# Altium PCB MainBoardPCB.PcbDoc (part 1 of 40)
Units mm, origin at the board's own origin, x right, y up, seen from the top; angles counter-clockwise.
Board outline 258.95 x 308.86 mm, 16 copper layers (L1, L2 (GND), L3 (Sign), L4 (GND), L5 (Sign), L6 (PWR/GND), L7(12V+Other), L8 (Plane_GND), L9 (PWR/GND), L10 (3V3+Other), L11 (PWR/GND), L12 (Sign), L13 (GND), L14 (Sign), L15 (GND), L16), stack 2.503 mm thick; 2578 components, 1867 nets, 8817 pads, 8021 vias.
Unrouted connection lines stored in the file: 25.

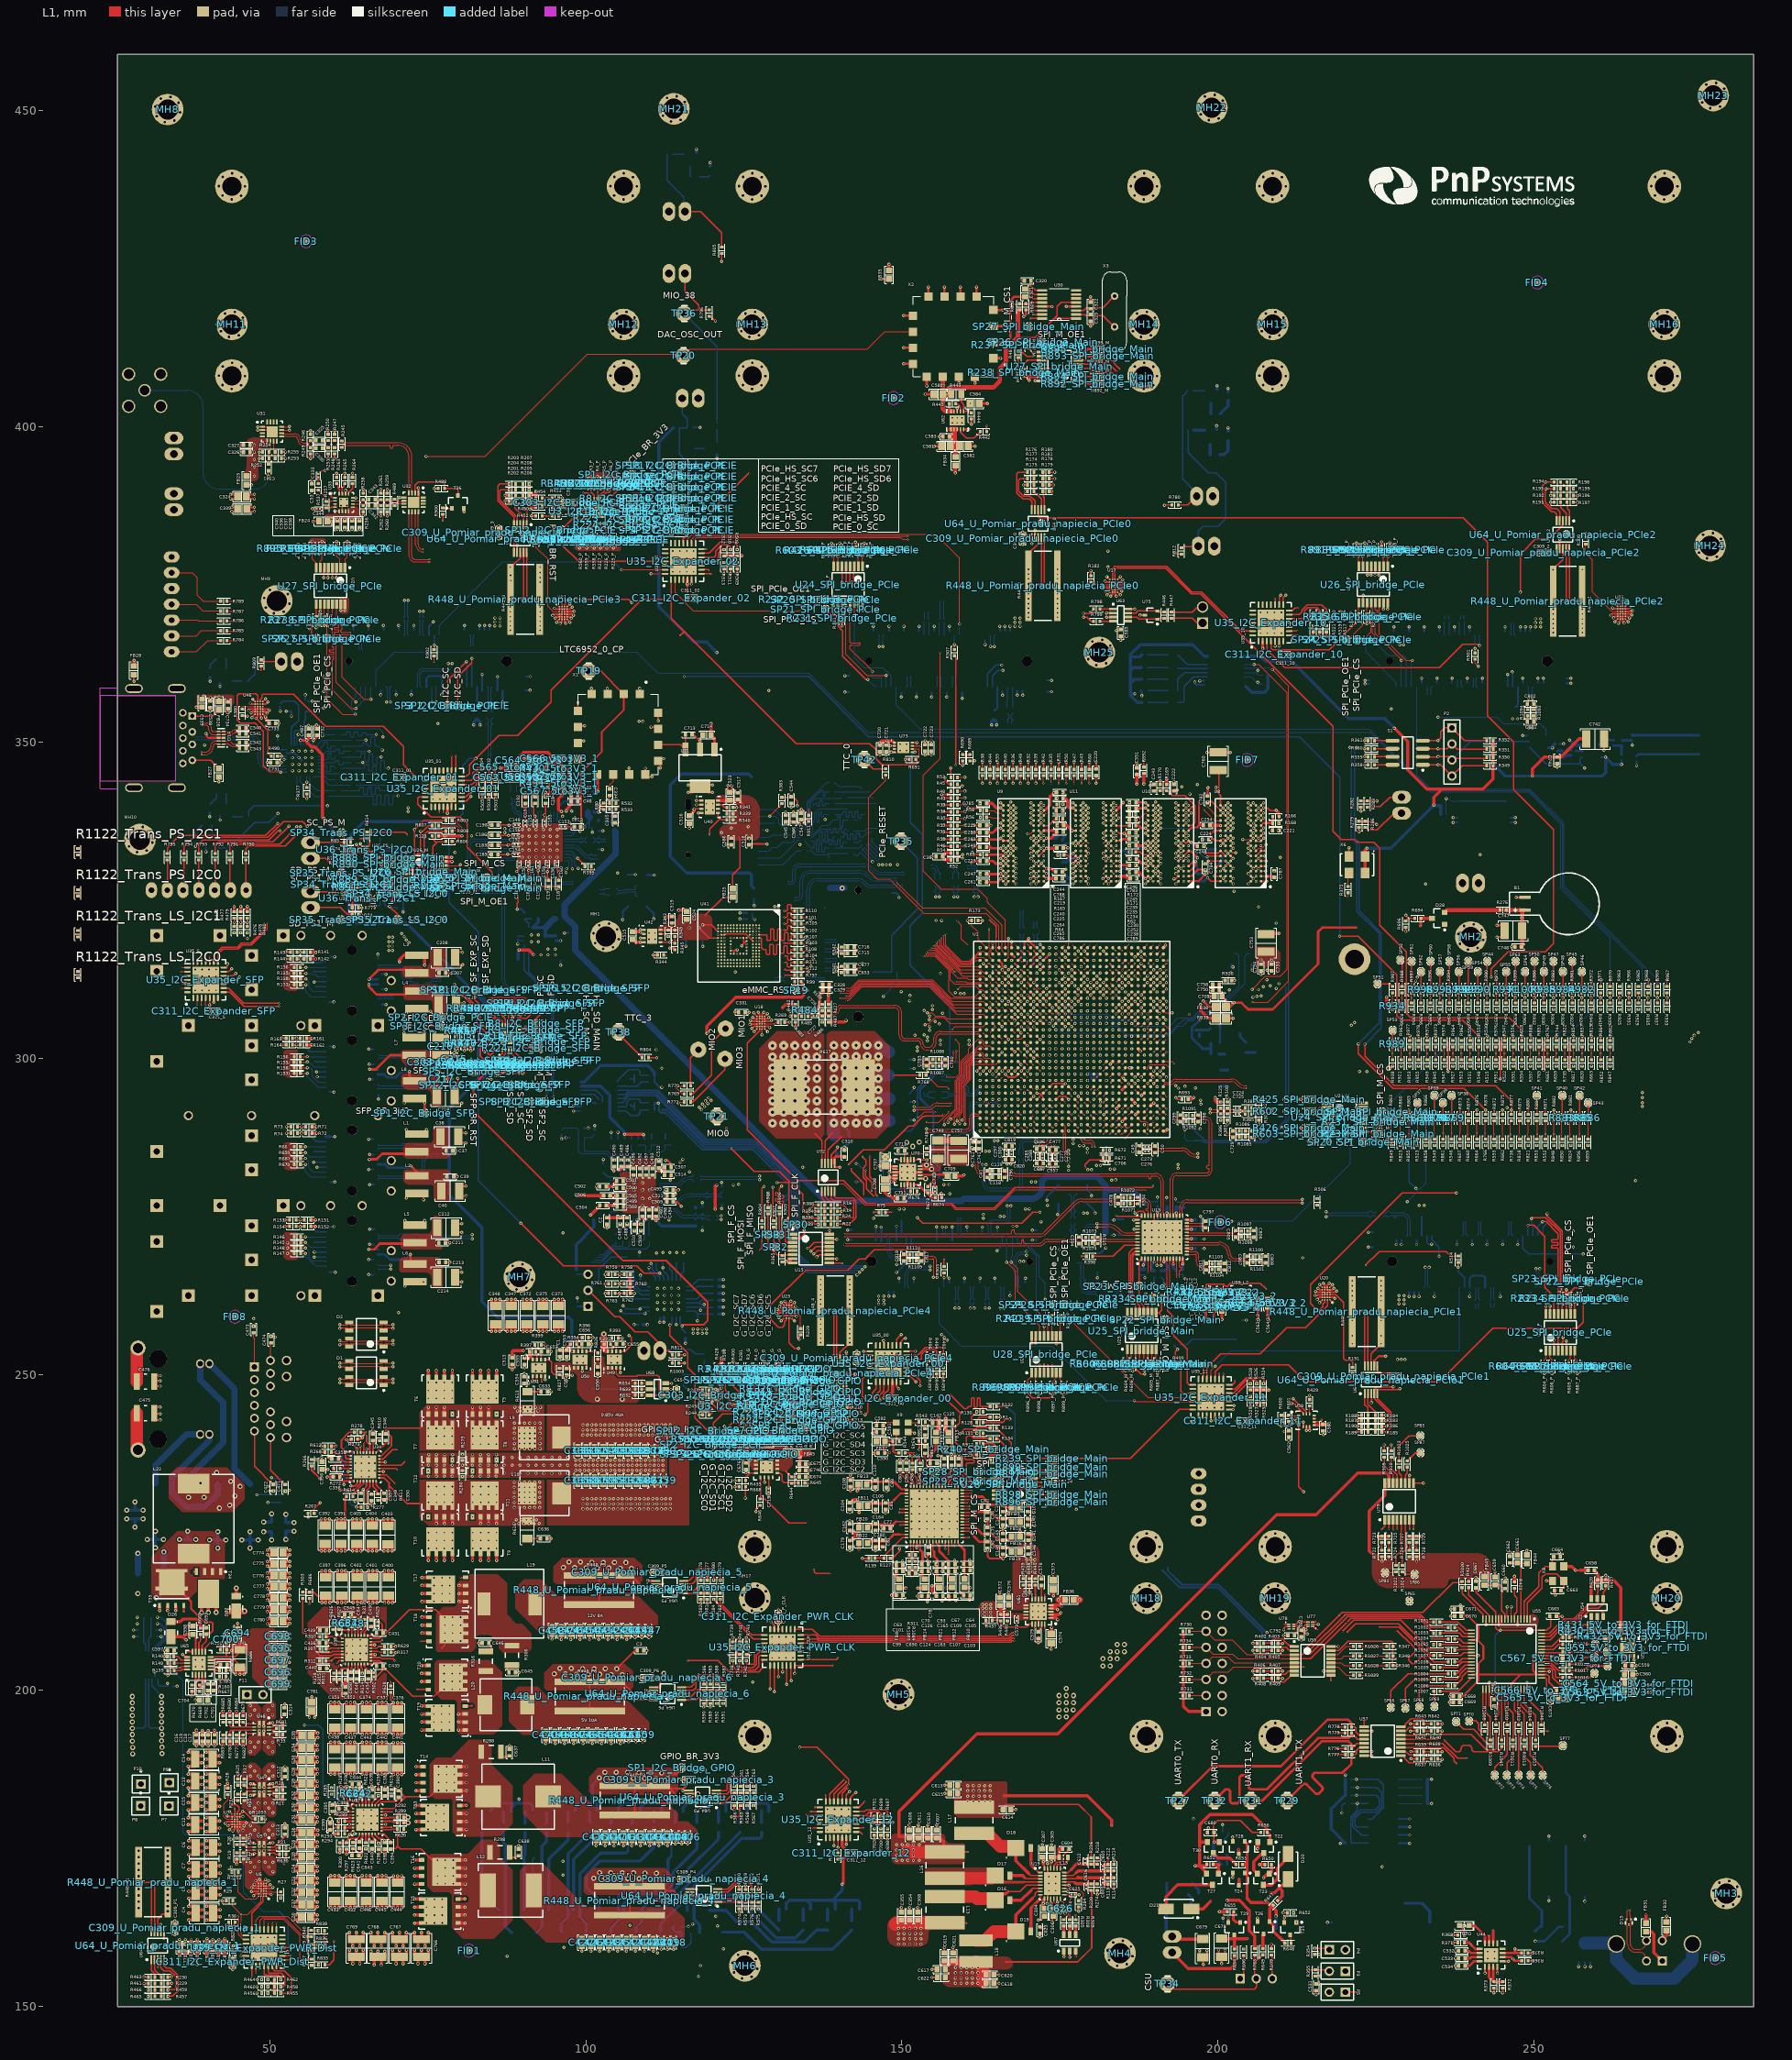
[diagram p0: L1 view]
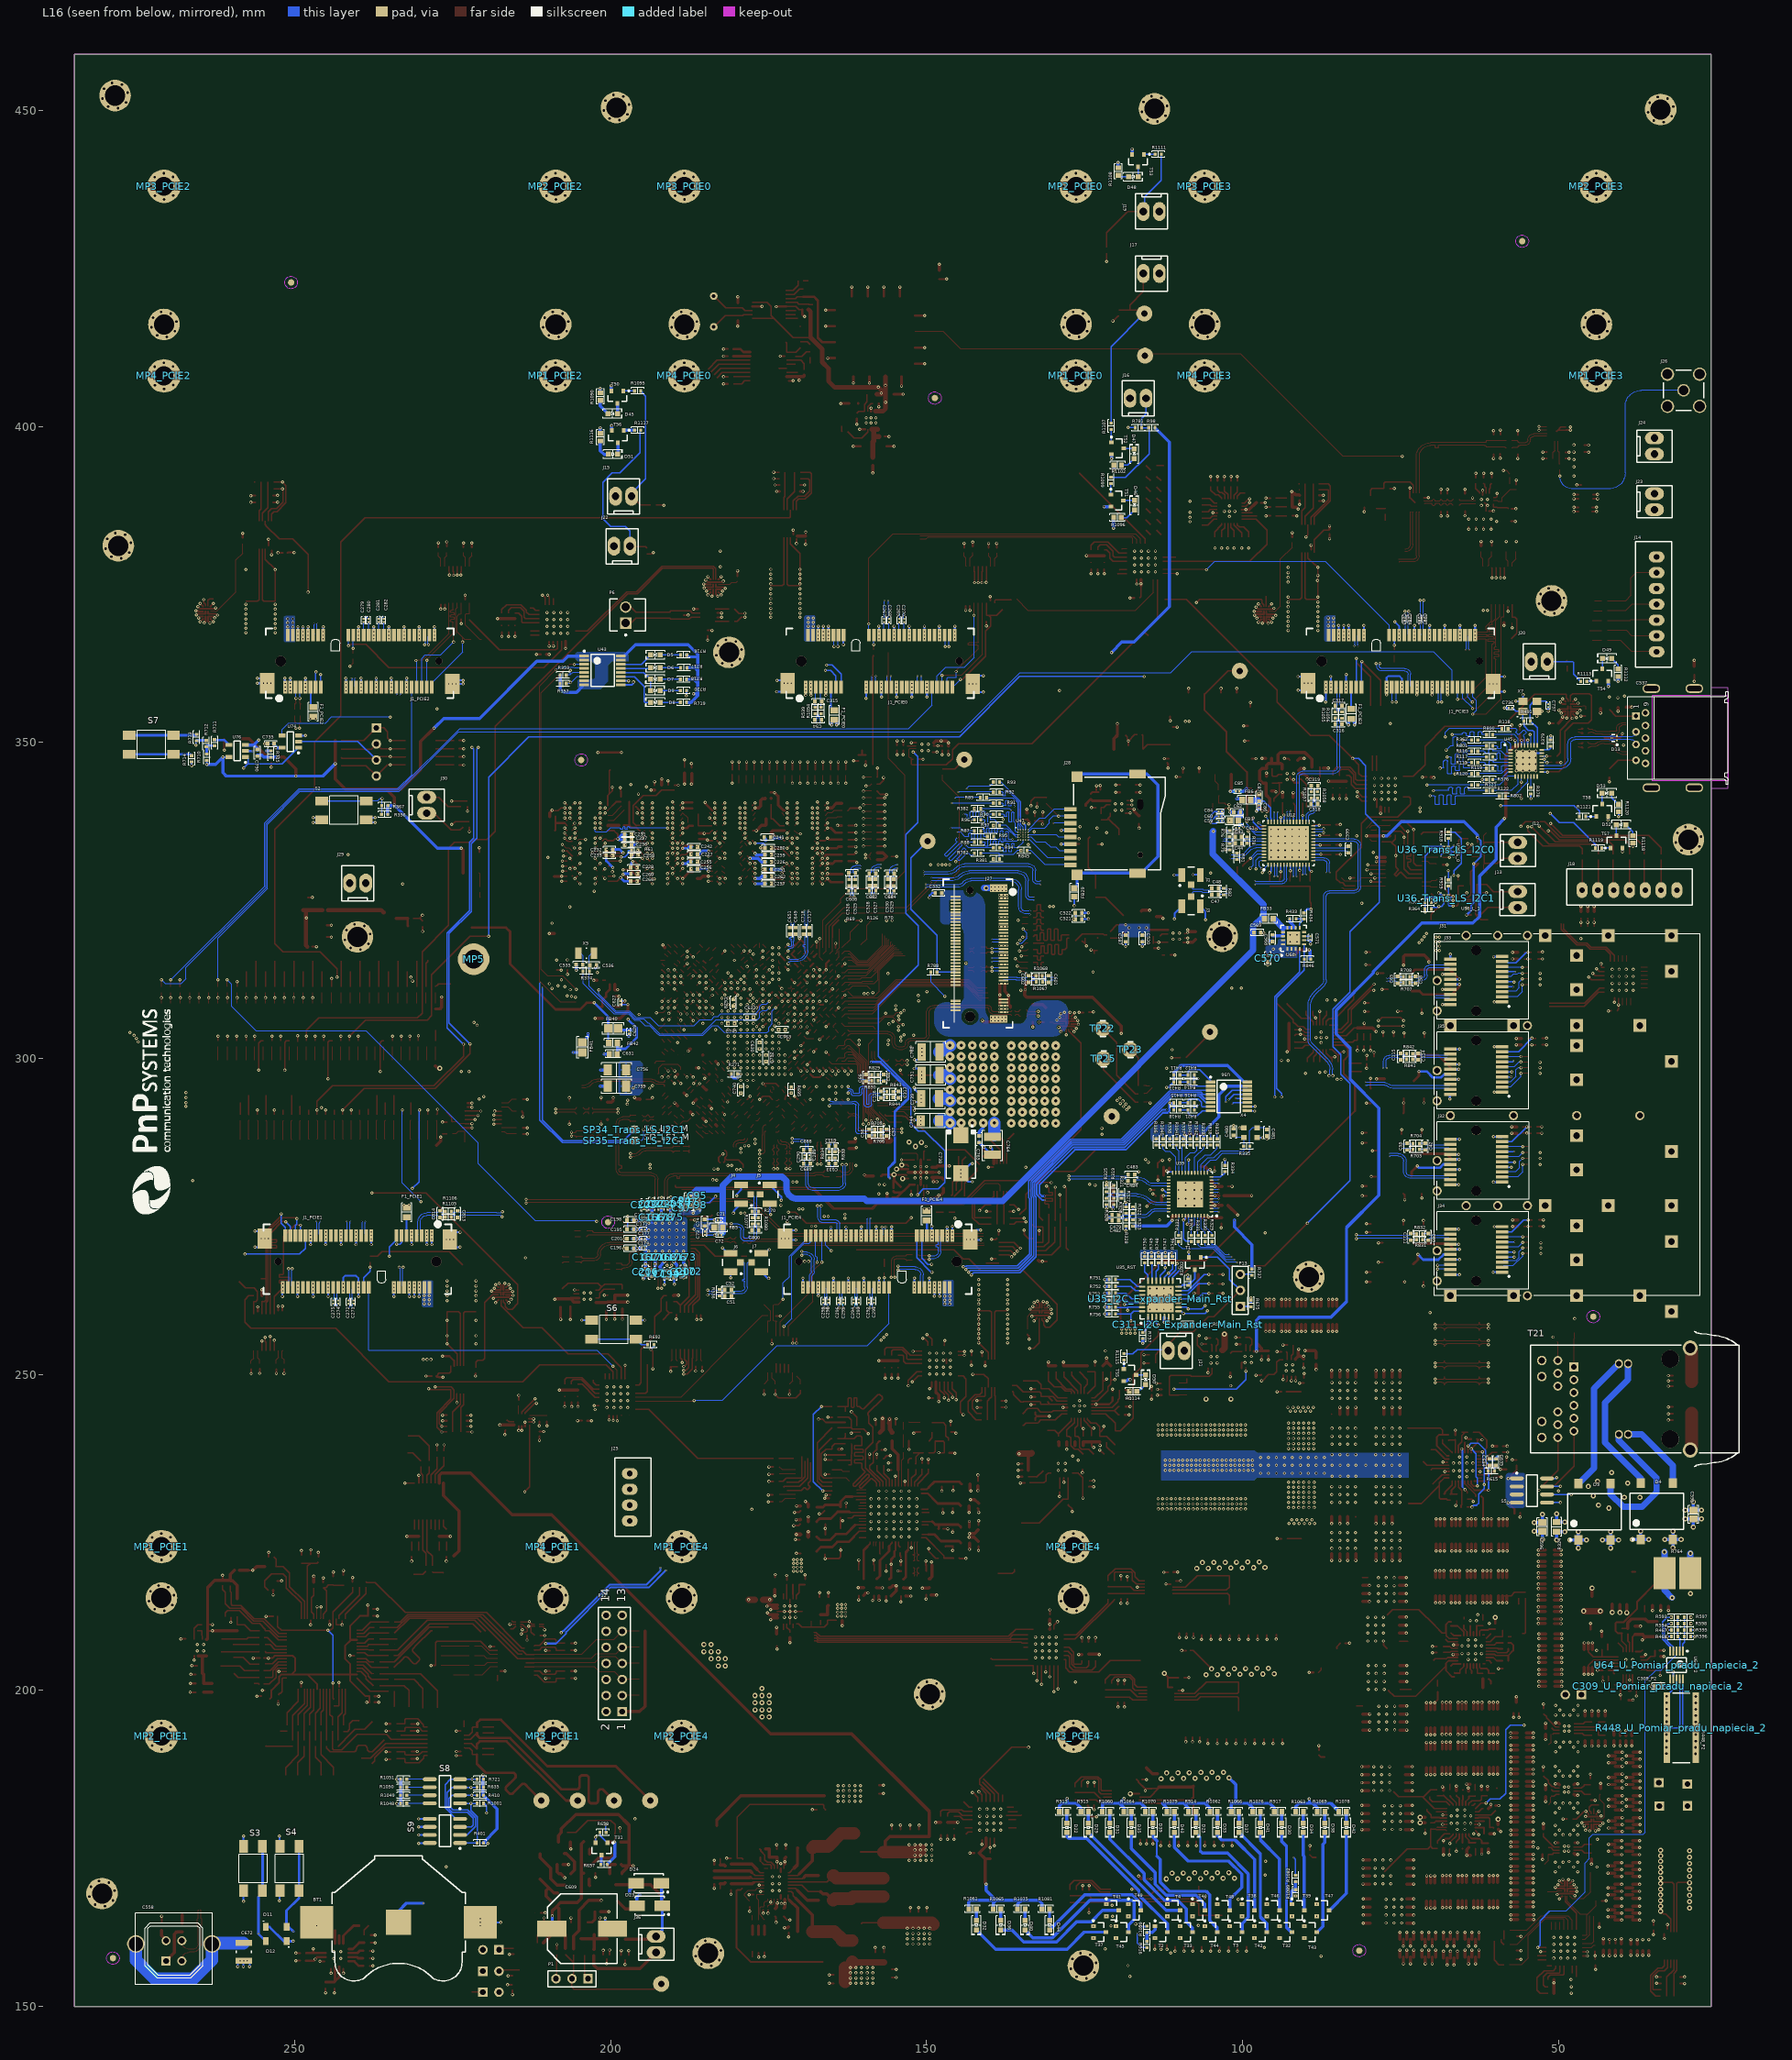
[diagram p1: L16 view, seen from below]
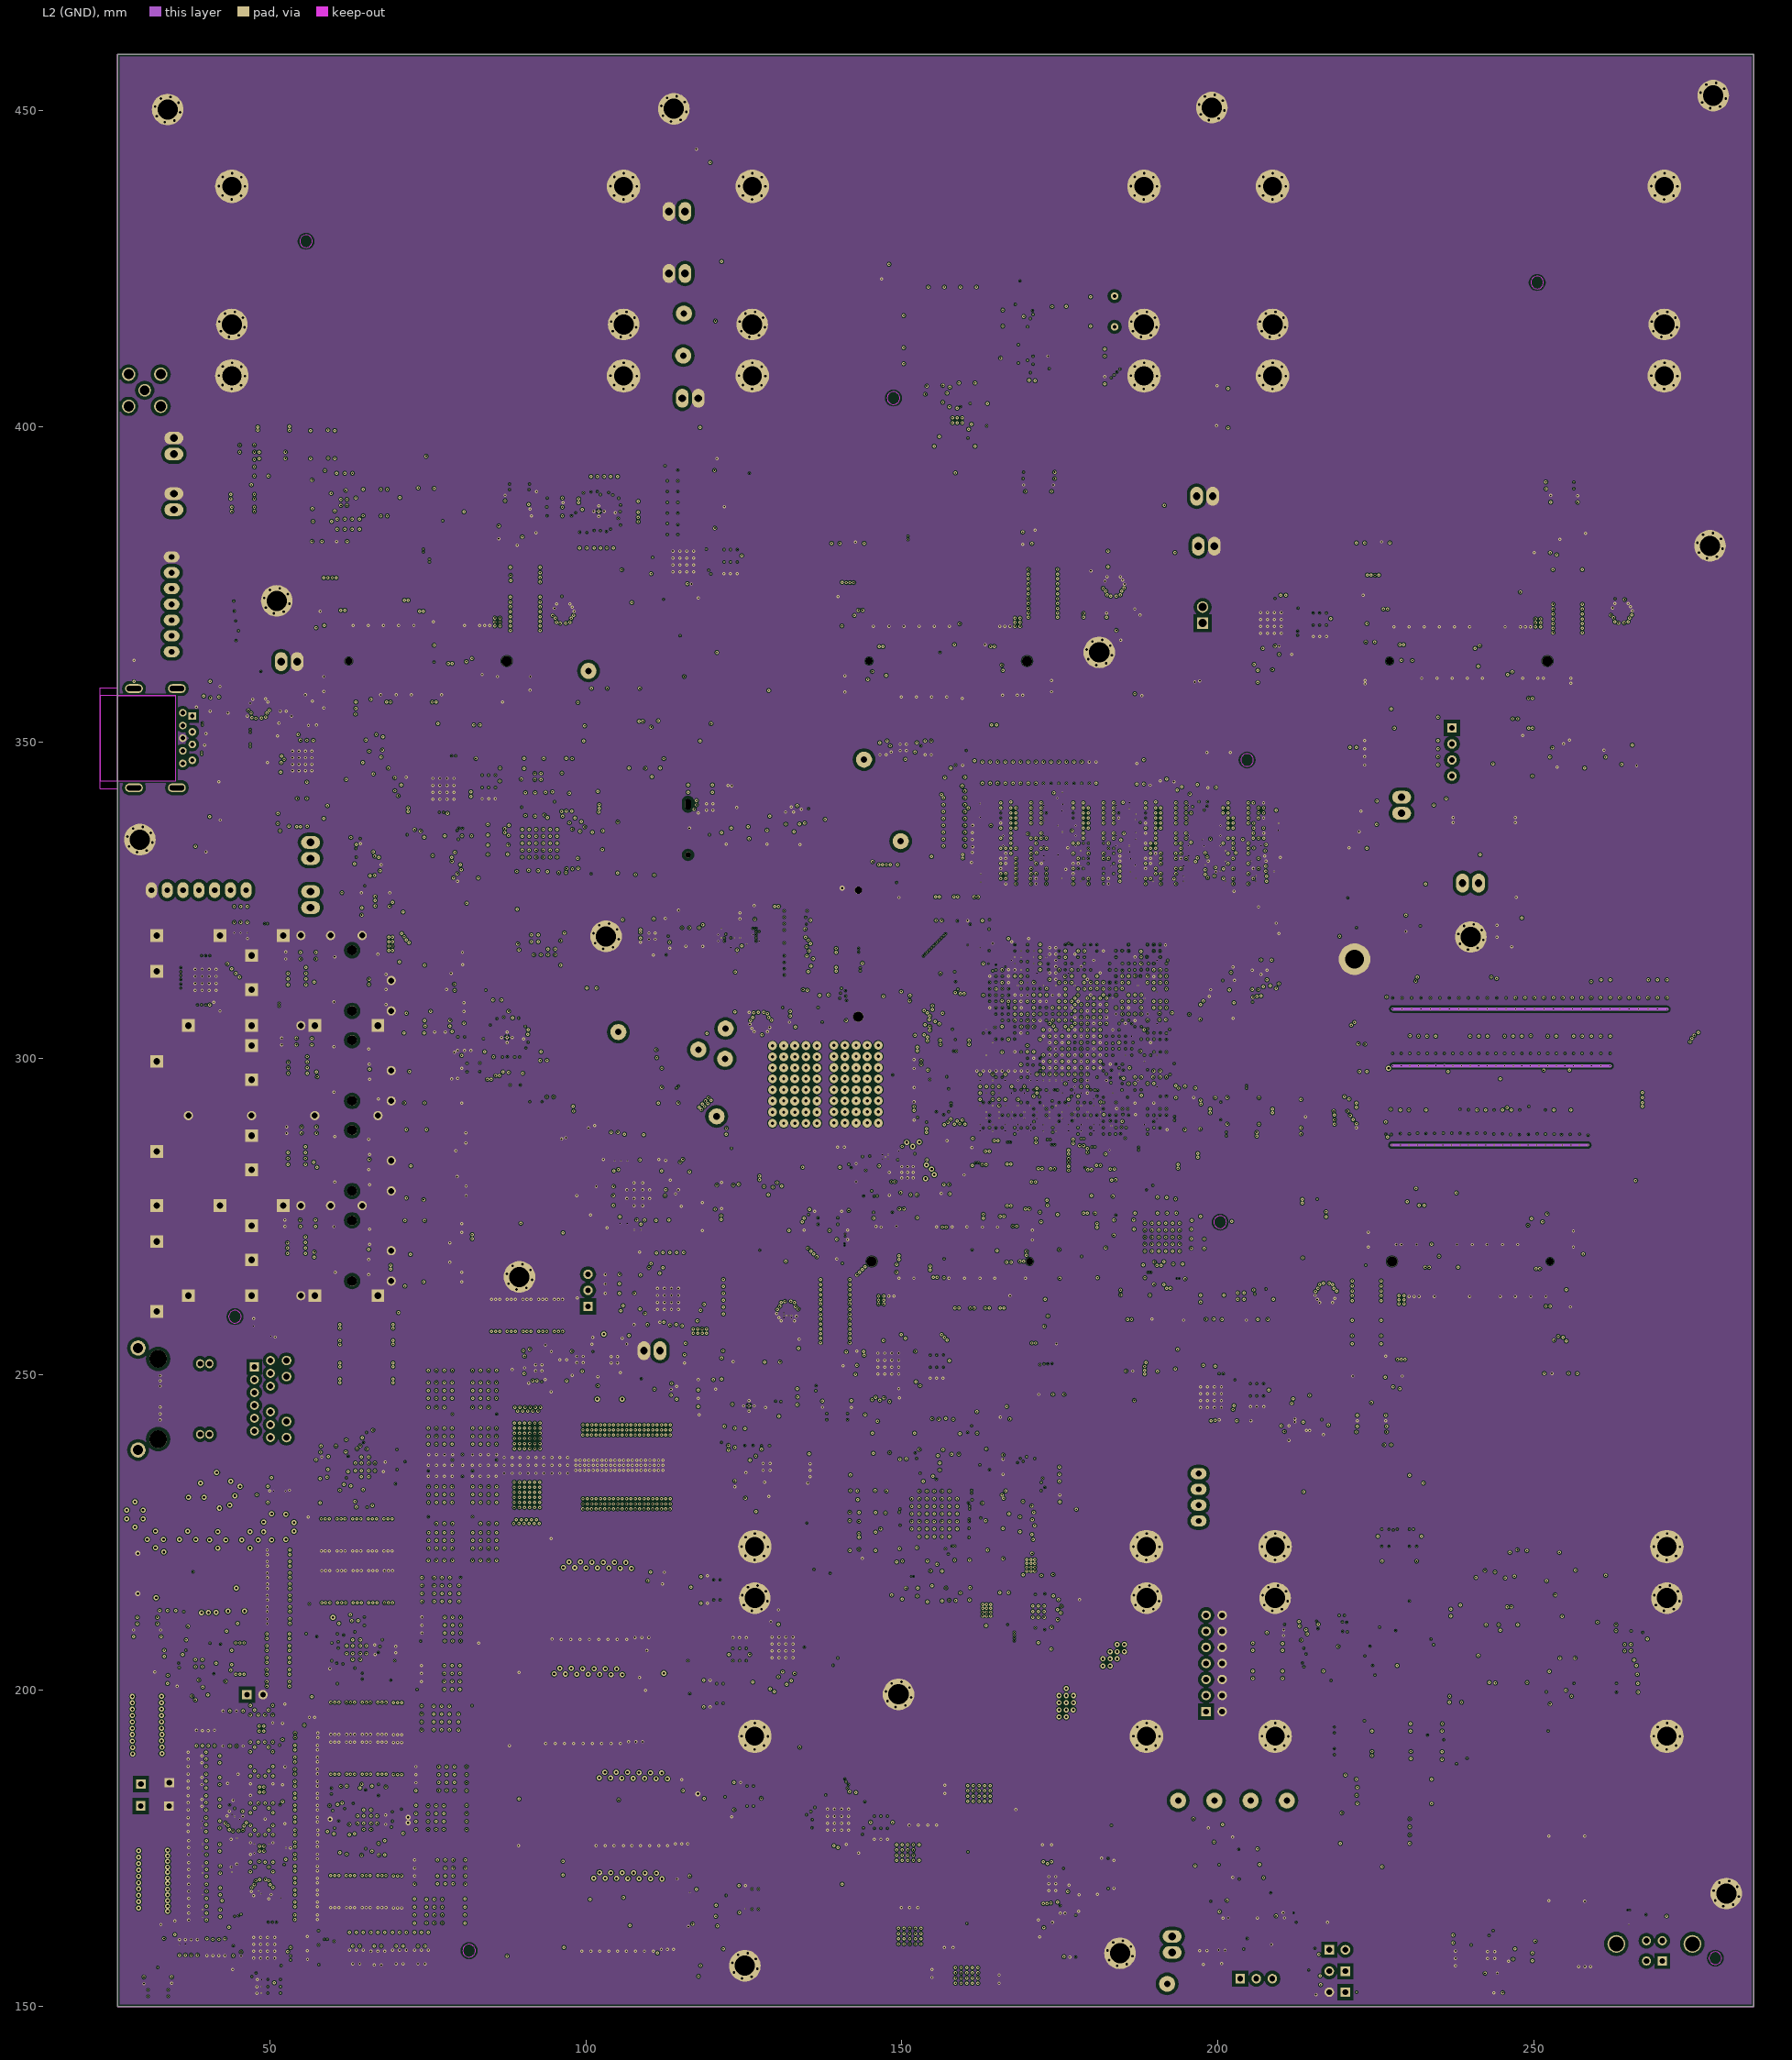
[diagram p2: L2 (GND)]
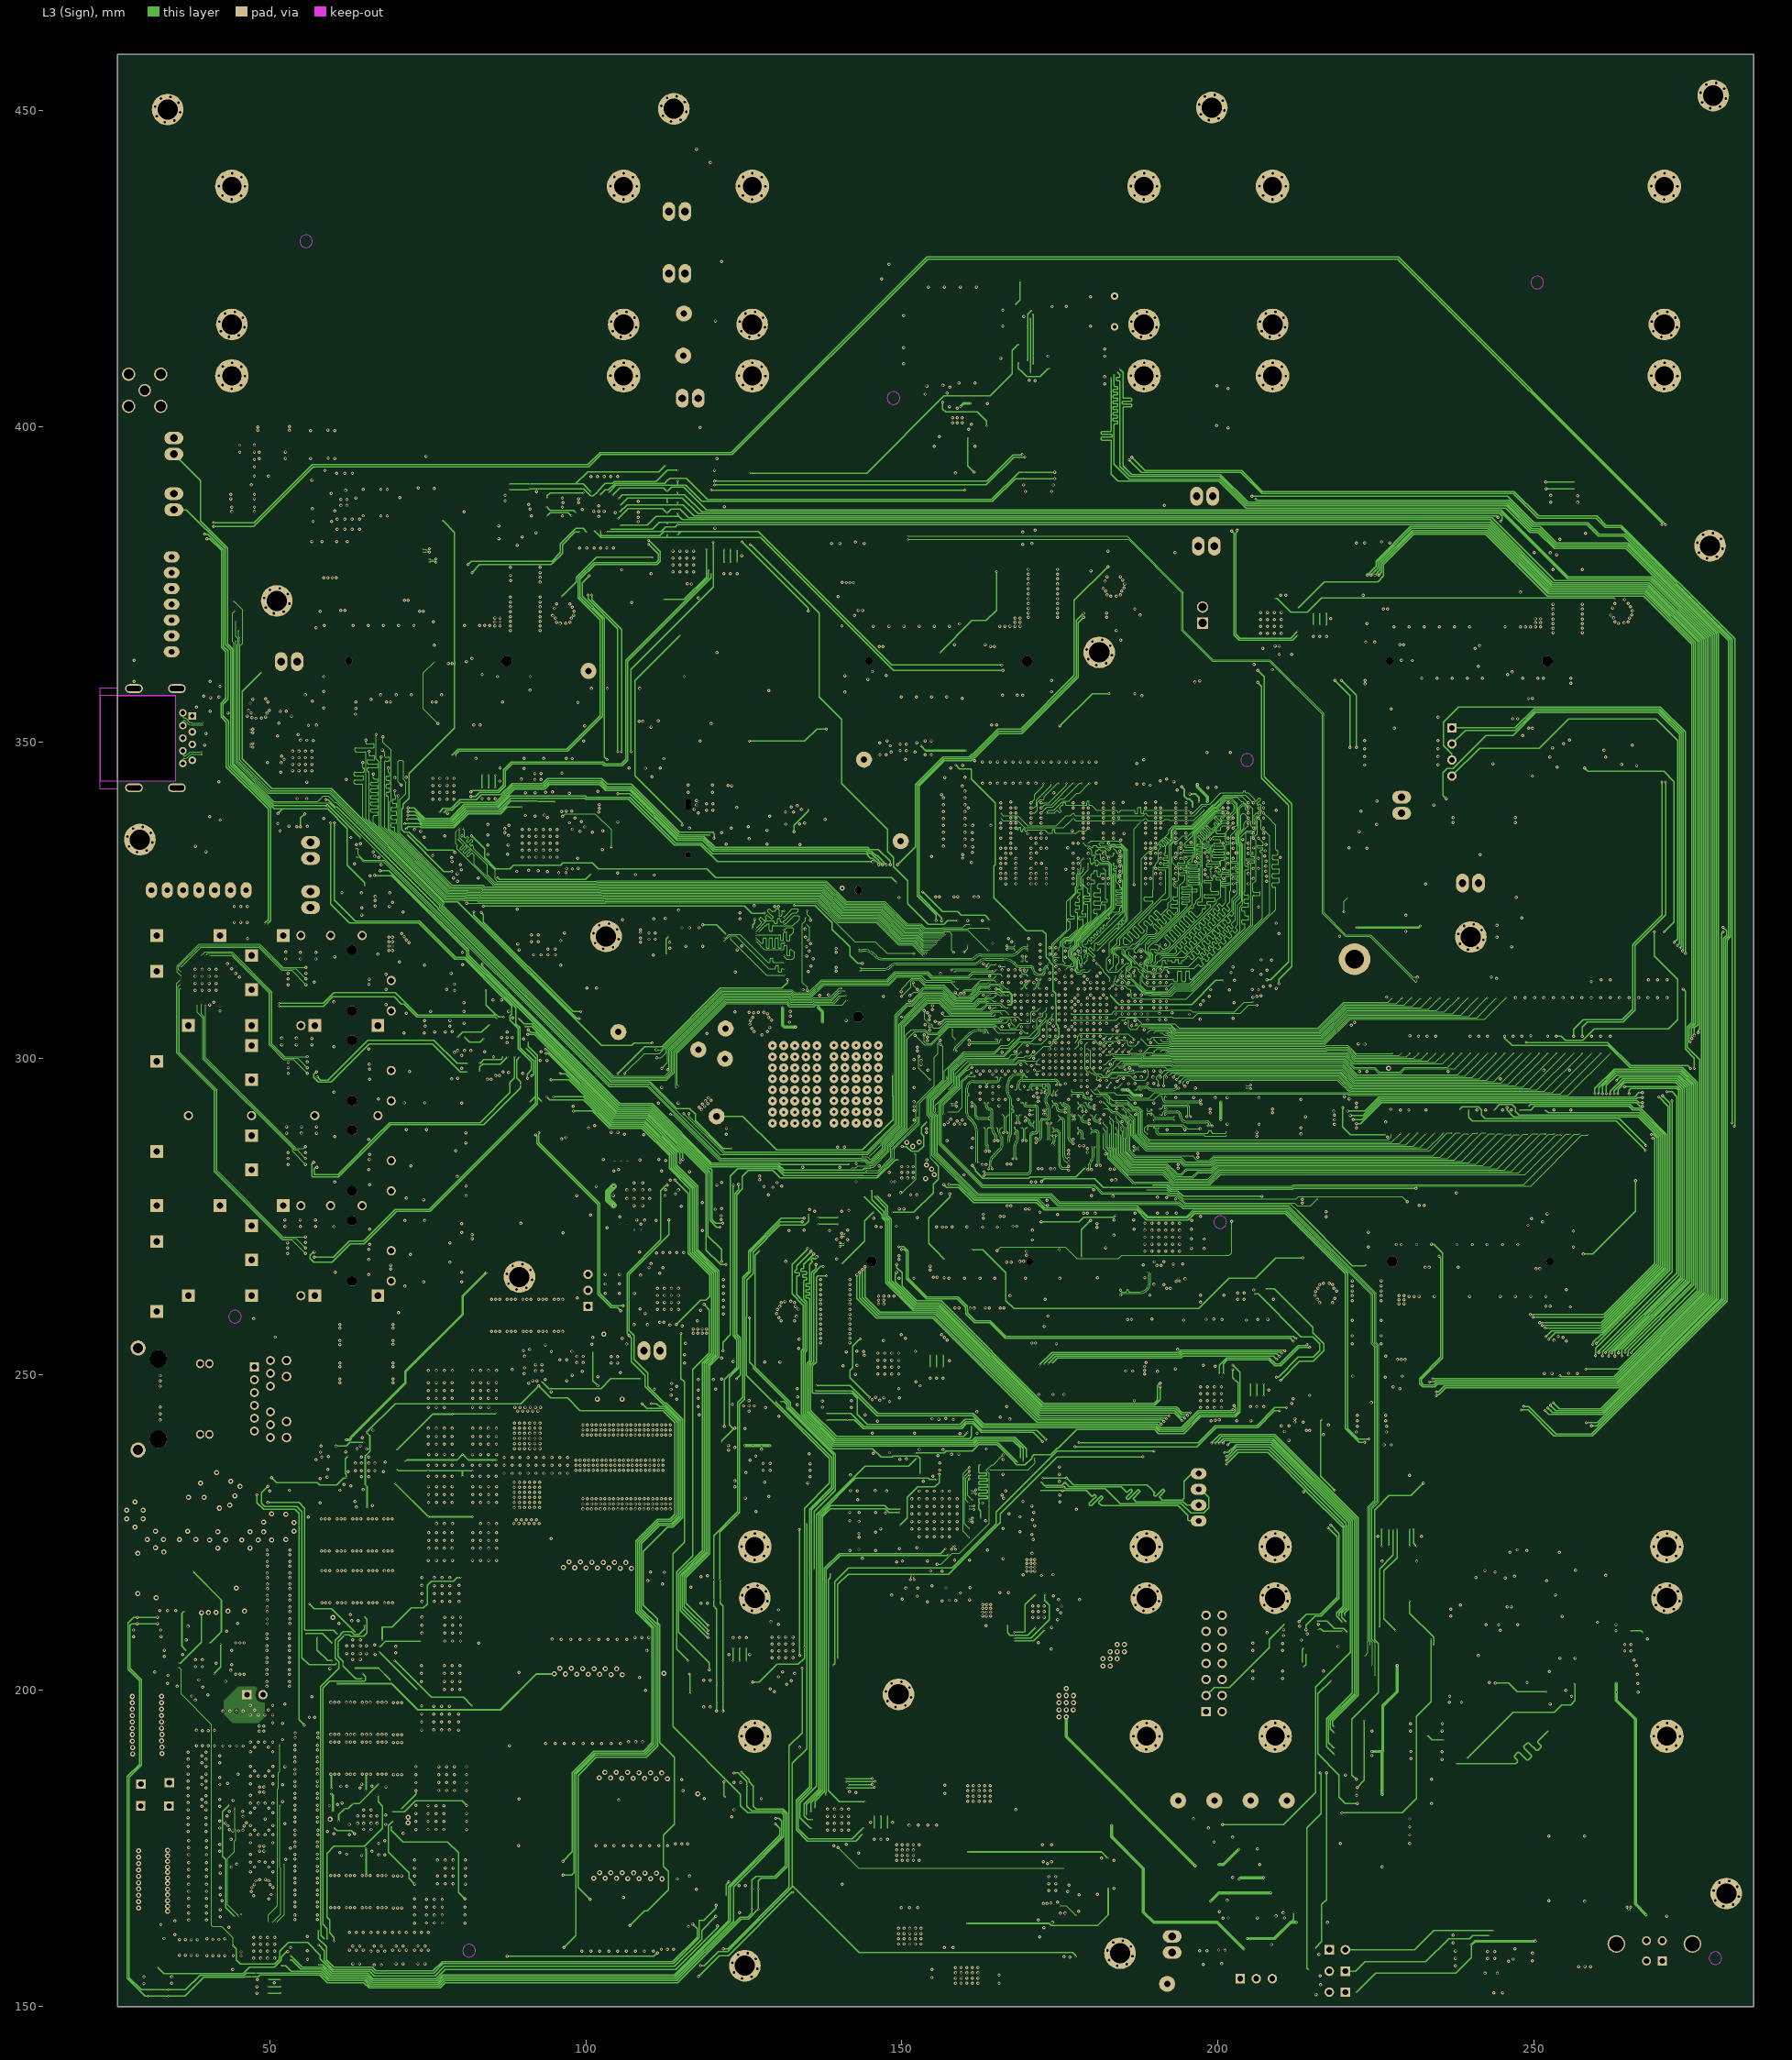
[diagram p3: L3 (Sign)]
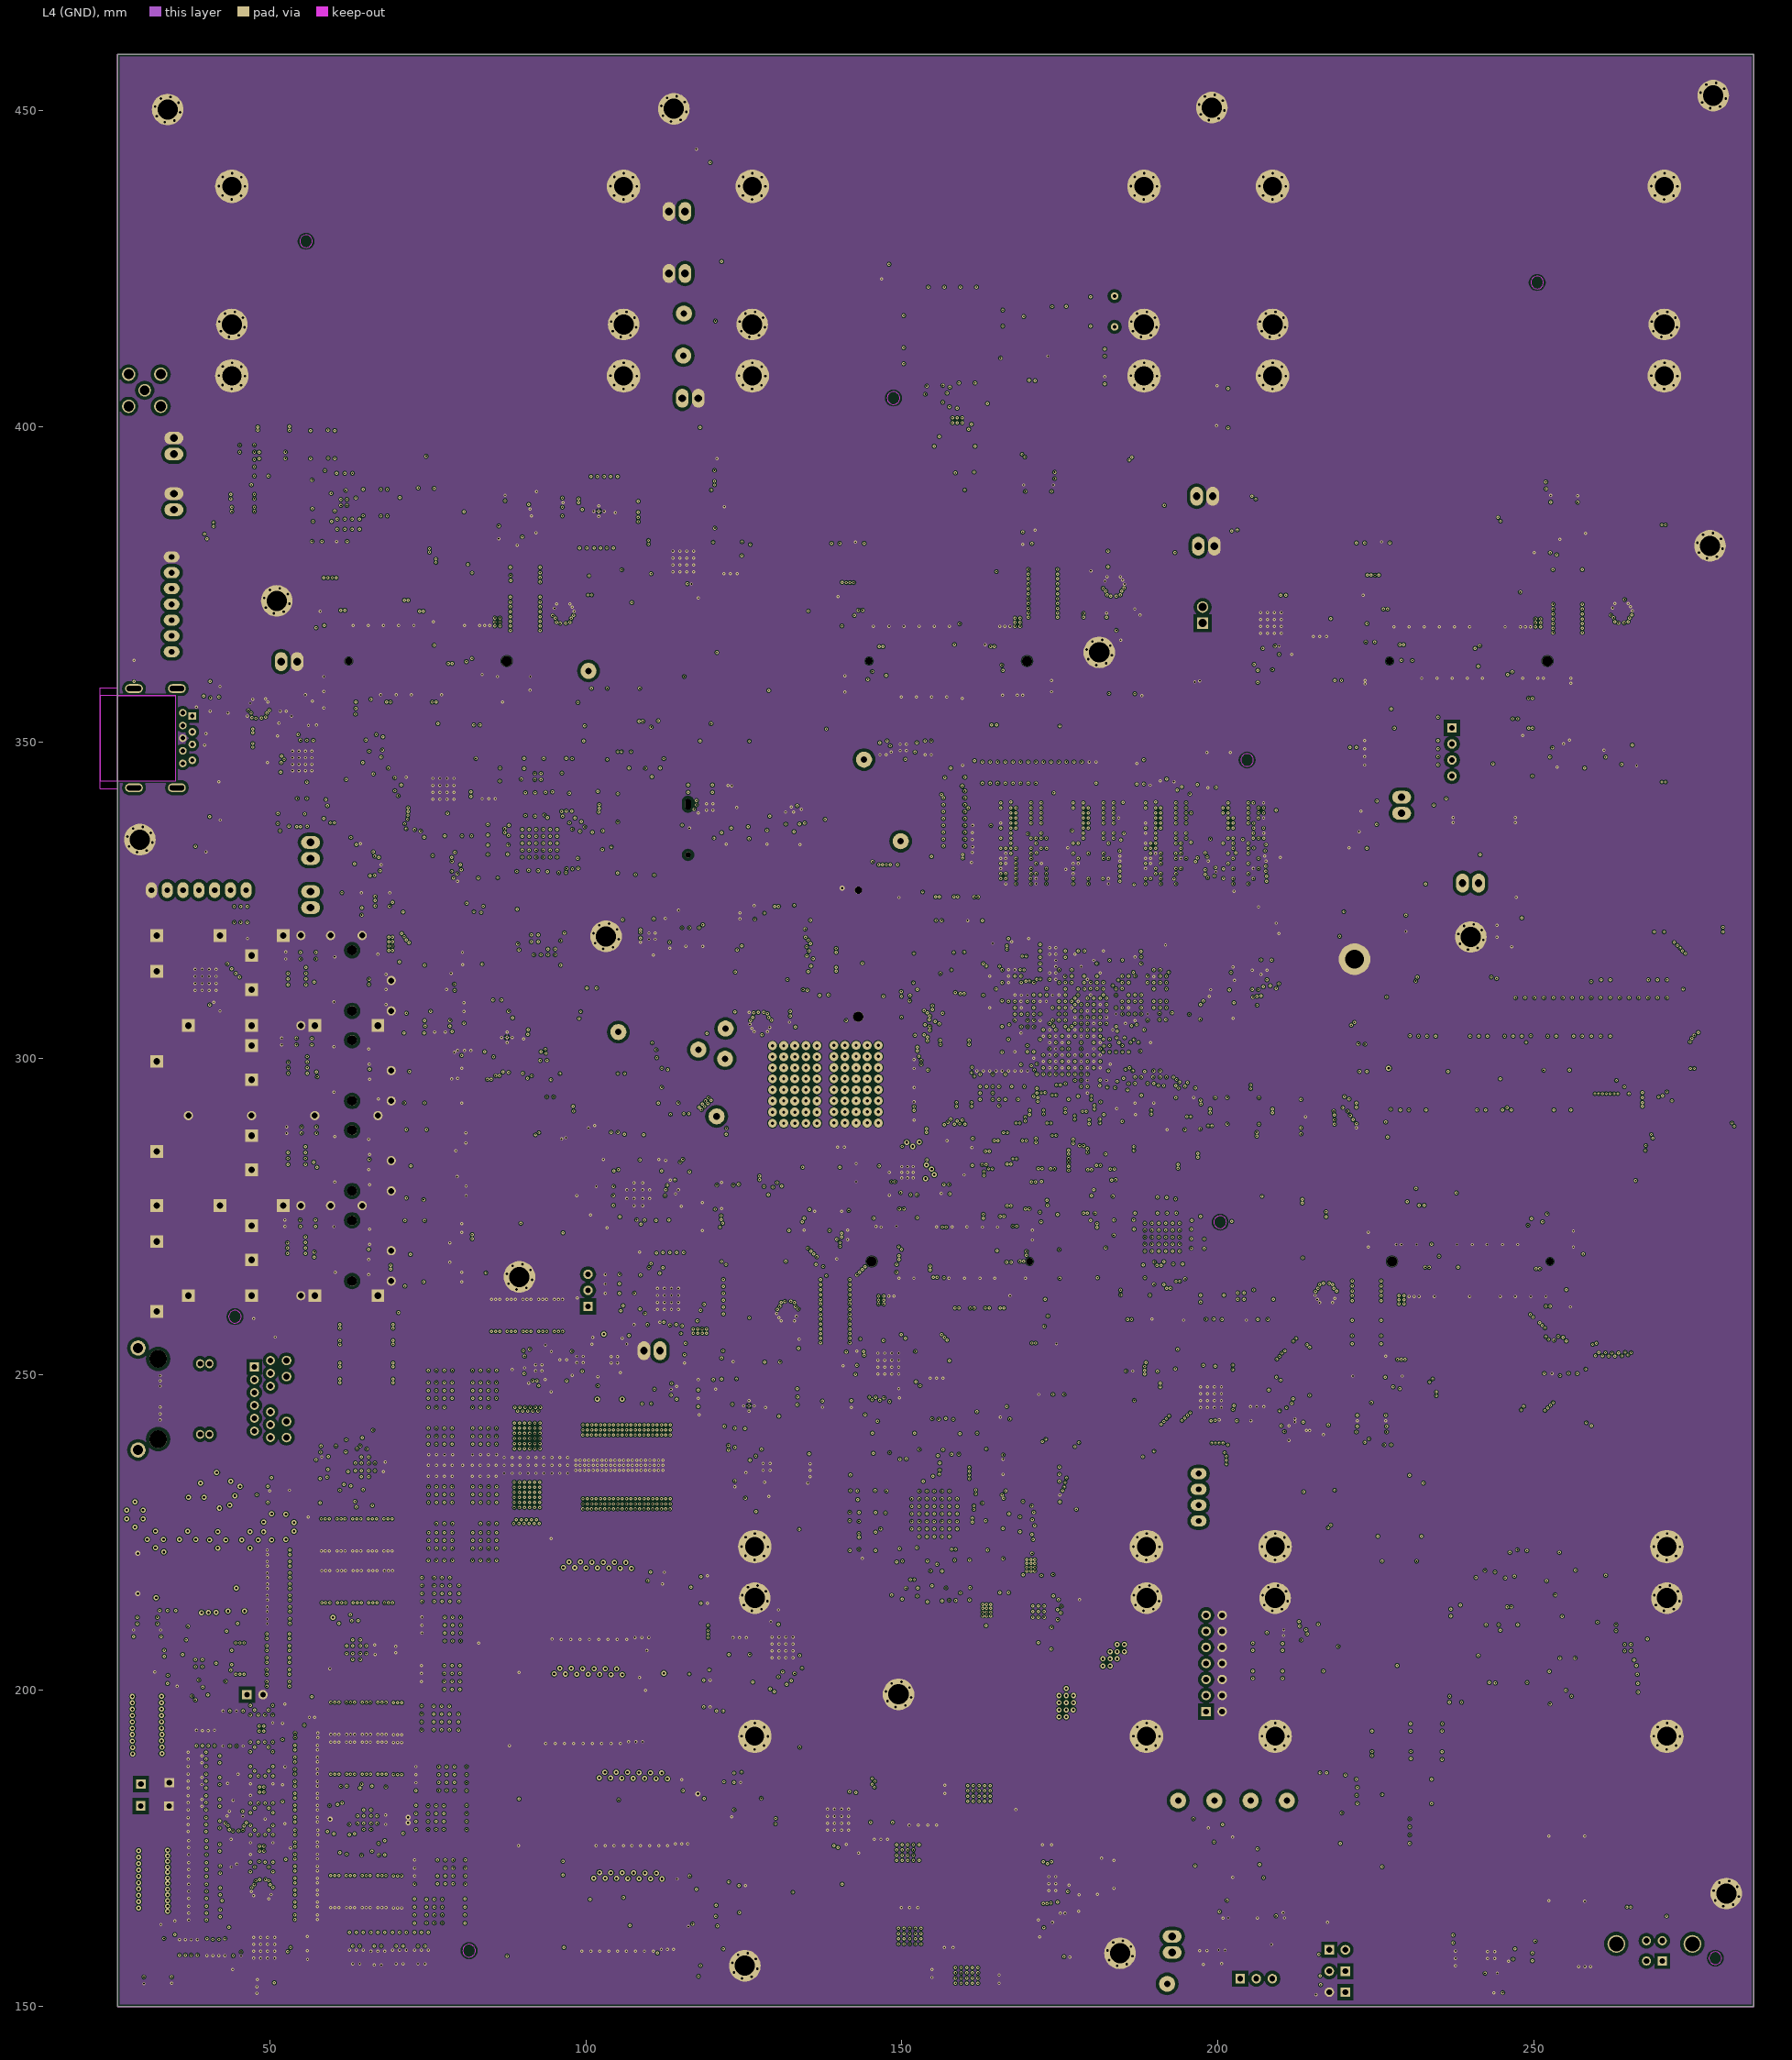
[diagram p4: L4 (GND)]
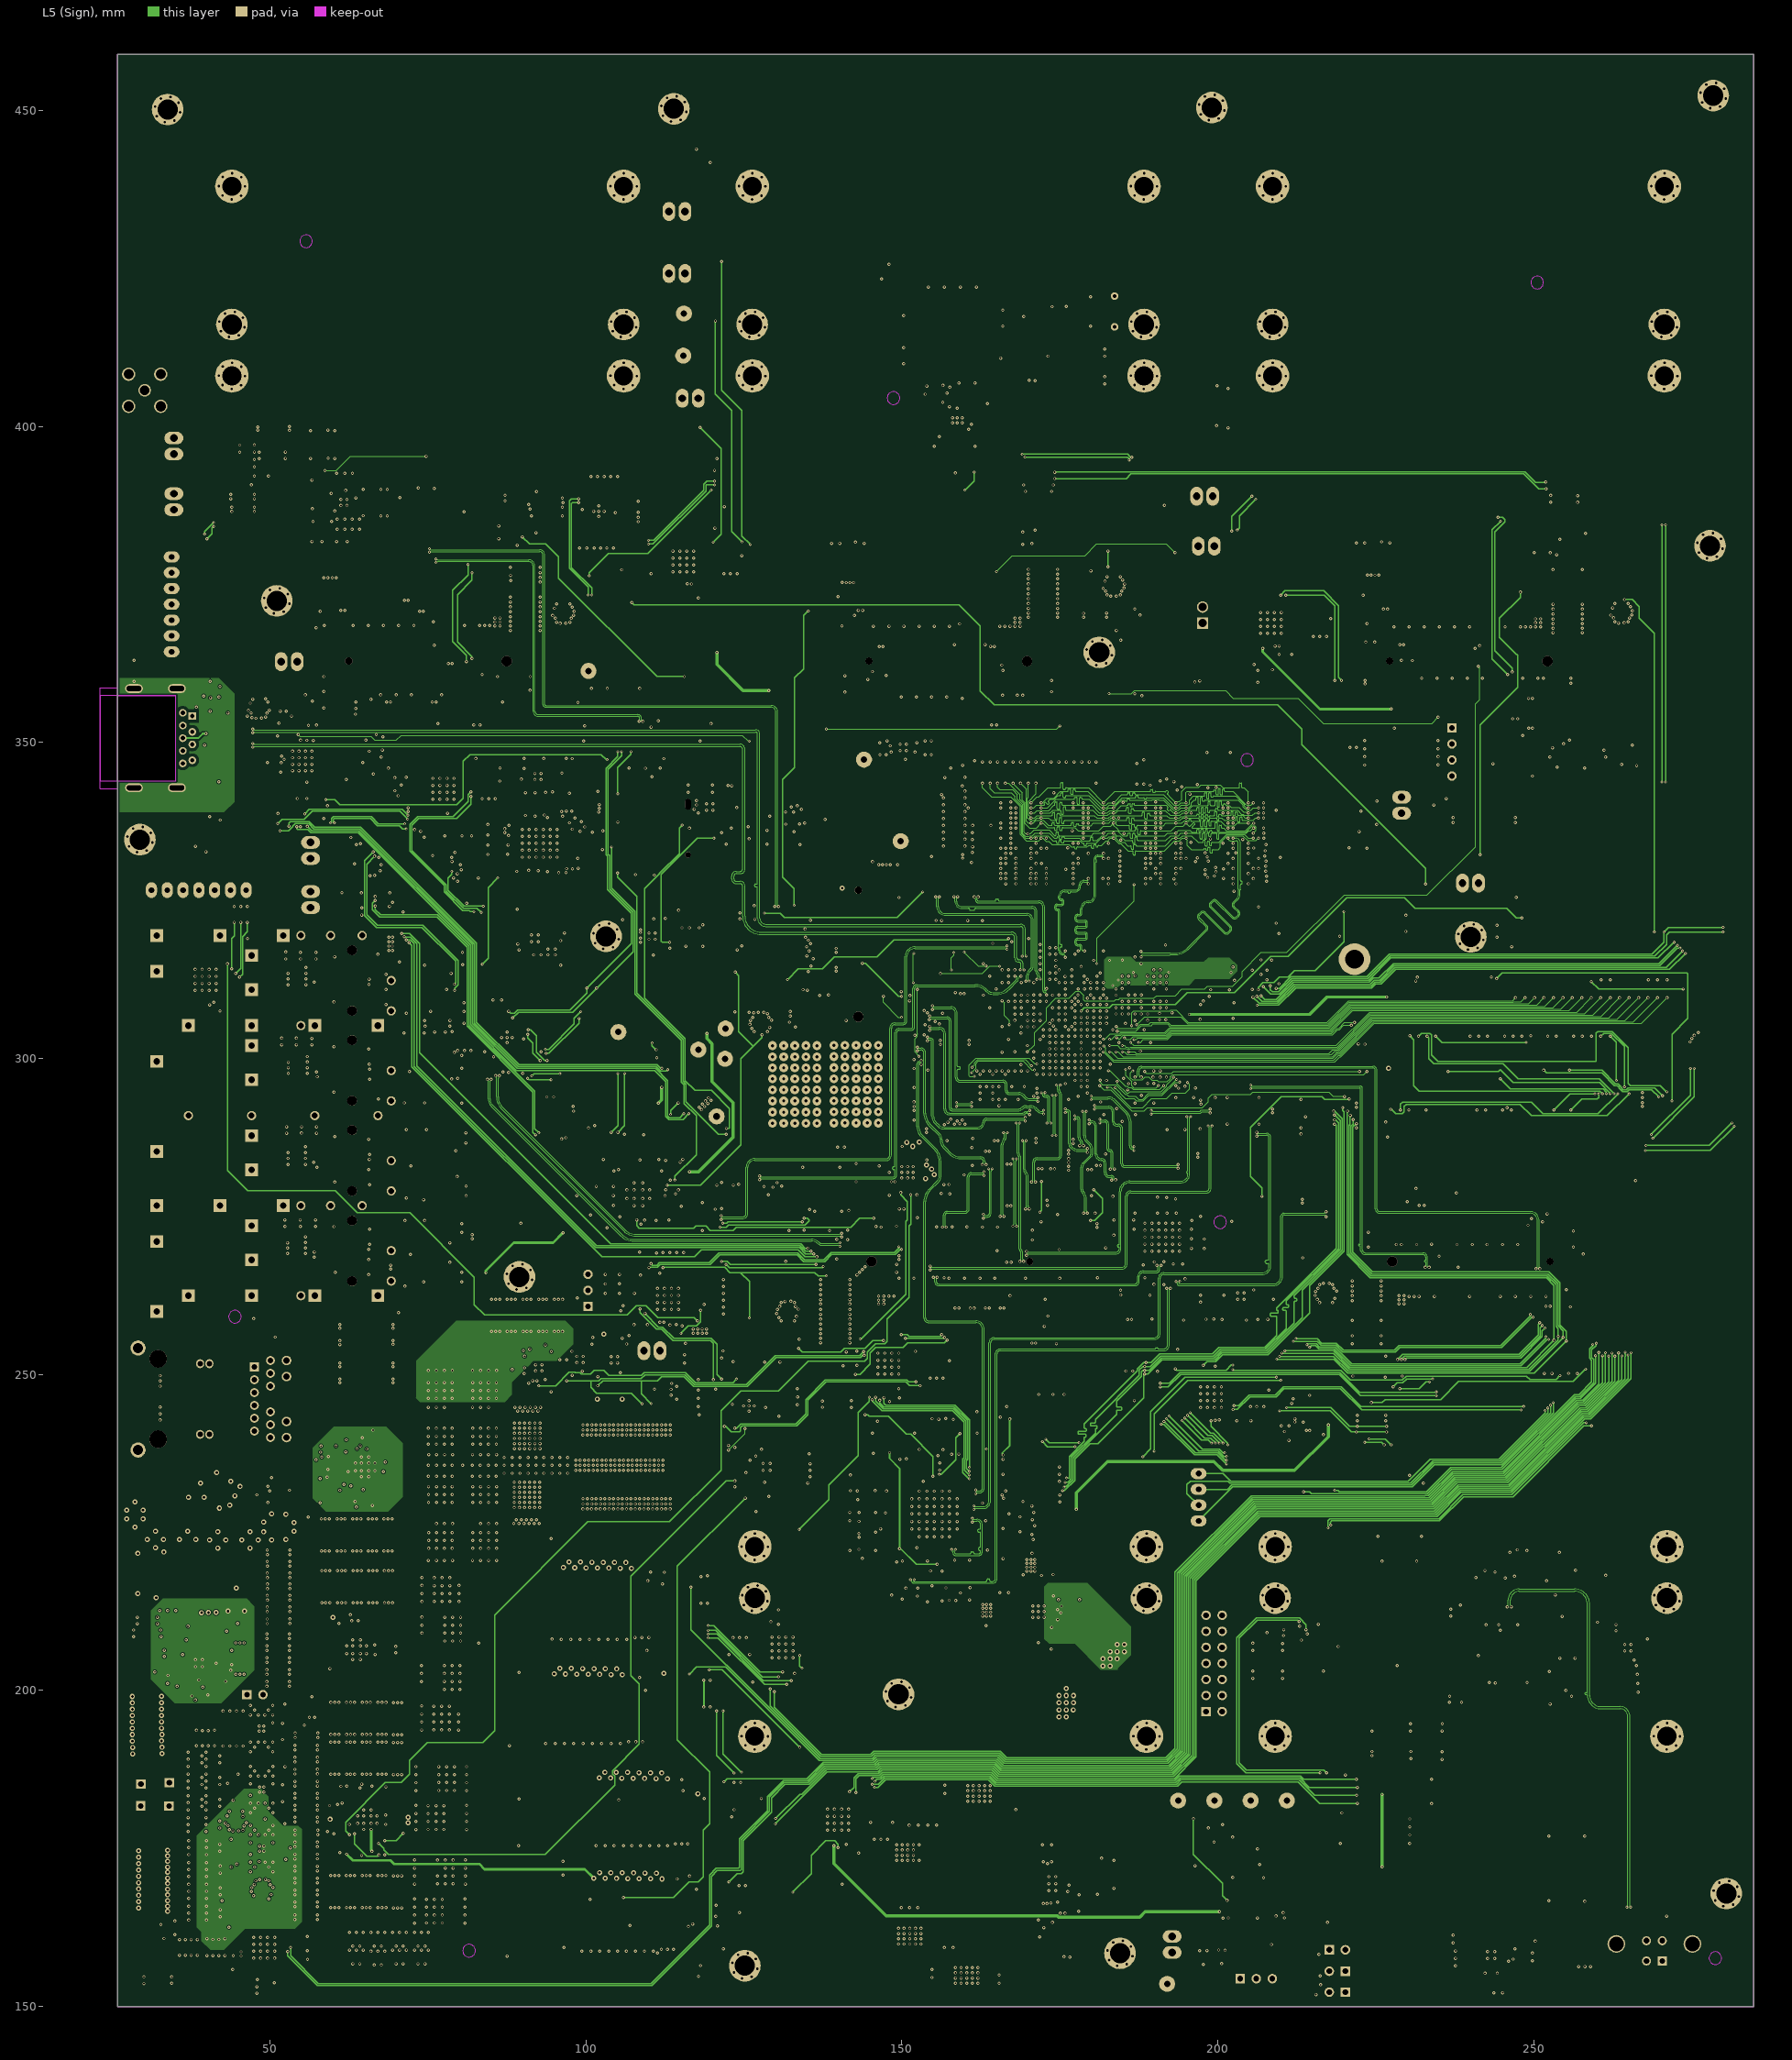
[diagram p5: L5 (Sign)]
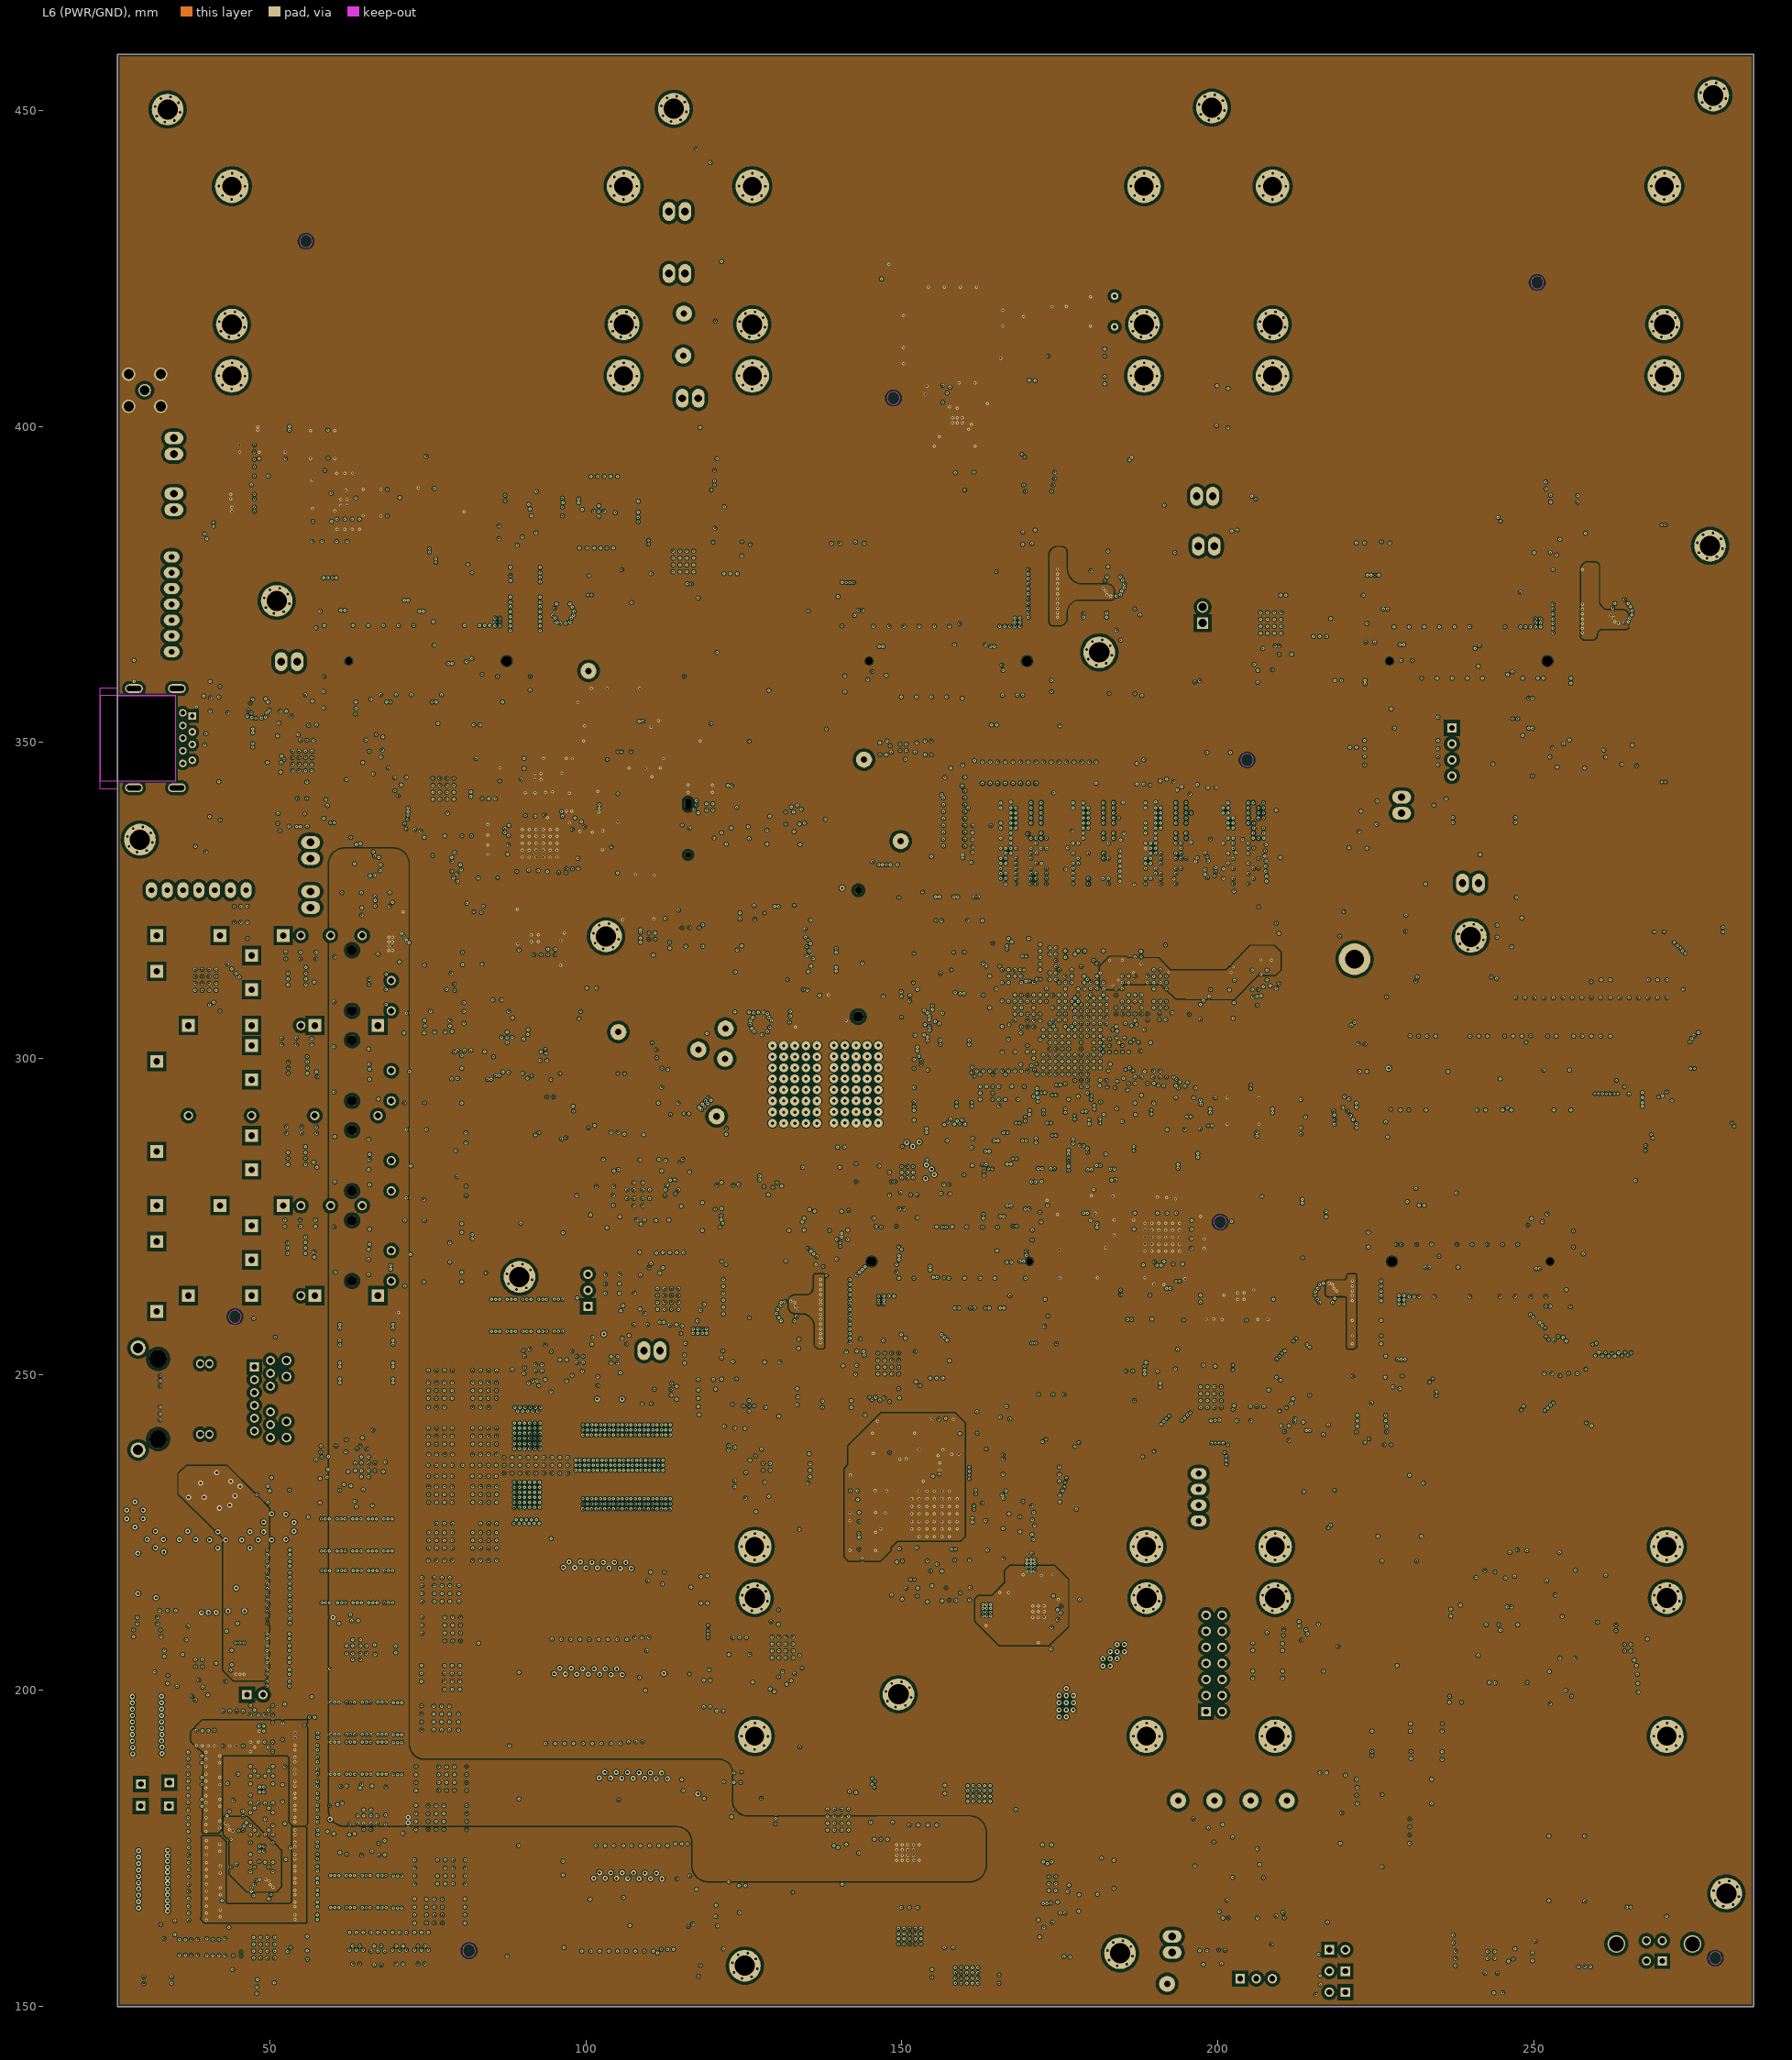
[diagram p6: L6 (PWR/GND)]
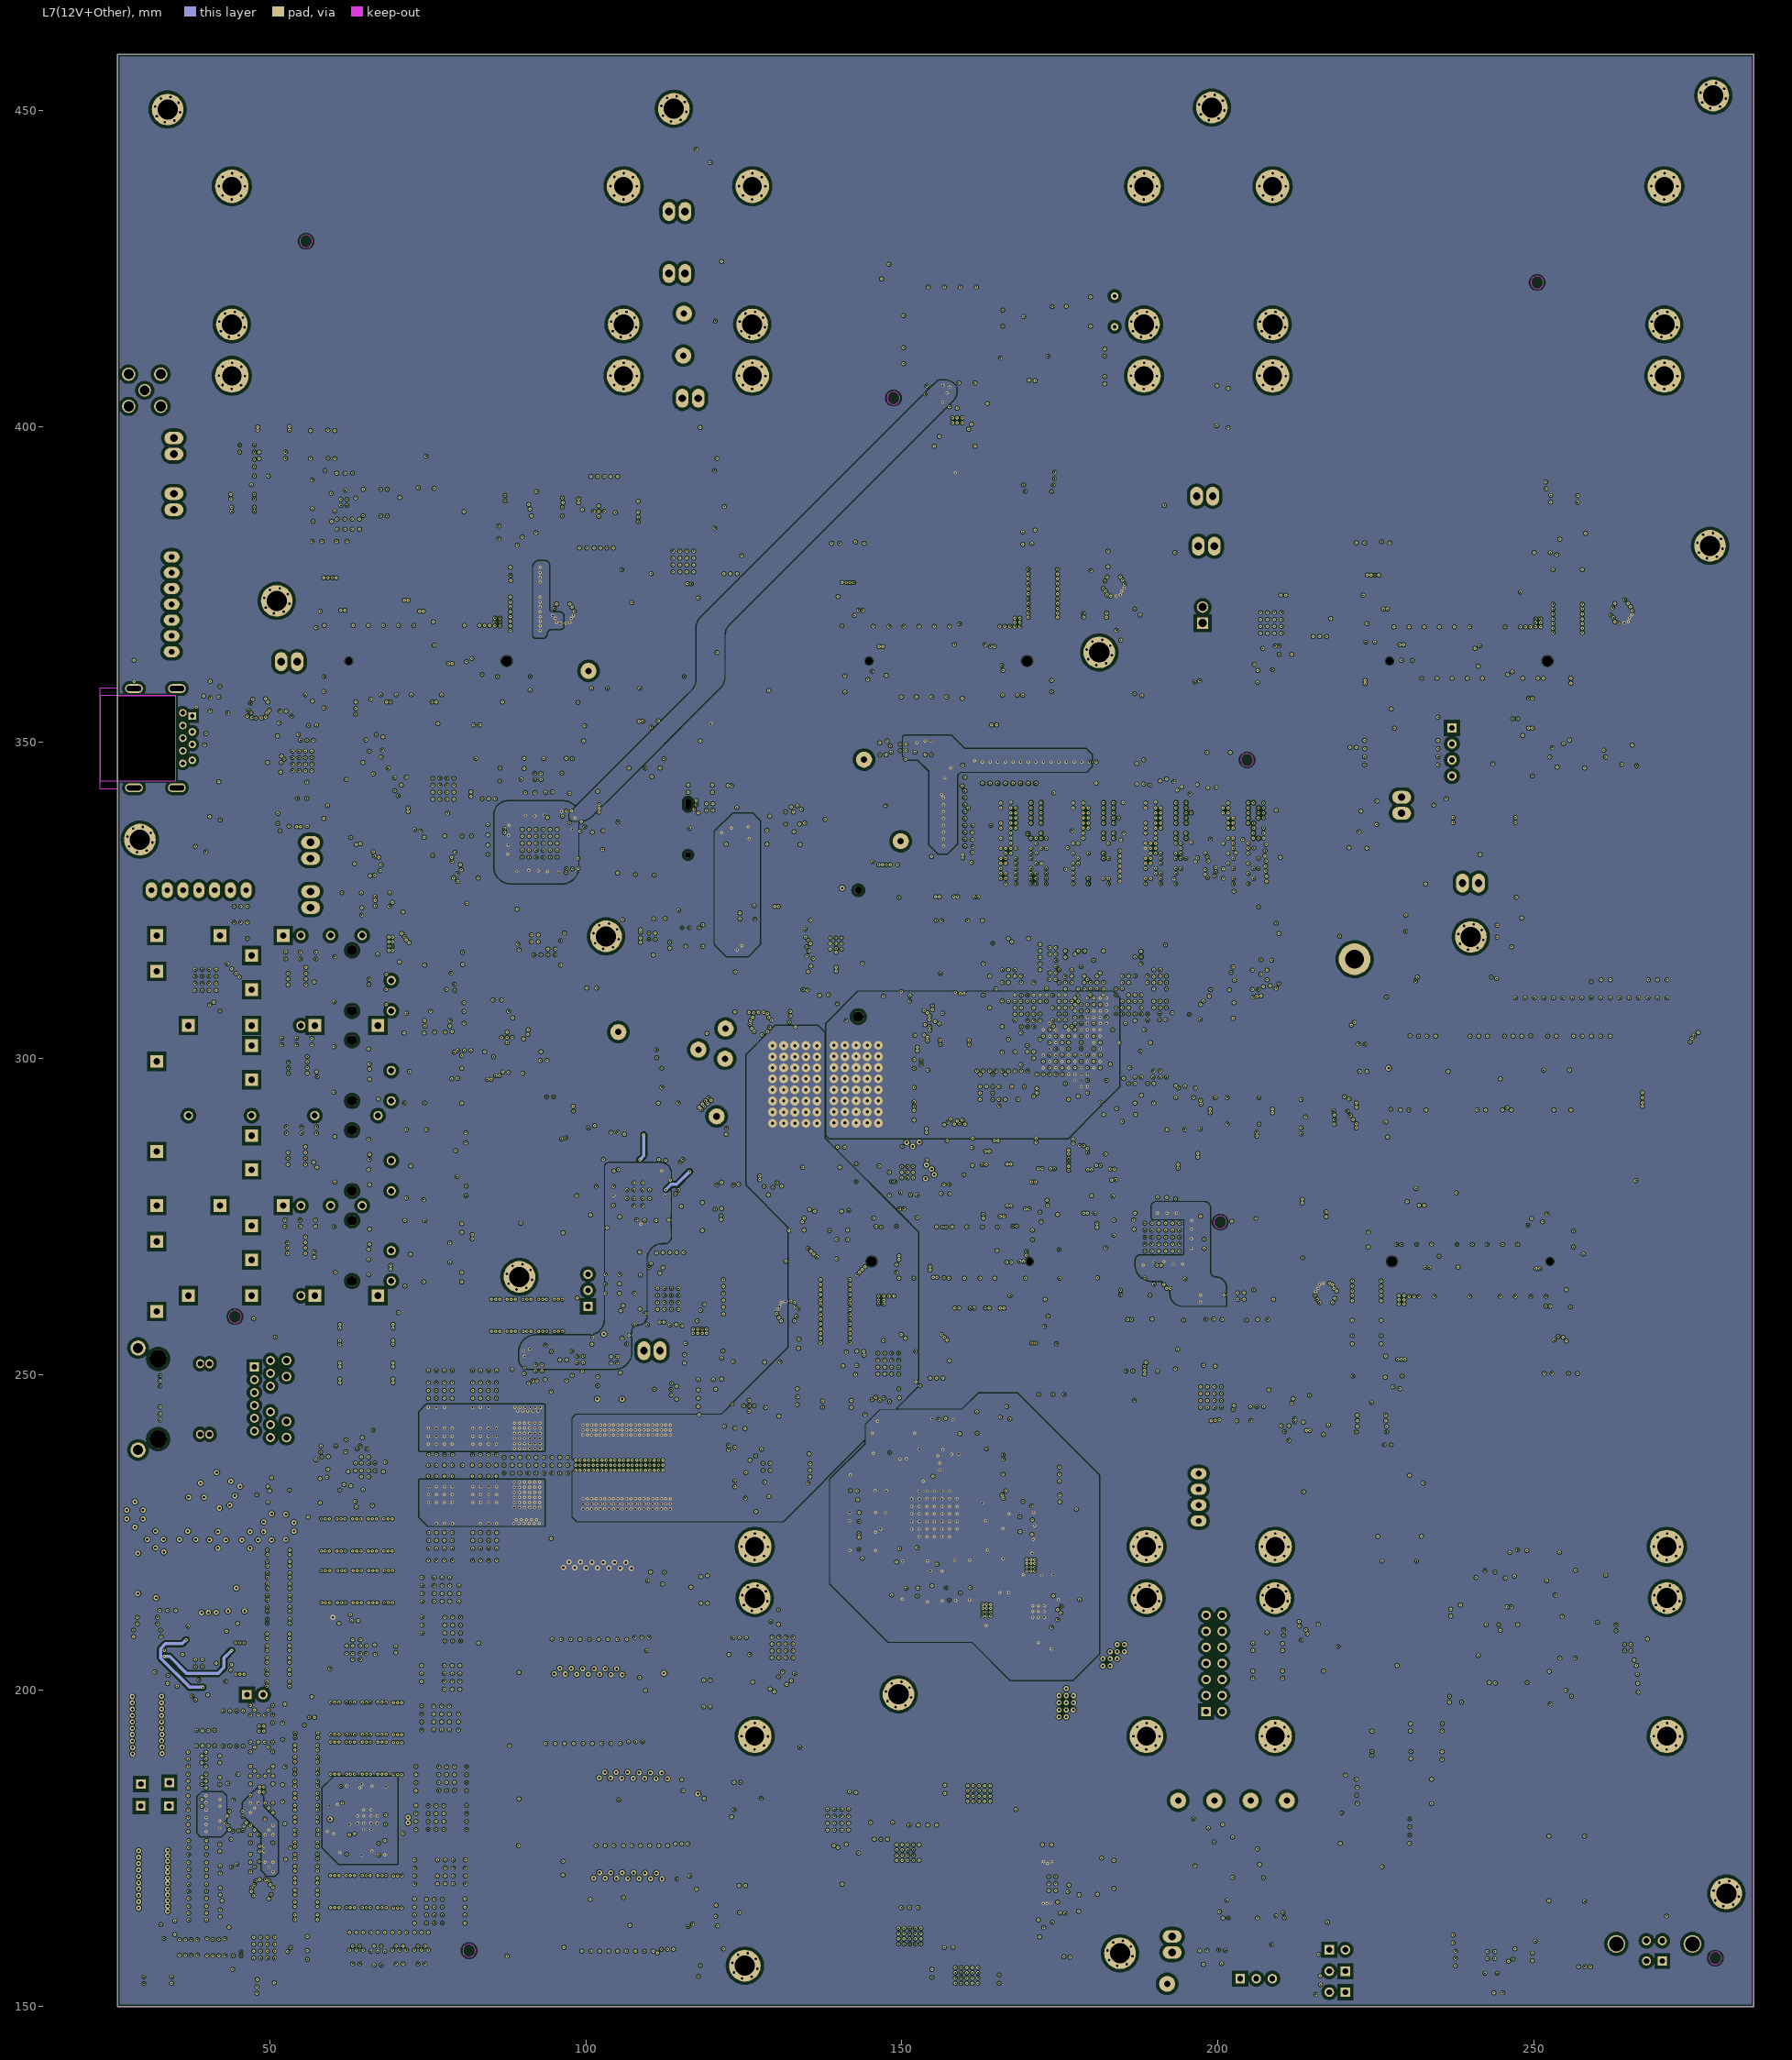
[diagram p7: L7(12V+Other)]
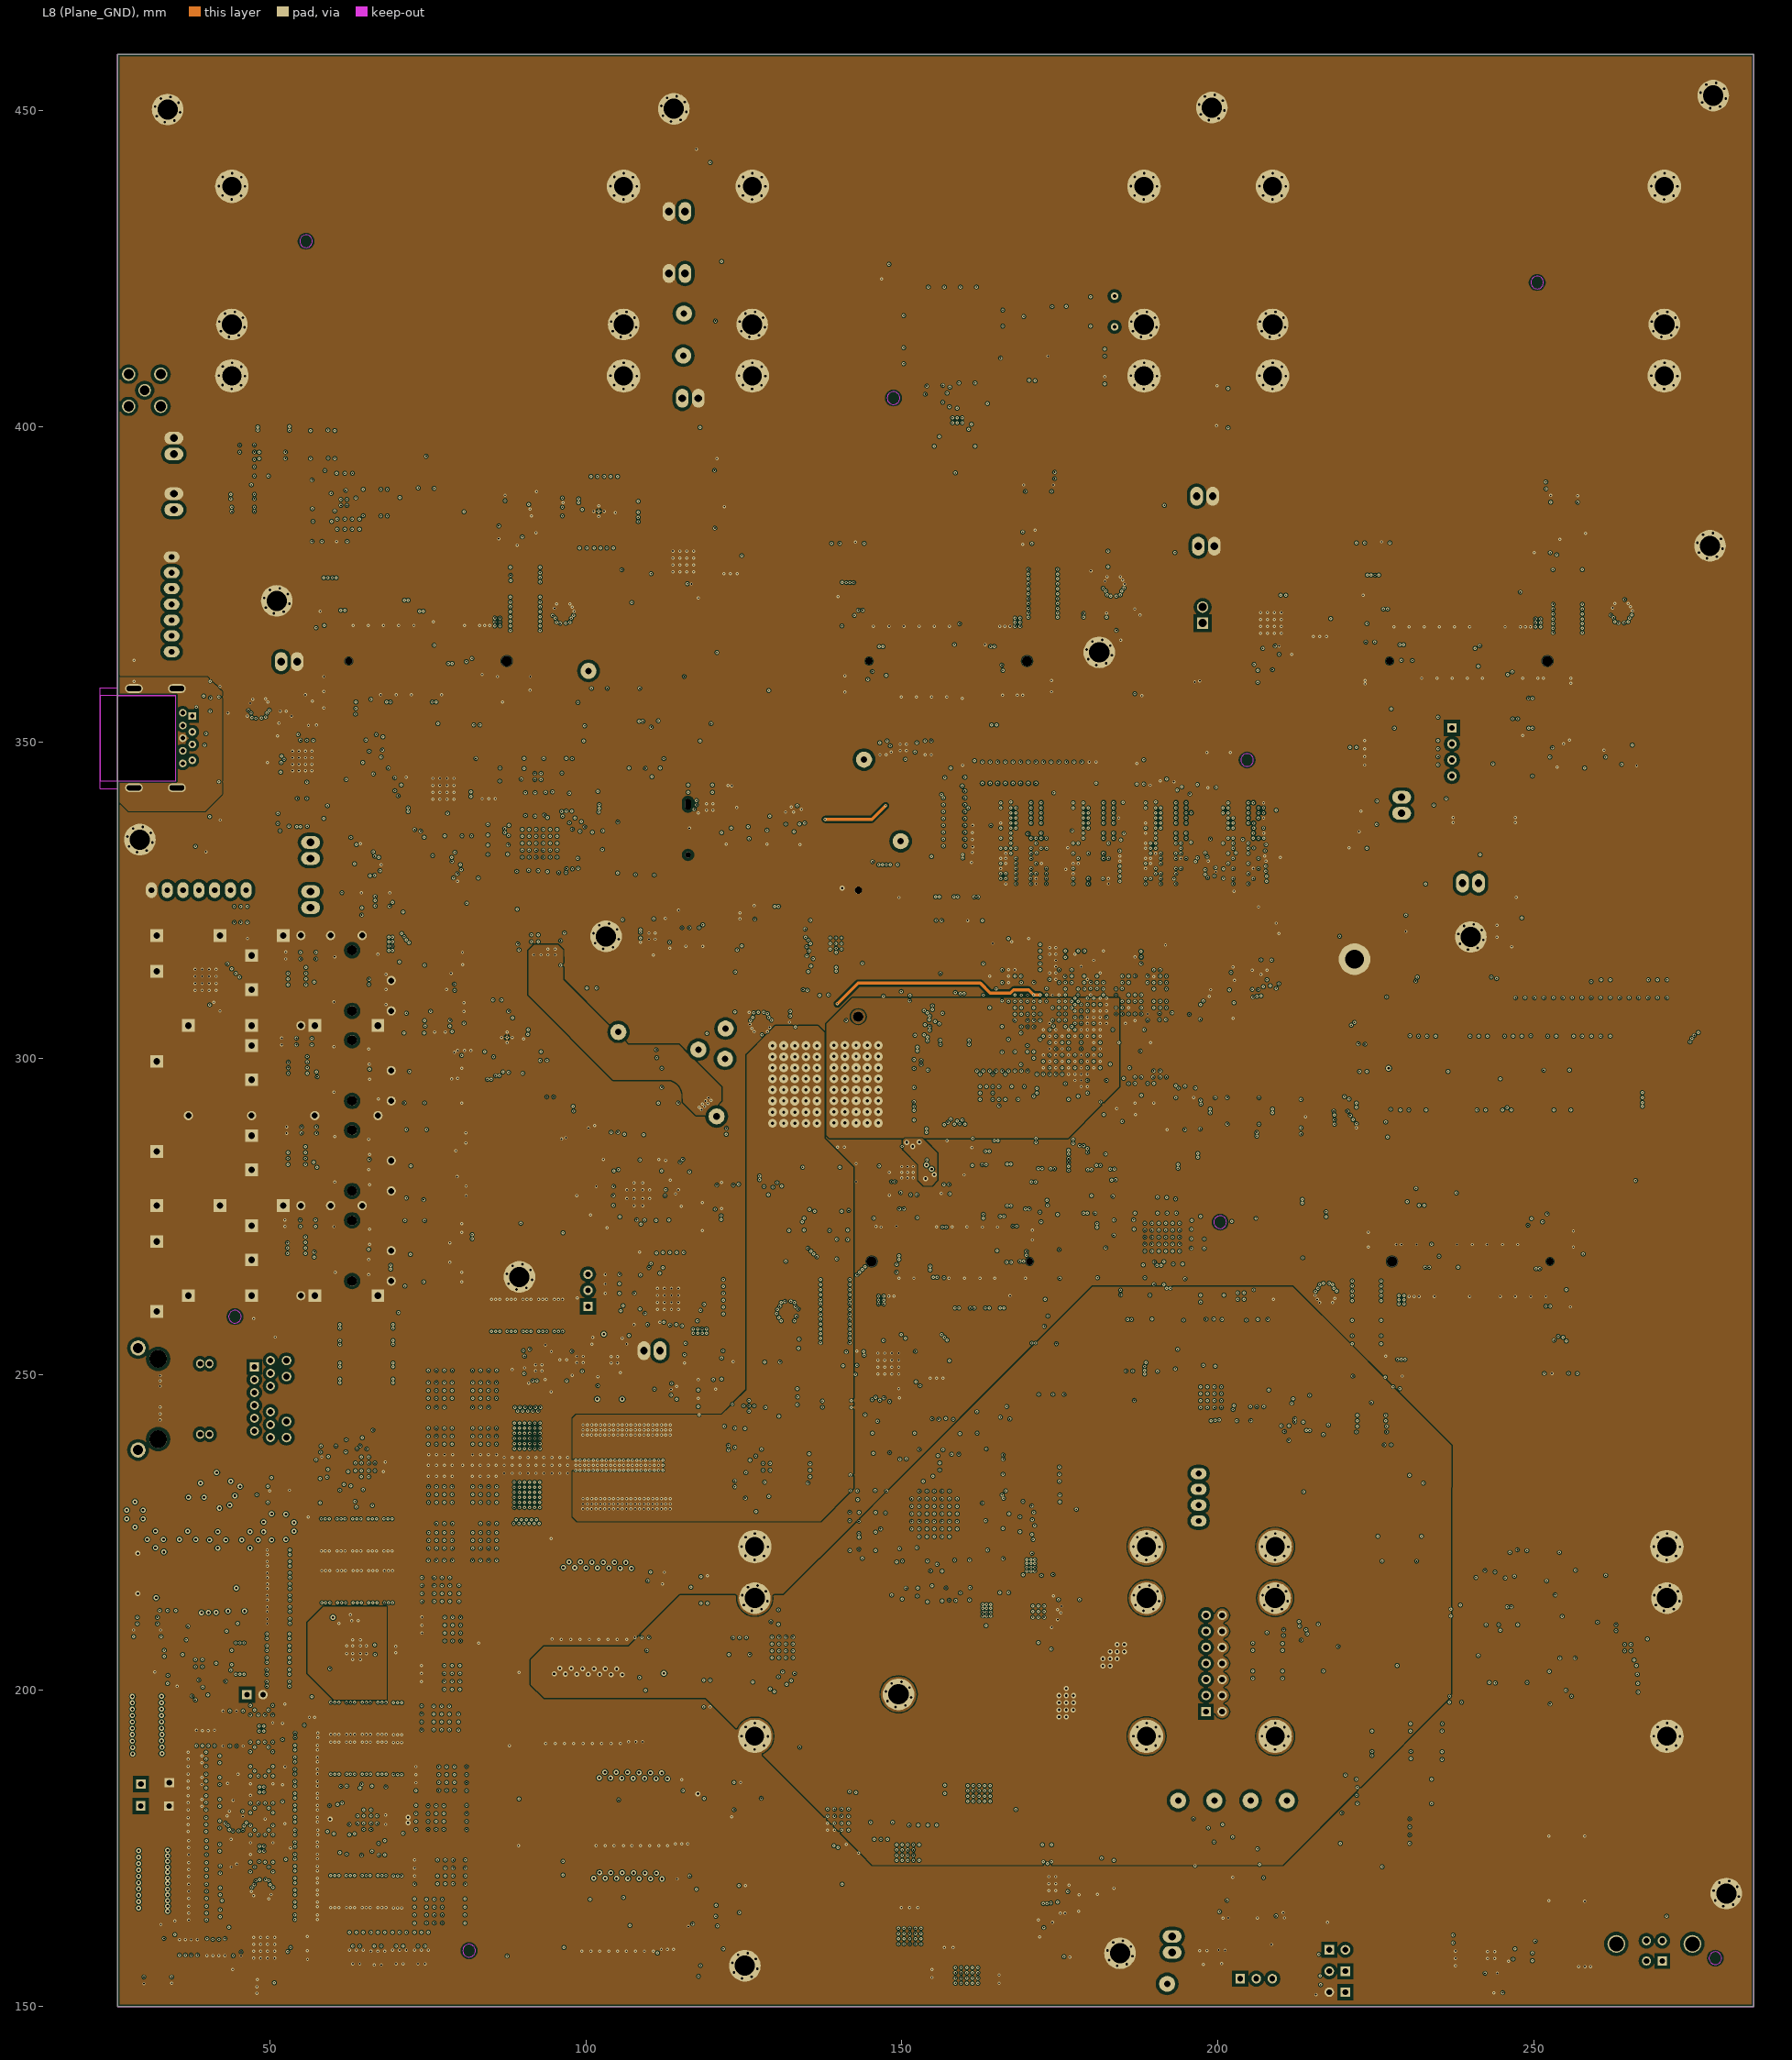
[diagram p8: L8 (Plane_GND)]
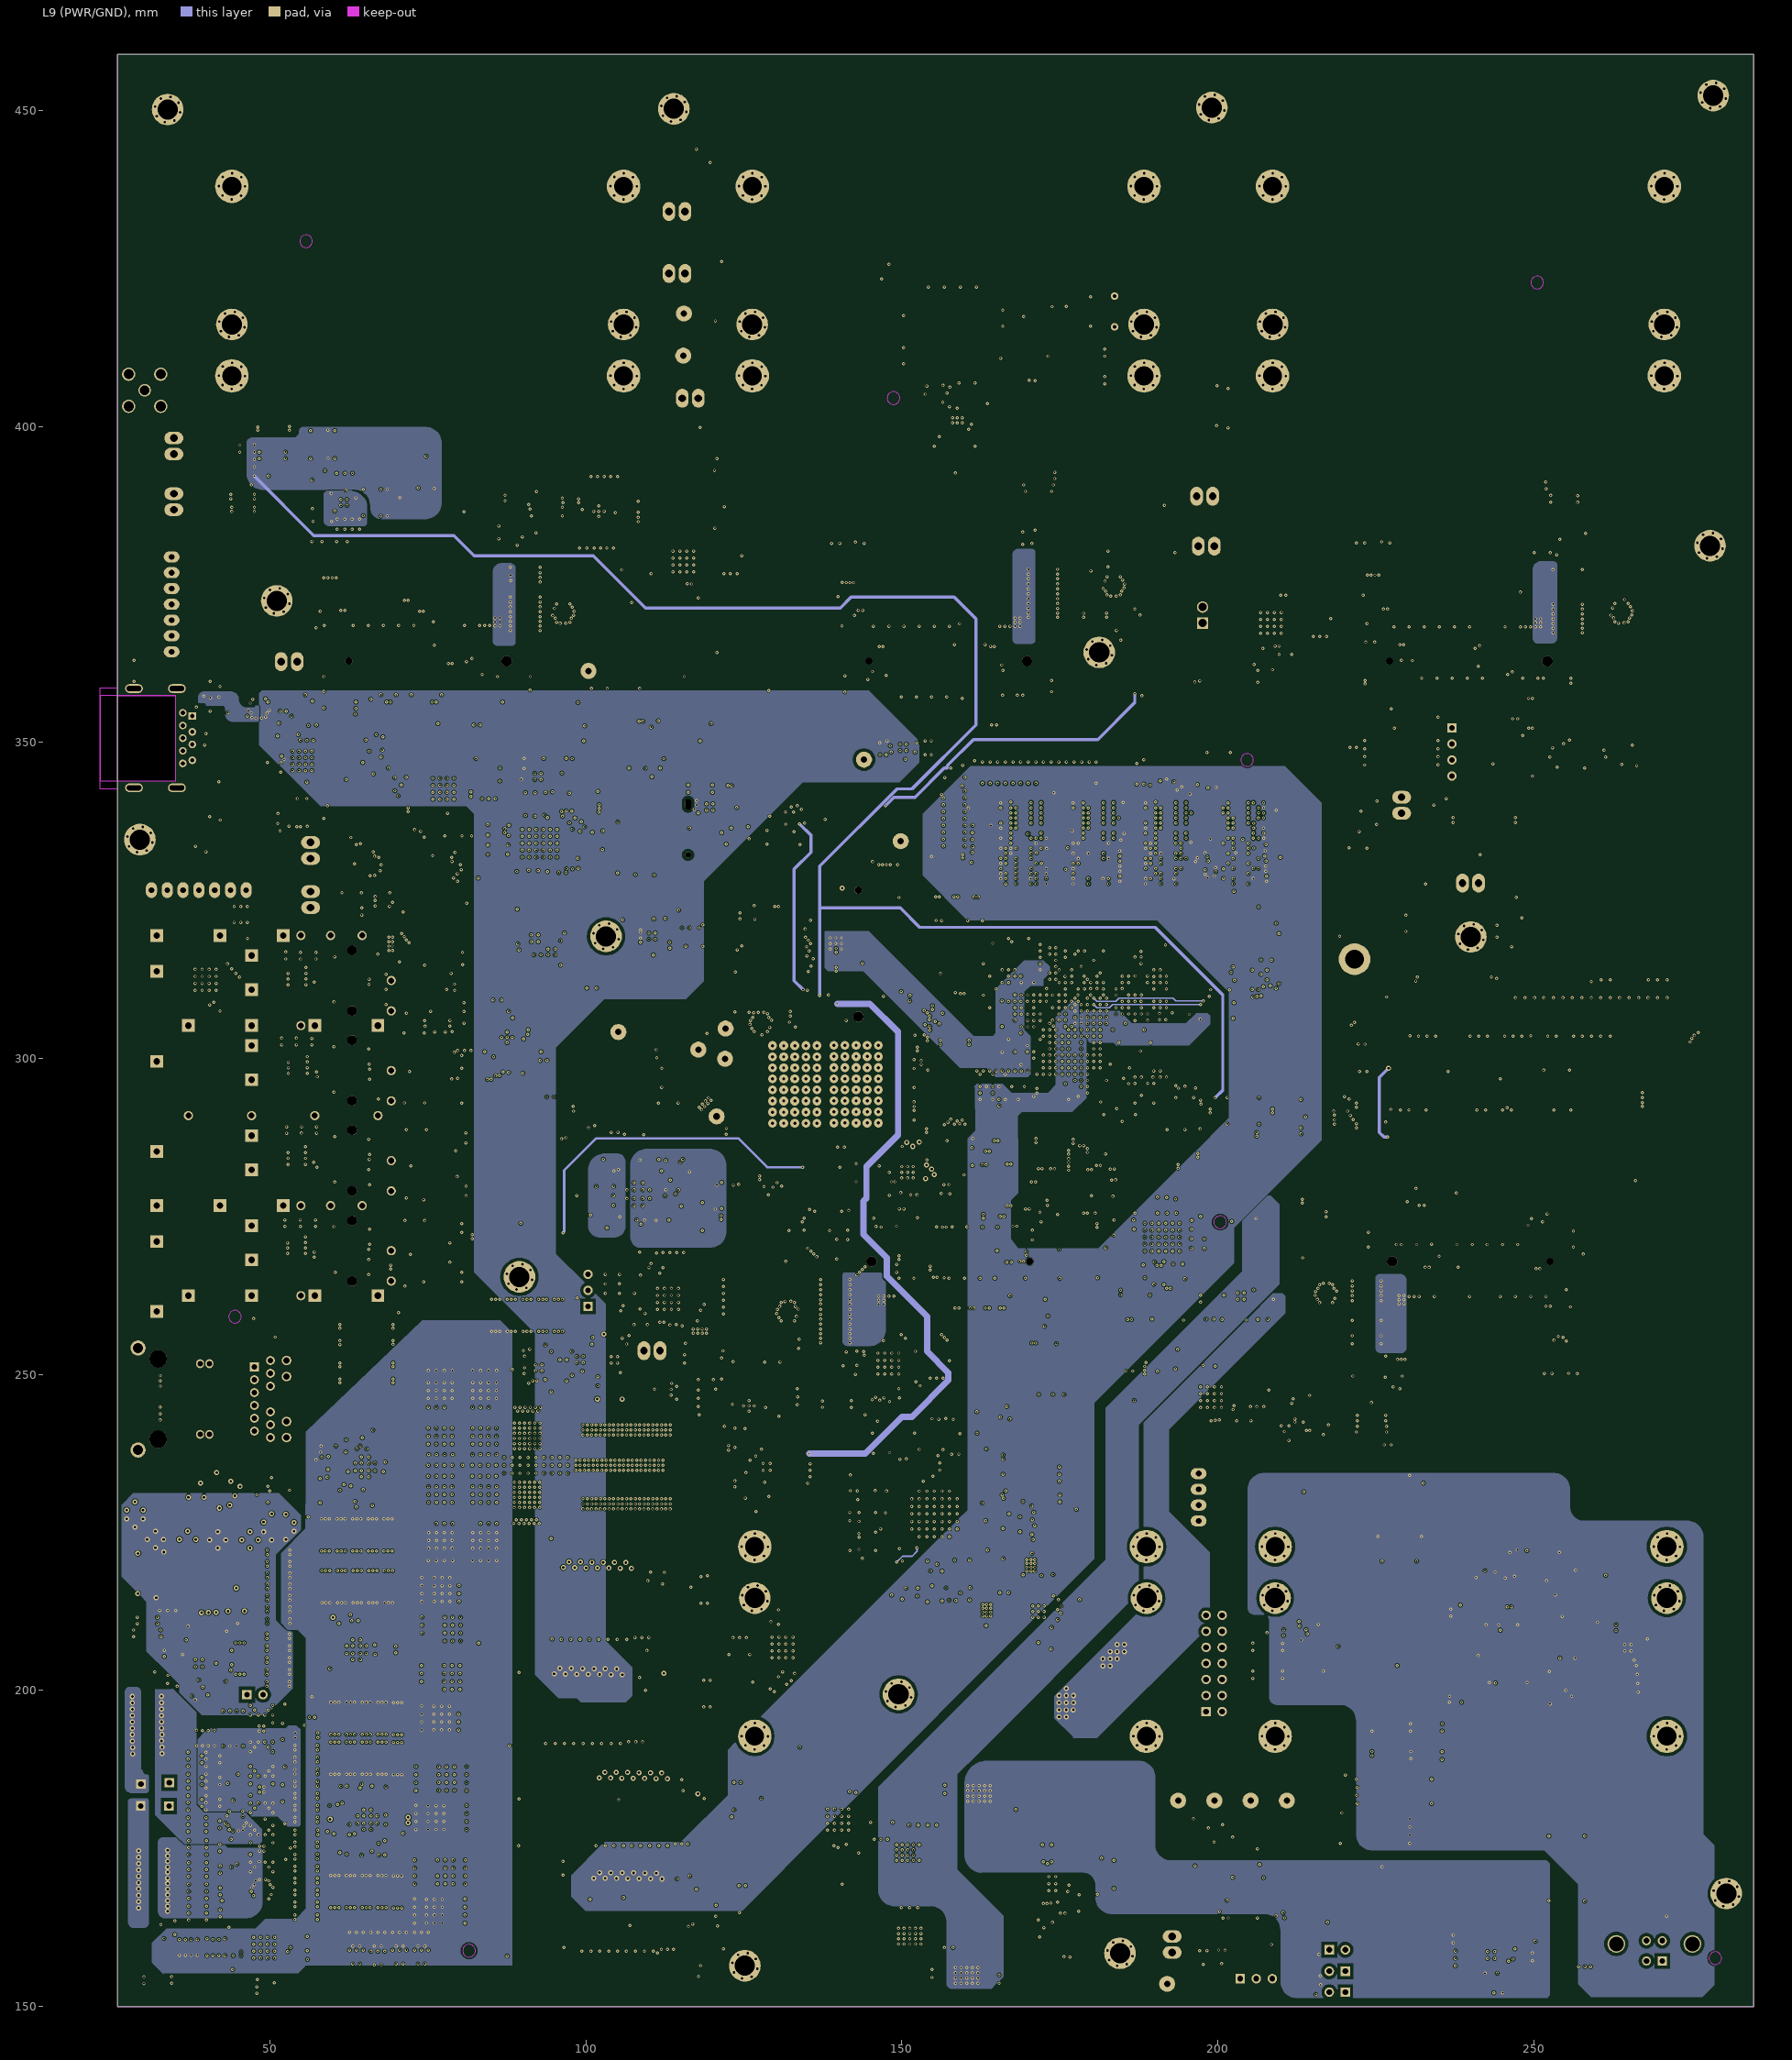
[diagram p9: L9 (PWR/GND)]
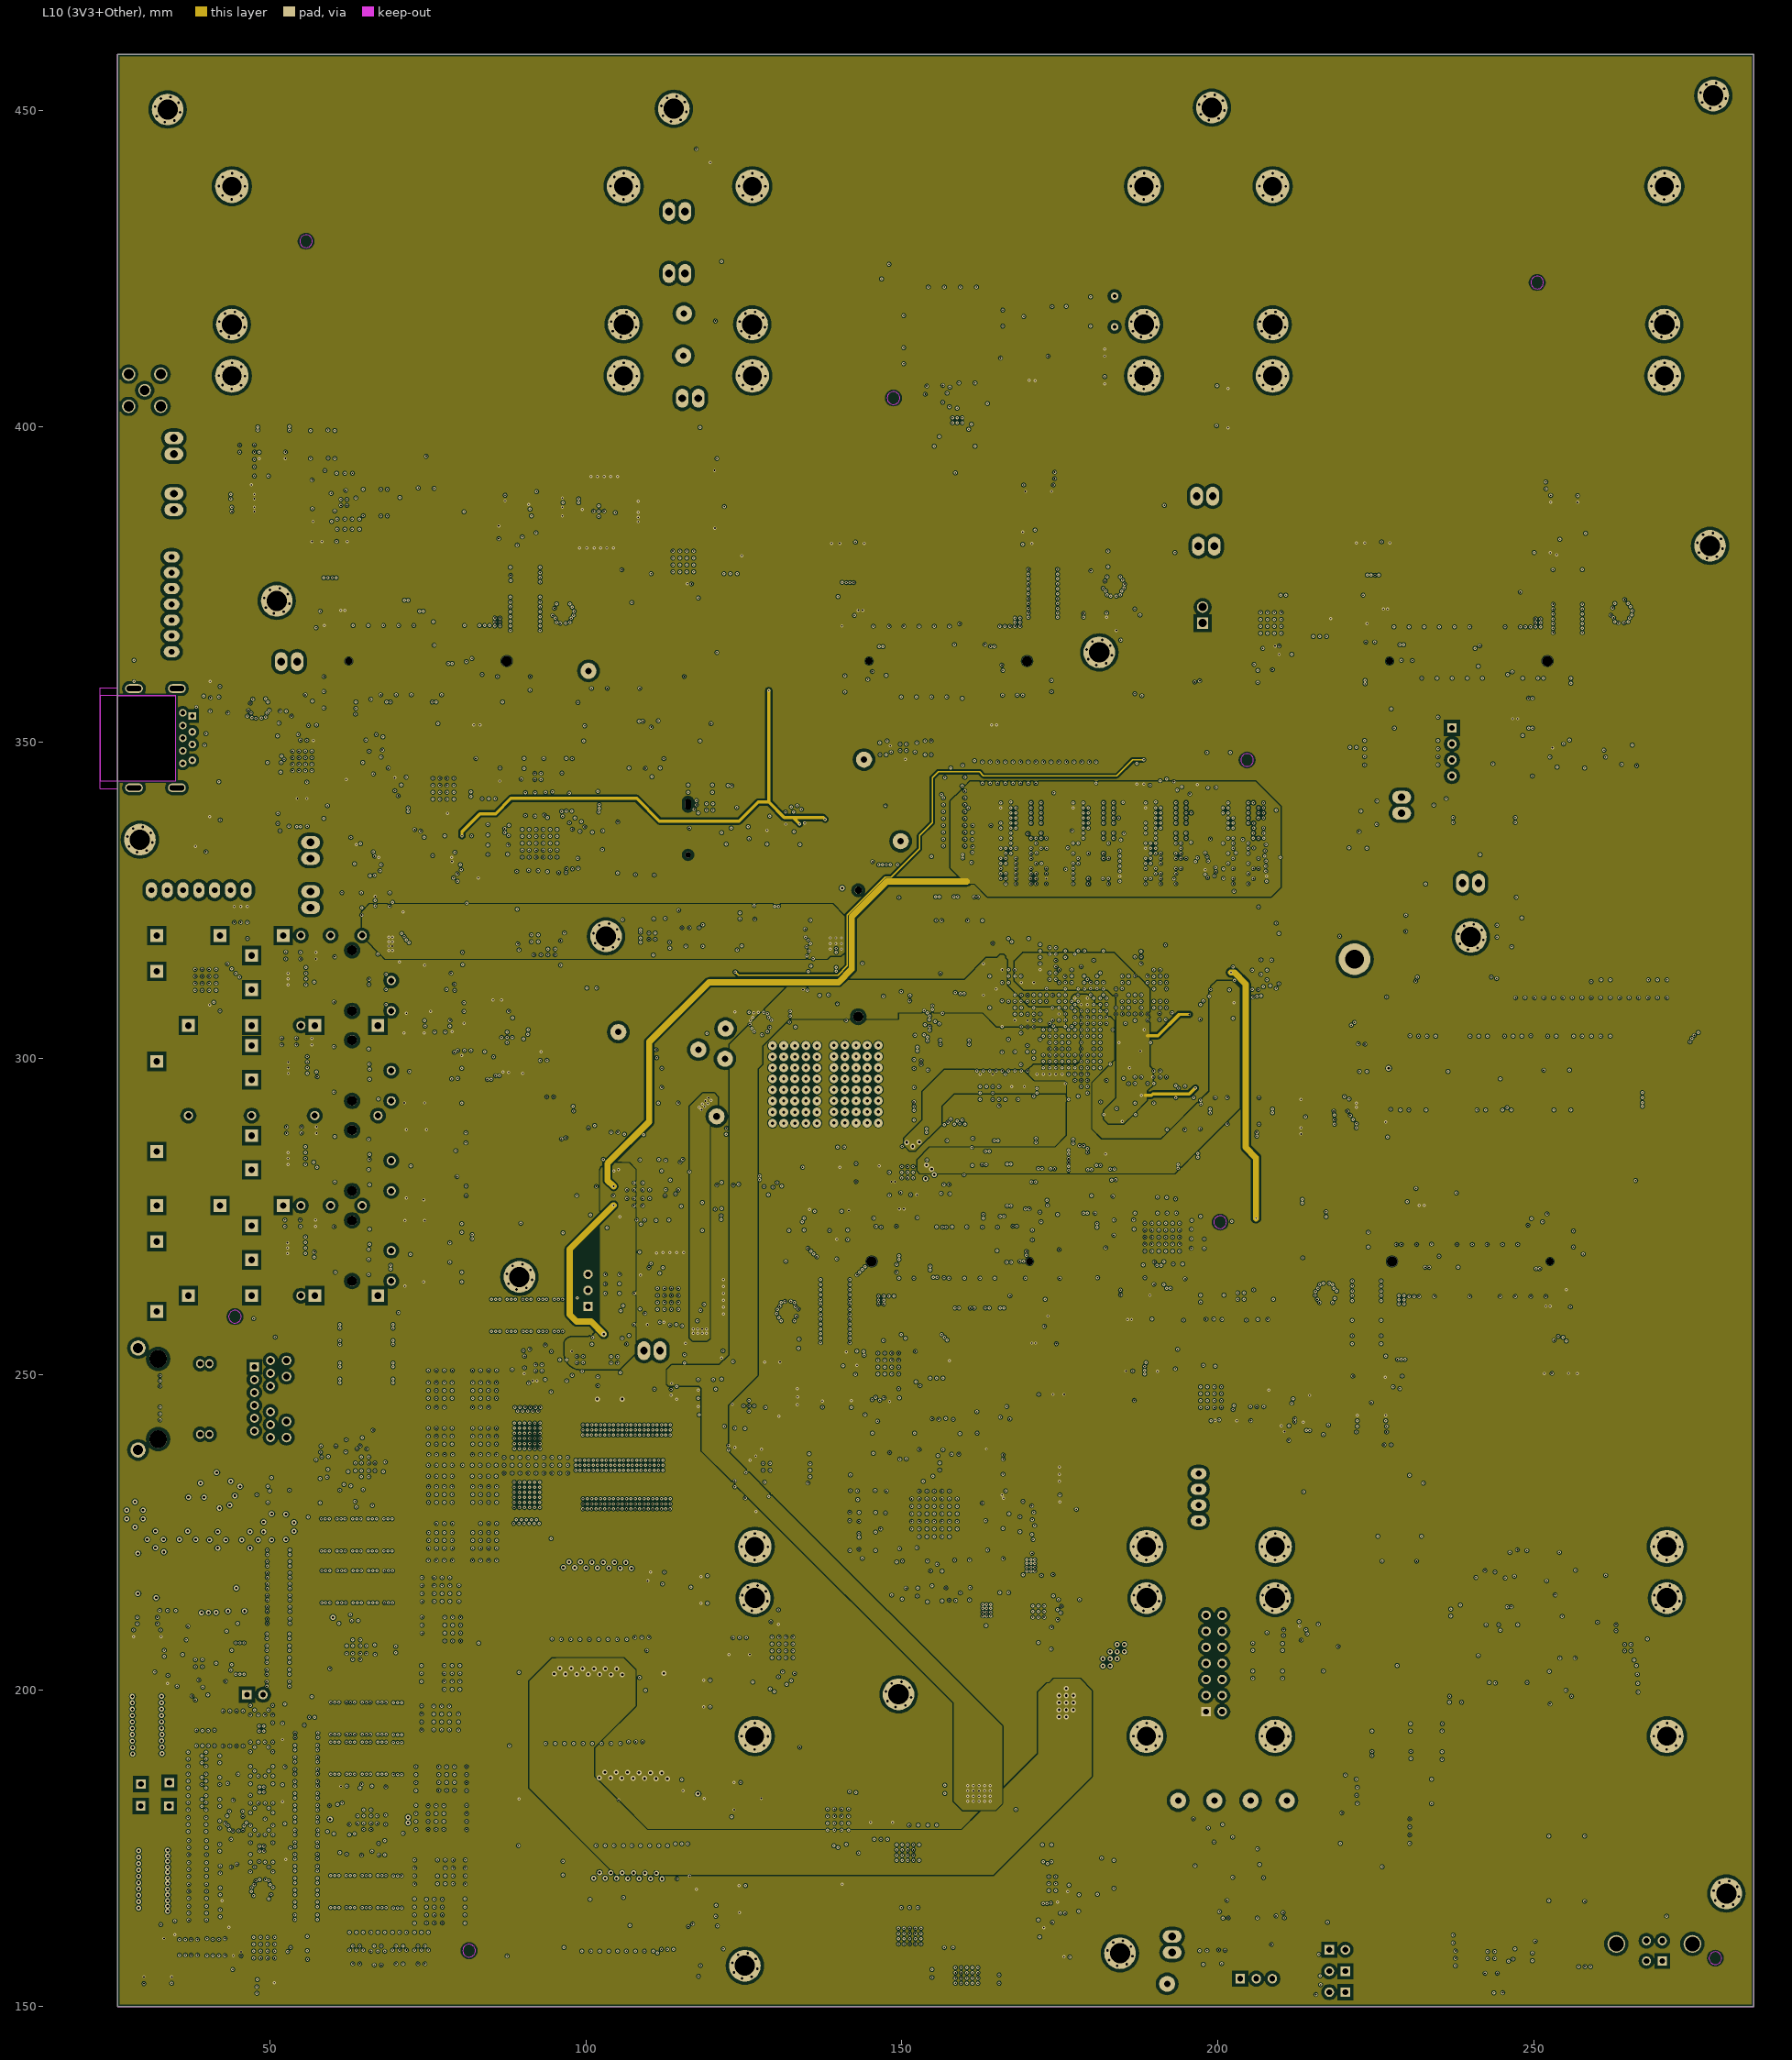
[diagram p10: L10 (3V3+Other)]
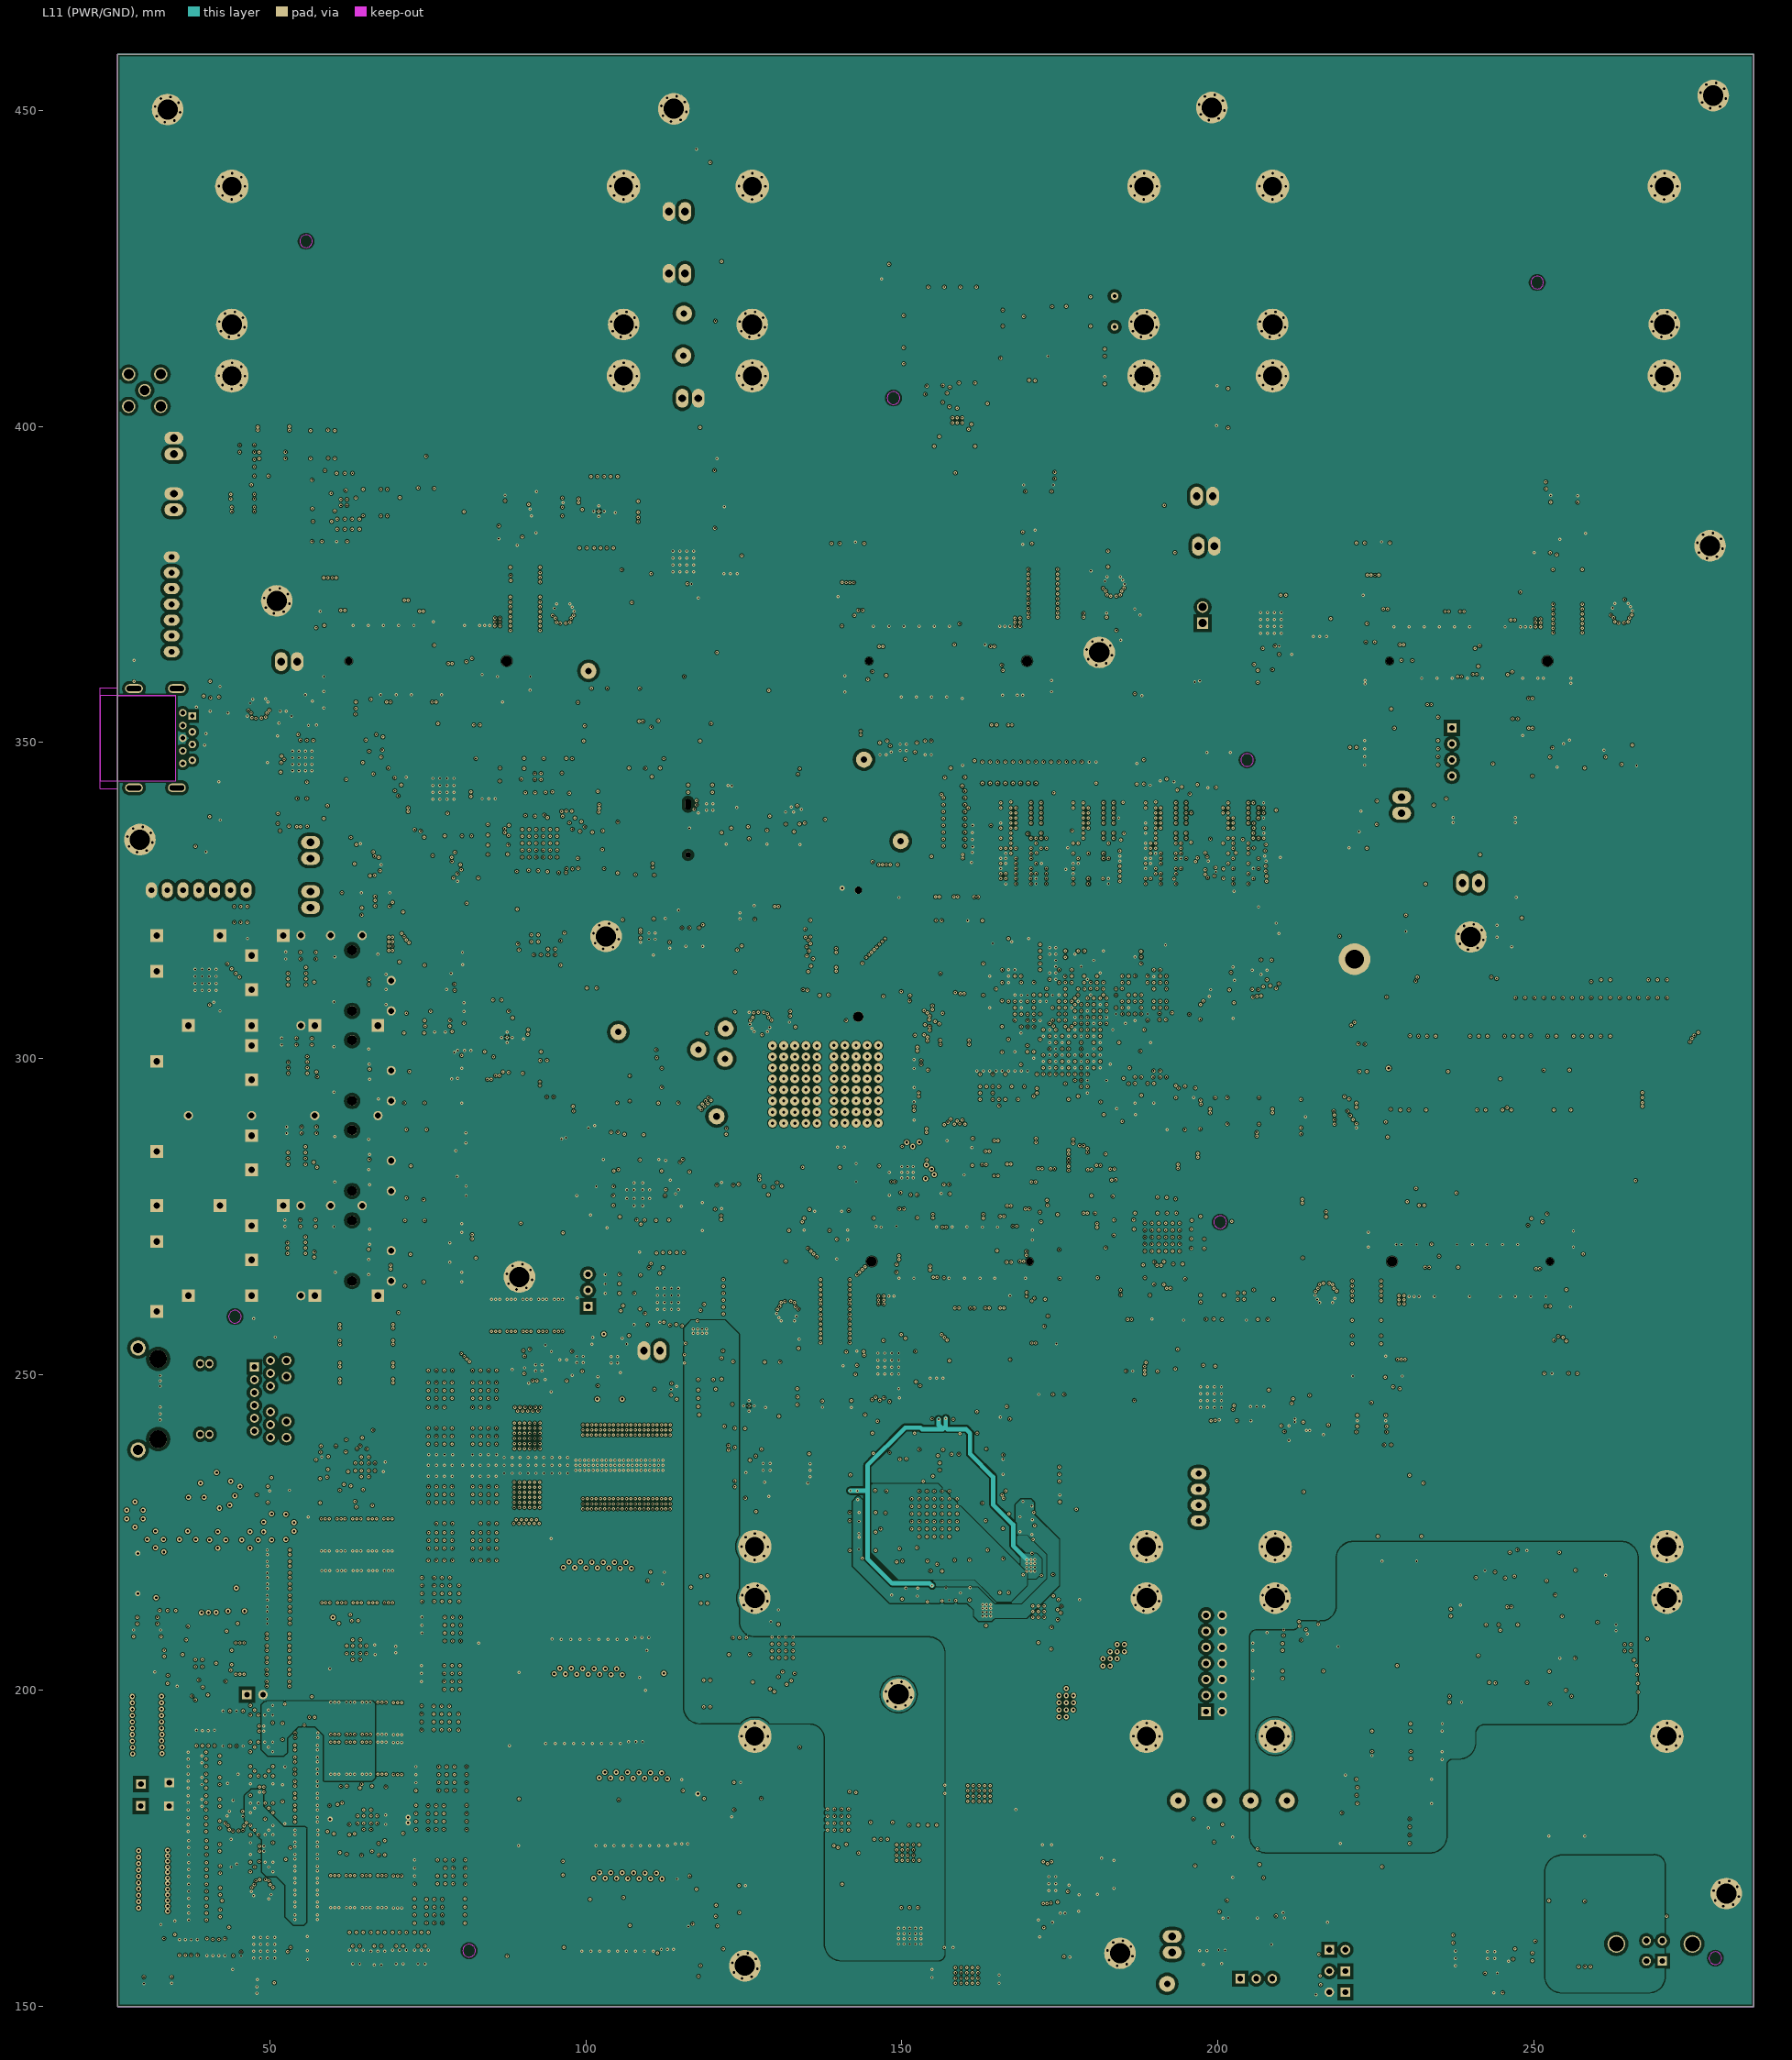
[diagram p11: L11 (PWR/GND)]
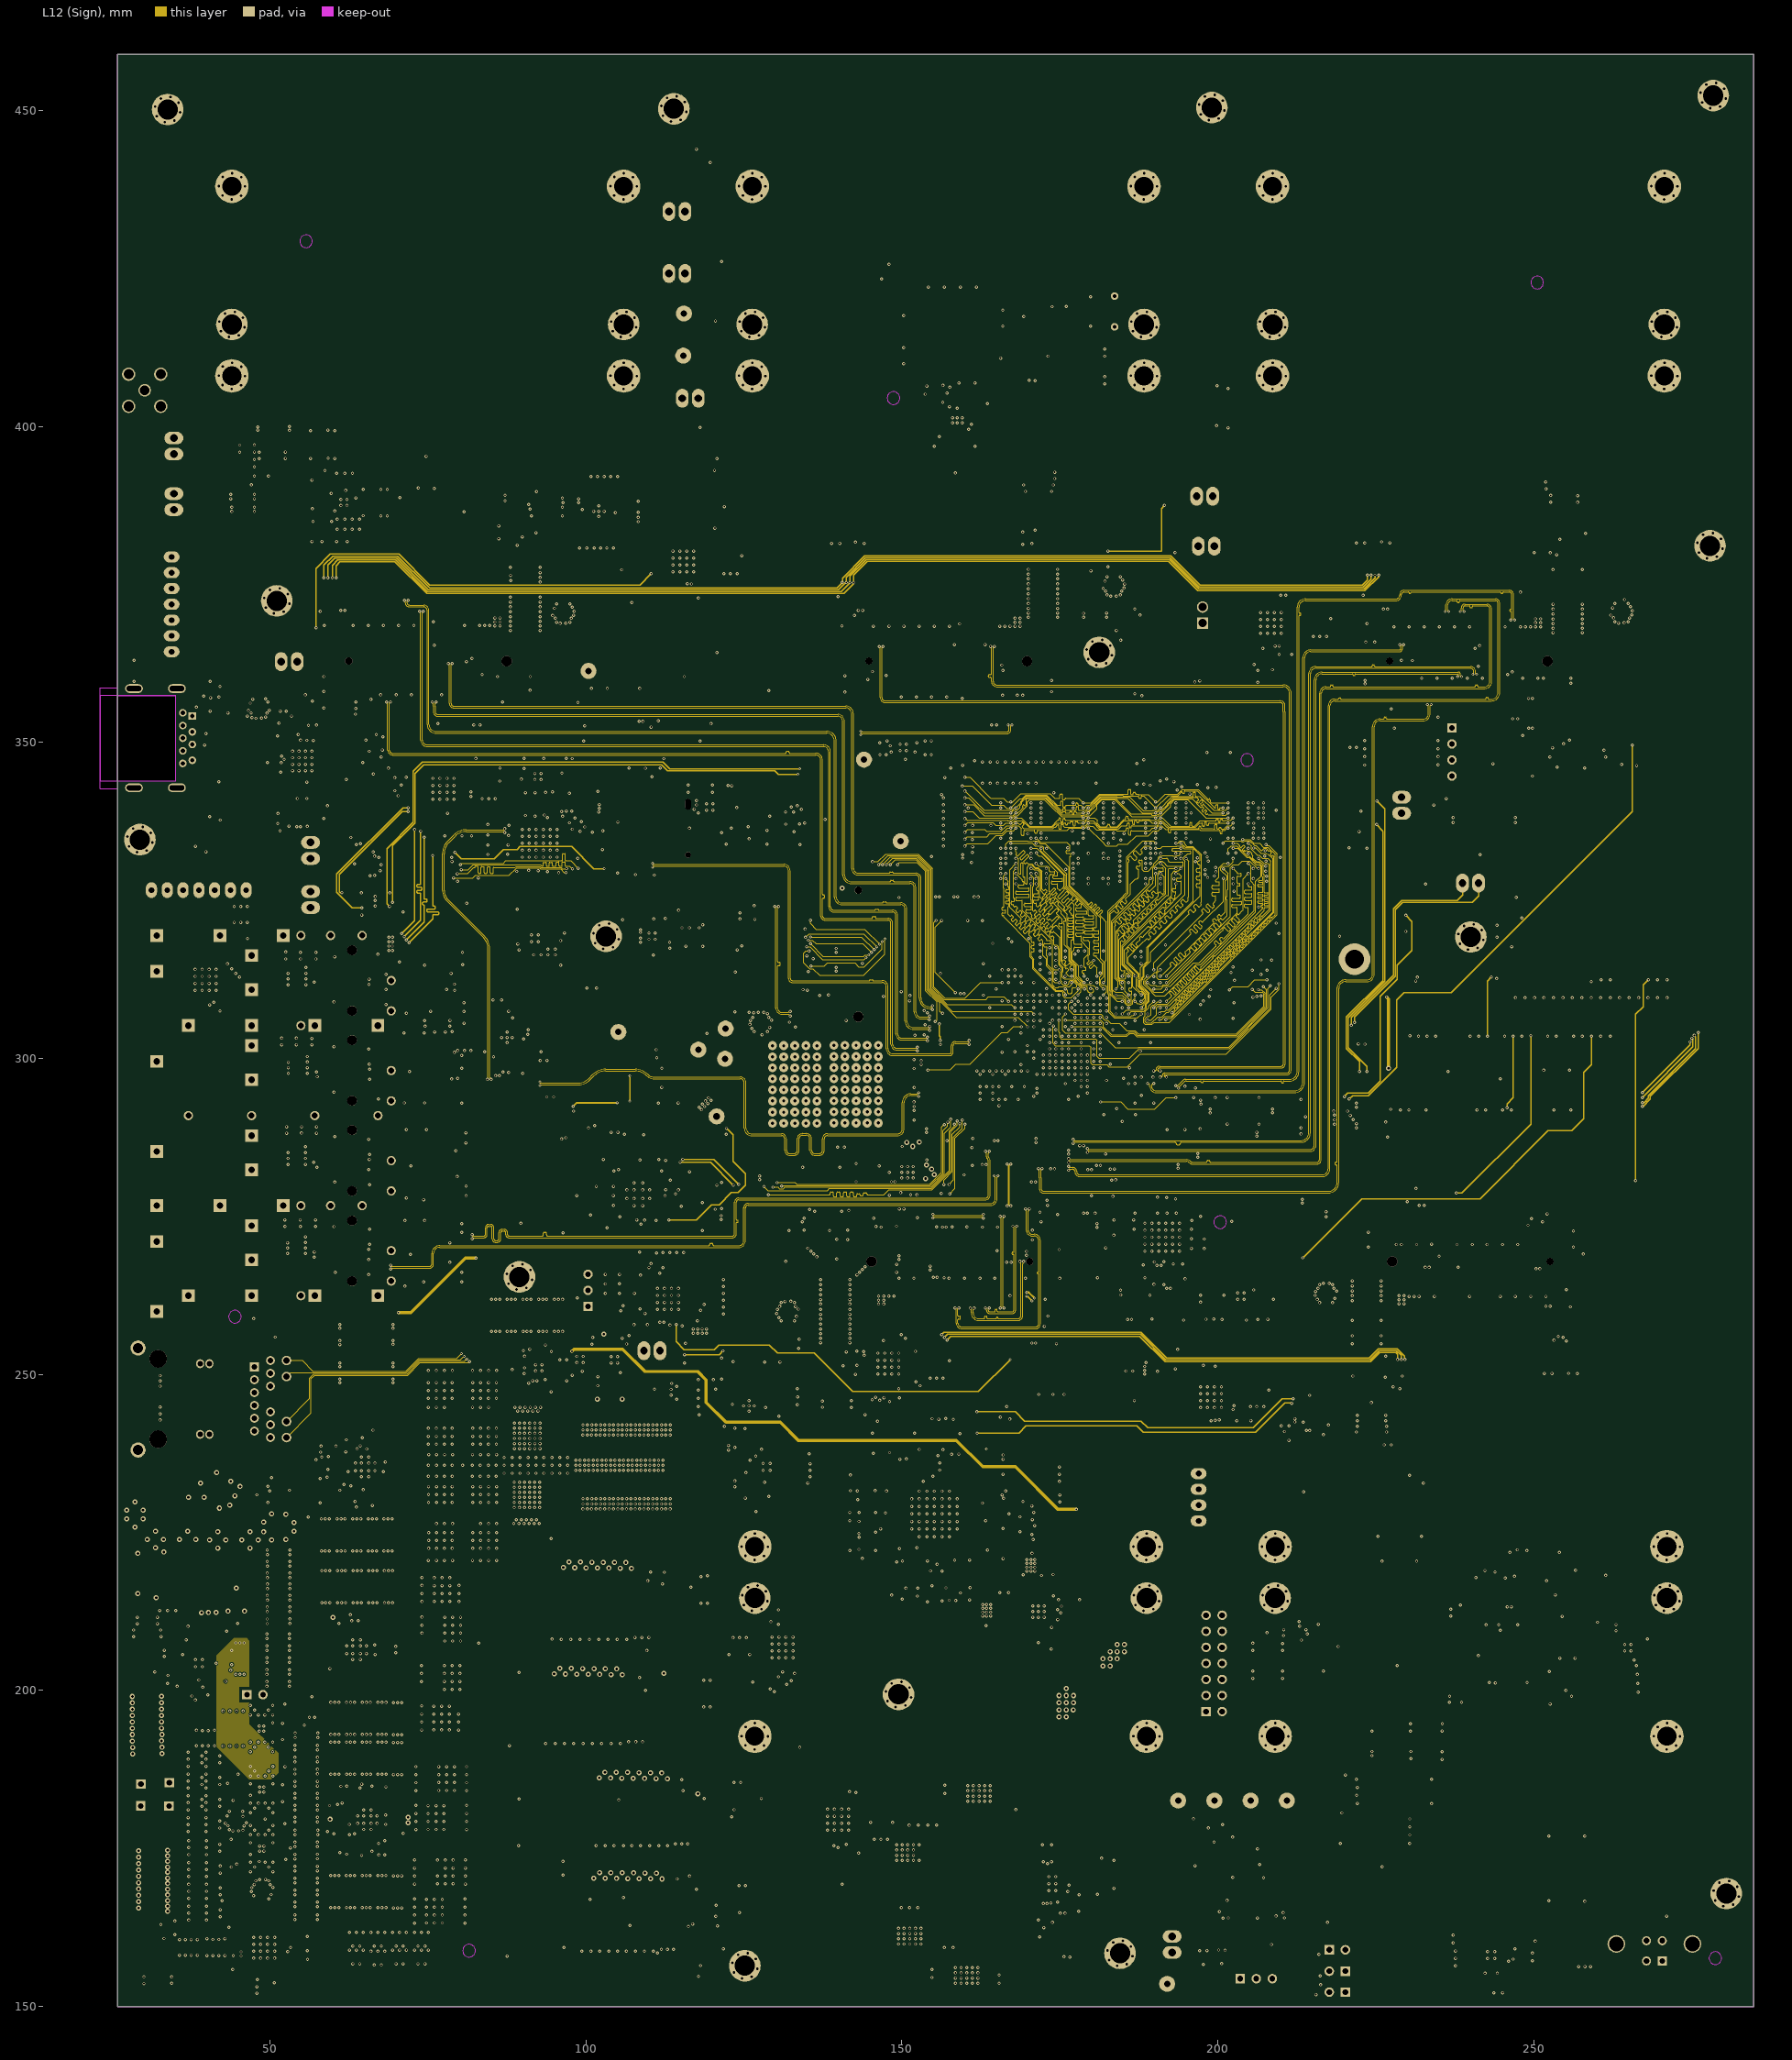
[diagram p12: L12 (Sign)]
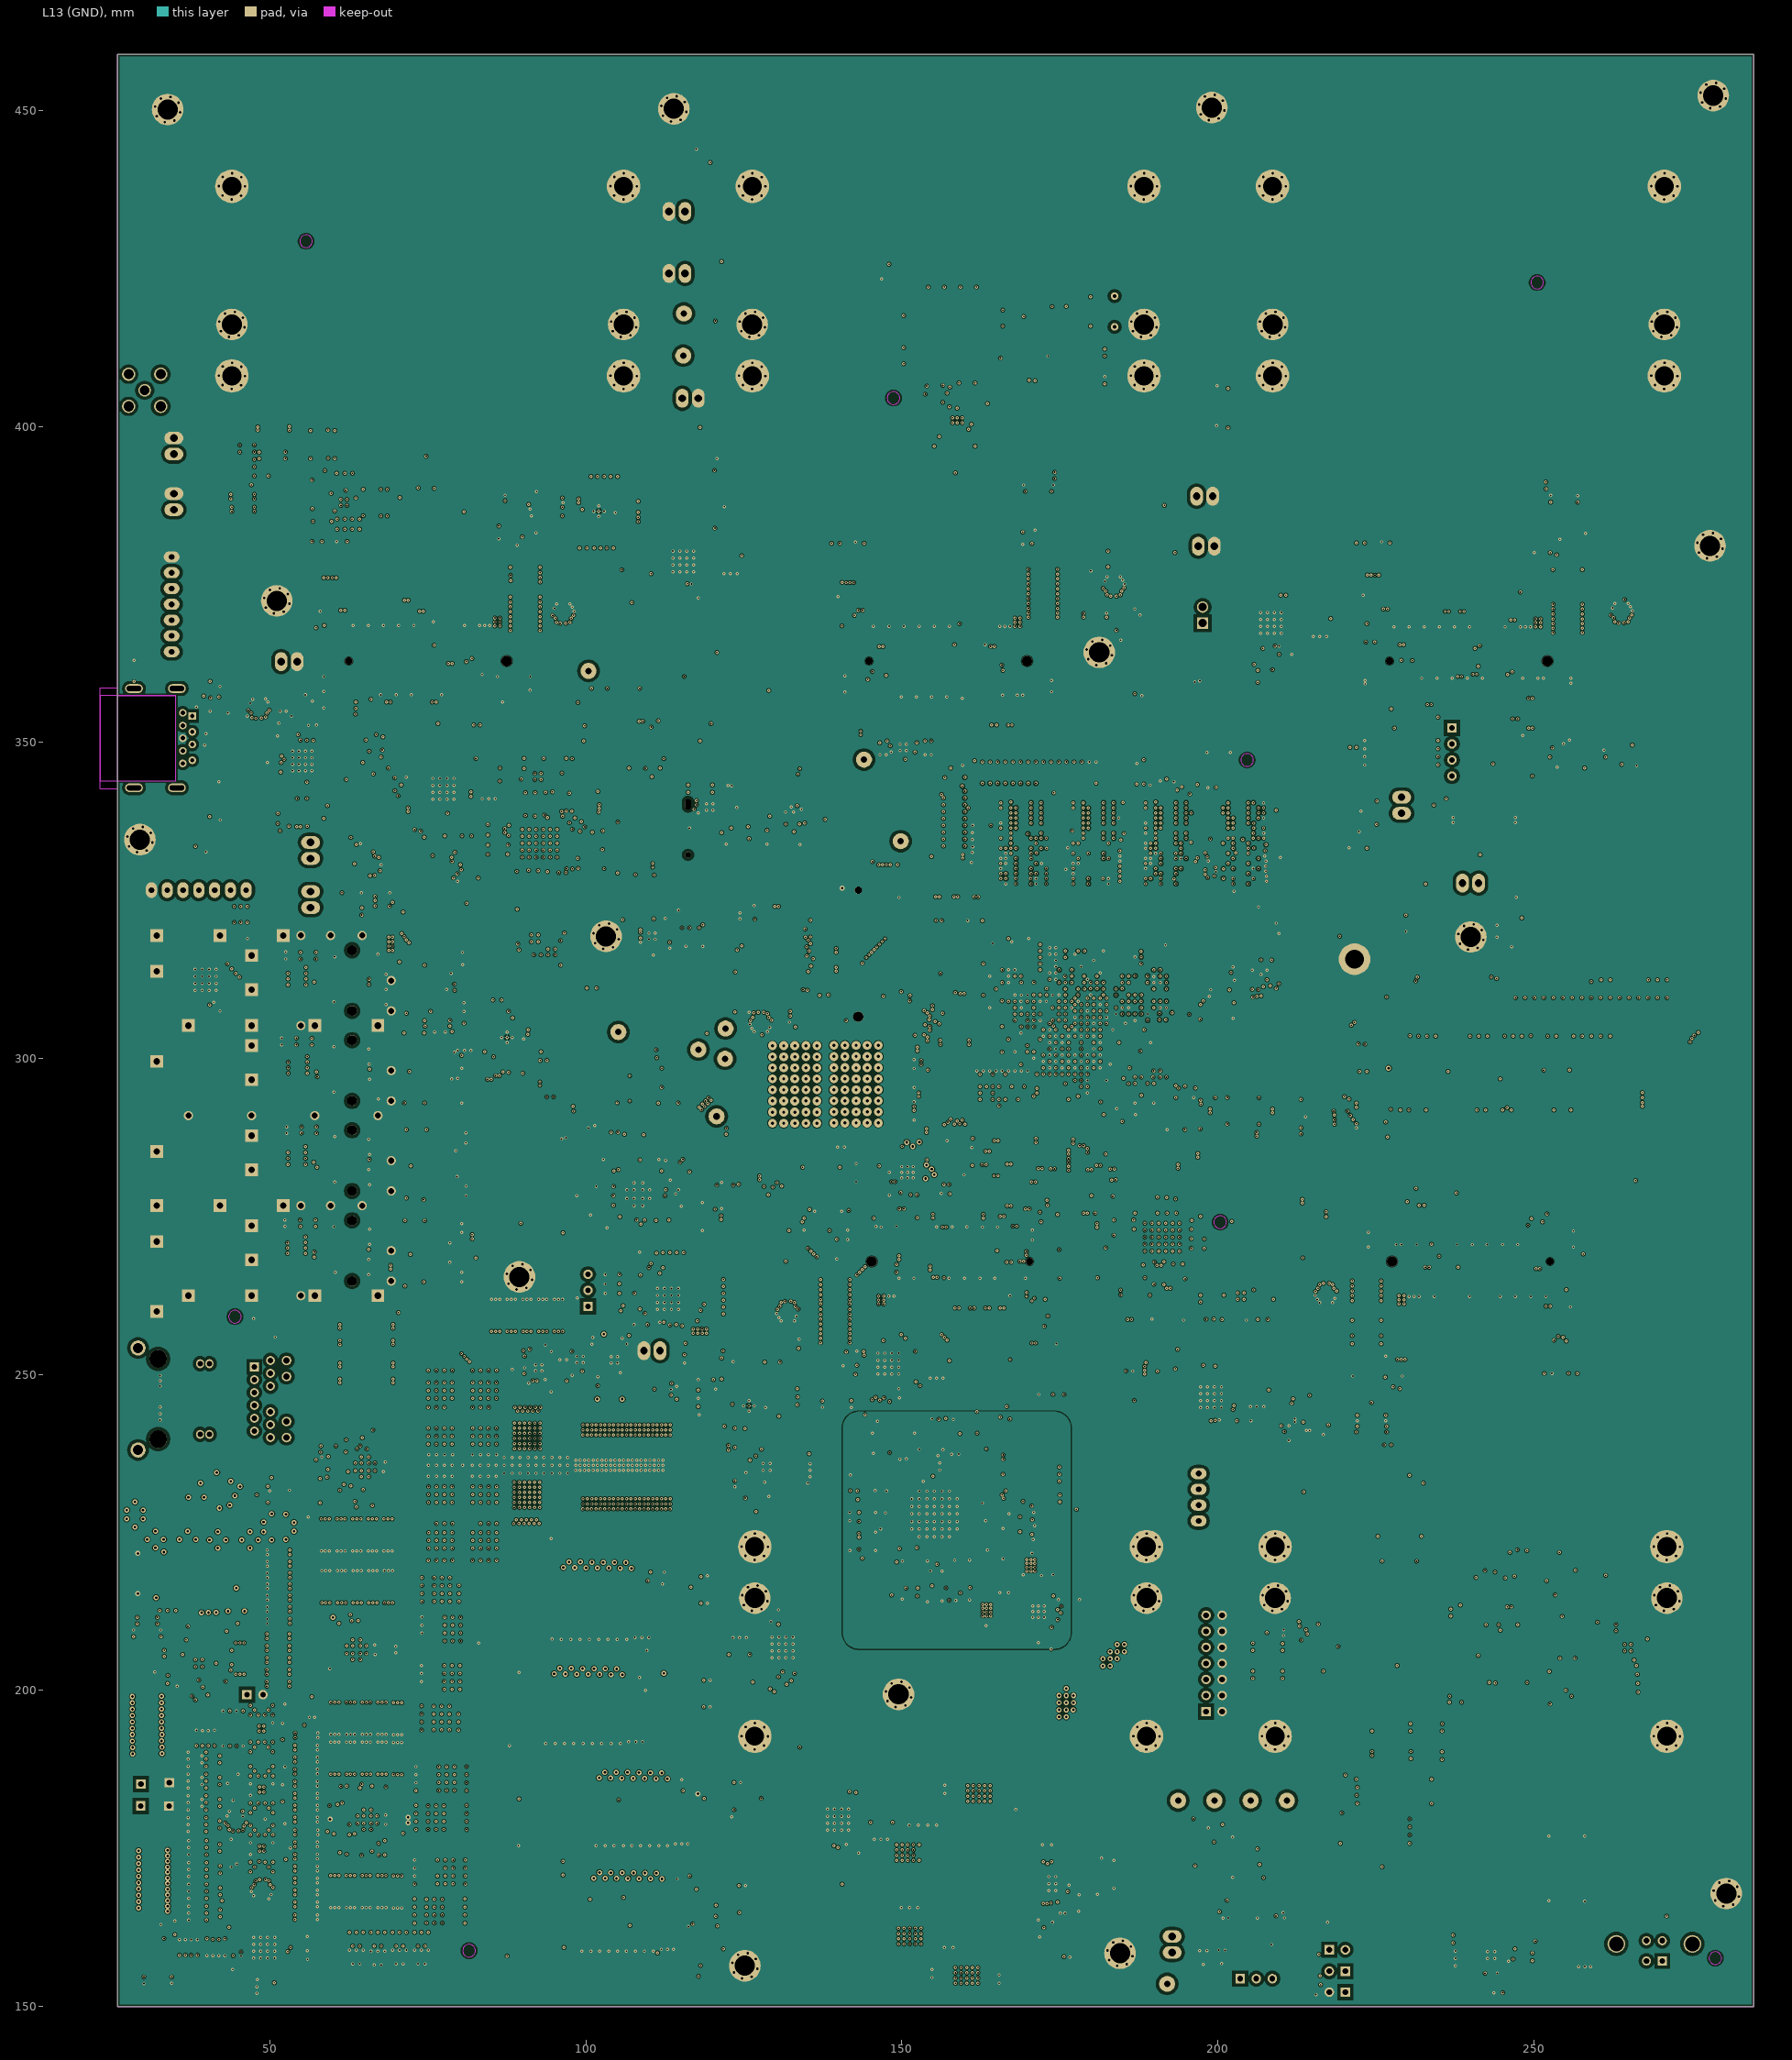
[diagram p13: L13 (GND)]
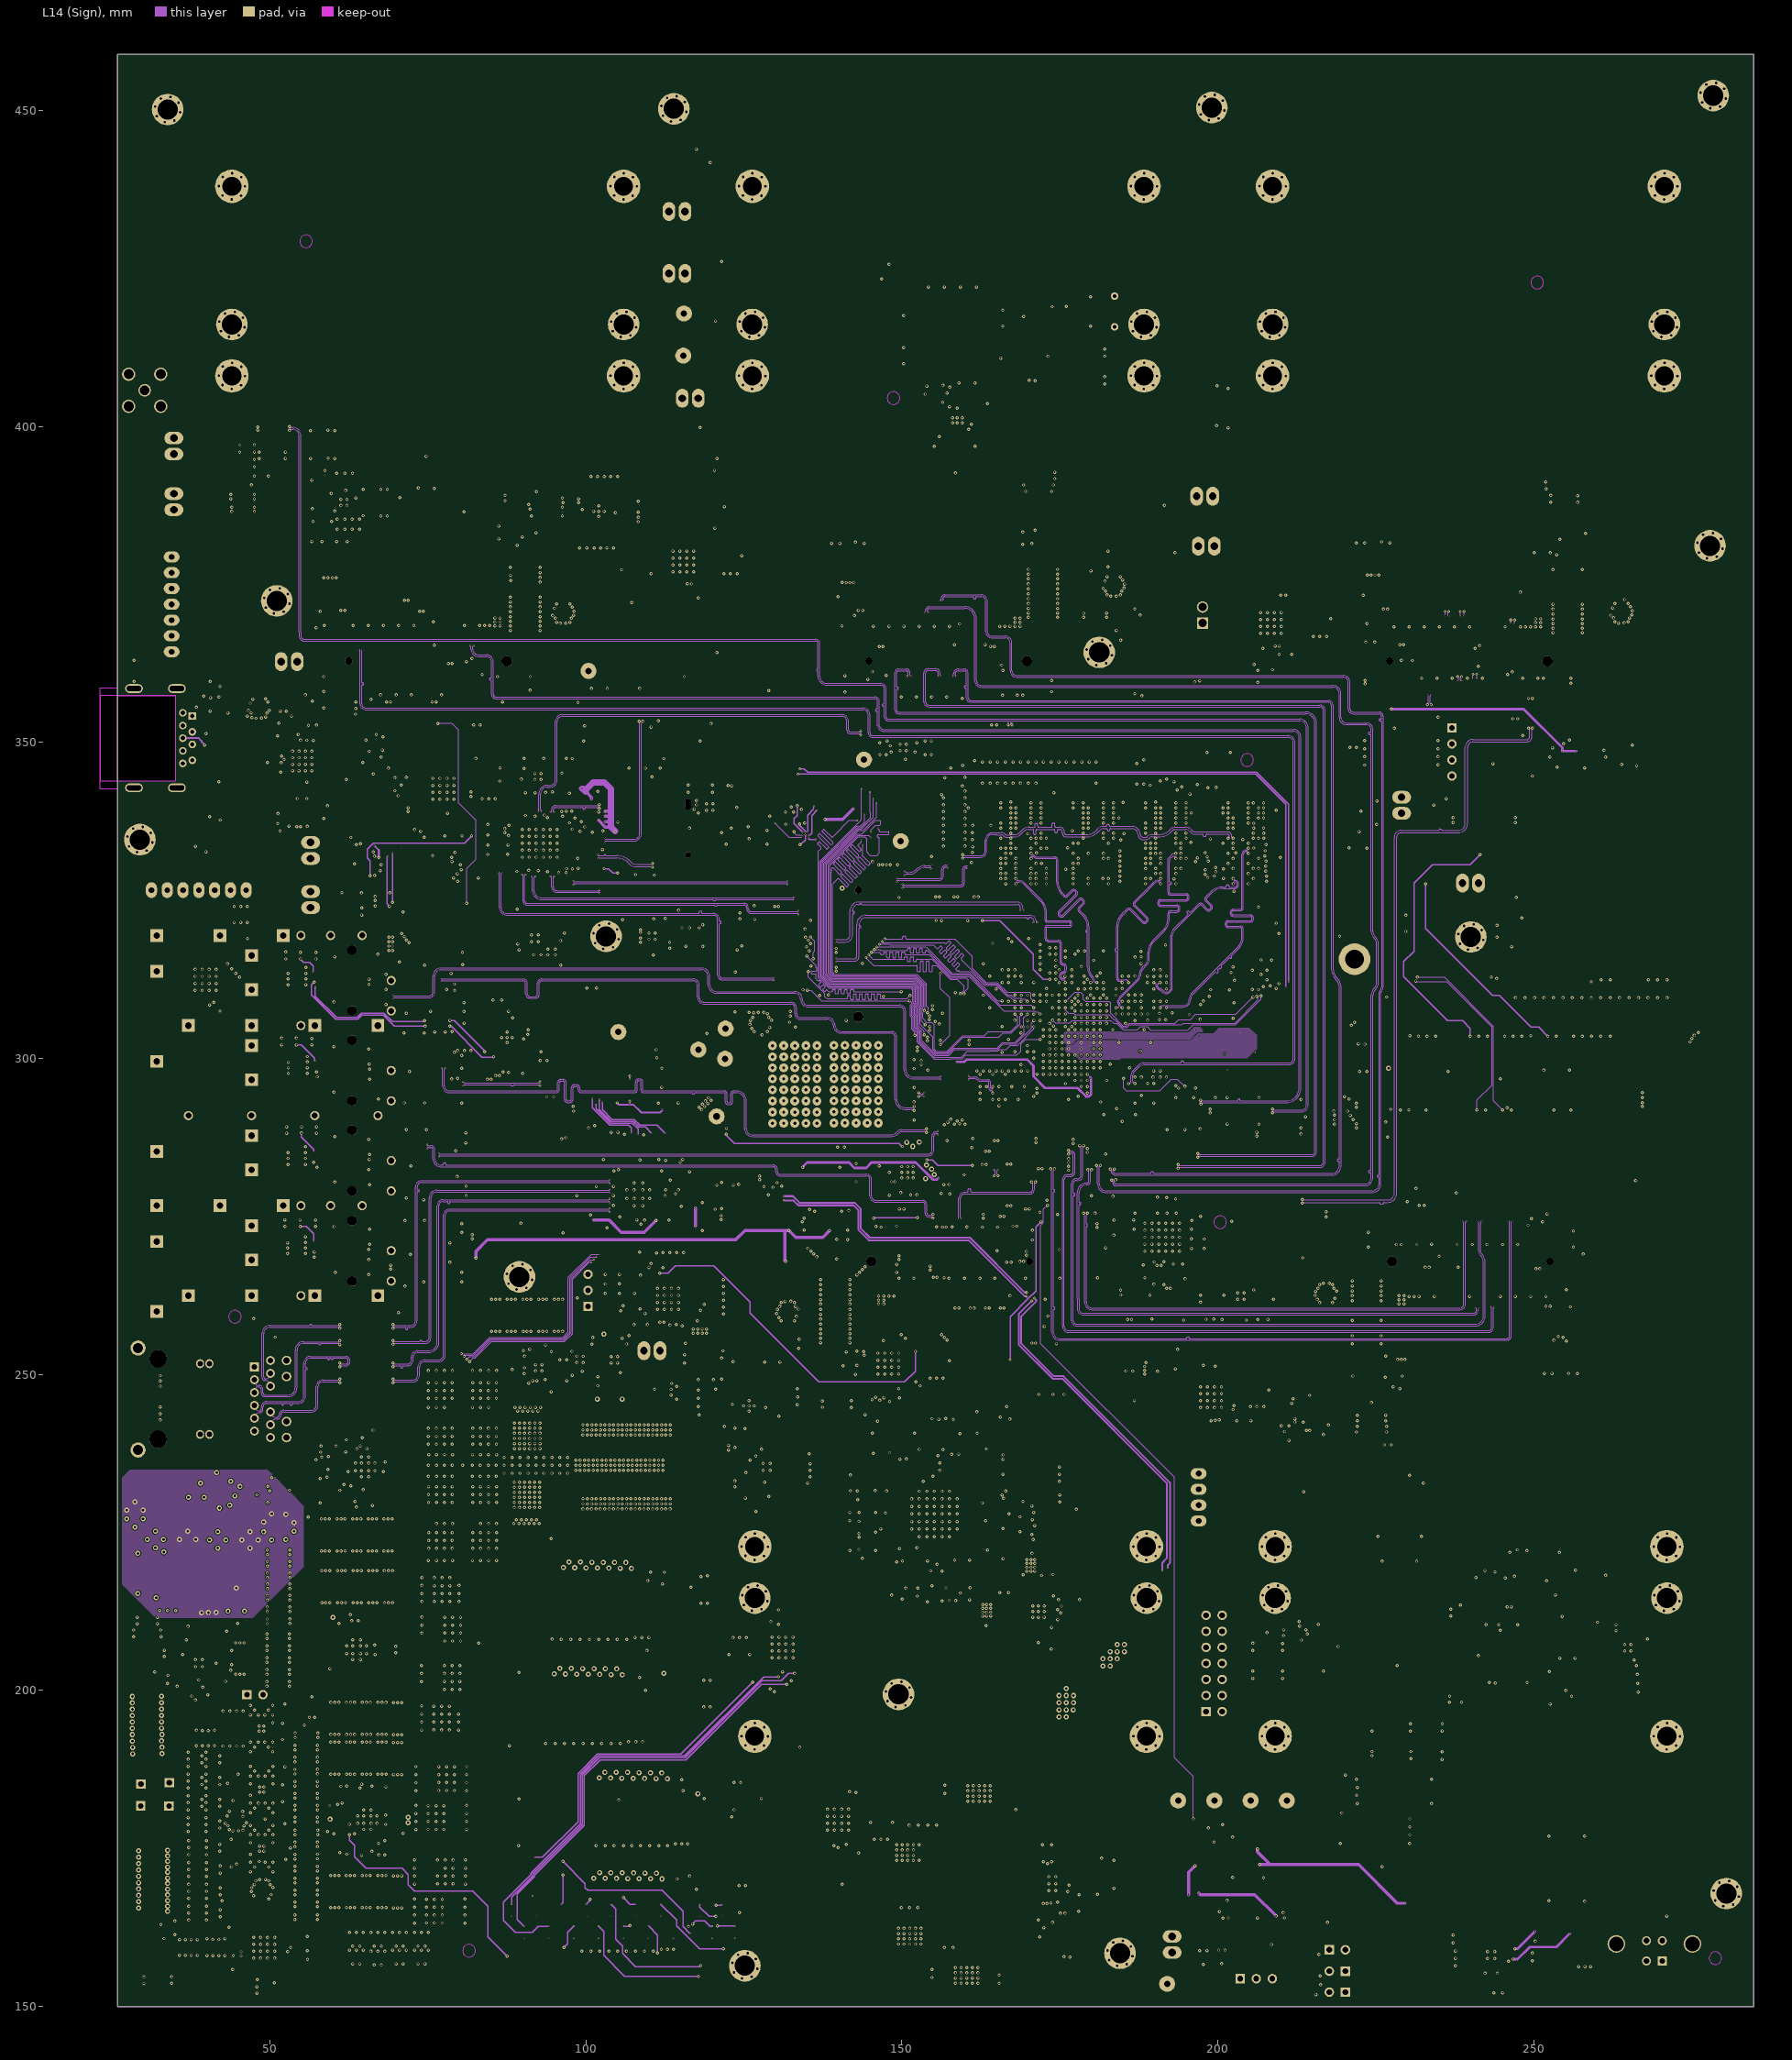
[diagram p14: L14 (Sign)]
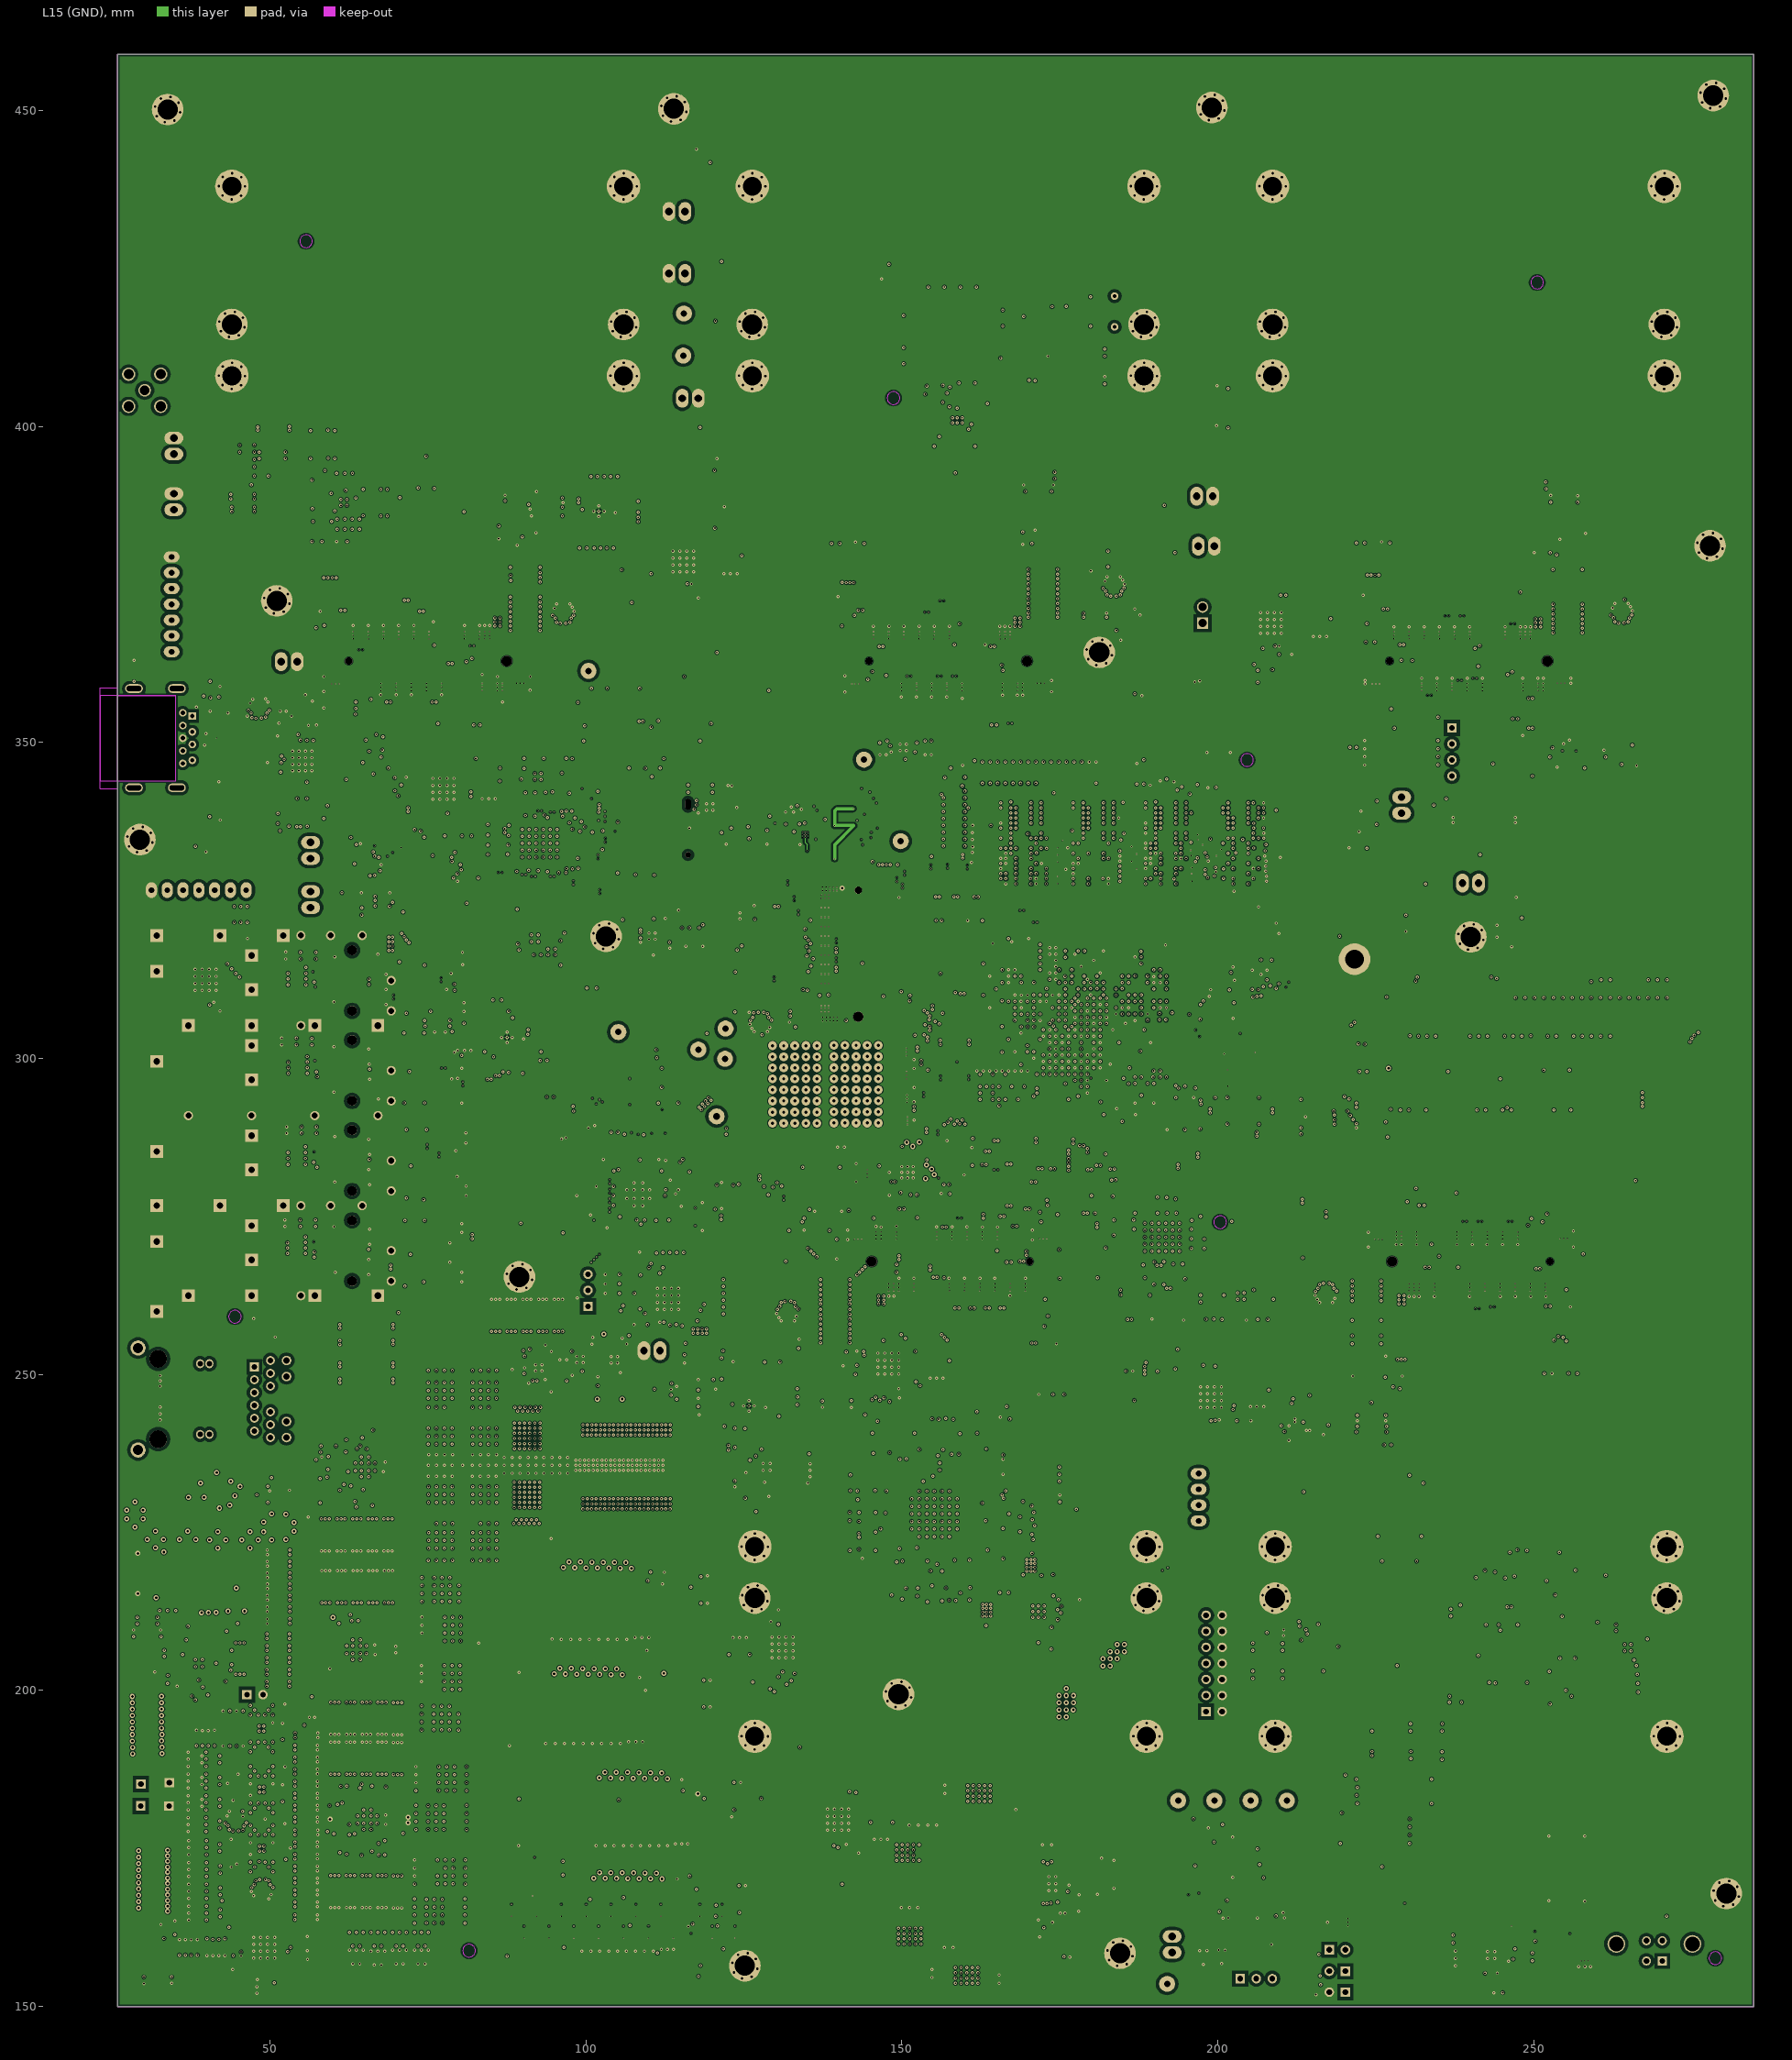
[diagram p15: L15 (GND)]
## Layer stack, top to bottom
Top Solder: solder mask 0.025, SM-001, Dk 4
L1: signal copper 0.064
Dielectric 1: prepreg 0.074, PP-013, Dk 4.3
L2 (GND): signal copper 0.015
Dielectric 2: core 0.114, Core-001, Dk 4.1
L3 (Sign): signal copper 0.015
Dielectric 3: prepreg 0.114, PP-013, Dk 4.3
L4 (GND): signal copper 0.015
Dielectric 4: core 0.114, Core-001, Dk 4.1
L5 (Sign): signal copper 0.015
Dielectric 5: prepreg 0.114, PP-013, Dk 4.3
L6 (PWR/GND): signal copper 0.03
Dielectric 6: core 0.203, Core-001, Dk 4.1
L7(12V+Other): signal copper 0.03
Dielectric 7: prepreg 0.203, PP-013, Dk 4.3
L8 (Plane_GND): signal copper 0.03
Dielectric 8: core 0.203, Core-001, Dk 4.1
L9 (PWR/GND): signal copper 0.03
Dielectric 9: prepreg 0.203, PP-013, Dk 4.3
L10 (3V3+Other): signal copper 0.03
Dielectric 10: core 0.203, Core-001, Dk 4.1
L11 (PWR/GND): signal copper 0.03
Dielectric 11: prepreg 0.114, PP-013, Dk 4.3
L12 (Sign): signal copper 0.015
Dielectric 12: core 0.114, Core-001, Dk 4.1
L13 (GND): signal copper 0.015
Dielectric 13: prepreg 0.114, PP-013, Dk 4.3
L14 (Sign): signal copper 0.015
Dielectric 14: core 0.114, Core-001, Dk 4.1
L15 (GND): signal copper 0.015
Dielectric 15: prepreg 0.074, PP-013, Dk 4.3
L16: signal copper 0.064
Bottom Solder: solder mask 0.025, SM-001, Dk 4

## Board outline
25.87,150.012 284.823,150.012 284.823,458.876 25.87,458.876

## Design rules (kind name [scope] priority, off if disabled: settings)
BackDrilling [(InNetClass('RAM_Adress') Or InNetClass('RAM_Data_IO') Or InNetClass('RAM_Clock_Signal') Or InNetClass('RAM_DQS_Strobe'))  And IsVia] p1: maxstublength=0.5 usetopbackdrill=TRUE usebottombackdrill=TRUE holeoversize=0.1 holetolplus=0.25 holetolminus=0
BoardOutlineClearance [All] p1: gap=0.254 ignorepadtopadclearanceinfootprint=FALSE except(0: Arc-SplitContinuation Track-SplitContinuation SMDPad-SplitContinuation THPad-SplitContinuation Via-SplitContinuation Fill-SplitContinuation Poly-SplitContinuation Region-SplitContinuation Text-SplitContinuation)
Clearance Clearance_4 [(IsTrack or IsArc) And (OnLayer('L1')   or  OnLayer('L16')) vs InNetClass('All Nets')] p1: gap=0.1 ignorepadtopadclearanceinfootprint=FALSE except(0.11: Arc-Via Track-Via Via-Via; 0.12: Arc-Arc Arc-Track; 0.2: SMDPad-Poly Fill-Poly Poly-Poly; 0.3: Arc-Poly Track-Poly; 0.5: THPad-Poly)
Clearance Clearance_3 [InNetClass('All Nets') vs BackDrillBottom] p2: gap=0.25 ignorepadtopadclearanceinfootprint=FALSE
Clearance Clearance_2 [InNetClass('RAM_Clock_Signal') vs InNetClass('RAM_Clock_Signal')] p3: gap=0.1 ignorepadtopadclearanceinfootprint=FALSE
Clearance Clearance_1 [All] p4 off: gap=0.1 ignorepadtopadclearanceinfootprint=FALSE except(0.102: Arc-Via Track-Via Via-Via)
Clearance RAM_Clearence [WithinRoom('RAM_CLK')] p5: gap=0.1 ignorepadtopadclearanceinfootprint=FALSE
Clearance "RAM_Addr to RAM_Addr" [InNetClass('Single_36_39_50_Adr') vs InNetClass('Single_36_39_50_Adr')] p6: gap=0.1 ignorepadtopadclearanceinfootprint=FALSE
Clearance "RAM_Addr to RAM_PWR" [InNetClass('Single_36_39_50_Adr') vs InNet('RAM_Vcc1V2')] p7: gap=0.1 ignorepadtopadclearanceinfootprint=FALSE
Clearance "RAM_Addr to other" [InNetClass('Single_36_39_50_Adr')] p8: gap=0.15 ignorepadtopadclearanceinfootprint=TRUE
Clearance [All] p9: gap=0.1 ignorepadtopadclearanceinfootprint=FALSE except(0.12: Via-Poly; 0.2: SMDPad-Poly Fill-Poly Poly-Poly; 0.3: Arc-Poly Track-Poly; 0.5: THPad-Poly)
Creepage [All] p1 off: checkdistance=0.254
DiffPairsRouting Diff100_Fpga [InDifferentialPairClass('Diff_100') and WithinRoom('FPGA_Room')] p1: maxlimit=0.254 minlimit=0.127 mostfreqgap=0.254 toplayer_mingap=0.2 toplayer_maxgap=0.2 toplayer_prefgap=0.2 toplayer_minwidth=0.09 toplayer_maxwidth=0.09 toplayer_prefwidth=0.09 midlayer2_mingap=0.2 midlayer2_maxgap=0.2 midlayer2_prefgap=0.2 midlayer2_minwidth=0.081 midlayer2_maxwidth=0.081 midlayer2_prefwidth=0.081 midlayer5_mingap=0.2 midlayer5_maxgap=0.2 midlayer5_prefgap=0.2 midlayer5_minwidth=0.081 midlayer5_maxwidth=0.081 midlayer5_prefwidth=0.081 midlayer8_mingap=0.2 midlayer8_maxgap=0.2 midlayer8_prefgap=0.2 midlayer8_minwidth=0.081 midlayer8_maxwidth=0.081 midlayer8_prefwidth=0.081 midlayer13_mingap=0.2 midlayer13_maxgap=0.2 midlayer13_prefgap=0.2 midlayer13_minwidth=0.081 midlayer13_maxwidth=0.081 midlayer13_prefwidth=0.081 bottomlayer_mingap=0.2 bottomlayer_maxgap=0.2 bottomlayer_prefgap=0.2 bottomlayer_minwidth=0.09 bottomlayer_maxwidth=0.09 bottomlayer_prefwidth=0.09 impedanceprofiledriven=TRUE impedanceprofileid={60D4C832-B92A-4812-B2AD-BB3BD3425739} impedanceprofilevalue=100.000000 maxuncoupledlength=12.7
DiffPairsRouting RAM_Diff86 [InDifferentialPairClass('Diff_76_to_90_Ram_CLK') and (WithinRoom('RAM_1')or WithinRoom('RAM_2')or WithinRoom('RAM_3')or WithinRoom('Ram_4')or WithinRoom('FPGA_Room'))and  OnTopLayer] p2: maxlimit=0.254 minlimit=0.148 mostfreqgap=0.254 toplayer_mingap=0.2 toplayer_maxgap=0.22 toplayer_prefgap=0.21 toplayer_minwidth=0.1 toplayer_maxwidth=0.1 toplayer_prefwidth=0.1 midlayer2_maxgap=0.15 midlayer2_prefgap=0.149 midlayer2_minwidth=0.1 midlayer2_maxwidth=0.12 midlayer2_prefwidth=0.1 midlayer5_maxgap=0.15 midlayer5_prefgap=0.149 midlayer5_minwidth=0.1 midlayer5_maxwidth=0.12 midlayer5_prefwidth=0.1 midlayer8_maxgap=0.15 midlayer8_prefgap=0.149 midlayer8_minwidth=0.1 midlayer8_maxwidth=0.12 midlayer8_prefwidth=0.1 midlayer13_maxgap=0.15 midlayer13_prefgap=0.149 midlayer13_minwidth=0.1 midlayer13_maxwidth=0.12 midlayer13_prefwidth=0.1 bottomlayer_mingap=0.2 bottomlayer_maxgap=0.22 bottomlayer_prefgap=0.21 bottomlayer_minwidth=0.1 bottomlayer_maxwidth=0.12 bottomlayer_prefwidth=0.1 impedanceprofiledriven=TRUE impedanceprofileid={1AFD27EA-460E-472B-BC44-4C5C59E93A8B} impedanceprofilevalue=86.000000 maxuncoupledlength=12.7 // breakout
DiffPairsRouting RAM_Diff90 [InDifferentialPairClass('Diff_76_to_90_Ram_CLK') and (WithinRoom('RAM_1')or WithinRoom('RAM_2')or WithinRoom('RAM_3')or WithinRoom('Ram_4')or WithinRoom('FPGA_Room')or WithinRoom('RAM_CLK'))and (not OnTopLayer)] p3: maxlimit=0.31 minlimit=0.127 mostfreqgap=0.254 toplayer_prefgap=0.31 toplayer_minwidth=0.018 toplayer_maxwidth=0.135 toplayer_prefwidth=0.135 midlayer2_maxgap=0.262 midlayer2_prefgap=0.25 midlayer2_minwidth=0.011 midlayer2_maxwidth=0.111 midlayer2_prefwidth=0.111 midlayer5_maxgap=0.262 midlayer5_prefgap=0.25 midlayer5_minwidth=0.011 midlayer5_maxwidth=0.111 midlayer5_prefwidth=0.111 midlayer8_maxgap=0.262 midlayer8_prefgap=0.25 midlayer8_minwidth=0.011 midlayer8_maxwidth=0.111 midlayer8_prefwidth=0.111 midlayer13_maxgap=0.262 midlayer13_prefgap=0.25 midlayer13_minwidth=0.011 midlayer13_maxwidth=0.111 midlayer13_prefwidth=0.111 bottomlayer_prefgap=0.31 bottomlayer_minwidth=0.018 bottomlayer_maxwidth=0.135 bottomlayer_prefwidth=0.135 impedanceprofiledriven=TRUE impedanceprofileid={1D82871A-FACB-482B-B08F-C93C2922060F} impedanceprofilevalue=90.000000 maxuncoupledlength=12.7
DiffPairsRouting Diff_76 [InDifferentialPairClass('Diff_76_to_90_Ram_CLK')] p4: maxlimit=0.254 minlimit=0.074 mostfreqgap=0.254 toplayer_mingap=0.115 toplayer_maxgap=0.154 toplayer_prefgap=0.115 toplayer_minwidth=0.1 toplayer_maxwidth=0.159 toplayer_prefwidth=0.143 midlayer2_maxgap=0.127 midlayer2_prefgap=0.103 midlayer2_minwidth=0.1 midlayer2_maxwidth=0.137 midlayer2_prefwidth=0.128 midlayer5_maxgap=0.127 midlayer5_prefgap=0.103 midlayer5_minwidth=0.1 midlayer5_maxwidth=0.137 midlayer5_prefwidth=0.128 midlayer8_maxgap=0.127 midlayer8_prefgap=0.103 midlayer8_minwidth=0.1 midlayer8_maxwidth=0.137 midlayer8_prefwidth=0.128 midlayer13_maxgap=0.127 midlayer13_prefgap=0.103 midlayer13_minwidth=0.1 midlayer13_maxwidth=0.137 midlayer13_prefwidth=0.128 bottomlayer_mingap=0.115 bottomlayer_maxgap=0.154 bottomlayer_prefgap=0.115 bottomlayer_minwidth=0.1 bottomlayer_maxwidth=0.159 bottomlayer_prefwidth=0.143 impedanceprofiledriven=TRUE impedanceprofileid={BD08387B-4D6E-4BB2-82BF-460CD7A1F64F} impedanceprofilevalue=76.000000 maxuncoupledlength=12.7
DiffPairsRouting RAM_DQS [InDifferentialPairClass('Diff_76_to_90_Ram_DQS')] p5: maxlimit=0.254 minlimit=0.127 mostfreqgap=0.254 toplayer_maxgap=0.127 toplayer_prefgap=0.127 toplayer_minwidth=0.123 toplayer_maxwidth=0.159 toplayer_prefwidth=0.124 midlayer1_maxgap=0.127 midlayer1_prefgap=0.127 midlayer1_minwidth=0.105 midlayer1_maxwidth=0.105 midlayer1_prefwidth=0.105 midlayer2_maxgap=0.127 midlayer2_prefgap=0.127 midlayer2_minwidth=0.105 midlayer2_maxwidth=0.137 midlayer2_prefwidth=0.105 midlayer3_mingap=0.254 midlayer3_minwidth=0.381 midlayer3_maxwidth=0.381 midlayer3_prefwidth=0.381 midlayer4_mingap=0.254 midlayer4_minwidth=0.381 midlayer4_maxwidth=0.381 midlayer4_prefwidth=0.381 midlayer5_maxgap=0.127 midlayer5_prefgap=0.127 midlayer5_minwidth=0.105 midlayer5_maxwidth=0.127 midlayer5_prefwidth=0.105 midlayer6_maxgap=0.127 midlayer6_prefgap=0.127 midlayer6_minwidth=0.105 midlayer6_maxwidth=0.105 midlayer6_prefwidth=0.105 midlayer7_maxgap=0.127 midlayer7_prefgap=0.127 midlayer7_minwidth=0.084 midlayer7_maxwidth=0.084 midlayer7_prefwidth=0.084 midlayer8_maxgap=0.127 midlayer8_prefgap=0.127 midlayer8_minwidth=0.105 midlayer8_maxwidth=0.137 midlayer8_prefwidth=0.105 midlayer9_mingap=0.254 midlayer9_minwidth=0.381 midlayer9_maxwidth=0.381 midlayer9_prefwidth=0.381 midlayer10_mingap=0.254 midlayer10_minwidth=0.381 midlayer10_maxwidth=0.381 midlayer10_prefwidth=0.381 midlayer11_mingap=0.254 midlayer11_minwidth=0.381 midlayer11_maxwidth=0.381 midlayer11_prefwidth=0.381 midlayer12_mingap=0.254 midlayer12_minwidth=0.381 midlayer12_maxwidth=0.381 midlayer12_prefwidth=0.381 midlayer13_maxgap=0.127 midlayer13_prefgap=0.127 midlayer13_minwidth=0.105 midlayer13_maxwidth=0.137 midlayer13_prefwidth=0.105 midlayer14_maxgap=0.127 midlayer14_prefgap=0.127 midlayer14_minwidth=0.084 midlayer14_maxwidth=0.102 midlayer14_prefwidth=0.084 bottomlayer_maxgap=0.127 bottomlayer_prefgap=0.127 bottomlayer_minwidth=0.123 bottomlayer_maxwidth=0.159 bottomlayer_prefwidth=0.124 maxuncoupledlength=12.7
DiffPairsRouting RAM_Diff_76_86_90_Addr [InDifferentialPairClass('Diff_76_to_90_Ram_CLK')] p6 off: maxlimit=0.254 minlimit=0.148 mostfreqgap=0.254 toplayer_mingap=0.2 toplayer_maxgap=0.22 toplayer_prefgap=0.21 toplayer_minwidth=0.1 toplayer_maxwidth=0.12 toplayer_prefwidth=0.1 midlayer2_maxgap=0.15 midlayer2_prefgap=0.149 midlayer2_minwidth=0.1 midlayer2_maxwidth=0.12 midlayer2_prefwidth=0.1 midlayer5_maxgap=0.15 midlayer5_prefgap=0.149 midlayer5_minwidth=0.1 midlayer5_maxwidth=0.12 midlayer5_prefwidth=0.1 midlayer8_maxgap=0.15 midlayer8_prefgap=0.149 midlayer8_minwidth=0.1 midlayer8_maxwidth=0.12 midlayer8_prefwidth=0.1 midlayer13_maxgap=0.15 midlayer13_prefgap=0.149 midlayer13_minwidth=0.1 midlayer13_maxwidth=0.12 midlayer13_prefwidth=0.1 bottomlayer_mingap=0.2 bottomlayer_maxgap=0.22 bottomlayer_prefgap=0.21 bottomlayer_minwidth=0.1 bottomlayer_maxwidth=0.12 bottomlayer_prefwidth=0.1 impedanceprofiledriven=TRUE impedanceprofileid={1AFD27EA-460E-472B-BC44-4C5C59E93A8B} impedanceprofilevalue=86.000000 maxuncoupledlength=0.2 // Differential pair 86 Ohm
DiffPairsRouting Diff100 [InDifferentialPairClass('Diff_100')] p7: maxlimit=0.504 minlimit=0.127 mostfreqgap=0.254 toplayer_mingap=0.3 toplayer_maxgap=0.3 toplayer_prefgap=0.3 toplayer_minwidth=0.101 toplayer_maxwidth=0.101 toplayer_prefwidth=0.101 midlayer2_mingap=0.2 midlayer2_maxgap=0.2 midlayer2_prefgap=0.2 midlayer2_minwidth=0.081 midlayer2_maxwidth=0.081 midlayer2_prefwidth=0.081 midlayer5_mingap=0.2 midlayer5_maxgap=0.2 midlayer5_prefgap=0.2 midlayer5_minwidth=0.081 midlayer5_maxwidth=0.081 midlayer5_prefwidth=0.081 midlayer8_mingap=0.2 midlayer8_maxgap=0.2 midlayer8_prefgap=0.2 midlayer8_minwidth=0.081 midlayer8_maxwidth=0.081 midlayer8_prefwidth=0.081 midlayer13_mingap=0.2 midlayer13_maxgap=0.2 midlayer13_prefgap=0.2 midlayer13_minwidth=0.081 midlayer13_maxwidth=0.081 midlayer13_prefwidth=0.081 bottomlayer_mingap=0.3 bottomlayer_maxgap=0.3 bottomlayer_prefgap=0.3 bottomlayer_minwidth=0.101 bottomlayer_maxwidth=0.101 bottomlayer_prefwidth=0.101 impedanceprofiledriven=TRUE impedanceprofileid={3149E961-6C2D-4C90-A41E-90A05D6C6F09} impedanceprofilevalue=100.000000 maxuncoupledlength=12.7 // Differential 100 Ohm
DiffPairsRouting "Diff 90" [InDifferentialPairClass('Diff_90')] p8: maxlimit=0.31 minlimit=0.127 mostfreqgap=0.254 toplayer_prefgap=0.31 toplayer_minwidth=0.018 toplayer_maxwidth=0.135 toplayer_prefwidth=0.135 midlayer2_maxgap=0.262 midlayer2_prefgap=0.25 midlayer2_minwidth=0.011 midlayer2_maxwidth=0.111 midlayer2_prefwidth=0.111 midlayer5_maxgap=0.262 midlayer5_prefgap=0.25 midlayer5_minwidth=0.011 midlayer5_maxwidth=0.111 midlayer5_prefwidth=0.111 midlayer8_maxgap=0.262 midlayer8_prefgap=0.25 midlayer8_minwidth=0.011 midlayer8_maxwidth=0.111 midlayer8_prefwidth=0.111 midlayer13_maxgap=0.262 midlayer13_prefgap=0.25 midlayer13_minwidth=0.011 midlayer13_maxwidth=0.111 midlayer13_prefwidth=0.111 bottomlayer_prefgap=0.31 bottomlayer_minwidth=0.018 bottomlayer_maxwidth=0.135 bottomlayer_prefwidth=0.135 impedanceprofiledriven=TRUE impedanceprofileid={1D82871A-FACB-482B-B08F-C93C2922060F} impedanceprofilevalue=90.000000 maxuncoupledlength=12.7 // Differential 90 Ohm
HoleSize DrillHole [All] p1: absolutevalues=TRUE maxlimit=5 minlimit=0.1 maxpercent=80.000 minpercent=20.000
HoleToHoleClearance [All] p1: gap=0.09 allowstackedmicrovias=TRUE
MatchedLengths SPI_R_U26_L [InxSignalClass('SPI_R_U26')] p1: tolerance=2 checknetsindiffpair=FALSE checkdiffpairvsdiffpair=TRUE checkxsignals=TRUE checkothers=TRUE
MatchedLengths SPI_R_U15_L [InxSignalClass('SPI_R_U15')] p2: tolerance=2 checknetsindiffpair=FALSE checkdiffpairvsdiffpair=TRUE checkxsignals=TRUE checkothers=TRUE
MatchedLengths SPI_R_U28_L [InxSignalClass('SPI_R_U28')] p3: tolerance=2 checknetsindiffpair=FALSE checkdiffpairvsdiffpair=TRUE checkxsignals=TRUE checkothers=TRUE
MatchedLengths SPI_R_U25_L [InxSignalClass('SPI_R_U25')] p4: tolerance=2 checknetsindiffpair=FALSE checkdiffpairvsdiffpair=TRUE checkxsignals=TRUE checkothers=TRUE
MatchedLengths SPI_R_U24_L [InxSignalClass('SPI_R_U24')] p5: tolerance=2 checknetsindiffpair=FALSE checkdiffpairvsdiffpair=TRUE checkxsignals=TRUE checkothers=TRUE
MatchedLengths SPI_R_J25_L [InxSignalClass('SPI_R_J25')] p6: tolerance=2 checknetsindiffpair=FALSE checkdiffpairvsdiffpair=TRUE checkxsignals=TRUE checkothers=TRUE
MatchedLengths SPI_R_U27_L [InxSignalClass('SPIR_U27')] p7: tolerance=2 checknetsindiffpair=FALSE checkdiffpairvsdiffpair=TRUE checkxsignals=TRUE checkothers=TRUE
MatchedLengths MDIO_Lengths [InNetClass('MDI_ETH')] p8: tolerance=7 checknetsindiffpair=FALSE checkdiffpairvsdiffpair=TRUE checkxsignals=TRUE checkothers=TRUE
MatchedLengths UART_FPGA_R_Lengths [InNetClass('UART_FPGA_R')] p9: tolerance=7 checknetsindiffpair=FALSE checkdiffpairvsdiffpair=TRUE checkxsignals=TRUE checkothers=TRUE
MatchedLengths UART_FTDI_LS_0_Lengths [InNetClass('UART_FTDI_LS_0')] p10: tolerance=7 checknetsindiffpair=FALSE checkdiffpairvsdiffpair=TRUE checkxsignals=TRUE checkothers=TRUE
MatchedLengths UART_FTDI_LS_2_Lengths [InNetClass('UART_FTDI_LS_2')] p11: tolerance=7 checknetsindiffpair=FALSE checkdiffpairvsdiffpair=TRUE checkxsignals=TRUE checkothers=TRUE
MatchedLengths UART_FTDI_LS_1_Lengths [InNetClass('UART_FTDI_LS_1')] p12: tolerance=7 checknetsindiffpair=FALSE checkdiffpairvsdiffpair=TRUE checkxsignals=TRUE checkothers=TRUE
MatchedLengths UART_FPTDI_US_1_Lengths [InNetClass('UART_FTDI_US1_1')] p13: tolerance=7 checknetsindiffpair=FALSE checkdiffpairvsdiffpair=TRUE checkxsignals=TRUE checkothers=TRUE
MatchedLengths UART_FTDI_US_1_2_Lengths [InNetClass('UART_FTDI_US1_2')] p14: tolerance=7 checknetsindiffpair=FALSE checkdiffpairvsdiffpair=TRUE checkxsignals=TRUE checkothers=TRUE
MatchedLengths UART_FTDI_US_2_Lengths [InNetClass('UART_FTDI_US2')] p15: tolerance=7 checknetsindiffpair=FALSE checkdiffpairvsdiffpair=TRUE checkxsignals=TRUE checkothers=TRUE
MatchedLengths SPI1_MIO_Lengths [InNetClass('SPI1_MIO')] p16: tolerance=2 checknetsindiffpair=FALSE checkdiffpairvsdiffpair=TRUE checkxsignals=TRUE checkothers=TRUE
MatchedLengths SPI_05028_Lengths [InNetClass('SPI_05028')] p17: tolerance=5 checknetsindiffpair=FALSE checkdiffpairvsdiffpair=TRUE checkxsignals=TRUE checkothers=TRUE
MatchedLengths SPI_DAC_Lengths [InNetClass('SPI_DAC')] p18: tolerance=5 checknetsindiffpair=FALSE checkdiffpairvsdiffpair=TRUE checkxsignals=TRUE checkothers=TRUE
MatchedLengths SPI_LTC0_Lengths [InNetClass('SPI_LTC_0')] p19: tolerance=5 checknetsindiffpair=FALSE checkdiffpairvsdiffpair=TRUE checkxsignals=TRUE checkothers=TRUE
MatchedLengths SPI_LTC1_Lengths [InNetClass('SPI_LTC_1')] p20: tolerance=7 checknetsindiffpair=FALSE checkdiffpairvsdiffpair=TRUE checkxsignals=TRUE checkothers=TRUE
MatchedLengths SPI_PCIE_RF0_Lengths [InNetClass('SPI_PCIE_RF_0')] p21: tolerance=5 checknetsindiffpair=FALSE checkdiffpairvsdiffpair=TRUE checkxsignals=TRUE checkothers=TRUE
MatchedLengths SPI_PCIE_RF2_Lengths [InNetClass('SPI_PCIE_RF_2')] p22: tolerance=5 checknetsindiffpair=FALSE checkdiffpairvsdiffpair=TRUE checkxsignals=TRUE checkothers=TRUE
MatchedLengths SPI_PCIE_RF1_Lengths [InNetClass('SPI_PCIE_RF_1')] p23: tolerance=5 checknetsindiffpair=FALSE checkdiffpairvsdiffpair=TRUE checkxsignals=TRUE checkothers=TRUE
MatchedLengths SPI_PCIE_RF3_Lengths [InNetClass('SPI_PCIE_RF_3')] p24: tolerance=5 checknetsindiffpair=FALSE checkdiffpairvsdiffpair=TRUE checkxsignals=TRUE checkothers=TRUE
MatchedLengths SPI_PCIE_RF4_Lengths [InNetClass('SPI_PCIE_RF_4')] p25: tolerance=5 checknetsindiffpair=FALSE checkdiffpairvsdiffpair=TRUE checkxsignals=TRUE checkothers=TRUE
MatchedLengths SPI_US2_FPGA_R_Lengths [InNetClass('SPI_US2_FPGA_R')] p26: tolerance=5 checknetsindiffpair=FALSE checkdiffpairvsdiffpair=TRUE checkxsignals=TRUE checkothers=TRUE
MatchedLengths SPI_Main_Lengths [InNetClass('SPI_MAIN')] p27 off: tolerance=5 checknetsindiffpair=FALSE checkdiffpairvsdiffpair=TRUE checkxsignals=TRUE checkothers=TRUE
MatchedLengths SPI_US2_R_Lengths [InNetClass('SPI_US2_R')] p28: tolerance=5 checknetsindiffpair=FALSE checkdiffpairvsdiffpair=TRUE checkxsignals=TRUE checkothers=TRUE
MatchedLengths SPI_US2_FPGA_Lengths [InNetClass('SPI_US2_FPGA_R')] p29: tolerance=5 checknetsindiffpair=FALSE checkdiffpairvsdiffpair=TRUE checkxsignals=TRUE checkothers=TRUE
MatchedLengths CAN_Lenght [InNetClass('CAN_US_01')] p30: tolerance=14 checknetsindiffpair=FALSE checkdiffpairvsdiffpair=TRUE checkxsignals=TRUE checkothers=TRUE
MatchedLengths USB2_Lenght [InNetClass('USB2_Lines')] p31: tolerance=11 checknetsindiffpair=FALSE checkdiffpairvsdiffpair=TRUE checkxsignals=TRUE checkothers=TRUE
MatchedLengths USB2_Dev [InNetClass('USB2_Dev')] p32: tolerance=2 checknetsindiffpair=FALSE checkdiffpairvsdiffpair=TRUE checkxsignals=TRUE checkothers=TRUE
MatchedLengths eMMC_Lenght [InNetClass('eMMC_Lines')] p33: tolerance=5 checknetsindiffpair=FALSE checkdiffpairvsdiffpair=TRUE checkxsignals=TRUE checkothers=TRUE
MatchedLengths eMMC_Dev [InNetClass('eMMC_Dev')] p34: tolerance=1 checknetsindiffpair=FALSE checkdiffpairvsdiffpair=TRUE checkxsignals=TRUE checkothers=TRUE
MatchedLengths uSD_Lenght [InNetClass('uSD_Lines')] p35: tolerance=5 checknetsindiffpair=FALSE checkdiffpairvsdiffpair=TRUE checkxsignals=TRUE checkothers=TRUE
MatchedLengths uSD_Dev [InNetClass('uSD_Dev')] p36: tolerance=1 checknetsindiffpair=FALSE checkdiffpairvsdiffpair=TRUE checkxsignals=TRUE checkothers=TRUE
MatchedLengths MatchedLengths_DDR_CLOCKS_STROBES [InxSignalClass('ADDR_PP1') OR InxSignalClass('ADDR_PP2') OR InxSignalClass('ADDR_PP3') OR InxSignalClass('ADDR_PP4') OR InxSignalClass('DATA_BL0') OR InxSignalClass('DATA_BL1') OR InxSignalClass('DATA_BL2') OR InxSignalClass('DATA_BL3') OR InxSignalClass('DATA_BL4') OR InxSignalClass('DATA_BL5') OR InxSignalClass('DATA_BL6') OR InxSignalClass('DATA_BL7')] p37: tolerance=0.305 checknetsindiffpair=TRUE checkdiffpairvsdiffpair=FALSE checkxsignals=FALSE checkothers=FALSE
MatchedLengths MatchedLengths_DATA_BL7 [InxSignalClass('DATA_BL7')] p38: tolerance=1.473 checknetsindiffpair=FALSE checkdiffpairvsdiffpair=TRUE checkxsignals=TRUE checkothers=TRUE
MatchedLengths MatchedLengths_DATA_BL6 [InxSignalClass('DATA_BL6')] p39: tolerance=1.473 checknetsindiffpair=FALSE checkdiffpairvsdiffpair=TRUE checkxsignals=TRUE checkothers=TRUE
MatchedLengths MatchedLengths_DATA_BL5 [InxSignalClass('DATA_BL5')] p40: tolerance=1.473 checknetsindiffpair=FALSE checkdiffpairvsdiffpair=TRUE checkxsignals=TRUE checkothers=TRUE
MatchedLengths MatchedLengths_DATA_BL4 [InxSignalClass('DATA_BL4')] p41: tolerance=1.473 checknetsindiffpair=FALSE checkdiffpairvsdiffpair=TRUE checkxsignals=TRUE checkothers=TRUE
MatchedLengths MatchedLengths_DATA_BL3 [InxSignalClass('DATA_BL3')] p42: tolerance=1.473 checknetsindiffpair=FALSE checkdiffpairvsdiffpair=TRUE checkxsignals=TRUE checkothers=TRUE
MatchedLengths MatchedLengths_DATA_BL2 [InxSignalClass('DATA_BL2')] p43: tolerance=1.473 checknetsindiffpair=FALSE checkdiffpairvsdiffpair=TRUE checkxsignals=TRUE checkothers=TRUE
MatchedLengths MatchedLengths_DATA_BL1 [InxSignalClass('DATA_BL1')] p44: tolerance=1.473 checknetsindiffpair=FALSE checkdiffpairvsdiffpair=TRUE checkxsignals=TRUE checkothers=TRUE
MatchedLengths MatchedLengths_DATA_BL0 [InxSignalClass('DATA_BL0')] p45: tolerance=1.473 checknetsindiffpair=FALSE checkdiffpairvsdiffpair=TRUE checkxsignals=TRUE checkothers=TRUE
MatchedLengths MatchedLengths_ADDR_PP4 [InxSignalClass('ADDR_PP4')] p46: tolerance=1.194 checknetsindiffpair=FALSE checkdiffpairvsdiffpair=TRUE checkxsignals=TRUE checkothers=TRUE
MatchedLengths MatchedLengths_ADDR_PP3 [InxSignalClass('ADDR_PP3')] p47: tolerance=1.194 checknetsindiffpair=FALSE checkdiffpairvsdiffpair=TRUE checkxsignals=TRUE checkothers=TRUE
MatchedLengths MatchedLengths_ADDR_PP2 [InxSignalClass('ADDR_PP2')] p48: tolerance=1.194 checknetsindiffpair=FALSE checkdiffpairvsdiffpair=TRUE checkxsignals=TRUE checkothers=TRUE
MatchedLengths MatchedLengths_ADDR_PP1 [InxSignalClass('ADDR_PP1')] p49: tolerance=1.194 checknetsindiffpair=FALSE checkdiffpairvsdiffpair=TRUE checkxsignals=TRUE checkothers=TRUE
MatchedLengths SFP_RX_1 [InNetClass('SFP_R_RX')] p50: tolerance=3 checknetsindiffpair=FALSE checkdiffpairvsdiffpair=TRUE checkxsignals=TRUE checkothers=TRUE
MatchedLengths SFP_TX_1 [InNetClass('SFP_R_TX')] p51: tolerance=3 checknetsindiffpair=FALSE checkdiffpairvsdiffpair=TRUE checkxsignals=TRUE checkothers=TRUE
MatchedLengths DiferentialPairSkew [All] p52: tolerance=0.3 checknetsindiffpair=TRUE checkdiffpairvsdiffpair=FALSE checkxsignals=FALSE checkothers=FALSE
MatchedLengths RAM_Data_to_DQS [InNetClass('Lenght_DQS_to_Data')] p53 off: tolerance=25.4 checknetsindiffpair=FALSE checkdiffpairvsdiffpair=TRUE checkxsignals=TRUE checkothers=TRUE
MatchedLengths RAM_DQS_to_CK [InNetClass('Lenght_DQS_to_CK')] p54 off: tolerance=25.4 checknetsindiffpair=FALSE checkdiffpairvsdiffpair=TRUE checkxsignals=TRUE checkothers=TRUE
MatchedLengths MatchedLengths_DDR_DQS [InNetClass('RAM_DQS_Strobe')] p55 off: tolerance=0.305 checknetsindiffpair=TRUE checkdiffpairvsdiffpair=FALSE checkxsignals=FALSE checkothers=FALSE
MatchedLengths RAM_Addr_LenghMatch [InNetClass('RAM_Adress')] p56 off: tolerance=0.305 checknetsindiffpair=FALSE checkdiffpairvsdiffpair=TRUE checkxsignals=TRUE checkothers=TRUE
MatchedLengths Ram_Addr_Com_Ctrl_to_CK [InNetClass('Lenght_CK_to_Addr')] p57 off: tolerance=0.305 checknetsindiffpair=FALSE checkdiffpairvsdiffpair=TRUE checkxsignals=TRUE checkothers=TRUE
MatchedLengths RAM_MatchedLengths_DATA_IO [InNetClass('RAM_Data_IO')] p58 off: tolerance=0.305 checknetsindiffpair=FALSE checkdiffpairvsdiffpair=TRUE checkxsignals=TRUE checkothers=TRUE
MinimumAnnularRing DefRing [All] p1: minimumring=0.105
MinimumSolderMaskSliver [All] p1: minsoldermaskwidth=0.1
PlaneClearance [All] p1 off: clearance=0.13
PlaneConnect [All] p1 off: planeconnectstyle=Direct reliefexpansion=0.508 reliefentries=4 reliefconductorwidth=0.4 reliefairgap=0.254
PolygonConnect PowerPolygon [HasFootprint('CAP 0201/0603 KK') or HasFootprint('CAP 0603/1608 RF') or HasFootprint('CAP 0402/1005 KK') or HasFootprint('CAP 0805/2012 RF') or HasFootprint('CAP 1206/3216') or   HasFootprint('CAP 1206/3216 - 0.8MM') or HasFootprint('CAP 1206/3216 - 1MM') or HasFootprint('FER 0603/1608') or   HasFootprint('FER 0805/2012') or  HasFootprint('RES 0201/0603') or  HasFootprint('RES 0603/1608 RF') or  HasFootprint('RES 0402/1005 RF KK') or  HasFootprint('RES 0805/2012 RF') or HasFootprint('RES 1206/2012 RF')] p1: thpad.connectstyle=Direct thpad.reliefconductorwidth=0.51 thpad.reliefentries=4 thpad.polygonreliefangle="90 Angle" thpad.airgapwidth=0.254 smdpad.connectstyle=Relief smdpad.reliefconductorwidth=0.4 smdpad.reliefentries=4 smdpad.polygonreliefangle="90 Angle" smdpad.airgapwidth=0.13 via.connectstyle=Direct via.reliefconductorwidth=0.254 via.reliefentries=4 via.polygonreliefangle="90 Angle" via.airgapwidth=0.254
PolygonConnect PolygonConnect_1 [All] p2: connectstyle=Direct reliefconductorwidth=0.254 reliefentries=4 polygonreliefangle="90 Angle" airgapwidth=0.254
ReturnPath [All] p1: impedanceprofileid={C52096D4-C36E-4BDB-BB83-9E54FFDADA41} _gaplimit=0
RoomDefinition RAM_3 [Not All] p1: confinementstyle=ConfineIn formatcopy=TRUE lockcomponents=FALSE outline 165.001,341.335 173.551,341.335 173.551,326.785 165.001,326.785
RoomDefinition Ram_4 [Not All] p2: confinementstyle=ConfineIn formatcopy=TRUE lockcomponents=FALSE outline 176.461,341.335 185.011,341.335 185.011,326.785 176.461,326.785
RoomDefinition RAM_2 [Not All] p3: confinementstyle=ConfineIn formatcopy=TRUE lockcomponents=FALSE outline 187.922,341.335 196.472,341.335 196.472,326.785 187.922,326.785
RoomDefinition RAM_1 [Not All] p4: confinementstyle=ConfineIn formatcopy=TRUE lockcomponents=FALSE outline 199.382,341.335 207.932,341.335 207.932,326.785 199.382,326.785
RoomDefinition FPGA_Room [Not All] p5: confinementstyle=ConfineIn formatcopy=TRUE lockcomponents=FALSE outline 161.397,318.539 192.397,318.539 192.397,287.539 161.397,287.539
RoomDefinition RAM_CLK [False] p6: confinementstyle=ConfineIn formatcopy=TRUE lockcomponents=FALSE outline 165.251,343.852 207.682,343.852 207.682,327.035 165.251,327.035
RoomDefinition RAMStubRoom_Addr [not All] p7: confinementstyle=ConfineIn formatcopy=TRUE lockcomponents=FALSE outline 158.259,345.172 185.298,345.172 185.298,330.46 158.259,330.46
RoutingTopology RoutingTopology_DDRAddressAndControls [InNetClass('DDR_AddressAndControls')] p1: topology=Daisy_Simple
RoutingTopology [All] p2: topology=Shortest
RoutingVias BackDrilled_1-5 [InDrillLayerPair('[BD] L5 (Sign) - L16')] p1: holewidth=0.35 width=0.5 viastyle="Through Hole" minholewidth=0.2 minwidth=0.5 maxholewidth=0.35 maxwidth=0.5
RoutingVias BackDrilled_1-14 [InDrillLayerPair('[BD] L14 (Sign) - L16')] p2: holewidth=0.35 width=0.5 viastyle="Through Hole" minholewidth=0.2 minwidth=0.5 maxholewidth=0.35 maxwidth=0.5
RoutingVias BackDrilled_1-12 [InDrillLayerPair('[BD] L12 (Sign) - L16')] p3: holewidth=0.35 width=0.5 viastyle="Through Hole" minholewidth=0.2 minwidth=0.5 maxholewidth=0.35 maxwidth=0.5
RoutingVias Vi14-16 [InDrillLayerPair('[UVIA] L14 (Sign) - L16')] p4: holewidth=0.1 width=0.254 viastyle="Through Hole" minholewidth=0.1 minwidth=0.254 maxholewidth=0.1 maxwidth=0.254
RoutingVias UVia1-2 [InDrillLayerPair('[UVIA] L1 - L2 (GND)')] p5: holewidth=0.1 width=0.254 viastyle="Through Hole" minholewidth=0.1 minwidth=0.254 maxholewidth=0.1 maxwidth=0.254
RoutingVias UVia1-3 [InDrillLayerPair('[UVIA] L1 - L3 (Sign)')] p6: holewidth=0.1 width=0.254 viastyle="Through Hole" minholewidth=0.1 minwidth=0.254 maxholewidth=0.1 maxwidth=0.254
RoutingVias UVia16-15 [InDrillLayerPair('[UVIA] L15 (GND) - L16')] p7: holewidth=0.127 width=0.35 viastyle="Through Hole" minholewidth=0.1 minwidth=0.225 maxholewidth=0.127 maxwidth=0.35
RoutingVias Diff_Pair_Via [InDifferentialPairClass('All Differential Pairs')] p8: holewidth=0.2 width=0.4 viastyle="Through Hole" minholewidth=0.127 minwidth=0.35 maxholewidth=0.3 maxwidth=0.5
RoutingVias [All] p9: holewidth=0.2 width=0.5 viastyle="Through Hole" minholewidth=0.1 minwidth=0.2 maxholewidth=2 maxwidth=2.25
ShortCircuit [InPadClass('All Pads') vs InPadClass('All Pads')] p1: allowed=FALSE
SilkToSilkClearance [All] p1: silktosilkclearance=0.1
SilkToSolderMaskClearance [IsPad] p1: minsilkscreentomaskgap=0 clearancetoexposedcopper=TRUE
SolderMaskExpansion [All] p1: expansion=0.102 istentingtop=FALSE
StubLength [All] p1 off: limit=25.4
UnConnectedPin [All] p1 off:
ViasUnderSMD [not (InDrillLayerPair('[UVIA] L14 (Sign) - L16') or  InDrillLayerPair('[UVIA] L1 - L2 (GND)') or  InDrillLayerPair('[UVIA] L1 - L3 (Sign)') or  InDrillLayerPair('[UVIA] L15 (GND) - L16')    )] p1 off: allowed=FALSE
Width Width_1 [InAnyDifferentialPair] p1: maxlimit=0.3 minlimit=0.05 preferedwidth=0.254 toplayer_minwidth=0.1 bottomlayer_minwidth=0.1 minimp=50.000000 maximp=50.000000 favimp=50.000000
Width Interrupts [InNetClass('Interrupt_Line')] p2: maxlimit=0.12 minlimit=0.076 preferedwidth=0.12 toplayer_minwidth=0.12 midlayer1_minwidth=0.12 midlayer2_minwidth=0.12 midlayer3_minwidth=0.12 midlayer4_minwidth=0.12 midlayer5_minwidth=0.12 midlayer6_minwidth=0.12 midlayer7_minwidth=0.12 midlayer9_minwidth=0.12 midlayer10_minwidth=0.12 midlayer11_minwidth=0.12 midlayer12_minwidth=0.12 midlayer13_minwidth=0.12 midlayer14_minwidth=0.12 bottomlayer_minwidth=0.12 minimp=50.000000 maximp=50.000000 favimp=50.000000
Width RAM_Address_50 [InNetClass('Single_36_39_50_Adr') and (WithinRoom('RAM_CLK')or WithinRoom('FPGA_Room'))] p3: maxlimit=0.254 minlimit=0.073 preferedwidth=0.254 toplayer_minwidth=0.1 toplayer_maxwidth=0.12 toplayer_prefwidth=0.101 midlayer2_maxwidth=0.093 midlayer2_prefwidth=0.081 midlayer5_maxwidth=0.093 midlayer5_prefwidth=0.081 midlayer8_minwidth=0.079 midlayer8_maxwidth=0.093 midlayer8_prefwidth=0.081 midlayer13_minwidth=0.079 midlayer13_maxwidth=0.093 midlayer13_prefwidth=0.081 bottomlayer_minwidth=0.1 bottomlayer_maxwidth=0.12 bottomlayer_prefwidth=0.101 impedanceprofiledriven=TRUE impedanceprofileid={C52096D4-C36E-4BDB-BB83-9E54FFDADA41} impedanceprofilevalue=50.000000 minimp=50.000000 maximp=50.000000 favimp=50.000000
Width RAM_Address_36 [InNetClass('Single_36_39_50_Adr') and (not((WithinRoom('RAM_CLK')or WithinRoom('FPGA_Room')or WithinRoom('RAMStubRoom_Addr'))))] p4: maxlimit=0.254 minlimit=0.171 preferedwidth=0.254 toplayer_minwidth=0.181 toplayer_maxwidth=0.184 toplayer_prefwidth=0.182 midlayer2_maxwidth=0.174 midlayer2_prefwidth=0.173 midlayer5_maxwidth=0.174 midlayer5_prefwidth=0.173 midlayer8_maxwidth=0.174 midlayer8_prefwidth=0.173 midlayer13_maxwidth=0.174 midlayer13_prefwidth=0.173 bottomlayer_minwidth=0.181 bottomlayer_maxwidth=0.184 bottomlayer_prefwidth=0.182 impedanceprofiledriven=TRUE impedanceprofileid={2EC469A3-C20B-4F07-A421-E0D2C58D58A8} impedanceprofilevalue=36.000000 minimp=50.000000 maximp=50.000000 favimp=50.000000
Width RAM_StubAddress39 [InNetClass('Single_36_39_50_Adr') and WithinRoom('RAMStubRoom_Addr')] p5: maxlimit=0.254 minlimit=0.15 preferedwidth=0.254 toplayer_maxwidth=0.156 toplayer_prefwidth=0.155 midlayer2_maxwidth=0.156 midlayer2_prefwidth=0.151 midlayer5_maxwidth=0.156 midlayer5_prefwidth=0.151 midlayer8_maxwidth=0.156 midlayer8_prefwidth=0.151 midlayer13_maxwidth=0.156 midlayer13_prefwidth=0.151 bottomlayer_maxwidth=0.156 bottomlayer_prefwidth=0.155 impedanceprofiledriven=TRUE impedanceprofileid={9B370C13-2427-420A-A153-D73BE69366B2} impedanceprofilevalue=39.000000 minimp=50.000000 maximp=50.000000 favimp=50.000000
Width RAM_Addr36 [InNetClass('Single_36_39_50_Adr')and not (WithinRoom('RAM_CLK')or WithinRoom('FPGA_Room'))] p6 off: maxlimit=0.254 minlimit=0.171 preferedwidth=0.254 toplayer_minwidth=0.181 toplayer_maxwidth=0.184 toplayer_prefwidth=0.182 midlayer2_maxwidth=0.184 midlayer2_prefwidth=0.173 midlayer5_maxwidth=0.184 midlayer5_prefwidth=0.173 midlayer8_maxwidth=0.184 midlayer8_prefwidth=0.173 midlayer13_maxwidth=0.184 midlayer13_prefwidth=0.173 bottomlayer_minwidth=0.181 bottomlayer_maxwidth=0.184 bottomlayer_prefwidth=0.182 impedanceprofiledriven=TRUE impedanceprofileid={2EC469A3-C20B-4F07-A421-E0D2C58D58A8} impedanceprofilevalue=36.000000 minimp=50.000000 maximp=50.000000 favimp=50.000000
Width Single_Ram_CLK [InNetClass('RAM_Clock_Signal')] p7: maxlimit=0.152 minlimit=0.102 preferedwidth=0.127
Width Single_RAM_Com [InNetClass('RAM_Adress')] p8: maxlimit=0.254 minlimit=0.068 preferedwidth=0.254 toplayer_minwidth=0.116 toplayer_maxwidth=0.211 toplayer_prefwidth=0.184 midlayer1_minwidth=0.092 midlayer1_maxwidth=0.173 midlayer1_prefwidth=0.151 midlayer2_minwidth=0.092 midlayer2_maxwidth=0.173 midlayer2_prefwidth=0.151 midlayer3_minwidth=0.254 midlayer4_minwidth=0.254 midlayer5_minwidth=0.092 midlayer5_maxwidth=0.173 midlayer5_prefwidth=0.151 midlayer6_minwidth=0.092 midlayer6_maxwidth=0.173 midlayer6_prefwidth=0.151 midlayer7_maxwidth=0.132 midlayer7_prefwidth=0.114 midlayer8_minwidth=0.092 midlayer8_maxwidth=0.173 midlayer8_prefwidth=0.151 midlayer9_minwidth=0.092 midlayer9_prefwidth=0.151 midlayer10_minwidth=0.254 midlayer11_minwidth=0.254 midlayer12_minwidth=0.254 midlayer13_minwidth=0.092 midlayer13_maxwidth=0.173 midlayer13_prefwidth=0.151 midlayer14_maxwidth=0.132 midlayer14_prefwidth=0.114 bottomlayer_minwidth=0.116 bottomlayer_maxwidth=0.211 bottomlayer_prefwidth=0.184 minimp=50.000000 maximp=50.000000 favimp=50.000000 // Track's for Adress, comands and control
Width Single_RAM_Ten [InNet('DDR4_TEN')] p9: maxlimit=0.254 minlimit=0.068 preferedwidth=0.254 toplayer_minwidth=0.116 toplayer_maxwidth=0.211 toplayer_prefwidth=0.184 midlayer1_minwidth=0.092 midlayer1_maxwidth=0.173 midlayer1_prefwidth=0.151 midlayer2_minwidth=0.092 midlayer2_maxwidth=0.173 midlayer2_prefwidth=0.151 midlayer3_minwidth=0.254 midlayer4_minwidth=0.254 midlayer5_minwidth=0.092 midlayer5_maxwidth=0.173 midlayer5_prefwidth=0.151 midlayer6_minwidth=0.092 midlayer6_maxwidth=0.173 midlayer6_prefwidth=0.151 midlayer7_maxwidth=0.132 midlayer7_prefwidth=0.114 midlayer8_minwidth=0.092 midlayer8_maxwidth=0.173 midlayer8_prefwidth=0.151 midlayer9_minwidth=0.092 midlayer9_prefwidth=0.151 midlayer10_minwidth=0.254 midlayer11_minwidth=0.254 midlayer12_minwidth=0.254 midlayer13_minwidth=0.092 midlayer13_maxwidth=0.173 midlayer13_prefwidth=0.151 midlayer14_maxwidth=0.132 midlayer14_prefwidth=0.114 bottomlayer_minwidth=0.116 bottomlayer_maxwidth=0.211 bottomlayer_prefwidth=0.184 minimp=50.000000 maximp=50.000000 favimp=50.000000 // Track's for Adress, comands and control
Width SingleRam_Data [InNetClass('RAM_Data_IO')] p10: maxlimit=0.254 minlimit=0.068 preferedwidth=0.254 toplayer_minwidth=0.101 toplayer_maxwidth=0.211 toplayer_prefwidth=0.101 midlayer2_minwidth=0.081 midlayer2_maxwidth=0.173 midlayer2_prefwidth=0.081 midlayer5_minwidth=0.081 midlayer5_maxwidth=0.173 midlayer5_prefwidth=0.081 midlayer8_minwidth=0.081 midlayer8_maxwidth=0.173 midlayer8_prefwidth=0.081 midlayer13_minwidth=0.081 midlayer13_maxwidth=0.173 midlayer13_prefwidth=0.081 bottomlayer_minwidth=0.101 bottomlayer_maxwidth=0.211 bottomlayer_prefwidth=0.101 impedanceprofiledriven=TRUE impedanceprofileid={C52096D4-C36E-4BDB-BB83-9E54FFDADA41} impedanceprofilevalue=50.000000 minimp=50.000000 maximp=50.000000 favimp=50.000000 // Track's for comand in r
Width Single45 [InNetClass('Single_45')] p11: maxlimit=0.254 minlimit=0.111 preferedwidth=0.254 toplayer_minwidth=0.113 toplayer_maxwidth=0.143 toplayer_prefwidth=0.135 midlayer2_maxwidth=0.115 midlayer2_prefwidth=0.111 midlayer5_maxwidth=0.115 midlayer5_prefwidth=0.111 midlayer8_maxwidth=0.115 midlayer8_prefwidth=0.111 midlayer13_maxwidth=0.115 midlayer13_prefwidth=0.111 bottomlayer_minwidth=0.113 bottomlayer_maxwidth=0.143 bottomlayer_prefwidth=0.135 impedanceprofiledriven=TRUE impedanceprofileid={F22BED46-E16F-4103-815A-6A081543B36A} impedanceprofilevalue=45.000000 minimp=50.000000 maximp=50.000000 favimp=50.000000 // Single line impedance 45 Ohm
Width "Single 50" [InNetClass('Single_50')] p12: maxlimit=0.254 minlimit=0.073 preferedwidth=0.254 toplayer_minwidth=0.1 toplayer_maxwidth=0.12 toplayer_prefwidth=0.101 midlayer2_maxwidth=0.092 midlayer2_prefwidth=0.081 midlayer5_maxwidth=0.092 midlayer5_prefwidth=0.081 midlayer8_minwidth=0.079 midlayer8_maxwidth=0.092 midlayer8_prefwidth=0.081 midlayer13_minwidth=0.079 midlayer13_maxwidth=0.092 midlayer13_prefwidth=0.081 bottomlayer_minwidth=0.1 bottomlayer_maxwidth=0.12 bottomlayer_prefwidth=0.101 impedanceprofiledriven=TRUE impedanceprofileid={C52096D4-C36E-4BDB-BB83-9E54FFDADA41} impedanceprofilevalue=50.000000 minimp=50.000000 maximp=50.000000 favimp=50.000000 checkconnectedcopper=TRUE // Single impedance line 50 Ohm
Width [InNetClass('SFP_diff')] p13 off: maxlimit=0.254 minlimit=0.254 preferedwidth=0.254
Width Power1A [InNetClass('Power_Line_1A')] p14: maxlimit=2 minlimit=0.2 preferedwidth=0.5
Width Power2A [InNetClass('Power_Line_2A')] p15: maxlimit=2 minlimit=0.2 preferedwidth=0.5
Width Power10A [InNetClass('Power_Line_10A')] p16: maxlimit=2 minlimit=0.2 preferedwidth=0.5
Width Power20A [InNetClass('Power_Line_20A')] p17: maxlimit=2 minlimit=0.2 preferedwidth=0.5
Width Power40A [InNetClass('Power_Line_40A')] p18: maxlimit=2 minlimit=0.2 preferedwidth=0.5
Width Power1A_5 [InNetClass('Ground')] p19: maxlimit=1 minlimit=0.2 preferedwidth=0.5
Width Other [All] p20: maxlimit=2 minlimit=0.12 preferedwidth=0.2
20 further rules are at their usual default settings.

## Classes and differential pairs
net class eMMC_Data: eMMC_data0 eMMC_data1 eMMC_data2 eMMC_data3 eMMC_data4 eMMC_data5 eMMC_data6 eMMC_data7
component class Main_Board: FID1 FID2 FID3 FID4 FID5 FID6 FID7 FID8
net class SFP_RX: SFP0_Rx_N SFP0_Rx_P SFP1_Rx_N SFP1_Rx_P SFP2_Rx_N SFP2_Rx_P SFP3_Rx_N SFP3_Rx_P
net class SFP_R_TX: SFP0_Tx_FPGA_N SFP0_Tx_FPGA_P SFP1_Tx_FPGA_N SFP1_Tx_FPGA_P SFP2_Tx_FPGA_N SFP2_Tx_FPGA_P SFP3_Tx_FPGA_N SFP3_Tx_FPGA_P
net class SFP_R_RX: SFP0_Rx_FPGA_N SFP0_Rx_FPGA_P SFP2_Rx_FPGA_N SFP2_Rx_FPGA_P SFP3_Rx_FPGA_N SFP3_Rx_FPGA_P
net class SPI1_MIO: MIO_64 MIO_67 MIO_68 MIO_69
net class SPI_PCIE_RF_4: HiSpeedModule_SPI4.C\S\ HiSpeedModule_SPI4.CLK HiSpeedModule_SPI4.MISO HiSpeedModule_SPI4.MOSI
net class SPI_PCIE_RF_3: HiSpeedModule_SPI3.C\S\ HiSpeedModule_SPI3.CLK HiSpeedModule_SPI3.MISO HiSpeedModule_SPI3.MOSI
net class SPI_PCIE_RF_2: HiSpeedModule_SPI2.C\S\ HiSpeedModule_SPI2.CLK HiSpeedModule_SPI2.MISO HiSpeedModule_SPI2.MOSI
net class SPI_PCIE_RF_1: HiSpeedModule_SPI1.C\S\ HiSpeedModule_SPI1.CLK HiSpeedModule_SPI1.MISO HiSpeedModule_SPI1.MOSI
net class SPI_PCIE_RF_0: HiSpeedModule_SPI0.C\S\ HiSpeedModule_SPI0.CLK HiSpeedModule_SPI0.MISO HiSpeedModule_SPI0.MOSI
component class U_LED_US_1: D45 D46 D47 D48 D49 D50 D51 D52 D53 R1090 R1095 R1096 R1099 R1102 R1107 R1108 R1111 R1112 R1113 R1114 R1115 R1116 R1117 R1118 R1119 R1120 R1121 T50 T51 T52 T53 T54 T55 T56 T57 T58
net class UART_FTDI_US2: US2_FTDI_UART1_RXD US2_FTDI_UART1_TXD
net class UART_FTDI_US1_2: uart0_RxD uart0_TxD
net class UART_FTDI_US1_1: uart1_RxD uart1_TxD
net class UART_FTDI_LS_2: FTDI_LS_UART2_RXD FTDI_LS_UART2_TXD
net class UART_FTDI_LS_1: FTDI_LS_UART_RXD FTDI_LS_UART_TXD
net class UART_FTDI_LS_0: FTDI_LS_UART0_RXD FTDI_LS_UART0_TXD
net class UART_FPGA_R: uart_FPGA_RxD_R uart_FPGA_TxD_R
net class SPI_US2_R: SPI_FPGA_CLK SPI_FPGA_CS SPI_FPGA_MISO SPI_FPGA_MOSI
net class SPI_US2_FPGA_R: SPI_FPGA_CLK_R SPI_FPGA_CS_R SPI_FPGA_MISO_R SPI_FPGA_MOSI_R
net class SPI_PCIE_RF: HiSpeedModule_SPI0.C\S\ HiSpeedModule_SPI0.CLK HiSpeedModule_SPI0.MISO HiSpeedModule_SPI0.MOSI HiSpeedModule_SPI1.C\S\ HiSpeedModule_SPI1.CLK HiSpeedModule_SPI1.MISO HiSpeedModule_SPI1.MOSI HiSpeedModule_SPI2.C\S\ HiSpeedModule_SPI2.CLK HiSpeedModule_SPI2.MISO HiSpeedModule_SPI2.MOSI HiSpeedModule_SPI3.C\S\ HiSpeedModule_SPI3.CLK HiSpeedModule_SPI3.MISO HiSpeedModule_SPI3.MOSI HiSpeedModule_SPI4.C\S\ HiSpeedModule_SPI4.CLK HiSpeedModule_SPI4.MISO HiSpeedModule_SPI4.MOSI
net class SPI_MAIN: SPI1_CLK SPI1_CS SPI1_MISO SPI1_MOSI
net class SPI_LTC_1: CLK0_SPI.C\S\ CLK0_SPI.CLK CLK0_SPI.MISO CLK0_SPI.MOSI
net class SPI_LTC_0: CLK1_SPI.C\S\ CLK1_SPI.CLK CLK1_SPI.MISO CLK1_SPI.MOSI
net class SPI_DAC: DAC_SPI_CLK DAC_SPI_MOSI SPI_DAC_CS
net class SPI_05028: I2C_05028_SCL I2C_05028_SDA SPI_05028_CS SPI_05028_MISO
net class MDI_ETH: GEM3_MDC GEM3_MDIO
net class JTAG_US_PS: US_PS_JTAG_TCK US_PS_JTAG_TDI US_PS_JTAG_TDO US_PS_JTAG_TMS
net class JTAG_FTDI: FTDI_TCK FTDI_TDI FTDI_TDO FTDI_TMS
net class CAN: CAN0_H CAN0_L
net class CAN_US_01: CAN1_RxD CAN1_TxD
component class U_Power_LED: D22 D25 D29 D30 D31 D32 D33 D34 D35 D36 D37 D38 D39 D40 D41 D42 D43 D44 R913 R914 R915 R916 R917 R1059 R1060 R1061 R1062 R1063 R1064 R1065 R1066 R1069 R1070 R1075 R1076 R1078 R1079 R1081 R1082 R1089 T2 T3 T4 T32 T33 T37 T38 T39 T40 T41 T42 T43 T44 T45 T46 T47 T48 T49
net class uSD_Dev: uSD_CD uSD_CLK uSD_CMD uSD_D0 uSD_D1 uSD_D2 uSD_D3 uSD_D4 uSD_D5 uSD_D6 uSD_D7
net class USB2_Dev: USB2_CLK USB2_D0 USB2_D1 USB2_D2 USB2_D3 USB2_D4 USB2_D5 USB2_D6 USB2_D7 USB2_DIR USB2_NXT USB2_STP
net class eMMC_Dev: eMMC_clk eMMC_cmd eMMC_data0 eMMC_data1 eMMC_data2 eMMC_data3 eMMC_data4 eMMC_data5 eMMC_data6 eMMC_data7 eMMC_rst
net class SPI1_Group: SPI1_CLK SPI1_CS SPI1_MISO SPI1_MOSI
net class SFP_diff_FPGA: SFP0_Rx_FPGA_N SFP0_Rx_FPGA_P SFP0_Tx_FPGA_N SFP0_Tx_FPGA_P SFP1_Rx_FPGA_N SFP1_Rx_FPGA_P SFP1_Tx_FPGA_N SFP1_Tx_FPGA_P SFP2_Rx_FPGA_N SFP2_Rx_FPGA_P SFP2_Tx_FPGA_N SFP2_Tx_FPGA_P SFP3_Rx_FPGA_N SFP3_Rx_FPGA_P SFP3_Tx_FPGA_N SFP3_Tx_FPGA_P
net class USB_FTDI_D: FTDI_D_N FTDI_D_P
net class SYNC: SYNC_PCIE0_N SYNC_PCIE0_P SYNC_PCIE1_N SYNC_PCIE1_P SYNC_PCIE2_N SYNC_PCIE2_P SYNC_PCIE3_N SYNC_PCIE3_P SYNC_PCIE4_N SYNC_PCIE4_P
net class RF_SYSEF_TO_FPGA*: RF_SYSREF_TO_FPGA_PCIE0_N RF_SYSREF_TO_FPGA_PCIE0_P RF_SYSREF_TO_FPGA_PCIE1_N RF_SYSREF_TO_FPGA_PCIE1_P RF_SYSREF_TO_FPGA_PCIE2_N RF_SYSREF_TO_FPGA_PCIE2_P RF_SYSREF_TO_FPGA_PCIE3_N RF_SYSREF_TO_FPGA_PCIE3_P RF_SYSREF_TO_FPGA_PCIE4_N RF_SYSREF_TO_FPGA_PCIE4_P
net class EXT_SRQ: CLK0_EZS_N CLK0_EZS_P
net class Si53323_2_Q2_C: Si53323_2_Q2_C_N Si53323_2_Q2_C_P
net class Si53323_1_Q2_C: Si53323_1_Q2_C_N Si53323_1_Q2_C_P
net class Ground: B503_Ground
net class USB2_Lines: MIO_52 MIO_53 MIO_54 MIO_55 MIO_56 MIO_57 MIO_58 MIO_59 MIO_60 MIO_61 MIO_62 MIO_63
net class uSD_Lines: MIO_13 MIO_14 MIO_15 MIO_16 MIO_17 MIO_18 MIO_19 MIO_20 MIO_21 MIO_22 MIO_24
net class eMMC_Lines: MIO_39 MIO_40 MIO_41 MIO_42 MIO_43 MIO_46 MIO_47 MIO_48 MIO_49 MIO_50 MIO_51
net class WR_CLK2: WR_LMK_CLK_RC_HF2_N WR_LMK_CLK_RC_HF2_P
net class WR_CLK1: WR_LMK_CLK_RC_HF1_N WR_LMK_CLK_RC_HF1_P
net class LTC_6952_2_MATCH_REF: LTC6952_1_REF_MATCH_N LTC6952_1_REF_MATCH_P
net class Interrupt_Line: Interrupt0 Interrupt1 Interrupt2 Interrupt3 Interrupt4 Interrupt5 Interrupt6 Interrupt7 Interrupt8 Interrupt9 Interrupt10 Interrupt11 Interrupt12 Interrupt13 Interrupt14 Interrupt15 Interrupt16 Interrupt17 Interrupt18 Interrupt19 Interrupt20 Interrupt21 Interrupt22 Interrupt23 Interrupt24 Interrupt25 Interrupt26 Interrupt27 Interrupt28 Interrupt29 Interrupt30 Interrupt31 Interrupt32 Interrupt33 Interrupt34 Interrupt35 Interrupt36 Interrupt37 Interrupt38 Interrupt39 Interrupt40 Interrupt41 Interrupt42 Interrupt43 Interrupt44 Interrupt45 Interrupt46 Interrupt47 Interrupt48 Interrupt49 Interrupt50 Interrupt51 Interrupt52 Interrupt53 Interrupt54 Interrupt55 Interrupt56 Interrupt57 Interrupt58 Interrupt59 Interrupt60 Interrupt61 Interrupt62 Interrupt63 Interrupt64 Interrupt65 Interrupt66 Interrupt67 Interrupt68 Interrupt69 Interrupt70 Interrupt71 Interrupt72 Interrupt73 Interrupt74 Interrupt75 Interrupt76 Interrupt77 Interrupt78 Interrupt79
component class I2C_Expander_02: C311_I2C_Expander_02 U35_I2C_Expander_02
component class I2C_Expander_01: C311_I2C_Expander_01 U35_I2C_Expander_01
component class I2C_Expander_00: C311_I2C_Expander_00 U35_I2C_Expander_00
net class Bank225_MGTREFx: Bank225_MGTREF0_N Bank225_MGTREF0_P
net class Bank224_MGTREFx: Bank224_MGTREF0_N Bank224_MGTREF0_P Bank224_MGTREF1_N Bank224_MGTREF1_P
net class Bank223_MGTREFx: Bank223_MGTREF0_N Bank223_MGTREF0_P Bank223_MGTREF1_N Bank223_MGTREF1_P
net class WR_CLK_C_LMK: LTC6952_1_MATCH_Out8_N LTC6952_1_MATCH_Out8_P
net class LTC_6952_1_REF: LTC6952_0_REF_N LTC6952_0_REF_P
component class "Xilinx FPGA": R75 R124 R363 R364 R365 R395 R398 R506 R507 R514 R900 R901 R902 R903 R904 R905 R906 R907 R908 R909 R910 R918 R919 SP30 SP31 SP32 SP33 U15
component class LTC6952_0: C43 C44 C47 C48 C54 C315 C316 C317 C318 C319 C478 C594 C599 C601 C602 C608 C682 C684 J2 J3 R76 R78 R79 R80 R81 R82 R539 R1054 R1055 R1056 R1057 R1058 R1067 R1068 R1071 R1072 R1073 R1074 U12
component class Ext_GPIO: R241 R242 R243 R244 R281 R281_G R400 R400_G R428 R428_g R599 R599_G R825 R826 R827 R828
component class Ext_GPIO_Bank0: R492 R493 R494 R495 R496 R497 R500 R501 R502 R503 R504 R505 R508 R509 R510 R511 R512 R513
component class ClockDistrib: C45 C46 C334 C335 R77 R532 R533 TP19 TP20 X1
differential pair class Diff_86: DDR4_CK
differential pair class Diff_76: DDR4_CK
component class GND: J31 MH1 MH2 MH3 MH4 MH5 MH6 MH7 MH8 MH9 MH10 MH11 MH12 MH13 MH14 MH15 MH16 MH17 MH18 MH19 MH20 MH21 MH22 MH23 MH24 MH25
component class I2C_Expander_12: C311_I2C_Expander_12 U35_I2C_Expander_12
component class I2C_Expander_11: C311_I2C_Expander_11 U35_I2C_Expander_11
component class I2C_Expander_10: C311_I2C_Expander_10 U35_I2C_Expander_10
component class I2C_Expander_Main_Rst: C311_I2C_Expander_Main_Rst U35_I2C_Expander_Main_Rst
component class I2C_Bridge_GPIO: C303_I2C_Bridge_GPIO R3_I2C_Bridge_GPIO R4_I2C_Bridge_GPIO R5_I2C_Bridge_GPIO R6_I2C_Bridge_GPIO R7_I2C_Bridge_GPIO R8_I2C_Bridge_GPIO R9_I2C_Bridge_GPIO R10_I2C_Bridge_GPIO R223_I2C_Bridge_GPIO R224_I2C_Bridge_GPIO R225_I2C_Bridge_GPIO R226_I2C_Bridge_GPIO R227_I2C_Bridge_GPIO R558_I2C_Bridge_GPIO R559_I2C_Bridge_GPIO R560_I2C_Bridge_GPIO SP1_I2C_Bridge_GPIO SP2_I2C_Bridge_PCIE SP3_I2C_Bridge_GPIO SP4_I2C_Bridge_GPIO SP5_I2C_Bridge_GPIO SP6_I2C_Bridge_GPIO SP7_I2C_Bridge_GPIO SP8_I2C_Bridge_GPIO SP9_I2C_Bridge_GPIO SP10_I2C_Bridge_GPIO SP11_I2C_Bridge_GPIO SP12_I2C_Bridge_GPIO SP13_I2C_Bridge_GPIO SP14_I2C_Bridge_GPIO SP15_I2C_Bridge_GPIO SP16_I2C_Bridge_GPIO SP17_I2C_Bridge_GPIO SP18_I2C_Bridge_GPIO U3_I2C_Bridge_GPIO
differential pair class Diff_90: DDR4_CK FTDI_D USB_D USB_RX USB_RX_C USB_TX USB_TX_C
net class uSD_to_Driv: CMD_SD DATA0_SD DATA1_SD DATA2_SD DATA3_SD SD_Card_CLK
net class USB_2.0: USB_D_N USB_D_P
net class USB3._to_C: USB_RX_C_N USB_RX_C_P USB_TX_C_N USB_TX_C_P
net class USB3._C_to_FPGA: USB_RX_N USB_RX_P USB_TX_N USB_TX_P
net class Single_45: FTDI_D_N FTDI_D_P USB_D_N USB_D_P USB_RX_C_N USB_RX_C_P USB_RX_N USB_RX_P USB_TX_C_N USB_TX_C_P USB_TX_N USB_TX_P
net class SGMII_DATA_TO_C: SGMI_Rx_N SGMI_Rx_P SGMI_Tx_N SGMI_Tx_P
net class SGMII_DATA_C_FPGA: SGMI_C_Rx_N SGMI_C_Rx_P SGMI_C_Tx_N SGMI_C_Tx_P
net class Power_Line_40A: 0.85V@40A_INA US+_Vcc_PS_IntFp
net class Power_Line_20A: 3V3_RAIL RAM_Vcc1V2 Vout1_1 Vout2_1
net class Power_Line_10A: 3V3_NVMe 5V_RAIL 12V_LT3042 Vout1_2 Vout2_2
net class Power_Line_2A: 0V9@1A_REG3 0V85@2A 1V0@1.5A 1V8@0.5A_ADC_filtered 1V8@1.5A 2V5@1.5A 3.3V_LN_1 3.3V_Stable_1 3.3V_Stable_2 12V_PCIE0 12V_PCIE0_CM 12V_PCIE1 12V_PCIE1_CM 12V_PCIE2 12V_PCIE2_CM 12V_PCIE3 12V_PCIE3_CM 12V_PCIE4 12V_PCIE4_CM FTDI_5V FTDI_VBUS FTDI_VccIO NetC568_2 NetC674_2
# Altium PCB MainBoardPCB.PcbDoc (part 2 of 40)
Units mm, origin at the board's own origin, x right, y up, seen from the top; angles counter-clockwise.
Board outline 258.95 x 308.86 mm, 16 copper layers (L1, L2 (GND), L3 (Sign), L4 (GND), L5 (Sign), L6 (PWR/GND), L7(12V+Other), L8 (Plane_GND), L9 (PWR/GND), L10 (3V3+Other), L11 (PWR/GND), L12 (Sign), L13 (GND), L14 (Sign), L15 (GND), L16), stack 2.503 mm thick; 2578 components, 1867 nets, 8817 pads, 8021 vias.
Unrouted connection lines stored in the file: 25.

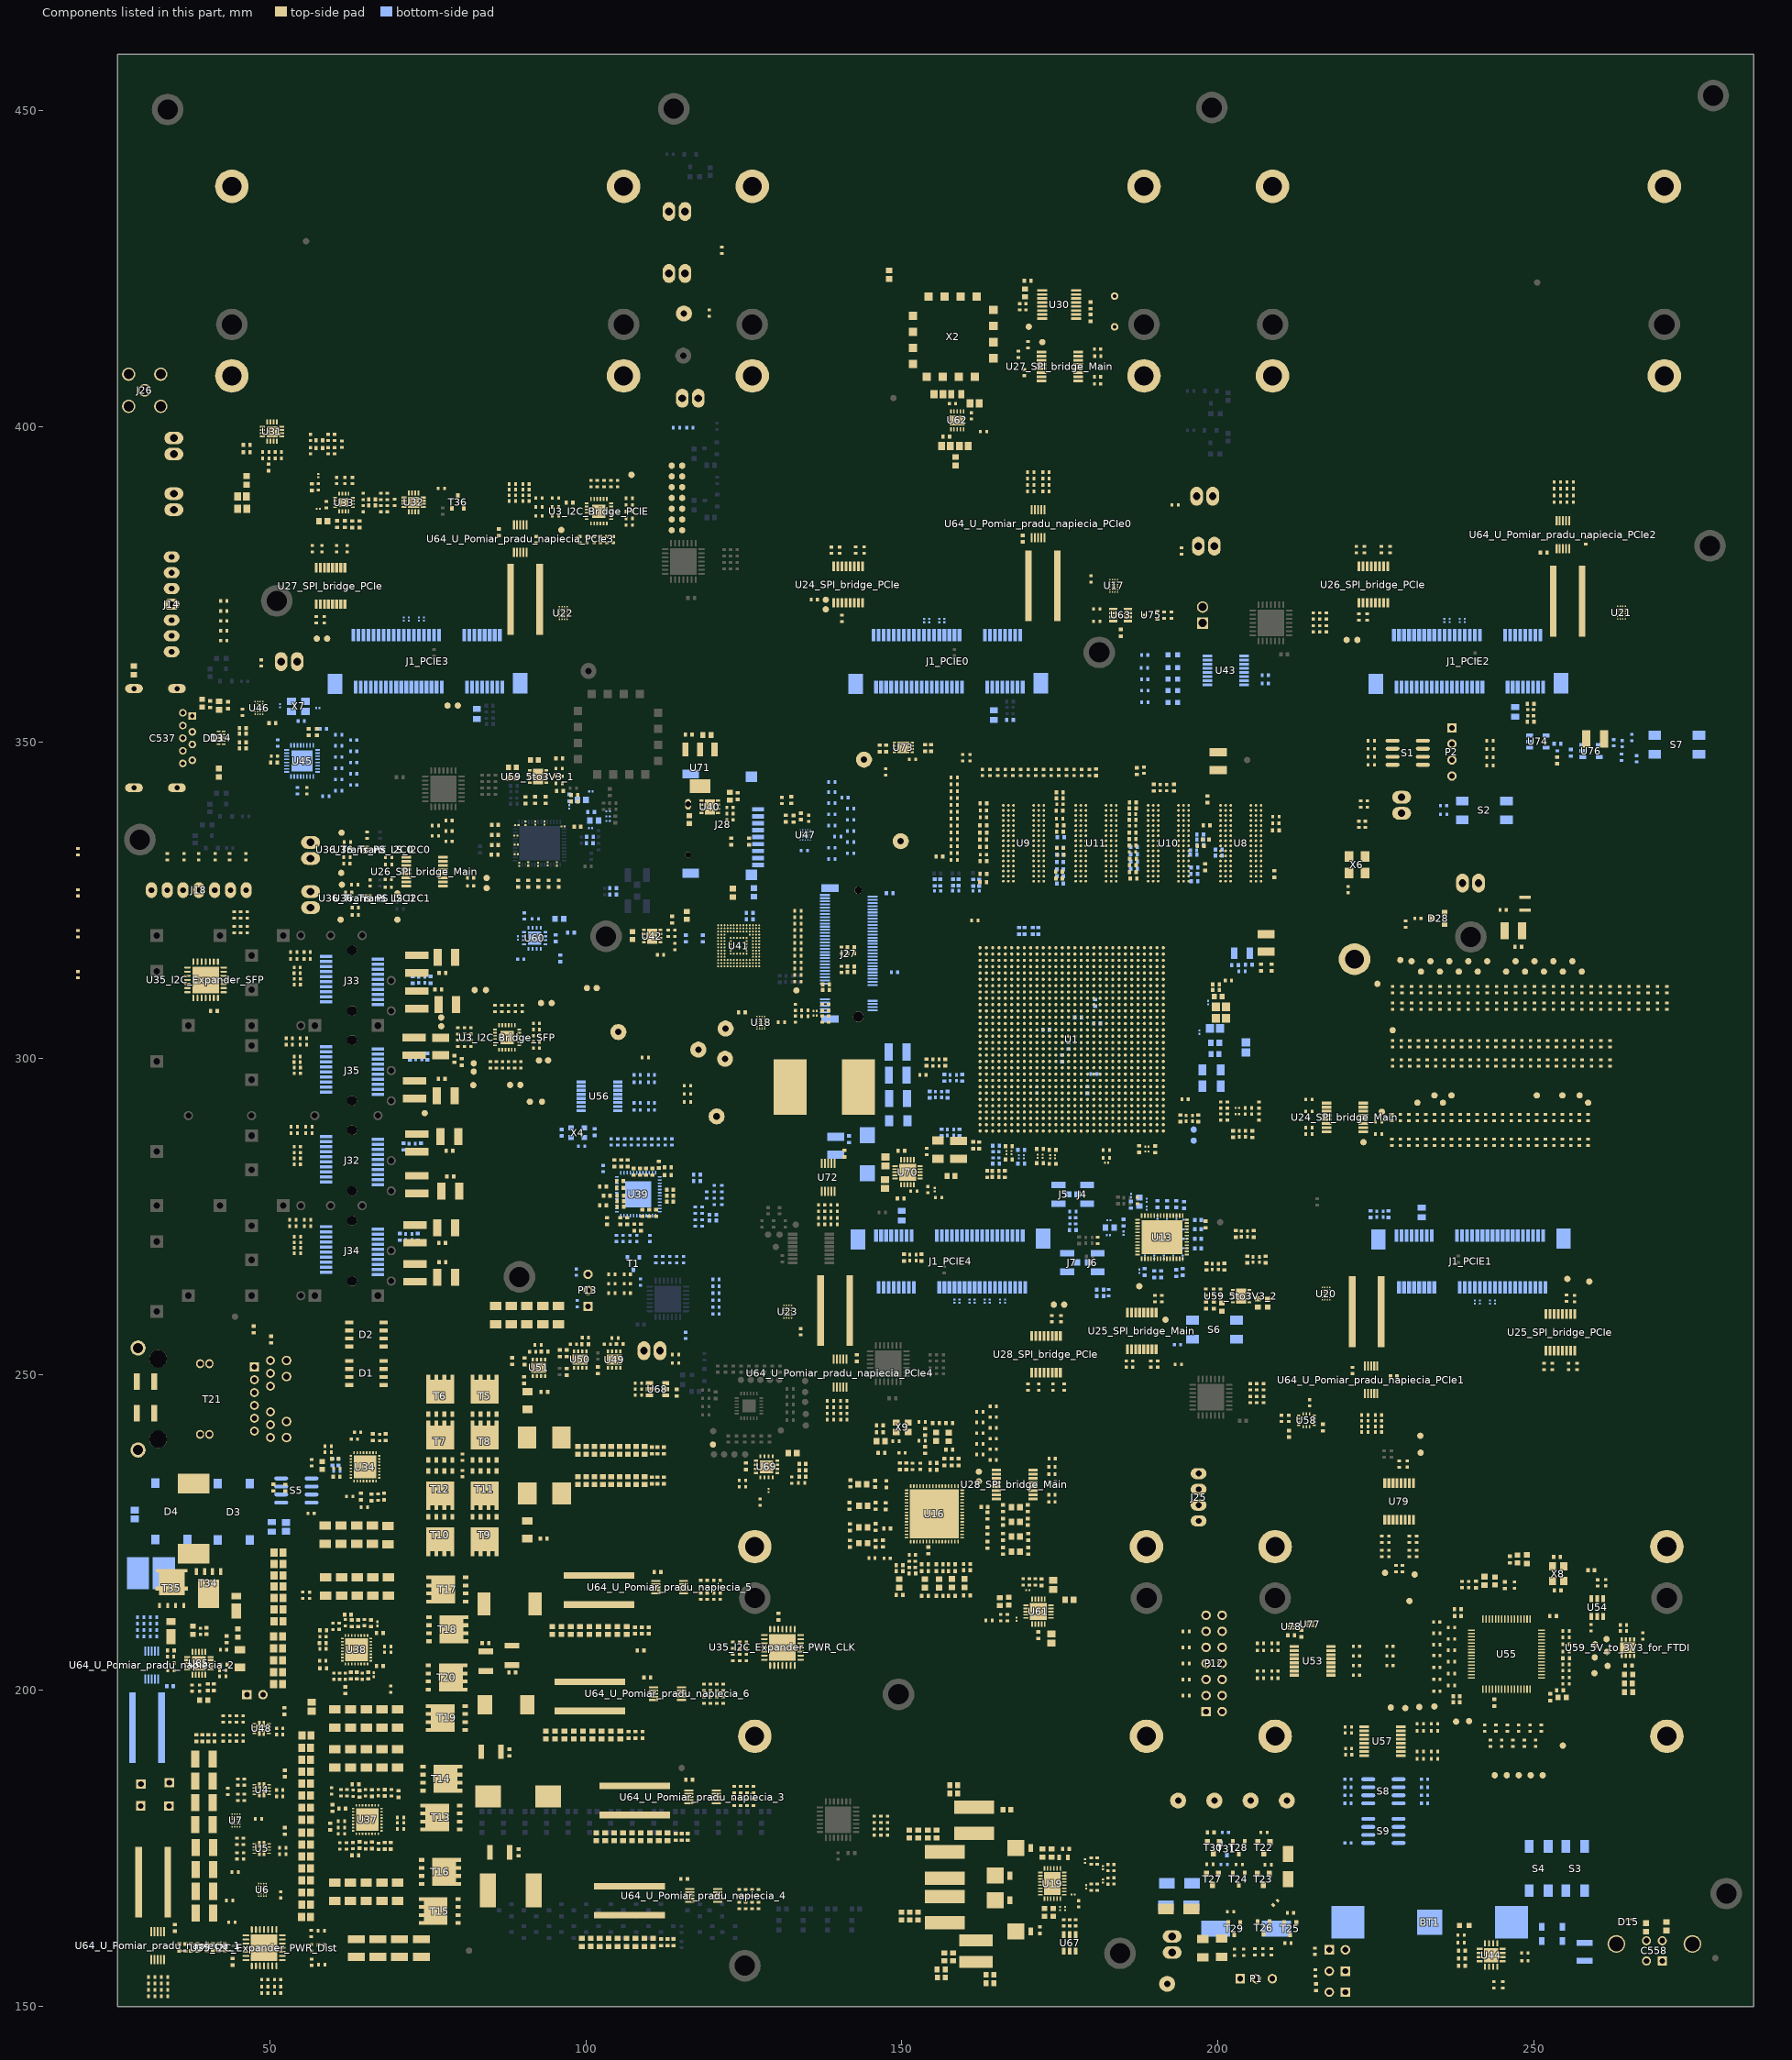
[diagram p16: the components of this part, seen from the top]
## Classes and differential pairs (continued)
net class NVMe_DATA: NVMe_Rx_0_N NVMe_Rx_0_P NVMe_Rx_1_N NVMe_Rx_1_P NVMe_Tx_0_N NVMe_Tx_0_P NVMe_Tx_1_N NVMe_Tx_1_P
net class DATA_ETH_TO_PHY: TD_A_N TD_A_P TD_B_N TD_B_P TD_C_N TD_C_P TD_D_N TD_D_P
component class µSD: C544 C545 C546 C547 FB29 J28 R381 R382 R383 R845 R911 U47
component class USB3.0: C1 C2 C3 C537 C538 C539 C540 C541 C542 C543 C731 C732 C733 C734 C735 C736 C737 D13 D14 FB26 FB27 FB28 R376 R377 R378 R379 R380 R490 R491 U45 U46 U74 X7
component class U_Expander_RESET: R746 R747 R748 R749 R750 R751 R752 R753 R754 R755 R756 R757 R758 R759 R760 R761 R762 R763 R1002 R1003 T1
component class U_CAN: C585 P6 R446 R447 U63 U75
component class NVMe: J27 MP5 R541 R542
component class "Gigabit Eth": C471 C472 C473 C474 C475 C476 C479 C480 C481 C482 C483 C484 C485 C486 C487 C488 C489 C490 C491 C492 C493 C494 C495 C496 C497 C498 C499 C500 C501 C502 C503 C504 C505 C506 C507 C508 C509 C510 C511 C512 C513 C514 C790 D1 D2 D3 D4 R319 R320 R321 R322 R323 R324 R325 R326 R327 R328 R329 R330 R331 R332 R333 R334 R335 R336 R337 R338 R709 R710 R711 R712 R713 R714 R715 S7 T21 U39 U76 X4
component class Flash_Memory: C515 C516 C517 C518 C519 C520 C521 C522 C523 C524 C586 C587 FB25 R339 R340 R341 R342 R343 R344 R345 U40 U41 U42
component class Debug: C558 C559 C560 C658 C659 C660 C661 C662 C663 C664 C665 C666 C667 C668 C669 C670 C671 C672 C673 C791 C792 D15 FB31 FB32 FB43 FB44 P12 R401 R402 R403 R404 R405 R406 R407 R408 R409 R410 R411 R412 R413 R414 R415 R416 R417 R418 R419 R420 R421 R422 R423 R424 R635 R636 R637 R638 R639 R640 R641 R642 R643 R721 R722 R723 R724 R725 R726 R727 R728 R729 R730 R731 R732 R733 R734 R1001 R1004 R1005 R1006 R1007 R1008 R1009 R1010 R1011 R1012 R1013 R1014 R1015 R1016 R1017 R1018 R1019 R1020 R1021 R1022 R1023 R1024 R1025 R1026 R1027 R1028 R1029 R1030 R1031 R1032 R1033 R1034 R1035 R1036 R1037 R1038 R1039 R1040 R1041 R1042 R1043 R1044 R1045 R1046 R1047 R1048 R1049 R1050 R1051 S8 S9 SP65 SP66 SP67 SP68 SP69 SP70 SP71 SP72 SP73 SP74 SP75 SP76 SP77 SP78 SP79 SP80 SP81 SP82 SP83 SP84 SP85 SP86 SP87 U53 U54 U55 U56 U57 U77 U78 U79 X8
component class 5V_to_3V3_for_FTDI: C563_5V_to_3V3_for_FTDI C564_5V_to_3V3_for_FTDI C565_5V_to_3V3_for_FTDI C566_5V_to_3V3_for_FTDI C567_5V_to_3V3_for_FTDI R430_5V_to_3V3_for_FTDI R431_5V_to_3V3_for_FTDI R432_5V_to_3V3_for_FTDI U59_5V_to_3V3_for_FTDI
component class I2C_Expander_PWR_CLK: C311_I2C_Expander_PWR_CLK U35_I2C_Expander_PWR_CLK
component class I2C_Expander_PWR_Dist: C311_I2C_Expander_PWR_Dist U35_I2C_Expander_PWR_Dist
component class U_FPGA_Decoupling: C738 C739 C740 C741 C742 C743 C744 C745 C746 C747 C748 C749 C750 C751 C752 C753 C754 C755 C756 C757 C758 C759 C760 C761 C762 C763 C764 C765
net class NVME_DATA_BANK: NVME_C_RX_1_N NVME_C_RX_1_P NVME_C_RX_O_N NVME_C_RX_O_P NVME_C_TX_1_N NVME_C_TX_1_P NVME_C_TX_O_N NVME_C_TX_O_P
component class U_ST1L08_5V_0V6: C720 C721 C722 C723 R689 R690 R691 U73
component class U_Pomiar_napiecia_high_curr: C310 R617 U72
component class U_UM78M_12_8V: C713 C714 U71
component class U_TPS7A88_3V3_1V8_0V9V@2x1A: C705 C706 C707 C708 C709 C710 C711 C712 R671 R672 R673 R674 R676 R745 U70
component class U_ADP1741_3V3_0V85: C674 C675 C676 C719 FB45 R435 R644 R645 R646 R668 U69
component class LowCurr: C304 C305 C306 C307 C308 C354 C355 C603 C604 C605 C606 C607 C610 C611 C612 C613 C614 C615 C616 C617 C618 C619 C620 C621 C622 C623 C624 C625 C626 D16 D17 D18 D19 L13 L15 L16 L17 L18 R113 R114 R212 R214 R216 R218 R220 R274 R284 R305 R308 R309 U19 U67
component class U_Detektor_otwarcia: BT1 BT? C609 C678 C679 C680 D20 D21 D23 D24 J36 R647 R648 R649 R650 R651 R652 R653 R654 R655 R656 R657 R658 T22 T23 T24 T25 T26 T27 T28 T29 T30 T31
net class RAM_DQS_Strobe: DDR4_DQS_0_N DDR4_DQS_0_P DDR4_DQS_1_N DDR4_DQS_1_P DDR4_DQS_2_N DDR4_DQS_2_P DDR4_DQS_3_N DDR4_DQS_3_P DDR4_DQS_4_N DDR4_DQS_4_P DDR4_DQS_5_N DDR4_DQS_5_P DDR4_DQS_6_N DDR4_DQS_6_P DDR4_DQS_7_N DDR4_DQS_7_P DDR4_DQS_8_N DDR4_DQS_8_P
net class RAM_Data_IO: DDR4_DM0 DDR4_DM1 DDR4_DM2 DDR4_DM3 DDR4_DM4 DDR4_DM5 DDR4_DM6 DDR4_DM7 DDR4_DQ0 DDR4_DQ1 DDR4_DQ2 DDR4_DQ3 DDR4_DQ4 DDR4_DQ5 DDR4_DQ6 DDR4_DQ7 DDR4_DQ8 DDR4_DQ9 DDR4_DQ10 DDR4_DQ11 DDR4_DQ12 DDR4_DQ13 DDR4_DQ14 DDR4_DQ15 DDR4_DQ16 DDR4_DQ17 DDR4_DQ18 DDR4_DQ19 DDR4_DQ20 DDR4_DQ21 DDR4_DQ22 DDR4_DQ23 DDR4_DQ24 DDR4_DQ25 DDR4_DQ26 DDR4_DQ27 DDR4_DQ28 DDR4_DQ29 DDR4_DQ30 DDR4_DQ31 DDR4_DQ32 DDR4_DQ33 DDR4_DQ34 DDR4_DQ35 DDR4_DQ36 DDR4_DQ37 DDR4_DQ38 DDR4_DQ39 DDR4_DQ40 DDR4_DQ41 DDR4_DQ42 DDR4_DQ43 DDR4_DQ44 DDR4_DQ45 DDR4_DQ46 DDR4_DQ47 DDR4_DQ48 DDR4_DQ49 DDR4_DQ50 DDR4_DQ51 DDR4_DQ52 DDR4_DQ53 DDR4_DQ54 DDR4_DQ55 DDR4_DQ56 DDR4_DQ57 DDR4_DQ58 DDR4_DQ59 DDR4_DQ60 DDR4_DQ61 DDR4_DQ62 DDR4_DQ63
net class Power_Line_1A: 12V_LT3042 ADP1741_3.6V ETH_VDDIO NetD16_2 NetD17_1 NetD17_2 NetD18_1 NetD18_2 NetD19_1 NetD19_2 Power_3.3_1 Power_3.3_2 US+_MGTVccAux US+_Vcc_PS_DDR_504
net class Lenght_DQS_to_Data: DDR4_DM0 DDR4_DM1 DDR4_DM2 DDR4_DM3 DDR4_DM4 DDR4_DM5 DDR4_DM6 DDR4_DM7 DDR4_DQ0 DDR4_DQ1 DDR4_DQ2 DDR4_DQ3 DDR4_DQ4 DDR4_DQ5 DDR4_DQ6 DDR4_DQ7 DDR4_DQ8 DDR4_DQ9 DDR4_DQ10 DDR4_DQ11 DDR4_DQ12 DDR4_DQ13 DDR4_DQ14 DDR4_DQ15 DDR4_DQ16 DDR4_DQ17 DDR4_DQ18 DDR4_DQ19 DDR4_DQ20 DDR4_DQ21 DDR4_DQ22 DDR4_DQ23 DDR4_DQ24 DDR4_DQ25 DDR4_DQ26 DDR4_DQ27 DDR4_DQ28 DDR4_DQ29 DDR4_DQ30 DDR4_DQ31 DDR4_DQ32 DDR4_DQ33 DDR4_DQ34 DDR4_DQ35 DDR4_DQ36 DDR4_DQ37 DDR4_DQ38 DDR4_DQ39 DDR4_DQ40 DDR4_DQ41 DDR4_DQ42 DDR4_DQ43 DDR4_DQ44 DDR4_DQ45 DDR4_DQ46 DDR4_DQ47 DDR4_DQ48 DDR4_DQ49 DDR4_DQ50 DDR4_DQ51 DDR4_DQ52 DDR4_DQ53 DDR4_DQ54 DDR4_DQ55 DDR4_DQ56 DDR4_DQ57 DDR4_DQ58 DDR4_DQ59 DDR4_DQ60 DDR4_DQ61 DDR4_DQ62 DDR4_DQ63
net class Lenght_DQS_to_CK: DDR4_DQS_0_N DDR4_DQS_0_P DDR4_DQS_1_N DDR4_DQS_1_P DDR4_DQS_2_N DDR4_DQS_2_P DDR4_DQS_3_N DDR4_DQS_3_P DDR4_DQS_4_N DDR4_DQS_4_P DDR4_DQS_5_N DDR4_DQS_5_P DDR4_DQS_6_N DDR4_DQS_6_P DDR4_DQS_7_N DDR4_DQS_7_P DDR4_DQS_8_N DDR4_DQS_8_P
net class Lenght_CK_to_Addr: DDR4_CK_N DDR4_CK_P
differential pair class Diff_76_to_90_Ram_CLK: DDR4_CK
net class RAM_Adress: DDR4_A0 DDR4_A1 DDR4_A2 DDR4_A3 DDR4_A4 DDR4_A5 DDR4_A6 DDR4_A7 DDR4_A8 DDR4_A9 DDR4_A10 DDR4_A11 DDR4_A12 DDR4_A13 DDR4_ACT_N DDR4_ALERT_N DDR4_BA0 DDR4_BA1 DDR4_BG0 DDR4_CAS DDR4_CKE0 DDR4_CS_B DDR4_DQS_ODT0 DDR4_PARITY DDR4_RAM_RST_N DDR4_RAS DDR4_TEN DDR4_WE
component class U_Power_48_20V@3A: C595 C596 C597 C598 C693 C694 C695 C696 C697 C698 C699 C700 C701 C702 C703 C704 D26 D27 L22 R140 R149 R150 R159 R160 R665 R666 R667 R669 R670 R764 T34 T35 U65
net class WR_CLK_C: WR_LMK_CLK_IN_N WR_LMK_CLK_IN_P
net class WR_CLK2_RC: WR_LMK_CLK_HF2_N WR_LMK_CLK_HF2_P
net class WR_CLK1_RC: WR_LMK_CLK_HF1_N WR_LMK_CLK_HF1_P
component class U_Pomiar_pradu_napiecia_1: C309_U_Pomiar_pradu_napiecia_1 R448_U_Pomiar_pradu_napiecia_1 U64_U_Pomiar_pradu_napiecia_1
component class U_Pomiar_pradu_napiecia_2: C309_U_Pomiar_pradu_napiecia_2 R448_U_Pomiar_pradu_napiecia_2 U64_U_Pomiar_pradu_napiecia_2
component class U_Pomiar_pradu_napiecia_3: C309_U_Pomiar_pradu_napiecia_3 R448_U_Pomiar_pradu_napiecia_3 U64_U_Pomiar_pradu_napiecia_3
component class U_Pomiar_pradu_napiecia_4: C309_U_Pomiar_pradu_napiecia_4 R448_U_Pomiar_pradu_napiecia_4 U64_U_Pomiar_pradu_napiecia_4
net class LTC_6952_2_REF_SMA: LTC6952_1_C_N LTC6952_1_C_P
component class DAC: C320 C321 C322 C323 R481 R608 R609 U30 X2 X3
net class Si53323_2_Q2_LVDS: Si53323_2_Q2_LVDS_N Si53323_2_Q2_LVDS_P
net class Si53323_1_Q2_LVDS: Si53323_1_Q2_LVDS_N Si53323_1_Q2_LVDS_P
component class SFP_Group+IMU: R469 R470 R471 R472 R473 R474 R475 R476 R477 R478 R479 R480
component class HighSpeed: R449 R450 R451 R452 R453 R454
component class CLK_MUX: C53 C324 C325 C326 C327 C328 C329 C330 C333 C336 C337 C338 C339 C340 C341 C342 C343 C344 C724 C725 C726 C727 FB23 FB24 J26 R100 R125 R245 R246 R247 R248 R249 R250 R251 R252 R253 R254 R255 R256 R257 R258 R259 R260 R261 R262 R263 R264 R265 R291 R301 R384 R385 R386 R387 R427 R482 R483 R484 R485 R486 R487 R488 R489 R537 R538 T36 U31 U32 U33
net class Si53323_2_Q2: Si53323_2_Q2_N Si53323_2_Q2_P
net class Si53323_2_Q1: Si53323_2_Q1_N Si53323_2_Q1_P
net class Si53323_2_CLK1: Si53323_2_CLK1_N Si53323_2_CLK1_P
net class Si53323_1_Q2: Si53323_1_Q2_N Si53323_1_Q2_P
net class Si53323_1_Q1: Si53323_1_Q1_N Si53323_1_Q1_P
net class RefClk_Si53323: RefClk_Si53323_N RefClk_Si53323_P
net class MUX_DIV_OUT: OSC_Out_DIV_N OSC_Out_DIV_P
net class MUX_DIV_OUT_I: Osc_in_Si53323_2_N Osc_in_Si53323_2_P
net class CLM_M_OSC_IN_C: OSC_500Out
net class CLK_SMA1_C: CLK_SMA0_C_N CLK_SMA0_C_P LTC6952_1_C_Out10_N LTC6952_1_C_Out10_P
net class CLK_M_OSC_In: CLK_M_OSC_In
differential pair class Diff_76_to_90_Ram_DQS: DDR4_DQS_0 DDR4_DQS_1 DDR4_DQS_2 DDR4_DQS_3 DDR4_DQS_4 DDR4_DQS_5 DDR4_DQS_6 DDR4_DQS_7 DDR4_DQS_8
net class Single_36_39_50_Adr: DDR4_A0 DDR4_A1 DDR4_A2 DDR4_A3 DDR4_A4 DDR4_A5 DDR4_A6 DDR4_A7 DDR4_A8 DDR4_A9 DDR4_A10 DDR4_A11 DDR4_A12 DDR4_A13 DDR4_ACT_N DDR4_ALERT_N DDR4_BA0 DDR4_BA1 DDR4_BG0 DDR4_CAS DDR4_CKE0 DDR4_CS_B DDR4_DQS_ODT0 DDR4_PARITY DDR4_RAM_RST_N DDR4_RAS DDR4_TEN DDR4_WE
net class Diff_76_86_90: DDR4_DQS_0_N DDR4_DQS_0_P DDR4_DQS_1_N DDR4_DQS_1_P DDR4_DQS_2_N DDR4_DQS_2_P DDR4_DQS_3_N DDR4_DQS_3_P DDR4_DQS_4_N DDR4_DQS_4_P DDR4_DQS_5_N DDR4_DQS_5_P DDR4_DQS_6_N DDR4_DQS_6_P DDR4_DQS_7_N DDR4_DQS_7_P DDR4_DQS_8_N DDR4_DQS_8_P
net class RAM_Clock_Signal: DDR4_CK_N DDR4_CK_P
component class U_Pomiar_pradu_napiecia_5: C309_U_Pomiar_pradu_napiecia_5 R448_U_Pomiar_pradu_napiecia_5 U64_U_Pomiar_pradu_napiecia_5
component class U_Pomiar_pradu_napiecia_6: C309_U_Pomiar_pradu_napiecia_6 R448_U_Pomiar_pradu_napiecia_6 U64_U_Pomiar_pradu_napiecia_6
component class U_Pomiar_pradu_napiecia_PCIe0: C309_U_Pomiar_pradu_napiecia_PCIe0 R448_U_Pomiar_pradu_napiecia_PCIe0 U64_U_Pomiar_pradu_napiecia_PCIe0
component class U_Pomiar_pradu_napiecia_PCIe1: C309_U_Pomiar_pradu_napiecia_PCIe1 R448_U_Pomiar_pradu_napiecia_PCIe1 U64_U_Pomiar_pradu_napiecia_PCIe1
component class U_Pomiar_pradu_napiecia_PCIe2: C309_U_Pomiar_pradu_napiecia_PCIe2 R448_U_Pomiar_pradu_napiecia_PCIe2 U64_U_Pomiar_pradu_napiecia_PCIe2
channel class Pomiar_pradu_napiecia: U_Pomiar_pradu_napiecia_PCIe3 U_Pomiar_pradu_napiecia_PCIe4
net class Single_39_50_D: DDR4_DM0 DDR4_DM1 DDR4_DM2 DDR4_DM3 DDR4_DM4 DDR4_DM5 DDR4_DM6 DDR4_DM7 DDR4_DQ0 DDR4_DQ1 DDR4_DQ2 DDR4_DQ3 DDR4_DQ4 DDR4_DQ5 DDR4_DQ6 DDR4_DQ7 DDR4_DQ8 DDR4_DQ9 DDR4_DQ10 DDR4_DQ11 DDR4_DQ12 DDR4_DQ13 DDR4_DQ14 DDR4_DQ15 DDR4_DQ16 DDR4_DQ17 DDR4_DQ18 DDR4_DQ19 DDR4_DQ20 DDR4_DQ21 DDR4_DQ22 DDR4_DQ23 DDR4_DQ24 DDR4_DQ25 DDR4_DQ26 DDR4_DQ27 DDR4_DQ28 DDR4_DQ29 DDR4_DQ30 DDR4_DQ31 DDR4_DQ32 DDR4_DQ33 DDR4_DQ34 DDR4_DQ35 DDR4_DQ36 DDR4_DQ37 DDR4_DQ38 DDR4_DQ39 DDR4_DQ40 DDR4_DQ41 DDR4_DQ42 DDR4_DQ43 DDR4_DQ44 DDR4_DQ45 DDR4_DQ46 DDR4_DQ47 DDR4_DQ48 DDR4_DQ49 DDR4_DQ50 DDR4_DQ51 DDR4_DQ52 DDR4_DQ53 DDR4_DQ54 DDR4_DQ55 DDR4_DQ56 DDR4_DQ57 DDR4_DQ58 DDR4_DQ59 DDR4_DQ60 DDR4_DQ61 DDR4_DQ62 DDR4_DQ63
component class US+_Interrupts: R515 R522 R523 R530 R531 R546 R547 R548 R549 R550 R551 R552 R553 R554 R555 R556 R557 R607 R618 R659 R660 R661 R662 R663 R664 R688 R735 R736 R744 R765 R766 R767 R817 R818 R819 R820 R821 R822 R823 R824 R847 R848 R849 R850 R851 R852 R853 R854 R855 R856 R857 R858 R859 R860 R861 R862 R863 R864 R865 R866 R867 R868 R869 R870 R871 R872 R873 R874 R875 R876 R877 R878 R879 R880 R881 R882 R883 R884 R885 R886 R921 R922 R923 R924 R925 R926 R927 R928 R929 R930 R931 R932 R933 R934 R935 R936 R937 R938 R939 R940 R941 R942 R943 R944 R945 R946 R947 R948 R949 R950 R951 R952 R953 R954 R955 R956 R957 R958 R959 R960 R961 R962 R963 R964 R965 R966 R967 R968 R969 R970 R971 R972 R973 R974 R975 R976 R977 R978 R979 R980 R981 R982 R983 R984 R985 R986 R987 R988 R989 R990 R991 R992 R993 R994 R995 R996 R997 R998 R999 R1000 SP36 SP37 SP38 SP39 SP40 SP41 SP42 SP43 SP44 SP45 SP46 SP47 SP48 SP49 SP50 SP51 SP52 SP53 SP54 SP55 SP56 SP57 SP58 SP59 SP60 SP61 SP62 SP63 SP64
component class U_Pomiar_pradu_napiecia_PCIe3: C309_U_Pomiar_pradu_napiecia_PCIe3 R448_U_Pomiar_pradu_napiecia_PCIe3 U64_U_Pomiar_pradu_napiecia_PCIe3
component class U_Pomiar_pradu_napiecia_PCIe4: C309_U_Pomiar_pradu_napiecia_PCIe4 R448_U_Pomiar_pradu_napiecia_PCIe4 U64_U_Pomiar_pradu_napiecia_PCIe4
component class PowerDistribition: P7 P8 P9 P10 P11 R229 R230 R455 R456 R457 R458 R459 R460 R461 R462 R463 R464 R465 R466 R467 R468 R593 R594 R595 R596 R597 R598 R835 R836 R837 R838 R839 R840
net class Single_50: Bank223_MGTREF0_N Bank223_MGTREF0_P Bank223_MGTREF1_N Bank223_MGTREF1_P Bank224_MGTREF0_N Bank224_MGTREF0_P Bank224_MGTREF1_N Bank224_MGTREF1_P Bank225_MGTREF0_N Bank225_MGTREF0_P Bank505_MGTRREF0_C_N Bank505_MGTRREF0_C_P Bank505_MGTRREF2_C_N Bank505_MGTRREF2_C_P Bank505_MGTRREF3_C_N Bank505_MGTRREF3_C_P CLK0_EZS_N CLK0_EZS_P CLK_M_OSC_In CLK_SMA0_C_N CLK_SMA0_C_P LTC6952_0_MATCH_Out0_N LTC6952_0_MATCH_Out0_P LTC6952_0_MATCH_Out1_N LTC6952_0_MATCH_Out1_P LTC6952_0_MATCH_Out2_N LTC6952_0_MATCH_Out2_P LTC6952_0_MATCH_Out3_N LTC6952_0_MATCH_Out3_P LTC6952_0_MATCH_Out4_N LTC6952_0_MATCH_Out4_P LTC6952_0_MATCH_Out5_N LTC6952_0_MATCH_Out5_P LTC6952_0_MATCH_Out6_N LTC6952_0_MATCH_Out6_P LTC6952_0_MATCH_Out7_N LTC6952_0_MATCH_Out7_P LTC6952_0_MATCH_Out8_N LTC6952_0_MATCH_Out8_P LTC6952_0_MATCH_Out9_N LTC6952_0_MATCH_Out9_P LTC6952_0_Out0_N LTC6952_0_Out0_P LTC6952_0_Out1_N LTC6952_0_Out1_P LTC6952_0_Out2_N LTC6952_0_Out2_P LTC6952_0_Out3_N LTC6952_0_Out3_P LTC6952_0_Out4_N LTC6952_0_Out4_P LTC6952_0_Out6_N LTC6952_0_Out6_P LTC6952_0_Out10_N LTC6952_0_Out10_P LTC6952_0_REF_N LTC6952_0_REF_P LTC6952_1_C_N LTC6952_1_C_Out10_N LTC6952_1_C_Out10_P LTC6952_1_C_P LTC6952_1_MATCH_Out0_N LTC6952_1_MATCH_Out0_P LTC6952_1_MATCH_Out1_N LTC6952_1_MATCH_Out1_P LTC6952_1_MATCH_Out2_N LTC6952_1_MATCH_Out2_P LTC6952_1_MATCH_Out3_N LTC6952_1_MATCH_Out3_P LTC6952_1_MATCH_Out4_N LTC6952_1_MATCH_Out4_P LTC6952_1_MATCH_Out5_N LTC6952_1_MATCH_Out5_P LTC6952_1_MATCH_Out6_N LTC6952_1_MATCH_Out6_P LTC6952_1_MATCH_Out7_N LTC6952_1_MATCH_Out7_P LTC6952_1_MATCH_Out8_N LTC6952_1_MATCH_Out8_P LTC6952_1_MATCH_Out9_N LTC6952_1_MATCH_Out9_P LTC6952_1_Out0_N LTC6952_1_Out0_P LTC6952_1_Out1_N LTC6952_1_Out1_P LTC6952_1_Out2_N LTC6952_1_Out2_P LTC6952_1_Out4_N LTC6952_1_Out4_P LTC6952_1_Out5_N LTC6952_1_Out5_P LTC6952_1_Out6_N LTC6952_1_Out6_P LTC6952_1_Out7_N LTC6952_1_Out7_P LTC6952_1_Out9_N LTC6952_1_Out9_P LTC6952_1_Out10_N LTC6952_1_Out10_P LTC6952_1_REF_MATCH_N LTC6952_1_REF_MATCH_P LTC6952_1_VCO_N LTC6952_1_VCO_P NetC333_2 NetC334_2 NetC335_2 NetC341_2 NetC588_1 NetC588_2 NetR543_1 NVME_C_RX_1_N NVME_C_RX_1_P NVME_C_RX_O_N NVME_C_RX_O_P NVME_C_TX_1_N NVME_C_TX_1_P NVME_C_TX_O_N NVME_C_TX_O_P NVMe_Rx_0_N NVMe_Rx_0_P NVMe_Rx_1_N NVMe_Rx_1_P NVMe_Tx_0_N NVMe_Tx_0_P NVMe_Tx_1_N NVMe_Tx_1_P OSC_500Out Osc_in_Si53323_2_N Osc_in_Si53323_2_P OSC_Out_DIV_N OSC_Out_DIV_P RefClk_Si53323_N RefClk_Si53323_P RF_SYSREF_TO_FPGA_PCIE0_N RF_SYSREF_TO_FPGA_PCIE0_P RF_SYSREF_TO_FPGA_PCIE1_N RF_SYSREF_TO_FPGA_PCIE1_P RF_SYSREF_TO_FPGA_PCIE2_N RF_SYSREF_TO_FPGA_PCIE2_P RF_SYSREF_TO_FPGA_PCIE3_N RF_SYSREF_TO_FPGA_PCIE3_P RF_SYSREF_TO_FPGA_PCIE4_N RF_SYSREF_TO_FPGA_PCIE4_P SFP0_Rx_FPGA_N SFP0_Rx_FPGA_P SFP0_Tx_FPGA_N SFP0_Tx_FPGA_P SFP1_Rx_FPGA_N SFP1_Rx_FPGA_P SFP1_Tx_FPGA_N SFP1_Tx_FPGA_P SFP2_Rx_FPGA_N SFP2_Rx_FPGA_P SFP2_Tx_FPGA_N SFP2_Tx_FPGA_P SFP3_Rx_FPGA_N SFP3_Rx_FPGA_P SFP3_Tx_FPGA_N SFP3_Tx_FPGA_P SGMI_C_Rx_N SGMI_C_Rx_P SGMI_C_Tx_N SGMI_C_Tx_P SGMI_CLK_Out_N SGMI_CLK_Out_P SGMI_Rx_N SGMI_Rx_P SGMI_Tx_N SGMI_Tx_P Si53323_1_Q1_N Si53323_1_Q1_P Si53323_1_Q2_C_N Si53323_1_Q2_C_P Si53323_1_Q2_LVDS_N Si53323_1_Q2_LVDS_P Si53323_1_Q2_N Si53323_1_Q2_P Si53323_2_CLK1_N Si53323_2_CLK1_P Si53323_2_Q1_N Si53323_2_Q1_P Si53323_2_Q2_C_N Si53323_2_Q2_C_P Si53323_2_Q2_LVDS_N Si53323_2_Q2_LVDS_P Si53323_2_Q2_N Si53323_2_Q2_P SYNC_PCIE0_N SYNC_PCIE0_P SYNC_PCIE1_N SYNC_PCIE1_P SYNC_PCIE2_N SYNC_PCIE2_P SYNC_PCIE3_N SYNC_PCIE3_P SYNC_PCIE4_N SYNC_PCIE4_P TD_A_N TD_A_P TD_B_N TD_B_P TD_C_N TD_C_P TD_D_N TD_D_P WR_LMK_CLK_HF1_N WR_LMK_CLK_HF1_P WR_LMK_CLK_HF2_N WR_LMK_CLK_HF2_P WR_LMK_CLK_IN_N WR_LMK_CLK_IN_P WR_LMK_CLK_RC_HF1_N WR_LMK_CLK_RC_HF1_P WR_LMK_CLK_RC_HF2_N WR_LMK_CLK_RC_HF2_P XO_LMK05028_P
net class Bank505_MGTRREFx_C: Bank505_MGTRREF0_C_N Bank505_MGTRREF0_C_P Bank505_MGTRREF2_C_N Bank505_MGTRREF2_C_P Bank505_MGTRREF3_C_N Bank505_MGTRREF3_C_P NetU2_L25 NetU2_L26
net class Bank225_MGTREFx_C: Bank225_MGTREF0_C_N Bank225_MGTREF0_C_P Bank225_MGTREF1_C_N Bank225_MGTREF1_C_P
net class Bank224_MGTREFx_C: Bank224_MGTREF0_C_N Bank224_MGTREF0_C_P Bank224_MGTREF1_C_N Bank224_MGTREF1_C_P
net class Bank223_MGTREFx_C: Bank223_MGTREF0_C_N Bank223_MGTREF0_C_P Bank223_MGTREF1_C_N Bank223_MGTREF1_C_P
component class Trans_LS_I2C0: R1122_Trans_LS_I2C0 SP34_Trans_LS_I2C0 SP35_Trans_LS_I2C0 U36_Trans_LS_I2C0
differential pair class Diff_100: B223_Rx0 B223_Rx1 B223_Rx2 B223_Rx3 B223_Tx0_to_C B223_Tx0C_to_B B223_Tx1_to_C B223_Tx1C_to_B B223_Tx2_to_C B223_Tx2C_to_B B223_Tx3_to_C B223_Tx3C_to_B B224_Rx0 B224_Rx1 B224_Rx2 B224_Rx3 B224_Tx0_to_C B224_Tx0C_to_B B224_Tx1_to_C B224_Tx1C_to_B B224_Tx2_to_C B224_Tx2C_to_B B224_Tx3_to_C B224_Tx3C_to_B B225_Rx0 B225_Rx1 B225_Rx2 B225_Rx3 B225_Tx0_to_C B225_Tx0C_to_B B225_Tx1_to_C B225_Tx1C_to_B B225_Tx2_to_C B225_Tx2C_to_B B225_Tx3_to_C B225_Tx3C_to_B Bank223_MGTREF0 Bank223_MGTREF0_C Bank223_MGTREF1 Bank223_MGTREF1_C Bank224_MGTREF0 Bank224_MGTREF0_C Bank224_MGTREF1 Bank224_MGTREF1_C Bank225_MGTREF0 Bank225_MGTREF0_C Bank225_MGTREF1 Bank225_MGTREF1_C Bank505_MGTRREF0_C Bank505_MGTRREF2_C Bank505_MGTRREF3_C CLK0_EZS CLK_100 CLK_Fanout_In CLK_GTR_T1 CLK_GTR_T2 CLK_GTR_T3 CLK_Hi_Rail1 CLK_Hi_Rail1_SysRef CLK_Hi_Rail2 CLK_Hi_Rail2_SysRef CLK_M_OSC_In CLK_NVME_Conn CLK_Q223_T1 CLK_Q224_T1 CLK_Q225_T1 CLK_Q226_T1 CLK_SMA0 CLK_SMA0_C CLK_SMA1 CLK_SMA1_C CLK_SMA2 CLK_SMA2_C Data_2_RX_PCIE0 Data_2_RX_PCIE1 Data_2_RX_PCIE2 Data_2_RX_PCIE3 Data_2_TX_PCIE0 Data_2_TX_PCIE1 Data_2_TX_PCIE2 Data_2_TX_PCIE3 Data_3_RX_PCIE0 Data_3_RX_PCIE1 Data_3_RX_PCIE2 Data_3_RX_PCIE3 Data_3_TX_PCIE0 Data_3_TX_PCIE1 Data_3_TX_PCIE2 Data_3_TX_PCIE3 LTC6952_0_MATCH_Out0 LTC6952_0_MATCH_Out1 LTC6952_0_MATCH_Out2 LTC6952_0_MATCH_Out3 LTC6952_0_MATCH_Out4 LTC6952_0_MATCH_Out5 LTC6952_0_MATCH_Out6 LTC6952_0_MATCH_Out7 LTC6952_0_MATCH_Out8 LTC6952_0_MATCH_Out9 LTC6952_0_Out0 LTC6952_0_Out1 LTC6952_0_Out2 LTC6952_0_Out3 LTC6952_0_Out4 LTC6952_0_Out5 LTC6952_0_Out6 LTC6952_0_Out7 LTC6952_0_Out8 LTC6952_0_Out9 LTC6952_0_Out10 LTC6952_0_REF LTC6952_0_REF_MATCH LTC6952_1_C LTC6952_1_C_Out10 LTC6952_1_MATCH_Out0 LTC6952_1_MATCH_Out1 LTC6952_1_MATCH_Out2 LTC6952_1_MATCH_Out3 LTC6952_1_MATCH_Out4 LTC6952_1_MATCH_Out5 LTC6952_1_MATCH_Out6 LTC6952_1_MATCH_Out7 LTC6952_1_MATCH_Out8 LTC6952_1_MATCH_Out9 LTC6952_1_Out0 LTC6952_1_Out1 LTC6952_1_Out2 LTC6952_1_Out3 LTC6952_1_Out4 LTC6952_1_Out5 LTC6952_1_Out6 LTC6952_1_Out7 LTC6952_1_Out8 LTC6952_1_Out9 LTC6952_1_Out10 LTC6952_1_REF LTC6952_1_REF_MATCH LTC6952_1_VCO LTC6952_2_REF LTC6952_2_REF_SMA LTC6952_3_REF LTC6952_3_REF_SMA NVME_C_RX_1 NVME_C_RX_O NVME_C_TX_1 NVME_C_TX_O NVMe_CLK NVMe_Rx_0 NVMe_Rx_1 NVMe_Tx_0 NVMe_Tx_1 Osc_in_Si53323_2 OSC_Out_DIV PCIE0_CLK PCIE0_Sync PCIE0_SysRef PCIE0_SysRef_FPGA PCIE1_CLK PCIE1_Sync PCIE1_SysRef PCIE1_SysRef_FPGA PCIE2_CLK PCIE2_Sync PCIE2_SysRef PCIE2_SysRef_FPGA PCIE3_CLK PCIE3_Sync PCIE3_SysRef PCIE3_SysRef_FPGA PCIE4_CLK PCIE4_Sync PCIE4_SysRef PCIE4_SysRef_FPGA RefClk_Si53323 RF_SYSREF_TO_FPGA_PCIE0 RF_SYSREF_TO_FPGA_PCIE1 RF_SYSREF_TO_FPGA_PCIE2 RF_SYSREF_TO_FPGA_PCIE3 RF_SYSREF_TO_FPGA_PCIE4 SFP0_Rx SFP0_Rx_FPGA SFP0_Tx SFP0_Tx_FPGA SFP1_Rx SFP1_Rx_FPGA SFP1_Tx SFP1_Tx_FPGA SFP2_Rx SFP2_Rx_FPGA SFP2_Tx SFP2_Tx_FPGA SFP3_Rx SFP3_Rx_FPGA SFP3_Tx SFP3_Tx_FPGA SGMI_C_Rx SGMI_C_Tx SGMI_CLK_C_Out SGMI_CLK_Out SGMI_Rx SGMI_Tx Si53323_1_Q1 Si53323_1_Q2 Si53323_1_Q2_C Si53323_1_Q2_LVDS Si53323_2_CLK1 Si53323_2_Q1 Si53323_2_Q2 Si53323_2_Q2_C Si53323_2_Q2_LVDS SYNC_PCIE0 SYNC_PCIE1 SYNC_PCIE2 SYNC_PCIE3 SYNC_PCIE4 SYSREF_PCIE0 SYSREF_PCIE1 SYSREF_PCIE2 SYSREF_PCIE3 SYSREF_PCIE4 TD_A TD_B TD_C TD_D WR_LMK_CLK_HF1 WR_LMK_CLK_HF2 WR_LMK_CLK_IN WR_LMK_CLK_LF WR_LMK_CLK_RC_HF1 WR_LMK_CLK_RC_HF2 WR_LMK_CLK_RC_IN WR_Source_CLK
channel class Translator_I2C: Trans_LS_I2C1 Trans_PS_I2C0 Trans_PS_I2C1
channel class 5V_to_3V3: 5to3V3_1 5to3V3_2 5V_to_3V3_for_FTDI
net class SFP_TX: SFP0_Rx_N SFP0_Tx_N SFP0_Tx_P SFP1_Rx_N SFP1_Tx_N SFP1_Tx_P SFP2_Rx_N SFP2_Tx_N SFP2_Tx_P SFP3_Rx_N SFP3_Tx_N SFP3_Tx_P
net class C_to_Bank225: B225_Rx0_N B225_Rx0_P B225_Rx1_N B225_Rx1_P B225_Rx2_N B225_Rx2_P B225_Rx3_N B225_Rx3_P B225_Tx0C_to_B_N B225_Tx0C_to_B_P B225_Tx1C_to_B_N B225_Tx1C_to_B_P B225_Tx2C_to_B_N B225_Tx2C_to_B_P B225_Tx3C_to_B_N B225_Tx3C_to_B_P
net class C_to_Bank224: B224_Tx0C_to_B_N B224_Tx0C_to_B_P B224_Tx1C_to_B_N B224_Tx1C_to_B_P B224_Tx2C_to_B_N B224_Tx2C_to_B_P B224_Tx3C_to_B_N B224_Tx3C_to_B_P
net class C_to_Bank223: B223_Rx0_N B223_Rx0_P B223_Rx1_N B223_Rx1_P B223_Rx2_N B223_Rx2_P B223_Rx3_N B223_Rx3_P B223_Tx0C_to_B_N B223_Tx0C_to_B_P B223_Tx1C_to_B_N B223_Tx1C_to_B_P B223_Tx2C_to_B_N B223_Tx2C_to_B_P B223_Tx3C_to_B_N B223_Tx3C_to_B_P
component class Trans_PS_I2C0: R1122_Trans_PS_I2C0 SP34_Trans_PS_I2C0 SP35_Trans_PS_I2C0 U36_Trans_PS_I2C0
component class Trans_PS_I2C1: R1122_Trans_PS_I2C1 SP34_Trans_PS_I2C1 SP35_Trans_PS_I2C1 U36_Trans_PS_I2C1
component class Trans_LS_I2C1: R1122_Trans_LS_I2C1 SP34_Trans_LS_I2C1 SP35_Trans_LS_I2C1 U36_Trans_LS_I2C1
component class U_TPS7A88_5V_Dual_3: C572 C573 C574 C575 C576 C577 C578 C579 R436 R437 R438 R439 R440 R441 U61
component class U_LT3042_12V_5V_LNLDO: C580 C581 C582 C583 C584 FB34 R442 R443 R444 R445 U62
component class U_ADP1741_3: C568 C569 C570 C571 FB33 R433 R434 R846 U60
component class 5to3V3_1: C563_5to3V3_1 C564_5to3V3_1 C565_5to3V3_1 C566_5to3V3_1 C567_5to3V3_1 R430_5to3V3_1 R431_5to3V3_1 R432_5to3V3_1 U59_5to3V3_1
component class 5to3V3_2: C563_5to3V3_2 C564_5to3V3_2 C565_5to3V3_2 C566_5to3V3_2 C567_5to3V3_2 R430_5to3V3_2 R431_5to3V3_2 R432_5to3V3_2 U59_5to3V3_2
component class Ram_Power: C219 C220 C221 C222 C223 C224 C225 C226 C227 C228 C229 C230 C231 C232 C233 C234 C235 C236 C237 C238 C239 C240 C241 C242 C243 C244 C245 C246 C247 C248 C249 C250 C251 C252 C253 C254 C255 C256 C257 C258 C259 C260 C261 C262 C263 C264 C265 C266 C782 C783 C784 C785 C786 C787 C788 C789 R165 R166 R167 R168 R169 R170 R171 R172
component class PS_Config: C531 C532 C533 C534 C535 C536 D5 D6 D7 D8 D9 D10 D11 D12 P2 P3 P4 P5 R346 R347 R348 R349 R350 R351 R352 R353 R354 R355 R356 R357 R358 R359 R360 R361 R367 R368 R369 R370 R371 R372 R373 R374 R375 R716 R717 R718 R719 R720 S1 S2 S3 S4 U43 U44 X5 X6
component class IMU: C561 C562 R429 R600 R601 U58
component class GTR: C525 C526 C527 C528 C529 C530 C649 C651 C653 C677 C715 C716 C717 C718 R69 R70 R126
component class "Bank 225": C291 C292 C293 C294 C295 C296 C297 C298 C299 C300 C819 C820
component class "Bank 224": C279 C280 C281 C282 C283 C284 C285 C286 C287 C288 C289 C290 C686 C687 C688 C689
component class "Bank 223": C49 C50 C267 C268 C269 C270 C271 C272 C273 C274 C275 C276 C277 C278 C477 C557
component class U_Power_Ethernet: C550 C551 C552 C553 C554 C555 C654 C655 C656 C657 R391 R392 R393 R394 R396 R397 R399 R632 R633 R634 U49 U50 U51 U68
component class U_Power_ADP1850_Dual_2: C430 C431 C432 C433 C434 C435 C436 C437 C438 C439 C440 C441 C442 C443 C444 C445 C446 C447 C448 C449 C450 C451 C452 C453 C454 C455 C456 C457 C458 C459 C460 C461 C462 C463 C464 C465 C466 C467 C468 C469 C470 C548 C549 C645 C646 C647 C648 C650 C652 L19 L20 R302 R303 R306 R307 R310 R312 R313 R314 R315 R316 R317 R318 R625 R626 R627 R628 R629 R631 R686 R687 T17 T18 T19 T20 U38
component class U_HI_Curr_ADP1850_3: C389 C390 C391 C392 C393 C394 C395 C396 C397 C398 C399 C400 C401 C402 C403 C404 C405 C406 C407 C408 C409 C410 C411 C412 C413 C414 C415 C416 C417 C418 C419 C420 C421 C422 C423 C424 C425 C426 C427 C428 C429 C637 C638 C639 C640 C641 C642 C643 C644 L11 L12 R285 R287 R288 R289 R290 R292 R293 R294 R295 R296 R297 R298 R299 R300 R619 R620 R621 R622 R623 R624 T13 T14 T15 T16 U37
component class "Zasilanie CLK": C59 C60 C61 C62 C63 C64 C67 C70 C71 C72 C73 C74 C75 C76 C77 C78 C79 C80 C81 C82 C83 C84 C85 C86 C87 C88 C89 C90 C91 C92 C93 C94 C95 C96 C97 C98 C99 C100 C101 C102 C103 C104 C105 C106 C107 C108 C109 C110 C124 C125 C126 C127 C141 C142 C143 C144 C145 C146 C147 C148 C149 C150 C151 C152 C153 C154 C155 C156 C157 C158 C159 C160 C161 C162 C163 C164 C165 C166 C167 C168 C169 C170 C171 C172 C173 C174 C175 C176 C177 C178 C179 C180 C181 C182 C183 C184 C185 C186 C187 C188 C189 C190 C191 C192 C193 C194 C195 C196 C197 C198 C199 C200 C201 C202 C203 C204 C205 C206 FB3 FB5 FB6 FB7 FB8 FB9 FB10 FB11 FB12 FB13 FB14 FB15 FB16 FB17 FB18 FB19 FB20 FB21 FB22 FB35 FB36 R738 R739 R740 R741 R742 R743 U16
component class PowerSelector: C4 C5 C6 C7 C8 C9 C10 C11 C12 C13 C14 C15 C16 C17 C18 C19 C20 C21 C22 C23 C24 C25 C26 C27 C28 C29 C30 C31 C32 C33 C34 C35 C312 C313 C314 C766 C767 C768 C769 C770 C771 C772 C773 C774 C775 C776 C777 C778 C779 C780 C781 R11 R12 R13 R15 R17 R18 R19 R20 R21 R23 R25 R26 R27 R28 R29 R30 R630 R677 R678 R679 R680 R681 R682 R683 R684 R685 R1052 R1053 U4 U5 U6 U7 U48
channel class SPI_Muxes: SPI_bridge_Main SPI_bridge_PCIe
channel class I2C_Expander: I2C_Expander4 I2C_Expander5
component class XilinxPower: B1 C627 C628 C629 C630 C631 C632 D28 FB38 FB39 FB40 FB41 FB42 J29 J30 R173 R276 R279 R282 R283 R286 R693 R694 R695 R696
component class "Xilinx Linux": J12 J13 J14 J15 J16 J17 J18 J19 J20 J21 J22 J23 J24 J25 P1 P13 R83 R84 R85 R86 R87 R88 R89 R90 R91 R92 R93 R94 R95 R96 R97 R98 R99 R101 R102 R103 R104 R105 R106 R107 R108 R109 R110 R111 R112 R115 R116 R117 R118 R119 R120 R121 R122 R123 R362 R675 R737 R768 R769 R770 R771 R772 R773 R774 R775 R776 R777 R778 R779 R780 R781 R782 R783 R784 R785 R786 R787 R788 R789 R790 R791 R792 R793 R794 R795 R796 R797 R798 R799 R800 R801 R802 R803 R804 R805 R806 R807 R808 R809 R810 R811 R812 R813 R814 R815 R816 SP19 TP21 TP22 TP23 TP25 TP27 TP29 TP31 TP32 TP34 TP35 TP36 TP38 TP42
component class "WR CLK": C588 C589 C590 C591 C592 C690 C728 C729 C730 C793 FB37 R1 R2 R127 R128 R129 R130 R131 R132 R133 R134 R139 R311 R366 R498 R499 R540 R543 R544 R545 R692 R912 R1083 R1084 R1085 R1086 R1087 R1088 S6 X9
component class U_HI_Curr_ADP1850_1: C345 C346 C347 C348 C349 C350 C351 C352 C353 C356 C357 C358 C359 C360 C361 C362 C363 C364 C365 C366 C367 C368 C369 C370 C371 C372 C373 C374 C375 C376 C377 C378 C379 C380 C381 C382 C383 C384 C385 C386 C387 C388 C633 C634 C635 C636 L9 L10 R268 R271 R272 R273 R275 R277 R278 R280 R610 R611 R612 R613 R614 R615 R616 T5 T6 T7 T8 T9 T10 T11 T12 U34
component class SPI_bridge_Main: R231_SPI_bridge_Main R232_SPI_bridge_Main R233_SPI_bridge_Main R234_SPI_bridge_Main R235_SPI_bridge_Main R236_SPI_bridge_Main R237_SPI_bridge_Main R238_SPI_bridge_Main R239_SPI_bridge_Main R240_SPI_bridge_Main R425_SPI_bridge_Main R426_SPI_bridge_Main R602_SPI_bridge_Main R603_SPI_bridge_Main R604_SPI_bridge_Main R605_SPI_bridge_Main R606_SPI_bridge_Main R887_SPI_bridge_Main R888_SPI_bridge_Main R889_SPI_bridge_Main R890_SPI_bridge_Main R891_SPI_bridge_Main R892_SPI_bridge_Main R893_SPI_bridge_Main R894_SPI_bridge_Main R895_SPI_bridge_Main R896_SPI_bridge_Main R897_SPI_bridge_Main R898_SPI_bridge_Main R899_SPI_bridge_Main SP20_SPI_bridge_Main SP21_SPI_bridge_Main SP22_SPI_bridge_Main SP23_SPI_bridge_Main SP24_SPI_bridge_Main SP25_SPI_bridge_Main SP26_SPI_bridge_Main SP27_SPI_bridge_Main SP28_SPI_bridge_Main SP29_SPI_bridge_Main U24_SPI_bridge_Main U25_SPI_bridge_Main U26_SPI_bridge_Main U27_SPI_bridge_Main U28_SPI_bridge_Main
component class SPI_bridge_PCIe: R231_SPI_bridge_PCIe R232_SPI_bridge_PCIe R233_SPI_bridge_PCIe R234_SPI_bridge_PCIe R235_SPI_bridge_PCIe R236_SPI_bridge_PCIe R237_SPI_bridge_PCIe R238_SPI_bridge_PCIe R239_SPI_bridge_PCIe R240_SPI_bridge_PCIe R425_SPI_bridge_PCIe R426_SPI_bridge_PCIe R602_SPI_bridge_PCIe R603_SPI_bridge_PCIe R604_SPI_bridge_PCIe R605_SPI_bridge_PCIe R606_SPI_bridge_PCIe R887_SPI_bridge_PCIe R888_SPI_bridge_PCIe R889_SPI_bridge_PCIe R890_SPI_bridge_PCIe R891_SPI_bridge_PCIe R892_SPI_bridge_PCIe R893_SPI_bridge_PCIe R894_SPI_bridge_PCIe R895_SPI_bridge_PCIe R896_SPI_bridge_PCIe R897_SPI_bridge_PCIe R898_SPI_bridge_PCIe R899_SPI_bridge_PCIe SP20_SPI_bridge_PCIe SP21_SPI_bridge_PCIe SP22_SPI_bridge_PCIe SP23_SPI_bridge_PCIe SP24_SPI_bridge_PCIe SP25_SPI_bridge_PCIe SP26_SPI_bridge_PCIe SP27_SPI_bridge_PCIe SP28_SPI_bridge_PCIe SP29_SPI_bridge_PCIe U24_SPI_bridge_PCIe U25_SPI_bridge_PCIe U26_SPI_bridge_PCIe U27_SPI_bridge_PCIe U28_SPI_bridge_PCIe
component class SFP3: C215 C216 C217 C218 J35 L7 L8 R155 R156 R157 R158 R161 R162 R163 R164
component class SFP2: C211 C212 C213 C214 J34 L5 L6 R145 R146 R147 R148 R151 R152 R153 R154
component class SFP1: C207 C208 C209 C210 J33 L3 L4 R135 R136 R137 R138 R141 R142 R143 R144
component class Ram: C36 R31 R32 R33 R34 R35 R36 R37 R38 R39 R40 R41 R42 R43 R44 R45 R46 R47 R48 R49 R50 R51 R52 R53 R54 R55 R56 R57 R58 R59 R60 R61 R62 R63 R64 R920 U8 U9 U10 U11
component class Power4HighSpeed: R174 R175 R176 R177 R178 R179 R180 R181 R182 R183 R184 R185 R186 R187 R188 R189 R190 R191 R192 R193 R194 R195 R196 R197 R198 R199 R200 R201 R202 R203 R204 R205 R206 R207 R208 R209 R210 R211 R213 R215 R217 R219 R221 R222 R228 U17 U20 U21 U22 U23
component class I2C_Expander_SFP: C311_I2C_Expander_SFP U35_I2C_Expander_SFP
component class Ext_GPIO_Bank1: R516 R517 R518 R519 R520 R521 R524 R525 R526 R527 R528 R529 R697 R698 R699 R700 R701 R702
component class HiCurrent: C331 C332 R14 R16 R22 R24 R266 R267 R269 R304 R388 R389 R390 R561 R562 R563 R564 R565 R566 R567 R568 R569 R570 R571 R572 R573 R574 R575 R576 R577 R578 R579 R580 R581 R582 R583 R584 R585 R586 R587 R588 R589 R590 R591 R592 S5 U18
component class PCIE4: D1_PCIE4 F1_PCIE4 J1_PCIE4 MP1_PCIE4 MP2_PCIE4 MP3_PCIE4 MP4_PCIE4
component class PCIE3: D1_PCIE3 F1_PCIE3 J1_PCIE3 MP1_PCIE3 MP2_PCIE3 MP3_PCIE3 MP4_PCIE3
component class PCIE2: D1_PCIE2 F1_PCIE2 J1_PCIE2 MP1_PCIE2 MP2_PCIE2 MP3_PCIE2 MP4_PCIE2
component class PCIE1: D1_PCIE1 F1_PCIE1 J1_PCIE1 MP1_PCIE1 MP2_PCIE1 MP3_PCIE1 MP4_PCIE1
component class PCIE0: D1_PCIE0 F1_PCIE0 J1_PCIE0 MP1_PCIE0 MP2_PCIE0 MP3_PCIE0 MP4_PCIE0
component class LTC6952_1: C41 C51 C52 C118 C119 C796 C797 C798 C799 C800 C801 C802 C805 C806 C807 C808 C811 C812 C813 C814 C817 C818 J4 J5 J6 J7 R270 R534 R535 R536 R1077 R1080 R1091 R1092 R1093 R1094 R1097 R1098 R1100 R1101 R1103 R1104 R1105 R1106 R1109 R1110 U13
channel class PCIe: PCIE0 PCIE1 PCIE2 PCIE3 PCIE4
channel class I2C_Bridge: I2C_Bridge_PCIE I2C_Bridge_SFP
component class "Bank 226": C42 C55 C56 C57 C58 C65 C66 C68 C69 C111 C112 C113 C114 C115 C116 C117 R703 R704 R705 R706 R707 R708 R829 R830 R831 R832 R833 R834 R841 R842 R843 R844 U1
component class SFP0: C37 C38 C39 C40 J32 L1 L2 R65 R66 R67 R68 R71 R72 R73 R74
component class I2C_Bridge_SFP: C303_I2C_Bridge_SFP PCIe_I2C_BR_RST R3_I2C_Bridge_SFP R4_I2C_Bridge_SFP R5_I2C_Bridge_SFP R6_I2C_Bridge_SFP R7_I2C_Bridge_SFP R8_I2C_Bridge_SFP R9_I2C_Bridge_SFP R10_I2C_Bridge_SFP R223_I2C_Bridge_SFP R224_I2C_Bridge_SFP R225_I2C_Bridge_SFP R226_I2C_Bridge_SFP R227_I2C_Bridge_SFP R558_I2C_Bridge_SFP R559_I2C_Bridge_SFP R560_I2C_Bridge_SFP SP1_I2C_Bridge_SFP SP2_I2C_Bridge_PCIE SP3_I2C_Bridge_SFP SP4_I2C_Bridge_SFP SP5_I2C_Bridge_SFP SP6_I2C_Bridge_SFP SP7_I2C_Bridge_SFP SP8_I2C_Bridge_SFP SP9_I2C_Bridge_SFP SP10_I2C_Bridge_SFP SP11_I2C_Bridge_SFP SP12_I2C_Bridge_SFP SP13_I2C_Bridge_SFP SP14_I2C_Bridge_SFP SP15_I2C_Bridge_SFP SP16_I2C_Bridge_SFP SP17_I2C_Bridge_SFP SP18_I2C_Bridge_SFP U3_I2C_Bridge_SFP
component class I2C_Bridge_PCIE: C303_I2C_Bridge_PCIE R3_I2C_Bridge_PCIE R4_I2C_Bridge_PCIE R5_I2C_Bridge_PCIE R6_I2C_Bridge_PCIE R7_I2C_Bridge_PCIE R8_I2C_Bridge_PCIE R9_I2C_Bridge_PCIE R10_I2C_Bridge_PCIE R223_I2C_Bridge_PCIE R224_I2C_Bridge_PCIE R225_I2C_Bridge_PCIE R226_I2C_Bridge_PCIE R227_I2C_Bridge_PCIE R558_I2C_Bridge_PCIE R559_I2C_Bridge_PCIE R560_I2C_Bridge_PCIE SP1_I2C_Bridge_PCIE SP2_I2C_Bridge_PCIE SP3_I2C_Bridge_PCIE SP4_I2C_Bridge_PCIE SP5_I2C_Bridge_PCIE SP6_I2C_Bridge_PCIE SP7_I2C_Bridge_PCIE SP8_I2C_Bridge_PCIE SP9_I2C_Bridge_PCIE SP10_I2C_Bridge_PCIE SP11_I2C_Bridge_PCIE SP12_I2C_Bridge_PCIE SP13_I2C_Bridge_PCIE SP14_I2C_Bridge_PCIE SP15_I2C_Bridge_PCIE SP16_I2C_Bridge_PCIE SP17_I2C_Bridge_PCIE SP18_I2C_Bridge_PCIE U3_I2C_Bridge_PCIE
differential pair SFP3_Tx_FPGA: +SFP3_Tx_FPGA_P -SFP3_Tx_FPGA_N
differential pair SFP3_Rx_FPGA: +SFP3_Rx_FPGA_P -SFP3_Rx_FPGA_N
differential pair SFP2_Tx_FPGA: +SFP2_Tx_FPGA_P -SFP2_Tx_FPGA_N
differential pair SFP2_Rx_FPGA: +SFP2_Rx_FPGA_P -SFP2_Rx_FPGA_N
differential pair SFP1_Tx_FPGA: +SFP1_Tx_FPGA_P -SFP1_Tx_FPGA_N
differential pair SFP1_Rx_FPGA: +SFP1_Rx_FPGA_P -SFP1_Rx_FPGA_N
differential pair SFP0_Tx_FPGA: +SFP0_Tx_FPGA_P -SFP0_Tx_FPGA_N
differential pair SFP0_Rx_FPGA: +SFP0_Rx_FPGA_P -SFP0_Rx_FPGA_N
differential pair OSC_Out_DIV: +OSC_Out_DIV_P -OSC_Out_DIV_N
differential pair FTDI_D: +FTDI_D_P -FTDI_D_N
differential pair LTC6952_1_Out0: +LTC6952_1_Out0_P -LTC6952_1_Out0_N
differential pair LTC6952_0_Out4: +LTC6952_0_Out4_P -LTC6952_0_Out4_N
differential pair LTC6952_0_Out3: +LTC6952_0_Out3_P -LTC6952_0_Out3_N
differential pair LTC6952_1_MATCH_Out9: +LTC6952_1_MATCH_Out9_P -LTC6952_1_MATCH_Out9_N
differential pair LTC6952_1_MATCH_Out8: +LTC6952_1_MATCH_Out8_P -LTC6952_1_MATCH_Out8_N
differential pair LTC6952_1_MATCH_Out7: +LTC6952_1_MATCH_Out7_P -LTC6952_1_MATCH_Out7_N
differential pair LTC6952_1_MATCH_Out6: +LTC6952_1_MATCH_Out6_P -LTC6952_1_MATCH_Out6_N
differential pair LTC6952_1_MATCH_Out5: +LTC6952_1_MATCH_Out5_P -LTC6952_1_MATCH_Out5_N
differential pair LTC6952_1_MATCH_Out4: +LTC6952_1_MATCH_Out4_P -LTC6952_1_MATCH_Out4_N
differential pair LTC6952_1_MATCH_Out3: +LTC6952_1_MATCH_Out3_P -LTC6952_1_MATCH_Out3_N
differential pair LTC6952_1_MATCH_Out2: +LTC6952_1_MATCH_Out2_P -LTC6952_1_MATCH_Out2_N
differential pair LTC6952_1_MATCH_Out1: +LTC6952_1_MATCH_Out1_P -LTC6952_1_MATCH_Out1_N
differential pair LTC6952_1_MATCH_Out0: +LTC6952_1_MATCH_Out0_P -LTC6952_1_MATCH_Out0_N
differential pair LTC6952_0_MATCH_Out9: +LTC6952_0_MATCH_Out9_P -LTC6952_0_MATCH_Out9_N
differential pair LTC6952_0_MATCH_Out8: +LTC6952_0_MATCH_Out8_P -LTC6952_0_MATCH_Out8_N
differential pair LTC6952_0_MATCH_Out7: +LTC6952_0_MATCH_Out7_P -LTC6952_0_MATCH_Out7_N
differential pair LTC6952_0_MATCH_Out6: +LTC6952_0_MATCH_Out6_P -LTC6952_0_MATCH_Out6_N
differential pair LTC6952_0_MATCH_Out5: +LTC6952_0_MATCH_Out5_P -LTC6952_0_MATCH_Out5_N
differential pair LTC6952_0_MATCH_Out4: +LTC6952_0_MATCH_Out3_P -LTC6952_0_MATCH_Out3_N
differential pair LTC6952_0_MATCH_Out3: +LTC6952_0_MATCH_Out4_P -LTC6952_0_MATCH_Out4_N
differential pair LTC6952_0_MATCH_Out2: +LTC6952_0_MATCH_Out2_P -LTC6952_0_MATCH_Out2_N
differential pair LTC6952_0_MATCH_Out1: +LTC6952_0_MATCH_Out1_P -LTC6952_0_MATCH_Out1_N
differential pair LTC6952_0_MATCH_Out0: +LTC6952_0_MATCH_Out0_P -LTC6952_0_MATCH_Out0_N
differential pair SYNC_PCIE4: +SYNC_PCIE4_P -SYNC_PCIE4_N
differential pair SYNC_PCIE3: +SYNC_PCIE3_P -SYNC_PCIE3_N
differential pair SYNC_PCIE2: +SYNC_PCIE2_P -SYNC_PCIE2_N
differential pair SYNC_PCIE1: +SYNC_PCIE1_P -SYNC_PCIE1_N
differential pair SYNC_PCIE0: +SYNC_PCIE0_P -SYNC_PCIE0_N
differential pair RF_SYSREF_TO_FPGA_PCIE4: +RF_SYSREF_TO_FPGA_PCIE4_P -RF_SYSREF_TO_FPGA_PCIE4_N
differential pair RF_SYSREF_TO_FPGA_PCIE3: +RF_SYSREF_TO_FPGA_PCIE3_P -RF_SYSREF_TO_FPGA_PCIE3_N
differential pair RF_SYSREF_TO_FPGA_PCIE2: +RF_SYSREF_TO_FPGA_PCIE2_P -RF_SYSREF_TO_FPGA_PCIE2_N
differential pair RF_SYSREF_TO_FPGA_PCIE1: +RF_SYSREF_TO_FPGA_PCIE1_P -RF_SYSREF_TO_FPGA_PCIE1_N
differential pair RF_SYSREF_TO_FPGA_PCIE0: +RF_SYSREF_TO_FPGA_PCIE0_P -RF_SYSREF_TO_FPGA_PCIE0_N
differential pair CLK0_EZS: +CLK0_EZS_P -CLK0_EZS_N
differential pair Si53323_2_Q2_C: +Si53323_2_Q2_C_P -Si53323_2_Q2_C_N
differential pair Si53323_1_Q2_C: +Si53323_1_Q2_C_P -Si53323_1_Q2_C_N
differential pair WR_LMK_CLK_LF: +WR_LMK_CLK_LF_P -WR_LMK_CLK_LF_N
differential pair WR_LMK_CLK_RC_HF2: +WR_LMK_CLK_RC_HF2_P -WR_LMK_CLK_RC_HF2_N
differential pair Bank223_MGTREF0: +Bank223_MGTREF0_P -Bank223_MGTREF0_N
differential pair WR_LMK_CLK_RC_HF1: +WR_LMK_CLK_RC_HF1_P -WR_LMK_CLK_RC_HF1_N
differential pair SGMI_CLK_Out: +SGMI_CLK_Out_P -SGMI_CLK_Out_N
differential pair LTC6952_1_REF_MATCH: +LTC6952_1_REF_MATCH_P -LTC6952_1_REF_MATCH_N
differential pair Bank225_MGTREF0: +Bank225_MGTREF0_P -Bank225_MGTREF0_N
differential pair Bank224_MGTREF1: +Bank224_MGTREF1_P -Bank224_MGTREF1_N
differential pair Bank224_MGTREF0: +Bank224_MGTREF0_P -Bank224_MGTREF0_N
differential pair Bank223_MGTREF1: +Bank223_MGTREF1_P -Bank223_MGTREF1_N
differential pair B225_Tx3_to_C: +B225_Tx3_to_C_P -B225_Tx3_to_C_N
differential pair B225_Tx2_to_C: +B225_Tx2_to_C_P -B225_Tx2_to_C_N
differential pair B225_Tx1_to_C: +B225_Tx1_to_C_P -B225_Tx1_to_C_N
differential pair B225_Tx0_to_C: +B225_Tx0_to_C_P -B225_Tx0_to_C_N
differential pair B225_Rx3: +B225_Rx3_P -B225_Rx3_N
differential pair B225_Rx2: +B225_Rx2_P -B225_Rx2_N
differential pair B225_Rx1: +B225_Rx1_P -B225_Rx1_N
differential pair B225_Rx0: +B225_Rx0_P -B225_Rx0_N
differential pair B224_Tx3_to_C: +B224_Tx3_to_C_P -B224_Tx3_to_C_N
differential pair B224_Tx2_to_C: +B224_Tx2_to_C_P -B224_Tx2_to_C_N
differential pair B224_Tx1_to_C: +B224_Tx1_to_C_P -B224_Tx1_to_C_N
differential pair B224_Tx0_to_C: +B224_Tx0_to_C_P -B224_Tx0_to_C_N
differential pair B224_Rx3: +B224_Rx3_P -B224_Rx3_N
differential pair B224_Rx2: +B224_Rx2_P -B224_Rx2_N
differential pair B224_Rx1: +B224_Rx1_P -B224_Rx1_N
differential pair B224_Rx0: +B224_Rx0_P -B224_Rx0_N
differential pair B223_Tx3_to_C: +B223_Tx3_to_C_P -B223_Tx3_to_C_N
differential pair B223_Tx2_to_C: +B223_Tx2_to_C_P -B223_Tx2_to_C_N
differential pair B223_Tx1_to_C: +B223_Tx1_to_C_P -B223_Tx1_to_C_N
differential pair B223_Tx0_to_C: +B223_Tx0_to_C_P -B223_Tx0_to_C_N
differential pair B223_Rx3: +B223_Rx3_P -B223_Rx3_N
differential pair B223_Rx2: +B223_Rx2_P -B223_Rx2_N
differential pair B223_Rx1: +B223_Rx1_P -B223_Rx1_N
differential pair B223_Rx0: +B223_Rx0_P -B223_Rx0_N
differential pair NVME_C_RX_1: +NVME_C_RX_1_P -NVME_C_RX_1_N
differential pair LTC6952_1_VCO: +LTC6952_1_VCO_P -LTC6952_1_VCO_N
differential pair LTC6952_1_Out10: +LTC6952_1_Out10_P -LTC6952_1_Out10_N
differential pair LTC6952_1_Out9: +LTC6952_1_Out9_P -LTC6952_1_Out9_N
differential pair LTC6952_1_Out7: +LTC6952_1_Out7_P -LTC6952_1_Out7_N
differential pair LTC6952_1_Out6: +LTC6952_1_Out6_P -LTC6952_1_Out6_N
differential pair LTC6952_1_Out5: +LTC6952_1_Out5_P -LTC6952_1_Out5_N
differential pair LTC6952_1_Out4: +LTC6952_1_Out4_P -LTC6952_1_Out4_N
differential pair LTC6952_1_Out2: +LTC6952_1_Out2_P -LTC6952_1_Out2_N
differential pair LTC6952_1_Out1: +LTC6952_1_Out1_P -LTC6952_1_Out1_N
differential pair LTC6952_1_C: +LTC6952_1_C_P -LTC6952_1_C_N
differential pair LTC6952_1_C_Out10: +LTC6952_1_C_Out10_P -LTC6952_1_C_Out10_N
differential pair LTC6952_0_REF: +LTC6952_0_REF_P -LTC6952_0_REF_N
differential pair LTC6952_0_Out10: +LTC6952_0_Out10_P -LTC6952_0_Out10_N
differential pair LTC6952_0_Out6: +LTC6952_0_Out6_P -LTC6952_0_Out6_N
differential pair LTC6952_0_Out2: +LTC6952_0_Out2_P -LTC6952_0_Out2_N
differential pair LTC6952_0_Out1: +LTC6952_0_Out1_P -LTC6952_0_Out1_N
differential pair LTC6952_0_Out0: +LTC6952_0_Out0_P -LTC6952_0_Out0_N
differential pair USB_TX: +USB_TX_P -USB_TX_N
differential pair USB_TX_C: +USB_TX_C_P -USB_TX_C_N
differential pair USB_RX: +USB_RX_P -USB_RX_N
differential pair USB_RX_C: +USB_RX_C_P -USB_RX_C_N
differential pair USB_D: +USB_D_P -USB_D_N
differential pair TD_D: +TD_D_P -TD_D_N
differential pair TD_C: +TD_C_P -TD_C_N
differential pair TD_B: +TD_B_P -TD_B_N
differential pair TD_A: +TD_A_P -TD_A_N
differential pair SGMI_Tx: +SGMI_Tx_P -SGMI_Tx_N
differential pair SGMI_Rx: +SGMI_Rx_P -SGMI_Rx_N
differential pair SGMI_C_Tx: +SGMI_C_Tx_P -SGMI_C_Tx_N
differential pair SGMI_C_Rx: +SGMI_C_Rx_P -SGMI_C_Rx_N
differential pair NVMe_Tx_1: +NVMe_Tx_1_P -NVMe_Tx_1_N
differential pair NVMe_Tx_0: +NVMe_Tx_0_P -NVMe_Tx_0_N
differential pair NVMe_Rx_1: +NVMe_Rx_1_P -NVMe_Rx_1_N
differential pair NVMe_Rx_0: +NVMe_Rx_0_P -NVMe_Rx_0_N
differential pair DDR4_DQS_8: +DDR4_DQS_8_P -DDR4_DQS_8_N
differential pair DDR4_DQS_4: +DDR4_DQS_4_P -DDR4_DQS_4_N
differential pair NVME_C_TX_O: +NVME_C_TX_O_P -NVME_C_TX_O_N
differential pair NVME_C_TX_1: +NVME_C_TX_1_P -NVME_C_TX_1_N
differential pair NVME_C_RX_O: +NVME_C_RX_O_P -NVME_C_RX_O_N
differential pair WR_LMK_CLK_IN: +WR_LMK_CLK_IN_P -WR_LMK_CLK_IN_N
differential pair WR_LMK_CLK_HF2: +WR_LMK_CLK_HF2_P -WR_LMK_CLK_HF2_N
differential pair WR_LMK_CLK_HF1: +WR_LMK_CLK_HF1_P -WR_LMK_CLK_HF1_N
differential pair Si53323_2_Q2_LVDS: +Si53323_2_Q2_LVDS_P -Si53323_2_Q2_LVDS_N
differential pair Si53323_1_Q2_LVDS: +Si53323_1_Q2_LVDS_P -Si53323_1_Q2_LVDS_N
differential pair Si53323_2_CLK1: +Si53323_2_CLK1_P -Si53323_2_CLK1_N
differential pair Osc_in_Si53323_2: +Osc_in_Si53323_2_P -Osc_in_Si53323_2_N
differential pair CLK_SMA0_C: +CLK_SMA0_C_P -CLK_SMA0_C_N
differential pair DDR4_DQS_7: +DDR4_DQS_7_P -DDR4_DQS_7_N
differential pair DDR4_DQS_6: +DDR4_DQS_6_P -DDR4_DQS_6_N
differential pair DDR4_DQS_5: +DDR4_DQS_5_P -DDR4_DQS_5_N
differential pair DDR4_DQS_3: +DDR4_DQS_3_P -DDR4_DQS_3_N
differential pair DDR4_DQS_2: +DDR4_DQS_2_P -DDR4_DQS_2_N
differential pair DDR4_DQS_1: +DDR4_DQS_1_P -DDR4_DQS_1_N
differential pair DDR4_DQS_0: +DDR4_DQS_0_P -DDR4_DQS_0_N
differential pair DDR4_CK: +DDR4_CK_P -DDR4_CK_N
differential pair Si53323_2_Q2: +Si53323_2_Q2_P -Si53323_2_Q2_N
differential pair Si53323_2_Q1: +Si53323_2_Q1_P -Si53323_2_Q1_N
differential pair Si53323_1_Q2: +Si53323_1_Q2_P -Si53323_1_Q2_N
differential pair Si53323_1_Q1: +Si53323_1_Q1_P -Si53323_1_Q1_N
differential pair RefClk_Si53323: +RefClk_Si53323_P -RefClk_Si53323_N
differential pair Bank505_MGTRREF3_C: +Bank505_MGTRREF3_C_P -Bank505_MGTRREF3_C_N
differential pair Bank505_MGTRREF2_C: +Bank505_MGTRREF2_C_P -Bank505_MGTRREF2_C_N
differential pair Bank505_MGTRREF0_C: +Bank505_MGTRREF0_C_P -Bank505_MGTRREF0_C_N
differential pair Bank225_MGTREF1_C: +Bank225_MGTREF1_C_P -Bank225_MGTREF1_C_N
differential pair Bank225_MGTREF0_C: +Bank225_MGTREF0_C_P -Bank225_MGTREF0_C_N
differential pair Bank224_MGTREF1_C: +Bank224_MGTREF1_C_P -Bank224_MGTREF1_C_N
differential pair Bank224_MGTREF0_C: +Bank224_MGTREF0_C_P -Bank224_MGTREF0_C_N
differential pair Bank223_MGTREF1_C: +Bank223_MGTREF1_C_P -Bank223_MGTREF1_C_N
differential pair Bank223_MGTREF0_C: +Bank223_MGTREF0_C_P -Bank223_MGTREF0_C_N
differential pair SFP3_Tx: +SFP3_Tx_P -SFP3_Tx_N
differential pair SFP3_Rx: +SFP3_Rx_P -SFP3_Rx_N
differential pair SFP2_Tx: +SFP2_Tx_P -SFP2_Tx_N
differential pair SFP2_Rx: +SFP2_Rx_P -SFP2_Rx_N
differential pair SFP1_Tx: +SFP1_Tx_P -SFP1_Tx_N
differential pair SFP1_Rx: +SFP1_Rx_P -SFP1_Rx_N
differential pair SFP0_Tx: +SFP0_Tx_P -SFP0_Tx_N
differential pair SFP0_Rx: +SFP0_Rx_P -SFP0_Rx_N
differential pair B225_Tx3C_to_B: +B225_Tx3C_to_B_P -B225_Tx3C_to_B_N
differential pair B225_Tx2C_to_B: +B225_Tx2C_to_B_P -B225_Tx2C_to_B_N
differential pair B225_Tx1C_to_B: +B225_Tx1C_to_B_P -B225_Tx1C_to_B_N
differential pair B225_Tx0C_to_B: +B225_Tx0C_to_B_P -B225_Tx0C_to_B_N
differential pair B224_Tx3C_to_B: +B224_Tx3C_to_B_P -B224_Tx3C_to_B_N
differential pair B224_Tx2C_to_B: +B224_Tx2C_to_B_P -B224_Tx2C_to_B_N
differential pair B224_Tx1C_to_B: +B224_Tx1C_to_B_P -B224_Tx1C_to_B_N
differential pair B224_Tx0C_to_B: +B224_Tx0C_to_B_P -B224_Tx0C_to_B_N
differential pair B223_Tx3C_to_B: +B223_Tx3C_to_B_P -B223_Tx3C_to_B_N
differential pair B223_Tx2C_to_B: +B223_Tx2C_to_B_P -B223_Tx2C_to_B_N
differential pair B223_Tx1C_to_B: +B223_Tx1C_to_B_P -B223_Tx1C_to_B_N
differential pair B223_Tx0C_to_B: +B223_Tx0C_to_B_P -B223_Tx0C_to_B_N

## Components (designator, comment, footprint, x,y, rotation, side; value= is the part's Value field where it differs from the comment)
B1 "TS920E-FL27E" Battery 248.648,324.51 r270 top
BT1 "79523141" 79523141 233.566,163.335 r0 bottom
C1 "100nF" "CAP 0402/1005 KK" 95.898,253.357 r90 top
C2 "100nF" "CAP 0402/1005 KK" 103.325,274.294 r90 top
C3 "100nF" "CAP 0402/1005 KK" 108.677,206.318 r180 top
C4 "22uF" "CAP 1210/3225 - 1MM" 39.648,164.772 r180 top
C5 "22uF" "CAP 1210/3225 - 1MM" 39.648,168.226 r180 top
C6 "22uF" "CAP 1210/3225 - 1MM" 39.648,175.135 r180 top
C7 "22uF" "CAP 1210/3225 - 1MM" 39.648,171.68 r180 top
C8 "100nF" "CAP 0402/1005 KK" 42.89,159.407 r90 top
C9 "100nF" "CAP 0402/1005 KK" 40.046,159.407 r90 top
C10 "100nF" "CAP 0402/1005 KK" 40.975,159.407 r90 top
C11 "100nF" "CAP 0402/1005 KK" 41.91,159.407 r90 top
C12 "22uF" "CAP 1210/3225 - 1MM" 39.567,178.794 r180 top
C13 "22uF" "CAP 1210/3225 - 1MM" 39.567,185.684 r180 top
C14 "22uF" "CAP 1210/3225 - 1MM" 39.567,189.129 r180 top
C15 "22uF" "CAP 1210/3225 - 1MM" 39.567,182.239 r180 top
C16 "100nF" "CAP 0402/1005 KK" 38.398,192.465 r270 top
C17 "100nF" "CAP 0402/1005 KK" 41.232,192.465 r270 top
C18 "100nF" "CAP 0402/1005 KK" 40.234,192.465 r270 top
C19 "100nF" "CAP 0402/1005 KK" 39.328,192.465 r270 top
C20 "10uF" "CAP 0805/2012 RF" 55.719,164.138 r180 top
C21 "10uF" "CAP 0805/2012 RF" 55.746,169.941 r180 top
C22 "10uF" "CAP 0805/2012 RF" 55.746,168.043 r180 top
C23 "10uF" "CAP 0805/2012 RF" 55.746,175.635 r180 top
C24 "4.7uF" "CAP 0805/2012 RF" 55.746,171.839 r180 top
C25 "4.7uF" "CAP 0805/2012 RF" 55.746,173.737 r180 top
C26 "4.7uF" "CAP 0805/2012 RF" 55.746,177.532 r180 top
C27 "4.7uF" "CAP 0805/2012 RF" 55.746,166.145 r180 top
C28 "10uF" "CAP 0805/2012 RF" 55.758,187.161 r180 top
C29 "10uF" "CAP 0805/2012 RF" 55.758,185.263 r180 top
C30 "10uF" "CAP 0805/2012 RF" 55.758,181.467 r180 top
C31 "10uF" "CAP 0805/2012 RF" 55.758,179.569 r180 top
C32 "4.7uF" "CAP 0805/2012 RF" 55.758,183.365 r180 top
C33 "4.7uF" "CAP 0805/2012 RF" 55.758,189.059 r180 top
C34 "4.7uF" "CAP 0805/2012 RF" 55.758,190.956 r180 top
C35 "4.7uF" "CAP 0805/2012 RF" 55.784,192.899 r180 top
C36 "10nF" "CAP 0402/1005 KK" 155.956,331.965 r180 top
C37 "100nF" "CAP 0402/1005 KK" 78.423,285.399 r180 top
C38 "22uF" "CAP 1210/3225 - 1MM" 78.423,287.647 r0 top
C39 "100nF" "CAP 0402/1005 KK" 78.553,281.311 r180 top
C40 "22uF" "CAP 1210/3225 - 1MM" 78.564,279.047 r0 top
C41 "100nF" "CAP 0402/1005 KK" 163.525,281.724 r90 top
C42 "10nF" "CAP 0402/1005 KK" 71.12,286.084 r90 bottom
C43 "1uF" "CAP 0402/1005 KK" 100.651,335.064 r0 bottom
C44 "1uF" "CAP 0402/1005 KK" 100.631,334.061 r0 bottom
C45 "5.6nF" "CAP 0402/1005 KK" 98.18,341.655 r0 top
C46 "200pF" "CAP 0402/1005 KK" 98.18,340.652 r0 top
C47 "1uF" "CAP 0402/1005 KK" 104.327,325.921 r180 bottom
C48 "1uF" "CAP 0402/1005 KK" 104.327,326.935 r180 bottom
C49 "100nF" "CAP 0402/1005 KK" 187.558,285.664 r90 top
C50 "100nF" "CAP 0402/1005 KK" 190.098,285.639 r90 top
C51 "1uF" "CAP 0402/1005 KK" 181.403,262.445 r0 bottom
C52 "1uF" "CAP 0402/1005 KK" 181.403,263.449 r0 bottom
C53 "100nF" "CAP 0402/1005 KK" 56.672,390.418 r270 top
C54 "100nF" "CAP 0402/1005 KK" 167.137,353.56 r180 bottom
C55 "10nF" "CAP 0402/1005 KK" 73.927,286.084 r270 bottom
C56 "10nF" "CAP 0402/1005 KK" 159.115,288.303 r90 bottom
C57 "10nF" "CAP 0402/1005 KK" 156.308,288.303 r270 bottom
C58 "10nF" "CAP 0402/1005 KK" 72.634,312.458 r90 bottom
C59 "0.1µF" "CAP 0201/0603 KK" 103.537,337.579 r180 bottom
C60 "0.1µF" "CAP 0201/0603 KK" 103.537,338.336 r180 bottom
C61 "0.1µF" "CAP 0201/0603 KK" 100.771,336.482 r180 bottom
C62 "10uF" "CAP 0402/1005 KK" 100.846,338.988 r180 bottom
C63 "100nF" "CAP 0402/1005 KK" 149.657,219.834 r0 top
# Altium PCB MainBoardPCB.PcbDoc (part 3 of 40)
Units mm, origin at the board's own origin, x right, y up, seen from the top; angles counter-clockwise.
Board outline 258.95 x 308.86 mm, 16 copper layers (L1, L2 (GND), L3 (Sign), L4 (GND), L5 (Sign), L6 (PWR/GND), L7(12V+Other), L8 (Plane_GND), L9 (PWR/GND), L10 (3V3+Other), L11 (PWR/GND), L12 (Sign), L13 (GND), L14 (Sign), L15 (GND), L16), stack 2.503 mm thick; 2578 components, 1867 nets, 8817 pads, 8021 vias.
Unrouted connection lines stored in the file: 25.

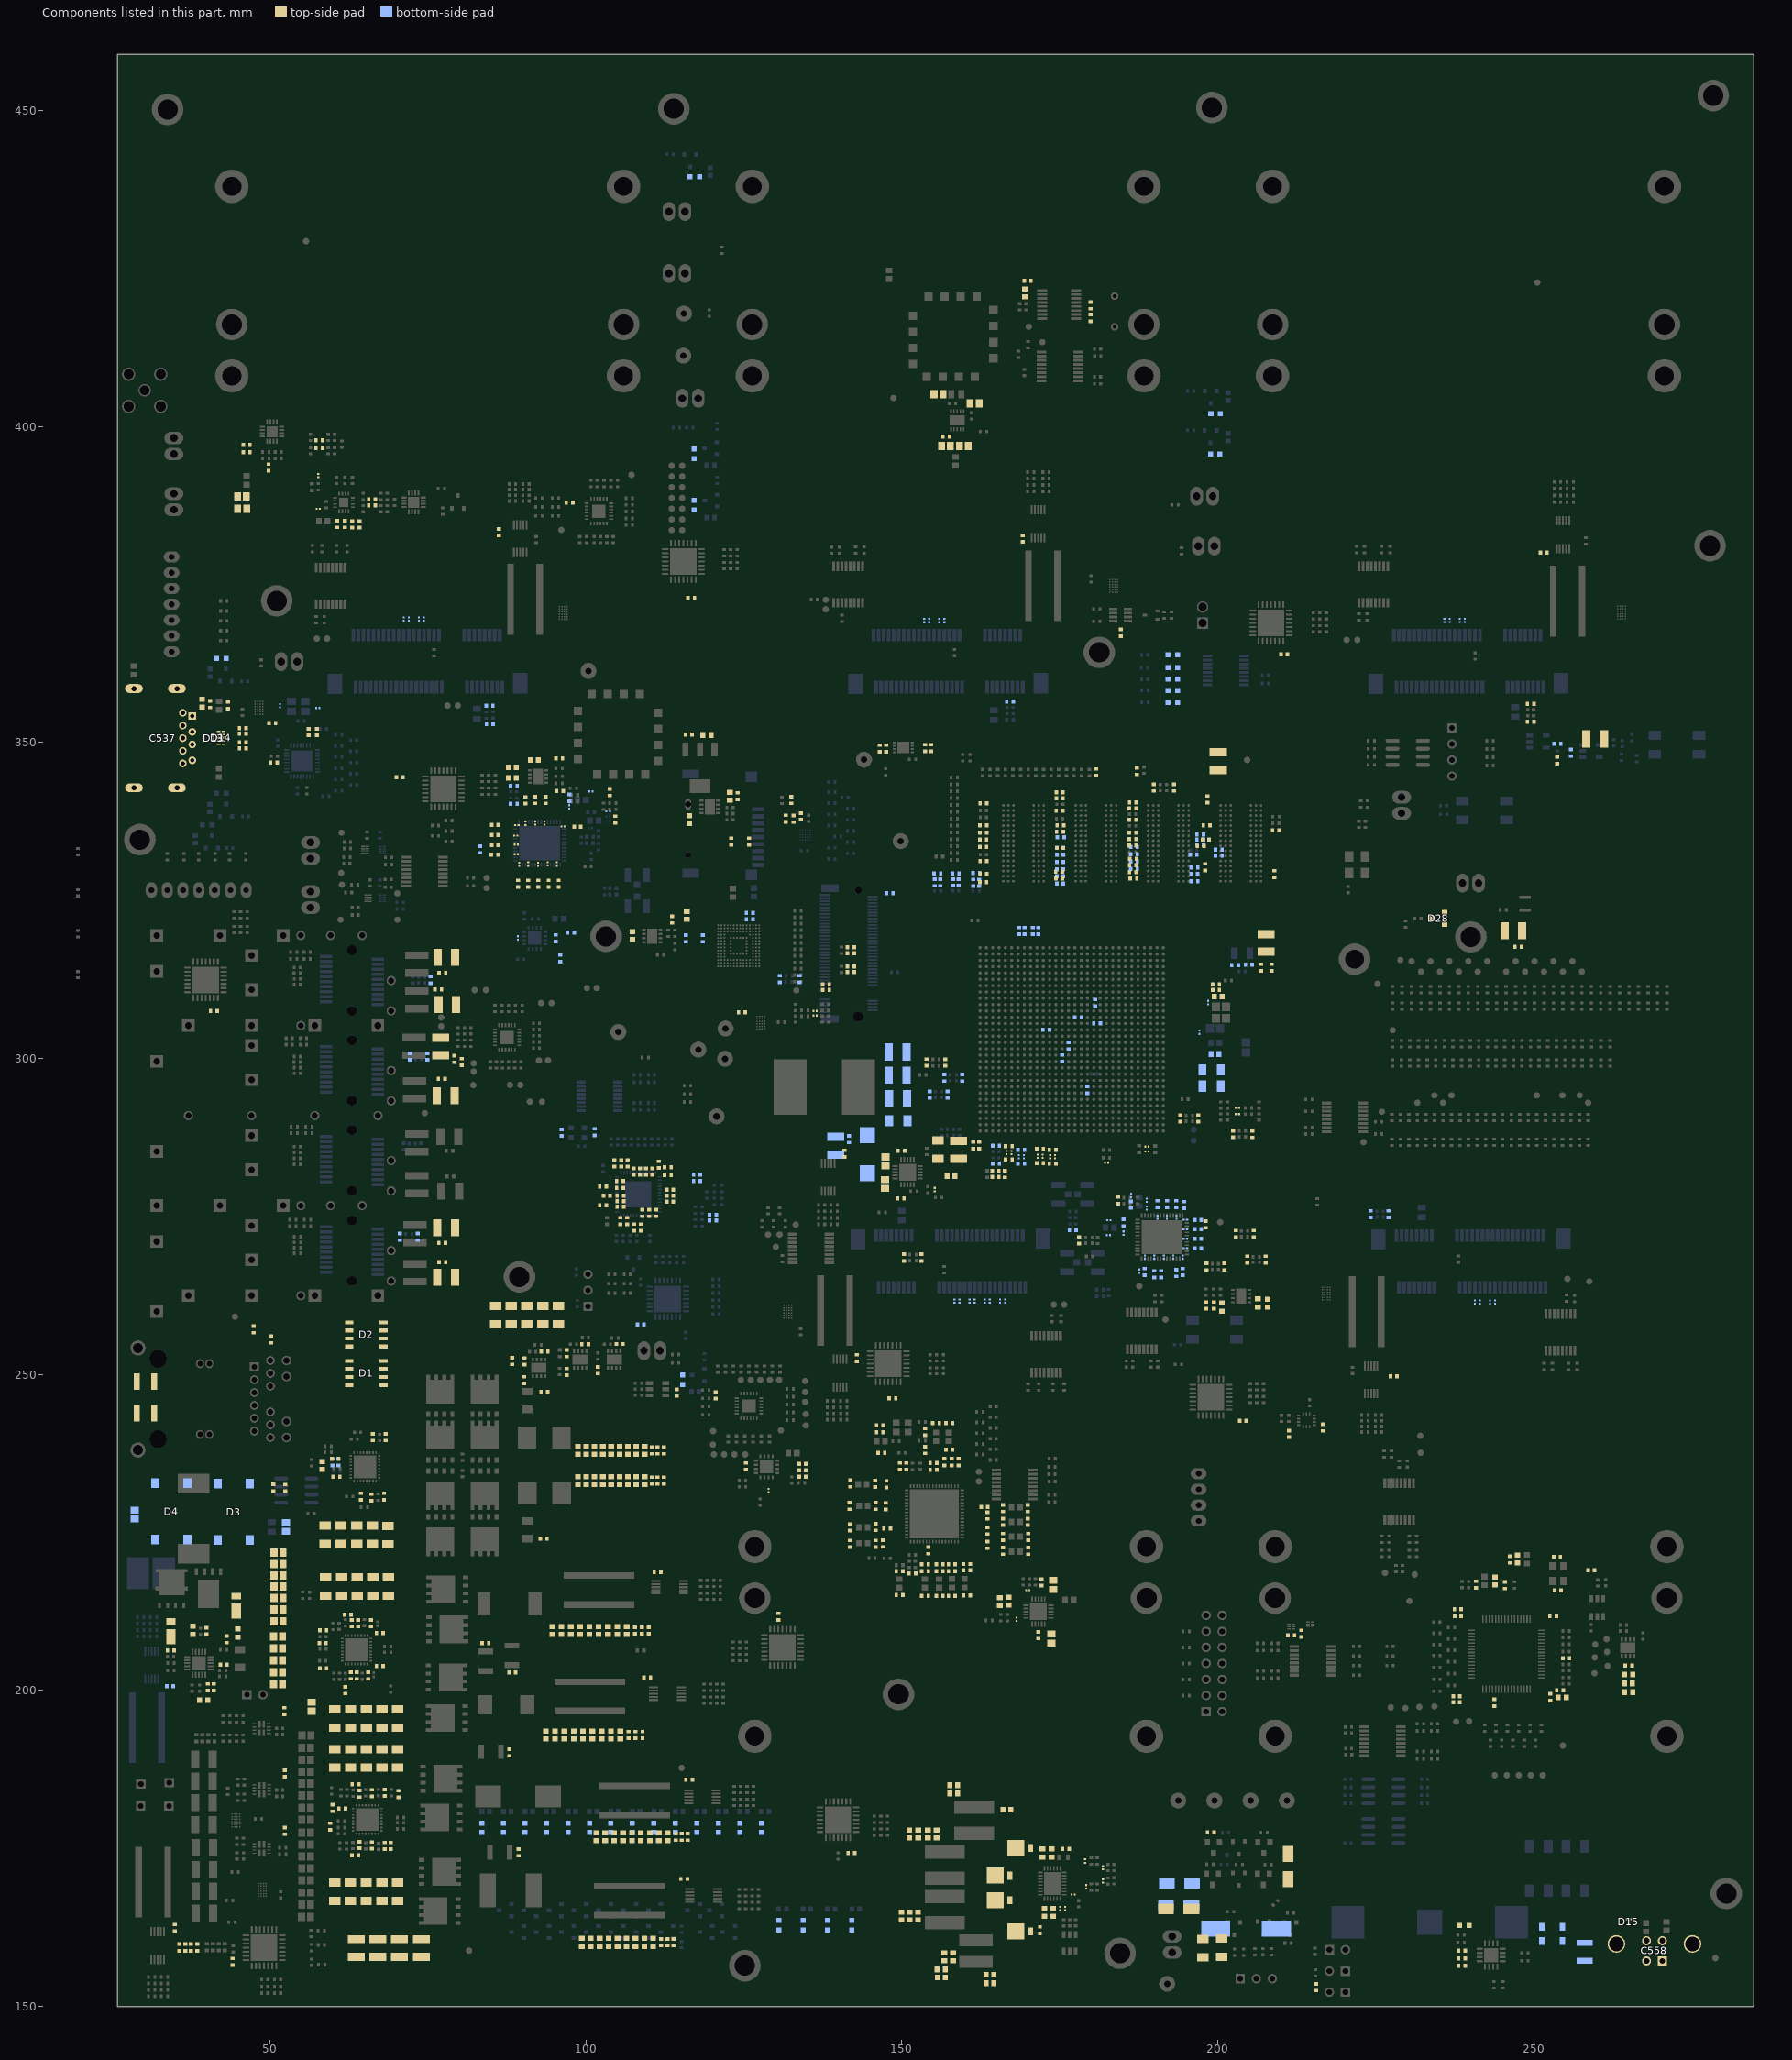
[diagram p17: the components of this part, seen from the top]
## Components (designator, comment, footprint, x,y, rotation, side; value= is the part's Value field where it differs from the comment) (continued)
C64 "100nF" "CAP 0402/1005 KK" 160.328,220.015 r0 top
C65 "10nF" "CAP 0402/1005 KK" 75.441,312.458 r270 bottom
C66 "10nF" "CAP 0402/1005 KK" 159.58,296.964 r90 bottom
C67 "100nF" "CAP 0402/1005 KK" 157.915,219.978 r0 top
C68 "10nF" "CAP 0402/1005 KK" 156.773,296.964 r270 bottom
C69 "10nF" "CAP 0402/1005 KK" 70.561,271.784 r90 bottom
C70 "100nF" "CAP 0402/1005 KK" 153.67,219.97 r0 top
C71 "0.1µF" "CAP 0201/0603 KK" 182.799,274.436 r180 bottom
C72 "0.1µF" "CAP 0201/0603 KK" 182.73,272.048 r180 bottom
C73 "0.1µF" "CAP 0201/0603 KK" 185.092,272.382 r90 bottom
C74 "10uF" "CAP 0402/1005 KK" 185.092,274.024 r270 bottom
C75 "100nF" "CAP 0402/1005 KK" 163.59,225.304 r90 top
C76 "100nF" "CAP 0402/1005 KK" 163.591,227.695 r270 top
C77 "100nF" "CAP 0402/1005 KK" 147.705,225.611 r180 top
C78 "10uF" "CAP 0402/1005 KK" 154.17,222.165 r90 top
C79 "10uF" "CAP 0402/1005 KK" 157.879,236.153 r270 top
C80 "10uF" "CAP 0402/1005 KK" 149.717,235.477 r270 top
C81 "100nF" "CAP 0402/1005 KK" 147.032,223.247 r270 top
C82 "100nF" "CAP 0402/1005 KK" 163.092,229.045 r180 top
C83 "100nF" "CAP 0402/1005 KK" 147.445,229.172 r270 top
C84 "0.1µF" "CAP 0201/0603 KK" 103.54,339.094 r180 bottom
C85 "0.1µF" "CAP 0201/0603 KK" 100.787,342.257 r180 bottom
C86 "10nF" "CAP 0201/0603 KK" 97.38,339.839 r90 bottom
C87 "10uF" "CAP 0402/1005 KK" 97.38,341.255 r270 bottom
C88 "100nF" "CAP 0402/1005 KK" 147.567,232.642 r270 top
C89 "100nF" "CAP 0402/1005 KK" 158.972,236.155 r90 top
C90 "100nF" "CAP 0402/1005 KK" 155.029,236.017 r0 top
C91 "100nF" "CAP 0402/1005 KK" 156.761,236.153 r90 top
C92 "100nF" "CAP 0402/1005 KK" 163.59,223.041 r270 top
C93 "100nF" "CAP 0402/1005 KK" 155.999,219.97 r0 top
C94 "0.1µF" "CAP 0201/0603 KK" 188.761,277.581 r90 bottom
C95 "0.1µF" "CAP 0201/0603 KK" 186.309,278.331 r90 bottom
C96 "100nF" "CAP 0402/1005 KK" 150.717,235.477 r90 top
C97 "10nF" "CAP 0201/0603 KK" 188.767,276.337 r270 bottom
C98 "10uF" "CAP 0402/1005 KK" 186.259,276.85 r270 bottom
C99 "100nF" "CAP 0402/1005 KK" 149.666,215.088 r180 top
C100 "100nF" "CAP 0402/1005 KK" 169.949,228.831 r90 top
C101 "10uF" "CAP 0402/1005 KK" 149.657,218.898 r180 top
C102 "10uF" "CAP 0402/1005 KK" 166.003,228.831 r90 top
C103 "100nF" "CAP 0402/1005 KK" 160.328,215.064 r180 top
C104 "100nF" "CAP 0402/1005 KK" 141.763,229.212 r90 top
C105 "10uF" "CAP 0402/1005 KK" 160.328,219.01 r180 top
C106 "10uF" "CAP 0402/1005 KK" 145.847,229.208 r90 top
C107 "100nF" "CAP 0402/1005 KK" 157.92,214.977 r180 top
C108 "100nF" "CAP 0402/1005 KK" 141.861,232.766 r270 top
C109 "10uF" "CAP 0402/1005 KK" 157.92,218.923 r180 top
C110 "10uF" "CAP 0402/1005 KK" 145.797,232.709 r90 top
C111 "10nF" "CAP 0402/1005 KK" 73.368,271.784 r270 bottom
C112 "10nF" "CAP 0402/1005 KK" 164.922,286.169 r180 bottom
C113 "10nF" "CAP 0402/1005 KK" 164.922,283.362 r0 bottom
C114 "10nF" "CAP 0402/1005 KK" 72.149,300.313 r90 bottom
C115 "10nF" "CAP 0402/1005 KK" 74.956,300.313 r270 bottom
C116 "10nF" "CAP 0402/1005 KK" 157.217,294.293 r90 bottom
C117 "10nF" "CAP 0402/1005 KK" 154.411,294.293 r270 bottom
C118 "10nF" "CAP 0402/1005 KK" 164.838,281.267 r180 top
C119 "10nF" "CAP 0402/1005 KK" 164.835,282.179 r180 top
C124 "100nF" "CAP 0402/1005 KK" 153.67,214.95 r180 top
C125 "100nF" "CAP 0402/1005 KK" 157.537,242.309 r180 top
C126 "10uF" "CAP 0402/1005 KK" 153.67,218.896 r180 top
C127 "10uF" "CAP 0402/1005 KK" 157.512,238.086 r0 top
C141 "100nF" "CAP 0402/1005 KK" 169.989,224.311 r90 top
C142 "100nF" "CAP 0402/1005 KK" 155.41,242.309 r0 top
C143 "10uF" "CAP 0402/1005 KK" 166.043,224.311 r270 top
C144 "10uF" "CAP 0402/1005 KK" 155.029,234.888 r180 top
C145 "100nF" "CAP 0402/1005 KK" 169.949,226.686 r90 top
C146 "100nF" "CAP 0402/1005 KK" 169.989,222.114 r90 top
C147 "10uF" "CAP 0402/1005 KK" 166.003,226.686 r90 top
C148 "10uF" "CAP 0402/1005 KK" 166.043,222.114 r90 top
C149 "10nF" "CAP 0201/0603 KK" 89.103,336.956 r180 top
C150 "10nF" "CAP 0201/0603 KK" 89.459,330.74 r270 top
C151 "10nF" "CAP 0201/0603 KK" 90.437,337.229 r90 top
C152 "10nF" "CAP 0201/0603 KK" 89.014,333.845 r180 top
C153 "10nF" "CAP 0201/0603 KK" 93.472,337.257 r90 top
C154 "10nF" "CAP 0201/0603 KK" 88.979,332.321 r180 top
C155 "10nF" "CAP 0201/0603 KK" 92.011,337.264 r90 top
C156 "10nF" "CAP 0201/0603 KK" 88.938,335.28 r180 top
C157 "10nF" "CAP 0201/0603 KK" 96.38,336.74 r0 top
C158 "10nF" "CAP 0201/0603 KK" 93.98,330.81 r270 top
C159 "10nF" "CAP 0201/0603 KK" 92.456,330.733 r270 top
C160 "10nF" "CAP 0201/0603 KK" 95.428,330.784 r270 top
C161 "10nF" "CAP 0201/0603 KK" 90.868,330.784 r270 top
C162 "100nF" "CAP 0402/1005 KK" 141.801,225.845 r270 top
C163 "100nF" "CAP 0402/1005 KK" 155.999,214.95 r180 top
C164 "10uF" "CAP 0402/1005 KK" 145.847,225.876 r90 top
C165 "10uF" "CAP 0402/1005 KK" 155.999,218.896 r180 top
C166 "10nF" "CAP 0201/0603 KK" 193.473,274.871 r90 bottom
C167 "10nF" "CAP 0201/0603 KK" 194.473,268.591 r270 bottom
C168 "10nF" "CAP 0201/0603 KK" 191.473,268.591 r270 bottom
C169 "10nF" "CAP 0201/0603 KK" 194.863,274.481 r0 bottom
C170 "10nF" "CAP 0201/0603 KK" 192.973,268.591 r270 bottom
C171 "10nF" "CAP 0201/0603 KK" 194.863,272.981 r0 bottom
C172 "10nF" "CAP 0201/0603 KK" 187.598,266.361 r90 bottom
C173 "10nF" "CAP 0201/0603 KK" 188.473,268.601 r270 bottom
C174 "10nF" "CAP 0201/0603 KK" 194.863,269.981 r0 bottom
C175 "10nF" "CAP 0201/0603 KK" 190.473,274.871 r90 bottom
C176 "10nF" "CAP 0201/0603 KK" 189.973,268.591 r270 bottom
C177 "10nF" "CAP 0201/0603 KK" 194.863,271.481 r0 bottom
C178 "10nF" "CAP 0201/0603 KK" 191.973,274.871 r90 bottom
C179 "100nF" "CAP 0402/1005 KK" 141.801,223.227 r90 top
C180 "10uF" "CAP 0402/1005 KK" 145.847,223.227 r90 top
C181 "1uF" "CAP 0402/1005 KK" 89.319,327.673 r270 top
C182 "1uF" "CAP 0402/1005 KK" 98.679,336.69 r0 top
C183 "1uF" "CAP 0402/1005 KK" 85.623,333.795 r180 top
C184 "1uF" "CAP 0402/1005 KK" 93.65,340.899 r90 top
C185 "1uF" "CAP 0402/1005 KK" 85.573,332.296 r180 top
C186 "1uF" "CAP 0402/1005 KK" 85.623,335.396 r180 top
C187 "1uF" "CAP 0402/1005 KK" 95.707,327.673 r270 top
C188 "1uF" "CAP 0402/1005 KK" 91.961,340.899 r90 top
C189 "1uF" "CAP 0402/1005 KK" 90.916,327.673 r270 top
C190 "1uF" "CAP 0402/1005 KK" 85.623,336.997 r180 top
C191 "1uF" "CAP 0402/1005 KK" 94.11,327.673 r270 top
C192 "1uF" "CAP 0402/1005 KK" 90.437,340.866 r90 top
C193 "1uF" "CAP 0402/1005 KK" 92.513,327.673 r270 top
C194 "1uF" "CAP 0402/1005 KK" 191.059,265.884 r270 bottom
C195 "1uF" "CAP 0402/1005 KK" 196.891,272.981 r0 bottom
C196 "1uF" "CAP 0402/1005 KK" 196.891,269.981 r0 bottom
C197 "1uF" "CAP 0402/1005 KK" 193.43,266.054 r270 bottom
C198 "1uF" "CAP 0402/1005 KK" 196.891,274.481 r0 bottom
C199 "1uF" "CAP 0402/1005 KK" 189.973,265.884 r270 bottom
C200 "1uF" "CAP 0402/1005 KK" 188.473,266.235 r270 bottom
C201 "1uF" "CAP 0402/1005 KK" 196.891,271.481 r0 bottom
C202 "1uF" "CAP 0402/1005 KK" 193.473,276.985 r90 bottom
C203 "1uF" "CAP 0402/1005 KK" 194.669,276.815 r90 bottom
C204 "1uF" "CAP 0402/1005 KK" 191.973,276.985 r90 bottom
C205 "1uF" "CAP 0402/1005 KK" 190.473,276.985 r90 bottom
C206 "1uF" "CAP 0402/1005 KK" 194.473,266.235 r270 bottom
C207 "100nF" "CAP 0402/1005 KK" 77.314,313.547 r180 top
C208 "22uF" "CAP 1210/3225 - 1MM" 77.936,315.991 r0 top
C209 "100nF" "CAP 0402/1005 KK" 76.641,310.947 r180 top
C210 "22uF" "CAP 1210/3225 - 1MM" 78.074,308.517 r0 top
C211 "100nF" "CAP 0402/1005 KK" 77.275,270.856 r180 top
C212 "22uF" "CAP 1210/3225 - 1MM" 77.915,273.206 r0 top
C213 "100nF" "CAP 0402/1005 KK" 77.304,267.773 r180 top
C214 "22uF" "CAP 1210/3225 - 1MM" 77.915,265.412 r0 top
C215 "100nF" "CAP 0402/1005 KK" 79.181,299.938 r270 top
C216 "22uF" "CAP 1210/3225 - 1MM" 77.031,301.911 r90 top
C217 "100nF" "CAP 0402/1005 KK" 77.181,296.771 r180 top
C218 "22uF" "CAP 1210/3225 - 1MM" 77.844,294.081 r0 top
C219 "100nF" "CAP 0402/1005 KK" 174.977,339.217 r0 top
C220 "100nF" "CAP 0402/1005 KK" 180.759,345.31 r90 top
C221 "100nF" "CAP 0402/1005 KK" 209.194,336.106 r0 top
C222 "100nF" "CAP 0402/1005 KK" 193.055,342.877 r90 top
C223 "4.7uF" "CAP 0402/1005 KK" 162.916,331.241 r0 top
C224 "470nF" "CAP 0402/1005 KK" 198.095,334.638 r0 top
C225 "470nF" "CAP 0402/1005 KK" 175.032,335.856 r180 top
C226 "68nF" "CAP 0402/1005 KK" 175.056,331.091 r0 bottom
C227 "68nF" "CAP 0402/1005 KK" 186.766,332.353 r180 bottom
C228 "4.7uF" "CAP 0402/1005 KK" 196.317,330.2 r0 bottom
C229 "470nF" "CAP 0402/1005 KK" 162.91,336.878 r0 top
C230 "470nF" "CAP 0402/1005 KK" 186.601,331.61 r0 top
C231 "68nF" "CAP 0402/1005 KK" 197.231,335.42 r0 bottom
C232 "68nF" "CAP 0402/1005 KK" 200.177,333.083 r180 bottom
C233 "4.7uF" "CAP 0402/1005 KK" 200.177,332.092 r0 bottom
C234 "470nF" "CAP 0402/1005 KK" 186.524,333.686 r0 top
C235 "470nF" "CAP 0402/1005 KK" 186.524,334.718 r180 top
C236 "68nF" "CAP 0402/1005 KK" 197.231,333.807 r180 bottom
C237 "68nF" "CAP 0402/1005 KK" 197.231,334.62 r0 bottom
C238 "4.7uF" "CAP 0402/1005 KK" 186.576,329.527 r0 top
C239 "470nF" "CAP 0402/1005 KK" 186.524,335.75 r180 top
C240 "470nF" "CAP 0402/1005 KK" 175.11,336.878 r0 top
C241 "68nF" "CAP 0402/1005 KK" 175.165,335.035 r180 bottom
C242 "68nF" "CAP 0402/1005 KK" 186.766,333.518 r0 bottom
C243 "100nF" "CAP 0402/1005 KK" 189.878,342.861 r90 top
C244 "100nF" "CAP 0402/1005 KK" 175.015,342.113 r0 top
C245 "100nF" "CAP 0402/1005 KK" 186.548,337.795 r0 top
C246 "100nF" "CAP 0402/1005 KK" 186.576,340.514 r180 top
C247 "4.7uF" "CAP 0402/1005 KK" 162.916,329.197 r0 top
C248 "470nF" "CAP 0402/1005 KK" 197.294,333.654 r180 top
C249 "470nF" "CAP 0402/1005 KK" 162.897,333.518 r0 top
C250 "68nF" "CAP 0402/1005 KK" 175.056,333.362 r0 bottom
C251 "68nF" "CAP 0402/1005 KK" 175.056,329.956 r180 bottom
C252 "4.7uF" "CAP 0402/1005 KK" 186.576,330.606 r180 top
C253 "470nF" "CAP 0402/1005 KK" 162.91,335.758 r0 top
C254 "470nF" "CAP 0402/1005 KK" 198.26,336.886 r180 top
C255 "68nF" "CAP 0402/1005 KK" 186.766,331.188 r0 bottom
C256 "68nF" "CAP 0402/1005 KK" 186.766,330.022 r180 bottom
C257 "4.7uF" "CAP 0402/1005 KK" 175.056,327.685 r0 bottom
C258 "470nF" "CAP 0402/1005 KK" 196.177,332.227 r0 bottom
C259 "470nF" "CAP 0402/1005 KK" 175.056,332.227 r0 bottom
C260 "68nF" "CAP 0402/1005 KK" 196.278,329.24 r0 bottom
C261 "68nF" "CAP 0402/1005 KK" 162.897,327.914 r0 top
C262 "4.7uF" "CAP 0402/1005 KK" 175.056,328.821 r0 bottom
C263 "470nF" "CAP 0402/1005 KK" 162.905,334.638 r0 top
C264 "470nF" "CAP 0402/1005 KK" 175.056,333.311 r180 top
C265 "68nF" "CAP 0402/1005 KK" 174.884,329.59 r180 top
C266 "68nF" "CAP 0402/1005 KK" 196.317,328.06 r0 bottom
C267 "100nF" "CAP 0201/0603 KK" 156.737,369.297 r90 bottom
C268 "100nF" "CAP 0201/0603 KK" 155.937,369.297 r90 bottom
C269 "100nF" "CAP 0201/0603 KK" 154.337,369.297 r90 bottom
C270 "100nF" "CAP 0201/0603 KK" 153.537,369.297 r90 bottom
C271 "100nF" "CAP 0201/0603 KK" 240.69,261.449 r270 bottom
C272 "100nF" "CAP 0201/0603 KK" 241.49,261.449 r270 bottom
C273 "10nF" "CAP 0201/0603 KK" 188.778,286.056 r0 top
C274 "100nF" "CAP 0201/0603 KK" 243.09,261.449 r270 bottom
C275 "100nF" "CAP 0201/0603 KK" 243.89,261.449 r270 bottom
C276 "10nF" "CAP 0201/0603 KK" 188.777,285.308 r0 top
C277 "10nF" "CAP 0201/0603 KK" 173.498,284.44 r270 top
C278 "10nF" "CAP 0201/0603 KK" 174.278,284.44 r270 top
C279 "100nF" "CAP 0201/0603 KK" 239.09,369.335 r90 bottom
C280 "100nF" "CAP 0201/0603 KK" 238.29,369.335 r90 bottom
C281 "100nF" "CAP 0201/0603 KK" 236.69,369.335 r90 bottom
C282 "100nF" "CAP 0201/0603 KK" 235.89,369.335 r90 bottom
C283 "100nF" "CAP 0201/0603 KK" 74.385,369.563 r90 bottom
C284 "100nF" "CAP 0201/0603 KK" 73.585,369.563 r90 bottom
C285 "10nF" "CAP 0201/0603 KK" 171.505,284.534 r270 top
C286 "100nF" "CAP 0201/0603 KK" 71.985,369.563 r90 bottom
C287 "100nF" "CAP 0201/0603 KK" 71.185,369.563 r90 bottom
C288 "10nF" "CAP 0201/0603 KK" 172.285,284.55 r270 top
C289 "10nF" "CAP 0201/0603 KK" 168.533,284.465 r270 bottom
C290 "10nF" "CAP 0201/0603 KK" 169.313,284.465 r270 bottom
C291 "100nF" "CAP 0201/0603 KK" 158.337,261.601 r270 bottom
C292 "100nF" "CAP 0201/0603 KK" 159.137,261.601 r270 bottom
C293 "100nF" "CAP 0201/0603 KK" 160.737,261.601 r270 bottom
C294 "100nF" "CAP 0201/0603 KK" 161.537,261.601 r270 bottom
C295 "100nF" "CAP 0201/0603 KK" 163.137,261.601 r270 bottom
C296 "100nF" "CAP 0201/0603 KK" 163.937,261.601 r270 bottom
C297 "10nF" "CAP 0201/0603 KK" 166.577,285.109 r270 top
C298 "100nF" "CAP 0201/0603 KK" 165.537,261.601 r270 bottom
C299 "100nF" "CAP 0201/0603 KK" 166.337,261.601 r270 bottom
C300 "10nF" "CAP 0201/0603 KK" 167.357,285.109 r270 top
C303_I2C_Bridge_GPIO "100nF" "CAP 0402/1005 KK" 120.568,246.733 r270 top (schematic designator C303)
C303_I2C_Bridge_PCIE "100nF" "CAP 0402/1005 KK" 97.426,387.96 r0 top (schematic designator C303)
C303_I2C_Bridge_SFP "100nF" "CAP 0402/1005 KK" 80.337,299.462 r90 top (schematic designator C303)
C304 "4.7µF" "CAP 0603/1608 RF" 172.578,164.915 r270 top
C305 "4.7µF" "CAP 0603/1608 RF" 173.703,174.283 r90 top
C306 "4.7µF" "CAP 0603/1608 RF" 173.953,164.914 r270 top
C307 "4.7µF" "CAP 0603/1608 RF" 172.278,174.282 r90 top
C308 "4.7uF" "CAP 0603/1608 RF" 152.563,164.29 r270 top
C309_U_Pomiar_pradu_napiecia_1 "100nF" "CAP 0402/1005 KK" 34.961,162.454 r270 top (schematic designator C309)
C309_U_Pomiar_pradu_napiecia_2 "100nF" "CAP 0402/1005 KK" 34.195,200.659 r180 bottom (schematic designator C309)
C309_U_Pomiar_pradu_napiecia_3 "100nF" "CAP 0402/1005 KK" 116.346,185.901 r0 top (schematic designator C309)
C309_U_Pomiar_pradu_napiecia_4 "100nF" "CAP 0402/1005 KK" 115.566,170.186 r0 top (schematic designator C309)
C309_U_Pomiar_pradu_napiecia_5 "100nF" "CAP 0402/1005 KK" 111.354,218.75 r180 top (schematic designator C309)
C309_U_Pomiar_pradu_napiecia_6 "100nF" "CAP 0402/1005 KK" 109.725,202.052 r0 top (schematic designator C309)
C309_U_Pomiar_pradu_napiecia_PCIe0 "100nF" "CAP 0402/1005 KK" 169.134,382.273 r90 top (schematic designator C309)
C309_U_Pomiar_pradu_napiecia_PCIe1 "100nF" "CAP 0402/1005 KK" 227.863,249.751 r180 top (schematic designator C309)
C309_U_Pomiar_pradu_napiecia_PCIe2 "100nF" "CAP 0402/1005 KK" 251.612,380.03 r0 top (schematic designator C309)
C309_U_Pomiar_pradu_napiecia_PCIe3 "100nF" "CAP 0402/1005 KK" 86.22,383.255 r90 top (schematic designator C309)
C309_U_Pomiar_pradu_napiecia_PCIe4 "100nF" "CAP 0402/1005 KK" 142.887,252.614 r270 top (schematic designator C309)
C310 "100nF" "CAP 0402/1005 KK" 140.907,284.937 r270 top
C311_I2C_Expander_00 "1uF" "CAP 0402/1005 KK" 148.522,246.24 r180 top (schematic designator C311)
C311_I2C_Expander_01 "1uF" "CAP 0402/1005 KK" 70.542,344.544 r180 top (schematic designator C311)
C311_I2C_Expander_02 "1uF" "CAP 0402/1005 KK" 116.697,372.875 r180 top (schematic designator C311)
C311_I2C_Expander_10 "1uF" "CAP 0402/1005 KK" 210.528,363.954 r180 top (schematic designator C311)
C311_I2C_Expander_11 "1uF" "CAP 0402/1005 KK" 203.999,242.712 r180 top (schematic designator C311)
C311_I2C_Expander_12 "1uF" "CAP 0402/1005 KK" 142.045,174.28 r180 top (schematic designator C311)
C311_I2C_Expander_Main_Rst "1uF" "CAP 0402/1005 KK" 108.689,257.892 r0 bottom (schematic designator C311)
C311_I2C_Expander_PWR_CLK "1uF" "CAP 0402/1005 KK" 130.479,211.703 r270 top (schematic designator C311)
C311_I2C_Expander_PWR_Dist "1uF" "CAP 0402/1005 KK" 44.121,157.078 r90 top (schematic designator C311)
C311_I2C_Expander_SFP "1uF" "CAP 0402/1005 KK" 41.127,307.547 r180 top (schematic designator C311)
C312 "100nF" "CAP 0402/1005 KK" 52.362,186.867 r270 top
C313 "100nF" "CAP 0402/1005 KK" 52.362,177.787 r270 top
C314 "100nF" "CAP 0402/1005 KK" 52.299,196.748 r90 top
C315 "100nF" "CAP 0402/1005 KK" 167.127,356.458 r0 bottom
C316 "100nF" "CAP 0402/1005 KK" 84.798,352.901 r180 bottom
C317 "100nF" "CAP 0402/1005 KK" 84.776,355.809 r0 bottom
C318 "100nF" "CAP 0402/1005 KK" 88.616,340.289 r180 bottom
C319 "100nF" "CAP 0402/1005 KK" 88.603,343.159 r0 bottom
C320 "10nF" "CAP 0402/1005 KK" 169.915,423.06 r0 top
C321 "3.3nF" "CAP 0603/1608 RF" 169.496,421.167 r270 top
C322 "27pF" "CAP 0402/1005 KK" 179.87,419.179 r270 top
C323 "27pF" "CAP 0402/1005 KK" 179.87,417.199 r90 top
C324 "10uF" "CAP 0805/2012 RF" 45.571,388.955 r0 top
C325 "100nF" "CAP 0402/1005 KK" 57.824,397.819 r180 top
C326 "1uF" "CAP 0402/1005 KK" 46.32,395.959 r180 top
C327 "1uF" "CAP 0402/1005 KK" 46.32,397.075 r180 top
C328 "1uF" "CAP 0402/1005 KK" 138.022,311.721 r0 top
C329 "1uF" "CAP 0402/1005 KK" 138.022,310.865 r0 top
C330 "100nF" "CAP 0402/1005 KK" 57.824,396.618 r180 top
C331 "1uF" "CAP 0402/1005 KK" 124.688,307.343 r0 top
C332 "1uF" "CAP 0402/1005 KK" 148.095,326.164 r0 bottom
C333 "10nF" "CAP 0201/0603 KK" 57.675,392.233 r270 top
C334 "100nF" "CAP 0402/1005 KK" 103.797,342.129 r90 top
C335 "100nF" "CAP 0402/1005 KK" 104.697,337.82 r90 top
C336 "100nF" "CAP 0402/1005 KK" 61.848,384.57 r90 top
C337 "100nF" "CAP 0402/1005 KK" 63.008,384.555 r90 top
C338 "100nF" "CAP 0402/1005 KK" 64.184,384.549 r90 top
C339 "10uF" "CAP 0805/2012 RF" 45.621,386.973 r0 top
C340 "1uF" "CAP 0402/1005 KK" 60.666,384.57 r270 top
C341 "100nF" "CAP 0402/1005 KK" 49.793,393.546 r270 top
C342 "100nF" "CAP 0402/1005 KK" 66.167,387.497 r180 top
C343 "100nF" "CAP 0402/1005 KK" 66.167,388.497 r180 top
C344 "10nF" "CAP 0201/0603 KK" 57.658,387 r0 top
C345 "22pF" "CAP 0402/1005 KK" 66.32,240.08 r270 top
C346 "100nF" "CAP 0402/1005 KK" 68.336,240.08 r90 top
C347 "10uF" "CAP 1206/3216" 88.21,259.372 r270 top
C348 "10uF" "CAP 1206/3216" 85.728,259.372 r270 top
C349 "22pF" "CAP 0402/1005 KK" 66.055,230.564 r90 top
C350 "100nF" "CAP 0402/1005 KK" 68.072,230.712 r270 top
C351 "1uF" "CAP 0402/1005 KK" 60.322,236.629 r180 top
C352 "10uF" "CAP 1206/3216" 62.772,195.58 r90 top
C353 "10uF" "CAP 1206/3216" 60.29,195.58 r90 top
C354 "4.7uF" "CAP 0603/1608 RF" 151.25,164.289 r270 top
C355 "4.7uF" "CAP 0603/1608 RF" 149.956,164.301 r270 top
C356 "1uF" "CAP 0402/1005 KK" 60.541,233.839 r180 top
C357 "100nF" "CAP 0402/1005 KK" 64.44,230.697 r90 top
C358 "1uF" "CAP 0603/1608 RF" 58.293,235.623 r270 top
C359 "100nF" "CAP 0402/1005 KK" 112.323,233.238 r270 top
C360 "470nF" "CAP 0402/1005 KK" 112.324,237.989 r90 top
C361 "1uF" "CAP 0402/1005 KK" 110.434,233.237 r90 top
C362 "4.7uF" "CAP 0603/1608 RF" 101.381,237.989 r90 top
C363 "10uF" "CAP 0603/1608 RF" 100.061,237.989 r90 top
C364 "22uF" "CAP 0603/1608 RF" 102.7,237.989 r90 top
C365 "10uF" "CAP 0603/1608 RF" 98.742,233.237 r270 top
C366 "22uF" "CAP 0603/1608 RF" 98.742,237.989 r90 top
C367 "10uF" "CAP 0603/1608 RF" 101.381,233.237 r270 top
C368 "22uF" "CAP 0603/1608 RF" 100.061,233.237 r270 top
C369 "10uF" "CAP 0603/1608 RF" 102.7,233.237 r270 top
C370 "22uF" "CAP 0603/1608 RF" 104.02,237.989 r90 top
C371 "10uF" "CAP 1206/3216 - 0.8MM" 67.736,195.58 r90 top
C372 "10uF" "CAP 1206/3216 - 0.8MM" 90.692,259.372 r270 top
C373 "10uF" "CAP 1206/3216 - 0.8MM" 95.656,259.372 r270 top
C374 "10uF" "CAP 1206/3216 - 0.8MM" 65.254,195.58 r90 top
C375 "10uF" "CAP 1206/3216 - 0.8MM" 93.174,259.372 r270 top
C376 "10uF" "CAP 1206/3216 - 0.8MM" 70.218,195.58 r90 top
C377 "100nF" "CAP 0402/1005 KK" 111.364,233.238 r270 top
C378 "470nF" "CAP 0402/1005 KK" 110.435,237.989 r90 top
C379 "1uF" "CAP 0402/1005 KK" 111.365,237.989 r270 top
C380 "4.7uF" "CAP 0603/1608 RF" 105.339,237.989 r90 top
C381 "10uF" "CAP 0603/1608 RF" 105.339,233.237 r270 top
C382 "22uF" "CAP 0603/1608 RF" 106.659,233.237 r270 top
C383 "10uF" "CAP 0603/1608 RF" 109.298,237.989 r90 top
C384 "22uF" "CAP 0603/1608 RF" 107.978,233.238 r270 top
C385 "10uF" "CAP 0603/1608 RF" 104.02,233.237 r270 top
C386 "22uF" "CAP 0603/1608 RF" 106.659,237.989 r90 top
C387 "10uF" "CAP 0603/1608 RF" 109.297,233.238 r270 top
C388 "22uF" "CAP 0603/1608 RF" 107.978,237.989 r90 top
C389 "22pF" "CAP 0402/1005 KK" 68.211,183.823 r270 top
C390 "100nF" "CAP 0402/1005 KK" 70.383,183.613 r90 top
C391 "10uF" "CAP 1206/3216" 61.258,224.638 r270 top
C392 "10uF" "CAP 1206/3216" 58.776,224.638 r90 top
C393 "22pF" "CAP 0402/1005 KK" 68.185,175.427 r90 top
C394 "100nF" "CAP 0402/1005 KK" 69.151,175.427 r270 top
C395 "1uF" "CAP 0402/1005 KK" 59.93,181.401 r90 top
C396 "10uF" "CAP 1206/3216" 61.334,216.433 r270 top
C397 "10uF" "CAP 1206/3216" 58.852,216.433 r90 top
C398 "1uF" "CAP 0402/1005 KK" 61.458,181.317 r180 top
C399 "100nF" "CAP 0402/1005 KK" 59.524,178.467 r90 top
C400 "10uF" "CAP 1206/3216 - 0.8MM" 68.78,216.433 r270 top
C401 "10uF" "CAP 1206/3216 - 0.8MM" 66.298,216.433 r270 top
C402 "10uF" "CAP 1206/3216 - 0.8MM" 63.816,216.433 r270 top
C403 "10uF" "CAP 1206/3216 - 0.8MM" 68.704,224.607 r90 top
C404 "10uF" "CAP 1206/3216 - 0.8MM" 66.222,224.637 r90 top
C405 "10uF" "CAP 1206/3216 - 0.8MM" 63.74,224.637 r90 top
C406 "100nF" "CAP 0402/1005 KK" 116.15,176.851 r90 top
C407 "470nF" "CAP 0402/1005 KK" 115.176,176.847 r90 top
C408 "1uF" "CAP 0402/1005 KK" 114.205,176.851 r270 top
C409 "4.7uF" "CAP 0603/1608 RF" 110.122,176.847 r90 top
C410 "10uF" "CAP 0603/1608 RF" 108.699,176.847 r90 top
C411 "22uF" "CAP 0603/1608 RF" 112.941,176.847 r90 top
C412 "10uF" "CAP 0603/1608 RF" 111.544,176.847 r90 top
C413 "22uF" "CAP 0603/1608 RF" 107.302,176.847 r90 top
C414 "10uF" "CAP 0603/1608 RF" 103.061,176.847 r90 top
C415 "22uF" "CAP 0603/1608 RF" 101.638,176.847 r90 top
C416 "10uF" "CAP 0603/1608 RF" 105.905,176.847 r90 top
C417 "22uF" "CAP 0603/1608 RF" 104.47,176.851 r90 top
C418 "100nF" "CAP 0402/1005 KK" 113.877,160.146 r90 top
C419 "470nF" "CAP 0402/1005 KK" 112.903,160.146 r90 top
C420 "1uF" "CAP 0402/1005 KK" 111.932,160.146 r270 top
C421 "4.7uF" "CAP 0603/1608 RF" 107.849,160.146 r90 top
C422 "10uF" "CAP 0603/1608 RF" 106.426,160.146 r90 top
C423 "22uF" "CAP 0603/1608 RF" 110.668,160.146 r90 top
C424 "10uF" "CAP 0603/1608 RF" 109.271,160.146 r90 top
C425 "22uF" "CAP 0603/1608 RF" 105.029,160.147 r90 top
C426 "10uF" "CAP 0603/1608 RF" 100.787,160.147 r90 top
C427 "22uF" "CAP 0603/1608 RF" 99.37,160.137 r90 top
C428 "10uF" "CAP 0603/1608 RF" 103.632,160.147 r90 top
C429 "22uF" "CAP 0603/1608 RF" 102.197,160.147 r90 top
C430 "22pF" "CAP 0402/1005 KK" 65.978,210.639 r270 top
C431 "100nF" "CAP 0402/1005 KK" 67.391,209.114 r0 top
C432 "10uF" "CAP 1206/3216" 62.758,168.173 r270 top
C433 "10uF" "CAP 1206/3216" 60.276,168.173 r90 top
C434 "22pF" "CAP 0402/1005 KK" 65.578,202.374 r90 top
C435 "100nF" "CAP 0402/1005 KK" 67.406,203.864 r0 top
C436 "1uF" "CAP 0402/1005 KK" 58.356,207.523 r180 top
C437 "10uF" "CAP 1206/3216" 62.772,189.281 r270 top
C438 "10uF" "CAP 1206/3216" 60.29,189.281 r90 top
C439 "1uF" "CAP 0402/1005 KK" 58.455,209.529 r180 top
C440 "100nF" "CAP 0402/1005 KK" 58.449,203.522 r0 top
C441 "10uF" "CAP 1206/3216 - 0.8MM" 70.218,189.281 r270 top
C442 "10uF" "CAP 1206/3216 - 0.8MM" 67.736,189.281 r270 top
C443 "10uF" "CAP 1206/3216 - 0.8MM" 65.254,189.281 r270 top
C444 "10uF" "CAP 1206/3216 - 0.8MM" 70.204,168.173 r90 top
C445 "10uF" "CAP 1206/3216 - 0.8MM" 67.722,168.173 r90 top
C446 "10uF" "CAP 1206/3216 - 0.8MM" 65.24,168.173 r90 top
C447 "100nF" "CAP 0402/1005 KK" 109.987,209.5 r90 top
C448 "470nF" "CAP 0402/1005 KK" 108.87,209.5 r90 top
C449 "1uF" "CAP 0402/1005 KK" 107.777,209.5 r270 top
C450 "4.7uF" "CAP 0603/1608 RF" 106.482,209.5 r90 top
C451 "10uF" "CAP 0603/1608 RF" 104.983,209.5 r90 top
C452 "22uF" "CAP 0603/1608 RF" 103.51,209.499 r90 top
C453 "10uF" "CAP 0603/1608 RF" 102.037,209.499 r90 top
C454 "22uF" "CAP 0603/1608 RF" 100.564,209.499 r90 top
C455 "10uF" "CAP 0603/1608 RF" 99.091,209.499 r90 top
C456 "22uF" "CAP 0603/1608 RF" 97.617,209.499 r90 top
C457 "10uF" "CAP 0603/1608 RF" 96.144,209.498 r90 top
C458 "22uF" "CAP 0603/1608 RF" 94.671,209.498 r90 top
C459 "100nF" "CAP 0402/1005 KK" 108.979,192.987 r90 top
C460 "470nF" "CAP 0402/1005 KK" 107.861,192.987 r90 top
C461 "1uF" "CAP 0402/1005 KK" 106.769,192.987 r270 top
C462 "4.7uF" "CAP 0603/1608 RF" 105.474,192.987 r90 top
C463 "10uF" "CAP 0603/1608 RF" 103.975,192.986 r90 top
C464 "22uF" "CAP 0603/1608 RF" 102.502,192.971 r90 top
C465 "10uF" "CAP 0603/1608 RF" 101.028,192.986 r90 top
C466 "22uF" "CAP 0603/1608 RF" 99.555,192.986 r90 top
C467 "10uF" "CAP 0603/1608 RF" 98.082,192.986 r90 top
C468 "22uF" "CAP 0603/1608 RF" 96.609,192.986 r90 top
C469 "10uF" "CAP 0603/1608 RF" 95.136,192.986 r90 top
C470 "22uF" "CAP 0603/1608 RF" 93.662,192.986 r90 top
C471 "100nF" "CAP 0402/1005 KK" 52.467,232.083 r90 top
C472 "100nF" "CAP 0402/1005 KK" 50.578,232.095 r90 top
C473 "100nF" "CAP 0402/1005 KK" 47.42,257.146 r270 top
C474 "100nF" "CAP 0402/1005 KK" 50.178,255.53 r270 top
C475 "Capacitor_1210" CAPC3326X17L 30.328,243.887 r180 top
C476 "Capacitor_1210" CAPC3326X17L 30.328,248.856 r180 top
C477 "100nF" "CAP 0402/1005 KK" 173.888,285.565 r180 top
C478 "100nF" "CAP 0402/1005 KK" 184.239,277.558 r90 top
C479 "100nF" "CAP 0402/1005 KK" 120.113,275.285 r0 bottom
C480 "27pF" "CAP 0402/1005 KK" 101.403,288.349 r270 bottom
C481 "27pF" "CAP 0402/1005 KK" 96.15,288.272 r90 bottom
C482 "100nF" "CAP 0402/1005 KK" 120.113,274.345 r0 bottom
C483 "100nF" "CAP 0402/1005 KK" 117.584,281.61 r0 bottom
C484 "100nF" "CAP 0402/1005 KK" 117.606,280.645 r0 bottom
C485 "1uF" "CAP 0402/1005 KK" 105.454,274.277 r270 top
C486 "1uF" "CAP 0402/1005 KK" 106.595,283.431 r90 top
C487 "100nF" "CAP 0402/1005 KK" 56.12,351.663 r270 top
C488 "100nF" "CAP 0402/1005 KK" 106.549,274.277 r90 top
C489 "10uF" "CAP 0402/1005 KK" 105.584,283.431 r270 top
C490 "10nF" "CAP 0402/1005 KK" 104.55,283.431 r270 top
C491 "1uF" "CAP 0402/1005 KK" 108.948,275.572 r90 top
C492 "1uF" "CAP 0402/1005 KK" 108.549,282.1 r270 top
C493 "1uF" "CAP 0402/1005 KK" 110.549,282.1 r270 top
C494 "100nF" "CAP 0402/1005 KK" 111.136,275.572 r270 top
C495 "100nF" "CAP 0402/1005 KK" 113.33,279.259 r180 top
C496 "100nF" "CAP 0402/1005 KK" 107.549,282.1 r90 top
C497 "10uF" "CAP 0402/1005 KK" 109.549,282.1 r90 top
C498 "10nF" "CAP 0402/1005 KK" 110.049,275.572 r270 top
C499 "1uF" "CAP 0402/1005 KK" 105.47,277.459 r0 top
C500 "1uF" "CAP 0402/1005 KK" 105.417,279.527 r0 top
C501 "100nF" "CAP 0402/1005 KK" 105.417,280.625 r180 top
C502 "100nF" "CAP 0402/1005 KK" 102.733,279.775 r0 top
C503 "10uF" "CAP 0402/1005 KK" 105.469,276.536 r180 top
C504 "10nF" "CAP 0402/1005 KK" 102.711,276.787 r0 top
C505 "1uF" "CAP 0402/1005 KK" 105.466,278.325 r0 top
C506 "1uF" "CAP 0402/1005 KK" 103.325,278.325 r180 top
C507 "1uF" "CAP 0402/1005 KK" 112.998,282.791 r0 top
C508 "1uF" "CAP 0402/1005 KK" 108.712,273.275 r270 top
C509 "100nF" "CAP 0402/1005 KK" 113.333,277.333 r180 top
C510 "100nF" "CAP 0402/1005 KK" 107.674,273.275 r90 top
C511 "100nF" "CAP 0402/1005 KK" 113.33,278.276 r180 top
C512 "100nF" "CAP 0402/1005 KK" 111.536,283.207 r270 top
C513 "10uF" "CAP 0402/1005 KK" 88.332,252.116 r90 top
C514 "10nF" "CAP 0402/1005 KK" 112.998,281.585 r180 top
C515 "4.7uF" "CAP 0603/1608 RF" 107.397,319.455 r90 top
C516 "4.7uF" "CAP 0603/1608 RF" 116.385,337.809 r90 top
C517 "100nF" "CAP 0402/1005 KK" 124.008,341.516 r270 top
C518 "2.2uF" "CAP 0402/1005 KK" 125.856,334.347 r90 top
C519 "100nF" "CAP 0402/1005 KK" 113.636,321.971 r270 top
C520 "2.2uF" "CAP 0402/1005 KK" 115.838,318.991 r90 bottom
C521 "100nF" "CAP 0402/1005 KK" 125.948,322.059 r0 bottom
C522 "1uF" "CAP 0402/1005 KK" 125.948,323.067 r180 bottom
C523 "4.7uF" "CAP 0603/1608 RF" 122.809,341.516 r270 top
C524 "4.7uF" "CAP 0603/1608 RF" 115.973,322.675 r270 top
C525 "10nF" "CAP 0402/1005 KK" 161.343,327.823 r90 bottom
C526 "10nF" "CAP 0402/1005 KK" 162.232,327.83 r90 bottom
C527 "10nF" "CAP 0402/1005 KK" 158.101,327.872 r90 bottom
C528 "10nF" "CAP 0402/1005 KK" 159,327.872 r90 bottom
C529 "10nF" "CAP 0402/1005 KK" 155.208,327.851 r90 bottom
C530 "10nF" "CAP 0402/1005 KK" 156.108,327.851 r90 bottom
C531 "100nF" "CAP 0402/1005 KK" 215.559,153.047 r90 top
C532 "100nF" "CAP 0402/1005 KK" 238.654,158.839 r0 top
C533 "100nF" "CAP 0402/1005 KK" 238.654,157.633 r0 top
C534 "100nF" "CAP 0402/1005 KK" 238.654,156.426 r0 top
C535 "22pF" "CAP 0402/1005 KK" 204.932,314.832 r180 bottom
C536 "22pF" "CAP 0402/1005 KK" 202.757,314.782 r0 bottom
C537 "WE-Communication Connectors 692121130100" 692121130100 35.291,358.548 r90 bottom locked
C538 "1uF" "CAP 0402/1005 KK" 40.561,356.069 r270 top
C539 "4.7uF" "CAP 0603/1608 RF" 39.29,356.24 r90 top
C540 "100nF" "CAP 0402/1005 KK" 45.72,352.291 r0 top
C541 "100nF" "CAP 0402/1005 KK" 45.72,351.396 r0 top
C542 "100nF" "CAP 0402/1005 KK" 45.72,350.012 r0 top
C543 "100nF" "CAP 0402/1005 KK" 45.72,349.116 r0 top
C544 "1uF" "CAP 0402/1005 KK" 132.499,340.913 r90 top
C545 "100nF" "CAP 0402/1005 KK" 131.629,337.967 r270 top
C546 "100nF" "CAP 0402/1005 KK" 132.863,337.93 r270 top
C547 "100nF" "CAP 0402/1005 KK" 134.066,338.32 r270 top
C548 "11pF" "CAP 0402/1005 KK" 62.953,210.639 r270 top
C549 "220pF" "CAP 0402/1005 KK" 62.344,211.976 r180 top
C550 "4.7uF" "CAP 0402/1005 KK" 101.922,250.684 r90 top
C551 "10uF" "CAP 0402/1005 KK" 187.177,345.465 r270 top
C552 "4.7uF" "CAP 0402/1005 KK" 96.964,250.415 r90 top
C553 "10uF" "CAP 0402/1005 KK" 96.964,253.376 r90 top
C554 "4.7uF" "CAP 0402/1005 KK" 90.252,249.119 r90 top
C555 "10uF" "CAP 0402/1005 KK" 90.322,252.088 r90 top
C557 "100nF" "CAP 0402/1005 KK" 173.888,283.337 r180 top
C558 "WE-Communication Connectors 61400413321" 61400413321 269.108,158.807 r0 bottom
C559 "1uF" "CAP 0402/1005 KK" 265.033,203.945 r0 top
C560 "4.7uF" "CAP 0603/1608 RF" 265.033,202.548 r180 top
C561 "100nF" "CAP 0402/1005 KK" 216.649,241.614 r90 top
C562 "100nF" "CAP 0402/1005 KK" 211.277,240.614 r90 top
C563_5to3V3_1 "4.7uF" "CAP 0603/1608 RF" 88.395,344.43 r0 top (schematic designator C563)
C563_5to3V3_2 "4.7uF" "CAP 0603/1608 RF" 206.365,261.323 r90 top (schematic designator C563)
C563_5V_to_3V3_for_FTDI "4.7uF" "CAP 0603/1608 RF" 265.033,199.737 r180 top (schematic designator C563)
C564_5to3V3_1 "4.7uF" "CAP 0603/1608 RF" 91.885,347.231 r180 top (schematic designator C564)
C564_5to3V3_2 "4.7uF" "CAP 0603/1608 RF" 207.912,261.308 r90 top (schematic designator C564)
C564_5V_to_3V3_for_FTDI "4.7uF" "CAP 0603/1608 RF" 265.02,201.125 r180 top (schematic designator C564)
C565_5to3V3_1 "4.7uF" "CAP 0603/1608 RF" 88.372,346.081 r0 top (schematic designator C565)
C565_5to3V3_2 "4.7uF" "CAP 0603/1608 RF" 200.673,260.673 r90 top (schematic designator C565)
C565_5V_to_3V3_for_FTDI "4.7uF" "CAP 0603/1608 RF" 254.51,198.903 r180 top (schematic designator C565)
C566_5to3V3_1 "100nF" "CAP 0402/1005 KK" 95.783,347.51 r180 top (schematic designator C566)
C566_5to3V3_2 "100nF" "CAP 0402/1005 KK" 199.36,260.933 r90 top (schematic designator C566)
C566_5V_to_3V3_for_FTDI "100nF" "CAP 0402/1005 KK" 254.187,200.046 r180 top (schematic designator C566)
C567_5to3V3_1 "2.2uF" "CAP 0402/1005 KK" 95.905,342.367 r0 top (schematic designator C567)
C567_5to3V3_2 "2.2uF" "CAP 0402/1005 KK" 198.138,260.933 r90 top (schematic designator C567)
C567_5V_to_3V3_for_FTDI "2.2uF" "CAP 0402/1005 KK" 255.143,205.136 r180 top (schematic designator C567)
C568 "4.7uF" "CAP 0402/1005 KK" 95.25,319.049 r90 bottom
C569 "4.7uF" "CAP 0402/1005 KK" 97.649,319.905 r0 bottom
C570 "4.7uF" "CAP 0402/1005 KK" 95.99,315.857 r90 bottom
C571 "1nF" "CAP 0201/0603 KK" 89.245,319.093 r270 bottom
C572 "10uF" "CAP 0603/1608 RF" 165.532,214.092 r270 top
C573 "10nF" "CAP 0201/0603 KK" 168.186,211.252 r90 top
C574 "10uF" "CAP 0805/2012 RF" 173.703,208.234 r90 top
C575 "10uF" "CAP 0805/2012 RF" 174.003,216.713 r270 top
C576 "10uF" "CAP 0603/1608 RF" 166.929,214.123 r270 top
C577 "10nF" "CAP 0201/0603 KK" 169.921,215.87 r180 top
C578 "100nF" "CAP 0402/1005 KK" 172.128,217.14 r270 top
C579 "100nF" "CAP 0402/1005 KK" 171.628,208.749 r90 top
C580 "4.7uF" "CAP 0805/2012 RF" 155.808,405.114 r0 top
C581 "10uF" "CAP 0805/2012 RF" 156.988,396.897 r0 top
C582 "4.7uF" "CAP 0805/2012 RF" 159.807,396.897 r180 top
C583 "100nF" "CAP 0402/1005 KK" 157.06,398.424 r0 top
C584 "4.7uF" "CAP 0805/2012 RF" 161.532,403.653 r180 top
C585 "100nF" "CAP 0402/1005 KK" 184.645,367.367 r90 top
C586 "2.2uF" "CAP 0402/1005 KK" 122.999,334.34 r90 top
C587 "2.2uF" "CAP 0402/1005 KK" 118.496,318.991 r90 bottom
C588 "100nF" "CAP 0402/1005 KK" 153.67,240.917 r90 top
C589 "100nF" "CAP 0402/1005 KK" 153.67,238.054 r90 top
C590 "100nF" "CAP 0402/1005 KK" 146.785,237.602 r0 top
C591 "10uF" "CAP 0402/1005 KK" 146.545,240.889 r0 top
C592 "100nF" "CAP 0402/1005 KK" 146.545,241.974 r0 top
C594 "100nF" "CAP 0402/1005 KK" 178.092,271.228 r270 top
C595 "10uF" "CAP 0805/2012 RF" 28.639,227.851 r90 bottom
C596 "10uF" "CAP 0805/2012 RF" 52.54,225.895 r90 bottom
C597 "1uF" "CAP 0402/1005 KK" 34.332,206.35 r0 top
C598 "10uF" "CAP 0603/1608 RF" 37.846,209.537 r270 top
C599 "100nF" "CAP 0402/1005 KK" 83.248,333.07 r90 bottom
C601 "100nF" "CAP 0402/1005 KK" 130.688,312.598 r270 bottom
C602 "100nF" "CAP 0402/1005 KK" 133.833,312.579 r90 bottom
C603 "43pF" "CAP 0201/0603 KK" 181.834,169.866 r270 top
C604 "1uF" "CAP 0402/1005 KK" 175.978,174.908 r180 top
C605 "100pF" "CAP 0201/0603 KK" 181.826,171.962 r90 top
C606 "4.7uF" "CAP 0603/1608 RF" 151.179,177.287 r270 top
C607 "4.7uF" "CAP 0603/1608 RF" 155.517,177.296 r270 top
C608 "100nF" "CAP 0402/1005 KK" 161.793,329.356 r180 bottom
C609 "FC0H224ZFTBR24" FC0H224ZFTBR24 204.495,162.332 r180 bottom
C610 "4.7uF" "CAP 0603/1608 RF" 154.122,177.296 r270 top
C611 "4.7uF" "CAP 0603/1608 RF" 152.605,177.306 r270 top
C612 "43pF" "CAP 0201/0603 KK" 179.024,173.015 r90 top
C613 "4.7uF" "CAP 0603/1608 RF" 158.243,185.022 r0 top
C614 "4.7uF" "CAP 0603/1608 RF" 166.626,181.153 r180 top
C615 "4.7uF" "CAP 0603/1608 RF" 158.243,183.706 r0 top
C616 "100pF" "CAP 0201/0603 KK" 179.174,168.95 r270 top
C617 "4.7uF" "CAP 0603/1608 RF" 156.237,155.868 r0 top
C618 "4.7uF" "CAP 0603/1608 RF" 163.975,153.678 r180 top
C619 "4.7uF" "CAP 0603/1608 RF" 156.729,157.871 r270 top
C620 "4.7uF" "CAP 0603/1608 RF" 163.975,155.006 r180 top
C621 "4.7uF" "CAP 0603/1608 RF" 158.119,157.87 r270 top
C622 "4.7uF" "CAP 0603/1608 RF" 156.25,154.593 r0 top
C623 "100nF" "CAP 0402/1005 KK" 171.866,162.095 r90 top
C624 "10nF" "CAP 0201/0603 KK" 175.841,165.493 r90 top
C625 "10nF" "CAP 0201/0603 KK" 177.122,167.7 r180 top
C626 "10nF" "CAP 0201/0603 KK" 175.078,165.493 r90 top
C627 "100nF" "CAP 0201/0603 KK" 198.476,308.864 r90 bottom
C628 "470nF" "CAP 0402/1005 KK" 180.581,308.817 r90 bottom
C629 "100nF" "CAP 0201/0603 KK" 197.104,304.165 r90 bottom
C630 "470nF" "CAP 0402/1005 KK" 176.39,302.031 r90 bottom
C631 "10uF" "CAP 0603/1608 RF" 199.567,300.723 r180 bottom
C632 "470nF" "CAP 0402/1005 KK" 177.902,306.54 r0 bottom
C633 "3nF" "CAP 0402/1005 KK" 93.442,247.284 r180 top
C634 "330pF" "CAP 0402/1005 KK" 60.847,236.129 r270 bottom
C635 "6.8nF" "CAP 0402/1005 KK" 59.901,236.129 r270 bottom
C636 "3nF" "CAP 0402/1005 KK" 93.332,224.031 r180 top
C637 "1.2nF" "CAP 0402/1005 KK" 87.909,190.2 r270 top
C638 "1.2nF" "CAP 0402/1005 KK" 89.332,174.38 r270 top
C639 "47nF" "CAP 0402/1005 KK" 66.141,183.759 r270 top
C640 "47nF" "CAP 0402/1005 KK" 66.161,175.503 r90 top
C641 "470pF" "CAP 0402/1005 KK" 64.175,175.557 r90 top
C642 "56pF" "CAP 0402/1005 KK" 64.175,183.66 r270 top
C643 "8.2nF" "CAP 0402/1005 KK" 63.51,173.949 r180 top
C644 "820pF" "CAP 0402/1005 KK" 63.565,185.176 r180 top
C645 "1.2nF" "CAP 0402/1005 KK" 88.354,202.857 r180 top
C646 "1.2nF" "CAP 0402/1005 KK" 84.112,207.488 r0 top
C647 "47nF" "CAP 0402/1005 KK" 63.953,210.654 r270 top
C648 "47nF" "CAP 0402/1005 KK" 63.741,202.373 r90 top
C649 "100nF" "CAP 0402/1005 KK" 170.726,320.189 r90 bottom
C650 "180pF" "CAP 0402/1005 KK" 62.828,202.374 r90 top
C651 "100nF" "CAP 0402/1005 KK" 171.635,320.189 r90 bottom
C652 "2.2nF" "CAP 0402/1005 KK" 61.925,200.059 r90 top
C653 "100nF" "CAP 0402/1005 KK" 141.944,313.674 r180 top
C654 "100nF" "CAP 0402/1005 KK" 114.383,247.123 r270 top
C655 "5.6nF" "CAP 0402/1005 KK" 105.362,254.83 r0 top
C656 "5.6nF" "CAP 0402/1005 KK" 99.88,254.796 r0 top
C657 "5.6nF" "CAP 0402/1005 KK" 93.466,253.617 r0 top
C658 "100nF" "CAP 0402/1005 KK" 259.121,219.018 r0 top
C659 "4.7uF" "CAP 0603/1608 RF" 243.891,217.341 r270 top
C660 "100nF" "CAP 0402/1005 KK" 245.47,216.675 r270 top
C661 "4.7uF" "CAP 0603/1608 RF" 247.434,220.815 r270 top
C662 "100nF" "CAP 0402/1005 KK" 246.235,220.713 r270 top
C663 "27pF" "CAP 0402/1005 KK" 253.801,215.824 r0 top
C664 "27pF" "CAP 0402/1005 KK" 253.712,221.171 r180 top
C665 "100nF" "CAP 0402/1005 KK" 253.081,211.766 r180 top
C666 "100nF" "CAP 0402/1005 KK" 243.803,198.075 r90 top
C667 "100nF" "CAP 0402/1005 KK" 240.851,216.778 r270 top
C668 "100nF" "CAP 0402/1005 KK" 237.8,199.095 r0 top
C669 "100nF" "CAP 0402/1005 KK" 237.8,198.151 r0 top
C670 "100nF" "CAP 0402/1005 KK" 238.019,211.789 r0 top
C671 "100nF" "CAP 0402/1005 KK" 237.999,212.902 r0 top
C672 "Capacitor_1210" CAPC3326X17L 258.076,158.642 r90 bottom
C673 "100nF" "CAP 0402/1005 KK" 252.606,198.947 r90 top
C674 "4.7uF" "CAP 0402/1005 KK" 134.297,233.837 r180 top
C675 "4.7uF" "CAP 0402/1005 KK" 134.297,235.893 r180 top
C676 "4.7uF" "CAP 0402/1005 KK" 125.32,235.477 r90 top
C677 "100nF" "CAP 0402/1005 KK" 141.944,314.574 r180 top
C678 "100uF" "CAP 1206/3216" 200.596,159.284 r90 top
C679 "100uF" "CAP 1206/3216" 197.637,159.208 r90 top
C680 "1uF" "CAP 0402/1005 KK" 198.895,177.56 r180 top
C682 "100nF" "CAP 0402/1005 KK" 158.547,329.308 r180 bottom
C684 "100nF" "CAP 0402/1005 KK" 155.645,329.26 r180 bottom
C686 "100nF" "CAP 0402/1005 KK" 171.895,285.679 r0 top
C687 "100nF" "CAP 0402/1005 KK" 171.895,283.439 r0 top
C688 "100nF" "CAP 0402/1005 KK" 168.923,285.547 r0 bottom
C689 "100nF" "CAP 0402/1005 KK" 168.923,283.375 r0 bottom
C690 "100nF" "CAP 0402/1005 KK" 151.671,218.561 r0 top
C693 "470nF" "CAP 0402/1005 KK" 39.98,209.427 r90 top
C694 "4.7uF" "CAP 0603/1608 RF" 44.911,209.097 r270 top
C695 "10uF" "CAP 0805/2012 RF" 51.294,206.694 r180 top
C696 "10uF" "CAP 0805/2012 RF" 51.294,202.914 r180 top
C697 "10uF" "CAP 0805/2012 RF" 51.294,204.804 r180 top
C698 "10uF" "CAP 0805/2012 RF" 51.294,208.585 r180 top
C699 "10uF" "CAP 0805/2012 RF" 51.294,201.023 r180 top
C700 "1uF" "CAP 0402/1005 KK" 43.152,208.104 r270 top
C701 "12nF" "CAP 0402/1005 KK" 41.097,200.511 r90 top
C702 "36pF" "CAP 0402/1005 KK" 40.17,200.511 r90 top
C703 "15nF" "CAP 0402/1005 KK" 42.714,204.102 r180 top
C704 "1uF" "CAP 0603/1608 RF" 39.532,198.489 r180 top
C705 "10uF" "CAP 0603/1608 RF" 200.101,309.829 r0 top
C706 "10nF" "CAP 0201/0603 KK" 182.401,283.52 r0 top
C707 "10uF" "CAP 0805/2012 RF" 147.408,283.729 r270 top
C708 "10uF" "CAP 0805/2012 RF" 147.331,280.162 r90 top
C709 "10uF" "CAP 0603/1608 RF" 157.772,281.407 r180 top
C710 "10nF" "CAP 0201/0603 KK" 155.232,279.273 r90 top
C711 "100nF" "CAP 0402/1005 KK" 149.822,277.838 r0 top
C712 "100nF" "CAP 0402/1005 KK" 149.928,285.388 r0 top
C713 "100nF" "CAP 0402/1005 KK" 116.287,351.231 r180 top
C714 "330nF" "CAP 0603/1608 RF" 119.177,351.206 r0 top
C715 "100nF" "CAP 0402/1005 KK" 141.944,316.674 r180 top
C716 "100nF" "CAP 0402/1005 KK" 141.944,317.575 r180 top
C717 "100nF" "CAP 0402/1005 KK" 168.542,320.189 r90 bottom
C718 "100nF" "CAP 0402/1005 KK" 169.451,320.189 r90 bottom
C719 "1nF" "CAP 0201/0603 KK" 128.93,231.655 r90 top
C720 "1uF" "CAP 0402/1005 KK" 146.52,349.06 r90 top
C721 "1uF" "CAP 0402/1005 KK" 147.511,349.06 r90 top
C722 "1uF" "CAP 0402/1005 KK" 153.683,349.142 r90 top
C723 "1uF" "CAP 0402/1005 KK" 154.673,349.142 r90 top
C724 "10nF" "CAP 0201/0603 KK" 203.117,292.202 r0 top
C725 "10nF" "CAP 0201/0603 KK" 203.117,291.216 r0 top
C726 "10nF" "CAP 0201/0603 KK" 136.272,307.523 r180 top
C727 "10nF" "CAP 0201/0603 KK" 136.272,306.81 r180 top
C728 "100nF" "CAP 0402/1005 KK" 205.454,288.027 r270 top
C729 "100nF" "CAP 0402/1005 KK" 202.425,288.052 r90 top
C730 "100nF" "CAP 0402/1005 KK" 156.889,299.371 r90 top
C731 "2.2uF" "CAP 0402/1005 KK" 50.629,346.841 r0 top
C732 "100nF" "CAP 0402/1005 KK" 57.413,351.663 r90 top
C733 "1uF" "CAP 0402/1005 KK" 50.404,353.09 r0 top
C734 "1uF" "CAP 0402/1005 KK" 43.346,355.908 r270 top
C735 "100nF" "CAP 0402/1005 KK" 253.772,349.783 r0 bottom
C736 "9pF" "CAP 0201/0603 KK" 57.578,355.473 r180 bottom
C737 "9pF" "CAP 0201/0603 KK" 51.613,355.841 r90 bottom
C738 "6TPE680MI" "CAP POL 2917/7343" 144.564,284.861 r270 bottom
C739 "100uF" "CAP 1210/3225 - 1MM" 149.428,293.649 r0 bottom
C740 "4.7uF" "CAP 0402/1005 KK" 179.387,295.021 r90 bottom
C741 "4.7uF" "CAP 0402/1005 KK" 162.238,286.251 r90 top
C742 "100uF" "CAP 1210/3225 - 1MM" 259.74,350.583 r0 top
C743 "4.7uF" "CAP 0402/1005 KK" 253.708,347.193 r90 top
C744 "47uF" "CAP 1206/3216 - 0.8MM" 149.441,290.157 r180 bottom
C745 "4.7uF" "CAP 0402/1005 KK" 180.911,305.537 r0 bottom
C746 "4.7uF" "CAP 0402/1005 KK" 134.297,234.865 r180 top
C747 "100uF" "CAP 1210/3225 - 1MM" 246.787,320.226 r180 top
C748 "4.7uF" "CAP 0402/1005 KK" 247.58,317.685 r0 top
C749 "47uF" "CAP 1206/3216 - 0.8MM" 155.753,285.612 r270 top
C750 "4.7uF" "CAP 0402/1005 KK" 199.749,310.883 r0 top
C751 "100uF" "CAP 1210/3225 - 1MM" 149.368,297.37 r0 bottom
C752 "4.7uF" "CAP 0402/1005 KK" 175.387,300.047 r270 bottom
C753 "100uF" "CAP 1210/3225 - 1MM" 207.67,318.29 r90 top
C754 "4.7uF" "CAP 0402/1005 KK" 206.836,314.392 r90 top
C755 "4.7uF" "CAP 0402/1005 KK" 208.534,314.392 r90 top
C756 "47uF" "CAP 1206/3216 - 0.8MM" 199.029,298.2 r180 bottom
C757 "100uF" "CAP 1210/3225 - 1MM" 158.966,285.56 r90 top
C758 "4.7uF" "CAP 0402/1005 KK" 199.749,311.734 r0 top
C759 "47uF" "CAP 1206/3216 - 0.8MM" 199.029,295.63 r180 bottom
C760 "100uF" "CAP 1210/3225 - 1MM" 200.088,347.04 r90 top
C761 "4.7uF" "CAP 0402/1005 KK" 161.332,286.273 r90 top
C762 "100uF" "CAP 1210/3225 - 1MM" 149.339,301.028 r0 bottom
C763 "4.7uF" "CAP 0402/1005 KK" 172.872,304.539 r180 bottom
C764 "100uF" "CAP 1210/3225 - 1MM" 139.573,286.207 r270 bottom
C765 "4.7uF" "CAP 0402/1005 KK" 141.681,287.236 r90 bottom
C766 "22uF" "CAP 1210/3225 - 1MM" 73.992,159.249 r270 top
C767 "22uF" "CAP 1210/3225 - 1MM" 70.524,159.25 r270 top
C768 "22uF" "CAP 1210/3225 - 1MM" 67.084,159.249 r270 top
C769 "22uF" "CAP 1210/3225 - 1MM" 63.68,159.249 r270 top
C770 "100nF" "CAP 0402/1005 KK" 38.538,159.341 r270 top
C771 "100nF" "CAP 0402/1005 KK" 37.531,159.341 r270 top
C772 "100nF" "CAP 0402/1005 KK" 36.624,159.341 r270 top
C773 "100nF" "CAP 0402/1005 KK" 35.693,159.341 r270 top
C774 "10uF" "CAP 0805/2012 RF" 51.366,221.852 r0 top
C775 "10uF" "CAP 0805/2012 RF" 51.366,220.038 r0 top
C776 "10uF" "CAP 0805/2012 RF" 51.366,218.215 r0 top
C777 "10uF" "CAP 0805/2012 RF" 51.366,216.47 r0 top
C778 "4.7uF" "CAP 0805/2012 RF" 51.366,214.657 r0 top
C779 "4.7uF" "CAP 0805/2012 RF" 51.366,212.847 r0 top
C780 "4.7uF" "CAP 0805/2012 RF" 51.366,210.952 r0 top
C781 "4.7uF" "CAP 0805/2012 RF" 56.629,197.434 r90 top
C782 "4.7uF" "CAP 0402/1005 KK" 198.382,341.029 r270 top
C783 "100nF" "CAP 0402/1005 KK" 186.552,339.598 r0 top
C784 "4.7uF" "CAP 0402/1005 KK" 198.044,330.285 r270 top
C785 "100nF" "CAP 0402/1005 KK" 162.91,340.36 r0 top
C786 "4.7uF" "CAP 0402/1005 KK" 174.91,328.509 r180 top
C787 "100nF" "CAP 0402/1005 KK" 208.94,329.209 r270 top
C788 "4.7uF" "CAP 0402/1005 KK" 174.995,341.202 r0 top
C789 "100nF" "CAP 0402/1005 KK" 186.669,328.509 r180 top
C790 "100nF" "CAP 0402/1005 KK" 255.918,348.377 r90 bottom
C791 "100nF" "CAP 0402/1005 KK" 213.222,209.005 r90 top
C792 "100nF" "CAP 0402/1005 KK" 211.632,208.702 r0 top
C793 "100nF" "CAP 0402/1005 KK" 153.886,299.371 r90 top
C796 "100nF" "CAP 0402/1005 KK" 166.292,281.724 r270 top
C797 "100nF" "CAP 0402/1005 KK" 198.12,273.745 r270 top
C798 "100nF" "CAP 0402/1005 KK" 196.901,290.539 r90 top
C799 "100nF" "CAP 0402/1005 KK" 194.107,290.539 r270 top
C800 "100nF" "CAP 0402/1005 KK" 177.08,272.854 r180 bottom
C801 "100nF" "CAP 0402/1005 KK" 249.53,353.301 r0 top
C802 "100nF" "CAP 0402/1005 KK" 249.53,356.121 r180 top
C805 "100nF" "CAP 0402/1005 KK" 202.864,272.261 r90 top
C806 "100nF" "CAP 0402/1005 KK" 205.677,272.263 r270 top
C807 "100nF" "CAP 0402/1005 KK" 204.655,268.186 r90 top
C808 "100nF" "CAP 0402/1005 KK" 207.582,268.186 r270 top
C811 "100nF" "CAP 0402/1005 KK" 198.265,267.068 r90 top
C812 "100nF" "CAP 0402/1005 KK" 201.031,267.068 r270 top
C813 "100nF" "CAP 0402/1005 KK" 224.207,275.386 r270 bottom
C814 "100nF" "CAP 0402/1005 KK" 226.996,275.386 r90 bottom
C817 "100nF" "CAP 0402/1005 KK" 153.145,268.503 r270 top
C818 "100nF" "CAP 0402/1005 KK" 150.356,268.503 r90 top
C819 "100nF" "CAP 0402/1005 KK" 166.967,286.131 r0 top
C820 "100nF" "CAP 0402/1005 KK" 166.967,284.036 r0 top
D1 "SLVU2.8-4BTG TVS Array" SLVU2.8-4 65.278,250.254 r180 top
D2 "SLVU2.8-4BTG TVS Array" SLVU2.8-4 65.278,256.337 r180 top
D3 "DF01S2" "DF005S2 - DF10S2" 44.298,228.282 r90 bottom locked
D4 "DF01S2" "DF005S2 - DF10S2" 34.43,228.346 r90 bottom locked
D5 "LTST-C190GKT" "LED 0603/1608 GREEN" 192.916,363.868 r0 bottom
D6 "LTST-C190GKT" "LED 0603/1608 GREEN" 192.916,361.831 r0 bottom
D7 "LTST-C190GKT" "LED 0603/1608 GREEN" 192.916,360.007 r0 bottom
D8 "LTST-C190GKT" "LED 0603/1608 GREEN" 192.916,356.362 r0 bottom
D9 "LTST-C190GKT" "LED 0603/1608 GREEN" 192.916,358.229 r180 bottom
D10 "LTST-C190GKT" "LED 0603/1608 GREEN" 239.044,162.789 r0 top
D11 "BAT54T1G" BAT54T1G 252.92,162.598 r180 bottom
D12 "BAT54T1G" BAT54T1G 252.92,160.333 r0 bottom
D13 "TPD2EUSB30DRTR" TPD2EUSB30 41.148,350.698 r0 bottom
D14 "TPD4EUSB30DQAR" TPD4EUSB30 42.291,350.761 r180 top
D15 "TPD2EUSB30DRTR" TPD2EUSB30 265.066,163.39 r270 top
D16 "MBRM140T3" "CASE 457" 166.424,166.813 r0 top
D17 "MBRM140T3" "CASE 457" 166.423,170.7 r0 top
D18 "MBRM140T3" "CASE 457" 169.724,175.069 r0 top
D19 "MBRM140T3" "CASE 457" 169.724,161.863 r0 top
D20 "S1M-13-F" S1M-13-F 211.142,172.137 r90 top
D21 "S1M-13-F" S1M-13-F 193.826,165.452 r180 top
D22 "LTST-C190GKT" "LED 0603/1608 GREEN" 127.781,178.273 r270 bottom
D23 "S1M-13-F" S1M-13-F 193.826,165.952 r0 bottom
D24 "S1M-13-F" S1M-13-F 193.954,169.495 r0 bottom
D25 "LTST-C190GKT" "LED 0603/1608 GREEN" 107.374,178.273 r270 bottom
D26 "DFLS1100-7" DFLS1100 34.353,210.071 r270 top
D27 "DFLS1100-7" DFLS1100 44.666,214.084 r270 top
D28 "BAS40-04-TP" BAS40-04-TP 234.92,322.199 r180 top
D29 "LTST-C190GKT" "LED 0603/1608 GREEN" 124.379,178.273 r270 bottom
D30 "LTST-C190GKT" "LED 0603/1608 GREEN" 93.769,178.273 r270 bottom
D31 "LTST-C190GKT" "LED 0603/1608 GREEN" 120.978,178.273 r270 bottom
D32 "LTST-C190GKT" "LED 0603/1608 GREEN" 142.113,162.849 r270 bottom
D33 "LTST-C190GKT" "LED 0603/1608 GREEN" 103.973,178.273 r270 bottom
D34 "LTST-C190GKT" "LED 0603/1608 GREEN" 90.368,178.273 r270 bottom
D35 "LTST-C190GKT" "LED 0603/1608 GREEN" 117.577,178.273 r270 bottom
D36 "LTST-C190GKT" "LED 0603/1608 GREEN" 138.253,162.849 r270 bottom
D37 "LTST-C190GKT" "LED 0603/1608 GREEN" 100.572,178.273 r270 bottom
D38 "LTST-C190GKT" "LED 0603/1608 GREEN" 86.967,178.273 r270 bottom
D39 "LTST-C190GKT" "LED 0603/1608 GREEN" 114.176,178.273 r270 bottom
D40 "LTST-C190GKT" "LED 0603/1608 GREEN" 134.393,162.849 r270 bottom
D41 "LTST-C190GKT" "LED 0603/1608 GREEN" 97.17,178.273 r270 bottom
D42 "LTST-C190GKT" "LED 0603/1608 GREEN" 83.566,178.273 r270 bottom
D43 "LTST-C190GKT" "LED 0603/1608 GREEN" 110.775,178.273 r270 bottom
D44 "LTST-C190GKT" "LED 0603/1608 GREEN" 130.533,162.849 r270 bottom
D45 "LTST-C190GKT" "LED 0603/1608 GREEN" 199.67,402.046 r180 bottom
D46 "LTST-C190GKT" "LED 0603/1608 GREEN" 117.11,387.544 r90 bottom
D47 "LTST-C190GKT" "LED 0603/1608 GREEN" 117.138,395.67 r90 bottom
D48 "LTST-C190GKT" "LED 0603/1608 GREEN" 117.27,439.511 r180 bottom
D49 "LTST-C190GKT" "LED 0603/1608 GREEN" 42.303,363.294 r0 bottom
D50 "LTST-C190GKT" "LED 0603/1608 GREEN" 115.316,249.187 r90 bottom
D51 "LTST-C190GKT" "LED 0603/1608 GREEN" 199.62,395.631 r180 bottom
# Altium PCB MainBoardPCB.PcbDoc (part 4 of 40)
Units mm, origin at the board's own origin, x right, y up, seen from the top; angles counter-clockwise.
Board outline 258.95 x 308.86 mm, 16 copper layers (L1, L2 (GND), L3 (Sign), L4 (GND), L5 (Sign), L6 (PWR/GND), L7(12V+Other), L8 (Plane_GND), L9 (PWR/GND), L10 (3V3+Other), L11 (PWR/GND), L12 (Sign), L13 (GND), L14 (Sign), L15 (GND), L16), stack 2.503 mm thick; 2578 components, 1867 nets, 8817 pads, 8021 vias.
Unrouted connection lines stored in the file: 25.

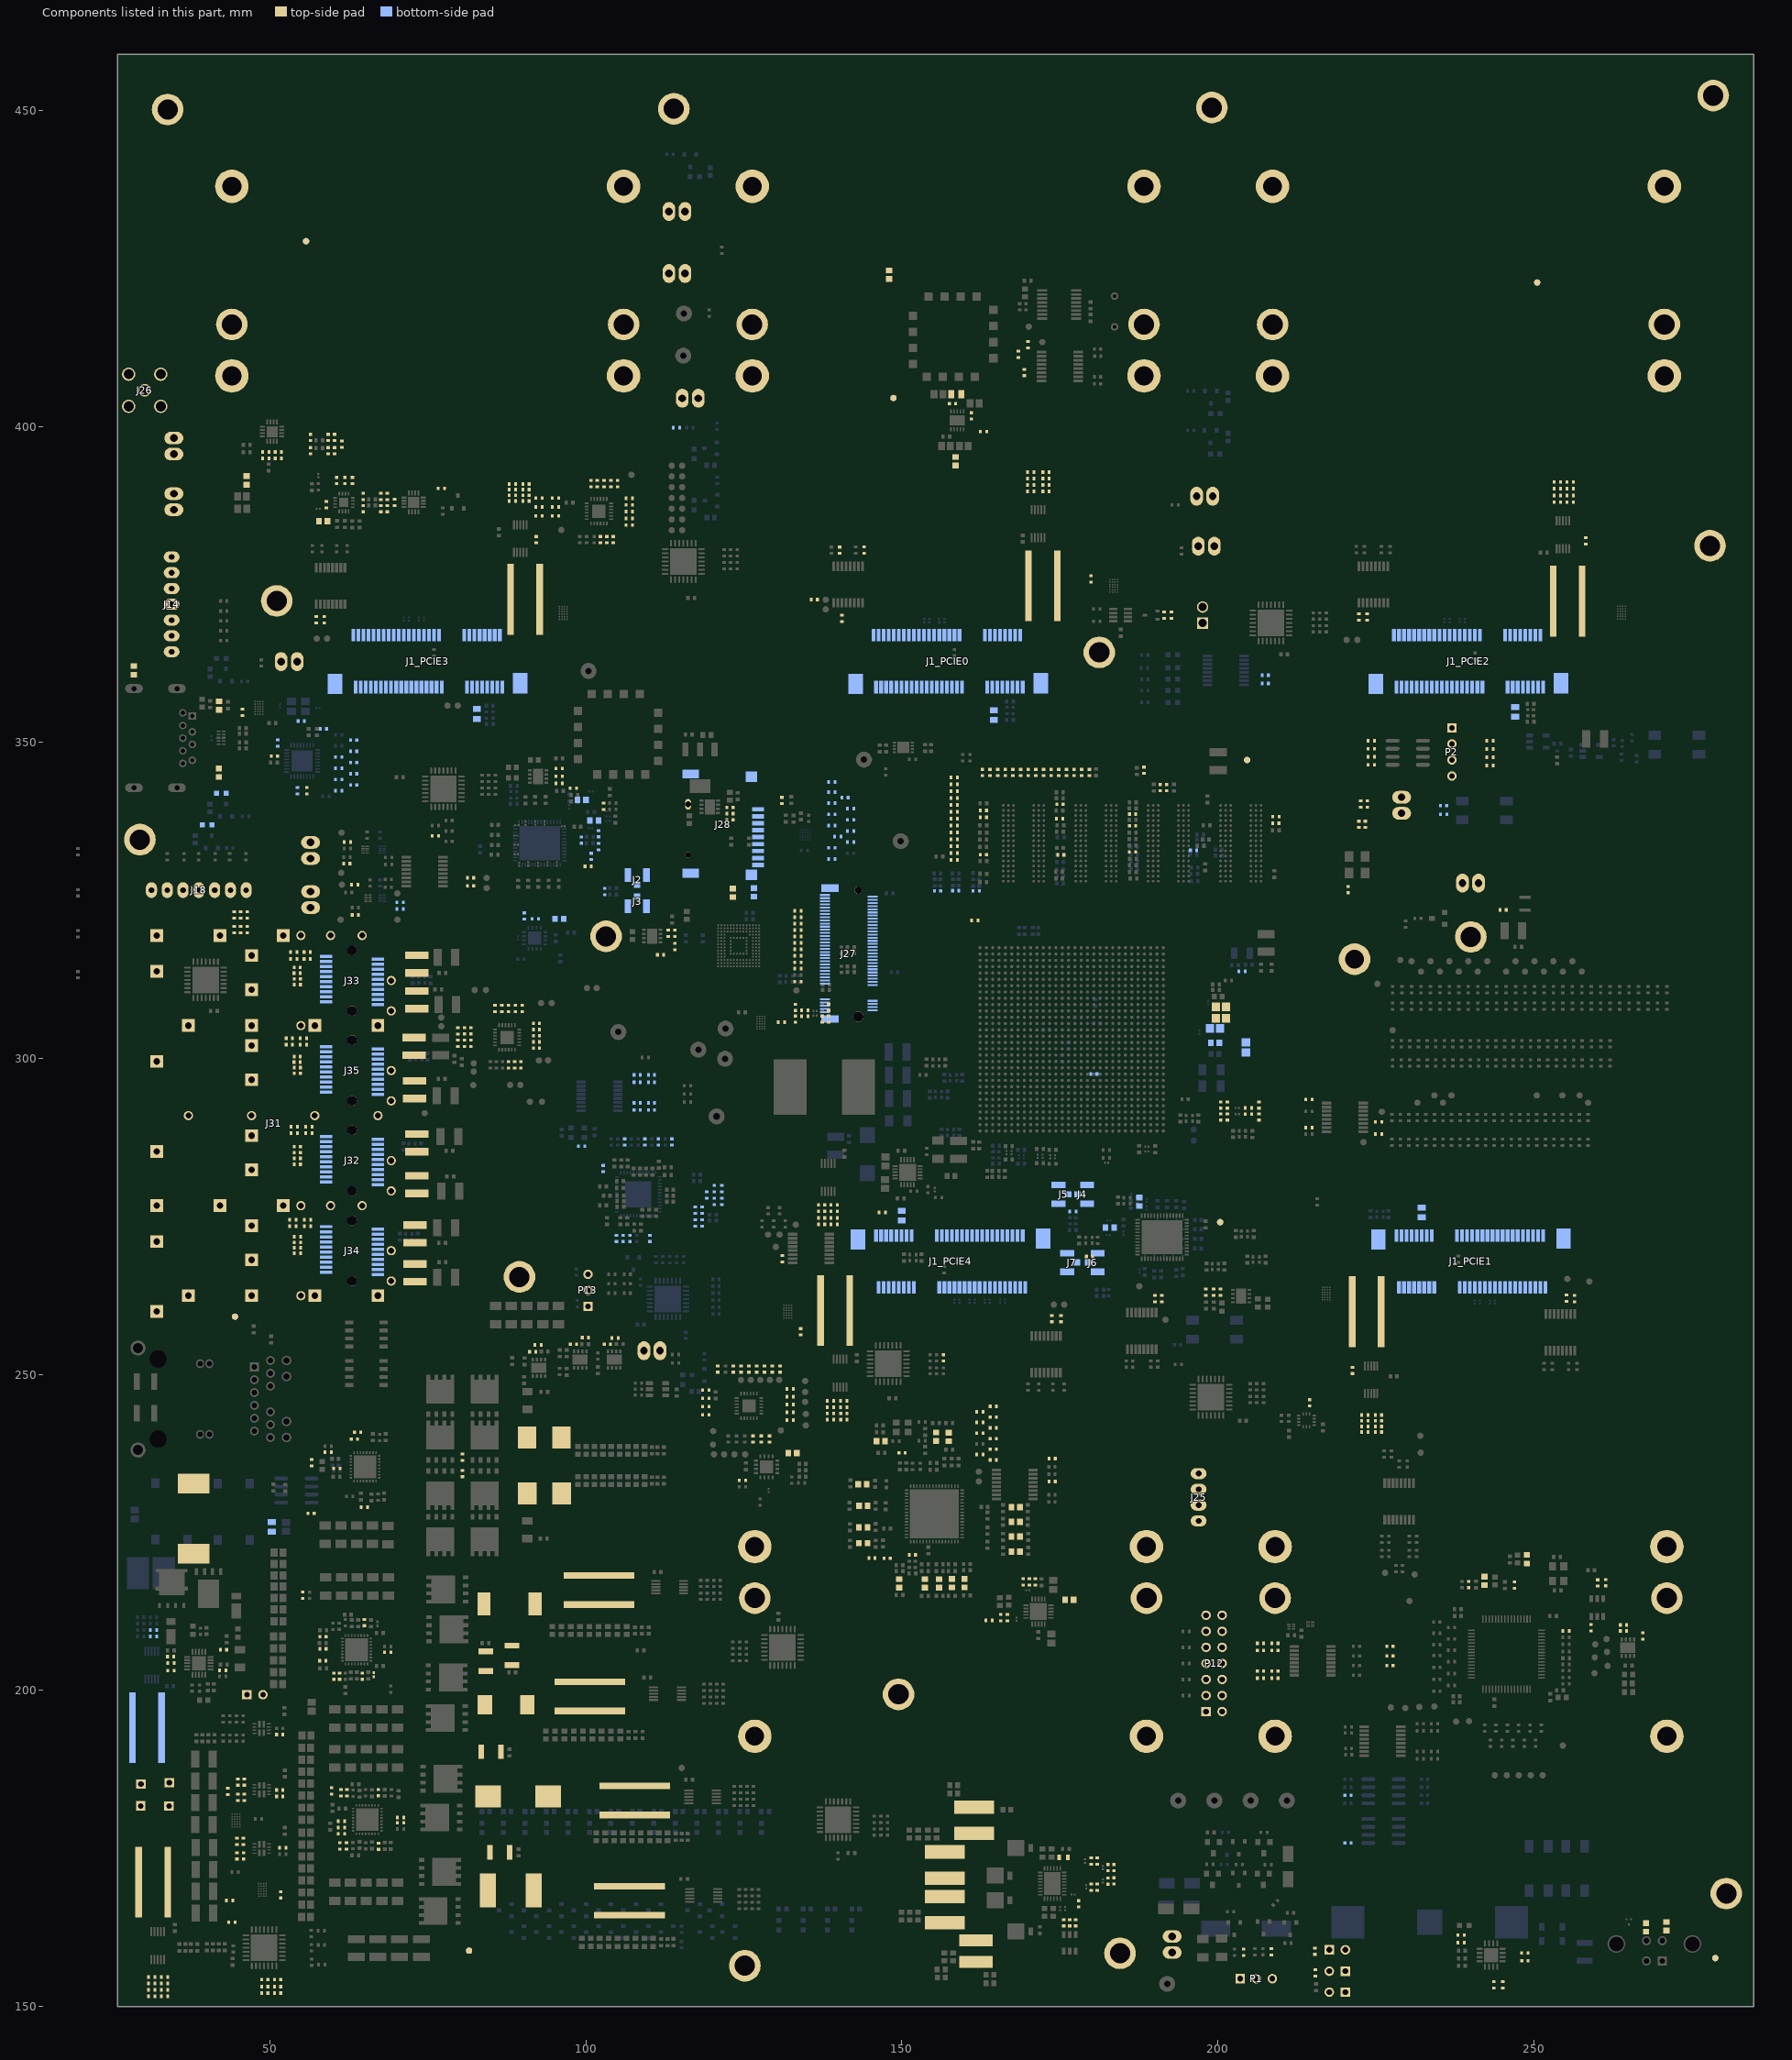
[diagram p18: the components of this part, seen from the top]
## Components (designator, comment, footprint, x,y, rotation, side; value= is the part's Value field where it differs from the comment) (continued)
D52 "LTST-C190GKT" "LED 0603/1608 GREEN" 40.071,337.002 r0 bottom
D53 "LTST-C190GKT" "LED 0603/1608 GREEN" 42.328,341.983 r0 bottom
F1_PCIE0 "" "RES 0805/2012 RF" 164.592,354.335 r270 bottom (schematic designator F1)
F1_PCIE1 "" "RES 0805/2012 RF" 232.29,275.661 r90 bottom (schematic designator F1)
F1_PCIE2 "" "RES 0805/2012 RF" 247.088,354.867 r270 bottom (schematic designator F1)
F1_PCIE3 "" "RES 0805/2012 RF" 82.785,354.533 r270 bottom (schematic designator F1)
F1_PCIE4 "" "RES 0805/2012 RF" 149.974,275.125 r90 bottom (schematic designator F1)
FB3 "220R" "FER 0603/1608" 101.324,337.682 r180 bottom
FB5 "220R" "FER 0603/1608" 182.928,273.241 r0 bottom
FB6 "220R" "FER 0603/1608" 99.355,340.914 r180 bottom
FB7 "220R" "FER 0603/1608" 187.623,277.325 r270 bottom
FB8 "220R" "FER 0603/1608" 149.588,216.951 r90 top
FB9 "220R" "FER 0603/1608" 168.044,229.023 r180 top
FB10 "220R" "FER 0603/1608" 159.938,216.978 r90 top
FB11 "220R" "FER 0603/1608" 143.924,229.212 r0 top
FB12 "220R" "FER 0603/1608" 157.915,216.978 r90 top
FB13 "220R" "FER 0603/1608" 143.794,232.658 r0 top
FB14 "220R" "FER 0603/1608" 153.67,216.951 r90 top
FB15 "220R" "FER 0603/1608" 157.404,240.127 r270 top
FB16 "220R" "FER 0603/1608" 168.044,224.348 r180 top
FB17 "220R" "FER 0603/1608" 155.435,240.157 r270 top
FB18 "220R" "FER 0603/1608" 168.044,226.695 r180 top
FB19 "220R" "FER 0603/1608" 168.044,221.996 r180 top
FB20 "220R" "FER 0603/1608" 143.902,225.818 r0 top
FB21 "220R" "FER 0603/1608" 155.893,216.951 r90 top
FB22 "220R" "FER 0603/1608" 143.902,223.318 r0 top
FB23 "Ferrite Chip" "FER 0603/1608" 46.321,391.484 r90 top
FB24 "Ferrite Chip" "FER 0603/1608" 58.43,385.003 r0 top
FB25 "Ferrite Chip" "FER 0603/1608" 123.254,326.206 r270 top
FB26 "220R" "FER 0603/1608" 41.948,355.864 r270 top
FB27 "220R" "FER 0603/1608" 41.93,345.237 r90 top
FB28 "220R" "FER 0603/1608" 28.49,361.426 r270 top
FB29 "220R" "FER 0603/1608" 126.606,326.288 r270 bottom
FB31 "220R" "FER 0603/1608" 267.792,162.515 r270 top
FB32 "220R" "FER 0603/1608" 271.043,162.693 r270 top
FB33 "120R" "FER 0603/1608" 95.822,322.11 r0 bottom
FB34 "330R" "FER 0603/1608" 158.498,394.509 r90 top
FB35 "220R" "FER 0603/1608" 147.991,424.028 r90 top
FB36 "220R" "FER 0603/1608" 176.517,214.363 r180 top
FB37 "220R" "FER 0603/1608" 146.695,239.444 r180 top
FB38 "600R" "FER 0805/2012" 200.507,308.178 r180 top
FB39 "600R" "FER 0805/2012" 200.507,306.362 r180 top
FB40 "600R" "FER 0805/2012" 199.579,304.749 r180 bottom
FB41 "600R" "FER 0805/2012" 204.466,301.765 r90 bottom
FB42 "120R" "FER 0603/1608" 199.593,302.489 r180 bottom
FB43 "220R" "FER 0603/1608" 242.221,217.341 r270 top
FB44 "220R" "FER 0603/1608" 248.933,220.777 r270 top
FB45 "120R" "FER 0603/1608" 132.702,237.553 r0 top
FID1 "Fiducials" Fiducials 81.526,158.834 r0 top
FID2 "Fiducials" Fiducials 148.691,404.514 r0 top
FID3 "Fiducials" Fiducials 55.728,429.323 r0 top
FID4 "Fiducials" Fiducials 250.564,422.796 r0 top
FID5 "Fiducials" Fiducials 278.757,157.657 r0 top
FID6 "Fiducials" Fiducials 200.395,274.107 r0 top
FID7 "Fiducials" Fiducials 204.659,347.243 r0 top
FID8 "Fiducials" Fiducials 44.475,259.156 r0 top
J1_PCIE0 "2041262-1" "PCI Express / PCI Connectors Mini PCI-E 6.8H G/F" 161.187,362.892 r180 bottom locked (schematic designator J1)
J1_PCIE1 "2041262-1" "PCI Express / PCI Connectors Mini PCI-E 6.8H G/F" 236.24,267.894 r0 bottom locked (schematic designator J1)
J1_PCIE2 "2041262-1" "PCI Express / PCI Connectors Mini PCI-E 6.8H G/F" 243.54,362.892 r180 bottom locked (schematic designator J1)
J1_PCIE3 "2041262-1" "PCI Express / PCI Connectors Mini PCI-E 6.8H G/F" 78.835,362.892 r180 bottom locked (schematic designator J1)
J1_PCIE4 "2041262-1" "PCI Express / PCI Connectors Mini PCI-E 6.8H G/F" 153.887,267.894 r0 bottom locked (schematic designator J1)
J2 "1909763-1" TECO-1909763-1_V 108.134,329.028 r180 bottom
J3 "1909763-1" TECO-1909763-1_V 108.134,324.087 r0 bottom
J4 "1909763-1" TECO-1909763-1_V 179.345,278.518 r90 bottom
J5 "1909763-1" TECO-1909763-1_V 174.806,278.518 r270 bottom
J6 "1909763-1" TECO-1909763-1_V 180.995,267.716 r90 bottom
J7 "1909763-1" TECO-1909763-1_V 176.174,267.716 r270 bottom
J12 "MOLEX - 22-27-2021 - WIRE-BOARD CONNECTOR HEADER 2 POSITION, 2.54MM" "MOLEX KK 0022272021" 56.439,332.93 r270 bottom
J13 "MOLEX - 22-27-2021 - WIRE-BOARD CONNECTOR HEADER 2 POSITION, 2.54MM" "MOLEX KK 0022272021" 56.446,325.158 r270 bottom
J14 "7 Pin" "JST XH B7B-XH-A" 34.455,371.876 r270 bottom
J15 "MOLEX - 22-27-2021 - WIRE-BOARD CONNECTOR HEADER 2 POSITION, 2.54MM" "MOLEX KK 0022272021" 197.942,388.976 r180 bottom
J16 "MOLEX - 22-27-2021 - WIRE-BOARD CONNECTOR HEADER 2 POSITION, 2.54MM" "MOLEX KK 0022272021" 116.535,404.482 r180 bottom
J17 "MOLEX - 22-27-2021 - WIRE-BOARD CONNECTOR HEADER 2 POSITION, 2.54MM" "MOLEX KK 0022272021" 114.427,424.222 r0 bottom
J18 "7 Pin" "JST XH B7B-XH-A" 38.757,326.657 r0 bottom
J19 "MOLEX - 22-27-2021 - WIRE-BOARD CONNECTOR HEADER 2 POSITION, 2.54MM" "MOLEX KK 0022272021" 114.427,434.037 r0 bottom
J20 "MOLEX - 22-27-2021 - WIRE-BOARD CONNECTOR HEADER 2 POSITION, 2.54MM" "MOLEX KK 0022272021" 53.048,362.814 r180 bottom
J21 "MOLEX - 22-27-2021 - WIRE-BOARD CONNECTOR HEADER 2 POSITION, 2.54MM" "MOLEX KK 0022272021" 110.477,253.771 r0 bottom
J22 "MOLEX - 22-27-2021 - WIRE-BOARD CONNECTOR HEADER 2 POSITION, 2.54MM" "MOLEX KK 0022272021" 198.196,381.074 r180 bottom
J23 "MOLEX - 22-27-2021 - WIRE-BOARD CONNECTOR HEADER 2 POSITION, 2.54MM" "MOLEX KK 0022272021" 34.799,388.112 r270 bottom
J24 "MOLEX - 22-27-2021 - WIRE-BOARD CONNECTOR HEADER 2 POSITION, 2.54MM" "MOLEX KK 0022272021" 34.799,396.913 r270 bottom
J25 "JST (JAPAN SOLDERLESS TERMINALS) - B4B-XH-A (LF)(SN) - Wire-To-Board-Steckverbinder, vertikal, 2.5 mm, 4 Kontakt(e), Stiftleiste, Baureihe XH" "JST XH B4B-XH-A" 196.986,230.585 r90 bottom
J26 "5-1814832-1" TECO-5-1814832-1_V 30.188,405.74 r270 bottom
J27 "Key M-SATA CHINA" "M.2 KEY M - NVMe" 141.668,316.624 r270 bottom locked
J28 "693071020811" 693071020811 119.487,337.182 r90 bottom locked
J29 "SYSMON_VP_VN" "MOLEX KK 0022272021" 240.017,327.762 r180 bottom
J30 "SYSMON_VP_VN" "MOLEX KK 0022272021" 229.108,340.081 r270 bottom
J31 "SFP Connector" 2007132 37.104,262.472 r90 bottom locked
J32 "1703820001" 1703820001 63.005,279.047 r90 bottom locked
J33 "1703820001" 1703820001 63.005,307.547 r90 bottom locked
J34 "1703820001" 1703820001 63.005,264.797 r90 bottom locked
J35 "1703820001" 1703820001 63.004,293.297 r90 bottom locked
J36 "MOLEX - 22-27-2021 - WIRE-BOARD CONNECTOR HEADER 2 POSITION, 2.54MM" "MOLEX KK 0022272021" 192.799,159.817 r270 bottom
L1 "NRS4018T4R7MDGJV" NRS8040 73.226,286.66 r270 top
L2 "NRS4018T4R7MDGJV" NRS8040 73.226,280.047 r90 top
L3 "NRS4018T4R7MDGJV" NRS8040 73.226,314.947 r270 top
L4 "NRS4018T4R7MDGJV" NRS8040 73.226,309.271 r90 top
L5 "NRS4018T4R7MDGJV" NRS8040 72.948,272.256 r270 top
L6 "NRS4018T4R7MDGJV" NRS8040 72.948,266.086 r90 top
L7 "NRS4018T4R7MDGJV" NRS8040 72.812,301.927 r270 top
L8 "NRS4018T4R7MDGJV" NRS8040 72.876,295.081 r90 top
L9 "MGV0605R22M-10" MGV0605 93.417,240.05 r0 top
L10 "MGV0605R22M-10" MGV0605 93.442,231.202 r0 top
L11 "MGV10041R2M-10" "MGV1004 Series" 89.295,183.236 r0 top
L12 "744373560068" 744373560068 88.108,168.37 r0 top
L13 "CDRH5D28-8R2" CDRH5D28 156.819,165.326 r270 top
L15 "" FB0603 175.603,173.617 r0 top
L16 "CDRH5D28-4R2" CDRH5D28 156.819,172.367 r90 top
L17 "CDRH5D28-8R2" CDRH5D28 161.461,179.472 r90 top
L18 "CDRH4D28NP-3R3NC" CDRH4D28NP 161.768,158.743 r270 top
L19 "3.3uH, 13.8A" WE-CHSA_1011 87.928,213.721 r0 top
L20 "1.5 uH, 16.5 A" WE-HCC_8070 87.389,197.752 r0 top
L22 "SRP1265A-220M" SRP1265A-220M 37.948,227.19 r90 top locked
MH1 "MH_5_3.2" MH_5_3.2_SUB_VIA 103.206,319.341 r0 top
MH2 "MH_5_3.2" MH_5_3.2_SUB_VIA 240.061,319.242 r0 top
MH3 "MH_5_3.2" MH_5_3.2_SUB_VIA 280.492,167.869 r0 top
MH4 "MH_5_3.2" MH_5_3.2_SUB_VIA 184.544,158.42 r0 top
MH5 "MH_5_3.2" MH_5_3.2_SUB_VIA 149.492,199.39 r0 top
MH6 "MH_5_3.2" MH_5_3.2_SUB_VIA 125.173,156.451 r0 top
MH7 "MH_5_3.2" MH_5_3.2_SUB_VIA 89.497,265.449 r0 top
MH8 "MH_5_3.2" MH_5_3.2_SUB_VIA 33.82,450.177 r0 top
MH9 "MH_5_3.2" MH_5_3.2_SUB_VIA 51.093,372.428 r0 top
MH10 "MH_5_3.2" MH_5_3.2_SUB_VIA 29.426,334.645 r0 top
MH11 "MH_5_3.2" MH_5_3.2_SUB_VIA 43.985,416.166 r0 top
MH12 "MH_5_3.2" MH_5_3.2_SUB_VIA 105.985,416.166 r0 top
MH13 "MH_5_3.2" MH_5_3.2_SUB_VIA 126.337,416.166 r0 top
MH14 "MH_5_3.2" MH_5_3.2_SUB_VIA 188.337,416.166 r0 top
MH15 "MH_5_3.2" MH_5_3.2_SUB_VIA 208.69,416.166 r0 top
MH16 "MH_5_3.2" MH_5_3.2_SUB_VIA 270.69,416.166 r0 top
MH17 "MH_5_3.2" MH_5_3.2_SUB_VIA 126.737,214.62 r0 top
MH18 "MH_5_3.2" MH_5_3.2_SUB_VIA 188.737,214.62 r0 top
MH19 "MH_5_3.2" MH_5_3.2_SUB_VIA 209.09,214.62 r0 top
MH20 "MH_5_3.2" MH_5_3.2_SUB_VIA 271.09,214.62 r0 top
MH21 "MH_5_3.2" MH_5_3.2_SUB_VIA 113.932,450.279 r0 top
MH22 "MH_5_3.2" MH_5_3.2_SUB_VIA 199.072,450.482 r0 top
MH23 "MH_5_3.2" MH_5_3.2_SUB_VIA 278.422,452.375 r0 top
MH24 "MH_5_3.2" MH_5_3.2_SUB_VIA 277.914,381.14 r0 top
MH25 "MH_5_3.2" MH_5_3.2_SUB_VIA 181.262,364.262 r0 top
MP1_PCIE0 "M2x4.5mm" "9774045243 - dual side copper" 126.337,408.024 r90 bottom (schematic designator MP1)
MP1_PCIE1 "M2x4.5mm" "9774045243 - dual side copper" 271.09,222.762 r90 bottom (schematic designator MP1)
MP1_PCIE2 "M2x4.5mm" "9774045243 - dual side copper" 208.69,408.024 r90 bottom (schematic designator MP1)
MP1_PCIE3 "M2x4.5mm" "9774045243 - dual side copper" 43.985,408.024 r90 bottom (schematic designator MP1)
MP1_PCIE4 "M2x4.5mm" "9774045243 - dual side copper" 188.737,222.762 r90 bottom (schematic designator MP1)
MP2_PCIE0 "M2x4.5mm" "9774045243 - dual side copper" 126.337,438.024 r90 bottom (schematic designator MP2)
MP2_PCIE1 "M2x4.5mm" "9774045243 - dual side copper" 271.09,192.762 r90 bottom (schematic designator MP2)
MP2_PCIE2 "M2x4.5mm" "9774045243 - dual side copper" 208.69,438.024 r90 bottom (schematic designator MP2)
MP2_PCIE3 "M2x4.5mm" "9774045243 - dual side copper" 43.985,438.024 r90 bottom (schematic designator MP2)
MP2_PCIE4 "M2x4.5mm" "9774045243 - dual side copper" 188.737,192.762 r90 bottom (schematic designator MP2)
MP3_PCIE0 "M2x4.5mm" "9774045243 - dual side copper" 188.337,438.024 r90 bottom (schematic designator MP3)
MP3_PCIE1 "M2x4.5mm" "9774045243 - dual side copper" 209.09,192.762 r90 bottom (schematic designator MP3)
MP3_PCIE2 "M2x4.5mm" "9774045243 - dual side copper" 270.69,438.024 r90 bottom (schematic designator MP3)
MP3_PCIE3 "M2x4.5mm" "9774045243 - dual side copper" 105.985,438.024 r90 bottom (schematic designator MP3)
MP3_PCIE4 "M2x4.5mm" "9774045243 - dual side copper" 126.737,192.762 r90 bottom (schematic designator MP3)
MP4_PCIE0 "M2x4.5mm" "9774045243 - dual side copper" 188.337,408.024 r90 bottom (schematic designator MP4)
MP4_PCIE1 "M2x4.5mm" "9774045243 - dual side copper" 209.09,222.762 r90 bottom (schematic designator MP4)
MP4_PCIE2 "M2x4.5mm" "9774045243 - dual side copper" 270.69,408.024 r90 bottom (schematic designator MP4)
MP4_PCIE3 "M2x4.5mm" "9774045243 - dual side copper" 105.985,408.024 r90 bottom (schematic designator MP4)
MP4_PCIE4 "M2x4.5mm" "9774045243 - dual side copper" 126.737,222.762 r90 bottom (schematic designator MP4)
MP5 "M2x2.5mm" 9774025243 221.669,315.724 r180 bottom
P1 "Header 3" HDR1X3 203.568,154.407 r0 bottom
P2 "Header 4" HDR1X4 237.071,352.323 r270 top
P3 "Header 2" HDR1X2 220.209,155.588 r180 top
P4 "Header 2" HDR1X2 217.669,158.979 r0 top
P5 "Header 2" HDR1X2 220.209,152.273 r180 top
P6 "640456-2" TECO-640456-2_V 197.613,370.167 r270 bottom
P7 "Plug" PIN1 34.034,181.709 r0 top
P8 "Plug" PIN1 29.564,181.734 r0 top
P9 "Plug" PIN1 34.092,185.417 r0 top
P10 "Plug" PIN1 29.583,185.201 r0 top
P11 "Header 2" HDR1X2 46.368,199.339 r0 top
P12 "Header 7X2" HDR2X7 198.171,196.669 r90 bottom
P13 "Header 3" HDR1X3 100.343,260.782 r90 bottom
R1 "0mR" "RES 0402/1005 RF KK" 164.501,243.256 r180 top
R2 "0mR" "RES 0402/1005 RF KK" 164.503,236.477 r180 top
R3_I2C_Bridge_GPIO "1kR" "RES 0402/1005 RF KK" 125.807,250.869 r270 top (schematic designator R3)
R3_I2C_Bridge_PCIE "1kR" "RES 0402/1005 RF KK" 100.82,390.989 r270 top (schematic designator R3)
R3_I2C_Bridge_SFP "1kR" "RES 0402/1005 RF KK" 85.62,307.942 r270 top (schematic designator R3)
R4_I2C_Bridge_GPIO "1kR" "RES 0402/1005 RF KK" 127.043,250.869 r270 top (schematic designator R4)
R4_I2C_Bridge_PCIE "1kR" "RES 0402/1005 RF KK" 101.82,390.989 r270 top (schematic designator R4)
R4_I2C_Bridge_SFP "1kR" "RES 0402/1005 RF KK" 86.698,307.942 r270 top (schematic designator R4)
R5_I2C_Bridge_GPIO "1kR" "RES 0402/1005 RF KK" 128.28,250.869 r270 top (schematic designator R5)
R5_I2C_Bridge_PCIE "1kR" "RES 0402/1005 RF KK" 102.895,390.989 r270 top (schematic designator R5)
R5_I2C_Bridge_SFP "1kR" "RES 0402/1005 RF KK" 87.775,307.942 r270 top (schematic designator R5)
R6_I2C_Bridge_GPIO "1kR" "RES 0402/1005 RF KK" 129.517,250.869 r270 top (schematic designator R6)
R6_I2C_Bridge_PCIE "1kR" "RES 0402/1005 RF KK" 103.955,390.989 r270 top (schematic designator R6)
R6_I2C_Bridge_SFP "1kR" "RES 0402/1005 RF KK" 88.853,307.942 r270 top (schematic designator R6)
R7_I2C_Bridge_GPIO "1kR" "RES 0402/1005 RF KK" 130.753,250.869 r270 top (schematic designator R7)
R7_I2C_Bridge_PCIE "1kR" "RES 0402/1005 RF KK" 105.028,390.989 r270 top (schematic designator R7)
R7_I2C_Bridge_SFP "1kR" "RES 0402/1005 RF KK" 89.93,307.942 r270 top (schematic designator R7)
R8_I2C_Bridge_GPIO "1kR" "RES 0402/1005 RF KK" 132.354,247.732 r180 top (schematic designator R8)
R8_I2C_Bridge_PCIE "1kR" "RES 0402/1005 RF KK" 106.896,388.645 r180 top (schematic designator R8)
R8_I2C_Bridge_SFP "1kR" "RES 0402/1005 RF KK" 92.188,305.56 r180 top (schematic designator R8)
R9_I2C_Bridge_GPIO "1kR" "RES 0402/1005 RF KK" 132.354,246.497 r180 top (schematic designator R9)
R9_I2C_Bridge_PCIE "1kR" "RES 0402/1005 RF KK" 106.896,387.59 r180 top (schematic designator R9)
R9_I2C_Bridge_SFP "1kR" "RES 0402/1005 RF KK" 92.188,304.586 r180 top (schematic designator R9)
R10_I2C_Bridge_GPIO "1kR" "RES 0402/1005 RF KK" 132.354,245.261 r180 top (schematic designator R10)
R10_I2C_Bridge_PCIE "1kR" "RES 0402/1005 RF KK" 106.896,386.535 r180 top (schematic designator R10)
R10_I2C_Bridge_SFP "1kR" "RES 0402/1005 RF KK" 92.188,303.612 r180 top (schematic designator R10)
R11 "10kR" "RES 0402/1005 RF KK" 51.567,183.244 r0 top
R12 "95.3kR" "RES 0402/1005 RF KK" 45.844,173.839 r270 top
R13 "10kR" "RES 0402/1005 RF KK" 51.568,193.051 r180 top
R14 "1kR" "RES 0402/1005 RF KK" 139.304,275.821 r0 top
R15 "95.3kR" "RES 0402/1005 RF KK" 45.94,183.113 r270 top
R16 "1kR" "RES 0402/1005 RF KK" 139.304,276.846 r0 top
R17 "95.3kR" "RES 0402/1005 RF KK" 45.94,185.524 r90 top
R18 "24.9kR" "RES 0402/1005 RF KK" 51.568,184.274 r180 top
R19 "4.87kR" "RES 0402/1005 RF KK" 44.801,173.839 r90 top
R20 "95.3kR" "RES 0402/1005 RF KK" 45.822,176.136 r90 top
R21 "24.9kR" "RES 0402/1005 RF KK" 52.05,175.125 r180 top
R22 "1kR" "RES 0402/1005 RF KK" 139.304,273.772 r0 top
R23 "4.87kR" "RES 0402/1005 RF KK" 44.92,183.113 r90 top
R24 "1kR" "RES 0402/1005 RF KK" 139.304,274.797 r0 top
R25 "4.87kR" "RES 0402/1005 RF KK" 44.92,185.524 r270 top
R26 "4.87kR" "RES 0402/1005 RF KK" 44.801,176.136 r270 top
R27 "1.02kR" "RES 0402/1005 RF KK" 51.717,167.669 r90 top
R28 "1.02kR" "RES 0402/1005 RF KK" 43.358,184.021 r90 top
R29 "10kR" "RES 0402/1005 RF KK" 43.622,166.762 r180 top
R30 "10kR" "RES 0402/1005 RF KK" 43.974,163.338 r180 top
R31 "39.2R" "RES 0402/1005 RF KK" 174.855,345.25 r90 top
R32 "39.2R" "RES 0402/1005 RF KK" 170.02,345.25 r90 top
R33 "39.2R" "RES 0402/1005 RF KK" 158.287,340.144 r180 top
R34 "39.2R" "RES 0402/1005 RF KK" 158.287,339.055 r180 top
R35 "39.2R" "RES 0402/1005 RF KK" 173.646,345.25 r90 top
R36 "39.2R" "RES 0402/1005 RF KK" 167.603,345.25 r90 top
R37 "39.2R" "RES 0402/1005 RF KK" 158.287,337.967 r180 top
R38 "39.2R" "RES 0402/1005 RF KK" 162.769,345.25 r90 top
R39 "39.2R" "RES 0402/1005 RF KK" 171.229,345.25 r90 top
R40 "39.2R" "RES 0402/1005 RF KK" 166.395,345.25 r90 top
R41 "39.2R" "RES 0402/1005 RF KK" 158.287,341.233 r180 top
R42 "39.2R" "RES 0402/1005 RF KK" 172.438,345.25 r90 top
R43 "39.2R" "RES 0402/1005 RF KK" 178.481,345.25 r90 top
R44 "39.2R" "RES 0402/1005 RF KK" 163.977,345.25 r90 top
R45 "39.2R" "RES 0402/1005 RF KK" 158.287,343.411 r180 top
R46 "39.2R" "RES 0402/1005 RF KK" 158.287,333.611 r180 top
R47 "39.2R" "RES 0402/1005 RF KK" 177.272,345.25 r90 top
R48 "39.2R" "RES 0402/1005 RF KK" 158.287,342.322 r180 top
R49 "39.2R" "RES 0402/1005 RF KK" 168.812,345.25 r90 top
R50 "39.2R" "RES 0402/1005 RF KK" 176.063,345.25 r90 top
R51 "39.2R" "RES 0402/1005 RF KK" 158.287,335.789 r180 top
R52 "36R" "RES 0402/1005 RF KK" 158.287,331.433 r180 top
R53 "39.2R" "RES 0402/1005 RF KK" 158.287,344.5 r180 top
R54 "36R" "RES 0402/1005 RF KK" 158.287,332.522 r180 top
R55 "39.2R" "RES 0402/1005 RF KK" 165.186,345.25 r90 top
R56 "499R" "RES 0402/1005 RF KK" 162.91,338.184 r180 top
R57 "39.2R" "RES 0402/1005 RF KK" 158.287,336.878 r180 top
R58 "4.7kR" "RES 0402/1005 RF KK" 162.91,339.242 r180 top
R59 "39.2R" "RES 0402/1005 RF KK" 158.287,334.7 r180 top
R60 "1kR" "RES 0402/1005 RF KK" 179.692,345.25 r90 top
R61 "240R" "RES 0402/1005 RF KK" 196.19,332.943 r180 bottom
R62 "240R" "RES 0402/1005 RF KK" 186.512,332.702 r180 top
R63 "240R" "RES 0402/1005 RF KK" 162.916,332.27 r180 top
R64 "240R" "RES 0402/1005 RF KK" 175.177,332.21 r180 top
R65 "4.7kR" "RES 0402/1005 RF KK" 54.329,285.118 r180 top
R66 "4.7kR" "RES 0402/1005 RF KK" 54.329,286.047 r180 top
R67 "4.7kR" "RES 0402/1005 RF KK" 54.329,283.247 r180 top
R68 "4.7kR" "RES 0402/1005 RF KK" 54.329,284.205 r180 top
R69 "100R" "RES 0402/1005 RF KK" 161.788,326.529 r0 bottom
R70 "100R" "RES 0402/1005 RF KK" 155.658,326.529 r0 bottom
R71 "0mR" "RES 0402/1005 RF KK" 56.183,289.204 r180 top
R72 "0mR" "RES 0402/1005 RF KK" 56.183,288.188 r180 top
R73 "0mR" "RES 0402/1005 RF KK" 53.843,289.204 r180 top
R74 "0mR" "RES 0402/1005 RF KK" 53.843,288.188 r180 top
R75 "0mR" "RES 0402/1005 RF KK" 146.908,275.654 r180 top
R76 "150R" "RES 0402/1005 RF KK" 102.019,335.59 r90 bottom
R77 "7.5kR" "RES 0402/1005 RF KK" 98.039,342.772 r0 top
R78 "100R" "RES 0402/1005 RF KK" 99.293,334.575 r90 bottom
R79 "150R" "RES 0402/1005 RF KK" 102.019,333.535 r90 bottom
R80 "160R" "RES 0402/1005 RF KK" 102.806,339.934 r90 top
R81 "100R" "RES 0402/1005 RF KK" 100.876,331.972 r90 bottom
R82 "100R" "RES 0402/1005 RF KK" 102.984,326.421 r270 bottom
R83 "4.7kR" "RES 0402/1005 RF KK" 63.409,327.515 r0 top
R84 "4.7kR" "RES 0402/1005 RF KK" 63.525,322.724 r0 top
R85 "4.7kR" "RES 0402/1005 RF KK" 62.261,334.259 r0 top
R86 "4.7kR" "RES 0402/1005 RF KK" 62.166,330.848 r0 top
R87 "30R" "RES 0402/1005 RF KK" 141.908,336.008 r180 bottom
R88 "30R" "RES 0402/1005 RF KK" 141.908,334.241 r180 bottom
R89 "30R" "RES 0402/1005 RF KK" 141.008,341.31 r180 bottom
R90 "30R" "RES 0402/1005 RF KK" 138.925,338.641 r180 bottom
R91 "0mR" "RES 0402/1005 RF KK" 138.925,340.405 r0 bottom
R92 "0mR" "RES 0402/1005 RF KK" 138.925,342.169 r0 bottom
R93 "0mR" "RES 0402/1005 RF KK" 138.918,343.738 r0 bottom
R94 "0mR" "RES 0402/1005 RF KK" 138.925,333.348 r0 bottom
R95 "30R" "RES 0402/1005 RF KK" 139.86,335.128 r180 bottom
R96 "30R" "RES 0402/1005 RF KK" 141.908,337.776 r180 bottom
R97 "4.7kR" "RES 0402/1005 RF KK" 138.925,336.877 r0 bottom
R98 "4.7kR" "RES 0402/1005 RF KK" 114.333,399.809 r180 bottom
R99 "4.7kR" "RES 0402/1005 RF KK" 133.579,312.179 r0 top
R100 "5.1kR" "RES 0402/1005 RF KK" 201.531,292.652 r270 top
R101 "30R" "RES 0402/1005 RF KK" 133.566,322.351 r180 top
R102 "30R" "RES 0402/1005 RF KK" 133.566,320.319 r180 top
R103 "30R" "RES 0402/1005 RF KK" 133.566,318.287 r180 top
R104 "30R" "RES 0402/1005 RF KK" 133.566,316.255 r180 top
R105 "30R" "RES 0402/1005 RF KK" 133.566,321.335 r180 top
R106 "1kR" "RES 0402/1005 RF KK" 204.114,158.598 r270 top
R107 "30R" "RES 0402/1005 RF KK" 133.566,319.303 r180 top
R108 "30R" "RES 0402/1005 RF KK" 133.566,317.271 r180 top
R109 "1kR" "RES 0402/1005 RF KK" 208.509,158.674 r270 top
R110 "30R" "RES 0402/1005 RF KK" 133.566,323.367 r180 top
R111 "30R" "RES 0402/1005 RF KK" 133.566,315.214 r180 top
R112 "30R" "RES 0402/1005 RF KK" 133.566,314.223 r180 top
R113 "34.8kR" "RES 0402/1005 RF KK" 182.642,169.852 r270 top
R114 "10kR" "RES 0402/1005 RF KK" 183.592,169.86 r90 top
R115 "30R" "RES 0402/1005 RF KK" 63.251,346.841 r180 bottom
R116 "30R" "RES 0402/1005 RF KK" 63.251,348.619 r180 bottom
R117 "30R" "RES 0402/1005 RF KK" 60.877,347.702 r180 bottom
R118 "30R" "RES 0402/1005 RF KK" 58.465,352.175 r180 bottom
R119 "30R" "RES 0402/1005 RF KK" 60.877,345.929 r180 bottom
R120 "30R" "RES 0402/1005 RF KK" 63.251,345.063 r180 bottom
R121 "30R" "RES 0402/1005 RF KK" 63.251,343.285 r180 bottom
R122 "30R" "RES 0402/1005 RF KK" 60.877,342.383 r180 bottom
R123 "4.7kR" "RES 0402/1005 RF KK" 76.199,335.229 r0 top
R124 "1kR" "RES 0402/1005 RF KK" 173.803,233.083 r0 top
R125 "8.87kR" "RES 0402/1005 RF KK" 200.49,292.652 r270 top
R126 "100R" "RES 0402/1005 RF KK" 158.551,326.55 r0 bottom
R127 "10kR" "RES 0402/1005 RF KK" 147.691,220.935 r0 top
R128 "10kR" "RES 0402/1005 RF KK" 162.382,242.418 r0 top
R129 "10kR" "RES 0402/1005 RF KK" 162.382,237.34 r0 top
R130 "0mR" "RES 0402/1005 RF KK" 162.382,244.11 r180 top
R131 "0mR" "RES 0402/1005 RF KK" 162.382,240.725 r180 top
R132 "0mR" "RES 0402/1005 RF KK" 164.501,244.951 r180 top
R133 "0mR" "RES 0402/1005 RF KK" 164.501,241.561 r180 top
R134 "0mR" "RES 0402/1005 RF KK" 164.501,239.866 r180 top
R135 "4.7kR" "RES 0402/1005 RF KK" 54.317,313.497 r180 top
R136 "4.7kR" "RES 0402/1005 RF KK" 54.326,314.403 r180 top
R137 "4.7kR" "RES 0402/1005 RF KK" 54.329,311.684 r180 top
R138 "4.7kR" "RES 0402/1005 RF KK" 54.329,312.59 r180 top
R139 "0mR" "RES 0402/1005 RF KK" 145.283,220.955 r0 top
R140 "2.2R" "RES 0402/1005 RF KK" 34.297,205.384 r180 top
R141 "0mR" "RES 0402/1005 RF KK" 55.911,316.827 r180 top
R142 "0mR" "RES 0402/1005 RF KK" 55.911,315.741 r180 top
R143 "0mR" "RES 0402/1005 RF KK" 53.772,316.827 r180 top
R144 "0mR" "RES 0402/1005 RF KK" 53.772,315.759 r180 top
R145 "4.7kR" "RES 0402/1005 RF KK" 54.344,270.912 r180 top
R146 "4.7kR" "RES 0402/1005 RF KK" 54.344,271.797 r180 top
R147 "4.7kR" "RES 0402/1005 RF KK" 54.348,269.173 r180 top
R148 "4.7kR" "RES 0402/1005 RF KK" 54.344,270.046 r180 top
R149 "196kR" "RES 0402/1005 RF KK" 34.323,204.343 r0 top
R150 "22k" "RES 0402/1005 RF KK" 42.652,206.468 r0 top
R151 "0mR" "RES 0402/1005 RF KK" 55.964,274.472 r180 top
R152 "0mR" "RES 0402/1005 RF KK" 55.964,273.456 r180 top
R153 "0mR" "RES 0402/1005 RF KK" 53.655,274.472 r180 top
R154 "0mR" "RES 0402/1005 RF KK" 53.655,273.456 r180 top
R155 "4.7kR" "RES 0402/1005 RF KK" 54.317,299.431 r180 top
R156 "4.7kR" "RES 0402/1005 RF KK" 54.326,300.308 r180 top
R157 "4.7kR" "RES 0402/1005 RF KK" 54.329,297.677 r180 top
R158 "4.7kR" "RES 0402/1005 RF KK" 54.329,298.554 r180 top
R159 "10kR" "RES 0402/1005 RF KK" 34.323,203.149 r0 top
R160 "910R" "RES 0402/1005 RF KK" 42.528,203.203 r180 top
R161 "0mR" "RES 0402/1005 RF KK" 55.321,303.205 r180 top
R162 "0mR" "RES 0402/1005 RF KK" 55.321,302.189 r180 top
R163 "0mR" "RES 0402/1005 RF KK" 53.082,303.205 r180 top
R164 "0mR" "RES 0402/1005 RF KK" 53.082,302.189 r180 top
R165 "100R" "RES 0402/1005 RF KK" 174.977,337.95 r0 top
R166 "100R" "RES 0402/1005 RF KK" 209.207,338.277 r0 top
R167 "100R" "RES 0402/1005 RF KK" 175.031,340.24 r0 top
R168 "100R" "RES 0402/1005 RF KK" 209.194,337.236 r0 top
R169 "100R" "RES 0402/1005 RF KK" 191.916,342.861 r90 top
R170 "100R" "RES 0402/1005 RF KK" 190.901,342.861 r90 top
R171 "100R" "RES 0402/1005 RF KK" 186.548,336.842 r0 top
R172 "100R" "RES 0402/1005 RF KK" 186.548,338.696 r0 top
R173 "500R" "RES 0402/1005 RF KK" 161.58,321.871 r180 top
R174 "1kR" "RES 0402/1005 RF KK" 170.427,390.756 r180 top
R175 "1kR" "RES 0402/1005 RF KK" 170.427,389.74 r180 top
R176 "1kR" "RES 0402/1005 RF KK" 170.427,392.788 r180 top
R177 "1kR" "RES 0402/1005 RF KK" 170.427,391.772 r180 top
R178 "1kR" "RES 0402/1005 RF KK" 172.84,390.756 r0 top
R179 "1kR" "RES 0402/1005 RF KK" 172.84,389.74 r0 top
R180 "1kR" "RES 0402/1005 RF KK" 172.84,392.788 r0 top
R181 "1kR" "RES 0402/1005 RF KK" 172.84,391.772 r0 top
R182 "1.02kR" "RES 0402/1005 RF KK" 179.955,375.907 r270 top
R183 "1kR" "RES 0402/1005 RF KK" 225.441,242.685 r0 top
R184 "1kR" "RES 0402/1005 RF KK" 225.441,243.574 r0 top
R185 "1kR" "RES 0402/1005 RF KK" 225.441,240.907 r0 top
R186 "1kR" "RES 0402/1005 RF KK" 225.441,241.796 r0 top
R187 "1kR" "RES 0402/1005 RF KK" 223.282,242.685 r180 top
R188 "1kR" "RES 0402/1005 RF KK" 223.282,243.574 r180 top
R189 "1kR" "RES 0402/1005 RF KK" 223.282,240.907 r180 top
R190 "1kR" "RES 0402/1005 RF KK" 223.282,241.796 r180 top
R191 "1.02kR" "RES 0402/1005 RF KK" 221.342,250.651 r90 top
R192 "1kR" "RES 0402/1005 RF KK" 253.774,389.101 r180 top
R193 "1kR" "RES 0402/1005 RF KK" 253.774,388.043 r180 top
R194 "1kR" "RES 0402/1005 RF KK" 253.774,391.218 r180 top
R195 "1kR" "RES 0402/1005 RF KK" 253.774,390.16 r180 top
R196 "1kR" "RES 0402/1005 RF KK" 255.806,389.101 r0 top
R197 "1kR" "RES 0402/1005 RF KK" 255.806,388.043 r0 top
R198 "1kR" "RES 0402/1005 RF KK" 255.806,391.218 r0 top
R199 "1kR" "RES 0402/1005 RF KK" 255.806,390.16 r0 top
R200 "1.02kR" "RES 0402/1005 RF KK" 258.249,381.907 r270 top
R201 "1kR" "RES 0402/1005 RF KK" 88.363,389.129 r180 top
R202 "1kR" "RES 0402/1005 RF KK" 88.363,388.24 r180 top
R203 "1kR" "RES 0402/1005 RF KK" 88.363,390.907 r180 top
R204 "1kR" "RES 0402/1005 RF KK" 88.363,390.018 r180 top
R205 "1kR" "RES 0402/1005 RF KK" 90.522,389.129 r0 top
R206 "1kR" "RES 0402/1005 RF KK" 90.522,388.24 r0 top
R207 "1kR" "RES 0402/1005 RF KK" 90.522,390.907 r0 top
R208 "1kR" "RES 0402/1005 RF KK" 90.522,390.018 r0 top
R209 "1.02kR" "RES 0402/1005 RF KK" 92.133,382.099 r270 top
R210 "1kR" "RES 0402/1005 RF KK" 140.841,244.823 r0 top
R211 "1kR" "RES 0402/1005 RF KK" 140.841,245.818 r0 top
R212 "12.5k" "RES 0402/1005 RF KK" 182.642,171.965 r90 top
R213 "1kR" "RES 0402/1005 RF KK" 140.844,242.844 r0 top
R214 "10kR" "RES 0402/1005 RF KK" 183.592,171.965 r270 top
R215 "1kR" "RES 0402/1005 RF KK" 140.844,243.828 r0 top
R216 "31.2kR" "RES 0402/1005 RF KK" 179.984,173.015 r270 top
R217 "1kR" "RES 0402/1005 RF KK" 138.715,244.823 r180 top
R218 "10kR" "RES 0402/1005 RF KK" 180.95,173.015 r270 top
R219 "1kR" "RES 0402/1005 RF KK" 138.714,245.818 r180 top
R220 "4.99kR" "RES 0402/1005 RF KK" 179.984,168.89 r270 top
R221 "1kR" "RES 0402/1005 RF KK" 138.715,242.844 r180 top
R222 "1kR" "RES 0402/1005 RF KK" 138.715,243.828 r180 top
R223_I2C_Bridge_GPIO "1kR" "RES 0402/1005 RF KK" 132.354,244.026 r180 top (schematic designator R223)
R223_I2C_Bridge_PCIE "1kR" "RES 0402/1005 RF KK" 106.896,385.48 r180 top (schematic designator R223)
R223_I2C_Bridge_SFP "1kR" "RES 0402/1005 RF KK" 92.188,302.638 r180 top (schematic designator R223)
R224_I2C_Bridge_GPIO "1kR" "RES 0402/1005 RF KK" 132.354,242.791 r180 top (schematic designator R224)
R224_I2C_Bridge_PCIE "1kR" "RES 0402/1005 RF KK" 106.896,384.424 r180 top (schematic designator R224)
R224_I2C_Bridge_SFP "1kR" "RES 0402/1005 RF KK" 92.188,301.665 r180 top (schematic designator R224)
R225_I2C_Bridge_GPIO "1kR" "RES 0402/1005 RF KK" 129.09,239.794 r90 top (schematic designator R225)
R225_I2C_Bridge_PCIE "1kR" "RES 0402/1005 RF KK" 104.356,382.099 r90 top (schematic designator R225)
R225_I2C_Bridge_SFP "1kR" "RES 0402/1005 RF KK" 89.707,298.998 r90 top (schematic designator R225)
R226_I2C_Bridge_GPIO "1kR" "RES 0402/1005 RF KK" 127.784,239.794 r90 top (schematic designator R226)
R226_I2C_Bridge_PCIE "1kR" "RES 0402/1005 RF KK" 103.32,382.099 r90 top (schematic designator R226)
R226_I2C_Bridge_SFP "1kR" "RES 0402/1005 RF KK" 88.742,298.998 r90 top (schematic designator R226)
R227_I2C_Bridge_GPIO "1kR" "RES 0402/1005 RF KK" 126.479,239.794 r90 top (schematic designator R227)
R227_I2C_Bridge_PCIE "1kR" "RES 0402/1005 RF KK" 102.32,382.099 r90 top (schematic designator R227)
R227_I2C_Bridge_SFP "1kR" "RES 0402/1005 RF KK" 87.777,298.998 r90 top (schematic designator R227)
R228 "1.02kR" "RES 0402/1005 RF KK" 134.003,256.757 r90 top
R229 "1kR" "RES 0402/1005 RF KK" 33.32,153.653 r0 top
R230 "1kR" "RES 0402/1005 RF KK" 33.32,154.669 r0 top
R231_SPI_bridge_Main "1kR" "RES 0402/1005 RF KK" 225.457,289.983 r0 top (schematic designator R231)
R231_SPI_bridge_PCIe "1kR" "RES 0402/1005 RF KK" 140.532,369.66 r270 top (schematic designator R231)
R232_SPI_bridge_Main "1kR" "RES 0402/1005 RF KK" 225.457,288.068 r180 top (schematic designator R232)
R232_SPI_bridge_PCIe "1kR" "RES 0402/1005 RF KK" 136.144,372.643 r0 top (schematic designator R232)
R233_SPI_bridge_Main "1kR" "RES 0402/1005 RF KK" 190.081,262.011 r90 top (schematic designator R233)
R233_SPI_bridge_PCIe "1kR" "RES 0402/1005 RF KK" 255.191,262.064 r90 top (schematic designator R233)
R234_SPI_bridge_Main "1kR" "RES 0402/1005 RF KK" 191.148,262.011 r270 top (schematic designator R234)
R234_SPI_bridge_PCIe "1kR" "RES 0402/1005 RF KK" 256.491,262.014 r270 top (schematic designator R234)
R235_SPI_bridge_Main "1kR" "RES 0402/1005 RF KK" 81.755,327.34 r0 top (schematic designator R235)
R235_SPI_bridge_PCIe "1kR" "RES 0402/1005 RF KK" 222.34,369.89 r270 top (schematic designator R235)
R236_SPI_bridge_Main "1kR" "RES 0402/1005 RF KK" 81.755,328.59 r0 top (schematic designator R236)
R236_SPI_bridge_PCIe "1kR" "RES 0402/1005 RF KK" 223.64,369.89 r270 top (schematic designator R236)
R237_SPI_bridge_Main "1kR" "RES 0402/1005 RF KK" 169.979,412.95 r90 top (schematic designator R237)
R237_SPI_bridge_PCIe "1kR" "RES 0402/1005 RF KK" 57.328,369.413 r270 top (schematic designator R237)
R238_SPI_bridge_Main "1kR" "RES 0402/1005 RF KK" 169.382,408.551 r270 top (schematic designator R238)
R238_SPI_bridge_PCIe "1kR" "RES 0402/1005 RF KK" 58.613,369.413 r270 top (schematic designator R238)
R239_SPI_bridge_Main "1kR" "RES 0402/1005 RF KK" 173.803,236.703 r180 top (schematic designator R239)
R239_SPI_bridge_PCIe "1kR" "RES 0402/1005 RF KK" 175.192,258.849 r270 top (schematic designator R239)
R240_SPI_bridge_Main "1kR" "RES 0402/1005 RF KK" 164.501,238.172 r180 top (schematic designator R240)
R240_SPI_bridge_PCIe "1kR" "RES 0402/1005 RF KK" 173.746,258.849 r90 top (schematic designator R240)
R241 "1kR" "RES 0402/1005 RF KK" 119.006,247.554 r0 top
R242 "0mR" "RES 0402/1005 RF KK" 119.006,246.246 r180 top
R243 "1kR" "RES 0402/1005 RF KK" 119.006,244.938 r0 top
R244 "0mR" "RES 0402/1005 RF KK" 119.006,243.63 r180 top
R245 "100R" "RES 0402/1005 RF KK" 61.419,397.235 r90 top
R246 "120R" "RES 0402/1005 RF KK" 56.436,398.269 r270 top
R247 "127R" "RES 0402/1005 RF KK" 60.246,398.269 r270 top
R248 "127R" "RES 0402/1005 RF KK" 60.246,396.168 r90 top
R249 "120R" "RES 0402/1005 RF KK" 56.436,396.168 r270 top
R250 "82.5R" "RES 0402/1005 RF KK" 59.23,398.269 r270 top
R251 "82.5R" "RES 0402/1005 RF KK" 59.23,396.168 r90 top
R252 "1kR" "RES 0402/1005 RF KK" 49.343,394.952 r180 top
R253 "1kR" "RES 0402/1005 RF KK" 51.347,394.952 r0 top
R254 "1kR" "RES 0402/1005 RF KK" 49.343,395.968 r0 top
R255 "1kR" "RES 0402/1005 RF KK" 51.347,395.968 r180 top
R256 "120R" "RES 0402/1005 RF KK" 64.77,387.018 r90 top
R257 "49.9R" "RES 0402/1005 RF KK" 58.922,387.635 r90 top
R258 "120R" "RES 0402/1005 RF KK" 64.77,388.955 r90 top
R259 "82.5R" "RES 0402/1005 RF KK" 68.58,388.955 r270 top
R260 "82.5R" "RES 0402/1005 RF KK" 68.58,387.018 r90 top
R261 "127R" "RES 0402/1005 RF KK" 67.564,388.955 r270 top
R262 "127R" "RES 0402/1005 RF KK" 67.564,387.018 r90 top
R263 "60.4kR" "RES 0402/1005 RF KK" 60.573,391.456 r270 top
R264 "0mR" "RES 0402/1005 RF KK" 63.083,391.456 r270 top
R265 "0mR" "RES 0402/1005 RF KK" 61.858,391.456 r270 top
R266 "84.5kR" "RES 0402/1005 RF KK" 56.594,236.039 r90 top
R267 "4.7kR" "RES 0402/1005 RF KK" 56.502,228.016 r0 top
R268 "2R" "RES 0402/1005 RF KK" 59.242,237.714 r0 top
R269 "1.02kR" "RES 0402/1005 RF KK" 130.948,305.752 r180 top
R270 "100R" "RES 0402/1005 RF KK" 177.08,275.811 r0 bottom
R271 "5kR" "RES 0402/1005 RF KK" 180.397,297.539 r180 bottom
R272 "2R" "RES 0402/1005 RF KK" 60.606,235.139 r180 top
R273 "12kR" "RES 0402/1005 RF KK" 63.385,239.777 r180 top
R274 "10kR" "RES 0402/1005 RF KK" 180.95,168.894 r90 top
R275 "47kR" "RES 0402/1005 RF KK" 80.488,236.914 r90 top
R276 "4.7kR" "RES 0402/1005 RF KK" 245.163,323.51 r180 top
R277 "12kR" "RES 0402/1005 RF KK" 64.94,229.024 r0 top
R278 "12kR" "RES 0402/1005 RF KK" 63.889,240.855 r0 top
R279 "0mR" "RES 0402/1005 RF KK" 222.364,337.058 r270 top
R280 "47kR" "RES 0402/1005 RF KK" 80.488,234.339 r270 top
R281 "1kR" "RES 0402/1005 RF KK" 124.57,250.869 r270 top
R282 "0mR" "RES 0402/1005 RF KK" 222.656,340.296 r270 top
R283 "0mR" "RES 0402/1005 RF KK" 223.698,340.296 r270 top
R284 "18.2k (1MHz)" "RES 0402/1005 RF KK" 177.98,166.233 r90 top
R285 "2R" "RES 0402/1005 RF KK" 59.753,184.12 r270 top
R286 "0mR" "RES 0402/1005 RF KK" 223.368,337.058 r270 top
R287 "49.9kR" "RES 0402/1005 RF KK" 61.241,183.809 r90 top
R288 "Resistor_1210" RES_1210 85.014,190.309 r180 top value=3.6R
R289 "2R" "RES 0402/1005 RF KK" 61.331,179.317 r180 top
R290 "10k" "RES 0402/1005 RF KK" 62.191,183.809 r90 top
R291 "150R" "RES 0402/1005 RF KK" 206.539,292.652 r90 top
R292 "" "RES 0402/1005 RF KK" 70.661,179.917 r180 top
R293 "0mR" "RES 0402/1005 RF KK" 61.331,178.317 r180 top
R294 "0mR" "RES 0402/1005 RF KK" 61.331,177.317 r180 top
R295 "12kR" "RES 0402/1005 RF KK" 67.169,183.85 r270 top
R296 "12kR" "RES 0402/1005 RF KK" 67.204,175.367 r90 top
R297 "10k" "RES 0402/1005 RF KK" 62.14,175.401 r90 top
R298 "Resistor_1210" RES_1210 86.39,174.414 r180 top value=3.6R
R299 "47kR" "RES 0402/1005 RF KK" 70.661,179.067 r180 top
R300 "10k" "RES 0402/1005 RF KK" 61.068,175.401 r270 top
R301 "150R" "RES 0402/1005 RF KK" 206.539,290.767 r270 top
R302 "1.4kR" "RES 0201/0603" 66.453,202.488 r90 top
R303 "2R" "RES 0402/1005 RF KK" 55.203,215.087 r270 top
R304 "1kR" "RES 0402/1005 RF KK" 137.316,275.821 r180 top
R305 "100R" "RES 0402/1005 RF KK" 175.639,163.255 r90 top
R306 "Resistor_1210" RES_1210 88.316,205.562 r90 top value=3.6R
R307 "2R" "RES 0402/1005 RF KK" 58.395,206.596 r0 top
R308 "100R" "RES 0402/1005 RF KK" 176.589,163.255 r270 top
R309 "100R" "RES 0402/1005 RF KK" 177.539,163.255 r90 top
R310 "0mR" "RES 0402/1005 RF KK" 58.395,208.526 r0 top
R311 "100R" "RES 0402/1005 RF KK" 151.671,221.475 r180 top
R312 "0mR" "RES 0402/1005 RF KK" 58.376,204.716 r180 top
R313 "12kR" "RES 0402/1005 RF KK" 64.953,210.754 r270 top
R314 "12kR" "RES 0402/1005 RF KK" 64.623,202.273 r90 top
R315 "196kR" "RES 0402/1005 RF KK" 61.041,202.273 r270 top
R316 "Resistor_1210" RES_1210 84.163,204.643 r270 top value=3.6R
R317 "47kR" "RES 0402/1005 RF KK" 68.656,206.039 r180 top
R318 "27kR" "RES 0402/1005 RF KK" 60.114,202.273 r90 top
R319 "10kR" "RES 0402/1005 RF KK" 120.332,279.437 r90 bottom
R320 "10kR" "RES 0402/1005 RF KK" 120.332,277.401 r270 bottom
R321 "100R" "RES 0402/1005 RF KK" 119.139,278.384 r90 bottom
R322 "5.76kR" "RES 0402/1005 RF KK" 117.334,276.022 r90 bottom
R323 "5.76kR" "RES 0402/1005 RF KK" 117.334,273.977 r270 bottom
R324 "100kR" "RES 0805/2012 RF" 50.292,225.882 r90 bottom
R325 "2.49kR" "RES 0402/1005 RF KK" 121.539,279.437 r270 bottom
R326 "2.49kR" "RES 0402/1005 RF KK" 121.539,277.401 r90 bottom
R327 "2.49kR" "RES 0402/1005 RF KK" 118.427,276.022 r270 bottom
R328 "2.49kR" "RES 0402/1005 RF KK" 118.427,273.977 r90 bottom
R329 "100R" "RES 0402/1005 RF KK" 104.826,271.544 r270 bottom
R330 "100R" "RES 0402/1005 RF KK" 105.908,271.544 r270 bottom
R331 "100R" "RES 0402/1005 RF KK" 106.991,271.544 r270 bottom
R332 "100R" "RES 0402/1005 RF KK" 110.122,271.544 r90 bottom
R333 "2.2kR" "RES 0402/1005 RF KK" 106.145,286.787 r270 bottom
R334 "11kR" "RES 0402/1005 RF KK" 102.761,282.585 r90 bottom
R335 "1MR" "RES 0402/1005 RF KK" 99.32,286.117 r180 bottom
R336 "2.2kR" "RES 0402/1005 RF KK" 113.633,286.787 r270 bottom
R337 "2.2kR" "RES 0402/1005 RF KK" 109.354,286.787 r270 bottom
R338 "2.2kR" "RES 0402/1005 RF KK" 111.494,286.787 r270 bottom
R339 "105kR" "RES 0402/1005 RF KK" 122.804,338.747 r0 top
R340 "10kR" "RES 0402/1005 RF KK" 122.804,337.782 r0 top
R341 "15kR" "RES 0402/1005 RF KK" 122.809,339.731 r180 top
R342 "105kR" "RES 0402/1005 RF KK" 113.04,319.805 r90 top
R343 "10kR" "RES 0402/1005 RF KK" 114.1,319.805 r90 top
R344 "15kR" "RES 0402/1005 RF KK" 111.84,316.411 r0 top
R345 "0mR" "RES 0402/1005 RF KK" 114.1,317.724 r270 top
R346 "4.7kR" "RES 0402/1005 RF KK" 227.247,203.962 r180 top
R347 "4.7kR" "RES 0402/1005 RF KK" 227.247,206.983 r180 top
R348 "4.7kR" "RES 0402/1005 RF KK" 227.247,205.472 r180 top
R349 "4.7kR" "RES 0402/1005 RF KK" 243.109,346.354 r0 top
R350 "4.7kR" "RES 0402/1005 RF KK" 243.109,347.667 r0 top
R351 "4.7kR" "RES 0402/1005 RF KK" 243.109,348.979 r0 top
R352 "4.7kR" "RES 0402/1005 RF KK" 243.109,350.291 r0 top
R353 "4.7kR" "RES 0402/1005 RF KK" 207.518,360.667 r180 bottom
R354 "4.7kR" "RES 0402/1005 RF KK" 215.392,158.75 r270 top
R355 "4.7kR" "RES 0402/1005 RF KK" 215.459,155.321 r90 top
R356 "4.7kR" "RES 0402/1005 RF KK" 235.757,338.633 r0 bottom
R357 "4.7kR" "RES 0402/1005 RF KK" 207.518,359.346 r0 bottom
R358 "499R" "RES 0402/1005 RF KK" 224.315,346.481 r180 top
R359 "499R" "RES 0402/1005 RF KK" 224.315,347.751 r180 top
R360 "499R" "RES 0402/1005 RF KK" 224.315,349.021 r180 top
R361 "499R" "RES 0402/1005 RF KK" 224.315,350.291 r180 top
R362 "30R" "RES 0402/1005 RF KK" 63.251,350.397 r180 bottom
R363 "4.7kR" "RES 0402/1005 RF KK" 70.63,324.714 r180 bottom
R364 "4.7kR" "RES 0402/1005 RF KK" 70.63,323.685 r180 bottom
R365 "4.7kR" "RES 0402/1005 RF KK" 131.091,268.344 r90 top
R366 "10kR" "RES 0402/1005 RF KK" 150.056,237.602 r0 top
R367 "4.7kR" "RES 0402/1005 RF KK" 235.744,340.03 r180 bottom
R368 "261R" "RES 0402/1005 RF KK" 238.513,161.303 r180 top
R369 "10kR" "RES 0402/1005 RF KK" 248.628,157.226 r0 top
R370 "10kR" "RES 0402/1005 RF KK" 248.602,158.458 r0 top
R371 "10kR" "RES 0402/1005 RF KK" 238.513,160.096 r180 top
R372 "8.06kR" "RES 0402/1005 RF KK" 245.11,153.421 r270 top
R373 "10kR" "RES 0402/1005 RF KK" 243.713,153.421 r90 top
R374 "4.7MR" "RES 0402/1005 RF KK" 203.86,313.797 r180 bottom
R375 "40.2R" "RES 0402/1005 RF KK" 220.65,326.735 r270 top
R376 "0mR" "RES 0402/1005 RF KK" 60.877,344.156 r0 bottom
R377 "0mR" "RES 0402/1005 RF KK" 55.855,342.386 r270 top
R378 "0mR" "RES 0402/1005 RF KK" 54.355,342.397 r270 bottom
R379 "8.06kR" "RES 0402/1005 RF KK" 51.256,349.941 r270 bottom
R380 "4.22kR" "RES 0402/1005 RF KK" 45.649,354.779 r90 top
R381 "4.7kR" "RES 0402/1005 RF KK" 138.925,331.584 r0 bottom
R382 "4.7kR" "RES 0402/1005 RF KK" 141.908,339.543 r0 bottom
R383 "10k" "RES 0402/1005 RF KK" 131.039,340.823 r270 top
R384 "71.5R" "RES 0402/1005 RF KK" 204.872,292.202 r0 top
R385 "71.5R" "RES 0402/1005 RF KK" 204.872,291.216 r0 top
R386 "8.87kR" "RES 0402/1005 RF KK" 200.49,290.759 r90 top
R387 "5.1kR" "RES 0402/1005 RF KK" 201.531,290.766 r90 top
R388 "1kR" "RES 0402/1005 RF KK" 137.316,276.846 r180 top
R389 "1kR" "RES 0402/1005 RF KK" 137.316,273.772 r180 top
R390 "1kR" "RES 0402/1005 RF KK" 137.316,274.797 r180 top
R391 "75kR" "RES 0402/1005 RF KK" 103.42,254.796 r180 top
R392 "100kR" "RES 0402/1005 RF KK" 188.316,345.614 r270 top
R393 "15kR" "RES 0402/1005 RF KK" 104.62,255.77 r180 top
R394 "51.1kR" "RES 0402/1005 RF KK" 98.051,254.796 r180 top
R395 "0mR" "RES 0402/1005 RF KK" 100.383,330.39 r180 top
R396 "15kR" "RES 0402/1005 RF KK" 99.944,255.867 r180 top
R397 "21.5kR" "RES 0402/1005 RF KK" 91.606,253.618 r180 top
R398 "0mR" "RES 0402/1005 RF KK" 179.73,268.694 r0 top
R399 "15kR" "RES 0402/1005 RF KK" 92.461,254.68 r180 top
R400 "0mR" "RES 0402/1005 RF KK" 123.333,250.869 r90 top
R401 "10k" "RES 0402/1005 RF KK" 220.642,175.874 r180 bottom
R402 "0mR" "RES 0402/1005 RF KK" 206.789,207.472 r0 top
R403 "0mR" "RES 0402/1005 RF KK" 209.049,207.472 r180 top
R404 "0mR" "RES 0402/1005 RF KK" 206.789,206.333 r0 top
R405 "0mR" "RES 0402/1005 RF KK" 209.049,206.333 r180 top
R406 "0mR" "RES 0402/1005 RF KK" 206.789,203.083 r0 top
R407 "0mR" "RES 0402/1005 RF KK" 209.049,203.083 r180 top
R408 "0mR" "RES 0402/1005 RF KK" 206.789,201.944 r0 top
R409 "0mR" "RES 0402/1005 RF KK" 209.049,201.944 r180 top
R410 "10k" "RES 0402/1005 RF KK" 220.642,183.418 r180 bottom
R411 "0mR" "RES 0402/1005 RF KK" 110.394,297.394 r180 bottom
R412 "0mR" "RES 0402/1005 RF KK" 108.133,297.394 r0 bottom
R413 "0mR" "RES 0402/1005 RF KK" 110.394,296.255 r180 bottom
R414 "0mR" "RES 0402/1005 RF KK" 108.133,296.255 r0 bottom
R415 "0mR" "RES 0402/1005 RF KK" 110.394,293.005 r180 bottom
R416 "0mR" "RES 0402/1005 RF KK" 108.133,293.005 r0 bottom
R417 "10k" "RES 0402/1005 RF KK" 261.417,217.076 r270 top
R418 "0mR" "RES 0402/1005 RF KK" 110.394,291.866 r180 bottom
R419 "2kR" "RES 0402/1005 RF KK" 255.115,209.431 r0 top
R420 "10k" "RES 0402/1005 RF KK" 260.159,217.013 r270 top
R421 "0mR" "RES 0402/1005 RF KK" 108.133,291.866 r0 bottom
R422 "10k" "RES 0402/1005 RF KK" 259.093,209.926 r270 top
R423 "12kR" "RES 0402/1005 RF KK" 246.959,216.675 r90 top
R424 "1kR" "RES 0402/1005 RF KK" 239.72,216.776 r270 top
R425_SPI_bridge_Main "0mR" "RES 0402/1005 RF KK" 214.452,293.539 r180 top (schematic designator R425)
R425_SPI_bridge_PCIe "0mR" "RES 0402/1005 RF KK" 144.057,380.477 r90 top (schematic designator R425)
R426_SPI_bridge_Main "0mR" "RES 0402/1005 RF KK" 214.452,289.052 r0 top (schematic designator R426)
R426_SPI_bridge_PCIe "0mR" "RES 0402/1005 RF KK" 140.183,380.427 r270 top (schematic designator R426)
R427 "5.1kR" "RES 0402/1005 RF KK" 138.412,308.1 r270 top
R428 "1kR" "RES 0402/1005 RF KK" 120.86,250.869 r90 top
R429 "0mR" "RES 0402/1005 RF KK" 214.553,245.515 r90 top
R430_5to3V3_1 "105kR" "RES 0402/1005 RF KK" 95.764,345.91 r0 top (schematic designator R430)
R430_5to3V3_2 "105kR" "RES 0402/1005 RF KK" 199.36,263.013 r270 top (schematic designator R430)
R430_5V_to_3V3_for_FTDI "105kR" "RES 0402/1005 RF KK" 264.233,209.436 r180 top (schematic designator R430)
R431_5to3V3_1 "100kR" "RES 0402/1005 RF KK" 95.764,343.56 r0 top (schematic designator R431)
R431_5to3V3_2 "100kR" "RES 0402/1005 RF KK" 198.138,263.038 r270 top (schematic designator R431)
R431_5V_to_3V3_for_FTDI "100kR" "RES 0402/1005 RF KK" 264.233,210.378 r180 top (schematic designator R431)
R432_5to3V3_1 "15kR" "RES 0402/1005 RF KK" 95.764,344.678 r180 top (schematic designator R432)
R432_5to3V3_2 "15kR" "RES 0402/1005 RF KK" 200.435,263.013 r90 top (schematic designator R432)
R432_5V_to_3V3_for_FTDI "15kR" "RES 0402/1005 RF KK" 267.268,208.612 r90 top (schematic designator R432)
R433 "56kR" "RES 0402/1005 RF KK" 92.011,322.096 r0 bottom
R434 "10k" "RES 0402/1005 RF KK" 90.287,322.546 r90 bottom
R435 "10kR" "RES 0402/1005 RF KK" 124.786,233.243 r180 top
R436 "3.57kR" "RES 0402/1005 RF KK" 165.659,211.548 r90 top
R437 "1.15kR" "RES 0402/1005 RF KK" 163.83,211.087 r0 top
R438 "3.57kR" "RES 0402/1005 RF KK" 170.181,217.2 r90 top
R439 "1.15kR" "RES 0402/1005 RF KK" 169.215,217.2 r270 top
R440 "20kR" "RES 0402/1005 RF KK" 166.736,211.548 r270 top
R441 "20kR" "RES 0402/1005 RF KK" 171.128,217.2 r270 top
R442 "100kR" "RES 0402/1005 RF KK" 162.941,399.212 r0 top
R443 "698kR" "RES 0805/2012 RF" 158.638,405.114 r180 top
R444 "49.9kR" "RES 0402/1005 RF KK" 161.032,401.681 r90 top
R445 "49.9kR" "RES 0402/1005 RF KK" 158.037,403.631 r0 top
R446 "120R" "RES 0402/1005 RF KK" 191.516,370.167 r90 top
R447 "120R" "RES 0402/1005 RF KK" 192.684,370.167 r90 top
R448_U_Pomiar_pradu_napiecia_1 "FCSL110R005FER" FCSL110R005FERCT-ND 31.533,169.673 r0 top (schematic designator R448)
R448_U_Pomiar_pradu_napiecia_2 "FCSL110R005FER" FCSL110R005FERCT-ND 30.549,194.108 r0 bottom (schematic designator R448)
R448_U_Pomiar_pradu_napiecia_3 "FCSL110R005FER" FCSL110R005FERCT-ND 107.759,182.601 r90 top (schematic designator R448)
R448_U_Pomiar_pradu_napiecia_4 "FCSL110R005FER" FCSL110R005FERCT-ND 106.904,166.738 r90 top (schematic designator R448)
R448_U_Pomiar_pradu_napiecia_5 "FCSL110R005FER" FCSL110R005FERCT-ND 102.092,215.887 r90 top (schematic designator R448)
R448_U_Pomiar_pradu_napiecia_6 "FCSL110R005FER" FCSL110R005FERCT-ND 100.635,199.06 r90 top (schematic designator R448)
R448_U_Pomiar_pradu_napiecia_PCIe0 "FCSL110R005FER" FCSL110R005FERCT-ND 172.34,374.81 r180 top (schematic designator R448)
R448_U_Pomiar_pradu_napiecia_PCIe1 "FCSL110R005FER" FCSL110R005FERCT-ND 223.582,259.937 r0 top (schematic designator R448)
R448_U_Pomiar_pradu_napiecia_PCIe2 "FCSL110R005FER" FCSL110R005FERCT-ND 255.391,372.367 r180 top (schematic designator R448)
R448_U_Pomiar_pradu_napiecia_PCIe3 "FCSL110R005FER" FCSL110R005FERCT-ND 90.391,372.663 r180 top (schematic designator R448)
R448_U_Pomiar_pradu_napiecia_PCIe4 "FCSL110R005FER" FCSL110R005FERCT-ND 139.473,260.116 r0 top (schematic designator R448)
R449 "1kR" "RES 0402/1005 RF KK" 95.195,387.28 r180 top
R450 "0mR" "RES 0402/1005 RF KK" 92.583,387.28 r180 top
R451 "1kR" "RES 0402/1005 RF KK" 95.195,385.877 r180 top
R452 "0mR" "RES 0402/1005 RF KK" 92.583,385.877 r180 top
R453 "1kR" "RES 0402/1005 RF KK" 95.195,388.683 r180 top
R454 "0mR" "RES 0402/1005 RF KK" 92.583,388.683 r180 top
R455 "1kR" "RES 0402/1005 RF KK" 51.217,152.11 r0 top
R456 "0mR" "RES 0402/1005 RF KK" 49.185,152.11 r180 top
R457 "1kR" "RES 0402/1005 RF KK" 33.32,151.621 r0 top
R458 "1kR" "RES 0402/1005 RF KK" 51.217,153.126 r0 top
R459 "1kR" "RES 0402/1005 RF KK" 33.32,152.637 r0 top
R460 "0mR" "RES 0402/1005 RF KK" 49.185,153.126 r180 top
R461 "1kR" "RES 0402/1005 RF KK" 31.288,153.653 r180 top
R462 "1kR" "RES 0402/1005 RF KK" 51.217,154.269 r0 top
R463 "1kR" "RES 0402/1005 RF KK" 31.288,154.669 r180 top
R464 "0mR" "RES 0402/1005 RF KK" 49.185,154.269 r180 top
R465 "1kR" "RES 0402/1005 RF KK" 31.288,151.621 r180 top
R466 "1kR" "RES 0402/1005 RF KK" 31.288,152.637 r180 top
R467 "1kR" "RES 0402/1005 RF KK" 31.608,209.555 r0 bottom
R468 "1kR" "RES 0402/1005 RF KK" 31.608,208.539 r0 bottom
R469 "1kR" "RES 0402/1005 RF KK" 80.807,304.401 r270 top
R470 "0mR" "RES 0402/1005 RF KK" 80.807,302.427 r270 top
R471 "1kR" "RES 0402/1005 RF KK" 81.823,304.401 r270 top
R472 "0mR" "RES 0402/1005 RF KK" 81.823,302.427 r270 top
R473 "1kR" "RES 0402/1005 RF KK" 79.743,304.389 r270 top
R474 "0mR" "RES 0402/1005 RF KK" 79.743,302.415 r270 top
R475 "1kR" "RES 0402/1005 RF KK" 44.356,322.712 r270 top
R476 "0mR" "RES 0402/1005 RF KK" 44.356,320.403 r270 top
R477 "1kR" "RES 0402/1005 RF KK" 45.372,322.712 r270 top
R478 "0mR" "RES 0402/1005 RF KK" 45.372,320.403 r270 top
R479 "1kR" "RES 0402/1005 RF KK" 46.434,322.712 r270 top
R480 "0mR" "RES 0402/1005 RF KK" 46.434,320.403 r270 top
R481 "0mR" "RES 0402/1005 RF KK" 168.442,411.413 r270 top
R482 "150R" "RES 0402/1005 RF KK" 133.18,308.1 r90 top
R483 "150R" "RES 0402/1005 RF KK" 133.18,306.235 r270 top
R484 "71.5R" "RES 0402/1005 RF KK" 134.673,307.65 r180 top
R485 "71.5R" "RES 0402/1005 RF KK" 134.673,306.685 r180 top
R486 "8.87kR" "RES 0402/1005 RF KK" 137.421,306.222 r90 top
R487 "5.1kR" "RES 0402/1005 RF KK" 138.412,306.222 r90 top
R488 "1kR" "RES 0402/1005 RF KK" 77.147,390.204 r180 top
R489 "100R" "RES 0402/1005 RF KK" 69.748,387.989 r90 top
R490 "10kR" "RES 0402/1005 RF KK" 50.706,347.841 r180 top
R491 "1MR" "RES 0402/1005 RF KK" 54.966,353.39 r0 bottom
R492 "1kR" "RES 0402/1005 RF KK" 156.598,252.62 r90 top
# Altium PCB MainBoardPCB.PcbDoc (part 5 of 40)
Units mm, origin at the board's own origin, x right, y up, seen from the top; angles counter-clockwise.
Board outline 258.95 x 308.86 mm, 16 copper layers (L1, L2 (GND), L3 (Sign), L4 (GND), L5 (Sign), L6 (PWR/GND), L7(12V+Other), L8 (Plane_GND), L9 (PWR/GND), L10 (3V3+Other), L11 (PWR/GND), L12 (Sign), L13 (GND), L14 (Sign), L15 (GND), L16), stack 2.503 mm thick; 2578 components, 1867 nets, 8817 pads, 8021 vias.
Unrouted connection lines stored in the file: 25.

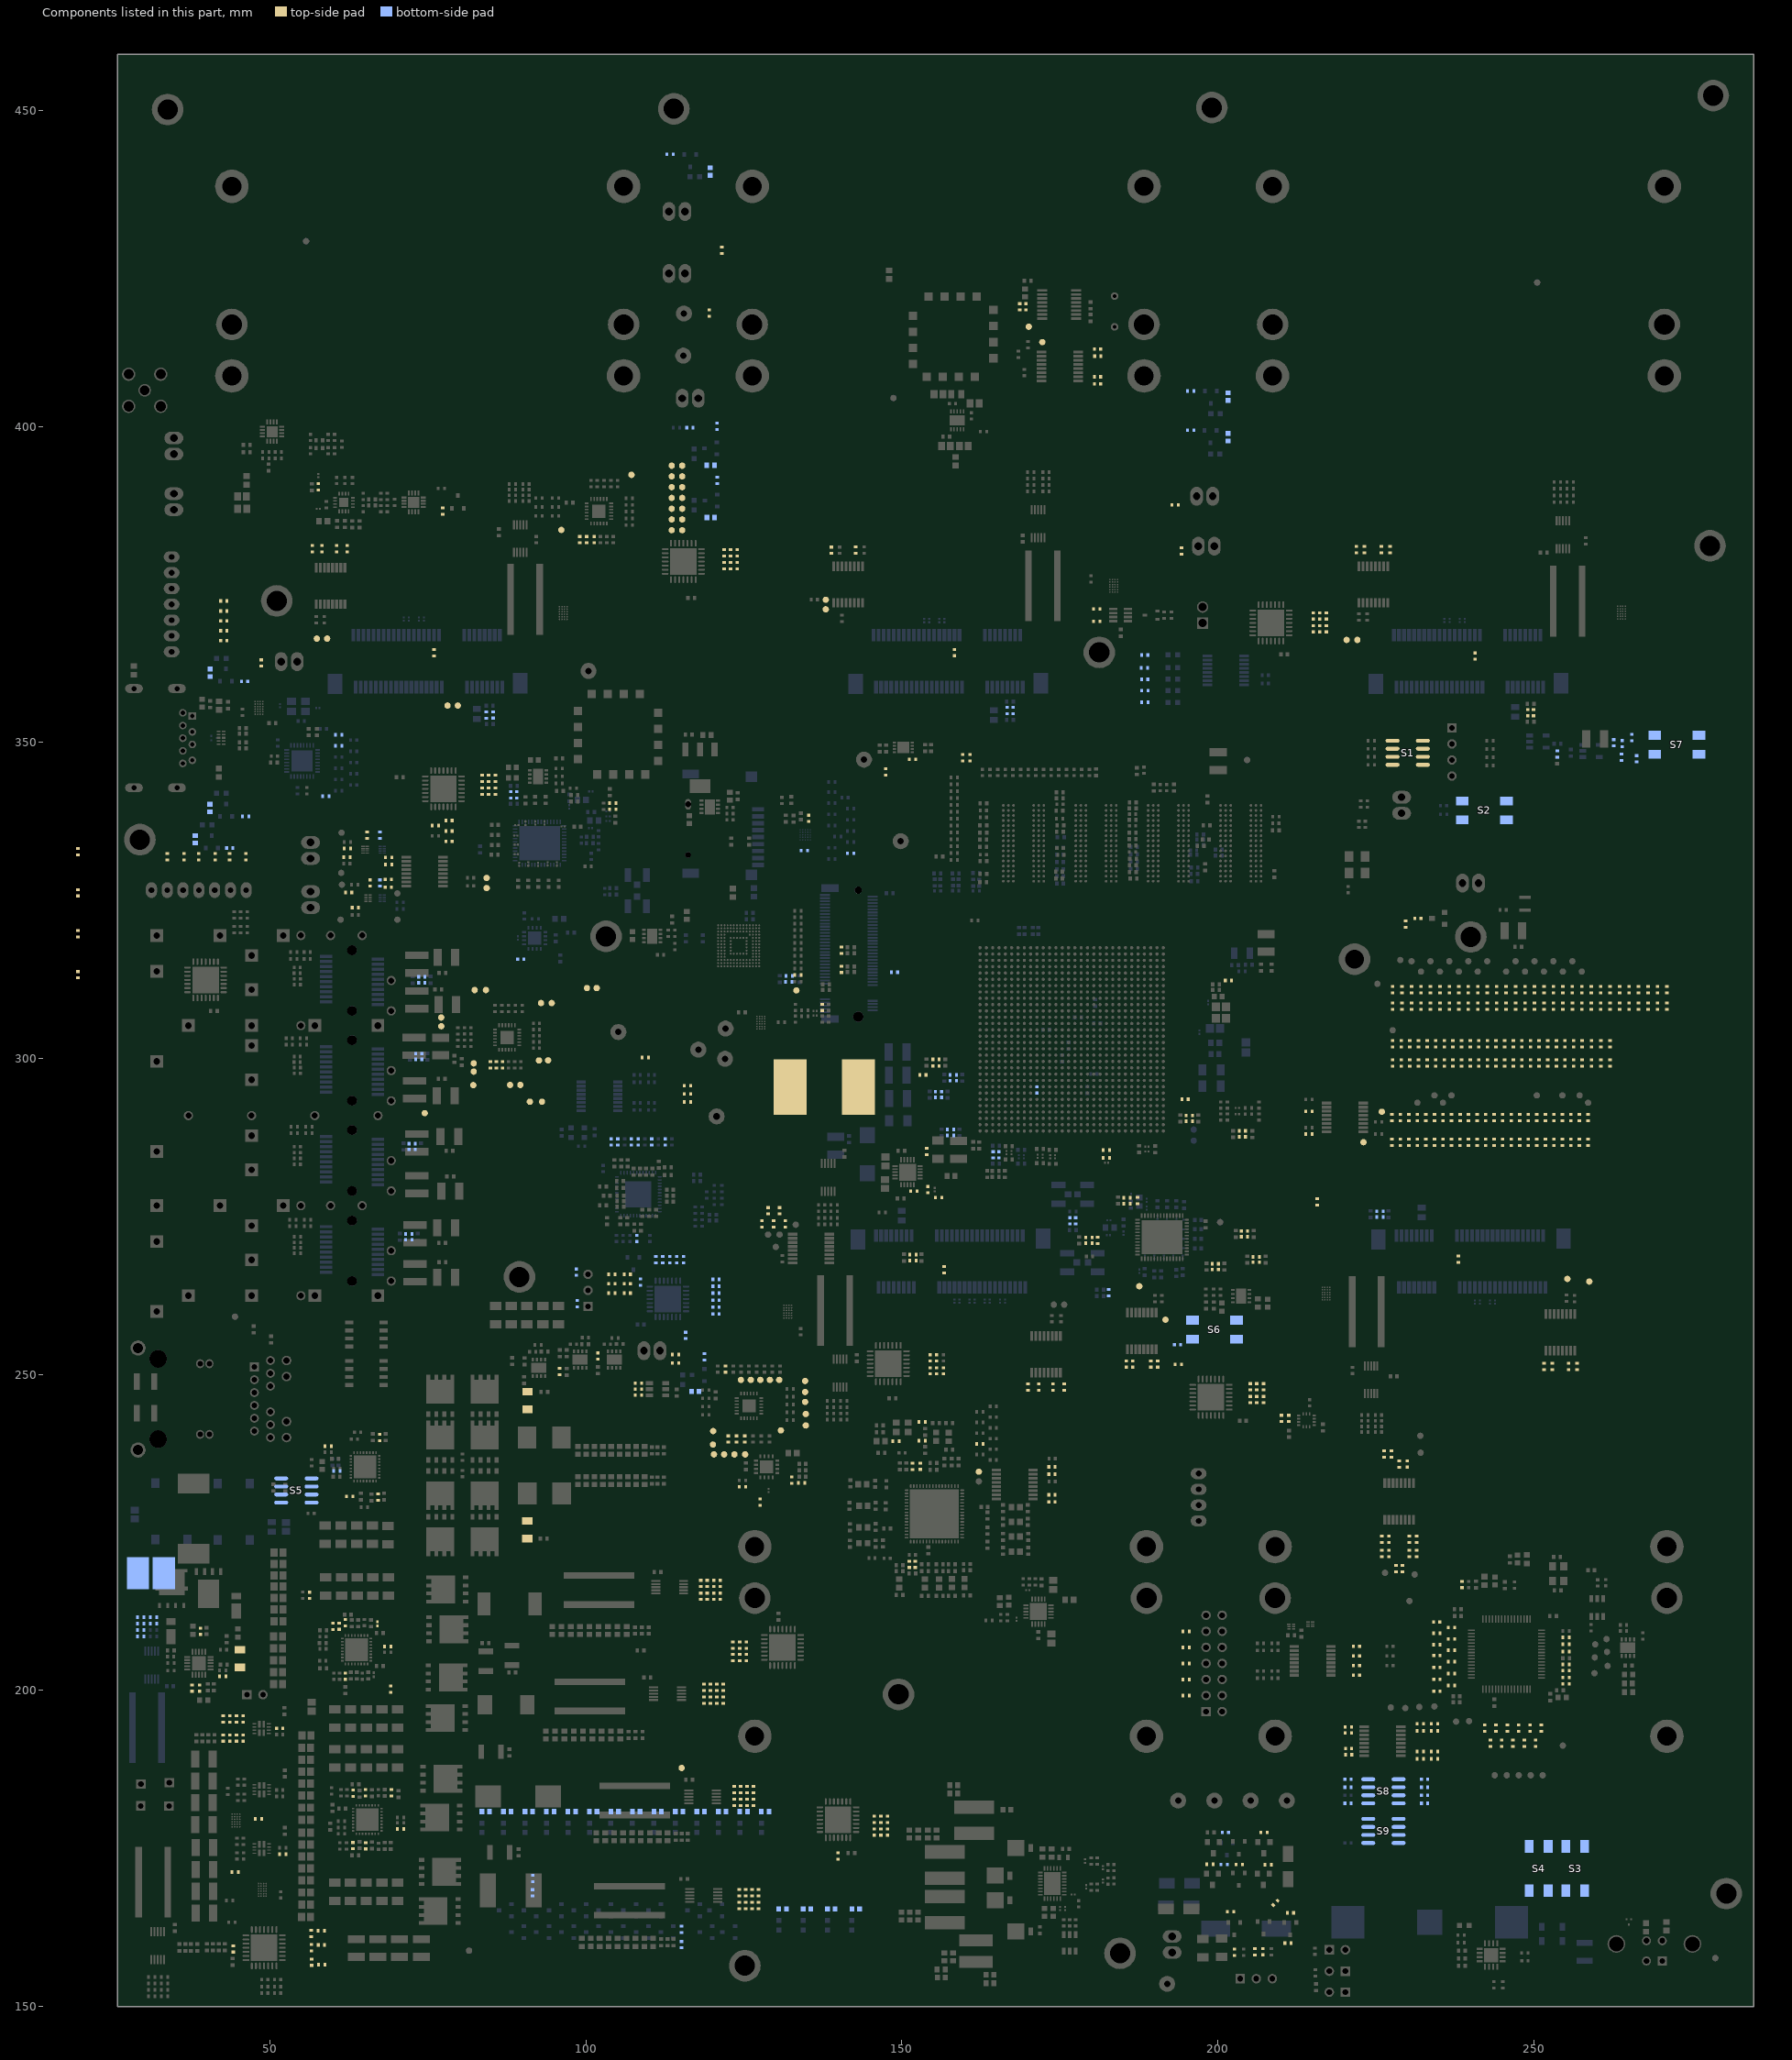
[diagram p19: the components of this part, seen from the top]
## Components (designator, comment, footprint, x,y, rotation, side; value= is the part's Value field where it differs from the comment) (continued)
R493 "0mR" "RES 0402/1005 RF KK" 156.598,250.588 r270 top
R494 "1kR" "RES 0402/1005 RF KK" 155.524,252.62 r90 top
R495 "0mR" "RES 0402/1005 RF KK" 155.524,250.588 r270 top
R496 "1kR" "RES 0402/1005 RF KK" 154.508,252.62 r90 top
R497 "0mR" "RES 0402/1005 RF KK" 154.508,250.588 r270 top
R498 "0mR" "RES 0402/1005 RF KK" 151.701,235.458 r90 top
R499 "1kR" "RES 0402/1005 RF KK" 193.751,251.6 r180 top
R500 "1kR" "RES 0402/1005 RF KK" 85.683,344.334 r90 top
R501 "0mR" "RES 0402/1005 RF KK" 85.683,342.302 r270 top
R502 "1kR" "RES 0402/1005 RF KK" 84.609,344.334 r90 top
R503 "0mR" "RES 0402/1005 RF KK" 84.609,342.302 r270 top
R504 "1kR" "RES 0402/1005 RF KK" 83.593,344.334 r90 top
R505 "0mR" "RES 0402/1005 RF KK" 83.593,342.302 r270 top
R506 "0mR" "RES 0402/1005 RF KK" 215.756,277.31 r270 top
R507 "0mR" "RES 0402/1005 RF KK" 158.337,364.243 r90 top
R508 "1kR" "RES 0402/1005 RF KK" 123.963,380.028 r90 top
R509 "0mR" "RES 0402/1005 RF KK" 123.963,377.996 r270 top
R510 "1kR" "RES 0402/1005 RF KK" 122.889,380.028 r90 top
R511 "0mR" "RES 0402/1005 RF KK" 122.889,377.996 r270 top
R512 "1kR" "RES 0402/1005 RF KK" 121.873,380.028 r90 top
R513 "0mR" "RES 0402/1005 RF KK" 121.873,377.996 r270 top
R514 "0mR" "RES 0402/1005 RF KK" 238.087,268.244 r270 top
R515 "10kR" "RES 0402/1005 RF KK" 242.686,299.297 r90 top
R516 "1kR" "RES 0402/1005 RF KK" 217.215,370.045 r90 top
R517 "0mR" "RES 0402/1005 RF KK" 217.215,368.013 r270 top
R518 "1kR" "RES 0402/1005 RF KK" 216.141,370.045 r90 top
R519 "0mR" "RES 0402/1005 RF KK" 216.141,368.013 r270 top
R520 "1kR" "RES 0402/1005 RF KK" 215.125,370.045 r90 top
R521 "0mR" "RES 0402/1005 RF KK" 215.125,368.013 r270 top
R522 "10kR" "RES 0402/1005 RF KK" 245.413,299.297 r90 top
R523 "10kR" "RES 0402/1005 RF KK" 231.607,286.757 r270 top
R524 "1kR" "RES 0402/1005 RF KK" 207.265,248.06 r90 top
R525 "0mR" "RES 0402/1005 RF KK" 207.265,246.028 r270 top
R526 "1kR" "RES 0402/1005 RF KK" 206.191,248.06 r90 top
R527 "0mR" "RES 0402/1005 RF KK" 206.191,246.028 r270 top
R528 "1kR" "RES 0402/1005 RF KK" 205.175,248.06 r90 top
R529 "0mR" "RES 0402/1005 RF KK" 205.175,246.028 r270 top
R530 "0mR" "RES 0402/1005 RF KK" 242.686,302.335 r90 top
R531 "10kR" "RES 0402/1005 RF KK" 239.96,299.297 r90 top
R532 "75R" "RES 0402/1005 RF KK" 104.247,340.411 r180 top
R533 "30R" "RES 0402/1005 RF KK" 104.247,339.432 r180 top
R534 "160R" "RES 0402/1005 RF KK" 187.323,277.55 r90 top
R535 "100R" "RES 0402/1005 RF KK" 181.026,271.241 r90 top
R536 "100R" "RES 0402/1005 RF KK" 182.758,262.957 r270 bottom
R537 "0mR" "RES 0402/1005 RF KK" 57.675,390.468 r90 top
R538 "8.87kR" "RES 0402/1005 RF KK" 137.421,308.1 r270 top
R539 "0mR" "RES 0402/1005 RF KK" 167.615,355.087 r270 bottom
R540 "0mR" "RES 0402/1005 RF KK" 152.915,235.5 r90 top
R541 "100R" "RES 0402/1005 RF KK" 140.462,314.124 r90 top
R542 "100R" "RES 0402/1005 RF KK" 140.462,317.125 r270 top
R543 "100R" "RES 0402/1005 RF KK" 153.22,242.481 r0 top
R544 "1kR" "RES 0402/1005 RF KK" 149.091,239.444 r180 top
R545 "49.9R" "RES 0402/1005 RF KK" 153.22,239.511 r0 top
R546 "10kR" "RES 0402/1005 RF KK" 237.005,286.757 r270 top
R547 "0mR" "RES 0402/1005 RF KK" 245.413,302.335 r90 top
R548 "10kR" "RES 0402/1005 RF KK" 241.323,299.297 r90 top
R549 "10kR" "RES 0402/1005 RF KK" 234.306,286.757 r270 top
R550 "0mR" "RES 0402/1005 RF KK" 239.96,302.335 r90 top
R551 "10kR" "RES 0402/1005 RF KK" 246.776,299.297 r90 top
R552 "10kR" "RES 0402/1005 RF KK" 251.85,286.757 r270 top
R553 "0mR" "RES 0402/1005 RF KK" 241.323,302.335 r90 top
R554 "10kR" "RES 0402/1005 RF KK" 248.14,299.297 r90 top
R555 "10kR" "RES 0402/1005 RF KK" 243.753,286.757 r270 top
R556 "0mR" "RES 0402/1005 RF KK" 246.776,302.335 r90 top
R557 "10kR" "RES 0402/1005 RF KK" 249.503,299.297 r90 top
R558_I2C_Bridge_GPIO "1kR" "RES 0402/1005 RF KK" 125.173,239.794 r90 top (schematic designator R558)
R558_I2C_Bridge_PCIE "1kR" "RES 0402/1005 RF KK" 101.32,382.099 r90 top (schematic designator R558)
R558_I2C_Bridge_SFP "1kR" "RES 0402/1005 RF KK" 86.811,298.998 r90 top (schematic designator R558)
R559_I2C_Bridge_GPIO "1kR" "RES 0402/1005 RF KK" 123.867,239.794 r90 top (schematic designator R559)
R559_I2C_Bridge_PCIE "1kR" "RES 0402/1005 RF KK" 100.135,382.099 r90 top (schematic designator R559)
R559_I2C_Bridge_SFP "1kR" "RES 0402/1005 RF KK" 85.846,298.998 r90 top (schematic designator R559)
R560_I2C_Bridge_GPIO "1kR" "RES 0402/1005 RF KK" 122.562,239.794 r90 top (schematic designator R560)
R560_I2C_Bridge_PCIE "1kR" "RES 0402/1005 RF KK" 99.022,382.099 r90 top (schematic designator R560)
R560_I2C_Bridge_SFP "1kR" "RES 0402/1005 RF KK" 84.88,298.998 r90 top (schematic designator R560)
R561 "1kR" "RES 0402/1005 RF KK" 124.498,184.31 r90 top
R562 "1kR" "RES 0402/1005 RF KK" 123.482,184.31 r90 top
R563 "1kR" "RES 0402/1005 RF KK" 126.53,184.31 r90 top
R564 "1kR" "RES 0402/1005 RF KK" 125.514,184.31 r90 top
R565 "1kR" "RES 0402/1005 RF KK" 124.498,182.278 r270 top
R566 "1kR" "RES 0402/1005 RF KK" 123.482,182.278 r270 top
R567 "1kR" "RES 0402/1005 RF KK" 126.53,182.278 r270 top
R568 "1kR" "RES 0402/1005 RF KK" 125.514,182.278 r270 top
R569 "1kR" "RES 0402/1005 RF KK" 125.281,168.011 r90 top
R570 "1kR" "RES 0402/1005 RF KK" 124.265,168.011 r90 top
R571 "1kR" "RES 0402/1005 RF KK" 127.313,168.011 r90 top
R572 "1kR" "RES 0402/1005 RF KK" 126.297,168.011 r90 top
R573 "1kR" "RES 0402/1005 RF KK" 125.281,165.979 r270 top
R574 "1kR" "RES 0402/1005 RF KK" 124.265,165.979 r270 top
R575 "1kR" "RES 0402/1005 RF KK" 127.313,165.979 r270 top
R576 "1kR" "RES 0402/1005 RF KK" 126.297,165.979 r270 top
R577 "1kR" "RES 0402/1005 RF KK" 119.228,216.941 r90 top
R578 "1kR" "RES 0402/1005 RF KK" 118.212,216.941 r90 top
R579 "1kR" "RES 0402/1005 RF KK" 121.26,216.941 r90 top
R580 "1kR" "RES 0402/1005 RF KK" 120.244,216.941 r90 top
R581 "1kR" "RES 0402/1005 RF KK" 119.228,214.909 r270 top
R582 "1kR" "RES 0402/1005 RF KK" 118.212,214.909 r270 top
R583 "1kR" "RES 0402/1005 RF KK" 121.26,214.909 r270 top
R584 "1kR" "RES 0402/1005 RF KK" 120.244,214.909 r270 top
R585 "1kR" "RES 0402/1005 RF KK" 119.698,200.521 r90 top
R586 "1kR" "RES 0402/1005 RF KK" 118.682,200.521 r90 top
R587 "1kR" "RES 0402/1005 RF KK" 121.73,200.521 r90 top
R588 "1kR" "RES 0402/1005 RF KK" 120.714,200.521 r90 top
R589 "1kR" "RES 0402/1005 RF KK" 119.698,198.489 r270 top
R590 "1kR" "RES 0402/1005 RF KK" 118.682,198.489 r270 top
R591 "1kR" "RES 0402/1005 RF KK" 121.73,198.489 r270 top
R592 "1kR" "RES 0402/1005 RF KK" 120.714,198.489 r270 top
R593 "1kR" "RES 0402/1005 RF KK" 31.608,211.587 r0 bottom
R594 "1kR" "RES 0402/1005 RF KK" 31.608,210.571 r0 bottom
R595 "1kR" "RES 0402/1005 RF KK" 29.576,209.555 r180 bottom
R596 "1kR" "RES 0402/1005 RF KK" 29.576,208.539 r180 bottom
R597 "1kR" "RES 0402/1005 RF KK" 29.576,211.587 r180 bottom
R598 "1kR" "RES 0402/1005 RF KK" 29.576,210.571 r180 bottom
R599 "1kR" "RES 0402/1005 RF KK" 122.097,250.869 r90 top
R600 "0mR" "RES 0402/1005 RF KK" 210.075,243.054 r270 top
R601 "0mR" "RES 0402/1005 RF KK" 211.261,243.054 r90 top
R602_SPI_bridge_Main "0mR" "RES 0402/1005 RF KK" 214.452,291.652 r180 top (schematic designator R602)
R602_SPI_bridge_PCIe "0mR" "RES 0402/1005 RF KK" 142.687,380.477 r90 top (schematic designator R602)
R603_SPI_bridge_Main "0mR" "RES 0402/1005 RF KK" 214.452,288.068 r0 top (schematic designator R603)
R603_SPI_bridge_PCIe "0mR" "RES 0402/1005 RF KK" 138.857,380.427 r270 top (schematic designator R603)
R604_SPI_bridge_Main "0mR" "RES 0402/1005 RF KK" 185.538,251.673 r270 top (schematic designator R604)
R604_SPI_bridge_PCIe "0mR" "RES 0402/1005 RF KK" 251.666,251.289 r270 top (schematic designator R604)
R605_SPI_bridge_Main "0mR" "RES 0402/1005 RF KK" 189.416,251.673 r90 top (schematic designator R605)
R605_SPI_bridge_PCIe "0mR" "RES 0402/1005 RF KK" 255.537,251.289 r90 top (schematic designator R605)
R606_SPI_bridge_Main "0mR" "RES 0402/1005 RF KK" 186.548,251.673 r270 top (schematic designator R606)
R606_SPI_bridge_PCIe "0mR" "RES 0402/1005 RF KK" 252.94,251.289 r270 top (schematic designator R606)
R607 "10kR" "RES 0402/1005 RF KK" 238.355,286.758 r270 top
R608 "10k" "RES 0402/1005 RF KK" 168.671,418.947 r90 top
R609 "10k" "RES 0402/1005 RF KK" 169.661,418.939 r270 top
R610 "1.33kR" "RES 0402/1005 RF KK" 67.378,240.02 r90 top
R611 "1.33kR" "RES 0402/1005 RF KK" 67.113,230.597 r270 top
R612 "270R" "RES 0402/1005 RF KK" 59.242,238.671 r180 top
R613 "2.4R" "RES 1206/3216" 90.765,245.884 r270 top
R614 "270R" "RES 0402/1005 RF KK" 62.638,230.712 r180 top
R615 "1kR" "RES 0402/1005 RF KK" 60.606,234.739 r0 bottom
R616 "2.4R" "RES 1206/3216" 90.717,225.431 r90 top
R617 "PU5931FKMP70R004L" PU5931 137.735,295.465 r0 top
R618 "0mR" "RES 0402/1005 RF KK" 248.14,302.335 r90 top
R619 "1.91kR" "RES 0402/1005 RF KK" 69.228,183.819 r90 top
R620 "2kR" "RES 0402/1005 RF KK" 70.68,178.1 r180 top
R621 "147kR" "RES 0402/1005 RF KK" 65.137,183.819 r90 top
R622 "340kR" "RES 0402/1005 RF KK" 65.175,175.443 r270 top
R623 "1.43kR" "RES 0402/1005 RF KK" 63.12,175.457 r90 top
R624 "15kR" "RES 0402/1005 RF KK" 63.175,183.76 r270 top
R625 "1.4kR" "RES 0201/0603" 67.001,210.554 r270 top
R626 "200kR" "RES 0402/1005 RF KK" 59.997,210.161 r90 top
R627 "10.5kR" "RES 0402/1005 RF KK" 60.944,210.183 r270 top
R628 "750kR" "RES 0402/1005 RF KK" 69.132,200.233 r270 top
R629 "" "RES 0402/1005 RF KK" 68.656,206.964 r180 top
R630 "10kR" "RES 0402/1005 RF KK" 52.05,174.091 r180 top
R631 "5.9kR" "RES 0402/1005 RF KK" 61.938,202.273 r90 top
R632 "100kR" "RES 0402/1005 RF KK" 108.341,246.733 r180 top
R633 "100kR" "RES 0402/1005 RF KK" 108.341,247.684 r180 top
R634 "100kR" "RES 0402/1005 RF KK" 108.341,248.634 r180 top
R635 "10k" "RES 0402/1005 RF KK" 220.642,184.688 r180 bottom
R636 "0mR" "RES 0402/1005 RF KK" 234.333,189.21 r180 top
R637 "0mR" "RES 0402/1005 RF KK" 232.073,189.21 r0 top
R638 "0mR" "RES 0402/1005 RF KK" 234.333,190.348 r180 top
R639 "0mR" "RES 0402/1005 RF KK" 232.073,190.348 r0 top
R640 "0mR" "RES 0402/1005 RF KK" 234.333,193.598 r180 top
R641 "0mR" "RES 0402/1005 RF KK" 232.073,193.598 r0 top
R642 "0mR" "RES 0402/1005 RF KK" 234.333,194.737 r180 top
R643 "0mR" "RES 0402/1005 RF KK" 232.073,194.737 r0 top
R644 "9.1kR" "RES 0402/1005 RF KK" 132.588,233.309 r90 top
R645 "13kR" "RES 0402/1005 RF KK" 134.156,232.859 r180 top
R646 "100kR" "RES 0402/1005 RF KK" 127.572,229.826 r90 top
R647 "100kR" "RES 0402/1005 RF KK" 209.143,166.395 r45 top
R648 "2R" "RES 0402/1005 RF KK" 211.137,160.033 r0 top
R649 "10k" "RES 0402/1005 RF KK" 207.162,158.686 r90 top
R650 "100MR" "RES 0402/1005 RF KK" 208.001,172.453 r0 top
R651 "10k" "RES 0402/1005 RF KK" 198.788,172.492 r180 top
R652 "1MR" "RES 0402/1005 RF KK" 211.506,164.834 r0 top
R653 "20R" "RES 0402/1005 RF KK" 203.416,172.467 r180 top
R654 "100R" "RES 0402/1005 RF KK" 202.667,158.573 r270 top
R655 "10k" "RES 0402/1005 RF KK" 202.039,164.999 r0 top
R656 "10k" "RES 0402/1005 RF KK" 207.34,177.547 r180 top
R657 "100R" "RES 0402/1005 RF KK" 201.028,172.467 r180 bottom
R658 "10k" "RES 0402/1005 RF KK" 201.206,177.56 r180 bottom
R659 "10kR" "RES 0402/1005 RF KK" 253.593,299.297 r90 top
R660 "10kR" "RES 0402/1005 RF KK" 239.704,286.758 r270 top
R661 "10kR" "RES 0402/1005 RF KK" 252.23,299.297 r90 top
R662 "10kR" "RES 0402/1005 RF KK" 245.102,286.758 r270 top
R663 "10kR" "RES 0402/1005 RF KK" 259.161,299.297 r90 top
R664 "10kR" "RES 0402/1005 RF KK" 241.054,286.758 r270 top
R665 "0mR" "RES 0402/1005 RF KK" 39.014,209.378 r270 top
R666 "12mR" "RES 1206/3216" 45.266,205.057 r90 top
R667 "24.9kR" "RES 0402/1005 RF KK" 42.528,202.265 r180 top
R668 "20kR" "RES 0402/1005 RF KK" 124.777,232.245 r180 top
R669 "0mR" "RES 0402/1005 RF KK" 38.887,200.381 r270 top
R670 "0mR" "RES 0402/1005 RF KK" 37.668,200.388 r270 top
R671 "1.87kR" "RES 0402/1005 RF KK" 182.401,284.274 r0 top
R672 "1.5kR" "RES 0402/1005 RF KK" 182.401,285.514 r180 top
R673 "1.87kR" "RES 0402/1005 RF KK" 154.127,279.248 r90 top
R674 "15kR" "RES 0402/1005 RF KK" 155.816,278.016 r180 top
R675 "0mR" "RES 0402/1005 RF KK" 98.654,261.232 r270 bottom
R676 "20kR" "RES 0402/1005 RF KK" 151.914,279.02 r180 top
R677 "95.3kR" "RES 0402/1005 RF KK" 44.716,192.483 r270 top
R678 "95.3kR" "RES 0402/1005 RF KK" 43.658,192.483 r270 top
R679 "95.3kR" "RES 0402/1005 RF KK" 45.775,195.483 r90 top
R680 "95.3kR" "RES 0402/1005 RF KK" 43.658,195.483 r90 top
R681 "24.9kR" "RES 0402/1005 RF KK" 51.568,194.019 r180 top
R682 "7.5kR" "RES 0402/1005 RF KK" 45.775,192.483 r90 top
R683 "4.87kR" "RES 0402/1005 RF KK" 42.6,192.483 r90 top
R684 "7.15kR" "RES 0402/1005 RF KK" 44.716,195.483 r270 top
R685 "5.9kR" "RES 0402/1005 RF KK" 42.6,195.483 r270 top
R686 "412kR" "RES 0402/1005 RF KK" 56.27,215.062 r90 top
R687 "57.6kR" "RES 0402/1005 RF KK" 61.953,210.719 r270 top
R688 "0mR" "RES 0402/1005 RF KK" 249.503,302.335 r90 top
R689 "20kR" "RES 0402/1005 RF KK" 160.795,347.612 r90 top
R690 "100kR" "RES 0402/1005 RF KK" 159.652,347.612 r90 top
R691 "20kR" "RES 0402/1005 RF KK" 151.692,347.358 r0 top
R692 "0mR" "RES 0402/1005 RF KK" 193.65,254.724 r0 bottom
R693 "0mR" "RES 0402/1005 RF KK" 194.824,293.548 r0 top
R694 "1kR" "RES 0402/1005 RF KK" 231.673,322.182 r180 top
R695 "100R" "RES 0402/1005 RF KK" 171.394,295.046 r270 bottom
R696 "0mR" "RES 0402/1005 RF KK" 229.761,321.277 r270 top
R697 "1kR" "RES 0402/1005 RF KK" 147.739,179.615 r90 top
R698 "0mR" "RES 0402/1005 RF KK" 147.739,177.615 r270 top
R699 "1kR" "RES 0402/1005 RF KK" 146.698,179.615 r90 top
R700 "0mR" "RES 0402/1005 RF KK" 146.698,177.615 r270 top
R701 "1kR" "RES 0402/1005 RF KK" 145.653,179.615 r90 top
R702 "0mR" "RES 0402/1005 RF KK" 145.653,177.615 r270 top
R703 "0mR" "RES 0402/1005 RF KK" 72.527,285.627 r180 bottom
R704 "0mR" "RES 0402/1005 RF KK" 72.527,286.541 r180 bottom
R705 "0mR" "RES 0402/1005 RF KK" 157.708,288.76 r180 bottom
R706 "0mR" "RES 0402/1005 RF KK" 157.708,287.846 r180 bottom
R707 "0mR" "RES 0402/1005 RF KK" 74.041,312.001 r180 bottom
R708 "0mR" "RES 0402/1005 RF KK" 74.041,312.915 r180 bottom
R709 "2.2kR" "RES 0402/1005 RF KK" 108.074,271.544 r90 bottom
R710 "10kR" "RES 0402/1005 RF KK" 263.919,347.657 r270 bottom
R711 "0mR" "RES 0402/1005 RF KK" 262.674,349.961 r90 bottom
R712 "0mR" "RES 0402/1005 RF KK" 264.008,349.821 r270 bottom
R713 "0mR" "RES 0402/1005 RF KK" 265.532,350.794 r270 bottom
R714 "2.2kR" "RES 0402/1005 RF KK" 266.306,347.434 r90 bottom
R715 "10kR" "RES 0402/1005 RF KK" 253.771,348.166 r270 bottom
R716 "261R" "RES 0402/1005 RF KK" 188.452,363.868 r180 bottom
R717 "261R" "RES 0402/1005 RF KK" 188.412,361.831 r180 bottom
R718 "261R" "RES 0402/1005 RF KK" 188.455,360.007 r180 bottom
R719 "261R" "RES 0402/1005 RF KK" 188.462,356.362 r180 bottom
R720 "261R" "RES 0402/1005 RF KK" 188.462,358.229 r180 bottom
R721 "10k" "RES 0402/1005 RF KK" 220.642,185.958 r180 bottom
R722 "0mR" "RES 0402/1005 RF KK" 225.959,221.69 r90 top
R723 "0mR" "RES 0402/1005 RF KK" 225.959,223.95 r270 top
R724 "0mR" "RES 0402/1005 RF KK" 227.098,221.69 r90 top
R725 "0mR" "RES 0402/1005 RF KK" 227.098,223.95 r270 top
R726 "0mR" "RES 0402/1005 RF KK" 230.348,221.69 r90 top
R727 "0mR" "RES 0402/1005 RF KK" 230.348,223.95 r270 top
R728 "0mR" "RES 0402/1005 RF KK" 231.487,221.69 r90 top
R729 "0mR" "RES 0402/1005 RF KK" 231.487,223.95 r270 top
R730 "4.7kR" "RES 0402/1005 RF KK" 195.016,209.369 r180 top
R731 "4.7kR" "RES 0402/1005 RF KK" 195.016,199.209 r180 top
R732 "4.7kR" "RES 0402/1005 RF KK" 195.016,201.749 r180 top
R733 "4.7kR" "RES 0402/1005 RF KK" 195.016,204.289 r180 top
R734 "4.7kR" "RES 0402/1005 RF KK" 195.016,206.829 r180 top
R735 "10kR" "RES 0402/1005 RF KK" 254.956,299.297 r90 top
R736 "10kR" "RES 0402/1005 RF KK" 246.452,286.758 r270 top
R737 "10kR" "RES 0402/1005 RF KK" 98.501,266.193 r90 bottom
R738 "1kR" "RES 0402/1005 RF KK" 123.273,205.228 r270 top
R739 "1kR" "RES 0402/1005 RF KK" 123.273,207.159 r270 top
R740 "1kR" "RES 0402/1005 RF KK" 124.34,205.228 r270 top
R741 "1kR" "RES 0402/1005 RF KK" 124.34,207.159 r270 top
R742 "1kR" "RES 0402/1005 RF KK" 125.394,205.228 r270 top
R743 "1kR" "RES 0402/1005 RF KK" 125.394,207.159 r270 top
R744 "0mR" "RES 0402/1005 RF KK" 253.593,302.335 r90 top
R745 "20kR" "RES 0402/1005 RF KK" 153.962,285.28 r270 top
R746 "10kR" "RES 0402/1005 RF KK" 111.087,268.181 r90 bottom
R747 "10kR" "RES 0402/1005 RF KK" 112.185,268.181 r90 bottom
R748 "10kR" "RES 0402/1005 RF KK" 113.284,268.181 r90 bottom
R749 "10kR" "RES 0402/1005 RF KK" 114.383,268.181 r90 bottom
R750 "10kR" "RES 0402/1005 RF KK" 115.481,268.181 r90 bottom
R751 "10kR" "RES 0402/1005 RF KK" 120.619,265.049 r0 bottom
R752 "10kR" "RES 0402/1005 RF KK" 120.619,263.957 r0 bottom
R753 "10kR" "RES 0402/1005 RF KK" 120.619,262.865 r0 bottom
R754 "10kR" "RES 0402/1005 RF KK" 120.619,261.772 r0 bottom
R755 "10kR" "RES 0402/1005 RF KK" 120.619,260.68 r0 bottom
R756 "10kR" "RES 0402/1005 RF KK" 120.619,259.588 r0 bottom
R757 "10kR" "RES 0402/1005 RF KK" 115.781,256.177 r270 bottom
R758 "1kR" "RES 0402/1005 RF KK" 106.559,265.852 r180 top
R759 "0mR" "RES 0402/1005 RF KK" 104.133,265.852 r180 top
R760 "1kR" "RES 0402/1005 RF KK" 106.559,264.358 r180 top
R761 "0mR" "RES 0402/1005 RF KK" 104.133,264.358 r180 top
R762 "1kR" "RES 0402/1005 RF KK" 106.559,262.865 r180 top
R763 "0mR" "RES 0402/1005 RF KK" 104.133,262.865 r180 top
R764 "WSHP28184L000FEA" WSHP2818 31.166,218.554 r0 bottom
R765 "10kR" "RES 0402/1005 RF KK" 250.866,299.297 r90 top
R766 "10kR" "RES 0402/1005 RF KK" 242.403,286.758 r270 top
R767 "0mR" "RES 0402/1005 RF KK" 252.23,302.335 r90 top
R768 "0mR" "RES 0402/1005 RF KK" 153.34,297.394 r0 top
R769 "0mR" "RES 0402/1005 RF KK" 116.078,294.405 r180 top
R770 "0mR" "RES 0402/1005 RF KK" 116.078,295.694 r180 top
R771 "0mR" "RES 0402/1005 RF KK" 116.078,293.115 r180 top
R772 "0mR" "RES 0402/1005 RF KK" 62.451,326.276 r180 top
R773 "0mR" "RES 0402/1005 RF KK" 63.531,323.863 r0 top
R774 "0mR" "RES 0402/1005 RF KK" 62.255,333.235 r0 top
R775 "0mR" "RES 0402/1005 RF KK" 62.179,331.864 r0 top
R776 "0mR" "RES 0402/1005 RF KK" 220.717,190.809 r180 top
R777 "0mR" "RES 0402/1005 RF KK" 220.718,189.856 r180 top
R778 "0mR" "RES 0402/1005 RF KK" 220.664,194.229 r180 top
R779 "0mR" "RES 0402/1005 RF KK" 220.668,193.302 r180 top
R780 "0mR" "RES 0402/1005 RF KK" 193.249,387.591 r180 top
R781 "0mR" "RES 0402/1005 RF KK" 116.474,399.809 r0 bottom
R782 "0mR" "RES 0402/1005 RF KK" 141.908,332.473 r0 bottom
R783 "0mR" "RES 0402/1005 RF KK" 205.867,158.649 r90 top
R784 "0mR" "RES 0402/1005 RF KK" 42.71,366.145 r0 top
R785 "0mR" "RES 0402/1005 RF KK" 42.71,367.706 r0 top
R786 "0mR" "RES 0402/1005 RF KK" 42.71,369.267 r0 top
R787 "0mR" "RES 0402/1005 RF KK" 42.71,370.828 r0 top
R788 "0mR" "RES 0402/1005 RF KK" 148.849,313.665 r0 bottom
R789 "0mR" "RES 0402/1005 RF KK" 42.71,372.389 r0 top
R790 "0mR" "RES 0402/1005 RF KK" 46.199,331.914 r90 top
R791 "0mR" "RES 0402/1005 RF KK" 43.646,331.914 r90 top
R792 "0mR" "RES 0402/1005 RF KK" 41.335,331.914 r90 top
R793 "0mR" "RES 0402/1005 RF KK" 38.731,331.914 r90 top
R794 "0mR" "RES 0402/1005 RF KK" 36.407,331.914 r90 top
R795 "0mR" "RES 0402/1005 RF KK" 33.766,331.914 r90 top
R796 "0mR" "RES 0402/1005 RF KK" 119.532,417.964 r270 top
R797 "0mR" "RES 0402/1005 RF KK" 133.566,313.233 r0 top
R798 "0mR" "RES 0402/1005 RF KK" 180.855,371.142 r180 top
R799 "0mR" "RES 0402/1005 RF KK" 180.855,369.192 r180 top
R800 "0mR" "RES 0402/1005 RF KK" 60.877,351.248 r0 bottom
R801 "0mR" "RES 0402/1005 RF KK" 60.877,349.475 r0 bottom
R802 "0mR" "RES 0402/1005 RF KK" 58.839,341.507 r0 bottom
R803 "0mR" "RES 0402/1005 RF KK" 78.346,337.668 r0 top
R804 "0mR" "RES 0402/1005 RF KK" 109.405,300.177 r0 top
R805 "0mR" "RES 0402/1005 RF KK" 121.526,427.888 r270 top
R806 "0mR" "RES 0402/1005 RF KK" 78.346,334.353 r0 top
R807 "0mR" "RES 0402/1005 RF KK" 76.199,336.88 r0 top
R808 "0mR" "RES 0402/1005 RF KK" 78.346,336.01 r0 top
R809 "0mR" "RES 0402/1005 RF KK" 48.616,362.585 r270 top
R810 "0mR" "RES 0402/1005 RF KK" 147.447,345.364 r270 top
R811 "0mR" "RES 0402/1005 RF KK" 114.205,253.149 r0 top
R812 "0mR" "RES 0402/1005 RF KK" 194.259,380.321 r270 top
R813 "0mR" "RES 0402/1005 RF KK" 65.867,327.767 r90 top
R814 "0mR" "RES 0402/1005 RF KK" 65.39,335.362 r90 top
R815 "0mR" "RES 0402/1005 RF KK" 104.005,286.787 r90 bottom
R816 "0mR" "RES 0402/1005 RF KK" 105.075,286.787 r90 bottom
R817 "10kR" "RES 0402/1005 RF KK" 256.32,299.297 r90 top
R818 "10kR" "RES 0402/1005 RF KK" 247.801,286.758 r270 top
R819 "0mR" "RES 0402/1005 RF KK" 259.161,302.335 r90 top
R820 "10kR" "RES 0402/1005 RF KK" 257.683,299.297 r90 top
R821 "10kR" "RES 0402/1005 RF KK" 249.151,286.758 r270 top
R822 "0mR" "RES 0402/1005 RF KK" 254.956,302.335 r90 top
R823 "10kR" "RES 0402/1005 RF KK" 228.908,286.758 r90 top
R824 "10kR" "RES 0402/1005 RF KK" 255.898,286.758 r270 top
R825 "100kR" "RES 0402/1005 RF KK" 139.916,173.83 r90 top
R826 "10kR" "RES 0402/1005 RF KK" 101.905,252.92 r90 top
R827 "10kR" "RES 0402/1005 RF KK" 95.868,250.475 r270 top
R828 "100kR" "RES 0402/1005 RF KK" 44.197,159.116 r90 top
R829 "0mR" "RES 0402/1005 RF KK" 158.173,297.421 r180 bottom
R830 "0mR" "RES 0402/1005 RF KK" 158.173,296.507 r180 bottom
R831 "0mR" "RES 0402/1005 RF KK" 71.968,271.326 r180 bottom
R832 "0mR" "RES 0402/1005 RF KK" 71.968,272.241 r180 bottom
R833 "0mR" "RES 0402/1005 RF KK" 164.465,284.762 r270 bottom
R834 "0mR" "RES 0402/1005 RF KK" 165.38,284.762 r270 bottom
R835 "10kR" "RES 0402/1005 RF KK" 58.197,156.615 r180 top
R836 "10kR" "RES 0402/1005 RF KK" 58.157,159.75 r180 top
R837 "20kR" "RES 0402/1005 RF KK" 56.608,157.015 r90 top
R838 "10kR" "RES 0402/1005 RF KK" 58.147,162 r180 top
R839 "20kR" "RES 0402/1005 RF KK" 56.569,159.3 r270 top
R840 "20kR" "RES 0402/1005 RF KK" 56.558,161.55 r270 top
R841 "0mR" "RES 0402/1005 RF KK" 73.555,299.856 r180 bottom
R842 "0mR" "RES 0402/1005 RF KK" 73.555,300.77 r180 bottom
R843 "0mR" "RES 0402/1005 RF KK" 155.811,294.75 r180 bottom
R844 "0mR" "RES 0402/1005 RF KK" 155.811,293.836 r180 bottom
R845 "0mR" "RES 0402/1005 RF KK" 134.576,332.909 r0 bottom
R846 "10k" "RES 0402/1005 RF KK" 89.719,315.716 r0 bottom
R847 "10kR" "RES 0402/1005 RF KK" 262.116,299.297 r90 top
R848 "10kR" "RES 0402/1005 RF KK" 253.199,286.758 r270 top
R849 "10kR" "RES 0402/1005 RF KK" 227.559,286.758 r90 top
R850 "10kR" "RES 0402/1005 RF KK" 254.549,286.758 r270 top
R851 "0mR" "RES 0402/1005 RF KK" 250.866,302.335 r90 top
R852 "10kR" "RES 0402/1005 RF KK" 260.639,299.297 r90 top
R853 "10kR" "RES 0402/1005 RF KK" 250.5,286.758 r270 top
R854 "0mR" "RES 0402/1005 RF KK" 256.32,302.335 r90 top
R855 "10kR" "RES 0402/1005 RF KK" 230.258,286.758 r90 top
R856 "10kR" "RES 0402/1005 RF KK" 257.248,286.758 r270 top
R857 "0mR" "RES 0402/1005 RF KK" 257.683,302.335 r90 top
R858 "10kR" "RES 0402/1005 RF KK" 232.957,286.758 r90 top
R859 "10kR" "RES 0402/1005 RF KK" 258.597,286.758 r270 top
R860 "0mR" "RES 0402/1005 RF KK" 228.908,290.66 r90 top
R861 "10kR" "RES 0402/1005 RF KK" 235.656,286.758 r270 top
R862 "0mR" "RES 0402/1005 RF KK" 262.116,302.335 r90 top
R863 "0mR" "RES 0402/1005 RF KK" 227.559,290.66 r90 top
R864 "0mR" "RES 0402/1005 RF KK" 260.639,302.335 r90 top
R865 "0mR" "RES 0402/1005 RF KK" 230.258,290.66 r90 top
R866 "0mR" "RES 0402/1005 RF KK" 232.957,290.66 r90 top
R867 "0mR" "RES 0402/1005 RF KK" 235.656,290.66 r90 top
R868 "0mR" "RES 0402/1005 RF KK" 231.607,290.66 r90 top
R869 "0mR" "RES 0402/1005 RF KK" 237.005,290.66 r90 top
R870 "0mR" "RES 0402/1005 RF KK" 234.306,290.66 r90 top
R871 "0mR" "RES 0402/1005 RF KK" 251.85,290.66 r90 top
R872 "0mR" "RES 0402/1005 RF KK" 243.753,290.66 r90 top
R873 "0mR" "RES 0402/1005 RF KK" 238.379,290.652 r90 top
R874 "0mR" "RES 0402/1005 RF KK" 239.704,290.652 r90 top
R875 "0mR" "RES 0402/1005 RF KK" 245.102,290.66 r90 top
R876 "0mR" "RES 0402/1005 RF KK" 241.054,290.66 r90 top
R877 "0mR" "RES 0402/1005 RF KK" 246.452,290.66 r90 top
R878 "0mR" "RES 0402/1005 RF KK" 242.403,290.66 r90 top
R879 "0mR" "RES 0402/1005 RF KK" 247.801,290.66 r90 top
R880 "0mR" "RES 0402/1005 RF KK" 249.151,290.66 r90 top
R881 "0mR" "RES 0402/1005 RF KK" 255.898,290.66 r90 top
R882 "0mR" "RES 0402/1005 RF KK" 253.199,290.66 r90 top
R883 "0mR" "RES 0402/1005 RF KK" 254.549,290.66 r90 top
R884 "0mR" "RES 0402/1005 RF KK" 250.5,290.66 r90 top
R885 "0mR" "RES 0402/1005 RF KK" 257.248,290.66 r90 top
R886 "0mR" "RES 0402/1005 RF KK" 258.597,290.66 r90 top
R887_SPI_bridge_Main "0mR" "RES 0402/1005 RF KK" 190.488,251.673 r90 top (schematic designator R887)
R887_SPI_bridge_PCIe "0mR" "RES 0402/1005 RF KK" 256.891,251.289 r90 top (schematic designator R887)
R888_SPI_bridge_Main "0mR" "RES 0402/1005 RF KK" 68.804,331.84 r180 top (schematic designator R888)
R888_SPI_bridge_PCIe "0mR" "RES 0402/1005 RF KK" 227.265,380.53 r90 top (schematic designator R888)
R889_SPI_bridge_Main "0mR" "RES 0402/1005 RF KK" 68.754,328.34 r0 top (schematic designator R889)
R889_SPI_bridge_PCIe "0mR" "RES 0402/1005 RF KK" 223.24,380.53 r270 top (schematic designator R889)
R890_SPI_bridge_Main "0mR" "RES 0402/1005 RF KK" 68.804,330.703 r180 top (schematic designator R890)
R890_SPI_bridge_PCIe "0mR" "RES 0402/1005 RF KK" 225.92,380.53 r90 top (schematic designator R890)
R891_SPI_bridge_Main "0mR" "RES 0402/1005 RF KK" 68.754,327.115 r0 top (schematic designator R891)
R891_SPI_bridge_PCIe "0mR" "RES 0402/1005 RF KK" 221.965,380.53 r270 top (schematic designator R891)
R892_SPI_bridge_Main "0mR" "RES 0402/1005 RF KK" 180.982,406.752 r0 top (schematic designator R892)
R892_SPI_bridge_PCIe "0mR" "RES 0402/1005 RF KK" 62.238,380.682 r90 top (schematic designator R892)
R893_SPI_bridge_Main "0mR" "RES 0402/1005 RF KK" 181.032,411.141 r180 top (schematic designator R893)
R893_SPI_bridge_PCIe "0mR" "RES 0402/1005 RF KK" 58.229,380.683 r270 top (schematic designator R893)
R894_SPI_bridge_Main "0mR" "RES 0402/1005 RF KK" 180.982,407.891 r0 top (schematic designator R894)
R894_SPI_bridge_PCIe "0mR" "RES 0402/1005 RF KK" 60.563,380.683 r90 top (schematic designator R894)
R895_SPI_bridge_Main "0mR" "RES 0402/1005 RF KK" 180.982,412.28 r180 top (schematic designator R895)
R895_SPI_bridge_PCIe "0mR" "RES 0402/1005 RF KK" 56.733,380.682 r270 top (schematic designator R895)
R896_SPI_bridge_Main "0mR" "RES 0402/1005 RF KK" 173.78,229.85 r0 top (schematic designator R896)
R896_SPI_bridge_PCIe "0mR" "RES 0402/1005 RF KK" 169.964,248.006 r270 top (schematic designator R896)
R897_SPI_bridge_Main "0mR" "RES 0402/1005 RF KK" 173.78,234.238 r180 top (schematic designator R897)
R897_SPI_bridge_PCIe "0mR" "RES 0402/1005 RF KK" 173.938,248.006 r90 top (schematic designator R897)
R898_SPI_bridge_Main "0mR" "RES 0402/1005 RF KK" 173.78,230.988 r0 top (schematic designator R898)
R898_SPI_bridge_PCIe "0mR" "RES 0402/1005 RF KK" 171.673,248.006 r270 top (schematic designator R898)
R899_SPI_bridge_Main "0mR" "RES 0402/1005 RF KK" 173.78,235.377 r180 top (schematic designator R899)
R899_SPI_bridge_PCIe "0mR" "RES 0402/1005 RF KK" 175.706,248.006 r90 top (schematic designator R899)
R900 "0mR" "RES 0402/1005 RF KK" 77.372,386.639 r90 top
R901 "0mR" "RES 0402/1005 RF KK" 240.741,363.677 r90 top
R902 "0mR" "RES 0402/1005 RF KK" 75.985,364.23 r90 top
R903 "0mR" "RES 0402/1005 RF KK" 156.719,266.591 r270 top
R904 "0mR" "RES 0402/1005 RF KK" 127.889,273.85 r270 top
R905 "0mR" "RES 0402/1005 RF KK" 131.572,273.85 r270 top
R906 "0mR" "RES 0402/1005 RF KK" 130.658,275.913 r270 top
R907 "0mR" "RES 0402/1005 RF KK" 129.731,273.85 r270 top
R908 "0mR" "RES 0402/1005 RF KK" 128.841,275.913 r270 top
R909 "0mR" "RES 0402/1005 RF KK" 226.359,237.434 r270 top
R910 "0mR" "RES 0402/1005 RF KK" 227.482,237.434 r270 top
R911 "0mR" "RES 0402/1005 RF KK" 135.274,338.003 r90 top
R912 "0mR" "RES 0402/1005 RF KK" 162.382,239.033 r180 top
R913 "100R" "RES 0603/1608 RF" 128.38,180.867 r0 bottom
R914 "100R" "RES 0603/1608 RF" 107.974,180.867 r0 bottom
R915 "100R" "RES 0603/1608 RF" 124.979,180.867 r0 bottom
R916 "10kR" "RES 0402/1005 RF KK" 115.133,159.779 r90 bottom
R917 "100R" "RES 0603/1608 RF" 94.369,180.867 r0 bottom
R918 "0mR" "RES 0402/1005 RF KK" 67.43,335.362 r270 bottom
R919 "0mR" "RES 0402/1005 RF KK" 67.43,327.767 r270 bottom
R920 "240R" "RES 0402/1005 RF KK" 201.71,312.356 r0 top
R921 "10kR" "RES 0402/1005 RF KK" 229.053,299.297 r90 top
R922 "10kR" "RES 0402/1005 RF KK" 256.128,308.301 r270 top
R923 "10kR" "RES 0402/1005 RF KK" 238.596,299.297 r90 top
R924 "10kR" "RES 0402/1005 RF KK" 257.625,308.301 r270 top
R925 "10kR" "RES 0402/1005 RF KK" 263.613,308.301 r90 top
R926 "10kR" "RES 0402/1005 RF KK" 253.134,308.301 r270 top
R927 "10kR" "RES 0402/1005 RF KK" 237.233,299.297 r90 top
R928 "10kR" "RES 0402/1005 RF KK" 254.631,308.301 r270 top
R929 "10kR" "RES 0402/1005 RF KK" 266.607,308.301 r90 top
R930 "10kR" "RES 0402/1005 RF KK" 251.637,308.301 r270 top
R931 "10kR" "RES 0402/1005 RF KK" 265.11,308.301 r90 top
R932 "10kR" "RES 0402/1005 RF KK" 250.14,308.301 r270 top
R933 "10kR" "RES 0402/1005 RF KK" 271.098,308.301 r90 top
R934 "10kR" "RES 0402/1005 RF KK" 227.686,308.301 r270 top
R935 "10kR" "RES 0402/1005 RF KK" 268.104,308.301 r90 top
R936 "10kR" "RES 0402/1005 RF KK" 229.183,308.301 r270 top
R937 "10kR" "RES 0402/1005 RF KK" 269.601,308.301 r90 top
R938 "10kR" "RES 0402/1005 RF KK" 227.69,299.297 r270 top
R939 "10kR" "RES 0402/1005 RF KK" 262.116,308.301 r90 top
R940 "10kR" "RES 0402/1005 RF KK" 241.159,308.301 r270 top
R941 "10kR" "RES 0402/1005 RF KK" 260.619,308.301 r90 top
R942 "10kR" "RES 0402/1005 RF KK" 245.649,308.301 r270 top
R943 "10kR" "RES 0402/1005 RF KK" 259.122,308.301 r90 top
R944 "10kR" "RES 0402/1005 RF KK" 238.165,308.301 r270 top
R945 "10kR" "RES 0402/1005 RF KK" 234.506,299.297 r90 top
R946 "10kR" "RES 0402/1005 RF KK" 235.171,308.301 r270 top
R947 "10kR" "RES 0402/1005 RF KK" 235.87,299.297 r90 top
R948 "10kR" "RES 0402/1005 RF KK" 236.668,308.301 r270 top
R949 "10kR" "RES 0402/1005 RF KK" 233.143,299.297 r90 top
R950 "10kR" "RES 0402/1005 RF KK" 239.662,308.301 r270 top
R951 "10kR" "RES 0402/1005 RF KK" 244.05,299.297 r90 top
R952 "10kR" "RES 0402/1005 RF KK" 233.674,308.301 r270 top
R953 "10kR" "RES 0402/1005 RF KK" 230.416,299.297 r90 top
R954 "10kR" "RES 0402/1005 RF KK" 230.68,308.301 r270 top
R955 "10kR" "RES 0402/1005 RF KK" 231.78,299.297 r90 top
R956 "10kR" "RES 0402/1005 RF KK" 232.177,308.301 r270 top
R957 "10kR" "RES 0402/1005 RF KK" 244.153,308.301 r90 top
R958 "10kR" "RES 0402/1005 RF KK" 247.146,308.301 r270 top
R959 "10kR" "RES 0402/1005 RF KK" 242.656,308.301 r90 top
R960 "10kR" "RES 0402/1005 RF KK" 248.643,308.301 r270 top
R961 "0mR" "RES 0402/1005 RF KK" 229.053,302.335 r90 top
R962 "0mR" "RES 0402/1005 RF KK" 238.596,302.335 r90 top
R963 "0mR" "RES 0402/1005 RF KK" 263.613,310.913 r90 top
R964 "0mR" "RES 0402/1005 RF KK" 237.233,302.335 r90 top
R965 "0mR" "RES 0402/1005 RF KK" 266.607,310.913 r90 top
R966 "0mR" "RES 0402/1005 RF KK" 265.11,310.913 r90 top
R967 "0mR" "RES 0402/1005 RF KK" 271.098,310.913 r90 top
R968 "0mR" "RES 0402/1005 RF KK" 268.104,310.913 r90 top
R969 "0mR" "RES 0402/1005 RF KK" 269.601,310.913 r90 top
R970 "0mR" "RES 0402/1005 RF KK" 262.116,310.913 r90 top
R971 "0mR" "RES 0402/1005 RF KK" 260.619,310.913 r90 top
R972 "0mR" "RES 0402/1005 RF KK" 259.122,310.913 r90 top
R973 "0mR" "RES 0402/1005 RF KK" 234.506,302.335 r90 top
R974 "0mR" "RES 0402/1005 RF KK" 235.87,302.335 r90 top
R975 "0mR" "RES 0402/1005 RF KK" 233.143,302.335 r90 top
R976 "0mR" "RES 0402/1005 RF KK" 244.05,302.335 r90 top
R977 "0mR" "RES 0402/1005 RF KK" 230.416,302.335 r90 top
R978 "0mR" "RES 0402/1005 RF KK" 231.78,302.335 r90 top
R979 "0mR" "RES 0402/1005 RF KK" 244.152,310.913 r90 top
R980 "0mR" "RES 0402/1005 RF KK" 242.655,310.913 r90 top
R981 "0mR" "RES 0402/1005 RF KK" 256.128,310.913 r90 top
R982 "0mR" "RES 0402/1005 RF KK" 257.625,310.913 r90 top
R983 "0mR" "RES 0402/1005 RF KK" 253.134,310.913 r90 top
R984 "0mR" "RES 0402/1005 RF KK" 254.631,310.913 r90 top
R985 "0mR" "RES 0402/1005 RF KK" 251.637,310.913 r90 top
R986 "0mR" "RES 0402/1005 RF KK" 250.14,310.913 r90 top
R987 "0mR" "RES 0402/1005 RF KK" 227.686,310.913 r90 top
R988 "0mR" "RES 0402/1005 RF KK" 229.183,310.913 r90 top
R989 "0mR" "RES 0402/1005 RF KK" 227.69,302.335 r90 top
R990 "0mR" "RES 0402/1005 RF KK" 241.158,310.913 r90 top
R991 "0mR" "RES 0402/1005 RF KK" 245.649,310.913 r90 top
R992 "0mR" "RES 0402/1005 RF KK" 238.164,310.913 r90 top
R993 "0mR" "RES 0402/1005 RF KK" 235.17,310.913 r90 top
R994 "0mR" "RES 0402/1005 RF KK" 236.667,310.913 r90 top
R995 "0mR" "RES 0402/1005 RF KK" 239.661,310.913 r90 top
R996 "0mR" "RES 0402/1005 RF KK" 233.674,310.913 r90 top
R997 "0mR" "RES 0402/1005 RF KK" 230.68,310.913 r90 top
R998 "0mR" "RES 0402/1005 RF KK" 232.177,310.913 r90 top
R999 "0mR" "RES 0402/1005 RF KK" 247.146,310.913 r90 top
R1000 "0mR" "RES 0402/1005 RF KK" 248.643,310.913 r90 top
R1001 "0mR" "RES 0402/1005 RF KK" 220.642,182.148 r180 bottom
R1002 "10kR" "RES 0402/1005 RF KK" 108.648,264.63 r90 bottom
R1003 "10kR" "RES 0402/1005 RF KK" 114.194,251.823 r180 top
R1004 "0mR" "RES 0402/1005 RF KK" 237.021,202.666 r180 top
R1005 "0mR" "RES 0402/1005 RF KK" 234.71,201.769 r180 top
R1006 "0mR" "RES 0402/1005 RF KK" 237.021,200.787 r180 top
R1007 "0mR" "RES 0402/1005 RF KK" 234.71,199.885 r180 top
R1008 "0mR" "RES 0402/1005 RF KK" 242.252,194.037 r270 top
R1009 "0mR" "RES 0402/1005 RF KK" 243.154,191.651 r270 top
R1010 "0mR" "RES 0402/1005 RF KK" 245.839,194.037 r270 top
R1011 "0mR" "RES 0402/1005 RF KK" 246.729,191.651 r270 top
R1012 "0mR" "RES 0402/1005 RF KK" 247.632,194.037 r270 top
R1013 "0mR" "RES 0402/1005 RF KK" 248.517,191.651 r270 top
R1014 "0mR" "RES 0402/1005 RF KK" 249.425,194.037 r270 top
R1015 "0mR" "RES 0402/1005 RF KK" 250.304,191.651 r270 top
R1016 "0mR" "RES 0402/1005 RF KK" 255.143,202.073 r0 top
R1017 "0mR" "RES 0402/1005 RF KK" 255.127,203.148 r0 top
R1018 "0mR" "RES 0402/1005 RF KK" 255.143,204.145 r0 top
R1019 "0mR" "RES 0402/1005 RF KK" 255.127,206.177 r0 top
R1020 "0mR" "RES 0402/1005 RF KK" 255.143,207.303 r0 top
R1021 "0mR" "RES 0402/1005 RF KK" 255.143,208.402 r0 top
R1022 "0mR" "RES 0402/1005 RF KK" 228.223,219.29 r90 top
R1023 "0mR" "RES 0402/1005 RF KK" 228.723,235.847 r90 top
R1024 "0mR" "RES 0402/1005 RF KK" 229.223,219.29 r90 top
R1025 "0mR" "RES 0402/1005 RF KK" 230.01,235.851 r90 top
R1026 "0mR" "RES 0402/1005 RF KK" 221.963,206.983 r0 top
R1027 "0mR" "RES 0402/1005 RF KK" 221.963,205.466 r0 top
R1028 "0mR" "RES 0402/1005 RF KK" 221.963,203.95 r0 top
R1029 "0mR" "RES 0402/1005 RF KK" 221.963,202.433 r0 top
R1030 "0mR" "RES 0402/1005 RF KK" 238.684,216.776 r90 top
R1031 "0mR" "RES 0402/1005 RF KK" 234.647,210.844 r180 top
R1032 "0mR" "RES 0402/1005 RF KK" 236.983,209.955 r180 top
R1033 "0mR" "RES 0402/1005 RF KK" 234.672,209.066 r180 top
R1034 "0mR" "RES 0402/1005 RF KK" 237.009,208.152 r180 top
R1035 "0mR" "RES 0402/1005 RF KK" 234.685,207.263 r180 top
R1036 "0mR" "RES 0402/1005 RF KK" 237.021,206.387 r180 top
R1037 "0mR" "RES 0402/1005 RF KK" 234.71,205.536 r180 top
R1038 "0mR" "RES 0402/1005 RF KK" 237.021,204.545 r180 top
R1039 "0mR" "RES 0402/1005 RF KK" 234.71,203.652 r180 top
R1040 "0mR" "RES 0402/1005 RF KK" 112.563,286.787 r90 bottom
R1041 "0mR" "RES 0402/1005 RF KK" 110.424,286.787 r90 bottom
R1042 "0mR" "RES 0402/1005 RF KK" 107.214,286.787 r90 bottom
R1043 "0mR" "RES 0402/1005 RF KK" 108.284,286.787 r90 bottom
R1044 "0mR" "RES 0402/1005 RF KK" 244.046,194.037 r270 top
R1045 "0mR" "RES 0402/1005 RF KK" 244.942,191.651 r270 top
R1046 "0mR" "RES 0402/1005 RF KK" 251.219,194.037 r270 top
R1047 "0mR" "RES 0402/1005 RF KK" 255.143,201.037 r0 top
R1048 "1kR" "RES 0402/1005 RF KK" 232.757,182.148 r180 bottom
R1049 "1kR" "RES 0402/1005 RF KK" 232.757,183.418 r180 bottom
R1050 "1kR" "RES 0402/1005 RF KK" 232.757,184.688 r180 bottom
R1051 "1kR" "RES 0402/1005 RF KK" 232.757,185.958 r180 bottom
R1052 "1kR" "RES 0402/1005 RF KK" 44.495,171.26 r180 top
R1053 "1kR" "RES 0402/1005 RF KK" 48.216,179.68 r0 top
R1054 "0mR" "RES 0402/1005 RF KK" 166.682,355.086 r270 bottom
R1055 "0mR" "RES 0402/1005 RF KK" 85.319,354.374 r270 bottom
R1056 "0mR" "RES 0402/1005 RF KK" 84.264,354.361 r270 bottom
R1057 "0mR" "RES 0402/1005 RF KK" 89.073,341.719 r270 bottom
R1058 "0mR" "RES 0402/1005 RF KK" 88.133,341.719 r270 bottom
R1059 "20kR" "RES 0402/1005 RF KK" 115.133,162.197 r90 bottom
R1060 "100R" "RES 0603/1608 RF" 121.578,180.867 r0 bottom
R1061 "100R" "RES 0603/1608 RF" 142.713,165.444 r0 bottom
R1062 "100R" "RES 0603/1608 RF" 104.573,180.867 r0 bottom
R1063 "100R" "RES 0603/1608 RF" 90.968,180.867 r0 bottom
R1064 "100R" "RES 0603/1608 RF" 118.177,180.867 r0 bottom
R1065 "100R" "RES 0603/1608 RF" 138.853,165.444 r0 bottom
R1066 "100R" "RES 0603/1608 RF" 101.171,180.867 r0 bottom
R1067 "0mR" "RES 0402/1005 RF KK" 132.131,312.115 r180 bottom
R1068 "0mR" "RES 0402/1005 RF KK" 132.174,313.055 r180 bottom
R1069 "100R" "RES 0603/1608 RF" 87.567,180.867 r0 bottom
R1070 "100R" "RES 0603/1608 RF" 114.776,180.867 r0 bottom
R1071 "0mR" "RES 0402/1005 RF KK" 185.661,277.035 r0 top
R1072 "0mR" "RES 0402/1005 RF KK" 185.661,277.99 r0 top
R1073 "0mR" "RES 0402/1005 RF KK" 179.636,271.691 r180 top
R1074 "0mR" "RES 0402/1005 RF KK" 179.636,270.771 r180 top
R1075 "100R" "RES 0603/1608 RF" 134.993,165.444 r0 bottom
R1076 "100R" "RES 0603/1608 RF" 97.77,180.867 r0 bottom
R1077 "0mR" "RES 0402/1005 RF KK" 177.53,274.322 r90 bottom
R1078 "100R" "RES 0603/1608 RF" 84.166,180.867 r0 bottom
R1079 "100R" "RES 0603/1608 RF" 111.375,180.867 r0 bottom
R1080 "0mR" "RES 0402/1005 RF KK" 176.63,274.322 r90 bottom
R1081 "100R" "RES 0603/1608 RF" 131.133,165.444 r0 bottom
R1082 "10kR" "RES 0402/1005 RF KK" 91.594,170.265 r270 bottom
R1083 "0mR" "RES 0402/1005 RF KK" 151.201,219.97 r90 top
R1084 "0mR" "RES 0402/1005 RF KK" 152.141,219.97 r90 top
R1085 "0mR" "RES 0402/1005 RF KK" 203.904,287.617 r0 top
R1086 "0mR" "RES 0402/1005 RF KK" 203.904,288.544 r0 top
R1087 "0mR" "RES 0402/1005 RF KK" 155.427,298.825 r180 top
R1088 "0mR" "RES 0402/1005 RF KK" 155.427,299.854 r180 top
R1089 "20kR" "RES 0402/1005 RF KK" 91.59,167.988 r270 bottom
R1090 "100R" "RES 0603/1608 RF" 201.638,404.736 r90 bottom
R1091 "0mR" "RES 0402/1005 RF KK" 195.509,291.002 r0 top
R1092 "0mR" "RES 0402/1005 RF KK" 195.509,290.068 r0 top
R1093 "0mR" "RES 0402/1005 RF KK" 249.987,354.744 r270 top
R1094 "0mR" "RES 0402/1005 RF KK" 249.072,354.744 r270 top
R1095 "0mR" "RES 0402/1005 RF KK" 195.714,405.644 r180 bottom
R1096 "100R" "RES 0603/1608 RF" 119.774,385.589 r0 bottom
R1097 "0mR" "RES 0402/1005 RF KK" 204.249,272.723 r180 top
R1098 "0mR" "RES 0402/1005 RF KK" 204.249,271.798 r180 top
R1099 "0mR" "RES 0402/1005 RF KK" 120.821,391.5 r90 bottom
R1100 "0mR" "RES 0402/1005 RF KK" 206.096,268.605 r180 top
R1101 "0mR" "RES 0402/1005 RF KK" 206.096,267.773 r180 top
R1102 "100R" "RES 0603/1608 RF" 119.754,393.893 r0 bottom
R1103 "0mR" "RES 0402/1005 RF KK" 199.625,267.525 r180 top
R1104 "0mR" "RES 0402/1005 RF KK" 199.625,266.611 r180 top
R1105 "0mR" "RES 0402/1005 RF KK" 225.675,274.924 r180 bottom
R1106 "0mR" "RES 0402/1005 RF KK" 225.675,275.838 r180 bottom
R1107 "0mR" "RES 0402/1005 RF KK" 120.767,400.045 r90 bottom
R1108 "100R" "RES 0603/1608 RF" 119.67,440.345 r90 bottom
R1109 "0mR" "RES 0402/1005 RF KK" 151.786,268.046 r0 top
R1110 "0mR" "RES 0402/1005 RF KK" 151.786,268.961 r0 top
R1111 "0mR" "RES 0402/1005 RF KK" 113.314,443.088 r180 bottom
R1112 "100R" "RES 0603/1608 RF" 40.551,361.031 r270 bottom
R1113 "0mR" "RES 0402/1005 RF KK" 45.992,359.688 r0 bottom
R1114 "100R" "RES 0603/1608 RF" 117.324,247.325 r0 bottom
R1115 "0mR" "RES 0402/1005 RF KK" 118.762,252.804 r90 bottom
R1116 "100R" "RES 0603/1608 RF" 201.638,398.328 r90 bottom
R1117 "0mR" "RES 0402/1005 RF KK" 195.714,399.412 r180 bottom
R1118 "100R" "RES 0603/1608 RF" 38.205,334.688 r270 bottom
R1119 "0mR" "RES 0402/1005 RF KK" 43.658,333.313 r0 bottom
R1120 "100R" "RES 0603/1608 RF" 40.488,339.643 r270 bottom
R1121 "0mR" "RES 0402/1005 RF KK" 46.172,338.307 r0 bottom
R1122_Trans_LS_I2C0 "200kR" "RES 0402/1005 RF KK" 19.61,313.26 r90 top (schematic designator R1122)
R1122_Trans_LS_I2C1 "200kR" "RES 0402/1005 RF KK" 19.61,319.748 r90 top (schematic designator R1122)
R1122_Trans_PS_I2C0 "200kR" "RES 0402/1005 RF KK" 19.61,326.236 r90 top (schematic designator R1122)
R1122_Trans_PS_I2C1 "200kR" "RES 0402/1005 RF KK" 19.61,332.724 r90 top (schematic designator R1122)
S1 "SWITCH SLIDE DIP SPST 25MA 24V" SO8_N 230.073,348.386 r180 top
S2 "430181038816" 430181038816 242.202,339.268 r180 bottom
S3 "430181038816" 430181038816 256.593,171.845 r270 bottom
S4 "430181038816" 430181038816 250.814,171.845 r270 bottom
S5 "SWITCH SLIDE DIP SPST 25MA 24V" SO8_N 54.194,231.648 r180 bottom
S6 "430181038816" 430181038816 199.499,257.103 r180 bottom
S7 "430181038816" 430181038816 272.669,349.656 r180 bottom
S8 "SWITCH SLIDE DIP SPST 25MA 24V" SO8_N 226.229,184.053 r0 bottom
S9 "SWITCH SLIDE DIP SPST 25MA 24V" SO8_N 226.229,177.779 r0 bottom
SP1_I2C_Bridge_GPIO "SP" MeasureTP#1 115.176,187.744 r90 top (schematic designator SP1)
SP1_I2C_Bridge_PCIE "SP" MeasureTP#1 107.227,392.366 r90 top (schematic designator SP1)
SP1_I2C_Bridge_SFP "SP" MeasureTP#1 74.511,291.355 r90 top (schematic designator SP1)
SP2_I2C_Bridge_PCIE "SP" MeasureTP#1 77.123,306.49 r90 top (schematic designator SP2)
SP2_I2C_Bridge_PCIE "SP" MeasureTP#1 79.743,355.854 r90 top (schematic designator SP2)
SP2_I2C_Bridge_PCIE "SP" MeasureTP#1 120.119,238.919 r90 top (schematic designator SP2)
SP3_I2C_Bridge_GPIO "SP" MeasureTP#1 120.279,237.364 r90 top (schematic designator SP3)
SP3_I2C_Bridge_PCIE "SP" MeasureTP#1 78.118,355.854 r90 top (schematic designator SP3)
SP3_I2C_Bridge_SFP "SP" MeasureTP#1 77.13,305.113 r90 top (schematic designator SP3)
SP4_I2C_Bridge_GPIO "SP" MeasureTP#1 121.888,237.364 r90 top (schematic designator SP4)
SP4_I2C_Bridge_PCIE "SP" MeasureTP#1 113.589,383.603 r90 top (schematic designator SP4)
SP4_I2C_Bridge_SFP "SP" MeasureTP#1 82.258,299.239 r90 top (schematic designator SP4)
SP5_I2C_Bridge_GPIO "SP" MeasureTP#1 123.52,237.364 r90 top (schematic designator SP5)
SP5_I2C_Bridge_PCIE "SP" MeasureTP#1 115.252,383.603 r90 top (schematic designator SP5)
SP5_I2C_Bridge_SFP "SP" MeasureTP#1 82.258,297.938 r90 top (schematic designator SP5)
SP6_I2C_Bridge_GPIO "SP" MeasureTP#1 125.216,237.364 r90 top (schematic designator SP6)
SP6_I2C_Bridge_PCIE "SP" MeasureTP#1 115.252,385.305 r90 top (schematic designator SP6)
SP6_I2C_Bridge_SFP "SP" MeasureTP#1 88.012,295.821 r270 top (schematic designator SP6)
SP7_I2C_Bridge_GPIO "SP" MeasureTP#1 130.861,241.158 r90 top (schematic designator SP7)
SP7_I2C_Bridge_PCIE "SP" MeasureTP#1 113.589,385.305 r90 top (schematic designator SP7)
SP7_I2C_Bridge_SFP "SP" MeasureTP#1 89.643,295.821 r270 top (schematic designator SP7)
SP8_I2C_Bridge_GPIO "SP" MeasureTP#1 134.813,241.948 r90 top (schematic designator SP8)
SP8_I2C_Bridge_PCIE "SP" MeasureTP#1 115.252,387.007 r90 top (schematic designator SP8)
SP8_I2C_Bridge_SFP "SP" MeasureTP#1 91.149,293.168 r90 top (schematic designator SP8)
SP9_I2C_Bridge_GPIO "SP" MeasureTP#1 134.813,243.758 r90 top (schematic designator SP9)
SP9_I2C_Bridge_PCIE "SP" MeasureTP#1 113.589,387.007 r90 top (schematic designator SP9)
SP9_I2C_Bridge_SFP "SP" MeasureTP#1 93.064,293.168 r90 top (schematic designator SP9)
SP10_I2C_Bridge_GPIO "SP" MeasureTP#1 134.714,245.661 r90 top (schematic designator SP10)
SP10_I2C_Bridge_PCIE "SP" MeasureTP#1 115.252,388.709 r90 top (schematic designator SP10)
SP10_I2C_Bridge_SFP "SP" MeasureTP#1 92.586,299.695 r90 top (schematic designator SP10)
SP11_I2C_Bridge_GPIO "SP" MeasureTP#1 134.714,247.233 r90 top (schematic designator SP11)
SP11_I2C_Bridge_PCIE "SP" MeasureTP#1 113.589,388.709 r90 top (schematic designator SP11)
SP11_I2C_Bridge_SFP "SP" MeasureTP#1 94.03,299.717 r90 top (schematic designator SP11)
SP12_I2C_Bridge_GPIO "SP" MeasureTP#1 120.157,241.054 r90 top (schematic designator SP12)
SP12_I2C_Bridge_PCIE "SP" MeasureTP#1 96.126,383.645 r90 top (schematic designator SP12)
SP12_I2C_Bridge_SFP "SP" MeasureTP#1 82.194,295.796 r90 top (schematic designator SP12)
SP13_I2C_Bridge_GPIO "SP" MeasureTP#1 134.714,248.972 r90 top (schematic designator SP13)
SP13_I2C_Bridge_PCIE "SP" MeasureTP#1 115.252,390.411 r90 top (schematic designator SP13)
SP13_I2C_Bridge_SFP "SP" MeasureTP#1 94.602,308.775 r90 top (schematic designator SP13)
SP14_I2C_Bridge_GPIO "SP" MeasureTP#1 130.607,249.149 r90 top (schematic designator SP14)
SP14_I2C_Bridge_PCIE "SP" MeasureTP#1 113.589,390.411 r90 top (schematic designator SP14)
SP14_I2C_Bridge_SFP "SP" MeasureTP#1 92.913,308.775 r90 top (schematic designator SP14)
SP15_I2C_Bridge_GPIO "SP" MeasureTP#1 129.134,249.149 r90 top (schematic designator SP15)
SP15_I2C_Bridge_PCIE "SP" MeasureTP#1 115.252,392.113 r90 top (schematic designator SP15)
SP15_I2C_Bridge_SFP "SP" MeasureTP#1 101.719,311.154 r90 top (schematic designator SP15)
SP16_I2C_Bridge_GPIO "SP" MeasureTP#1 127.622,249.149 r90 top (schematic designator SP16)
SP16_I2C_Bridge_PCIE "SP" MeasureTP#1 113.589,392.113 r90 top (schematic designator SP16)
SP16_I2C_Bridge_SFP "SP" MeasureTP#1 100.171,311.154 r90 top (schematic designator SP16)
SP17_I2C_Bridge_GPIO "SP" MeasureTP#1 126.106,249.149 r90 top (schematic designator SP17)
SP17_I2C_Bridge_PCIE "SP" MeasureTP#1 115.252,393.814 r90 top (schematic designator SP17)
SP17_I2C_Bridge_SFP "SP" MeasureTP#1 84.19,310.839 r90 top (schematic designator SP17)
SP18_I2C_Bridge_GPIO "SP" MeasureTP#1 124.549,249.149 r90 top (schematic designator SP18)
SP18_I2C_Bridge_PCIE "SP" MeasureTP#1 113.589,393.814 r90 top (schematic designator SP18)
SP18_I2C_Bridge_SFP "SP" MeasureTP#1 82.407,310.839 r90 top (schematic designator SP18)
SP19 "SP" MeasureTP#2 133.324,310.782 r90 top
SP20_SPI_bridge_Main "SP" MeasureTP#2 223.078,286.766 r90 top (schematic designator SP20)
SP20_SPI_bridge_PCIe "SP" MeasureTP#2 137.973,372.593 r90 top (schematic designator SP20)
SP21_SPI_bridge_Main "SP" MeasureTP#2 225.979,291.576 r90 top (schematic designator SP21)
SP21_SPI_bridge_PCIe "SP" MeasureTP#2 137.973,371.081 r90 top (schematic designator SP21)
SP22_SPI_bridge_Main "SP" MeasureTP#2 191.745,258.674 r90 top (schematic designator SP22)
SP22_SPI_bridge_PCIe "SP" MeasureTP#2 258.814,264.712 r90 top (schematic designator SP22)
SP23_SPI_bridge_Main "SP" MeasureTP#2 187.595,263.969 r90 top (schematic designator SP23)
SP23_SPI_bridge_PCIe "SP" MeasureTP#2 255.34,265.138 r90 top (schematic designator SP23)
SP24_SPI_bridge_Main "SP" MeasureTP#2 84.309,326.976 r90 top (schematic designator SP24)
SP24_SPI_bridge_PCIe "SP" MeasureTP#2 220.405,366.247 r90 top (schematic designator SP24)
SP25_SPI_bridge_Main "SP" MeasureTP#2 84.309,328.584 r90 top (schematic designator SP25)
SP25_SPI_bridge_PCIe "SP" MeasureTP#2 222.1,366.247 r90 top (schematic designator SP25)
SP26_SPI_bridge_Main "SP" MeasureTP#2 172.25,413.36 r180 top (schematic designator SP26)
SP26_SPI_bridge_PCIe "SP" MeasureTP#2 57.429,366.448 r90 top (schematic designator SP26)
SP27_SPI_bridge_Main "SP" MeasureTP#2 170.104,415.798 r180 top (schematic designator SP27)
SP27_SPI_bridge_PCIe "SP" MeasureTP#2 59.064,366.448 r90 top (schematic designator SP27)
SP28_SPI_bridge_Main "SP" MeasureTP#2 162.201,234.625 r90 top (schematic designator SP28)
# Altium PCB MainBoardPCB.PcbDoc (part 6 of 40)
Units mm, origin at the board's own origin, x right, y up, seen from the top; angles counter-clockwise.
Board outline 258.95 x 308.86 mm, 16 copper layers (L1, L2 (GND), L3 (Sign), L4 (GND), L5 (Sign), L6 (PWR/GND), L7(12V+Other), L8 (Plane_GND), L9 (PWR/GND), L10 (3V3+Other), L11 (PWR/GND), L12 (Sign), L13 (GND), L14 (Sign), L15 (GND), L16), stack 2.503 mm thick; 2578 components, 1867 nets, 8817 pads, 8021 vias.
Unrouted connection lines stored in the file: 25.

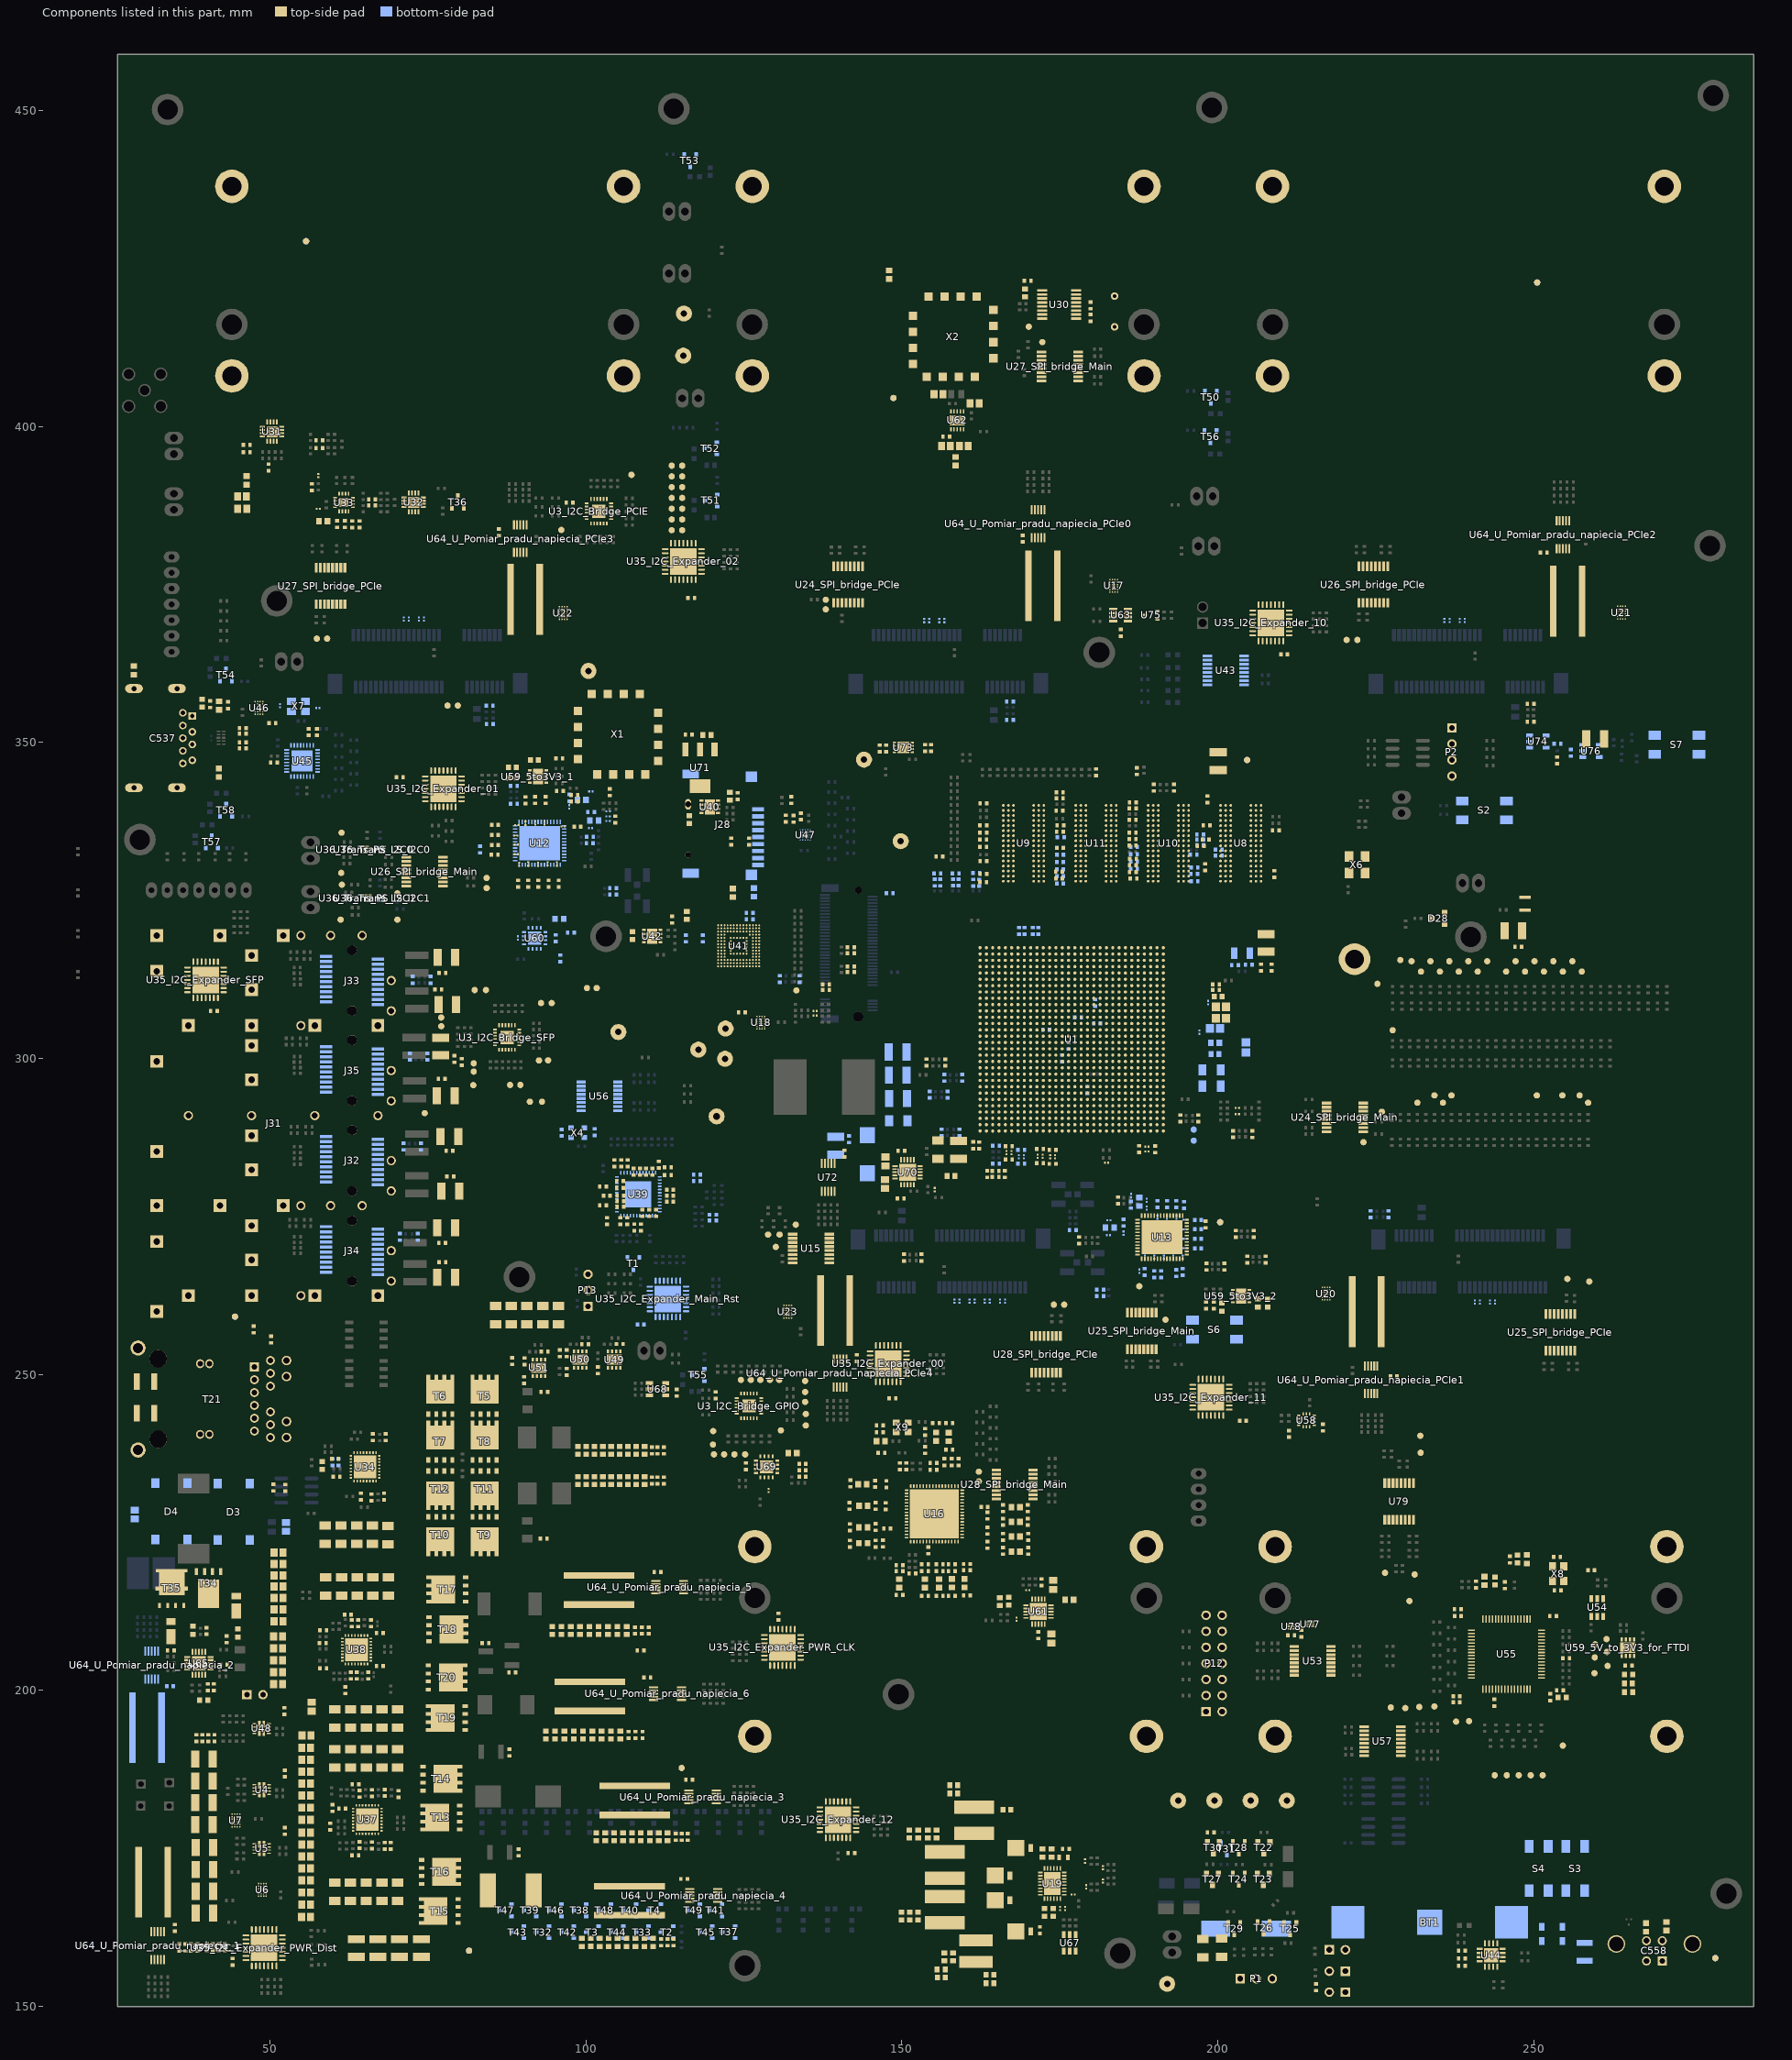
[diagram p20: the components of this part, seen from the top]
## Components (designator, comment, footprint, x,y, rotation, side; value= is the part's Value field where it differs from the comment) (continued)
SP28_SPI_bridge_PCIe "SP" MeasureTP#2 175.706,261.061 r90 top (schematic designator SP28)
SP29_SPI_bridge_Main "SP" MeasureTP#2 162.201,233.095 r90 top (schematic designator SP29)
SP29_SPI_bridge_PCIe "SP" MeasureTP#2 174.072,261.061 r90 top (schematic designator SP29)
SP30 "SP" MeasureTP#1 133.223,273.71 r90 top
SP31 "SP" MeasureTP#1 130.67,272.136 r90 top
SP32 "SP" MeasureTP#1 130.073,270.192 r90 top
SP33 "SP" MeasureTP#1 128.841,272.136 r90 top
SP34_Trans_LS_I2C0 "SP" MeasureTP#1 70.18,326.128 r90 top (schematic designator SP34)
SP34_Trans_LS_I2C1 "SP" MeasureTP#1 196.207,288.76 r180 bottom (schematic designator SP34)
SP34_Trans_PS_I2C0 "SP" MeasureTP#1 61.345,335.739 r0 top (schematic designator SP34)
SP34_Trans_PS_I2C1 "SP" MeasureTP#1 61.401,327.515 r0 top (schematic designator SP34)
SP35_Trans_LS_I2C0 "SP" MeasureTP#1 70.18,321.971 r90 top (schematic designator SP35)
SP35_Trans_LS_I2C1 "SP" MeasureTP#1 196.207,287.007 r180 bottom (schematic designator SP35)
SP35_Trans_PS_I2C0 "SP" MeasureTP#1 61.292,329.375 r0 top (schematic designator SP35)
SP35_Trans_PS_I2C1 "SP" MeasureTP#1 61.19,321.971 r180 top (schematic designator SP35)
SP36 "SP" MeasureTP#2 235.656,293.014 r90 top
SP37 "SP" MeasureTP#2 231.607,293.014 r90 top
SP38 "SP" MeasureTP#2 237.005,294.174 r90 top
SP39 "SP" MeasureTP#2 234.306,294.174 r90 top
SP40 "SP" MeasureTP#2 254.549,294.174 r90 top
SP41 "SP" MeasureTP#2 250.5,294.174 r90 top
SP42 "SP" MeasureTP#2 257.277,294.174 r90 top
SP43 "SP" MeasureTP#2 258.623,293.014 r90 top
SP44 "SP" MeasureTP#2 242.655,315.397 r90 top
SP45 "SP" MeasureTP#2 256.128,315.397 r90 top
SP46 "SP" MeasureTP#2 257.625,313.762 r90 top
SP47 "SP" MeasureTP#2 253.134,315.397 r90 top
SP48 "SP" MeasureTP#2 254.631,313.762 r90 top
SP49 "SP" MeasureTP#2 251.637,313.762 r90 top
SP50 "SP" MeasureTP#2 250.14,315.397 r90 top
SP51 "SP" MeasureTP#2 225.282,311.823 r90 top
SP52 "SP" MeasureTP#2 228.905,315.59 r90 top
SP53 "SP" MeasureTP#2 227.69,304.482 r90 top
SP54 "SP" MeasureTP#2 241.159,313.762 r90 top
SP55 "SP" MeasureTP#2 245.649,313.762 r90 top
SP56 "SP" MeasureTP#2 238.165,313.762 r90 top
SP57 "SP" MeasureTP#2 235.172,313.762 r90 top
SP58 "SP" MeasureTP#2 236.667,315.397 r90 top
SP59 "SP" MeasureTP#2 239.662,315.397 r90 top
SP60 "SP" MeasureTP#2 233.674,315.397 r90 top
SP61 "SP" MeasureTP#2 230.68,315.397 r90 top
SP62 "SP" MeasureTP#2 232.177,313.762 r90 top
SP63 "SP" MeasureTP#2 247.146,315.397 r90 top
SP64 "SP" MeasureTP#2 248.643,313.762 r90 top
SP65 "SP" MeasureTP#1 230.348,214.156 r90 top
SP66 "SP" MeasureTP#1 227.392,197.308 r90 top
SP67 "SP" MeasureTP#1 229.694,197.223 r90 top
SP68 "SP" MeasureTP#1 231.911,197.394 r90 top
SP69 "SP" MeasureTP#1 234.295,197.475 r90 top
SP70 "SP" MeasureTP#1 239.784,195.158 r90 top
SP71 "SP" MeasureTP#1 237.733,195.081 r90 top
SP72 "SP" MeasureTP#1 243.849,186.59 r90 top
SP73 "SP" MeasureTP#1 245.745,186.59 r90 top
SP74 "SP" MeasureTP#1 247.641,186.59 r90 top
SP75 "SP" MeasureTP#1 249.537,186.59 r90 top
SP76 "SP" MeasureTP#1 251.433,186.59 r90 top
SP77 "SP" MeasureTP#1 254.62,191.283 r90 top
SP78 "SP" MeasureTP#1 259.627,202.728 r90 top
SP79 "SP" MeasureTP#1 261.708,203.895 r90 top
SP80 "SP" MeasureTP#1 259.673,205.237 r90 top
SP81 "SP" MeasureTP#1 261.618,206.111 r90 top
SP82 "SP" MeasureTP#1 259.75,207.308 r90 top
SP83 "SP" MeasureTP#1 261.544,208.134 r90 top
SP84 "SP" MeasureTP#1 226.486,218.626 r90 top
SP85 "SP" MeasureTP#1 232.068,240.302 r90 top
SP86 "SP" MeasureTP#1 231.172,218.359 r90 top
SP87 "SP" MeasureTP#1 232.116,237.63 r90 top
T1 "SI2342DS-T1-GE3" SI2342DS-T1-GE3 107.531,267.564 r270 bottom
T2 "SI2342DS-T1-GE3" SI2342DS-T1-GE3 112.849,161.755 r180 bottom
T3 "SI2342DS-T1-GE3" SI2342DS-T1-GE3 101.041,161.755 r180 bottom
T4 "SI2342DS-T1-GE3" SI2342DS-T1-GE3 110.881,165.224 r180 bottom
T5 "BSC080N03LSG" BSC080N03LS 83.977,246.623 r90 top
T6 "BSC080N03LSG" BSC080N03LS 76.977,246.623 r90 top locked
T7 "BSC030N03LS-G" BSC030N03LS 76.977,239.389 r90 top
T8 "BSC030N03LS-G" BSC030N03LS 83.977,239.389 r90 top
T9 "BSC080N03LSG" BSC080N03LS 83.977,224.601 r270 top
T10 "BSC080N03LSG" BSC080N03LS 76.983,224.601 r270 top
T11 "BSC030N03LS-G" BSC030N03LS 83.977,231.864 r270 top
T12 "BSC030N03LS-G" BSC030N03LS 76.977,231.864 r270 top
T13 "BSC080N03LSG" BSC080N03LS 77.142,179.908 r180 top
T14 "BSC030N03LS-G" BSC030N03LS 77.114,186.055 r0 top
T15 "BSC080N03LSG" BSC080N03LS 76.889,165.106 r180 top
T16 "BSC030N03LS-G" BSC030N03LS 76.91,171.285 r0 top
T17 "BSC080N03LSG" BSC080N03LS 78.098,215.984 r180 top
T18 "BSC030N03LS-G" BSC030N03LS 78.073,209.702 r0 top
T19 "BSC080N03LSG" BSC080N03LS 78.029,195.651 r180 top
T20 "BSC030N03LS-G" BSC030N03LS 77.974,202.057 r0 top
T21 "7499511440" 7499511440 37.922,246.126 r90 bottom
T22 "IRLML6401TRPBF" IRLML6401PbF 207.327,175.121 r270 top
T23 "IRLML6401TRPBF" IRLML6401PbF 207.239,170.117 r270 top
T24 "SI2342DS-T1-GE3" SI2342DS-T1-GE3 203.34,170.13 r270 top
T25 "SI2342DS-T1-GE3" SI2342DS-T1-GE3 211.493,162.345 r270 top
T26 "SI2342DS-T1-GE3" SI2342DS-T1-GE3 207.264,162.434 r270 top
T27 "IRLML6401TRPBF" IRLML6401PbF 199.161,170.143 r270 top
T28 "SI2342DS-T1-GE3" SI2342DS-T1-GE3 203.327,175.121 r270 top
T29 "SI2342DS-T1-GE3" SI2342DS-T1-GE3 202.629,162.345 r270 top
T30 "IRLML6401TRPBF" IRLML6401PbF 199.339,175.121 r270 top
T31 "SI2342DS-T1-GE3" SI2342DS-T1-GE3 201.435,174.918 r270 bottom
T32 "SI2342DS-T1-GE3" SI2342DS-T1-GE3 93.169,161.755 r180 bottom
T33 "SI2342DS-T1-GE3" SI2342DS-T1-GE3 108.913,161.755 r180 bottom
T34 "RJK0651DPB-00#J5" RJK0651DPB 40.282,216.141 r270 top
T35 "SIJ482DP-T1-GE3" SiJ482DP 34.455,216.175 r90 top
T36 "SI2342DS-T1-GE3" SI2342DS-T1-GE3 79.761,388.074 r90 top
T37 "SI2342DS-T1-GE3" SI2342DS-T1-GE3 122.618,161.773 r180 bottom
T38 "SI2342DS-T1-GE3" SI2342DS-T1-GE3 99.073,165.224 r180 bottom
T39 "SI2342DS-T1-GE3" SI2342DS-T1-GE3 91.201,165.224 r180 bottom
T40 "SI2342DS-T1-GE3" SI2342DS-T1-GE3 106.945,165.224 r180 bottom
T41 "SI2342DS-T1-GE3" SI2342DS-T1-GE3 120.58,165.224 r180 bottom
T42 "SI2342DS-T1-GE3" SI2342DS-T1-GE3 97.105,161.755 r180 bottom
T43 "SI2342DS-T1-GE3" SI2342DS-T1-GE3 89.233,161.755 r180 bottom
T44 "SI2342DS-T1-GE3" SI2342DS-T1-GE3 104.977,161.755 r180 bottom
T45 "SI2342DS-T1-GE3" SI2342DS-T1-GE3 119.021,161.755 r180 bottom
T46 "SI2342DS-T1-GE3" SI2342DS-T1-GE3 95.137,165.224 r180 bottom
T47 "SI2342DS-T1-GE3" SI2342DS-T1-GE3 87.265,165.224 r180 bottom
T48 "SI2342DS-T1-GE3" SI2342DS-T1-GE3 103.009,165.224 r180 bottom
T49 "SI2342DS-T1-GE3" SI2342DS-T1-GE3 117.053,165.224 r180 bottom
T50 "SI2342DS-T1-GE3" SI2342DS-T1-GE3 198.92,404.66 r270 bottom
T51 "SI2342DS-T1-GE3" SI2342DS-T1-GE3 119.837,388.294 r180 bottom
T52 "SI2342DS-T1-GE3" SI2342DS-T1-GE3 119.755,396.545 r180 bottom
T53 "SI2342DS-T1-GE3" SI2342DS-T1-GE3 116.52,442.104 r270 bottom
T54 "SI2342DS-T1-GE3" SI2342DS-T1-GE3 43.053,360.716 r90 bottom
T55 "SI2342DS-T1-GE3" SI2342DS-T1-GE3 117.778,249.928 r180 bottom
T56 "SI2342DS-T1-GE3" SI2342DS-T1-GE3 198.87,398.428 r270 bottom
T57 "SI2342DS-T1-GE3" SI2342DS-T1-GE3 40.821,334.297 r90 bottom
T58 "SI2342DS-T1-GE3" SI2342DS-T1-GE3 43.078,339.291 r90 bottom
TP19 "TestPoint" TestPoint 100.425,361.34 r0 top
TP20 "TestPoint" TestPoint 115.418,411.226 r0 top
TP21 "TestPoint" TestPoint 120.695,290.845 r0 top
TP22 "TestPoint" TestPoint 122.123,304.749 r180 bottom
TP23 "TestPoint" TestPoint 117.805,301.415 r180 bottom
TP25 "TestPoint" TestPoint 122.034,299.966 r180 bottom
TP27 "TestPoint" TestPoint 193.738,182.585 r0 top
TP29 "TestPoint" TestPoint 210.947,182.585 r0 top
TP31 "TestPoint" TestPoint 205.211,182.585 r0 top
TP32 "TestPoint" TestPoint 199.475,182.585 r0 top
TP34 "TestPoint" TestPoint 191.999,153.581 r0 top
TP35 "TestPoint" TestPoint 149.836,334.393 r0 top
TP36 "TestPoint" TestPoint 115.532,417.893 r0 top
TP38 "TestPoint" TestPoint 105.156,304.196 r0 top
TP42 "TestPoint" TestPoint 144.03,347.301 r0 top
U1 "FBVB900" "FBVB900 XX" 176.897,303.039 r90 top locked
U3_I2C_Bridge_GPIO "TCA9548" TCA9548 125.813,245.039 r90 top locked (schematic designator U3)
U3_I2C_Bridge_PCIE "TCA9548" TCA9548 102.07,386.613 r90 top (schematic designator U3)
U3_I2C_Bridge_SFP "TCA9548" TCA9548 87.535,303.346 r90 top (schematic designator U3)
U4 "TPS2121RUXT" TPS212x 48.71,184.321 r270 top
U5 "TPS2121RUXT" TPS212x 48.71,175 r270 top
U6 "FPF2895CUCX" FPF2895C-D 48.806,168.456 r180 top
U7 "FPF2895CUCX" FPF2895C-D 44.628,179.434 r0 top
U8 "MT40A512M16JY" MT40A512M16JY 203.657,334.06 r180 top locked
U9 "MT40A512M16JY" MT40A512M16JY 169.276,334.06 r180 top locked
U10 "MT40A512M16JY" MT40A512M16JY 192.197,334.06 r180 top locked
U11 "MT40A512M16JY" MT40A512M16JY 180.736,334.06 r180 top locked
U12 "LTC6952" LTC6952 92.697,334.061 r90 bottom
U13 "LTC6952" LTC6952 191.223,271.731 r90 top locked
U15 "SN74AXC4T774PWR" SN74AXC4T774PWR 135.623,269.926 r0 top locked
U16 "LMK05028" LMK05028 155.165,227.945 r90 top locked
U17 "FPF2895CUCX" FPF2895C-D 183.545,374.802 r0 top
U18 "FPF2895CUCX" FPF2895C-D 127.698,305.681 r180 top
U19 "LT3504EUFD#PBF" LT3504 173.828,169.45 r0 top
U20 "FPF2895CUCX" FPF2895C-D 217.156,262.804 r180 top
U21 "FPF2895CUCX" FPF2895C-D 263.909,370.567 r0 top
U22 "FPF2895CUCX" FPF2895C-D 96.428,370.507 r0 top
U23 "FPF2895CUCX" FPF2895C-D 131.955,259.938 r180 top
U24_SPI_bridge_Main "SN74AXC4T774PWR" SN74AXC4T774PWR 220.132,290.677 r0 top (schematic designator U24)
U24_SPI_bridge_PCIe "SN74AXC4T774PWR" SN74AXC4T774PWR 141.507,375.007 r270 top (schematic designator U24)
U25_SPI_bridge_Main "SN74AXC4T774PWR" SN74AXC4T774PWR 187.973,256.921 r90 top (schematic designator U25)
U25_SPI_bridge_PCIe "SN74AXC4T774PWR" SN74AXC4T774PWR 254.216,256.667 r90 top (schematic designator U25)
U26_SPI_bridge_Main "SN74AXC4T774PWR" SN74AXC4T774PWR 74.473,329.565 r0 top (schematic designator U26)
U26_SPI_bridge_PCIe "SN74AXC4T774PWR" SN74AXC4T774PWR 224.615,375.007 r270 top (schematic designator U26)
U27_SPI_bridge_Main "SN74AXC4T774PWR" SN74AXC4T774PWR 175.008,409.516 r180 top (schematic designator U27)
U27_SPI_bridge_PCIe "SN74AXC4T774PWR" SN74AXC4T774PWR 59.588,374.79 r270 top (schematic designator U27)
U28_SPI_bridge_Main "SN74AXC4T774PWR" SN74AXC4T774PWR 167.869,232.613 r180 top (schematic designator U28)
U28_SPI_bridge_PCIe "SN74AXC4T774PWR" SN74AXC4T774PWR 172.823,253.178 r90 top locked (schematic designator U28)
U30 "DAC1220" DAC1220 174.917,419.329 r180 top
U31 "SI53323-B-GM" SI53323-B-GM 50.343,399.199 r0 top
U32 "SI53323-B-GM" SI53323-B-GM 72.745,388.011 r270 top
U33 "CDCM1802RGTT" CDCM1802RGTT 61.719,387.985 r0 top
U34 "ADP1850ACPZ-R7" ADP1850 65.072,235.389 r0 top locked
U35_I2C_Expander_00 "MCP23017-E/ML" QFN-ML28_N 147.872,251.732 r90 top locked (schematic designator U35)
U35_I2C_Expander_01 "MCP23017-E/ML" QFN-ML28_N 77.463,342.689 r90 top locked (schematic designator U35)
U35_I2C_Expander_02 "MCP23017-E/ML" QFN-ML28_N 115.43,378.657 r90 top (schematic designator U35)
U35_I2C_Expander_10 "MCP23017-E/ML" QFN-ML28_N 208.43,368.94 r90 top (schematic designator U35)
U35_I2C_Expander_11 "MCP23017-E/ML" QFN-ML28_N 198.939,246.41 r90 top locked (schematic designator U35)
U35_I2C_Expander_12 "MCP23017-E/ML" QFN-ML28_N 139.916,179.565 r90 top (schematic designator U35)
U35_I2C_Expander_Main_Rst "MCP23017-E/ML" QFN-ML28_N 112.998,261.968 r90 bottom (schematic designator U35)
U35_I2C_Expander_PWR_CLK "MCP23017-E/ML" QFN-ML28_N 131.129,206.828 r270 top (schematic designator U35)
U35_I2C_Expander_PWR_Dist "MCP23017-E/ML" QFN-ML28_N 49.093,159.303 r0 top (schematic designator U35)
U35_I2C_Expander_SFP "MCP23017-E/ML" QFN-ML28_N 39.827,312.453 r90 top (schematic designator U35)
U36_Trans_LS_I2C0 "PCA9306" PCA9306 67.765,333.035 r180 bottom (schematic designator U36)
U36_Trans_LS_I2C1 "PCA9306" PCA9306 67.765,325.361 r180 bottom (schematic designator U36)
U36_Trans_PS_I2C0 "PCA9306" PCA9306 65.062,333.045 r0 top (schematic designator U36)
U36_Trans_PS_I2C1 "PCA9306" PCA9306 65.532,325.361 r0 top (schematic designator U36)
U37 "ADP1850ACPZ-R7" ADP1850 65.425,179.567 r0 top
U38 "ADP1850ACPZ-R7" ADP1850 63.703,206.464 r0 top
U39 "DP83867ERGZT" DP83867E 108.299,278.525 r0 bottom
U40 "MCP1727T-ADJE/MF" MCP1727T-ADJE/MF 119.609,339.819 r0 top
U41 "MTFC8GAKAJCN-4MITTR" "MTFC8GAKAJCN-4M IT TR" 124.188,317.841 r270 top locked
U42 "MCP1727T-ADJE/MF" MCP1727T-ADJE/MF 110.493,319.376 r0 top
U43 "SN74AXC4T774PWR" SN74AXC4T774PWR 201.27,361.404 r180 bottom
U44 "MAX16025TE+T" MAX16025TE+T 243.275,158.132 r90 top
U45 "USB3320C-EZK-TR" USB3320 55.105,347.091 r180 bottom
U46 "FPF2895CUCX" FPF2895C-D 48.275,355.49 r0 top
U47 "IP4856CX25/CZ" IP4856CX25/C 134.729,335.404 r180 bottom locked
U48 "TPS2121RUXT" TPS212x 48.677,193.983 r270 top
U49 "MCP1727T-ADJE/MF" MCP1727T-ADJE/MF 104.495,252.348 r90 top
U50 "MCP1727T-ADJE/MF" MCP1727T-ADJE/MF 99.101,252.371 r90 top
U51 "MCP1727T-ADJE/MF" MCP1727T-ADJE/MF 92.569,251.063 r90 top
U53 "SN74AXC4T774PWR" SN74AXC4T774PWR 215.024,204.708 r0 top
U54 "93LC56BT-I/OT" 93LC56BT 260.071,213.139 r90 top
U55 "FT4232HL-REEL" FT4232HL 245.72,205.766 r270 top locked
U56 "SN74AXC4T774PWR" SN74AXC4T774PWR 102.159,294.005 r180 bottom
U57 "SN74AXC4T774PWR" SN74AXC4T774PWR 226.098,191.973 r180 top
U58 "ISM330DHCXTR" ISM330DHCXL 214.053,242.754 r0 top
U59_5to3V3_1 "MCP1727T-ADJE/MF" MCP1727T-ADJE/MF 92.431,344.627 r0 top (schematic designator U59)
U59_5to3V3_2 "MCP1727T-ADJE/MF" MCP1727T-ADJE/MF 203.695,262.413 r180 top (schematic designator U59)
U59_5V_to_3V3_for_FTDI "MCP1727T-ADJE/MF" MCP1727T-ADJE/MF 264.919,206.777 r90 top (schematic designator U59)
U60 "ADP1741ACPZ-R7" ADP1752_1753/ADP1740_1741 91.914,319.028 r90 bottom
U61 "TPS7A8801RTJT" TPS7A88 171.628,212.498 r180 top
U62 "LT3042EDD#PBF" LT3042 158.785,400.986 r90 top
U63 "MAX3051EKA+T" "MAX3051EKA+T SOT23" 184.645,370.167 r0 top
U64_U_Pomiar_pradu_napiecia_1 "INA226AIDGSR" INA226 32.245,159.614 r90 top (schematic designator U64)
U64_U_Pomiar_pradu_napiecia_2 "INA226AIDGSR" INA226 31.298,204.035 r270 bottom (schematic designator U64)
U64_U_Pomiar_pradu_napiecia_3 "INA226AIDGSR" INA226 118.478,183.159 r180 top (schematic designator U64)
U64_U_Pomiar_pradu_napiecia_4 "INA226AIDGSR" INA226 118.649,167.56 r180 top (schematic designator U64)
U64_U_Pomiar_pradu_napiecia_5 "INA226AIDGSR" INA226 113.271,216.348 r180 top (schematic designator U64)
U64_U_Pomiar_pradu_napiecia_6 "INA226AIDGSR" INA226 112.941,199.508 r180 top (schematic designator U64)
U64_U_Pomiar_pradu_napiecia_PCIe0 "INA226AIDGSR" INA226 171.587,384.63 r270 top (schematic designator U64)
U64_U_Pomiar_pradu_napiecia_PCIe1 "INA226AIDGSR" INA226 224.281,249.17 r90 top (schematic designator U64)
U64_U_Pomiar_pradu_napiecia_PCIe2 "INA226AIDGSR" INA226 254.646,382.875 r270 top (schematic designator U64)
U64_U_Pomiar_pradu_napiecia_PCIe3 "INA226AIDGSR" INA226 89.633,382.271 r270 top (schematic designator U64)
U64_U_Pomiar_pradu_napiecia_PCIe4 "INA226AIDGSR" INA226 140.229,250.204 r90 top (schematic designator U64)
U65 "MAX17557ATP+" MAX17557 38.76,204.318 r90 top
U67 "LM3880MFE-1AF/NOPB" LM3880-Q1 176.589,160.085 r90 top
U68 "LM3880MFE-1AF/NOPB" LM3880-Q1 111.364,247.684 r180 top
U69 "ADP1741ACPZ-R7" ADP1752_1753/ADP1740_1741 128.605,235.393 r0 top
U70 "TPS7A8801RTJT" TPS7A88 150.914,282.003 r0 top
U71 "UA78M08CDCYR" UA78M 118.064,346.024 r270 top
U72 "INA226AIDGSR" INA226 138.353,281.203 r90 top
U73 "ST1L08SPUR" ST1L08 150.244,349.234 r0 top
U74 "SN74LVC1G08DBVR" SN74LVC1G08DBVR 250.685,350.164 r0 bottom
U75 "ESDCAN02-2BWY" ESDCAN02-2BWY 189.459,370.167 r180 top
U76 "SN74LVC1G08DBVR" SN74LVC1G08DBVR 259.08,348.666 r0 bottom
U77 "NC7WZ07FHX" NC7WZ07FHX 214.659,210.512 r180 top
U78 "NC7WZ07FHX" NC7WZ07FHX 211.632,210.124 r0 top
U79 "SN74AXC4T774PWR" SN74AXC4T774PWR 228.723,229.925 r90 top
X1 "OSC CRO 2000-2000 MHZ SMD .5X.5" CVCO55CW 98.755,357.657 r270 top locked
X2 "OSC VCO 490-540MHZ SMD .5X.5\"" CVCO55CW 164.503,420.599 r180 top
X3 "2.4576MHz" Crystal 183.68,420.653 r270 top
X4 "FA-23825.0000MB-C3" FA-23825.0000MB-C3 98.72,288.26 r270 bottom
X5 "32.768kHz" FC-135R/FC-135 203.86,316.649 r180 bottom
X6 "510CCA50M0000BAG" Si510 222.047,330.672 r270 top
X7 "TSX-322524.0000MF15X-AC6" "TSX-3225 24.0000MF15X-AC6" 54.52,355.74 r180 bottom
X8 "ECS-120-8-33-RWY-TR" ECS-120-8-33-RWY-TR 253.877,218.491 r90 top
X9 "SIT1602BI-12-33E-48.000000G" SiT1602B 150.063,241.643 r0 top

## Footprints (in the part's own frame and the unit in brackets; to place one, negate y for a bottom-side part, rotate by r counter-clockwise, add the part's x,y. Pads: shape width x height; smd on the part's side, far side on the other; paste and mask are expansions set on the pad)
93LC56BT [mm] "SOT-23-6, 6-Leads, Body 2,90x1,55mm, Pitch 0,95mm, IPC High Density"
  rect 1.1x0.6 smd: 1(-1.4,0.95) 2(-1.4,0) 3(-1.4,-0.95) 4(1.4,-0.95) 5(1.4,0) 6(1.4,0.95)
  silkscreen extent -1.52,-1.55 0.5,1.92, body extent -1.35,-1.55 1.35,1.55, height 1.45
2007132 [mm] "SFP Connector"
  rect 2x2 hole 1.05: SH1(-2.5,-5) SH1(0,0) SH2(8.575,-5) SH3(14.25,-5) SH4(0,10) SH5(5.675,10) SH6(11.075,10) SH7(14.25,15) SH8(0,20) SH9(0,30) SH10(14.25,5) SH13(19.925,10) SH14(25.325,10) SH17(22.825,-5) SH20(34.175,10) SH21(39.575,10) SH22(42.75,10) SH23(42.75,0) SH24(37.075,-5) SH25(42.75,20) SH26(42.75,30) SH29(57,15) SH30(57,5) SH31(57,-5) SH32(48.425,10) SH33(53.825,10) SH34(51.325,-5)
  round 1.458 hole 0.95: SH11(14.25,22.5) SH12(14.25,27.5) SH15(28.5,10) SH16(28.5,0) SH18(28.5,20) SH19(28.5,30) SH27(57,27.5) SH28(57,22.5) SH35(0,17.8) SH36(2.325,32.1) SH37(7.125,32.1) SH38(14.25,17.8) SH39(16.575,32.1) SH40(21.375,32.1) SH41(30.825,32.1) SH42(35.625,32.1) SH43(45.075,32.1) SH44(49.875,32.1) SH45(42.75,17.8) SH46(57,17.8)
  silkscreen extent 0,-9.5 57.25,32.57, body extent -0.97,-16.49 58.08,32.49, height 10.62
79523141 [mm] "Battery Holder, Battery Type: 2016,2020,2025,2032"
  rect 5.2x5.2 smd: 1(-12.95,0) 1(12.95,0)
  rect 4x4 smd: 2(0,0)
  silkscreen extent -10.55,-10.5 10.55,9.3, body extent -15.25,-10.5 15.25,9.3, height 4
1703820001 [mm] "20 Position zSFP+ Receptacle Connector Solder Surface Mount, Right Angle"
  rect 0.5x2 smd: 1(1.4,-4.1) 2(2.2,-4.1) 3(3,-4.1) 4(3.8,-4.1) 5(4.6,-4.1) 6(5.4,-4.1) 7(6.2,-4.1) 8(7,-4.1) 9(7.8,-4.1) 10(8.6,-4.1) 11(8.2,4.1) 12(7.4,4.1) 13(6.6,4.1) 14(5.8,4.1) 15(5,4.1) 16(4.2,4.1) 17(3.4,4.1) 18(2.6,4.1) 19(1.8,4.1) 20(1,4.1)
  round 1.55 hole 1.55: ""(0,0)
  round 1.55 hole 1.55 unplated: ""(9.6,0)
  silkscreen extent -1.33,-8.3 10.92,6.2, body extent -0.69,-4.41 10.31,4.26, height 5.17
7499511440 [mm] "LAN Transformer, body 33.02x17mm"
  rect 1.4x1.4 hole 0.89: 1(5.075,9.63)
  round 1.4 hole 0.89: 2(3.045,9.63) 3(1.015,9.63) 4(-1.015,9.63) 5(-3.045,9.63) 6(-5.075,9.63) 7(6.09,12.17) 8(4.06,12.17) 9(2.03,12.17) 10(-2.03,12.17) 11(-4.06,12.17) 12(-6.09,12.17)
  oval 1.4x1.25 hole 0.89: 13(5.59,2.51) 14(-5.59,2.51) 15(5.59,1.05) 16(-5.59,1.05)
  round 1.52 hole 1.02: 17(6.095,14.71) 18(3.555,14.71) 19(-3.555,14.71) 20(-6.095,14.71)
  round 2.8 hole 2.8 unplated: MH1(-6.35,-5.61) MH2(6.35,-5.61)
  round 2.4 hole 1.57: S1(-8.065,-8.79) S2(8.065,-8.79)
  silkscreen extent -10.72,-16.51 10.72,16.51, body extent -10.8,-16.51 10.8,16.51, height 16.21
9774025243 [mm] "SMT Steel Spacer with internal Thread M2, height 2.5mm"
  round 5 hole 3: 1(0,0)
  body extent -2.17,-2.17 2.18,2.17, height 2.5
"9774045243 - dual side copper" [mm] "SMT Steel Spacer with internal Thread M2, height 4.5mm"
  round 5.3 hole 3: 1(0,0)
  body extent -2.17,-2.17 2.18,2.17, height 4.5
61400413321 [mm] "F Str 04p Btype vertical"
  rect 1.428x1.428 hole 0.92: 1(1.25,1.6)
  round 1.428 hole 0.92: 2(-1.25,1.6) 3(-1.25,-1.6) 4(1.25,-1.6)
  round 2.8 hole 2.3: Z1(-6.02,-1.1) Z2(6.02,-1.1)
  silkscreen extent -6.1,-5.94 6.1,5.31, body extent -7.4,-5.94 7.4,5.26, height 16.11
430181038816 [mm] "Tact Switch, SMD, body 4.5x4.5mm"
  rect 2x1.4 smd: 1(-3.5,1.5) 2(3.5,1.5) 3(-3.5,-1.5) 4(3.5,-1.5)
  silkscreen extent -2.25,-2.25 2.25,2.25, body extent -3.75,-2.25 3.75,2.25, height 3.8
692121130100 [mm] "Receptacle TH Reverse Offset 0.14mm"
  rect 1.2x1.2 hole 0.7: 1(-4.35,2.43)
  round 1.2 hole 0.7: 2(-6.85,2.43) 3(-8.85,2.43) 4(-11.35,2.43) 5(-11.85,0.93) 6(-9.85,0.93) 7(-7.85,0.93) 8(-5.85,0.93) 9(-3.85,0.93)
  oval 1.4x2.8 hole 0.8 slot 2.3 at 90 deg: Z1(-15.7,-6.8) Z1(-15.7,0) Z1(0,-6.8) Z1(0,0)
  Keep-Out Layer board cut-out: -14.6,-0.2 -1.1,-0.2 -1.1,-12.15 -14.6,-12.15
  Mechanical 1 keep-out lines w0.127: -14.6,-12.15 -14.6,-0.2 -1.1,-0.2 -1.1,-12.15 -14.6,-12.15
  silkscreen extent -15.16,-12.15 -0.53,3.72, body extent -15.85,-12.15 0.15,3.72, height 3.71
693071020811 [mm] "Micro SD Card Connector Push & Push - with Card Detection - 8 Pins"
  rect 0.7x1.9 smd: 1(2.25,7.75) 2(1.15,7.75) 3(0.05,7.75) 4(-1.05,7.75) 5(-2.15,7.75) 6(-3.25,7.75) 7(-4.35,7.75) 8(-5.45,7.75) 9(-6.55,7.75)
  rect 1.7x1.8 smd: 10(-8.1,6.7) 11(7.4,6.7)
  rect 1.4x2.6 smd: 12(-7.85,-2.9) 13(7.85,-2.9)
  round 0.9 hole 0.9 unplated: MH1(-4.95,-3.3)
  oval 1.7x0.9 hole 0.9 slot 1.7 at 0 deg unplated: MH2(3.05,-3.3)
  silkscreen extent -7.35,-7.25 7.35,7.25, body extent -8.2,-7.3 8.2,7.73, height 1.85
744373560068 [mm] "Precision Wire Wound Inductor, 2-Leads, Body 9,70x8,50mm, IPC High Density"
  rect 2.52x5.33 smd: 1(-3.62,0) 2(3.62,0)
  silkscreen extent -5.1,-4.25 5.1,4.25, body extent -4.95,-4.25 4.95,4.25, height 3.1
ADP1752_1753/ADP1740_1741 [mm] "16-Lead Lead Frame Chip Scale Package [LFCSP_WQ]  4 mm × 4 mm Body, Very Very Thin Quad  (CP-16-23)"
  rect 0.6x0.3 smd: 1(-1.675,0.975) 2(-1.675,0.325) 3(-1.675,-0.325) 4(-1.675,-0.975) 9(1.675,-0.975) 10(1.675,-0.325) 11(1.675,0.325) 12(1.675,0.975)
  rect 0.3x0.6 smd: 5(-0.975,-1.675) 6(-0.325,-1.675) 7(0.325,-1.675) 8(0.975,-1.675) 13(0.975,1.675) 14(0.325,1.675) 15(-0.325,1.675) 16(-0.975,1.675)
  rect 2.1x2.1 smd: 17(0,0)
  silkscreen extent -2.82,-2.05 2.05,2.05, body extent -2.05,-2.05 2.05,2.05, height 0.8
ADP1850 [mm] "32-Lead Lead Frame Chip Scale Package [LFCSP] 5 mm × 5 mm Body and 0.75 mm Package Height (CP-32-12)"
  rect 0.4x0.25 smd: 1(-2.25,1.75) 2(-2.25,1.25) 3(-2.25,0.75) 4(-2.25,0.25) 5(-2.25,-0.25) 6(-2.25,-0.75) 7(-2.25,-1.25) 8(-2.25,-1.75) 17(2.25,-1.75) 18(2.25,-1.25) 19(2.25,-0.75) 20(2.25,-0.25) 21(2.25,0.25) 22(2.25,0.75) 23(2.25,1.25) 24(2.25,1.75)
  rect 0.25x0.4 smd: 9(-1.75,-2.25) 10(-1.25,-2.25) 11(-0.75,-2.25) 12(-0.25,-2.25) 13(0.25,-2.25) 14(0.75,-2.25) 15(1.25,-2.25) 16(1.75,-2.25) 25(1.75,2.25) 26(1.25,2.25) 27(0.75,2.25) 28(0.25,2.25) 29(-0.25,2.25) 30(-0.75,2.25) 31(-1.25,2.25) 32(-1.75,2.25)
  rect 3.6x3.6 smd paste-3: 33(0,0)
  silkscreen extent -3.27,-2.5 2.5,2.5, body extent -2.5,-2.5 2.5,2.5, height 0.8
BAS40-04-TP [mm] "SOT23, 3-Leads, Body 2,92x2,37mm, Pitch 0,90mm, IPC High Density"
  rect 0.9x0.8 smd: 1(-1,0.95) 2(-1,-0.95) 3(1,0)
  silkscreen extent -1.13,-1.5 0.7,1.97, body extent -1.32,-1.52 1.32,1.52, height 1.12
BAT54T1G [mm] "SOD-123  CASE 425-04"
  rect 0.91x1.22 smd: 1(-1.635,0) 2(1.635,0)
  silkscreen extent -2.04,0.86 -1.94,0.96, body extent -1.86,-0.9 1.86,0.9, height 1.35
Battery [mm]
  rect 0.5x1.8 smd: 1(1,0) 2(-1,0)
  silkscreen extent -4.86,-2.5 4.91,11.73
BSC030N03LS [mm] "PG-TDSON-8-1"
  rect 0.85x0.6 smd: 1(-2.9,1.905) 2(-2.9,0.635) 3(-2.9,-0.635) 4(-2.9,-1.905)
  rect 0.8x0.6 smd: 5(2.925,-1.905) 6(2.925,-0.635) 7(2.925,0.635) 8(2.925,1.905)
  rect 3.762x4.41 smd paste-2: 8(0.662,0)
  silkscreen extent -3.77,-2.9 3.32,2.94, body extent -3.32,-2.75 3.32,2.75, height 1.1
BSC080N03LS [mm] "PG-TDSON-8-5"
  rect 0.85x0.6 smd: 1(-2.9,1.905) 2(-2.9,0.635) 3(-2.9,-0.635) 4(-2.9,-1.905)
  rect 0.8x0.6 smd: 5(2.925,-1.905) 6(2.925,-0.635) 7(2.925,0.635) 8(2.925,1.905)
  rect 3.762x4.41 smd paste-2: 8(0.662,0)
  silkscreen extent -3.77,-2.9 3.32,2.94, body extent -3.32,-2.75 3.32,2.75, height 1.1
"CAP 0201/0603 KK" [mm] "Chip Capacitor, 2-Leads, Body 0.60x0.30mm, IPC High Density"
  rect 0.3x0.32 smd mask+0.062: 1(-0.26,0) 2(0.26,0)
  silkscreen extent -0.58,-0.33 0.58,0.33, body extent -0.3,-0.15 0.3,0.15, height 0.3
"CAP 0402/1005 KK" [mm] "Chip Capacitor, 2-Leads, Body 1.02x0.51mm, IPC Medium Density"
  rect 0.55x0.65 smd: 1(-0.525,0) 2(0.525,0)
  silkscreen extent -1,-0.5 1,0.5, body extent -0.5,-0.26 0.5,0.26, height 0.52
"CAP 0603/1608 RF" [mm] "Chip Capacitor, 2-Leads, Body 1.60x0.80mm, IPC High Density"
  rect 0.8x0.9 smd: 1(-0.625,0) 2(0.625,0)
  silkscreen extent -1.2,-0.62 1.2,0.62, body extent -0.8,-0.41 0.8,0.41, height 0.82
"CAP 0805/2012 RF" [mm] "Chip Capacitor, 2-Leads, Body 2.00x1.20mm, IPC High Density"
  rect 1.1x1.3 smd: 1(-0.7,0) 2(0.7,0)
  silkscreen extent -1.43,-0.82 1.43,0.82, body extent -1,-0.64 1,0.64, height 1.26
"CAP 1206/3216" [mm] "Chip Capacitor, 2-Leads, Body 3.25x1.60mm, IPC Medium Density"
  rect 1.3x1.8 smd: 1(-1.45,0) 2(1.45,0)
  silkscreen extent -2.38,-1.13 2.38,1.13, body extent -1.6,-0.81 1.6,0.81, height 1.62
"CAP 1206/3216 - 0.8MM" [mm] "Chip Capacitor, 2-Leads, Body 3.25x1.60mm, IPC Medium Density"
  rect 1.3x1.8 smd: 1(-1.45,0) 2(1.45,0)
  silkscreen extent -2.38,-1.13 2.38,1.13, body extent -1.6,-0.8 1.6,0.8, height 0.8
"CAP 1210/3225 - 1MM" [mm] "Chip Capacitor, 2-Leads, Body 3.20x2.50mm, IPC Medium Density"
  rect 1.3x2.7 smd: 1(-1.4,0) 2(1.4,0)
  silkscreen extent -2.38,-1.62 2.38,1.62, body extent -1.6,-1.25 1.6,1.25, height 1
"CAP POL 2917/7343" [mm] "Molded Capacitor, 2-Leads, Body 7.30x4.30mm, IPC Medium Density"
  rect 2.55x2.45 smd: 1(-3.025,0) 2(3.025,0)
  silkscreen extent -4.57,-2.3 3.8,2.3, body extent -3.65,-2.15 3.65,2.15, height 4.1
CAPC3326X17L [mm] "Chip Capacitor, 2-Leads, Body 3,30x2,60mm, IPC High Density"
  rect 0.95x2.6 smd: 1(-1.4,0) 2(1.4,0)
  silkscreen extent -0.2,-1.2 0.2,1.2, body extent -1.85,-1.45 1.85,1.45, height 1.7
"CASE 457" [mil] "CASE 457-04, MBRM140T1G"
  rect 105.12x100 smd: 1(-65.06,0)
  rect 30x50 smd: 2(27.5,0)
  silkscreen extent -126,-61 -122,-57, body extent -118,-52 27,53, height 43
CDCM1802RGTT [mm] "PQFN, 16-Leads, Body 3,00x3,00mm, Pitch 0,50mm, Thermal Pad 1,45x1,45mm, IPC High Density"
  rect 0.6x0.24 smd: 1(-1.4,0.75) 2(-1.4,0.25) 3(-1.4,-0.25) 4(-1.4,-0.75) 9(1.4,-0.75) 10(1.4,-0.25) 11(1.4,0.25) 12(1.4,0.75)
  rect 0.24x0.6 smd: 5(-0.75,-1.4) 6(-0.25,-1.4) 7(0.25,-1.4) 8(0.75,-1.4) 13(0.75,1.4) 14(0.25,1.4) 15(-0.25,1.4) 16(-0.75,1.4)
  rect 1.45x1.45 smd paste-0.11: 17(0,0)
  silkscreen extent -2.32,-1.55 1.55,1.55, body extent -1.55,-1.55 1.55,1.55, height 1
CDRH4D28NP [mm] "Precision Wire Wound Inductor, 2-Leads, Body 4,70x4,70mm, IPC High Density"
  rect 1.9x5.3 smd: 1(-1.7,0) 2(1.7,0)
  body extent -2.45,-2.35 2.45,2.35, height 3.1
CDRH5D28 [mm] "CDRH5D28 , Precision Wire Wound Inductor, 2-Leads, Body 6,00x6,00mm, IPC High Density"
  rect 2.15x6.3 smd: 1(-2.075,0) 2(2.075,0)
  silkscreen extent -0.45,-3 0.45,3, body extent -3.1,-3.15 3.1,3.15, height 3.1
Crystal [mm]
  round 1.2 hole 0.6: 1(0,0) 2(4.88,0)
  silkscreen extent -3.81,-1.91 8.69,1.91
CVCO55CW [mm]
  rect 1.32x1.32 smd: 1(0,9.779) 2(0,7.239) 3(0,4.699) 4(0,2.159) 5(2.667,0) 6(5.207,0) 7(7.747,0) 8(10.287,0) 9(12.7,3.048) 10(12.7,5.588) 11(12.7,8.128) 12(12.7,10.668) 13(10.541,12.7) 14(8.001,12.7) 15(5.461,12.7) 16(2.921,12.7)
  silkscreen extent -1.95,0 12.7,12.7
DAC1220 [mm]
  rect 1.6x0.41 smd: 1(-2.667,2.235) 2(-2.667,1.6) 3(-2.667,0.965) 4(-2.667,0.33) 5(-2.667,-0.305) 6(-2.667,-0.94) 7(-2.667,-1.575) 8(-2.667,-2.21) 9(2.667,-2.21) 10(2.667,-1.575) 11(2.667,-0.94) 12(2.667,-0.305) 13(2.667,0.33) 14(2.667,0.965) 15(2.667,1.6) 16(2.667,2.235)
  silkscreen extent -1.55,-2.49 1.55,2.49
"DF005S2 - DF10S2" [mm] "4-LEAD, SDIP, 6.5 MM WIDE"
  rect 1.5x1.3 smd: 1(-4.45,2.55) 2(-4.45,-2.55) 3(4.45,-2.55) 4(4.45,2.55)
  silkscreen extent -4.57,-4.25 2.85,4.25, body extent -4.92,-4.25 4.92,4.25, height 2.6
DFLS1100 [mm] "Molded Diode, 2-Leads, Body 2,80x1,78mm, IPC High Density"
  rect 1.05x1.5 smd: 1(-0.85,0)
  rect 2.4x1.5 smd: 2(1.524,0)
  silkscreen extent -0.81,-1.02 1.27,1.07, body extent -1.02,-0.96 2.42,0.96, height 1
DP83867E [mm] "VQFN, 48-Leads, Body 7,00x7,00mm, Pitch 0,50mm, Thermal Pad 4,10x4,10mm, IPC High Density"
  oval 0.6x0.24 smd: 1(-3.4,2.75) 2(-3.4,2.25) 3(-3.4,1.75) 4(-3.4,1.25) 5(-3.4,0.75) 6(-3.4,0.25) 7(-3.4,-0.25) 8(-3.4,-0.75) 9(-3.4,-1.25) 10(-3.4,-1.75) 11(-3.4,-2.25) 12(-3.4,-2.75) 25(3.4,-2.75) 26(3.4,-2.25) 27(3.4,-1.75) 28(3.4,-1.25) 29(3.4,-0.75) 30(3.4,-0.25) 31(3.4,0.25) 32(3.4,0.75) 33(3.4,1.25) 34(3.4,1.75) 35(3.4,2.25) 36(3.4,2.75)
  oval 0.24x0.6 smd: 13(-2.75,-3.4) 14(-2.25,-3.4) 15(-1.75,-3.4) 16(-1.25,-3.4) 17(-0.75,-3.4) 18(-0.25,-3.4) 19(0.25,-3.4) 20(0.75,-3.4) 21(1.25,-3.4) 22(1.75,-3.4) 23(2.25,-3.4) 24(2.75,-3.4) 37(2.75,3.4) 38(2.25,3.4) 39(1.75,3.4) 40(1.25,3.4) 41(0.75,3.4) 42(0.25,3.4) 43(-0.25,3.4) 44(-0.75,3.4) 45(-1.25,3.4) 46(-1.75,3.4) 47(-2.25,3.4) 48(-2.75,3.4)
  rect 4.1x4.1 smd paste-2.5: 49(0,0)
  silkscreen extent -4.35,-3.57 3.57,3.58, body extent -3.57,-3.58 3.58,3.57, height 1
ECS-120-8-33-RWY-TR [mm] "Ceramic package 4-Leads, Body 2,50x3,20mm, Pitch 1,80mm, IPC High Density"
  rect 1.3x1.1 smd: 1(-1.15,-0.9) 2(1.15,-0.9) 3(1.15,0.9) 4(-1.15,0.9)
  silkscreen extent -2.1,-1.55 -2,-1.45, body extent -1.6,-1.25 1.6,1.25, height 0.8
ESDCAN02-2BWY [mm] "SOT23, 3-Leads, Body 2,00x2,10mm, Pitch 0,65mm, IPC High Density"
  rect 0.7x0.42 smd: 1(-1,0.65) 2(-1,-0.65) 3(1,0)
  silkscreen extent -1.13,-1.1 0.67,1.53, body extent -1.3,-1.1 1.3,1.1, height 1.1
FA-23825.0000MB-C3 [mm] "3.2 x 2.5 x 0.7 mm -- FA-238V / FA-238"
  rect 0.8x0.9 smd: 1(-0.75,1.05) 2(-0.75,-1.05) 3(0.75,-1.05) 4(0.75,1.05)
  silkscreen extent -1.81,1.66 -1.71,1.76, body extent -1.25,-1.6 1.25,1.6, height 0.7
FB0603 [mm] "Chip Inductor, 2-Leads, Body 1,60x0,80mm, IPC High Density"
  rect 0.6x0.85 smd: 1(-0.7,0) 2(0.7,0)
  silkscreen extent -0.05,-0.3 0.05,0.3, body extent -0.8,-0.4 0.8,0.4, height 0.8
"FBVB900 XX" [mm] "BGA, 900-Leads, Body 31,00x31,00mmx2,88mm, Pitch 1,00mm"
  round 0.5 smd: A1(-14.5,14.5) A2(-13.5,14.5) A3(-12.5,14.5) A4(-11.5,14.5) A5(-10.5,14.5) A6(-9.5,14.5) A7(-8.5,14.5) A8(-7.5,14.5) A9(-6.5,14.5) A10(-5.5,14.5) A11(-4.5,14.5) A12(-3.5,14.5) A13(-2.5,14.5) A14(-1.5,14.5) A15(-0.5,14.5) A16(0.5,14.5) A17(1.5,14.5) A18(2.5,14.5) A19(3.5,14.5) A20(4.5,14.5) A21(5.5,14.5) A22(6.5,14.5) A23(7.5,14.5) A24(8.5,14.5) A25(9.5,14.5) A26(10.5,14.5) A27(11.5,14.5) A28(12.5,14.5) A29(13.5,14.5) A30(14.5,14.5) AA1(-14.5,-5.5) AA2(-13.5,-5.5) AA3(-12.5,-5.5) AA4(-11.5,-5.5) AA5(-10.5,-5.5) AA6(-9.5,-5.5) AA7(-8.5,-5.5) AA8(-7.5,-5.5) AA9(-6.5,-5.5) AA10(-5.5,-5.5) AA11(-4.5,-5.5) AA12(-3.5,-5.5) AA13(-2.5,-5.5) AA14(-1.5,-5.5) AA15(-0.5,-5.5) AA16(0.5,-5.5) AA17(1.5,-5.5) AA18(2.5,-5.5) AA19(3.5,-5.5) AA20(4.5,-5.5) AA21(5.5,-5.5) AA22(6.5,-5.5) AA23(7.5,-5.5) AA24(8.5,-5.5) AA25(9.5,-5.5) AA26(10.5,-5.5) AA27(11.5,-5.5) AA28(12.5,-5.5) AA29(13.5,-5.5) AA30(14.5,-5.5) AB1(-14.5,-6.5) AB2(-13.5,-6.5) AB3(-12.5,-6.5) AB4(-11.5,-6.5) AB5(-10.5,-6.5) AB6(-9.5,-6.5) AB7(-8.5,-6.5) AB8(-7.5,-6.5) AB9(-6.5,-6.5) AB10(-5.5,-6.5) AB11(-4.5,-6.5) AB12(-3.5,-6.5) AB13(-2.5,-6.5) AB14(-1.5,-6.5) AB15(-0.5,-6.5) AB16(0.5,-6.5) AB17(1.5,-6.5) AB18(2.5,-6.5) AB19(3.5,-6.5) AB20(4.5,-6.5) AB21(5.5,-6.5) AB22(6.5,-6.5) AB23(7.5,-6.5) AB24(8.5,-6.5) AB25(9.5,-6.5) AB26(10.5,-6.5) AB27(11.5,-6.5) AB28(12.5,-6.5) AB29(13.5,-6.5) AB30(14.5,-6.5) AC1(-14.5,-7.5) AC2(-13.5,-7.5) AC3(-12.5,-7.5) AC4(-11.5,-7.5) AC5(-10.5,-7.5) AC6(-9.5,-7.5) AC7(-8.5,-7.5) AC8(-7.5,-7.5) AC9(-6.5,-7.5) AC10(-5.5,-7.5) AC11(-4.5,-7.5) AC12(-3.5,-7.5) AC13(-2.5,-7.5) AC14(-1.5,-7.5) AC15(-0.5,-7.5) AC16(0.5,-7.5) AC17(1.5,-7.5) AC18(2.5,-7.5) AC19(3.5,-7.5) AC20(4.5,-7.5) AC21(5.5,-7.5) AC22(6.5,-7.5) AC23(7.5,-7.5) AC24(8.5,-7.5) AC25(9.5,-7.5) AC26(10.5,-7.5) AC27(11.5,-7.5) AC28(12.5,-7.5) AC29(13.5,-7.5) AC30(14.5,-7.5) AD1(-14.5,-8.5) AD2(-13.5,-8.5) AD3(-12.5,-8.5) AD4(-11.5,-8.5) AD5(-10.5,-8.5) AD6(-9.5,-8.5) AD7(-8.5,-8.5) AD8(-7.5,-8.5) AD9(-6.5,-8.5) AD10(-5.5,-8.5) AD11(-4.5,-8.5) AD12(-3.5,-8.5) AD13(-2.5,-8.5) AD14(-1.5,-8.5) AD15(-0.5,-8.5) AD16(0.5,-8.5) AD17(1.5,-8.5) AD18(2.5,-8.5) AD19(3.5,-8.5) AD20(4.5,-8.5) AD21(5.5,-8.5) AD22(6.5,-8.5) AD23(7.5,-8.5) AD24(8.5,-8.5) AD25(9.5,-8.5) AD26(10.5,-8.5) AD27(11.5,-8.5) AD28(12.5,-8.5) AD29(13.5,-8.5) AD30(14.5,-8.5) AE1(-14.5,-9.5) AE2(-13.5,-9.5) AE3(-12.5,-9.5) AE4(-11.5,-9.5) AE5(-10.5,-9.5) AE6(-9.5,-9.5) AE7(-8.5,-9.5) AE8(-7.5,-9.5) AE9(-6.5,-9.5) AE10(-5.5,-9.5) AE11(-4.5,-9.5) AE12(-3.5,-9.5) AE13(-2.5,-9.5) AE14(-1.5,-9.5) AE15(-0.5,-9.5) AE16(0.5,-9.5) AE17(1.5,-9.5) AE18(2.5,-9.5) AE19(3.5,-9.5) AE20(4.5,-9.5) AE21(5.5,-9.5) AE22(6.5,-9.5) AE23(7.5,-9.5) AE24(8.5,-9.5) AE25(9.5,-9.5) AE26(10.5,-9.5) AE27(11.5,-9.5) AE28(12.5,-9.5) AE29(13.5,-9.5) AE30(14.5,-9.5) AF1(-14.5,-10.5) AF2(-13.5,-10.5) AF3(-12.5,-10.5) AF4(-11.5,-10.5) AF5(-10.5,-10.5) AF6(-9.5,-10.5) AF7(-8.5,-10.5) AF8(-7.5,-10.5) AF9(-6.5,-10.5) AF10(-5.5,-10.5) AF11(-4.5,-10.5) AF12(-3.5,-10.5) AF13(-2.5,-10.5) AF14(-1.5,-10.5) AF15(-0.5,-10.5) AF16(0.5,-10.5) AF17(1.5,-10.5) AF18(2.5,-10.5) AF19(3.5,-10.5) AF20(4.5,-10.5) AF21(5.5,-10.5) AF22(6.5,-10.5) AF23(7.5,-10.5) AF24(8.5,-10.5) AF25(9.5,-10.5) AF26(10.5,-10.5) AF27(11.5,-10.5) AF28(12.5,-10.5) AF29(13.5,-10.5) AF30(14.5,-10.5) AG1(-14.5,-11.5) AG2(-13.5,-11.5) AG3(-12.5,-11.5) AG4(-11.5,-11.5) AG5(-10.5,-11.5) AG6(-9.5,-11.5) AG7(-8.5,-11.5) AG8(-7.5,-11.5) AG9(-6.5,-11.5) AG10(-5.5,-11.5) AG11(-4.5,-11.5) AG12(-3.5,-11.5) AG13(-2.5,-11.5) AG14(-1.5,-11.5) AG15(-0.5,-11.5) AG16(0.5,-11.5) AG17(1.5,-11.5) AG18(2.5,-11.5) AG19(3.5,-11.5) AG20(4.5,-11.5) AG21(5.5,-11.5) AG22(6.5,-11.5) AG23(7.5,-11.5) AG24(8.5,-11.5) AG25(9.5,-11.5) AG26(10.5,-11.5) AG27(11.5,-11.5) AG28(12.5,-11.5) AG29(13.5,-11.5) AG30(14.5,-11.5) AH1(-14.5,-12.5) AH2(-13.5,-12.5) AH3(-12.5,-12.5) AH4(-11.5,-12.5) AH5(-10.5,-12.5) AH6(-9.5,-12.5) AH7(-8.5,-12.5) AH8(-7.5,-12.5) AH9(-6.5,-12.5) AH10(-5.5,-12.5) AH11(-4.5,-12.5) AH12(-3.5,-12.5) AH13(-2.5,-12.5) AH14(-1.5,-12.5) AH15(-0.5,-12.5) AH16(0.5,-12.5) AH17(1.5,-12.5) AH18(2.5,-12.5) AH19(3.5,-12.5) AH20(4.5,-12.5) AH21(5.5,-12.5) AH22(6.5,-12.5) AH23(7.5,-12.5) AH24(8.5,-12.5) AH25(9.5,-12.5) AH26(10.5,-12.5) AH27(11.5,-12.5) AH28(12.5,-12.5) AH29(13.5,-12.5) AH30(14.5,-12.5) AJ1(-14.5,-13.5) AJ2(-13.5,-13.5) AJ3(-12.5,-13.5) AJ4(-11.5,-13.5) AJ5(-10.5,-13.5) AJ6(-9.5,-13.5) AJ7(-8.5,-13.5) AJ8(-7.5,-13.5) AJ9(-6.5,-13.5) AJ10(-5.5,-13.5) AJ11(-4.5,-13.5) AJ12(-3.5,-13.5) AJ13(-2.5,-13.5) AJ14(-1.5,-13.5) AJ15(-0.5,-13.5) AJ16(0.5,-13.5) AJ17(1.5,-13.5) AJ18(2.5,-13.5) AJ19(3.5,-13.5) AJ20(4.5,-13.5) AJ21(5.5,-13.5) AJ22(6.5,-13.5) AJ23(7.5,-13.5) AJ24(8.5,-13.5) AJ25(9.5,-13.5) AJ26(10.5,-13.5) AJ27(11.5,-13.5) AJ28(12.5,-13.5) AJ29(13.5,-13.5) AJ30(14.5,-13.5) AK1(-14.5,-14.5) AK2(-13.5,-14.5) AK3(-12.5,-14.5) AK4(-11.5,-14.5) AK5(-10.5,-14.5) AK6(-9.5,-14.5) AK7(-8.5,-14.5) AK8(-7.5,-14.5) AK9(-6.5,-14.5) AK10(-5.5,-14.5) AK11(-4.5,-14.5) AK12(-3.5,-14.5) AK13(-2.5,-14.5) AK14(-1.5,-14.5) AK15(-0.5,-14.5) AK16(0.5,-14.5) AK17(1.5,-14.5) AK18(2.5,-14.5) AK19(3.5,-14.5) AK20(4.5,-14.5) AK21(5.5,-14.5) AK22(6.5,-14.5) AK23(7.5,-14.5) AK24(8.5,-14.5) AK25(9.5,-14.5) AK26(10.5,-14.5) AK27(11.5,-14.5) AK28(12.5,-14.5) AK29(13.5,-14.5) AK30(14.5,-14.5) B1(-14.5,13.5) B2(-13.5,13.5) B3(-12.5,13.5) B4(-11.5,13.5) B5(-10.5,13.5) B6(-9.5,13.5) B7(-8.5,13.5) B8(-7.5,13.5) B9(-6.5,13.5) B10(-5.5,13.5) B11(-4.5,13.5) B12(-3.5,13.5) B13(-2.5,13.5) B14(-1.5,13.5) B15(-0.5,13.5) B16(0.5,13.5) B17(1.5,13.5) B18(2.5,13.5) B19(3.5,13.5) B20(4.5,13.5) B21(5.5,13.5) B22(6.5,13.5) B23(7.5,13.5) B24(8.5,13.5) B25(9.5,13.5) B26(10.5,13.5) B27(11.5,13.5) B28(12.5,13.5) B29(13.5,13.5) B30(14.5,13.5) C1(-14.5,12.5) C2(-13.5,12.5) C3(-12.5,12.5) C4(-11.5,12.5) C5(-10.5,12.5) C6(-9.5,12.5) C7(-8.5,12.5) C8(-7.5,12.5) C9(-6.5,12.5) C10(-5.5,12.5) C11(-4.5,12.5) C12(-3.5,12.5) C13(-2.5,12.5) C14(-1.5,12.5) C15(-0.5,12.5) C16(0.5,12.5) C17(1.5,12.5) C18(2.5,12.5) C19(3.5,12.5) C20(4.5,12.5) C21(5.5,12.5) C22(6.5,12.5) C23(7.5,12.5) C24(8.5,12.5) C25(9.5,12.5) C26(10.5,12.5) C27(11.5,12.5) C28(12.5,12.5) C29(13.5,12.5) C30(14.5,12.5) D1(-14.5,11.5) D2(-13.5,11.5) D3(-12.5,11.5) D4(-11.5,11.5) D5(-10.5,11.5) D6(-9.5,11.5) D7(-8.5,11.5) D8(-7.5,11.5) D9(-6.5,11.5) D10(-5.5,11.5) D11(-4.5,11.5) D12(-3.5,11.5) D13(-2.5,11.5) D14(-1.5,11.5) D15(-0.5,11.5) D16(0.5,11.5) D17(1.5,11.5) D18(2.5,11.5) D19(3.5,11.5) D20(4.5,11.5) D21(5.5,11.5) D22(6.5,11.5) D23(7.5,11.5) D24(8.5,11.5) D25(9.5,11.5) D26(10.5,11.5) D27(11.5,11.5) D28(12.5,11.5) D29(13.5,11.5) D30(14.5,11.5) E1(-14.5,10.5) E2(-13.5,10.5) E3(-12.5,10.5) E4(-11.5,10.5) E5(-10.5,10.5) E6(-9.5,10.5) E7(-8.5,10.5) E8(-7.5,10.5) E9(-6.5,10.5) E10(-5.5,10.5) E11(-4.5,10.5) E12(-3.5,10.5) E13(-2.5,10.5) E14(-1.5,10.5) E15(-0.5,10.5) E16(0.5,10.5) E17(1.5,10.5) E18(2.5,10.5) E19(3.5,10.5) E20(4.5,10.5) E21(5.5,10.5) E22(6.5,10.5) E23(7.5,10.5) E24(8.5,10.5) E25(9.5,10.5) E26(10.5,10.5) E27(11.5,10.5) E28(12.5,10.5) E29(13.5,10.5) E30(14.5,10.5) F1(-14.5,9.5) F2(-13.5,9.5) F3(-12.5,9.5) F4(-11.5,9.5) F5(-10.5,9.5) F6(-9.5,9.5) F7(-8.5,9.5) F8(-7.5,9.5) F9(-6.5,9.5) F10(-5.5,9.5) F11(-4.5,9.5) F12(-3.5,9.5) F13(-2.5,9.5) F14(-1.5,9.5) F15(-0.5,9.5) F16(0.5,9.5) F17(1.5,9.5) F18(2.5,9.5) F19(3.5,9.5) F20(4.5,9.5) F21(5.5,9.5) F22(6.5,9.5) F23(7.5,9.5) F24(8.5,9.5) F25(9.5,9.5) F26(10.5,9.5) F27(11.5,9.5) F28(12.5,9.5) F29(13.5,9.5) F30(14.5,9.5) G1(-14.5,8.5) G2(-13.5,8.5) G3(-12.5,8.5) G4(-11.5,8.5) G5(-10.5,8.5) G6(-9.5,8.5) G7(-8.5,8.5) G8(-7.5,8.5) G9(-6.5,8.5) G10(-5.5,8.5) G11(-4.5,8.5) G12(-3.5,8.5) G13(-2.5,8.5) G14(-1.5,8.5) G15(-0.5,8.5) G16(0.5,8.5) G17(1.5,8.5) G18(2.5,8.5) G19(3.5,8.5) G20(4.5,8.5) G21(5.5,8.5) G22(6.5,8.5) G23(7.5,8.5) G24(8.5,8.5) G25(9.5,8.5) G26(10.5,8.5) G27(11.5,8.5) G28(12.5,8.5) G29(13.5,8.5) G30(14.5,8.5) H1(-14.5,7.5) H2(-13.5,7.5) H3(-12.5,7.5) H4(-11.5,7.5) H5(-10.5,7.5) H6(-9.5,7.5) H7(-8.5,7.5) H8(-7.5,7.5) H9(-6.5,7.5) H10(-5.5,7.5) H11(-4.5,7.5) H12(-3.5,7.5) H13(-2.5,7.5) H14(-1.5,7.5) H15(-0.5,7.5) H16(0.5,7.5) H17(1.5,7.5) H18(2.5,7.5) H19(3.5,7.5) H20(4.5,7.5) H21(5.5,7.5) H22(6.5,7.5) H23(7.5,7.5) H24(8.5,7.5) H25(9.5,7.5) H26(10.5,7.5) H27(11.5,7.5) H28(12.5,7.5) H29(13.5,7.5) H30(14.5,7.5) J1(-14.5,6.5) J2(-13.5,6.5) J3(-12.5,6.5) J4(-11.5,6.5) J5(-10.5,6.5) J6(-9.5,6.5) J7(-8.5,6.5) J8(-7.5,6.5) J9(-6.5,6.5) J10(-5.5,6.5) J11(-4.5,6.5) J12(-3.5,6.5) J13(-2.5,6.5) J14(-1.5,6.5) J15(-0.5,6.5) J16(0.5,6.5) J17(1.5,6.5) J18(2.5,6.5) J19(3.5,6.5) J20(4.5,6.5) J21(5.5,6.5) J22(6.5,6.5) J23(7.5,6.5) J24(8.5,6.5) J25(9.5,6.5) J26(10.5,6.5) J27(11.5,6.5) J28(12.5,6.5) J29(13.5,6.5) J30(14.5,6.5) K1(-14.5,5.5) K2(-13.5,5.5) K3(-12.5,5.5) K4(-11.5,5.5) K5(-10.5,5.5) K6(-9.5,5.5) K7(-8.5,5.5) K8(-7.5,5.5) K9(-6.5,5.5) K10(-5.5,5.5) K11(-4.5,5.5) K12(-3.5,5.5) K13(-2.5,5.5) K14(-1.5,5.5) K15(-0.5,5.5) K16(0.5,5.5) K17(1.5,5.5) K18(2.5,5.5) K19(3.5,5.5) K20(4.5,5.5) K21(5.5,5.5) K22(6.5,5.5) K23(7.5,5.5) K24(8.5,5.5) K25(9.5,5.5) K26(10.5,5.5) K27(11.5,5.5) K28(12.5,5.5) K29(13.5,5.5) K30(14.5,5.5) L1(-14.5,4.5) L2(-13.5,4.5) L3(-12.5,4.5) L4(-11.5,4.5) L5(-10.5,4.5) L6(-9.5,4.5) L7(-8.5,4.5) L8(-7.5,4.5) L9(-6.5,4.5) L10(-5.5,4.5) L11(-4.5,4.5) L12(-3.5,4.5) L13(-2.5,4.5) L14(-1.5,4.5) L15(-0.5,4.5) L16(0.5,4.5) L17(1.5,4.5) L18(2.5,4.5) L19(3.5,4.5) L20(4.5,4.5) L21(5.5,4.5) L22(6.5,4.5) L23(7.5,4.5) L24(8.5,4.5) L25(9.5,4.5) L26(10.5,4.5) L27(11.5,4.5) L28(12.5,4.5) L29(13.5,4.5) L30(14.5,4.5) M1(-14.5,3.5) M2(-13.5,3.5) M3(-12.5,3.5) M4(-11.5,3.5) M5(-10.5,3.5) M6(-9.5,3.5) M7(-8.5,3.5) M8(-7.5,3.5) M9(-6.5,3.5) M10(-5.5,3.5) M11(-4.5,3.5) M12(-3.5,3.5) M13(-2.5,3.5) M14(-1.5,3.5) M15(-0.5,3.5) M16(0.5,3.5) M17(1.5,3.5) M18(2.5,3.5) M19(3.5,3.5) M20(4.5,3.5) M21(5.5,3.5) M22(6.5,3.5) M23(7.5,3.5) M24(8.5,3.5) M25(9.5,3.5) M26(10.5,3.5) M27(11.5,3.5) M28(12.5,3.5) M29(13.5,3.5) M30(14.5,3.5) N1(-14.5,2.5) N2(-13.5,2.5) N3(-12.5,2.5) N4(-11.5,2.5) N5(-10.5,2.5) N6(-9.5,2.5) N7(-8.5,2.5) N8(-7.5,2.5) N9(-6.5,2.5) N10(-5.5,2.5) N11(-4.5,2.5) N12(-3.5,2.5) N13(-2.5,2.5) N14(-1.5,2.5) N15(-0.5,2.5) N16(0.5,2.5) N17(1.5,2.5) N18(2.5,2.5) N19(3.5,2.5) N20(4.5,2.5) N21(5.5,2.5) N22(6.5,2.5) N23(7.5,2.5) N24(8.5,2.5) N25(9.5,2.5) N26(10.5,2.5) N27(11.5,2.5) N28(12.5,2.5) N29(13.5,2.5) N30(14.5,2.5) P1(-14.5,1.5) P2(-13.5,1.5) P3(-12.5,1.5) P4(-11.5,1.5) P5(-10.5,1.5) P6(-9.5,1.5) P7(-8.5,1.5) P8(-7.5,1.5) P9(-6.5,1.5) P10(-5.5,1.5) P11(-4.5,1.5) P12(-3.5,1.5) P13(-2.5,1.5) P14(-1.5,1.5) P15(-0.5,1.5) P16(0.5,1.5) P17(1.5,1.5) P18(2.5,1.5) P19(3.5,1.5) P20(4.5,1.5) P21(5.5,1.5) P22(6.5,1.5) P23(7.5,1.5) P24(8.5,1.5) P25(9.5,1.5) P26(10.5,1.5) P27(11.5,1.5) P28(12.5,1.5) P29(13.5,1.5) P30(14.5,1.5) R1(-14.5,0.5) R2(-13.5,0.5) R3(-12.5,0.5) R4(-11.5,0.5) R5(-10.5,0.5) R6(-9.5,0.5) R7(-8.5,0.5) R8(-7.5,0.5) R9(-6.5,0.5) R10(-5.5,0.5) R11(-4.5,0.5) R12(-3.5,0.5) R13(-2.5,0.5) R14(-1.5,0.5) R15(-0.5,0.5) R16(0.5,0.5) R17(1.5,0.5) R18(2.5,0.5) R19(3.5,0.5) R20(4.5,0.5) R21(5.5,0.5) R22(6.5,0.5) R23(7.5,0.5) R24(8.5,0.5) R25(9.5,0.5) R26(10.5,0.5) R27(11.5,0.5) R28(12.5,0.5) R29(13.5,0.5) R30(14.5,0.5) T1(-14.5,-0.5) T2(-13.5,-0.5) T3(-12.5,-0.5) T4(-11.5,-0.5) T5(-10.5,-0.5) T6(-9.5,-0.5) T7(-8.5,-0.5) T8(-7.5,-0.5) T9(-6.5,-0.5) T10(-5.5,-0.5) T11(-4.5,-0.5) T12(-3.5,-0.5) T13(-2.5,-0.5) T14(-1.5,-0.5) T15(-0.5,-0.5) T16(0.5,-0.5) T17(1.5,-0.5) T18(2.5,-0.5) T19(3.5,-0.5) T20(4.5,-0.5) T21(5.5,-0.5) T22(6.5,-0.5) T23(7.5,-0.5) T24(8.5,-0.5) T25(9.5,-0.5) T26(10.5,-0.5) T27(11.5,-0.5) T28(12.5,-0.5) T29(13.5,-0.5) T30(14.5,-0.5) U1(-14.5,-1.5) U2(-13.5,-1.5) U3(-12.5,-1.5) U4(-11.5,-1.5) U5(-10.5,-1.5) U6(-9.5,-1.5) U7(-8.5,-1.5) U8(-7.5,-1.5) U9(-6.5,-1.5) U10(-5.5,-1.5) U11(-4.5,-1.5) U12(-3.5,-1.5) U13(-2.5,-1.5) U14(-1.5,-1.5) U15(-0.5,-1.5) U16(0.5,-1.5) U17(1.5,-1.5) U18(2.5,-1.5) U19(3.5,-1.5) U20(4.5,-1.5) U21(5.5,-1.5) U22(6.5,-1.5) U23(7.5,-1.5) U24(8.5,-1.5) U25(9.5,-1.5) U26(10.5,-1.5) U27(11.5,-1.5) U28(12.5,-1.5) U29(13.5,-1.5) U30(14.5,-1.5) V1(-14.5,-2.5) V2(-13.5,-2.5) V3(-12.5,-2.5) V4(-11.5,-2.5) V5(-10.5,-2.5) V6(-9.5,-2.5) V7(-8.5,-2.5) V8(-7.5,-2.5) V9(-6.5,-2.5) V10(-5.5,-2.5) V11(-4.5,-2.5) V12(-3.5,-2.5) V13(-2.5,-2.5) V14(-1.5,-2.5) V15(-0.5,-2.5) V16(0.5,-2.5) V17(1.5,-2.5) V18(2.5,-2.5) V19(3.5,-2.5) V20(4.5,-2.5) V21(5.5,-2.5) V22(6.5,-2.5) V23(7.5,-2.5) V24(8.5,-2.5) V25(9.5,-2.5) V26(10.5,-2.5) V27(11.5,-2.5) V28(12.5,-2.5) V29(13.5,-2.5) V30(14.5,-2.5) W1(-14.5,-3.5) W2(-13.5,-3.5) W3(-12.5,-3.5) W4(-11.5,-3.5) W5(-10.5,-3.5) W6(-9.5,-3.5) W7(-8.5,-3.5) W8(-7.5,-3.5) W9(-6.5,-3.5) W10(-5.5,-3.5) W11(-4.5,-3.5) W12(-3.5,-3.5) W13(-2.5,-3.5) W14(-1.5,-3.5) W15(-0.5,-3.5) W16(0.5,-3.5) W17(1.5,-3.5) W18(2.5,-3.5) W19(3.5,-3.5) W20(4.5,-3.5) W21(5.5,-3.5) W22(6.5,-3.5) W23(7.5,-3.5) W24(8.5,-3.5) W25(9.5,-3.5) W26(10.5,-3.5) W27(11.5,-3.5) W28(12.5,-3.5) W29(13.5,-3.5) W30(14.5,-3.5) Y1(-14.5,-4.5) Y2(-13.5,-4.5) Y3(-12.5,-4.5) Y4(-11.5,-4.5) Y5(-10.5,-4.5) Y6(-9.5,-4.5) Y7(-8.5,-4.5) Y8(-7.5,-4.5) Y9(-6.5,-4.5) Y10(-5.5,-4.5) Y11(-4.5,-4.5) Y12(-3.5,-4.5) Y13(-2.5,-4.5) Y14(-1.5,-4.5) Y15(-0.5,-4.5) Y16(0.5,-4.5) Y17(1.5,-4.5) Y18(2.5,-4.5) Y19(3.5,-4.5) Y20(4.5,-4.5) Y21(5.5,-4.5) Y22(6.5,-4.5) Y23(7.5,-4.5) Y24(8.5,-4.5) Y25(9.5,-4.5) Y26(10.5,-4.5) Y27(11.5,-4.5) Y28(12.5,-4.5) Y29(13.5,-4.5) Y30(14.5,-4.5)
  silkscreen extent -16.27,-15.5 15.5,15.5, body extent -15.5,-15.5 15.5,15.5, height 2.88
FC0H224ZFTBR24 [mm] "Super-CAP Aluminum Electrolytic Capacitor, Body 10,80x10,80x11,00mm, IPC High Density"
  rect 4.6x2.5 smd: 1(4.8,0) 2(-4.8,0)
  silkscreen extent -5.5,-5.5 5.5,5.5, body extent -6.1,-5.5 6.1,5.5, height 11
FC-135R/FC-135 [mm] "Crystal Unit,32,768kHz, 2-Leads, Body 3,20x1,50mm, IPC Medium Density"
  rect 1x1.8 smd: 1(-1.25,0) 2(1.25,0)
  silkscreen extent -0.07,-0.8 0.08,0.8, body extent -1.65,-0.8 1.65,0.8, height 0.8
FCSL110R005FERCT-ND [mm] "Wide 4320 (11050 Metric), 2043"
  rect 1.05x11.2 smd: 1(-2.3,0) 2(2.3,0)
  silkscreen extent -1.4,-5.5 1.4,5.5, body extent -2.8,-5.6 2.8,5.6, height 0.8
"FER 0603/1608" [mm] "Chip Ferrite, 2-Leads, Body 1.60x0.80mm, IPC Medium Density"
  rect 0.9x1 smd: 1(-0.675,0) 2(0.675,0)
  silkscreen extent -1.4,-0.7 1.4,0.7, body extent -0.8,-0.41 0.8,0.41, height 0.82
"FER 0805/2012" [mm] "Chip Ferrite, 2-Leads, Body 2.00x1.20mm, IPC Medium Density"
  rect 1.3x1.4 smd: 1(-0.8,0) 2(0.8,0)
  silkscreen extent -1.7,-0.9 1.7,0.9, body extent -1,-0.64 1,0.64, height 1.26
Fiducials [mm]
  round 1 smd paste-10 mask+0.5: 0(0,0)
  round 1 smd far side paste-10 mask+0.5: 0(0,0)
  Keep-Out Layer circle w0.01: c0,0 r1
FPF2895C-D [mm] "BGA, 24-Leads, Body 1,67x2,60mmx0,61mm, Pitch 0,40mm"
  round 0.23 smd mask+0.035: A1(-0.6,1) A2(-0.2,1) A3(0.2,1) A4(0.6,1) B1(-0.6,0.6) B2(-0.2,0.6) B3(0.2,0.6) B4(0.6,0.6) C1(-0.6,0.2) C2(-0.2,0.2) C3(0.2,0.2) C4(0.6,0.2) D1(-0.6,-0.2) D2(-0.2,-0.2) D3(0.2,-0.2) D4(0.6,-0.2) E1(-0.6,-0.6) E2(-0.2,-0.6) E3(0.2,-0.6) E4(0.6,-0.6) F1(-0.6,-1) F2(-0.2,-1) F3(0.2,-1) F4(0.6,-1)
  silkscreen extent -0.99,1.36 -0.89,1.45, body extent -0.83,-1.3 0.83,1.3, height 0.61
FT4232HL [mm] "LQFP-64 Package Dimensions"
  rect 1.1x0.22 smd: 1(-5.55,3.75) 2(-5.55,3.25) 3(-5.55,2.75) 4(-5.55,2.25) 5(-5.55,1.75) 6(-5.55,1.25) 7(-5.55,0.75) 8(-5.55,0.25) 9(-5.55,-0.25) 10(-5.55,-0.75) 11(-5.55,-1.25) 12(-5.55,-1.75) 13(-5.55,-2.25) 14(-5.55,-2.75) 15(-5.55,-3.25) 16(-5.55,-3.75) 33(5.55,-3.75) 34(5.55,-3.25) 35(5.55,-2.75) 36(5.55,-2.25) 37(5.55,-1.75) 38(5.55,-1.25) 39(5.55,-0.75) 40(5.55,-0.25) 41(5.55,0.25) 42(5.55,0.75) 43(5.55,1.25) 44(5.55,1.75) 45(5.55,2.25) 46(5.55,2.75) 47(5.55,3.25) 48(5.55,3.75)
  rect 0.22x1.1 smd: 17(-3.75,-5.55) 18(-3.25,-5.55) 19(-2.75,-5.55) 20(-2.25,-5.55) 21(-1.75,-5.55) 22(-1.25,-5.55) 23(-0.75,-5.55) 24(-0.25,-5.55) 25(0.25,-5.55) 26(0.75,-5.55) 27(1.25,-5.55) 28(1.75,-5.55) 29(2.25,-5.55) 30(2.75,-5.55) 31(3.25,-5.55) 32(3.75,-5.55) 49(3.75,5.55) 50(3.25,5.55) 51(2.75,5.55) 52(2.25,5.55) 53(1.75,5.55) 54(1.25,5.55) 55(0.75,5.55) 56(0.25,5.55) 57(-0.25,5.55) 58(-0.75,5.55) 59(-1.25,5.55) 60(-1.75,5.55) 61(-2.25,5.55) 62(-2.75,5.55) 63(-3.25,5.55) 64(-3.75,5.55)
  silkscreen extent -5.67,-4.68 4.68,4.67, body extent -6,-6 6,6, height 1.6
HDR1X2 [mm] "Connector; Header; 2 Position"
  rect 1.5x1.5 hole 0.9: 1(0,0)
  round 1.5 hole 0.9: 2(2.54,0)
  silkscreen extent -1.27,-1.27 3.81,1.27
HDR1X3 [mm] "Connector; Header; 3 Position"
  rect 1.5x1.5 hole 0.9: 1(0,0)
  round 1.5 hole 0.9: 2(2.54,0) 3(5.08,0)
  silkscreen extent -1.27,-1.27 6.35,1.27
HDR1X4 [mm] "Connector; Header; 4 Position"
  rect 1.5x1.5 hole 0.9: 1(0,0)
  round 1.5 hole 0.9: 2(2.54,0) 3(5.08,0) 4(7.62,0)
  silkscreen extent -1.27,-1.27 8.89,1.27
HDR2X7 [mm] "Connector; Header; 7x2 Position"
  rect 1.5x1.5 hole 0.9: 1(0,0)
  round 1.5 hole 0.9: 2(0,2.54) 3(2.54,0) 4(2.54,2.54) 5(5.08,0) 6(5.08,2.54) 7(7.62,0) 8(7.62,2.54) 9(10.16,0) 10(10.16,2.54) 11(12.7,0) 12(12.7,2.54) 13(15.24,0) 14(15.24,2.54)
  silkscreen extent -1.27,-1.27 16.51,3.81
INA226 [mm] "TSSOP, 10-Leads, Body 3,00x3,00mm, Pitch 0,50mm, IPC Medium Density"
  rect 1.45x0.3 smd: 1(-2.2,1) 2(-2.2,0.5) 3(-2.2,0) 4(-2.2,-0.5) 5(-2.2,-1) 6(2.2,-1) 7(2.2,-0.5) 8(2.2,0) 9(2.2,0.5) 10(2.2,1)
  silkscreen extent -2.32,-1.55 1.15,1.82, body extent -2.45,-1.55 2.45,1.55, height 1.1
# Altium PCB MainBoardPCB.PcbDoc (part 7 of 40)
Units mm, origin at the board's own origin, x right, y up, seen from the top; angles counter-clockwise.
Board outline 258.95 x 308.86 mm, 16 copper layers (L1, L2 (GND), L3 (Sign), L4 (GND), L5 (Sign), L6 (PWR/GND), L7(12V+Other), L8 (Plane_GND), L9 (PWR/GND), L10 (3V3+Other), L11 (PWR/GND), L12 (Sign), L13 (GND), L14 (Sign), L15 (GND), L16), stack 2.503 mm thick; 2578 components, 1867 nets, 8817 pads, 8021 vias.
Unrouted connection lines stored in the file: 25.

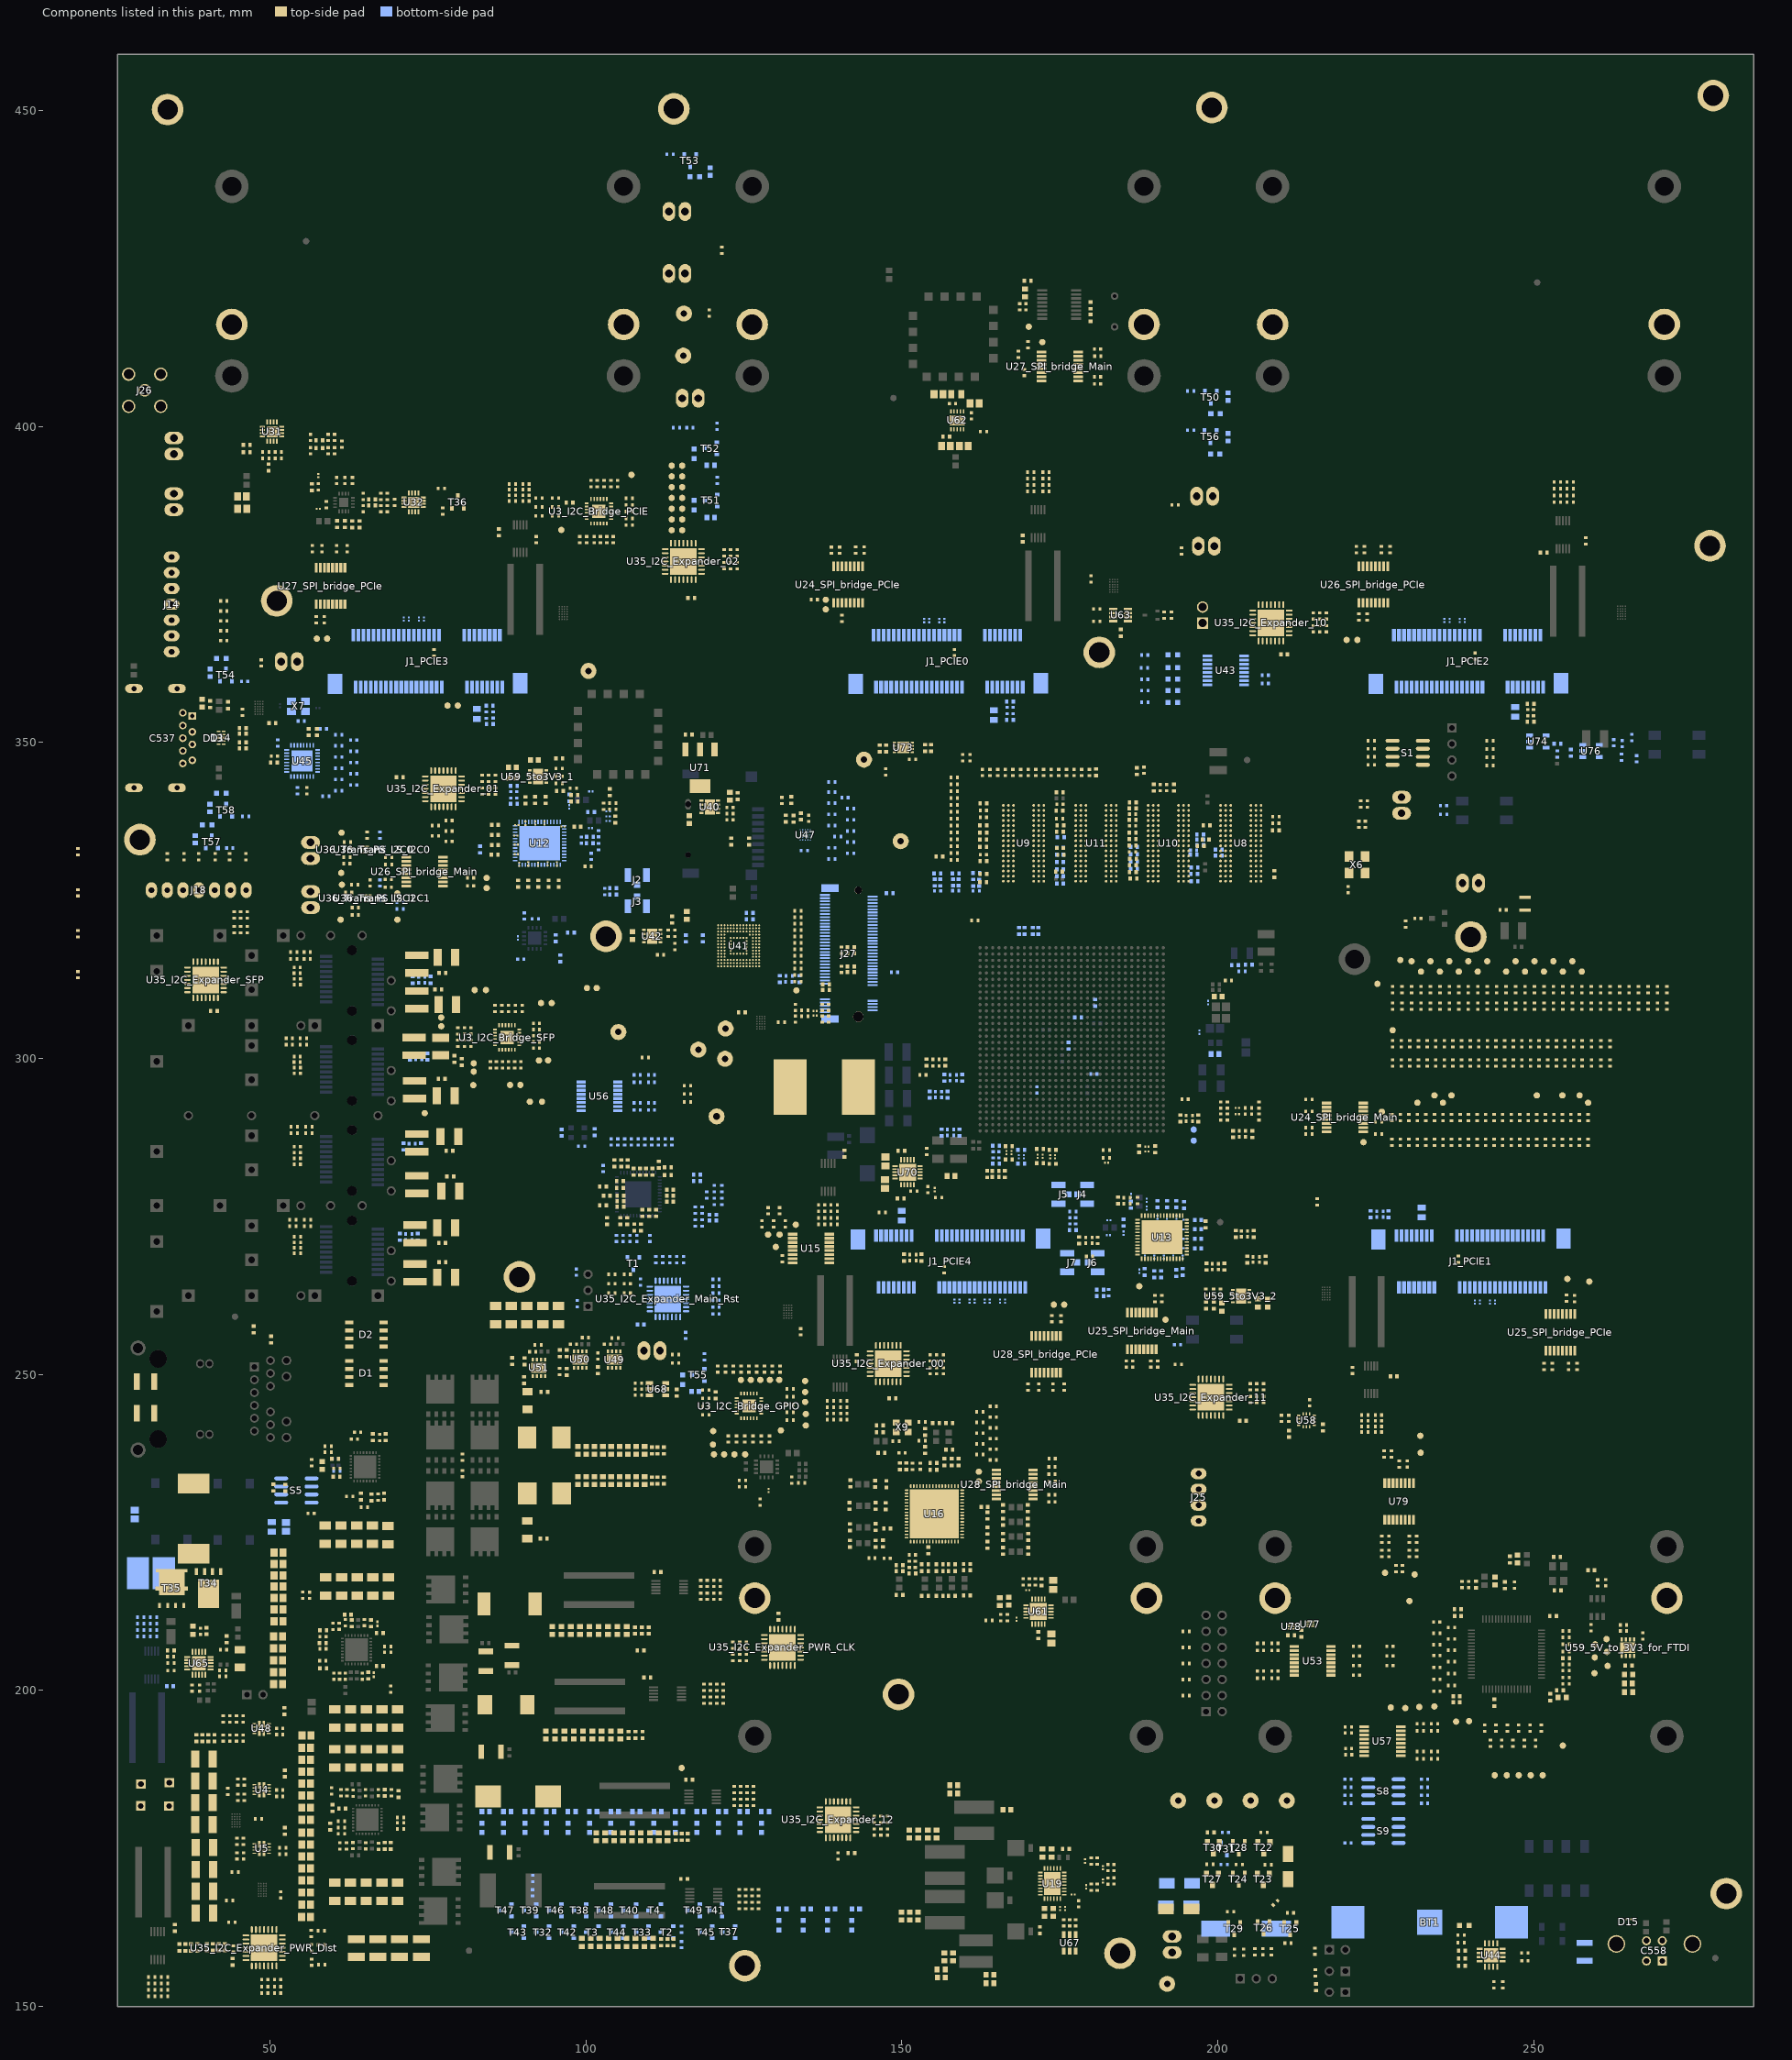
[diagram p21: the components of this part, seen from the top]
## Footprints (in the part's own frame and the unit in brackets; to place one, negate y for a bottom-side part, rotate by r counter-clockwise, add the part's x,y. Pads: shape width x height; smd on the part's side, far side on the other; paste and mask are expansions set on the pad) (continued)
IP4856CX25/C [mm] "BGA, 25-Leads, Body 2,05x2,05mmx0,55mm, Pitch 0,40mm"
  round 0.2 smd: A1(-0.8,0.8) A2(-0.4,0.8) A3(0,0.8) A4(0.4,0.8) A5(0.8,0.8) B1(-0.8,0.4) B2(-0.4,0.4) B3(0,0.4) B4(0.4,0.4) B5(0.8,0.4) C1(-0.8,0) C2(-0.4,0) C3(0,0) C4(0.4,0) C5(0.8,0) D1(-0.8,-0.4) D2(-0.4,-0.4) D3(0,-0.4) D4(0.4,-0.4) D5(0.8,-0.4) E1(-0.8,-0.8) E2(-0.4,-0.8) E3(0,-0.8) E4(0.4,-0.8) E5(0.8,-0.8)
  silkscreen extent -1.18,1.08 -1.08,1.18, body extent -1.02,-1.03 1.03,1.03, height 0.55
IRLML6401PbF [mm] "SOT23, 3-Leads, Body 2,92x2,37mm, Pitch 0,95mm, IPC High Density"
  rect 0.975x0.802 smd: 1(-0.885,0.95) 2(-0.885,-0.95) 3(0.885,0)
  silkscreen extent -1.01,-1.5 0.7,2.03, body extent -1.32,-1.52 1.32,1.52, height 1.12
ISM330DHCXL [mm] "LGA-14L 2.5x3x0.86 mm"
  rect 0.5x0.25 smd: 1(-1.25,0.75) 2(-1.25,0.25) 3(-1.25,-0.25) 4(-1.25,-0.75) 8(1.25,-0.75) 9(1.25,-0.25) 10(1.25,0.25) 11(1.25,0.75)
  rect 0.25x0.5 smd: 5(-0.5,-1) 6(0,-1) 7(0.5,-1) 12(0.5,1) 13(0,1) 14(-0.5,1)
  silkscreen extent -2.47,-1.45 1.7,1.45, body extent -1.6,-1.35 1.6,1.35, height 0.86
"JST XH B4B-XH-A" [mm]
  oval 1.75x2.5 hole 0.9: 1(-3.75,0) 2(-1.25,0) 3(1.25,0) 4(3.75,0)
  silkscreen extent -6.2,-3.38 6.2,2.38, body extent -6.2,-3.37 6.2,2.38, height 7
"JST XH B7B-XH-A" [mm]
  oval 1.75x2.5 hole 0.9: 1(-7.5,0) 2(-5,0) 3(-2.5,0) 4(0,0) 5(2.5,0) 6(5,0) 7(7.5,0)
  silkscreen extent -9.95,-3.38 9.95,2.38, body extent -9.95,-3.37 9.95,2.38, height 7
"LED 0603/1608 GREEN" [mm] "Chip Diode, 2-Leads, Body 1.60x0.80mm, IPC Medium Density"
  rect 0.8x0.8 smd: 1(-0.75,0) 2(0.75,0)
  silkscreen extent -1.52,-0.7 1.52,0.7, body extent -0.8,-0.4 0.8,0.4, height 0.53
LM3880-Q1 [mm] "SOT23, 6-Leads, Body 2,90x2,80mm, Pitch 0,95mm, IPC High Density"
  rect 1.1x0.6 smd: 1(-1.3,0.95) 2(-1.3,0) 3(-1.3,-0.95) 4(1.3,-0.95) 5(1.3,0) 6(1.3,0.95)
  silkscreen extent -1.42,-1.55 0.5,1.92, body extent -1.5,-1.53 1.5,1.53, height 1.45
LMK05028 [mm] "QFN, 64-Leads, Body 9,15x9,15mm, Pitch 0,50mm, Thermal Pad 7,75x7,75mm, IPC Medium Density"
  oval 0.6x0.24 smd: 1(-4.4,3.75) 2(-4.4,3.25) 3(-4.4,2.75) 4(-4.4,2.25) 5(-4.4,1.75) 6(-4.4,1.25) 7(-4.4,0.75) 8(-4.4,0.25) 9(-4.4,-0.25) 10(-4.4,-0.75) 11(-4.4,-1.25) 12(-4.4,-1.75) 13(-4.4,-2.25) 14(-4.4,-2.75) 15(-4.4,-3.25) 16(-4.4,-3.75) 33(4.4,-3.75) 34(4.4,-3.25) 35(4.4,-2.75) 36(4.4,-2.25) 37(4.4,-1.75) 38(4.4,-1.25) 39(4.4,-0.75) 40(4.4,-0.25) 41(4.4,0.25) 42(4.4,0.75) 43(4.4,1.25) 44(4.4,1.75) 45(4.4,2.25) 46(4.4,2.75) 47(4.4,3.25) 48(4.4,3.75)
  oval 0.24x0.6 smd: 17(-3.75,-4.4) 18(-3.25,-4.4) 19(-2.75,-4.4) 20(-2.25,-4.4) 21(-1.75,-4.4) 22(-1.25,-4.4) 23(-0.75,-4.4) 24(-0.25,-4.4) 25(0.25,-4.4) 26(0.75,-4.4) 27(1.25,-4.4) 28(1.75,-4.4) 29(2.25,-4.4) 30(2.75,-4.4) 31(3.25,-4.4) 32(3.75,-4.4) 49(3.75,4.4) 50(3.25,4.4) 51(2.75,4.4) 52(2.25,4.4) 53(1.75,4.4) 54(1.25,4.4) 55(0.75,4.4) 56(0.25,4.4) 57(-0.25,4.4) 58(-0.75,4.4) 59(-1.25,4.4) 60(-1.75,4.4) 61(-2.25,4.4) 62(-2.75,4.4) 63(-3.25,4.4) 64(-3.75,4.4)
  rect 7.75x7.75 smd paste-300: 65(0,0)
  silkscreen extent -5.32,-4.55 4.55,4.55, body extent -4.65,-4.65 4.65,4.65, height 1
LT3042 [mm] "10-Lead Plastic DFN (3mm × 3mm)"
  rect 0.7x0.25 smd: 1(-1.425,1) 2(-1.425,0.5) 3(-1.425,0) 4(-1.425,-0.5) 5(-1.425,-1) 6(1.425,-1) 7(1.425,-0.5) 8(1.425,0) 9(1.425,0.5) 10(1.425,1)
  rect 1.65x2.38 smd: 11(0,0)
  silkscreen extent -2.15,-1.7 1.7,1.75, body extent -1.55,-1.55 1.55,1.55, height 0.75
LT3504 [mm] "UFD Package  28-Lead Plastic QFN (4mm × 5mm)  (Reference LTC DWG # 05-08-1712 Rev B)"
  rect 0.7x0.25 smd: 1(-1.9,1.75) 2(-1.9,1.25) 3(-1.9,0.75) 4(-1.9,0.25) 5(-1.9,-0.25) 6(-1.9,-0.75) 7(-1.9,-1.25) 8(-1.9,-1.75) 15(1.9,-1.75) 16(1.9,-1.25) 17(1.9,-0.75) 18(1.9,-0.25) 19(1.9,0.25) 20(1.9,0.75) 21(1.9,1.25) 22(1.9,1.75)
  rect 0.25x0.7 smd: 9(-1.25,-2.4) 10(-0.75,-2.4) 11(-0.25,-2.4) 12(0.25,-2.4) 13(0.75,-2.4) 14(1.25,-2.4) 23(1.25,2.4) 24(0.75,2.4) 25(0.25,2.4) 26(-0.25,2.4) 27(-0.75,2.4) 28(-1.25,2.4)
  rect 2.65x3.65 smd: 29(0,0)
  silkscreen extent -2.82,-2.55 2.05,2.55, body extent -2.05,-2.55 2.05,2.55, height 0.8
LTC6952 [mm] "PQFN, 52-Leads, Body 7,00x8,00mm, Pitch 0,50mm, Thermal Pad 5,70x6,70mm, IPC High Density"
  rect 0.7x0.25 smd: 1(-3.4,3.25) 2(-3.4,2.75) 3(-3.4,2.25) 4(-3.4,1.75) 5(-3.4,1.25) 6(-3.4,0.75) 7(-3.4,0.25) 8(-3.4,-0.25) 9(-3.4,-0.75) 10(-3.4,-1.25) 11(-3.4,-1.75) 12(-3.4,-2.25) 13(-3.4,-2.75) 14(-3.4,-3.25) 27(3.4,-3.25) 28(3.4,-2.75) 29(3.4,-2.25) 30(3.4,-1.75) 31(3.4,-1.25) 32(3.4,-0.75) 33(3.4,-0.25) 34(3.4,0.25) 35(3.4,0.75) 36(3.4,1.25) 37(3.4,1.75) 38(3.4,2.25) 39(3.4,2.75) 40(3.4,3.25)
  rect 0.25x0.7 smd: 15(-2.75,-3.9) 16(-2.25,-3.9) 17(-1.75,-3.9) 18(-1.25,-3.9) 19(-0.75,-3.9) 20(-0.25,-3.9) 21(0.25,-3.9) 22(0.75,-3.9) 23(1.25,-3.9) 24(1.75,-3.9) 25(2.25,-3.9) 26(2.75,-3.9) 41(2.75,3.9) 42(2.25,3.9) 43(1.75,3.9) 44(1.25,3.9) 45(0.75,3.9) 46(0.25,3.9) 47(-0.25,3.9) 48(-0.75,3.9) 49(-1.25,3.9) 50(-1.75,3.9) 51(-2.25,3.9) 52(-2.75,3.9)
  rect 5.41x6.45 smd: 53(0,0)
  silkscreen extent -4.32,-4.05 3.55,4.05, body extent -3.55,-4.05 3.55,4.05, height 0.8
"M.2 KEY M - NVMe" [mm]
  rect 0.3x1.55 smd: 1(-9.25,3.825) 2(-9,-3.725) 3(-8.75,3.825) 4(-8.5,-3.725) 5(-8.25,3.825) 6(-8,-3.725) 7(-7.75,3.825) 8(-7.5,-3.725) 9(-7.25,3.825) 10(-7,-3.725) 11(-6.75,3.825) 12(-6.5,-3.725) 13(-6.25,3.825) 14(-6,-3.725) 15(-5.75,3.825) 16(-5.5,-3.725) 17(-5.25,3.825) 18(-5,-3.725) 19(-4.75,3.825) 20(-4.5,-3.725) 21(-4.25,3.825) 22(-4,-3.725) 23(-3.75,3.825) 24(-3.5,-3.725) 25(-3.25,3.825) 26(-3,-3.725) 27(-2.75,3.825) 28(-2.5,-3.725) 29(-2.25,3.825) 30(-2,-3.725) 31(-1.75,3.825) 32(-1.5,-3.725) 33(-1.25,3.825) 34(-1,-3.725) 35(-0.75,3.825) 36(-0.5,-3.725) 37(-0.25,3.825) 38(0,-3.725) 39(0.25,3.825) 40(0.5,-3.725) 41(0.75,3.825) 42(1,-3.725) 43(1.25,3.825) 44(1.5,-3.725) 45(1.75,3.825) 46(2,-3.725) 47(2.25,3.825) 48(2.5,-3.725) 49(2.75,3.825) 50(3,-3.725) 51(3.25,3.825) 52(3.5,-3.725) 53(3.75,3.825) 54(4,-3.725) 55(4.25,3.825) 56(4.5,-3.725) 57(4.75,3.825) 58(5,-3.725) 59(7.25,3.825) 60(7.5,-3.725) 61(7.75,3.825) 62(8,-3.725) 63(8.25,3.825) 64(8.5,-3.725) 65(8.75,3.825) 66(9,-3.725) 67(9.25,3.825)
  rect 1.2x2.75 smd: M(-10.35,3.05) M(10.35,3.05)
  round 1.15 hole 1.15: M(-10,-1.45)
  round 1.65 hole 1.65: M(10,-1.45)
  silkscreen extent -11.75,-5.7 11.75,5.45, body extent -10.95,-4.3 10.95,4.4, height 4.09
"MAX3051EKA+T SOT23" [mm] "SOT-23, 8L BODY"
  rect 1.3x0.42 smd: 1(-1.175,0.975) 2(-1.175,0.325) 3(-1.175,-0.325) 4(-1.175,-0.975) 5(1.175,-0.975) 6(1.175,-0.325) 7(1.175,0.325) 8(1.175,0.975)
  silkscreen extent -1.3,-1.5 0.5,1.86, body extent -1.39,-1.5 1.39,1.5, height 1.45
MAX16025TE+T [mm] "Thin Quad Flatpack, No Leads; T1644-4;  4.10mm(L) x 4.10mm(W) x 0.80mm(H)"
  rect 0.95x0.35 smd: 1(-1.84,0.975) 2(-1.84,0.325) 3(-1.84,-0.325) 4(-1.84,-0.975) 9(1.84,-0.975) 10(1.84,-0.325) 11(1.84,0.325) 12(1.84,0.975)
  rect 0.35x0.95 smd: 5(-0.975,-1.84) 6(-0.325,-1.84) 7(0.325,-1.84) 8(0.975,-1.84) 13(0.975,1.84) 14(0.325,1.84) 15(-0.325,1.84) 16(-0.975,1.84)
  rect 2.23x2.23 smd: 17(0,0)
  silkscreen extent -2.97,-2.2 2.2,2.2, body extent -2.05,-2.05 2.05,2.05, height 0.8
MAX17557 [mm] "20 TQFN, Maximintegrated 21-0139, Land Pattern Number 90-0037"
  rect 0.95x0.3 smd: 1(-1.84,1) 2(-1.84,0.5) 3(-1.84,0) 4(-1.84,-0.5) 5(-1.84,-1) 11(1.84,-1) 12(1.84,-0.5) 13(1.84,0) 14(1.84,0.5) 15(1.84,1)
  rect 0.3x0.95 smd: 6(-1,-1.84) 7(-0.5,-1.84) 8(0,-1.84) 9(0.5,-1.84) 10(1,-1.84) 16(1,1.84) 17(0.5,1.84) 18(0,1.84) 19(-0.5,1.84) 20(-1,1.84)
  rect 2.23x2.23 smd: 21(0,0)
  silkscreen extent -2.82,-2.05 2.05,2.05, body extent -2.05,-2.05 2.05,2.05, height 1
MCP1727T-ADJE/MF [mm] "SON, 8-Leads, Body 3.00x3.00mm, Pitch 0.65mm, Thermal Pad 2.40x1.60mm, IPC High Density"
  rect 0.6x0.35 smd: 1(-1.3,0.975) 2(-1.3,0.325) 3(-1.3,-0.325) 4(-1.3,-0.975) 5(1.3,-0.975) 6(1.3,-0.325) 7(1.3,0.325) 8(1.3,0.975)
  rect 1.6x2.4 smd: 9(0,0)
  silkscreen extent -2.1,-1.65 1.65,1.7, body extent -1.5,-1.5 1.5,1.5, height 1
MeasureTP#1 [mm]
  round 1 smd paste-0.5: 1(0,0)
  silkscreen extent -0.6,-0.6 0.6,0.6
MeasureTP#2 [mm]
  round 1 smd: 1(0,0)
  silkscreen extent -0.6,-0.6 0.6,0.6
MGV0605 [mm] "Precision Wire Wound Inductor, 2-Leads, Body 7,30x6,70mm, IPC High Density"
  rect 2.95x3.5 smd: 1(-2.725,0) 2(2.725,0)
  silkscreen extent -3.9,-3.55 3.9,3.55, body extent -3.75,-3.35 3.75,3.35, height 5.5
"MGV1004 Series" [mm] "Precision Wire Wound Inductor, 2-Leads, Body 11,00x10,00mm, IPC High Density"
  rect 4.1x3.5 smd: 1(-4.75,0) 2(4.75,0)
  silkscreen extent -5.75,-5.15 5.75,5.15, body extent -5.6,-5 5.6,5, height 4.1
MH_5_3.2_SUB_VIA [mm] "M3_D5"
  round 5 hole 3.2: 1(0,0)
"MOLEX KK 0022272021" [mm]
  oval 2x3 hole 1.2: 1(-1.27,0) 2(1.27,0)
  silkscreen extent -2.54,-2.79 2.54,2.79, body extent -2.54,-2.9 2.54,2.9, height 11.7
MT40A512M16JY [mm] "BGA, 96-Leads, Body 8,05x14,05mmx1,10mm, Pitch 0,80mm"
  round 0.42 smd: A1(-3.2,6) A2(-2.4,6) A3(-1.6,6) A4(1.6,6) A5(2.4,6) A6(3.2,6) B1(-3.2,5.2) B2(-2.4,5.2) B3(-1.6,5.2) B4(1.6,5.2) B5(2.4,5.2) B6(3.2,5.2) C1(-3.2,4.4) C2(-2.4,4.4) C3(-1.6,4.4) C4(1.6,4.4) C5(2.4,4.4) C6(3.2,4.4) D1(-3.2,3.6) D2(-2.4,3.6) D3(-1.6,3.6) D4(1.6,3.6) D5(2.4,3.6) D6(3.2,3.6) E1(-3.2,2.8) E2(-2.4,2.8) E3(-1.6,2.8) E4(1.6,2.8) E5(2.4,2.8) E6(3.2,2.8) F1(-3.2,2) F2(-2.4,2) F3(-1.6,2) F4(1.6,2) F5(2.4,2) F6(3.2,2) G1(-3.2,1.2) G2(-2.4,1.2) G3(-1.6,1.2) G4(1.6,1.2) G5(2.4,1.2) G6(3.2,1.2) H1(-3.2,0.4) H2(-2.4,0.4) H3(-1.6,0.4) H4(1.6,0.4) H5(2.4,0.4) H6(3.2,0.4) J1(-3.2,-0.4) J2(-2.4,-0.4) J3(-1.6,-0.4) J4(1.6,-0.4) J5(2.4,-0.4) J6(3.2,-0.4) K1(-3.2,-1.2) K2(-2.4,-1.2) K3(-1.6,-1.2) K4(1.6,-1.2) K5(2.4,-1.2) K6(3.2,-1.2) L1(-3.2,-2) L2(-2.4,-2) L3(-1.6,-2) L4(1.6,-2) L5(2.4,-2) L6(3.2,-2) M1(-3.2,-2.8) M2(-2.4,-2.8) M3(-1.6,-2.8) M4(1.6,-2.8) M5(2.4,-2.8) M6(3.2,-2.8) N1(-3.2,-3.6) N2(-2.4,-3.6) N3(-1.6,-3.6) N4(1.6,-3.6) N5(2.4,-3.6) N6(3.2,-3.6) P1(-3.2,-4.4) P2(-2.4,-4.4) P3(-1.6,-4.4) P4(1.6,-4.4) P5(2.4,-4.4) P6(3.2,-4.4) R1(-3.2,-5.2) R2(-2.4,-5.2) R3(-1.6,-5.2) R4(1.6,-5.2) R5(2.4,-5.2) R6(3.2,-5.2) T1(-3.2,-6) T2(-2.4,-6) T3(-1.6,-6) T4(1.6,-6) T5(2.4,-6) T6(3.2,-6)
  silkscreen extent -4.8,-7.03 4.02,7.02, body extent -4.09,-7.15 3.96,6.9, height 1.1
"MTFC8GAKAJCN-4M IT TR" [mm] "BGA, 156-Leads, Body 11,50x13,00mmx1,00mm, Pitch 0,50mm"
  round 0.3 smd mask+0.05: A1(-3.25,3.25) A2(-2.75,3.25) A3(-2.25,3.25) A4(-1.75,3.25) A5(-1.25,3.25) A6(-0.75,3.25) A7(-0.25,3.25) A8(0.25,3.25) A9(0.75,3.25) A10(1.25,3.25) A11(1.75,3.25) A12(2.25,3.25) A13(2.75,3.25) A14(3.25,3.25) B1(-3.25,2.75) B2(-2.75,2.75) B3(-2.25,2.75) B4(-1.75,2.75) B5(-1.25,2.75) B6(-0.75,2.75) B7(-0.25,2.75) B8(0.25,2.75) B9(0.75,2.75) B10(1.25,2.75) B11(1.75,2.75) B12(2.25,2.75) B13(2.75,2.75) B14(3.25,2.75) C1(-3.25,2.25) C2(-2.75,2.25) C3(-2.25,2.25) C4(-1.75,2.25) C5(-1.25,2.25) C6(-0.75,2.25) C7(-0.25,2.25) C8(0.25,2.25) C9(0.75,2.25) C10(1.25,2.25) C11(1.75,2.25) C12(2.25,2.25) C13(2.75,2.25) C14(3.25,2.25) D1(-3.25,1.75) D2(-2.75,1.75) D3(-2.25,1.75) D4(-1.75,1.75) D12(2.25,1.75) D13(2.75,1.75) D14(3.25,1.75) E1(-3.25,1.25) E2(-2.75,1.25) E3(-2.25,1.25) E5(-1.25,1.25) E6(-0.75,1.25) E7(-0.25,1.25) E8(0.25,1.25) E9(0.75,1.25) E10(1.25,1.25) E12(2.25,1.25) E13(2.75,1.25) E14(3.25,1.25) F1(-3.25,0.75) F2(-2.75,0.75) F3(-2.25,0.75) F5(-1.25,0.75) F10(1.25,0.75) F12(2.25,0.75) F13(2.75,0.75) F14(3.25,0.75) G1(-3.25,0.25) G2(-2.75,0.25) G3(-2.25,0.25) G5(-1.25,0.25) G10(1.25,0.25) G12(2.25,0.25) G13(2.75,0.25) G14(3.25,0.25) H1(-3.25,-0.25) H2(-2.75,-0.25) H3(-2.25,-0.25) H5(-1.25,-0.25) H10(1.25,-0.25) H12(2.25,-0.25) H13(2.75,-0.25) H14(3.25,-0.25) J1(-3.25,-0.75) J2(-2.75,-0.75) J3(-2.25,-0.75) J5(-1.25,-0.75) J10(1.25,-0.75) J12(2.25,-0.75) J13(2.75,-0.75) J14(3.25,-0.75) K1(-3.25,-1.25) K2(-2.75,-1.25) K3(-2.25,-1.25) K5(-1.25,-1.25) K6(-0.75,-1.25) K7(-0.25,-1.25) K8(0.25,-1.25) K9(0.75,-1.25) K10(1.25,-1.25) K12(2.25,-1.25) K13(2.75,-1.25) K14(3.25,-1.25) L1(-3.25,-1.75) L2(-2.75,-1.75) L3(-2.25,-1.75) L12(2.25,-1.75) L13(2.75,-1.75) L14(3.25,-1.75) M1(-3.25,-2.25) M2(-2.75,-2.25) M3(-2.25,-2.25) M4(-1.75,-2.25) M5(-1.25,-2.25) M6(-0.75,-2.25) M7(-0.25,-2.25) M8(0.25,-2.25) M9(0.75,-2.25) M10(1.25,-2.25) M11(1.75,-2.25) M12(2.25,-2.25) M13(2.75,-2.25) M14(3.25,-2.25) N1(-3.25,-2.75) N2(-2.75,-2.75) N3(-2.25,-2.75) N4(-1.75,-2.75) N5(-1.25,-2.75) N6(-0.75,-2.75) N7(-0.25,-2.75) N8(0.25,-2.75) N9(0.75,-2.75) N10(1.25,-2.75) N11(1.75,-2.75) N12(2.25,-2.75) N13(2.75,-2.75) N14(3.25,-2.75) P1(-3.25,-3.25) P2(-2.75,-3.25) P3(-2.25,-3.25) P4(-1.75,-3.25) P5(-1.25,-3.25) P6(-0.75,-3.25) P7(-0.25,-3.25) P8(0.25,-3.25) P9(0.75,-3.25) P10(1.25,-3.25) P11(1.75,-3.25) P12(2.25,-3.25) P13(2.75,-3.25) P14(3.25,-3.25)
  silkscreen extent -6.52,-6.5 5.75,6.5, body extent -5.75,-6.5 5.75,6.5, height 1
NC7WZ07FHX [mm] "6-UFDFN, 6-MicroPak2™"
  rect 0.57x0.2 smd: 1(-0.365,0.35)
  rect 0.52x0.2 smd: 2(-0.365,0) 3(-0.365,-0.35) 4(0.365,-0.35) 5(0.365,0) 6(0.365,0.35)
  silkscreen extent -0.91,0.61 -0.81,0.71, body extent -0.53,-0.53 0.53,0.53, height 0.55
NRS8040 [mm] "Precision Wire Wound Inductor, 2-Leads, Body 4,00x4,00mm, IPC High Density"
  rect 1.2x3.7 smd: 1(-1.4,0) 2(1.4,0)
  body extent -2.1,-2 2.1,2, height 1.9
PCA9306 [mm] "8-XFDFN, Body 1,40x1,00mm, Pitch 0,35mm, IPC High Density"
  rect 0.53x0.2 smd: 1(-0.335,0.525) 2(-0.335,0.175) 3(-0.335,-0.175) 4(-0.335,-0.525) 5(0.335,-0.525) 6(0.335,-0.175) 7(0.335,0.175) 8(0.335,0.525)
  silkscreen extent -0.86,0.79 -0.76,0.89, body extent -0.53,-0.73 0.53,0.72, height 0.4
"PCI Express / PCI Connectors Mini PCI-E 6.8H G/F" [mm] "PCI Express / PCI Connectors Mini PCI-E 6.8H G/F"
  rect 0.6x2 smd: 1(-7.95,-4.1) 2(-7.55,4.1) 3(-7.15,-4.1) 4(-6.75,4.1) 5(-6.35,-4.1) 6(-5.95,4.1) 7(-5.55,-4.1) 8(-5.15,4.1) 9(-4.75,-4.1) 10(-4.35,4.1) 11(-3.95,-4.1) 12(-3.55,4.1) 13(-3.15,-4.1) 14(-2.75,4.1) 15(-2.35,-4.1) 16(-1.95,4.1) 17(1.65,-4.1) 18(2.05,4.1) 19(2.45,-4.1) 20(2.85,4.1) 21(3.25,-4.1) 22(3.65,4.1) 23(4.05,-4.1) 24(4.45,4.1) 25(4.85,-4.1) 26(5.25,4.1) 27(5.65,-4.1) 28(6.05,4.1) 29(6.45,-4.1) 30(6.85,4.1) 31(7.25,-4.1) 32(7.65,4.1) 33(8.05,-4.1) 34(8.45,4.1) 35(8.85,-4.1) 36(9.25,4.1) 37(9.65,-4.1) 38(10.05,4.1) 39(10.45,-4.1) 40(10.85,4.1) 41(11.25,-4.1) 42(11.65,4.1) 43(12.05,-4.1) 44(12.45,4.1) 45(12.85,-4.1) 46(13.25,4.1) 47(13.65,-4.1) 48(14.05,4.1) 49(14.45,-4.1) 50(14.85,4.1) 51(15.25,-4.1) 52(15.65,4.1)
  rect 2.3x3.2 smd: M(-10.8,-3.5) M(18.5,-3.6)
  silkscreen extent -11.03,-6.05 18.7,5.15, body extent -11.1,-4.62 18.8,4.63, height 6.95
PIN1 [mm] "Connector; Plug"
  rect 1.5x1.5 hole 0.9: 1(0,0)
  silkscreen extent -1.4,-1.4 1.4,2.17
PU5931 [mm] "Chip Resistor, 2-Leads, Body 15,00x7,75mm, IPC High Density"
  rect 5.2x8.75 smd: 1(-5.4,0) 2(5.4,0)
  silkscreen extent -2.75,-4.28 2.75,4.28, body extent -7.63,-4 7.63,4, height 1.18
QFN-ML28_N [mm] "QFN, 28-Leads, Body 6x6mm, Pitch 0.65mm, Thermal Pad 4.2x4.2mm, IPC Medium Density"
  oval 1.05x0.3 smd: 1(-2.875,1.95) 2(-2.875,1.3) 3(-2.875,0.65) 4(-2.875,0) 5(-2.875,-0.65) 6(-2.875,-1.3) 7(-2.875,-1.95) 15(2.875,-1.95) 16(2.875,-1.3) 17(2.875,-0.65) 18(2.875,0) 19(2.875,0.65) 20(2.875,1.3) 21(2.875,1.95)
  oval 0.3x1.05 smd: 8(-1.95,-2.875) 9(-1.3,-2.875) 10(-0.65,-2.875) 11(0,-2.875) 12(0.65,-2.875) 13(1.3,-2.875) 14(1.95,-2.875) 22(1.95,2.875) 23(1.3,2.875) 24(0.65,2.875) 25(0,2.875) 26(-0.65,2.875) 27(-1.3,2.875) 28(-1.95,2.875)
  rect 4.2x4.2 smd: 29(0,0)
  silkscreen extent -3.97,-3.2 3.2,3.2, body extent -3.05,-3.05 3.05,3.05, height 1
"RES 0201/0603" [mm] "Chip Resistor, 2-Leads, Body 0.60x0.30mm, IPC Medium Density"
  rect 0.44x0.35 smd: 1(-0.325,0) 2(0.325,0)
  silkscreen extent -0.7,-0.33 0.7,0.33, body extent -0.3,-0.15 0.3,0.15, height 0.21
"RES 0402/1005 RF KK" [mm] "Chip Resistor, 2-Leads, Body 1.0x0.5mm, IPC High Density"
  rect 0.45x0.55 smd: 1(-0.5,0) 2(0.5,0)
  silkscreen extent -1.02,-0.51 1.02,0.51, body extent -0.5,-0.25 0.5,0.25, height 0.35
"RES 0603/1608 RF" [mm] "Chip Resistor, 2-Leads, Body 1.60x0.80mm, IPC High Density"
  rect 0.75x0.85 smd: 1(-0.6,0) 2(0.6,0)
  silkscreen extent -1.2,-0.6 1.2,0.6, body extent -0.8,-0.4 0.8,0.4, height 0.45
"RES 0805/2012 RF" [mm] "Chip Resistor, 2-Leads, Body 2.00x1.25mm, IPC High Density"
  rect 0.95x1.25 smd: 1(-0.775,0) 2(0.775,0)
  silkscreen extent -1.5,-0.8 1.5,0.8, body extent -0.95,-0.62 1.05,0.63, height 0.6
"RES 1206/3216" [mm] "Chip Resistor, 2-Leads, Body 3.13x1.55mm, IPC Medium Density"
  rect 1.2x1.65 smd: 1(-1.4,0) 2(1.4,0)
  silkscreen extent -2.3,-1.1 2.3,1.1, body extent -1.57,-0.8 1.62,0.8, height 0.6
RES_1210 [mm]
  rect 0.9x2.3 smd: 1(-1.55,0) 2(1.55,0)
  silkscreen extent -0.4,-1.05 0.4,1.05, body extent -1.67,-1.33 1.68,1.33, height 0.65
RJK0651DPB [mm] "LFPAK, PTZZ0005DA-A"
  rect 1.1x0.5 smd: 1(-2.65,1.905) 2(-2.65,0.635) 3(-2.65,-0.635) 4(-2.65,-1.905)
  rect 4.5x3.3 smd: 5(0.85,0)
  silkscreen extent -2.77,2.58 -2.53,2.83, body extent -3.05,-2.65 2.95,2.65, height 1.1
S1M-13-F [mm] "Molded Diode, 2-Leads, Body 4,30x2,61mm, IPC High Density"
  rect 2.5x1.7 smd: 1(-2,0) 2(2,0)
  silkscreen extent -3.12,-1.5 2.3,1.52, body extent -2.52,-1.46 2.52,1.46, height 2.4
Si510 [mm] "4-Leads, Body 5,00x3,20mm, Pitch 2,54mm, IPC High Density"
  rect 1.7x1.35 smd: 1(-1.3,1.27) 2(-1.3,-1.27) 3(1.3,-1.27) 4(1.3,1.27)
  silkscreen extent -2.2,-2.65 1.75,2.7, body extent -1.6,-2.5 1.6,2.5, height 1.28
SI2342DS-T1-GE3 [mm] "SOT23, 3-Leads, Body 2,92x2,37mm, Pitch 0,95mm, IPC High Density"
  rect 0.724x0.6 smd: 1(-0.984,0.95) 2(-0.984,-0.95) 3(0.984,0)
  silkscreen extent -1.11,-1.5 0.7,1.92, body extent -1.32,-1.52 1.32,1.52, height 1.12
SI53323-B-GM [mm] "QFN, 16-Leads, Body 3,00x3,00mm, Pitch 0,50mm, Thermal Pad 1,75x1,75mm, IPC High Density"
  rect 0.8x0.3 smd: 1(-1.5,0.75) 2(-1.5,0.25) 3(-1.5,-0.25) 4(-1.5,-0.75) 9(1.5,-0.75) 10(1.5,-0.25) 11(1.5,0.25) 12(1.5,0.75)
  rect 0.3x0.8 smd: 5(-0.75,-1.5) 6(-0.25,-1.5) 7(0.25,-1.5) 8(0.75,-1.5) 13(0.75,1.5) 14(0.25,1.5) 15(-0.25,1.5) 16(-0.75,1.5)
  rect 1.75x1.75 smd: 17(0,0)
  silkscreen extent -2.42,-1.65 1.65,1.65, body extent -1.5,-1.5 1.5,1.5, height 0.9
SiJ482DP [mm] "PowerPAK® SO-8L Case Outline 1"
  rect 0.82x0.41 smd: 1(-2.715,1.905) 2(-2.715,0.635) 3(-2.715,-0.635) 4(-2.715,-1.905)
  rect 0.61x0.595 smd: 5(-0.05,2.286) 5(-0.05,-2.286)
  rect 3.63x4.061 smd: 5(0.75,0)
  rect 0.51x5 smd: 5(2.8,0)
  silkscreen extent -2.84,-2.65 -1.47,2.78, body extent -2.67,-2.63 3.48,2.63, height 1.14
SiT1602B [mm] "2.5 x 2.0 x 0.75 mm"
  rect 1.1x1 smd: 1(-0.95,-0.75) 2(0.95,-0.75) 3(0.95,0.75) 4(-0.95,0.75)
  silkscreen extent -1.76,-1.31 -1.66,-1.21, body extent -1.28,-1.02 1.28,1.02, height 0.8
SLVU2.8-4 [mm] "SOIC-8 Pins 8"
  rect 1.3x0.6 smd: 1(-2.75,1.905) 2(-2.75,0.635) 3(-2.75,-0.635) 4(-2.75,-1.905) 5(2.75,-1.905) 6(2.75,-0.635) 7(2.75,0.635) 8(2.75,1.905)
  silkscreen extent -2.88,-2.5 1.6,2.88, body extent -3,-2.5 3,2.5, height 1.75
SN74AXC4T774PWR [mm] "TSOP,PW0016A, 16-Leads, Body 5,00x4,40mm, Pitch 0,65mm, IPC High Density"
  rect 1.5x0.45 smd: 1(-2.9,2.275) 2(-2.9,1.625) 3(-2.9,0.975) 4(-2.9,0.325) 5(-2.9,-0.325) 6(-2.9,-0.975) 7(-2.9,-1.625) 8(-2.9,-2.275) 9(2.9,-2.275) 10(2.9,-1.625) 11(2.9,-0.975) 12(2.9,-0.325) 13(2.9,0.325) 14(2.9,0.975) 15(2.9,1.625) 16(2.9,2.275)
  silkscreen extent -3.02,-2.55 1.85,3.17, body extent -3.2,-2.55 3.2,2.55, height 1.2
SN74LVC1G08DBVR [mm] "SOT23, 5-Leads, Body 2,90x2,80mm, Pitch 0,95mm, IPC High Density"
  rect 1.1x0.6 smd: 1(-1.3,0.95) 2(-1.3,0) 3(-1.3,-0.95) 4(1.3,-0.95) 5(1.3,0.95)
  silkscreen extent -1.42,-1.55 0.5,1.92, body extent -1.5,-1.53 1.5,1.52, height 1.45
SO8_N [mm] "SOIC, 8-Leads, Body 4.9x3.9mm, Pitch 1.27mm, IPC Medium Density"
  oval 2.2x0.6 smd: 1(-2.4,1.905) 2(-2.4,0.635) 3(-2.4,-0.635) 4(-2.4,-1.905) 5(2.4,-1.905) 6(2.4,-0.635) 7(2.4,0.635) 8(2.4,1.905)
  silkscreen extent -2.53,-2.5 0.9,2.88, body extent -2,-2.5 2,2.5, height 1.75
SRP1265A-220M [mm] "Precision Wire Wound Inductor, 2-Leads, Body 13,50x12,50mm, IPC High Density"
  rect 3.1x5 smd: 1(-5.55,0) 2(5.55,0)
  silkscreen extent -7,-6.4 7,6.4, body extent -6.85,-6.25 6.85,6.25, height 6.6
ST1L08 [mm] "DFN8 (2x3 mm) package outline"
  rect 0.5x0.3 smd: 1(-1.4,0.75) 2(-1.4,0.25) 3(-1.4,-0.25) 4(-1.4,-0.75) 5(1.4,-0.75) 6(1.4,-0.25) 7(1.4,0.25) 8(1.4,0.75)
  rect 1.9x1.75 smd: 9(0,0)
  silkscreen extent -1.91,1.06 -1.81,1.16, body extent -1.5,-1 1.5,1, height 0.9
TCA9548 [mm]
  rect 0.6x0.26 smd: 1(-1.935,1.25) 2(-1.935,0.75) 3(-1.935,0.25) 4(-1.935,-0.25) 5(-1.935,-0.75) 6(-1.935,-1.25) 13(1.935,-1.25) 14(1.935,-0.75) 15(1.935,-0.25) 16(1.935,0.25) 17(1.935,0.75) 18(1.935,1.25)
  rect 0.26x0.6 smd: 7(-1.25,-1.935) 8(-0.75,-1.935) 9(-0.25,-1.935) 10(0.25,-1.935) 11(0.75,-1.935) 12(1.25,-1.935) 19(1.25,1.935) 20(0.75,1.935) 21(0.25,1.935) 22(-0.25,1.935) 23(-0.75,1.935) 24(-1.25,1.935)
  rect 2.1x2.1 smd paste-100: 25(0,0)
  silkscreen extent -2.88,-2 2,2
TECO-5-1814832-1_V [mm] "THD, 5-Leads, Body 6.4x6.4mm, Pitch 5.08mm"
  round 2 hole 1.5: 1(0,0)
  round 2.1 hole 1.6: 2(-2.54,2.54) 3(-2.54,-2.54) 4(2.54,-2.54) 5(2.54,2.54)
  silkscreen extent -3.2,-3.2 3.2,3.2, body extent -3.21,-3.21 3.19,3.19, height 9.5
TECO-640456-2_V [mm] "HDR, 2-Leads, Body 5.715x5.08mm, Pitch 2.54mm"
  rect 1.8x1.8 hole 1.3: 1(1.27,0)
  round 1.8 hole 1.3: 2(-1.27,0)
  silkscreen extent -2.54,-2.54 3.26,3.17, body extent -2.54,-2.67 2.54,3.17, height 9.4
TECO-1909763-1_V [mm] "SMD, 3-Leads, Body 2.6x2.6mm, Height 1.25mm"
  rect 1.05x2.2 smd: 1(-1.475,0) 3(1.475,0)
  rect 1x1.05 smd: 2(0,-1.525)
  silkscreen extent -1.9,-1.77 0.55,1.3, body extent -1.5,-1.55 1.5,1.55, height 1.23
TestPoint [mm] "TestPoint,  Body 1,00x2,54x4,60mm, IPC Low Density"
  round 2.54 hole 1.02: 1(0,0)
  silkscreen extent -0.37,-1.27 0.5,1.27, body extent -1.27,-1.27 1.26,1.27, height 4.6
TPD2EUSB30 [mm] "SOT23, 3-Leads, Body 1,00x1,00mm, Pitch 0,35mm, IPC High Density"
  rect 0.3x0.3 smd: 1(-0.425,0.35) 2(-0.425,-0.35) 3(0.425,0)
  silkscreen extent -0.55,-0.55 0.43,1.17, body extent -0.6,-0.52 0.6,0.53, height 0.5
TPD4EUSB30 [mm] "DQA0010A, 10-Leads, Body 2,50x1,00mm, Pitch 0,50mm, IPC High Density"
  rect 0.565x0.2 smd: 1(-0.417,1) 2(-0.418,0.5) 4(-0.417,-0.5) 5(-0.417,-1) 6(0.417,-1) 7(0.417,-0.5) 9(0.417,0.5) 10(0.417,1)
  rect 0.565x0.4 smd paste-0.04: 3(-0.417,0) 8(0.417,0)
  silkscreen extent -1,-1.45 0.55,1.5, body extent -0.63,-1.3 0.63,1.3, height 0.55
TPS7A88 [mm] "RTJ (S-PWQFN-N20) 20-Leads, Body 4,00x4,00mm, Pitch 0,50mm, Thermal Pad 2,70x2,70mm, IPC High Density"
  rect 0.85x0.28 smd: 1(-1.975,1) 2(-1.975,0.5) 3(-1.975,0) 4(-1.975,-0.5) 5(-1.975,-1) 11(1.975,-1) 12(1.975,-0.5) 13(1.975,0) 14(1.975,0.5) 15(1.975,1)
  rect 0.28x0.85 smd: 6(-1,-1.975) 7(-0.5,-1.975) 8(0,-1.975) 9(0.5,-1.975) 10(1,-1.975) 16(1,1.975) 17(0.5,1.975) 18(0,1.975) 19(-0.5,1.975) 20(-1,1.975)
  rect 2.7x2.7 smd paste-3: 21(0,0)
  silkscreen extent -2.85,-2.08 2.07,2.07, body extent -2.07,-2.07 2.07,2.07, height 0.8
TPS212x [mm] "VQFN-HR - 1 mm max height"
  rect 1.05x0.4 smd: 1(-0.675,0.35) 2(-0.675,-0.35) 7(0.675,-0.35) 8(0.675,0.35)
  rect 0.2x0.6 smd: 3(-0.75,-1.15) 4(-0.25,-1.15) 5(0.25,-1.15) 6(0.75,-1.15) 9(0.75,1.15) 10(0.25,1.15) 11(-0.25,1.15) 12(-0.75,1.15)
  silkscreen extent -1.82,-1.3 1.05,1.3, body extent -1.05,-1.3 1.05,1.3, height 1
"TSX-3225 24.0000MF15X-AC6" [mm] "Ceramic Package, 4-Leads, Body 2,50x3,20mm, Pitch 1,60mm, IPC High Density"
  rect 1.4x1.15 smd: 1(-1.1,-0.8) 2(1.1,-0.8) 3(1.1,0.8) 4(-1.1,0.8)
  silkscreen extent -2,-1.7 -1.9,-1.6, body extent -1.6,-1.25 1.6,1.25, height 0.6
UA78M [mm] "SOT223, 4-Leads, DCY (R-PDSO-G4)"
  rect 2.15x0.95 smd: 1(-2.9,2.3) 2(-2.9,0) 3(-2.9,-2.3)
  rect 2.15x3.25 smd: 2(2.9,0)
  silkscreen extent -3.02,-3.35 2.05,3.45, body extent -3.5,-3.35 3.5,3.35, height 1.8
USB3320 [mm] "32-PIN QFN, 5X5MM BODY, 0.5MM PITCH"
  rect 0.75x0.25 smd: 1(-2.45,1.75) 2(-2.45,1.25) 3(-2.45,0.75) 4(-2.45,0.25) 5(-2.45,-0.25) 6(-2.45,-0.75) 7(-2.45,-1.25) 8(-2.45,-1.75) 17(2.45,-1.75) 18(2.45,-1.25) 19(2.45,-0.75) 20(2.45,-0.25) 21(2.45,0.25) 22(2.45,0.75) 23(2.45,1.25) 24(2.45,1.75)
  rect 0.25x0.75 smd: 9(-1.75,-2.45) 10(-1.25,-2.45) 11(-0.75,-2.45) 12(-0.25,-2.45) 13(0.25,-2.45) 14(0.75,-2.45) 15(1.25,-2.45) 16(1.75,-2.45) 25(1.75,2.45) 26(1.25,2.45) 27(0.75,2.45) 28(0.25,2.45) 29(-0.25,2.45) 30(-0.75,2.45) 31(-1.25,2.45) 32(-1.75,2.45)
  rect 3.3x3.3 smd paste-2: 33(0,0)
  silkscreen extent -3.48,2.43 -3.23,2.67, body extent -2.57,-2.57 2.57,2.57, height 1
WE-CHSA_1011 [mm] "SMT High Current Inductor, 2-Leads, body 10.6x10.6mm"
  rect 2.05x3.6 smd: 1(-4.05,0) 2(4.05,0)
  silkscreen extent -5.45,-5.45 5.45,5.45, body extent -5.3,-5.3 5.3,5.3, height 11
WE-HCC_8070 [mm] "SMT High Current Cube Inductor, 2-Leads, body 7.9x7.9mm"
  rect 2.3x3 smd: 1(-3.35,0) 2(3.35,0)
  silkscreen extent -4.1,-4.1 4.1,4.1, body extent -4.2,-3.95 4.2,3.95, height 7.23
WSHP2818 [mm] "Chip Resistor, 2-Leads, Body 7,10x4,60mm, IPC High Density"
  rect 3.5x5.1 smd: 1(-2.055,0) 2(2.055,0)
  body extent -3.67,-2.42 3.68,2.42, height 1.75

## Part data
B1: "BATT LITH 1.5V 5.5MAH COIN 9.5MM", Capacity=5.5mAh, Manufacturer=Seiko, Supplier Part Number 1=728-1082-ND, Voltage Rating=1.5V
BT1: "WA-BCMC Battery Holder, SMT, Battery Type 2016/2020/2025/2032"
C1 C2 C3 C49 C50 C54 C207 C209 C312 C313 C314 C315 C316 C317 C318 C319 C325 C330 C334 C335 C341 C342 C343 C477 C478 C479 C482 C483 C484 C531 C532 C533 C534 C540 C541 C542 C543 C557 C588 C589 C592 C594 C599 C601 C602 C608 C682 C684 C686 C687 C688 C689 C690 C728 C729 C730 C732 C735 C790 C793 C796 C797 C798 C799 C800 C801 C802 C805 C806 C807 C808 C811 C812 C813 C814 C817 C818 C819 C820: library part Capacitor, Case/Package=0402, Case Code (Metric)=1005, Dielectric=X7R, Manufacturer=Murata, Manufacturer Part Number=GRM155R71E104KE14J, Max Operating Temperature=125°C, Min Operating Temperature=-55°C, Package Quantity=50000, Supplier Part Number 1=490-14603-1-ND, Tolerance=10%, Voltage Rating=25V
C4 C5 C6 C7 C12 C13 C14 C15 C38 C40 C212 C214 C216 C218 C766 C767 C768 C769: library part Capacitor, Case Code (Imperial)=1210, Case Code (Metric)=3225, Dielectric=X5R, Manufacturer=Samsung, Manufacturer Part Number=CL32A226KAJNNNE, Max Operating Temperature=85°C, Min Operating Temperature=-55°C, Package Quantity=1, Supplier Part Number 1=1276-1101-1-ND, Tolerance=10%, Voltage=25V
C8 C9 C10 C11 C16 C17 C18 C19 C37 C39 C41 C211 C213 C215 C217 C770 C771 C772 C773: library part Capacitor, Case Code (Imperial)=0402, Case Code (Metric)=1005, Dielectric=X7R, Manufacturer=Murata, Manufacturer Part Number=GRM155R71E104KE14J, Max Operating Temperature=125°C, Min Operating Temperature=-55°C, Package Quantity=50000, Supplier Part Number 1=490-14603-1-ND, Tolerance=10%, Voltage Rating=25V
C20 C21 C22 C23 C28 C29 C30 C31 C574 C575 C581 C774 C775 C776 C777: library part Capacitor, "CAP CER 10UF 25V X5R 0805", Case Code (Imperial)=0805, Case Code (Metric)=2012, Dielectric=X5R, Dielectric Material=Ceramic, Manufacturer=KEMET, Manufacturer Part Number=C0805C106K3PACTU, Max Operating Temperature=85°C, Min Operating Temperature=-55°C, Supplier Part Number 1=399-11939-6-ND, Tolerance=10%, Voltage=25V
C24 C25 C26 C27 C32 C33 C34 C35 C580 C582 C584 C778 C779 C780: library part Capacitor, "CAP CER 4.7UF 25V X5R 0805", Case Code (Imperial)=0805, Case Code (Metric)=2012, Dielectric=X5R, Manufacturer=Murata, Manufacturer Part Number=GRM219R61E475KA73D, Max Operating Temperature=85°C, Min Operating Temperature=-55°C, Package Quantity=4000, Supplier Part Number 1=490-12753-1-ND, Tolerance=10%, Voltage Rating=25V
C36 C320 C490 C498 C504 C514 C525 C526 C527 C528 C529 C530: library part Capacitor, Case/Package=0402, Case Code (Metric)=1005, Dielectric=X7R, Dielectric Material=Ceramic, Manufacturer=KEMET, Manufacturer Part Number=C0402C103K4RACTU, Max Operating Temperature=125°C, Min Operating Temperature=-55°C, Package Quantity=1, Supplier Part Number 1=399-1038-1-ND, Tolerance=10%, Voltage=16V
C42 C55 C56 C57 C58 C65 C66 C68 C69 C111 C112 C113 C114 C115 C116 C117 C118 C119: library part Capacitor, Case Code (Imperial)=0402, Case Code (Metric)=1005, Dielectric=X7R, Dielectric Material=Ceramic, Manufacturer=KEMET, Manufacturer Part Number=C0402C103K4RACTU, Max Operating Temperature=125°C, Min Operating Temperature=-55°C, Package Quantity=1, Supplier Part Number 1=399-1038-1-ND, Tolerance=10%, Voltage=16V
C43 C44 C47 C48 C51 C52 C181 C182 C183 C184 C185 C186 C187 C188 C189 C190 C191 C192 C193 C194 C195 C196 C197 C198 C199 C200 C201 C202 C203 C204 C205 C206 C311_I2C_Expander_00 C311_I2C_Expander_01 C311_I2C_Expander_02 C311_I2C_Expander_10 C311_I2C_Expander_11 C311_I2C_Expander_12 C311_I2C_Expander_Main_Rst C311_I2C_Expander_PWR_CLK C311_I2C_Expander_PWR_Dist C311_I2C_Expander_SFP C326 C327 C328 C329 C331 C332 C340 C351 C356 C361 C379 C395 C398 C408 C420 C436 C449 C461 C485 C486 C491 C492 C493 C499 C500 C505 C506 C507 C508 C522 C538 C544 C559 C604 C680 C700 C720 C721 C722 C723 C733 C734: library part Capacitor, "MURATA - GRT155R61E105KE01D - SMD Multilayer Ceramic Capacitor, 1 µF, 25 V, 0402 [1005 Metric], ± 10%, X5R, GRT Series - SMD Multilayer Ceramic Capacitor, 1 µF, 25 V, 0402 [1005 Metric], ± 10%, X5R, GRT Series", Case/Package=0402, Case Code (Metric)=1005, Dielectric=X5R, Manufacturer=Murata, Manufacturer Part Number=GRT155R61E105KE01D, Max Operating Temperature=85°C, Min Operating Temperature=-55°C, Ratings=AEC-Q200, Supplier Part Number 1=490-12263-1-ND, Tolerance=10%, Voltage Rating=25V
C45: library part Capacitor, "Cap Ceramic 0.0056uF 25V X7R 10% SMD 0402 125C Paper T/R", Case Code (Imperial)=0402, Case Code (Metric)=1005, Dielectric=X7R, Manufacturer=Yageo, Manufacturer Part Number=CC0402KRX7R8BB562, Max Operating Temperature=125°C, Min Operating Temperature=-55°C, Supplier Part Number 1=311-1718-1-ND, Tolerance=10%, Voltage Rating=25V
C46: library part Capacitor, "Multilayer Ceramic Capacitors MLCC - SMD/SMT 200pF 50V NPO 5%", Case Code (Imperial)=0402, Case Code (Metric)=1005, Dielectric=C0G, Manufacturer=Yageo, Manufacturer Part Number=CC0402JRNPO9BN201, Max Operating Temperature=125°C, Min Operating Temperature=-55°C, Supplier Part Number 1=311-1664-1-ND, Tolerance=5%, Voltage Rating=50V
C53 C63 C64 C67 C70 C75 C76 C77 C81 C82 C83 C88 C89 C90 C91 C92 C93 C96 C99 C100 C103 C104 C107 C108 C124 C125 C141 C142 C145 C146 C162 C163 C179 C336 C337 C338 C578 C579 C583 C590: library part Capacitor, "CAP CER 0.1UF 50V X5R 0402", Case Code (Imperial)=0402, Case Code (Metric)=1005, Dielectric=X5R, Dielectric Material=Ceramic, Manufacturer=Murata, Manufacturer Part Number=GRM155R61H104KE14D, Max Operating Temperature=85°C, Min Operating Temperature=-55°C, Package Quantity=10000, Supplier Part Number 1=490-10697-1-ND, Tolerance=10%, Voltage=50V
C59 C60 C61 C71 C72 C73 C84 C85 C94 C95: library part Capacitor, "SMT Capacitor", Part Number=GRM033R61C104ME84D, Supplier Part Number 1=490-9986-1-ND
C62 C74 C87 C98 C489 C497 C503 C551 C553 C555: library part Capacitor, "CAP CER 10UF 10V X5R 0402", Case/Package=0402, Case Code (Metric)=1005, Manufacturer=Samsung, Manufacturer Part Number=CL05A106MP8NUB8, Max Operating Temperature=85°C, Min Operating Temperature=-55°C, Supplier Part Number 1=1276-6830-1-ND, Tolerance=20%, Voltage Rating=10V
C78 C79 C80 C101 C102 C105 C106 C109 C110 C126 C127 C143 C144 C147 C148 C164 C165 C180 C513 C591: library part Capacitor, "CAP CER 10UF 10V X5R 0402", Case Code (Imperial)=0402, Case Code (Metric)=1005, Manufacturer=Samsung, Manufacturer Part Number=CL05A106MP8NUB8, Max Operating Temperature=85°C, Min Operating Temperature=-55°C, Supplier Part Number 1=1276-6830-1-ND, Tolerance=20%, Voltage Rating=10V
C86 C97 C149 C150 C151 C152 C153 C154 C155 C156 C157 C158 C159 C160 C161 C166 C167 C168 C169 C170 C171 C172 C173 C174 C175 C176 C177 C178 C273 C276 C277 C278 C285 C288 C289 C290 C297 C300 C333 C344 C573 C577 C624 C625 C626 C706 C710 C724 C725 C726 C727: library part Capacitor, "CAP CER 10000PF 16V X7R 0201", Dielectric=X7R, Manufacturer=Murata, Manufacturer Part Number=GRM033R71C103KE14D, Supplier Part Number 1=490-14453-1-ND, Tolerance=10%, Voltage Rating (DC)=16V
C208 C210: library part Capacitor, Case/Package=1210, Case Code (Metric)=3225, Dielectric=X5R, Manufacturer=Samsung, Manufacturer Part Number=CL32A226KAJNNNE, Max Operating Temperature=85°C, Min Operating Temperature=-55°C, Package Quantity=1, Supplier Part Number 1=1276-1101-1-ND, Tolerance=10%, Voltage=25V
C219 C220 C221 C222 C243 C244 C245 C246 C303_I2C_Bridge_GPIO C303_I2C_Bridge_PCIE C303_I2C_Bridge_SFP C309_U_Pomiar_pradu_napiecia_1 C309_U_Pomiar_pradu_napiecia_2 C309_U_Pomiar_pradu_napiecia_3 C309_U_Pomiar_pradu_napiecia_4 C309_U_Pomiar_pradu_napiecia_5 C309_U_Pomiar_pradu_napiecia_6 C309_U_Pomiar_pradu_napiecia_PCIe0 C309_U_Pomiar_pradu_napiecia_PCIe1 C309_U_Pomiar_pradu_napiecia_PCIe2 C309_U_Pomiar_pradu_napiecia_PCIe3 C309_U_Pomiar_pradu_napiecia_PCIe4 C310 C346 C350 C357 C359 C377 C390 C394 C399 C406 C418 C431 C435 C440 C447 C459 C471 C472 C473 C474 C487 C488 C494 C495 C496 C501 C502 C509 C510 C511 C512 C517 C519 C521 C545 C546 C547 C561 C562 C566_5to3V3_1 C566_5to3V3_2 C566_5V_to_3V3_for_FTDI C585 C623 C649 C651 C653 C654 C658 C660 C662 C665 C666 C667 C668 C669 C670 C671 C673 C677 C711 C712 C713 C715 C716 C717 C718 C783 C785 C787 C789 C791 C792: library part Capacitor, "CAP CER 0.1UF 50V X5R 0402", Case/Package=0402, Case Code (Metric)=1005, Dielectric=X5R, Dielectric Material=Ceramic, Manufacturer=Murata, Manufacturer Part Number=GRM155R61H104KE14D, Max Operating Temperature=85°C, Min Operating Temperature=-55°C, Package Quantity=10000, Supplier Part Number 1=490-10697-1-ND, Tolerance=10%, Voltage=50V
C223 C228 C233 C238 C247 C252 C257 C262 C550 C552 C554 C568 C569 C570: library part Capacitor, "0402 10 V 4.7 uF ±20% Tolerance X5R Multilayer Ceramic Chip Capacitor", Case Code (Imperial)=0402, Case Code (Metric)=1005, Manufacturer=Murata, Manufacturer Part Number=GRM155R61A475MEAAD, Max Operating Temperature=85°C, Min Operating Temperature=-55°C, Supplier Part Number 1=490-14306-1-ND, Tolerance=20%, Voltage Rating=10V
C224 C225 C229 C230 C234 C235 C239 C240 C248 C249 C253 C254 C258 C259 C263 C264: library part Capacitor, "Cap Ceramic 0.47uF 10V X5R 10% SMD 0402 85C Paper T/R", Case Code (Imperial)=0402, Case Code (Metric)=1005, Dielectric=X5R, Manufacturer=Samsung, Manufacturer Part Number=CL05A474KP5NNNC, Max Operating Temperature=85°C, Min Operating Temperature=-55°C, Supplier Part Number 1=1276-1173-1-ND, Tolerance=10%, Voltage Rating=10V
C226 C227 C231 C232 C236 C237 C241 C242 C250 C251 C255 C256 C260 C261 C265 C266: library part Capacitor, "KEMET - C0402C683K4RACTU - CAP, 0.068µF, 16V, 10%, X7R, 0402", Case Code (Imperial)=0402, Case Code (Metric)=1005, Dielectric=X7R, Dielectric Material=Ceramic, Manufacturer=KEMET, Manufacturer Part Number=C0402C683K4RACTU, Max Operating Temperature=125°C, Min Operating Temperature=-55°C, Package Quantity=1, Supplier Part Number 1=399-4904-1-ND, Tolerance=10%, Voltage=16V
C267 C269 C271 C274 C279 C281 C283 C286 C291 C293 C295 C298: library part Capacitor, "CAP CER 0.1UF 16V X5R 0201", Case Code (Metric)=0603, Case/Package=0201, Dielectric=X5R, Manufacturer=Murata, Manufacturer Part Number=GRM033R61C104ME84D, Max Operating Temperature=85°C, Min Operating Temperature=-55°C, Package Quantity=15000, Supplier Part Number 1=490-9986-1-ND, Tolerance=20%, Voltage Rating=16V
C268 C270 C272 C275 C280 C282 C284 C287 C292 C294 C296 C299 C629: library part Capacitor, "CAP CER 0.1UF 16V X5R 0201", Case Code (Imperial)=0201, Case Code (Metric)=0603, Dielectric=X5R, Manufacturer=Murata, Manufacturer Part Number=GRM033R61C104ME84D, Max Operating Temperature=85°C, Min Operating Temperature=-55°C, Package Quantity=15000, Supplier Part Number 1=490-9986-1-ND, Tolerance=20%, Voltage Rating=16V
C304 C305 C306 C307: library part Capacitor, "SMT Capacitor", Part Number=CL10A475KO8NNNC, Supplier Part Number 1=1276-1784-2-ND
C308 C354 C355 C409 C421 C450 C462 C515 C516 C523 C524 C539 C560 C563_5V_to_3V3_for_FTDI C564_5V_to_3V3_for_FTDI C565_5V_to_3V3_for_FTDI C606 C607 C610 C611 C613 C614 C615 C617 C618 C619 C620 C621 C622 C659 C661: library part Capacitor, Case/Package=0603, Case Code (Metric)=1608, Dielectric=X5R, Manufacturer=Samsung, Manufacturer Part Number=CL10A475KP8NNNC, Max Operating Temperature=85°C, Min Operating Temperature=-55°C, Package Quantity=1, Supplier Part Number 1=1276-1044-1-ND, Tolerance=10%, Voltage Rating=10V
C321: library part Capacitor, Case/Package=0603, Case Code (Metric)=1608, Manufacturer="Wurth Electronics", Manufacturer Part Number=885012006016, Max Operating Temperature=125°C, Min Operating Temperature=-55°C, Supplier Part Number 1=732-7759-1-ND, Tolerance=5%, Voltage Rating=10V
C322 C323 C480 C481 C663 C664: library part Capacitor, Case/Package=0402, Case Code (Metric)=1005, Dielectric=C0G, Dielectric Material=Ceramic, Manufacturer=KEMET, Manufacturer Part Number=C0402C270K5GACTU, Max Operating Temperature=125°C, Min Operating Temperature=-55°C, Package Quantity=1, Supplier Part Number 1=399-8960-1-ND, Tolerance=10%, Voltage Rating=50V
C324 C339 C707 C708: library part Capacitor, "CAP CER 10UF 25V X5R 0805", Case/Package=0805, Case Code (Metric)=2012, Dielectric=X5R, Dielectric Material=Ceramic, Manufacturer=KEMET, Manufacturer Part Number=C0805C106K3PACTU, Max Operating Temperature=85°C, Min Operating Temperature=-55°C, Supplier Part Number 1=399-11939-6-ND, Tolerance=10%, Voltage=25V
C345 C349 C535 C536: library part Capacitor, Case Code (Imperial)=0402, Case Code (Metric)=1005, Dielectric=C0G, Manufacturer="Kyocera AVX", Manufacturer Part Number=04025A220JAT2A, Max Operating Temperature=125°C, Min Operating Temperature=-55°C, Package Quantity=1, Supplier Part Number 1=478-1074-1-ND, Temperature Coefficient=30ppm/°C, Tolerance=5%, Voltage=50V
C347 C348 C352 C353 C391 C392 C396 C397 C432 C433 C437 C438: library part Capacitor, Case/Package=1206, Case Code (Metric)=3216, Dielectric=X7R, Manufacturer 1=Murata, Manufacturer Part Number 1=GRM31CR71E106MA12L, Max Operating Temperature=125°C, Min Operating Temperature=-55°C, Package Quantity=1, Supplier Part Number 1=490-6519-1-ND, Tolerance=20%, Voltage=25V
C358: library part Capacitor, "Cap Ceramic 1uF 10V X5R 10% SMD 0603 85C Paper T/R", Case Code (Imperial)=0603, Case Code (Metric)=1608, Dielectric=X5R, Manufacturer=Samsung, Manufacturer Part Number=CL10A105KP8NNNC, Max Operating Temperature=85°C, Min Operating Temperature=-55°C, Package Quantity=1, Supplier Part Number 1=1276-1182-1-ND, Tolerance=10%, Voltage=10V
C360 C378: library part Capacitor, Case Code (Imperial)=0402, Case Code (Metric)=1005, Dielectric=X5R, Manufacturer=Samsung, Manufacturer Part Number=CL05A474KP5NNNC, Max Operating Temperature=85°C, Min Operating Temperature=-55°C, Supplier Part Number 1=1276-1173-1-ND, Tolerance=10%, Voltage Rating=10V
C362 C380 C563_5to3V3_1 C563_5to3V3_2 C564_5to3V3_1 C564_5to3V3_2 C565_5to3V3_1 C565_5to3V3_2: library part Capacitor, Case Code (Imperial)=0603, Case Code (Metric)=1608, Dielectric=X5R, Manufacturer=Samsung, Manufacturer Part Number=CL10A475KP8NNNC, Max Operating Temperature=85°C, Min Operating Temperature=-55°C, Package Quantity=1, Supplier Part Number 1=1276-1044-1-ND, Tolerance=10%, Voltage Rating=10V
C363 C365 C367 C369 C381 C383 C385 C387 C572 C576 C598 C631: library part Capacitor, Case Code (Imperial)=0603, Case Code (Metric)=1608, Dielectric=X5R, Manufacturer=Murata, Manufacturer Part Number=GRM188R61A106KE69D, Max Operating Temperature=85°C, Min Operating Temperature=-55°C, Supplier Part Number 1=490-10474-1-ND, Tolerance=10%, Voltage=10V
C364 C366 C368 C370 C382 C384 C386 C388: library part Capacitor, Case Code (Imperial)=0603, Case Code (Metric)=1608, Dielectric=X5R, Manufacturer=Murata, Manufacturer Part Number=GRM188R61A226ME15D, Max Operating Temperature=85°C, Min Operating Temperature=-55°C, Package Quantity=4000, Supplier Part Number 1=490-10476-1-ND, Tolerance=20%, Voltage Rating=10V
C371 C372 C373 C374 C375 C376: library part Capacitor, "Cap Ceramic 10uF 25V X5R 10% SMD 1206 85C Embossed T/R", Case Code (Imperial)=1206, Case Code (Metric)=3216, Dielectric=X5R, Manufacturer=Samsung, Manufacturer Part Number=CL31A106KAHNNNE, Max Operating Temperature=85°C, Min Operating Temperature=-55°C, Supplier Part Number 1=1276-1075-1-ND, Tolerance=10%, Voltage=25V
C389 C393 C430 C434: library part Capacitor, Case/Package=0402, Case Code (Metric)=1005, Dielectric=C0G, Manufacturer="Kyocera AVX", Manufacturer Part Number=04025A220JAT2A, Max Operating Temperature=125°C, Min Operating Temperature=-55°C, Package Quantity=1, Supplier Part Number 1=478-1074-1-ND, Temperature Coefficient=30ppm/°C, Tolerance=5%, Voltage=50V
C400 C401 C402 C403 C404 C405 C441 C442 C443 C444 C445 C446: library part Capacitor, "Cap Ceramic 10uF 25V X5R 10% SMD 1206 85C Embossed T/R", Case/Package=1206, Case Code (Metric)=3216, Dielectric=X5R, Manufacturer=Samsung, Manufacturer Part Number=CL31A106KAHNNNE, Max Operating Temperature=85°C, Min Operating Temperature=-55°C, Supplier Part Number 1=1276-1075-1-ND, Tolerance=10%, Voltage=25V
C407 C419 C448 C460 C628 C630 C632 C693: library part Capacitor, Case/Package=0402, Case Code (Metric)=1005, Dielectric=X5R, Manufacturer=Samsung, Manufacturer Part Number=CL05A474KP5NNNC, Max Operating Temperature=85°C, Min Operating Temperature=-55°C, Supplier Part Number 1=1276-1173-1-ND, Tolerance=10%, Voltage Rating=10V
C410 C412 C414 C416 C422 C424 C426 C428 C451 C453 C455 C457 C463 C465 C467 C469 C705 C709: library part Capacitor, Case/Package=0603, Case Code (Metric)=1608, Dielectric=X5R, Manufacturer=Murata, Manufacturer Part Number=GRM188R61A106KE69D, Max Operating Temperature=85°C, Min Operating Temperature=-55°C, Supplier Part Number 1=490-10474-1-ND, Tolerance=10%, Voltage=10V
C411 C413 C415 C417 C423 C425 C427 C429 C452 C454 C456 C458 C464 C466 C468 C470: library part Capacitor, Case/Package=0603, Case Code (Metric)=1608, Dielectric=X5R, Manufacturer=Murata, Manufacturer Part Number=GRM188R61A226ME15D, Max Operating Temperature=85°C, Min Operating Temperature=-55°C, Package Quantity=4000, Supplier Part Number 1=490-10476-1-ND, Tolerance=20%, Voltage Rating=10V
C439 C597: library part Capacitor, "MURATA - GRT155R61E105KE01D - SMD Multilayer Ceramic Capacitor, 1 µF, 25 V, 0402 [1005 Metric], ± 10%, X5R, GRT Series - SMD Multilayer Ceramic Capacitor, 1 µF, 25 V, 0402 [1005 Metric], ± 10%, X5R, GRT Series", Case Code (Imperial)=0402, Case Code (Metric)=1005, Dielectric=X5R, Manufacturer=Murata, Manufacturer Part Number=GRT155R61E105KE01D, Max Operating Temperature=85°C, Min Operating Temperature=-55°C, Ratings=AEC-Q200, Supplier Part Number 1=490-12263-1-ND, Tolerance=10%, Voltage Rating=25V
C475 C476 C672: "CAP CER 1210 4.7NF 2000V X7R 10%", Capacitance={}Capacitance, Case Code (Imperial)=1210, Case Code (Metric)=3225, Manufacturer=KEMET, Manufacturer Part Number=C1210X472KGRACAUTO, Max Operating Temperature=125°C, Min Operating Temperature=-55°C, Ratings=AEC-Q200, Supplier Part Number 1=399-16765-1-ND, Tolerance=10%, Voltage Rating=2kV
C518 C520 C567_5V_to_3V3_for_FTDI C586 C587 C731: library part Capacitor, "CAP CER 2.2UF 6.3V X5R 0402", Case/Package=0402, Case Code (Metric)=1005, Dielectric=X5R, Manufacturer="Taiyo Yuden", Manufacturer Part Number=JMK105BJ225KV-F, Max Operating Temperature=85°C, Min Operating Temperature=-55°C, Package Quantity=10000, Supplier Part Number 1=587-5867-1-ND, Tolerance=10%, Voltage Rating=6.3V
C537: "WR-COM USB 3.0 Horizontal Type A", Manufacturer="Würth Elektronik eiSos GmbH", partNo=692121130100
C548: library part Capacitor, Case/Package=0402, Case Code (Metric)=1005, Dielectric=C0G, Manufacturer=Yageo, Manufacturer Part Number=CC0402JRNPO9BN110, Max Operating Temperature=125°C, Min Operating Temperature=-55°C, Package Quantity=1, Supplier Part Number 1=311-1015-1-ND, Tolerance=5%, Voltage Rating=50V
C549: library part Capacitor, Case/Package=0402, Case Code (Metric)=1005, Dielectric=X7R, Dielectric Material=Ceramic, Insulation Resistance=100GR, Manufacturer=Yageo, Manufacturer Part Number=CC0402KRX7R9BB221, Max Operating Temperature=125°C, Min Operating Temperature=-55°C, Package Quantity=1, Supplier Part Number 1=311-1035-1-ND, Tolerance=10%, Voltage Rating=50V
C558: "WR-COM USB Vertical Type B", Manufacturer="Würth Elektronik eiSos GmbH", partNo=61400413321
C567_5to3V3_1 C567_5to3V3_2: library part Capacitor, "CAP CER 2.2UF 6.3V X5R 0402", Case Code (Imperial)=0402, Case Code (Metric)=1005, Dielectric=X5R, Manufacturer="Taiyo Yuden", Manufacturer Part Number=JMK105BJ225KV-F, Max Operating Temperature=85°C, Min Operating Temperature=-55°C, Package Quantity=10000, Supplier Part Number 1=587-5867-1-ND, Tolerance=10%, Voltage Rating=6.3V
C571 C719: library part Capacitor, "CAP CER 1000PF 25V X5R 0201", Case/Package=0201, Dielectric=X5R, Manufacturer=Murata, Manufacturer Part Number=GRM033R61E102KA01D, Max Operating Temperature=85°C, Min Operating Temperature=-55°C, Supplier Part Number 1=490-14452-1-ND, Tolerance=10%, Voltage Rating (DC)=25V
C595 C596 C695 C696 C697 C698 C699: library part Capacitor, Dielectric=X5R, Manufacturer=Murata, Manufacturer Part Number=GRM21BR61H106KE43L, Supplier Part Number 1=490-18663-1-ND, Tolerance=10%, Voltage Rating (DC)=50V
C603 C612: library part Capacitor, Case Code (Imperial)=0201, Case Code (Metric)=0603, Dielectric=C0G, Manufacturer=Murata, Manufacturer Part Number=GRM0335C1H430GA01D, Max Operating Temperature=125°C, Min Operating Temperature=-55°C, Package Quantity=15000, Supplier Part Number 1=490-14799-1-ND, Tolerance=2%, Voltage Rating=50V
C605 C616: library part Capacitor, Case Code (Imperial)=0201, Case Code (Metric)=0603, Dielectric=C0G, Manufacturer=Murata, Manufacturer Part Number=GRM0335C1E101JA01D, Max Operating Temperature=125°C, Min Operating Temperature=-55°C, Package Quantity=15000, Supplier Part Number 1=490-3160-1-ND, Tolerance=5%, Voltage=25V
C609: "Supercapacitors / Ultracapacitors 0.22F 5.5volts SMD Super Capacitor", Capacitance=220mF, Case/Package=Radial, ESR (Equivalent Series Resistance)=25R, Leakage Current=330uA, Manufacturer=KEMET, Max Operating Temperature=70°C, Min Operating Temperature=-25°C, Package Quantity=500, Supplier Part Number 1=18X4838, Tolerance=80%, Voltage=5.5V
C627: library part Capacitor, "CAP CER 0.1UF 16V X5R 0201", Case/Package=0201, Case Code (Metric)=0603, Dielectric=X5R, Manufacturer=Murata, Manufacturer Part Number=GRM033R61C104ME84D, Max Operating Temperature=85°C, Min Operating Temperature=-55°C, Package Quantity=15000, Supplier Part Number 1=490-9986-1-ND, Tolerance=20%, Voltage Rating=16V
C633 C636: library part Capacitor, Case/Package=0402, Case Code (Metric)=1005, Dielectric=U2J, Manufacturer=Murata, Manufacturer Part Number=GRM1557U1A302JA01D, Max Operating Temperature=125°C, Min Operating Temperature=-55°C, Package Quantity=10000, Supplier Part Number 1=490-8243-1-ND, Tolerance=5%, Voltage Rating=10V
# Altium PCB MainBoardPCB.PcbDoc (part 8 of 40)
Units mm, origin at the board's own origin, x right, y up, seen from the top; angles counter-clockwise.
Board outline 258.95 x 308.86 mm, 16 copper layers (L1, L2 (GND), L3 (Sign), L4 (GND), L5 (Sign), L6 (PWR/GND), L7(12V+Other), L8 (Plane_GND), L9 (PWR/GND), L10 (3V3+Other), L11 (PWR/GND), L12 (Sign), L13 (GND), L14 (Sign), L15 (GND), L16), stack 2.503 mm thick; 2578 components, 1867 nets, 8817 pads, 8021 vias.
Unrouted connection lines stored in the file: 25.

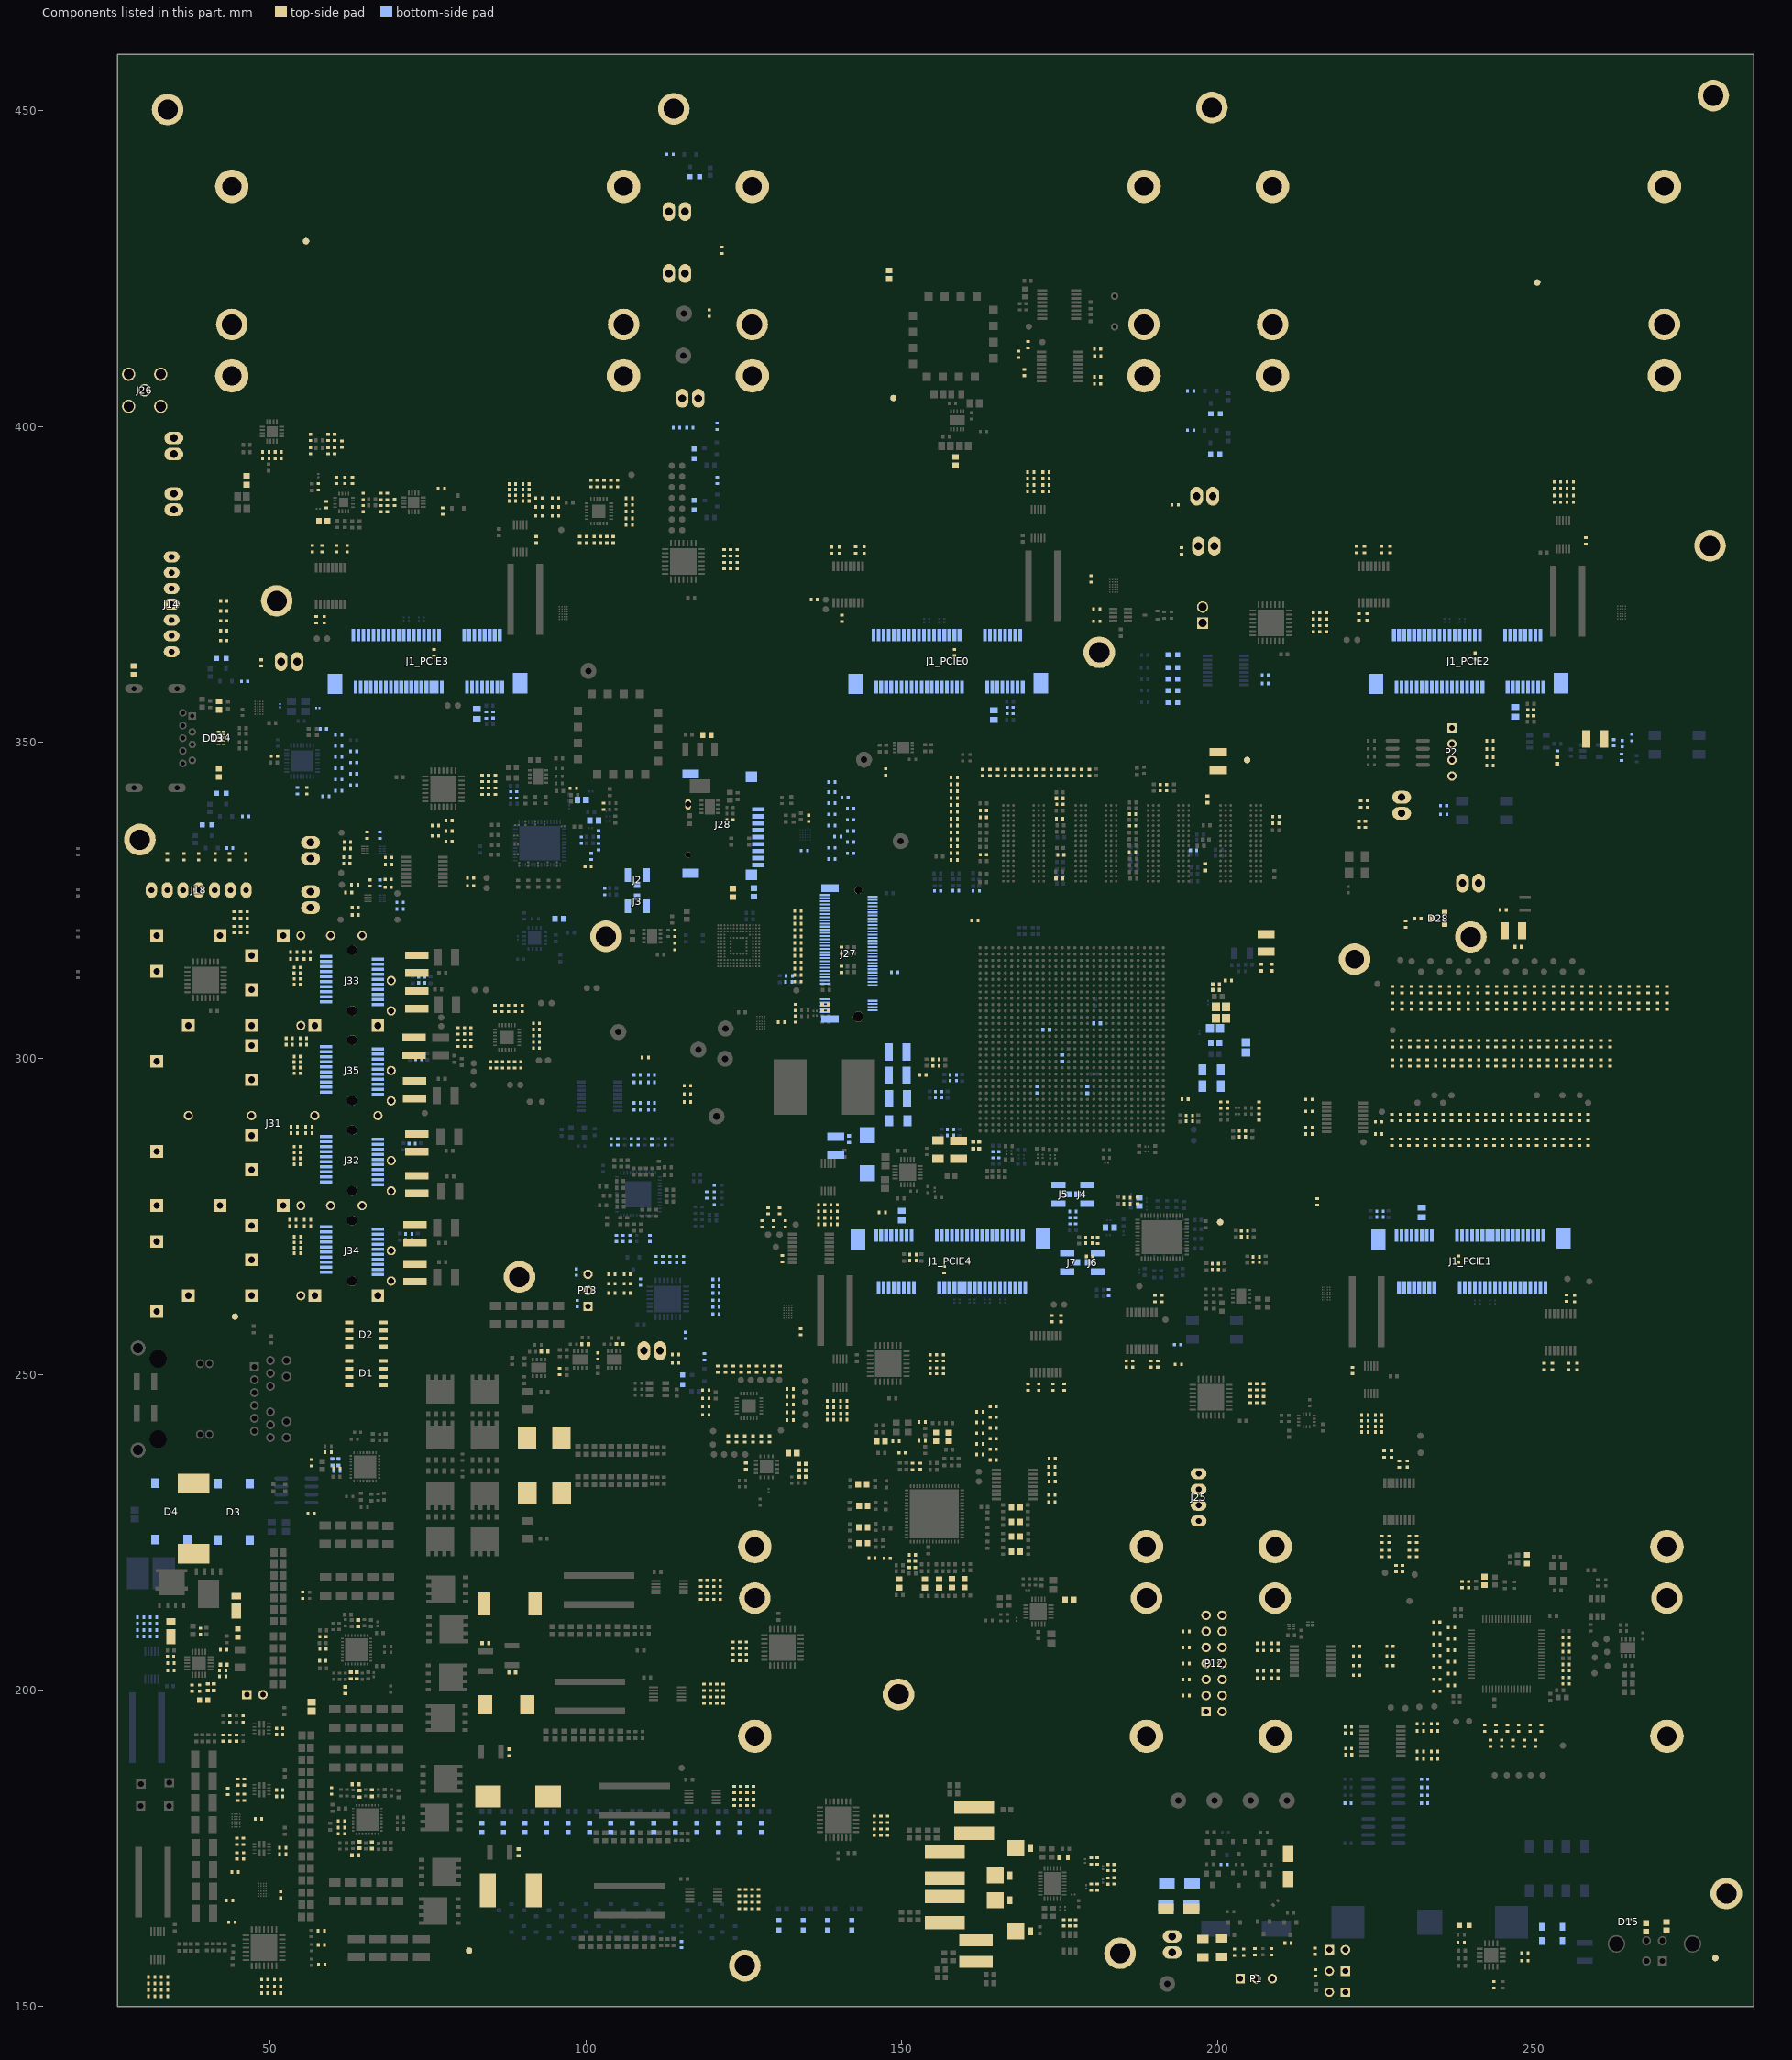
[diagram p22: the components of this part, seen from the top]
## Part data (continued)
C634: library part Capacitor, Case/Package=0402, Case Code (Metric)=1005, Dielectric=X7R, Dielectric Material=Ceramic, Insulation Resistance=100GR, Manufacturer=Yageo, Manufacturer Part Number=CC0402KRX7R9BB331, Max Operating Temperature=125°C, Min Operating Temperature=-55°C, Package Quantity=1, Supplier Part Number 1=311-1027-1-ND, Tolerance=10%, Voltage Rating=50V
C635: library part Capacitor, Case/Package=0402, Case Code (Metric)=1005, Dielectric=X7R, Manufacturer=Yageo, Manufacturer Part Number=CC0402KRX7R9BB682, Max Operating Temperature=125°C, Min Operating Temperature=-55°C, Supplier Part Number 1=311-1726-1-ND, Tolerance=10%, Voltage=50V
C637 C638 C645 C646: library part Capacitor, "CAP CER 1200PF 50V X7R 0402", Case Code (Imperial)=0402, Case Code (Metric)=1005, Dielectric=X7R, Manufacturer=Yageo, Manufacturer Part Number=CC0402KRX7R9BB122, Max Operating Temperature=125°C, Min Operating Temperature=-55°C, Package Quantity=1, Supplier Part Number 1=311-1031-1-ND, Tolerance=10%, Voltage Rating=50V
C639 C640 C647 C648: library part Capacitor, Case/Package=0402, Case Code (Metric)=1005, Dielectric=X7R, Insulation Resistance=10GR, Manufacturer=Yageo, Manufacturer Part Number=CC0402KRX7R8BB473, Max Operating Temperature=125°C, Min Operating Temperature=-55°C, Supplier Part Number 1=311-1717-1-ND, Tolerance=10%, Voltage Rating=25V
C641: library part Capacitor, Case/Package=0402, Dielectric=X7R, Dielectric Material=Ceramic, Manufacturer=KEMET, Manufacturer Part Number=C0402C471K5RACTU, Max Operating Temperature=125°C, Min Operating Temperature=-55°C, Supplier Part Number 1=399-1025-1-ND, Tolerance=10%, Voltage=50V
C642: library part Capacitor, Case/Package=0402, Case Code (Metric)=1005, Dielectric=C0G, Manufacturer=Yageo, Manufacturer Part Number=CC0402JRNPO9BN560, Max Operating Temperature=125°C, Min Operating Temperature=-55°C, Package Quantity=1, Supplier Part Number 1=311-1022-1-ND, Tolerance=5%, Voltage Rating=50V
C643: library part Capacitor, Case/Package=0402, Case Code (Metric)=1005, Dielectric=X7R, Manufacturer=Yageo, Manufacturer Part Number=CC0402KRX7R7BB822, Max Operating Temperature=125°C, Min Operating Temperature=-55°C, Package Quantity=1, Supplier Part Number 1=311-1041-1-ND, Tolerance=10%, Voltage Rating=16V
C644: library part Capacitor, Case/Package=0402, Case Code (Metric)=1005, Dielectric=X7R, Manufacturer=Yageo, Manufacturer Part Number=CC0402KRX7R9BB821, Max Operating Temperature=125°C, Min Operating Temperature=-55°C, Package Quantity=10000, Supplier Part Number 1=311-1727-1-ND, Tolerance=10%, Voltage=50V
C650: library part Capacitor, Case/Package=0402, Case Code (Metric)=1005, Dielectric=C0G, Manufacturer=Yageo, Manufacturer Part Number=CC0402JRNPO9BN181, Max Operating Temperature=125°C, Min Operating Temperature=-55°C, Supplier Part Number 1=311-1663-1-ND, Tolerance=5%, Voltage Rating=50V
C652: library part Capacitor, Case/Package=0402, Case Code (Metric)=1005, Dielectric=X7R, Manufacturer=Yageo, Manufacturer Part Number=CC0402KRX7R7BB222, Max Operating Temperature=125°C, Min Operating Temperature=-55°C, Package Quantity=10000, Supplier Part Number 1=311-1707-1-ND, Tolerance=10%, Voltage Rating=16V
C655 C656 C657: library part Capacitor, Case/Package=0402, Case Code (Metric)=1005, Dielectric=X7R, Manufacturer=Yageo, Manufacturer Part Number=CC0402KRX7R8BB562, Max Operating Temperature=125°C, Min Operating Temperature=-55°C, Supplier Part Number 1=311-1718-1-ND, Tolerance=10%, Voltage Rating=25V
C674 C675 C676 C782 C784 C786 C788: library part Capacitor, "0402 10 V 4.7 uF ±20% Tolerance X5R Multilayer Ceramic Chip Capacitor", Case/Package=0402, Case Code (Metric)=1005, Manufacturer=Murata, Manufacturer Part Number=GRM155R61A475MEAAD, Max Operating Temperature=85°C, Min Operating Temperature=-55°C, Supplier Part Number 1=490-14306-1-ND, Tolerance=20%, Voltage Rating=10V
C678 C679: library part Capacitor, "Cap Ceramic 100uF 6.3V X6T 20% Pad SMD 1206 105C T/R", Case Code (Imperial)=1206, Case Code (Metric)=3216, Dielectric=X6T, Dielectric Material=Ceramic, Manufacturer=Murata, Manufacturer Part Number=GRM31CD80J107ME39L, Max Operating Temperature=105°C, Min Operating Temperature=-55°C, Package Quantity=2000, Supplier Part Number 1=490-10525-1-ND, Tolerance=20%, Voltage=6.3V
C694: library part Capacitor, "0603 4.7 uF 35 V ±10% Tolerance X5R Multilayer Ceramic Chip Capacitor", Case/Package=0603, Case Code (Metric)=1608, Dielectric=X5R, Manufacturer=Murata, Manufacturer Part Number=GRM188R6YA475KE15D, Max Operating Temperature=85°C, Min Operating Temperature=-55°C, Package Quantity=4000, Supplier Part Number 1=490-7205-6-ND, Tolerance=10%, Voltage=35V
C701: library part Capacitor, "CAP, MLCC, X7R, 0.012UF, 16V, 0402; Product Range:C Series; Capacitance:0.012 F; Capacitance Tolerance: 10%; Dielectric Characteristic:X7R; Voltage Rating:16V; Ceramic Capacitor Case:0402 [1005 Metric]; Operating Temperature ;RoHS Compliant: Yes", Case/Package=0402, Case Code (Metric)=1005, Dielectric=X7R, Dielectric Material=Ceramic, Manufacturer=KEMET, Manufacturer Part Number=C0402C123K4RACTU, Max Operating Temperature=125°C, Min Operating Temperature=-55°C, Package Quantity=1, Supplier Part Number 1=399-4875-1-ND, Tolerance=10%, Voltage=16V
C702: library part Capacitor, "Ceramic Capacitor 36PF 50V, C0G, 5%, 0402, Full Reel", Case/Package=0402, Case Code (Metric)=1005, Dielectric=C0G, Manufacturer="Kyocera AVX", Manufacturer Part Number=04025A360JAT2A, Max Operating Temperature=125°C, Min Operating Temperature=-55°C, Package Quantity=10000, Supplier Part Number 1=478-10099-1-ND, Tolerance=5%, Voltage Rating=50V
C703: library part Capacitor, "Cap Ceramic 0.015uF 25V X7R 10% SMD 0402 125C Paper T/R", Case/Package=0402, Case Code (Metric)=1005, Dielectric=X7R, Manufacturer=Yageo, Manufacturer Part Number=CC0402KRX7R8BB153, Max Operating Temperature=125°C, Min Operating Temperature=-55°C, Supplier Part Number 1=311-1713-1-ND, Tolerance=10%, Voltage Rating=25V
C704: library part Capacitor, "Cap Ceramic 1uF 10V X5R 10% SMD 0603 85C Paper T/R", Case/Package=0603, Case Code (Metric)=1608, Dielectric=X5R, Manufacturer=Samsung, Manufacturer Part Number=CL10A105KP8NNNC, Max Operating Temperature=85°C, Min Operating Temperature=-55°C, Package Quantity=1, Supplier Part Number 1=1276-1182-1-ND, Tolerance=10%, Voltage=10V
C714: library part Capacitor, "CAP CER 0.33UF 25V Y5V 0603", Case Code (Imperial)=0603, Case Code (Metric)=1608, Dielectric=Y5V, Dielectric Material=Ceramic, Manufacturer=KEMET, Manufacturer Part Number=C0603C334Z3VACTU, Max Operating Temperature=85°C, Min Operating Temperature=-30°C, Package Quantity=1, Supplier Part Number 1=399-1292-1-ND, Tolerance=80%, Voltage Rating=25V
C736 C737: library part Capacitor, Case/Package=0201, Case Code (Metric)=0603, Manufacturer=Murata, Manufacturer Part Number=GRM0335C1E9R0CA01D, Max Operating Temperature=125°C, Min Operating Temperature=-55°C, Package Quantity=15000, Supplier Part Number 1=490-16718-1-ND, Voltage Rating=25V
C738: "CAP TANT POLY 680UF 6.3V 2917", Capacitance=680uF, Case/Package=2917, Case Code (Metric)=7343, ESR (Equivalent Series Resistance)=18mR, Leakage Current=428.4uA, Manufacturer=Panasonic, Max Operating Temperature=105°C, Min Operating Temperature=-55°C, Package Quantity=1, Ripple Current=3.5A, Supplier Part Number 1=P16633CT-ND, Tolerance=20%, Voltage=6.3V
C739 C742 C747 C751 C753 C757 C760 C762 C764: library part Capacitor, Case/Package=1210, Case Code (Metric)=3225, Dielectric=X7U, Manufacturer=Murata, Manufacturer Part Number=GRM32EE70G107ME19L, Max Operating Temperature=125°C, Min Operating Temperature=-55°C, Package Quantity=1, Supplier Part Number 1=490-6534-1-ND, Tolerance=20%, Voltage Rating=4V
C740 C741 C743 C745 C746 C748 C750 C752 C754 C755 C758 C761 C763 C765: library part Capacitor, Case/Package=0402, Case Code (Metric)=1005, Manufacturer=Murata, Manufacturer Part Number=GRM155R61A475MEAAD, Max Operating Temperature=85°C, Min Operating Temperature=-55°C, Supplier Part Number 1=490-14306-1-ND, Tolerance=20%, Voltage Rating=10V
C744 C749 C756 C759: library part Capacitor, Case/Package=1206, Case Code (Metric)=3216, Dielectric=X5R, Dielectric Material=Ceramic, Manufacturer=KEMET, Manufacturer Part Number=C1206C476M8PACTU, Max Operating Temperature=85°C, Min Operating Temperature=-55°C, Package Quantity=1, Supplier Part Number 1=399-5508-1-ND, Tolerance=20%, Voltage=10V
C781: library part Capacitor, "CAP CER 4.7UF 25V X5R 0805", Case/Package=0805, Case Code (Metric)=2012, Dielectric=X5R, Manufacturer=Murata, Manufacturer Part Number=GRM219R61E475KA73D, Max Operating Temperature=85°C, Min Operating Temperature=-55°C, Package Quantity=4000, Supplier Part Number 1=490-12753-1-ND, Tolerance=10%, Voltage Rating=25V
D1 D2: library part SLVU2.8-4BTG, "ESD Suppressor TVS ±30KV 8-Pin SOIC T/R", Breakdown Voltage=3V, Capacitance=2.5pF, Case/Package=SOIC, Clamping Voltage=15V, Leakage Current=1uA, Manufacturer=Littelfuse, Max Operating Temperature=85°C, Max Power Dissipation=600W, Min Operating Temperature=-40°C, Operating Supply Voltage=2.8V, Package Quantity=2500, Peak Pulse Current=40A, Power Line Protection=No, Supplier Part Number 1=F4206CT-ND
D3 D4: "DIODE BRIDGE 100V 2A SDIP", Case/Package=SMD/SMT, Forward Current=2A, Forward Voltage=1.1V, Manufacturer="ON Semiconductor / Fairchild", Max Forward Surge Current (Ifsm)=85A, Max Operating Temperature=150°C, Max Repetitive Reverse Voltage (Vrrm)=100V, Min Operating Temperature=-55°C, Package Quantity=1500, Peak Reverse Current=3uA, Reverse Voltage (DC)=70V, Supplier Part Number 1=DF01S2CT-ND
D5 D6 D7 D8 D9 D10: "LED,  LTST-C190GKT", Case/Package=0603, Case Code (Metric)=1608, Color=Green, Forward Current=30mA, Forward Voltage=2.1V, Lens Color=Colorless, Manufacturer 1="Vishay Lite-On", Max Operating Temperature=85°C, Min Operating Temperature=-55°C, Package Quantity=1, Power Dissipation=100mW, Reverse Voltage=5V, Supplier Part Number 1=160-1183-1-ND, Test Current=10mA, Voltage=2V
D11 D12: "DIODE SCHOTTKY 30V 200MA SOD123", Average Rectified Current=200mA, Capacitance=10pF, Case/Package=SOD-123-2, Forward Voltage=350mV, Manufacturer="ON Semiconductor", Max Forward Surge Current (Ifsm)=600mA, Max Operating Temperature=125°C, Max Repetitive Reverse Voltage (Vrrm)=30V, Max Reverse Leakage Current=2uA, Min Operating Temperature=-55°C, Package Quantity=3000, Power Dissipation=400mW, Supplier Part Number 1=BAT54T1GOSCT-ND
D13 D15: "TVS DIODE 5.5V 8V SOT3", Breakdown Voltage=9V, Capacitance=0.8pF, Case/Package=SOT, Clamping Voltage=8V, Manufacturer="Texas Instruments", Max Operating Temperature=85°C, Min Operating Temperature=-40°C, Package Quantity=1, Peak Pulse Current=1A, Peak Pulse Power=45W, Power Line Protection=Yes, Reverse Standoff Voltage=5.5V, Supplier Part Number 1=296-25509-1-ND, Test Current=1mA
D14: "TVS DIODE 5.5V 8V 10SON", Breakdown Voltage=7V, Capacitance=0.8pF, Clamping Voltage=8V, Current Rating=5A, Manufacturer="Texas Instruments", Max Operating Temperature=85°C, Min Operating Temperature=-40°C, Package Quantity=1, Peak Pulse Current=1A, Peak Pulse Power=45W, Power Line Protection=Yes, Reverse Standoff Voltage=5.5V, Supplier Part Number 1=296-28063-1-ND
D16 D17 D18 D19: library part MBRM140T1G, Supplier Part Number 1=MBRM140T3GOSCT-ND
D20 D21 D23 D24: "DIODE GEN PURP 1KV 1A SMA", Average Rectified Current=1A, Capacitance=10pF, Case/Package=SMA, Forward Voltage="Vf {} 1.1V", Manufacturer=Diodes, Max Forward Surge Current (Ifsm)=30A, Max Operating Temperature=150°C, Max Repetitive Reverse Voltage (Vrrm)=1kV, Min Operating Temperature=-65°C, Package Quantity=5000, Peak Reverse Current=5uA, Supplier Part Number 1=S1M-FDICT-ND
D22 D25 D29 D30 D31 D32 D33 D34 D35 D36 D37 D38 D39 D40 D41 D42 D43 D44 D45 D46 D47 D48 D49 D50 D51 D52 D53: "LED,  LTST-C190GKT", Case Code (Imperial)=0603, Case Code (Metric)=1608, Color=Green, Forward Current=30mA, Forward Voltage=2.1V, Lens Color=Colorless, Manufacturer 1="Vishay Lite-On", Max Operating Temperature=85°C, Min Operating Temperature=-55°C, Package Quantity=1, Power Dissipation=100mW, Reverse Voltage=5V, Supplier Part Number 1=160-1183-1-ND, Test Current=10mA, Voltage=2V
D26 D27: "DIODE SCHOTTKY 100V POWERDI123", Average Rectified Current=1A, Capacitance=36pF, Forward Voltage=770mV, Manufacturer=Diodes, Max Forward Surge Current (Ifsm)=40A, Max Operating Temperature=175°C, Max Repetitive Reverse Voltage (Vrrm)=100V, Min Operating Temperature=-55°C, Package Quantity=3000, Peak Non-Repetitive Surge Current=50A, Peak Reverse Current=1uA, Supplier Part Number 1=DFLS1100DICT-ND
D28: "DIODE ARRAY SCHOTTKY 40V SOT23", Average Rectified Current=200mA, Capacitance=5pF, Case/Package=SOT-23, Forward Voltage=1V, Manufacturer=MCC, Max Forward Surge Current (Ifsm)=600mA, Max Operating Temperature=125°C, Max Repetitive Reverse Voltage (Vrrm)=40V, Max Reverse Leakage Current=200nA, Min Operating Temperature=-55°C, Package Quantity=3000, Power Dissipation=200mW, Supplier Part Number 1=BAS40-04TPMSCT-ND
F1_PCIE0 F1_PCIE1 F1_PCIE2 F1_PCIE3 F1_PCIE4: library part Resistor, "FUSE BOARD MNT 500MA 32VDC 0805", Case/Package=SMD/SMT, Case Code (Imperial)=0805, Case Code (Metric)=2012, Current Rating=500mA, DC Cold Resistance=570mR, Manufacturer=Vishay, Manufacturer Part Number=MFU0805FF00500P100, Max Operating Temperature=125°C, Min Operating Temperature=-55°C, Package Quantity=1000, Supplier Part Number 1=MFU0805.50CT-ND, Voltage Rating (DC)=32V
FB3 FB5 FB6 FB7 FB26 FB27 FB28 FB29 FB31 FB32 FB35 FB43 FB44: library part Ferrite, "FERRITE BEAD 220 OHM 0603 1LN", Case/Package=0603, Case Code (Metric)=1608, Current Rating=2.5A, DC Resistance (DCR)=40mR, Manufacturer=Murata, Manufacturer Part Number=BLM18SG221TN1D, Max Operating Temperature=125°C, Min Operating Temperature=-55°C, Package Quantity=1, Supplier Part Number 1=490-5225-1-ND, Test Frequency=100MHz, Tolerance=25%
FB8 FB9 FB10 FB11 FB12 FB13 FB14 FB15 FB16 FB17 FB18 FB19 FB20 FB21 FB22 FB36 FB37: library part Ferrite, "FERRITE BEAD 220 OHM 0603 1LN", Case Code (Imperial)=0603, Case Code (Metric)=1608, Current Rating=2.5A, DC Resistance (DCR)=40mR, Manufacturer=Murata, Manufacturer Part Number=BLM18SG221TN1D, Max Operating Temperature=125°C, Min Operating Temperature=-55°C, Package Quantity=1, Supplier Part Number 1=490-5225-1-ND, Test Frequency=100MHz, Tolerance=25%
FB23 FB25: "SMT Ferrite Chip", Case/Package=0603, Case Code (Metric)=1608, Current Rating=1.7A, DC Resistance (DCR)=80mR, Manufacturer=TDK, Manufacturer Part Number=MPZ1608S331ATA00, Package Quantity=1, Supplier Part Number 1=445-5221-1-ND, Tolerance=25%
FB24: "SMT Ferrite Chip", Case Code (Imperial)=0603, Case Code (Metric)=1608, Current Rating=1.7A, DC Resistance (DCR)=80mR, Manufacturer=TDK, Manufacturer Part Number=MPZ1608S331ATA00, Package Quantity=1, Supplier Part Number 1=445-5221-1-ND, Tolerance=25%
FB33 FB45: library part Ferrite, "Ind Chip Bead 120Ohm 25% 100MHz Ferrite 3A 0603 Paper T/R", Case/Package=0603, Case Code (Metric)=1608, Current Rating=3A, DC Resistance (DCR)=25mR, Frequency=100MHz, Manufacturer=Murata, Manufacturer Part Number=BLM18SG121TN1D, Max Operating Temperature=125°C, Min Operating Temperature=-55°C, Package Quantity=1, Supplier Part Number 1=1515752, Tolerance=25%
FB34: library part Ferrite, "Ferrite Beads Power Chip 330Ohm 25% 100MHz 800mA 210mOhm DCR 0603 Automotive T/R", Case Code (Imperial)=0603, Case Code (Metric)=1608, DC Resistance (DCR)=210mR, Frequency=100MHz, Manufacturer="Taiyo Yuden", Manufacturer Part Number=FBMH1608HL331-T, Max Current Rating=800mA, Max DC Current=600mA, Max Operating Temperature=125°C, Min Operating Temperature=-40°C, Package Quantity=1, Supplier Part Number 1=587-1734-1-ND, Tolerance=25%
FB38 FB39 FB40 FB41: library part Ferrite, "FERRITE BEAD 600 OHM 0805 1LN", Case Code (Imperial)=0805, Case Code (Metric)=2012, Current Rating=500mA, DC Resistance (DCR)=300mR, Frequency=100MHz, Manufacturer=Laird, Manufacturer Part Number=HZ0805E601R-10, Max Operating Temperature=125°C, Min Operating Temperature=-40°C, Package Quantity=1, Supplier Part Number 1=240-2399-1-ND
FB42: library part Ferrite, "Ind Chip Bead 120Ohm 25% 100MHz Ferrite 3A 0603 Paper T/R", Case Code (Imperial)=0603, Case Code (Metric)=1608, Current Rating=3A, DC Resistance (DCR)=25mR, Frequency=100MHz, Manufacturer=Murata, Manufacturer Part Number=BLM18SG121TN1D, Max Operating Temperature=125°C, Min Operating Temperature=-55°C, Package Quantity=1, Supplier Part Number 1=1515752, Tolerance=25%
FID1 FID2 FID3 FID4 FID5 FID6 FID7 FID8: library part Fid
J1_PCIE0 J1_PCIE1 J1_PCIE2 J1_PCIE3 J1_PCIE4: "PCI Express / PCI Connectors Mini PCI-E 6.8H G/F", Flammability Rating="UL94 V-0", High Temperature Housing=Yes, Housing Color=Black, Manufacturer="TE Connectivity AMP", Max Operating Temperature=85°C, Min Operating Temperature=-55°C, Package Quantity=450, Supplier Part Number 1=A125147CT-ND
J2 J3 J4 J5 J6 J7: "Ultra Miniature Coaxial Connector Jack, 60 V, 50 Ohm, -40 to 90 degC, RoHS, Tape and Reel", Maximum Frequency="6 GHz", Operating Temperature Range="- 40 C to + 90 C", Supplier Part Number 1=62X0488
J12 J13 J15 J16 J17 J19 J20 J21 J22 J23 J24 J29 J30 J36: library part "2 Pin", Color=White, Contact Resistance=20mR, Current Rating=4A, Flammability Rating="UL94 V-0", Housing Color=Natural, Insulation Resistance=50GR, Manufacturer=Molex, Manufacturer Part Number=22-27-2021, Max Operating Temperature=75°C, Min Operating Temperature=0°C, Package Quantity=24000, Supplier Part Number 1=0022272021, Voltage Rating=250V
J14 J18: "JST (JAPAN SOLDERLESS TERMINALS) - B7B-XH-A (LF)(SN) - HEADER, VERTICAL, 7WAY", Color=Natural, Contact Resistance=20mR, Current Rating=3A, Flammability Rating="UL94 V-0", Housing Color=White, Insulation Resistance=1GR, Manufacturer=JST, Manufacturer Part Number=B7B-XH-A(LF)(SN), Max Operating Temperature=85°C, Max Voltage Rating (AC)=250V, Min Operating Temperature=-25°C, Supplier Part Number 1=1516283
J25: library part "4 Pin", Color=Natural, Contact Resistance=20mR, Current Rating=3A, Housing Color=White, Insulation Resistance=1GR, Manufacturer=JST, Manufacturer Part Number=B4B-XH-A(LF)(SN), Max Operating Temperature=85°C, Max Voltage Rating (AC)=250V, Min Operating Temperature=-25°C, Package Quantity=500, Supplier Part Number 1=73M9436
J26: "SMA Connector, Pitch 5.08 mm, 1 Position, Height 9.5 mm, Tail Length 4 mm, -65 to 165 degC, RoHS, Bulk", Frequency Max=3GHz, Supplier Part Number 1=78M7270
J27: library part 1-2199230-6_CHINA, "CONN EDGE DUAL FMALE 67POS 0.020", Contact Current Rating=500mA, Housing Color=Black, Manufacturer 1="TE Connectivity", Manufacturer Part Number 1=1-2199230-6, Package Quantity=1, Supplier Part Number 1=A118046CT-ND
J28: "WR-CRD Micro SD Card Connector Push & Push", Contact Resistance=100mOhm, Operating Temperature="-40 to +85degC", Rated Current=0.5A, Withstanding Voltage=500VAC, Working Voltage=30VAC
J31: library part 2007132, Flammability Rating="UL94 V-0", Manufacturer="TE Connectivity", Manufacturer Part Number=2007132-1, Package Quantity=16, Supplier Part Number 1=A97939-ND
J32 J33 J34 J35: "Conn zSFP+ F 20 POS 0.8mm Solder RA SMD 20 Terminal 1 Port zSFP+™ Reel", Current Rating=500mA, Flammability Rating="UL94 V-0", Housing Color=Black, Manufacturer=Molex, Max Operating Temperature=85°C, Max Voltage Rating (AC)=120V, Min Operating Temperature=-40°C, Package Quantity=960, Supplier Part Number 1=WM6178CT-ND
L1 L2 L3 L4 L5 L6 L7 L8: "Ind Power Shielded Wirewound 4.7uH 20% 100KHz Ferrite 1.7A Embossed T/R", Case/Package=Nonstandard, Current Rating=1.7A, DC Resistance (DCR)=84mR, Inductance=4.7uH, Manufacturer="Taiyo Yuden", Max Operating Temperature=125°C, Min Operating Temperature=-40°C, Package Quantity=3500, Ratings=AEC-Q200, Saturation Current=2A, Self Resonant Frequency=35MHz, Supplier Part Number 1=587-3578-1-ND, Test Frequency=100kHz, Tolerance=20%
L9 L10: "220nH Shielded Molded Inductor 25A 1.9mOhm Max Nonstandard", Inductance=220nH@25A, Manufacturer 1=Laird, Supplier Part Number 1=240-3179-1-ND
L11: "1.2µH Shielded Molded Inductor 17A 3.8mOhm Max Nonstandard", Inductance=1.2uH@17A, Manufacturer 1=Laird, Supplier Part Number 1=240-3187-1-ND
L12: "Wurth WE-LHMI Series Shielded Wire-wound SMD Inductor with a Iron Core, 0.68 µH Moulded 14A Idc", Case/Package=Nonstandard, Current Rating=14A, DC Resistance (DCR)=3.99mR, Inductance=680nH, Manufacturer 1="Wurth Electronics", Max Operating Temperature=125°C, Min Operating Temperature=-40°C, Saturation Current=32.5A, Self Resonant Frequency=53MHz, Supplier Part Number 1=732-7217-1-ND, Test Frequency=100kHz, Tolerance=20%
L13 L17: Inductance [µH]=8.2, Part Number=CDRH5D28NP-8R2, Supplier Part Number 1=308-2309-1-ND
L15: library part Inductor, Manufacturer=TDK, Manufacturer Part Number=MLZ1608N6R8LT000, Supplier Part Number 1=445-MLZ1608N6R8LT000CT-ND
L16: Inductance="4.2 µH", Supplier Part Number 1=308-1802-1-ND
L18: "Fixed Inductors 3.3uH 1.57A 30% SMD LP INDUCTOR", Case/Package=Nonstandard, Current Rating=1.57A, DC Resistance (DCR)=49.2mR, Inductance=3.3uH, Manufacturer=Sumida, Max Operating Temperature=100°C, Min Operating Temperature=-40°C, Package Quantity=2000, Supplier Part Number 1=308-2184-1-ND, Test Frequency=100kHz, Tolerance=30%
L19: library part 7843330330, "WE-CHSA SMT High Current Inductor, size 1011, 3.3uH, 13.8A", DC Resistance max.=6.5mOhm, Inductance=3.3uH, Operating Temperature="-55 to +150degC", Rated Current=13.8A, Saturation Current=20.5A, Self Resonant Frequency=55MHz
L20: library part 7443340150, "SMT High Current Cube Inductor WE-HCC, size 8070, 1.5 uH, 16.5 A", DC Resistance max.="5.6 mOhm", Inductance="1.5 uH", Operating Temperature="-40 to +125 degC", Rated Current="16.5 A", Saturation Current="18.5 A", Self Resonant Frequency="120 MHz"
L22: "Inductor Power Shielded Wirewound 22uH 20% 100KHz 20Q-Factor Carbonyl Powder 9A 37mOhm DCR Automotive T/R", Case/Package=Nonstandard, Current Rating=9A, DC Resistance (DCR)=37mR, Inductance=22uH, Inductance Tolerance=20%, Manufacturer=Bourns, Max Operating Temperature=150°C, Min Operating Temperature=-40°C, Ratings=AEC-Q200, Saturation Current=12A, Self Resonant Frequency=6MHz, Supplier Part Number 1=SRP1265A-220MCT-ND, Test Frequency=100kHz
MH1 MH2 MH3 MH4 MH5 MH6 MH7 MH8 MH9 MH10 MH11 MH12 MH13 MH14 MH15 MH16 MH17 MH18 MH19 MH20 MH21 MH22 MH23 MH24 MH25: "Mounting Holes_5_3.2"
MP1_PCIE0 MP1_PCIE1 MP1_PCIE2 MP1_PCIE3 MP1_PCIE4 MP2_PCIE0 MP2_PCIE1 MP2_PCIE2 MP2_PCIE3 MP2_PCIE4 MP3_PCIE0 MP3_PCIE1 MP3_PCIE2 MP3_PCIE3 MP3_PCIE4 MP4_PCIE0 MP4_PCIE1 MP4_PCIE2 MP4_PCIE3 MP4_PCIE4: library part 9774045243R, "WA-SMSI SMT Steel Spacer, OD4.35mm, M2x4.5mm", Operating Temperature="-55 to +150degC"
MP5: library part 9774025243R, "WA-SMSI SMT Steel Spacer, OD4.35mm, M2x2.5mm", Operating Temperature="-55 to +150degC"
P1 P13: "CONN HEADER VERT 3POS 2.54MM", Color=Beige,White, Contact Current Rating=5A, Contact Resistance=6mR, Flammability Rating="UL94 V-0", Housing Color=Natural, Manufacturer="TE Connectivity", Manufacturer Part Number=640456-3, Max Operating Temperature=221°C, Max Voltage Rating (AC)=250V, Min Operating Temperature=-67°C, Package Quantity=5000, Supplier Part Number 1=A19470-ND
P2: "Header, 4-Pin"
P3 P4 P5 P11: "00000005000HDR ASSY F/L SQ STR", Color=Natural,White,Beige, Contact Current Rating=5A, Contact Resistance=6mR, Flammability Rating="UL94 V-0", Housing Color=Natural, Manufacturer="TE Connectivity", Manufacturer Part Number=640456-2, Max Operating Temperature=221°C, Max Voltage Rating (AC)=250V, Min Operating Temperature=-67°C, Package Quantity=5000, Supplier Part Number 1=26AC8457
P6: "Male Header, Pitch 2.54 mm, 1 x 2 Position, Height 10.49 mm, Tail Length 3.556 mm, -55 to 105 degC, RoHS, Bulk", Color=White, Current, Rating="5  A", Flammability Rating=UL94V-0, Supplier Part Number 1=A1921-ND, Temperature, Operating="-55 to +105  °C", Voltage, Rating="250  V"
P12: "SAMTEC         HTSW-107-08-T-D-RA             Board-To-Board Connector, Right Angle, HTSW Series, 14 Contacts, Header, 2.54 mm, Through Hole", Housing Color=Natural, Manufacturer=Samtec, Manufacturer Part Number=HTSW-107-08-T-D-RA, Max Current Rating=7.6A, Max Operating Temperature=105°C, Max Voltage Rating (AC)=450V, Min Operating Temperature=-55°C, Supplier Part Number 1=HTSW-107-08-T-D-RA-ND
R1 R2 R71 R72 R73 R74 R75 R91 R92 R93 R94 R130 R131 R132 R133 R134 R139 R141 R142 R143 R144 R151 R152 R153 R154 R161 R162 R163 R164 R242 R244 R279 R282 R283 R286 R293 R294 R310 R312 R345 R376 R377 R378 R395 R398 R400 R402 R403 R404 R405 R406 R407 R408 R409 R411 R412 R413 R414 R415 R416 R418 R421 R425_SPI_bridge_Main R425_SPI_bridge_PCIe R426_SPI_bridge_Main R426_SPI_bridge_PCIe R481 R498 R506 R507 R514 R530 R540 R547 R550 R553 R556 R602_SPI_bridge_Main R602_SPI_bridge_PCIe R603_SPI_bridge_Main R603_SPI_bridge_PCIe R604_SPI_bridge_Main R604_SPI_bridge_PCIe R605_SPI_bridge_Main R605_SPI_bridge_PCIe R606_SPI_bridge_Main R606_SPI_bridge_PCIe R618 R636 R637 R638 R639 R640 R641 R642 R643 R665 R669 R670 R675 R688 R692 R693 R696 R698 R700 R702 R711 R712 R713 R722 R723 R724 R725 R726 R727 R728 R729 R744 R759 R761 R763 R767 R768 R769 R770 R771 R772 R773 R774 R775 R776 R777 R778 R779 R780 R781 R782 R783 R784 R785 R786 R787 R788 R789 R790 R791 R792 R793 R794 R795 R796 R797 R798 R799 R800 R801 R802 R803 R804 R805 R806 R807 R808 R809 R810 R811 R812 R813 R814 R815 R816 R819 R822 R845 R851 R854 R857 R860 R862 R863 R864 R865 R866 R867 R868 R869 R870 R871 R872 R873 R874 R875 R876 R877 R878 R879 R880 R881 R882 R883 R884 R885 R886 R887_SPI_bridge_Main R887_SPI_bridge_PCIe R888_SPI_bridge_Main R888_SPI_bridge_PCIe R889_SPI_bridge_Main R889_SPI_bridge_PCIe R890_SPI_bridge_Main R890_SPI_bridge_PCIe R891_SPI_bridge_Main R891_SPI_bridge_PCIe R892_SPI_bridge_Main R892_SPI_bridge_PCIe R893_SPI_bridge_Main R893_SPI_bridge_PCIe R894_SPI_bridge_Main R894_SPI_bridge_PCIe R895_SPI_bridge_Main R895_SPI_bridge_PCIe R896_SPI_bridge_Main R896_SPI_bridge_PCIe R897_SPI_bridge_Main R897_SPI_bridge_PCIe R898_SPI_bridge_Main R898_SPI_bridge_PCIe R899_SPI_bridge_Main R899_SPI_bridge_PCIe R900 R901 R902 R903 R904 R905 R906 R907 R908 R909 R910 R911 R912 R918 R919 R961 R962 R963 R964 R965 R966 R967 R968 R969 R970 R971 R972 R973 R974 R975 R976 R977 R978 R979 R980 R981 R982 R983 R984 R985 R986 R987 R988 R989 R990 R991 R992 R993 R994 R995 R996 R997 R998 R999 R1000 R1001 R1004 R1005 R1006 R1007 R1008 R1009 R1010 R1011 R1012 R1013 R1014 R1015 R1016 R1017 R1018 R1019 R1020 R1021 R1022 R1023 R1024 R1025 R1026 R1027 R1028 R1029 R1030 R1031 R1032 R1033 R1034 R1035 R1036 R1037 R1038 R1039 R1040 R1041 R1042 R1043 R1044 R1045 R1046 R1047: library part Resistor, Case/Package=0402, Case Code (Metric)=1005, Manufacturer 1=Yageo, Manufacturer Part Number 1=RC0402JR-070RL, Max Operating Temperature=155°C, Max Power Dissipation=63mW, Min Operating Temperature=-55°C, Package Quantity=1, Power Rating=62.5mW, Supplier Part Number 1=311-0.0JRCT-ND, Temperature Coefficient=200ppm/°C, Tolerance=5%, Voltage Rating=50V
R3_I2C_Bridge_GPIO R3_I2C_Bridge_PCIE R3_I2C_Bridge_SFP R4_I2C_Bridge_GPIO R4_I2C_Bridge_PCIE R4_I2C_Bridge_SFP R5_I2C_Bridge_GPIO R5_I2C_Bridge_PCIE R5_I2C_Bridge_SFP R6_I2C_Bridge_GPIO R6_I2C_Bridge_PCIE R6_I2C_Bridge_SFP R7_I2C_Bridge_GPIO R7_I2C_Bridge_PCIE R7_I2C_Bridge_SFP R8_I2C_Bridge_GPIO R8_I2C_Bridge_PCIE R8_I2C_Bridge_SFP R9_I2C_Bridge_GPIO R9_I2C_Bridge_PCIE R9_I2C_Bridge_SFP R10_I2C_Bridge_GPIO R10_I2C_Bridge_PCIE R10_I2C_Bridge_SFP R60 R106 R109 R124 R223_I2C_Bridge_GPIO R223_I2C_Bridge_PCIE R223_I2C_Bridge_SFP R224_I2C_Bridge_GPIO R224_I2C_Bridge_PCIE R224_I2C_Bridge_SFP R225_I2C_Bridge_GPIO R225_I2C_Bridge_PCIE R225_I2C_Bridge_SFP R226_I2C_Bridge_GPIO R226_I2C_Bridge_PCIE R226_I2C_Bridge_SFP R227_I2C_Bridge_GPIO R227_I2C_Bridge_PCIE R227_I2C_Bridge_SFP R558_I2C_Bridge_GPIO R558_I2C_Bridge_PCIE R558_I2C_Bridge_SFP R559_I2C_Bridge_GPIO R559_I2C_Bridge_PCIE R559_I2C_Bridge_SFP R560_I2C_Bridge_GPIO R560_I2C_Bridge_PCIE R560_I2C_Bridge_SFP: library part Resistor, "PANASONIC - ERJ-2RKF1001X - SMD Chip Resistor, 0402 [1005 Metric], 1 kohm, ERJ2R Series, 50 V, Thick Film, 100 mW", Case/Package=0402, Case Code (Metric)=1005, Manufacturer=Panasonic, Manufacturer Part Number=ERJ-2RKF1001X, Max Operating Temperature=155°C, Max Power Dissipation=100mW, Min Operating Temperature=-55°C, Package Quantity=1, Supplier Part Number 1=P1.00KLDKR-ND, Temperature Coefficient=100ppm/°C, Tolerance=1%, Voltage Rating=50V
R11 R13 R29 R30 R127 R128 R129 R214 R218 R319 R320 R340 R343 R366 R369 R370 R371 R373 R490 R607 R630 R659 R660 R661 R662 R663 R664 R710 R715 R735 R736 R765 R766 R817 R818 R820 R821 R823 R824 R826 R827 R835 R836 R838 R847 R848 R849 R850 R852 R853 R855 R856 R858 R859 R861 R921 R922 R923 R924 R925 R926 R927 R928 R929 R930 R931 R932 R933 R934 R935 R936 R937 R938 R939 R940 R941 R942 R943 R944 R945 R946 R947 R948 R949 R950 R951 R952 R953 R954 R955 R956 R957 R958 R959 R960: library part Resistor, Case/Package=0402, Case Code (Metric)=1005, Manufacturer 1=Yageo, Manufacturer Part Number 1=RC0402FR-0710KL, Max Operating Temperature=155°C, Min Operating Temperature=-55°C, Power Rating=62.5mW, Supplier Part Number 1=311-10.0KLRCT-ND, Temperature Coefficient=100ppm/°C, Tolerance=1%, Voltage Rating=50V
R12 R15 R17 R20 R677 R678 R679 R680: library part Resistor, Case/Package=0402, Case Code (Metric)=1005, Manufacturer 1=Yageo, Manufacturer Part Number 1=RC0402FR-0795K3L, Max Operating Temperature=155°C, Max Power Dissipation=63mW, Min Operating Temperature=-55°C, Package Quantity=1, Power Rating=62.5mW, Supplier Part Number 1=311-95.3KLRCT-ND, Temperature Coefficient=100ppm/°C, Tolerance=1%, Voltage Rating=50V
R14 R16 R22 R24 R174 R175 R176 R177 R178 R179 R180 R181 R183 R184 R185 R186 R187 R188 R189 R190 R192 R193 R194 R195 R196 R197 R198 R199 R201 R202 R203 R204 R205 R206 R207 R208 R210 R211 R213 R215 R217 R219 R221 R222 R229 R230 R241 R243 R281 R304 R388 R389 R390 R449 R451 R453 R455 R457 R458 R459 R461 R462 R463 R465 R466 R467 R468 R469 R471 R473 R475 R477 R479 R492 R494 R496 R500 R502 R504 R508 R510 R512 R516 R518 R520 R524 R526 R528 R561 R562 R563 R564 R565 R566 R567 R568 R569 R570 R571 R572 R573 R574 R575 R576 R577 R578 R579 R580 R581 R582 R583 R584 R585 R586 R587 R588 R589 R590 R591 R592 R593 R594 R595 R596 R597 R598 R615 R697 R699 R701 R738 R739 R740 R741 R742 R743 R758 R760 R762: library part Resistor, "PANASONIC - ERJ-2RKF1001X - SMD Chip Resistor, 0402 [1005 Metric], 1 kohm, ERJ2R Series, 50 V, Thick Film, 100 mW", Case Code (Imperial)=0402, Case Code (Metric)=1005, Manufacturer=Panasonic, Manufacturer Part Number=ERJ-2RKF1001X, Max Operating Temperature=155°C, Max Power Dissipation=100mW, Min Operating Temperature=-55°C, Package Quantity=1, Supplier Part Number 1=P1.00KLDKR-ND, Temperature Coefficient=100ppm/°C, Tolerance=1%, Voltage Rating=50V
R18 R21 R667 R681: library part Resistor, "RES SMD 24.9KOHM 0.1% 1/16W 0402", Case/Package=0402, Case Code (Metric)=1005, Manufacturer=Panasonic, Manufacturer Part Number=ERA-2AEB2492X, Max Operating Temperature=155°C, Max Power Dissipation=63mW, Min Operating Temperature=-55°C, Package Quantity=1, Supplier Part Number 1=P24.9KDCCT-ND, Temperature Coefficient=25ppm/°C, Tolerance=0.1%, Voltage Rating=25V, Voltage Rating (DC)=50V
R19 R23 R25 R26 R683: library part Resistor, Case/Package=0402, Case Code (Metric)=1005, Manufacturer 1=Yageo, Manufacturer Part Number 1=RC0402FR-074K87L, Max Operating Temperature=155°C, Max Power Dissipation=63mW, Min Operating Temperature=-55°C, Power Rating=62.5mW, Supplier Part Number 1=YAG3175CT-ND, Temperature Coefficient=100ppm/°C, Tolerance=1%, Voltage Rating=50V
R27 R28 R182 R191 R200 R209 R228 R269: library part Resistor, Case/Package=0402, Case Code (Metric)=1005, Manufacturer=Panasonic, Manufacturer Part Number=ERJ-2RKF1021X, Max Operating Temperature=155°C, Max Power Dissipation=100mW, Min Operating Temperature=-55°C, Package Quantity=1, Supplier Part Number 1=P1.02KLCT-ND, Temperature Coefficient=100ppm/°C, Tolerance=1%, Voltage Rating=50V
R31 R32 R33 R34 R35 R36 R37 R38 R39 R40 R41 R42 R43 R44 R45 R46 R47 R48 R49 R50 R51 R53 R55 R57 R59: library part Resistor, Case/Package=0402, Case Code (Metric)=1005, Manufacturer=Panasonic, Manufacturer Part Number=ERJ-2RKF39R2X, Max Operating Temperature=155°C, Max Power Dissipation=100mW, Min Operating Temperature=-55°C, Package Quantity=1, Supplier Part Number 1=P39.2LCT-ND, Temperature Coefficient=100ppm/°C, Tolerance=1%, Voltage Rating=50V
R52 R54: library part Resistor, Case/Package=0402, Case Code (Metric)=1005, Manufacturer=Panasonic, Manufacturer Part Number=ERJ-2RKF36R0X, Max Operating Temperature=155°C, Max Power Dissipation=100mW, Min Operating Temperature=-55°C, Package Quantity=10000, Supplier Part Number 1=P36.0LCT-ND, Temperature Coefficient=100ppm/°C, Tolerance=1%, Voltage Rating=50V
R56: library part Resistor, "Resistor;  Thick Film;  Res 499 Ohms;  Pwr-Rtg 0.1 W;  Tol 1%;  SMT;  0402;  Tape & Reel", Case/Package=0402, Case Code (Metric)=1005, Manufacturer=Panasonic, Manufacturer Part Number=ERJ-2RKF4990X, Max Operating Temperature=155°C, Max Power Dissipation=100mW, Min Operating Temperature=-55°C, Package Quantity=1, Supplier Part Number 1=P499LCT-ND, Temperature Coefficient=100ppm/°C, Tolerance=1%, Voltage Rating=50V
R58 R99 R267 R276 R363 R364 R365 R381 R382 R730 R731 R732 R733 R734: library part Resistor, Case/Package=0402, Case Code (Metric)=1005, Manufacturer=Panasonic, Manufacturer Part Number=ERJ-2RKF4701X, Max Operating Temperature=155°C, Max Power Dissipation=100mW, Min Operating Temperature=-55°C, Package Quantity=1, Supplier Part Number 1=P4.70KLCT-ND, Temperature Coefficient=100ppm/°C, Tolerance=1%, Voltage Rating=50V
R61 R62 R63 R64 R920: library part Resistor, Case/Package=0402, Case Code (Metric)=1005, Manufacturer=Vishay, Manufacturer Part Number=CRCW0402240RFKED, Max Operating Temperature=155°C, Max Power Dissipation=63mW, Min Operating Temperature=-55°C, Package Quantity=10, Supplier Part Number 1=541-240LCT-ND, Temperature Coefficient=100ppm/°C, Tolerance=1%, Voltage Rating=50V
R65 R66 R67 R68 R83 R84 R85 R86 R97 R98 R123 R135 R136 R137 R138 R145 R146 R147 R148 R155 R156 R157 R158 R346 R347 R348 R349 R350 R351 R352 R353 R354 R355 R356 R357 R367: library part Resistor, Case Code (Imperial)=0402, Case Code (Metric)=1005, Manufacturer=Panasonic, Manufacturer Part Number=ERJ-2RKF4701X, Max Operating Temperature=155°C, Max Power Dissipation=100mW, Min Operating Temperature=-55°C, Package Quantity=1, Supplier Part Number 1=P4.70KLCT-ND, Temperature Coefficient=100ppm/°C, Tolerance=1%, Voltage Rating=50V
R69 R70 R126: library part Resistor, Case Code (Imperial)=0402, Case Code (Metric)=1005, Manufacturer="Vishay Dale", Manufacturer Part Number=CRCW0402100RFKED, Max Operating Temperature=155°C, Max Power Dissipation=63mW, Min Operating Temperature=-55°C, Package Quantity=10, Supplier Part Number 1=541-100LDKR-ND, Temperature Coefficient=100ppm/°C, Tolerance=1%, Voltage Rating=50V
R76 R79 R291 R301 R482 R483: library part Resistor, "RES SMD 150 OHM 1% 1/10W 0402", Case/Package=0402, Case Code (Metric)=1005, Manufacturer=Panasonic, Manufacturer Part Number=ERJ-2RKF1500X, Max Operating Temperature=155°C, Max Power Dissipation=100mW, Min Operating Temperature=-55°C, Package Quantity=1, Supplier Part Number 1=P150LCT-ND, Temperature Coefficient=100ppm/°C, Tolerance=1%, Voltage Rating=50V
R77: library part Resistor, "RES SMD 7.5K OHM 0.5% 1/16W 0402", Case Code (Imperial)=0402, Case Code (Metric)=1005, Manufacturer=Susumu, Manufacturer Part Number=RR0510P-752-D, Max Operating Temperature=125°C, Max Power Dissipation=63mW, Min Operating Temperature=-55°C, Package Quantity=1, Power Rating=62.5mW, Supplier Part Number 1=RR05P7.5KDCT-ND, Temperature Coefficient=25ppm/°C, Tolerance=0.5%, Voltage Rating=25V, Voltage Rating (DC)=50V
R78 R81 R82 R245 R270 R305 R308 R309 R311 R321 R329 R330 R331 R332 R489 R535 R536 R541 R542 R543 R654 R657 R695: library part Resistor, "RES SMD 100 OHM 1% 1/16W 0402", Case/Package=0402, Case Code (Metric)=1005, Manufacturer=Yageo, Manufacturer Part Number=RC0402FR-07100RL, Max Operating Temperature=155°C, Min Operating Temperature=-55°C, Power Rating=62.5mW, Supplier Part Number 1=311-100LRDKR-ND, Temperature Coefficient=100ppm/°C, Tolerance=1%, Voltage Rating=50V
R80 R534: library part Resistor, "Res Thick Film 0402 160 Ohm 1% 1/16W 100ppm/C Molded SMD SMD Paper T/R", Case/Package=0402, Manufacturer="Stackpole Electronics", Manufacturer Part Number=RMCF0402FT160R, Max Operating Temperature=155°C, Min Operating Temperature=-55°C, Supplier Part Number 1=RMCF0402FT160RCT-ND, Temperature Coefficient=100ppm/°C, Tolerance=1%
R87 R88 R89 R90 R95 R96 R101 R102 R103 R104 R105 R107 R108 R110 R111 R112 R115 R116 R117 R118 R119 R120 R121 R122: library part Resistor, "RES SMD 30 OHM 0.5% 1/16W 0402", Case Code (Imperial)=0402, Case Code (Metric)=1005, Manufacturer=Panasonic, Manufacturer Part Number=ERA-2AKD300X, Max Operating Temperature=155°C, Max Power Dissipation=63mW, Min Operating Temperature=-55°C, Package Quantity=10000, Power Rating=62.5mW, Supplier Part Number 1=P30DDCT-ND, Temperature Coefficient=100ppm/°C, Tolerance=0.5%
R100 R427: library part Resistor, Case Code (Imperial)=0402, Case Code (Metric)=1005, Manufacturer=Panasonic, Manufacturer Part Number=ERJ-2RKF5101X, Max Operating Temperature=155°C, Max Power Dissipation=100mW, Min Operating Temperature=-55°C, Package Quantity=10000, Supplier Part Number 1=P5.10KLCT-ND, Temperature Coefficient=100ppm/°C, Tolerance=1%, Voltage Rating=50V
R113: library part Resistor, "Thick Film Resistors 34.8K OHM 1%", Case Code (Imperial)=0402, Case Code (Metric)=1005, Manufacturer=Yageo, Manufacturer Part Number=RC0402FR-0734K8L, Max Operating Temperature=155°C, Max Power Dissipation=63mW, Min Operating Temperature=-55°C, Power Rating=62.5mW, Supplier Part Number 1=YAG3125CT-ND, Temperature Coefficient=100ppm/°C, Tolerance=1%, Voltage Rating=50V
R114 R274 R515 R522 R523 R531 R546 R548 R549 R551 R552 R554 R555 R557 R916 R1082: library part Resistor, Case Code (Imperial)=0402, Case Code (Metric)=1005, Manufacturer 1=Yageo, Manufacturer Part Number 1=RC0402FR-0710KL, Max Operating Temperature=155°C, Min Operating Temperature=-55°C, Power Rating=62.5mW, Supplier Part Number 1=311-10.0KLRCT-ND, Temperature Coefficient=100ppm/°C, Tolerance=1%, Voltage Rating=50V
R125 R538: library part Resistor, Case Code (Imperial)=0402, Case Code (Metric)=1005, Manufacturer="Stackpole Electronics", Manufacturer Part Number=RMCF0402FT8K87, Max Operating Temperature=155°C, Max Power Dissipation=63mW, Min Operating Temperature=-55°C, Package Quantity=1, Supplier Part Number 1=RMCF0402FT8K87CT-ND, Temperature Coefficient=100ppm/°C, Tolerance=1%
R140: library part Resistor, "RES SMD 2.2 OHM 5% 1/16W 0402", Case Code (Imperial)=0402, Case Code (Metric)=1005, Manufacturer=Yageo, Manufacturer Part Number=RC0402JR-072R2L, Max Operating Temperature=155°C, Max Power Dissipation=63mW, Min Operating Temperature=-55°C, Package Quantity=1, Power Rating=62.5mW, Supplier Part Number 1=311-2.2JRCT-ND, Temperature Coefficient=200ppm/°C, Tolerance=5%, Voltage Rating=50V
R149: library part Resistor, "Thick Film Resistors - SMD 196K OHM 1%", Case/Package=0402, Case Code (Metric)=1005, Manufacturer=Yageo, Manufacturer Part Number=RC0402FR-07196KL, Max Operating Temperature=155°C, Max Power Dissipation=63mW, Min Operating Temperature=-55°C, Power Rating=62.5mW, Supplier Part Number 1=YAG3024CT-ND, Temperature Coefficient=100ppm/°C, Tolerance=1%, Voltage Rating=50V
R150: library part Resistor, "TE CONNECTIVITY - CRGCQ0402F22K - RES, 22K, 1%, 0402, THICK FILM", Manufacturer="TE Connectivity", Manufacturer Part Number=CRGCQ0402F22K, Supplier Part Number 1=A129643CT-ND
R159 R737 R746 R747 R748 R749 R750 R751 R752 R753 R754 R755 R756 R757 R1002 R1003: library part Resistor, "Surface Mount Thick Film Resistor, Rc Series, 10 Kohm, 62.5 Mw, - 1%, 50 V, 0402 [1005 Metric]", Case/Package=0402, Case Code (Metric)=1005, Manufacturer=Yageo, Manufacturer Part Number=RC0402FR-0710KL, Max Operating Temperature=155°C, Min Operating Temperature=-55°C, Power Rating=62.5mW, Supplier Part Number 1=311-10.0KLRDKR-ND, Temperature Coefficient=100ppm/°C, Tolerance=1%, Voltage Rating=50V
R160: library part Resistor, "RES SMD 910 OHM 5% 1/10W 0402", Case Code (Imperial)=0402, Case Code (Metric)=1005, Manufacturer=Panasonic, Manufacturer Part Number=ERJ2GEJ911X, Max Operating Temperature=155°C, Max Power Dissipation=100mW, Min Operating Temperature=-55°C, Package Quantity=1, Supplier Part Number 1=P910JCT-ND, Temperature Coefficient=200ppm/°C, Tolerance=5%, Voltage Rating=50V
R165 R166 R167 R168 R169 R170 R171 R172: library part Resistor, "RES SMD 100 OHM 1% 1/16W 0402", Case Code (Imperial)=0402, Case Code (Metric)=1005, Manufacturer=Yageo, Manufacturer Part Number=RC0402FR-07100RL, Max Operating Temperature=155°C, Min Operating Temperature=-55°C, Power Rating=62.5mW, Supplier Part Number 1=311-100LRDKR-ND, Temperature Coefficient=100ppm/°C, Tolerance=1%, Voltage Rating=50V
R173: library part Resistor, "RES SMD 500 OHM 0.1% 1/20W 0402", Case/Package=0402, Case Code (Metric)=1005, Manufacturer="Vishay Dale", Manufacturer Part Number=PNM0402E5000BST1, Max Operating Temperature=155°C, Max Power Dissipation=50mW, Min Operating Temperature=-55°C, Package Quantity=1000, Supplier Part Number 1=541-1905-1-ND, Temperature Coefficient=25ppm/°C, Tolerance=0.1%
R212: library part Resistor, "SMT Resistor", Supplier Part Number 1=RR05P12.4KDCT-ND
R216: library part Resistor, Case/Package=0402, Manufacturer="Vishay Dale", Manufacturer Part Number=TNPW040231K2BEED, Max Operating Temperature=125°C, Max Power Dissipation=63mW, Min Operating Temperature=-55°C, Supplier Part Number 1=541-3564-1-ND, Temperature Coefficient=25ppm/°C, Tolerance=0.1%
R220: library part Resistor, Case Code (Imperial)=0402, Case Code (Metric)=1005, Manufacturer=Panasonic, Manufacturer Part Number=ERA-2AEB4991X, Max Operating Temperature=155°C, Max Power Dissipation=63mW, Min Operating Temperature=-55°C, Package Quantity=1, Power Rating=62.5mW, Supplier Part Number 1=P4.99KDCCT-ND, Temperature Coefficient=25ppm/°C, Tolerance=0.1%, Voltage Rating=50V
R231_SPI_bridge_Main R232_SPI_bridge_Main R232_SPI_bridge_PCIe R233_SPI_bridge_Main R234_SPI_bridge_Main R234_SPI_bridge_PCIe R235_SPI_bridge_Main R235_SPI_bridge_PCIe R236_SPI_bridge_Main R237_SPI_bridge_Main R237_SPI_bridge_PCIe R238_SPI_bridge_Main R239_SPI_bridge_Main R239_SPI_bridge_PCIe R240_SPI_bridge_Main R499 R544: library part Resistor, Case Code (Imperial)=0402, Case Code (Metric)=1005, Manufacturer=Panasonic, Manufacturer Part Number=ERJ-2RKF1001X, Max Operating Temperature=155°C, Max Power Dissipation=100mW, Min Operating Temperature=-55°C, Package Quantity=1, Supplier Part Number 1=P1.00KLCT-ND, Temperature Coefficient=100ppm/°C, Tolerance=1%, Voltage Rating=50V
R231_SPI_bridge_PCIe R233_SPI_bridge_PCIe R236_SPI_bridge_PCIe R238_SPI_bridge_PCIe R240_SPI_bridge_PCIe R252 R253 R254 R255 R424 R428 R488 R599 R694 R1048 R1049 R1050 R1051 R1052 R1053: library part Resistor, Case/Package=0402, Case Code (Metric)=1005, Manufacturer=Panasonic, Manufacturer Part Number=ERJ-2RKF1001X, Max Operating Temperature=155°C, Max Power Dissipation=100mW, Min Operating Temperature=-55°C, Package Quantity=1, Supplier Part Number 1=P1.00KLCT-ND, Temperature Coefficient=100ppm/°C, Tolerance=1%, Voltage Rating=50V
R246 R249 R256 R258: library part Resistor, "Res Thin Film 0402 120 Ohm 0.5% 1/16W ±25ppm/C Molded SMD Punched Carrier T/R", Case Code (Imperial)=0402, Case Code (Metric)=1005, Manufacturer=Panasonic, Manufacturer Part Number=ERA-2AED121X, Max Operating Temperature=155°C, Max Power Dissipation=63mW, Min Operating Temperature=-55°C, Package Quantity=10000, Supplier Part Number 1=P120DECT-ND, Temperature Coefficient=25ppm/°C, Tolerance=0.5%, Voltage Rating=25V
R247 R248 R261 R262: library part Resistor, "Res Thick Film 0402 127 Ohm 1% 0.063W(1/16W) }100ppm/? Molded SMD Paper T/R", Case Code (Imperial)=0402, Case Code (Metric)=1005, Manufacturer=Yageo, Manufacturer Part Number=RC0402FR-07127RL, Max Operating Temperature=155°C, Max Power Dissipation=63mW, Min Operating Temperature=-55°C, Power Rating=62.5mW, Supplier Part Number 1=YAG2963CT-ND, Temperature Coefficient=100ppm/°C, Tolerance=1%, Voltage Rating=50V
R250 R251 R259 R260: library part Resistor, "Res Thick Film 0402 82.5 Ohm 1% 0.063W(1/16W) ±100ppm/C Molded SMD Automotive Punched Paper T/R", Case Code (Imperial)=0402, Case Code (Metric)=1005, Manufacturer="KOA Speer", Manufacturer Part Number=RK73H1ETTP82R5F, Max Operating Temperature=155°C, Min Operating Temperature=-55°C, Package Quantity=10000, Power Rating=63mW, Supplier Part Number 1=2019-RK73H1ETTP82R5FCT-ND, Temperature Coefficient=100ppm/°C, Tolerance=1%, Voltage Rating=50V
R257 R545: library part Resistor, "RES SMD 49.9 OHM 1% 1/16W 0402", Case Code (Imperial)=0402, Case Code (Metric)=1005, Manufacturer=Yageo, Manufacturer Part Number=RC0402FR-0749R9L, Max Operating Temperature=155°C, Max Power Dissipation=63mW, Min Operating Temperature=-55°C, Package Quantity=1, Power Rating=62.5mW, Supplier Part Number 1=311-49.9LRDKR-ND, Temperature Coefficient=100ppm/°C, Tolerance=1%, Voltage Rating=50V
R263: library part Resistor, "RES 60.4K OHM 1% 1/16W 0402", Case Code (Imperial)=0402, Case Code (Metric)=1005, Manufacturer="Stackpole Electronics", Manufacturer Part Number=RMCF0402FT60K4, Max Operating Temperature=155°C, Max Power Dissipation=63mW, Min Operating Temperature=-55°C, Supplier Part Number 1=RMCF0402FT60K4CT-ND, Temperature Coefficient=100ppm/°C, Tolerance=1%
R264 R265 R450 R452 R454 R456 R460 R464 R470 R472 R474 R476 R478 R480 R493 R495 R497 R501 R503 R505 R509 R511 R513 R517 R519 R521 R525 R527 R529 R537 R539 R703 R704 R705 R706 R707 R708 R829 R830 R831 R832 R833 R834 R841 R842 R843 R844 R1054 R1055 R1056 R1057 R1058 R1067 R1068 R1071 R1072 R1073 R1074 R1077 R1080 R1083 R1084 R1085 R1086 R1087 R1088 R1091 R1092 R1093 R1094 R1095 R1097 R1098 R1099 R1100 R1101 R1103 R1104 R1105 R1106 R1107 R1109 R1110 R1111 R1113 R1115 R1117 R1119 R1121: library part Resistor, Case Code (Imperial)=0402, Case Code (Metric)=1005, Manufacturer 1=Yageo, Manufacturer Part Number 1=RC0402JR-070RL, Max Operating Temperature=155°C, Max Power Dissipation=63mW, Min Operating Temperature=-55°C, Package Quantity=1, Power Rating=62.5mW, Supplier Part Number 1=311-0.0JRCT-ND, Temperature Coefficient=200ppm/°C, Tolerance=5%, Voltage Rating=50V
R266: library part Resistor, "Thick Film Resistors - SMD 84.5K OHM 1%", Case/Package=0402, Case Code (Metric)=1005, Manufacturer=Yageo, Manufacturer Part Number=RC0402FR-0784K5L, Max Operating Temperature=155°C, Max Power Dissipation=63mW, Min Operating Temperature=-55°C, Power Rating=62.5mW, Supplier Part Number 1=YAG3245CT-ND, Temperature Coefficient=100ppm/°C, Tolerance=1%, Voltage Rating=50V
R268 R272 R285 R289 R303 R307 R648: library part Resistor, Case/Package=0402, Case Code (Metric)=1005, Manufacturer 1=Yageo, Manufacturer Part Number 1=RC0402FR-072RL, Max Operating Temperature=155°C, Max Power Dissipation=63mW, Min Operating Temperature=-55°C, Supplier Part Number 1=YAG3369CT-ND, Temperature Coefficient=200ppm/°C, Tolerance=1%, Voltage Rating=50V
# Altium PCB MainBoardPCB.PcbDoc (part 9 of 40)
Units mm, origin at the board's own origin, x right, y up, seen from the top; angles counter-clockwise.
Board outline 258.95 x 308.86 mm, 16 copper layers (L1, L2 (GND), L3 (Sign), L4 (GND), L5 (Sign), L6 (PWR/GND), L7(12V+Other), L8 (Plane_GND), L9 (PWR/GND), L10 (3V3+Other), L11 (PWR/GND), L12 (Sign), L13 (GND), L14 (Sign), L15 (GND), L16), stack 2.503 mm thick; 2578 components, 1867 nets, 8817 pads, 8021 vias.
Unrouted connection lines stored in the file: 25.

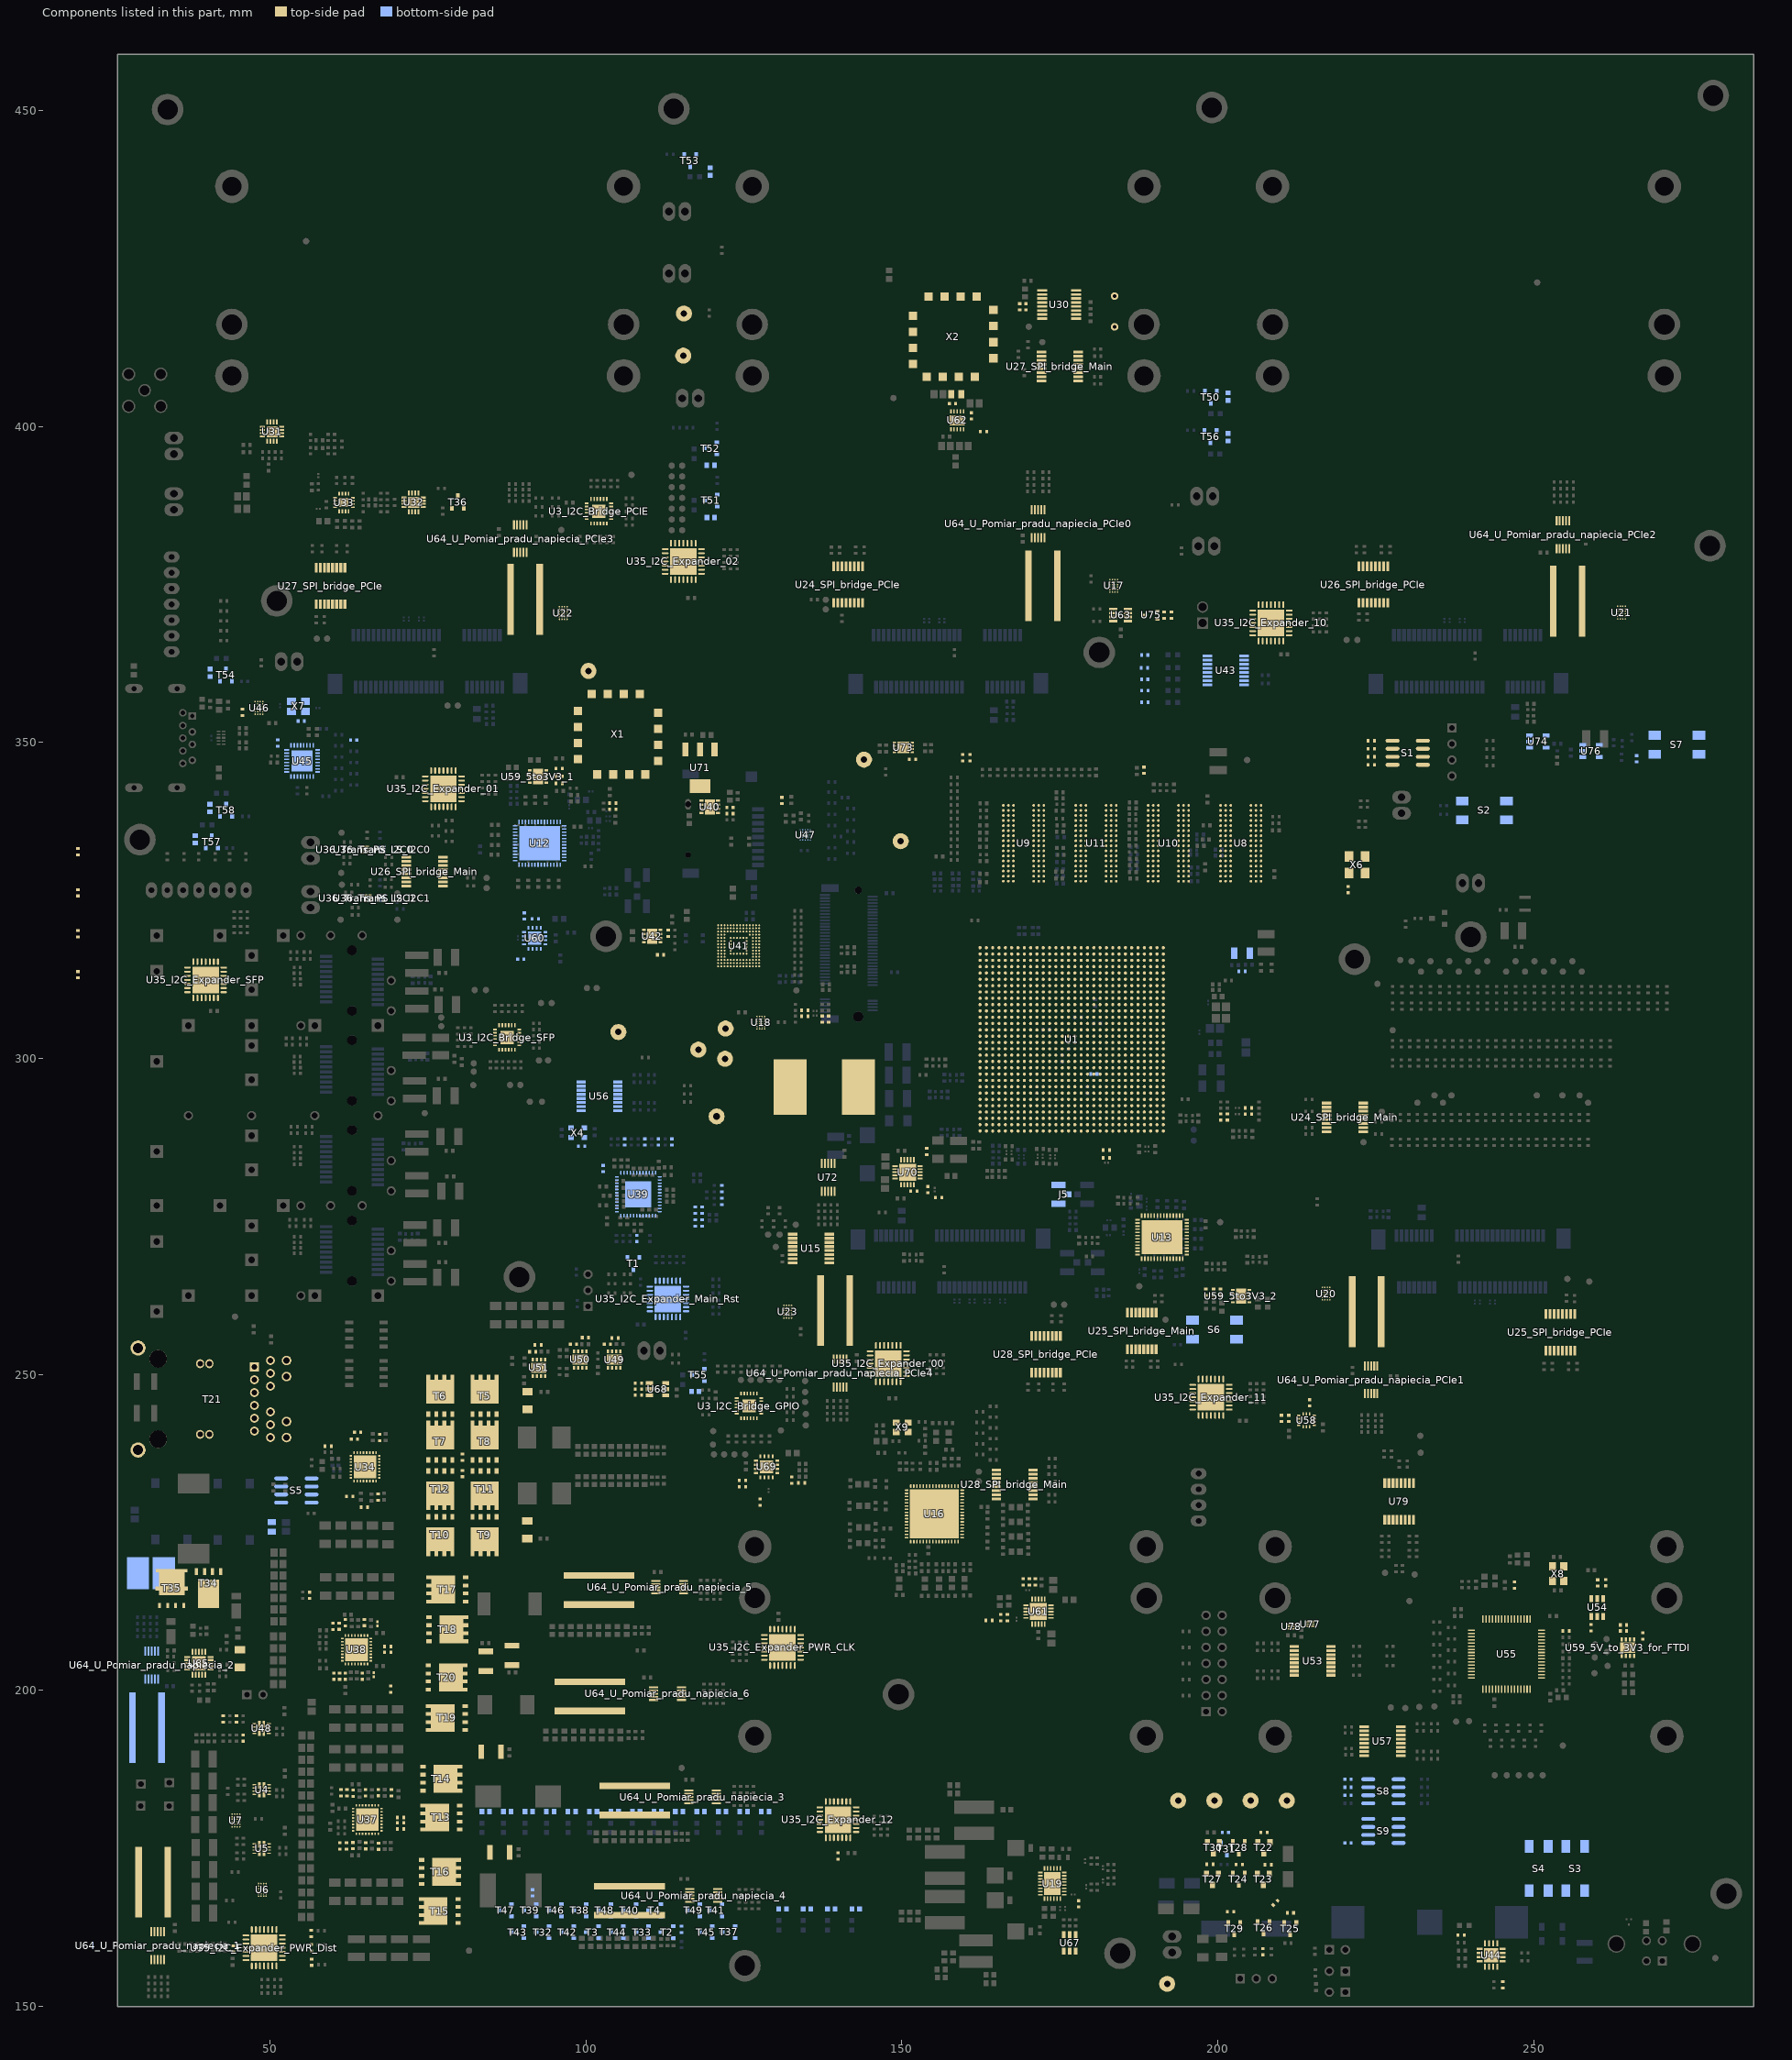
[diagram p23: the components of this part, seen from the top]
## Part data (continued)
R271: library part Resistor, "RES SMD 5K OHM 0.1% 1/20W 0402", Case Code (Imperial)=0402, Case Code (Metric)=1005, Manufacturer="Vishay Dale", Manufacturer Part Number=PNM0402E5001BST1, Max Operating Temperature=155°C, Max Power Dissipation=50mW, Min Operating Temperature=-55°C, Package Quantity=1000, Supplier Part Number 1=541-1901-1-ND, Temperature Coefficient=25ppm/°C, Tolerance=0.1%
R273 R277 R278 R295 R296 R313 R314 R423: library part Resistor, "CRGCQ 0402 12K 1%", Manufacturer="TE Connectivity", Manufacturer Part Number=CRGCQ0402F12K, Supplier Part Number 1=A129640CT-ND
R275 R280 R299 R317: library part Resistor, "PANASONIC - ERJ2RKF4702X - SMD Chip Resistor, 0402 [1005 Metric], 47 kohm, ERJ2R Series, 50 V, Thick Film, 100 mW", Case/Package=0402, Case Code (Metric)=1005, Manufacturer=Panasonic, Manufacturer Part Number=ERJ-2RKF4702X, Max Operating Temperature=155°C, Max Power Dissipation=100mW, Min Operating Temperature=-55°C, Package Quantity=1, Supplier Part Number 1=P47.0KLCT-ND, Temperature Coefficient=100ppm/°C, Tolerance=1%, Voltage Rating=50V
R284: library part Resistor, "SMT Resistor", Supplier Part Number 1=RR05P18.2KDCT-ND
R287 R444 R445: library part Resistor, "Res Thin Film 0402 49.9K Ohm 0.1% 1/16W 25ppm/C Molded SMD SMD Punched Carrier T/R", Case Code (Imperial)=0402, Case Code (Metric)=1005, Manufacturer=Panasonic, Manufacturer Part Number=ERA-2AEB4992X, Max Operating Temperature=155°C, Max Power Dissipation=63mW, Min Operating Temperature=-55°C, Package Quantity=1, Power Rating=62.5mW, Supplier Part Number 1=P49.9KDCCT-ND, Temperature Coefficient=25ppm/°C, Tolerance=0.1%, Voltage Rating=50V
R288 R298 R306 R316: "RES SMD 3.6 OHM 5% 1/2W 1210", Case Code (Imperial)=1210, Case Code (Metric)=3225, Manufacturer=Rohm, Manufacturer Part Number=ESR25JZPJ3R6, Max Operating Temperature=155°C, Max Power Dissipation=500mW, Min Operating Temperature=-55°C, Package Quantity=4000, Power="{}Power (Watts)", Resistance=3.6R, Supplier Part Number 1=RHM3.6AXCT-ND, Temperature Coefficient=200ppm/°C, Tolerance=5%
R290 R297 R300 R383 R401 R410 R417 R420 R422 R434 R608 R609 R635 R649 R651 R655 R656 R658 R721 R846: library part Resistor, "SMT Resistor", Supplier Part Number 1=RR05P10.0KDCT-ND
R292 R629: library part Resistor
R302: library part Resistor, "Thick Film Resistors - SMD 1.4K OHM 1%", Case Code (Imperial)=0402, Case Code (Metric)=1005, Manufacturer=Yageo, Manufacturer Part Number=RC0402FR-071K4L, Max Operating Temperature=155°C, Max Power Dissipation=63mW, Min Operating Temperature=-55°C, Power Rating=62.5mW, Supplier Part Number 1=YAG3039CT-ND, Temperature Coefficient=100ppm/°C, Tolerance=1%, Voltage Rating=50V
R315: library part Resistor, "Thick Film Resistors - SMD 196K OHM 1%", Case Code (Imperial)=0402, Case Code (Metric)=1005, Manufacturer=Yageo, Manufacturer Part Number=RC0402FR-07196KL, Max Operating Temperature=155°C, Max Power Dissipation=63mW, Min Operating Temperature=-55°C, Power Rating=62.5mW, Supplier Part Number 1=YAG3024CT-ND, Temperature Coefficient=100ppm/°C, Tolerance=1%, Voltage Rating=50V
R318: library part Resistor, "RES 27K OHM 1% 1/16W 0402", Case Code (Imperial)=0402, Case Code (Metric)=1005, Manufacturer="Stackpole Electronics", Manufacturer Part Number=RMCF0402FT27K0, Max Operating Temperature=155°C, Max Power Dissipation=63mW, Min Operating Temperature=-55°C, Package Quantity=10000, Power Rating=62.5mW, Supplier Part Number 1=RMCF0402FT27K0CT-ND, Temperature Coefficient=100ppm/°C, Tolerance=1%
R322 R323: library part Resistor, Case/Package=0402, Case Code (Metric)=1005, Manufacturer="Stackpole Electronics", Manufacturer Part Number=RMCF0402FT5K76, Max Operating Temperature=155°C, Max Power Dissipation=63mW, Min Operating Temperature=-55°C, Supplier Part Number 1=RMCF0402FT5K76CT-ND, Temperature Coefficient=100ppm/°C, Tolerance=1%
R324: library part Resistor, "RES SMD 100K OHM 1% 1/8W 0805", Case/Package=0805, Case Code (Metric)=2012, Manufacturer=Yageo, Manufacturer Part Number=RC0805FR-07100KL, Max Operating Temperature=155°C, Max Power Dissipation=125mW, Min Operating Temperature=-55°C, Package Quantity=1, Supplier Part Number 1=311-100KCRDKR-ND, Temperature Coefficient=100ppm/°C, Tolerance=1%, Voltage Rating=150V
R325 R326 R327 R328: library part Resistor, Case/Package=0402, Case Code (Metric)=1005, Manufacturer="Stackpole Electronics", Manufacturer Part Number=RMCF0402FT2K49, Max Operating Temperature=155°C, Max Power Dissipation=63mW, Min Operating Temperature=-55°C, Package Quantity=10000, Supplier Part Number 1=RMCF0402FT2K49CT-ND, Temperature Coefficient=100ppm/°C, Tolerance=1%
R333 R336 R337 R338 R709 R714: library part Resistor, "PANASONIC - ERJ2RKF2201X - SMD Chip Resistor, 0402 [1005 Metric], 2.2 kohm, ERJ2R Series, 50 V, Thick Film, 100 mW", Case/Package=0402, Case Code (Metric)=1005, Manufacturer=Panasonic, Manufacturer Part Number=ERJ-2RKF2201X, Max Operating Temperature=155°C, Max Power Dissipation=100mW, Min Operating Temperature=-55°C, Package Quantity=1, Supplier Part Number 1=P2.20KLCT-ND, Temperature Coefficient=100ppm/°C, Tolerance=1%, Voltage Rating=50V
R334: library part Resistor, Case/Package=0402, Case Code (Metric)=1005, Manufacturer 1=Yageo, Manufacturer Part Number 1=RC0402FR-0711KL, Max Operating Temperature=155°C, Max Power Dissipation=63mW, Min Operating Temperature=-55°C, Package Quantity=1, Supplier Part Number 1=311-11.0KLRCT-ND, Temperature Coefficient=100ppm/°C, Tolerance=1%, Voltage Rating=50V
R335 R491: library part Resistor, "RES SMD 1M OHM 1% 1/16W 0402", Case/Package=0402, Case Code (Metric)=1005, Manufacturer=Yageo, Manufacturer Part Number=RC0402FR-071ML, Max Operating Temperature=155°C, Min Operating Temperature=-55°C, Power Rating=63mW, Supplier Part Number 1=311-1.00MLRDKR-ND, Temperature Coefficient=100ppm/°C, Tolerance=1%, Voltage Rating=50V
R339 R342 R430_5V_to_3V3_for_FTDI: library part Resistor, "Thick Film Resistors - SMD 105K OHM 1%", Case/Package=0402, Case Code (Metric)=1005, Manufacturer=Yageo, Manufacturer Part Number=RC0402FR-07105KL, Max Operating Temperature=155°C, Max Power Dissipation=63mW, Min Operating Temperature=-55°C, Power Rating=62.5mW, Supplier Part Number 1=YAG2946CT-ND, Temperature Coefficient=100ppm/°C, Tolerance=1%, Voltage Rating=50V
R341 R344 R393 R396 R399 R432_5to3V3_1 R432_5to3V3_2 R432_5V_to_3V3_for_FTDI R624 R674: library part Resistor, Case/Package=0402, Case Code (Metric)=1005, Manufacturer=Panasonic, Manufacturer Part Number=ERJ-2RKF1502X, Max Operating Temperature=155°C, Max Power Dissipation=100mW, Min Operating Temperature=-55°C, Package Quantity=1, Supplier Part Number 1=P15.0KLDKR-ND, Temperature Coefficient=100ppm/°C, Tolerance=1%, Voltage Rating=50V
R358 R359 R360 R361: library part Resistor, "Resistor;  Thick Film;  Res 499 Ohms;  Pwr-Rtg 0.1 W;  Tol 1%;  SMT;  0402;  Tape & Reel", Case Code (Imperial)=0402, Case Code (Metric)=1005, Manufacturer=Panasonic, Manufacturer Part Number=ERJ-2RKF4990X, Max Operating Temperature=155°C, Max Power Dissipation=100mW, Min Operating Temperature=-55°C, Package Quantity=1, Supplier Part Number 1=P499LCT-ND, Temperature Coefficient=100ppm/°C, Tolerance=1%, Voltage Rating=50V
R362 R533: library part Resistor, "RES SMD 30 OHM 0.5% 1/16W 0402", Case/Package=0402, Case Code (Metric)=1005, Manufacturer=Panasonic, Manufacturer Part Number=ERA-2AKD300X, Max Operating Temperature=155°C, Max Power Dissipation=63mW, Min Operating Temperature=-55°C, Package Quantity=10000, Power Rating=62.5mW, Supplier Part Number 1=P30DDCT-ND, Temperature Coefficient=100ppm/°C, Tolerance=0.5%
R368: library part Resistor, "Thick Film Resistors 0402 261ohms 1% AEC-Q200", Case Code (Imperial)=0402, Case Code (Metric)=1005, Manufacturer=Panasonic, Manufacturer Part Number=ERJ-2RKF2610X, Max Operating Temperature=155°C, Max Power Dissipation=100mW, Min Operating Temperature=-55°C, Package Quantity=1, Supplier Part Number 1=P261LCT-ND, Temperature Coefficient=100ppm/°C, Tolerance=1%, Voltage Rating=50V
R372: library part Resistor, "RES 8.06K OHM 1% 1/16W 0402", Case Code (Imperial)=0402, Case Code (Metric)=1005, Manufacturer="Stackpole Electronics", Manufacturer Part Number=RMCF0402FT8K06, Max Operating Temperature=155°C, Max Power Dissipation=63mW, Min Operating Temperature=-55°C, Supplier Part Number 1=RMCF0402FT8K06CT-ND, Temperature Coefficient=100ppm/°C, Tolerance=1%
R374: library part Resistor, "Thick Film Resistors 0.1W 4.7Mohms 5%", Case Code (Imperial)=0402, Case Code (Metric)=1005, Manufacturer="KOA Speer", Manufacturer Part Number=RK73B1ETTP475J, Max Operating Temperature=155°C, Min Operating Temperature=-55°C, Package Quantity=10000, Power Rating=63mW, Supplier Part Number 1=2019-RK73B1ETTP475JCT-ND, Temperature Coefficient=200ppm/°C, Tolerance=5%, Voltage Rating=50V
R375: library part Resistor, "RES SMD 40.2 OHM 1% 1/16W 0402", Case Code (Imperial)=0402, Case Code (Metric)=1005, Manufacturer=Yageo, Manufacturer Part Number=RC0402FR-0740R2L, Max Operating Temperature=155°C, Max Power Dissipation=63mW, Min Operating Temperature=-55°C, Package Quantity=1, Power Rating=62.5mW, Supplier Part Number 1=311-40.2LRCT-ND, Temperature Coefficient=100ppm/°C, Tolerance=1%, Voltage Rating=50V
R379: library part Resistor, "RES 8.06K OHM 1% 1/16W 0402", Case/Package=0402, Case Code (Metric)=1005, Manufacturer="Stackpole Electronics", Manufacturer Part Number=RMCF0402FT8K06, Max Operating Temperature=155°C, Max Power Dissipation=63mW, Min Operating Temperature=-55°C, Supplier Part Number 1=RMCF0402FT8K06CT-ND, Temperature Coefficient=100ppm/°C, Tolerance=1%
R380: library part Resistor, "Thick Film Resistors 4.22K OHM 1%", Case/Package=0402, Case Code (Metric)=1005, Manufacturer=Yageo, Manufacturer Part Number=RC0402FR-074K22L, Max Operating Temperature=155°C, Max Power Dissipation=63mW, Min Operating Temperature=-55°C, Power Rating=62.5mW, Supplier Part Number 1=YAG3172CT-ND, Temperature Coefficient=100ppm/°C, Tolerance=1%, Voltage Rating=50V
R384 R385 R484 R485: library part Resistor, Case/Package=0402, Case Code (Metric)=1005, Manufacturer=Vishay, Manufacturer Part Number=CRCW040271R5FKED, Max Operating Temperature=155°C, Max Power Dissipation=63mW, Min Operating Temperature=-55°C, Package Quantity=10, Supplier Part Number 1=541-71.5LCT-ND, Temperature Coefficient=100ppm/°C, Tolerance=1%, Voltage Rating=50V
R386 R486: library part Resistor, Case/Package=0402, Case Code (Metric)=1005, Manufacturer="Stackpole Electronics", Manufacturer Part Number=RMCF0402FT8K87, Max Operating Temperature=155°C, Max Power Dissipation=63mW, Min Operating Temperature=-55°C, Package Quantity=1, Supplier Part Number 1=RMCF0402FT8K87CT-ND, Temperature Coefficient=100ppm/°C, Tolerance=1%
R387 R487: library part Resistor, Case/Package=0402, Case Code (Metric)=1005, Manufacturer=Panasonic, Manufacturer Part Number=ERJ-2RKF5101X, Max Operating Temperature=155°C, Max Power Dissipation=100mW, Min Operating Temperature=-55°C, Package Quantity=10000, Supplier Part Number 1=P5.10KLCT-ND, Temperature Coefficient=100ppm/°C, Tolerance=1%, Voltage Rating=50V
R391: library part Resistor, "RES SMD 75K OHM 1% 1/16W 0402", Case/Package=0402, Case Code (Metric)=1005, Manufacturer=Yageo, Manufacturer Part Number=RC0402FR-0775KL, Max Operating Temperature=155°C, Max Power Dissipation=63mW, Min Operating Temperature=-55°C, Package Quantity=1, Power Rating=62.5mW, Supplier Part Number 1=311-75KLRCT-ND, Temperature Coefficient=100ppm/°C, Tolerance=1%, Voltage Rating=50V
R392 R431_5to3V3_1 R431_5to3V3_2 R442: library part Resistor, Case Code (Imperial)=0402, Case Code (Metric)=1005, Manufacturer 1=Panasonic, Manufacturer Part Number 1=ERA-2AED104X, Max Operating Temperature=155°C, Max Power Dissipation=63mW, Min Operating Temperature=-55°C, Package Quantity=10000, Supplier Part Number 1=P100KDECT-ND, Temperature Coefficient=25ppm/°C, Tolerance=0.5%, Voltage Rating=25V
R394: library part Resistor, "RES 51.1K OHM 1% 1/16W 0402", Case/Package=0402, Case Code (Metric)=1005, Manufacturer="Stackpole Electronics", Manufacturer Part Number=RMCF0402FT51K1, Max Operating Temperature=155°C, Max Power Dissipation=63mW, Min Operating Temperature=-55°C, Supplier Part Number 1=RMCF0402FT51K1CT-ND, Temperature Coefficient=100ppm/°C, Tolerance=1%
R397: library part Resistor, "RES 21.5K OHM 1% 1/16W 0402", Case/Package=0402, Case Code (Metric)=1005, Manufacturer="Stackpole Electronics", Manufacturer Part Number=RMCF0402FT21K5, Max Operating Temperature=155°C, Max Power Dissipation=63mW, Min Operating Temperature=-55°C, Package Quantity=10000, Supplier Part Number 1=RMCF0402FT21K5CT-ND, Temperature Coefficient=100ppm/°C, Tolerance=1%
R419: library part Resistor, "RES SMD 2K OHM 1% 1/16W 0402", Case/Package=0402, Case Code (Metric)=1005, Manufacturer=Yageo, Manufacturer Part Number=RC0402FR-072KL, Max Operating Temperature=155°C, Max Power Dissipation=63mW, Min Operating Temperature=-55°C, Package Quantity=1, Supplier Part Number 1=311-2KLRDKR-ND, Temperature Coefficient=100ppm/°C, Tolerance=1%, Voltage Rating=50V
R429 R600 R601: library part Resistor, Case/Package=0402, Case Code (Metric)=1005, Manufacturer=Yageo, Manufacturer Part Number=RC0402JR-070RL, Max Operating Temperature=155°C, Max Power Dissipation=63mW, Min Operating Temperature=-55°C, Package Quantity=1, Power Rating=62.5mW, Supplier Part Number 1=311-0.0JRCT-ND, Temperature Coefficient=200ppm/°C, Tolerance=5%, Voltage Rating=50V
R430_5to3V3_1 R430_5to3V3_2: library part Resistor, "Thick Film Resistors - SMD 105K OHM 1%", Case Code (Imperial)=0402, Case Code (Metric)=1005, Manufacturer=Yageo, Manufacturer Part Number=RC0402FR-07105KL, Max Operating Temperature=155°C, Max Power Dissipation=63mW, Min Operating Temperature=-55°C, Power Rating=62.5mW, Supplier Part Number 1=YAG2946CT-ND, Temperature Coefficient=100ppm/°C, Tolerance=1%, Voltage Rating=50V
R431_5V_to_3V3_for_FTDI R632 R633 R634 R646 R647 R690 R825 R828: library part Resistor, Case/Package=0402, Case Code (Metric)=1005, Manufacturer 1=Panasonic, Manufacturer Part Number 1=ERA-2AED104X, Max Operating Temperature=155°C, Max Power Dissipation=63mW, Min Operating Temperature=-55°C, Package Quantity=10000, Supplier Part Number 1=P100KDECT-ND, Temperature Coefficient=25ppm/°C, Tolerance=0.5%, Voltage Rating=25V
R433: library part Resistor, "RES 56K OHM 1% 1/16W 0402", Case Code (Imperial)=0402, Case Code (Metric)=1005, Manufacturer="Stackpole Electronics", Manufacturer Part Number=RMCF0402FT56K0, Max Operating Temperature=155°C, Max Power Dissipation=63mW, Min Operating Temperature=-55°C, Package Quantity=10000, Supplier Part Number 1=RMCF0402FT56K0CT-ND, Temperature Coefficient=100ppm/°C, Tolerance=1%
R435: library part Resistor, Case/Package=0402, Case Code (Metric)=1005, Manufacturer=Yageo, Manufacturer Part Number=RC0402FR-0710KL, Max Operating Temperature=155°C, Min Operating Temperature=-55°C, Power Rating=62.5mW, Supplier Part Number 1=311-10.0KLRDKR-ND, Temperature Coefficient=100ppm/°C, Tolerance=1%, Voltage Rating=50V
R436 R438: library part Resistor, "Thick Film Resistors - SMD 3.57K OHM 1%", Case Code (Imperial)=0402, Case Code (Metric)=1005, Manufacturer=Yageo, Manufacturer Part Number=RC0402FR-073K57L, Max Operating Temperature=155°C, Max Power Dissipation=63mW, Min Operating Temperature=-55°C, Power Rating=62.5mW, Supplier Part Number 1=YAG3150CT-ND, Temperature Coefficient=100ppm/°C, Tolerance=1%, Voltage Rating=50V
R437 R439: library part Resistor, "Res General Purpose Thick Film 0402 1.15K Ohm 1% 1/16W ±100ppm/°C Molded SMD Paper T/R", Case Code (Imperial)=0402, Case Code (Metric)=1005, Manufacturer=Yageo, Manufacturer Part Number=RC0402FR-071K15L, Max Operating Temperature=155°C, Max Power Dissipation=63mW, Min Operating Temperature=-55°C, Power Rating=62.5mW, Supplier Part Number 1=YAG3033CT-ND, Temperature Coefficient=100ppm/°C, Tolerance=1%, Voltage Rating=50V
R440 R441 R668 R676 R689 R691 R745 R837 R839 R840: library part Resistor, Case/Package=0402, Case Code (Metric)=1005, Manufacturer=Panasonic, Manufacturer Part Number=ERJ-2RKF2002X, Max Operating Temperature=155°C, Max Power Dissipation=100mW, Min Operating Temperature=-55°C, Package Quantity=1, Supplier Part Number 1=P20.0KLCT-ND, Temperature Coefficient=100ppm/°C, Tolerance=1%, Voltage Rating=50V
R443: library part Resistor, "Panasonic ERA Series Thin Film Surface Mount Fixed Resistor 0805 Case 698k 0.1% 0.125W 25ppm/C", Case Code (Imperial)=0805, Case Code (Metric)=2012, Manufacturer=Panasonic, Manufacturer Part Number=ERA-6AEB6983V, Max Operating Temperature=155°C, Max Power Dissipation=125mW, Min Operating Temperature=-55°C, Package Quantity=5000, Supplier Part Number 1=P698KDACT-ND, Temperature Coefficient=25ppm/°C, Tolerance=0.1%, Voltage Rating=100V
R446 R447: library part Resistor, "RES SMD 120 OHM 1% 1/16W 0402", Case/Package=0402, Case Code (Metric)=1005, Manufacturer=Vishay, Manufacturer Part Number=CRCW0402120RFKED, Max Operating Temperature=155°C, Max Power Dissipation=63mW, Min Operating Temperature=-55°C, Package Quantity=10000, Supplier Part Number 1=541-120LCT-ND, Temperature Coefficient=100ppm/°C, Tolerance=1%, Voltage Rating=50V
R448_U_Pomiar_pradu_napiecia_1 R448_U_Pomiar_pradu_napiecia_2 R448_U_Pomiar_pradu_napiecia_3 R448_U_Pomiar_pradu_napiecia_4 R448_U_Pomiar_pradu_napiecia_5 R448_U_Pomiar_pradu_napiecia_6 R448_U_Pomiar_pradu_napiecia_PCIe0 R448_U_Pomiar_pradu_napiecia_PCIe1 R448_U_Pomiar_pradu_napiecia_PCIe2 R448_U_Pomiar_pradu_napiecia_PCIe3 R448_U_Pomiar_pradu_napiecia_PCIe4: "RES SMD 5 MOHM 5W 4320 WIDE", Case/Package=Metal, Manufacturer=Ohmite, Max Operating Temperature=155°C, Max Power Dissipation=5W, Min Operating Temperature=-55°C, Package Quantity=1, Resistance=5mR, Supplier Part Number 1=FCSL110R005FERCT-ND, Temperature Coefficient=50ppm/°C, Tolerance=1%
R532: library part Resistor, "Res Thick Film 0402 75 Ohm 1% 1/10W 100ppm/C Molded SMD SMD Punched Carrier T/R", Case Code (Imperial)=0402, Case Code (Metric)=1005, Manufacturer=Panasonic, Manufacturer Part Number=ERJ-2RKF75R0X, Max Operating Temperature=155°C, Max Power Dissipation=100mW, Min Operating Temperature=-55°C, Package Quantity=1, Supplier Part Number 1=P75.0LDKR-ND, Temperature Coefficient=100ppm/°C, Tolerance=1%, Voltage Rating=50V
R610 R611: library part Resistor, Case/Package=0402, Case Code (Metric)=1005, Manufacturer=Yageo, Manufacturer Part Number=RC0402FR-071K33L, Max Operating Temperature=155°C, Max Power Dissipation=63mW, Min Operating Temperature=-55°C, Package Quantity=1, Power Rating=62.5mW, Supplier Part Number 1=311-1.33KLRCT-ND, Temperature Coefficient=100ppm/°C, Tolerance=1%, Voltage Rating=50V
R612 R614: library part Resistor, Case/Package=0402, Manufacturer="Vishay BCcomponents", Manufacturer Part Number=MCS04020C2203FE000, Max Operating Temperature=125°C, Min Operating Temperature=-55°C, Supplier Part Number 1=749-1566-1-ND, Temperature Coefficient=50ppm/°C, Tolerance=1%
R613 R616: library part Resistor, Case/Package=1206, Case Code (Metric)=3216, Manufacturer="Vishay Dale", Manufacturer Part Number=CRCW12062R40FKEAHP, Max Operating Temperature=155°C, Max Power Dissipation=500mW, Min Operating Temperature=-55°C, Supplier Part Number 1=541-2.40UCT-ND, Temperature Coefficient=100ppm/°C, Tolerance=1%
R617: "RES 0.004 OHM 1% 7W 5931", Case/Package=5931, Manufacturer=Yageo, Max Operating Temperature=170°C, Max Power Dissipation=7W, Min Operating Temperature=-65°C, Resistance=4mR, Supplier Part Number 1=YAG4096CT-ND, Temperature Coefficient=75ppm/°C, Tolerance=1%
R619: library part Resistor, Case/Package=0402, Case Code (Metric)=1005, Manufacturer="Stackpole Electronics", Manufacturer Part Number=RMCF0402FT1K91, Max Operating Temperature=155°C, Max Power Dissipation=63mW, Min Operating Temperature=-55°C, Supplier Part Number 1=RMCF0402FT1K91CT-ND, Temperature Coefficient=100ppm/°C, Tolerance=1%
R620: library part Resistor, Case/Package=0402, Case Code (Metric)=1005, Manufacturer=Yageo, Manufacturer Part Number=RC0402FR-072KL, Max Operating Temperature=155°C, Max Power Dissipation=63mW, Min Operating Temperature=-55°C, Package Quantity=1, Supplier Part Number 1=311-2KLRCT-ND, Temperature Coefficient=100ppm/°C, Tolerance=1%, Voltage Rating=50V
R621: library part Resistor, "Res Thick Film 0402 147K Ohm 1% 1/16W 100ppm/C Molded SMD SMD Paper T/R", Case/Package=0402, Case Code (Metric)=1005, Manufacturer="Stackpole Electronics", Manufacturer Part Number=RMCF0402FT147K, Max Operating Temperature=155°C, Max Power Dissipation=63mW, Min Operating Temperature=-55°C, Temperature Coefficient=100ppm/°C, Tolerance=1%
R622: library part Resistor, Case/Package=0402, Case Code (Metric)=1005, Manufacturer="Stackpole Electronics", Manufacturer Part Number=RMCF0402FT340K, Max Operating Temperature=155°C, Max Power Dissipation=63mW, Min Operating Temperature=-55°C, Supplier Part Number 1=RMCF0402FT340KCT-ND, Temperature Coefficient=100ppm/°C, Tolerance=1%
R623: library part Resistor, Case/Package=0402, Case Code (Metric)=1005, Manufacturer=Panasonic, Manufacturer Part Number=ERA-2AEB1431X, Max Operating Temperature=155°C, Max Power Dissipation=63mW, Min Operating Temperature=-55°C, Package Quantity=1, Power Rating=62.5mW, Supplier Part Number 1=P1.43KDCCT-ND, Temperature Coefficient=25ppm/°C, Tolerance=0.1%, Voltage Rating=50V
R625: library part Resistor, "Thick Film Resistors - SMD 1.4K OHM 1%", Case/Package=0402, Case Code (Metric)=1005, Manufacturer=Yageo, Manufacturer Part Number=RC0402FR-071K4L, Max Operating Temperature=155°C, Max Power Dissipation=63mW, Min Operating Temperature=-55°C, Power Rating=62.5mW, Supplier Part Number 1=YAG3039CT-ND, Temperature Coefficient=100ppm/°C, Tolerance=1%, Voltage Rating=50V
R626 R1122_Trans_LS_I2C0 R1122_Trans_LS_I2C1 R1122_Trans_PS_I2C0 R1122_Trans_PS_I2C1: library part Resistor, Case/Package=0402, Manufacturer="Vishay BCcomponents", Manufacturer Part Number=MCS04020C2003FE000, Max Operating Temperature=125°C, Min Operating Temperature=-55°C, Supplier Part Number 1=749-1562-1-ND, Temperature Coefficient=50ppm/°C, Tolerance=1%
R627: library part Resistor, Case/Package=0402, Case Code (Metric)=1005, Manufacturer=Yageo, Manufacturer Part Number=RC0402FR-0710K5L, Max Operating Temperature=155°C, Max Power Dissipation=63mW, Min Operating Temperature=-55°C, Power Rating=62.5mW, Supplier Part Number 1=YAG2951CT-ND, Temperature Coefficient=100ppm/°C, Tolerance=1%, Voltage Rating=50V
R628: library part Resistor, Case/Package=0402, Case Code (Metric)=1005, Manufacturer="Stackpole Electronics", Manufacturer Part Number=RMCF0402FT750K, Max Operating Temperature=155°C, Max Power Dissipation=63mW, Min Operating Temperature=-55°C, Supplier Part Number 1=RMCF0402FT750KCT-ND, Temperature Coefficient=100ppm/°C, Tolerance=1%
R631 R685: library part Resistor, Case/Package=0402, Case Code (Metric)=1005, Manufacturer="Stackpole Electronics", Manufacturer Part Number=RMCF0402FT5K90, Max Operating Temperature=155°C, Max Power Dissipation=63mW, Min Operating Temperature=-55°C, Supplier Part Number 1=RMCF0402FT5K90CT-ND, Temperature Coefficient=100ppm/°C, Tolerance=1%
R644: library part Resistor, Case/Package=0402, Case Code (Metric)=1005, Manufacturer=Vishay, Manufacturer Part Number=CRCW04029K10FKED, Max Operating Temperature=155°C, Max Power Dissipation=63mW, Min Operating Temperature=-55°C, Package Quantity=10, Supplier Part Number 1=541-9.10KLCT-ND, Temperature Coefficient=100ppm/°C, Tolerance=1%, Voltage Rating=50V
R645: library part Resistor, Case/Package=0402, Case Code (Metric)=1005, Manufacturer=Panasonic, Manufacturer Part Number=ERA-2AED133X, Max Operating Temperature=155°C, Max Power Dissipation=63mW, Min Operating Temperature=-55°C, Package Quantity=1, Power Rating=62.5mW, Supplier Part Number 1=P13KDECT-ND, Temperature Coefficient=25ppm/°C, Tolerance=0.5%
R650: library part Resistor, "RES SMD 100M OHM 5% 1/16W 0402", Case Code (Imperial)=0402, Case Code (Metric)=1005, Manufacturer="Stackpole Electronics", Manufacturer Part Number=HMC0402JT100M, Max Operating Temperature=125°C, Max Power Dissipation=63mW, Min Operating Temperature=-55°C, Supplier Part Number 1=HMC0402JT100MCT-ND, Temperature Coefficient=400ppm/°C, Tolerance=5%
R652: library part Resistor, "RES SMD 1M OHM 1% 1/16W 0402", Case Code (Imperial)=0402, Case Code (Metric)=1005, Manufacturer=Yageo, Manufacturer Part Number=RC0402FR-071ML, Max Operating Temperature=155°C, Min Operating Temperature=-55°C, Power Rating=63mW, Supplier Part Number 1=311-1.00MLRDKR-ND, Temperature Coefficient=100ppm/°C, Tolerance=1%, Voltage Rating=50V
R653: library part Resistor, "RES SMD 20 OHM 5% 1/5W 0402", Case Code (Imperial)=0402, Case Code (Metric)=1005, Manufacturer=Rohm, Manufacturer Part Number=ESR01MZPJ200, Max Operating Temperature=155°C, Max Power Dissipation=200mW, Min Operating Temperature=-55°C, Package Quantity=1, Supplier Part Number 1=RHM1011CT-ND, Temperature Coefficient=200ppm/°C, Tolerance=5%
R666: library part Resistor, "RES 0.012 OHM 1% 1/2W 1206", Case/Package=1206, Case Code (Metric)=3216, Manufacturer="Stackpole Electronics", Manufacturer Part Number=CSR1206FK12L0, Max Operating Temperature=155°C, Max Power Dissipation=500mW, Min Operating Temperature=-55°C, Supplier Part Number 1=CSR1206FK12L0CT-ND, Temperature Coefficient=100ppm/°C, Tolerance=1%
R671 R673: library part Resistor, Case/Package=0402, Case Code (Metric)=1005, Manufacturer=Panasonic, Manufacturer Part Number=ERA-2AEB1871X, Max Operating Temperature=155°C, Max Power Dissipation=63mW, Min Operating Temperature=-55°C, Package Quantity=10000, Power Rating=62.5mW, Supplier Part Number 1=P1.87KDCCT-ND, Temperature Coefficient=25ppm/°C, Tolerance=0.1%
R672: library part Resistor, Case/Package=0402, Case Code (Metric)=1005, Manufacturer=Panasonic, Manufacturer Part Number=ERA-2AEB152X, Max Operating Temperature=155°C, Max Power Dissipation=63mW, Min Operating Temperature=-55°C, Package Quantity=10000, Supplier Part Number 1=P1.5KDCCT-ND, Temperature Coefficient=25ppm/°C, Tolerance=0.1%, Voltage Rating=25V
R682: library part Resistor, "RES SMD 7.5K OHM 0.5% 1/16W 0402", Case/Package=0402, Case Code (Metric)=1005, Manufacturer=Susumu, Manufacturer Part Number=RR0510P-752-D, Max Operating Temperature=125°C, Max Power Dissipation=63mW, Min Operating Temperature=-55°C, Package Quantity=1, Power Rating=62.5mW, Supplier Part Number 1=RR05P7.5KDCT-ND, Temperature Coefficient=25ppm/°C, Tolerance=0.5%, Voltage Rating=25V, Voltage Rating (DC)=50V
R684: library part Resistor, Case/Package=0402, Case Code (Metric)=1005, Manufacturer 1=Yageo, Manufacturer Part Number 1=RC0402FR-077K15L, Max Operating Temperature=155°C, Max Power Dissipation=63mW, Min Operating Temperature=-55°C, Power Rating=62.5mW, Supplier Part Number 1=YAG3235CT-ND, Temperature Coefficient=100ppm/°C, Tolerance=1%, Voltage Rating=50V
R686: library part Resistor, Case/Package=0402, Case Code (Metric)=1005, Manufacturer=Yageo, Manufacturer Part Number=RC0402FR-07412KL, Max Operating Temperature=155°C, Max Power Dissipation=63mW, Min Operating Temperature=-55°C, Power Rating=62.5mW, Supplier Part Number 1=YAG3153CT-ND, Temperature Coefficient=100ppm/°C, Tolerance=1%, Voltage Rating=50V
R687: library part Resistor, Case/Package=0402, Case Code (Metric)=1005, Manufacturer=Panasonic, Manufacturer Part Number=ERA-2AEB5762X, Max Operating Temperature=155°C, Max Power Dissipation=63mW, Min Operating Temperature=-55°C, Package Quantity=1, Power Rating=62.5mW, Supplier Part Number 1=P57.6KDCCT-ND, Temperature Coefficient=25ppm/°C, Tolerance=0.1%, Voltage Rating=50V
R716 R717 R718 R719 R720: library part Resistor, "Thick Film Resistors 0402 261ohms 1% AEC-Q200", Case/Package=0402, Case Code (Metric)=1005, Manufacturer=Panasonic, Manufacturer Part Number=ERJ-2RKF2610X, Max Operating Temperature=155°C, Max Power Dissipation=100mW, Min Operating Temperature=-55°C, Package Quantity=1, Supplier Part Number 1=P261LCT-ND, Temperature Coefficient=100ppm/°C, Tolerance=1%, Voltage Rating=50V
R764: "RES 0.004 OHM 1% 10W 2818", Case/Package=Nonstandard, Manufacturer=Vishay, Max Operating Temperature=170°C, Max Power Dissipation=10W, Min Operating Temperature=-65°C, Resistance=4mR, Supplier Part Number 1=541-3274-1-ND, Temperature Coefficient=200ppm/°C, Tolerance=1%
R913 R914 R915 R917 R1060 R1061 R1062 R1063 R1064 R1065 R1066 R1069 R1070 R1075 R1076 R1078 R1079 R1081 R1090 R1096 R1102 R1108 R1112 R1114 R1116 R1118 R1120: library part Resistor, "KOA SPEAR ELECTRONICS - RK73H1JTTD1000F - RES, 100R, 1%, 0.1W, 0603, THICK FILM", Case Code (Imperial)=0603, Case Code (Metric)=1608, Manufacturer="KOA Speer", Manufacturer Part Number=RK73H1JTTD1000F, Max Operating Temperature=155°C, Min Operating Temperature=-55°C, Package Quantity=5000, Power Rating=100mW, Supplier Part Number 1=2019-RK73H1JTTD1000FCT-ND, Temperature Coefficient=100ppm/°C, Tolerance=1%, Voltage Rating=50V
R1059 R1089: library part Resistor, Case Code (Imperial)=0402, Case Code (Metric)=1005, Manufacturer=Panasonic, Manufacturer Part Number=ERJ-2RKF2002X, Max Operating Temperature=155°C, Max Power Dissipation=100mW, Min Operating Temperature=-55°C, Package Quantity=1, Supplier Part Number 1=P20.0KLCT-ND, Temperature Coefficient=100ppm/°C, Tolerance=1%, Voltage Rating=50V
S1 S5 S8 S9: library part "SW DIP-4", Current Rating=25mA, Manufacturer=CTS, Manufacturer Part Number=218-4LPSTR, Max Operating Temperature=85°C, Max Voltage Rating (DC)=24V, Min Operating Temperature=-55°C, Package Quantity=2000, Supplier Part Number 1=CT3110CT-ND
S2 S3 S4 S6 S7: "WS-TASV SMT Tact Switch 4.5x4.5mm, height 3.8mm, 160gf", Operating Temperature="-40 to +85degC", Rated Current=50mA, Rated Voltage=12VDC
T1 T2 T3 T4 T24 T25 T26 T28 T29 T31 T32 T33 T36 T37 T38 T39 T40 T41 T42 T43 T44 T45 T46 T47 T48 T49 T50 T51 T52 T53 T54 T55 T56 T57 T58: "Trans MOSFET N-CH 8V 6A 3-Pin SOT-23 T/R", Case/Package=SOT-23, Continuous Drain Current (ID)=6A, Drain to Source Voltage (Vdss)=8V, Gate to Source Voltage (Vgs)=5V, Input Capacitance=1.07nF, Manufacturer=Vishay, Max Operating Temperature=150°C, Max Power Dissipation=2.5W, Min Operating Temperature=-55°C, Package Quantity=3000, Power Dissipation=1.3W, Supplier Part Number 1=SI2342DS-T1-GE3CT-ND, Threshold Voltage=800mV
T5 T6 T9 T10 T13 T15 T17 T19: "MOSFET N-CH 30V 53A TDSON-8", Continuous Drain Current (ID)=53A, Drain to Source Breakdown Voltage=30V, Drain to Source Resistance=8mR, Gate to Source Voltage (Vgs)=20V, Input Capacitance=1.7nF, Manufacturer 1=Infineon, Max Operating Temperature=150°C, Max Power Dissipation=35W, Min Operating Temperature=-55°C, Package Quantity=1, Power Dissipation=2.5W, Supplier Part Number 1=BSC080N03LSGATMA1CT-ND, Threshold Voltage=2.2V
T7 T8 T11 T12 T14 T16 T18 T20: "MOSFET, N CH, 100A, 30V, PG-TDSON-8", Case/Package=TO-252-3, Continuous Drain Current (ID)=100A, Drain to Source Breakdown Voltage=30V, Drain to Source Resistance=4.7mR, Gate to Source Voltage (Vgs)=20V, Input Capacitance=4.3nF, Manufacturer 1=Infineon, Max Operating Temperature=150°C, Max Power Dissipation=69W, Min Operating Temperature=-55°C, Package Quantity=5000, Power Dissipation=2.5W, Supplier Part Number 1="BSC030N03LS G-ND", Threshold Voltage=1V
T21: "WE-RJ45 LAN Transformer, THT, 10/100/1000 Base-T, Port 1x1, Tab Up", Operating Temperature="-40 to +85degC"
T22 T23 T27 T30: "MOSFET MOSFT P-Ch -4.3A 50mOhm 10nC Log Lvl", Case/Package=SOT-23, Continuous Drain Current (ID)=4.3A, Current Rating=-4.3A, Drain to Source Breakdown Voltage=-12V, Drain to Source Resistance=50mR, Drain to Source Voltage (Vdss)=12V, Gate to Source Voltage (Vgs)=8V, Input Capacitance=830pF, Manufacturer="International Rectifier", Max Operating Temperature=150°C, Max Power Dissipation=1.3W, Min Operating Temperature=-55°C, Package Quantity=1, Supplier Part Number 1=IRLML6401PBFCT-ND, Threshold Voltage=-550mV
T34: "MOSFET N-CH 60V 25A LFPAK", Continuous Drain Current (ID)=25A, Drain to Source Resistance=14MR, Drain to Source Voltage (Vdss)=60V, Gate to Source Voltage (Vgs)=20V, Input Capacitance=2.03nF, Manufacturer=Renesas, Max Operating Temperature=150°C, Max Power Dissipation=45W, Min Operating Temperature=-55°C, Package Quantity=1, Supplier Part Number 1=968-RJK0651DPB-00#J5
T35: "MOSFET 80V 6.2mOhm@10V 60A N-Ch MV T-FET", Continuous Drain Current (ID)=60A, Drain to Source Breakdown Voltage=80V, Drain to Source Resistance=6.2mR, Gate to Source Voltage (Vgs)=20V, Input Capacitance=2.425nF, Manufacturer=Vishay, Max Operating Temperature=150°C, Max Power Dissipation=69.4W, Min Operating Temperature=-55°C, On-State Resistance=9.5MR, Package Quantity=1, Supplier Part Number 1=SIJ482DP-T1-GE3CT-ND, Threshold Voltage=1.5V
TP19 TP20 TP21 TP22 TP23 TP25 TP27 TP29 TP31 TP32 TP34 TP35 TP36 TP38 TP42: "TEstPoint", Color=Black, Flammability Rating="UL94 V-0", Manufacturer="Keystone Electronics", Manufacturer Part Number=5001, Package Quantity=100, Supplier Part Number 1=36-5001-ND
U1: "FPGA Zynq UltraScale+ Family 192150 Cells 20nm Technology 0.85V 900-Pin FCBGA Tray", Case/Package=FCBGA, Frequency=500MHz, Manufacturer=Xilinx, Manufacturer Part Number=XCZU4CG-1FBVB900E, Max Operating Temperature=100°C, Min Operating Temperature=0°C, Supplier Part Number 1=217-CZU4CG-1FBVB900E
U3_I2C_Bridge_GPIO U3_I2C_Bridge_PCIE U3_I2C_Bridge_SFP: "8X I2C Switch", Case/Package=VQFN, Manufacturer="Texas Instruments", Manufacturer Part Number=TCA9548ARGER, Max Operating Temperature=85°C, Max Supply Current=80uA, Max Supply Voltage=5.5V, Min Operating Temperature=-40°C, Min Supply Voltage=1.65V, On-State Resistance=70R, Package Quantity=3000, Supplier Part Number 1=296-39222-1-ND
U4 U5 U48: Manufacturer 1="Texas Instruments", Supplier Part Number 1=296-53412-1-ND
U6 U7 U17 U18 U20 U21 U22 U23 U46: "Current Limit Load Switch with OVP and TRCB, 28 V, 5 A", Manufacturer 1="ON Semiconductor", Supplier Part Number 1=863-FPF2895CUCX
U8 U9 U10 U11: "RAM 8GB", Frequency=1.2GHz, Manufacturer="Micron Technology", Manufacturer Part Number=MT40A512M16JY-083EIT:BTR, Max Operating Temperature=95°C, Min Operating Temperature=-40°C, Supplier Part Number 1=557-1690-2-ND
U12 U13: "Dystrybutor Zegarów", Manufacturer="Analog Devices", Manufacturer Part Number=LTC6952IUKG#PBF, Supplier Part Number 1=LTC6952IUKG#PBF-ND
U15 U24_SPI_bridge_Main U24_SPI_bridge_PCIe U25_SPI_bridge_Main U25_SPI_bridge_PCIe U26_SPI_bridge_Main U26_SPI_bridge_PCIe U27_SPI_bridge_Main U27_SPI_bridge_PCIe U28_SPI_bridge_Main U28_SPI_bridge_PCIe U43 U53 U56 U57 U79: Manufacturer 1="Texas Instruments", Supplier Part Number 1=296-SN74AXC4T774PWRCT-ND
U16: Manufacturer="Texas Instruments", Manufacturer Part Number=LMK05028RGCR, Supplier Part Number 1=296-49099-1-ND
U19: "Quad 40 V / 1 A Step-Down Switching Regulator with 100% Duty Cycle Operation, 28-pin QFN (UFD-28), -40 to 125 degC, Pb-Free", Manufacturer="Linear Technology", Supplier Part Number 1=LT3504EUFD#PBF-ND
U30: "DAC 20bit", Case/Package=SSOP, Manufacturer="Texas Instruments", Manufacturer Part Number=DAC1220E, Max Operating Temperature=85°C, Max Supply Voltage=5.25V, Min Operating Temperature=-40°C, Min Supply Voltage=4.75V, Nominal Supply Current=460uA, Operating Supply Voltage=5V, Package Quantity=75, Power Consumption=2.5mW, Supplier Part Number 1=DAC1220E-ND
U31 U32: "IC BUFFER 2:4 LVPECL MUX 16QFN", Case/Package=QFN, Frequency=1.25GHz, Manufacturer 1="Silicon Labs", Max Operating Temperature=85°C, Max Supply Voltage=3.63V, Min Operating Temperature=-40°C, Min Supply Voltage=2.38V, Nominal Supply Current=210mA, Package Quantity=100, Supplier Part Number 1=336-2500-5-ND
U33: "IC, BUF LVPECL CLOCK DRVR 16-VQFN", Case/Package=QFN, Frequency=800MHz, Input Current=10uA, Manufacturer="Texas Instruments", Max Operating Temperature=85°C, Max Supply Voltage=3.6V, Min Operating Temperature=-40°C, Min Supply Voltage=3V, Package Quantity=1, Supplier Part Number 1=296-17045-1-ND
U34 U37 U38: "Analog Devices", Case/Package="LFCSP EP", Max Input Voltage=20V, Max Operating Temperature=85°C, Max Output Current=30A, Min Input Voltage=2.75V, Min Operating Temperature=-40°C, Nominal Supply Current=4.5mA, Operating Supply Current=100uA, Output Current=25A, Output Voltage=18V, Supplier Part Number 1=ADP1850ACPZ-R7CT-ND, Switching Frequency=1.5MHz
U35_I2C_Expander_00 U35_I2C_Expander_01 U35_I2C_Expander_02 U35_I2C_Expander_10 U35_I2C_Expander_11 U35_I2C_Expander_12 U35_I2C_Expander_Main_Rst U35_I2C_Expander_PWR_CLK U35_I2C_Expander_PWR_Dist U35_I2C_Expander_SFP: "16-Bit I/O Expander with Serial Interface, 28-Pin QFN, Extended Temperature", Manufacturer=Microchip, Supplier Part Number 1=MCP23017-E/ML-ND
U36_Trans_LS_I2C0 U36_Trans_LS_I2C1 U36_Trans_PS_I2C0 U36_Trans_PS_I2C1: "I2C [V] Level translator", Low Level Output Current=128mA, Manufacturer="Texas Instruments", Manufacturer Part Number=PCA9306DQER, Max Operating Temperature=85°C, Max Supply Voltage=5V, Min Operating Temperature=-40°C, Min Supply Voltage=0uV, Package Quantity=1, Supplier Part Number 1=296-27957-1-ND
U39: "IC ETHERNET PHY 48VQFN", Case/Package=VQFN, Manufacturer 1="Texas Instruments", Max Operating Temperature=105°C, Max Supply Voltage=2.625V, Min Operating Temperature=-40°C, Min Supply Voltage=950mV, Supplier Part Number 1=296-43254-1-ND
U40 U42 U49 U50 U51 U59_5to3V3_1 U59_5to3V3_2 U59_5V_to_3V3_for_FTDI: "IC REG LDO ADJ 1.5A 8DFN", Case/Package=DFN, Dropout Voltage=330mV, Input Bias Current=120uA, Manufacturer 1=Microchip, Max Input Voltage=6V, Max Operating Temperature=125°C, Max Output Current=1.5A, Min Input Voltage=2.3V, Min Operating Temperature=-40°C, Output Voltage=5V, Package Quantity=3300, Reference Voltage=410mV, Supplier Part Number 1=MCP1727T-ADJE/MFCT-ND
U41: "IC FLASH 64G MMC", Manufacturer 1="Micron Technology", Supplier Part Number 1=340-296563-REEL
U44: "IC SUPERVISORY CIRC DL 16TQFN", Manufacturer=Maxim, Max Operating Temperature=125°C, Max Power Dissipation=2W, Max Supply Voltage=28V, Min Operating Temperature=-40°C, Min Supply Voltage=2.2V, Number of Voltages Monitored=2, Operating Supply Current=52uA, Package Quantity=2500, Supplier Part Number 1=MAX16025TE+TCT-ND
U45: "IC TXRX USB 2.0 FLEXPWR 32QFN", Case/Package=QFN, Frequency=60MHz, Manufacturer 1=Microchip, Max Operating Temperature=85°C, Min Operating Temperature=-40°C, Operating Supply Current=18uA, Operating Supply Voltage=5.5V, Package Quantity=4000, Supplier Part Number 1=USB3320C-EZK-DKR-ND
U47: "Memory Card Interface 25-WLCSP (2.04x2.04)", Manufacturer 1="Nexperia USA", Supplier Part Number 1=1727-8607-1-ND
U54: "MICROCHIP - 93LC56BT-I/OT. - 2K, 128 X 16, SERIAL EE, IND ROHS COMPLIANT: YES", Case/Package=SOT-23, Frequency=2MHz, Manufacturer=Microchip, Max Operating Temperature=85°C, Max Supply Voltage=5.5V, Min Operating Temperature=-40°C, Min Supply Voltage=2.5V, Nominal Supply Current=2mA, Package Quantity=3000, Supplier Part Number 1=93LC56BT-I/OTCT-ND
U55: "IC USB HS QUAD UART/SYNC 64-LQFP", Case/Package=LQFP, Dual Supply Voltage=3.3V, Manufacturer 1=FTDI, Max Operating Temperature=85°C, Max Supply Voltage=3.63V, Min Operating Temperature=-40°C, Min Supply Voltage=1.62V, Operating Supply Current=70mA, Package Quantity=1000, Supplier Part Number 1=768-1026-1-ND
U58: Manufacturer 1=STMicroelectronics, Supplier Part Number 1=497-19784-1-ND
U60 U69: "IC REG LIN POS ADJ 2A 16LFCSP", Case/Package="LFCSP EP", Dropout Voltage=160mV, Manufacturer="Analog Devices", Max Input Voltage=3.6V, Max Operating Temperature=125°C, Max Output Current=2A, Max Output Voltage=3V, Max Supply Current=1.8mA, Min Current Limit=2.4A, Min Input Voltage=1.6V, Min Operating Temperature=-40°C, Min Output Voltage=750mV, Output Voltage Accuracy=1%, Power Supply Rejection Ratio (PSRR)=70dB, Supplier Part Number 1=ADP1741ACPZ-R7CT-ND
U61 U70: "IC REG LINEAR POS ADJ 1A 20QFN", Case/Package=QFN, Dropout Voltage=130mV, Manufacturer="Texas Instruments", Max Operating Temperature=125°C, Min Current Limit=1.5A, Min Operating Temperature=-40°C, Output Current=1A, Output Voltage=5V, Quiescent Current=2mA, Supplier Part Number 1=296-43312-1-ND
U62: "LINEAR TECHNOLOGY         LT3042EDD#PBF             LDO Voltage Regulator, Adjustable, 1.8V to 20V in, 350mV drop, 0V to 15V/0.2A out, DFN-10", Case/Package=DFN, Dropout Voltage=350mV, Manufacturer="Analog Devices / Linear Technology", Max Input Voltage=20V, Max Operating Temperature=125°C, Max Output Voltage=15V, Min Current Limit=220mA, Min Input Voltage=1.8V, Min Operating Temperature=-40°C, Min Output Voltage=0uV, Output Current=200mA, Supplier Part Number 1=LT3042EDD#PBF-ND
U63: "IC TXRX CAN 1MBPS SOT23-8", Case/Package=SOT-23-8, Manufacturer=Maxim, Max Operating Temperature=85°C, Max Supply Current=70mA, Max Supply Voltage=3.465V, Min Operating Temperature=-40°C, Min Supply Voltage=3.135V, Operating Supply Current=35mA, Operating Supply Voltage=3.3V, Package Quantity=1, Supplier Part Number 1=MAX3051EKA+TCT-ND
U64_U_Pomiar_pradu_napiecia_1 U64_U_Pomiar_pradu_napiecia_2 U64_U_Pomiar_pradu_napiecia_3 U64_U_Pomiar_pradu_napiecia_4 U64_U_Pomiar_pradu_napiecia_5 U64_U_Pomiar_pradu_napiecia_6 U64_U_Pomiar_pradu_napiecia_PCIe0 U64_U_Pomiar_pradu_napiecia_PCIe1 U64_U_Pomiar_pradu_napiecia_PCIe2 U64_U_Pomiar_pradu_napiecia_PCIe3 U64_U_Pomiar_pradu_napiecia_PCIe4 U72: "IC MONITOR PWR/CURR BIDIR 10MSOP", Case/Package=VSSOP, Input Bias Current=10uA, Input Offset Voltage (Vos)=2.5uV, Manufacturer="Texas Instruments", Max Operating Temperature=125°C, Max Supply Voltage=5.5V, Min Operating Temperature=-40°C, Min Supply Voltage=2.7V, Nominal Supply Current=330uA, Output Current=10mA, Package Quantity=1, Supplier Part Number 1=296-29034-1-ND
U65: "IC REG CTRLR BUCK 20-TQFN", Manufacturer=Maxim, Supplier Part Number 1=MAX17557ATP+-ND
U67 U68: "IC PWR SUPPLY SEQUENCER SOT23-6", Case/Package=SOT-23-6, Manufacturer="TI National Semiconductor", Max Operating Temperature=125°C, Max Supply Voltage=5.5V, Min Operating Temperature=-40°C, Min Supply Voltage=2.7V, Number of Voltages Monitored=3, Operating Supply Current=25uA, Overvoltage Threshold=1.4V, Package Quantity=250, Supplier Part Number 1=LM3880MFE-1AF/NOPBCT-ND, Undervoltage Threshold=1V
U71: "IC REG LINEAR 8V 500MA SOT223-4", Case/Package=SOT-223-4, Dropout Voltage=2V, Manufacturer="Texas Instruments", Max Input Voltage=25V, Max Operating Temperature=125°C, Max Output Current=500mA, Min Input Voltage=10.5V, Min Operating Temperature=-40°C, Nominal Output Voltage=8V, Package Quantity=1, Power Supply Rejection Ratio (PSRR)=80dB, Quiescent Current=4.6mA, Supplier Part Number 1=296-12612-1-ND
U73: "IC REG LINEAR POS ADJ 800MA 8DFN", Case/Package=DFN, Dropout Voltage=700mV, Input Bias Current=150uA, Manufacturer=STMicroelectronics, Max Input Voltage=5.5V, Max Operating Temperature=125°C, Max Output Current=800mA, Min Input Voltage=1V, Min Operating Temperature=-40°C, Operating Supply Current=200nA, Output Voltage=4V, Package Quantity=2500, Power Supply Rejection Ratio (PSRR)=80dB, Supplier Part Number 1=497-15098-1-ND, Tolerance=2%
U74 U76: "IC GATE AND 1CH 2-INP SOT23-5", Case/Package=SOT-23, High Level Output Current=-32mA, Low Level Output Current=32mA, Manufacturer="Texas Instruments", Max Operating Temperature=125°C, Max Supply Voltage=5.5V, Min Operating Temperature=-40°C, Min Supply Voltage=1.65V, Package Quantity=1, Quiescent Current=10uA, Supplier Part Number 1=296-11601-1-ND
U75: "TVS DIODE 26.5VWM 44VC SOT323", Case/Package=SOT-323-3, Clamping Voltage=44V, Manufacturer=STMicroelectronics, Max Operating Temperature=175°C, Min Breakdown Voltage=28.5V, Min Operating Temperature=-55°C, Peak Pulse Current=3A, Peak Pulse Power=250W, Power Line Protection=No, Reverse Standoff Voltage=26.5V, Supplier Part Number 1=497-15845-1-ND
U77 U78: "Buffer/Driver 2-CH Non-Inverting Open Drain CMOS 6-Pin MicroPak T/R", Low Level Output Current=32mA, Manufacturer="ON Semiconductor / Fairchild", Max Operating Temperature=85°C, Max Supply Voltage=5.5V, Min Operating Temperature=-40°C, Min Supply Voltage=1.65V, Package Quantity=5000, Quiescent Current=1uA, Supplier Part Number 1=NC7WZ07FHXCT-ND
X1: library part CVCO55CC-2000-2000, Frequency=2GHz, Load Capacitance=22pF, Manufacturer=Crystek, Max Operating Temperature=85°C, Min Operating Temperature=-30°C, Operating Supply Voltage=8V, Package Quantity=1, Supplier Part Number 1=549-CVCO55CC20002000
X2: library part CVCO55CL-0490-0540, Case/Package=SMD/SMT, Frequency=540MHz, Load Capacitance=100pF, Manufacturer=Crystek, Max Operating Temperature=85°C, Max Supply Voltage=5.25V, Min Operating Temperature=-40°C, Min Supply Voltage=4.75V, Package Quantity=5, Supplier Part Number 1=744-1174-ND
X3: library part MP024S, "CRYSTAL 2.4576MHZ 32PF T/H", ESR (Equivalent Series Resistance)=300R, Frequency Stability=50ppm, Frequency Tolerance=30ppm, Load Capacitance=32pF, Manufacturer=CTS, Max Operating Temperature=70°C, Min Operating Temperature=-20°C, Package Quantity=100, Supplier Part Number 1=CTX069-ND
X4: "CRYSTAL 25.0000MHZ 18PF SMD", Case/Package=SMD/SMT, ESR (Equivalent Series Resistance)=50R, Frequency=25MHz, Frequency Stability=30ppm, Frequency Tolerance=50ppm, Load Capacitance=18pF, Manufacturer 1=Epson, Max Operating Temperature=70°C, Min Operating Temperature=-20°C, Package Quantity=250, Supplier Part Number 1=SER3691CT-ND
X5: library part FC-13532.7680KA-A5, "CRYSTAL 32.7680 KHZ 12.5PF SMD", Case/Package=SMD/SMT, ESR (Equivalent Series Resistance)=70kR, Frequency Tolerance=20ppm, Load Capacitance=12.5pF, Manufacturer=Epson, Max Operating Temperature=85°C, Min Operating Temperature=-40°C, Supplier Part Number 1=SER4103CT-ND
X6: "SMD Crystal Oscillator 50MHz 3.3V 4-Pin SMD Tray", Case/Package=SMD/SMT, Frequency=50MHz, Frequency Stability=20ppm, Manufacturer="Silicon Labs", Operating Supply Voltage=3.3V, Package Quantity=1, Supplier Part Number 1=336-5245-ND
X7: "CRYSTAL 24.00 MHZ 9.0PF SMD", Case/Package=SMD/SMT, ESR (Equivalent Series Resistance)=40R, Frequency=24MHz, Frequency Stability=15ppm, Frequency Tolerance=10ppm, Load Capacitance=9pF, Manufacturer 1=Epson, Max Operating Temperature=85°C, Min Operating Temperature=-40°C, Supplier Part Number 1=SER4180DKR-ND
X8: Manufacturer 1="ECS International", Supplier Part Number 1=XC2904CT-ND
X9: "OSC MEMS 48.0000MHZ LVCMOS SMD", Case/Package=SMD/SMT, Frequency=48MHz, Frequency Stability=25ppm, Manufacturer=SiTime, Max Operating Temperature=85°C, Max Supply Current=4.5mA, Min Operating Temperature=-40°C, Supplier Part Number 1=1473-30890-1-ND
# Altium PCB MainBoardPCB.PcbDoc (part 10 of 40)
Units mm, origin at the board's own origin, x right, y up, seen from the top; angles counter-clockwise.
Board outline 258.95 x 308.86 mm, 16 copper layers (L1, L2 (GND), L3 (Sign), L4 (GND), L5 (Sign), L6 (PWR/GND), L7(12V+Other), L8 (Plane_GND), L9 (PWR/GND), L10 (3V3+Other), L11 (PWR/GND), L12 (Sign), L13 (GND), L14 (Sign), L15 (GND), L16), stack 2.503 mm thick; 2578 components, 1867 nets, 8817 pads, 8021 vias.
Unrouted connection lines stored in the file: 25.

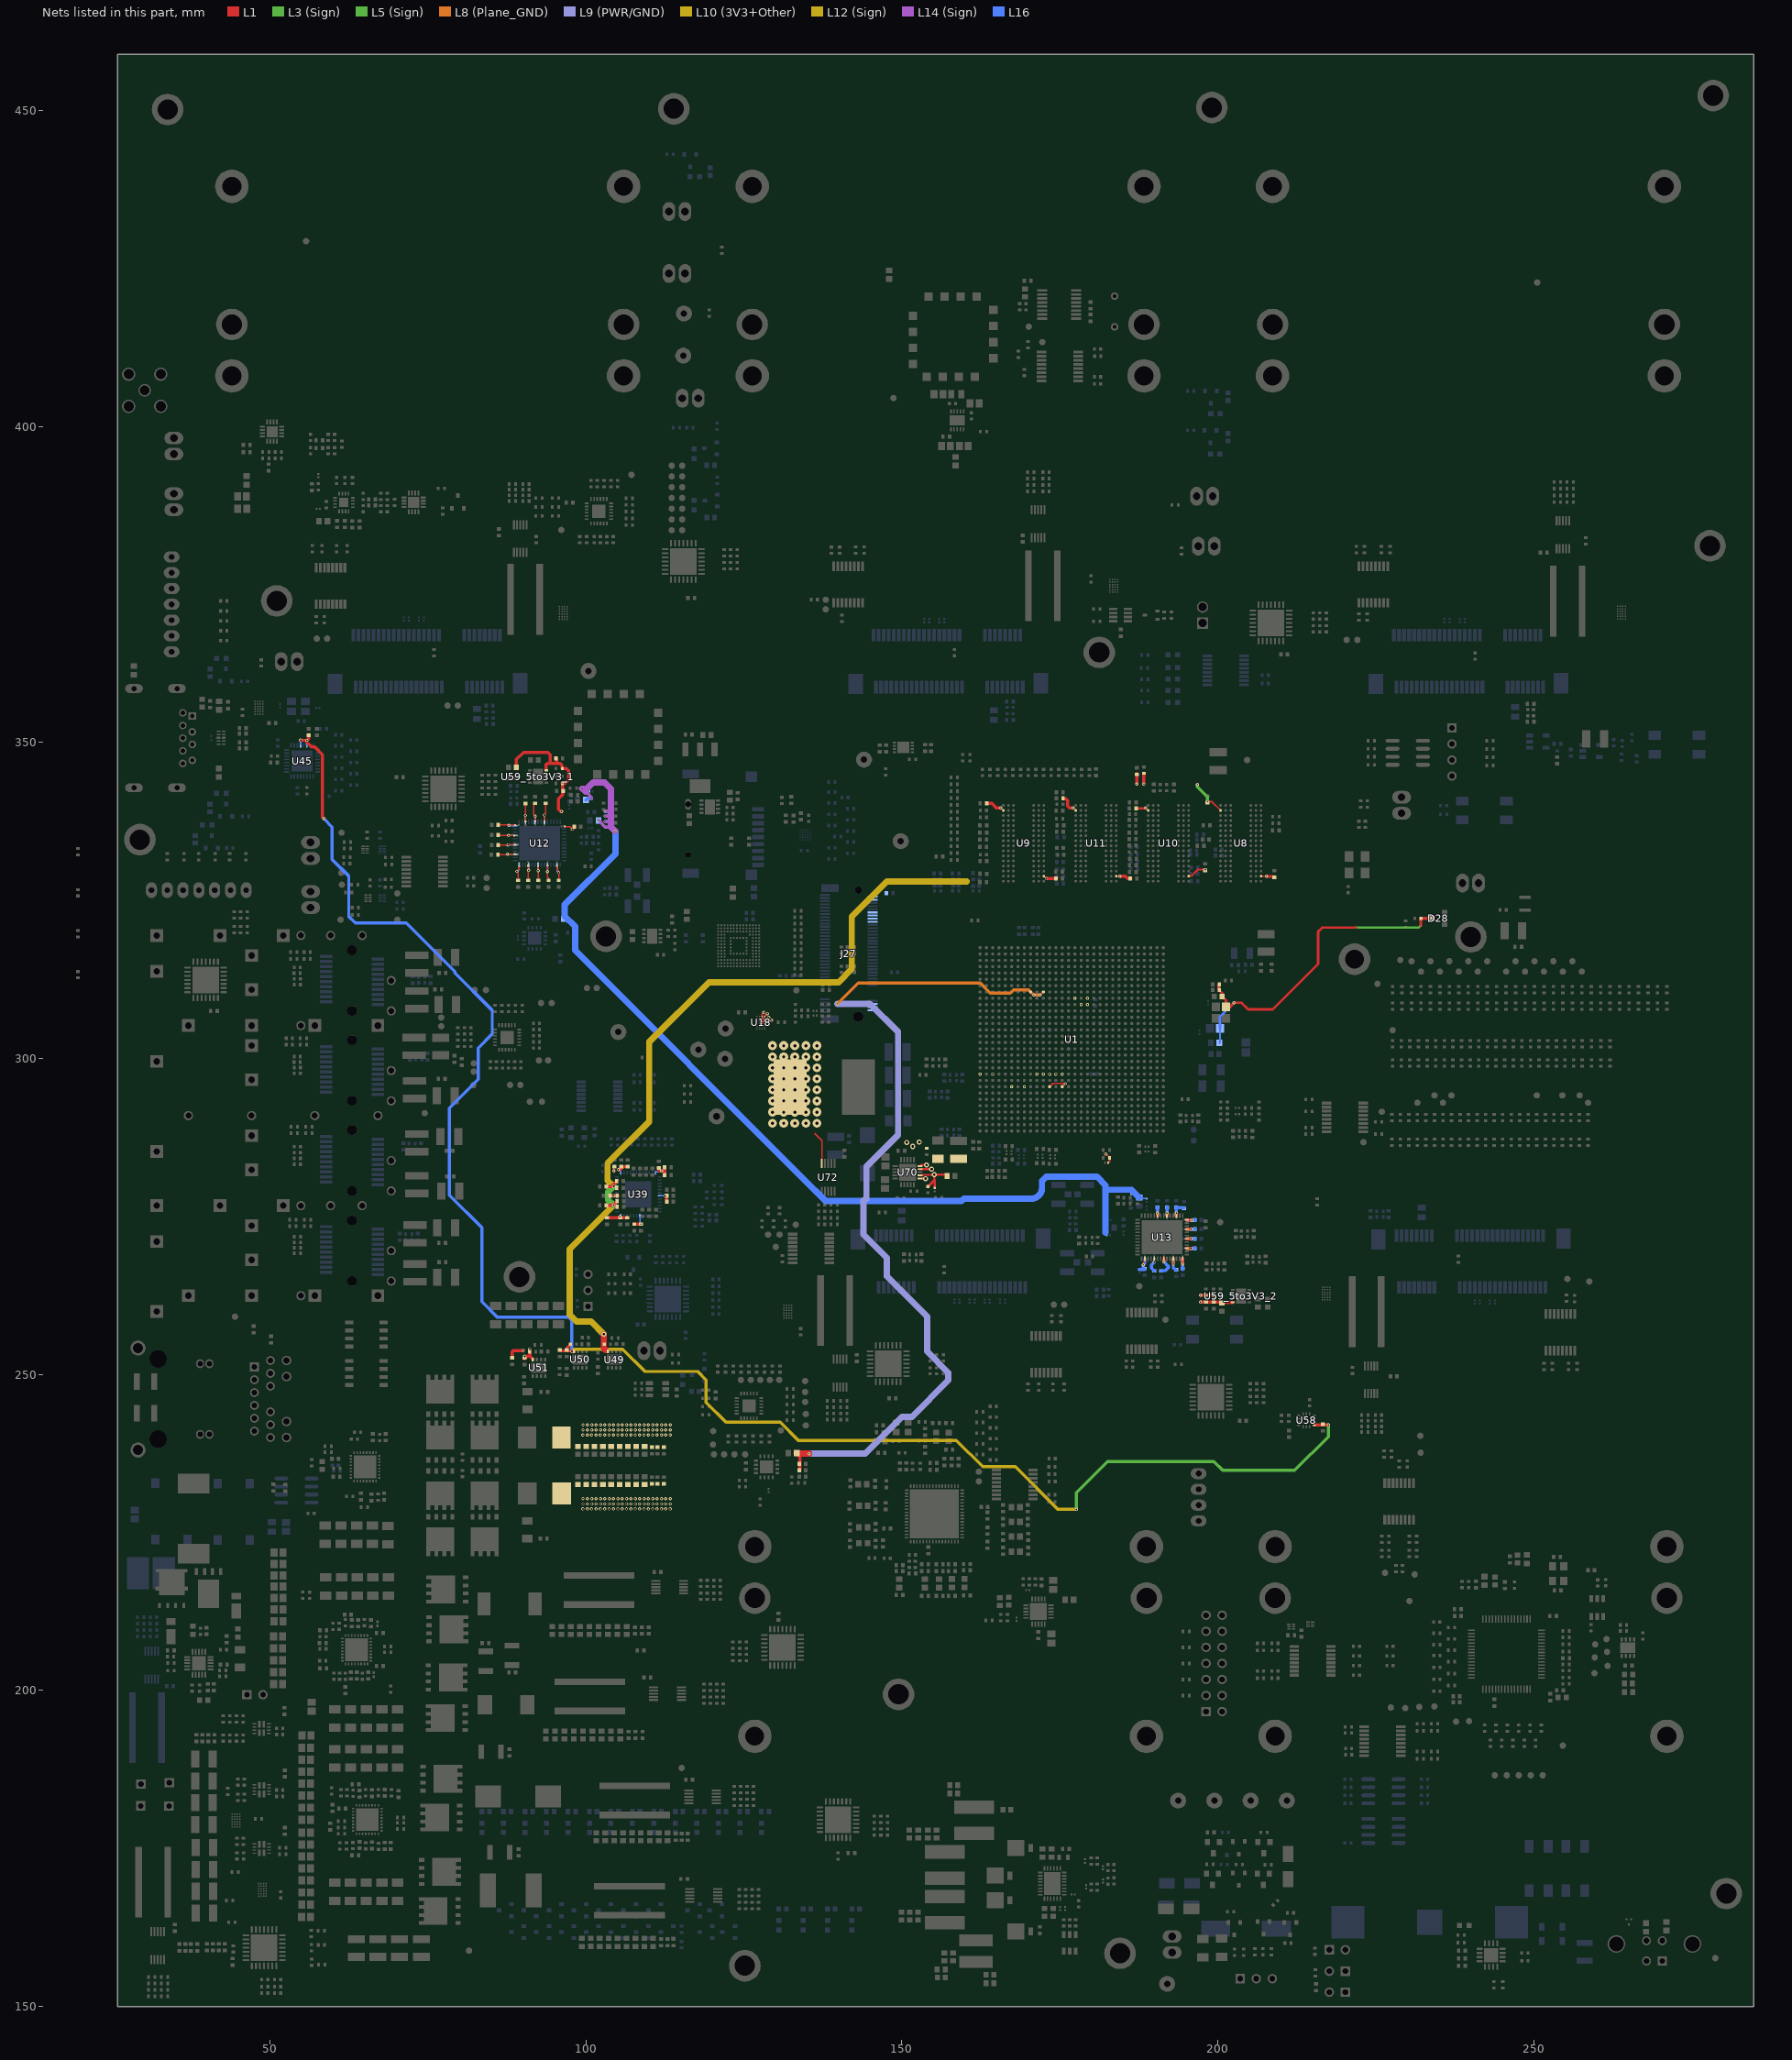
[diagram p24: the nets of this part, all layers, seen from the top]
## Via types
v1: diameter 0.5, hole 0.25, L1 to L16, tented both sides, 4341 vias
v2: diameter 0.254, hole 0.1, L1 to L3 (Sign), tented both sides, 781 vias
v3: diameter 0.5, hole 0.25, L1 to L16, 565 vias
v4: diameter 0.254, hole 0.1, L15 (GND) to L16, tented both sides, 406 vias
v5: diameter 0.254, hole 0.1, L1 to L2 (GND), tented both sides, 283 vias
v6: diameter 0.457, hole 0.2, L3 (Sign) to L6 (PWR/GND), tented both sides, 254 vias
v7: diameter 0.254, hole 0.1, L1 to L3 (Sign), 237 vias
v8: diameter 0.75, hole 0.4, L1 to L16, 200 vias
v9: diameter 0.8, hole 0.4, L1 to L16, tented both sides, 182 vias
v10: diameter 0.254, hole 0.1, L14 (Sign) to L16, tented both sides, 170 vias
v11: diameter 0.75/0/0/0/0/0/0/0/0/0/0/0/0/0/0/0.75 (per signal layer), hole 0.4, L1 to L16, 160 vias
v12: diameter 0.457, hole 0.2, L3 (Sign) to L6 (PWR/GND), 158 vias
v13: diameter 1.4, hole 0.5, L1 to L16, tented both sides, 80 vias
v14: diameter 0.254, hole 0.1, L14 (Sign) to L16, 65 vias
v15: diameter 0.254, hole 0.1, L1 to L2 (GND), 45 vias
v16: diameter 0.457, hole 0.2, L11 (PWR/GND) to L14 (Sign), tented both sides, 26 vias
v17: diameter 0.457, hole 0.2, L11 (PWR/GND) to L14 (Sign), 25 vias
v18: diameter 0.457, hole 0.2, L7(12V+Other) to L10 (3V3+Other), tented both sides, 11 vias
v19: diameter 0.254/0/0.254 (per signal layer), hole 0.1, L1 to L3 (Sign), 9 vias
v20: diameter 0.2/0/0.2 (per signal layer), hole 0.1, L1 to L3 (Sign), 6 vias
v21: diameter 1.65, hole 1.65, L1 to L16, 5 vias
v22: diameter 1.15, hole 1.15, L1 to L16, 5 vias
v23: diameter 0.457, hole 0.2, L1 to L16, 3 vias
v24: diameter 0.5, hole 0.3, L1 to L16, 2 vias
v25: diameter 0.5/0/0.5 (per signal layer), hole 0.2, L14 (Sign) to L16, 1 vias
v26: diameter 0.5, hole 0.25, L1 to L16, tented bottom, 1 vias

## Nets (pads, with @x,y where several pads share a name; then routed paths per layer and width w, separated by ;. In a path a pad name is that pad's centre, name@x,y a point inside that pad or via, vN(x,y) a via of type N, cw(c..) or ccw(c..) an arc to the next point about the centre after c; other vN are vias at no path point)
0.85V@40A_INA: C359.2 C360.2 C361.1 C362.2 C363.2 C364.2 C365.2 C366.2 C367.2 C368.2 C369.2 C370.2 C377.2 C378.2 C379.1 C380.2 C381.2 C382.2 C383.2 C384.2 C385.2 C386.2 C387.2 C388.2 L9.2 L10.2 R617.1 U72.10 | length 5.2
  L1 w0.2: 136.188,288.148 137.353,286.983 U72.10@137.353,283.403
  other v1: 99.543,228.727 100.232,228.727 100.922,228.727 101.612,228.727 102.302,228.727 102.991,228.727 103.681,228.727 104.371,228.727 105.061,228.727 105.75,228.727 106.44,228.727 107.13,228.727 107.82,228.727 108.509,228.727 109.199,228.727 109.889,228.727 110.579,228.727 111.268,228.727 111.958,228.727 112.648,228.727 113.338,228.727 99.554,229.517 100.244,229.517 100.933,229.517 101.623,229.517 102.313,229.517 103.003,229.517 103.693,229.517 104.382,229.517 105.072,229.517 105.762,229.517 106.452,229.517 107.141,229.517 107.831,229.517 108.521,229.517 109.211,229.517 109.9,229.517 110.59,229.517 111.28,229.517 111.97,229.517 112.659,229.517 113.349,229.517 99.554,230.34 100.244,230.34 100.933,230.34 101.623,230.34 102.313,230.34 103.003,230.34 103.693,230.34 104.382,230.34 105.072,230.34 105.762,230.34 106.452,230.34 107.141,230.34 107.831,230.34 108.521,230.34 109.211,230.34 109.9,230.34 110.59,230.34 111.28,230.34 111.97,230.34 112.659,230.34 113.349,230.34 99.543,240.424 100.232,240.424 100.922,240.424 101.612,240.424 102.302,240.424 102.991,240.424 103.681,240.424 104.371,240.424 105.061,240.424 105.75,240.424 106.44,240.424 107.13,240.424 107.82,240.424 108.509,240.424 109.199,240.424 109.889,240.424 110.579,240.424 111.268,240.424 111.958,240.424 112.648,240.424 113.338,240.424 99.554,241.214 100.244,241.214 100.933,241.214 101.623,241.214 102.313,241.214 103.003,241.214 103.693,241.214 104.382,241.214 105.072,241.214 105.762,241.214 106.452,241.214 107.141,241.214 107.831,241.214 108.521,241.214 109.211,241.214 109.9,241.214 110.59,241.214 111.28,241.214 111.97,241.214 112.659,241.214 113.349,241.214 99.554,242.037 100.244,242.037 100.933,242.037 101.623,242.037 102.313,242.037 103.003,242.037 103.693,242.037 104.382,242.037 105.072,242.037 105.762,242.037 106.452,242.037 107.141,242.037 107.831,242.037 108.521,242.037 109.211,242.037 109.9,242.037 110.59,242.037 111.28,242.037 111.97,242.037 112.659,242.037 113.349,242.037
  other v13: 129.565,289.776 131.318,289.776 133.071,289.776 134.823,289.776 136.576,289.776 129.565,291.529 131.318,291.529 133.071,291.529 134.823,291.529 136.576,291.529 129.565,293.282 131.318,293.282 133.071,293.282 134.823,293.282 136.576,293.282 129.565,295.034 131.318,295.034 133.071,295.034 134.823,295.034 136.576,295.034 129.565,296.787 131.318,296.787 133.071,296.787 134.823,296.787 136.576,296.787 129.565,298.539 131.318,298.539 133.071,298.539 134.823,298.539 136.576,298.539 129.565,300.292 131.318,300.292 133.071,300.292 134.823,300.292 136.576,300.292 129.565,302.045 131.318,302.045 133.071,302.045 134.823,302.045 136.576,302.045
0V9@1A_REG3: C709.2 C710.2 R673.2 U1.A10 U1.C10 U1.F8 U1.H8 U1.M8 U1.P8 U70.11 U70.12 | length 12
  L1 w0.2: U1.M8@173.397,295.539 173.909,296.052 175.819,296.052 175.845,296.027 175.845,295.987 U1.P8@175.397,295.539
  L1 w0.3: U70.11@152.889,281.004 v9(153.784,281.004) v9@153.797,281.004 ; U70.12@153.157,281.514 153.217,281.574 153.217,281.614 155.128,281.614 v9(155.141,281.627)
  L1 w0.4: R673.2@154.127,279.698 155.141,280.711 ; C710.2@155.232,279.533 155.232,280.62 155.141,280.711 ; C709.2@157.147,281.407 156.927,281.627 v9(155.141,281.627) 155.141,280.711
  other v1: 167.397,295.539 169.397,295.539 162.397,297.539 164.397,297.539
  other v3: 175.884,296.027
  other v9: 151.752,286.093 150.812,286.74 152.781,286.779
0V85@2A: C675.2 C746.2 FB45.2 U1.J23 U1.L23 | length 142.2
  L1 w0.3: U1.J23@170.397,310.539 v1(170.884,310.052) ; v1(171.909,310.052) U1.L23@172.397,310.539
  L1 w0.5: FB45.2@133.377,237.553 133.377,237.504 133.907,236.974 133.907,235.893 C746.2@133.907,234.865
  L1 w1: FB45.2@133.377,237.553 133.453,237.477 v1(135.344,237.477)
  L8 (Plane_GND) w0.5: v18(139.789,308.661) 139.827,308.661 143.09,311.925 162.433,311.925 164.014,310.344 167.189,310.344 167.702,310.856 170.08,310.856 v1(170.884,310.052) v1(171.909,310.052)
  L9 (PWR/GND) w1: v1(135.344,237.477) 144.238,237.477 150.052,243.291 151.603,243.291 157.387,249.074 157.387,250.296 154.038,253.644 154.038,259.159 147.663,265.534 147.663,268.469 143.942,272.19 143.942,277.431 144.412,277.901 144.412,282.905 149.415,287.909 149.415,304.203 144.957,308.661 v18(139.789,308.661)
1V0@1.5A: C505.1 C506.1 C507.1 C508.1 C509.2 C510.2 C511.2 C512.2 C513.2 C514.2 C555.2 R397.2 U39.6 U39.24 U39.31 U39.42 U51.8 | length 14.8
  L1 w0.5: C513.2@88.332,252.641 88.332,253.595 88.508,253.771 v3(90.124,253.771) ; C555.2@90.322,252.478 90.763,252.919 91.156,252.919 ; R397.2@91.156,253.618 91.156,252.919 ; U51.8@91.595,252.363 91.595,252.481 91.156,252.919 ; C506.1@103.715,278.325 C506.1@103.85,278.325 104.345,278.325 v1(104.349,278.322) 105.073,278.322 C505.1@105.076,278.325 ; C510.2@107.674,273.8 C508.1@108.712,273.8 ; C512.2@111.536,282.682 111.536,282.257 111.593,282.2 v1(111.974,282.2) ; v1@112.08,282.188 112.473,282.188 ; C514.2@112.473,281.585 112.473,282.188 ; C507.1@112.473,282.791 112.473,282.188 ; C511.2@112.805,278.276 C511.2@112.805,278.276 112.807,277.334 C509.2@112.808,277.333
  L16 w0.2: v1(104.349,278.322) 104.395,278.275 U39.6@104.899,278.275 ; U39.42@108.549,275.125 108.549,274.034 108.712,273.871 v1(108.712,273.79) ; U39.24@111.049,281.925 111.049,282.085 111.068,282.103 v1@111.796,282.103 ; U39.31@111.699,278.275 v1(112.53,278.276)
  other v1: 90.322,252.888 91.128,254.018
1V8@0.5A_ADC_filtered: C705.2 C706.2 C749.2 C750.2 C757.1 C758.2 D28.3 FB38.1 FB40.1 FB42.1 R671.2 R694.1 R745.1 U1.K10 U1.L10 U1.M10 U1.N10 U1.P10 U1.T22 U1.U21 U1.V21 U1.V22 U70.14 U70.15 | length 59.2
  L1 w0.254: v1(182.243,284.879) 182.29,284.832 182.393,284.832 182.922,284.303 R671.2@182.922,284.295 ; C706.2@182.661,283.52 182.901,283.76 R671.2@182.901,284.274
  L1 w0.3: U70.14@152.889,282.504 v9(154.745,282.504) ; U70.15@152.889,283.003 153.058,283.172 v9(153.924,283.172) 153.924,283.132 153.925,283.131 v9@153.797,283.003
  L1 w0.4: C758.2@200.139,311.734 200.139,310.883 200.726,310.296 C705.2@200.726,309.829 201.307,309.248 FB38.1@201.307,308.178 201.939,308.178 v1(202.578,308.817) 203.78,308.817 204.826,307.772 208.699,307.772 215.9,314.973 215.9,320.078 216.535,320.713 v2(221.958,320.713) ; v2(232.08,320.993) 232.123,321.036 R694.1@232.123,322.182
  L1 w0.5: R694.1@232.123,322.182 232.131,322.19 233.912,322.19 D28.3@233.92,322.199
  L3 (Sign) w0.4: v2(221.958,320.713) 231.8,320.713 v2(232.08,320.993)
  L16 w0.3: FB42.1@200.268,302.489 200.379,302.599 FB40.1@200.379,304.749
  L16 w0.4: FB40.1@200.379,304.749 200.379,306.618 v1(202.578,308.817)
  other v1: 171.397,297.539 172.397,297.539 173.397,297.539 174.397,297.539 175.397,297.539 178.397,308.539 179.397,308.539 177.397,309.539 179.397,309.539
1V8@1.5A: C1.2 C2.2 C485.1 C486.1 C487.2 C488.2 C489.2 C490.2 C553.2 C561.2 R394.2 U39.13 U39.48 U45.28 U45.30 U50.8 U58.8 | length 289.1
  L1 w0.3: v1(104.427,282.226) C490.2@104.427,282.915
  L1 w0.5: v1(54.855,350.37) 54.868,350.357 v1(55.841,350.357) ; C487.2@56.12,351.273 56.12,350.637 v1(55.841,350.357) ; v1(58.529,337.978) 58.318,338.189 58.318,348.078 57.058,349.339 56.558,349.339 55.841,350.056 v1(55.841,350.357) ; C1.2@95.898,253.747 97.725,253.747 v1(97.801,253.671) U50.8@98.126,253.671 ; C553.2@96.964,253.766 96.964,254.16 R394.2@97.601,254.796 ; C2.2@103.325,274.819 103.333,274.811 106.541,274.811 C488.2@106.549,274.802 ; v1(105.14,282.431) 105.472,282.431 105.947,282.906 C486.1@106.595,282.906 ; U58.8@215.303,242.004 v1(217.513,242.004)
  L5 (Sign) w0.5: v1(177.647,228.653) 177.647,231.305 182.588,236.245 199.39,236.245 200.812,234.823 212.179,234.823 217.513,240.157 v1(217.513,242.004)
  L12 (Sign) w0.5: v1(97.801,253.671) 98.117,253.987 105.855,253.987 109.36,250.482 117.691,250.482 119.05,249.123 119.05,245.58 122.182,242.448 130.773,242.448 133.635,239.585 158.648,239.585 162.827,235.407 167.996,235.407 174.75,228.653 v1(177.647,228.653)
  L16 w0.2: v1(105.14,282.431) 105.33,282.431 105.549,282.212 U39.13@105.549,281.925 ; v1(105.384,274.941) 105.329,274.941 105.329,275.101 105.531,275.101 105.549,275.12 U39.48@105.549,275.125
  L16 w0.3: U45.28@54.855,349.681 v1(54.855,350.37) ; U45.30@55.841,349.668 v1(55.841,350.357)
  L16 w0.5: v1(58.529,337.978) 59.868,336.64 59.868,331.501 62.484,328.884 62.484,322.484 63.531,321.437 71.601,321.437 79.284,313.754 79.284,313.54 85.192,307.633 85.192,303.885 82.958,301.651 82.958,296.723 78.415,292.18 78.415,278.378 83.534,273.258 83.534,261.525 85.954,259.105 97.258,259.105 97.801,258.562 v1(97.801,253.671)
2V5@1.5A: C499.1 C500.1 C501.2 C502.2 C503.2 C504.2 C551.2 C782.2 C783.2 C784.2 C785.2 C786.2 C787.2 C788.2 C789.2 R391.2 R392.2 U8.B1 U8.R6 U9.B1 U9.R6 U10.B1 U10.R6 U11.B1 U11.R6 U39.3 U39.9 U49.8 | length 158.9
  L1 w0.2: U9.B1@172.476,328.86 v1(172.879,328.457) ; U8.B1@206.857,328.86 206.868,328.871 v1(207.752,328.871) 207.774,328.871 v1@207.785,328.86
  L1 w0.25: v1(165.672,339.664) U9.R6@166.076,339.26 ; v1(177.133,339.664) U11.R6@177.536,339.26 ; U11.B1@183.936,328.86 v1@184.423,328.86 ; v1@184.424,328.86 cw(c184.423,328.61) 184.511,328.844 v1(184.518,328.842) ; v1(188.593,339.664) U10.R6@188.997,339.26
  L1 w0.254: C782.2@198.382,340.639 v2(198.387,340.639) 199.094,340.639 ; U8.R6@200.457,339.26 199.094,340.623 199.094,340.639 ; 199.094,340.639 199.094,340.676 199.131,340.639 199.094,340.639
  L1 w0.3: U10.B1@195.397,328.86 195.841,328.86 196.888,329.908 198.022,329.908 198.044,329.886 v1(198.044,329.87)
  L1 w0.4: C783.2@187.077,339.598 188.5,339.598 188.566,339.664 v1(188.593,339.664) ; v1@207.785,328.86 207.826,328.819 C787.2@208.94,328.819
  L1 w0.5: C504.2@103.236,276.787 104.383,276.787 v1(104.395,276.775) ; C502.2@103.258,279.775 v1(104.405,279.775) 104.405,280.087 104.892,280.575 C501.2@104.892,280.625 ; C503.2@104.944,276.536 104.944,276.586 104.919,276.611 104.869,276.611 104.705,276.775 v1(104.395,276.775) ; C499.1@104.945,277.459 104.945,277.409 104.395,276.859 v1(104.395,276.775) ; C785.2@163.435,340.36 164.273,340.36 164.274,340.361 164.971,339.664 v1(165.672,339.664) ; v1(172.879,328.457) 174.467,328.457 C786.2@174.52,328.509 ; C788.2@175.52,341.202 175.52,341.152 175.545,341.127 175.982,341.127 176.275,340.834 176.275,339.957 176.568,339.664 v1(177.133,339.664) ; v1(184.518,328.842) 184.527,328.844 cw(c184.653,328.36) 184.652,328.86 184.654,328.86 185.401,328.86 185.752,328.509 C789.2@186.144,328.509 C789.2@186.279,328.509 ; C551.2@187.177,345.075 187.177,343.427 v1(187.193,343.411) ; v1(188.316,343.433) R392.2@188.316,345.164
  L1 w1: v9(102.851,256.385) 102.851,254.184 103.188,253.848
  L3 (Sign) w0.5: v1(196.788,343.357) 196.788,343.016 198.387,341.417 v2(198.387,340.639)
  L3 (Sign) w1: v1(104.395,276.775) 103.499,277.671 103.499,278.869 v1(104.405,279.775)
  L10 (3V3+Other) w1: v9(102.851,256.385) 100.829,258.407 98.514,258.407 97.447,259.474 97.447,269.827 v1(104.395,276.775) ; v1(104.405,279.775) 103.429,280.751 103.429,283.38 110.033,289.984 110.033,302.603 119.507,312.077 140.005,312.077 142.088,314.16 142.088,322.428 147.663,328.003 160.293,328.003
  L16 w0.2: v1(104.395,276.775) U39.3@104.899,276.775 ; v1(104.405,279.775) U39.9@104.899,279.775
  L16 w0.3: v1(198.044,329.87) v1@198.044,329.895
3.3V_LN_1: C59.2 C60.2 C71.2 C72.2 C84.2 C85.2 C94.2 C95.2 C569.2 FB3.1 FB5.1 FB6.1 FB7.1 FB33.2 | length 163.6
  L14 (Sign) w0.5: 100.005,342.257 100.907,341.355 v14(100.907,341.126) ; v14(102.029,337.682) 103.08,336.632 103.974,336.632 ; v14(103.048,337.49) 103.974,337.49 ; v14(103.048,338.328) 103.087,338.366 103.974,338.366 ; v14(103.048,339.099) 103.097,339.148 103.974,339.148
  L14 (Sign) w1: v14(99.406,342.706) 99.556,342.706 100.005,342.257 100.005,342.545 101.146,343.687 102.941,343.687 103.974,342.654 103.974,339.148 103.974,338.366 103.974,337.49 103.974,336.632 v25(104.631,335.975)
  L16 w0.2: 100.266,342.257 C85.2@100.527,342.257 ; FB7.1@187.623,278 187.782,277.841 C94.2@188.761,277.841
  L16 w0.5: v14(99.406,342.706) 99.855,342.257 100.266,342.257 ; FB6.1@100.03,340.914 100.03,340.926 100.23,341.126 v14(100.907,341.126) ; FB3.1@101.999,337.682 v14(102.029,337.682) ; v14(103.048,337.49) 103.188,337.49 C59.2@103.277,337.579 ; v14(103.048,338.328) 103.056,338.336 C60.2@103.277,338.336 ; v14(103.048,339.099) 103.275,339.099 C84.2@103.28,339.094
  L16 w1: v25(104.631,335.975) 104.697,335.909 104.697,332.375 96.677,324.355 96.677,322.537 98.311,320.904 98.311,317.134 134.398,281.046 134.398,281.027 137.956,277.47 159.461,277.47 159.829,277.838 170.523,277.838 ccw(c170.523,279.509) 172.194,279.509 172.194,280.64 172.86,281.305 180.899,281.305 182.253,279.951 182.253,279.235 ; 182.253,272.429 FB5.1@182.253,273.241 182.253,279.235 ; FB7.1@187.623,278 186.388,279.235 182.253,279.235
3.3V_Stable_1: C149.2 C150.2 C151.2 C152.2 C153.2 C154.2 C155.2 C156.2 C157.2 C158.2 C159.2 C160.2 C161.2 C181.1 C182.1 C183.1 C184.1 C185.1 C186.1 C187.1 C188.1 C189.1 C190.1 C191.1 C192.1 C193.1 C565_5to3V3_1.2 C566_5to3V3_1.2 C567_5to3V3_1.2 R430_5to3V3_1.2 R431_5to3V3_1.2 U12.2 U12.5 U12.8 U12.11 U12.14 U12.17 U12.20 U12.23 U12.26 U12.29 U12.32 U12.35 U59_5to3V3_1.8 | length 70.1
  L1 w0.2: C185.1@85.963,332.296 87.574,332.296 v1(87.599,332.321) C154.2@88.719,332.321 ; C183.1@86.013,333.795 87.707,333.795 v1(87.723,333.811) 87.757,333.845 C152.2@88.754,333.845 ; C190.1@86.013,336.997 87.843,336.997 87.884,336.956 C149.2@88.843,336.956 ; C186.1@86.148,335.396 86.264,335.28 C156.2@88.678,335.28 ; C181.1@89.319,328.063 89.319,329.369 v1(89.072,329.616) 89.459,330.003 C150.2@89.459,330.48 ; C151.2@90.437,337.489 90.437,338.449 C192.1@90.437,340.476 ; C161.2@90.868,330.524 90.869,329.851 v1(90.947,329.772) 90.916,329.741 C189.1@90.916,328.063 ; v1(91.947,338.366) 91.947,338.408 91.722,338.633 91.722,340.082 91.736,340.096 91.736,340.199 91.911,340.374 C188.1@91.961,340.374 ; v1(91.947,338.366) 92.012,338.43 C155.2@92.011,337.524 ; C159.2@92.456,330.473 92.456,328.751 92.513,328.693 C193.1@92.513,328.063 ; C153.2@93.472,337.517 93.442,337.546 93.442,338.508 93.447,338.513 93.447,338.602 93.65,338.805 C184.1@93.65,340.509 ; C158.2@93.98,330.55 93.98,329.839 93.947,329.806 v1(93.947,329.59) 93.947,328.734 94.11,328.571 C191.1@94.11,328.063 ; C160.2@95.428,330.524 95.428,329.921 95.694,329.654 95.694,329.413 v1(95.707,329.4) C187.1@95.707,328.063 ; C157.2@96.64,336.74 96.691,336.69 97.468,336.69 v1(97.868,336.29)
  L1 w0.5: C565_5to3V3_1.2@88.997,346.081 88.997,347.322 90.137,348.463 93.982,348.463 94.348,348.097 94.348,346.723 ; 93.731,345.839 93.731,346.537 93.916,346.723 94.348,346.723 ; C566_5to3V3_1.2@95.393,347.51 95.393,346.761 95.355,346.723 ; v1(96.157,339.099) 96.061,339.099 95.694,339.465 95.694,341.128 96.295,341.728 96.295,342.367 96.295,343.51 96.245,343.56 96.755,343.56 97.259,344.065 97.259,345.542 96.891,345.91 96.214,345.91 96.214,346.432 95.923,346.723 95.355,346.723 ; v1(97.868,336.29) 98.268,336.69 C182.1@98.289,336.69 ; 94.348,346.723 95.355,346.723
  L16 w0.2: v1@87.599,332.311 U12.17@88.797,332.311 ; v1(87.723,333.811) U12.20@88.797,333.811 ; v1@87.775,335.311 U12.23@88.797,335.311 ; v1(87.833,336.906) 87.928,336.811 U12.26@88.797,336.811 ; v1(89.072,329.616) 89.202,329.616 89.447,329.861 U12.14@89.447,330.661 ; U12.29@90.447,337.461 v1(90.447,338.46) ; v1(90.947,329.772) U12.11@90.947,330.661 ; U12.32@91.947,337.461 v1(91.947,338.366) v1@91.961,338.38 ; v1(92.447,329.724) U12.8@92.447,330.661 ; U12.35@93.447,337.461 93.408,337.5 93.472,337.563 93.447,337.588 v1(93.447,338.538) ; v1(93.947,329.59) U12.5@93.947,330.661 ; U12.2@95.447,330.661 95.447,329.66 v1(95.707,329.4)
  other v1: 87.775,335.28
3.3V_Stable_2: C166.2 C167.2 C168.2 C169.2 C170.2 C171.2 C172.2 C173.2 C174.2 C175.2 C176.2 C177.2 C178.2 C194.1 C195.1 C196.1 C197.1 C198.1 C199.1 C200.1 C201.1 C202.1 C203.1 C204.1 C205.1 C206.1 C565_5to3V3_2.2 C566_5to3V3_2.2 C567_5to3V3_2.2 R430_5to3V3_2.2 R431_5to3V3_2.2 U13.2 U13.5 U13.8 U13.11 U13.14 U13.17 U13.20 U13.23 U13.26 U13.29 U13.32 U13.35 U59_5to3V3_2.8 | length 39.5
  L1 w0.2: v1(188.227,267.335) 188.227,267.65 188.473,267.896 U13.2@188.473,268.331 ; U13.5@189.973,268.331 189.973,267.837 ccw(c189.992,267.837) v1(189.992,267.818)
  L1 w0.5: U13.35@190.473,275.131 v1(190.473,275.559) ; U13.8@191.473,268.331 191.481,268.324 v1(191.481,267.841) ; U13.32@191.973,275.131 v1(191.973,275.559) ; v1(192.973,267.478) U13.11@192.973,268.331 ; U13.29@193.473,275.131 v1(193.473,275.559) ; v1(194.473,267.478) U13.14@194.473,268.331 ; U13.17@195.123,269.981 v1(195.812,269.981) ; U13.20@195.123,271.481 v1(195.812,271.481) ; U13.23@195.123,272.981 v1(195.812,272.981) ; U13.26@195.123,274.481 195.148,274.456 195.837,274.456 v1(195.897,274.397) ; v3(197.281,261.448) 197.291,261.458 C567_5to3V3_2.2@198.138,261.458 ; v3(197.291,262.563) 197.316,262.538 R431_5to3V3_2.2@198.138,262.538 199.335,262.538 R430_5to3V3_2.2@199.36,262.513 C566_5to3V3_2.2@199.36,261.458 ; C567_5to3V3_2.2@198.138,261.458 C566_5to3V3_2.2@199.36,261.458 ; U59_5to3V3_2.8@202.345,261.368 200.603,261.368 200.523,261.448 200.19,261.448 200.18,261.458 C566_5to3V3_2.2@199.36,261.458
  L16 w0.2: C176.2@189.973,268.331 189.973,267.837 ccw(c189.992,267.837) v1(189.992,267.818) ; v1@191.473,267.841 C168.2@191.473,268.331
  L16 w0.5: C172.2@187.598,266.621 187.598,266.625 188.473,266.625 188.227,266.871 v1(188.227,267.335) 188.227,267.383 188.473,267.629 C173.2@188.473,268.341 ; C199.1@189.973,266.409 189.923,266.409 189.502,266.829 189.502,267.328 v1(189.992,267.818) ; C175.2@190.473,275.131 v1(190.473,275.559) C205.1@190.473,276.595 ; C194.1@191.059,266.409 191.084,266.434 191.687,266.434 192.243,266.989 192.243,267.071 v1@191.473,267.841 ; C178.2@191.973,275.131 v1(191.973,275.559) C204.1@191.973,276.595 ; C170.2@192.973,268.331 v1(192.973,267.478) 192.973,266.906 193.43,266.449 C197.1@193.43,266.444 ; C166.2@193.473,275.131 v1(193.473,275.559) 193.473,276.595 ccw(c193.643,276.595) 193.643,276.425 C203.1@194.669,276.425 ; C206.1@194.473,266.625 v1(194.473,267.478) C167.2@194.473,268.331 ; C174.2@195.123,269.981 v1(195.812,269.981) C196.1@196.501,269.981 ; C177.2@195.123,271.481 v1(195.812,271.481) C201.1@196.501,271.481 ; C171.2@195.123,272.981 v1(195.812,272.981) C195.1@196.501,272.981 ; C169.2@195.123,274.481 195.208,274.397 v1(195.897,274.397) ; v1@195.897,274.481 C198.1@196.501,274.481
3V3_NVMe: C332.1 J27.2 J27.4 J27.12 J27.14 J27.16 J27.18 J27.62 J27.64 J27.66 U18.C2 U18.D1 U18.D2 U18.E1 U18.E2 U18.F1 U18.F2 | length 4.9
  L1 w0.3: U18.C2@127.898,305.481 U18.D2@127.898,305.881 U18.D1@128.298,305.881 129.163,305.881 v1(129.372,306.09) ; v1(128.191,307.329) 127.898,307.037 U18.F2@127.898,306.681 U18.E2@127.898,306.281 U18.E1@128.298,306.281 128.705,306.281 v1(128.94,306.516) ; U18.F1@128.298,306.681 v1(128.739,307.121)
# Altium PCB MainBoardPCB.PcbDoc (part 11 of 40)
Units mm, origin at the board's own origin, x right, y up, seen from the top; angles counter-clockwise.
Board outline 258.95 x 308.86 mm, 16 copper layers (L1, L2 (GND), L3 (Sign), L4 (GND), L5 (Sign), L6 (PWR/GND), L7(12V+Other), L8 (Plane_GND), L9 (PWR/GND), L10 (3V3+Other), L11 (PWR/GND), L12 (Sign), L13 (GND), L14 (Sign), L15 (GND), L16), stack 2.503 mm thick; 2578 components, 1867 nets, 8817 pads, 8021 vias.
Unrouted connection lines stored in the file: 25.

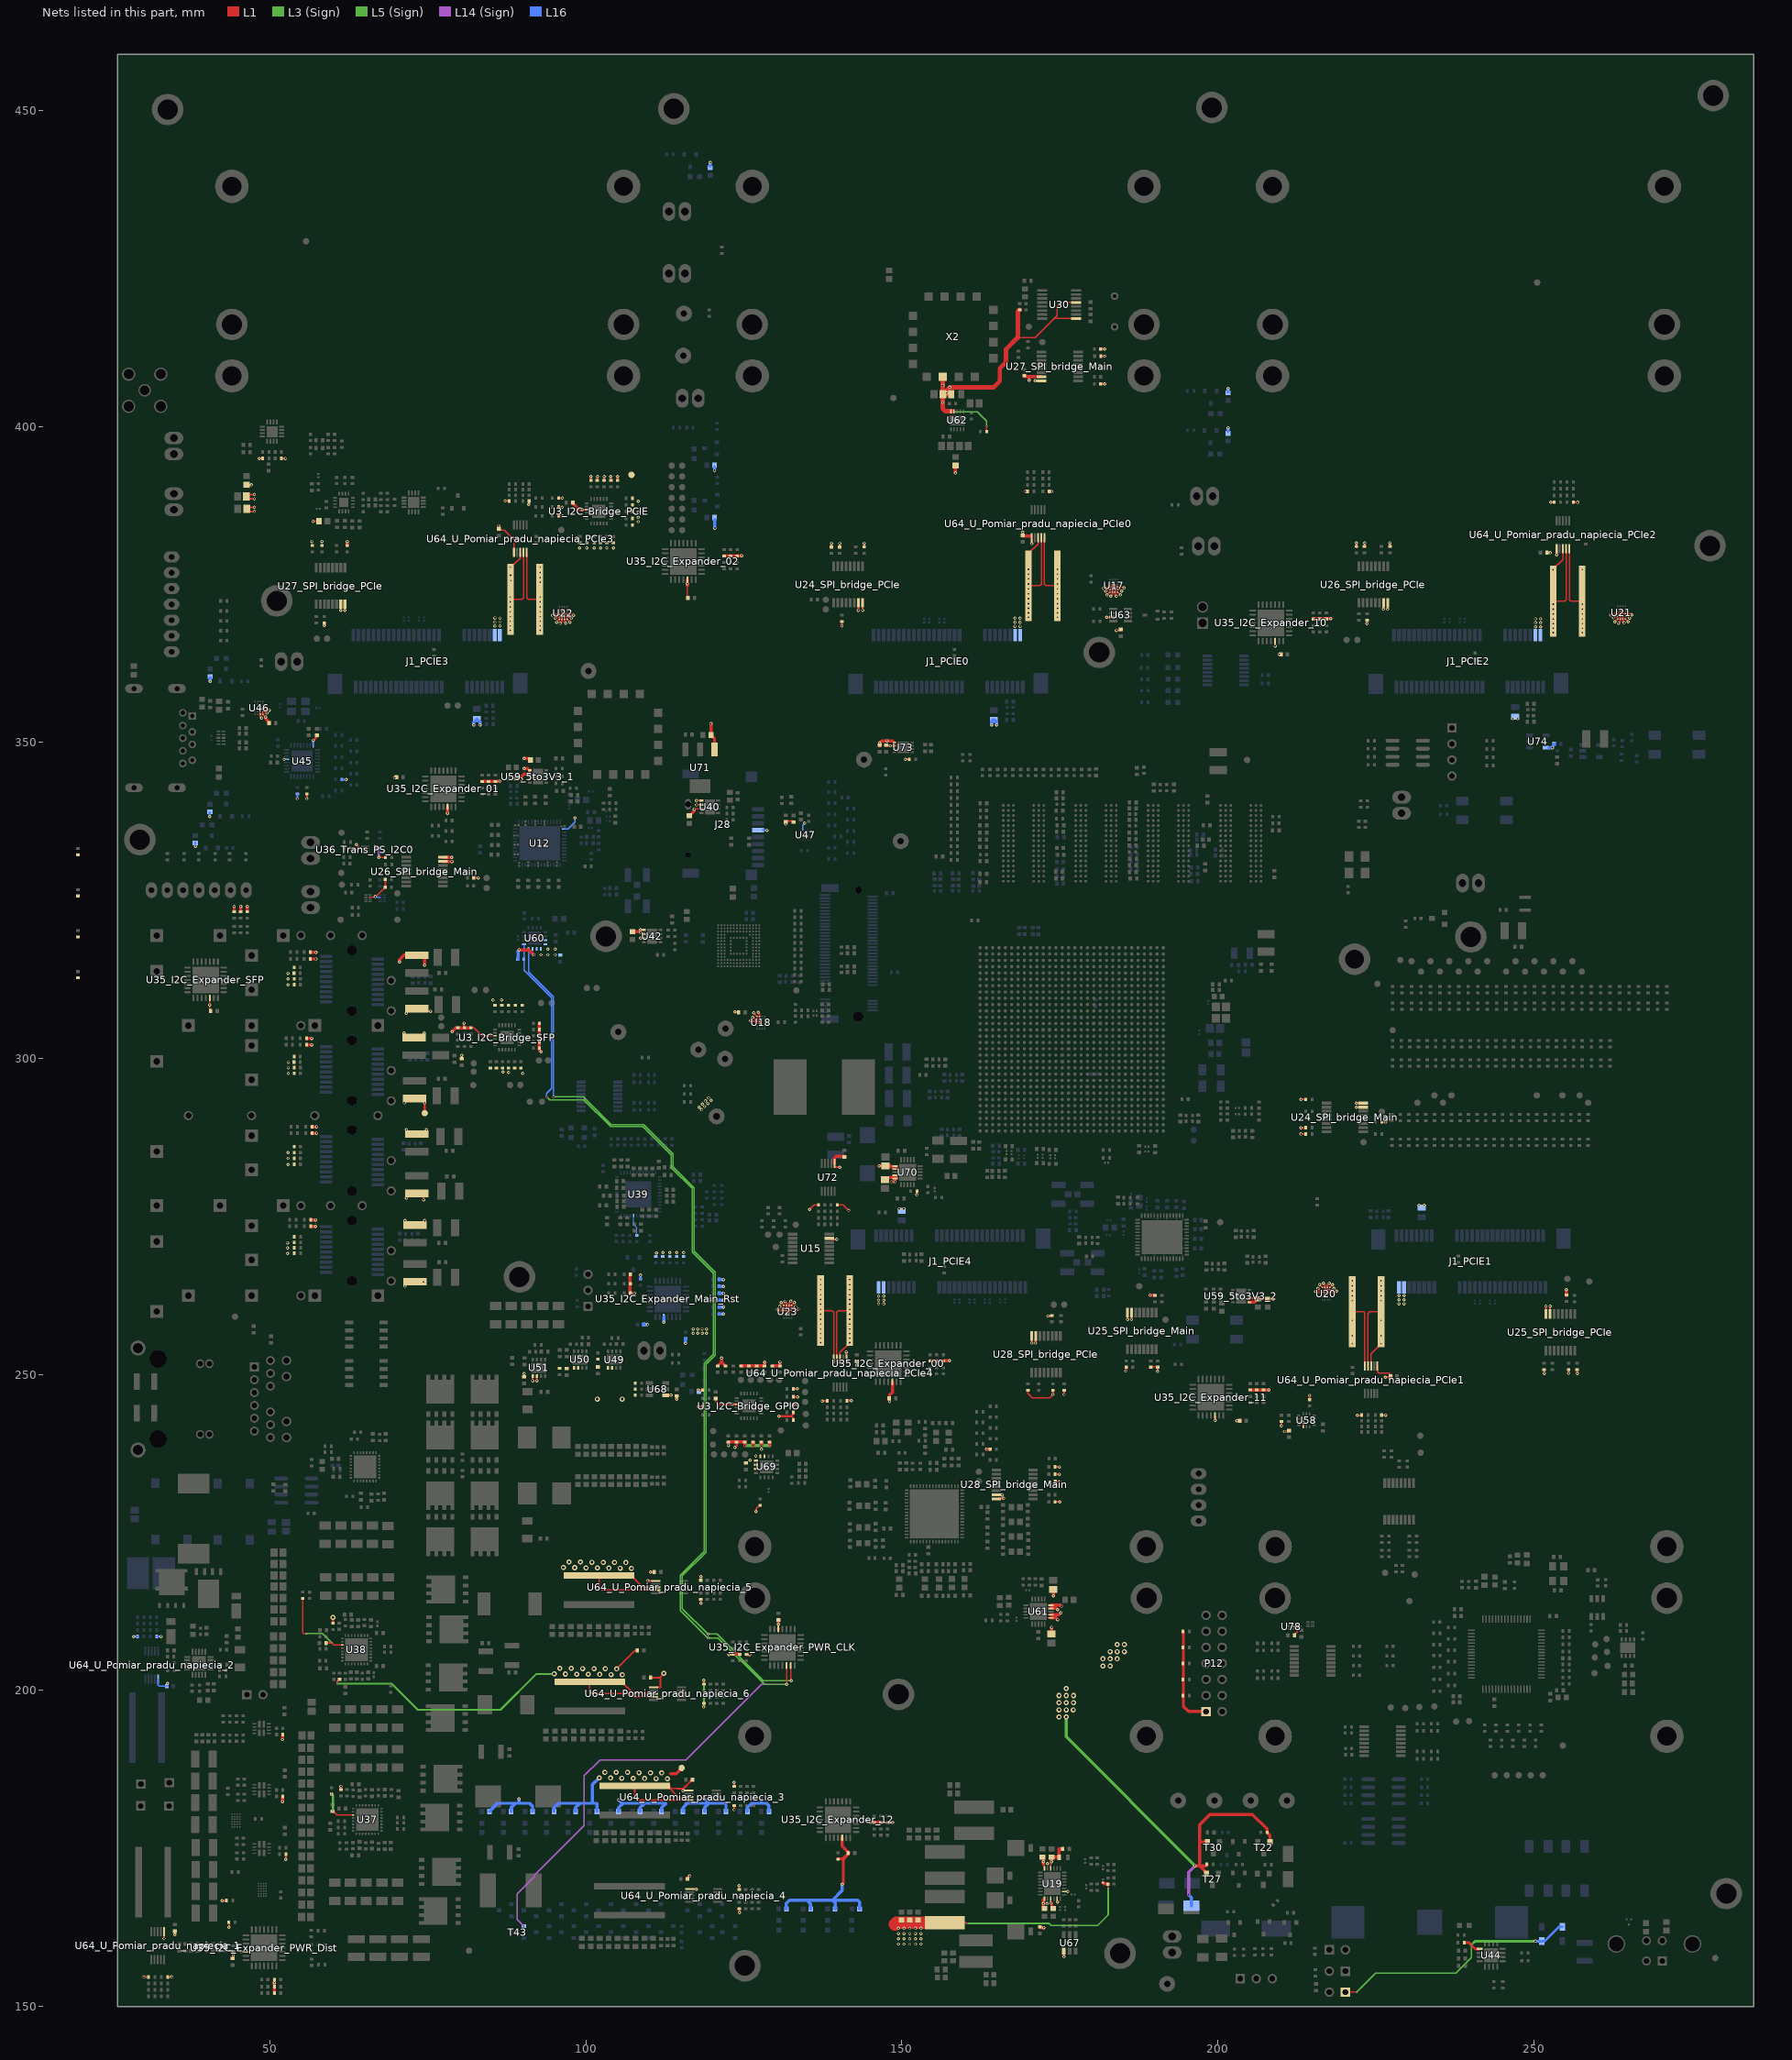
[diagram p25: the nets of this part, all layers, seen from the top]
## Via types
v1: diameter 0.5, hole 0.25, L1 to L16, tented both sides, 4341 vias
v2: diameter 0.254, hole 0.1, L1 to L3 (Sign), tented both sides, 781 vias
v3: diameter 0.5, hole 0.25, L1 to L16, 565 vias
v4: diameter 0.254, hole 0.1, L15 (GND) to L16, tented both sides, 406 vias
v5: diameter 0.254, hole 0.1, L1 to L2 (GND), tented both sides, 283 vias
v6: diameter 0.457, hole 0.2, L3 (Sign) to L6 (PWR/GND), tented both sides, 254 vias
v7: diameter 0.254, hole 0.1, L1 to L3 (Sign), 237 vias
v8: diameter 0.75, hole 0.4, L1 to L16, 200 vias
v9: diameter 0.8, hole 0.4, L1 to L16, tented both sides, 182 vias
v10: diameter 0.254, hole 0.1, L14 (Sign) to L16, tented both sides, 170 vias
v11: diameter 0.75/0/0/0/0/0/0/0/0/0/0/0/0/0/0/0.75 (per signal layer), hole 0.4, L1 to L16, 160 vias
v12: diameter 0.457, hole 0.2, L3 (Sign) to L6 (PWR/GND), 158 vias
v13: diameter 1.4, hole 0.5, L1 to L16, tented both sides, 80 vias
v14: diameter 0.254, hole 0.1, L14 (Sign) to L16, 65 vias
v15: diameter 0.254, hole 0.1, L1 to L2 (GND), 45 vias
v16: diameter 0.457, hole 0.2, L11 (PWR/GND) to L14 (Sign), tented both sides, 26 vias
v17: diameter 0.457, hole 0.2, L11 (PWR/GND) to L14 (Sign), 25 vias
v18: diameter 0.457, hole 0.2, L7(12V+Other) to L10 (3V3+Other), tented both sides, 11 vias
v19: diameter 0.254/0/0.254 (per signal layer), hole 0.1, L1 to L3 (Sign), 9 vias
v20: diameter 0.2/0/0.2 (per signal layer), hole 0.1, L1 to L3 (Sign), 6 vias
v21: diameter 1.65, hole 1.65, L1 to L16, 5 vias
v22: diameter 1.15, hole 1.15, L1 to L16, 5 vias
v23: diameter 0.457, hole 0.2, L1 to L16, 3 vias
v24: diameter 0.5, hole 0.3, L1 to L16, 2 vias
v25: diameter 0.5/0/0.5 (per signal layer), hole 0.2, L14 (Sign) to L16, 1 vias
v26: diameter 0.5, hole 0.25, L1 to L16, tented bottom, 1 vias

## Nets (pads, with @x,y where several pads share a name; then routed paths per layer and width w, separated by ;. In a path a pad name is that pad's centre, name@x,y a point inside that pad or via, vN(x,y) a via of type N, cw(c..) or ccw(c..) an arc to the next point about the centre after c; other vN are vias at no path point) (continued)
3V3_RAIL: C303_I2C_Bridge_GPIO.2 C303_I2C_Bridge_PCIE.2 C303_I2C_Bridge_SFP.2 C309_U_Pomiar_pradu_napiecia_1.2 C309_U_Pomiar_pradu_napiecia_2.2 C309_U_Pomiar_pradu_napiecia_3.2 C309_U_Pomiar_pradu_napiecia_4.2 C309_U_Pomiar_pradu_napiecia_5.2 C309_U_Pomiar_pradu_napiecia_6.2 C309_U_Pomiar_pradu_napiecia_PCIe0.2 C309_U_Pomiar_pradu_napiecia_PCIe1.2 C309_U_Pomiar_pradu_napiecia_PCIe2.2 C309_U_Pomiar_pradu_napiecia_PCIe3.2 C309_U_Pomiar_pradu_napiecia_PCIe4.2 C310.2 C311_I2C_Expander_00.2 C311_I2C_Expander_01.2 C311_I2C_Expander_02.2 C311_I2C_Expander_10.2 C311_I2C_Expander_11.2 C311_I2C_Expander_12.2 C311_I2C_Expander_Main_Rst.2 C311_I2C_Expander_PWR_CLK.2 C311_I2C_Expander_PWR_Dist.2 C311_I2C_Expander_SFP.2 C324.2 C331.1 C339.2 C545.2 C546.2 C550.2 C552.2 C554.2 C562.2 C585.2 C623.2 C654.2 C676.2 C707.2 C708.2 C721.2 C732.1 C735.1 C792.2 F1_PCIE0.2 F1_PCIE1.2 F1_PCIE2.2 F1_PCIE3.2 F1_PCIE4.2 FB23.1 FB24.1 J28.4 L1.1 L2.1 L3.1 L4.1 L5.1 L6.1 L7.1 L8.1 P12.1 R3_I2C_Bridge_GPIO.1 R3_I2C_Bridge_PCIE.1 R3_I2C_Bridge_SFP.1 R4_I2C_Bridge_GPIO.1 R4_I2C_Bridge_PCIE.1 R4_I2C_Bridge_SFP.1 R5_I2C_Bridge_GPIO.1 R5_I2C_Bridge_PCIE.1 R5_I2C_Bridge_SFP.1 R6_I2C_Bridge_GPIO.1 R6_I2C_Bridge_PCIE.1 R6_I2C_Bridge_SFP.1 R7_I2C_Bridge_GPIO.1 R7_I2C_Bridge_PCIE.1 R7_I2C_Bridge_SFP.1 R8_I2C_Bridge_GPIO.1 R8_I2C_Bridge_PCIE.1 R8_I2C_Bridge_SFP.1 R9_I2C_Bridge_GPIO.1 R9_I2C_Bridge_PCIE.1 R9_I2C_Bridge_SFP.1 R10_I2C_Bridge_GPIO.1 R10_I2C_Bridge_PCIE.1 R10_I2C_Bridge_SFP.1 R11.2 R13.1 R16.2 R29.2 R30.2 R65.2 R66.2 R67.2 R68.2 R71.1 R72.1 R124.2 R135.2 R136.2 R137.2 R138.2 R141.1 R142.1 R145.2 R146.2 R147.2 R148.2 R151.1 R152.1 R155.2 R156.2 R157.2 R158.2 R161.1 R162.1 R175.2 R179.2 R184.2 R188.2 R193.2 R197.2 R202.2 R206.2 R211.2 R219.2 R223_I2C_Bridge_GPIO.1 R223_I2C_Bridge_PCIE.1 R223_I2C_Bridge_SFP.1 R224_I2C_Bridge_GPIO.1 R224_I2C_Bridge_PCIE.1 R224_I2C_Bridge_SFP.1 R225_I2C_Bridge_GPIO.1 R225_I2C_Bridge_PCIE.1 R225_I2C_Bridge_SFP.1 R226_I2C_Bridge_GPIO.1 R226_I2C_Bridge_PCIE.1 R226_I2C_Bridge_SFP.1 R227_I2C_Bridge_GPIO.1 R227_I2C_Bridge_PCIE.1 R227_I2C_Bridge_SFP.1 R230.2 R231_SPI_bridge_Main.2 R231_SPI_bridge_PCIe.2 R233_SPI_bridge_Main.2 R233_SPI_bridge_PCIe.2 R236_SPI_bridge_Main.2 R236_SPI_bridge_PCIe.2 R238_SPI_bridge_Main.2 R238_SPI_bridge_PCIe.2 R240_SPI_bridge_Main.2 R240_SPI_bridge_PCIe.2 R241.1 R243.1 R252.2 R253.2 R281.1 R287.2 R376.2 R377.2 R378.2 R388.2 R425_SPI_bridge_Main.2 R425_SPI_bridge_PCIe.2 R426_SPI_bridge_Main.1 R426_SPI_bridge_PCIe.1 R428.2 R429.2 R448_U_Pomiar_pradu_napiecia_3.2 R449.1 R451.1 R453.1 R455.1 R458.1 R462.1 R463.2 R468.2 R469.1 R471.1 R473.1 R475.1 R477.1 R479.1 R492.1 R494.1 R496.1 R500.1 R502.1 R504.1 R508.1 R510.1 R512.1 R516.1 R518.1 R520.1 R524.1 R526.1 R528.1 R558_I2C_Bridge_GPIO.1 R558_I2C_Bridge_PCIE.1 R558_I2C_Bridge_SFP.1 R559_I2C_Bridge_GPIO.1 R559_I2C_Bridge_PCIE.1 R559_I2C_Bridge_SFP.1 R560_I2C_Bridge_GPIO.1 R560_I2C_Bridge_PCIE.1 R560_I2C_Bridge_SFP.1 R562.2 R566.2 R570.2 R574.2 R578.2 R582.2 R586.2 R590.2 R596.2 R599.2 R600.2 R603_SPI_bridge_Main.1 R603_SPI_bridge_PCIe.1 R604_SPI_bridge_Main.2 R604_SPI_bridge_PCIe.2 R605_SPI_bridge_Main.1 R605_SPI_bridge_PCIe.1 R630.1 R632.2 R633.2 R634.2 R646.1 R676.1 R691.1 R697.1 R699.1 R701.1 R730.2 R731.2 R732.2 R733.2 R734.2 R738.1 R740.1 R742.1 R746.2 R747.2 R748.2 R749.2 R750.2 R751.2 R752.2 R753.2 R754.2 R755.2 R756.2 R757.2 R758.1 R760.1 R762.1 R825.1 R826.1 R827.1 R828.1 R887_SPI_bridge_Main.1 R887_SPI_bridge_PCIe.1 R888_SPI_bridge_Main.2 R888_SPI_bridge_PCIe.2 R889_SPI_bridge_Main.1 R889_SPI_bridge_PCIe.1 R891_SPI_bridge_Main.1 R891_SPI_bridge_PCIe.1 R892_SPI_bridge_Main.2 R892_SPI_bridge_PCIe.2 R893_SPI_bridge_Main.1 R893_SPI_bridge_PCIe.1 R895_SPI_bridge_Main.1 R895_SPI_bridge_PCIe.1 R896_SPI_bridge_Main.2 R896_SPI_bridge_PCIe.2 R897_SPI_bridge_Main.1 R897_SPI_bridge_PCIe.1 R899_SPI_bridge_Main.1 R899_SPI_bridge_PCIe.1 R913.2 R914.2 R915.2 R917.2 R1002.2 R1060.2 R1061.2 R1062.2 R1063.2 R1064.2 R1065.2 R1066.2 R1069.2 R1070.2 R1075.2 R1076.2 R1078.2 R1079.2 R1081.2 R1090.2 R1096.2 R1102.2 R1108.2 R1112.2 R1114.2 R1116.2 R1118.2 R1120.2 R1122_Trans_LS_I2C0.1 R1122_Trans_LS_I2C1.1 R1122_Trans_PS_I2C0.1 R1122_Trans_PS_I2C1.1 SP1_I2C_Bridge_GPIO.1 SP1_I2C_Bridge_PCIE.1 SP1_I2C_Bridge_SFP.1 U3_I2C_Bridge_GPIO.21 U3_I2C_Bridge_PCIE.21 U3_I2C_Bridge_SFP.21 U15.15 U18.C3 U18.D3 U18.D4 U18.E3 U18.E4 U18.F3 U18.F4 U19.13 U19.16 U24_SPI_bridge_Main.15 U24_SPI_bridge_Main.16 U24_SPI_bridge_PCIe.15 U24_SPI_bridge_PCIe.16 U25_SPI_bridge_Main.15 U25_SPI_bridge_Main.16 U25_SPI_bridge_PCIe.15 U25_SPI_bridge_PCIe.16 U26_SPI_bridge_Main.15 U26_SPI_bridge_Main.16 U26_SPI_bridge_PCIe.15 U26_SPI_bridge_PCIe.16 U27_SPI_bridge_Main.15 U27_SPI_bridge_Main.16 U27_SPI_bridge_PCIe.15 U27_SPI_bridge_PCIe.16 U28_SPI_bridge_Main.15 U28_SPI_bridge_Main.16 U28_SPI_bridge_PCIe.15 U28_SPI_bridge_PCIe.16 U35_I2C_Expander_00.5 U35_I2C_Expander_01.5 U35_I2C_Expander_02.5 U35_I2C_Expander_10.5 U35_I2C_Expander_11.5 U35_I2C_Expander_12.5 U35_I2C_Expander_Main_Rst.5 U35_I2C_Expander_PWR_CLK.5 U35_I2C_Expander_PWR_Dist.5 U35_I2C_Expander_SFP.5 U36_Trans_PS_I2C0.2 U45.32 U47.A4 U49.1 U49.2 U50.1 U50.2 U51.1 U51.2 U58.5 U63.3 U64_U_Pomiar_pradu_napiecia_1.6 U64_U_Pomiar_pradu_napiecia_2.6 U64_U_Pomiar_pradu_napiecia_3.6 U64_U_Pomiar_pradu_napiecia_3.8 U64_U_Pomiar_pradu_napiecia_3.9 U64_U_Pomiar_pradu_napiecia_4.6 U64_U_Pomiar_pradu_napiecia_5.6 U64_U_Pomiar_pradu_napiecia_6.6 U64_U_Pomiar_pradu_napiecia_PCIe0.6 U64_U_Pomiar_pradu_napiecia_PCIe1.6 U64_U_Pomiar_pradu_napiecia_PCIe2.6 U64_U_Pomiar_pradu_napiecia_PCIe3.6 U64_U_Pomiar_pradu_napiecia_PCIe4.6 U67.1 U68.1 U69.1 U69.2 U69.3 U69.15 U69.16 U70.1 U70.2 U70.4 U70.5 U72.6 U73.2 U74.5 U78.5 | length 421.7
  L1 w0.2: U35_I2C_Expander_SFP.5@40.477,309.578 v1(40.477,308.496) 40.477,307.807 40.562,307.722 40.562,307.717 40.732,307.547 C311_I2C_Expander_SFP.2@40.737,307.547 ; C311_I2C_Expander_PWR_Dist.2@44.121,157.468 44.163,157.509 44.163,158.003 v1(44.204,158.045) ; v1(63.701,333.859) 64.341,333.22 U36_Trans_PS_I2C0.2@64.727,333.22 65.397,333.22 65.512,333.22 ; 65.867,325.536 66.504,325.536 v1@66.596,325.628 ; v1(67.24,331.815) 68.33,331.815 R888_SPI_bridge_Main.2@68.354,331.84 ; R471.1@81.823,304.851 82.308,304.851 83.563,303.596 U3_I2C_Bridge_SFP.21@85.6,303.596 ; C309_U_Pomiar_pradu_napiecia_PCIe3.2@86.22,383.645 87.098,383.645 88.633,382.11 U64_U_Pomiar_pradu_napiecia_PCIe3.6@88.633,380.071 ; U3_I2C_Bridge_PCIE.21@100.127,386.872 U3_I2C_Bridge_PCIE.21@100.135,386.863 ; R448_U_Pomiar_pradu_napiecia_3.2@113.221,184.709 113.221,184.515 113.26,184.476 R448_U_Pomiar_pradu_napiecia_3.2@113.301,184.476 ; 114.401,184.476 R448_U_Pomiar_pradu_napiecia_3.2@113.301,184.476 ; 116.08,374.866 116.08,373.097 116.302,372.875 C311_I2C_Expander_02.2@116.307,372.875 ; U64_U_Pomiar_pradu_napiecia_3.8@116.278,183.159 114.617,183.159 R448_U_Pomiar_pradu_napiecia_3.2@113.301,184.476 ; 130.998,243.428 131.017,243.409 ; v1(135.414,276.105) 136.155,276.846 R388.2@136.866,276.846 ; R16.2@139.754,276.846 140.726,276.846 v1(141.618,275.954) ; R896_SPI_bridge_PCIe.2@169.964,247.556 169.964,247.052 170.686,246.329 173.417,246.329 v1(173.938,246.85) ; U19.13@174.578,167.05 174.603,167.025 174.603,166.558 v1(174.655,166.507) ; U19.16@175.728,168.2 v1(176.283,168.2) ; R605_SPI_bridge_Main.1@189.416,251.223 R887_SPI_bridge_Main.1@190.488,251.223 ; U78.5@211.997,210.124 212.047,210.174 v1(212.983,210.174) 212.915,210.174 212.598,209.856 212.598,209.273 212.027,208.702 C792.2@212.022,208.702 ; U64_U_Pomiar_pradu_napiecia_PCIe1.6@225.281,251.37 225.281,250.426 225.513,250.193 227.161,250.193 227.298,250.056 227.298,249.921 227.468,249.751 227.598,249.751 C309_U_Pomiar_pradu_napiecia_PCIe1.2@227.603,249.751
  L1 w0.3: v1(30.061,154.669) R463.2@30.75,154.669 ; v1(33.245,160.76) U64_U_Pomiar_pradu_napiecia_1.6@33.245,161.449 ; R230.2@33.783,154.669 v1(34.472,154.669) ; v1(34.961,161.359) C309_U_Pomiar_pradu_napiecia_1.2@34.961,162.048 ; v1(42.43,166.723) R29.2@43.119,166.723 ; v1(43.536,162.551) R30.2@43.536,163.24 ; v1(44.204,158.045) R828.1@44.204,158.734 ; v1(45.443,158.652) U35_I2C_Expander_PWR_Dist.5@46.133,158.652 ; FB23.1@46.382,390.768 v1(47.071,390.768) ; C339.2@46.858,386.568 v1(47.548,386.568) ; C339.2@46.858,387.235 v1(47.548,387.235) ; 46.858,388.577 v1(47.548,388.577) ; 46.858,389.255 v1(47.548,389.255) ; v1(48.31,394.936) R252.2@48.843,394.936 ; R253.2@51.847,394.952 v1(52.464,394.952) ; v1(52.5,173.277) 52.525,173.303 52.525,174.066 R630.1@52.55,174.091 ; v1(55.855,341.147) R377.2@55.855,341.837 ; v1(56.828,385.003) FB24.1@57.517,385.003 ; v1(56.855,350.348) 56.898,350.348 57.413,350.863 C732.1@57.413,351.322 ; v1@66.596,325.628 66.635,325.666 66.805,325.666 R891_SPI_bridge_Main.1@68.254,327.115 68.304,327.115 R889_SPI_bridge_Main.1@68.304,328.34 ; L7.1@71.212,303.337 v1(71.212,304.027) ; v1(71.274,292.981) L8.1@71.274,293.671 ; v1(71.362,263.986) L6.1@71.362,264.675 ; L5.1@71.362,273.667 v1(71.362,274.356) ; v1(71.62,277.947) L2.1@71.62,278.636 ; L1.1@71.62,288.07 v1(71.62,288.76) ; v1(71.62,307.17) L4.1@71.62,307.86 ; v1(74.323,264.658) 74.545,264.658 L6.1@74.562,264.675 ; v1(74.323,277.675) 74.323,278.398 L2.1@74.562,278.636 ; L7.1@74.422,303.337 v1(74.422,304.027) ; L8.1@74.474,293.671 v1(74.474,292.981) 74.492,292.963 74.492,291.374 SP1_I2C_Bridge_SFP.1@74.511,291.355 ; L5.1@74.511,273.667 v1(74.511,274.356) ; L4.1@74.737,307.482 v1(75.426,307.482) ; L1.1@74.812,288.07 v1(74.812,288.76) ; C303_I2C_Bridge_SFP.2@80.337,299.79 v1(80.337,300.479) ; v1(80.72,305.594) 80.72,304.938 80.807,304.851 R469.1@80.807,304.822 ; R236_SPI_bridge_Main.2@82.299,328.584 v1(82.989,328.584) ; v1(87.222,388.245) R202.2@87.911,388.245 ; C554.2@90.252,249.455 v1(90.252,250.144) ; v1(90.972,387.678) R206.2@90.972,388.368 ; v1(91.586,249.022) U51.1@91.586,249.711 ; v1(92.244,249.022) U51.2@92.244,249.711 ; R451.1@95.597,385.877 v1(96.287,385.877) ; R449.1@95.597,387.261 v1(96.287,387.261) ; R453.1@95.597,388.683 v1(96.287,388.683) ; v1(99.455,386.863) U3_I2C_Bridge_PCIE.21@100.135,386.863 U3_I2C_Bridge_PCIE.21@100.144,386.863 ; R3_I2C_Bridge_PCIE.1@100.82,391.423 v1(100.82,392.113) ; R4_I2C_Bridge_PCIE.1@101.805,391.423 v1(101.805,392.113) ; R5_I2C_Bridge_PCIE.1@102.895,391.423 v1(102.895,392.113) ; R6_I2C_Bridge_PCIE.1@103.956,391.423 v1(103.956,392.113) ; R7_I2C_Bridge_PCIE.1@105.028,391.423 v1(105.028,392.113) ; R762.1@107.009,262.875 v1(107.679,262.875) ; R448_U_Pomiar_pradu_napiecia_3.2@107.759,184.901 107.759,183.101 108.201,182.659 U64_U_Pomiar_pradu_napiecia_3.9@116.278,182.659 ; v1(109.791,217.348) U64_U_Pomiar_pradu_napiecia_5.6@110.481,217.348 ; C309_U_Pomiar_pradu_napiecia_6.2@110.132,202.052 111.717,202.052 111.825,202.16 ; v1(110.249,218.75) C309_U_Pomiar_pradu_napiecia_5.2@110.938,218.75 ; U64_U_Pomiar_pradu_napiecia_6.6@111.135,200.508 111.825,200.508 111.825,202.16 ; v9(112.367,202.702) 111.825,202.16 ; U68.1@112.793,246.747 v1(113.482,246.747) ; v1(114.383,246.096) C654.2@114.383,246.785 ; 114.401,184.476 115.429,184.476 116.481,185.528 116.481,185.651 116.731,185.901 C309_U_Pomiar_pradu_napiecia_3.2@116.736,185.901 ; U64_U_Pomiar_pradu_napiecia_4.6@116.827,168.572 v1(117.516,168.572) ; v1(117.78,244.934) R243.1@118.469,244.934 ; v1(117.78,247.544) R241.1@118.469,247.544 ; v1(118.212,213.825) R582.2@118.212,214.514 ; R578.2@118.212,217.337 v1(118.212,218.026) ; v1(118.682,197.396) R590.2@118.682,198.085 ; R586.2@118.682,200.923 v1(118.682,201.613) ; C303_I2C_Bridge_GPIO.2@120.56,246.42 120.56,245.822 121.093,245.289 v1(123.198,245.289) U3_I2C_Bridge_GPIO.21@123.878,245.289 U3_I2C_Bridge_GPIO.21@123.887,245.289 ; v1(122.549,238.789) R560_I2C_Bridge_GPIO.1@122.549,239.294 ; R562.2@123.457,184.777 v1(123.457,185.466) ; v1(123.482,181.137) R566.2@123.482,181.826 ; v1(123.568,238.464) 123.619,238.464 123.887,238.732 R559_I2C_Bridge_GPIO.1@123.887,239.344 ; v1(123.588,307.368) C331.1@124.277,307.368 ; R570.2@124.265,168.439 v1(124.265,169.129) ; v1(124.295,164.846) R574.2@124.295,165.535 ; v1(126.057,306.034) 126.21,305.881 U18.D3@127.498,305.881 U18.C3@127.498,305.481 ; v1(126.425,306.529) 126.673,306.281 U18.E4@127.098,306.281 ; v1@126.658,307.121 U18.F4@127.098,306.681 ; v1(126.951,228.321) 126.951,228.735 R646.1@127.577,229.361 ; v1(127.276,307.312) 127.499,307.09 U18.E3@127.498,306.281 ; U35_I2C_Expander_PWR_CLK.5@130.479,209.789 v1(130.479,210.478) ; v1(130.554,243.409) 131.017,243.409 132.537,243.409 ; C545.2@131.629,337.576 C545.2@131.637,337.576 ; v1(131.637,337.087) C545.2@131.637,337.576 ; R8_I2C_Bridge_GPIO.1@132.788,247.742 v1(133.477,247.742) ; R10_I2C_Bridge_GPIO.1@132.802,245.238 v1(133.492,245.238) ; R224_I2C_Bridge_GPIO.1@132.804,242.791 132.804,243.143 132.537,243.409 ; R223_I2C_Bridge_GPIO.1@132.804,244.026 132.804,243.675 132.537,243.409 ; R9_I2C_Bridge_GPIO.1@132.813,246.457 v1(133.503,246.457) ; C546.2@132.863,337.576 C545.2@131.637,337.576 ; v1(137.425,245.815) R219.2@138.114,245.815 ; U15.15@138.89,271.544 139.043,271.392 v1(139.723,271.392) ; R603_SPI_bridge_PCIe.1@138.889,380.843 v1(138.889,381.532) ; U72.6@139.464,282.855 139.515,282.804 v1(140.224,282.804) ; R426_SPI_bridge_PCIe.1@140.183,380.843 v1(140.183,381.532) ; v1(140.532,368.455) R231_SPI_bridge_PCIe.2@140.532,369.144 ; U64_U_Pomiar_pradu_napiecia_PCIe4.6@141.229,252.9 v1(141.229,253.589) ; R211.2@141.325,245.884 v1(142.014,245.884) ; v1(142.919,251.476) C309_U_Pomiar_pradu_napiecia_PCIe4.2@142.919,252.165 ; v1(143.132,370.942) U24_SPI_bridge_PCIe.15@143.132,371.631 ; v1(143.807,370.942) U24_SPI_bridge_PCIe.16@143.807,371.631 ; R425_SPI_bridge_PCIe.2@144.057,380.843 v1(144.057,381.532) ; C721.2@147.511,349.449 147.545,349.484 v1(148.195,349.484) U73.2@148.844,349.484 U73.2@148.884,349.484 ; v1(148.076,245.72) C311_I2C_Expander_00.2@148.076,246.184 ; 148.076,246.753 148.132,246.808 ; v1(150.554,347.364) 150.557,347.361 151.239,347.361 R691.1@151.242,347.358 ; v1(152.416,278.419) R676.1@152.416,279.108 ; U28_SPI_bridge_Main.15@165.208,230.963 v1(165.898,230.963) ; U28_SPI_bridge_Main.16@165.442,230.427 v1(166.132,230.427) ; C309_U_Pomiar_pradu_napiecia_PCIe0.2@169.126,382.609 v1(169.126,383.299) ; v1(170.587,254.974) U28_SPI_bridge_PCIe.16@170.587,255.663 ; v1(170.587,381.48) U64_U_Pomiar_pradu_napiecia_PCIe0.6@170.587,382.169 ; v1(171.103,407.241) U27_SPI_bridge_Main.16@171.793,407.241 ; v1(171.173,254.974) U28_SPI_bridge_PCIe.15@171.173,255.663 ; v1(173.148,259.255) R240_SPI_bridge_PCIe.2@173.837,259.255 ; v1(173.938,246.85) R897_SPI_bridge_PCIe.1@173.938,247.539 ; R124.2@174.244,233.083 v1(174.933,233.083) ; R897_SPI_bridge_Main.1@174.244,234.222 v1(174.933,234.222) ; R899_SPI_bridge_Main.1@174.244,235.377 v1(174.933,235.377) ; R896_SPI_bridge_Main.2@174.351,229.85 v1(175.041,229.85) ; v1(175.676,157.871) U67.1@175.676,158.56 ; v1(175.706,246.85) R899_SPI_bridge_PCIe.1@175.706,247.539 ; R892_SPI_bridge_Main.2@181.429,406.752 v1(182.118,406.752) ; R893_SPI_bridge_Main.1@181.429,411.141 v1(182.118,411.141) ; R895_SPI_bridge_Main.1@181.429,412.28 v1(182.118,412.28) ; v1(182.423,369.815) U63.3@183.112,369.815 ; v1(183.968,367.757) C585.2@184.657,367.757 ; v1(185.492,250.554) R604_SPI_bridge_Main.2@185.492,251.244 ; v1(185.727,258.712) U25_SPI_bridge_Main.16@185.727,259.401 ; v1(186.373,258.712) U25_SPI_bridge_Main.15@186.373,259.401 ; v1(190.488,250.485) R887_SPI_bridge_Main.1@190.488,251.174 ; v1(199.589,242.76) U35_I2C_Expander_11.5@199.589,243.45 ; v1(203.048,242.684) C311_I2C_Expander_11.2@203.737,242.684 ; v1(209.08,365.29) U35_I2C_Expander_10.5@209.08,365.979 ; v1(210.082,241.903) R600.2@210.082,242.592 ; v1(210.584,240.978) C562.2@211.273,240.978 ; v1(213.2,288.068) R603_SPI_bridge_Main.1@213.889,288.068 ; v1(213.2,289.032) R426_SPI_bridge_Main.1@213.889,289.032 ; v1(213.2,293.539) R425_SPI_bridge_Main.2@213.889,293.539 ; U58.5@213.553,241.761 v1(213.553,242.45) ; R429.2@214.541,246.019 v1(214.541,246.708) ; v1(221.933,292.302) U24_SPI_bridge_Main.15@222.622,292.302 ; v1(221.933,292.952) U24_SPI_bridge_Main.16@222.622,292.952 ; R891_SPI_bridge_PCIe.1@221.965,380.893 v1(221.965,381.582) ; v1(222.095,243.535) R188.2@222.784,243.535 ; R889_SPI_bridge_PCIe.1@223.277,380.893 v1(223.277,381.582) ; v1(223.64,368.824) R236_SPI_bridge_PCIe.2@223.64,369.514 ; R184.2@225.907,243.574 v1(226.596,243.574) ; R231_SPI_bridge_Main.2@225.906,289.952 v1(226.596,289.952) ; v1(226.237,371.116) U26_SPI_bridge_PCIe.15@226.237,371.805 ; v1(226.535,249.578) 227.169,249.578 227.173,249.574 227.23,249.631 227.478,249.631 C309_U_Pomiar_pradu_napiecia_PCIe1.2@227.598,249.751 ; v1(226.89,371.116) U26_SPI_bridge_PCIe.16@226.89,371.805 ; R888_SPI_bridge_PCIe.2@227.265,380.92 v1(227.265,381.61) ; v1(251.682,250.183) R604_SPI_bridge_PCIe.2@251.682,250.872 ; C309_U_Pomiar_pradu_napiecia_PCIe2.2@251.924,380.03 v1(252.614,380.03) ; U25_SPI_bridge_PCIe.16@251.941,260.124 v1(251.941,260.813) ; U25_SPI_bridge_PCIe.15@252.608,260.113 v1(252.608,260.802) ; v1(252.696,388.029) R193.2@253.385,388.029 ; v1(253.646,379.725) U64_U_Pomiar_pradu_napiecia_PCIe2.6@253.646,380.415 ; v1(255.538,250.193) R605_SPI_bridge_PCIe.1@255.538,250.883 ; R197.2@256.263,388.01 v1(256.952,388.01) ; v1(256.891,250.164) R887_SPI_bridge_PCIe.1@256.891,250.853
  L1 w0.5: R475.1@44.356,323.227 v1(44.356,324.053) ; R477.1@45.372,323.227 v1(45.372,324.053) ; R479.1@46.449,323.227 v1(46.449,324.053) ; R455.1@50.717,152.11 v3(50.715,153.769) 50.715,154.267 R462.1@50.717,154.269 ; v1(52.017,182.431) R11.2@52.017,183.244 ; v1(52.018,192.237) R13.1@52.018,193.051 ; R162.1@55.84,302.189 v1(56.666,302.189) ; R161.1@55.84,303.205 v1(56.666,303.205) ; R142.1@56.441,315.759 v1(57.267,315.759) ; R141.1@56.441,316.827 v1(57.267,316.827) ; R152.1@56.464,273.456 v1(57.241,273.456) ; R151.1@56.464,274.472 v1(57.241,274.472) ; R72.1@56.566,288.188 v1(57.393,288.188) ; R71.1@56.566,289.204 v1(57.393,289.204) ; v1(58.613,368.538) R238_SPI_bridge_PCIe.2@58.613,368.963 ; R287.2@61.241,184.259 61.241,184.831 v1(61.246,184.836) ; R892_SPI_bridge_PCIe.2@62.238,381.132 v1(62.238,381.826) ; v1(69.748,344.424) 69.748,344.538 69.742,344.544 C311_I2C_Expander_01.2@70.152,344.544 ; v1(70.485,315.283) 70.485,315.62 71.211,316.347 L3.1@73.226,316.347 74.256,316.347 74.536,316.067 74.511,316.041 v1(74.511,314.782) ; U26_SPI_bridge_Main.15@77.373,331.19 78.805,331.19 v1(78.818,331.203) ; U26_SPI_bridge_Main.16@77.373,331.84 v1(78.789,331.84) ; U35_I2C_Expander_01.5@78.113,339.814 78.113,338.817 v1(78.118,338.812) ; v1(78.833,304.282) 79.401,304.851 80.807,304.851 R471.1@81.823,304.851 ; R504.1@83.593,343.884 86.355,343.884 v1(86.374,343.903) ; C309_U_Pomiar_pradu_napiecia_PCIe3.2@86.22,383.864 v1(86.22,384.289) ; R8_I2C_Bridge_SFP.1@92.638,305.56 92.638,301.372 v1(92.926,301.085) ; C303_I2C_Bridge_PCIE.2@97.816,387.96 97.821,387.96 98.918,386.863 v1(99.455,386.863) ; R762.1@107.009,262.865 107.009,262.875 R758.1@107.009,265.852 ; R448_U_Pomiar_pradu_napiecia_3.2@107.759,184.901 107.951,184.709 R448_U_Pomiar_pradu_napiecia_3.2@113.221,184.709 ; 113.47,186.85 114.282,186.85 SP1_I2C_Bridge_GPIO.1@115.176,187.744 ; C309_U_Pomiar_pradu_napiecia_4.2@115.956,170.186 115.961,170.186 116.411,170.636 v1(116.441,170.636) ; 116.08,374.866 v1(116.08,375.133) U35_I2C_Expander_02.5@116.08,375.782 ; R428.2@120.86,251.369 121.469,251.977 121.488,251.977 ; v1(121.488,252.593) 121.488,251.977 ; R512.1@121.873,379.578 v1(124.669,379.578) ; R599.2@122.097,251.369 121.488,251.977 ; R560_I2C_Bridge_GPIO.1@122.562,239.344 123.887,239.344 125.173,239.344 v2(125.173,238.763) ; v1(122.659,205.701) 122.694,205.736 R740.1@124.333,205.736 ; R281.1@124.57,251.369 R3_I2C_Bridge_GPIO.1@125.807,251.369 R4_I2C_Bridge_GPIO.1@127.043,251.369 128.247,251.369 R5_I2C_Bridge_GPIO.1@128.305,251.426 ; R742.1@125.412,205.711 v1(125.947,205.711) ; v2(126.479,238.775) R227_I2C_Bridge_GPIO.1@126.479,239.344 ; R226_I2C_Bridge_GPIO.1@127.784,239.344 127.784,238.773 v2(127.8,238.757) ; R5_I2C_Bridge_GPIO.1@128.28,251.369 128.305,251.394 R5_I2C_Bridge_GPIO.1@128.305,251.426 ; v1(128.322,251.968) 128.305,251.951 R5_I2C_Bridge_GPIO.1@128.305,251.426 ; v2(129.08,238.747) 129.08,239.334 R225_I2C_Bridge_GPIO.1@129.09,239.344 ; R6_I2C_Bridge_GPIO.1@129.517,251.369 R7_I2C_Bridge_GPIO.1@130.753,251.369 130.732,251.39 v1(130.732,251.993) ; U35_I2C_Expander_PWR_CLK.5@130.479,209.703 U35_I2C_Expander_PWR_CLK.5@130.479,209.789 ; v1(130.479,210.478) C311_I2C_Expander_PWR_CLK.2@130.479,211.313 ; U72.6@139.353,283.403 139.353,284.254 139.646,284.547 C310.2@140.907,284.547 ; R825.1@139.916,173.38 140.75,173.38 ; v1(140.564,169.36) 140.75,169.546 140.75,173.38 ; U35_I2C_Expander_12.5@140.566,176.69 140.566,175.359 141.648,174.277 140.75,173.38 ; C311_I2C_Expander_12.2@141.65,174.28 C311_I2C_Expander_12.2@141.655,174.28 ; v1(145.055,179.165) 145.105,179.115 R699.1@146.698,179.115 ; v3@146.415,283.003 148.233,283.003 148.448,282.789 149.165,282.789 ; C708.2@147.331,280.862 147.631,281.162 148.091,281.162 148.156,281.227 149.16,281.227 ; R697.1@147.739,179.115 148.558,179.115 v1(148.565,179.122) ; C311_I2C_Expander_00.2@148.076,246.184 148.076,246.753 ; 148.132,246.808 148.522,247.199 U35_I2C_Expander_00.5@148.522,248.856 ; v1(148.368,280.511) v1(148.939,280.511) U70.5@148.939,281.004 ; R496.1@154.508,252.17 157.538,252.17 v1(157.544,252.176) ; v23(163.401,238.204) 163.408,238.197 R240_SPI_bridge_Main.2@163.976,238.197 ; C309_U_Pomiar_pradu_napiecia_PCIe0.2@169.134,382.663 U64_U_Pomiar_pradu_napiecia_PCIe0.6@170.487,382.663 ; R238_SPI_bridge_Main.2@169.382,408.101 ccw(c169.592,408.101) 169.592,407.891 170.155,407.891 ; v1(169.552,389.74) R175.2@169.977,389.74 ; v1(170.155,407.327) 170.155,407.891 ; C623.2@171.866,162.62 172.001,162.485 v1(172.491,162.484) ; U27_SPI_bridge_Main.15@172.108,407.891 170.155,407.891 ; R179.2@173.29,389.74 v1(173.715,389.74) ; v1(189.278,262.555) 189.987,262.555 R233_SPI_bridge_Main.2@190.081,262.461 ; R730.2@194.566,209.369 194.566,197.509 195.406,196.669 P12.1@198.171,196.669 ; R528.1@205.175,247.56 R526.1@206.191,247.56 R524.1@207.265,247.56 208.104,247.56 v1(208.109,247.556) ; v1(209.728,363.954) C311_I2C_Expander_10.2@210.138,363.954 ; R520.1@215.125,369.595 217.862,369.595 v1(217.894,369.626) ; v1(255.188,263.423) 255.191,263.42 R233_SPI_bridge_PCIe.2@255.191,262.514
  L5 (Sign) w0.3: v1(118.682,197.396) v1(118.682,201.613)
  L3 (Sign) w0.5: v2(125.173,238.763) v2@126.467,238.763 ; v2(126.479,238.775) v2@126.467,238.763 ; v2@129.08,238.763 v2@126.467,238.763
  L14 (Sign) w0.3: v10(66.567,333.659) 67.24,332.986 v1(67.24,331.815)
  L16 w0.2: U64_U_Pomiar_pradu_napiecia_2.6@32.298,201.835 32.298,200.9 32.54,200.659 C309_U_Pomiar_pradu_napiecia_2.2@33.805,200.659 ; v1(66.677,325.628) 66.759,325.628 66.85,325.536 67.43,325.536 ; U47.A4@134.329,336.204 134.329,336.869 134.649,337.188 v1(134.649,337.282)
  L16 w0.3: v1(28.443,208.539) R596.2@29.133,208.539 ; R468.2@32.086,208.547 v1(32.776,208.547) ; C309_U_Pomiar_pradu_napiecia_2.2@33.805,200.762 33.806,200.763 v1(33.807,201.105) v1(33.807,201.105) ; v1(38.205,333.588) R1118.2@38.205,334.277 ; v1(40.468,338.275) R1120.2@40.468,338.964 ; v1(54.347,341.147) R378.2@54.347,341.837 ; U45.32@56.855,349.658 v1(56.855,350.348) ; R376.2@61.366,344.144 v1(62.055,344.144) ; v10(66.567,333.659) 67.015,333.21 67.43,333.21 ; R1002.2@108.648,265.033 v1(108.648,265.722) ; J28.4@127.993,336.132 v1(128.682,336.132) ; U74.5@252.282,349.184 U74.5@252.435,349.184
  L16 w0.5: v1(40.561,359.696) R1112.2@40.561,360.26 ; v1(82.278,352.793) 82.278,353.251 F1_PCIE3.2@82.785,353.758 83.236,353.307 v1(83.236,352.793) ; R1078.2@84.766,180.867 84.766,180.917 86.005,182.156 88.867,182.156 ; R1069.2@88.167,180.867 88.167,181.456 88.867,182.156 ; v1(89.421,182.855) 89.408,182.842 89.408,182.156 ; R1063.2@91.568,180.867 91.568,181.698 91.11,182.156 89.408,182.156 ; R917.2@94.969,180.867 94.969,181.456 95.669,182.156 99.07,182.156 ; R1076.2@98.37,180.867 98.37,181.456 99.07,182.156 ; R1066.2@101.771,180.867 101.771,182.156 101.067,182.156 ; v9(102.113,186.169) 101.067,185.123 101.067,182.156 ; R1062.2@105.173,180.867 105.173,181.456 105.873,182.156 ; v1(105.207,182.677) 105.727,182.156 105.873,182.156 ; R914.2@108.574,180.867 108.574,181.456 109.274,182.156 ; C311_I2C_Expander_Main_Rst.2@109.079,257.892 v1(109.766,257.892) ; R1079.2@111.975,180.867 111.975,181.456 112.675,182.156 109.274,182.156 ; v1(112.347,258.279) U35_I2C_Expander_Main_Rst.5@112.348,259.093 ; R1070.2@115.376,180.867 115.376,181.456 116.076,182.156 119.477,182.156 ; R757.2@115.781,255.727 115.781,254.945 v1(115.786,254.94) ; v1(118.732,182.918) 118.732,182.901 119.477,182.156 ; R1064.2@118.777,180.867 118.777,181.456 119.477,182.156 ; R1108.2@119.702,441.226 v1(119.702,441.79) ; v1(120.367,393.067) R1102.2@120.367,393.63 ; v1(120.434,383.934) 120.434,385.267 R1096.2@120.468,385.301 ; R756.2@121.069,259.588 v1(121.767,259.588) ; R755.2@121.069,260.68 v1(121.767,260.68) ; R754.2@121.069,261.772 v1(121.767,261.772) ; R753.2@121.069,262.865 121.757,262.865 v1(121.767,262.875) ; R752.2@121.069,263.957 121.079,263.947 v1(121.767,263.947) ; R751.2@121.069,265.049 v1(121.767,265.049) ; R1060.2@122.178,180.867 122.178,182.156 119.477,182.156 ; R915.2@125.579,180.867 125.579,181.456 126.279,182.156 127.762,182.156 ; v1(127.762,182.944) 127.762,182.156 ; R913.2@128.98,180.867 128.98,181.789 128.613,182.156 127.762,182.156 ; R1081.2@131.733,165.444 131.733,166.328 132.245,166.84 134.963,166.84 ; R1075.2@135.593,165.444 135.593,166.21 134.963,166.84 ; R1065.2@139.453,165.444 139.453,166.413 139.027,166.84 ; v1(140.564,169.36) 140.564,168.377 139.027,166.84 ; R1061.2@143.313,165.444 143.313,166.547 143.02,166.84 139.027,166.84 ; v1(164.212,352.781) 164.212,353.181 cw(c164.592,353.181) F1_PCIE0.2@164.592,353.56 cw(c164.592,353.154) 164.998,353.154 v1(164.998,352.781) ; R1116.2@201.638,399.248 v1(201.638,399.812) ; R1090.2@201.638,405.48 v1(201.638,406.044) ; U74.5@252.435,349.184 252.777,349.184 253.377,349.783 C735.1@253.382,349.783 ; 88.867,182.156 89.408,182.156 ; 99.07,182.156 101.067,182.156 ; 105.873,182.156 109.274,182.156 ; 134.963,166.84 139.027,166.84
  other v1: 115.374,184.159 125.997,236.461 126.893,237.109 127.8,238.158 52.78,269.153 111.176,269.215 112.195,269.285 113.284,269.308 114.395,269.308 115.498,269.308 52.78,270.015 52.78,270.856 149.608,276.225 150.335,276.225 231.89,276.761 232.69,276.761 52.891,283.247 52.891,284.205 52.891,285.118 52.913,297.676 90.037,297.677 87.79,297.793 86.879,297.864 52.913,298.554 52.913,299.431 126.598,307.231 85.32,309.271 86.645,309.271 52.883,311.671 52.883,312.59 52.883,313.497 252.972,349.184 246.688,353.767 247.488,353.767 61.213,370.926 61.863,370.926 99.004,380.784 100.135,380.784 101.32,380.784 102.325,380.784 103.32,380.784 104.355,380.784 56.672,381.826 58.239,381.826 108.288,384.955 108.288,385.621 108.288,386.433 108.304,388.167
  other v3: 146.414,283.003
  other v9: 112.903,186.048 109.306,186.088 111.104,186.068 107.508,186.109 105.71,186.129 103.911,186.149 110.215,186.977 112.014,186.957 108.417,186.998 103.022,187.058 104.821,187.038 106.599,187.038 105.769,246.109 101.815,246.123
5V_LN: C580.2 R442.2 R443.2 R608.1 U12.42 U30.1 U30.5 U62.9 U62.10 X2.14 | length 58.8
  L1 w0.2: R442.2@163.391,399.212 163.437,399.258 v2(163.437,400.113) ; 168.371,414.045 171.103,414.045 174.151,417.093 ; U30.1@177.584,417.093 174.151,417.093 ; U30.5@177.584,419.633 175.222,419.633 174.612,419.024 174.612,417.554 174.151,417.093
  L1 w0.7: C580.2@156.502,405.414 v1(156.502,406.509) X2.14@156.502,407.899 ; C580.2@156.508,405.114 156.508,404.834 156.488,404.814 v1(156.488,403.832) 156.488,402.841 156.898,402.431 158.102,402.431 ; C580.2@156.678,405.284 v1(157.158,405.284) ; C580.2@156.918,405.524 v1(157.607,406.214) 157.617,406.204 164.512,406.204 165.516,407.207 165.516,409.205 166.51,410.199 166.51,412.277 168.278,414.045 168.371,414.045 168.371,418.197 R608.1@168.671,418.497 ; v1@157.158,405.114 R443.2@157.863,405.114
  L3 (Sign) w0.2: v1(156.488,403.832) 156.488,402.782 156.934,402.336 161.976,402.336 163.437,400.875 v2(163.437,400.113)
  L16 w0.2: U12.42@96.597,336.311 97.214,336.311 98.285,337.382 v1(98.285,338.068)
5V_RAIL: C3.2 C515.2 C516.2 C563_5to3V3_1.2 C563_5to3V3_2.2 C564_5to3V3_1.2 C564_5to3V3_2.2 C574.2 C575.2 C720.2 C733.1 D23.2 R315.2 R448_U_Pomiar_pradu_napiecia_6.2 R651.2 R656.1 T22.1 T27.2 T30.2 U40.1 U40.2 U40.3 U42.1 U42.2 U42.3 U45.21 U46.C3 U46.D3 U46.D4 U46.E3 U46.E4 U46.F3 U46.F4 U59_5to3V3_1.1 U59_5to3V3_1.2 U59_5to3V3_2.1 U59_5to3V3_2.2 U61.1 U61.2 U61.4 U61.5 U64_U_Pomiar_pradu_napiecia_6.8 U64_U_Pomiar_pradu_napiecia_6.9 U73.1 | length 165.9
  L1 w0.2: v9(104.889,203.416) 107.791,206.318 C3.2@108.287,206.318 ; v1(108.658,319.053) 108.659,319.052 U42.3@109.193,319.051 U42.3@109.193,319.051 ; v1(108.661,319.964) 108.681,319.964 108.869,319.776 109.118,319.776 U42.2@109.193,319.701 ; U64_U_Pomiar_pradu_napiecia_6.9@110.741,199.008 107.468,199.008 106.921,199.555 100.848,199.555 100.635,199.769 R448_U_Pomiar_pradu_napiecia_6.2@100.635,201.36 105.71,201.36 107.561,199.508 U64_U_Pomiar_pradu_napiecia_6.8@110.741,199.508 ; v1(117.165,339.471) 117.176,339.482 118.297,339.482 U40.3@118.309,339.494 ; v1(117.526,340.804) 117.531,340.799 118.303,340.799 U40.1@118.309,340.794 ; v1(117.531,340.131) 117.537,340.138 118.302,340.138 U40.2@118.309,340.144
  L1 w0.3: U46.E3@48.475,354.89 U46.F3@48.475,354.49 48.475,354.081 v1(48.698,353.859) ; U46.C3@48.475,355.69 U46.D3@48.475,355.29 U46.D4@48.875,355.29 49.764,355.29 v1(49.917,355.138) ; U46.F4@48.875,354.49 v1(49.315,354.05) ; U46.E4@48.875,354.89 49.301,354.89 v1(49.548,354.642) ; v2(60.664,201.091) 60.664,201.446 R315.2@61.041,201.823
  L1 w0.5: v1(49.315,354.05) 49.315,353.784 50.009,353.09 C733.1@50.014,353.09 ; C563_5to3V3_1.2@89.02,344.43 89.02,344.38 89.17,344.23 89.736,344.23 v1(89.764,344.202) 89.764,344.563 90.237,345.036 U59_5to3V3_1.2@91.047,345.036 ; v1(90.237,345.91) 90.833,345.91 91.136,345.607 U59_5to3V3_1.1@91.131,345.602 ; v1(90.237,347.512) 90.978,347.512 C564_5to3V3_1.2@91.26,347.231 ; C515.2@107.397,320.08 108.388,320.08 v1@108.66,320.353 ; C516.2@116.385,338.434 116.435,338.434 117.165,339.164 v1(117.165,339.471) ; C720.2@146.52,349.449 v1(146.52,349.959) 146.837,350.275 v1(147.695,350.275) 148.553,350.275 U73.1@148.844,349.985 ; U61.1@173.603,211.498 174.414,211.498 v1(174.689,211.223) ; U61.2@173.603,211.998 174.893,211.998 v1(175.192,212.298) ; U61.4@173.603,212.998 174.469,212.998 v1(174.676,212.791) ; U61.5@173.603,213.498 175.115,213.498 v1(175.273,213.34) ; C574.2@173.703,208.934 173.703,209.961 v1(173.736,209.994) ; v1(174.003,214.986) C575.2@174.003,216.013 ; v1(196.434,172.278) 197.117,172.278 ; T27.2@198.211,171.028 198.211,171.184 197.117,172.278 ; R651.2@198.338,172.492 198.124,172.278 197.117,172.278 ; T30.2@198.389,176.006 197.298,176.006 197.117,176.187 ; U59_5to3V3_2.1@204.995,261.438 205.805,261.438 206.315,261.948 C563_5to3V3_2.2@206.365,261.948 ; U59_5to3V3_2.2@204.995,262.088 206.226,262.088 C563_5to3V3_2.2@206.365,261.948 ; T22.1@208.278,176.006 208.278,177.059 207.79,177.547 207.79,178.112 205.499,180.403 198.78,180.403 197.117,178.74 197.117,176.187 ; v1(208.826,261.913) 208.791,261.948 C563_5to3V3_2.2@206.365,261.948 ; 197.117,172.278 197.117,176.187
  L3 (Sign) w0.3: v2(60.664,201.091) 69.254,201.091 73.393,196.952 86.487,196.952 92.164,202.629 v9(94.988,202.629)
  L3 (Sign) w0.5: v9(176.022,195.809) 176.022,192.69 v1(196.434,172.278)
  L14 (Sign) w0.5: v10(195.377,167.684) 195.377,171.221 v1(196.434,172.278)
  L16 w0.2: v1(52.255,347.333) 52.255,347.341 U45.21@52.655,347.341
  L16 w0.5: v10(195.377,167.684) 195.826,167.234 D23.2@195.826,165.952
  other v1: 108.658,320.355
  other v9: 174.91,195.809 174.91,196.939 176.04,196.939 177.152,196.939 174.91,198.069 176.04,198.069 177.17,198.069 174.91,199.2 176.04,199.2 177.17,199.2 176.04,200.33 105.778,202.507 102.181,202.548 103.98,202.527 100.383,202.568 98.585,202.588 96.787,202.608 103.091,203.437 101.292,203.457 99.494,203.477 95.898,203.517 97.696,203.497 181.839,203.886 182.969,203.886 181.839,205.016 182.969,205.016 184.099,205.016 182.969,206.146 184.099,206.146 185.23,206.146 184.099,207.277 185.23,207.277
12V_LT3042: C304.1 C305.1 C306.1 C307.1 C604.2 C714.2 FB34.1 L15.1 R448_U_Pomiar_pradu_napiecia_5.2 R626.2 U17.C3 U17.D3 U17.D4 U17.E3 U17.E4 U17.F3 U17.F4 U19.9 U19.11 U19.26 U19.28 U20.C3 U20.D3 U20.D4 U20.E3 U20.E4 U20.F3 U20.F4 U21.C3 U21.D3 U21.D4 U21.E3 U21.E4 U21.F3 U21.F4 U22.C3 U22.D3 U22.D4 U22.E3 U22.E4 U22.F3 U22.F4 U23.C3 U23.D3 U23.D4 U23.E3 U23.E4 U23.F3 U23.F4 U64_U_Pomiar_pradu_napiecia_5.8 U64_U_Pomiar_pradu_napiecia_5.9 U71.1 | length 59.4
  L1 w0.2: U64_U_Pomiar_pradu_napiecia_5.9@111.071,215.848 111.026,215.893 102.586,215.893 102.092,216.387 R448_U_Pomiar_pradu_napiecia_5.2@102.092,218.187 107.167,218.187 109.006,216.348 U64_U_Pomiar_pradu_napiecia_5.8@111.071,216.348 ; 172.428,172.515 172.553,172.39 172.553,171.875 U19.28@172.578,171.85 ; U19.11@173.578,167.05 173.578,166.389 v3(173.609,166.359) ; U19.26@173.578,171.85 173.578,172.718 173.685,172.825 v1(173.685,172.907)
  L1 w0.3: U22.E3@96.628,369.907 96.628,369.097 v1(96.85,368.875) ; U22.C3@96.628,370.707 U22.D3@96.628,370.307 97.917,370.306 v1(98.07,370.154) ; U22.F4@97.028,369.507 v1(97.468,369.066) ; U22.E4@97.028,369.907 97.454,369.906 v1(97.701,369.659) ; v1(130.313,260.29) 130.466,260.138 U23.D3@131.755,260.138 U23.C3@131.755,259.738 ; v1(130.682,260.786) 130.93,260.538 U23.E4@131.355,260.538 ; v1(130.915,261.378) U23.F4@131.355,260.938 ; v1(131.533,261.569) 131.755,261.347 U23.E3@131.755,260.538 ; U17.E3@183.745,374.202 183.745,373.393 v1(183.968,373.171) ; U17.C3@183.745,375.002 U17.D3@183.745,374.602 185.034,374.602 v1(185.187,374.45) ; U17.F4@184.145,373.802 v1(184.585,373.362) ; U17.E4@184.145,374.202 184.571,374.202 v1(184.819,373.954) ; v1(215.514,263.157) 215.667,263.004 U20.D3@216.956,263.004 U20.C3@216.956,262.604 ; v1(215.883,263.652) 216.131,263.404 U20.E4@216.556,263.404 ; v1(216.116,264.245) U20.F4@216.556,263.804 ; v1(216.734,264.436) 216.956,264.214 U20.E3@216.956,263.404 ; U21.E3@264.109,369.967 264.109,369.157 v1(264.331,368.935) ; U21.C3@264.109,370.767 U21.D3@264.109,370.367 265.398,370.367 v1(265.55,370.214) ; U21.F4@264.509,369.567 v1(264.949,369.126) ; U21.E4@264.509,369.967 264.934,369.967 v1(265.182,369.719)
  L1 w0.4: R626.2@59.997,210.611 v9(59.997,211.56)
  L1 w0.5: v1(119.802,352.984) C714.2@119.802,351.206 119.802,351.156 120.364,350.594 U71.1@120.364,348.924 ; v1(158.498,392.66) FB34.1@158.498,393.834 ; C307.1@172.278,173.657 172.428,173.508 v1(172.428,172.907) 172.428,172.515 ; U19.9@172.453,166.95 172.453,166.925 172.397,166.868 v3(172.397,166.279) 172.397,165.69 172.547,165.54 C304.1@172.578,165.54 ; v3(173.609,166.359) 173.753,166.214 173.753,165.689 173.903,165.539 C306.1@173.953,165.539 ; v1(173.685,172.907) 173.685,173.639 C305.1@173.703,173.658 173.724,173.637 174.883,173.637 L15.1@174.903,173.617 174.903,174.917 174.883,174.938 175.428,174.938 175.453,174.913 C604.2@175.453,174.908
  other v1: 172.971,166.274 173.063,172.608
  other v9: 107.235,219.335 105.437,219.355 103.638,219.375 100.042,219.416 101.84,219.395 98.244,219.436 96.446,219.456 106.346,220.244 104.548,220.264 100.951,220.305 102.749,220.284 99.153,220.325 97.355,220.345
12V_PCIE0: R448_U_Pomiar_pradu_napiecia_PCIe0.1 U17.C2 U17.D1 U17.D2 U17.E1 U17.E2 U17.F1 U17.F2 U64_U_Pomiar_pradu_napiecia_PCIe0.10 | length 14.4
  L1 w0.2: U64_U_Pomiar_pradu_napiecia_PCIe0.10@172.587,382.43 172.587,375.063 172.84,374.81 R448_U_Pomiar_pradu_napiecia_PCIe0.1@174.64,374.81
  L1 w0.3: v1(181.872,374.394) 182.081,374.602 U17.D1@182.945,374.602 U17.D2@183.345,374.602 U17.C2@183.345,375.002 ; v1(182.304,373.967) 182.539,374.202 U17.E1@182.945,374.202 U17.E2@183.345,374.202 U17.F2@183.345,373.802 183.345,373.446 v1(183.053,373.154) ; v1(182.505,373.362) U17.F1@182.945,373.802
  other v1: 174.64,369.821 174.64,370.518 174.64,371.238 174.64,371.988 174.64,372.768 174.64,373.539 174.64,374.318 174.64,375.108 174.64,375.931 174.64,376.642 174.64,377.416
12V_PCIE0_CM: J1_PCIE0.2 J1_PCIE0.4 R448_U_Pomiar_pradu_napiecia_PCIe0.2 U64_U_Pomiar_pradu_napiecia_PCIe0.8 U64_U_Pomiar_pradu_napiecia_PCIe0.9 | length 17.8
  L1 w0.2: U64_U_Pomiar_pradu_napiecia_PCIe0.8@171.587,382.43 171.587,381.432 170.04,379.885 R448_U_Pomiar_pradu_napiecia_PCIe0.2@170.04,374.81 171.84,374.81 172.087,375.057 U64_U_Pomiar_pradu_napiecia_PCIe0.9@172.087,382.43
  other v1: 167.937,368.414 168.741,368.414 167.937,369.036 168.741,369.036 167.937,369.679 168.741,369.679 170.04,369.821 170.04,370.518 170.04,371.238 170.04,371.988 170.04,372.768 170.04,373.539 170.04,374.318 170.04,375.108 170.04,375.931 170.04,376.642 170.04,377.416
12V_PCIE1: R448_U_Pomiar_pradu_napiecia_PCIe1.1 U20.C2 U20.D1 U20.D2 U20.E1 U20.E2 U20.F1 U20.F2 U64_U_Pomiar_pradu_napiecia_PCIe1.10 | length 15.3
  L1 w0.2: R448_U_Pomiar_pradu_napiecia_PCIe1.1@221.282,259.937 223.082,259.937 223.281,259.738 U64_U_Pomiar_pradu_napiecia_PCIe1.10@223.281,251.37
  L1 w0.3: U20.C2@217.356,262.604 U20.D2@217.356,263.004 U20.D1@217.756,263.004 218.62,263.004 v1(218.829,263.213) ; v1(217.648,264.452) 217.356,264.16 U20.F2@217.356,263.804 U20.E2@217.356,263.404 U20.E1@217.756,263.404 218.162,263.404 v1(218.397,263.64) ; U20.F1@217.756,263.804 v1(218.196,264.245)
  other v1: 221.282,254.862 221.282,256.134 221.282,258.58 221.282,261.682 221.282,262.457 221.282,263.23 221.282,264.028 221.282,264.827
12V_PCIE1_CM: J1_PCIE1.2 J1_PCIE1.4 R448_U_Pomiar_pradu_napiecia_PCIe1.2 U64_U_Pomiar_pradu_napiecia_PCIe1.8 U64_U_Pomiar_pradu_napiecia_PCIe1.9 | length 19.7
  L1 w0.2: U64_U_Pomiar_pradu_napiecia_PCIe1.9@223.781,251.37 223.781,259.636 224.082,259.937 R448_U_Pomiar_pradu_napiecia_PCIe1.2@225.882,259.937 v1(225.882,254.862) 224.281,253.261 U64_U_Pomiar_pradu_napiecia_PCIe1.8@224.281,251.37
  other v1: 225.882,256.134 225.882,258.58 228.69,261.2 229.494,261.2 225.882,261.682 228.69,261.821 229.494,261.821 225.882,262.457 228.69,262.464 229.494,262.464 225.882,263.23 225.882,264.028 225.882,264.827
12V_PCIE2: R448_U_Pomiar_pradu_napiecia_PCIe2.1 U21.C2 U21.D1 U21.D2 U21.E1 U21.E2 U21.F1 U21.F2 U64_U_Pomiar_pradu_napiecia_PCIe2.10 | length 15.1
  L1 w0.2: U64_U_Pomiar_pradu_napiecia_PCIe2.10@255.646,380.675 255.646,372.612 255.891,372.367 R448_U_Pomiar_pradu_napiecia_PCIe2.1@257.691,372.367
  L1 w0.3: v1(262.236,370.158) 262.444,370.367 U21.D1@263.309,370.367 U21.D2@263.709,370.367 U21.C2@263.709,370.767 ; v1(262.668,369.731) 262.903,369.967 U21.E1@263.309,369.967 U21.E2@263.709,369.967 U21.F2@263.709,369.567 263.709,369.211 v1(263.417,368.919) ; v1(262.869,369.126) U21.F1@263.309,369.567
  other v1: 257.716,367.392 257.716,368.089 257.716,368.808 257.716,369.558 257.716,370.338 257.716,371.11 257.716,371.888 257.716,377.357
12V_PCIE2_CM: J1_PCIE2.2 J1_PCIE2.4 R448_U_Pomiar_pradu_napiecia_PCIe2.2 U64_U_Pomiar_pradu_napiecia_PCIe2.8 U64_U_Pomiar_pradu_napiecia_PCIe2.9 | length 19.2
  L1 w0.2: v1(253.084,377.349) R448_U_Pomiar_pradu_napiecia_PCIe2.2@253.091,377.349 ; U64_U_Pomiar_pradu_napiecia_PCIe2.8@254.646,380.675 254.646,378.996 253.091,377.442 R448_U_Pomiar_pradu_napiecia_PCIe2.2@253.091,372.367 254.891,372.367 255.146,372.621 U64_U_Pomiar_pradu_napiecia_PCIe2.9@255.146,380.675
  other v1: 253.091,367.392 253.091,368.089 250.29,368.313 251.094,368.313 253.091,368.808 250.29,368.934 251.094,368.934 250.29,369.577 251.094,369.577 253.091,369.558 253.091,370.338 253.091,371.11 253.091,371.888
12V_PCIE3: R448_U_Pomiar_pradu_napiecia_PCIe3.1 U22.C2 U22.D1 U22.D2 U22.E1 U22.E2 U22.F1 U22.F2 U64_U_Pomiar_pradu_napiecia_PCIe3.10 | length 14.2
  L1 w0.2: U64_U_Pomiar_pradu_napiecia_PCIe3.10@90.633,380.071 90.633,372.922 90.891,372.663 R448_U_Pomiar_pradu_napiecia_PCIe3.1@92.691,372.663
  L1 w0.3: v1(94.755,370.098) 94.964,370.306 U22.D2@96.228,370.307 U22.C2@96.228,370.707 ; v1(95.187,369.671) 95.422,369.906 U22.E1@95.828,369.907 U22.E2@96.228,369.907 U22.F2@96.228,369.507 96.228,369.151 v1(95.936,368.859) ; v1(95.388,369.066) U22.F1@95.828,369.507
  other v1: 92.759,367.755 92.759,368.452 92.759,369.172 92.759,369.922 92.759,370.702 92.759,371.473 92.759,372.252 92.759,373.042 92.773,375.387 92.759,376.123 92.761,376.898 92.759,377.72
12V_PCIE3_CM: J1_PCIE3.2 J1_PCIE3.4 R448_U_Pomiar_pradu_napiecia_PCIe3.2 U64_U_Pomiar_pradu_napiecia_PCIe3.8 U64_U_Pomiar_pradu_napiecia_PCIe3.9 | length 17.4
  L1 w0.2: U64_U_Pomiar_pradu_napiecia_PCIe3.8@89.633,380.071 89.633,379.206 88.59,378.163 88.516,378.163 88.091,377.738 v1(88.091,376.457) 88.091,375.628 88.091,373.042 R448_U_Pomiar_pradu_napiecia_PCIe3.2@88.091,372.663 89.891,372.663 90.133,372.905 U64_U_Pomiar_pradu_napiecia_PCIe3.9@90.133,380.071
  other v1: 88.063,367.755 85.619,368.452 86.422,368.452 88.063,368.452 85.619,369.074 86.422,369.074 88.063,369.172 85.619,369.716 86.422,369.716 88.063,369.922 88.063,370.702 88.063,371.473 88.063,372.252 88.063,373.042 88.113,375.628 88.063,377.72
12V_PCIE4: R448_U_Pomiar_pradu_napiecia_PCIe4.1 U23.C2 U23.D1 U23.D2 U23.E1 U23.E2 U23.F1 U23.F2 U64_U_Pomiar_pradu_napiecia_PCIe4.10 | length 14.5
  L1 w0.2: R448_U_Pomiar_pradu_napiecia_PCIe4.1@137.173,260.116 138.973,260.116 139.229,259.86 U64_U_Pomiar_pradu_napiecia_PCIe4.10@139.229,252.404
  L1 w0.3: U23.C2@132.155,259.738 U23.D2@132.155,260.138 U23.D1@132.555,260.138 133.42,260.138 v1(133.628,260.347) ; v1(132.447,261.586) 132.155,261.294 U23.F2@132.155,260.938 U23.E2@132.155,260.538 U23.E1@132.555,260.538 132.961,260.538 v1(133.196,260.773) ; U23.F1@132.555,260.938 v1(132.995,261.378)
  other v1: 137.173,255.041 137.173,255.738 137.173,256.457 137.173,257.207 137.173,257.988 137.173,258.759 137.173,259.537 137.173,260.328 137.173,261.151 137.173,261.861 137.173,262.636 137.173,263.409 137.173,264.207 137.173,265.006
12V_PCIE4_CM: J1_PCIE4.2 J1_PCIE4.4 R448_U_Pomiar_pradu_napiecia_PCIe4.2 U64_U_Pomiar_pradu_napiecia_PCIe4.8 U64_U_Pomiar_pradu_napiecia_PCIe4.9 | length 18
  L1 w0.2: U64_U_Pomiar_pradu_napiecia_PCIe4.9@139.729,252.404 139.729,259.873 139.973,260.116 R448_U_Pomiar_pradu_napiecia_PCIe4.2@141.773,260.116 v1(141.773,255.041) 140.229,253.498 U64_U_Pomiar_pradu_napiecia_PCIe4.8@140.229,252.404
  other v1: 141.773,255.738 141.773,256.457 141.773,257.207 141.773,257.988 141.773,258.759 141.773,259.537 141.773,260.328 141.773,261.151 146.333,261.151 147.137,261.151 146.333,261.772 147.137,261.772 141.773,261.861 146.333,262.415 147.137,262.415 141.773,262.636 141.773,263.409 141.773,264.207 141.773,265.006
\I\N\T\: R709.2 U39.44 | length 3.3
  L16 w0.12: U39.44@107.549,275.125 107.549,273.717 108.074,273.193 R709.2@108.074,271.994
\M\R\: D11.1 D12.1 P5.1 R371.1 U44.13 | length 42.6
  L1 w0.2: P5.1@220.209,152.273 v2(221.988,152.273)
  L1 w0.4: R371.1@239.013,160.096 239.795,160.096 240.785,159.107 U44.13@241.435,159.107
  L3 (Sign) w0.2: v2(221.988,152.273) 224.998,155.283 237.654,155.283 240.132,157.761 v2(240.132,159.728)
  L3 (Sign) w0.4: v2(240.132,159.728) 240.737,160.333 v1(250.266,160.333)
  L16 w0.4: v1(250.266,160.333) D12.1@251.285,160.333 251.697,160.333 253.962,162.598 D11.1@254.555,162.598
ADP1741_3.6V: C308.2 C354.2 C355.2 C570.2 C603.2 L13.2 R113.2 R846.1 U60.1 U60.2 U60.3 U60.15 U60.16 | length 44.7
  L1 w0.254: L13.2@156.819,163.251 160.167,163.251 160.285,163.133 v7(160.311,163.133) ; R113.2@182.642,169.402 182.642,168.709 182.665,168.686 v7(182.665,168.65)
  L1 w0.5: v1(89.43,317.204) 90.984,317.204 v1(91.778,316.411) ; C603.2@181.834,169.606 181.992,169.447 182.597,169.447 R113.2@182.642,169.402
  L1 w2: 148.94,163.022 149.169,163.251 L13.2@156.819,163.251
  L3 (Sign) w0.254: v7(160.311,163.133) 173.335,163.133 173.636,162.832 181.002,162.832 182.665,164.496 v7(182.665,168.65)
  L16 w0.5: R846.1@89.269,315.716 89.269,317.043 v1(89.43,317.204)
  other v1: 149.481,159.889 150.368,159.889 151.269,159.889 152.152,159.889 153.038,159.889 149.481,160.714 150.368,160.714 151.269,160.714 152.152,160.714 153.038,160.714 149.481,161.538 150.368,161.538 151.269,161.538 152.152,161.538 153.038,161.538 149.481,162.363 150.368,162.363 151.269,162.363 152.152,162.363 153.038,162.363 117.021,256.534 117.719,256.538 118.417,256.534 119.115,256.534 117.01,257.213 118.406,257.213 119.104,257.213 117.708,257.217 118.33,291.909 117.936,292.303 118.821,292.405 118.427,292.799 119.317,292.896 118.923,293.29 119.811,293.389 119.417,293.783 92.895,316.411 94.013,316.411 95.13,316.411 94.013,317.311 95.13,317.311
ADP1741_EN: U35_I2C_Expander_PWR_CLK.20 U60.4 | length 149
  L1 w0.2: U35_I2C_Expander_PWR_CLK.20@132.429,203.953 132.429,201.667 v1(132.524,201.571)
  L5 (Sign) w0.2: v6(119.355,208.922) 120.754,208.922 128.105,201.571 v1(132.524,201.571)
  L3 (Sign) w0.2: v1(94.907,293.929) 99.637,293.929 99.787,293.779 99.801,293.779 104.03,289.549 109.157,289.549 113.8,284.906 113.8,282.874 117.118,279.556 117.118,269.517 120.483,266.151 120.483,253.072 119.014,251.604 119.014,221.896 115.269,218.15 115.269,212.971 119.318,208.922 v6(119.355,208.922)
  L16 w0.2: U60.4@90.939,317.353 90.939,313.72 94.907,309.751 v1(94.907,293.929)
ADP1741_PG: R846.2 T43.1 U35_I2C_Expander_PWR_CLK.19 U60.5 | length 218.1
  L1 w0.2: v1(131.778,200.977) U35_I2C_Expander_PWR_CLK.19@131.779,203.953
  L5 (Sign) w0.2: v6(119.355,208.322) 120.93,208.322 128.281,200.971 v1@131.778,200.971
  L3 (Sign) w0.2: v1(93.82,293.929) 94.27,293.479 99.677,293.479 103.906,289.249 109.032,289.249 113.5,284.782 113.5,282.75 116.818,279.432 116.818,269.393 120.183,266.027 120.183,253.197 118.714,251.728 118.714,222.02 114.969,218.275 114.969,212.671 119.318,208.322 v6(119.355,208.322)
  L14 (Sign) w0.2: v10(90.217,162.705) 89.129,163.793 89.129,167.8 91.885,170.556 91.885,170.808 99.738,178.661 99.738,186.532 102.241,189.035 115.842,189.035 127.785,200.977 v1(131.778,200.977)
  L16 w0.2: U60.5@90.239,318.053 90.239,313.995 94.602,309.632 94.602,295.262 93.82,294.48 v1(93.82,293.929)
ADP_Vin_1: C395.1 R285.2 U37.3 | length 6.3
  L1 w0.2: v2(59.93,181.011) 60.625,180.317 U37.3@63.175,180.317
  L3 (Sign) w0.4: v2(59.728,183.629) 59.989,183.368 59.989,181.07 v2(59.93,181.011)
ADP_Vin_2: C436.1 R303.2 U38.3 | length 13.6
  L1 w0.2: R303.2@55.203,214.637 55.203,209.147 55.359,208.991 v2(55.728,208.991)
  L1 w0.254: C436.1@58.746,207.523 v2(59.82,207.523) 60.129,207.214 U38.3@61.453,207.214
  L3 (Sign) w0.2: v2(55.728,208.991) 58.351,208.991 v2(59.82,207.523)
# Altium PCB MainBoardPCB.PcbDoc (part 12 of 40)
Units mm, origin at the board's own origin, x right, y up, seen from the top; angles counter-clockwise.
Board outline 258.95 x 308.86 mm, 16 copper layers (L1, L2 (GND), L3 (Sign), L4 (GND), L5 (Sign), L6 (PWR/GND), L7(12V+Other), L8 (Plane_GND), L9 (PWR/GND), L10 (3V3+Other), L11 (PWR/GND), L12 (Sign), L13 (GND), L14 (Sign), L15 (GND), L16), stack 2.503 mm thick; 2578 components, 1867 nets, 8817 pads, 8021 vias.
Unrouted connection lines stored in the file: 25.

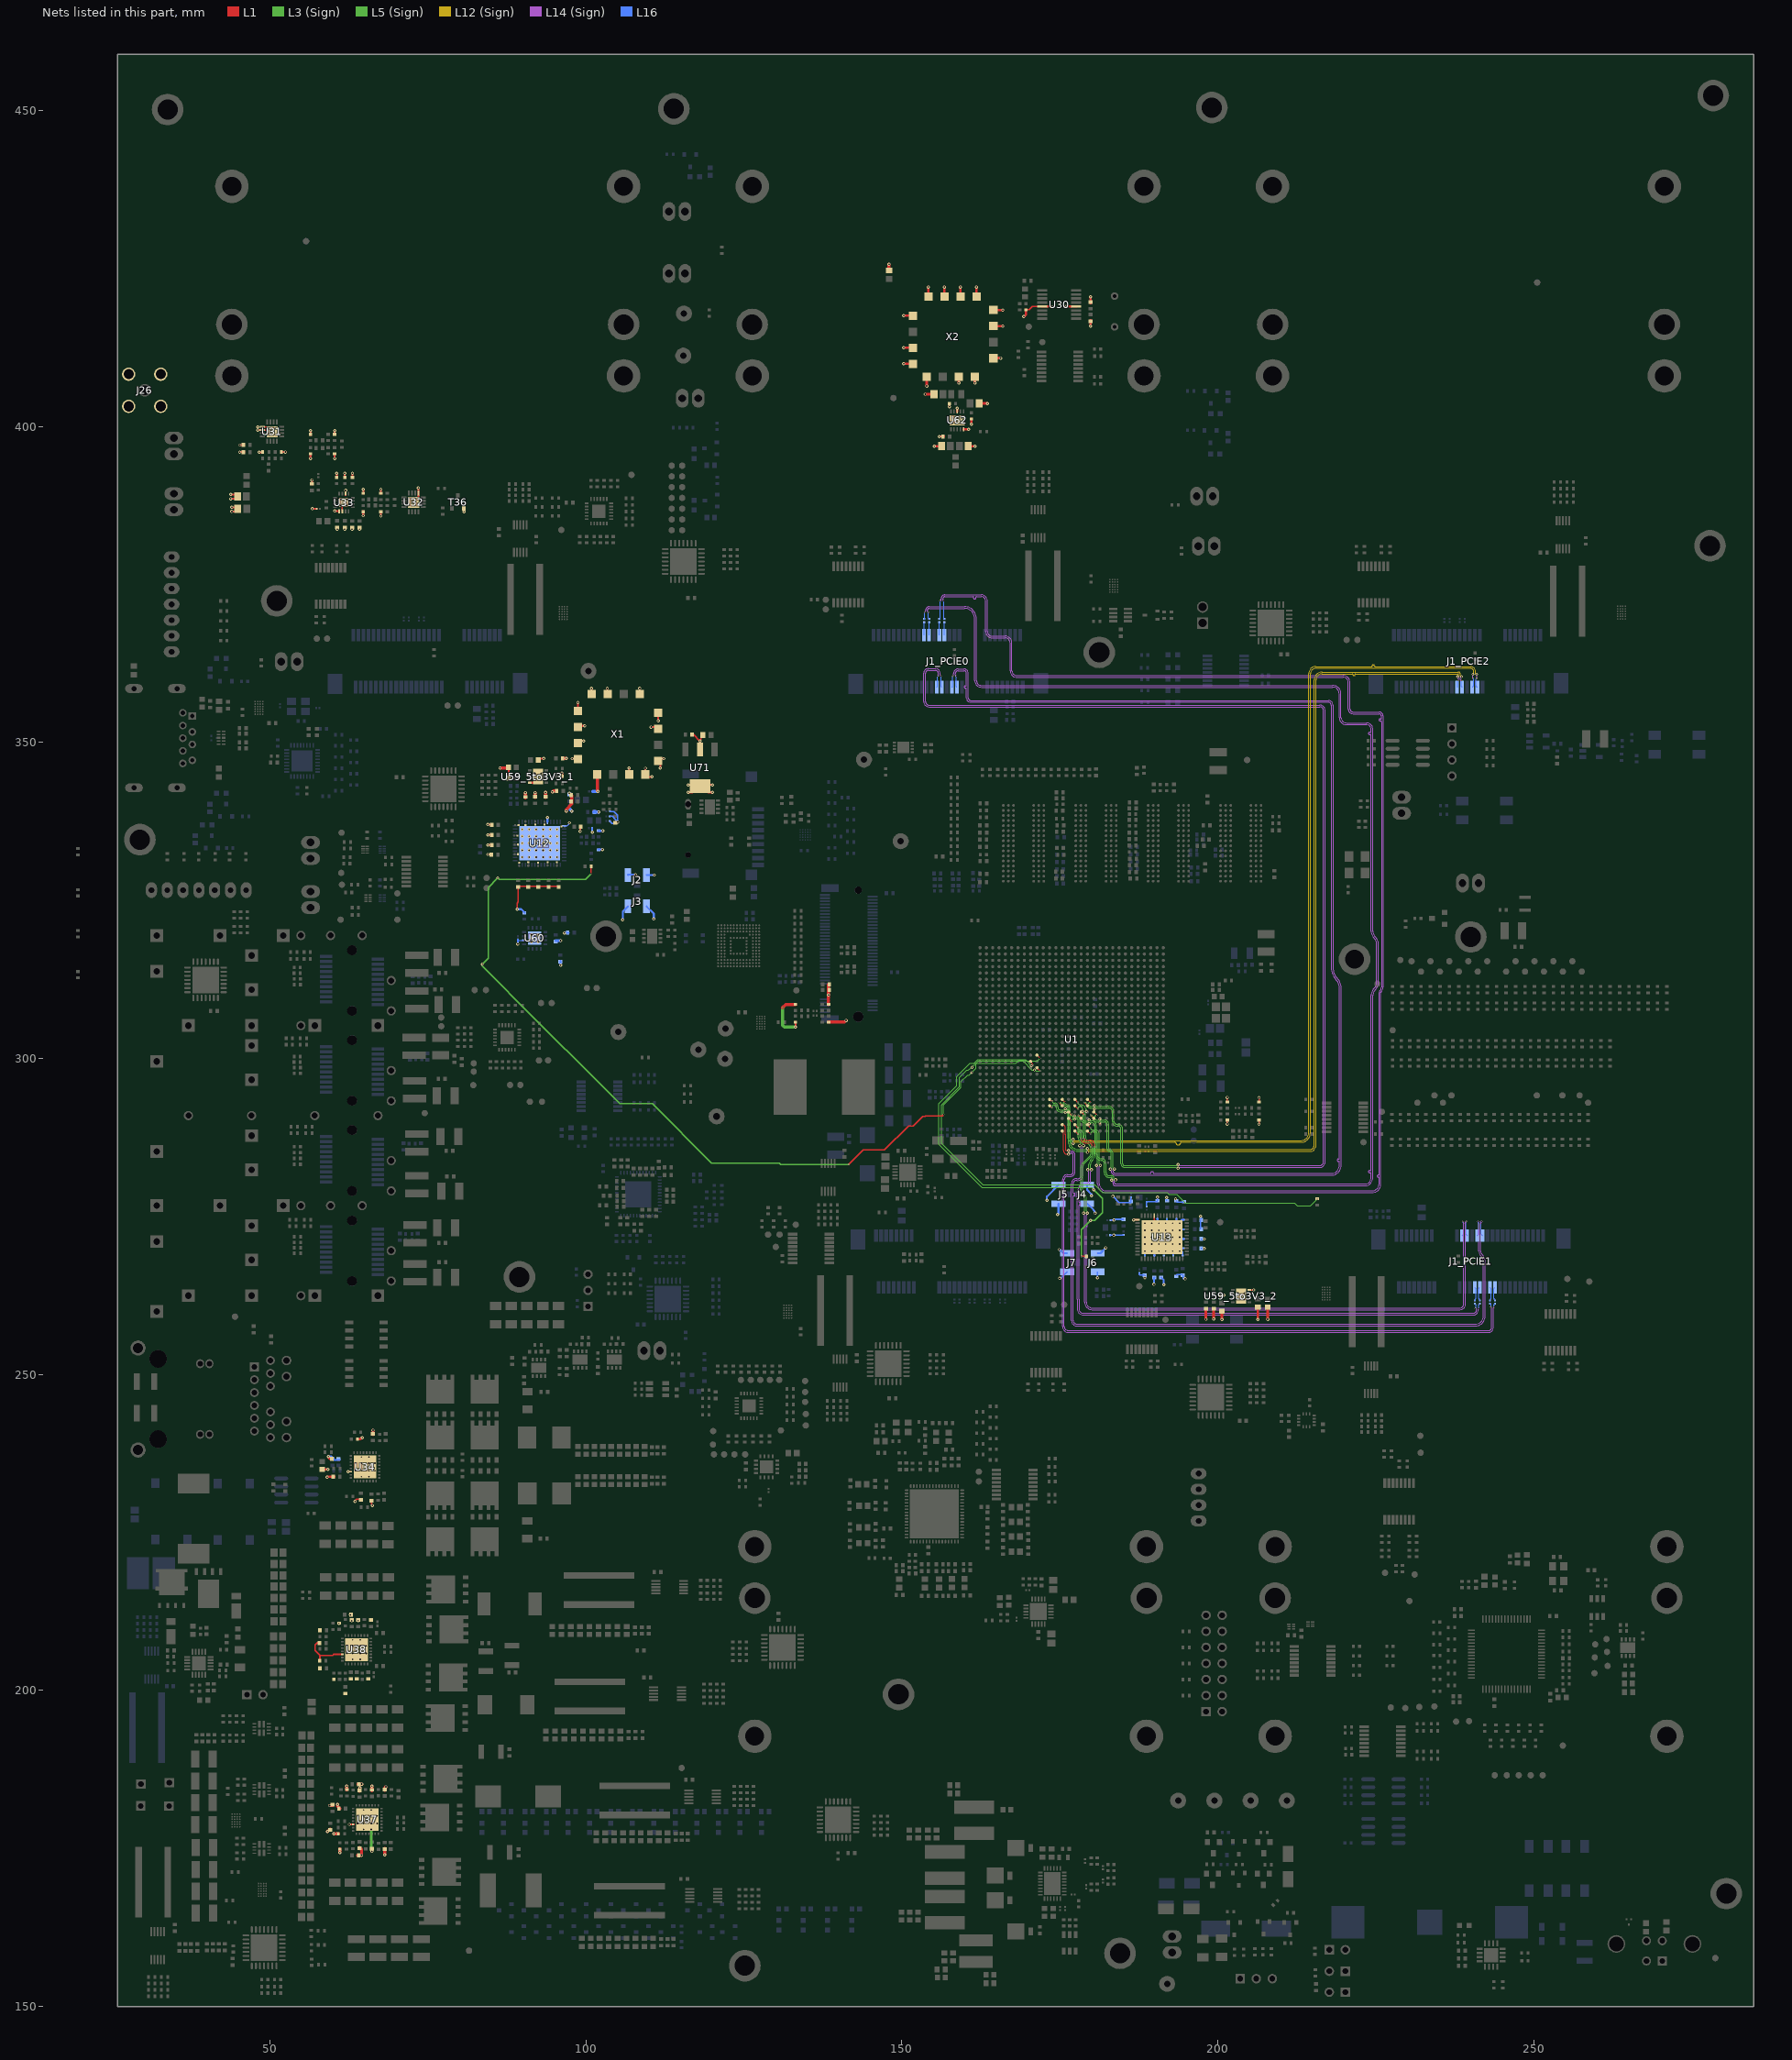
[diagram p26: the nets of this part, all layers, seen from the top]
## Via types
v1: diameter 0.5, hole 0.25, L1 to L16, tented both sides, 4341 vias
v2: diameter 0.254, hole 0.1, L1 to L3 (Sign), tented both sides, 781 vias
v3: diameter 0.5, hole 0.25, L1 to L16, 565 vias
v4: diameter 0.254, hole 0.1, L15 (GND) to L16, tented both sides, 406 vias
v5: diameter 0.254, hole 0.1, L1 to L2 (GND), tented both sides, 283 vias
v6: diameter 0.457, hole 0.2, L3 (Sign) to L6 (PWR/GND), tented both sides, 254 vias
v7: diameter 0.254, hole 0.1, L1 to L3 (Sign), 237 vias
v8: diameter 0.75, hole 0.4, L1 to L16, 200 vias
v9: diameter 0.8, hole 0.4, L1 to L16, tented both sides, 182 vias
v10: diameter 0.254, hole 0.1, L14 (Sign) to L16, tented both sides, 170 vias
v11: diameter 0.75/0/0/0/0/0/0/0/0/0/0/0/0/0/0/0.75 (per signal layer), hole 0.4, L1 to L16, 160 vias
v12: diameter 0.457, hole 0.2, L3 (Sign) to L6 (PWR/GND), 158 vias
v13: diameter 1.4, hole 0.5, L1 to L16, tented both sides, 80 vias
v14: diameter 0.254, hole 0.1, L14 (Sign) to L16, 65 vias
v15: diameter 0.254, hole 0.1, L1 to L2 (GND), 45 vias
v16: diameter 0.457, hole 0.2, L11 (PWR/GND) to L14 (Sign), tented both sides, 26 vias
v17: diameter 0.457, hole 0.2, L11 (PWR/GND) to L14 (Sign), 25 vias
v18: diameter 0.457, hole 0.2, L7(12V+Other) to L10 (3V3+Other), tented both sides, 11 vias
v19: diameter 0.254/0/0.254 (per signal layer), hole 0.1, L1 to L3 (Sign), 9 vias
v20: diameter 0.2/0/0.2 (per signal layer), hole 0.1, L1 to L3 (Sign), 6 vias
v21: diameter 1.65, hole 1.65, L1 to L16, 5 vias
v22: diameter 1.15, hole 1.15, L1 to L16, 5 vias
v23: diameter 0.457, hole 0.2, L1 to L16, 3 vias
v24: diameter 0.5, hole 0.3, L1 to L16, 2 vias
v25: diameter 0.5/0/0.5 (per signal layer), hole 0.2, L14 (Sign) to L16, 1 vias
v26: diameter 0.5, hole 0.25, L1 to L16, tented bottom, 1 vias

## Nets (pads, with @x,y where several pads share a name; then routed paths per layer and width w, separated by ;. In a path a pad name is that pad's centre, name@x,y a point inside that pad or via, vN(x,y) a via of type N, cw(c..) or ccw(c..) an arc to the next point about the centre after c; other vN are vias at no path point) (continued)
AGND: C45.1 C46.1 C53.1 C59.1 C60.1 C61.1 C62.1 C71.1 C72.1 C73.1 C74.1 C84.1 C85.1 C86.1 C87.1 C94.1 C95.1 C97.1 C98.1 C149.1 C150.1 C151.1 C152.1 C153.1 C154.1 C155.1 C156.1 C157.1 C158.1 C159.1 C160.1 C161.1 C166.1 C167.1 C168.1 C169.1 C170.1 C171.1 C172.1 C173.1 C174.1 C175.1 C176.1 C177.1 C178.1 C181.2 C182.2 C183.2 C184.2 C185.2 C186.2 C187.2 C188.2 C189.2 C190.2 C191.2 C192.2 C193.2 C194.2 C195.2 C196.2 C197.2 C198.2 C199.2 C200.2 C201.2 C202.2 C203.2 C204.2 C205.2 C206.2 C322.1 C323.1 C324.1 C326.2 C327.2 C328.2 C329.2 C335.1 C336.1 C337.1 C338.1 C339.1 C340.2 C344.1 C563_5to3V3_1.1 C563_5to3V3_2.1 C564_5to3V3_1.1 C564_5to3V3_2.1 C565_5to3V3_1.1 C565_5to3V3_2.1 C566_5to3V3_1.1 C566_5to3V3_2.1 C567_5to3V3_1.1 C567_5to3V3_2.1 C568.1 C569.1 C570.1 C571.2 C580.1 C581.1 C582.1 C583.1 C584.1 C713.1 C714.1 FB35.2 J2.1 J2.3 J3.1 J3.3 J4.1 J4.3 J5.1 J5.3 J6.1 J6.3 J7.1 J7.3 J26.2 J26.3 J26.4 J26.5 R76.2 R79.1 R100.1 R246.1 R247.1 R248.1 R249.2 R254.1 R255.1 R256.1 R258.2 R261.1 R262.1 R263.1 R264.1 R265.1 R291.2 R301.2 R387.1 R427.1 R432_5to3V3_1.1 R432_5to3V3_2.1 R434.2 R444.1 R445.1 R482.2 R483.2 R487.1 R609.2 T36.2 U12.36 U12.41 U12.53 U13.36 U13.41 U13.53 U30.4 U30.13 U31.1 U31.2 U31.17 U32.1 U32.17 U33.5 U33.6 U33.14 U33.17 U59_5to3V3_1.4 U59_5to3V3_1.9 U59_5to3V3_2.4 U59_5to3V3_2.9 U60.6 U60.17 U62.5 U62.8 U62.11 U71.2 X1.1 X1.3 X1.4 X1.5 X1.6 X1.7 X1.8 X1.9 X1.11 X1.12 X1.13 X1.15 X1.16 X2.1 X2.3 X2.4 X2.5 X2.6 X2.7 X2.8 X2.9 X2.11 X2.12 X2.13 X2.15 X2.16 | length 203.9
  L1 w0.2: U31.2@48.843,399.449 U31.17@50.093,399.449 ; U31.1@48.843,399.949 49.593,399.949 U31.17@50.093,399.449 ; U31.17@50.343,399.199 U31.17@50.093,399.449 ; v1(60.666,383.77) C340.2@60.666,384.18 ; U33.5@60.949,386.639 60.969,386.619 U33.5@60.969,386.585 ; U33.6@61.469,386.585 61.469,387.735 U33.17@61.719,387.985 ; v1(61.848,383.77) C336.1@61.848,384.18 ; v1(63.008,383.755) C337.1@63.008,384.165 ; v1(64.184,383.749) C338.1@64.184,384.159 ; v1(89.138,323.628) 89.138,324.597 89.319,324.777 89.319,327.283 C187.2@95.707,327.283 ; C713.1@116.677,351.231 117.075,351.231 v1@118.044,350.262 ; v1(118.064,350.262) v1@118.044,350.262 ; C714.1@118.552,351.206 118.252,350.906 118.252,350.531 118.044,350.324 v1@118.044,350.262 ; R609.2@169.661,418.489 170.184,418.489 170.693,418.998 U30.13@172.25,418.998 ; 189.973,274.46 U13.36@189.973,275.131 ; R432_5to3V3_2.1@200.435,262.513 200.459,262.538 200.955,262.538 v1(200.98,262.563) ; v1(201.527,289.641) R387.1@201.527,290.197 ; R100.1@201.527,293.284 v1(201.527,293.839) ; U59_5to3V3_2.4@204.995,263.388 v1(205.692,263.388) ; v1@206.539,289.607 R301.2@206.539,290.163 ; R291.2@206.539,293.234 v1(206.539,293.789)
  L1 w0.3: v1(43.791,388.577) C324.1@44.481,388.577 ; v1(43.791,389.255) C324.1@44.481,389.255 ; v1(43.985,386.568) C339.1@44.674,386.568 ; v1(43.985,387.235) C339.1@44.674,387.235 ; v1(45.227,395.959) C326.2@45.916,395.959 ; v1(45.227,397.068) C327.2@45.916,397.068 ; v1(48.09,399.449) U31.2@48.779,399.449 ; v1(48.314,395.937) R254.1@48.843,395.937 ; R255.1@51.847,395.968 v1(52.464,395.968) ; v1(56.433,394.952) R249.2@56.433,395.641 ; R246.1@56.436,398.674 v1(56.436,399.364) ; C53.1@56.672,390.856 v1(56.672,391.545) ; v1(56.729,387) C344.1@57.419,387 ; v1(60.258,386.636) U33.5@60.947,386.636 ; R247.1@60.263,398.769 v1(60.263,399.364) ; v1(60.266,394.952) R248.1@60.266,395.641 ; R263.1@60.573,391.91 v1(60.573,392.599) ; R265.1@61.838,391.91 v1(61.838,392.599) ; U33.14@61.988,389.204 v1(61.988,389.893) ; R264.1@63.066,391.91 v1(63.066,392.599) ; v1(64.77,385.9) R256.1@64.77,386.589 ; R258.2@64.785,389.383 v1(64.785,390.073) ; v1(67.564,385.864) R262.1@67.564,386.553 ; R261.1@67.564,389.395 v1(67.564,390.084) ; U32.17@72.745,388.011 73.495,388.761 U32.1@73.495,389.511 ; U32.1@73.495,389.585 v1(73.495,390.274) ; v1(80.711,386.499) T36.2@80.711,387.09 T36.2@80.711,387.188 ; v1(84.499,332.296) C185.2@85.188,332.296 ; v1(84.515,333.799) C183.2@85.204,333.799 ; v1(84.515,335.396) C186.2@85.204,335.396 ; v1(84.516,337.02) C190.2@85.206,337.02 ; C565_5to3V3_1.1@87.747,346.081 cw(c87.691,346.025) 87.77,346.025 C563_5to3V3_1.1@87.77,344.43 ; U59_5to3V3_1.4@91.131,343.652 91.781,343.652 92.431,344.302 U59_5to3V3_1.9@92.431,344.627 ; C564_5to3V3_1.1@92.509,347.231 92.745,347.467 v3(93.345,347.467) ; v1(97.845,347.453) X1.8@98.535,347.453 ; 98.755,355.665 v1(98.755,356.354) ; X1.7@98.957,350.262 v1(99.646,350.262) ; v1(99.099,335.94) C182.2@99.099,336.63 ; X1.6@99.141,352.639 v1(99.83,352.639) ; X1.4@100.907,357.878 v1(100.907,358.567) ; X1.3@103.397,357.878 v1(103.397,358.567) ; C335.1@104.697,337.43 105.056,337.43 v1(105.06,337.433) ; X1.11@106.857,345.288 v1(106.857,345.978) ; X1.1@108.534,357.878 v1(108.534,358.567) ; X1.12@109.423,345.243 v1(109.423,345.932) ; X1.12@109.767,344.577 v1(110.456,344.577) ; v1(110.353,352.45) X1.15@111.043,352.45 ; v1(111.455,353.454) X1.16@111.455,354.143 ; X1.13@111.676,347.453 v1(112.365,347.453) ; v1(111.782,345.971) 111.782,346.676 X1.13@111.877,346.77 ; v1(116.187,342.124) U71.2@116.877,342.124 ; v1(116.187,343.294) U71.2@116.877,343.294 ; U71.2@118.064,349.573 v1(118.064,350.262) ; U71.2@119.362,342.124 v1(120.052,342.124) ; U71.2@119.362,343.294 v1(120.052,343.294) ; v1(133.18,304.98) R483.2@133.18,305.789 ; v1(155.931,398.424) C583.1@156.67,398.424 ; v1(186.699,274.482) U13.41@187.388,274.482
  L1 w0.4: v1(150.318,409.931) X2.12@151.803,409.931 ; v1(150.318,412.471) X2.11@151.803,412.471 ; v1(150.318,417.551) X2.9@151.803,417.551 ; v1(153.721,405.12) C580.1@155.206,405.12 ; v1(153.962,406.414) X2.13@153.962,407.899 ; X2.8@154.216,420.599 v1(154.216,422.084) ; v1(155.13,396.888) 155.14,396.897 C581.1@156.288,396.897 ; X2.7@156.756,420.599 v1(156.756,422.084) ; v1(157.537,403.147) R445.1@157.537,403.581 ; v1(158.76,402.894) 158.76,402.867 158.785,402.842 U62.8@158.785,402.411 ; v1(159.042,406.914) X2.15@159.042,407.899 ; X2.6@159.296,420.599 v1(159.296,422.084) ; U62.5@159.785,399.561 160.573,399.561 v1(160.579,399.567) ; C582.1@160.507,396.897 v1(161.595,396.897) ; R444.1@161.032,401.231 161.032,400.385 v1(161.036,400.38) ; v1(161.582,406.914) X2.16@161.582,407.899 ; X2.5@161.836,420.599 v1(161.836,422.084) ; C584.1@162.232,403.653 v1(163.581,403.653) ; X2.1@164.503,410.82 164.522,410.839 v1(165.638,410.839) ; X2.3@164.503,415.9 v1(165.988,415.9) ; X2.4@164.503,418.44 v1(165.988,418.44) ; v1(169.316,417.398) 169.329,417.385 169.661,417.718 R609.2@169.661,418.489 ; U30.13@172.25,418.998 173.774,418.998 v1(173.799,418.973) ; v1(176.022,419.024) 175.996,418.998 U30.4@177.584,418.998 ; C323.1@179.87,416.809 179.87,415.914 v1(179.884,415.9) ; C322.1@179.87,419.569 179.87,420.522 v1(179.87,420.535) ; v1(198.138,258.752) C567_5to3V3_2.1@198.138,260.408 ; C566_5to3V3_2.1@199.36,260.408 199.36,258.78 v1(199.365,258.775) ; v1(200.673,258.712) C565_5to3V3_2.1@200.673,260.048 ; C563_5to3V3_2.1@206.365,260.698 206.365,258.734 v1(206.375,258.724) ; C564_5to3V3_2.1@207.912,260.683 207.912,258.747 v1(207.924,258.734)
  L1 w0.5: v1(86.422,345.978) 87.236,345.978 ; C192.2@90.437,341.268 v1(90.437,342.082) ; C188.2@91.961,341.289 v1(91.961,342.082) ; C184.2@93.65,341.289 v1(93.65,342.102) ; v1(94.704,342.189) 94.882,342.367 C567_5to3V3_1.1@95.38,342.367 ; R432_5to3V3_1.1@96.214,344.678 v1(96.214,345.163) ; C566_5to3V3_1.1@96.308,347.51 96.912,347.51 v1(96.914,347.512) ; v1(96.884,339.175) 96.884,339.378 97.79,340.284 C45.1@97.79,341.655 ; X1.9@101.803,344.957 101.803,342.38 v1(101.927,342.257) ; v2(131.153,308.064) 131.153,308.077 131.627,308.55 R482.2@133.18,308.55 ; R487.1@138.412,305.772 140.932,305.772 v1(141.192,306.032) ; R427.1@138.412,308.55 v1(138.412,310.083) C328.2@138.412,311.721 ; FB35.2@147.991,424.703 v1(147.991,425.678)
  L3 (Sign) w0.5: v2(131.153,308.064) 131.153,305.244 131.418,304.98 v1(133.18,304.98)
  L16 w0.12: C571.2@89.238,318.838 ccw(c89.373,318.838) 89.373,318.703 U60.6@90.239,318.703 ; U12.41@96.597,336.811 97.022,336.811 97.396,337.185 v1(97.396,337.299)
  L16 w0.2: C59.1@103.797,337.579 103.797,337.569 104.181,337.185 104.73,337.185 104.978,337.433 v1(105.06,337.433) ; C60.1@103.797,338.336 104.241,338.336 104.446,338.13 104.446,338.046 v1(105.06,337.433) ; C84.1@103.8,339.094 104.446,339.094 105.06,338.481 v1(105.06,337.433) ; J6.1@180.995,266.241 180.995,265.316 v1(181,265.316) ; C72.1@182.995,272.028 v1(183.551,272.028) 184.858,272.028 184.901,272.072 185.042,272.072 C73.1@185.092,272.122 ; C71.1@183.047,274.436 v1(183.603,274.436) ; v1(183.403,278.201) 184.364,277.24 186.259,277.24 186.284,277.265 186.284,278.046 C95.1@186.309,278.071 ; C172.1@187.598,266.101 187.598,265.878 187.715,265.761 188.389,265.761 188.487,265.663 188.487,265.308 v1(188.478,265.299) ; C97.1@188.767,276.597 188.764,276.6 188.764,277.318 C94.1@188.761,277.321 188.788,277.348 190.446,277.348 C205.2@190.473,277.375 ; C205.2@190.481,277.494 v1@190.481,278.05 ; v1(191.941,278.017) 191.941,277.526 C204.2@191.973,277.494 ; v3(192.873,269.531) 192.873,269.45 192.973,269.35 C170.1@192.973,268.851 ; v1(193.334,277.799) ccw(c193.521,277.729) 193.38,277.587 C202.2@193.473,277.494 ; C197.2@193.43,265.664 193.43,265.669 193.6,265.839 193.605,265.839 193.611,265.845 C206.2@194.473,265.845 ; C202.2@193.473,277.375 193.558,277.29 194.584,277.29 C203.2@194.669,277.205 ; v3(193.973,269.531) 194.03,269.474 194.356,269.474 194.473,269.357 C167.1@194.473,268.851 ; 194.263,269.981 C174.1@194.603,269.981 ; C206.2@194.563,265.745 194.563,265.189 194.609,265.143 v1(194.854,265.143) ; C195.2@197.281,272.981 C198.2@197.281,274.481 ; C198.2@197.281,274.631 197.338,274.688 197.338,274.964 v1(197.281,275.021) ; C196.2@197.333,269.926 v1(197.888,269.926) ; C201.2@197.333,271.441 v1(197.888,271.441)
  L16 w0.3: v1(89.138,323.628) 89.779,323.628 R434.2@90.322,323.086 ; v1(89.238,318.148) C571.2@89.238,318.838 ; U12.36@93.931,337.441 v1(93.931,338.13) ; v1(96.009,314.783) C570.1@96.009,315.472 ; v1(96.611,319.889) C569.1@97.3,319.889 ; v1(101.031,335.796) C61.1@101.031,336.485 ; R79.1@101.96,333.085 v1(102.649,333.085) ; R76.2@101.992,336.037 v1(102.681,336.037) ; v1(105.855,321.945) 105.855,323.253 106.659,324.057 J3.1@106.659,324.087 ; J2.3@106.659,329.028 106.737,329.106 v1(107.836,329.106) ; J3.3@109.609,324.087 110.757,322.939 v1(110.757,322.085) ; J2.1@109.609,329.028 109.612,329.032 v1(110.815,329.032) ; v1@172.999,277.571 v1(172.981,277.59) 172.981,278.168 J5.1@174.806,279.993 J5.1@174.803,279.993 ; v1(174.666,275.314) 174.806,275.454 J5.3@174.806,277.043 ; v1(174.91,269.772) 174.948,269.734 175.056,269.734 175.599,269.191 J7.1@176.174,269.191 ; v1(174.993,265.214) 175.148,265.214 J7.3@176.174,266.241 ; J4.1@179.345,277.043 180.365,276.023 cw(c179.854,275.512) v3(180.577,275.512) ; J4.3@179.345,279.993 179.345,279.229 180.037,278.538 v1(180.037,278.294) ; J6.3@180.995,269.191 181.434,269.191 v1(182.296,270.053) ; v1(183.603,274.436) cw(c183.716,274.436) 183.716,274.549 C74.1@185.092,274.549 ; C173.1@188.473,268.861 v3(188.473,269.531) ; v3(189.919,264.268) 189.919,265.305 C199.2@189.973,265.359 ; C176.1@189.973,268.851 189.973,269.494 ; C175.1@190.473,274.611 190.483,274.611 190.483,274.175 190.673,273.985 v3(190.673,273.931) ; C194.2@191.059,265.359 191.481,264.937 v3(191.481,264.245) ; v3(191.773,273.931) 191.773,273.985 191.963,274.175 191.963,274.611 C178.1@191.973,274.611 ; 193.434,274.005 193.473,274.044 C166.1@193.473,274.611 ; v3(193.973,272.831) 194.027,272.831 194.167,272.971 194.603,272.971 C171.1@194.603,272.981 ; 194.03,271.441 194.07,271.481 C177.1@194.603,271.481 ; 194.263,274.481 C169.1@194.603,274.481
  L16 w0.4: C568.1@95.25,318.659 v1(96.009,318.659)
  L16 w0.5: C86.1@97.38,339.579 v1(97.793,339.166) ; C85.1@101.113,342.257 v1(101.927,342.257) ; C62.1@101.236,338.988 101.361,339.113 101.486,338.988 v1(102.029,338.988)
  other v1: 190.481,278.05 206.539,289.607 97.38,341.964 48.09,399.949
  other v3: 203.195,261.913 204.195,261.913 203.195,262.913 204.195,262.913 189.573,269.531 190.673,269.531 191.773,269.531 188.473,270.631 189.573,270.631 190.673,270.631 191.773,270.631 192.873,270.631 193.973,270.631 188.473,271.731 189.573,271.731 190.673,271.731 191.773,271.731 192.873,271.731 193.973,271.731 188.473,272.831 189.573,272.831 190.673,272.831 191.773,272.831 192.873,272.831 188.473,273.931 189.573,273.931 192.873,273.931 193.973,273.931 91.364,318.478 92.464,318.478 91.364,319.578 92.464,319.578 89.947,331.861 91.047,331.861 92.147,331.861 93.247,331.861 94.347,331.861 95.447,331.861 89.947,332.961 91.047,332.961 92.147,332.961 93.247,332.961 94.347,332.961 95.447,332.961 89.947,334.061 91.047,334.061 92.147,334.061 93.247,334.061 94.347,334.061 95.447,334.061 89.947,335.161 91.047,335.161 92.147,335.161 93.247,335.161 94.347,335.161 95.447,335.161 89.947,336.261 91.047,336.261 92.147,336.261 93.247,336.261 94.347,336.261 95.447,336.261 91.931,344.127 92.931,344.127 91.931,345.127 92.931,345.127 61.244,387.51 62.194,387.51 61.244,388.46 62.194,388.46 158.023,400.605 158.785,400.605 159.547,400.605 158.023,401.367 158.785,401.367 159.547,401.367
AGND_1: C389.1 C393.1 C395.2 C398.2 C399.1 C639.1 C640.1 C641.1 C642.1 C643.1 C644.1 R290.2 R294.2 R300.2 U37.6 U37.33 | length 14.2
  L1 w0.2: v1(66.161,174.542) C640.1@66.161,175.113
  L1 w0.3: v1(62.566,178.817) U37.6@63.175,178.817 U37.6@63.255,178.817
  L1 w0.5: v1@59.124,177.667 v1(59.124,177.677) C399.1@59.524,178.077 ; v1@59.436,181.788 v1(59.439,181.791) C395.2@59.93,181.791 ; v1(60.128,177.317) R294.2@60.881,177.317 ; v1(60.689,181.968) 60.689,181.686 61.058,181.317 C398.2@61.068,181.317 ; v1(61.068,174.358) R300.2@61.068,174.951 ; v1(62.185,184.89) 62.191,184.884 R290.2@62.191,184.259 ; C643.1@63.9,173.949 v1(64.514,173.949) 64.514,174.827 C641.1@64.175,175.167 ; C644.1@63.955,185.176 64.515,185.176 v1(64.53,185.19) ; C642.1@64.175,184.05 64.175,184.47 v1(64.275,184.57) ; v1(66.138,184.861) 66.141,184.858 C639.1@66.141,184.149 ; v1(68.185,173.974) C393.1@68.185,175.037 ; C389.1@68.211,184.213 68.211,184.611 v1(68.359,184.76)
  L5 (Sign) w0.4: v3(66.025,178.017) 66.025,174.706 66.161,174.569 v1(66.161,174.542)
  other v3: 64.825,178.017 63.875,178.967 64.825,178.967 66.025,178.967 66.975,178.967 63.875,180.167 64.825,180.167 66.025,180.167 66.975,180.167 64.825,181.117 66.025,181.117
AGND_2: C430.1 C434.1 C436.2 C439.2 C440.1 C548.1 C549.1 C647.1 C648.1 C650.1 C652.1 R312.2 R318.1 R627.1 U38.6 U38.33 | length 7.4
  L1 w0.254: R312.2@57.926,204.716 57.926,205.54 57.15,206.316 57.15,207.205 57.468,207.523 C436.2@57.967,207.523 ; 57.937,205.529 59.906,205.529 60.091,205.714 U38.6@61.453,205.714
  other v1: 60.944,210.633 62.953,211.029 63.953,211.044 62.734,211.976
  other v3: 63.103,204.914 64.303,204.914 62.153,205.864 63.103,205.864 64.303,205.864 65.253,205.864 62.153,207.064 63.103,207.064 64.303,207.064 65.253,207.064 63.103,208.014 64.303,208.014
Analog0_R: R395.1 U1.K11 | length 142.6
  L1 w0.12: U1.K11@171.397,298.539 v2(171.884,298.052)
  L1 w0.2: v2(100.825,329.222) 100.833,329.23 R395.1@100.833,330.39 ; v2(141.618,283.259) 143.892,285.534 147.256,285.534 151.066,289.344 151.822,289.344 153.345,290.867 153.714,290.867 153.768,290.922 156.422,290.922 v2(156.629,291.129)
  L5 (Sign) w0.12: v12(161.081,297.793) 161.081,297.803 161.397,298.119 161.728,298.451 161.728,299.218 162.098,299.588 169.204,299.588 170.609,298.183 v12(170.996,298.183)
  L5 (Sign) w0.2: v6(83.617,314.935) 84.539,315.857 84.539,327.069 v6(86.057,328.587)
  L3 (Sign) w0.12: v2(156.629,291.129) 156.629,292.679 159.385,295.436 159.385,296.38 160.411,297.406 160.694,297.406 v12(161.081,297.793) ; v12(170.996,298.183) 171.099,298.183 171.23,298.052 v2(171.884,298.052)
  L3 (Sign) w0.2: v6(83.617,314.935) 83.617,314.63 87.326,310.92 87.328,310.92 88.295,309.954 88.295,309.952 105.397,292.849 110.553,292.849 119.927,283.476 130.638,283.476 130.854,283.259 v2(141.618,283.259) ; v6(86.057,328.587) 86.29,328.353 99.956,328.353 v2(100.825,329.222)
Analog1_R: R398.1 U1.K13 | length 68.3
  L1 w0.12: U1.K13@171.397,300.539 v2(171.884,300.052)
  L1 w0.2: v2(178.46,268.694) R398.1@179.23,268.694 R398.1@179.28,268.694
  L5 (Sign) w0.2: v6(179.883,274.386) 180.518,274.386 181.767,275.635 181.767,277.865 v6(180.397,279.235)
  L3 (Sign) w0.12: v2(171.884,300.052) 171.474,299.642 169.605,299.642 169.474,299.774 168.585,299.774 168.054,299.243 161.397,299.243 160.783,299.243 158.725,297.185 158.725,295.709 155.876,292.86 155.876,286.401 162.67,279.608 180.024,279.608 v6(180.397,279.235)
  L3 (Sign) w0.2: v2@178.448,268.681 v2(178.46,268.694) 178.46,272.964 v6(179.883,274.386)
Analog2_R: R506.1 U1.J12 | length 89.7
  L1 w0.12: U1.J12@170.397,299.539 170.802,298.977 170.79,298.966 v2(170.786,298.966)
  L5 (Sign) w0.12: v12(161.123,298.613) 161.397,298.887 161.508,298.998 161.508,299.309 162.007,299.808 169.564,299.808 v12(170.517,298.855)
  L3 (Sign) w0.12: v12(161.123,298.613) 161.02,298.613 160.83,298.423 160.82,298.423 160.549,298.152 160.315,298.152 159.165,297.003 159.165,295.527 156.316,292.678 156.316,286.584 162.852,280.048 180.524,280.048 181.741,278.831 192.017,278.831 192.32,278.529 193.495,278.529 194.891,277.132 212.171,277.132 212.612,276.691 214.687,276.691 v2(215.756,277.76) ; v12(170.517,298.855) 170.59,298.927 170.716,298.927 170.765,298.977 v2@170.802,298.977 ; v2(170.786,298.966) v2@170.786,298.977
ANGD: C345.1 C349.1 C351.2 C356.2 C357.1 C358.2 C634.1 C635.1 R273.1 U34.6 U34.33 | length 9
  L1 w0.2: v1(62.395,234.639) U34.6@62.822,234.639 ; v1(63.487,229.921) 63.487,230.073 63.721,230.307 C357.1@64.44,230.307 ; C349.1@66.055,230.039 66.055,229.453 v1(66.222,229.286)
  L1 w0.3: v1(59.242,237.029) 59.242,236.844 59.457,236.629 C351.2@59.932,236.629
  L1 w0.4: C358.2@58.293,234.998 59.159,234.998 v1(59.169,234.988) ; v1(59.064,233.756) 59.146,233.839 C356.2@60.016,233.839 C356.2@60.151,233.839 ; R273.1@63.835,239.777 R273.1@63.885,239.777 64.26,239.777 64.456,239.973 64.598,239.973 v1(64.618,239.992) ; C345.1@66.319,240.47 v1(66.319,241.198)
  L16 w0.3: C635.1@60.062,236.504 C634.1@61.028,236.504
  L16 w0.4: v1(59.242,237.029) 59.672,237.029 59.937,236.764 59.937,236.714 60.012,236.639 C635.1@60.062,236.639
  other v3: 64.472,233.839 65.672,233.839 63.522,234.789 64.472,234.789 65.672,234.789 66.622,234.789 63.522,235.989 64.472,235.989 65.672,235.989 66.622,235.989 64.472,236.939 65.672,236.939
B223_Rx0_N: J1_PCIE0.21 U1.W3 | length 190.8
  L1 w0.1: v2(179.909,291.027) U1.W3@180.397,290.539
  L5 (Sign) w0.081: v12(181.355,289.802) cw(c181.514,289.802) 181.514,289.961 182.143,289.961 cw(c182.143,289.618) 182.486,289.618 182.486,285.708 ccw(c182.887,285.708) 182.887,285.307 cw(c182.887,285.051) 183.143,285.051 183.143,282.659 cw(c183.033,282.659) 183.033,282.55 183.025,282.542 v3(183.025,282.504)
  L3 (Sign) w0.081: v2(179.909,291.027) cw(c179.909,290.68) 180.256,290.68 180.256,290.578 ccw(c180.873,290.578) 180.873,289.961 181.195,289.961 cw(c181.195,289.802) v12(181.355,289.802)
  L14 (Sign) w0.081: v10(158.037,360.528) ccw(c158.037,360.687) 158.197,360.687 158.197,360.909 cw(c158.926,360.909) 158.926,361.639 159.848,361.639 cw(c159.848,360.948) 160.539,360.948 160.539,357.039 ccw(c160.917,357.039) 160.917,356.661 217.52,356.661 cw(c217.52,355.932) 218.25,355.932 218.25,314.377 ccw(c220.736,314.377) 218.978,312.619 218.979,312.617 cw(c217.614,311.252) 219.545,311.252 219.545,283.098 cw(c217.987,283.098) 217.987,281.539 183.836,281.539 cw(c183.836,282.232) 183.143,282.232 183.143,282.44 ccw(c183.033,282.44) 183.033,282.55 183.025,282.542 v3(183.025,282.504)
  L16 w0.101: J1_PCIE0.21@157.937,358.792 ccw(c157.937,358.892) 158.037,358.892 v10(158.037,360.528)
B223_Rx0_P: J1_PCIE0.19 U1.W4 | length 190.6
  L1 w0.1: U1.W4@180.397,291.539 v2(180.884,291.052)
  L5 (Sign) w0.081: v12(181.355,290.402) ccw(c181.514,290.402) 181.514,290.242 182.143,290.242 cw(c182.143,289.618) 182.767,289.618 182.767,285.708 ccw(c182.887,285.708) 182.887,285.588 cw(c182.887,285.051) 183.424,285.051 183.424,282.659 ccw(c183.533,282.659) 183.533,282.55 183.557,282.526 v3(183.633,282.526)
  L3 (Sign) w0.081: v2(180.884,291.052) ccw(c180.884,290.705) 180.537,290.705 180.537,290.578 ccw(c180.873,290.578) 180.873,290.242 181.195,290.242 ccw(c181.195,290.402) v12(181.355,290.402)
  L14 (Sign) w0.081: v10(158.637,360.528) cw(c158.637,360.687) 158.478,360.687 158.478,360.909 cw(c158.926,360.909) 158.926,361.358 159.848,361.358 cw(c159.848,360.948) 160.258,360.948 160.258,359.418 160.258,359.042 cw(c160.174,359.042) 160.174,358.958 160.004,358.958 ccw(c160.004,358.875) 159.92,358.875 159.92,358.707 ccw(c160.004,358.707) 160.004,358.623 160.174,358.623 cw(c160.174,358.539) 160.258,358.539 160.258,357.978 160.258,357.039 ccw(c160.917,357.039) 160.917,356.38 217.52,356.38 cw(c217.52,355.932) 217.969,355.932 217.969,314.375 ccw(c220.732,314.375) 218.778,312.421 218.779,312.42 cw(c217.609,311.25) 219.264,311.25 219.264,284.537 219.264,284.172 cw(c219.18,284.172) 219.18,284.089 219.052,284.089 ccw(c219.052,284.005) 218.968,284.005 218.968,283.837 ccw(c219.052,283.837) 219.052,283.753 219.18,283.753 cw(c219.18,283.67) 219.264,283.67 219.264,283.629 219.264,283.098 cw(c217.987,283.098) 217.987,281.82 190.27,281.82 189.894,281.82 cw(c189.894,281.904) 189.81,281.904 189.81,282.024 ccw(c189.726,282.024) 189.726,282.108 189.559,282.108 ccw(c189.559,282.024) 189.475,282.024 189.475,281.904 cw(c189.391,281.904) 189.391,281.82 189.093,281.82 188.124,281.82 187.039,281.82 183.836,281.82 cw(c183.836,282.232) 183.424,282.232 183.424,282.44 cw(c183.533,282.44) 183.533,282.55 183.557,282.526 v3(183.633,282.526)
  L16 w0.101: v10(158.637,360.528) 158.637,358.892 ccw(c158.737,358.892) J1_PCIE0.19@158.737,358.792
B223_Rx1_N: J1_PCIE0.27 U1.V5 | length 193.3
  L1 w0.1: v2(178.909,293.027) U1.V5@179.397,292.539
  L5 (Sign) w0.081: v12(180.518,291.995) cw(c180.678,291.995) 180.678,292.155 182.737,292.155 cw(c182.737,291.564) 183.328,291.564 183.328,290.038 ccw(c184.029,290.038) 184.029,289.337 184.204,289.337 cw(c184.204,288.858) 184.683,288.858 184.683,283.372 ccw(c185.277,283.372) 185.277,282.778 193.491,282.778 193.65,282.619 v3(193.748,282.619)
  L3 (Sign) w0.081: v2(178.909,293.027) 179.047,293.027 cw(c179.047,292.817) 179.256,292.817 ccw(c179.919,292.817) 179.919,292.155 180.359,292.155 cw(c180.359,291.995) v12(180.518,291.995)
  L14 (Sign) w0.081: v10(155.637,360.528) ccw(c155.637,360.687) 155.797,360.687 155.797,360.948 ccw(c155.328,360.948) 155.328,361.417 154.216,361.417 ccw(c154.216,360.948) 153.747,360.948 153.747,356.501 ccw(c154.316,356.501) 154.316,355.932 216.141,355.932 cw(c216.141,355.054) 217.019,355.054 217.019,283.629 cw(c216.168,283.629) 216.168,282.778 196.064,282.778 193.931,282.778 193.771,282.619 v3(193.748,282.619)
  L16 w0.101: J1_PCIE0.27@155.537,358.792 ccw(c155.537,358.892) 155.637,358.892 v10(155.637,360.528)
B223_Rx1_P: J1_PCIE0.25 U1.V6 | length 193.4
  L1 w0.1: U1.V6@179.397,293.539 179.851,293.086 cw(c179.787,293.022) v2(179.876,293.006)
  L5 (Sign) w0.081: v12(180.518,292.595) ccw(c180.678,292.595) 180.678,292.436 182.737,292.436 cw(c182.737,291.564) 183.609,291.564 183.609,290.038 ccw(c184.029,290.038) 184.029,289.618 184.204,289.618 cw(c184.204,288.858) 184.964,288.858 184.964,283.372 ccw(c185.277,283.372) 185.277,283.059 193.491,283.059 193.65,283.219 v3(193.748,283.219)
  L3 (Sign) w0.081: v2(179.876,293.006) 179.812,293.042 ccw(c179.772,292.971) 179.772,293.052 ccw(c179.772,292.817) 179.537,292.817 ccw(c179.919,292.817) 179.919,292.436 180.359,292.436 ccw(c180.359,292.595) v12(180.518,292.595)
  L14 (Sign) w0.081: v10(156.237,360.528) cw(c156.237,360.687) 156.078,360.687 156.078,360.948 ccw(c155.328,360.948) 155.328,361.698 154.216,361.698 ccw(c154.216,360.948) 153.466,360.948 153.466,356.501 ccw(c154.316,356.501) 154.316,355.651 216.141,355.651 cw(c216.141,355.054) 216.738,355.054 216.738,283.629 cw(c216.168,283.629) 216.168,283.059 196.18,283.059 193.931,283.059 193.771,283.219 v3(193.748,283.219)
  L16 w0.101: v10(156.237,360.528) 156.237,358.892 ccw(c156.337,358.892) J1_PCIE0.25@156.337,358.792
B223_Rx2_N: J1_PCIE1.21 U1.T5 | length 111
  L1 w0.1: U1.T5@177.397,292.539 v2(177.884,292.052)
  L5 (Sign) w0.081: v12(178.613,291.634) cw(c178.613,291.475) 178.772,291.475 178.772,287.795 ccw(c180.14,287.795) 179.173,286.828 179.668,286.332 cw(c178.967,285.631) 179.959,285.631 179.959,285.061 cw(c179.36,285.061) 179.784,284.638 178.618,283.472 ccw(c179.31,282.781) 178.332,282.781 178.332,279.303 ccw(c179.152,279.303) 178.572,278.723 178.574,278.721 cw(c177.709,277.856) 178.932,277.856 178.932,275.922 cw(c178.659,275.922) 178.852,275.729 178.841,275.718 ccw(c179.007,275.552) v3(178.772,275.552)
  L3 (Sign) w0.081: v2(177.884,292.052) cw(c178.244,292.052) 178.244,292.411 178.27,292.411 cw(c178.27,292.069) 178.613,292.069 v12(178.613,291.634)
  L14 (Sign) w0.081: v3(178.772,275.552) ccw(c179.007,275.552) 178.841,275.386 cw(c178.622,275.167) 178.932,275.167 178.932,261.448 ccw(c180.115,261.448) 180.115,260.265 238.352,260.265 ccw(c238.352,261.143) 239.23,261.143 239.23,274.072 cw(c239.39,274.072) v10(239.39,274.231) ccw(c239.39,274.121) 239.28,274.121
  L16 w0.101: v10(239.39,274.231) 239.313,274.155 239.313,273.996 239.29,273.972 239.29,272.194 J1_PCIE1.21@239.49,271.994
B223_Rx2_P: J1_PCIE1.19 U1.T6 | length 111
  L1 w0.1: U1.T6@177.397,293.539 v2(177.884,293.052)
  L5 (Sign) w0.081: v12(179.213,291.634) ccw(c179.213,291.475) 179.053,291.475 179.053,287.796 ccw(c180.142,287.796) 179.372,287.026 179.95,286.449 cw(c179.248,285.747) 180.24,285.747 180.24,285.059 cw(c179.366,285.059) 179.984,284.441 178.819,283.276 ccw(c179.316,282.778) 178.613,282.778 178.613,279.305 ccw(c179.157,279.305) 178.772,278.92 178.775,278.917 cw(c177.718,277.86) 179.213,277.86 179.213,275.922 ccw(c179.485,275.922) 179.292,275.729 179.303,275.718 cw(c179.137,275.552) v3(179.372,275.552)
  L3 (Sign) w0.081: v2(177.884,293.052) ccw(c178.244,293.052) 178.244,292.692 178.27,292.692 cw(c178.27,291.75) 179.213,291.75 v12(179.213,291.634)
  L14 (Sign) w0.081: v3(179.372,275.552) cw(c179.137,275.552) 179.303,275.386 ccw(c179.522,275.167) 179.213,275.167 179.213,273.895 179.213,273.855 ccw(c179.297,273.855) 179.297,273.771 179.325,273.771 cw(c179.325,273.687) 179.408,273.687 179.408,273.52 cw(c179.325,273.52) 179.325,273.436 179.297,273.436 ccw(c179.297,273.352) 179.213,273.352 179.213,273.167 179.213,261.448 ccw(c180.115,261.448) 180.115,260.546 238.352,260.546 ccw(c238.352,261.143) 238.949,261.143 238.949,274.072 ccw(c238.79,274.072) v10(238.79,274.231) cw(c238.79,274.121) 238.9,274.121
  L16 w0.101: J1_PCIE1.19@238.69,271.994 238.889,272.193 238.889,273.972 238.866,273.996 238.866,274.155 v10(238.79,274.231)
B223_Rx3_N: J1_PCIE1.27 U1.R3 | length 119.9
  L1 w0.1: U1.R3@176.397,290.539 176.805,290.132 v2(176.967,290.132)
  L5 (Sign) w0.081: v12(177.397,290.35) cw(c177.556,290.35) 177.556,290.509 177.758,290.509 cw(c177.758,290.358) 177.91,290.358 177.91,287.504 ccw(c178.668,287.504) 178.132,286.967 178.231,286.868 cw(c177.987,286.624) 178.332,286.624 178.332,286.594 cw(c178.059,286.594) 178.252,286.402 178.241,286.391 ccw(c178.407,286.225) v3(178.172,286.225)
  L3 (Sign) w0.081: v2(176.967,290.132) 176.967,290.339 cw(c177.138,290.339) 177.138,290.509 177.237,290.509 cw(c177.237,290.35) v12(177.397,290.35)
  L14 (Sign) w0.081: v3(178.172,286.225) cw(c178.172,286.065) 178.332,286.065 178.332,281.396 cw(c177.939,281.396) 177.939,281.004 177.69,281.004 ccw(c177.69,280.147) 176.833,280.147 176.833,258.603 ccw(c177.753,258.603) 177.753,257.683 240.794,257.683 ccw(c240.794,259.197) 242.309,259.197 242.309,267.882 ccw(c240.847,267.882) 241.881,268.915 241.878,268.918 cw(c242.477,269.517) 241.63,269.517 241.63,273.846 cw(c242.175,273.846) v10(241.79,274.231) ccw(c241.79,274.121) 241.68,274.121
  L16 w0.101: v10(241.79,274.231) 241.713,274.155 241.713,273.996 241.69,273.972 241.69,272.194 J1_PCIE1.27@241.89,271.994
B223_Rx3_P: J1_PCIE1.25 U1.R4 | length 119.5
  L1 w0.1: U1.R4@176.397,291.539 176.769,291.168 v2(176.931,291.168)
  L5 (Sign) w0.081: v12(177.397,290.95) ccw(c177.556,290.95) 177.556,290.79 177.758,290.79 cw(c177.758,290.358) 178.191,290.358 178.191,287.506 ccw(c178.673,287.506) 178.332,287.165 178.47,287.026 cw(c178.127,286.683) 178.613,286.683 178.613,286.532 ccw(c178.735,286.532) 178.648,286.446 178.684,286.41 cw(c178.639,286.41) 178.671,286.378 v3@178.613,286.32
  L3 (Sign) w0.081: v2(176.931,291.168) 176.931,290.997 ccw(c177.138,290.997) 177.138,290.79 177.237,290.79 ccw(c177.237,290.95) v12(177.397,290.95)
  L14 (Sign) w0.081: v3@178.613,286.065 178.613,281.396 cw(c177.939,281.396) 177.939,280.723 177.69,280.723 ccw(c177.69,280.147) 177.114,280.147 177.114,278.849 177.114,278.724 ccw(c177.198,278.724) 177.198,278.64 177.334,278.64 cw(c177.334,278.556) 177.418,278.556 177.418,278.389 cw(c177.334,278.389) 177.334,278.305 177.198,278.305 ccw(c177.198,278.221) 177.114,278.221 177.114,277.845 177.114,258.603 ccw(c177.753,258.603) 177.753,257.964 240.794,257.964 ccw(c240.794,259.197) 242.028,259.197 242.028,267.879 ccw(c240.839,267.879) 241.68,268.719 ; 241.3,274.121 ccw(c241.19,274.121) v10(241.19,274.231) cw(c240.805,273.846) 241.349,273.846 241.349,269.516 ccw(c242.474,269.516) 241.679,268.72
  L16 w0.101: J1_PCIE1.25@241.09,271.994 241.289,272.193 241.289,273.972 241.266,273.996 241.266,274.155 v10(241.19,274.231)
  other v3: 178.772,286.224
B223_Tx0_to_C_N: C268.1 J1_PCIE0.26 | length 2
  L16 w0.101: J1_PCIE0.26@155.937,366.992 C268.1@155.937,369.037
B223_Tx0_to_C_P: C267.1 J1_PCIE0.24 | length 2
  L16 w0.101: J1_PCIE0.24@156.737,366.992 C267.1@156.737,369.037
B223_Tx0C_to_B_N: C268.2 U1.V1 | length 221.2
  L1 w0.1: U1.V1@179.397,288.539 v2(179.884,288.052)
  L3 (Sign) w0.081: v2(179.884,288.052) 179.884,288.1 cw(c180.196,288.1) 180.196,288.411 180.604,288.411 cw(c180.604,288.015) 181,288.015 181,283.226 cw(c180.841,283.226) v3(180.841,283.067)
  L14 (Sign) w0.081: v10(156.063,372.428) ccw(c156.063,372.587) 156.222,372.587 156.222,372.768 cw(c156.823,372.768) 156.823,373.368 162.607,373.368 cw(c162.607,372.428) 163.547,372.428 163.547,367.575 ccw(c164.276,367.575) 164.276,366.847 166.357,366.847 cw(c166.357,365.767) 167.437,365.767 167.437,361.358 ccw(c168.194,361.358) 168.194,360.601 219.857,360.601 cw(c219.857,359.508) 220.95,359.508 220.95,355.308 ccw(c221.418,355.308) 221.418,354.839 225.561,354.839 cw(c225.561,354.213) 226.187,354.213 226.187,311.274 cw(c225.216,311.274) 225.903,310.587 ; v3(180.841,283.067) cw(c180.841,282.907) 181,282.907 181,280.147 ccw(c182.357,280.147) 182.357,278.79 224.467,278.79 ccw(c224.467,280.147) 225.824,280.147 225.824,310.398 cw(c226.091,310.398) 225.902,310.587
  L16 w0.101: C268.2@155.937,369.557 ccw(c155.937,369.682) 156.063,369.682 v10(156.063,372.428)
B223_Tx0C_to_B_P: C267.2 U1.V2 | length 221.2
  L1 w0.1: U1.V2@179.397,289.539 v2(179.884,289.052)
  L3 (Sign) w0.081: v2(179.884,289.052) 179.884,289.004 ccw(c180.196,289.004) 180.196,288.692 180.604,288.692 cw(c180.604,288.015) 181.281,288.015 181.281,283.226 ccw(c181.441,283.226) v3(181.441,283.067)
  L14 (Sign) w0.081: v10(156.663,372.428) cw(c156.663,372.587) 156.503,372.587 156.503,372.768 cw(c156.823,372.768) 156.823,373.087 160.917,373.087 161.293,373.087 cw(c161.293,373.003) 161.376,373.003 161.376,372.816 ccw(c161.46,372.816) 161.46,372.732 161.628,372.732 ccw(c161.628,372.816) 161.711,372.816 161.711,373.003 cw(c161.795,373.003) 161.795,373.087 162.074,373.087 162.607,373.087 cw(c162.607,372.428) 163.266,372.428 163.266,367.575 ccw(c164.276,367.575) 164.276,366.566 166.357,366.566 cw(c166.357,365.767) 167.156,365.767 167.156,361.358 ccw(c168.194,361.358) 168.194,360.32 219.857,360.32 cw(c219.857,359.508) 220.669,359.508 220.669,355.308 ccw(c221.418,355.308) 221.418,354.558 225.561,354.558 cw(c225.561,354.213) 225.906,354.213 225.906,354.172 225.906,353.837 cw(c225.822,353.837) 225.822,353.754 225.687,353.754 ccw(c225.687,353.67) 225.603,353.67 225.603,353.502 ccw(c225.687,353.502) 225.687,353.419 225.822,353.419 cw(c225.822,353.335) 225.906,353.335 225.906,353.244 225.906,353.203 225.906,311.275 cw(c225.214,311.275) 225.704,310.785 ; v3(181.441,283.067) ccw(c181.441,282.907) 181.281,282.907 181.281,280.147 ccw(c182.357,280.147) 182.357,279.071 224.467,279.071 ccw(c224.467,280.147) 225.543,280.147 225.543,280.608 225.543,281.15 ccw(c225.459,281.15) 225.459,281.234 225.405,281.234 cw(c225.405,281.317) 225.321,281.317 225.321,281.485 cw(c225.405,281.485) 225.405,281.569 225.459,281.569 ccw(c225.459,281.653) 225.543,281.653 225.543,282.028 225.543,310.399 cw(c226.088,310.399) 225.703,310.784
  L16 w0.101: v10(156.663,372.428) 156.663,369.631 ccw(c156.737,369.631) C267.2@156.737,369.557
B223_Tx1_to_C_N: C270.1 J1_PCIE0.32 | length 2
  L16 w0.101: J1_PCIE0.32@153.537,366.992 C270.1@153.537,369.037
B223_Tx1_to_C_P: C269.1 J1_PCIE0.30 | length 2
  L16 w0.101: J1_PCIE0.30@154.337,366.992 C269.1@154.337,369.037
B223_Tx1C_to_B_N: C270.2 U1.U3 | length 218.7
  L1 w0.1: v2(177.909,291.027) U1.U3@178.397,290.539
  L5 (Sign) w0.081: v12(179.668,289.675) cw(c179.828,289.675) 179.828,289.835 180.037,289.835 cw(c180.037,289.294) 180.577,289.294 180.577,284.911 ccw(c181.617,284.911) 181.617,283.87 cw(c181.617,283.457) 182.03,283.457 182.03,281.974 ccw(c182.791,281.974) 182.791,281.213 183.165,281.213 cw(c183.165,281.051) 183.328,281.051 183.328,280.93 cw(c183.243,280.93) 183.243,280.846 183.201,280.804 v3(183.201,280.769)
  L3 (Sign) w0.081: v2(177.909,291.027) cw(c177.909,290.68) 178.256,290.68 178.256,290.61 ccw(c179.031,290.61) 179.031,289.835 179.509,289.835 cw(c179.509,289.675) v12(179.668,289.675)
  L14 (Sign) w0.081: v10(153.637,370.637) ccw(c153.637,370.796) 153.797,370.796 153.797,370.942 cw(c154.374,370.942) 154.374,371.519 159.92,371.519 cw(c159.92,369.619) 161.819,369.619 161.819,359.832 ccw(c162.609,359.832) 162.609,359.042 218.191,359.042 cw(c218.191,357.719) 219.514,357.719 219.514,353.983 ccw(c220.391,353.983) 220.391,353.106 223.547,353.106 cw(c223.547,352.083) 224.57,352.083 224.57,320.148 ccw(c225.768,320.148) 224.921,319.3 224.923,319.297 cw(c223.649,318.023) 225.452,318.023 225.452,312.139 cw(c223.65,312.139) 224.924,310.865 ; v3(183.201,280.769) 183.201,280.804 183.243,280.846 183.248,280.841 183.248,280.634 cw(c183.248,280.474) 183.407,280.474 183.407,280.298 ccw(c183.84,280.298) 183.84,279.866 223.298,279.866 ccw(c223.298,281.128) 224.56,281.128 224.56,309.988 cw(c225.8,309.988) 224.923,310.865
  L16 w0.101: C270.2@153.537,369.557 ccw(c153.537,369.657) 153.637,369.657 v10(153.637,370.637)
B223_Tx1C_to_B_P: C269.2 U1.U4 | length 218.1
  L1 w0.1: U1.U4@178.397,291.539 v2(178.884,291.052)
  L5 (Sign) w0.081: v12(179.668,290.275) ccw(c179.828,290.275) 179.828,290.116 180.037,290.116 cw(c180.037,289.294) 180.858,289.294 180.858,284.911 ccw(c181.617,284.911) 181.617,284.151 cw(c181.617,283.457) 182.311,283.457 182.311,281.974 ccw(c182.791,281.974) 182.791,281.494 183.165,281.494 cw(c183.165,281.051) 183.609,281.051 183.609,280.93 ccw(c183.693,280.93) 183.693,280.846 183.725,280.814 v3(183.843,280.814)
  L3 (Sign) w0.081: v2(178.884,291.052) ccw(c178.884,290.705) 178.537,290.705 178.537,290.61 ccw(c179.031,290.61) 179.031,290.116 179.509,290.116 ccw(c179.509,290.275) v12(179.668,290.275)
  L14 (Sign) w0.081: v10(154.237,370.637) cw(c154.237,370.796) 154.078,370.796 154.078,370.942 cw(c154.374,370.942) 154.374,371.238 159.92,371.238 cw(c159.92,369.619) 161.538,369.619 161.538,359.832 ccw(c162.609,359.832) 162.609,358.761 218.191,358.761 cw(c218.191,357.719) 219.233,357.719 219.233,353.983 ccw(c220.391,353.983) 220.391,352.825 223.547,352.825 cw(c223.547,352.083) 224.289,352.083 224.289,351.708 cw(c224.205,351.708) 224.205,351.624 224.018,351.624 ccw(c224.018,351.54) 223.934,351.54 223.934,351.373 ccw(c224.018,351.373) 224.018,351.289 224.205,351.289 cw(c224.205,351.205) 224.289,351.205 224.289,350.902 224.289,320.147 ccw(c225.766,320.147) 224.721,319.102 ; v3(183.843,280.814) 183.715,280.814 183.688,280.841 183.688,280.298 ccw(c183.84,280.298) 183.84,280.147 223.298,280.147 ccw(c223.298,281.128) 224.279,281.128 224.279,281.82 224.279,281.861 ccw(c224.195,281.861) 224.195,281.945 224.025,281.945 cw(c224.025,282.028) 223.941,282.028 223.941,282.196 cw(c224.025,282.196) 224.025,282.28 224.195,282.28 ccw(c224.195,282.364) 224.279,282.364 224.279,283.059 224.279,309.989 cw(c225.797,309.989) 224.724,311.062 224.725,311.063 ccw(c223.649,312.14) 225.171,312.14 225.171,318.019 ccw(c223.639,318.019) 224.722,319.102
  L16 w0.101: v10(154.237,370.637) 154.237,369.657 ccw(c154.337,369.657) C269.2@154.337,369.557
B223_Tx2_to_C_N: C272.1 J1_PCIE1.26 | length 2.3
  L16 w0.101: C272.1@241.49,261.709 241.48,261.709 241.38,261.808 241.38,261.959 241.291,262.049 241.291,263.595 J1_PCIE1.26@241.49,263.794
B223_Tx2_to_C_P: C271.1 J1_PCIE1.24 | length 2.3
  L16 w0.101: C271.1@240.69,261.709 240.7,261.709 240.799,261.808 240.799,261.959 240.89,262.049 240.89,263.595 J1_PCIE1.24@240.69,263.794
B223_Tx2C_to_B_N: C272.2 U1.T1 | length 97.9
  L1 w0.1: U1.T1@177.397,288.539 v2(177.884,288.052)
  L1 w0.101: v7(178.376,287.336) ccw(c179.051,287.336) 179.051,286.661 179.752,286.661 cw(c179.752,286.276) 180.136,286.276 180.136,286.041 cw(c180.111,286.041) v7(180.111,286.016)
  L3 (Sign) w0.081: v2(177.884,288.052) 177.884,288.232 cw(c178.064,288.232) 178.064,288.411 cw(c178.064,288.015) 178.46,288.015 178.46,287.363 cw(c178.433,287.363) 178.433,287.336 v7(178.376,287.336) ; v3(179.442,282.398) 179.468,282.416 179.602,282.55 179.602,283.255 ; 179.602,283.256 cw(c180.561,283.256) 179.609,283.376 179.614,283.403 cw(c180.57,283.252) 179.786,283.82 179.803,283.843 cw(c180.561,283.256) 179.883,283.934 ccw(c179.127,284.69) 180.196,284.69 180.196,286.016 v7(180.111,286.016)
  L14 (Sign) w0.081: v3(179.442,282.398) 179.442,282.393 ccw(c179.678,282.398) 179.511,282.232 cw(c179.293,282.013) 179.602,282.013 179.602,280.634 cw(c179.266,280.634) 179.266,280.298 ccw(c179.266,278.815) 177.783,278.815 177.783,261.887 177.783,260.363 ccw(c178.718,260.363) 178.718,259.428 240.477,259.428 ccw(c240.477,260.181) 241.23,260.181 241.23,260.279 cw(c241.39,260.279) v10(241.39,260.439)
  L16 w0.101: v10(241.39,260.439) 241.313,260.515 241.313,260.674 241.29,260.698 241.29,261.03 241.349,261.089 241.39,261.089 C272.2@241.49,261.189
B223_Tx2C_to_B_P: C271.2 U1.T2 | length 97.8
  L1 w0.1: U1.T2@177.397,289.539 v2(177.884,289.052)
  L1 w0.101: v7(178.826,287.336) ccw(c179.1,287.336) 179.1,287.062 179.752,287.062 cw(c179.752,286.276) 180.537,286.276 180.537,286.041 ccw(c180.561,286.041) v7(180.561,286.016)
  L3 (Sign) w0.081: v2(177.884,289.052) 177.884,288.872 ccw(c178.064,288.872) 178.064,288.692 cw(c178.064,288.015) 178.741,288.015 178.741,287.363 ccw(c178.769,287.363) 178.769,287.336 v7(178.826,287.336) ; v3(180.042,282.398) 180.017,282.416 179.883,282.55 179.883,283.252 cw(c180.57,283.252) 180.084,283.737 ; 180.085,283.738 ccw(c179.136,284.686) 180.477,284.686 180.477,286.016 v7(180.561,286.016)
  L14 (Sign) w0.081: v3(180.042,282.398) 180.042,282.395 cw(c179.807,282.398) 179.974,282.233 179.883,282.013 179.883,280.634 cw(c179.266,280.634) 179.266,280.017 ccw(c179.266,278.815) 178.064,278.815 178.064,277.59 178.064,277.291 ccw(c178.148,277.291) 178.148,277.208 178.263,277.208 cw(c178.263,277.124) 178.347,277.124 178.347,276.956 cw(c178.263,276.956) 178.263,276.872 178.148,276.872 ccw(c178.148,276.789) 178.064,276.789 178.064,276.413 178.064,261.887 178.064,260.363 ccw(c178.718,260.363) 178.718,259.709 240.477,259.709 ccw(c240.477,260.181) 240.949,260.181 240.949,260.279 ccw(c240.79,260.279) v10(240.79,260.439)
  L16 w0.101: C271.2@240.69,261.189 240.789,261.089 240.83,261.089 240.889,261.03 240.889,260.698 240.866,260.674 240.866,260.515 v10(240.79,260.439)
B223_Tx3_to_C_N: C275.1 J1_PCIE1.32 | length 2.3
  L16 w0.101: C275.1@243.89,261.709 243.88,261.709 243.78,261.808 243.78,261.959 243.691,262.049 243.691,263.595 J1_PCIE1.32@243.89,263.794
B223_Tx3_to_C_P: C274.1 J1_PCIE1.30 | length 2.3
  L16 w0.101: C274.1@243.09,261.709 243.1,261.709 243.199,261.808 243.199,261.959 243.29,262.049 243.29,263.594 J1_PCIE1.30@243.09,263.794
B223_Tx3C_to_B_N: C275.2 U1.P1 | length 106.8
  L1 w0.09: 175.599,287.539 175.599,288.337
  L1 w0.1: U1.P1@175.397,288.539 cw(c175.397,288.337) 175.599,288.337
  L1 w0.101: 175.599,287.539 175.599,285.465 ccw(c176.199,285.465) 176.199,284.865 v3(176.403,284.865)
  L14 (Sign) w0.081: v3(176.403,284.865) cw(c176.563,284.865) 176.563,285.025 176.872,285.025 cw(c176.872,284.782) 177.114,284.782 177.114,282.036 cw(c176.705,282.036) 176.705,281.627 176.204,281.627 ccw(c176.204,280.848) 175.425,280.848 175.425,257.645 ccw(c176.403,257.645) 176.403,256.666 242.858,256.666 ccw(c242.858,257.438) 243.63,257.438 243.63,260.546 cw(c243.79,260.546) v14(243.79,260.706)
  L16 w0.101: v14(243.79,260.706) cw(c243.79,260.805) 243.69,260.805 243.69,260.989 cw(c243.89,260.989) C275.2@243.89,261.189
B223_Tx3C_to_B_P: C274.2 U1.P2 | length 106.9
  L1 w0.09: 176,287.539 176,287.859
  L1 w0.1: U1.P2@175.397,289.539 cw(c175.397,289.047) 175.889,289.047 175.889,287.97 cw(c175.889,287.859) 176,287.859
  L1 w0.101: 176,287.539 176,285.465 v3(176.403,285.465)
  L14 (Sign) w0.081: v3(176.403,285.465) ccw(c176.563,285.465) 176.563,285.306 176.872,285.306 cw(c176.872,284.782) 177.395,284.782 177.395,282.036 cw(c176.705,282.036) 176.705,281.346 176.204,281.346 ccw(c176.204,280.848) 175.706,280.848 175.706,257.645 ccw(c176.403,257.645) 176.403,256.947 242.858,256.947 ccw(c242.858,257.438) 243.349,257.438 243.349,260.546 ccw(c243.19,260.546) v14(243.19,260.706)
  L16 w0.101: C274.2@243.09,261.189 cw(c243.09,260.989) 243.289,260.989 243.289,260.805 cw(c243.19,260.805) v14(243.19,260.706)
B224_Rx0_N: J1_PCIE2.21 U1.P5 | length 149.6
  L1 w0.1: v2(174.909,293.027) U1.P5@175.397,292.539
  L12 (Sign) w0.081: v3(177.138,286.593) cw(c177.297,286.593) 177.297,286.753 192.553,286.753 193.233,286.753 cw(c193.233,286.561) 193.425,286.561 193.425,286.558 ccw(c193.617,286.558) 193.617,286.366 193.873,286.366 ccw(c193.873,286.558) 194.065,286.558 194.065,286.561 cw(c194.256,286.561) 194.256,286.753 194.847,286.753 213.214,286.753 ccw(c213.214,288.213) 214.675,288.213 214.675,360.886 cw(c215.535,360.886) 215.535,361.747 239.978,361.747 cw(c239.978,361.175) 240.55,361.175 240.55,360.941 cw(c240.39,360.941) v17(240.39,360.782)
  L3 (Sign) w0.081: v2(174.909,293.027) 175.1,293.027 cw(c175.1,292.87) 175.256,292.87 ccw(c175.691,292.87) 175.691,292.436 176.042,292.436 cw(c176.042,292.132) 176.346,292.132 176.346,287.336 ccw(c176.929,287.336) 176.929,286.753 176.978,286.753 cw(c176.978,286.593) v3(177.138,286.593)
  L14 (Sign) w0.081: v14(240.39,360.168) v17(240.39,360.782)
  L16 w0.101: J1_PCIE2.21@240.29,358.792 ccw(c240.29,358.992) 240.49,358.992 240.49,360.069 ccw(c240.39,360.069) v14(240.39,360.168)
B224_Rx0_P: J1_PCIE2.19 U1.P6 | length 149.6
  L1 w0.1: U1.P6@175.397,293.539 v2(175.884,293.052)
  L12 (Sign) w0.081: v3(177.138,287.193) ccw(c177.297,287.193) 177.297,287.034 213.214,287.034 ccw(c213.214,288.213) 214.394,288.213 214.394,360.886 cw(c215.535,360.886) 215.535,362.028 224.355,362.028 224.396,362.028 ccw(c224.396,362.112) 224.48,362.112 224.48,362.231 cw(c224.563,362.231) 224.563,362.315 224.731,362.315 cw(c224.731,362.231) 224.815,362.231 224.815,362.112 ccw(c224.899,362.112) 224.899,362.028 225.184,362.028 239.978,362.028 cw(c239.978,361.175) 240.831,361.175 240.831,360.941 ccw(c240.99,360.941) v17(240.99,360.782)
  L3 (Sign) w0.081: v2(175.884,293.052) 175.719,293.052 ccw(c175.719,292.87) 175.537,292.87 ccw(c175.691,292.87) 175.691,292.717 176.042,292.717 cw(c176.042,292.132) 176.627,292.132 176.627,287.336 ccw(c176.929,287.336) 176.929,287.034 176.978,287.034 ccw(c176.978,287.193) v3(177.138,287.193)
  L14 (Sign) w0.081: v14(240.99,360.168) v17(240.99,360.782)
  L16 w0.101: v14(240.99,360.168) ccw(c240.99,360.069) 240.891,360.069 240.891,358.991 ccw(c241.09,358.991) J1_PCIE2.19@241.09,358.792
B224_Rx1_N: J1_PCIE2.27 U1.M5 | length 149.1
  L1 w0.1: U1.M5@173.402,292.551 173.646,292.307 v2(173.809,292.307)
  L5 (Sign) w0.081: v12(175.884,291.437) cw(c176.044,291.437) 176.044,291.597 176.181,291.597 cw(c176.181,291.381) 176.397,291.381 176.397,286.589 ccw(c177.377,286.589) 176.684,285.896 176.687,285.893 ccw(c178.102,287.308) 178.102,285.307 179.237,285.307 cw(c179.237,285.147) v3(179.397,285.147)
  L12 (Sign) w0.081: v3(179.397,285.147) cw(c179.556,285.147) v3@179.556,285.307 ; v3@179.558,285.307 196.844,285.361 cw(c196.846,284.97) 196.849,285.361 214.621,285.307 ; 214.622,285.307 ccw(c214.622,286.238) 215.554,286.238 215.554,359.928 cw(c216.478,359.928) 216.478,360.853 220.95,360.853 221.326,360.853 cw(c221.326,360.769) 221.409,360.769 221.409,360.692 ccw(c221.493,360.692) 221.493,360.608 221.661,360.608 ccw(c221.661,360.692) 221.745,360.692 221.745,360.769 cw(c221.828,360.769) 221.828,360.853 222.364,360.853 238.078,360.853 cw(c238.078,360.782) 238.15,360.782 238.15,360.582 cw(c237.99,360.582) v17(237.99,360.423)
  L3 (Sign) w0.081: v2(173.809,292.307) 173.809,292.339 cw(c174.131,292.339) 174.131,292.661 174.22,292.661 cw(c174.22,292.458) 174.423,292.458 174.423,292.263 ccw(c175.09,292.263) 175.09,291.597 175.725,291.597 cw(c175.725,291.437) v12(175.884,291.437)
  L14 (Sign) w0.081: v14(237.99,359.832) ccw(c237.99,359.992) 238.15,359.992 238.15,360.263 ccw(c237.99,360.263) v17(237.99,360.423)
  L16 w0.101: J1_PCIE2.27@237.89,358.792 ccw(c237.89,358.892) 237.99,358.892 v14(237.99,359.832)
B224_Rx1_P: J1_PCIE2.25 U1.M6 | length 149.2
  L1 w0.1: U1.M6@173.397,293.539 173.641,293.296 v2(173.809,293.296)
  L5 (Sign) w0.081: v12(175.884,292.037) ccw(c176.044,292.037) 176.044,291.878 176.205,291.878 cw(c176.205,291.404) 176.678,291.404 176.678,286.591 ccw(c177.383,286.591) 176.884,286.093 ccw(c178.104,287.312) 178.104,285.588 179.237,285.588 ccw(c179.237,285.747) v3(179.397,285.747)
  L12 (Sign) w0.081: v3(179.397,285.747) ccw(c179.556,285.747) 179.556,285.588 196.842,285.642 cw(c196.846,284.97) 196.849,285.642 214.622,285.588 ccw(c214.622,286.238) 215.273,286.238 215.273,359.928 cw(c216.478,359.928) 216.478,361.134 238.078,361.134 cw(c238.078,360.782) 238.431,360.782 238.431,360.582 ccw(c238.59,360.582) v17(238.59,360.423)
  L3 (Sign) w0.081: v2(173.809,293.296) 173.809,293.264 ccw(c174.131,293.264) 174.131,292.942 174.22,292.942 cw(c174.22,292.458) 174.704,292.458 174.704,292.263 ccw(c175.09,292.263) 175.09,291.878 175.725,291.878 ccw(c175.725,292.037) v12(175.884,292.037)
  L14 (Sign) w0.081: v14(238.59,359.832) cw(c238.59,359.992) 238.431,359.992 238.431,360.263 cw(c238.59,360.263) v17(238.59,360.423)
  L16 w0.101: v14(238.59,359.832) 238.59,358.892 ccw(c238.69,358.892) J1_PCIE2.25@238.69,358.792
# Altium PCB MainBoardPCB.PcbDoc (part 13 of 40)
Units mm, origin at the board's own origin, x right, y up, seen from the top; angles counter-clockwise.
Board outline 258.95 x 308.86 mm, 16 copper layers (L1, L2 (GND), L3 (Sign), L4 (GND), L5 (Sign), L6 (PWR/GND), L7(12V+Other), L8 (Plane_GND), L9 (PWR/GND), L10 (3V3+Other), L11 (PWR/GND), L12 (Sign), L13 (GND), L14 (Sign), L15 (GND), L16), stack 2.503 mm thick; 2578 components, 1867 nets, 8817 pads, 8021 vias.
Unrouted connection lines stored in the file: 25.

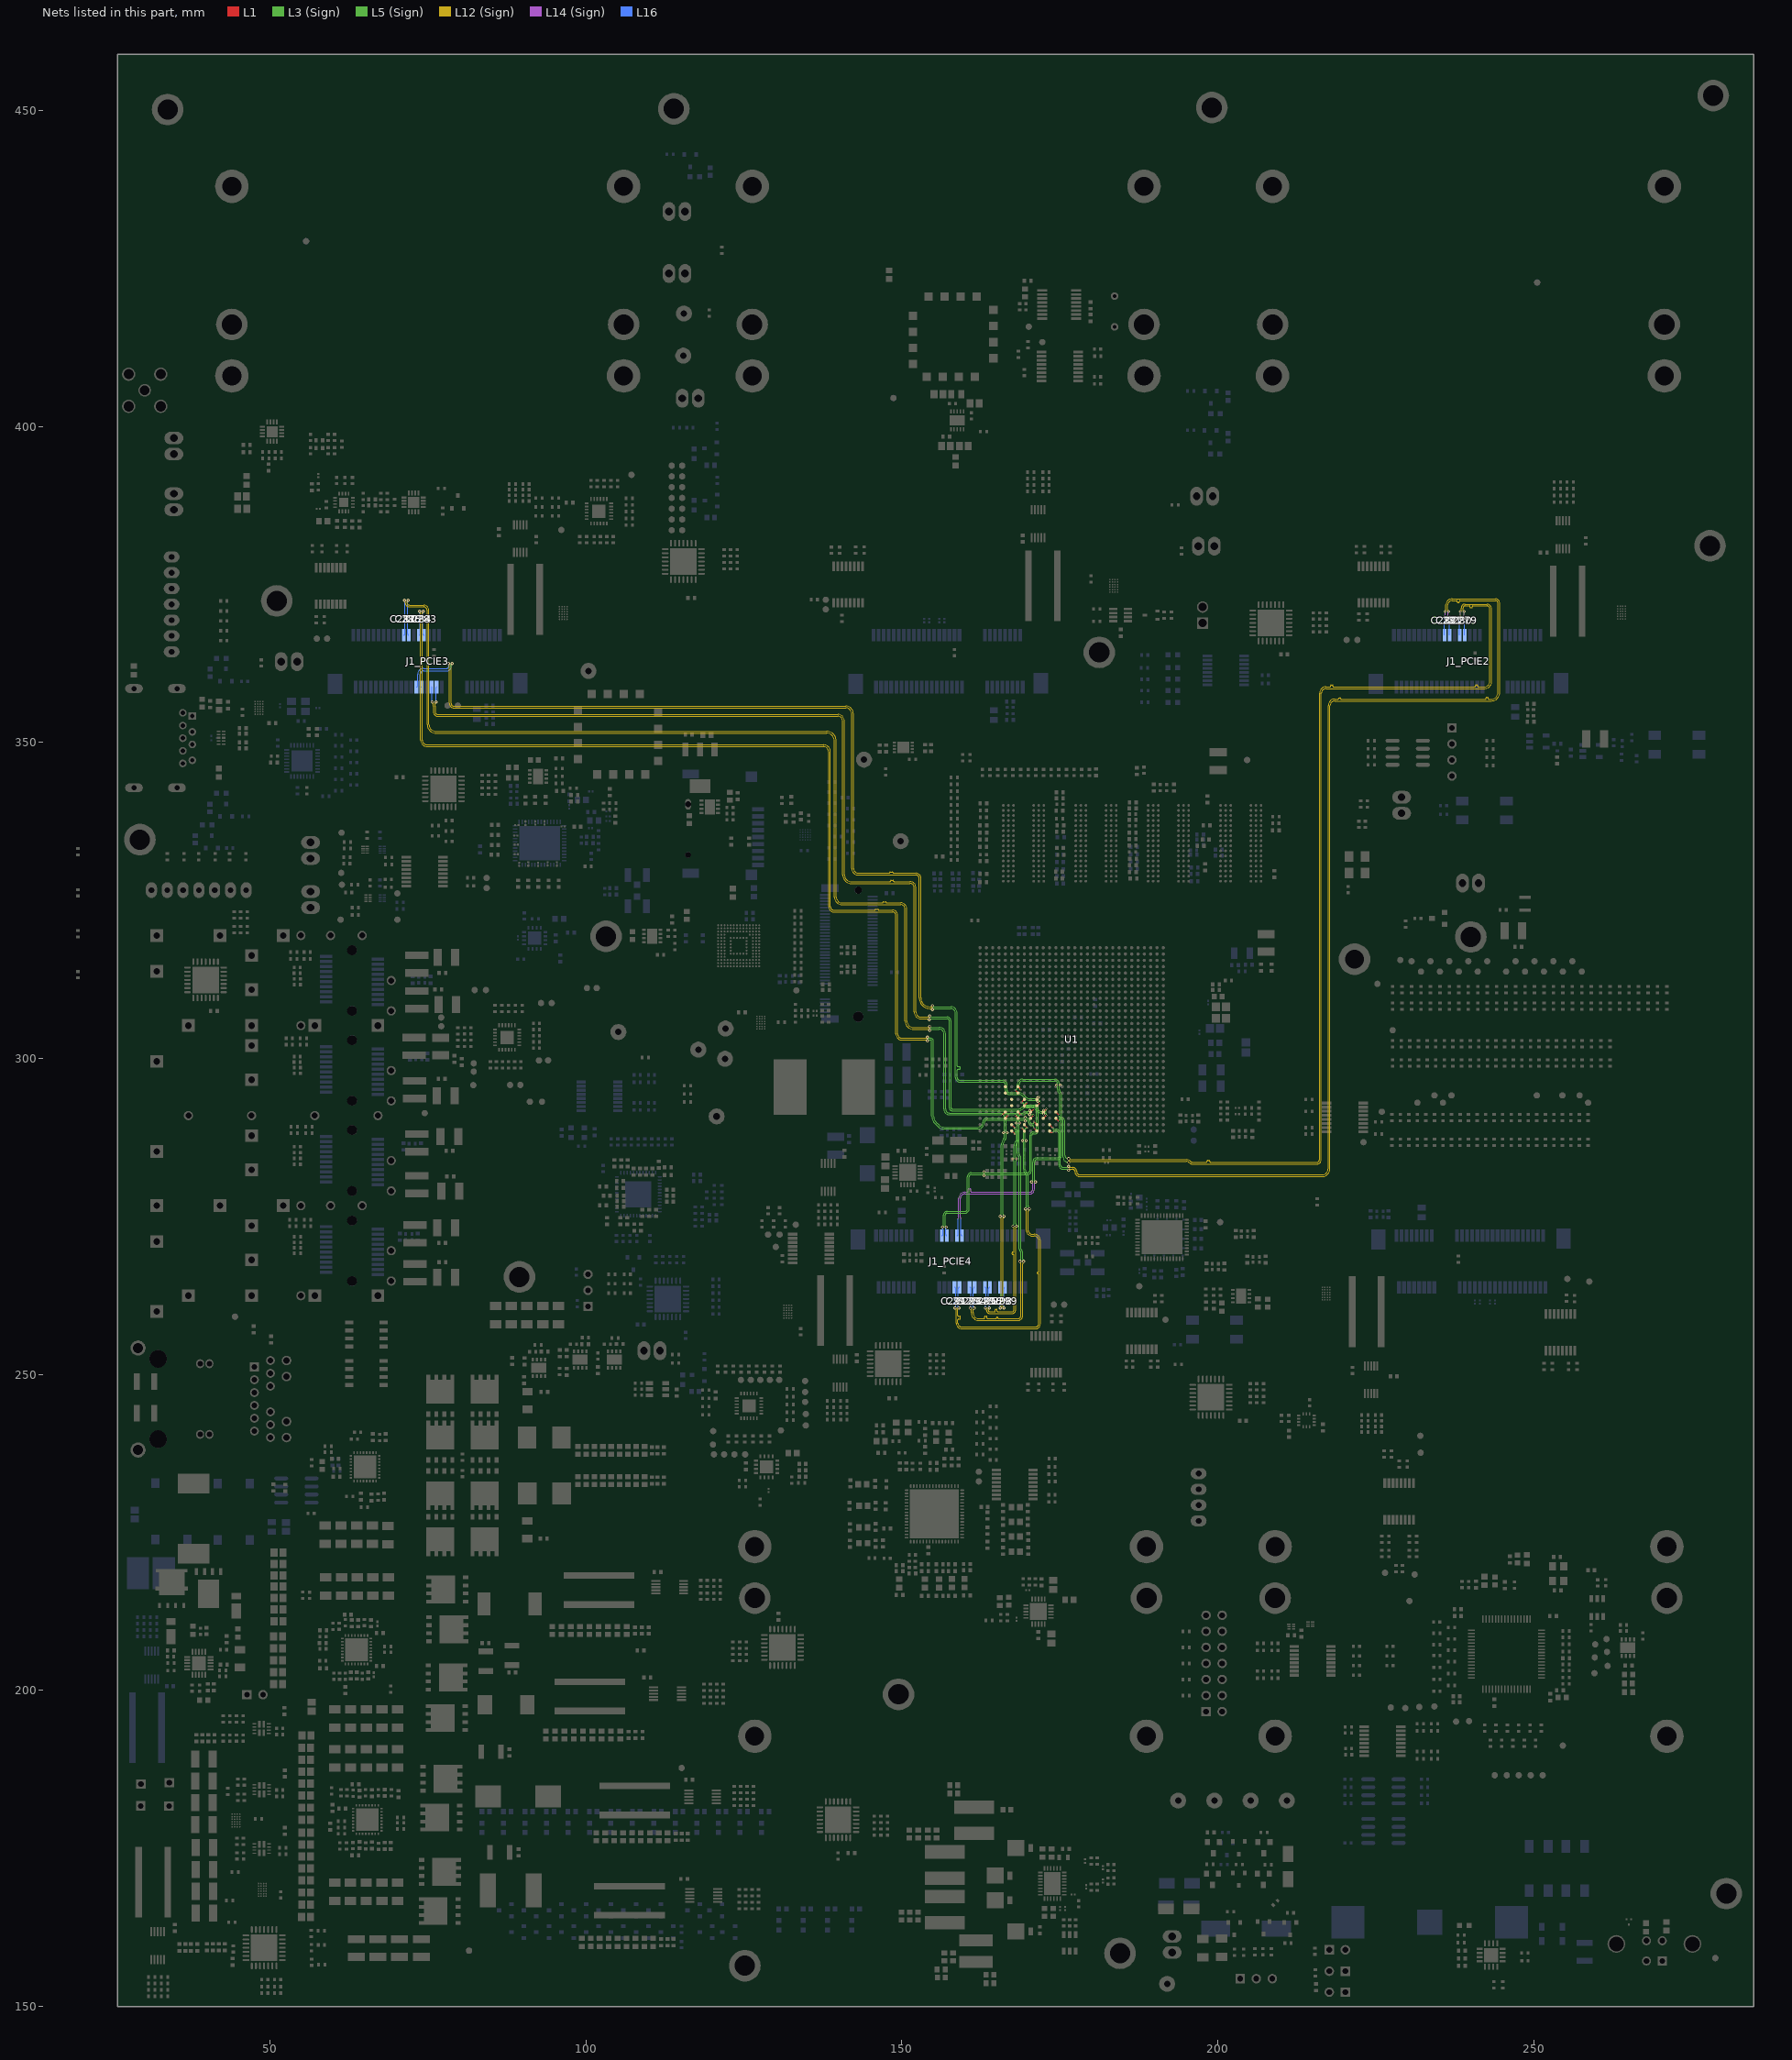
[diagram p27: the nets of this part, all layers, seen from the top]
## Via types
v1: diameter 0.5, hole 0.25, L1 to L16, tented both sides, 4341 vias
v2: diameter 0.254, hole 0.1, L1 to L3 (Sign), tented both sides, 781 vias
v3: diameter 0.5, hole 0.25, L1 to L16, 565 vias
v4: diameter 0.254, hole 0.1, L15 (GND) to L16, tented both sides, 406 vias
v5: diameter 0.254, hole 0.1, L1 to L2 (GND), tented both sides, 283 vias
v6: diameter 0.457, hole 0.2, L3 (Sign) to L6 (PWR/GND), tented both sides, 254 vias
v7: diameter 0.254, hole 0.1, L1 to L3 (Sign), 237 vias
v8: diameter 0.75, hole 0.4, L1 to L16, 200 vias
v9: diameter 0.8, hole 0.4, L1 to L16, tented both sides, 182 vias
v10: diameter 0.254, hole 0.1, L14 (Sign) to L16, tented both sides, 170 vias
v11: diameter 0.75/0/0/0/0/0/0/0/0/0/0/0/0/0/0/0.75 (per signal layer), hole 0.4, L1 to L16, 160 vias
v12: diameter 0.457, hole 0.2, L3 (Sign) to L6 (PWR/GND), 158 vias
v13: diameter 1.4, hole 0.5, L1 to L16, tented both sides, 80 vias
v14: diameter 0.254, hole 0.1, L14 (Sign) to L16, 65 vias
v15: diameter 0.254, hole 0.1, L1 to L2 (GND), 45 vias
v16: diameter 0.457, hole 0.2, L11 (PWR/GND) to L14 (Sign), tented both sides, 26 vias
v17: diameter 0.457, hole 0.2, L11 (PWR/GND) to L14 (Sign), 25 vias
v18: diameter 0.457, hole 0.2, L7(12V+Other) to L10 (3V3+Other), tented both sides, 11 vias
v19: diameter 0.254/0/0.254 (per signal layer), hole 0.1, L1 to L3 (Sign), 9 vias
v20: diameter 0.2/0/0.2 (per signal layer), hole 0.1, L1 to L3 (Sign), 6 vias
v21: diameter 1.65, hole 1.65, L1 to L16, 5 vias
v22: diameter 1.15, hole 1.15, L1 to L16, 5 vias
v23: diameter 0.457, hole 0.2, L1 to L16, 3 vias
v24: diameter 0.5, hole 0.3, L1 to L16, 2 vias
v25: diameter 0.5/0/0.5 (per signal layer), hole 0.2, L14 (Sign) to L16, 1 vias
v26: diameter 0.5, hole 0.25, L1 to L16, tented bottom, 1 vias

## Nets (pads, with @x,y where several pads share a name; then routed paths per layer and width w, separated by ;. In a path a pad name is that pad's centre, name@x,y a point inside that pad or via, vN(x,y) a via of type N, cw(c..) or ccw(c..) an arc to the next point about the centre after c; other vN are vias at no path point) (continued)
B224_Rx2_N: J1_PCIE3.21 U1.L3 | length 163.6
  L1 w0.1: U1.L3@172.397,290.539 v2(172.884,291.027)
  L5 (Sign) w0.081: v1(154.353,306.147) 154.604,306.3 157.143,306.3 cw(c157.143,305.925) 157.518,305.925 157.518,292.217 ccw(c158.006,292.217) 158.006,291.729 168.448,291.729 ccw(c168.448,292.706) 169.139,292.015 169.142,292.018 cw(c169.722,291.438) 169.722,292.258 169.724,292.258 170.245,292.258 cw(c170.245,290.893) 171.21,291.858 171.435,291.634 ccw(c172.033,292.233) 172.033,291.386 172.283,291.386 cw(c172.283,291.227) v12(172.442,291.227)
  L12 (Sign) w0.081: v1(75.685,356.4) cw(c75.685,356.241) 75.844,356.241 75.844,355.768 75.844,354.949 ccw(c76.639,354.949) 76.639,354.154 139.89,354.154 cw(c139.89,353.409) 140.635,353.409 140.635,329.086 ccw(c142.011,329.086) 142.011,327.71 151.315,327.71 cw(c151.315,327.058) 151.967,327.058 151.967,307.354 ccw(c153.021,307.354) 153.021,306.3 154.285,306.3 154.333,306.252 v1(154.353,306.147)
  L3 (Sign) w0.081: v12(172.442,291.227) cw(c172.602,291.227) 172.602,291.386 172.686,291.386 cw(c172.686,291.188) 172.884,291.188 v2(172.884,291.027)
  L16 w0.101: J1_PCIE3.21@75.585,358.792 cw(c75.585,358.692) 75.685,358.692 v1(75.685,356.4)
B224_Rx2_P: J1_PCIE3.19 U1.L4 | length 163.5
  L1 w0.1: U1.L4@172.397,291.539 v2(172.884,292.027)
  L5 (Sign) w0.081: v1(154.445,306.74) ccw(c154.604,306.74) 154.604,306.581 157.143,306.581 cw(c157.143,305.925) 157.799,305.925 157.799,292.217 ccw(c158.006,292.217) 158.006,292.01 168.446,292.01 ccw(c168.446,292.709) 168.941,292.215 168.945,292.219 cw(c169.719,291.444) 169.719,292.539 169.724,292.539 170.246,292.539 cw(c170.246,290.895) 171.409,292.058 171.632,291.834 ccw(c172.035,292.238) 172.035,291.667 172.283,291.667 ccw(c172.283,291.827) v12(172.442,291.827)
  L12 (Sign) w0.081: v1(76.285,356.4) ccw(c76.285,356.241) 76.125,356.241 76.125,355.768 76.125,354.949 ccw(c76.64,354.949) 76.64,354.435 139.89,354.435 cw(c139.89,353.409) 140.916,353.409 140.916,329.086 ccw(c142.011,329.086) 142.011,327.991 148.096,327.991 148.136,327.991 ccw(c148.136,328.088) 148.234,328.088 148.234,328.11 cw(c148.331,328.11) 148.331,328.207 148.623,328.207 cw(c148.623,328.11) 148.721,328.11 148.721,328.088 ccw(c148.818,328.088) 148.818,327.991 149.365,327.991 151.315,327.991 cw(c151.315,327.058) 152.248,327.058 152.248,307.354 ccw(c153.021,307.354) 153.021,306.581 154.285,306.581 ccw(c154.285,306.74) v1(154.445,306.74)
  L3 (Sign) w0.081: v12(172.442,291.827) ccw(c172.602,291.827) 172.602,291.667 172.686,291.667 ccw(c172.686,291.865) 172.884,291.865 v2(172.884,292.027)
  L16 w0.101: v1(76.285,356.4) 76.285,358.692 cw(c76.385,358.692) J1_PCIE3.19@76.385,358.792
B224_Rx3_N: J1_PCIE3.27 U1.K5 | length 168.5
  L1 w0.1: U1.K5@171.397,292.539 v2(171.884,293.027)
  L5 (Sign) w0.081: v1(154.862,307.762) cw(c155.022,307.762) 155.022,307.922 157.743,307.922 cw(c157.743,307.181) 158.484,307.181 158.484,297.015 ccw(c159.227,297.015) 159.227,296.272 166.016,296.272 cw(c166.016,295.901) 166.386,295.901 166.386,294.953 ccw(c167.016,294.953) 167.016,294.322 168.578,294.322 cw(c168.578,293.644) 169.058,294.124 169.483,293.698 ccw(c170.236,294.451) 170.236,293.386 171.378,293.386 cw(c171.378,293.227) v12(171.537,293.227)
  L12 (Sign) w0.081: v1(78.237,362.522) cw(c78.237,362.362) 78.397,362.362 78.397,356.203 ccw(c79.113,356.203) 79.113,355.487 141.147,355.487 cw(c141.147,354.564) 142.07,354.564 142.07,330.094 ccw(c143.118,330.094) 143.118,329.045 152.248,329.045 cw(c152.248,328.552) 152.74,328.552 152.74,309.601 ccw(c154.42,309.601) 154.42,307.922 154.703,307.922 cw(c154.703,307.762) v1(154.862,307.762)
  L3 (Sign) w0.081: v12(171.537,293.227) 171.537,293.287 cw(c171.636,293.287) 171.636,293.386 cw(c171.636,293.138) 171.884,293.138 v2(171.884,293.027)
  L16 w0.101: J1_PCIE3.27@73.185,358.792 ccw(c73.185,358.991) 73.385,358.991 73.385,360.766 cw(c74.36,360.766) 74.36,361.741 77.989,361.741 ccw(c77.989,362.082) 78.329,362.082 78.329,362.43 ccw(c78.237,362.43) v1(78.237,362.522)
B224_Rx3_P: J1_PCIE3.25 U1.K6 | length 168.5
  L1 w0.1: U1.K6@171.397,293.539 v2(171.794,293.937)
  L5 (Sign) w0.081: v1(154.862,308.362) ccw(c155.022,308.362) 155.022,308.203 157.743,308.203 cw(c157.743,307.181) 158.765,307.181 158.765,298.887 158.765,298.846 ccw(c158.895,298.846) 158.895,298.716 159.12,298.716 cw(c159.12,298.585) 159.251,298.585 159.251,298.411 cw(c159.12,298.411) 159.12,298.28 158.895,298.28 ccw(c158.895,298.149) 158.765,298.149 158.765,297.803 158.765,297.015 ccw(c159.227,297.015) 159.227,296.553 166.016,296.553 cw(c166.016,295.901) 166.667,295.901 166.667,294.953 ccw(c167.016,294.953) 167.016,294.604 168.579,294.604 cw(c168.579,293.646) 169.256,294.323 169.681,293.897 ccw(c170.237,294.453) 170.237,293.667 171.378,293.667 ccw(c171.378,293.827) v12(171.537,293.827)
  L12 (Sign) w0.081: v1(78.837,362.522) ccw(c78.837,362.362) 78.678,362.362 78.678,356.203 ccw(c79.113,356.203) 79.113,355.768 141.147,355.768 cw(c141.147,354.564) 142.351,354.564 142.351,330.094 ccw(c143.118,330.094) 143.118,329.326 147.958,329.326 147.998,329.326 ccw(c147.998,329.423) 148.096,329.423 cw(c148.193,329.423) 148.193,329.521 148.485,329.521 cw(c148.485,329.423) 148.583,329.423 ccw(c148.68,329.423) 148.68,329.326 149.365,329.326 152.248,329.326 cw(c152.248,328.552) 153.021,328.552 153.021,309.601 ccw(c154.42,309.601) 154.42,308.203 154.703,308.203 ccw(c154.703,308.362) v1(154.862,308.362)
  L3 (Sign) w0.081: v12(171.537,293.827) 171.651,293.827 171.731,293.907 171.764,293.907 v2(171.794,293.937)
  L16 w0.101: J1_PCIE3.25@73.985,358.792 cw(c73.985,358.991) 73.786,358.991 73.786,360.766 cw(c74.36,360.766) 74.36,361.34 77.989,361.34 ccw(c77.989,362.082) 78.73,362.082 78.73,362.414 cw(c78.837,362.414) v1(78.837,362.522)
B224_Tx0_to_C_N: C280.1 J1_PCIE2.26 | length 2.1
  L16 w0.101: J1_PCIE2.26@238.29,366.992 C280.1@238.29,369.075
B224_Tx0_to_C_P: C279.1 J1_PCIE2.24 | length 2.1
  L16 w0.101: J1_PCIE2.24@239.09,366.992 C279.1@239.09,369.075
B224_Tx0C_to_B_N: C280.2 U1.N3 | length 170.2
  L1 w0.1: U1.N3@174.397,290.539 v2(174.884,290.052)
  L12 (Sign) w0.081: v24(176.397,283.557) cw(c176.556,283.557) 176.556,283.716 177.138,283.716 192.19,283.716 195.016,283.716 cw(c195.016,283.019) 195.509,283.512 ; 195.51,283.511 ccw(c195.976,283.978) 195.976,283.318 215.718,283.318 ccw(c215.718,283.997) 216.397,283.997 216.397,357.78 cw(c217.168,357.78) 217.168,358.551 242.229,358.551 ccw(c242.229,359.69) 243.367,359.69 243.367,371.139 ccw(c242.606,371.139) 242.606,371.9 239.143,371.9 ccw(c239.143,371.306) 238.549,371.306 238.549,370.899 cw(c238.39,370.899) v17(238.39,370.74)
  L3 (Sign) w0.081: v2(174.884,290.052) 174.884,290.167 cw(c175.129,290.167) 175.129,290.411 cw(c175.129,290.003) 175.537,290.003 175.537,284.416 ccw(c176.397,284.416) v24(176.397,283.557)
  L14 (Sign) w0.081: v14(238.39,370.049) v17(238.39,370.74)
  L16 w0.101: C280.2@238.29,369.595 ccw(c238.29,369.794) 238.489,369.794 238.489,369.962 ccw(c238.402,369.962) 238.402,370.049 v14(238.39,370.049)
B224_Tx0C_to_B_P: C279.2 U1.N4 | length 170.2
  L1 w0.1: U1.N4@174.397,291.539 v2(174.884,291.052)
  L12 (Sign) w0.081: v24(176.397,284.157) ccw(c176.556,284.157) 176.556,283.997 177.138,283.997 192.19,283.997 195.017,283.997 cw(c195.017,283.02) 195.708,283.711 ; 195.708,283.711 ccw(c195.977,283.979) 195.977,283.599 198.138,283.599 198.179,283.599 ccw(c198.179,283.73) 198.31,283.73 198.31,283.733 cw(c198.44,283.733) 198.44,283.863 198.615,283.863 cw(c198.615,283.733) 198.745,283.733 198.745,283.73 ccw(c198.876,283.73) 198.876,283.599 199.233,283.599 215.718,283.599 ccw(c215.718,283.997) 216.116,283.997 216.116,357.78 cw(c217.168,357.78) 217.168,358.832 217.773,358.832 217.813,358.832 ccw(c217.813,358.916) 217.897,358.916 217.897,359.036 cw(c217.981,359.036) 217.981,359.12 218.148,359.12 cw(c218.148,359.036) 218.232,359.036 218.232,358.916 ccw(c218.316,358.916) 218.316,358.832 218.517,358.832 240.676,358.832 240.717,358.832 ccw(c240.717,358.916) 240.801,358.916 240.801,359.036 cw(c240.884,359.036) 240.884,359.12 241.052,359.12 cw(c241.052,359.036) 241.136,359.036 241.136,358.916 ccw(c241.22,358.916) 241.22,358.832 241.49,358.832 242.229,358.832 ccw(c242.229,359.69) 243.086,359.69 243.086,371.139 ccw(c242.606,371.139) 242.606,371.619 240.676,371.619 240.368,371.619 ccw(c240.368,371.535) 240.284,371.535 240.284,371.415 cw(c240.201,371.415) 240.201,371.332 240.033,371.332 cw(c240.033,371.415) 239.949,371.415 239.949,371.535 ccw(c239.865,371.535) 239.865,371.619 239.49,371.619 239.143,371.619 ccw(c239.143,371.306) 238.83,371.306 238.83,370.899 ccw(c238.99,370.899) v17(238.99,370.74)
  L3 (Sign) w0.081: v2(174.884,291.052) 174.884,290.937 ccw(c175.129,290.937) 175.129,290.692 cw(c175.129,290.003) 175.818,290.003 175.818,284.686 ccw(c176.348,284.686) 176.348,284.157 v24(176.397,284.157)
  L14 (Sign) w0.081: v14(238.99,370.049) v17(238.99,370.74)
  L16 w0.101: v14(238.99,370.049) 238.977,370.049 ccw(c238.977,369.962) 238.89,369.962 238.89,369.794 ccw(c239.09,369.794) C279.2@239.09,369.595
B224_Tx1_to_C_N: C282.1 J1_PCIE2.32 | length 2.1
  L16 w0.101: J1_PCIE2.32@235.89,366.992 C282.1@235.89,369.075
B224_Tx1_to_C_P: C281.1 J1_PCIE2.30 | length 2.1
  L16 w0.101: J1_PCIE2.30@236.69,366.992 C281.1@236.69,369.075
B224_Tx1C_to_B_N: C282.2 U1.M1 | length 179
  L1 w0.1: U1.M1@173.397,288.539 173.606,288.33 v2(173.884,288.33)
  L12 (Sign) w0.081: v3(176.397,282.32) cw(c176.556,282.32) 176.556,282.48 177.034,282.48 cw(c177.034,282.117) 177.397,282.117 ccw(c178.198,282.117) 178.198,281.316 216.47,281.316 ccw(c216.47,282.619) 217.773,282.619 217.773,355.84 cw(c218.517,355.84) 218.517,356.584 243.339,356.584 ccw(c243.339,357.884) 244.639,357.884 244.639,372.071 ccw(c243.972,372.071) 243.972,372.738 237.09,372.738 ccw(c237.09,371.775) 236.126,371.775 236.126,370.899 cw(c235.967,370.899) v17(235.967,370.74)
  L3 (Sign) w0.081: v2(173.884,288.33) cw(c174.105,288.33) 174.105,288.551 174.389,288.551 cw(c174.389,288.091) 174.848,288.091 174.848,283.169 ccw(c175.537,283.169) 175.537,282.48 176.237,282.48 cw(c176.237,282.32) v3(176.397,282.32)
  L14 (Sign) w0.081: v14(235.967,370.049) ccw(c235.967,370.124) 236.042,370.124 236.042,370.665 ccw(c235.967,370.665) v17(235.967,370.74)
  L16 w0.101: C282.2@235.89,369.595 ccw(c235.89,369.672) 235.967,369.672 v14(235.967,370.049)
B224_Tx1C_to_B_P: C281.2 U1.M2 | length 179.1
  L1 w0.1: U1.M2@173.397,289.539 v2(173.884,289.052)
  L12 (Sign) w0.081: v3(176.397,282.92) ccw(c176.556,282.92) 176.556,282.761 177.034,282.761 cw(c177.034,282.117) 177.678,282.117 ccw(c178.198,282.117) 178.198,281.597 216.47,281.597 ccw(c216.47,282.619) 217.492,282.619 217.492,355.84 cw(c218.517,355.84) 218.517,356.865 218.992,356.865 219.033,356.865 ccw(c219.033,356.949) 219.116,356.949 cw(c219.2,356.949) 219.2,357.033 219.368,357.033 cw(c219.368,356.949) 219.452,356.949 ccw(c219.535,356.949) 219.535,356.865 219.833,356.865 242.353,356.865 242.393,356.865 ccw(c242.393,356.949) 242.477,356.949 242.477,357.068 cw(c242.561,357.068) 242.561,357.152 242.729,357.152 cw(c242.729,357.068) 242.812,357.068 242.812,356.949 ccw(c242.896,356.949) 242.896,356.865 243.086,356.865 243.339,356.865 ccw(c243.339,357.884) 244.358,357.884 244.358,372.071 ccw(c243.972,372.071) 243.972,372.457 238.382,372.457 238.341,372.457 ccw(c238.341,372.373) 238.257,372.373 238.257,372.254 cw(c238.174,372.254) 238.174,372.17 238.006,372.17 cw(c238.006,372.254) 237.922,372.254 237.922,372.373 ccw(c237.838,372.373) 237.838,372.457 237.49,372.457 237.09,372.457 ccw(c237.09,371.775) 236.407,371.775 236.407,370.899 ccw(c236.567,370.899) v17(236.567,370.74)
  L3 (Sign) w0.081: v2(173.884,289.052) ccw(c174.105,289.052) 174.105,288.832 174.389,288.832 cw(c174.389,288.091) 175.129,288.091 175.129,283.169 ccw(c175.537,283.169) 175.537,282.761 176.237,282.761 ccw(c176.237,282.92) v3(176.397,282.92)
  L14 (Sign) w0.081: v14(236.567,370.049) cw(c236.567,370.124) 236.492,370.124 236.492,370.665 cw(c236.567,370.665) v17(236.567,370.74)
  L16 w0.101: v14(236.567,370.049) 236.567,369.717 ccw(c236.69,369.717) C281.2@236.69,369.595 cw(c236.69,369.708) C281.2@236.577,369.708
B224_Tx2_to_C_N: C284.1 J1_PCIE3.26 | length 2.5
  L16 w0.101: J1_PCIE3.26@73.585,366.992 ccw(c73.585,367.191) 73.784,367.191 73.784,369.104 ccw(c73.585,369.104) C284.1@73.585,369.303
B224_Tx2_to_C_P: C283.1 J1_PCIE3.24 | length 2.5
  L16 w0.101: J1_PCIE3.24@74.385,366.992 cw(c74.385,367.192) 74.185,367.192 74.185,369.104 cw(c74.385,369.104) C283.1@74.385,369.303
B224_Tx2C_to_B_N: C284.2 U1.K1 | length 180
  L1 w0.1: v2(170.909,289.027) U1.K1@171.397,288.539
  L5 (Sign) w0.081: v1(154.076,302.784) cw(c154.236,302.784) 154.236,302.943 154.516,302.943 cw(c154.516,302.714) 154.745,302.714 154.745,290.948 ccw(c156.529,290.948) 155.267,289.686 155.65,289.304 ccw(c156.725,290.38) 156.725,288.858 162.024,288.858 ccw(c162.024,289.928) 163.094,289.928 cw(c163.441,289.928) 163.441,290.276 169.378,290.276 cw(c169.378,290.116) 169.537,290.116 v12(169.537,290.115)
  L12 (Sign) w0.081: v1(73.685,370.789) cw(c73.685,370.63) 73.844,370.63 73.844,350.398 ccw(c74.875,350.398) 74.875,349.367 78.15,349.367 135.295,349.367 cw(c135.295,349.286) 135.307,349.366 ccw(c135.347,349.644) 135.347,349.363 137.623,349.363 cw(c137.624,349.282) 137.631,349.363 cw(c137.546,348.482) 138.431,348.482 138.431,324.064 ccw(c139.308,324.064) 139.308,323.186 148.572,323.186 cw(c148.572,322.688) 149.07,322.688 149.07,303.887 ccw(c150.014,303.887) 150.014,302.943 153.917,302.943 cw(c153.917,302.784) v1(154.076,302.784)
  L3 (Sign) w0.081: v12(169.537,290.115) 169.537,290.116 cw(c169.697,290.116) v12@169.697,290.276 ; v12@169.697,290.276 cw(c169.697,289.9) 170.073,289.9 170.073,289.873 ccw(c170.559,289.873) 170.559,289.386 170.668,289.386 cw(c170.668,289.145) 170.909,289.145 v2(170.909,289.027)
  L16 w0.101: C284.2@73.585,369.823 ccw(c73.585,370.023) 73.784,370.023 73.784,370.69 ccw(c73.685,370.69) v1(73.685,370.789)
B224_Tx2C_to_B_P: C283.2 U1.K2 | length 179.8
  L1 w0.1: v2(170.909,290.027) U1.K2@171.397,289.539
  L5 (Sign) w0.081: v1(154.076,303.384) ccw(c154.236,303.384) 154.236,303.224 154.516,303.224 cw(c154.516,302.714) 155.026,302.714 155.026,290.95 ccw(c156.534,290.95) 155.467,289.883 155.848,289.503 ccw(c156.726,290.382) 156.726,289.139 162.024,289.139 ccw(c162.024,289.928) 162.813,289.928 cw(c163.441,289.928) 163.441,290.557 169.378,290.557 ccw(c169.378,290.638) 169.443,290.589 v12(169.537,290.715)
  L12 (Sign) w0.081: v1(74.285,370.789) ccw(c74.285,370.63) 74.125,370.63 74.125,350.398 ccw(c74.875,350.398) 74.875,349.648 135.343,349.648 135.347,349.644 137.639,349.644 cw(c137.639,348.572) 138.712,348.572 138.712,324.064 ccw(c139.308,324.064) 139.308,323.467 145.696,323.467 145.737,323.467 ccw(c145.737,323.548) 145.818,323.548 145.818,323.558 cw(c145.891,323.558) 145.891,323.631 146.232,323.631 cw(c146.232,323.558) 146.305,323.558 146.305,323.548 ccw(c146.386,323.548) 146.386,323.467 147.104,323.467 148.572,323.467 cw(c148.572,322.688) 149.351,322.688 149.351,303.887 ccw(c150.014,303.887) 150.014,303.224 153.917,303.224 ccw(c153.917,303.384) v1(154.076,303.384)
  L3 (Sign) w0.081: v12(169.537,290.715) 169.632,290.589 ccw(c169.697,290.638) 169.697,290.557 cw(c169.697,289.9) 170.354,289.9 170.354,289.873 ccw(c170.559,289.873) 170.559,289.667 170.668,289.667 ccw(c170.668,289.909) 170.909,289.909 v2(170.909,290.027)
  L16 w0.101: v1(74.285,370.789) ccw(c74.285,370.69) 74.185,370.69 74.185,370.023 ccw(c74.385,370.023) C283.2@74.385,369.823
B224_Tx3_to_C_N: C287.1 J1_PCIE3.32 | length 2.5
  L16 w0.101: J1_PCIE3.32@71.185,366.992 ccw(c71.185,367.191) 71.384,367.191 71.384,369.104 ccw(c71.185,369.104) C287.1@71.185,369.303
B224_Tx3_to_C_P: C286.1 J1_PCIE3.30 | length 2.5
  L16 w0.101: J1_PCIE3.30@71.985,366.992 cw(c71.985,367.192) 71.785,367.192 71.785,369.104 cw(c71.985,369.104) C286.1@71.985,369.303
B224_Tx3C_to_B_N: C287.2 U1.J3 | length 180.9
  L1 w0.1: U1.J3@170.397,290.539 v2(170.884,291.027)
  L5 (Sign) w0.081: v1(154.445,304.485) cw(c154.604,304.485) 154.604,304.645 155.958,304.645 cw(c155.958,303.951) 156.653,303.951 156.653,292.01 ccw(c157.557,292.01) 157.557,291.105 169.265,291.105 ccw(c169.265,291.479) 169.53,291.215 cw(c169.794,290.95) 169.794,291.324 169.846,291.324 cw(c169.846,291.001) 170.075,291.23 170.122,291.182 ccw(c170.237,291.298) v12(170.237,291.135)
  L12 (Sign) w0.081: v1(71.285,372.529) cw(c71.285,372.37) 71.444,372.37 71.444,372.09 ccw(c72.061,372.09) 72.061,371.473 74.329,371.473 cw(c74.329,370.911) 74.891,370.911 74.891,352.885 ccw(c76.285,352.885) 76.285,351.492 138.126,351.492 cw(c138.126,350.262) 139.355,350.262 139.355,325.545 ccw(c140.558,325.545) 140.558,324.343 149.836,324.343 cw(c149.836,323.647) 150.531,323.647 150.531,305.928 ccw(c151.814,305.928) 151.814,304.645 154.285,304.645 cw(c154.285,304.485) v1(154.445,304.485)
  L3 (Sign) w0.081: v12(170.237,291.135) 170.776,291.135 cw(c170.776,291.027) v2(170.884,291.027)
  L16 w0.101: C287.2@71.185,369.823 ccw(c71.185,370.023) 71.384,370.023 v1@71.384,372.329
B224_Tx3C_to_B_P: C286.2 U1.J4 | length 180.8
  L1 w0.1: U1.J4@170.397,291.539 v2(170.884,292.027)
  L5 (Sign) w0.081: v1(154.445,305.085) ccw(c154.604,305.085) 154.604,304.926 155.958,304.926 cw(c155.958,303.951) 156.934,303.951 156.934,292.01 ccw(c157.557,292.01) 157.557,291.386 169.149,291.386 ccw(c169.149,291.76) 169.413,291.496 cw(c169.678,291.231) 169.678,291.605 169.854,291.605 ccw(c169.854,291.929) 170.083,291.7 170.13,291.747 cw(c170.245,291.632) v12(170.245,291.795)
  L12 (Sign) w0.081: v1(71.885,372.529) ccw(c71.885,372.37) 71.725,372.37 71.725,372.09 ccw(c72.061,372.09) 72.061,371.754 74.329,371.754 cw(c74.329,370.911) 75.172,370.911 75.172,352.885 ccw(c76.285,352.885) 76.285,351.773 138.126,351.773 cw(c138.126,350.262) 139.636,350.262 139.636,325.545 ccw(c140.558,325.545) 140.558,324.624 146.908,324.624 146.949,324.624 ccw(c146.949,324.705) 147.03,324.705 147.03,324.723 cw(c147.103,324.723) 147.103,324.796 147.444,324.796 cw(c147.444,324.723) 147.517,324.723 147.517,324.705 ccw(c147.598,324.705) 147.598,324.624 148.68,324.624 149.836,324.624 cw(c149.836,323.647) 150.812,323.647 150.812,305.928 ccw(c151.814,305.928) 151.814,304.926 154.285,304.926 ccw(c154.285,305.085) v1(154.445,305.085)
  L3 (Sign) w0.081: v12(170.245,291.795) 170.652,291.795 ccw(c170.652,292.027) v2(170.884,292.027)
  L16 w0.101: v1@71.785,372.329 71.785,370.023 ccw(c71.985,370.023) C286.2@71.985,369.823
B225_Rx0_N: J1_PCIE4.21 U1.H5 | length 37.8
  L1 w0.1: U1.H5@169.397,292.539 v2(169.884,293.027)
  L5 (Sign) w0.081: v3(157.037,273.326) cw(c157.037,273.485) 156.878,273.485 156.878,275.232 cw(c157.186,275.232) 157.186,275.54 159.995,275.54 ccw(c159.995,276.213) 160.668,276.213 160.668,281.286 cw(c161.036,281.286) 161.036,281.654 162.855,281.654 cw(c162.855,281.494) v12(163.014,281.494)
  L3 (Sign) w0.081: v12(163.014,281.494) cw(c163.174,281.494) 163.174,281.654 169.884,281.654 ccw(c169.884,282.329) 170.559,282.329 170.559,287.853 cw(c170.798,287.853) 170.798,288.091 171.123,288.091 ccw(c171.123,288.591) 171.623,288.591 171.623,292.143 ccw(c171.125,292.143) 171.125,292.64 169.768,292.64 cw(c169.768,292.87) 169.537,292.87 cw(c169.694,292.87) 169.694,293.027 v2(169.884,293.027)
  L16 w0.101: v3(157.037,273.326) ccw(c157.037,273.226) 156.938,273.226 156.938,272.193 ccw(c157.137,272.193) J1_PCIE4.21@157.137,271.994
B225_Rx0_P: J1_PCIE4.19 U1.H6 | length 37.7
  L1 w0.1: v2(168.909,293.052) U1.H6@169.397,293.539
  L5 (Sign) w0.081: v3(156.437,273.326) ccw(c156.437,273.485) 156.597,273.485 156.597,275.232 cw(c157.186,275.232) 157.186,275.821 159.995,275.821 ccw(c159.995,276.213) 160.387,276.213 160.387,281.286 cw(c161.036,281.286) 161.036,281.935 162.855,281.935 ccw(c162.855,282.094) v12(163.014,282.094)
  L3 (Sign) w0.081: v12(163.014,282.094) ccw(c163.174,282.094) 163.174,281.935 169.884,281.935 ccw(c169.884,282.329) 170.278,282.329 170.278,287.853 cw(c170.798,287.853) 170.798,288.372 171.007,288.372 ccw(c171.007,288.707) 171.342,288.707 171.342,292.143 ccw(c171.125,292.143) 171.125,292.359 169.768,292.359 cw(c169.768,292.87) 169.256,292.87 ccw(c169.075,292.87) 169.075,293.052 v2(168.909,293.052)
  L16 w0.101: J1_PCIE4.19@156.337,271.994 ccw(c156.337,272.194) 156.537,272.194 156.537,273.226 ccw(c156.437,273.226) v3(156.437,273.326)
B225_Rx1_N: J1_PCIE4.27 U1.G7 | length 49.3
  L1 w0.1: v2(167.909,295.027) U1.G7@168.397,294.539
  L5 (Sign) w0.081: v3(171.155,280.458) 171.155,280.302 cw(c171.155,280.461) 170.996,280.461 170.996,283.582 cw(c171.42,283.582) 171.42,284.007 174.626,284.007 ccw(c174.626,284.718) 175.338,284.718 175.338,294.136 ccw(c174.495,294.136) 175.091,294.731 175.09,294.733 cw(c175.475,295.118) 174.931,295.118 174.931,295.641 cw(c175.09,295.641) v12(175.09,295.8)
  L3 (Sign) w0.081: v2(167.909,295.027) 167.938,295.027 ccw(c167.938,295.345) 168.256,295.345 168.256,295.813 cw(c169.172,295.813) 169.172,296.729 174.224,296.729 cw(c174.224,296.023) 174.931,296.023 174.931,295.96 ccw(c175.09,295.96) v12(175.09,295.8)
  L14 (Sign) w0.081: v10(159.437,274.752) cw(c159.437,274.911) 159.278,274.911 159.278,277.845 cw(c160,277.845) 160,278.568 170.278,278.568 ccw(c170.278,279.285) 170.996,279.285 170.996,280.298 cw(c171.155,280.298) v3(171.155,280.458)
  L16 w0.101: v10(159.437,274.752) ccw(c159.437,274.652) 159.337,274.652 159.337,272.193 ccw(c159.537,272.193) J1_PCIE4.27@159.537,271.994
B225_Rx1_P: J1_PCIE4.25 U1.G8 | length 49.3
  L1 w0.1: U1.G8@168.397,295.539 v2(168.884,295.052)
  L5 (Sign) w0.081: v3(170.555,280.458) 170.555,280.302 ccw(c170.555,280.461) 170.715,280.461 170.715,283.582 cw(c171.42,283.582) 171.42,284.288 174.626,284.288 ccw(c174.626,284.718) 175.057,284.718 175.057,294.134 ccw(c174.492,294.134) 174.891,294.534 174.89,294.535 cw(c175.472,295.116) 174.65,295.116 174.65,295.641 ccw(c174.49,295.641) v12(174.49,295.8)
  L3 (Sign) w0.081: v2(168.884,295.052) 168.83,295.052 cw(c168.83,295.345) 168.537,295.345 168.537,295.813 cw(c169.172,295.813) 169.172,296.448 174.224,296.448 cw(c174.224,296.023) 174.65,296.023 174.65,295.96 cw(c174.49,295.96) v12(174.49,295.8)
  L14 (Sign) w0.081: v10(158.837,274.752) ccw(c158.837,274.911) 158.997,274.911 158.997,277.845 cw(c160,277.845) 160,278.849 160.318,278.849 160.359,278.849 ccw(c160.359,278.979) 160.49,278.979 160.49,279.279 cw(c160.62,279.279) 160.62,279.41 160.795,279.41 cw(c160.795,279.279) 160.925,279.279 160.925,278.979 ccw(c161.056,278.979) 161.056,278.849 161.269,278.849 162.482,278.849 163.382,278.849 170.278,278.849 ccw(c170.278,279.285) 170.715,279.285 170.715,280.298 ccw(c170.555,280.298) v3(170.555,280.458)
  L16 w0.101: J1_PCIE4.25@158.737,271.994 ccw(c158.737,272.193) 158.936,272.193 158.936,274.652 ccw(c158.837,274.652) v10(158.837,274.752)
B225_Rx2_N: U1.F5
B225_Rx2_P: U1.F6
B225_Rx3_N: U1.E7
B225_Rx3_P: U1.E8
B225_Tx0_to_C_N: C292.1 J1_PCIE4.26 | length 2.2
  L16 w0.101: C292.1@159.137,261.861 cw(c159.137,262.061) 158.938,262.061 158.938,263.595 cw(c159.137,263.595) J1_PCIE4.26@159.137,263.794
B225_Tx0_to_C_P: C291.1 J1_PCIE4.24 | length 2.2
  L16 w0.101: C291.1@158.337,261.861 ccw(c158.337,262.061) 158.537,262.061 158.537,263.594 ccw(c158.337,263.594) J1_PCIE4.24@158.337,263.794
B225_Tx0C_to_B_N: C292.2 U1.H1 | length 51.4
  L1 w0.1: v2(168.909,289.027) U1.H1@169.397,288.539
  L5 (Sign) w0.081: v12(169.097,287.011) cw(c169.097,286.851) 169.256,286.851 169.256,282.47 ccw(c170.211,282.47) 169.536,281.795 169.537,281.794 cw(c169.028,281.285) 169.748,281.285 169.748,276.66 ccw(c169.94,276.468) 169.669,276.468 169.669,276.419 cw(c169.395,276.419) v3(169.589,276.225)
  L12 (Sign) w0.081: v1(159.037,260.528) ccw(c159.037,260.368) 158.878,260.368 158.878,259.78 158.878,259.341 ccw(c159.008,259.341) 159.008,259.211 159.185,259.211 cw(c159.185,259.08) 159.315,259.08 159.315,258.906 cw(c159.185,258.906) 159.185,258.775 159.008,258.775 ccw(c159.008,258.644) 158.878,258.644 158.878,258.168 ccw(c159.504,258.168) 159.504,257.542 171.229,257.542 ccw(c171.229,257.97) 171.658,257.97 171.658,265.667 171.658,265.829 ccw(c171.558,265.829) 171.558,265.928 171.536,265.928 cw(c171.536,266.028) 171.437,266.028 171.437,266.113 cw(c171.536,266.113) 171.536,266.212 171.558,266.212 ccw(c171.558,266.312) 171.658,266.312 171.658,266.637 171.658,271.219 ccw(c170.948,271.219) 170.948,271.929 170.619,271.929 cw(c170.619,272.812) 169.736,272.812 169.736,274.636 cw(c169.778,274.636) 169.748,274.665 169.748,275.84 ccw(c169.439,275.84) 169.658,276.059 cw(c169.824,276.225) v3(169.589,276.225)
  L3 (Sign) w0.081: v2(168.909,289.027) 169.061,289.027 cw(c169.061,288.832) 169.256,288.832 169.256,287.17 cw(c169.097,287.17) v12(169.097,287.011)
  L16 w0.101: v1(159.037,260.528) cw(c159.037,260.627) 158.938,260.627 158.938,261.142 cw(c159.137,261.142) C292.2@159.137,261.341
B225_Tx0C_to_B_P: C291.2 U1.H2 | length 51.4
  L1 w0.1: U1.H2@169.397,289.539 v2(169.884,289.052)
  L5 (Sign) w0.081: v12(169.697,287.011) ccw(c169.697,286.851) 169.537,286.851 169.537,282.472 ccw(c170.215,282.472) 169.736,281.993 ; 169.737,281.992 cw(c169.031,281.286) 170.029,281.286 170.029,276.66 cw(c169.838,276.468) 170.109,276.468 170.109,276.419 ccw(c170.382,276.419) v3(170.189,276.225)
  L12 (Sign) w0.081: v1(158.437,260.528) cw(c158.437,260.368) 158.597,260.368 158.597,258.168 ccw(c159.504,258.168) 159.504,257.261 171.229,257.261 ccw(c171.229,257.97) 171.939,257.97 171.939,271.219 ccw(c170.948,271.219) 170.948,272.21 170.619,272.21 cw(c170.619,272.812) 170.017,272.812 170.017,274.519 cw(c170.059,274.519) 170.029,274.549 170.029,275.84 cw(c170.338,275.84) 170.12,276.059 ccw(c169.953,276.225) v3(170.189,276.225)
  L3 (Sign) w0.081: v12(169.697,287.011) cw(c169.697,287.17) 169.537,287.17 169.537,288.832 cw(c169.758,288.832) 169.758,289.052 v2(169.884,289.052)
  L16 w0.101: C291.2@158.337,261.341 cw(c158.337,261.142) 158.537,261.142 158.537,260.627 cw(c158.437,260.627) v1(158.437,260.528)
B225_Tx1_to_C_N: C294.1 J1_PCIE4.32 | length 2.2
  L16 w0.101: J1_PCIE4.32@161.537,263.794 ccw(c161.537,263.595) 161.338,263.595 161.338,262.061 ccw(c161.537,262.061) C294.1@161.537,261.861
B225_Tx1_to_C_P: C293.1 J1_PCIE4.30 | length 2.2
  L16 w0.101: C293.1@160.737,261.861 ccw(c160.737,262.061) 160.937,262.061 160.937,263.594 ccw(c160.737,263.594) J1_PCIE4.30@160.737,263.794
B225_Tx1C_to_B_N: C294.2 U1.G3 | length 44.3
  L1 w0.1: v2(167.909,291.027) U1.G3@168.397,290.539
  L5 (Sign) w0.081: v12(168.097,289.801) cw(c168.097,289.642) 168.256,289.642 168.256,285.061 ccw(c169.02,285.061) 168.48,284.521 168.482,284.52 cw(c168.248,284.286) 168.579,284.286 168.579,269.915 ccw(c169.144,269.915) 168.744,269.515 168.746,269.514 cw(c168.519,269.287) 168.84,269.287 168.84,268.264 cw(c168.568,268.264) 168.76,268.071 168.749,268.06 ccw(c168.916,267.894) v3(168.68,267.894)
  L12 (Sign) w0.081: v1(161.437,260.502) ccw(c161.437,260.343) 161.278,260.343 161.278,259.78 ccw(c162.236,259.78) 162.236,258.821 162.827,258.821 163,258.821 ccw(c163,258.937) 163.116,258.937 163.116,259.119 cw(c163.231,259.119) 163.231,259.234 163.386,259.234 cw(c163.386,259.119) 163.501,259.119 163.501,258.937 ccw(c163.617,258.937) 163.617,258.821 164.043,258.821 164.878,258.821 164.919,258.821 ccw(c164.919,258.903) 165.001,258.903 165.001,258.967 cw(c165.082,258.967) 165.082,259.049 165.152,259.049 cw(c165.152,258.967) 165.234,258.967 165.234,258.903 ccw(c165.316,258.903) 165.316,258.821 165.67,258.821 168.374,258.821 ccw(c168.374,259.287) 168.84,259.287 168.84,267.509 ccw(c168.531,267.509) 168.749,267.728 cw(c168.916,267.894) v3(168.68,267.894)
  L3 (Sign) w0.081: v2(167.909,291.027) cw(c167.94,290.996) 167.94,291.039 168.175,291.039 cw(c168.175,290.958) 168.233,291.016 cw(c168.175,290.958) 168.256,290.958 168.256,289.961 cw(c168.097,289.961) v12(168.097,289.801)
  L16 w0.101: v1(161.437,260.502) cw(c161.437,260.602) 161.338,260.602 161.338,261.142 cw(c161.537,261.142) C294.2@161.537,261.341
B225_Tx1C_to_B_P: C293.2 U1.G4 | length 44.3
  L1 w0.1: U1.G4@168.397,291.539 v2(168.884,291.052)
  L5 (Sign) w0.081: v12(168.697,289.801) ccw(c168.697,289.642) 168.537,289.642 168.537,285.064 ccw(c169.026,285.064) 168.68,284.718 168.682,284.717 cw(c168.253,284.288) 168.86,284.288 168.86,269.918 ccw(c169.15,269.918) 168.945,269.712 168.946,269.711 cw(c168.523,269.289) 169.121,269.289 169.121,268.264 ccw(c169.393,268.264) 169.201,268.071 v3@169.212,268.06 ; v3@169.212,268.06 cw(c169.045,267.894) v3(169.28,267.894)
  L12 (Sign) w0.081: v1(160.837,260.502) cw(c160.837,260.343) 160.997,260.343 160.997,259.78 ccw(c162.236,259.78) 162.236,258.54 168.374,258.54 ccw(c168.374,259.287) 169.121,259.287 169.121,267.509 cw(c169.43,267.509) 169.212,267.728 ccw(c169.045,267.894) v3(169.28,267.894)
  L3 (Sign) w0.081: v12(168.697,289.801) cw(c168.697,289.961) 168.537,289.961 168.537,290.95 cw(c168.64,290.95) 168.567,291.022 cw(c168.64,290.95) 168.64,291.052 v2(168.884,291.052)
  L16 w0.101: C293.2@160.737,261.341 cw(c160.737,261.142) 160.937,261.142 160.937,260.602 cw(c160.837,260.602) v1(160.837,260.502)
B225_Tx2_to_C_N: C296.1 J1_PCIE4.38 | length 2.2
  L16 w0.101: C296.1@163.937,261.861 cw(c163.937,262.061) 163.738,262.061 163.738,263.595 cw(c163.937,263.595) J1_PCIE4.38@163.937,263.794
B225_Tx2_to_C_P: C295.1 J1_PCIE4.36 | length 2.2
  L16 w0.101: C295.1@163.137,261.861 ccw(c163.137,262.061) 163.337,262.061 163.337,263.594 ccw(c163.137,263.594) J1_PCIE4.36@163.137,263.794
B225_Tx2C_to_B_N: C296.2 U1.F1 | length 36.7
  L1 w0.1: U1.F1@167.397,288.539 v2(167.884,288.052)
  L5 (Sign) w0.081: v3(167.583,273.469) cw(c167.818,273.469) 167.652,273.635 ccw(c167.433,273.854) 167.743,273.854 167.743,283.765 ccw(c167.47,283.765) 167.663,283.958 cw(c167.855,284.15) 167.583,284.15 v12@167.583,284.251
  L12 (Sign) w0.081: v1(163.837,260.528) ccw(c163.837,260.368) 163.678,260.368 163.678,260.198 ccw(c163.957,260.198) 163.957,259.918 164.142,259.918 164.677,259.918 ccw(c164.677,260.019) 164.778,260.019 164.778,260.216 cw(c164.878,260.216) 164.878,260.316 165.012,260.316 cw(c165.012,260.216) 165.113,260.216 165.113,260.019 ccw(c165.213,260.019) 165.213,259.918 165.589,259.918 167.472,259.918 ccw(c167.472,260.19) 167.743,260.19 167.743,268.886 167.743,268.927 ccw(c167.659,268.927) 167.659,269.01 167.539,269.01 cw(c167.539,269.094) 167.455,269.094 167.455,269.262 cw(c167.539,269.262) 167.539,269.346 167.659,269.346 ccw(c167.659,269.429) 167.743,269.429 167.743,269.741 167.743,273.31 ccw(c167.583,273.31) v3(167.583,273.469)
  L3 (Sign) w0.081: v12(167.583,284.135) ccw(c167.583,284.294) 167.743,284.294 167.743,286.185 cw(c168.702,286.185) 168.024,286.863 ccw(c167.549,287.338) 168.22,287.338 168.22,288.215 ccw(c168.024,288.215) 168.024,288.411 ccw(c168.024,288.272) 167.884,288.272 v2(167.884,288.052)
  L16 w0.101: v1(163.837,260.528) 163.837,261.241 cw(c163.937,261.241) C296.2@163.937,261.341
B225_Tx2C_to_B_P: C295.2 U1.F2 | length 36.9
  L1 w0.1: U1.F2@167.397,289.539 v2(167.884,289.052)
  L5 (Sign) w0.081: v3(168.183,273.469) ccw(c167.948,273.469) 168.114,273.635 cw(c168.333,273.854) 168.024,273.854 168.024,283.765 cw(c168.296,283.765) 168.103,283.958 168.114,283.968 ccw(c167.948,284.135) v12(168.183,284.135)
  L12 (Sign) w0.081: v1(163.237,260.528) cw(c163.237,260.368) 163.397,260.368 163.397,260.198 ccw(c163.957,260.198) 163.957,259.637 167.472,259.637 ccw(c167.472,260.19) 168.024,260.19 168.024,273.31 cw(c168.183,273.31) v3(168.183,273.469)
  L3 (Sign) w0.081: v2(167.884,289.052) 167.884,288.832 ccw(c168.024,288.832) 168.024,288.692 cw(c168.024,288.215) 168.501,288.215 168.501,287.338 cw(c167.549,287.338) 168.222,286.665 ccw(c168.702,286.185) 168.024,286.185 168.024,284.294 ccw(c168.183,284.294) v12(168.183,284.135)
  L16 w0.101: C295.2@163.137,261.341 cw(c163.137,261.241) 163.237,261.241 v1(163.237,260.528)
B225_Tx3_to_C_N: C299.1 J1_PCIE4.44 | length 2.2
  L16 w0.101: C299.1@166.337,261.861 cw(c166.337,262.061) 166.138,262.061 166.138,263.595 cw(c166.337,263.595) J1_PCIE4.44@166.337,263.794
B225_Tx3_to_C_P: C298.1 J1_PCIE4.42 | length 2.2
  L16 w0.101: C298.1@165.537,261.861 ccw(c165.537,262.061) 165.737,262.061 165.737,263.594 ccw(c165.537,263.594) J1_PCIE4.42@165.537,263.794
B225_Tx3C_to_B_N: C299.2 U1.E3 | length 32.7
  L1 w0.1: U1.E3@166.397,290.539 v2(166.846,291.027)
  L5 (Sign) w0.081: v3@166.098,275.223 166.087,275.233 cw(c166.279,275.425) 166.008,275.425 166.008,278.626 166.016,278.634 166.016,286.32 cw(c167.21,286.32) 166.366,287.165 ccw(c165.951,287.58) 166.537,287.58 166.537,288.131 cw(c166.697,288.131) v12(166.697,288.29) ; v3@166.098,275.223 cw(c165.93,275.056) v3(166.167,275.056)
  L12 (Sign) w0.081: v3(166.167,275.056) 166.167,274.95 ccw(c166.248,274.95) 166.189,274.894 ccw(c166.189,274.734) 166.03,274.734 166.03,271.731 166.03,261.772 166.03,260.687 ccw(c166.189,260.687) v1(166.189,260.528)
  L3 (Sign) w0.081: v12(166.697,288.29) cw(c166.697,288.449) 166.537,288.449 166.537,290.682 cw(c166.618,290.682) 166.561,290.739 v2(166.846,291.027)
  L16 w0.101: v1(166.189,260.528) 166.189,261.193 cw(c166.337,261.193) C299.2@166.337,261.341
B225_Tx3C_to_B_P: C298.2 U1.E4 | length 32.8
  L1 w0.1: v2(165.909,291.052) U1.E4@166.397,291.539
  L5 (Sign) w0.081: v3@165.568,274.939 165.568,275.005 cw(c165.839,275.005) 165.647,275.197 ccw(c165.455,275.389) 165.727,275.389 165.727,278.743 165.735,278.75 165.735,286.32 cw(c167.21,286.32) 166.167,287.363 ccw(c165.951,287.58) 166.256,287.58 166.256,288.131 ccw(c166.097,288.131) v12(166.097,288.29)
  L12 (Sign) w0.081: v1(165.589,260.528) ccw(c165.589,260.687) 165.749,260.687 165.749,261.772 165.749,271.731 165.749,274.734 ccw(c165.589,274.734) v3@165.589,274.894
  L3 (Sign) w0.081: v2(165.909,291.052) cw(c165.909,290.705) 166.256,290.705 166.256,288.449 cw(c166.097,288.449) v12(166.097,288.29)
  L16 w0.101: C298.2@165.537,261.341 cw(c165.537,261.289) 165.589,261.289 v1(165.589,260.528)
  other v3: 165.568,275.02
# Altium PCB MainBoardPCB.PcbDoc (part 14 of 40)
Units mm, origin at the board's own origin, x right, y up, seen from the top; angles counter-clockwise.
Board outline 258.95 x 308.86 mm, 16 copper layers (L1, L2 (GND), L3 (Sign), L4 (GND), L5 (Sign), L6 (PWR/GND), L7(12V+Other), L8 (Plane_GND), L9 (PWR/GND), L10 (3V3+Other), L11 (PWR/GND), L12 (Sign), L13 (GND), L14 (Sign), L15 (GND), L16), stack 2.503 mm thick; 2578 components, 1867 nets, 8817 pads, 8021 vias.
Unrouted connection lines stored in the file: 25.

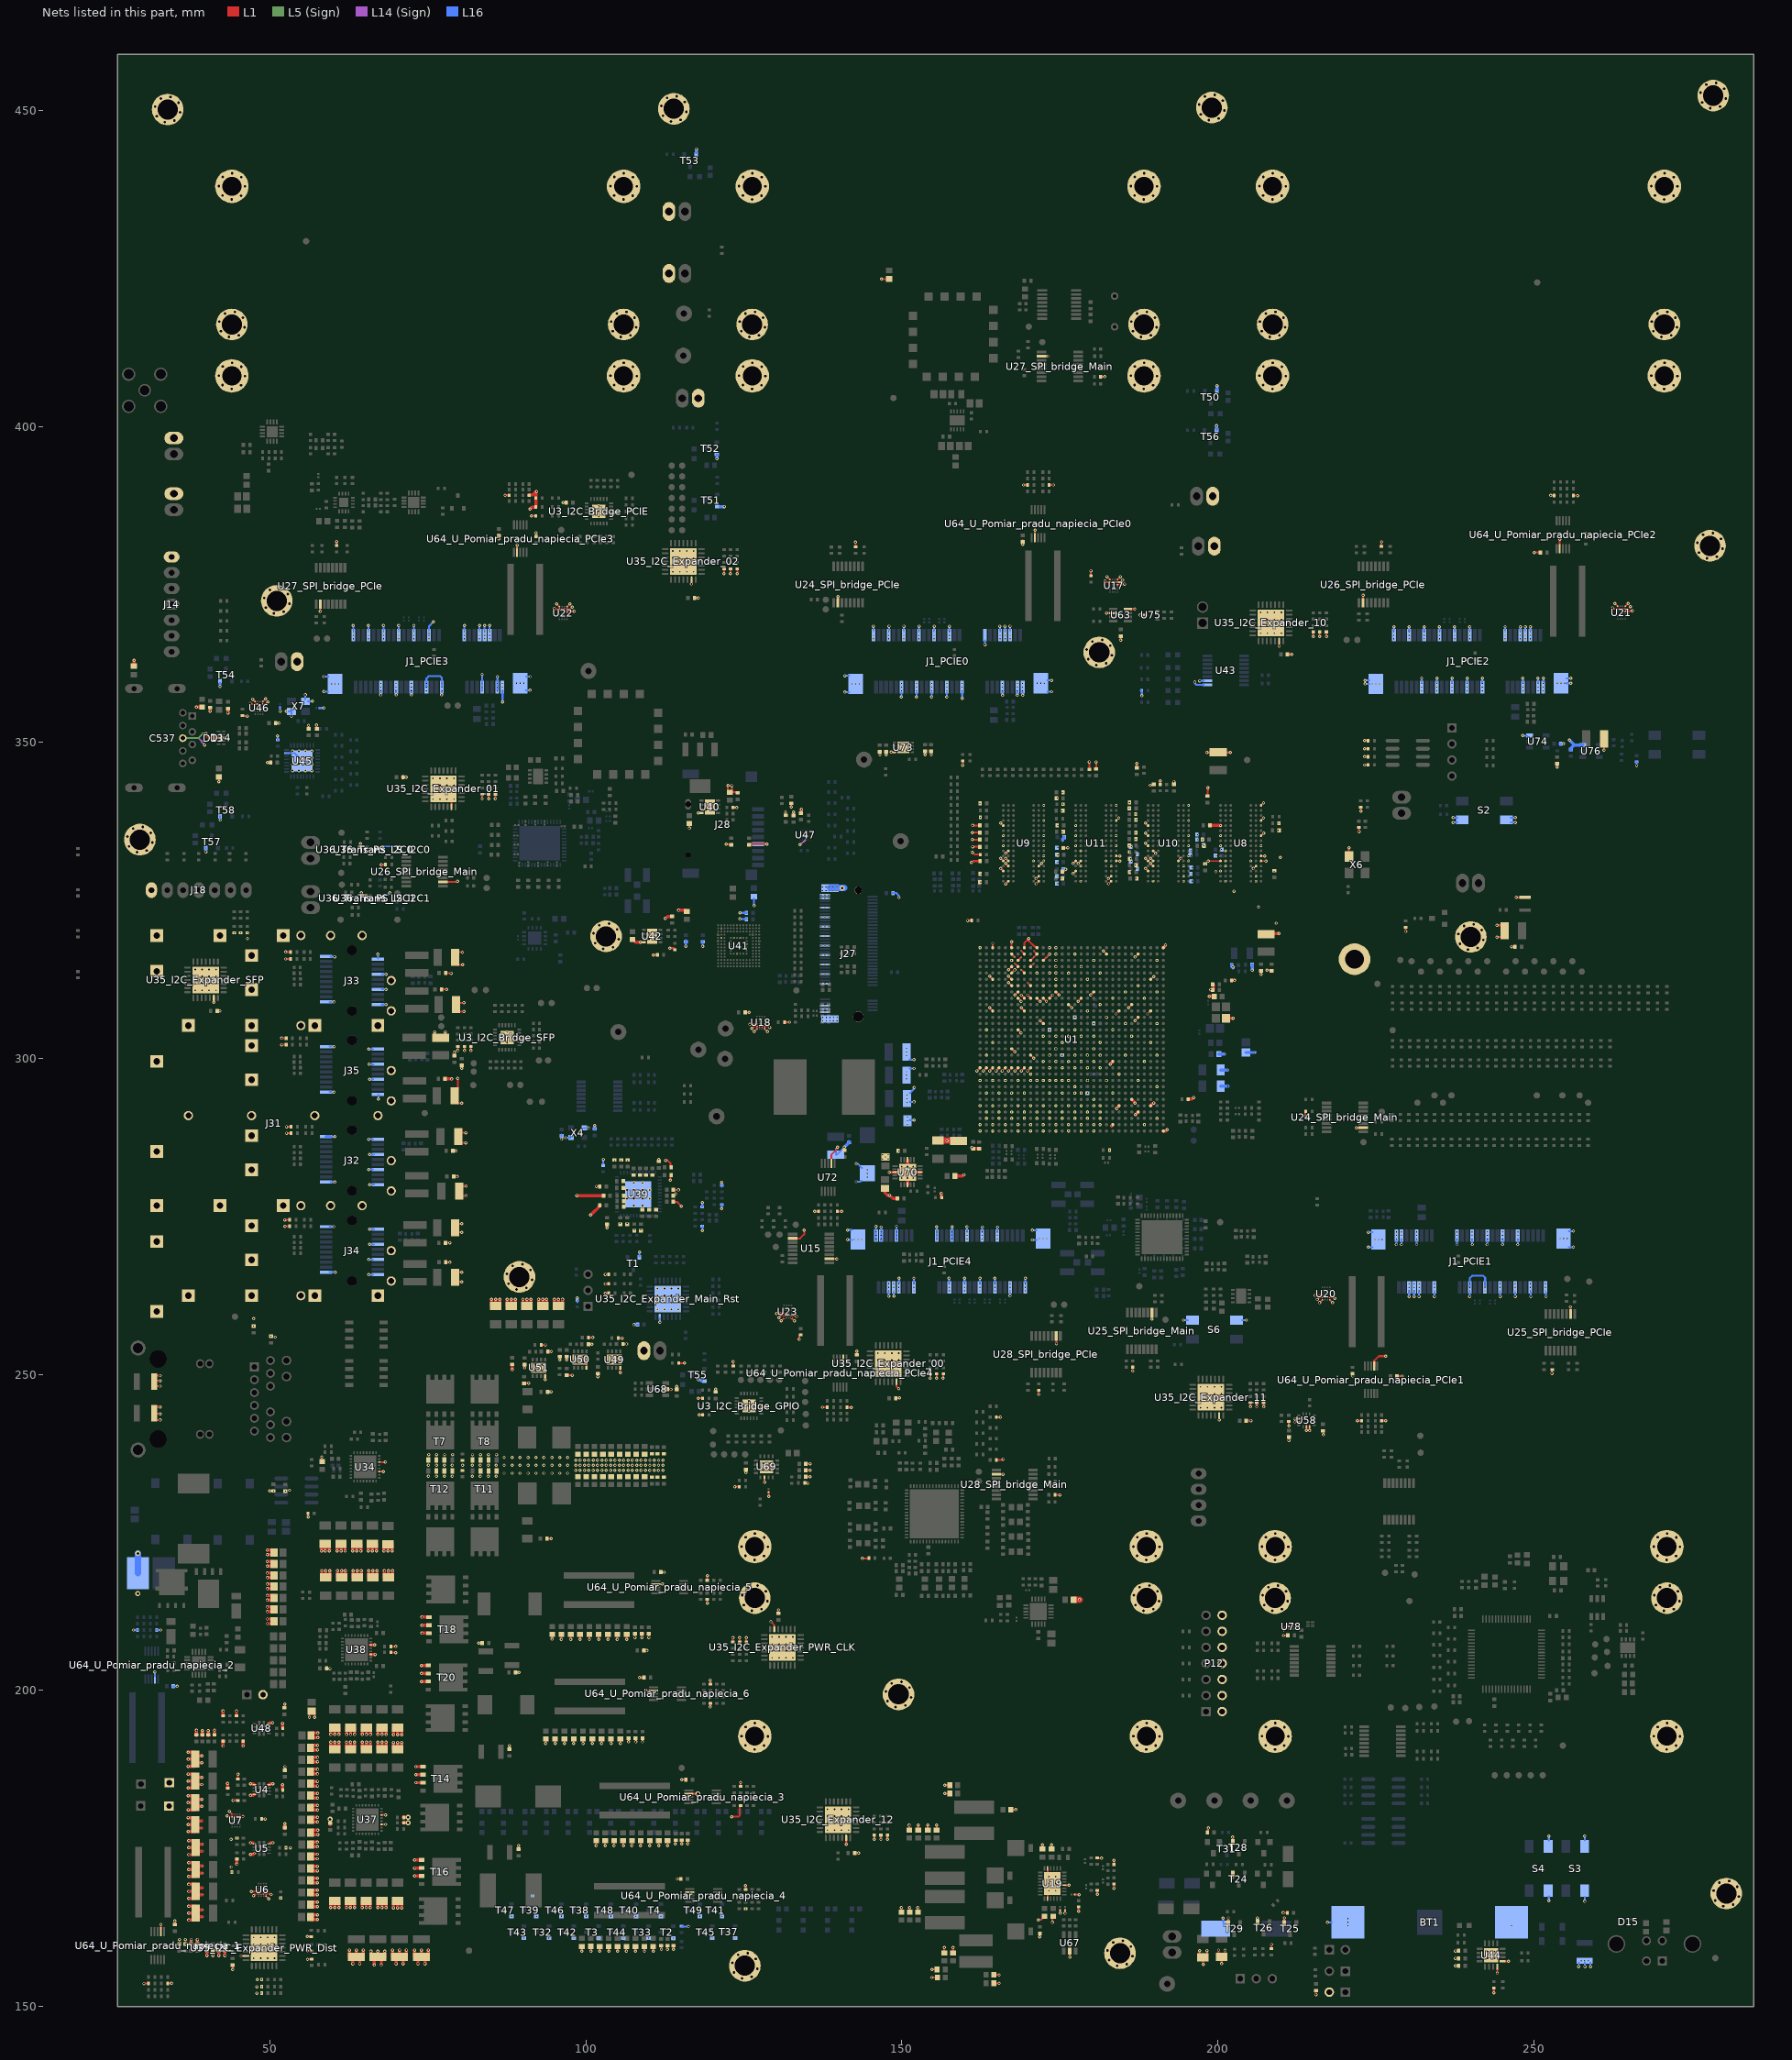
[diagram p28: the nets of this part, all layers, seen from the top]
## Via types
v1: diameter 0.5, hole 0.25, L1 to L16, tented both sides, 4341 vias
v2: diameter 0.254, hole 0.1, L1 to L3 (Sign), tented both sides, 781 vias
v3: diameter 0.5, hole 0.25, L1 to L16, 565 vias
v4: diameter 0.254, hole 0.1, L15 (GND) to L16, tented both sides, 406 vias
v5: diameter 0.254, hole 0.1, L1 to L2 (GND), tented both sides, 283 vias
v6: diameter 0.457, hole 0.2, L3 (Sign) to L6 (PWR/GND), tented both sides, 254 vias
v7: diameter 0.254, hole 0.1, L1 to L3 (Sign), 237 vias
v8: diameter 0.75, hole 0.4, L1 to L16, 200 vias
v9: diameter 0.8, hole 0.4, L1 to L16, tented both sides, 182 vias
v10: diameter 0.254, hole 0.1, L14 (Sign) to L16, tented both sides, 170 vias
v11: diameter 0.75/0/0/0/0/0/0/0/0/0/0/0/0/0/0/0.75 (per signal layer), hole 0.4, L1 to L16, 160 vias
v12: diameter 0.457, hole 0.2, L3 (Sign) to L6 (PWR/GND), 158 vias
v13: diameter 1.4, hole 0.5, L1 to L16, tented both sides, 80 vias
v14: diameter 0.254, hole 0.1, L14 (Sign) to L16, 65 vias
v15: diameter 0.254, hole 0.1, L1 to L2 (GND), 45 vias
v16: diameter 0.457, hole 0.2, L11 (PWR/GND) to L14 (Sign), tented both sides, 26 vias
v17: diameter 0.457, hole 0.2, L11 (PWR/GND) to L14 (Sign), 25 vias
v18: diameter 0.457, hole 0.2, L7(12V+Other) to L10 (3V3+Other), tented both sides, 11 vias
v19: diameter 0.254/0/0.254 (per signal layer), hole 0.1, L1 to L3 (Sign), 9 vias
v20: diameter 0.2/0/0.2 (per signal layer), hole 0.1, L1 to L3 (Sign), 6 vias
v21: diameter 1.65, hole 1.65, L1 to L16, 5 vias
v22: diameter 1.15, hole 1.15, L1 to L16, 5 vias
v23: diameter 0.457, hole 0.2, L1 to L16, 3 vias
v24: diameter 0.5, hole 0.3, L1 to L16, 2 vias
v25: diameter 0.5/0/0.5 (per signal layer), hole 0.2, L14 (Sign) to L16, 1 vias
v26: diameter 0.5, hole 0.25, L1 to L16, tented bottom, 1 vias

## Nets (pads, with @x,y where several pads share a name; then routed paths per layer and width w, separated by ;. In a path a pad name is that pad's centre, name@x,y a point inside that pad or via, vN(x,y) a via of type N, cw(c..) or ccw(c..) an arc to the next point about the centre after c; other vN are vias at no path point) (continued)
B503_Ground: B1.2 BT1.1 C1.1 C2.1 C3.1 C4.2 C5.2 C6.2 C7.2 C8.1 C9.1 C10.1 C11.1 C12.2 C13.2 C14.2 C15.2 C16.1 C17.1 C18.1 C19.1 C20.1 C21.1 C22.1 C23.1 C24.1 C25.1 C26.1 C27.1 C28.1 C29.1 C30.1 C31.1 C32.1 C33.1 C34.1 C35.1 C37.1 C38.2 C39.1 C40.2 C207.1 C208.2 C209.1 C210.2 C211.1 C212.2 C213.1 C214.2 C215.1 C216.2 C217.1 C218.2 C219.2 C220.2 C221.2 C222.2 C223.1 C224.1 C225.1 C226.1 C227.1 C228.1 C229.1 C230.1 C231.1 C232.1 C233.1 C234.1 C235.1 C236.1 C237.1 C238.1 C239.1 C240.1 C241.1 C242.1 C243.2 C244.2 C245.2 C246.2 C247.1 C248.1 C249.1 C250.1 C251.1 C252.1 C253.1 C254.1 C255.1 C256.1 C257.1 C258.1 C259.1 C260.1 C261.1 C262.1 C263.1 C264.1 C265.1 C266.1 C303_I2C_Bridge_GPIO.1 C303_I2C_Bridge_PCIE.1 C303_I2C_Bridge_SFP.1 C304.2 C305.2 C306.2 C307.2 C308.1 C309_U_Pomiar_pradu_napiecia_1.1 C309_U_Pomiar_pradu_napiecia_2.1 C309_U_Pomiar_pradu_napiecia_3.1 C309_U_Pomiar_pradu_napiecia_4.1 C309_U_Pomiar_pradu_napiecia_5.1 C309_U_Pomiar_pradu_napiecia_6.1 C309_U_Pomiar_pradu_napiecia_PCIe0.1 C309_U_Pomiar_pradu_napiecia_PCIe1.1 C309_U_Pomiar_pradu_napiecia_PCIe2.1 C309_U_Pomiar_pradu_napiecia_PCIe3.1 C309_U_Pomiar_pradu_napiecia_PCIe4.1 C310.1 C311_I2C_Expander_00.1 C311_I2C_Expander_01.1 C311_I2C_Expander_02.1 C311_I2C_Expander_10.1 C311_I2C_Expander_11.1 C311_I2C_Expander_12.1 C311_I2C_Expander_Main_Rst.1 C311_I2C_Expander_PWR_CLK.1 C311_I2C_Expander_PWR_Dist.1 C311_I2C_Expander_SFP.1 C312.1 C313.1 C314.2 C331.2 C332.2 C347.1 C348.1 C352.1 C353.1 C354.1 C355.1 C358.1 C359.1 C360.1 C361.2 C362.1 C363.1 C364.1 C365.1 C366.1 C367.1 C368.1 C369.1 C370.1 C371.1 C372.1 C373.1 C374.1 C375.1 C376.1 C377.1 C378.1 C379.2 C380.1 C381.1 C382.1 C383.1 C384.1 C385.1 C386.1 C387.1 C388.1 C391.2 C392.1 C396.1 C397.2 C399.2 C400.1 C401.1 C402.1 C403.1 C404.1 C405.1 C406.1 C407.1 C408.2 C409.1 C410.1 C411.1 C412.1 C413.1 C414.1 C415.1 C416.1 C417.1 C418.1 C419.1 C420.2 C421.1 C422.1 C423.1 C424.1 C425.1 C426.1 C427.1 C428.1 C429.1 C432.2 C433.1 C437.1 C438.2 C440.2 C441.1 C442.1 C443.1 C444.1 C445.1 C446.1 C447.1 C448.1 C449.2 C450.1 C451.1 C452.1 C453.1 C454.1 C455.1 C456.1 C457.1 C458.1 C459.1 C460.1 C461.2 C462.1 C463.1 C464.1 C465.1 C466.1 C467.1 C468.1 C469.1 C470.1 C471.1 C472.1 C473.1 C474.1 C475.1 C476.1 C480.1 C481.1 C485.2 C486.2 C487.1 C488.1 C489.1 C490.1 C491.2 C492.2 C493.2 C494.1 C495.1 C496.1 C497.1 C498.1 C499.2 C500.2 C501.1 C502.1 C503.1 C504.1 C505.2 C506.2 C507.2 C508.2 C509.1 C510.1 C511.1 C512.1 C513.1 C514.1 C515.1 C516.1 C517.1 C518.1 C519.1 C520.1 C521.1 C522.2 C523.1 C524.1 C531.1 C532.1 C533.1 C534.1 C535.1 C536.1 C537.7 C538.2 C539.1 C544.1 C545.1 C546.1 C547.1 C550.1 C551.1 C552.1 C553.1 C554.1 C555.1 C561.1 C562.1 C585.1 C586.1 C587.1 C606.1 C607.1 C609.1 C610.1 C611.1 C613.1 C614.1 C615.1 C617.1 C618.1 C619.1 C620.1 C621.1 C622.1 C623.1 C624.1 C625.1 C626.1 C631.1 C632.1 C633.1 C636.1 C637.1 C638.1 C645.1 C646.1 C654.1 C655.2 C656.2 C657.2 C672.1 C674.1 C675.1 C676.1 C678.1 C679.1 C680.2 C705.1 C707.1 C708.1 C709.1 C711.1 C712.1 C719.1 C720.1 C721.1 C722.1 C723.1 C731.1 C732.2 C733.2 C734.2 C735.2 C736.1 C737.1 C738.2 C739.2 C740.1 C741.1 C742.2 C743.1 C744.1 C745.1 C746.1 C747.2 C748.1 C749.1 C750.1 C751.2 C752.1 C753.2 C754.1 C755.1 C756.1 C757.2 C758.1 C759.1 C760.2 C761.1 C762.2 C763.1 C764.2 C765.1 C766.2 C767.2 C768.2 C769.2 C770.1 C771.1 C772.1 C773.1 C774.1 C775.1 C776.1 C777.1 C778.1 C779.1 C780.1 C781.1 C782.1 C783.1 C784.1 C785.1 C786.1 C787.1 C788.1 C789.1 C790.2 C792.1 D13.3 D14.3 D14.8 D15.3 FB27.1 FB28.1 FB29.2 FB35.1 FB36.1 FB39.1 FB41.1 J1_PCIE0.1 J1_PCIE0.3 J1_PCIE0.6 J1_PCIE0.8 J1_PCIE0.9 J1_PCIE0.10 J1_PCIE0.16 J1_PCIE0.17 J1_PCIE0.22 J1_PCIE0.23 J1_PCIE0.28 J1_PCIE0.29 J1_PCIE0.34 J1_PCIE0.35 J1_PCIE0.40 J1_PCIE0.41 J1_PCIE0.46 J1_PCIE0.52 J1_PCIE0.M J1_PCIE1.1 J1_PCIE1.3 J1_PCIE1.6 J1_PCIE1.8 J1_PCIE1.9 J1_PCIE1.10 J1_PCIE1.16 J1_PCIE1.17 J1_PCIE1.22 J1_PCIE1.23 J1_PCIE1.28 J1_PCIE1.29 J1_PCIE1.34 J1_PCIE1.35 J1_PCIE1.40 J1_PCIE1.41 J1_PCIE1.46 J1_PCIE1.52 J1_PCIE1.M J1_PCIE2.1 J1_PCIE2.3 J1_PCIE2.6 J1_PCIE2.8 J1_PCIE2.9 J1_PCIE2.10 J1_PCIE2.16 J1_PCIE2.17 J1_PCIE2.22 J1_PCIE2.23 J1_PCIE2.28 J1_PCIE2.29 J1_PCIE2.34 J1_PCIE2.35 J1_PCIE2.40 J1_PCIE2.41 J1_PCIE2.46 J1_PCIE2.52 J1_PCIE2.M J1_PCIE3.1 J1_PCIE3.3 J1_PCIE3.6 J1_PCIE3.8 J1_PCIE3.9 J1_PCIE3.10 J1_PCIE3.16 J1_PCIE3.17 J1_PCIE3.22 J1_PCIE3.23 J1_PCIE3.28 J1_PCIE3.29 J1_PCIE3.34 J1_PCIE3.35 J1_PCIE3.40 J1_PCIE3.41 J1_PCIE3.46 J1_PCIE3.52 J1_PCIE3.M J1_PCIE4.1 J1_PCIE4.3 J1_PCIE4.6 J1_PCIE4.8 J1_PCIE4.9 J1_PCIE4.10 J1_PCIE4.16 J1_PCIE4.17 J1_PCIE4.22 J1_PCIE4.23 J1_PCIE4.28 J1_PCIE4.29 J1_PCIE4.34 J1_PCIE4.35 J1_PCIE4.40 J1_PCIE4.41 J1_PCIE4.46 J1_PCIE4.52 J1_PCIE4.M J14.1 J15.1 J16.1 J17.1 J18.1 J19.1 J20.1 J21.1 J22.1 J23.1 J24.1 J27.1 J27.3 J27.9 J27.15 J27.21 J27.27 J27.33 J27.39 J27.45 J27.51 J27.57 J27.63 J27.65 J27.67 J27.M J28.6 J31.SH1 J31.SH2 J31.SH3 J31.SH4 J31.SH5 J31.SH6 J31.SH7 J31.SH8 J31.SH9 J31.SH10 J31.SH11 J31.SH12 J31.SH13 J31.SH14 J31.SH15 J31.SH16 J31.SH17 J31.SH18 J31.SH19 J31.SH20 J31.SH21 J31.SH22 J31.SH23 J31.SH24 J31.SH25 J31.SH26 J31.SH27 J31.SH28 J31.SH29 J31.SH30 J31.SH31 J31.SH32 J31.SH33 J31.SH34 J31.SH35 J31.SH36 J31.SH37 J31.SH38 J31.SH39 J31.SH40 J31.SH41 J31.SH42 J31.SH43 J31.SH44 J31.SH45 J31.SH46 J32.1 J32.10 J32.11 J32.14 J32.17 J32.20 J33.1 J33.10 J33.11 J33.14 J33.17 J33.20 J34.1 J34.10 J34.11 J34.14 J34.17 J34.20 J35.1 J35.10 J35.11 J35.14 J35.17 J35.20 MH1.1 MH2.1 MH3.1 MH4.1 MH5.1 MH6.1 MH7.1 MH8.1 MH9.1 MH10.1 MH11.1 MH12.1 MH13.1 MH14.1 MH15.1 MH16.1 MH17.1 MH18.1 MH19.1 MH20.1 MH21.1 MH22.1 MH23.1 MH24.1 MH25.1 MP1_PCIE0.1 MP1_PCIE1.1 MP1_PCIE2.1 MP1_PCIE3.1 MP1_PCIE4.1 MP2_PCIE0.1 MP2_PCIE1.1 MP2_PCIE2.1 MP2_PCIE3.1 MP2_PCIE4.1 MP3_PCIE0.1 MP3_PCIE1.1 MP3_PCIE2.1 MP3_PCIE3.1 MP3_PCIE4.1 MP4_PCIE0.1 MP4_PCIE1.1 MP4_PCIE2.1 MP4_PCIE3.1 MP4_PCIE4.1 MP5.1 P5.2 P7.1 P9.1 P11.2 P12.2 P12.4 P12.6 P12.8 P12.10 P12.12 P12.14 R1.1 R2.1 R14.2 R18.1 R19.1 R21.1 R23.1 R25.1 R26.1 R27.1 R28.2 R56.2 R60.2 R61.2 R62.2 R63.2 R64.2 R73.2 R74.2 R109.1 R114.1 R139.1 R143.2 R144.2 R153.2 R154.2 R163.2 R164.2 R167.2 R168.2 R170.2 R172.2 R173.2 R174.2 R178.2 R182.1 R183.2 R187.2 R191.1 R192.2 R196.2 R200.1 R201.2 R205.2 R209.1 R210.2 R214.1 R217.2 R218.1 R228.1 R229.2 R242.2 R244.2 R267.1 R269.1 R274.1 R275.1 R279.2 R280.1 R282.2 R284.1 R292.1 R299.1 R304.2 R317.1 R325.1 R326.1 R327.1 R328.1 R334.2 R341.1 R344.1 R345.2 R358.2 R359.2 R360.2 R361.2 R373.1 R379.1 R380.1 R393.1 R396.1 R399.1 R400.2 R450.2 R452.2 R454.2 R456.2 R460.2 R461.2 R464.2 R467.2 R470.2 R472.2 R474.2 R476.2 R478.2 R480.2 R493.2 R495.2 R497.2 R501.2 R503.2 R505.2 R509.2 R511.2 R513.2 R517.2 R519.2 R521.2 R525.2 R527.2 R529.2 R561.2 R565.2 R569.2 R573.2 R577.2 R581.2 R585.2 R589.2 R595.2 R601.1 R602_SPI_bridge_Main.2 R602_SPI_bridge_PCIe.2 R606_SPI_bridge_Main.2 R606_SPI_bridge_PCIe.2 R629.1 R645.1 R652.1 R668.2 R672.1 R674.1 R675.1 R681.1 R682.1 R683.1 R684.1 R685.1 R690.1 R693.2 R696.2 R698.2 R700.2 R702.2 R714.1 R720.2 R739.1 R741.1 R743.1 R759.2 R761.2 R763.2 R764.1 R837.2 R839.2 R840.2 R890_SPI_bridge_Main.2 R890_SPI_bridge_PCIe.2 R894_SPI_bridge_Main.2 R894_SPI_bridge_PCIe.2 R898_SPI_bridge_Main.2 R898_SPI_bridge_PCIe.2 R920.2 R1003.1 R1052.2 R1053.2 R1059.2 R1089.2 S2.3 S2.4 S3.3 S3.4 S4.3 S4.4 S6.1 S6.2 T1.2 T2.2 T3.2 T4.2 T7.1 T7.2 T7.3 T8.1 T8.2 T8.3 T11.1 T11.2 T11.3 T12.1 T12.2 T12.3 T14.1 T14.2 T14.3 T16.1 T16.2 T16.3 T18.1 T18.2 T18.3 T20.1 T20.2 T20.3 T24.2 T25.2 T26.2 T28.2 T29.2 T31.2 T32.2 T33.2 T37.2 T38.2 T39.2 T40.2 T41.2 T42.2 T43.2 T44.2 T45.2 T46.2 T47.2 T48.2 T49.2 T50.2 T51.2 T52.2 T53.2 T54.2 T55.2 T56.2 T57.2 T58.2 U1.A1 U1.A2 U1.A5 U1.A9 U1.A11 U1.A30 U1.AA9 U1.AA19 U1.AA29 U1.AB2 U1.AB7 U1.AB12 U1.AB17 U1.AB22 U1.AC5 U1.AC10 U1.AC20 U1.AD13 U1.AD18 U1.AD23 U1.AE6 U1.AE16 U1.AE21 U1.AF4 U1.AF9 U1.AF19 U1.AF24 U1.AF29 U1.AG2 U1.AG12 U1.AG22 U1.AH5 U1.AH15 U1.AH20 U1.AH25 U1.AJ3 U1.AJ8 U1.AJ13 U1.AJ18 U1.AJ23 U1.AJ28 U1.AK1 U1.AK30 U1.B3 U1.B4 U1.B7 U1.B11 U1.B13 U1.B17 U1.C1 U1.C2 U1.C5 U1.C9 U1.C11 U1.C15 U1.C20 U1.C25 U1.C30 U1.D3 U1.D4 U1.D7 U1.D11 U1.E1 U1.E2 U1.E5 U1.E9 U1.E11 U1.F3 U1.F4 U1.F7 U1.F11 U1.F14 U1.F24 U1.F25 U1.F26 U1.F27 U1.F28 U1.F29 U1.F30 U1.G1 U1.G2 U1.G5 U1.G9 U1.G11 U1.G17 U1.G22 U1.G23 U1.G24 U1.G27 U1.G28 U1.H3 U1.H4 U1.H7 U1.H11 U1.H20 U1.H22 U1.H26 U1.H29 U1.H30 U1.J1 U1.J2 U1.J5 U1.J9 U1.J10 U1.J11 U1.J13 U1.J22 U1.J24 U1.J27 U1.J28 U1.K3 U1.K4 U1.K9 U1.K22 U1.K26 U1.K29 U1.K30 U1.L1 U1.L2 U1.L5 U1.L9 U1.L12 U1.L16 U1.L18 U1.L22 U1.L24 U1.L28 U1.M3 U1.M4 U1.M7 U1.M9 U1.M11 U1.M13 U1.M15 U1.M17 U1.M22 U1.M26 U1.M29 U1.M30 U1.N1 U1.N2 U1.N5 U1.N9 U1.N12 U1.N14 U1.N16 U1.N23 U1.N24 U1.N25 U1.N26 U1.N27 U1.N28 U1.N29 U1.N30 U1.P3 U1.P4 U1.P7 U1.P9 U1.P11 U1.P13 U1.P15 U1.P17 U1.R1 U1.R2 U1.R5 U1.R9 U1.R12 U1.R16 U1.R21 U1.R26 U1.T3 U1.T4 U1.T7 U1.T8 U1.T11 U1.T13 U1.T17 U1.T19 U1.T24 U1.T29 U1.U1 U1.U2 U1.U5 U1.U7 U1.U12 U1.U16 U1.U22 U1.U27 U1.V3 U1.V4 U1.V7 U1.V9 U1.V11 U1.V13 U1.V20 U1.V25 U1.W1 U1.W2 U1.W5 U1.W6 U1.W12 U1.W14 U1.W16 U1.W18 U1.W23 U1.W28 U1.Y2 U1.Y3 U1.Y4 U1.Y5 U1.Y11 U1.Y13 U1.Y15 U1.Y21 U1.Y26 U3_I2C_Bridge_GPIO.9 U3_I2C_Bridge_GPIO.25 U3_I2C_Bridge_PCIE.9 U3_I2C_Bridge_PCIE.25 U3_I2C_Bridge_SFP.9 U3_I2C_Bridge_SFP.25 U4.3 U4.6 U4.12 U5.3 U5.6 U5.12 U6.A1 U6.B1 U6.B2 U6.B3 U6.B4 U6.C4 U7.A1 U7.B1 U7.B2 U7.B3 U7.B4 U7.C4 U8.A2 U8.A5 U8.B2 U8.C6 U8.D2 U8.D5 U8.E1 U8.E3 U8.E5 U8.E6 U8.F1 U8.G5 U8.H1 U8.H6 U8.K1 U8.K6 U8.M6 U8.N1 U8.T1 U9.A2 U9.A5 U9.B2 U9.C6 U9.D2 U9.D5 U9.E1 U9.E3 U9.E5 U9.E6 U9.F1 U9.G5 U9.H1 U9.H6 U9.K1 U9.K6 U9.M6 U9.N1 U9.T1 U10.A2 U10.A5 U10.B2 U10.C6 U10.D2 U10.D5 U10.E1 U10.E3 U10.E5 U10.E6 U10.F1 U10.G5 U10.H1 U10.H6 U10.K1 U10.K6 U10.M6 U10.N1 U10.T1 U11.A2 U11.A5 U11.B2 U11.C6 U11.D2 U11.D5 U11.E1 U11.E3 U11.E5 U11.E6 U11.F1 U11.G5 U11.H1 U11.H6 U11.K1 U11.K6 U11.M6 U11.N1 U11.T1 U15.2 U15.10 U17.A1 U17.A4 U17.B1 U17.B2 U17.B3 U17.B4 U17.C4 U18.A1 U18.A4 U18.B1 U18.B2 U18.B3 U18.B4 U18.C4 U19.10 U19.18 U19.27 U19.29 U20.A1 U20.A4 U20.B1 U20.B2 U20.B3 U20.B4 U20.C4 U21.A1 U21.A4 U21.B1 U21.B2 U21.B3 U21.B4 U21.C4 U22.A1 U22.A4 U22.B1 U22.B2 U22.B3 U22.B4 U22.C4 U23.A1 U23.A4 U23.B1 U23.B2 U23.B3 U23.B4 U23.C4 U24_SPI_bridge_Main.10 U24_SPI_bridge_PCIe.10 U25_SPI_bridge_Main.10 U25_SPI_bridge_PCIe.10 U26_SPI_bridge_Main.10 U26_SPI_bridge_PCIe.10 U27_SPI_bridge_Main.10 U27_SPI_bridge_PCIe.10 U28_SPI_bridge_Main.10 U28_SPI_bridge_PCIe.10 U34.19 U34.22 U35_I2C_Expander_00.6 U35_I2C_Expander_00.29 U35_I2C_Expander_01.6 U35_I2C_Expander_01.29 U35_I2C_Expander_02.6 U35_I2C_Expander_02.29 U35_I2C_Expander_10.6 U35_I2C_Expander_10.29 U35_I2C_Expander_11.6 U35_I2C_Expander_11.29 U35_I2C_Expander_12.6 U35_I2C_Expander_12.29 U35_I2C_Expander_Main_Rst.6 U35_I2C_Expander_Main_Rst.29 U35_I2C_Expander_PWR_CLK.6 U35_I2C_Expander_PWR_CLK.29 U35_I2C_Expander_PWR_Dist.6 U35_I2C_Expander_PWR_Dist.29 U35_I2C_Expander_SFP.6 U35_I2C_Expander_SFP.29 U36_Trans_LS_I2C0.1 U36_Trans_LS_I2C1.1 U36_Trans_PS_I2C0.1 U36_Trans_PS_I2C1.1 U37.19 U37.22 U38.19 U38.22 U39.49 U40.4 U40.9 U41.A6 U41.C4 U41.E7 U41.G5 U41.H10 U41.J5 U41.K8 U41.N2 U41.N5 U41.P4 U41.P6 U42.4 U42.9 U43.9 U43.10 U44.4 U44.5 U44.17 U45.23 U45.33 U46.A1 U46.A4 U46.B1 U46.B2 U46.B4 U47.C3 U48.12 U49.4 U49.9 U50.4 U50.9 U51.4 U51.9 U58.2 U58.3 U58.6 U58.7 U63.2 U63.8 U64_U_Pomiar_pradu_napiecia_1.7 U64_U_Pomiar_pradu_napiecia_2.7 U64_U_Pomiar_pradu_napiecia_3.7 U64_U_Pomiar_pradu_napiecia_4.7 U64_U_Pomiar_pradu_napiecia_5.7 U64_U_Pomiar_pradu_napiecia_6.7 U64_U_Pomiar_pradu_napiecia_PCIe0.7 U64_U_Pomiar_pradu_napiecia_PCIe1.7 U64_U_Pomiar_pradu_napiecia_PCIe2.7 U64_U_Pomiar_pradu_napiecia_PCIe3.7 U64_U_Pomiar_pradu_napiecia_PCIe4.7 U67.2 U68.2 U69.6 U69.17 U70.3 U70.8 U70.13 U70.18 U70.21 U72.7 U73.4 U73.9 U74.3 U75.3 U76.3 U78.2 X4.2 X4.4 X6.2 X7.2 X7.4 | length 927.2
  L1 w0.2: v1(64.325,334.01) 64.383,333.952 64.383,333.749 64.562,333.57 U36_Trans_PS_I2C0.1@64.727,333.57 ; v1(64.477,326.211) 64.802,325.886 U36_Trans_PS_I2C1.1@65.197,325.886 ; v1(129.292,210.882) 129.828,210.345 U35_I2C_Expander_PWR_CLK.6@129.828,209.703 ; U9.H6@166.076,333.66 v5(166.076,333.667) ; U9.E3@170.876,331.26 v5(170.876,331.268) ; U11.H6@177.536,333.66 v5(177.536,333.664) ; v5(183.134,330.46) U11.D2@183.136,330.46 ; v5(183.394,309.542) U1.AB22@183.397,309.539 ; v5(183.934,333.663) U11.H1@183.936,333.66 ; U10.A5@189.797,328.06 v5(189.797,328.063) ; v5(200.449,333.66) U8.H6@200.457,333.66 ; v5(205.251,331.26) U8.E3@205.257,331.26 ; v1(205.652,330.063) 205.66,330.063 U8.D2@206.057,330.46 ; U8.F1@206.857,332.06 v1(207.44,332.06) ; U8.K1@206.857,335.26 207.278,335.681 v1(207.278,335.683) ; U8.N1@206.857,337.66 v1(207.261,338.064) ; U8.T1@206.857,340.06 v1(207.261,340.464) ; U8.E1@206.863,331.254 206.87,331.247 v1(207.638,331.247) ; v1(210.453,209.639) 210.511,209.696 210.511,209.914 210.72,210.124 U78.2@211.267,210.124
  L1 w0.25: v1@165.672,330.064 U9.C6@166.076,329.66 ; v1(171.272,327.657) U9.A2@171.676,328.06 ; v1(171.272,328.457) U9.B2@171.676,328.86 ; U9.D2@171.676,330.46 v1(172.106,330.89) ; v1(177.133,329.257) U11.C6@177.536,329.66 ; v1(177.133,330.857) U11.E6@177.536,331.26 ; v1(177.933,330.857) U11.E5@178.336,331.26 ; R60.2@179.692,345.699 v1(179.692,346.944) ; v1(181.909,317.027) U1.AA29@182.397,316.539 ; v1(182.728,328.46) 182.736,328.46 U11.B2@183.136,328.86 ; v1(182.733,327.657) U11.A2@183.136,328.06 ; v1(183.909,307.052) U1.AC20@184.397,307.539 ; U11.E1@183.936,331.26 v1(184.507,331.26) ; U11.F1@183.936,332.06 v1(184.507,332.06) ; U11.N1@183.936,337.66 v1(184.34,338.064) ; v1(185.909,308.051) U1.AE21@186.397,308.539 ; v1(186.909,306.017) 186.909,306.035 187.397,306.522 U1.AF19@187.397,306.539 ; v1(186.923,316.065) U1.AF29@187.397,316.539 ; v1(188.593,330.064) U10.C6@188.997,329.66 ; v1(188.593,331.664) U10.E6@188.997,331.26 ; v1(188.593,334.064) U10.H6@188.997,333.66 ; v1(188.593,335.664) U10.K6@188.997,335.26 ; v1(188.593,337.264) U10.M6@188.997,336.86 ; v1(188.909,307.052) U1.AH20@189.397,307.539 ; v1(189.393,330.864) U10.D5@189.797,330.46 ; v1(189.393,331.664) U10.E5@189.797,331.26 ; U1.AH25@189.397,312.539 189.427,312.539 189.854,312.967 v1(189.884,312.967) ; U10.G5@189.797,332.86 v1(190.2,332.457)
  L1 w0.254: U64_U_Pomiar_pradu_napiecia_3.7@116.278,183.659 v9(117.754,183.659) ; v5(188.394,309.539) U1.AG22@188.397,309.539 ; v1@198.406,331.26 v1(198.495,331.26) U8.E6@200.457,331.26
  L1 w0.3: v1(30.061,153.632) R461.2@30.75,153.632 ; C475.1@31.917,242.796 v1(32.606,242.796) ; C475.1@31.917,243.78 v1(32.606,243.78) ; C475.1@31.917,244.875 v1(32.606,244.875) ; C476.1@31.917,248.156 v1(32.606,248.156) ; C476.1@31.917,249.01 v1(32.606,249.01) ; C476.1@31.917,249.825 v1(32.606,249.825) ; U64_U_Pomiar_pradu_napiecia_1.7@32.745,162.264 v1(32.745,162.953) ; R229.2@33.783,153.665 v1(34.472,153.665) ; C309_U_Pomiar_pradu_napiecia_1.1@34.961,162.832 C309_U_Pomiar_pradu_napiecia_1.1@34.961,162.979 v1(34.961,163.521) ; C537.7@36.22,350.698 C537.7@36.252,350.73 ; v3(39.871,351.411) 40.036,351.246 40.036,350.937 40.212,350.761 D14.8@41.874,350.761 D14.3@42.708,350.761 ; v1(41.127,308.889) U35_I2C_Expander_SFP.6@41.127,309.578 ; C311_I2C_Expander_SFP.1@41.652,307.547 v1(42.104,307.547) ; v1(41.934,343.787) FB27.1@41.934,344.476 ; v1(43.247,180.173) 43.387,180.034 U7.B1@44.028,180.034 v15(44.428,180.034) U7.B3@44.828,180.034 U7.B4@45.228,180.034 45.698,180.034 v1(45.728,180.064) ; v1@43.588,180.874 v15(44.028,180.434) ; v1(44.121,155.869) C311_I2C_Expander_PWR_Dist.1@44.121,156.553 C311_I2C_Expander_PWR_Dist.1@44.121,156.558 ; v1(44.197,182.652) R23.1@44.886,182.652 ; R25.1@44.945,186.053 v1(44.945,186.742) ; v1(45.443,158.003) U35_I2C_Expander_PWR_Dist.6@46.133,158.003 ; R380.1@45.746,354.193 v1(46.435,354.193) ; v1(46.894,356.23) 46.948,356.23 47.088,356.09 U46.B1@47.675,356.09 U46.B2@48.075,356.09 ; v1(47.076,168.173) 47.412,168.173 47.495,168.256 v15(48.206,168.256) ; v1@47.235,356.93 v1(47.289,356.877) U46.A1@47.675,356.49 ; v1(47.406,167.526) 47.736,167.856 50.047,167.856 v1(50.187,167.716) ; R1053.2@48.666,179.68 R1053.2@48.716,179.68 v1(49.246,179.68) v1@49.251,179.684 ; U46.B4@48.875,356.09 49.345,356.09 v1(49.675,356.42) ; U46.A4@48.875,356.49 v1(49.315,356.93) ; U6.A1@49.406,167.456 v1(49.846,167.016) v1@49.884,167.054 ; v1(49.604,346.841) C731.1@50.293,346.841 ; C733.2@50.758,353.066 v1(51.448,353.066) ; v1(51.891,302.189) R164.2@52.58,302.189 ; v1(51.891,303.225) R163.2@52.58,303.225 ; C314.2@52.35,197.152 v1(52.35,197.842) ; v1(52.388,273.456) R154.2@53.077,273.456 ; v1(52.387,274.472) R153.2@53.077,274.472 ; C312.1@52.394,187.252 v1(52.394,187.942) ; v1(52.521,315.759) R144.2@53.21,315.759 ; v1(52.521,316.852) R143.2@53.21,316.852 ; v1(52.632,288.188) R74.2@53.321,288.188 ; v1(52.632,289.204) R73.2@53.321,289.204 ; v1(55.904,161.1) R840.2@56.558,161.1 ; v1(55.915,158.85) R839.2@56.604,158.85 ; v1(55.954,157.468) R837.2@56.644,157.468 ; v1(56.052,227.457) R267.1@56.052,228.146 ; C487.1@56.104,352.008 v1(56.104,352.698) ; v1(56.246,195.751) C781.1@56.246,196.44 ; v1(57.096,195.751) C781.1@57.096,196.44 ; C732.2@57.37,352.072 v1(57.37,352.762) ; v1(57.979,370.789) U27_SPI_bridge_PCIe.10@57.979,371.479 ; C358.1@58.206,236.249 v1(58.206,236.939) ; C440.2@58.808,203.464 v1(59.497,203.464) ; R894_SPI_bridge_PCIe.2@60.563,381.136 R894_SPI_bridge_PCIe.2@60.563,381.182 v1(60.563,381.826) ; U34.19@67.26,234.639 U34.19@67.322,234.639 v1(67.949,234.639) ; 67.589,236.139 v1(68.278,236.139) ; v1(67.627,330.67) R890_SPI_bridge_Main.2@68.317,330.67 ; U37.19@67.675,178.817 v1(68.313,178.817) ; U37.22@67.675,180.317 v1(68.303,180.317) ; R317.1@69.241,205.994 v1(69.93,205.994) ; R629.1@69.241,206.964 v1(69.93,206.964) ; C311_I2C_Expander_01.1@70.868,344.538 70.871,344.541 71.554,344.541 v1(71.557,344.538) ; C216.2@76.081,303.521 v1(76.081,304.211) ; C209.1@76.983,310.946 76.986,310.944 v1(77.943,310.944) ; C207.1@77.699,313.503 77.701,313.501 v1(78.674,313.501) ; C216.2@77.753,303.521 v1(77.753,304.211) ; C213.1@77.792,267.751 v1(78.482,267.751) ; C211.1@77.792,270.856 C211.1@77.8,270.856 v1(78.482,270.856) ; U26_SPI_bridge_Main.10@78.074,327.94 79.512,327.94 79.633,328.06 v1(79.687,328.06) ; C37.1@78.754,285.418 v1(79.443,285.418) ; U35_I2C_Expander_01.29@78.756,341.039 78.756,339.807 U35_I2C_Expander_01.6@78.763,339.814 ; C39.1@78.925,281.311 v1(79.615,281.311) ; C215.1@79.181,300.288 v1(79.181,300.978) ; C214.2@79.679,264.658 v1(80.368,264.658) ; C214.2@79.679,266.197 v1(80.368,266.197) ; C212.2@79.679,272.507 v1(80.368,272.507) ; C212.2@79.679,273.856 v1(80.368,273.856) ; C218.2@79.679,295.237 79.743,295.301 v1(79.743,296.875) ; C218.2@79.684,292.935 v1(80.374,292.935) ; v1(79.743,301.265) R474.2@79.743,301.915 R474.2@79.743,301.954 ; C208.2@79.786,316.827 v1(80.476,316.827) ; C208.2@79.802,314.837 v1(80.492,314.837) ; C210.2@80.006,307.442 v1(80.696,307.442) ; C210.2@80.006,308.817 v1(80.696,308.817) ; C38.2@80.337,286.66 v1(81.026,286.66) ; C38.2@80.337,288.26 v1(81.026,288.26) ; v1(80.355,298.446) C303_I2C_Bridge_SFP.1@80.355,299.135 ; C40.2@80.368,278.275 v1(81.057,278.275) ; C40.2@80.368,279.822 v1(81.057,279.822) ; v1(80.807,301.265) R470.2@80.807,301.927 R470.2@80.807,301.954 ; v1(81.807,301.265) R472.2@81.807,301.954 ; v1(83.041,207.488) C646.1@83.73,207.488 ; v1(83.593,341.126) R505.2@83.593,341.816 ; v1(84.625,341.107) R503.2@84.625,341.796 ; v1(85.683,341.107) R501.2@85.683,341.796 ; v1(86.22,382.268) C309_U_Pomiar_pradu_napiecia_PCIe3.1@86.22,382.957 ; v1(87.222,389.129) R201.2@87.911,389.129 ; C637.1@87.909,190.59 v1(87.909,191.279) ; C645.1@88.744,202.857 C645.1@88.879,202.857 v1(89.433,202.857) ; U64_U_Pomiar_pradu_napiecia_PCIe3.7@89.133,380.557 v1(89.133,381.246) ; C638.1@89.332,174.77 v1(89.332,175.459) ; U3_I2C_Bridge_SFP.9@89.461,303.096 U3_I2C_Bridge_SFP.9@89.47,303.096 v1(90.15,303.096) ; C554.1@90.28,248.654 v1(90.969,248.654) ; v1(90.322,251.063) C555.1@90.322,251.753 ; v1(91.397,385.88) R452.2@92.086,385.88 ; R209.1@92.133,382.516 R209.1@92.133,382.599 v1(92.133,383.205) ; R399.1@92.911,254.68 v1(93.601,254.68) ; v1(93.548,249.228) U51.4@93.548,249.918 ; v1(93.663,191.635) C470.1@93.663,192.324 ; C636.1@93.832,224.031 v1(94.521,224.031) ; C633.1@93.832,247.284 C633.1@93.967,247.284 v1(94.521,247.284) ; C657.2@93.856,253.617 C657.2@93.991,253.617 v1(94.546,253.617) ; v1(94.661,208.129) C458.1@94.661,208.818 ; v1(95.047,371.246) 95.187,371.106 97.498,371.106 v1(97.828,371.437) ; v1(95.146,191.631) C469.1@95.146,192.32 ; v1(95.388,371.947) U22.A1@95.828,371.507 ; v1(95.898,252.32) C1.1@95.898,252.832 C1.1@95.898,253.009 ; v1(96.134,208.102) C457.1@96.134,208.791 ; v1(96.406,387.95) C303_I2C_Bridge_PCIE.1@97.096,387.95 ; v1(96.619,191.631) C468.1@96.619,192.32 ; v1(96.964,252.32) C553.1@96.964,253.009 ; C552.1@96.995,249.994 97.104,249.884 v1(97.854,249.884) ; U22.C4@97.028,370.707 97.739,370.706 97.822,370.789 v1(98.159,370.789) ; U22.A4@97.028,371.507 v1(97.468,371.947) ; v1(97.607,208.071) C456.1@97.607,208.76 ; v1(98.082,191.631) C467.1@98.082,192.32 ; v1(99.08,208.071) C455.1@99.08,208.76 ; v1(99.369,158.749) C427.1@99.369,159.439 ; v1(99.566,191.631) C466.1@99.566,192.32 ; U50.9@100.076,251.904 100.14,251.841 U50.4@100.14,250.978 ; C656.2@100.27,254.796 C656.2@100.405,254.796 v1(100.959,254.796) ; R396.1@100.394,255.867 v1(101.084,255.867) ; v1(100.564,208.071) C454.1@100.564,208.76 ; v1(100.796,158.749) C426.1@100.796,159.439 ; v1(101.028,191.631) C465.1@101.028,192.32 ; v1(101.638,175.459) C415.1@101.638,176.149 ; v1(101.653,279.775) C502.1@102.208,279.775 C502.1@102.343,279.775 ; v1(101.922,249.669) C550.1@101.922,250.358 ; v1(102.037,208.071) C453.1@102.037,208.76 ; v1(102.197,158.749) C429.1@102.197,159.439 ; v1(102.512,191.631) C464.1@102.512,192.32 ; v1(103.061,175.459) C414.1@103.061,176.149 ; v1(103.099,262.861) R763.2@103.788,262.861 ; v1(103.099,264.33) R761.2@103.788,264.33 ; v1(103.099,265.849) R759.2@103.788,265.849 ; v1(103.358,273.207) C2.1@103.358,273.896 ; v1(103.51,208.071) C452.1@103.51,208.76 ; v1(103.632,158.749) C428.1@103.632,159.439 ; v1(103.985,191.631) C463.1@103.985,192.32 ; U3_I2C_Bridge_PCIE.9@103.996,386.363 U3_I2C_Bridge_PCIE.9@104.005,386.363 v1(104.685,386.363) ; v1(104.47,175.459) C417.1@104.47,176.149 ; v1(104.983,208.071) C451.1@104.983,208.76 ; v1(105.029,158.749) C425.1@105.029,159.439 ; R393.1@105.061,255.77 v1(105.75,255.77) ; v1(105.454,250.294) U49.4@105.454,250.983 ; v1(105.493,191.631) C462.1@105.493,192.32 ; C655.2@105.762,254.83 C655.2@105.887,254.83 v1(106.452,254.83) ; v1(105.951,175.459) C416.1@105.951,176.149 ; v1(106.426,158.749) C422.1@106.426,159.439 ; v1(106.482,208.071) C450.1@106.482,208.76 ; v1(106.769,191.886) C461.2@106.769,192.575 ; v1(107.302,175.459) C413.1@107.302,176.149 ; v1(107.759,208.398) C449.2@107.759,209.088 ; v1(107.857,158.749) C421.1@107.857,159.439 ; v1(107.902,191.887) C460.1@107.902,192.576 ; v1(108.488,202.052) C309_U_Pomiar_pradu_napiecia_6.1@109.177,202.052 ; v1(108.658,318.401) U42.4@109.193,318.401 U42.4@109.348,318.401 ; v1(108.671,175.459) C410.1@108.671,176.149 ; v1(108.869,208.398) C448.1@108.869,209.088 ; C3.1@108.949,206.318 v1(109.638,206.318) ; v1(108.979,191.887) C459.1@108.979,192.576 ; v1(109.271,158.749) C424.1@109.271,159.439 ; v1(109.47,200.021) U64_U_Pomiar_pradu_napiecia_6.7@110.159,200.021 ; v1(109.987,208.398) C447.1@109.987,209.088 ; v1(110.122,175.459) C409.1@110.122,176.149 ; v1(110.668,158.749) C423.1@110.668,159.439 ; v1(110.694,316.392) R344.1@111.383,316.392 ; U64_U_Pomiar_pradu_napiecia_5.7@111.425,216.848 v1(112.115,216.848) ; C512.1@111.536,283.706 C512.1@111.536,283.732 v1(111.536,284.007) ; v1(111.544,175.459) C412.1@111.544,176.149 ; C309_U_Pomiar_pradu_napiecia_5.1@111.752,218.711 v1(112.441,218.711) ; v1(111.956,159.047) C420.2@111.956,159.736 ; v1(112.662,283.909) 112.951,283.909 113.388,283.472 C507.2@113.388,282.791 ; U68.2@112.793,247.654 v1(113.482,247.654) ; v1(112.903,159.047) C419.1@112.903,159.736 ; v1(112.941,175.459) C411.1@112.941,176.149 ; v1(113.281,317.463) 113.97,317.463 ; v1(113.383,280.775) C514.1@113.383,281.464 ; C511.1@113.72,278.276 113.76,278.276 114.059,278.575 v1(114.198,278.575) ; C509.1@113.723,277.333 C509.1@113.858,277.333 114.416,277.333 v1(115.113,276.636) ; v1(113.877,159.047) C418.1@113.877,159.736 ; C495.1@113.954,279.215 v1(114.643,279.215) ; v1(114.184,175.751) C408.2@114.184,176.44 ; C654.1@114.383,247.444 v1(114.383,248.134) ; v1(114.433,170.186) C309_U_Pomiar_pradu_napiecia_4.1@115.041,170.186 C309_U_Pomiar_pradu_napiecia_4.1@115.122,170.186 ; R1003.1@114.769,251.771 114.802,251.804 v1(115.598,251.804) ; v1(115.176,175.751) C407.1@115.176,176.44 ; v1(115.176,185.901) C309_U_Pomiar_pradu_napiecia_3.1@115.821,185.901 C309_U_Pomiar_pradu_napiecia_3.1@115.866,185.901 ; v1(116.15,175.751) C406.1@116.15,176.44 ; v1(116.385,336.441) C516.1@116.385,337.13 ; v1(116.73,375.093) U35_I2C_Expander_02.6@116.73,375.782 ; C311_I2C_Expander_02.1@117.129,372.875 v1(117.818,372.875) ; v1(117.774,338.844) U40.4@118.309,338.844 U40.4@118.463,338.844 ; v1(117.78,246.246) R242.2@118.469,246.246 ; v1(117.935,243.63) R244.2@118.506,243.63 R244.2@118.624,243.63 ; v1(119.228,213.825) R581.2@119.228,214.409 R581.2@119.228,214.514 ; R577.2@119.228,217.459 v1(119.228,218.148) ; v1(119.698,197.396) R589.2@119.698,198.085 ; R585.2@119.698,200.961 R585.2@119.698,201.021 v1(119.698,201.651) ; C303_I2C_Bridge_GPIO.1@120.561,247.383 v1(120.561,247.675) ; v1(121.873,376.707) R513.2@121.873,377.397 ; v1(122.229,333.915) C586.1@122.918,333.915 ; C523.1@122.499,342.525 v1(122.499,343.214) ; C523.1@122.809,342.141 123.773,342.141 123.883,342.031 123.888,342.031 124.008,341.911 C517.1@124.008,341.906 ; v1(122.889,376.707) R511.2@122.889,377.397 ; v1(123.082,180.03) 124.204,180.03 124.379,180.205 124.379,181.707 R565.2@124.498,181.826 ; C523.1@123.109,342.482 v1(123.109,343.172) ; R341.1@123.21,339.71 v1(123.899,339.71) ; R739.1@123.273,207.66 v1(123.273,208.349) ; R400.2@123.333,251.369 v1(123.333,252.058) ; v1(123.568,232.255) 123.573,232.25 124.318,232.25 R668.2@124.323,232.255 ; v1(123.963,376.707) R509.2@123.963,377.397 ; R741.1@124.34,207.66 v1(124.34,208.349) ; R561.2@124.498,184.777 R561.2@124.498,184.81 v1(124.498,185.466) ; C331.2@125.167,307.303 v1(125.856,307.303) ; R569.2@125.282,168.439 v1(125.282,169.129) ; v1(125.319,234.465) C676.1@125.32,234.952 ; R743.1@125.394,207.66 v1(125.394,208.349) ; C518.1@125.856,333.957 125.869,333.944 128.669,333.944 v1(128.682,333.931) ; v1(125.968,305.399) 126.305,305.399 126.387,305.481 U18.C4@127.098,305.481 ; v1(126.298,304.751) 126.628,305.081 U18.B3@127.498,305.081 U18.B2@127.898,305.081 128.94,305.081 v1(129.08,304.941) ; v1(126.658,304.241) U18.A4@127.098,304.681 ; U3_I2C_Bridge_GPIO.9@127.739,244.789 U3_I2C_Bridge_GPIO.9@127.748,244.789 v1(128.428,244.789) ; v1(128.28,232.977) U69.6@128.28,233.666 ; U18.A1@128.298,304.681 v1(128.739,304.241) ; v1(128.947,230.695) C719.1@128.947,231.385 ; v1(130.225,259.655) 130.561,259.655 130.644,259.738 v15(131.355,259.738) ; C311_I2C_Expander_PWR_CLK.1@130.479,212.074 v1(130.479,212.763) ; v1(130.555,259.008) 130.885,259.338 v15(132.555,259.338) 133.196,259.338 v1(133.336,259.198) ; v1(130.915,258.498) v15(131.355,258.938) ; R269.1@131.398,305.752 R269.1@131.448,305.752 v1(132.207,305.752) ; C545.1@131.61,338.32 v1(131.61,339.009) ; v1(132.502,339.822) C544.1@132.502,340.511 ; v15(132.555,258.938) v1(132.995,258.498) ; C546.1@132.863,338.32 C546.1@132.863,338.455 v1(132.863,339.009) ; U15.2@133.085,271.544 133.904,271.544 134.556,272.197 v1(134.556,272.872) ; v1(133.772,255.582) 133.772,256.066 R228.1@134.028,256.323 ; R645.1@134.466,232.843 v1(135.156,232.843) ; C674.1@134.813,233.837 v1(135.503,233.837) ; C746.1@134.813,234.865 v1(135.503,234.865) ; C675.1@134.813,235.893 C675.1@134.822,235.893 v1(135.503,235.893) ; v1(136.203,275.821) R304.2@136.816,275.821 R304.2@136.892,275.821 ; v1(137.429,244.823) R217.2@138.119,244.823 ; U72.7@138.853,283.403 138.853,284.762 139.852,285.761 v1(139.852,285.987) ; U15.10@139.04,268.301 v1(139.729,268.301) ; R14.2@139.808,275.821 v1(140.497,275.821) ; U24_SPI_bridge_PCIe.10@139.883,372.474 139.922,372.513 v1(139.922,373.087) ; v1(140.729,251.369) U64_U_Pomiar_pradu_napiecia_PCIe4.7@140.729,252.058 ; C310.1@140.907,285.277 C310.1@140.907,285.462 v1(140.907,285.966) ; v1(141.216,175.671) U35_I2C_Expander_12.6@141.216,176.36 ; R210.2@141.309,244.789 v1(141.999,244.789) ; C311_I2C_Expander_12.1@142.457,174.28 C311_I2C_Expander_12.1@142.57,174.28 v1(143.147,174.28) ; R602_SPI_bridge_PCIe.2@142.687,381.018 v1(142.687,381.707) ; C309_U_Pomiar_pradu_napiecia_PCIe4.1@142.887,253.016 v1(142.887,253.705) ; v1(143.764,220.897) 144.775,220.897 R139.1@144.813,220.935 ; v1(145.653,176.469) R702.2@145.653,177.115 R702.2@145.653,177.159 ; v1(146.555,348.062) C720.1@146.555,348.751 ; v1(146.698,176.469) R700.2@146.698,177.115 R700.2@146.698,177.159 ; v1(146.814,423.353) FB35.1@147.991,423.353 ; U35_I2C_Expander_00.29@146.866,251.769 U35_I2C_Expander_00.29@146.866,252.458 ; v1(147.537,348.062) C721.1@147.537,348.751 ; v1(147.739,176.469) R698.2@147.739,177.115 R698.2@147.739,177.159 ; v1(148.018,281.993) U70.3@148.939,281.993 ; v1(148.337,348.482) U73.4@149.026,348.482 ; C311_I2C_Expander_00.1@148.941,246.289 v1(149.63,246.289) ; U35_I2C_Expander_00.6@149.172,248.771 149.172,248.092 v1(149.522,247.742) ; C355.1@149.956,164.969 v1(149.956,165.658) ; C606.1@151.179,177.997 v1(151.179,178.687) ; C354.1@151.25,164.969 v1(151.25,165.658) ; C308.1@152.563,164.969 v1(152.563,165.658) ; C611.1@152.605,178.016 v1(152.605,178.706) ; v1(153.702,348.062) C722.1@153.702,348.751 ; C610.1@154.122,178.02 v1(154.122,178.709) ; v1(154.508,249.426) R497.2@154.508,250.116 ; v1(154.673,348.062) C723.1@154.673,348.751 ; v1(154.782,154.594) C622.1@155.472,154.594 ; v1(154.782,155.868) C617.1@155.472,155.868 ; C607.1@155.517,178.037 v1(155.517,178.726) ; v1(155.526,249.426) R495.2@155.526,250.116 ; v1(156.537,249.426) 156.537,250.027 R493.2@156.598,250.088 R493.2@156.598,250.116 ; C619.1@156.729,158.621 v1(156.729,159.31) ; v1(156.835,183.706) C615.1@157.524,183.706 ; v1(156.835,185.022) C613.1@157.524,185.022 ; C621.1@158.119,158.621 v1(158.119,159.31) ; v1(159.652,346.431) R690.1@159.652,347.112 R690.1@159.652,347.12 ; v1(160.415,321.846) R173.2@161.105,321.846 ; v1(161.049,331.038) 161.252,331.241 C223.1@162.391,331.241 ; v1(161.143,332.638) 161.511,332.27 R63.2@162.466,332.27 ; v1(161.143,334.638) C263.1@162.38,334.638 ; v1(161.149,335.758) C253.1@162.385,335.758 ; v1(161.21,333.518) C249.1@162.372,333.518 ; v1(161.211,336.878) C229.1@162.385,336.878 ; v1(161.909,298.052) U1.A11@162.397,298.539 ; v1(162.909,298.052) U1.B11@163.397,298.539 ; v1(163.909,298.052) U1.C11@164.397,298.539 ; v1(163.909,308.027) U1.C20@164.397,307.539 ; v1(163.909,313.027) U1.C25@164.397,312.539 ; U1.C30@164.397,317.539 v1(164.397,318.229) ; C618.1@164.723,153.678 v1(165.413,153.678) ; C620.1@164.723,155.005 v1(165.413,155.005) ; v1(164.909,298.052) U1.D11@165.397,298.539 ; R1.1@164.929,243.244 v1(165.619,243.244) ; R2.1@164.998,236.453 165.839,236.453 166.003,236.617 v1(166.058,236.617) ; U28_SPI_bridge_Main.10@165.335,234.222 v1(166.024,234.222) ; v1(165.665,331.671) U9.E6@166.076,331.26 ; v1(165.665,337.274) 166.076,336.863 U9.M6@166.076,336.86 ; v1(165.909,298.052) U1.E11@166.397,298.539 ; v1@166.433,327.647 v1(166.463,327.647) U9.A5@166.876,328.06 ; v1(166.472,330.873) 166.472,330.864 U9.D5@166.876,330.46 ; v1(166.472,332.456) U9.G5@166.876,332.86 ; v1(166.479,331.657) U9.E5@166.876,331.26 ; v1(166.909,298.052) U1.F11@167.397,298.539 ; v1(166.909,312.027) U1.F24@167.397,311.539 ; v1(166.909,313.027) U1.F25@167.397,312.539 ; v1(166.909,314.052) U1.F27@167.397,314.539 ; C614.1@167.373,181.153 v1(168.062,181.153) ; U1.F14@167.397,301.539 v1(167.884,301.052) ; U1.F26@167.397,313.539 v1(167.884,314.027) ; U1.F29@167.397,316.539 v5(167.884,316.052) ; U1.F30@167.397,317.539 v1(167.397,318.491) ; v1(167.909,298.052) U1.G11@168.397,298.539 ; v1(167.909,310.052) U1.G23@168.397,310.539 ; v5(167.909,315.027) U1.G27@168.397,314.539 ; U1.G17@168.397,304.539 v1(168.884,304.052) ; U1.G22@168.397,309.539 v1(168.884,309.052) ; U1.G28@168.397,315.539 v5(168.884,316.027) ; v1(168.909,298.052) U1.H11@169.397,298.539 ; v1(168.909,308.027) U1.H20@169.397,307.539 ; v1(168.909,310.027) U1.H22@169.397,309.539 ; v5(168.909,314.027) U1.H26@169.397,313.539 ; v5(168.909,317.027) U1.H29@169.397,316.539 ; v1(169.137,381.352) 169.137,382.042 ; v1(169.287,390.756) R174.2@169.977,390.756 ; U1.H30@169.397,317.539 169.418,317.518 169.418,318.325 v1(170.093,319) 170.093,318.629 171.007,317.715 171.221,317.715 U1.K30@171.397,317.539 ; v1(169.909,298.052) U1.J11@170.397,298.539 ; v1(169.909,310.027) U1.J22@170.397,309.539 ; v5(169.909,312.027) U1.J24@170.397,311.539 ; U1.J13@170.397,300.539 v1(170.884,300.052) ; U1.J27@170.397,314.539 v5(170.884,315.027) ; U1.J28@170.397,315.539 v5(170.897,316.039) U1.K29@171.397,316.539 v5(170.909,317.027) ; U64_U_Pomiar_pradu_napiecia_PCIe0.7@171.087,382.94 v1(171.087,383.629) ; U1.K22@171.397,309.539 v1(171.884,309.052) ; v1(171.625,163.709) 172.042,163.709 C304.2@172.578,164.244 ; v1(171.673,246.85) R898_SPI_bridge_PCIe.2@171.673,247.506 R898_SPI_bridge_PCIe.2@171.673,247.539 ; v1(171.831,161.002) C623.1@171.831,161.691 ; v1(171.909,306.027) U1.L18@172.397,305.539 ; C307.2@172.278,174.907 v1(172.278,175.597) ; U1.L22@172.397,309.539 v1(172.884,309.052) ; U1.L28@172.397,315.539 v5(172.884,316.027) v1(173.397,316.539) ; U27_SPI_bridge_Main.10@172.469,411.141 v1(173.158,411.141) ; U19.10@173.078,167.05 173.078,167.615 ; U19.29@173.078,171.264 U19.27@173.078,171.85 ; R178.2@173.29,390.756 v1(173.98,390.756) ; U1.M22@173.397,309.539 v1(173.884,310.027) ; C305.2@173.703,174.908 v1(173.703,175.597) ; v1(173.834,163.309) 173.834,164.125 C306.2@173.954,164.244 ; R898_SPI_bridge_Main.2@174.351,230.963 v1(175.041,230.963) ; U1.N23@174.397,310.539 v1(174.884,310.052) ; v1(174.475,254.889) U28_SPI_bridge_PCIe.10@174.475,255.578 ; v1(175.078,164.751) C626.1@175.078,165.233 ; C265.1@175.274,329.59 175.57,329.59 v1(175.936,329.956) ; C264.1@175.446,333.312 176.34,333.312 176.299,333.352 v1(176.275,333.352) ; U19.18@175.789,169.19 v1(176.478,169.19) ; v1(175.841,164.751) C624.1@175.841,165.233 ; U1.R21@176.397,308.539 v1(176.884,308.052) ; v1(176.589,157.834) U67.2@176.589,158.524 ; C625.1@177.382,167.7 v1(178.071,167.7) ; v1(177.909,309.05) U1.U22@178.397,309.537 ; v1(177.98,165.092) R284.1@177.98,165.733 R284.1@177.98,165.781 ; v1(179.909,310.052) U1.W23@180.397,310.539 ; v1(179.926,377.189) 179.941,377.175 179.941,376.372 R182.1@179.955,376.357 ; C220.2@180.759,345.7 C220.2@180.759,345.835 v1(180.759,346.939) v1@180.759,346.951 ; v1(180.95,167.755) R274.1@180.95,168.394 R274.1@180.95,168.444 ; R218.1@180.95,173.465 v1(181.639,173.465) ; R894_SPI_bridge_Main.2@181.429,407.891 R894_SPI_bridge_Main.2@181.482,407.891 v1(182.118,407.891) ; v1(182.164,375.542) 182.304,375.402 184.615,375.402 v1(184.946,375.732) ; v1(182.423,370.51) U63.2@183.112,370.51 ; v1(182.505,376.242) U17.A1@182.945,375.802 ; v1(183.592,168.72) R114.1@183.592,169.36 R114.1@183.592,169.41 ; R214.1@183.592,172.415 v1(183.592,173.105) ; U17.C4@184.145,375.002 184.857,375.002 184.939,375.085 v1(185.276,375.085) ; U17.A4@184.145,375.802 v1(184.585,376.242) ; v1(184.645,366.215) C585.1@184.645,366.842 C585.1@184.645,366.904 ; U1.AD23@185.397,310.539 v5(185.397,310.548) ; U63.8@186.191,371.142 v1(186.88,371.142) ; v1(186.548,250.554) R606_SPI_bridge_Main.2@186.548,251.173 R606_SPI_bridge_Main.2@186.548,251.244 ; C551.1@187.193,345.989 v1(187.193,346.679) ; v1(187.717,370.167) U75.3@188.407,370.167 ; v1(189.29,343.251) C243.2@189.878,343.251 ; v1(189.598,258.775) U25_SPI_bridge_Main.10@189.598,259.465 ; R170.2@190.901,343.311 190.901,343.942 v1(190.909,343.951) ; v1(193.053,343.821) 193.053,343.79 193.055,343.788 C222.2@193.055,343.267 ; U10.E3@193.797,331.26 v1(194.195,331.659) ; U10.D2@194.597,330.46 v5(194.599,330.463) ; U10.E1@195.397,331.26 v5(195.397,331.268) ; C679.1@197.129,158.128 v1(197.129,158.817) ; v1(197.714,156.664) C679.1@197.714,157.353 ; v1(198.282,348.44) C760.2@200.088,348.44 v1(201.986,348.44) ; C679.1@198.323,158.174 v1(198.323,158.863) ; C782.1@198.382,341.419 C782.1@198.382,341.554 198.382,342.337 198.45,342.405 v1(198.45,342.837) v1@198.539,342.925 ; C680.2@198.505,177.56 v1(198.505,178.249) ; C678.1@200.153,158.255 v1(200.153,158.944) ; v1(200.239,242.846) U35_I2C_Expander_11.6@200.239,243.535 ; v1(200.622,156.778) C678.1@200.622,157.467 ; C678.1@201.168,158.191 v1(201.168,158.881) ; T29.2@201.678,163.329 v1(201.678,164.018) ; T28.2@202.377,176.105 v1(202.377,176.794) ; v1(202.39,170.425) T24.2@202.39,171.114 ; C311_I2C_Expander_11.1@204.549,242.712 v1(205.239,242.712) ; v1(205.175,244.902) R529.2@205.175,245.528 R529.2@205.175,245.592 ; U8.B2@206.057,328.86 v5(206.057,328.878) ; v1(206.177,244.902) R527.2@206.177,245.592 ; T26.2@206.267,163.319 v1(206.267,164.009) ; v1(206.834,313.327) C754.1@206.834,314.016 ; v1(207.279,244.902) R525.2@207.279,245.592 ; v1(207.814,314.002) C755.1@208.503,314.002 ; R109.1@208.509,159.124 R109.1@208.509,159.174 v1(208.509,159.813) ; v1(209.73,365.29) U35_I2C_Expander_10.6@209.73,365.979 ; v1(210.366,164.834) R652.1@211.006,164.834 R652.1@211.056,164.834 ; v1(210.421,208.702) C792.1@211.107,208.702 C792.1@211.11,208.702 ; T25.2@210.543,163.329 v1(210.543,164.018) ; C311_I2C_Expander_10.1@211.029,363.954 v1(211.718,363.954) ; v1(211.265,239.585) C562.1@211.265,240.275 ; v1(211.277,241.874) R601.1@211.277,242.564 ; v1(212.203,242.504) U58.3@212.803,242.504 U58.3@212.892,242.504 ; v1(212.203,243.004) U58.2@212.803,243.004 U58.2@212.892,243.004 ; v1(213.881,290.799) 213.881,291.424 214.013,291.556 214.021,291.559 214.021,291.604 R602_SPI_bridge_Main.2@214.002,291.652 ; v1(214.053,241.154) U58.6@214.053,241.754 U58.6@214.053,241.844 ; v1(214.542,241.13) U58.7@214.542,241.82 ; v1(215.125,366.79) R521.2@215.125,367.479 ; v1(215.426,262.522) 215.762,262.522 215.845,262.604 U20.C4@216.556,262.604 ; v1(215.535,151.901) 215.535,152.522 C531.1@215.535,152.59 ; v1(215.756,261.874) 216.086,262.204 218.397,262.204 v1(218.537,262.065) ; v1(216.116,261.364) U20.A4@216.556,261.804 ; v1(216.141,366.79) R519.2@216.141,367.479 ; C561.1@216.649,241.184 216.734,241.1 v1(216.734,240.486) ; v1(217.215,366.79) R517.2@217.215,367.479 ; U20.A1@217.756,261.804 v1(218.196,261.364) ; X6.2@220.777,332.642 v1(220.777,333.332) ; R191.1@221.342,250.151 221.392,250.101 v1(221.392,249.751) ; v1(221.924,289.032) 223.012,289.032 U24_SPI_bridge_Main.10@223.032,289.052 U24_SPI_bridge_Main.10@223.445,289.052 ; v1(222.095,242.686) R187.2@222.784,242.686 ; v1(222.364,335.916) R279.2@222.364,336.558 R279.2@222.364,336.605 ; v1(222.656,339.141) R282.2@222.656,339.797 R282.2@222.656,339.83 ; U26_SPI_bridge_PCIe.10@223.012,372.64 v1(223.012,373.329) ; v1(223.24,346.443) R358.2@223.929,346.443 ; v1(223.24,347.751) R359.2@223.815,347.751 R359.2@223.929,347.751 ; v1(223.24,349.021) R360.2@223.815,349.021 R360.2@223.929,349.021 ; v1(223.24,350.329) R361.2@223.929,350.329 ; U64_U_Pomiar_pradu_napiecia_PCIe1.7@224.781,251.37 224.781,252.18 225.513,252.913 v1(226.596,252.913) ; R183.2@225.891,242.685 v1(226.58,242.685) ; R890_SPI_bridge_PCIe.2@225.933,381.073 v1(225.933,381.762) ; C309_U_Pomiar_pradu_napiecia_PCIe1.1@228.284,249.751 v1(229.214,249.751) ; v1(229.753,320.114) R696.2@229.753,320.803 ; v1(237.638,156.426) C534.1@238.129,156.426 ; v1(237.638,157.633) C533.1@238.129,157.633 ; v1(237.647,158.787) C532.1@238.129,158.787 ; v1(243.713,152.178) R373.1@243.713,152.868 ; v1(244.192,319.215) C747.2@244.881,319.215 ; v1(244.192,321.086) C747.2@244.881,321.086 ; v1(244.25,155.255) U44.4@244.25,155.945 ; U44.5@245.322,157.156 v1(246.012,157.156) ; v1(246.547,317.703) C748.1@247.236,317.703 ; v1(247.236,325.51) B1.2@247.926,325.51 ; v1(250.077,380.08) 251.095,380.08 C309_U_Pomiar_pradu_napiecia_PCIe2.1@251.145,380.03 ; v1(252.715,389.101) R192.2@253.404,389.101 ; v1(252.899,250.177) R606_SPI_bridge_PCIe.2@252.899,250.867 ; v1(253.708,346.126) C743.1@253.708,346.668 C743.1@253.708,346.803 ; v1(254.139,382.164) 254.139,381.225 U64_U_Pomiar_pradu_napiecia_PCIe2.7@254.146,381.218 ; U25_SPI_bridge_PCIe.10@255.841,260.016 v1(255.841,260.706) ; R196.2@256.263,389.07 v1(256.952,389.07) ; R200.1@258.235,382.412 v1(258.235,383.101) ; v1(261.14,348.783) C742.2@261.14,350.583 ; v1(262.528,371.306) 262.668,371.167 U21.B3@264.109,371.167 264.979,371.167 v1(265.309,371.497) ; v1(262.869,372.007) U21.A1@263.309,371.567 ; U21.C4@264.509,370.767 265.22,370.767 265.303,370.849 v1(265.639,370.849) ; U21.A4@264.509,371.567 v1(264.949,372.007) ; v5(265.066,162.954) D15.3@265.066,162.965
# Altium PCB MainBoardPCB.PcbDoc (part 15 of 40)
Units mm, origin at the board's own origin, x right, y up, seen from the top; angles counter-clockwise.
Board outline 258.95 x 308.86 mm, 16 copper layers (L1, L2 (GND), L3 (Sign), L4 (GND), L5 (Sign), L6 (PWR/GND), L7(12V+Other), L8 (Plane_GND), L9 (PWR/GND), L10 (3V3+Other), L11 (PWR/GND), L12 (Sign), L13 (GND), L14 (Sign), L15 (GND), L16), stack 2.503 mm thick; 2578 components, 1867 nets, 8817 pads, 8021 vias.
Unrouted connection lines stored in the file: 25.

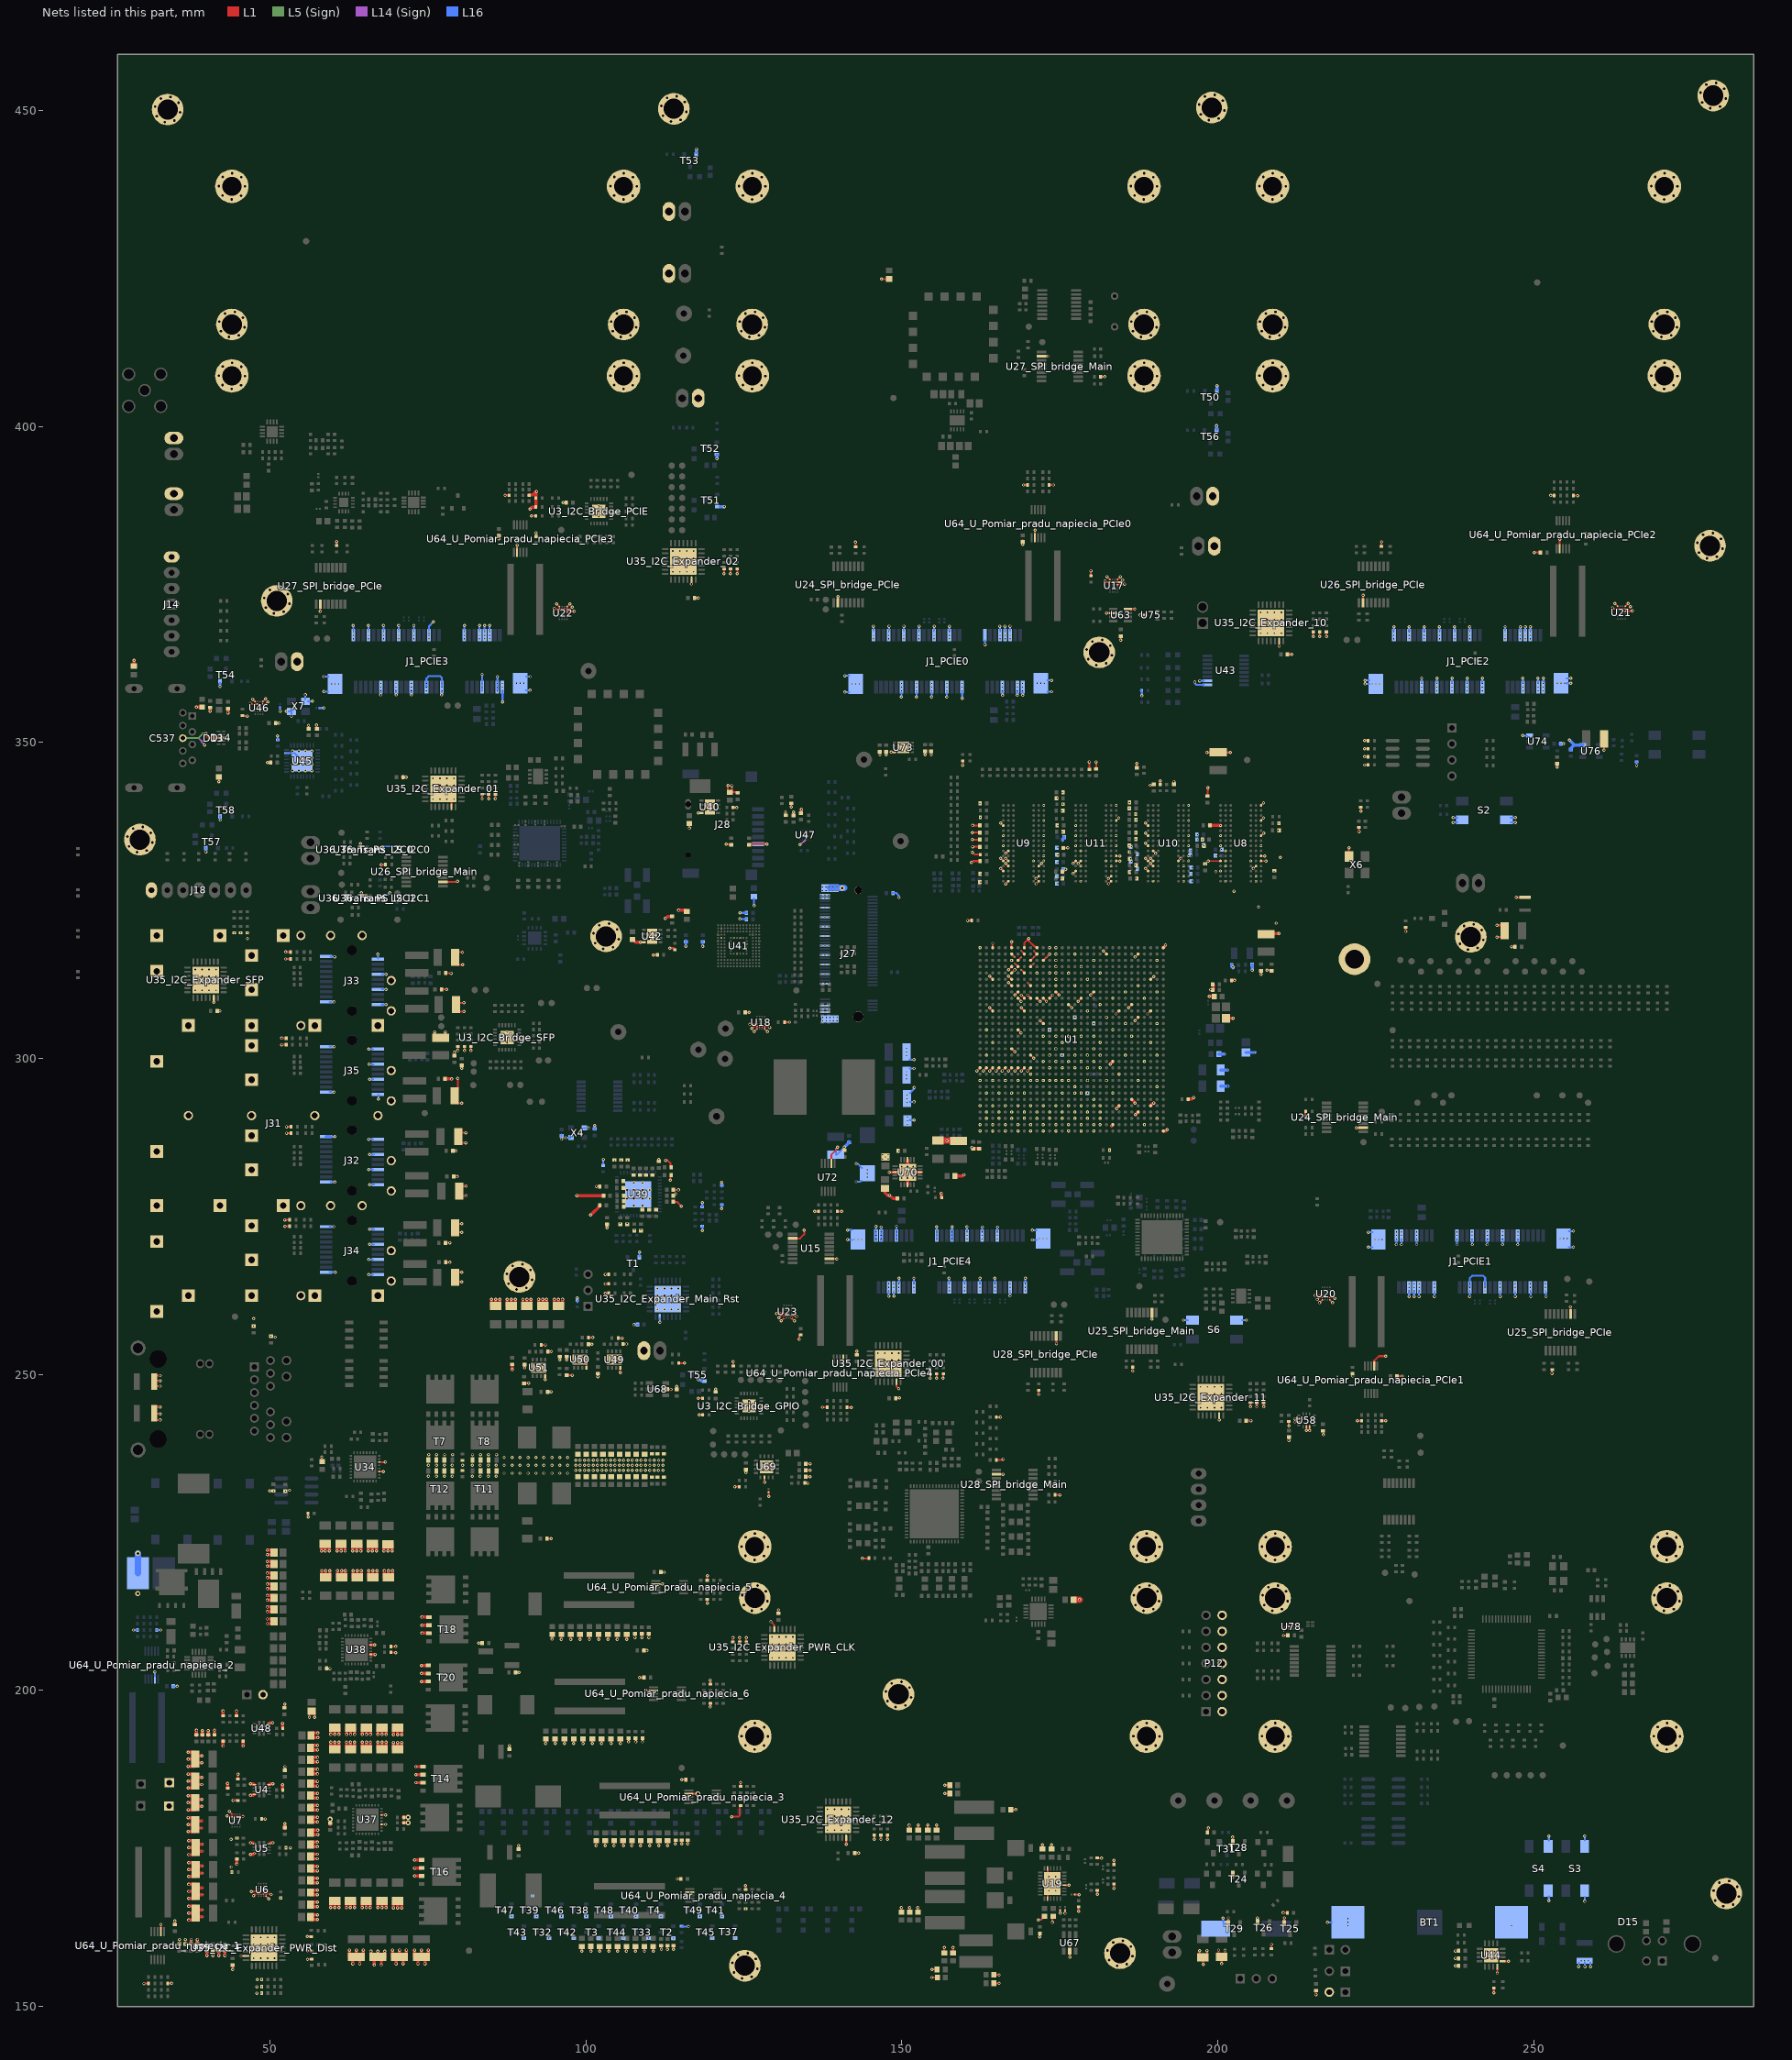
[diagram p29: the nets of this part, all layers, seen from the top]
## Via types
v1: diameter 0.5, hole 0.25, L1 to L16, tented both sides, 4341 vias
v2: diameter 0.254, hole 0.1, L1 to L3 (Sign), tented both sides, 781 vias
v3: diameter 0.5, hole 0.25, L1 to L16, 565 vias
v4: diameter 0.254, hole 0.1, L15 (GND) to L16, tented both sides, 406 vias
v5: diameter 0.254, hole 0.1, L1 to L2 (GND), tented both sides, 283 vias
v6: diameter 0.457, hole 0.2, L3 (Sign) to L6 (PWR/GND), tented both sides, 254 vias
v7: diameter 0.254, hole 0.1, L1 to L3 (Sign), 237 vias
v8: diameter 0.75, hole 0.4, L1 to L16, 200 vias
v9: diameter 0.8, hole 0.4, L1 to L16, tented both sides, 182 vias
v10: diameter 0.254, hole 0.1, L14 (Sign) to L16, tented both sides, 170 vias
v11: diameter 0.75/0/0/0/0/0/0/0/0/0/0/0/0/0/0/0.75 (per signal layer), hole 0.4, L1 to L16, 160 vias
v12: diameter 0.457, hole 0.2, L3 (Sign) to L6 (PWR/GND), 158 vias
v13: diameter 1.4, hole 0.5, L1 to L16, tented both sides, 80 vias
v14: diameter 0.254, hole 0.1, L14 (Sign) to L16, 65 vias
v15: diameter 0.254, hole 0.1, L1 to L2 (GND), 45 vias
v16: diameter 0.457, hole 0.2, L11 (PWR/GND) to L14 (Sign), tented both sides, 26 vias
v17: diameter 0.457, hole 0.2, L11 (PWR/GND) to L14 (Sign), 25 vias
v18: diameter 0.457, hole 0.2, L7(12V+Other) to L10 (3V3+Other), tented both sides, 11 vias
v19: diameter 0.254/0/0.254 (per signal layer), hole 0.1, L1 to L3 (Sign), 9 vias
v20: diameter 0.2/0/0.2 (per signal layer), hole 0.1, L1 to L3 (Sign), 6 vias
v21: diameter 1.65, hole 1.65, L1 to L16, 5 vias
v22: diameter 1.15, hole 1.15, L1 to L16, 5 vias
v23: diameter 0.457, hole 0.2, L1 to L16, 3 vias
v24: diameter 0.5, hole 0.3, L1 to L16, 2 vias
v25: diameter 0.5/0/0.5 (per signal layer), hole 0.2, L14 (Sign) to L16, 1 vias
v26: diameter 0.5, hole 0.25, L1 to L16, tented bottom, 1 vias

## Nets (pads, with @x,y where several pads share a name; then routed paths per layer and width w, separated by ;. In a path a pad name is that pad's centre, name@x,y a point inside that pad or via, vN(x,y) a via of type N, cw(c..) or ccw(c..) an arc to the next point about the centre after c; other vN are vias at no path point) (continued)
B503_Ground: (continued)
  L1 w0.5: FB28.1@28.49,362.101 v3(28.49,363.014) ; v1(37.08,177.689) C12.2@38.167,177.689 ; v1(37.08,178.794) C12.2@38.167,178.794 ; v1(37.08,179.891) C12.2@38.167,179.891 ; v1(37.08,181.134) C15.2@38.167,181.134 ; v1(37.08,182.239) C15.2@38.167,182.239 ; v1(37.08,183.336) C15.2@38.167,183.336 ; v1(37.08,184.579) C13.2@38.167,184.579 ; v1(37.08,185.684) C13.2@38.167,185.684 ; v1(37.08,186.781) C13.2@38.167,186.781 ; v1(37.08,188.024) C14.2@38.167,188.024 ; v1(37.08,189.129) C14.2@38.167,189.129 ; v1(37.08,190.226) C14.2@38.167,190.226 ; v1(37.161,163.667) C4.2@38.248,163.667 ; v1(37.161,164.772) C4.2@38.248,164.772 ; v1(37.161,165.868) C4.2@38.248,165.868 ; v1(37.161,167.121) C5.2@38.248,167.121 ; v1(37.161,168.226) C5.2@38.248,168.226 ; v1(37.161,169.323) C5.2@38.248,169.323 ; v1(37.161,170.575) C7.2@38.248,170.575 ; v1(37.161,171.68) C7.2@38.248,171.68 ; v1(37.161,172.777) C7.2@38.248,172.777 ; v1(37.161,174.03) C6.2@38.248,174.03 ; v1(37.161,175.135) C6.2@38.248,175.135 ; v1(37.161,176.232) C6.2@38.248,176.232 ; C771.1@37.531,159.866 v1(37.531,160.603) ; C12.2@38.167,178.237 v15(39.254,178.237) ; C12.2@38.167,179.342 v15(39.254,179.342) ; C15.2@38.167,181.682 v1(39.254,181.682) ; C15.2@38.167,182.787 v1(39.254,182.787) ; C13.2@38.167,185.127 v1(39.254,185.127) ; C13.2@38.167,186.232 v1(39.254,186.232) ; C14.2@38.167,188.573 v1(39.254,188.573) ; C14.2@38.167,189.678 v1(39.254,189.678) ; C4.2@38.248,164.215 v15(39.335,164.215) ; C4.2@38.248,165.32 v15(39.335,165.32) ; C5.2@38.248,167.669 v15(39.335,167.669) ; C5.2@38.248,168.774 v15(39.335,168.774) ; C7.2@38.248,171.124 v15(39.335,171.124) ; C7.2@38.248,172.229 v15(39.335,172.229) ; C6.2@38.248,174.578 v15(39.335,174.578) ; C6.2@38.248,175.683 v15(39.335,175.683) ; v3(38.365,355.594) 39.269,355.594 ccw(c39.269,355.615) C539.1@39.29,355.615 ; C16.1@38.398,192.881 v1(38.398,193.695) ; C770.1@38.538,159.866 v1(38.538,160.603) ; C19.1@39.328,192.855 v1(39.328,193.669) ; v1(40.046,158.068) C9.1@40.046,158.882 ; C18.1@40.234,192.855 C18.1@40.234,192.99 v1(40.234,193.668) ; v3(40.561,354.989) C538.2@40.561,355.544 ; v1(40.975,158.068) C10.1@40.975,158.882 ; C17.1@41.232,192.897 C17.1@41.232,192.99 v1(41.232,193.711) ; v1(41.91,158.068) C11.1@41.91,158.882 ; v1(42.6,191.22) R683.1@42.6,191.983 R683.1@42.6,192.033 ; R685.1@42.6,195.933 R685.1@42.6,195.983 v1(42.6,196.747) ; v1(42.89,158.068) C8.1@42.89,158.882 ; R28.2@43.328,184.502 v1(43.328,185.316) ; v3(43.341,354.698) 43.346,354.698 C734.2@43.346,355.383 ; R684.1@44.716,195.933 R684.1@44.716,195.983 v1(44.716,196.747) ; v1(44.783,172.518) R19.1@44.783,173.331 ; v1(45.775,191.22) R682.1@45.775,191.983 R682.1@45.775,192.033 ; v1(46.946,174.081) 47.391,174.081 v15(47.56,174.25) ; v1(46.946,175.918) 47.391,175.918 ; v1(46.946,183.403) 47.391,183.403 U4.6@47.56,183.571 ; v1(46.946,185.24) 47.391,185.24 U4.3@47.56,185.071 ; v1(49.579,210.588) C780.1@50.666,210.588 ; v1(49.579,211.312) C780.1@50.665,211.312 ; v1(49.579,212.483) C779.1@50.666,212.483 ; v1(49.579,213.207) C779.1@50.666,213.207 ; v1(49.579,214.293) C778.1@50.666,214.293 ; v1(49.579,215.016) C778.1@50.666,215.016 ; v1(49.579,216.83) C777.1@50.666,216.83 ; v1(49.579,217.851) C776.1@50.666,217.851 ; v1(49.579,218.575) C776.1@50.666,218.575 ; v1(49.579,219.674) C775.1@50.666,219.674 ; v1(49.579,220.398) C775.1@50.666,220.398 ; v1(49.579,221.488) C774.1@50.666,221.488 ; v1(49.579,222.211) C774.1@50.666,222.211 ; v1(49.579,216.106) C777.1@50.666,216.106 ; U48.12@49.827,194.733 49.996,194.902 v1(50.442,194.902) ; U4.12@49.86,185.071 50.029,185.24 v1(50.475,185.24) ; 50.029,175.918 v1(50.475,175.918) ; R18.1@52.018,184.274 v1(52.018,185.088) ; R681.1@52.018,194.019 v1(52.018,194.833) ; C313.1@52.362,178.103 v1(52.362,178.917) ; C20.1@56.419,164.502 v1(57.506,164.502) ; C20.1@56.419,163.778 v1(57.506,163.778) ; C27.1@56.447,165.786 v1(57.534,165.786) ; C27.1@56.446,166.51 v1(57.533,166.51) ; C22.1@56.447,167.684 v1(57.534,167.684) ; C22.1@56.446,168.408 v1(57.533,168.408) ; C21.1@56.447,169.581 v1(57.534,169.581) ; C21.1@56.446,170.305 v1(57.533,170.305) ; C24.1@56.447,171.479 v1(57.534,171.479) ; C24.1@56.446,172.203 v1(57.533,172.203) ; C25.1@56.447,173.377 v1(57.534,173.377) ; C25.1@56.446,174.101 v1(57.533,174.101) ; C23.1@56.447,175.275 v1(57.534,175.275) ; C23.1@56.446,175.999 v1(57.533,175.999) ; C31.1@56.458,179.934 v1(57.545,179.934) ; C30.1@56.458,181.831 v1(57.545,181.831) ; C32.1@56.458,183.729 v1(57.545,183.729) ; C29.1@56.458,185.627 v1(57.545,185.627) ; C28.1@56.458,187.525 v1(57.545,187.525) ; C33.1@56.458,189.423 v1(57.545,189.423) ; C34.1@56.458,191.321 v1(57.545,191.321) ; C31.1@56.459,179.21 v1(57.546,179.21) ; C30.1@56.459,181.108 v1(57.546,181.108) ; C32.1@56.459,183.005 v1(57.546,183.005) ; C29.1@56.459,184.903 v1(57.546,184.903) ; C28.1@56.459,186.801 v1(57.546,186.801) ; C33.1@56.459,188.699 v1(57.546,188.699) ; C34.1@56.459,190.597 v1(57.546,190.597) ; C26.1@56.477,177.173 v1(57.564,177.173) ; C26.1@56.476,177.897 v1(57.563,177.897) ; C35.1@56.484,193.263 v1(57.571,193.263) ; C35.1@56.484,192.539 v1(57.571,192.539) ; v1(58.138,222.101) C392.1@58.138,223.188 ; C397.2@58.206,217.883 v1(58.206,218.97) ; v1(58.776,222.101) C392.1@58.776,223.188 ; C397.2@58.852,217.883 v1(58.852,218.97) ; v1(59.421,222.101) C392.1@59.421,223.188 ; C397.2@59.489,217.883 v1(59.489,218.97) ; C399.2@59.53,178.803 v9(59.53,179.617) ; v1(59.638,165.636) C433.1@59.638,166.723 ; C438.2@59.645,190.731 v1(59.645,191.818) ; v1(59.653,193.043) C353.1@59.653,194.13 ; v1(60.276,165.636) C433.1@60.276,166.723 ; C438.2@60.29,190.731 v1(60.29,191.818) ; v1(60.29,193.043) C353.1@60.29,194.13 ; v1(60.62,222.101) C391.2@60.62,223.188 ; C396.1@60.688,217.883 v1(60.688,218.97) ; v1(60.921,165.636) C433.1@60.921,166.723 ; C438.2@60.927,190.731 v1(60.927,191.818) ; v1(60.936,193.043) C353.1@60.936,194.13 ; v1(61.258,222.101) C391.2@61.258,223.188 ; C396.1@61.334,217.883 v1(61.334,218.97) ; v1(61.903,222.101) C391.2@61.903,223.188 ; C396.1@61.971,217.883 v1(61.971,218.97) ; v1(62.12,165.636) C432.2@62.12,166.723 ; C437.1@62.127,190.731 v1(62.127,191.818) ; v1(62.135,193.043) C352.1@62.135,194.13 ; C769.2@62.575,157.849 v1(62.575,158.936) ; v1(62.758,165.636) C432.2@62.758,166.723 ; C437.1@62.772,190.731 v1(62.772,191.818) ; v1(62.772,193.043) C352.1@62.772,194.13 ; v1(63.102,222.1) C405.1@63.102,223.187 ; v1(63.124,156.762) C769.2@63.124,157.849 ; C402.1@63.17,217.883 v1(63.17,218.97) ; v1(63.403,165.636) C432.2@63.403,166.723 ; C437.1@63.409,190.731 v1(63.409,191.818) ; v1(63.418,193.043) C352.1@63.418,194.13 ; C769.2@63.68,157.849 v1(63.68,158.936) ; v1(63.74,222.1) C405.1@63.74,223.187 ; C402.1@63.816,217.883 v1(63.816,218.97) ; v1(64.229,156.762) C769.2@64.229,157.849 ; v1(64.385,222.1) C405.1@64.385,223.187 ; C402.1@64.453,217.883 v1(64.453,218.97) ; v1(64.602,165.636) C446.1@64.602,166.723 ; C443.1@64.609,190.731 v1(64.609,191.818) ; v1(64.617,193.043) C374.1@64.617,194.13 ; C769.2@64.777,157.849 v1(64.777,158.936) ; v1(65.24,165.636) C446.1@65.24,166.723 ; C443.1@65.254,190.731 v1(65.254,191.818) ; v1(65.254,193.043) C374.1@65.254,194.13 ; v1(65.584,222.1) C404.1@65.584,223.187 ; C401.1@65.652,217.883 v1(65.652,218.97) ; v1(65.885,165.636) C446.1@65.885,166.723 ; C443.1@65.891,190.731 v1(65.891,191.818) ; v1(65.9,193.043) C374.1@65.9,194.13 ; U38.19@65.953,205.714 v1(66.65,205.714) ; U38.22@65.953,207.214 66.595,207.214 v1(66.599,207.218) ; C768.2@65.979,157.65 65.979,157.849 v1(65.979,158.737) ; v1(66.222,222.1) C404.1@66.222,223.187 ; C401.1@66.298,217.883 v1(66.298,218.97) ; v1(66.528,156.563) C768.2@66.528,157.65 ; v1(66.867,222.1) C404.1@66.867,223.187 ; C401.1@66.935,217.883 v1(66.935,218.97) ; C768.2@67.084,157.65 v1(67.084,158.737) ; v1(67.085,165.636) C445.1@67.085,166.723 ; C442.1@67.091,190.731 v1(67.091,191.818) ; v1(67.099,193.043) C371.1@67.099,194.13 ; v1(67.632,156.563) C768.2@67.632,157.65 ; v1(67.722,165.636) C445.1@67.722,166.723 ; C442.1@67.736,190.731 v1(67.736,191.818) ; v1(67.736,193.043) C371.1@67.736,194.13 ; v1(68.066,222.07) C403.1@68.066,223.157 ; C400.1@68.134,217.853 v1(68.134,218.94) ; C768.2@68.181,157.65 68.181,157.849 v1(68.181,158.737) ; v1(68.367,165.636) C445.1@68.367,166.723 ; C442.1@68.373,190.731 v1(68.373,191.818) ; v1(68.382,193.043) C371.1@68.382,194.13 ; v1(68.704,222.07) C403.1@68.704,223.157 ; C400.1@68.78,217.853 C400.1@68.78,217.883 v1(68.78,218.94) ; v1(69.349,222.07) C403.1@69.349,223.157 ; C400.1@69.417,217.853 v1(69.417,218.94) ; C767.2@69.419,157.85 v1(69.419,158.937) ; v1(69.567,165.605) C444.1@69.567,166.692 ; C441.1@69.573,190.7 v1(69.573,191.787) ; v1(69.581,193.012) C376.1@69.581,194.099 ; v1(69.967,156.763) C767.2@69.967,157.85 ; v1(70.204,165.605) C444.1@70.204,166.692 ; C441.1@70.218,190.7 v1(70.218,191.787) ; v1(70.218,193.012) C376.1@70.218,194.099 ; C767.2@70.524,157.85 v1(70.524,158.937) ; v1(70.849,165.605) C444.1@70.849,166.692 ; C441.1@70.855,190.7 v1(70.855,191.787) ; v1(70.864,193.012) C376.1@70.864,194.099 ; R299.1@71.06,179.067 R299.1@71.161,179.067 v9(71.874,179.067) ; R292.1@71.06,179.934 v9(71.874,179.934) ; v1(71.072,156.763) C767.2@71.072,157.85 ; C767.2@71.621,157.85 v1(71.621,158.937) ; C766.2@72.887,157.849 v1(72.887,158.936) ; v1(72.923,170.65) T16.3@74.01,170.65 ; v1(72.923,171.92) T16.2@74.01,171.92 ; v1(72.923,173.19) T16.1@74.01,173.19 ; v1(73.127,185.42) T14.3@74.214,185.42 ; v1(73.127,186.69) T14.2@74.214,186.69 ; v1(73.127,187.96) T14.1@74.214,187.96 ; v1(73.435,156.762) C766.2@73.435,157.849 ; v1(73.987,201.422) T20.3@75.074,201.422 ; v1(73.987,202.692) T20.2@75.074,202.692 ; v1(73.987,203.962) T20.1@75.074,203.962 ; C766.2@73.992,157.849 v1(73.992,158.936) ; v1(74.086,209.067) T18.3@75.173,209.067 ; v1(74.086,210.337) T18.2@75.173,210.337 ; v1(74.086,211.607) T18.1@75.173,211.607 ; v1(74.54,156.762) C766.2@74.54,157.849 ; C766.2@75.088,157.849 v1(75.088,158.936) ; C217.1@77.571,296.771 v1(78.781,296.771) ; C348.1@85.083,260.822 v1(85.083,261.909) ; C348.1@85.728,260.822 v1(85.728,261.909) ; C348.1@86.366,260.822 v1(86.366,261.909) ; C347.1@87.565,260.822 v1(87.565,261.909) ; C347.1@88.21,260.822 v1(88.21,261.909) ; v3(88.328,250.775) 88.332,250.778 C513.1@88.332,251.591 ; C347.1@88.848,260.822 v1(88.848,261.909) ; C372.1@90.047,260.822 v1(90.047,261.909) ; C372.1@90.692,260.822 v1(90.692,261.909) ; R205.2@90.972,389.129 91.022,389.179 91.58,389.179 92.112,389.711 92.133,389.69 92.133,387.28 92.083,387.23 91.478,387.23 v1(91.183,386.935) ; C372.1@91.33,260.822 v1(91.33,261.909) ; C375.1@92.529,260.822 v1(92.529,261.909) ; C375.1@93.174,260.822 v1(93.174,261.909) ; C375.1@93.812,260.822 v1(93.812,261.909) ; C373.1@95.011,260.791 v1(95.011,261.878) ; C373.1@95.656,260.791 C373.1@95.656,260.822 v1(95.656,261.878) ; C373.1@96.294,260.791 v1(96.294,261.878) ; v1(98.552,278.32) 98.556,278.325 C506.2@102.8,278.325 C506.2@102.935,278.325 ; v1(100.753,275.247) 100.781,275.247 C504.1@102.321,276.787 ; C515.1@107.397,318.83 107.447,318.83 107.876,318.401 v1(108.658,318.401) ; v1(112.59,322.166) 112.915,322.49 113.63,322.49 C519.1@113.636,322.496 ; v3(114.705,323.452) 115.82,323.452 cw(c115.82,323.3) C524.1@115.973,323.3 ; C547.1@134.066,338.845 134.116,338.845 134.141,338.87 134.141,339.423 v1(134.143,339.425) ; C708.1@147.331,279.462 147.331,278.812 147.746,278.397 v1(148.057,278.397) 148.615,277.838 C711.1@149.297,277.838 C711.1@149.432,277.838 ; U70.3@148.939,282.014 150.904,282.014 v3(150.914,282.003) ; v3(150.014,282.003) v3(150.914,282.003) ; U70.8@150.914,280.028 v3(150.914,281.103) v3(150.914,282.003) ; U70.18@150.914,283.979 v3(150.914,282.904) v3(150.914,282.003) ; U70.13@152.889,282.003 v3(151.814,282.003) v3(150.914,282.003) ; R674.1@156.266,278.016 v1(156.266,278.669) ; v1(157.15,287.011) v1@157.175,287.011 ; C709.1@158.397,281.407 159.652,281.407 v1(159.842,281.597) ; C761.1@161.332,285.748 161.339,285.742 C741.1@162.238,285.742 ; v5(174.604,341.201) v5(174.604,341.201) ; v1(182.981,299.123) U1.AB12@183.397,299.539 ; v5(183.192,289.344) U1.AB2@183.397,289.539 ; v1(184.036,292.075) 184.036,292.178 U1.AC5@184.397,292.539 ; U1.AC10@184.397,297.539 v5(184.417,297.548) ; v5(185.39,300.533) U1.AD13@185.397,300.539 ; U1.AE6@186.397,293.539 v1@186.789,293.147 ; v1@186.789,293.147 cw(c186.435,292.794) v1(186.906,292.964) ; v1(186.978,291.135) 186.992,291.135 U1.AF4@187.397,291.539 ; U1.AH5@189.397,292.539 v1@189.712,292.855 ; v1@189.713,292.855 cw(c190.064,292.5) 189.775,292.908 v1(189.872,292.977) ; U1.AK1@191.397,288.539 191.765,288.539 v1(191.986,288.76) ; U1.AK30@191.397,317.539 191.737,317.88 v1(191.737,317.963) ; R693.2@195.324,293.548 195.348,293.573 195.944,293.573 v1(196.211,293.839) ; C254.1@198.65,336.886 200.431,336.886 v5(200.457,336.86) ; v1(198.653,309.829) C705.1@199.476,309.829 ; v1(198.882,310.896) 198.895,310.883 C750.1@199.224,310.883 199.359,310.883 C758.1@199.359,311.734 ; FB39.1@201.307,306.362 v26(202.456,306.362) ; R920.2@202.16,312.356 R920.2@202.21,312.356 v1(202.667,312.356) ; C753.2@208.891,319.797 v1(209.705,319.797)
  L1 w1: C749.1@155.753,287.062 155.804,287.011 v1(157.15,287.011) ; v1@157.175,287.011 158.915,287.011 C757.2@158.966,286.959 ; FB36.1@177.192,214.363 v1(178.156,214.363)
  L5 (Sign) w0.3: C537.7@36.22,350.698 38.673,350.698 39.386,351.411 v3(39.871,351.411)
  L14 (Sign) w0.2: v1(133.896,333.87) 133.995,333.87 134.73,334.606 134.729,334.607 v10(134.729,335.404)
  L14 (Sign) w0.3: C537.7@36.22,350.698 38.757,350.698 39.195,350.26 39.195,350.134 39.671,349.657 v3(39.671,349.62)
  L16 w0.2: U36_Trans_LS_I2C0.1@68.1,333.56 70.63,333.56 v10(70.79,333.4) ; U36_Trans_LS_I2C1.1@68.337,325.886 68.628,325.886 v1(68.958,326.217) ; v1(202.377,176.794) 202.377,175.91 T31.2@202.385,175.902
  L16 w0.3: v1(28.443,209.571) R595.2@29.133,209.571 ; U64_U_Pomiar_pradu_napiecia_2.7@31.798,202.263 v1(31.798,202.953) ; R467.2@32.004,209.571 v1(32.693,209.571) ; C309_U_Pomiar_pradu_napiecia_2.1@34.626,200.663 v1(35.315,200.663) ; v1(39.871,332.722) T57.2@39.871,333.313 T57.2@39.871,333.411 ; v1@42.128,337.716 T58.2@42.128,338.307 T58.2@42.128,338.405 ; R379.1@51.218,350.357 v1(51.218,351.047) ; v1(51.613,354.989) C737.1@51.613,355.679 ; v1(52.585,354.949) X7.2@53.274,354.949 ; U45.23@52.655,348.341 53.855,348.341 v3(54.595,347.601) U45.33@55.105,347.091 ; v1(53.42,354.198) X7.2@53.42,354.887 ; X7.4@55.605,356.854 v1(55.605,357.543) ; X7.4@56.044,356.548 v1(56.733,356.548) ; C736.1@57.875,355.473 v1(58.564,355.473) ; v1(58.564,358.064) J1_PCIE3.M@59.253,358.064 ; v1(58.564,360.439) J1_PCIE3.M@59.253,360.439 ; J34.1@59.465,266.197 v1(60.325,266.197) ; J34.10@59.465,273.397 v1(60.155,273.397) ; J35.1@59.465,294.697 v1(60.155,294.697) ; J35.10@59.465,301.889 v1(60.155,301.889) ; J33.1@59.465,308.947 v1(60.155,308.947) ; J33.10@59.559,316.108 v1(60.249,316.108) ; J32.1@59.574,280.447 v1(60.263,280.447) ; J32.10@59.574,287.647 v1(60.263,287.647) ; J1_PCIE3.52@63.185,367.849 v1(63.185,368.538) ; J1_PCIE3.46@65.585,367.824 v1(65.585,368.513) ; v1(65.66,265.797) J34.20@66.349,265.797 ; v1(65.66,268.186) J34.17@66.349,268.186 ; v1(65.66,282.447) J32.17@66.349,282.447 ; v1(65.66,287.247) J32.11@66.349,287.247 ; v1(65.66,301.497) J35.11@66.349,301.497 ; v1(65.743,299.097) J35.14@66.433,299.097 ; v1(65.771,296.722) 66.323,296.722 J35.17@66.349,296.697 ; v1(65.778,270.597) J34.14@66.467,270.597 ; v1(65.778,272.997) J34.11@66.467,272.997 ; v1(65.778,280.047) J32.20@66.467,280.047 ; v1(65.778,284.818) J32.14@66.467,284.818 ; J33.11@67.104,315.802 v1(67.104,316.491) ; v1(67.183,293.582) J35.20@67.183,294.271 ; v1(67.551,357.543) J1_PCIE3.41@67.551,358.232 ; J33.20@67.68,308.547 v1(68.37,308.547) ; J33.17@67.68,310.947 v1(68.37,310.947) ; J33.14@67.68,313.347 v1(68.37,313.347) ; J1_PCIE3.40@67.985,367.824 v1(67.985,368.513) ; v1(69.978,357.543) J1_PCIE3.35@69.978,358.232 ; J1_PCIE3.34@70.385,367.824 v1(70.385,368.513) ; v1(72.385,357.543) J1_PCIE3.29@72.385,358.232 ; J1_PCIE3.28@72.785,367.824 v1(72.785,368.513) ; v4(74.785,358.792) v4(74.785,359.366) 74.785,360.141 75.184,360.54 76.914,360.54 77.185,360.269 v4(77.185,359.366) v4(77.185,358.792) ; v4(75.185,366.992) v4(75.185,367.566) 75.185,368.397 75.885,369.097 v1(75.885,369.113) ; v1(77.185,357.543) J1_PCIE3.17@77.185,358.232 ; J1_PCIE3.16@80.785,367.824 v1(80.785,368.513) ; J1_PCIE3.10@83.185,367.824 v1(83.185,368.513) ; J1_PCIE3.9@83.593,358.232 v1(83.593,360.777) ; J1_PCIE3.8@83.973,367.824 v1(83.973,368.513) ; J1_PCIE3.6@84.773,367.824 v1(84.773,368.513) ; J1_PCIE3.3@85.985,358.232 86.024,358.272 86.024,358.792 v1(86.024,360.442) ; v1(86.817,356.425) 86.817,358.206 J1_PCIE3.1@86.844,358.232 ; J1_PCIE3.M@90.493,358.274 v1(91.183,358.274) ; J1_PCIE3.M@90.545,360.442 v1(91.207,360.442) ; v1(96.15,287.259) C481.1@96.15,287.747 C481.1@96.15,287.949 ; v1(96.857,287.472) X4.4@97.547,287.472 ; 98.654,261.417 R675.1@98.654,261.732 v1(98.654,262.107) ; X4.2@99.731,289.01 X4.2@99.77,289.01 v1(100.42,289.01) ; C480.1@101.402,288.702 v1(101.402,289.391) ; 102.761,283.361 v1(102.761,284.051) ; v1(107.614,257.892) C311_I2C_Expander_Main_Rst.1@108.164,257.892 C311_I2C_Expander_Main_Rst.1@108.304,257.892 ; T1.2@108.496,268.703 v1(108.496,269.392) ; v1(111.722,258.276) U35_I2C_Expander_Main_Rst.6@111.722,258.965 ; R1059.2@115.133,162.647 116.229,162.647 v1(116.23,162.649) ; C520.1@115.838,318.731 C520.1@115.838,318.466 115.838,317.785 v1(115.843,317.779) ; R327.1@118.441,276.536 v1(118.441,277.225) ; v1(118.454,272.795) R328.1@118.454,273.484 ; v1@118.491,317.777 C587.1@118.491,318.593 ; v1(121.511,276.275) R326.1@121.511,276.964 ; R325.1@121.511,279.713 v1(121.511,280.402) ; v1(124.384,322.074) C521.1@125.517,322.074 ; v1(124.384,323.051) C522.2@125.517,323.051 ; v1(126.632,324.18) FB29.2@126.632,325.313 ; J28.6@127.993,333.931 v1(128.682,333.931) ; v1(139.852,285.987) 139.573,285.708 C764.2@139.573,284.807 139.749,284.807 v1(140.907,285.966) ; v1(141.007,357.978) J1_PCIE0.M@141.696,357.978 ; v1(141.007,360.576) J1_PCIE0.M@141.696,360.576 ; v1(141.416,271.319) J1_PCIE4.M@142.106,271.319 ; v1(141.445,272.872) J1_PCIE4.M@142.134,272.872 ; v1(142.777,280.511) 143.409,280.511 C738.2@143.566,280.669 ; v1(142.777,283.364) 143.012,283.364 C738.2@143.704,282.672 ; J1_PCIE0.52@145.517,367.725 v1(145.517,368.414) ; J1_PCIE4.1@145.873,271.263 145.923,271.214 145.987,271.277 145.91,271.353 145.91,271.994 v1(145.91,273.444) ; J1_PCIE4.3@146.685,271.093 J1_PCIE4.3@146.749,271.157 ; v1(146.749,273.326) J1_PCIE4.3@146.749,271.157 ; J1_PCIE4.3@146.769,271.263 146.812,271.22 J1_PCIE4.3@146.749,271.157 ; v1(147.937,262.407) J1_PCIE4.6@147.937,263.097 ; J1_PCIE0.46@147.997,367.725 v1(147.997,368.414) ; C332.2@148.499,326.176 149.169,326.176 149.516,325.829 149.516,325.514 v1(149.553,325.477) ; v1(148.755,262.407) J1_PCIE4.8@148.755,263.097 ; J1_PCIE4.9@149.137,271.263 149.149,271.252 149.161,271.264 149.161,271.994 v1(149.161,273.469) ; J1_PCIE4.10@149.569,264.563 v1(149.569,265.252) ; v1(149.937,357.23) J1_PCIE0.41@149.937,357.919 ; J1_PCIE0.40@150.335,367.725 v1(150.335,368.414) ; C762.2@151.235,299.833 v1(151.924,299.833) ; C739.2@151.239,293.134 v1(151.928,293.134) ; C739.2@151.239,294.491 151.981,295.234 v1(151.981,295.402) ; C744.1@151.253,290.267 v1(151.942,290.267) ; C751.2@151.256,298.425 v1(151.945,298.425) ; J1_PCIE4.16@151.917,264.563 v1(151.917,265.252) ; v1(152.337,357.23) J1_PCIE0.35@152.337,357.919 ; J1_PCIE0.34@152.737,367.725 v1(152.737,368.414) ; v1(154.737,357.23) J1_PCIE0.29@154.737,357.919 ; J1_PCIE0.28@155.137,367.725 v1(155.137,368.414) ; J1_PCIE4.17@155.516,271.339 J1_PCIE4.17@155.524,271.331 ; v1(155.524,273.368) J1_PCIE4.17@155.524,271.331 ; J1_PCIE4.17@155.537,271.319 J1_PCIE4.17@155.524,271.331 ; v1(157.137,357.23) J1_PCIE0.23@157.137,357.919 ; J1_PCIE4.22@157.493,264.563 v1(157.493,265.252) ; J1_PCIE0.22@157.537,367.725 v1(157.537,368.414) ; J1_PCIE4.23@157.924,271.257 157.975,271.308 v1(157.975,273.368) ; J1_PCIE0.17@159.537,357.919 159.576,357.881 v1(159.576,357.01) ; J1_PCIE4.28@159.937,264.563 v1(159.937,265.252) ; J1_PCIE4.29@160.318,272.683 v1(160.318,273.372) ; J1_PCIE4.34@162.374,264.563 v1(162.374,265.252) ; J1_PCIE4.35@162.75,272.636 v1(162.75,273.326) ; v1(163.169,365.505) J1_PCIE0.16@163.169,366.195 ; J1_PCIE4.40@164.737,264.563 v1(164.737,265.252) ; J1_PCIE4.41@165.137,272.636 v1(165.137,273.326) ; J1_PCIE0.10@165.537,367.725 v1(165.537,368.414) ; v1(165.937,357.478) J1_PCIE0.9@165.937,358.168 ; J1_PCIE0.8@166.337,367.725 v1(166.337,368.414) ; v1(167.137,262.461) J1_PCIE4.46@167.137,263.151 ; J1_PCIE0.6@167.137,367.725 v1(167.137,368.414) ; v1(168.277,357.478) J1_PCIE0.3@168.277,358.168 ; v1(169.137,357.479) J1_PCIE0.1@169.137,358.168 ; J1_PCIE4.52@169.558,264.563 v1(169.558,265.252) ; v1(170.668,272.831) J1_PCIE4.M@171.357,272.831 ; v1(170.683,271.294) J1_PCIE4.M@171.372,271.294 ; J1_PCIE0.M@172.995,359.832 v1(173.684,359.832) ; J1_PCIE0.M@173.019,358.046 v1(173.708,358.046) ; C251.1@175.446,329.956 v1(175.936,329.956) ; R720.2@187.819,358.229 188.002,358.046 v1(188.002,357.403) ; v1(194.589,258.603) S6.2@195.279,258.603 ; v1(196.38,359.575) 196.38,359.372 196.623,359.129 U43.9@197.818,359.129 ; v1(197.164,359.779) U43.10@197.854,359.779 ; C609.1@200.859,163.302 v1(200.859,163.992) ; S6.1@203.859,258.603 v1(204.549,258.603) ; v1(217.386,163.309) BT1.1@218.075,163.309 ; v1(223.34,359.292) J1_PCIE2.M@224.029,359.292 ; v1(223.34,359.832) J1_PCIE2.M@224.029,359.832 ; v1(223.821,270.167) J1_PCIE1.M@224.511,270.167 ; v1(223.821,272.523) J1_PCIE1.M@224.511,272.523 ; J1_PCIE2.52@227.89,367.623 v1(227.89,368.313) ; v1(228.29,270.572) J1_PCIE1.1@228.29,271.261 ; v1(229.09,270.574) J1_PCIE1.3@229.09,271.263 ; v1(230.29,262.364) J1_PCIE1.6@230.29,263.053 ; J1_PCIE2.46@230.29,367.623 v1(230.29,368.313) ; v1(231.09,262.364) J1_PCIE1.8@231.09,263.053 ; v1(231.49,270.574) J1_PCIE1.9@231.49,271.263 ; v1(231.857,262.364) J1_PCIE1.10@231.857,263.053 ; J1_PCIE2.41@232.29,359.479 v1(232.29,360.168) ; J1_PCIE2.40@232.69,367.6 v1(232.69,368.29) ; v1(234.306,262.364) J1_PCIE1.16@234.306,263.053 ; J1_PCIE2.35@234.7,359.479 v1(234.7,360.168) ; J1_PCIE2.34@235.09,367.6 v1(235.09,368.29) ; J1_PCIE2.29@237.09,359.479 v1(237.09,360.168) ; v1(237.279,337.358) S2.4@237.968,337.358 ; v1(237.279,338.118) S2.4@237.968,338.118 ; J1_PCIE2.28@237.49,367.6 v1(237.49,368.29) ; v1(237.874,270.574) J1_PCIE1.17@237.874,271.263 ; J1_PCIE2.23@239.49,359.479 v1(239.49,360.168) ; v1(239.89,262.364) J1_PCIE1.22@239.89,263.053 ; J1_PCIE2.22@239.89,367.623 v1(239.89,368.313) ; v4(239.89,263.794) v4(239.89,264.368) 239.89,265.225 240.29,265.625 242.029,265.625 242.329,265.325 242.329,263.833 v4(242.29,263.794) ; v1(240.29,270.574) J1_PCIE1.23@240.29,271.263 ; J1_PCIE2.17@241.89,359.479 v1(241.89,360.168) ; v1(242.653,270.574) J1_PCIE1.29@242.653,271.263 ; v1(244.702,262.364) J1_PCIE1.34@244.702,263.053 ; v1(245.102,270.574) J1_PCIE1.35@245.102,271.263 ; J1_PCIE2.16@245.49,367.623 v1(245.49,368.313) ; S2.3@246.399,337.358 v1(247.088,337.358) ; S2.3@246.399,338.118 v1(247.088,338.118) ; v1(247.09,262.364) J1_PCIE1.40@247.09,263.053 ; v1(247.49,270.574) J1_PCIE1.41@247.49,271.263 ; J1_PCIE2.10@247.89,367.6 v1(247.89,368.29) ; v1(248.29,351.114) U74.3@248.979,351.114 ; J1_PCIE2.9@248.29,359.479 v1(248.29,360.168) ; J1_PCIE2.8@248.69,367.6 v1(248.69,368.29) ; J1_PCIE2.6@249.49,367.6 v1(249.49,368.29) ; v1(249.551,262.364) J1_PCIE1.46@249.551,263.053 ; J1_PCIE2.3@250.69,359.479 v1(250.69,360.168) ; J1_PCIE2.1@251.56,359.479 v1(251.56,360.168) ; v1(251.941,262.364) J1_PCIE1.52@251.941,263.053 ; v1(252.416,166.74) S4.4@252.416,167.429 ; S4.3@252.416,176.288 v1(252.416,176.978) ; C735.2@254.044,349.783 C735.2@254.297,349.783 v1(254.733,349.783) ; J1_PCIE2.M@255.202,359.392 v1(255.891,359.392) ; J1_PCIE2.M@255.202,360.168 v1(255.891,360.168) ; J1_PCIE1.M@255.609,270.167 v1(256.298,270.167) ; J1_PCIE1.M@255.609,272.7 v1(256.298,272.7) ; v1(257.137,156.316) C672.1@257.137,157.006 ; v1(258.093,166.637) 258.093,167.326 ; S3.3@258.093,176.288 v1(258.093,176.978) ; v1(258.123,156.316) C672.1@258.123,157.006 ; v1(259.004,156.316) C672.1@259.004,157.006 ; v1(266.306,346.354) R714.1@266.306,346.934 R714.1@266.306,347.044
  L16 w0.5: v1(42.103,358.861) T54.2@42.103,359.425 ; J32.10@58.904,287.647 J32.10@59.574,287.647 ; T53.2@117.47,443.352 v1(117.47,443.916) ; v1(117.78,249.187) 118.113,249.187 118.319,248.98 ; v1(120.739,394.945) T52.2@120.739,395.509 ; 121.267,387.34 121.27,387.337 v1(121.907,387.337) ; v1(140.907,285.966) 141.681,286.74 C765.1@141.681,286.846 ; v4(175.446,334.497) 175.446,334.741 175.69,334.985 C241.1@175.69,335.035 ; T56.2@199.82,399.561 v1(199.82,400.125) ; T50.2@199.885,405.9 v1(199.885,406.464) ; C631.1@200.192,300.723 201.028,300.723 v10(201.041,300.736) ; C759.1@200.479,295.63 v10(201.625,295.631) ; C756.1@200.479,298.2 201.566,298.2 v10(201.574,298.209) ; C536.1@202.232,314.782 202.232,314.549 v1@202.414,314.367 ; FB41.1@204.466,300.965 v10(205.905,300.965) ; v1(205.454,314.002) 205.454,314.829 C535.1@205.457,314.832 ; v1(255.691,350.391) 256.417,349.666 256.417,349.616 ; C790.2@255.918,348.767 C790.2@255.918,348.902 255.918,349.117 256.417,349.616 ; U76.3@257.78,349.616 256.417,349.616
  L16 w1: R764.1@29.111,218.554 v9(29.111,221.701) ; J27.M@138.619,326.974 v9(140.558,326.974) v9@140.893,326.974
  other v1: 47.96,152.11 47.96,153.126 48.009,154.269 35.693,160.603 36.635,160.603 43.908,172.073 53.258,175.106 43.851,176.479 43.574,180.911 49.99,231.601 53.08,231.693 75.092,233.907 76.352,233.907 77.612,233.907 78.872,233.907 82.032,233.914 83.292,233.914 84.552,233.914 85.812,233.914 87.072,234.379 88.332,234.379 89.591,234.379 90.851,234.379 92.111,234.379 93.371,234.379 94.631,234.379 95.891,234.379 97.151,234.379 98.4,234.848 99.089,234.848 99.779,234.848 100.469,234.848 101.159,234.848 101.848,234.848 102.538,234.848 103.228,234.848 103.918,234.848 104.607,234.848 105.297,234.848 105.987,234.848 106.677,234.848 107.366,234.848 108.056,234.848 108.746,234.848 109.436,234.848 110.125,234.848 110.815,234.848 111.505,234.848 112.195,234.848 75.092,235.632 76.352,235.632 77.612,235.632 78.872,235.632 80.488,235.639 82.032,235.639 83.292,235.639 84.552,235.639 85.812,235.639 87.072,235.639 88.332,235.639 89.591,235.639 90.851,235.639 92.111,235.639 93.371,235.639 94.631,235.639 95.891,235.639 97.151,235.639 98.411,235.639 99.101,235.639 99.79,235.639 100.48,235.639 101.17,235.639 101.86,235.639 102.55,235.639 103.239,235.639 103.929,235.639 104.619,235.639 105.309,235.639 105.998,235.639 106.688,235.639 107.378,235.639 108.068,235.639 108.757,235.639 109.447,235.639 110.137,235.639 110.827,235.639 111.516,235.639 112.206,235.639 98.411,236.461 99.101,236.461 99.79,236.461 100.48,236.461 101.17,236.461 101.86,236.461 102.55,236.461 103.239,236.461 103.929,236.461 104.619,236.461 105.309,236.461 105.998,236.461 106.688,236.461 107.378,236.461 108.068,236.461 108.757,236.461 109.447,236.461 110.137,236.461 110.827,236.461 111.516,236.461 112.206,236.461 87.072,236.899 88.332,236.899 89.591,236.899 90.851,236.899 92.111,236.899 93.371,236.899 94.631,236.899 95.891,236.899 97.151,236.899 75.129,237.339 76.389,237.339 77.649,237.339 78.909,237.339 82.069,237.346 83.328,237.346 84.588,237.346 85.848,237.346 50.838,255.92 47.42,258.837 161.123,285.898 179.397,294.539 179.397,296.539 182.397,296.539 173.397,298.539 175.397,298.539 177.397,298.539 179.397,298.539 181.397,298.539 172.397,299.539 174.397,299.539 176.397,299.539 178.397,299.539 180.397,299.539 173.397,300.539 175.397,300.539 177.397,300.539 179.397,300.539 181.397,300.539 174.397,301.539 180.397,301.539 173.397,302.539 175.397,302.539 181.397,302.539 189.397,302.539 172.397,303.539 174.397,303.539 176.397,303.539 178.397,303.539 180.397,303.539 173.397,304.539 177.397,304.539 183.397,304.539 180.397,305.539 185.397,305.539 177.397,306.539 182.397,306.539 179.397,307.539 181.397,308.539 174.397,312.539 179.397,312.539 173.397,313.539 174.397,313.539 181.397,313.539 202.414,314.504 174.397,314.539 178.397,314.539 174.397,315.539 180.397,315.539 174.397,316.539 177.397,316.539 173.397,317.539 174.397,317.539 118.496,317.771 46.455,318.976 209.258,321.414 206.467,323.991 202.603,326.479 199.72,329.552 165.671,330.06 209.918,331.845 42.14,337.739 92.218,389.711
  other v2: 107.674,272.885 108.712,272.885 105.454,273.887 106.549,273.887 104.55,283.821 105.584,283.821 106.595,283.821
  other v3: 242.725,157.581 243.825,157.581 47.443,157.653 48.543,157.653 49.643,157.653 50.743,157.653 242.725,158.682 243.825,158.682 47.443,158.753 48.543,158.753 49.643,158.753 50.743,158.753 47.443,159.853 48.543,159.853 49.643,159.853 50.743,159.853 47.443,160.953 48.543,160.953 49.643,160.953 50.743,160.953 173.278,168.35 174.378,168.35 173.278,169.45 174.378,169.45 173.278,170.55 174.378,170.55 138.266,177.915 139.366,177.915 140.466,177.915 141.566,177.915 138.266,179.015 139.366,179.015 140.466,179.015 141.566,179.015 138.266,180.115 139.366,180.115 140.466,180.115 141.566,180.115 138.266,181.215 139.366,181.215 140.466,181.215 141.566,181.215 129.479,205.178 130.579,205.178 131.679,205.178 132.779,205.178 129.479,206.278 130.579,206.278 131.679,206.278 132.779,206.278 129.479,207.378 130.579,207.378 131.679,207.378 132.779,207.378 129.479,208.478 130.579,208.478 131.679,208.478 132.779,208.478 128.055,234.843 129.155,234.843 128.055,235.943 129.155,235.943 125.813,244.192 197.289,244.76 198.389,244.76 199.489,244.76 200.589,244.76 124.968,245.039 125.813,245.039 126.638,245.039 197.289,245.86 198.389,245.86 199.489,245.86 200.589,245.86 125.813,245.889 197.289,246.96 198.389,246.96 199.489,246.96 200.589,246.96 197.289,248.06 198.389,248.06 199.489,248.06 200.589,248.06 146.222,250.081 147.322,250.081 148.422,250.081 149.522,250.081 92.069,250.563 93.069,250.563 146.222,251.181 147.322,251.181 148.422,251.181 149.522,251.181 92.069,251.563 93.069,251.563 103.995,251.848 104.995,251.848 98.601,251.871 99.601,251.871 146.222,252.281 147.322,252.281 148.422,252.281 149.522,252.281 103.995,252.848 104.995,252.848 98.601,252.871 99.601,252.871 146.222,253.381 147.322,253.381 148.422,253.381 149.522,253.381 111.348,260.318 112.448,260.318 113.548,260.318 114.648,260.318 111.348,261.418 112.448,261.418 113.548,261.418 114.648,261.418 111.348,262.518 112.448,262.518 113.548,262.518 114.648,262.518 111.348,263.618 112.448,263.618 113.548,263.618 114.648,263.618 107.614,276.725 108.984,276.725 106.499,277.84 107.614,277.84 108.984,277.84 110.099,277.84 106.499,279.21 107.614,279.21 108.984,279.21 110.099,279.21 107.614,280.325 108.984,280.325 150.014,281.103 151.814,281.103 150.014,282.904 151.814,282.904 87.535,302.498 86.69,303.346 87.535,303.346 88.36,303.346 87.535,304.196 38.177,310.803 39.277,310.803 40.377,310.803 41.477,310.803 38.177,311.903 39.277,311.903 40.377,311.903 41.477,311.903 38.177,313.003 39.277,313.003 40.377,313.003 41.477,313.003 38.177,314.103 39.277,314.103 40.377,314.103 41.477,314.103 109.993,318.876 110.993,318.876 109.993,319.876 110.993,319.876 119.109,339.319 120.109,339.319 119.109,340.319 120.109,340.319 75.813,341.039 76.913,341.039 78.013,341.039 79.113,341.039 75.813,342.139 76.913,342.139 78.013,342.139 79.113,342.139 75.813,343.239 76.913,343.239 78.013,343.239 79.113,343.239 75.813,344.339 76.913,344.339 78.013,344.339 79.113,344.339 53.575,345.561 54.595,345.561 55.615,345.561 56.635,345.561 53.575,346.581 54.595,346.581 55.615,346.581 56.635,346.581 53.575,347.601 55.615,347.601 56.635,347.601 53.575,348.621 54.595,348.621 55.615,348.621 56.635,348.621 149.744,348.735 150.744,348.735 149.744,349.735 150.744,349.735 206.78,367.29 207.88,367.29 208.98,367.29 210.08,367.29 206.78,368.39 207.88,368.39 208.98,368.39 210.08,368.39 206.78,369.49 207.88,369.49 208.98,369.49 210.08,369.49 206.78,370.59 207.88,370.59 208.98,370.59 210.08,370.59 113.78,377.007 114.88,377.007 115.98,377.007 117.08,377.007 113.78,378.107 114.88,378.107 115.98,378.107 117.08,378.107 113.78,379.207 114.88,379.207 115.98,379.207 117.08,379.207 113.78,380.307 114.88,380.307 115.98,380.307 117.08,380.307 102.07,385.766 101.225,386.613 102.07,386.613 102.895,386.613 102.07,387.463
  other v4: 257.503,157.242 258.076,157.242 258.65,157.242 220.616,162.761 246.516,162.761 220.616,163.335 220.616,163.909 147.937,263.22 148.737,263.22 149.537,263.22 151.937,263.22 157.537,263.22 159.937,263.22 162.337,263.22 164.737,263.22 167.137,263.22 169.537,263.22 230.29,263.22 231.09,263.22 231.89,263.22 234.29,263.22 239.89,263.22 242.29,263.22 244.69,263.22 247.09,263.22 249.49,263.22 251.89,263.22 147.937,263.794 148.737,263.794 149.537,263.794 151.937,263.794 157.537,263.794 159.937,263.794 162.337,263.794 164.737,263.794 167.137,263.794 169.537,263.794 230.29,263.794 231.09,263.794 231.89,263.794 234.29,263.794 244.69,263.794 247.09,263.794 249.49,263.794 251.89,263.794 147.937,264.368 148.737,264.368 149.537,264.368 151.937,264.368 157.537,264.368 159.937,264.368 162.337,264.368 164.737,264.368 167.137,264.368 169.537,264.368 230.29,264.368 231.09,264.368 231.89,264.368 234.29,264.368 242.29,264.368 244.69,264.368 247.09,264.368 249.49,264.368 251.89,264.368 142.513,271.394 143.087,271.394 143.661,271.394 224.866,271.394 225.44,271.394 226.014,271.394 145.937,271.42 146.737,271.42 149.137,271.42 155.537,271.42 157.937,271.42 160.337,271.42 162.737,271.42 165.137,271.42 228.29,271.42 229.09,271.42 231.49,271.42 237.89,271.42 240.29,271.42 242.69,271.42 245.09,271.42 247.49,271.42 171.813,271.494 172.387,271.494 172.961,271.494 254.166,271.494 254.74,271.494 255.314,271.494 145.937,271.994 146.737,271.994 149.137,271.994 155.537,271.994 157.937,271.994 160.337,271.994 162.737,271.994 165.137,271.994 228.29,271.994 229.09,271.994 231.49,271.994 237.89,271.994 240.29,271.994 242.69,271.994 245.09,271.994 247.49,271.994 145.937,272.568 146.737,272.568 149.137,272.568 155.537,272.568 157.937,272.568 160.337,272.568 162.737,272.568 165.137,272.568 228.29,272.568 229.09,272.568 231.49,272.568 237.89,272.568 240.29,272.568 242.69,272.568 245.09,272.568 247.49,272.568 144.564,281.262 144.564,281.836 144.564,282.41 150.891,289.583 150.891,290.157 150.891,290.731 150.828,293.076 150.828,293.649 150.828,294.223 150.768,296.797 150.768,297.37 150.768,297.944 150.739,300.454 150.739,301.028 150.739,301.602 137.473,305.941 138.047,305.941 138.62,305.941 139.194,305.941 139.768,305.941 137.473,306.514 138.047,306.514 138.62,306.514 139.194,306.514 139.768,306.514 137.27,307.374 137.843,307.374 138.417,307.374 137.27,307.874 137.843,307.874 138.417,307.874 137.27,308.374 137.843,308.374 138.417,308.374 137.27,311.874 137.843,311.874 138.417,311.874 137.27,313.374 137.843,313.374 138.417,313.374 137.27,314.874 137.843,314.874 138.417,314.874 137.27,316.374 137.843,316.374 138.417,316.374 137.27,317.874 137.843,317.874 138.417,317.874 137.27,319.374 137.843,319.374 138.417,319.374 137.27,320.874 137.843,320.874 138.417,320.874 137.27,322.374 137.843,322.374 138.417,322.374 137.27,323.874 137.844,323.874 138.417,323.874 137.294,325.364 137.844,325.374 138.418,325.374 137.287,325.869 137.844,325.874 138.418,325.874 137.453,326.555 138.026,326.555 138.6,326.555 139.174,326.555 139.748,326.555 137.453,327.129 138.026,327.129 138.6,327.129 139.174,327.129 139.748,327.129 174.666,327.685 195.927,328.06 174.666,328.821 195.889,329.24 187.156,330.022 195.927,330.2 174.666,331.091 186.376,331.188 199.787,332.092 195.787,332.118 174.666,332.227 187.156,332.353 195.74,332.943 200.567,333.083 174.666,333.362 186.376,333.518 197.621,333.807 196.841,334.62 196.841,335.42 41.573,350.698 67.585,358.218 69.985,358.218 72.385,358.218 74.785,358.218 77.185,358.218 83.585,358.218 85.985,358.218 86.785,358.218 149.937,358.218 152.337,358.218 154.737,358.218 157.137,358.218 159.537,358.218 165.937,358.218 168.337,358.218 169.137,358.218 232.29,358.218 234.69,358.218 237.09,358.218 239.49,358.218 241.89,358.218 248.29,358.218 250.69,358.218 251.49,358.218 67.585,358.792 69.985,358.792 72.385,358.792 83.585,358.792 85.985,358.792 86.785,358.792 149.937,358.792 152.337,358.792 154.737,358.792 157.137,358.792 159.537,358.792 165.937,358.792 168.337,358.792 169.137,358.792 232.29,358.792 234.69,358.792 237.09,358.792 239.49,358.792 241.89,358.792 248.29,358.792 250.69,358.792 251.49,358.792 59.761,359.292 60.335,359.292 60.909,359.292 142.113,359.292 142.687,359.292 143.261,359.292 224.466,359.292 225.04,359.292 225.614,359.292 67.585,359.366 69.985,359.366 72.385,359.366 83.585,359.366 85.985,359.366 86.785,359.366 149.937,359.366 152.337,359.366 154.737,359.366 157.137,359.366 159.537,359.366 165.937,359.366 168.337,359.366 169.137,359.366 232.29,359.366 234.69,359.366 237.09,359.366 239.49,359.366 241.89,359.366 248.29,359.366 250.69,359.366 251.49,359.366 89.061,359.392 89.635,359.392 90.209,359.392 171.413,359.392 171.987,359.392 172.561,359.392 253.766,359.392 254.34,359.392 254.914,359.392 63.185,366.418 65.585,366.418 67.985,366.418 70.385,366.418 72.785,366.418 75.185,366.418 80.785,366.418 83.185,366.418 83.985,366.418 84.785,366.418 145.537,366.418 147.937,366.418 150.337,366.418 152.737,366.418 155.137,366.418 157.537,366.418 165.537,366.418 166.337,366.418 167.137,366.418 227.89,366.418 230.29,366.418 232.69,366.418 235.09,366.418 237.49,366.418 239.89,366.418 245.49,366.418 247.89,366.418 248.69,366.418 249.49,366.418 63.185,366.992 65.585,366.992 67.985,366.992 70.385,366.992 72.785,366.992 80.785,366.992 83.185,366.992 83.985,366.992 84.785,366.992 145.537,366.992 147.937,366.992 150.337,366.992 152.737,366.992 155.137,366.992 157.537,366.992 165.537,366.992 166.337,366.992 167.137,366.992 227.89,366.992 230.29,366.992 232.69,366.992 235.09,366.992 237.49,366.992 239.89,366.992 245.49,366.992 247.89,366.992 248.69,366.992 249.49,366.992 63.185,367.566 65.585,367.566 67.985,367.566 70.385,367.566 72.785,367.566 80.785,367.566 83.185,367.566 83.985,367.566 84.785,367.566 145.537,367.566 147.937,367.566 150.337,367.566 152.737,367.566 155.137,367.566 157.537,367.566 165.537,367.566 166.337,367.566 167.137,367.566 227.89,367.566 230.29,367.566 232.69,367.566 235.09,367.566 237.49,367.566 239.89,367.566 245.49,367.566 247.89,367.566 248.69,367.566 249.49,367.566
  other v5: 146.952,284.103 147.853,284.103 147.408,284.429 146.952,284.772 147.853,284.772 149.538,285.388 182.902,285.514 162.395,288.539 164.396,288.539 166.395,288.539 168.396,288.539 170.395,288.539 172.395,288.539 174.395,288.539 176.395,288.539 178.396,288.539 180.395,288.539 162.395,289.539 164.396,289.539 166.395,289.539 168.396,289.539 170.395,289.539 172.395,289.539 174.395,289.539 176.395,289.539 178.396,289.539 180.395,289.539 181.395,289.539 188.397,289.539 163.395,290.539 165.395,290.539 167.395,290.539 169.396,290.539 171.395,290.539 173.396,290.539 175.395,290.539 177.395,290.539 179.395,290.539 181.395,290.539 190.397,290.539 163.395,291.539 165.395,291.539 167.395,291.539 169.396,291.539 171.395,291.539 173.396,291.539 175.395,291.539 177.395,291.539 179.395,291.539 181.395,291.539 162.395,292.539 164.396,292.539 166.395,292.539 168.396,292.539 170.395,292.539 172.395,292.539 174.395,292.539 176.395,292.539 178.396,292.539 180.395,292.539 181.395,292.539 180.395,293.539 163.395,294.539 165.395,294.539 167.395,294.539 169.396,294.539 173.396,294.539 175.395,294.539 177.395,294.539 178.396,294.539 183.397,294.539 177.395,295.539 190.397,295.539 162.397,296.539 164.397,296.539 166.395,296.539 168.396,296.539 170.395,296.539 171.395,296.539 172.395,296.539 173.396,296.539 174.395,296.539 175.395,296.539 176.395,296.539 187.397,296.539 170.395,297.539 188.397,299.539 163.397,300.539 190.397,300.539 164.397,302.539 186.397,303.539 163.397,304.539 175.397,304.539 190.395,305.539 190.397,310.539 168.396,311.539 172.395,311.539 174.395,311.539 177.395,311.539 187.401,311.535 171.397,313.539 176.395,313.539 167.395,315.539 190.397,315.539 123.938,316.6 162.395,317.539 122.938,317.6 125.438,318.1 120.938,318.6 127.438,318.6 121.438,319.1 123.438,319.1 124.438,319.1 120.938,319.6 126.438,319.6 121.438,320.6 162.507,327.914 178.336,328.06 194.597,328.06 201.257,328.06 206.057,328.06 175.3,328.509 187.059,328.509 194.597,328.86 162.526,329.197 186.186,329.527 208.94,329.599 200.457,329.66 178.336,330.46 201.257,330.46 186.966,330.606 198.044,330.675 172.476,331.26 182.336,331.26 201.257,331.26 186.211,331.61 172.476,332.06 195.397,332.06 174.726,332.21 186.062,332.702 178.336,332.86 201.257,332.86 172.476,333.66 195.392,333.667 197.82,333.654 206.857,333.66 185.999,333.686 197.57,334.638 187.049,334.718 166.076,335.26 172.476,335.26 177.536,335.26 183.936,335.26 195.392,335.267 200.457,335.26 187.049,335.75 175.423,335.857 209.584,336.106 177.536,336.86 174.719,336.877 209.644,337.236 172.476,337.66 195.397,337.66 187.073,337.795 187.048,338.696 175.366,339.216 186.027,339.598 172.476,340.06 183.936,340.06 195.392,340.067 175.48,340.239 186.051,340.514 175.405,342.113
  other v8: 124.709,154.461 126.253,154.716 123.437,155.372 127.164,155.988 184.08,156.429 185.623,156.684 123.182,156.915 182.808,157.34 126.909,157.531 186.534,157.956 124.093,158.187 125.637,158.442 182.553,158.884 186.279,159.5 183.464,160.155 185.007,160.411 280.028,165.878 281.572,166.133 278.757,166.789 282.483,167.405 278.501,168.332 282.228,168.948 279.412,169.604 280.956,169.859 149.028,197.399 150.571,197.654 147.756,198.31 151.482,198.926 147.501,199.854 151.227,200.47 148.412,201.126 149.955,201.381 126.273,212.629 188.273,212.629 208.626,212.629 270.626,212.629 127.817,212.884 189.817,212.884 210.17,212.884 272.17,212.884 125.002,213.54 187.001,213.54 207.354,213.54 269.354,213.54 128.728,214.156 190.728,214.156 211.081,214.156 273.081,214.156 124.746,215.084 186.746,215.084 207.099,215.084 269.099,215.084 128.473,215.7 190.473,215.7 210.826,215.7 272.826,215.7 125.657,216.356 187.657,216.355 208.01,216.355 270.01,216.356 127.201,216.611 189.201,216.611 209.554,216.611 271.554,216.611 89.033,263.459 90.577,263.714 87.761,264.37 91.488,264.986 87.506,265.913 91.233,266.529 88.417,267.185 89.961,267.44 239.598,317.251 102.743,317.351 241.141,317.506 104.286,317.606 238.326,318.162 101.471,318.262 242.052,318.778 105.197,318.878 238.071,319.706 101.216,319.805 241.797,320.321 104.942,320.421 238.982,320.977 102.127,321.077 240.525,321.232 103.67,321.332 28.962,332.654 30.506,332.909 27.69,333.565 31.417,334.181 27.435,335.109 31.162,335.725 28.346,336.381 29.89,336.636 180.798,362.271 182.342,362.527 179.526,363.182 183.253,363.798 179.271,364.726 182.998,365.342 180.182,365.998 181.726,366.253 50.629,370.437 52.173,370.692 49.357,371.348 53.084,371.964 49.102,372.891 52.828,373.507 50.013,374.163 51.557,374.418 277.45,379.149 278.994,379.404 276.178,380.06 279.905,380.676 275.923,381.603 279.65,382.219 276.834,382.875 278.378,383.13 43.521,414.176 105.521,414.175 125.873,414.176 187.873,414.175 208.226,414.175 270.227,414.175 45.065,414.431 107.064,414.43 127.417,414.431 189.417,414.43 209.769,414.43 271.77,414.431 42.249,415.087 104.249,415.086 124.601,415.087 186.601,415.086 206.954,415.086 268.955,415.086 45.976,415.703 107.975,415.702 128.328,415.702 190.328,415.702 210.68,415.702 272.681,415.702 41.994,416.63 103.994,416.63 124.346,416.63 186.346,416.629 206.699,416.629 268.7,416.63 45.721,417.246 107.72,417.246 128.073,417.246 190.073,417.245 210.425,417.245 272.426,417.246 42.905,417.902 104.905,417.902 125.257,417.902 187.257,417.901 207.61,417.901 269.611,417.902 44.449,418.157 106.448,418.157 126.801,418.157 188.801,418.156 209.153,418.156 271.154,418.157 33.356,448.186 113.468,448.288 34.9,448.441 198.609,448.491 115.011,448.543 200.152,448.746 32.084,449.097 112.196,449.199 197.337,449.402 35.811,449.713 115.922,449.815 201.063,450.018 277.958,450.384 31.829,450.641 279.502,450.639 111.941,450.742 197.082,450.945 35.556,451.257 276.686,451.295 115.667,451.358 200.808,451.561 32.74,451.913 280.413,451.911 112.852,452.014 34.284,452.168 197.993,452.217 114.395,452.269 199.536,452.472 276.431,452.839 280.158,453.454 277.342,454.11 278.886,454.365
  other v9: 29.108,215.328
  other v10: 90.217,160.805 94.153,160.805 98.089,160.805 102.025,160.805 105.961,160.805 109.897,160.805 113.833,160.805 120.005,160.805 123.603,160.823 88.249,164.274 92.185,164.274 96.121,164.274 100.057,164.274 103.993,164.274 107.929,164.274 111.865,164.274 118.037,164.274 121.564,164.274 91.59,167.488
  other v11: 126.712,190.687 188.712,190.687 209.065,190.687 271.065,190.687 128.187,191.277 190.187,191.277 210.539,191.277 272.539,191.277 125.252,191.312 187.252,191.312 207.605,191.312 269.605,191.312 128.812,192.737 190.812,192.737 211.165,192.737 273.165,192.737 124.662,192.787 186.662,192.787 207.015,192.787 269.015,192.787 128.222,194.211 190.222,194.211 210.575,194.211 272.575,194.211 125.288,194.247 187.288,194.247 207.64,194.247 269.64,194.247 126.762,194.837 188.762,194.837 209.115,194.837 271.115,194.837 126.712,220.687 188.712,220.687 209.065,220.687 271.065,220.687 128.187,221.277 190.187,221.277 210.539,221.277 272.539,221.277 125.252,221.312 187.252,221.312 207.605,221.312 269.605,221.312 128.812,222.737 190.812,222.737 211.165,222.737 273.165,222.737 124.662,222.787 186.662,222.787 207.015,222.787 269.015,222.787 128.222,224.211 190.222,224.211 210.575,224.211 272.575,224.211 125.288,224.247 187.288,224.247 207.64,224.247 269.64,224.247 126.762,224.837 188.762,224.837 209.115,224.837 271.115,224.837 43.96,405.949 105.96,405.949 126.312,405.949 188.312,405.949 208.665,405.949 270.665,405.949 45.434,406.539 107.434,406.539 127.787,406.539 189.787,406.539 210.139,406.539 272.139,406.539 42.5,406.574 104.5,406.574 124.852,406.574 186.852,406.574 207.205,406.574 269.205,406.574 46.06,407.999 108.06,407.999 128.412,407.999 190.412,407.999 210.765,407.999 272.765,407.999 41.91,408.049 103.91,408.049 124.262,408.049 186.262,408.049 206.615,408.049 268.615,408.049 45.47,409.473 107.47,409.473 127.822,409.473 189.822,409.473 210.175,409.473 272.175,409.473 42.535,409.509 104.535,409.509 124.888,409.509 186.888,409.509 207.24,409.509 269.24,409.509 44.01,410.099 106.01,410.099 126.362,410.099 188.362,410.099 208.715,410.099 270.715,410.099 43.96,435.949 105.96,435.949 126.312,435.949 188.312,435.949 208.665,435.949 270.665,435.949 45.434,436.539 107.434,436.539 127.787,436.539 189.787,436.539 210.139,436.539 272.139,436.539 42.5,436.574 104.5,436.574 124.852,436.574 186.852,436.574 207.205,436.574 269.205,436.574 46.06,437.999 108.06,437.999 128.412,437.999 190.412,437.999 210.765,437.999 272.765,437.999 41.91,438.049 103.91,438.049 124.262,438.049 186.262,438.049 206.615,438.049 268.615,438.049 45.47,439.473 107.47,439.473 127.822,439.473 189.822,439.473 210.175,439.473 272.175,439.473 42.535,439.509 104.535,439.509 124.888,439.509 186.888,439.509 207.24,439.509 269.24,439.509 44.01,440.099 106.01,440.099 126.362,440.099 188.362,440.099 208.715,440.099 270.715,440.099
  other v15: 48.649,152.11 48.685,153.126 48.698,154.269 35.693,159.866 36.624,159.866 125.281,165.479 51.717,167.169 48.606,167.856 116.449,168.06 43.995,171.26 52.55,175.125 47.56,175.75 49.86,175.75 44.801,176.636 45.228,179.634 52.467,231.558 50.578,231.57 50.178,256.055 47.42,257.671 131.355,259.338 131.755,259.338 132.155,259.338 44.356,319.903 45.372,319.903 46.434,319.903 162.41,338.184 162.385,340.36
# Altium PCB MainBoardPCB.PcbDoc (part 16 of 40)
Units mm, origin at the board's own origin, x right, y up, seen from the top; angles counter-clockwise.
Board outline 258.95 x 308.86 mm, 16 copper layers (L1, L2 (GND), L3 (Sign), L4 (GND), L5 (Sign), L6 (PWR/GND), L7(12V+Other), L8 (Plane_GND), L9 (PWR/GND), L10 (3V3+Other), L11 (PWR/GND), L12 (Sign), L13 (GND), L14 (Sign), L15 (GND), L16), stack 2.503 mm thick; 2578 components, 1867 nets, 8817 pads, 8021 vias.
Unrouted connection lines stored in the file: 25.

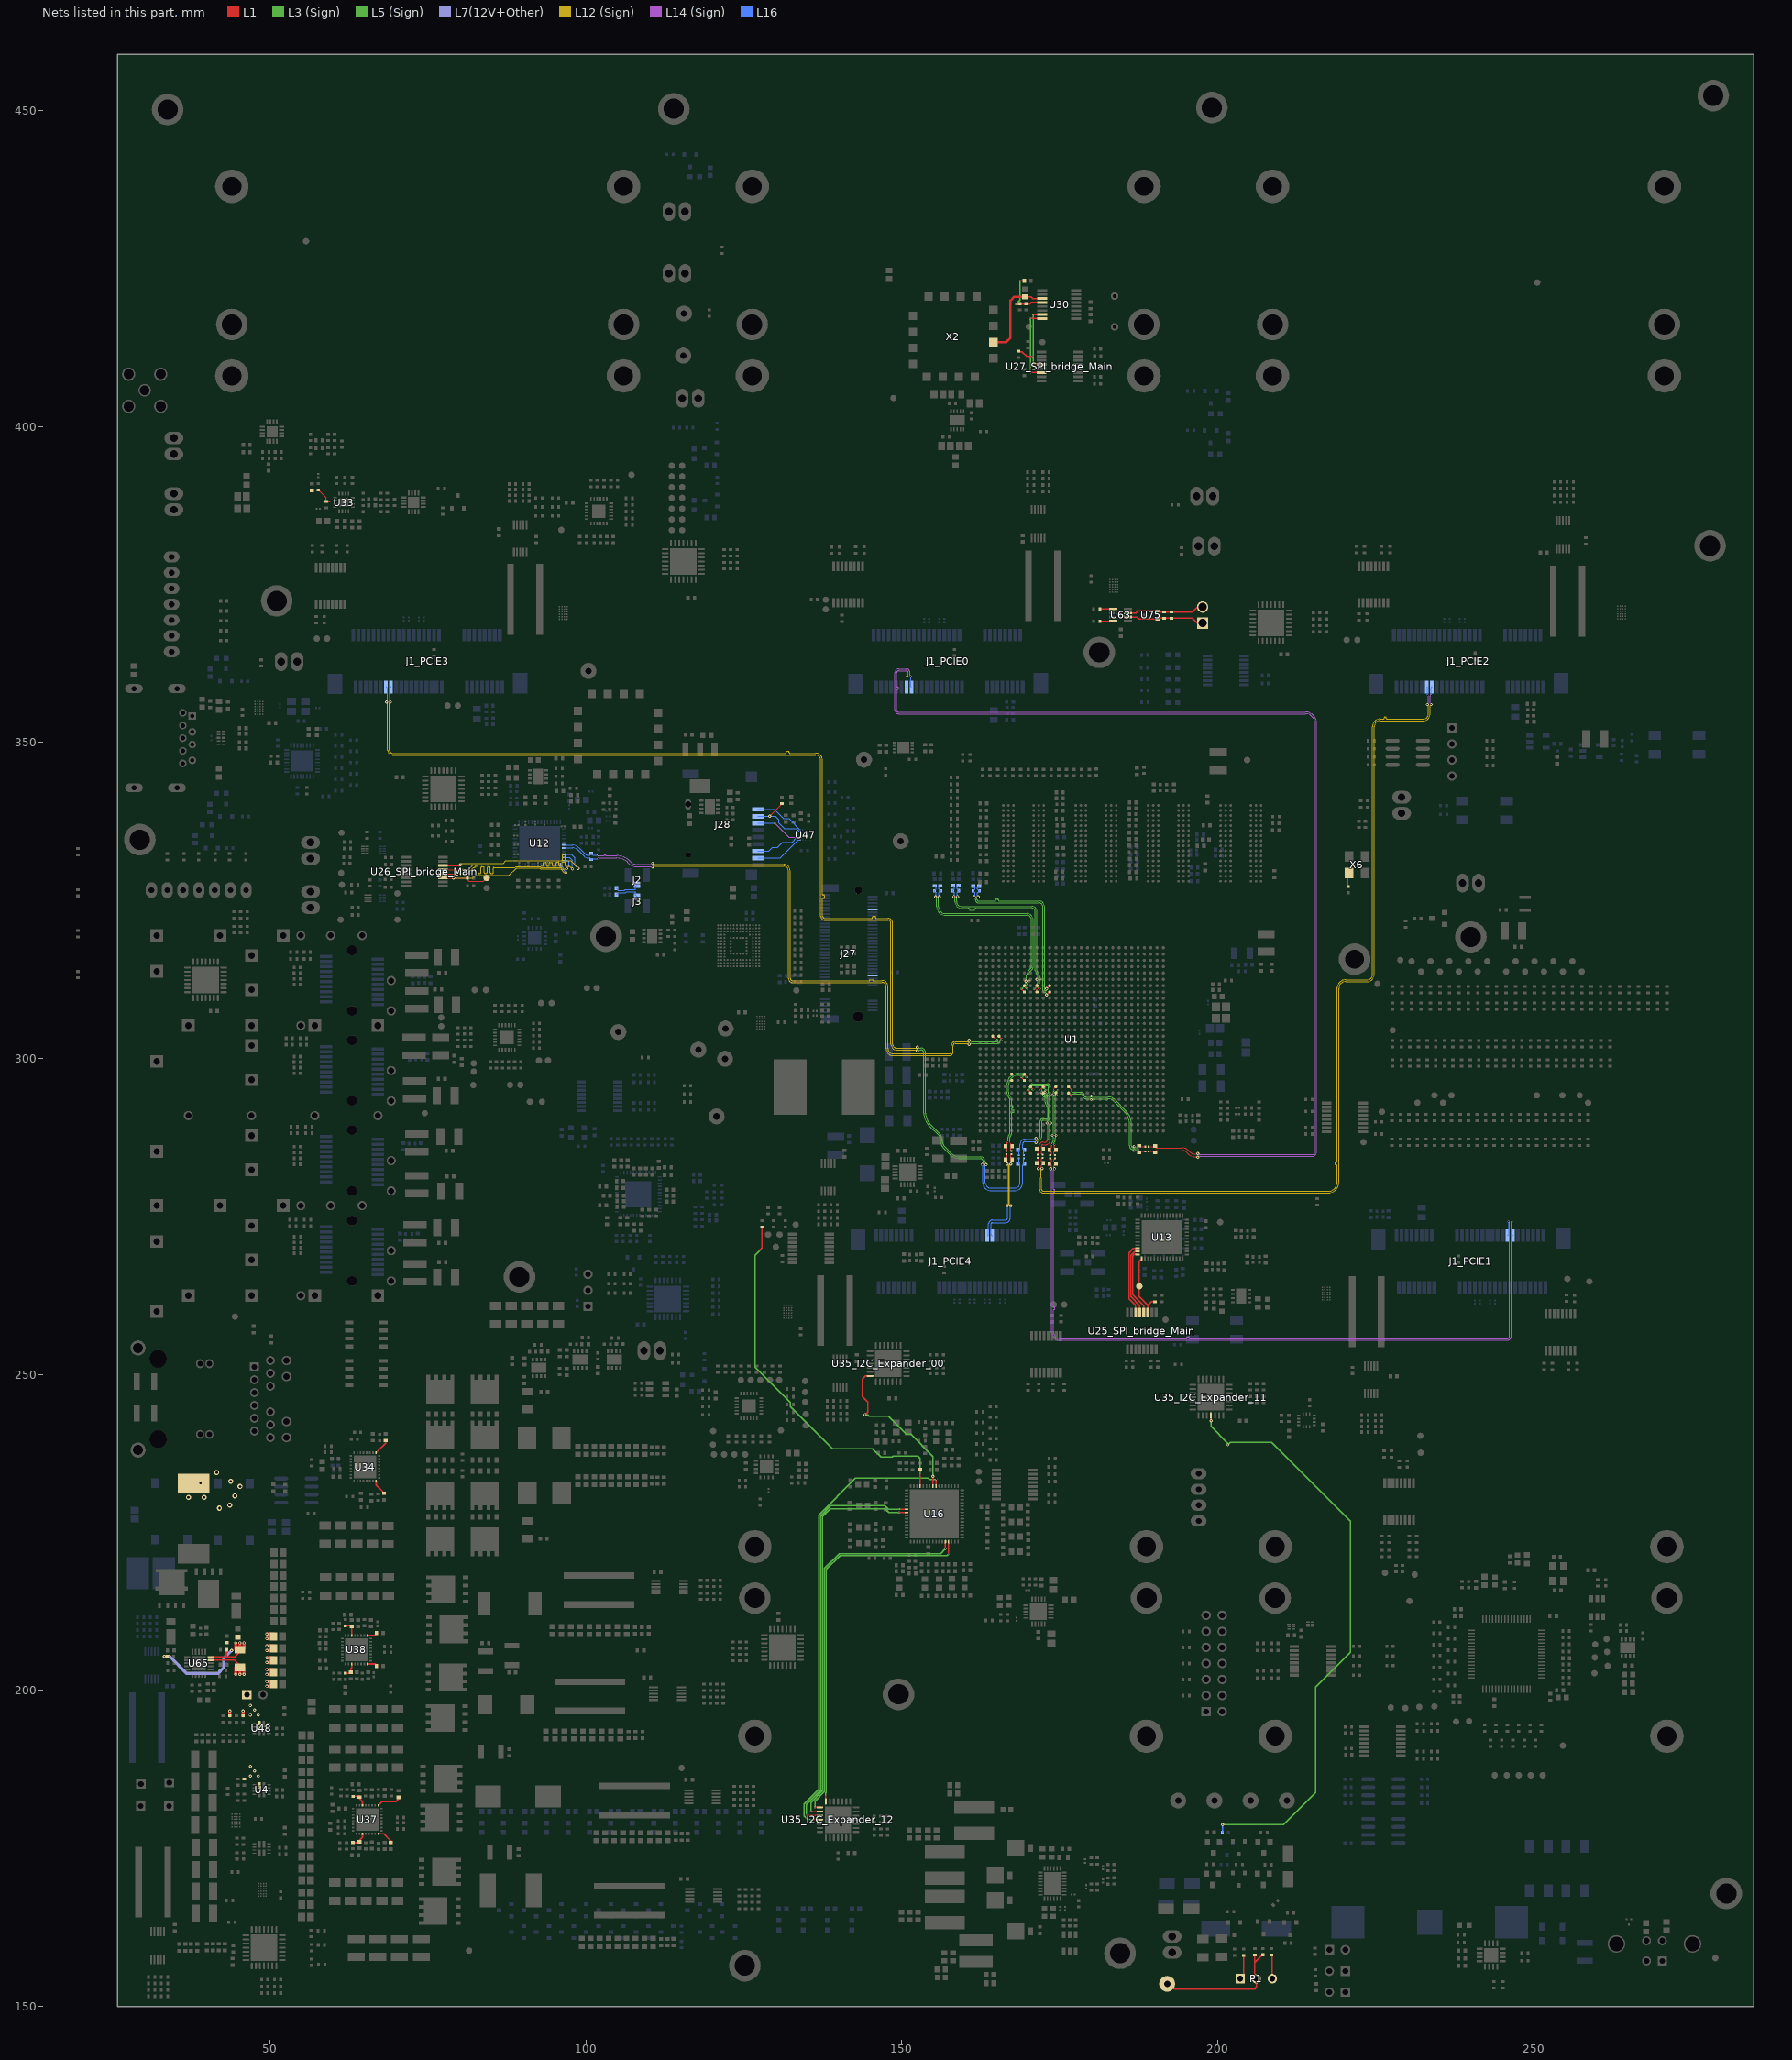
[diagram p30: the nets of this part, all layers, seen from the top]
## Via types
v1: diameter 0.5, hole 0.25, L1 to L16, tented both sides, 4341 vias
v2: diameter 0.254, hole 0.1, L1 to L3 (Sign), tented both sides, 781 vias
v3: diameter 0.5, hole 0.25, L1 to L16, 565 vias
v4: diameter 0.254, hole 0.1, L15 (GND) to L16, tented both sides, 406 vias
v5: diameter 0.254, hole 0.1, L1 to L2 (GND), tented both sides, 283 vias
v6: diameter 0.457, hole 0.2, L3 (Sign) to L6 (PWR/GND), tented both sides, 254 vias
v7: diameter 0.254, hole 0.1, L1 to L3 (Sign), 237 vias
v8: diameter 0.75, hole 0.4, L1 to L16, 200 vias
v9: diameter 0.8, hole 0.4, L1 to L16, tented both sides, 182 vias
v10: diameter 0.254, hole 0.1, L14 (Sign) to L16, tented both sides, 170 vias
v11: diameter 0.75/0/0/0/0/0/0/0/0/0/0/0/0/0/0/0.75 (per signal layer), hole 0.4, L1 to L16, 160 vias
v12: diameter 0.457, hole 0.2, L3 (Sign) to L6 (PWR/GND), 158 vias
v13: diameter 1.4, hole 0.5, L1 to L16, tented both sides, 80 vias
v14: diameter 0.254, hole 0.1, L14 (Sign) to L16, 65 vias
v15: diameter 0.254, hole 0.1, L1 to L2 (GND), 45 vias
v16: diameter 0.457, hole 0.2, L11 (PWR/GND) to L14 (Sign), tented both sides, 26 vias
v17: diameter 0.457, hole 0.2, L11 (PWR/GND) to L14 (Sign), 25 vias
v18: diameter 0.457, hole 0.2, L7(12V+Other) to L10 (3V3+Other), tented both sides, 11 vias
v19: diameter 0.254/0/0.254 (per signal layer), hole 0.1, L1 to L3 (Sign), 9 vias
v20: diameter 0.2/0/0.2 (per signal layer), hole 0.1, L1 to L3 (Sign), 6 vias
v21: diameter 1.65, hole 1.65, L1 to L16, 5 vias
v22: diameter 1.15, hole 1.15, L1 to L16, 5 vias
v23: diameter 0.457, hole 0.2, L1 to L16, 3 vias
v24: diameter 0.5, hole 0.3, L1 to L16, 2 vias
v25: diameter 0.5/0/0.5 (per signal layer), hole 0.2, L14 (Sign) to L16, 1 vias
v26: diameter 0.5, hole 0.25, L1 to L16, tented bottom, 1 vias

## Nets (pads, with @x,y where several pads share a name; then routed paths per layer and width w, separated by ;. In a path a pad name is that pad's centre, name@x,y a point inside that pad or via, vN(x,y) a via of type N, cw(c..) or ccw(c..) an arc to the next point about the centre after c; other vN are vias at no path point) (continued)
Bank223_MGTREF0_C_N: C49.1 C276.1 U1.R7 | length 19.9
  L1 w0.1: U1.R7@176.397,294.539 v2(176.884,294.052)
  L1 w0.101: v7(187.487,285.518) cw(c187.487,285.447) 187.558,285.447 C49.1@187.558,285.139 cw(c187.728,285.139) 187.728,285.308 C276.1@188.517,285.308
  L5 (Sign) w0.081: v12(179.965,293.475) cw(c180.125,293.475) 180.125,293.634 182.625,293.634 cw(c182.625,292.243) 183.609,293.227 185.302,291.533 cw(c183.506,289.737) 186.046,289.737 186.046,286.17 ccw(c186.605,286.17) 186.605,285.612 cw(c186.605,285.472) 186.744,285.472 v12(186.744,285.452)
  L3 (Sign) w0.081: v2(176.884,294.052) 176.884,294.364 176.932,294.411 177.507,294.411 177.517,294.422 178.458,294.422 178.613,294.267 178.613,294.165 ccw(c179.143,294.165) 179.143,293.634 179.806,293.634 cw(c179.806,293.475) v12(179.965,293.475) ; v12(186.744,285.452) cw(c186.904,285.452) 186.904,285.612 187.393,285.612 cw(c187.393,285.518) v7(187.487,285.518)
Bank223_MGTREF0_C_P: C49.2 C273.1 U1.R8 | length 19.8
  L1 w0.1: U1.R8@176.397,295.539 v2(176.884,295.052)
  L1 w0.101: v7(187.487,285.968) ccw(c187.487,286.039) 187.558,286.039 C49.2@187.558,286.189 ccw(c187.691,286.189) 187.691,286.056 C273.1@188.518,286.056
  L5 (Sign) w0.081: v12(179.965,294.075) ccw(c180.125,294.075) 180.125,293.915 182.627,293.915 cw(c182.627,292.247) 183.806,293.427 185.502,291.731 cw(c183.509,289.738) 186.327,289.738 186.327,286.17 ccw(c186.605,286.17) 186.605,285.893 ccw(c186.605,286.032) 186.744,286.032 v12(186.744,286.052)
  L3 (Sign) w0.081: v2(176.884,295.052) 176.884,294.74 176.932,294.692 177.39,294.692 177.401,294.703 178.574,294.703 178.894,294.383 178.894,294.165 ccw(c179.143,294.165) 179.143,293.915 179.806,293.915 ccw(c179.806,294.075) v12(179.965,294.075) ; v12(186.744,286.052) ccw(c186.904,286.052) 186.904,285.893 187.413,285.893 ccw(c187.413,285.968) v7(187.487,285.968)
Bank223_MGTREF0_N: C50.1 C276.2 J1_PCIE0.39 | length 174.1
  L1 w0.101: C276.2@189.037,285.308 189.904,285.308 cw(c189.904,285.114) C50.1@190.098,285.114 cw(c190.423,285.114) 190.423,285.438 194.401,285.438 cw(c194.401,284.417) 195.123,285.139 195.346,284.916 ccw(c196.437,286.008) 196.437,284.464 196.443,284.47 196.623,284.47 cw(c196.623,284.432) 196.649,284.459 196.661,284.447 ccw(c196.846,284.631) v3(196.846,284.37)
  L14 (Sign) w0.081: v10(150.837,360.528) ccw(c150.837,360.687) 150.997,360.687 150.997,361.106 ccw(c150.744,361.106) 150.744,361.358 149.487,361.358 ccw(c149.487,361.071) 149.2,361.071 149.2,359.361 149.2,358.856 ccw(c149.284,358.856) 149.284,358.773 149.386,358.773 cw(c149.386,358.689) 149.47,358.689 149.47,358.521 cw(c149.386,358.521) 149.386,358.437 149.284,358.437 ccw(c149.284,358.354) 149.2,358.354 149.2,357.978 149.2,355.13 ccw(c149.49,355.13) 149.49,354.839 213.88,354.839 cw(c213.88,353.057) 215.662,353.057 215.662,285.257 cw(c214.935,285.257) 214.935,284.53 197.231,284.53 ccw(c197.231,284.221) 197.012,284.439 cw(c196.846,284.606) v3(196.846,284.37)
  L16 w0.101: J1_PCIE0.39@150.737,358.792 ccw(c150.737,358.892) 150.837,358.892 v10(150.837,360.528)
Bank223_MGTREF0_P: C50.2 C273.2 J1_PCIE0.37 | length 174.1
  L1 w0.101: C273.2@189.038,286.056 189.991,286.056 ccw(c189.991,286.164) C50.2@190.098,286.164 ccw(c190.423,286.164) 190.423,285.839 194.403,285.839 cw(c194.403,284.422) 195.405,285.424 195.628,285.201 ccw(c196.438,286.011) 196.438,284.865 196.45,284.877 196.456,284.871 196.623,284.871 ccw(c196.623,284.908) 196.649,284.882 196.661,284.894 cw(c196.846,284.71) v3(196.846,284.97)
  L14 (Sign) w0.081: v10(151.437,360.528) cw(c151.437,360.687) 151.278,360.687 151.278,361.106 ccw(c150.744,361.106) 150.744,361.639 149.487,361.639 ccw(c149.487,361.071) 148.919,361.071 148.919,355.13 ccw(c149.49,355.13) 149.49,354.558 213.88,354.558 cw(c213.88,353.057) 215.381,353.057 215.381,285.257 cw(c214.935,285.257) 214.935,284.811 197.231,284.811 cw(c197.231,285.12) 197.012,284.901 ccw(c196.846,284.735) v3(196.846,284.97)
  L16 w0.101: v10(151.437,360.528) 151.437,358.892 ccw(c151.537,358.892) J1_PCIE0.37@151.537,358.792
Bank223_MGTREF1_C_N: C278.1 C477.1 U1.N7 | length 11.8
  L1 w0.1: U1.N7@174.397,294.539 174.641,294.783 v2(174.641,295.027)
  L1 w0.101: 174.089,285.939 ccw(c174.19,285.94) 174.118,285.869 174.134,285.854 ccw(c174.168,285.888) 174.168,285.839 cw(c174.168,285.79) 174.203,285.825 174.378,285.65 cw(c174.293,285.565) C477.1@174.413,285.565 ; 174.089,285.94 174.089,285.944 cw(c174.18,285.944) 174.116,286.009 ccw(c174.051,286.074) 174.143,286.074 174.143,286.288 cw(c174.248,286.288) v7(174.173,286.362) ; C278.1@174.278,284.7 174.179,284.8 174.148,284.8 174.089,284.859 174.089,285.231 174.148,285.29 174.189,285.29 C477.1@174.413,285.515
  L5 (Sign) w0.081: v12(174.423,287.853) ccw(c174.328,287.853) 174.396,287.92 174.264,288.052 174.264,294.072 cw(c174.423,294.072) v12(174.423,294.231)
  L3 (Sign) w0.081: v7(174.173,286.362) 174.173,286.375 ccw(c174.029,286.375) 174.131,286.477 cw(c174.233,286.579) 174.089,286.579 174.089,286.621 cw(c174.258,286.621) 174.138,286.74 174.182,286.784 ccw(c173.983,286.983) 174.183,286.786 ccw(c173.983,286.983) 174.264,286.983 174.264,287.468 cw(c174.573,287.468) 174.355,287.687 ccw(c174.188,287.853) v12(174.423,287.853) ; v12(174.423,294.231) 174.423,294.329 174.264,294.488 174.264,294.624 174.641,295.001 v2(174.641,295.027)
Bank223_MGTREF1_C_P: C277.1 C477.2 U1.N8 | length 11.7
  L1 w0.1: v2(174.168,295.052) 174.168,295.311 U1.N8@174.397,295.539
  L1 w0.101: C477.2@173.363,285.515 173.588,285.29 173.629,285.29 173.688,285.231 173.688,284.859 173.629,284.8 173.598,284.8 C277.1@173.498,284.7 ; C477.2@173.363,285.565 cw(c173.484,285.565) 173.399,285.65 173.573,285.825 cw(c173.608,285.79) 173.608,285.839 ccw(c173.608,285.888) 173.643,285.854 173.658,285.869 ccw(c173.587,285.94) 173.688,285.94 173.688,286.276 cw(c173.809,286.276) v7(173.723,286.362)
  L5 (Sign) w0.081: v12(173.823,287.853) cw(c173.918,287.853) 173.851,287.92 173.983,288.052 173.983,294.072 ccw(c173.823,294.072) v12(173.823,294.231)
  L3 (Sign) w0.081: v7(173.723,286.362) 173.723,286.375 cw(c173.868,286.375) 173.766,286.477 ccw(c173.664,286.579) 173.808,286.579 173.808,286.623 cw(c174.255,286.623) 173.939,286.939 173.983,286.983 173.983,287.468 ccw(c173.674,287.468) 173.892,287.687 cw(c174.059,287.853) v12(173.823,287.853) ; v12(173.823,294.231) 173.823,294.329 173.983,294.488 173.983,294.74 174.137,294.894 174.137,295.02 v2(174.168,295.052)
Bank223_MGTREF1_N: C278.2 C557.1 J1_PCIE1.37 | length 122.5
  L1 w0.101: v3(174.188,282.55) 174.119,282.55 cw(c174.119,282.58) 174.089,282.58 174.089,283.012 cw(c174.413,283.012) C557.1@174.413,283.337 ; C278.2@174.278,284.18 174.179,284.081 174.148,284.081 174.089,284.022 174.089,283.671 174.148,283.612 174.189,283.612 C557.1@174.413,283.387
  L14 (Sign) w0.081: v3(174.188,282.55) ccw(c174.188,282.39) 174.029,282.39 174.029,279.866 174.029,279.326 ccw(c174.113,279.326) 174.113,279.242 174.13,279.242 cw(c174.13,279.158) 174.214,279.158 174.214,278.991 cw(c174.13,278.991) 174.13,278.907 174.113,278.907 ccw(c174.113,278.823) 174.029,278.823 174.029,278.447 174.029,260.97 174.029,260.772 ccw(c174.11,260.772) 174.11,260.691 174.15,260.691 cw(c174.15,260.633) 174.208,260.633 174.208,260.363 cw(c174.15,260.363) 174.15,260.305 174.11,260.305 ccw(c174.11,260.224) 174.029,260.224 174.029,259.798 174.029,256.682 ccw(c175.012,256.682) 175.012,255.699 194.843,255.699 195.001,255.699 ccw(c195.001,255.78) 195.082,255.78 195.082,255.897 cw(c195.14,255.897) 195.14,255.955 195.41,255.955 cw(c195.41,255.897) 195.468,255.897 195.468,255.78 ccw(c195.549,255.78) 195.549,255.699 195.975,255.699 245.829,255.699 ccw(c245.829,256.042) 246.172,256.042 246.172,274.049 ccw(c245.99,274.049) v10(245.99,274.231)
  L16 w0.101: J1_PCIE1.37@245.89,271.994 246.089,272.193 246.089,273.972 246.066,273.996 246.066,274.155 v10(245.99,274.231)
Bank223_MGTREF1_P: C277.2 C557.2 J1_PCIE1.39 | length 122.5
  L1 w0.101: C557.2@173.363,283.337 cw(c173.363,283.012) 173.688,283.012 173.688,282.58 cw(c173.658,282.58) 173.658,282.55 v3(173.588,282.55) ; C557.2@173.363,283.387 173.588,283.612 173.629,283.612 173.688,283.671 173.688,284.022 173.629,284.081 173.598,284.081 C277.2@173.498,284.18
  L14 (Sign) w0.081: v3(173.588,282.55) cw(c173.588,282.39) 173.748,282.39 173.748,256.682 ccw(c175.012,256.682) 175.012,255.418 245.829,255.418 ccw(c245.829,256.042) 246.453,256.042 246.453,274.094 cw(c246.59,274.094) v10(246.59,274.231)
  L16 w0.101: v10(246.59,274.231) 246.513,274.155 246.513,273.996 246.49,273.972 246.49,272.194 J1_PCIE1.39@246.69,271.994
Bank224_MGTREF0_C_N: C288.1 C686.2 U1.L7 | length 13.3
  L1 w0.1: U1.L7@172.397,294.539 v2(172.884,295.027)
  L1 w0.101: C686.2@172.154,285.404 172.095,285.345 172.095,284.968 172.154,284.909 172.185,284.909 C288.1@172.285,284.81 ; C686.2@172.42,285.679 cw(c172.42,286.003) 172.095,286.003 172.095,286.155 cw(c172.302,286.155) 172.302,286.362 172.686,286.362 ccw(c172.686,287.176) v7(173.5,287.176)
  L5 (Sign) w0.081: v12(172.684,294.616) 172.563,294.503 ccw(c172.618,294.444) 172.537,294.444 172.537,294.322 ccw(c172.659,294.322) 172.659,294.201 172.884,294.201 cw(c172.884,293.652) 173.433,293.652 173.433,293.386 173.433,290.14 173.433,289.957 ccw(c173.592,289.957) v12(173.592,289.797)
  L3 (Sign) w0.081: v12(172.684,294.616) cw(c172.648,294.688) 172.617,294.613 cw(c172.666,294.733) 172.537,294.733 cw(c172.832,294.733) 172.832,295.027 v2(172.884,295.027) ; v7@173.416,287.261 ccw(c173.5,287.261) v7(173.5,287.176) cw(c173.5,287.244) 173.433,287.244 173.433,289.638 cw(c173.592,289.638) v12(173.592,289.797)
Bank224_MGTREF0_C_P: C285.1 C686.1 U1.L8 | length 13.3
  L1 w0.1: v2(171.909,295.052) U1.L8@172.397,295.539
  L1 w0.101: C686.1@171.37,285.679 ccw(c171.37,286.003) 171.694,286.003 171.694,286.155 cw(c172.302,286.155) 172.302,286.763 172.663,286.763 ccw(c172.663,287.151) 173.05,287.151 v7(173.05,287.176) ; C285.1@171.505,284.794 171.604,284.893 171.635,284.893 171.694,284.952 171.694,285.345 C686.1@171.635,285.404
  L5 (Sign) w0.081: v12(172.085,294.603) 172.101,294.603 cw(c172.102,294.522) 172.106,294.603 cw(c172.097,294.444) 172.256,294.444 172.256,294.322 ccw(c172.659,294.322) 172.659,293.92 172.884,293.92 cw(c172.884,293.652) 173.152,293.652 173.152,293.386 173.152,290.14 173.152,289.957 cw(c172.992,289.957) v12(172.992,289.797)
  L3 (Sign) w0.081: v2(171.909,295.052) 171.937,295.052 cw(c171.937,294.733) 172.256,294.733 cw(c172.127,294.733) 172.127,294.604 172.103,294.604 ccw(c172.103,294.522) 172.102,294.603 v12(172.085,294.603) ; v12(172.992,289.797) cw(c172.992,289.638) 173.152,289.638 173.152,287.278 cw(c173.05,287.278) v7(173.05,287.176) ccw(c173.05,287.261) v7@173.135,287.261
Bank224_MGTREF0_N: C288.2 C687.2 J1_PCIE2.39 | length 145.5
  L1 w0.101: v1(172.194,282.6) 172.118,282.677 172.118,282.836 172.095,282.859 172.095,283.105 172.154,283.164 172.195,283.164 172.42,283.389 C687.2@172.42,283.439 172.42,283.489 172.195,283.713 172.154,283.713 172.095,283.772 172.095,284.131 172.154,284.19 172.185,284.19 C288.2@172.285,284.29
  L12 (Sign) w0.081: v1(172.194,282.6) ccw(c172.194,282.441) 172.035,282.441 172.035,281.152 172.035,279.458 ccw(c172.493,279.458) 172.493,279 217.492,279 ccw(c217.492,280.391) 218.882,280.391 218.882,283.035 218.882,283.075 ccw(c218.795,283.075) 218.795,283.163 218.714,283.163 cw(c218.714,283.25) 218.627,283.25 218.627,283.512 cw(c218.714,283.512) 218.714,283.599 218.795,283.599 ccw(c218.795,283.686) 218.882,283.686 218.882,283.915 218.882,311.191 218.887,311.197 cw(c220.27,311.075) 220.27,312.464 223.667,312.464 ccw(c223.667,313.296) 224.499,313.296 224.499,352.532 cw(c225.708,352.532) 225.708,353.741 226.237,353.741 226.277,353.741 ccw(c226.277,353.825) 226.361,353.825 226.361,353.945 cw(c226.445,353.945) 226.445,354.029 226.612,354.029 cw(c226.612,353.945) 226.696,353.945 226.696,353.825 ccw(c226.78,353.825) 226.78,353.741 227.125,353.741 232.552,353.741 ccw(c232.552,354.539) 233.35,354.539 233.35,355.85 ccw(c233.19,355.85) v17(233.19,356.01)
  L14 (Sign) w0.081: v17(233.19,356.01) ccw(c233.19,356.169) 233.35,356.169 233.35,357.328 ccw(c233.19,357.328) v14(233.19,357.488)
  L16 w0.101: J1_PCIE2.39@233.09,358.792 cw(c233.09,358.692) 233.19,358.692 v14(233.19,357.488)
Bank224_MGTREF0_P: C285.2 C687.1 J1_PCIE2.37 | length 145.5
  L1 w0.101: C285.2@171.505,284.274 171.604,284.174 171.635,284.174 171.694,284.115 171.694,283.772 171.635,283.713 171.594,283.713 171.37,283.489 C687.1@171.37,283.439 171.37,283.389 171.594,283.164 171.635,283.164 171.694,283.105 171.694,282.859 171.671,282.836 171.671,282.677 v1(171.594,282.6)
  L12 (Sign) w0.081: v1(171.594,282.6) cw(c171.594,282.441) 171.754,282.441 171.754,281.152 171.754,279.458 ccw(c172.493,279.458) 172.493,278.719 217.492,278.719 ccw(c217.492,280.391) 219.163,280.391 219.163,311.075 cw(c220.27,311.075) 220.27,312.183 223.667,312.183 ccw(c223.667,313.296) 224.78,313.296 224.78,352.532 cw(c225.708,352.532) 225.708,353.46 232.552,353.46 ccw(c232.552,354.539) 233.631,354.539 233.631,355.85 cw(c233.79,355.85) v17(233.79,356.01)
  L14 (Sign) w0.081: v17(233.79,356.01) cw(c233.79,356.169) 233.631,356.169 233.631,357.328 cw(c233.79,357.328) v14(233.79,357.488)
  L16 w0.101: v14(233.79,357.488) 233.79,358.692 cw(c233.89,358.692) J1_PCIE2.37@233.89,358.792
Bank224_MGTREF1_C_N: C290.1 C688.2 U1.J7 | length 20.1
  L1 w0.1: v2(169.909,295.027) U1.J7@170.397,294.539
  L3 (Sign) w0.081: v2(169.909,295.027) 170.072,295.027 ccw(c170.072,295.212) 170.256,295.212 170.256,295.594 cw(c170.652,295.594) 170.652,295.99 173.063,295.99 cw(c173.063,295.553) 173.5,295.553 173.5,294.706 cw(c172.959,294.706) 173.342,294.324 173.115,294.097 ccw(c173.411,293.801) 172.992,293.801 172.992,293.102 ccw(c173.537,293.102) 173.152,292.717 173.153,292.716 cw(c172.315,291.878) 173.5,291.878 173.5,290.734 cw(c172.996,290.734) 172.996,290.23 172.339,290.23 ccw(c172.339,290.086) 172.194,290.086 172.194,287.748 cw(c171.342,287.748) 171.342,286.895 ccw(c171.342,286.798) 171.245,286.798 v3(171.245,286.736)
  L16 w0.101: C290.1@169.313,284.725 C688.2@169.313,285.412 ; C688.2@169.448,285.547 cw(c169.448,285.871) 169.123,285.871 169.123,286.426 cw(c169.533,286.426) 169.533,286.835 171.145,286.835 cw(c171.145,286.736) v3(171.245,286.736)
Bank224_MGTREF1_C_P: C289.1 C688.1 U1.J8 | length 20.1
  L1 w0.1: U1.J8@170.397,295.539 v2(170.884,295.052)
  L3 (Sign) w0.081: v2(170.884,295.052) 170.697,295.052 cw(c170.697,295.212) 170.537,295.212 170.537,295.594 cw(c170.652,295.594) 170.652,295.709 171.858,295.709 172.232,295.709 cw(c172.232,295.609) 172.332,295.609 172.332,295.369 ccw(c172.433,295.369) 172.433,295.269 172.566,295.269 ccw(c172.566,295.369) 172.666,295.369 172.666,295.609 cw(c172.767,295.609) 172.767,295.709 173.038,295.709 173.063,295.709 cw(c173.063,295.553) 173.219,295.553 ; v3(171.245,287.336) 171.245,287.274 ccw(c171.342,287.274) 171.342,287.176 ccw(c171.342,287.748) 171.913,287.748 171.913,290.086 cw(c172.339,290.086) 172.339,290.511 172.992,290.511 ccw(c172.992,290.739) 173.219,290.739 173.219,291.876 ccw(c172.311,291.876) 172.953,292.518 172.952,292.519 cw(c173.534,293.101) 172.711,293.101 172.711,293.802 cw(c173.409,293.802) 172.916,294.295 ; 172.916,294.296 173.142,294.521 ccw(c172.955,294.708) 173.219,294.708 173.219,295.553 ; 173.219,295.551 ccw(c173.138,295.553) 173.219,295.553
  L16 w0.101: C688.1@168.398,285.547 ccw(c168.398,285.871) 168.722,285.871 168.722,286.426 cw(c169.533,286.426) 169.533,287.236 171.145,287.236 ccw(c171.145,287.336) v3(171.245,287.336) ; C289.1@168.533,284.725 C688.1@168.533,285.412
Bank224_MGTREF1_N: C290.2 C689.2 J1_PCIE3.39 | length 180
  L5 (Sign) w0.081: v1(152.476,301.213) cw(c152.636,301.213) 152.636,301.372 153.021,301.372 cw(c153.021,300.901) 153.492,300.901 153.492,291.348 ccw(c156.217,291.348) 154.29,289.421 155.852,287.859 cw(c155.357,287.363) 156.058,287.363 156.058,287.265 ccw(c158.173,287.265) 156.677,285.769 157.589,284.857 ccw(c159.293,286.561) 159.293,284.151 162.468,284.151 cw(c162.468,283.731) 162.889,283.731 162.889,283.582 cw(c162.58,283.582) 162.798,283.364 ccw(c162.965,283.197) v1(162.729,283.197)
  L12 (Sign) w0.081: v1(68.485,356.425) cw(c68.485,356.266) 68.644,356.266 68.644,348.818 ccw(c69.432,348.818) 69.432,348.03 136.381,348.03 cw(c136.381,347.227) 137.184,347.227 137.184,322.57 ccw(c137.858,322.57) 137.858,321.895 147.812,321.895 cw(c147.812,321.416) 148.291,321.416 148.291,302.254 ccw(c149.173,302.254) 149.173,301.372 152.317,301.372 cw(c152.317,301.213) v1(152.476,301.213)
  L16 w0.101: J1_PCIE3.39@68.385,358.792 cw(c68.385,358.592) 68.585,358.592 68.585,356.525 cw(c68.485,356.525) v1(68.485,356.425) ; v1(162.729,283.197) cw(c162.729,283.098) 162.829,283.098 162.829,280.345 ccw(c164.066,280.345) 164.066,279.108 167.896,279.108 ccw(c167.896,280.336) 169.123,280.336 169.123,283.051 cw(c169.448,283.051) C689.2@169.448,283.375 cw(c169.448,283.51) 169.313,283.51 C290.2@169.313,284.205
Bank224_MGTREF1_P: C289.2 C689.1 J1_PCIE3.37 | length 180
  L5 (Sign) w0.081: v1(152.476,301.813) ccw(c152.636,301.813) 152.636,301.653 153.021,301.653 cw(c153.021,300.901) 153.773,300.901 153.773,291.35 ccw(c156.222,291.35) 154.49,289.618 156.053,288.056 cw(c155.362,287.366) 156.339,287.366 156.339,287.267 ccw(c158.179,287.267) 156.878,285.966 157.785,285.058 ccw(c159.296,286.57) 159.296,284.432 162.468,284.432 cw(c162.468,283.731) 163.17,283.731 163.17,283.582 ccw(c163.479,283.582) 163.26,283.364 cw(c163.094,283.197) v1(163.329,283.197)
  L12 (Sign) w0.081: v1(69.085,356.425) ccw(c69.085,356.266) 68.925,356.266 68.925,348.818 ccw(c69.432,348.818) 69.432,348.311 131.54,348.311 131.58,348.311 ccw(c131.58,348.433) 131.702,348.433 131.702,348.501 cw(c131.824,348.501) 131.824,348.623 132.067,348.623 cw(c132.067,348.501) 132.189,348.501 132.189,348.433 ccw(c132.311,348.433) 132.311,348.311 133.456,348.311 136.381,348.311 cw(c136.381,347.227) 137.465,347.227 137.465,326.041 137.465,326.001 ccw(c137.587,326.001) 137.587,325.879 137.655,325.879 cw(c137.655,325.757) 137.776,325.757 137.776,325.513 cw(c137.655,325.513) 137.655,325.392 137.587,325.392 ccw(c137.587,325.27) 137.465,325.27 137.465,324.624 137.465,322.57 ccw(c137.858,322.57) 137.858,322.176 145.211,322.176 145.252,322.176 ccw(c145.252,322.298) 145.374,322.298 145.374,322.366 cw(c145.496,322.366) 145.496,322.488 145.739,322.488 cw(c145.739,322.366) 145.861,322.366 145.861,322.298 ccw(c145.983,322.298) 145.983,322.176 146.484,322.176 147.812,322.176 cw(c147.812,321.416) 148.572,321.416 148.572,302.254 ccw(c149.173,302.254) 149.173,301.653 152.317,301.653 ccw(c152.317,301.813) v1(152.476,301.813)
  L16 w0.101: v1(69.085,356.425) cw(c69.085,356.525) 68.986,356.525 68.986,358.593 cw(c69.185,358.593) J1_PCIE3.37@69.185,358.792 ; v1(163.329,283.197) ccw(c163.329,283.098) 163.23,283.098 163.23,280.345 ccw(c164.066,280.345) 164.066,279.509 167.896,279.509 ccw(c167.896,280.336) 168.722,280.336 168.722,283.051 ccw(c168.398,283.051) C689.1@168.398,283.375 ccw(c168.398,283.51) 168.533,283.51 C289.2@168.533,284.205
Bank225_MGTREF0_C_N: C300.1 C819.2 U1.H9 | length 16.5
  L1 w0.1: v2(168.909,297.027) U1.H9@169.397,296.539
  L1 w0.101: v7(167.198,286.779) ccw(c167.236,286.779) 167.236,286.741 167.273,286.741 C819.2@167.273,286.35 ; C300.1@167.357,285.369 cw(c167.357,285.453) 167.273,285.453 C819.2@167.273,286.35 ; C819.2@167.492,286.131 cw(c167.492,286.35) C819.2@167.273,286.35
  L3 (Sign) w0.081: v7(167.198,286.779) cw(c167.198,286.863) 167.114,286.863 167.114,287.514 cw(c167.402,287.514) 167.198,287.719 167.199,287.72 ccw(c166.729,288.191) 167.395,288.191 167.395,291.034 167.395,291.408 cw(c167.495,291.408) 167.495,291.509 167.701,291.509 ccw(c167.701,291.609) 167.801,291.609 167.801,291.742 ccw(c167.701,291.742) 167.701,291.843 167.495,291.843 cw(c167.495,291.943) 167.395,291.943 167.395,292.076 cw(c167.495,292.076) 167.495,292.177 167.515,292.177 ccw(c167.515,292.277) 167.615,292.277 167.615,292.41 ccw(c167.515,292.41) 167.515,292.511 167.495,292.511 cw(c167.495,292.611) 167.395,292.611 167.395,292.817 ; 167.395,292.833 167.395,293.427 ccw(c166.53,293.427) 167.141,294.038 167.139,294.04 cw(c167.76,294.661) 166.882,294.661 166.882,295.8 cw(c168.432,295.8) 168.432,297.35 169.173,297.35 cw(c169.173,297.267) 169.256,297.267 cw(c169.016,297.267) 169.016,297.027 v2(168.909,297.027)
Bank225_MGTREF0_C_P: C297.1 C819.1 U1.H10 | length 16.5
  L1 w0.1: U1.H10@169.397,297.539 v2(169.884,297.052)
  L1 w0.101: C819.1@166.442,286.131 ccw(c166.442,286.362) C819.1@166.673,286.362 ; C297.1@166.577,285.369 ccw(c166.577,285.465) 166.673,285.465 C819.1@166.673,286.362 ; v7(166.748,286.779) cw(c166.71,286.779) 166.71,286.741 166.673,286.741 C819.1@166.673,286.362
  L3 (Sign) w0.081: v7(166.748,286.779) ccw(c166.748,286.863) 166.833,286.863 166.833,287.517 cw(c167.396,287.517) 166.998,287.915 166.999,287.917 ccw(c166.724,288.193) 167.114,288.193 167.114,293.424 ccw(c166.523,293.424) 166.941,293.842 166.939,293.843 cw(c167.756,294.659) 166.601,294.659 166.601,295.8 cw(c168.432,295.8) 168.432,297.631 169.173,297.631 cw(c169.173,297.267) 169.537,297.267 ccw(c169.752,297.267) 169.752,297.052 v2(169.884,297.052)
Bank225_MGTREF0_N: C300.2 C820.2 J1_PCIE4.39 | length 15.9
  L1 w0.101: v1(167.267,283.299) 167.267,284.759 cw(c167.357,284.759) C300.2@167.357,284.849
  L12 (Sign) w0.081: v1(167.267,276.669) cw(c167.267,276.869) 167.067,276.869 167.067,283.099 cw(c167.267,283.099) v1(167.267,283.299)
  L16 w0.101: J1_PCIE4.39@164.337,271.994 cw(c164.337,272.193) 164.138,272.193 164.138,273.839 cw(c164.334,273.839) 164.334,274.035 166.395,274.035 ccw(c166.395,274.807) 167.167,274.807 167.167,276.57 cw(c167.267,276.57) v1(167.267,276.669)
Bank225_MGTREF0_P: C297.2 C820.1 J1_PCIE4.37 | length 15.9
  L1 w0.101: C297.2@166.577,284.849 cw(c166.577,284.759) 166.667,284.759 v1(166.667,283.299)
  L12 (Sign) w0.081: v1(166.667,276.669) ccw(c166.667,276.869) 166.867,276.869 166.867,283.099 ccw(c166.667,283.099) v1(166.667,283.299)
  L16 w0.101: J1_PCIE4.37@163.537,271.994 ccw(c163.537,272.194) 163.737,272.194 163.737,273.839 cw(c164.334,273.839) 164.334,274.436 166.395,274.436 ccw(c166.395,274.807) 166.766,274.807 166.766,276.57 ccw(c166.667,276.57) v1(166.667,276.669)
Bank225_MGTREF1_C_N: U1.F9
Bank225_MGTREF1_C_P: U1.F10
Bank505_MGTRREF0_C_N: C526.1 R69.2 U1.M24 | length 29
  L1 w0.1: v1(172.909,311.052) U1.M24@173.397,311.539
  L5 (Sign) w0.081: v1(162.088,325.565) ccw(c162.088,325.405) 161.928,325.405 161.928,325.136 ccw(c162.133,325.136) 162.133,324.932 164.495,324.932 164.741,324.932 ccw(c164.741,325.063) 164.872,325.063 164.872,325.13 cw(c165.003,325.13) 165.003,325.261 165.178,325.261 cw(c165.178,325.13) 165.309,325.13 165.309,325.063 ccw(c165.44,325.063) 165.44,324.932 165.917,324.932 171.704,324.932 cw(c171.704,324.038) 172.598,324.038 172.598,310.825 ccw(c172.73,310.825) 172.73,310.692 ccw(c172.73,310.872) 172.909,310.872 v1(172.909,311.052)
  L16 w0.101: v1(162.088,325.565) 162.011,325.641 162.011,325.8 161.988,325.823 161.988,326.246 162.047,326.305 162.113,326.305 162.288,326.479 R69.2@162.288,326.529 162.288,326.579 162.113,326.754 162.047,326.754 161.988,326.813 161.988,327.081 162.213,327.305 C526.1@162.232,327.305
Bank505_MGTRREF0_C_P: C525.1 R69.1 U1.M23 | length 29
  L1 w0.1: v1(172.909,310.052) U1.M23@173.397,310.539
  L5 (Sign) w0.081: v1(161.488,325.565) cw(c161.488,325.405) 161.647,325.405 161.647,325.136 ccw(c162.133,325.136) 162.133,324.651 171.704,324.651 cw(c171.704,324.038) 172.317,324.038 172.317,310.825 ccw(c172.73,310.825) 172.73,310.411 cw(c172.73,310.232) 172.909,310.232 v1(172.909,310.052)
  L16 w0.101: C525.1@161.343,327.298 161.363,327.298 161.587,327.073 161.587,326.813 161.528,326.754 161.462,326.754 161.288,326.579 R69.1@161.288,326.529 161.288,326.479 161.462,326.305 161.528,326.305 161.587,326.246 161.587,325.823 161.564,325.8 161.564,325.641 v1(161.488,325.565)
Bank505_MGTRREF2_C_N: C528.1 R126.2 U1.K24 | length 30.2
  L1 w0.1: U1.K24@171.397,311.539 171.432,311.505 171.432,311.21 171.555,311.087 171.85,311.087 v2(171.884,311.052)
  L5 (Sign) w0.081: v1(158.85,325.618) ccw(c158.85,325.458) 158.691,325.458 158.691,324.843 ccw(c159.467,324.843) 159.467,324.067 170.607,324.067 cw(c170.607,323.254) 171.42,323.254 171.42,313.934 ccw(c171.956,313.934) 171.577,313.555 171.601,313.531 cw(c171.059,312.989) 171.825,312.989 171.825,312.858 ccw(c172.012,312.858) 171.88,312.726 cw(c171.748,312.594) 171.935,312.594 v12(171.935,312.585)
  L3 (Sign) w0.081: v2(171.884,311.052) 171.8,311.052 cw(c171.8,311.315) 171.537,311.315 171.537,311.397 cw(c171.829,311.397) 171.623,311.604 ccw(c171.135,312.092) 171.825,312.092 171.825,312.312 cw(c172.012,312.312) 171.88,312.444 ccw(c171.748,312.576) 171.935,312.576 v12(171.935,312.585)
  L16 w0.101: v1@158.751,325.653 158.751,326.267 158.81,326.326 158.876,326.326 159.051,326.5 R126.2@159.051,326.55 159.051,326.6 158.876,326.775 158.81,326.775 158.751,326.834 158.751,327.123 158.976,327.347 C528.1@159,327.347
Bank505_MGTRREF2_C_P: C527.1 R126.1 U1.K23 | length 30.9
  L1 w0.1: v2(170.909,311.027) 170.944,310.992 171.239,310.992 171.362,310.869 171.362,310.574 U1.K23@171.397,310.539
  L5 (Sign) w0.081: v1(158.25,325.618) cw(c158.25,325.458) 158.41,325.458 158.41,324.843 ccw(c159.467,324.843) 159.467,323.786 160.045,323.786 160.548,323.786 cw(c160.548,323.618) 160.717,323.618 ccw(c160.885,323.618) 160.885,323.449 161.391,323.449 ccw(c161.391,323.618) 161.56,323.618 cw(c161.728,323.618) 161.728,323.786 161.769,323.786 170.607,323.786 cw(c170.607,323.254) 171.139,323.254 171.139,313.933 ccw(c171.952,313.933) 171.377,313.357 171.401,313.334 cw(c171.054,312.987) 171.544,312.987 171.544,312.858 cw(c171.357,312.858) 171.489,312.726 ccw(c171.622,312.594) 171.435,312.594 171.414,312.573 171.382,312.542 v12(171.378,312.542)
  L3 (Sign) w0.081: v2(170.909,311.027) 170.968,311.027 ccw(c170.968,311.315) 171.256,311.315 171.256,311.399 cw(c171.825,311.399) 171.423,311.801 ccw(c171.13,312.094) 171.544,312.094 171.544,312.312 ccw(c171.357,312.312) 171.489,312.444 cw(c171.622,312.576) 171.435,312.576 171.4,312.542 v12(171.378,312.542)
  L16 w0.101: C527.1@158.101,327.347 158.126,327.347 158.35,327.123 158.35,326.834 158.291,326.775 158.225,326.775 158.051,326.6 R126.1@158.051,326.55 158.051,326.5 158.225,326.326 158.291,326.326 158.35,326.267 v1@158.35,325.653 ; v1(158.25,325.618) ccw(c158.25,325.717) v1@158.35,325.717
Bank505_MGTRREF3_C_N: C530.1 R70.2 U1.H24 | length 32.5
  L1 w0.1: U1.H24@169.397,311.539 v2(169.884,311.052)
  L5 (Sign) w0.081: v1(155.958,325.59) ccw(c155.958,325.43) 155.799,325.43 155.799,324.075 ccw(c156.924,324.075) 156.924,322.95 169.769,322.95 cw(c169.769,321.911) 170.808,321.911 170.808,314.539 cw(c170.101,314.539) 170.601,314.039 170.231,313.67 ccw(c170.71,313.192) 170.033,313.192 170.033,312.362 ccw(c170.143,312.362) 170.143,312.252 170.144,312.254 v12(170.2,312.254)
  L3 (Sign) w0.081: v2(169.884,311.052) 169.86,311.052 cw(c169.86,311.375) 169.537,311.375 cw(c169.755,311.375) 169.601,311.528 169.863,311.79 ccw(c169.452,312.201) 170.033,312.201 170.033,312.203 v12@170.04,312.21 ; v12@170.04,312.21 cw(c170.143,312.107) 170.143,312.252 170.144,312.254 v12(170.2,312.254)
  L16 w0.101: v1(155.958,325.59) 155.882,325.666 155.882,325.825 155.859,325.849 155.859,326.246 155.918,326.305 155.984,326.305 156.158,326.479 R70.2@156.158,326.529 156.158,326.579 155.984,326.754 155.918,326.754 155.859,326.813 155.859,327.102 156.083,327.326 C530.1@156.108,327.326
Bank505_MGTRREF3_C_P: C529.1 R70.1 U1.H23 | length 32.4
  L1 w0.1: v2(168.909,311.027) U1.H23@169.397,310.539
  L5 (Sign) w0.081: v1(155.358,325.59) cw(c155.358,325.43) 155.518,325.43 155.518,324.075 ccw(c156.924,324.075) 156.924,322.669 169.769,322.669 cw(c169.769,321.911) 170.527,321.911 170.527,314.539 cw(c170.099,314.539) 170.402,314.237 170.033,313.869 ccw(c170.71,313.192) 169.752,313.192 169.752,312.362 cw(c169.643,312.362) v12(169.643,312.252)
  L3 (Sign) w0.081: v2(168.909,311.027) ccw(c168.909,311.374) 169.256,311.374 169.256,311.376 cw(c169.751,311.376) 169.401,311.726 169.663,311.988 ccw(c169.448,312.203) 169.752,312.203 169.746,312.21 ccw(c169.643,312.107) v12(169.643,312.252)
  L16 w0.101: C529.1@155.208,327.326 155.233,327.326 155.458,327.102 155.458,326.813 155.399,326.754 155.333,326.754 155.158,326.579 R70.1@155.158,326.529 155.158,326.479 155.333,326.305 155.399,326.305 155.458,326.246 155.458,325.849 155.435,325.825 155.435,325.666 v1(155.358,325.59)
Battery_PWR: P11.1 R679.2 R680.2 U48.2 | length 1.6
  L1 w0.5: R680.2@43.658,195.933 v1(43.658,196.747) ; R679.2@45.775,195.933 v1(45.775,196.747)
  other v1: 46.906,196.145 48.155,196.145 47.566,196.91 46.907,197.647
  other v3: 48.327,194.383
BST1: C346.1 U34.25 | length 2.7
  L1 w0.254: U34.25@66.822,237.639 66.822,237.71 66.824,237.712 66.895,237.712 68.336,239.154 C346.1@68.336,239.69
BST1_1: C390.1 U37.25 | length 4
  L1 w0.2: U37.25@67.175,181.817 67.755,182.397 69.953,182.397 70.383,182.828 C390.1@70.383,183.223
BST1_2: C431.1 U38.25 | length 1.7
  L1 w0.254: U38.25@65.453,208.714 66.596,208.714 66.996,209.114 C431.1@67.001,209.114
BST2: C350.1 U34.16 | length 2.6
  L1 w0.254: U34.16@66.822,233.139 66.822,232.556 67.929,231.449 67.929,231.245 C350.1@68.072,231.102
BST2_1: C394.1 U37.16 | length 2.8
  L1 w0.254: U37.16@67.175,177.317 68.028,177.317 69.151,176.194 C394.1@69.151,175.817
BST2_2: C435.1 U38.16 | length 1.7
  L1 w0.254: U38.16@65.453,204.214 66.661,204.214 67.011,203.864 C435.1@67.016,203.864
CAN0_H: P6.2 R446.2 R447.2 U63.7 U75.2 | length 11.5
  L1 w0.2: U63.7@185.82,370.492 187.052,370.492 187.377,370.817 U75.2@190.459,370.817 190.659,370.617 191.516,370.617 192.684,370.617 195.979,370.617 P6.2@196.799,371.437
CAN0_L: P6.1 R446.1 R447.1 U63.6 U75.1 | length 11.5
  L1 w0.2: U63.6@185.82,369.842 187.227,369.842 187.552,369.517 U75.1@190.459,369.517 190.659,369.717 191.516,369.717 192.684,369.717 195.979,369.717 P6.1@196.799,368.897
CAN1_RxD: R798.1 U63.1 | length 2.2
  L1 w0.2: R798.1@181.305,371.142 U63.1@183.47,371.142
CAN1_TxD: R799.1 U63.4 | length 2.2
  L1 w0.2: R799.1@181.305,369.192 U63.4@183.47,369.192
Charge_CAP: R658.2 U35_I2C_Expander_11.4 | length 93.8
  L1 w0.2: U35_I2C_Expander_11.4@198.939,243.535 v1(198.939,242.686) v1@198.945,242.679
  L5 (Sign) w0.2: v1(198.939,242.686) 198.939,241.815 201.6,239.154 v6(201.6,238.874)
  L3 (Sign) w0.2: v1(200.753,178.794) 210.417,178.794 215.506,183.883 215.506,200.558 221.024,206.076 221.024,226.252 221.023,226.254 221.023,226.79 221.005,226.808 221.005,226.809 208.559,239.255 201.981,239.255 v6(201.6,238.874)
  L16 w0.2: v1(200.753,178.794) 200.756,178.791 R658.2@200.756,177.56
CLK0_EZS_N: R81.1 U1.D16 U12.48 | length 102.1
  L1 w0.1: U1.D16@165.397,303.539 v2(165.884,303.052)
  L12 (Sign) w0.081: v16(110.566,330.277) cw(c110.726,330.277) 110.726,330.437 131.337,330.437 cw(c131.337,329.71) 132.064,329.71 132.064,312.71 ccw(c132.722,312.71) 132.722,312.052 146.908,312.052 cw(c146.908,311.429) 147.531,311.429 147.531,301.558 ccw(c148.625,301.558) 148.625,300.465 157.557,300.465 ccw(c157.557,301.027) 158.119,301.027 158.119,302.044 cw(c158.489,302.044) 158.489,302.413 160.508,302.413 cw(c160.508,302.254) v1(160.668,302.254)
  L3 (Sign) w0.081: v1(160.668,302.254) ccw(c160.668,302.489) 160.834,302.323 cw(c161.053,302.104) 161.053,302.413 165.155,302.413 ccw(c165.155,302.784) 165.525,302.784 cw(c165.793,302.784) 165.793,303.052 v2(165.884,303.052)
  L14 (Sign) w0.081: v14(101.927,331.613) cw(c102.037,331.613) 102.037,331.723 104.905,331.723 cw(c104.905,329.183) 106.701,330.979 106.857,330.823 ccw(c107.909,331.876) 107.909,330.387 ; 107.912,330.387 110.456,330.387 cw(c110.456,330.277) v16(110.566,330.277)
  L16 w0.101: U12.48@96.597,333.311 cw(c96.647,333.311) 96.647,333.36 97.894,333.36 cw(c97.894,332.248) 98.68,333.035 99.696,332.019 ccw(c100.293,332.616) 100.293,331.772 100.601,331.772 cw(c100.601,331.671) 100.672,331.743 ; 100.672,331.742 100.678,331.736 cw(c100.622,331.68) 100.702,331.68 ccw(c100.781,331.68) 100.725,331.624 R81.1@100.876,331.472 cw(c101.014,331.472) 101.014,331.611 101.676,331.611 101.676,331.613 v14(101.927,331.613)
CLK0_EZS_P: R81.2 U1.C16 U12.47 | length 102.1
  L1 w0.1: U1.C16@164.397,303.539 v2(164.884,303.052)
  L12 (Sign) w0.081: v16(110.566,330.877) ccw(c110.726,330.877) 110.726,330.718 131.337,330.718 cw(c131.337,329.71) 132.345,329.71 132.345,312.71 ccw(c132.722,312.71) 132.722,312.333 144.813,312.333 144.854,312.333 ccw(c144.854,312.414) 144.935,312.414 cw(c144.984,312.414) 144.984,312.463 145.374,312.463 cw(c145.374,312.414) 145.422,312.414 ccw(c145.503,312.414) 145.503,312.333 146.229,312.333 146.908,312.333 cw(c146.908,311.429) 147.812,311.429 147.812,301.558 ccw(c148.625,301.558) 148.625,300.746 157.557,300.746 ccw(c157.557,301.027) 157.838,301.027 157.838,302.044 cw(c158.489,302.044) 158.489,302.694 160.508,302.694 ccw(c160.508,302.854) v1(160.668,302.854)
  L3 (Sign) w0.081: v1(160.668,302.854) cw(c160.668,302.619) 160.834,302.785 ccw(c161.053,303.004) 161.053,302.694 165.155,302.694 ccw(c165.155,302.784) 165.244,302.784 ccw(c164.976,302.784) 164.976,303.052 v2(164.884,303.052)
  L14 (Sign) w0.081: v14(101.927,332.213) ccw(c102.037,332.213) 102.037,332.103 102.781,332.103 102.816,332.103 ccw(c102.816,332.184) 102.897,332.184 102.897,332.213 cw(c102.979,332.213) 102.979,332.295 103.048,332.295 cw(c103.048,332.213) 103.13,332.213 103.13,332.184 ccw(c103.211,332.184) 103.211,332.103 103.302,332.103 104.906,332.103 cw(c104.906,329.185) 106.969,331.248 107.123,331.094 ccw(c107.912,331.883) 107.912,330.767 110.456,330.767 ccw(c110.456,330.877) v16(110.566,330.877)
  L16 w0.101: U12.47@96.597,333.811 ccw(c96.647,333.811) 96.647,333.761 97.896,333.761 cw(c97.896,332.253) 98.962,333.319 99.92,332.362 ccw(c100.376,332.817) 100.376,332.173 100.601,332.173 ccw(c100.601,332.274) 100.672,332.202 100.678,332.209 ccw(c100.622,332.265) 100.702,332.265 cw(c100.781,332.265) 100.725,332.321 R81.2@100.876,332.472 ccw(c101.134,332.472) 101.134,332.215 101.676,332.215 101.676,332.213 v14(101.927,332.213)
CLK0_SPI.C\S\: R236_SPI_bridge_Main.1 SP25_SPI_bridge_Main.1 U12.1 U26_SPI_bridge_Main.11 | length 28
  L1 w0.12: U26_SPI_bridge_Main.11@77.363,328.6 U26_SPI_bridge_Main.11@77.373,328.59 ; U26_SPI_bridge_Main.11@77.371,328.59 U26_SPI_bridge_Main.11@77.373,328.59 ; SP25_SPI_bridge_Main.1@84.309,328.584 83.765,328.04 81.541,328.04 81.305,328.276 81.305,328.59 v1(79.045,328.59) U26_SPI_bridge_Main.11@77.373,328.59
  L12 (Sign) w0.12: v1(79.045,328.59) 82.108,328.59 82.513,328.994 87.871,328.994 89.058,330.182 92.687,330.182 92.869,330 96.008,330 96.571,329.438 v1(96.863,329.438)
  L16 w0.12: U12.1@95.947,330.661 96.392,330.216 96.392,329.909 v1(96.863,329.438)
CLK0_SPI.CLK: U12.50 U26_SPI_bridge_Main.14 | length 28
  L1 w0.12: U26_SPI_bridge_Main.14@77.373,330.54 80.02,330.54 v1(80.15,330.67)
  L12 (Sign) w0.12: v1(80.15,330.67) 80.379,330.899 86.954,330.899 87.347,331.292 96.05,331.292 96.193,331.292 ccw(c96.193,331.387) 96.288,331.387 96.288,332.305 cw(c96.383,332.305) 96.383,332.4 96.669,332.4 cw(c96.669,332.305) 96.764,332.305 96.764,331.387 ccw(c96.859,331.387) 96.859,331.292 96.952,331.292 97.599,331.292 v1(98.781,330.111)
  L16 w0.12: U12.50@96.597,332.311 97.724,332.311 98.285,331.749 98.285,330.606 v1(98.781,330.111)
CLK0_SPI.MISO: U12.51 U26_SPI_bridge_Main.13 | length 28
  L1 w0.12: U26_SPI_bridge_Main.13@77.373,329.895 v1(80.277,329.895)
  L12 (Sign) w0.12: v1(80.277,329.895) 81.385,329.895 82.16,330.67 92.822,330.67 93.035,330.457 93.177,330.457 ccw(c93.177,330.552) 93.273,330.552 93.273,330.924 cw(c93.368,330.924) 93.368,331.02 93.653,331.02 cw(c93.653,330.924) 93.748,330.924 93.748,330.552 ccw(c93.844,330.552) 93.844,330.457 94.129,330.457 ccw(c94.129,330.552) 94.224,330.552 94.224,330.924 cw(c94.319,330.924) 94.319,331.02 94.605,331.02 cw(c94.605,330.924) 94.7,330.924 94.7,330.552 ccw(c94.795,330.552) 94.795,330.457 94.869,330.457 95.208,330.457 ccw(c95.208,330.552) 95.303,330.552 95.303,330.977 cw(c95.398,330.977) 95.398,331.072 95.683,331.072 cw(c95.683,330.977) 95.779,330.977 95.779,330.552 ccw(c95.874,330.552) 95.874,330.457 96.159,330.457 ccw(c96.159,330.552) 96.254,330.552 96.254,331.008 cw(c96.35,331.008) 96.35,331.103 96.635,331.103 cw(c96.635,331.008) 96.73,331.008 96.73,330.552 ccw(c96.825,330.552) 96.825,330.457 97.206,330.457 97.444,330.457 v1(97.879,330.022)
  L16 w0.12: U12.51@96.597,331.811 97.437,331.811 97.879,331.368 v1(97.879,330.022)
CLK0_SPI.MOSI: U12.52 U26_SPI_bridge_Main.12 | length 28
  L1 w0.12: U26_SPI_bridge_Main.12@77.373,329.24 v1(79.667,329.24)
  L12 (Sign) w0.12: v1(79.667,329.24) 79.711,329.284 81.288,329.284 82.25,330.246 82.393,330.246 ccw(c82.393,330.341) 82.488,330.341 cw(c82.583,330.341) 82.583,330.436 82.869,330.436 cw(c82.869,330.341) 82.964,330.341 82.964,330.246 82.964,329.414 ccw(c83.059,329.414) 83.059,329.319 83.345,329.319 ccw(c83.345,329.414) 83.44,329.414 83.44,330.246 83.44,330.25 cw(c83.535,330.25) 83.535,330.345 83.82,330.345 cw(c83.82,330.25) 83.916,330.25 83.916,330.246 83.916,329.414 ccw(c84.011,329.414) 84.011,329.319 84.296,329.319 ccw(c84.296,329.414) 84.391,329.414 84.391,330.246 84.391,330.25 cw(c84.487,330.25) 84.487,330.345 84.772,330.345 cw(c84.772,330.25) 84.867,330.25 84.867,330.246 84.867,329.414 ccw(c84.962,329.414) 84.962,329.319 85.248,329.319 ccw(c85.248,329.414) 85.343,329.414 85.343,330.151 cw(c85.438,330.151) 85.438,330.246 85.585,330.246 88.811,330.246 88.967,330.402 92.779,330.402 92.944,330.237 96.083,330.237 96.274,330.046 v1(96.952,330.046)
  L16 w0.12: U12.52@96.597,331.311 97.162,331.311 97.32,331.152 97.32,330.414 v1(96.952,330.046)
CLK1_SPI.C\S\: R233_SPI_bridge_Main.1 SP23_SPI_bridge_Main.1 U13.1 U25_SPI_bridge_Main.11 | length 10.6
  L1 w0.2: U13.1@187.973,268.331 187.595,267.954 187.595,262.31 188.948,260.958 ; U25_SPI_bridge_Main.11@188.948,259.821 188.948,260.958 ; R233_SPI_bridge_Main.1@190.081,261.561 189.552,261.561 188.948,260.958
CLK1_SPI.CLK: U13.50 U25_SPI_bridge_Main.14 | length 11.6
  L1 w0.2: U25_SPI_bridge_Main.14@186.998,259.821 186.998,260.931 185.941,261.988 185.941,269.265 186.657,269.981 U13.50@187.323,269.981
CLK1_SPI.MISO: U13.51 U25_SPI_bridge_Main.13 | length 11
  L1 w0.2: U13.51@187.323,269.481 186.842,269.481 186.241,268.88 186.241,262.318 187.648,260.911 U25_SPI_bridge_Main.13@187.648,259.821
CLK1_SPI.MOSI: U13.52 U25_SPI_bridge_Main.12 | length 10.5
  L1 w0.2: U13.52@187.323,268.981 186.8,268.981 186.541,268.722 186.541,262.646 188.298,260.888 U25_SPI_bridge_Main.12@188.298,259.821
CLK_M_OSC_In: C53.2 R257.2 R537.1 U33.2 | length 4.9
  L1 w0.101: C53.2@56.672,390.028 56.681,390.018 57.675,390.018 58.922,388.772 58.922,388.085 59.473,388.085 59.623,388.235 U33.2@60.319,388.235
CLK_SMA0_C_N: C48.1 J2.2 | length 4.1
  L16 w0.101: C48.1@104.852,326.935 104.852,326.885 105.109,326.629 106.105,326.629 106.234,326.758 107.829,326.758 107.889,326.817 107.889,327.258 J2.2@108.134,327.503
CLK_SMA0_C_P: C47.1 J3.2 | length 4.1
  L16 w0.101: C47.1@104.852,325.921 104.852,325.971 105.109,326.228 106.271,326.228 106.401,326.357 107.829,326.357 107.889,326.298 107.889,325.857 J3.2@108.134,325.612
CLKREF_R: R375.1 X6.3 | length 2.2
  L1 w0.12: R375.1@220.65,327.185 220.65,329.245 X6.3@220.777,329.372
CLKREQ: J27.52
CMD_SD: J28.3 U47.D4 | length 8
  L14 (Sign) w0.12: v10(129.927,337.233) 132.155,335.004 v10(134.329,335.004)
  L16 w0.12: J28.3@127.238,337.233 v10(129.927,337.233)
COMP1_1: C642.2 R624.2 U37.30 | length 2.7
  L1 w0.254: R624.2@63.175,183.31 63.195,183.29 64.155,183.29 64.175,183.27 64.175,182.936 64.675,182.436 U37.30@64.675,181.817
COMP1_2: C548.2 R687.2 U38.30 | length 2.5
  L1 w0.254: R687.2@61.953,210.269 61.963,210.259 62.943,210.259 62.953,210.249 U38.30@62.953,208.714
COMP2_1: C641.2 R623.2 U37.11 | length 2.6
  L1 w0.254: R623.2@63.12,175.907 63.14,175.927 64.155,175.927 64.175,175.947 64.175,176.323 64.675,176.823 U37.11@64.675,177.317
COMP2_2: C650.2 R631.2 U38.11 | length 2.4
  L1 w0.254: R631.2@61.938,202.723 62.788,202.723 62.828,202.764 62.828,203.439 62.953,203.564 U38.11@62.953,204.214
CSN: C694.2 C695.2 C696.2 C697.2 C698.2 C699.2 C700.2 R17.2 R140.2 R150.2 R666.2 U4.2 U65.10 | length 35.4
  L1 w0.254: U65.10@40.6,205.318 43.104,205.318 ; R150.2@43.102,206.468 43.102,205.319 43.104,205.318 ; R666.2@45.266,206.456 45.266,206.112 44.472,205.318 43.104,205.318
  L1 w0.5: v1(33.287,205.384) R140.2@33.847,205.384 ; R666.2@44.621,206.456 v1(44.621,207.543) ; R666.2@45.266,206.456 v1(45.266,207.543) ; R666.2@45.904,206.456 v1(45.904,207.543) ; v1(49.507,200.659) C699.2@50.594,200.659 ; v1(49.507,201.383) C699.2@50.593,201.383 ; v1(49.507,202.549) C696.2@50.594,202.549 ; v1(49.507,203.273) C696.2@50.593,203.273 ; v1(49.507,204.44) C697.2@50.594,204.44 ; v1(49.507,205.164) C697.2@50.594,205.164 ; v1(49.507,206.33) C695.2@50.594,206.33 ; v1(49.507,207.054) C695.2@50.593,207.054 ; v1(49.507,208.221) C698.2@50.594,208.221 ; v1(49.507,208.944) C698.2@50.594,208.944
  L7(12V+Other) w0.5: v1(33.287,205.384) 34.156,205.384 36.855,202.686 41.777,202.686 42.736,203.645 42.736,205.143 v1(43.943,206.35)
  other v1: 46.939,186.483 48.188,186.483 47.599,187.248 46.94,187.985
  other v3: 48.36,184.721
CSP: L22.2 R666.1 U65.9 | length 8.6
  L1 w0.254: U65.9@40.6,204.818 44.43,204.818 45.266,203.981 R666.1@45.266,203.657
  L1 w0.5: v1(44.629,202.57) R666.1@44.629,203.657 ; v1(45.266,202.57) R666.1@45.266,203.657 ; v1(45.912,202.57) R666.1@45.912,203.657
  other v9: 42.02,228.866 43.644,229.333 37.109,230.581 39.58,230.581 44.463,230.811 45.281,232.29 39.025,232.804 43.802,233.108 41.58,234.493
CSU: P1.2 R649.1 R783.1 TP34.1 | length 21.7
  L1 w0.2: TP34.1@191.999,153.581 192.291,153.581 193.142,152.73 205.816,152.73 206.167,153.081 206.167,154.349 P1.2@206.108,154.407 205.867,154.649 205.867,156.941 ; R783.1@205.867,158.149 205.867,156.941 ; R649.1@207.162,158.187 207.112,158.187 205.867,156.941
CSU_Neg: P1.3 R109.2 | length 3.8
  L1 w0.2: R109.2@208.509,158.174 208.578,158.104 208.578,154.477 P1.3@208.648,154.407
CSU_Pos: P1.1 R106.2 | length 3.9
  L1 w0.2: P1.1@203.568,154.407 204.114,154.954 R106.2@204.114,158.098
D_05028_G0: R540.1 R904.2 U16.45 | length 60.4
  L1 w0.2: v2(127.523,269.667) 127.889,270.033 R904.2@127.889,273.4 ; v2(152.908,234.393) v2@152.915,234.393 ; U16.45@152.915,232.345 v2@152.915,234.393 ; R540.1@152.915,235.05 v2@152.915,234.393
  L3 (Sign) w0.2: v2(127.523,269.667) 127.523,269.626 127.294,269.398 127.294,269.391 126.767,268.863 126.767,251.171 132.366,245.572 132.366,244.946 139.019,238.292 145.389,238.292 146.75,236.931 148.45,236.931 148.641,237.122 152.54,237.122 152.908,236.753 v2(152.908,234.393)
D_05028_G3: U16.40 U35_I2C_Expander_12.25 | length 73.5
  L1 w0.2: v7(135.84,179.564) U35_I2C_Expander_12.25@137.041,179.565 U35_I2C_Expander_12.25@137.041,179.565 ; U16.40@155.415,232.345 155.415,233.368 v2(155.461,233.413)
  L3 (Sign) w0.2: v7(135.84,179.564) 135.164,179.564 134.544,180.185 134.544,182.046 136.846,184.348 136.846,227.75 142.684,233.589 154.215,233.589 154.39,233.413 v2(155.461,233.413)
D_05028_G4: U16.41 U35_I2C_Expander_00.28 | length 25.8
  L1 w0.2: v1(144.185,243.65) 144.613,244.078 144.613,245.634 143.744,246.503 143.744,249.288 144.237,249.781 U35_I2C_Expander_00.28@144.997,249.781 ; U16.41@154.915,232.345 v1@154.915,233.897
  L5 (Sign) w0.2: v1(144.185,243.65) 144.609,243.65 144.852,243.407 147.864,243.407 150.724,240.547 151.437,240.547 154.949,237.035 v1(154.949,233.925)
D_05028_G5: U16.12 U35_I2C_Expander_12.22 | length 61
  L1 w0.2: v7(136.266,181.515) U35_I2C_Expander_12.22@137.041,181.515 U35_I2C_Expander_12.22@137.279,181.515 ; v7(156.915,222.427) U16.12@156.915,223.545
  L3 (Sign) w0.2: v7(136.266,181.515) 136.266,182.495 137.765,183.994 137.765,219.321 140.125,221.682 156.17,221.682 v7(156.915,222.427)
D_05028_G6: U16.13 U35_I2C_Expander_12.21 | length 59.1
  L1 w0.2: U35_I2C_Expander_12.21@137.966,182.44 137.972,182.447 v7(137.972,183.475) ; v7(157.371,221.584) 157.371,221.624 157.415,221.669 U16.13@157.415,223.545
  L3 (Sign) w0.2: v7(137.972,183.475) 137.979,183.481 137.979,183.784 138.065,183.87 138.065,219.197 140.249,221.382 157.168,221.382 v7(157.371,221.584)
D_05028_S0: U16.55 U35_I2C_Expander_12.24 | length 65.3
  L1 w0.2: v7(134.919,180.34) 134.959,180.34 135.103,180.196 U35_I2C_Expander_12.24@137.404,180.196 ; v7(149.717,228.708) 150.752,228.708 U16.55@150.765,228.695
  L3 (Sign) w0.2: v7(134.919,180.34) 134.919,181.997 137.146,184.224 137.146,227.626 138.778,229.257 147.322,229.257 147.871,228.708 v7(149.717,228.708)
D_05028_S1: U16.56 U35_I2C_Expander_12.23 | length 63
  L1 w0.2: v7(135.616,180.851) 135.652,180.815 136.589,180.815 136.62,180.846 137.074,180.846 U35_I2C_Expander_12.23@137.101,180.819 ; v7(149.611,228.195) U16.56@150.765,228.195
  L3 (Sign) w0.2: v7(135.616,180.851) 135.616,182.27 137.465,184.119 137.465,227.521 138.681,228.737 147.418,228.737 147.96,228.195 v7(149.611,228.195)
DAC1220_Vref: C320.1 R608.2 R609.1 U30.12 | length 9.3
  L1 w0.2: v7(167.972,419.325) 168.598,419.325 168.671,419.397 170.254,419.397 170.49,419.633 U30.12@172.25,419.633 ; v7(168.709,423.06) C320.1@169.525,423.06
  L3 (Sign) w0.2: v7(167.972,419.325) 168.709,420.062 v7(168.709,423.06)
DAC_OUT: C321.2 U30.11 X2.2 | length 14.3
  L1 w0.2: C321.2@169.496,420.542 170.462,420.542 170.735,420.268 U30.11@172.25,420.268
  L1 w0.4: X2.2@164.503,413.36 166.51,413.36 167.195,414.045 167.195,419.938 167.799,420.542 C321.2@169.496,420.542
DAC_SPI_CLK: U27_SPI_bridge_Main.14 U30.16 | length 12.2
  L1 w0.2: v7(170.36,417.103) 170.369,417.093 U30.16@172.25,417.093 ; v7(170.362,408.541) U27_SPI_bridge_Main.14@172.108,408.541
  L3 (Sign) w0.2: v7(170.362,408.541) v7@170.362,417.103
DAC_SPI_MOSI: R481.1 U27_SPI_bridge_Main.12 U30.15 | length 13.3
  L1 w0.2: R481.1@168.442,411.863 169.021,411.863 169.763,411.121 v7(170.779,411.121) ; v7(170.779,409.864) 172.085,409.864 U27_SPI_bridge_Main.12@172.108,409.841 ; v7(170.779,417.728) U30.15@172.25,417.728
  L3 (Sign) w0.2: v7@170.779,409.851 v7(170.779,409.864) v7(170.779,411.121) v7(170.779,417.728)
DAS/DSS#: J27.10
DATA0_SD: J28.7 U47.D5 | length 7.6
  L16 w0.12: J28.7@127.237,332.832 128.929,332.832 129.513,333.415 130.315,333.415 131.154,334.255 132.63,334.255 133.379,335.004 U47.D5@133.929,335.004
DATA1_SD: J28.8 U47.E5 | length 7.9
  L16 w0.12: J28.8@127.237,331.732 130.761,331.732 133.633,334.604 U47.E5@133.929,334.604
DATA2_SD: J28.1 U47.A5 | length 8
  L16 w0.12: J28.1@127.237,339.432 129.828,339.432 131.294,337.967 132.167,337.967 U47.A5@133.929,336.204
DATA3_SD: J28.2 R383.2 U47.B5 | length 10.9
  L1 w0.12: v1(129.09,338.336) 129.09,338.375 R383.2@131.039,340.323 R383.2@131.039,340.373
  L16 w0.12: J28.2@127.237,338.332 127.241,338.336 v1(129.09,338.336) 130.014,338.336 130.541,337.809 130.541,337.257 131.404,336.394 133.339,336.394 U47.B5@133.929,335.804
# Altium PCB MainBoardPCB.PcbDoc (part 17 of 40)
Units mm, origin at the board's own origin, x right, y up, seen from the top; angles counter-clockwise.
Board outline 258.95 x 308.86 mm, 16 copper layers (L1, L2 (GND), L3 (Sign), L4 (GND), L5 (Sign), L6 (PWR/GND), L7(12V+Other), L8 (Plane_GND), L9 (PWR/GND), L10 (3V3+Other), L11 (PWR/GND), L12 (Sign), L13 (GND), L14 (Sign), L15 (GND), L16), stack 2.503 mm thick; 2578 components, 1867 nets, 8817 pads, 8021 vias.
Unrouted connection lines stored in the file: 25.

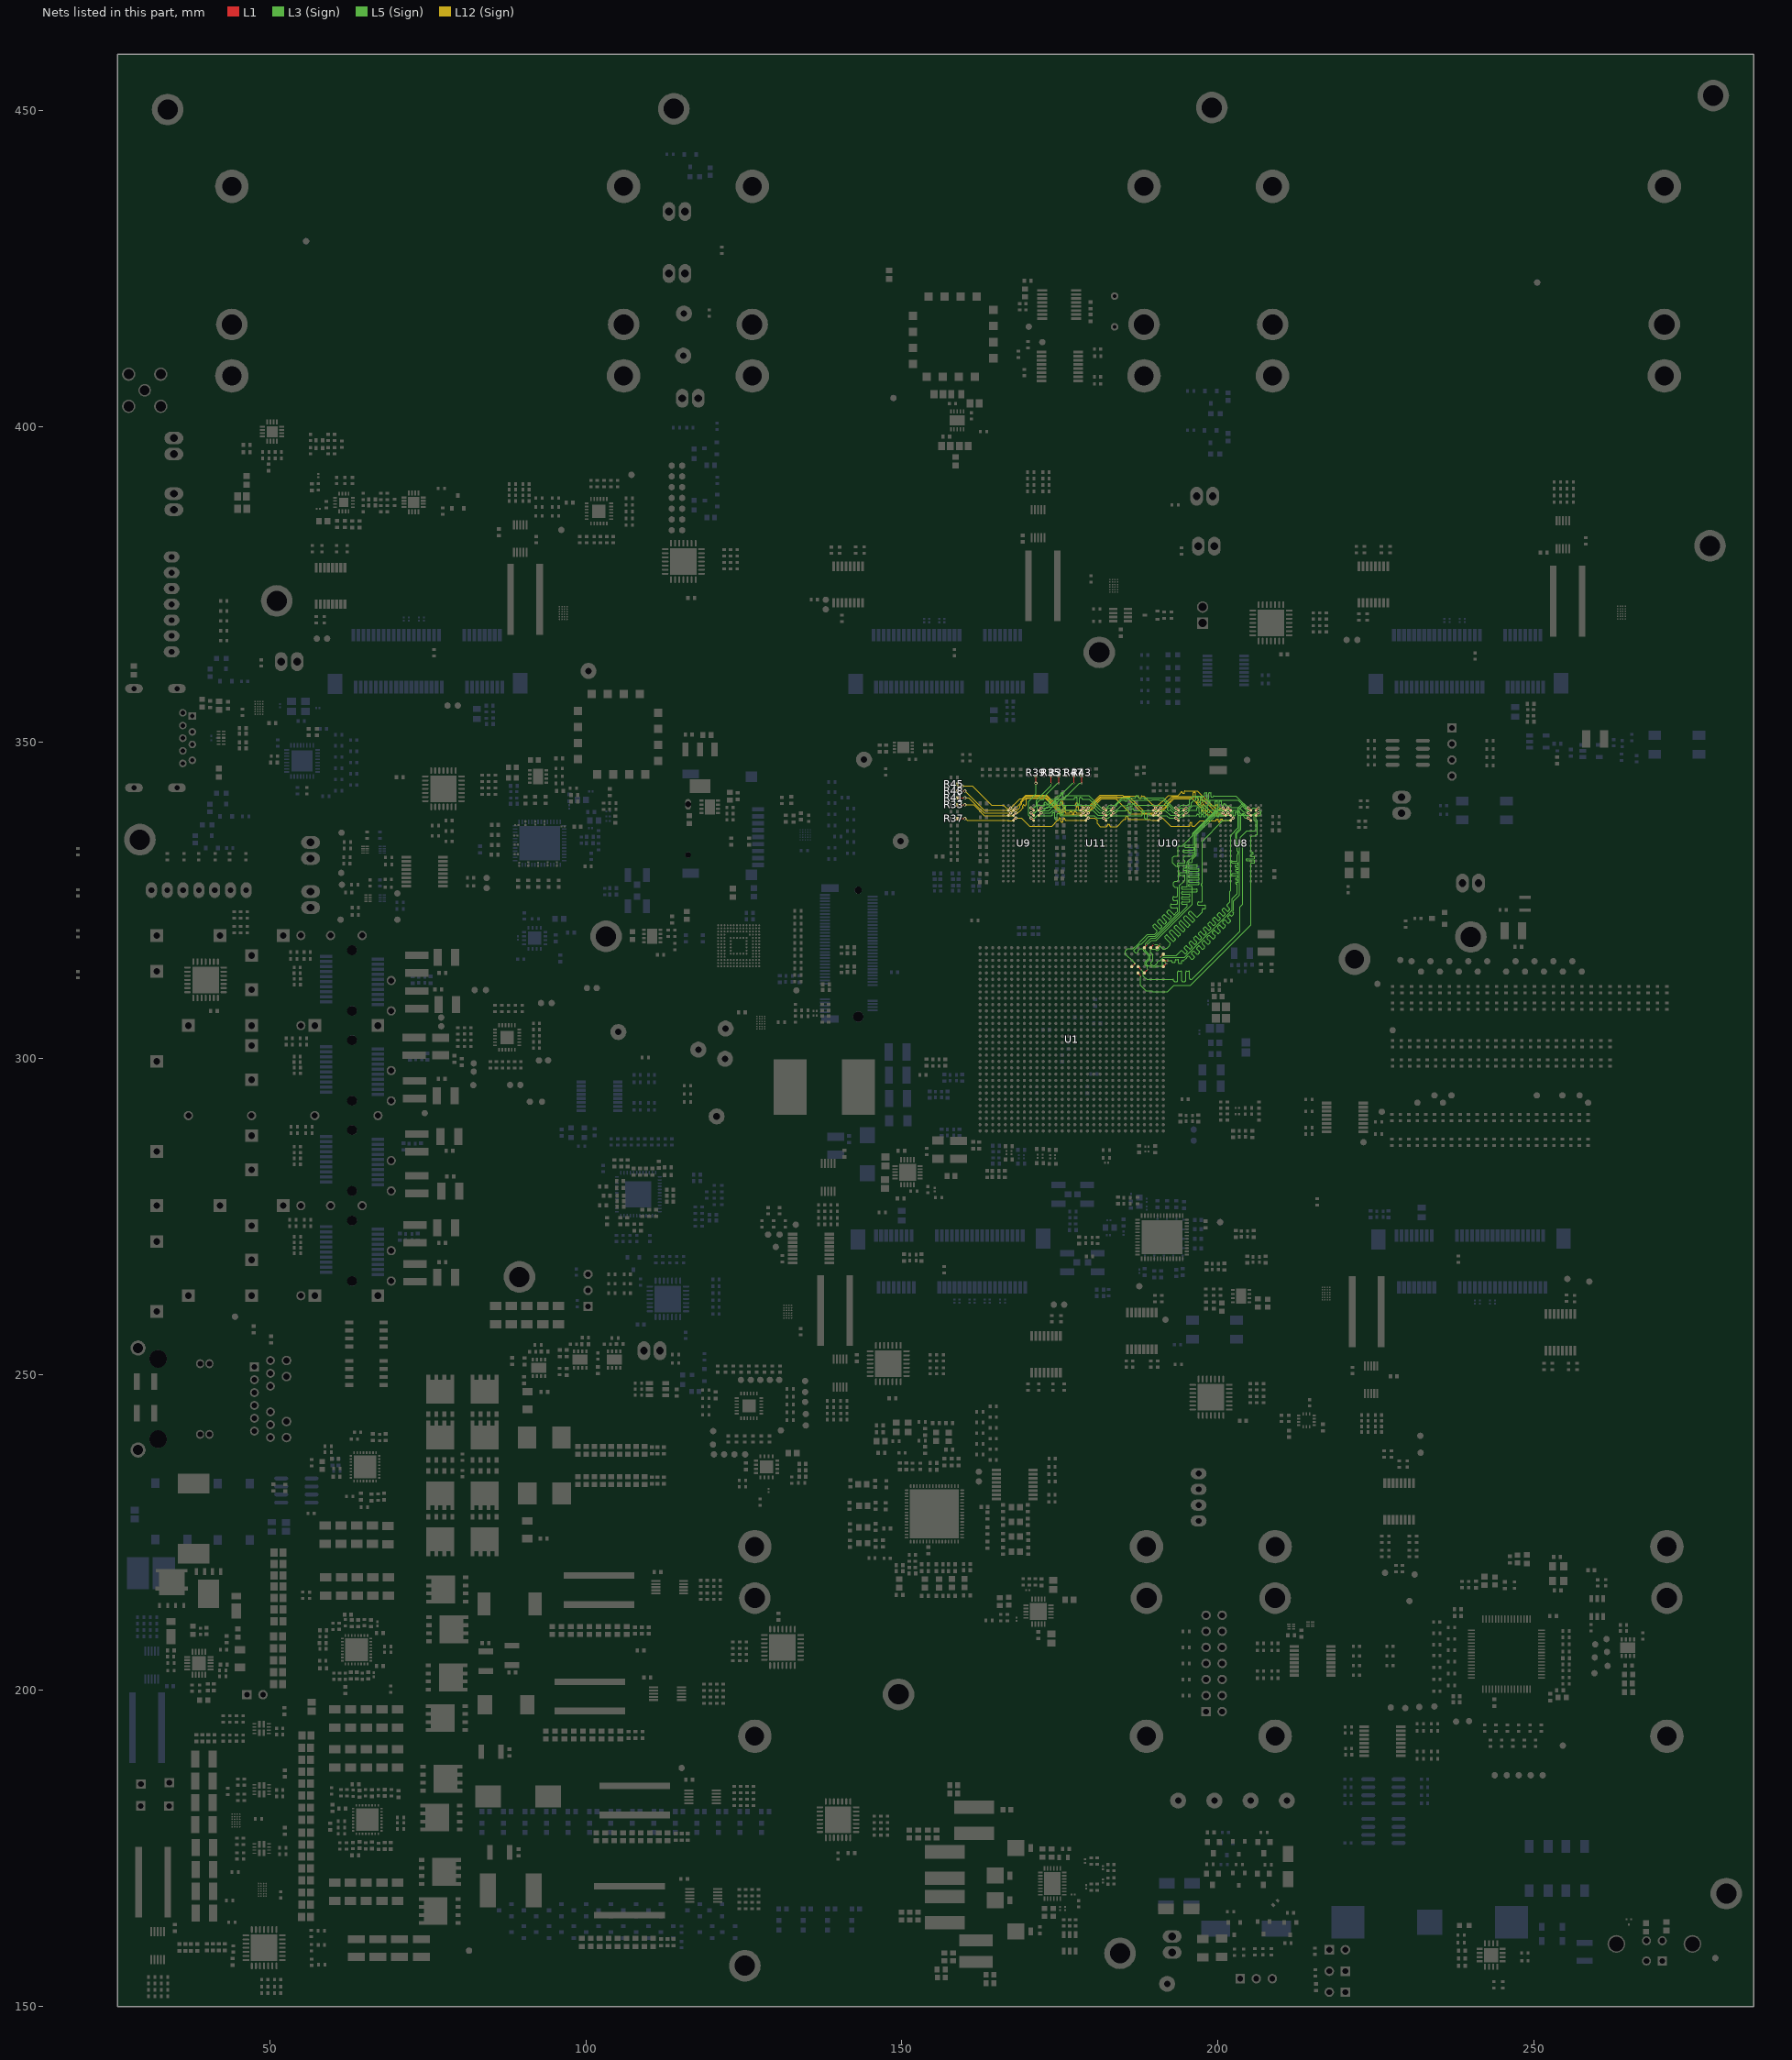
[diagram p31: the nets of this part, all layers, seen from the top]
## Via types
v1: diameter 0.5, hole 0.25, L1 to L16, tented both sides, 4341 vias
v2: diameter 0.254, hole 0.1, L1 to L3 (Sign), tented both sides, 781 vias
v3: diameter 0.5, hole 0.25, L1 to L16, 565 vias
v4: diameter 0.254, hole 0.1, L15 (GND) to L16, tented both sides, 406 vias
v5: diameter 0.254, hole 0.1, L1 to L2 (GND), tented both sides, 283 vias
v6: diameter 0.457, hole 0.2, L3 (Sign) to L6 (PWR/GND), tented both sides, 254 vias
v7: diameter 0.254, hole 0.1, L1 to L3 (Sign), 237 vias
v8: diameter 0.75, hole 0.4, L1 to L16, 200 vias
v9: diameter 0.8, hole 0.4, L1 to L16, tented both sides, 182 vias
v10: diameter 0.254, hole 0.1, L14 (Sign) to L16, tented both sides, 170 vias
v11: diameter 0.75/0/0/0/0/0/0/0/0/0/0/0/0/0/0/0.75 (per signal layer), hole 0.4, L1 to L16, 160 vias
v12: diameter 0.457, hole 0.2, L3 (Sign) to L6 (PWR/GND), 158 vias
v13: diameter 1.4, hole 0.5, L1 to L16, tented both sides, 80 vias
v14: diameter 0.254, hole 0.1, L14 (Sign) to L16, 65 vias
v15: diameter 0.254, hole 0.1, L1 to L2 (GND), 45 vias
v16: diameter 0.457, hole 0.2, L11 (PWR/GND) to L14 (Sign), tented both sides, 26 vias
v17: diameter 0.457, hole 0.2, L11 (PWR/GND) to L14 (Sign), 25 vias
v18: diameter 0.457, hole 0.2, L7(12V+Other) to L10 (3V3+Other), tented both sides, 11 vias
v19: diameter 0.254/0/0.254 (per signal layer), hole 0.1, L1 to L3 (Sign), 9 vias
v20: diameter 0.2/0/0.2 (per signal layer), hole 0.1, L1 to L3 (Sign), 6 vias
v21: diameter 1.65, hole 1.65, L1 to L16, 5 vias
v22: diameter 1.15, hole 1.15, L1 to L16, 5 vias
v23: diameter 0.457, hole 0.2, L1 to L16, 3 vias
v24: diameter 0.5, hole 0.3, L1 to L16, 2 vias
v25: diameter 0.5/0/0.5 (per signal layer), hole 0.2, L14 (Sign) to L16, 1 vias
v26: diameter 0.5, hole 0.25, L1 to L16, tented bottom, 1 vias

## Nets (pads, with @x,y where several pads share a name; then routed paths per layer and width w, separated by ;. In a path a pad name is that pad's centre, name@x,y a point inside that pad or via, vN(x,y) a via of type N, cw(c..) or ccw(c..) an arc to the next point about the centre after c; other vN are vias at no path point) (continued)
DDR4_A0: R31.1 U1.AH30 U8.P3 U9.P3 U10.P3 U11.P3 | length 105.5
  L1 w0.1: v1(170.472,338.864) U9.P3@170.876,338.46 ; v1(181.933,338.864) U11.P3@182.336,338.46 ; U1.AH30@189.397,317.539 v2(189.884,318.027) ; v1(193.393,338.864) U10.P3@193.797,338.46 ; v1(204.853,338.864) U8.P3@205.257,338.46
  L1 w0.155: v2(174.855,343.555) R31.1@174.855,344.8
  L5 (Sign) w0.081: v1(170.472,338.864) 171.003,338.864 171.394,339.254 173.27,339.254 174.076,340.06 174.116,340.06 ccw(c174.116,340.176) 174.232,340.176 174.232,340.479 cw(c174.348,340.479) 174.348,340.595 174.502,340.595 cw(c174.502,340.479) 174.618,340.479 174.618,339.557 ccw(c174.734,339.557) 174.734,339.441 174.888,339.441 ccw(c174.888,339.557) 175.004,339.557 175.004,340.406 cw(c175.12,340.406) 175.12,340.522 175.274,340.522 cw(c175.274,340.406) 175.39,340.406 175.39,340.176 ccw(c175.506,340.176) 175.506,340.06 175.781,340.06 180.091,340.06 181.287,338.864 v1(181.933,338.864) 182.528,338.864 182.918,339.254 183.936,339.254 184.735,340.053 185.641,340.053 185.649,340.06 185.752,340.06 ccw(c185.752,340.13) 185.822,340.13 185.822,340.272 cw(c185.891,340.272) 185.891,340.342 186.099,340.342 cw(c186.099,340.272) 186.168,340.272 186.168,340.06 186.168,339.973 ccw(c186.237,339.973) 186.237,339.903 186.445,339.903 ccw(c186.445,339.973) 186.514,339.973 186.514,340.06 186.514,340.272 cw(c186.583,340.272) 186.583,340.342 186.791,340.342 cw(c186.791,340.272) 186.86,340.272 186.86,340.13 ccw(c186.93,340.13) 186.93,340.06 186.944,340.06 191.829,340.06 192.13,339.759 cw(c192.048,339.677) 192.13,339.595 192.035,339.5 ccw(c192.117,339.418) 192.035,339.336 192.144,339.227 ccw(c192.226,339.309) 192.308,339.227 192.403,339.322 cw(c192.485,339.24) 192.567,339.322 192.81,339.079 193.025,338.864 v1(193.393,338.864) 193.902,338.864 194.281,339.242 194.826,339.242 194.845,339.261 195.294,339.261 196.087,340.054 198.367,340.054 198.407,340.054 ccw(c198.407,340.138) 198.491,340.138 198.491,340.617 cw(c198.575,340.617) 198.575,340.701 198.742,340.701 cw(c198.742,340.617) 198.826,340.617 198.826,340.138 ccw(c198.91,340.138) 198.91,340.054 199.198,340.054 199.479,340.054 199.52,340.054 ccw(c199.52,340.138) 199.603,340.138 199.603,340.662 cw(c199.687,340.662) 199.687,340.746 199.855,340.746 cw(c199.855,340.662) 199.939,340.662 199.939,339.88 ccw(c200.022,339.88) 200.022,339.797 200.19,339.797 ccw(c200.19,339.88) 200.274,339.88 200.274,340.662 cw(c200.358,340.662) 200.358,340.746 200.525,340.746 cw(c200.525,340.662) 200.609,340.662 200.609,340.138 ccw(c200.693,340.138) 200.693,340.054 200.86,340.054 ccw(c200.86,340.138) 200.944,340.138 200.944,340.197 cw(c201.028,340.197) 201.028,340.281 201.196,340.281 cw(c201.196,340.197) 201.279,340.197 201.279,340.138 ccw(c201.363,340.138) 201.363,340.054 201.489,340.054 201.889,340.054 202.178,339.765 203.375,339.765 204.102,339.039 204.678,339.039 v1(204.853,338.864)
  L3 (Sign) w0.079: 203.122,326.785 203.122,327.472 203.122,327.512 ccw(c203.039,327.512) 203.039,327.595 202.933,327.595 cw(c202.933,327.678) 202.85,327.678 202.85,327.845 cw(c202.933,327.845) 202.933,327.928 203.178,327.928 ccw(c203.178,328.011) 203.261,328.011 203.261,328.178 ccw(c203.178,328.178) 203.178,328.261 202.933,328.261 cw(c202.933,328.344) 202.85,328.344 202.85,328.511 cw(c202.933,328.511) 202.933,328.594 203.178,328.594 ccw(c203.178,328.677) 203.261,328.677 203.261,328.844 ccw(c203.178,328.844) 203.178,328.927 202.32,328.927 cw(c202.32,329.011) 202.237,329.011 202.237,329.177 cw(c202.32,329.177) 202.32,329.26 203.178,329.26 ccw(c203.178,329.344) 203.261,329.344 203.261,329.51 ccw(c203.178,329.51) 203.178,329.593 202.933,329.593 cw(c202.933,329.677) 202.85,329.677 202.85,329.843 cw(c202.933,329.843) 202.933,329.927 203.178,329.927 ccw(c203.178,330.01) 203.261,330.01 203.261,330.176 ccw(c203.178,330.176) 203.178,330.26 202.899,330.26 cw(c202.899,330.343) 202.816,330.343 202.816,330.51 cw(c202.899,330.51) 202.899,330.593 203.178,330.593 ccw(c203.178,330.676) 203.261,330.676 203.261,330.843 ccw(c203.178,330.843) 203.178,330.926 202.32,330.926 cw(c202.32,331.009) 202.237,331.009 202.237,331.176 cw(c202.32,331.176) 202.32,331.259 203.039,331.259 ccw(c203.039,331.342) 203.122,331.342 203.122,332.03 203.122,332.244 203.261,332.383 203.261,332.706 203.122,332.845 203.122,332.862
  L3 (Sign) w0.081: v1(170.472,338.864) 171.003,338.864 171.471,339.332 171.471,340.502 171.922,340.953 172.452,340.953 172.585,341.085 172.585,341.495 174.645,343.555 v2(174.855,343.555) ; v2(189.884,318.027) 190.375,318.027 190.74,317.661 190.74,317.349 190.517,317.125 190.303,317.125 190.081,317.348 189.55,317.348 189.36,317.158 189.36,316.828 189.738,316.449 189.738,315.504 189.479,315.245 189.479,314.952 189.725,314.706 190.024,314.706 190.452,315.134 190.452,315.263 190.728,315.539 190.896,315.539 191.383,316.027 192.397,316.027 ; 203.122,332.862 203.122,333.704 202.857,333.969 202.857,335.751 203.456,336.351 203.456,339.499 203.949,339.992 204.174,339.992 204.432,339.734 204.432,339.407 204.559,339.28 204.768,339.28 204.853,339.195 v1(204.853,338.864)
  L3 (Sign) w0.171: 203.09,326.098 203.122,326.13 203.122,326.785
  L3 (Sign) w0.172: 192.397,316.027 194.783,316.027 202.26,323.504 202.26,325.268 203.09,326.098
DDR4_A1: R33.1 U1.AG30 U8.P4 U9.P4 U10.P4 U11.P4 | length 99.9
  L1 w0.1: U9.P4@167.676,338.46 168.072,338.857 v1(168.075,338.857) ; U11.P4@179.136,338.46 179.533,338.857 v1(179.535,338.857) ; U1.AG30@188.397,317.539 v2(188.884,318.027) ; U10.P4@190.597,338.46 190.993,338.857 v1(190.995,338.857) ; v1(201.653,338.864) U8.P4@202.057,338.46
  L1 w0.155: R33.1@158.737,340.144 v1(159.982,340.144)
  L12 (Sign) w0.081: 165.251,338.46 167.659,338.46 168.055,338.857 v1(168.075,338.857) 168.08,338.862 168.373,338.862 168.91,339.398 169.141,339.63 169.17,339.659 ccw(c169.099,339.73) 169.17,339.801 169.091,339.88 cw(c169.162,339.951) 169.091,340.022 169.185,340.117 cw(c169.256,340.046) 169.328,340.117 169.407,340.038 ccw(c169.478,340.109) 169.549,340.038 169.72,340.208 169.72,341.014 169.87,341.164 172.72,341.164 175.343,338.541 178.332,338.541 178.332,338.527 178.429,338.429 178.555,338.429 178.592,338.466 178.897,338.466 178.972,338.541 179.211,338.541 179.575,338.906 179.592,338.906 180.743,340.056 180.743,340.213 181.653,341.123 183.86,341.123 186.3,338.683 189.421,338.683 189.586,338.518 189.982,338.518 190.023,338.478 190.031,338.478 190.042,338.467 190.357,338.467 190.521,338.63 190.697,338.63 190.924,338.857 191.004,338.857 192.212,340.066 192.212,340.215 193.107,341.11 195.948,341.11 197.308,339.751 197.336,339.723 ccw(c197.396,339.782) 197.455,339.723 197.536,339.804 cw(c197.596,339.745) 197.655,339.804 197.773,339.685 cw(c197.714,339.626) 197.773,339.567 197.504,339.297 ccw(c197.563,339.238) 197.504,339.179 197.622,339.06 ccw(c197.681,339.12) 197.741,339.06 198.01,339.33 cw(c198.07,339.271) 198.129,339.33 198.247,339.211 cw(c198.188,339.152) 198.247,339.093 198.039,338.885 ccw(c198.098,338.825) 198.039,338.766 198.158,338.648 ccw(c198.217,338.707) 198.276,338.648 198.284,338.656 cw(c198.344,338.597) 198.403,338.656 198.523,338.536 200.601,338.536 200.663,338.473 201.263,338.473 v1(201.653,338.864)
  L12 (Sign) w0.151: v1(159.982,340.144) 161.387,340.144 163.071,338.46 165.251,338.46
  L3 (Sign) w0.081: v2(188.884,318.027) 189.397,318.539 ; 195.968,324.694 195.968,325.996 195.968,326.183 195.968,326.529 195.968,326.876 195.968,327.135 ccw(c195.882,327.135) 195.882,327.222 195.479,327.222 cw(c195.479,327.308) 195.393,327.308 195.393,327.481 cw(c195.479,327.481) 195.479,327.568 195.968,327.568 196.957,327.568 ccw(c196.957,327.655) 197.043,327.655 197.043,327.828 ccw(c196.957,327.828) 196.957,327.914 195.968,327.914 195.479,327.914 cw(c195.479,328.001) 195.393,328.001 195.393,328.174 cw(c195.479,328.174) 195.479,328.26 195.968,328.26 196.957,328.26 ccw(c196.957,328.347) 197.043,328.347 197.043,328.52 ccw(c196.957,328.52) 196.957,328.607 195.968,328.607 195.479,328.607 cw(c195.479,328.693) 195.393,328.693 195.393,328.866 cw(c195.479,328.866) 195.479,328.953 195.968,328.953 196.957,328.953 ccw(c196.957,329.039) 197.043,329.039 197.043,329.212 ccw(c196.957,329.212) 196.957,329.299 195.968,329.299 195.479,329.299 cw(c195.479,329.386) 195.393,329.386 195.393,329.559 cw(c195.479,329.559) 195.479,329.645 195.968,329.645 196.957,329.645 ccw(c196.957,329.732) 197.043,329.732 197.043,329.905 ccw(c196.957,329.905) 196.957,329.991 195.968,329.991 195.479,329.991 cw(c195.479,330.078) 195.393,330.078 195.393,330.251 cw(c195.479,330.251) 195.479,330.338 195.968,330.338 196.727,330.338 ccw(c196.727,330.424) 196.814,330.424 196.814,330.597 ccw(c196.727,330.597) 196.727,330.684 195.968,330.684 195.479,330.684 cw(c195.479,330.77) 195.393,330.77 195.393,330.943 cw(c195.479,330.943) 195.479,331.03 195.882,331.03 ccw(c195.882,331.117) 195.968,331.117 195.968,331.376 195.968,331.549 196.63,332.21 196.63,335.438 199.652,338.46 201.002,338.46 201.244,338.702 201.244,338.734 201.374,338.864 v1(201.653,338.864)
  L3 (Sign) w0.172: 189.397,318.539 189.569,318.712 190.245,318.712 195.968,324.435 195.968,324.694
DDR4_A2: R35.1 U1.AK29 U8.R3 U9.R3 U10.R3 U11.R3 | length 102.3
  L1 w0.1: v1(170.472,339.664) U9.R3@170.876,339.26 ; v1(181.933,339.664) U11.R3@182.336,339.26 ; v2(190.909,316.052) U1.AK29@191.397,316.539 ; v1(193.393,339.664) U10.R3@193.797,339.26 ; v1(204.853,339.664) U8.R3@205.257,339.26
  L1 w0.155: v2(173.646,343.555) R35.1@173.646,344.8
  L5 (Sign) w0.081: v1(170.472,339.664) 170.901,339.664 171.305,340.068 172.536,340.068 172.565,340.097 ccw(c172.482,340.179) 172.565,340.262 172.542,340.285 cw(c172.625,340.368) 172.542,340.451 172.613,340.522 cw(c172.696,340.439) 172.779,340.522 173.058,340.243 ccw(c173.141,340.326) 173.224,340.243 173.295,340.314 ccw(c173.212,340.397) 173.295,340.48 173.204,340.57 cw(c173.287,340.653) 173.204,340.736 173.427,340.959 173.497,341.028 174.153,341.028 174.762,341.638 175.016,341.638 175.057,341.638 ccw(c175.057,341.753) 175.173,341.753 175.173,341.932 cw(c175.288,341.932) 175.288,342.048 175.443,342.048 cw(c175.443,341.932) 175.559,341.932 175.559,341.404 ccw(c175.674,341.404) 175.674,341.288 175.829,341.288 ccw(c175.829,341.404) 175.945,341.404 175.945,341.522 cw(c176.06,341.522) 176.06,341.638 176.254,341.638 179.578,341.638 181.552,339.664 v1(181.933,339.664) 182.433,339.664 182.837,340.068 183.672,340.068 183.678,340.073 183.701,340.073 184.061,340.433 184.061,340.457 184.891,341.287 186.792,341.287 186.987,341.287 ccw(c186.987,341.356) 187.056,341.356 187.056,341.519 cw(c187.125,341.519) 187.125,341.589 187.333,341.589 cw(c187.333,341.519) 187.402,341.519 187.402,341.356 ccw(c187.471,341.356) 187.471,341.287 187.748,341.287 187.922,341.287 188.022,341.287 188.299,341.287 cw(c188.299,341.218) 188.368,341.218 188.368,341.177 ccw(c188.437,341.177) 188.437,341.108 188.645,341.108 ccw(c188.645,341.177) 188.714,341.177 188.714,341.218 cw(c188.783,341.218) 188.783,341.287 188.887,341.287 191.389,341.287 193.012,339.664 v1(193.393,339.664) 193.822,339.664 194.226,340.068 195.277,340.068 195.516,340.307 195.516,340.906 196.164,341.554 197.827,341.554 197.867,341.554 ccw(c197.867,341.638) 197.951,341.638 197.951,341.989 cw(c198.035,341.989) 198.035,342.072 198.202,342.072 cw(c198.202,341.989) 198.286,341.989 198.286,341.192 ccw(c198.37,341.192) 198.37,341.108 198.538,341.108 ccw(c198.538,341.192) 198.621,341.192 198.621,341.989 cw(c198.705,341.989) 198.705,342.072 198.873,342.072 cw(c198.873,341.989) 198.957,341.989 198.957,341.467 ccw(c199.04,341.467) 199.04,341.384 199.208,341.384 ccw(c199.208,341.467) 199.292,341.467 199.292,341.47 cw(c199.376,341.47) 199.376,341.554 199.77,341.554 202.847,341.554 204.23,340.171 204.23,339.92 204.486,339.664 v1(204.853,339.664)
  L3 (Sign) w0.081: v1(170.472,339.664) 170.901,339.664 171.29,340.053 171.29,340.854 171.456,341.02 171.471,341.02 173.63,343.18 v2@173.63,343.539 ; v2(190.909,316.052) 191.179,316.322 192.397,316.322 ; 202.057,326.576 202.057,331.486 202.052,331.492 202.052,335.338 203.249,336.536 203.249,339.66 203.898,340.309 204.2,340.309 204.845,339.664 v1(204.853,339.664)
  L3 (Sign) w0.172: 192.397,316.322 193.462,316.322 ; 201.905,324.764 201.905,326.424 202.057,326.576
  L3 (Sign) w0.173: 193.462,316.322 193.715,316.575 194.15,317.01 cw(c194.273,316.887) 194.395,317.01 194.794,316.611 ccw(c194.888,316.704) 194.981,316.611 195.168,316.798 ccw(c195.074,316.891) 195.168,316.984 194.737,317.415 cw(c194.831,317.508) 194.737,317.602 194.924,317.789 cw(c195.018,317.695) 195.111,317.789 195.542,317.358 ccw(c195.635,317.452) 195.729,317.358 195.915,317.545 ccw(c195.822,317.638) 195.915,317.732 195.485,318.162 cw(c195.578,318.256) 195.485,318.349 195.672,318.536 cw(c195.765,318.443) 195.859,318.536 196.289,318.106 ccw(c196.383,318.199) 196.476,318.106 196.663,318.293 ccw(c196.569,318.386) 196.663,318.479 196.232,318.91 cw(c196.326,319.003) 196.232,319.097 196.419,319.284 cw(c196.513,319.19) 196.606,319.284 197.037,318.853 ccw(c197.13,318.947) 197.224,318.853 197.41,319.04 ccw(c197.317,319.133) 197.41,319.227 196.98,319.657 cw(c197.073,319.751) 196.98,319.844 197.167,320.031 cw(c197.26,319.938) 197.354,320.031 197.784,319.601 ccw(c197.878,319.694) 197.971,319.601 198.158,319.788 ccw(c198.064,319.881) 198.158,319.974 197.727,320.405 cw(c197.821,320.498) 197.727,320.592 197.914,320.779 cw(c198.008,320.685) 198.101,320.779 198.532,320.348 ccw(c198.625,320.442) 198.719,320.348 198.905,320.535 ccw(c198.812,320.629) 198.905,320.722 198.475,321.152 cw(c198.568,321.246) 198.475,321.339 198.662,321.526 cw(c198.755,321.433) 198.849,321.526 199.279,321.096 ccw(c199.373,321.189) 199.466,321.096 199.653,321.283 ccw(c199.56,321.376) 199.653,321.469 199.222,321.9 cw(c199.316,321.993) 199.222,322.087 199.409,322.274 cw(c199.503,322.18) 199.596,322.274 200.027,321.843 ccw(c200.12,321.937) 200.214,321.843 200.4,322.03 ccw(c200.307,322.124) 200.4,322.217 199.97,322.648 cw(c200.063,322.741) 199.97,322.834 200.157,323.021 cw(c200.25,322.928) 200.344,323.021 200.774,322.591 ccw(c200.868,322.684) 200.961,322.591 201.148,322.778 ccw(c201.055,322.871) 201.148,322.965 200.717,323.395 cw(c200.811,323.488) 200.717,323.582 200.904,323.769 cw(c200.998,323.675) 201.091,323.769 201.521,323.34 ccw(c201.614,323.433) 201.707,323.34 201.894,323.526 ccw(c201.801,323.62) 201.894,323.713 201.496,324.111 cw(c201.619,324.233) 201.496,324.356 201.854,324.713 201.905,324.764
DDR4_A3: R37.1 U1.AJ30 U8.N4 U9.N4 U10.N4 U11.N4 | length 102.1
  L1 w0.1: U9.N4@167.676,337.66 168.072,338.057 v1(168.075,338.057) ; U11.N4@179.136,337.66 179.533,338.057 v1(179.535,338.057) ; U1.AJ30@190.397,317.539 v2(190.884,318.027) ; U10.N4@190.597,337.66 190.993,338.057 v1(190.995,338.057) ; U8.N4@202.057,337.66 202.453,338.057 v1(202.456,338.057)
  L1 w0.155: R37.1@158.737,337.967 v1(159.982,337.967)
  L12 (Sign) w0.081: 165.251,337.687 166.734,337.687 166.76,337.661 167.508,337.661 167.896,338.049 v1(168.075,338.057) ; v1@168.075,338.049 168.083,338.057 168.93,338.057 170.209,336.778 173.763,336.778 174.684,337.698 174.724,337.698 ccw(c174.724,337.816) 174.841,337.816 174.841,337.944 cw(c174.959,337.944) 174.959,338.061 175.059,338.061 cw(c175.059,337.944) 175.176,337.944 175.176,337.555 ccw(c175.294,337.555) 175.294,337.438 175.394,337.438 ccw(c175.394,337.555) 175.511,337.555 175.511,337.862 cw(c175.629,337.862) 175.629,337.98 175.729,337.98 cw(c175.729,337.862) 175.846,337.862 175.846,337.816 ccw(c175.964,337.816) 175.964,337.698 176.461,337.698 178.397,337.698 178.429,337.666 179.065,337.666 179.455,338.057 v1(179.535,338.057) 180.56,338.057 180.95,337.668 180.95,337.187 181.417,336.719 182.372,336.719 182.413,336.719 ccw(c182.413,336.835) 182.528,336.835 182.528,336.924 cw(c182.644,336.924) 182.644,337.04 182.799,337.04 cw(c182.799,336.924) 182.914,336.924 182.914,336.835 ccw(c183.03,336.835) 183.03,336.719 183.397,336.719 184.055,336.719 185.198,337.862 185.298,337.862 185.338,337.862 ccw(c185.338,337.978) 185.454,337.978 185.454,338.216 cw(c185.57,338.216) 185.57,338.332 185.724,338.332 cw(c185.724,338.216) 185.84,338.216 185.84,337.978 ccw(c185.956,337.978) 185.956,337.862 186.214,337.862 189.251,337.862 189.447,337.666 190.56,337.666 190.951,338.057 v1(190.995,338.057) ; v1@190.995,338.049 191.006,338.038 191.292,338.038 192.553,336.777 195.483,336.777 195.524,336.777 ccw(c195.524,336.861) 195.607,336.861 195.607,337.274 cw(c195.691,337.274) 195.691,337.358 195.859,337.358 cw(c195.859,337.274) 195.943,337.274 195.943,336.861 ccw(c196.026,336.861) 196.026,336.777 196.381,336.777 197.213,337.609 199.61,337.609 199.651,337.609 ccw(c199.651,337.726) 199.768,337.726 199.768,337.759 cw(c199.885,337.759) 199.885,337.876 199.986,337.876 cw(c199.986,337.759) 200.103,337.759 200.103,337.555 ccw(c200.22,337.555) 200.22,337.438 200.321,337.438 ccw(c200.321,337.555) 200.438,337.555 200.438,337.759 cw(c200.555,337.759) 200.555,337.876 200.656,337.876 cw(c200.656,337.759) 200.773,337.759 200.773,337.726 ccw(c200.89,337.726) 200.89,337.609 201.147,337.609 201.205,337.666 202.065,337.666 v1(202.456,338.057)
  L12 (Sign) w0.151: v1(159.982,337.967) 160.077,337.967 160.356,337.687 165.251,337.687
  L3 (Sign) w0.079: 191.726,317.344 191.875,317.492 191.971,317.492 192.397,317.918 192.397,318.015
  L3 (Sign) w0.081: v2(190.884,318.027) 190.884,317.789 191.329,317.344 191.726,317.344 ; 197.574,327.035 197.574,327.152 197.574,327.243 ccw(c197.492,327.243) 197.492,327.325 cw(c197.492,327.411) 197.405,327.411 197.405,327.584 cw(c197.492,327.584) 197.492,327.671 ccw(c197.492,327.753) 197.574,327.753 197.574,327.851 197.574,334.379 200.862,337.666 201.818,337.666 201.993,337.842 202.241,337.842 v1(202.456,338.057)
  L3 (Sign) w0.172: 196.989,322.606 197.574,323.192 197.574,323.279 ; 197.574,325.044 197.574,327.035
  L3 (Sign) w0.173: 192.397,318.015 192.49,318.108 ccw(c192.397,318.202) 192.49,318.295 191.639,319.147 cw(c191.732,319.24) 191.639,319.334 191.826,319.52 cw(c191.919,319.427) 192.013,319.52 192.958,318.576 ccw(c193.024,318.642) 193.09,318.576 193.332,318.817 ccw(c193.265,318.883) 193.332,318.949 192.387,319.894 cw(c192.48,319.988) 192.387,320.081 192.574,320.268 cw(c192.667,320.175) 192.761,320.268 193.706,319.323 ccw(c193.772,319.39) 193.838,319.323 194.079,319.565 ccw(c194.013,319.631) 194.079,319.697 193.135,320.642 cw(c193.228,320.736) 193.135,320.829 193.322,321.016 cw(c193.415,320.923) 193.508,321.016 194.453,320.071 ccw(c194.52,320.137) 194.586,320.071 194.827,320.313 ccw(c194.761,320.379) 194.827,320.445 193.882,321.39 cw(c193.976,321.483) 193.882,321.577 194.069,321.764 cw(c194.163,321.67) 194.256,321.764 195.201,320.819 ccw(c195.267,320.885) 195.334,320.819 195.575,321.06 ccw(c195.509,321.127) 195.575,321.193 194.63,322.138 cw(c194.724,322.231) 194.63,322.325 194.817,322.512 cw(c194.911,322.418) 195.004,322.512 195.949,321.567 ccw(c196.015,321.633) 196.081,321.567 196.323,321.808 ccw(c196.257,321.874) 196.323,321.941 195.378,322.886 cw(c195.471,322.979) 195.378,323.073 195.565,323.259 cw(c195.658,323.166) 195.752,323.259 196.603,322.408 ccw(c196.697,322.502) 196.79,322.408 196.989,322.606 ; 197.574,323.279 197.574,323.59 cw(c197.706,323.59) 197.706,323.722 197.943,323.722 ccw(c197.943,323.854) 198.076,323.854 198.076,324.118 ccw(c197.943,324.118) 197.943,324.251 197.574,324.251 196.987,324.251 cw(c196.987,324.383) 196.855,324.383 196.855,324.647 cw(c196.987,324.647) 196.987,324.779 197.442,324.779 ccw(c197.442,324.912) 197.574,324.912 197.574,325.044
DDR4_A4: R39.1 U1.AK28 U8.N3 U9.N3 U10.N3 U11.N3 | length 101.2
  L1 w0.1: v1(170.472,338.064) U9.N3@170.876,337.66 ; v1(181.933,338.064) U11.N3@182.336,337.66 ; U1.AK28@191.397,315.539 v2(192.086,315.539) ; v1(193.393,338.064) U10.N3@193.797,337.66 ; v1(204.853,338.064) U8.N3@205.257,337.66
  L1 w0.155: v1(171.229,343.555) R39.1@171.229,344.75 R39.1@171.229,344.8
  L5 (Sign) w0.081: v1(171.229,343.555) 171.229,341.878 170.06,340.709 170.06,338.476 v1(170.472,338.064) 171.003,338.064 171.4,338.46 173.684,338.46 173.725,338.46 ccw(c173.725,338.576) 173.841,338.576 173.841,338.818 cw(c173.957,338.818) 173.957,338.934 174.111,338.934 cw(c174.111,338.818) 174.227,338.818 174.227,337.963 ccw(c174.343,337.963) 174.343,337.847 174.497,337.847 ccw(c174.497,337.963) 174.613,337.963 174.613,338.675 cw(c174.729,338.675) 174.729,338.791 174.883,338.791 cw(c174.883,338.675) 174.999,338.675 174.999,338.576 ccw(c175.115,338.576) 175.115,338.46 176.32,338.46 178.481,338.46 180.482,338.46 180.878,338.064 v1(181.933,338.064) 182.713,338.064 183.109,338.46 187.922,338.46 187.962,338.46 ccw(c187.962,338.576) 188.078,338.576 188.078,338.865 cw(c188.194,338.865) 188.194,338.98 188.348,338.98 cw(c188.348,338.865) 188.464,338.865 188.464,338.056 ccw(c188.58,338.056) 188.58,337.94 188.734,337.94 ccw(c188.734,338.056) 188.85,338.056 188.85,338.702 cw(c188.966,338.702) 188.966,338.818 189.12,338.818 cw(c189.12,338.702) 189.236,338.702 189.236,338.576 ccw(c189.352,338.576) 189.352,338.46 189.624,338.46 191.942,338.46 192.339,338.064 v1(193.393,338.064) 193.924,338.064 194.145,338.285 194.669,338.285 194.844,338.46 196.613,338.46 196.653,338.46 ccw(c196.653,338.544) 196.737,338.544 196.737,338.592 cw(c196.821,338.592) 196.821,338.676 196.989,338.676 cw(c196.989,338.592) 197.072,338.592 197.072,338.329 ccw(c197.156,338.329) 197.156,338.245 197.324,338.245 ccw(c197.324,338.329) 197.408,338.329 197.408,338.592 cw(c197.491,338.592) 197.491,338.676 197.659,338.676 cw(c197.659,338.592) 197.743,338.592 197.743,338.329 ccw(c197.827,338.329) 197.827,338.245 197.994,338.245 ccw(c197.994,338.329) 198.078,338.329 198.078,338.521 cw(c198.162,338.521) 198.162,338.605 198.329,338.605 cw(c198.329,338.521) 198.413,338.521 198.413,338.377 ccw(c198.497,338.377) 198.497,338.293 198.665,338.293 ccw(c198.665,338.377) 198.748,338.377 cw(c198.832,338.377) 198.832,338.46 199.198,338.46 199.405,338.46 199.445,338.46 ccw(c199.445,338.544) 199.529,338.544 199.529,338.996 cw(c199.613,338.996) 199.613,339.079 199.781,339.079 cw(c199.781,338.996) 199.864,338.996 199.864,338.329 ccw(c199.948,338.329) 199.948,338.245 200.116,338.245 ccw(c200.116,338.329) 200.2,338.329 200.2,338.546 cw(c200.283,338.546) 200.283,338.63 200.451,338.63 cw(c200.451,338.546) 200.535,338.546 200.535,338.544 ccw(c200.619,338.544) 200.619,338.46 200.863,338.46 201.246,338.46 201.259,338.473 201.815,338.473 201.848,338.506 202.013,338.506 202.054,338.506 ccw(c202.054,338.59) 202.138,338.59 202.138,338.996 cw(c202.221,338.996) 202.221,339.079 202.389,339.079 cw(c202.389,338.996) 202.473,338.996 202.473,338.531 ccw(c202.557,338.531) 202.557,338.447 202.724,338.447 ccw(c202.724,338.531) 202.808,338.531 202.808,338.926 cw(c202.892,338.926) 202.892,339.01 203.059,339.01 cw(c203.059,338.926) 203.143,338.926 203.143,338.59 ccw(c203.227,338.59) 203.227,338.506 203.357,338.506 203.398,338.465 203.944,338.465 204.345,338.064 v1(204.853,338.064)
  L3 (Sign) w0.081: v2(192.086,315.539) 192.397,315.539 ; 203.213,325.632 203.441,325.86 203.441,333.648 203.043,334.046 203.043,335.584 203.707,336.248 203.707,338.504 203.962,338.76 204.158,338.76 v1(204.853,338.064)
  L3 (Sign) w0.172: 192.397,315.539 192.481,315.539 ; 194.681,315.539 194.784,315.642 ; 202.54,323.398 202.54,324.959 203.213,325.632
  L3 (Sign) w0.173: 192.481,315.539 192.613,315.539 cw(c192.613,315.407) 192.745,315.407 192.745,315.335 ccw(c192.878,315.335) 192.878,315.203 193.142,315.203 ccw(c193.142,315.335) 193.274,315.335 193.274,315.539 cw(c193.406,315.539) 193.406,315.672 193.67,315.672 cw(c193.67,315.539) 193.803,315.539 193.803,315.17 ccw(c193.935,315.17) 193.935,315.038 194.199,315.038 ccw(c194.199,315.17) 194.331,315.17 194.331,315.407 cw(c194.463,315.407) 194.463,315.539 194.681,315.539 ; 194.784,315.642 194.961,315.819 195.268,316.126 cw(c195.37,316.024) 195.473,316.126 195.865,315.734 ccw(c195.967,315.836) 196.07,315.734 196.274,315.939 ccw(c196.172,316.041) 196.274,316.144 195.882,316.536 cw(c195.985,316.638) 195.882,316.741 196.087,316.945 cw(c196.19,316.843) 196.292,316.945 196.688,316.55 ccw(c196.79,316.652) 196.892,316.55 197.097,316.755 ccw(c196.995,316.857) 197.097,316.96 196.702,317.355 cw(c196.804,317.457) 196.702,317.56 196.907,317.765 cw(c197.009,317.662) 197.111,317.765 197.524,317.352 ccw(c197.626,317.455) 197.729,317.352 197.933,317.557 ccw(c197.831,317.66) 197.933,317.762 197.521,318.174 cw(c197.623,318.277) 197.521,318.379 197.726,318.584 cw(c197.828,318.482) 197.931,318.584 198.376,318.139 ccw(c198.478,318.241) 198.581,318.139 198.786,318.344 ccw(c198.683,318.446) 198.786,318.549 198.34,318.994 cw(c198.443,319.096) 198.34,319.199 198.545,319.403 cw(c198.648,319.301) 198.75,319.403 199.174,318.98 ccw(c199.276,319.082) 199.378,318.98 199.583,319.185 ccw(c199.481,319.287) 199.583,319.39 199.16,319.813 cw(c199.262,319.916) 199.16,320.018 199.365,320.223 cw(c199.467,320.12) 199.569,320.223 199.97,319.822 ccw(c200.072,319.925) 200.175,319.822 200.38,320.027 ccw(c200.277,320.13) 200.38,320.232 199.979,320.633 cw(c200.082,320.735) 199.979,320.837 200.184,321.042 cw(c200.286,320.94) 200.389,321.042 200.781,320.65 ccw(c200.883,320.752) 200.986,320.65 201.191,320.855 ccw(c201.088,320.957) 201.191,321.06 200.798,321.452 cw(c200.901,321.554) 200.798,321.657 201.003,321.862 cw(c201.106,321.759) 201.208,321.862 201.6,321.469 ccw(c201.703,321.572) 201.805,321.469 202.01,321.674 ccw(c201.907,321.777) 202.01,321.879 201.618,322.271 cw(c201.72,322.374) 201.618,322.476 201.823,322.681 cw(c201.925,322.578) 202.027,322.681 202.094,322.614 ccw(c202.196,322.717) 202.299,322.614 202.504,322.819 ccw(c202.401,322.922) 202.504,323.024 202.437,323.091 cw(c202.54,323.193) 202.437,323.295 202.54,323.398
DDR4_A5: R41.1 U1.AK27 U8.P5 U9.P5 U10.P5 U11.P5 | length 102
  L1 w0.1: U9.P5@166.876,338.46 167.272,338.857 v1(167.275,338.857) ; U11.P5@178.336,338.46 178.733,338.857 v1(178.735,338.857) ; U10.P5@189.797,338.46 190.193,338.857 v1(190.196,338.857) ; U1.AK27@191.397,314.539 v2(191.884,315.027) ; v1(200.853,338.864) U8.P5@201.257,338.46
  L1 w0.155: R41.1@158.737,341.233 v1(159.982,341.233)
  L12 (Sign) w0.081: 165.251,338.857 167.296,338.857 167.712,339.273 168.241,339.273 168.729,339.761 168.729,340.057 169.018,340.347 169.018,340.568 169.795,341.345 172.795,341.345 175.283,338.857 175.336,338.857 175.377,338.857 ccw(c175.377,338.973) 175.492,338.973 175.492,338.978 cw(c175.608,338.978) 175.608,339.094 175.763,339.094 cw(c175.763,338.978) 175.878,338.978 175.878,338.973 ccw(c175.994,338.973) 175.994,338.857 176.276,338.857 176.479,338.857 176.52,338.857 ccw(c176.52,338.957) 176.62,338.957 176.62,338.979 cw(c176.721,338.979) 176.721,339.079 176.855,339.079 cw(c176.855,338.979) 176.956,338.979 176.956,338.841 ccw(c177.056,338.841) 177.056,338.74 177.19,338.74 ccw(c177.19,338.841) 177.291,338.841 177.291,338.958 cw(c177.391,338.958) 177.391,339.058 177.525,339.058 cw(c177.525,338.958) 177.626,338.958 ccw(c177.727,338.957) 177.727,338.857 178.233,338.857 v1(178.735,338.857) 178.793,338.915 179.041,338.915 179.373,339.247 179.443,339.247 179.451,339.255 179.685,339.255 180.562,340.131 180.562,340.288 181.578,341.304 183.935,341.304 184.034,341.204 185.725,341.204 188.065,338.864 189.665,338.864 189.672,338.857 v1(190.196,338.857) 190.385,339.047 190.609,339.047 190.829,339.266 191.157,339.266 192.031,340.14 192.031,340.29 193.032,341.291 196.689,341.291 196.955,341.026 cw(c196.896,340.967) 196.955,340.907 196.74,340.693 ccw(c196.8,340.634) 196.74,340.574 196.859,340.456 ccw(c196.918,340.515) 196.978,340.456 197.38,340.858 cw(c197.439,340.799) 197.499,340.858 197.617,340.74 cw(c197.558,340.681) 197.617,340.621 197.311,340.315 ccw(c197.37,340.256) 197.311,340.197 197.43,340.078 ccw(c197.489,340.138) 197.548,340.078 197.666,340.196 cw(c197.725,340.137) 197.784,340.196 198.884,339.097 199.117,338.864 v1(200.853,338.864)
  L12 (Sign) w0.151: v1(159.982,341.233) 160.607,341.233 161.446,340.395 161.491,340.395 163.029,338.857 165.251,338.857
  L3 (Sign) w0.081: 188.941,318.539 188.588,318.187 188.563,318.187 188.563,317.061 189.328,316.297 189.328,315.791 188.718,315.182 188.718,314.916 188.907,314.728 189.391,314.728 189.605,314.514 190.167,314.514 190.322,314.668 191.091,314.668 191.271,314.847 191.271,315.413 191.419,315.562 191.671,315.562 191.711,315.522 191.711,315.2 v2(191.884,315.027) ; 195.212,324.064 195.212,324.218 195.212,324.298 ccw(c195.093,324.298) 195.093,324.417 194.431,324.417 cw(c194.431,324.536) 194.312,324.536 194.312,324.694 cw(c194.431,324.694) 194.431,324.813 195.212,324.813 195.519,324.813 ccw(c195.519,324.933) 195.638,324.933 195.638,325.091 ccw(c195.519,325.091) 195.519,325.21 195.212,325.21 194.431,325.21 cw(c194.431,325.329) 194.312,325.329 194.312,325.488 cw(c194.431,325.488) 194.431,325.607 195.212,325.607 195.519,325.607 ccw(c195.519,325.726) 195.638,325.726 195.638,325.885 ccw(c195.519,325.885) 195.519,326.004 195.212,326.004 194.431,326.004 cw(c194.431,326.123) 194.312,326.123 194.312,326.282 cw(c194.431,326.282) 194.431,326.401 195.212,326.401 196.67,326.401 ccw(c196.67,326.52) 196.789,326.52 196.789,326.678 ccw(c196.67,326.678) 196.67,326.797 195.212,326.797 194.405,326.797 cw(c194.405,326.917) 194.286,326.917 194.286,327.075 cw(c194.405,327.075) 194.405,327.194 195.093,327.194 ccw(c195.093,327.313) 195.212,327.313 195.212,328.092 195.212,331.064 196.438,332.29 196.438,335.517 199.777,338.857 200.861,338.857 v1(200.853,338.864)
  L3 (Sign) w0.172: 188.941,318.539 189.438,319.037 190.184,319.037 195.212,324.064
DDR4_A6: R43.1 U1.AF27 U8.P2 U9.P2 U10.P2 U11.P2 | length 105.5
  L1 w0.1: U9.P2@171.676,338.46 v1(172.079,338.864) ; U11.P2@183.136,338.46 v1(183.54,338.864) ; U1.AF27@187.397,314.539 v2(187.884,314.052) ; U10.P2@194.597,338.46 v1(195,338.864) ; U8.P2@206.057,338.46 v1(206.461,338.864)
  L1 w0.155: v2(178.481,343.555) R43.1@178.481,344.799
  L5 (Sign) w0.081: v1(172.079,338.864) 173.515,338.864 173.911,339.26 174.665,339.26 175.091,339.26 cw(c175.091,339.145) 175.207,339.145 175.207,338.757 ccw(c175.323,338.757) 175.323,338.641 175.477,338.641 ccw(c175.477,338.757) 175.593,338.757 175.593,339.731 cw(c175.709,339.731) 175.709,339.847 175.863,339.847 cw(c175.863,339.731) 175.979,339.731 175.979,339.376 ccw(c176.095,339.376) 176.095,339.26 176.446,339.26 180.228,339.26 181.015,338.473 182.576,338.473 182.966,338.864 v1(183.54,338.864) 183.839,338.864 184.217,339.242 185.391,339.242 185.432,339.242 ccw(c185.432,339.358) 185.548,339.358 185.548,339.596 cw(c185.663,339.596) 185.663,339.712 185.818,339.712 cw(c185.818,339.596) 185.934,339.596 185.934,338.889 ccw(c186.049,338.889) 186.049,338.773 186.204,338.773 ccw(c186.204,338.889) 186.32,338.889 186.32,339.429 cw(c186.435,339.429) 186.435,339.545 186.59,339.545 cw(c186.59,339.429) 186.706,339.429 186.706,339.358 ccw(c186.821,339.358) 186.821,339.242 187.897,339.242 189.587,339.242 189.592,339.248 191.157,339.248 191.162,339.242 191.707,339.242 192.475,338.473 193.634,338.473 193.641,338.48 194.043,338.48 194.427,338.864 v1(195,338.864) 195.227,338.864 195.623,339.26 196.613,339.26 196.653,339.26 ccw(c196.653,339.344) 196.737,339.344 196.737,339.646 cw(c196.821,339.646) 196.821,339.73 196.989,339.73 cw(c196.989,339.646) 197.072,339.646 197.072,338.934 ccw(c197.156,338.934) 197.156,338.85 197.324,338.85 ccw(c197.324,338.934) 197.408,338.934 197.408,339.646 cw(c197.491,339.646) 197.491,339.73 197.659,339.73 cw(c197.659,339.646) 197.743,339.646 197.743,338.934 ccw(c197.827,338.934) 197.827,338.85 197.994,338.85 ccw(c197.994,338.934) 198.078,338.934 198.078,339.646 cw(c198.162,339.646) 198.162,339.73 198.329,339.73 cw(c198.329,339.646) 198.413,339.646 198.413,338.992 ccw(c198.497,338.992) 198.497,338.908 198.665,338.908 ccw(c198.665,338.992) 198.748,338.992 198.748,339.177 cw(c198.832,339.177) 198.832,339.26 199.194,339.26 199.518,339.26 199.558,339.26 ccw(c199.558,339.376) 199.674,339.376 199.674,339.5 cw(c199.79,339.5) 199.79,339.616 199.944,339.616 cw(c199.944,339.5) 200.06,339.5 200.06,339.376 ccw(c200.176,339.376) 200.176,339.26 200.358,339.26 203.149,339.26 203.763,338.646 204.027,338.646 204.208,338.465 205.489,338.465 205.887,338.864 v1(206.461,338.864)
  L3 (Sign) w0.081: v1(172.079,338.864) 173.022,339.807 173.892,339.807 175.171,341.085 175.706,341.085 178.176,343.555 v2(178.481,343.555) ; v2(187.884,314.052) 187.884,314.03 188.227,313.687 188.227,313.068 188.768,312.526 192.381,312.526 192.397,312.543 ; 203.492,323.964 203.984,324.456 203.984,333.873 203.586,334.271 203.586,335.013 204.633,336.06 205.761,336.06 205.836,336.06 206.075,336.299 206.075,337.395 205.791,337.679 205.791,338.496 206.148,338.853 206.449,338.853 v1(206.461,338.864)
  L3 (Sign) w0.172: 192.397,312.543 192.405,312.551 ; 195.878,312.551 203.492,320.165 203.492,323.964
  L3 (Sign) w0.173: 192.405,312.551 192.917,312.551 cw(c192.917,312.425) 193.043,312.425 193.043,312.329 ccw(c193.169,312.329) 193.169,312.203 193.547,312.203 ccw(c193.547,312.329) 193.673,312.329 193.673,312.551 193.673,313.721 cw(c193.799,313.721) 193.799,313.847 194.177,313.847 cw(c194.177,313.721) 194.303,313.721 194.303,312.551 194.303,312.329 ccw(c194.429,312.329) 194.429,312.203 194.807,312.203 ccw(c194.807,312.329) 194.933,312.329 194.933,312.551 194.933,313.721 cw(c195.059,313.721) 195.059,313.847 195.437,313.847 cw(c195.437,313.721) 195.563,313.721 195.563,312.677 ccw(c195.689,312.677) 195.689,312.551 195.878,312.551
DDR4_A7: R45.1 U1.AE27 U8.R5 U9.R5 U10.R5 U11.R5 | length 103.9
  L1 w0.1: U9.R5@166.876,339.26 v1(167.279,339.664) ; U11.R5@178.336,339.26 178.733,339.657 v1(178.735,339.657) ; U1.AE27@186.397,314.539 v2(186.884,315.027) v2@186.884,315.052 ; U10.R5@189.797,339.26 190.193,339.657 v1(190.195,339.657) ; v1(200.853,339.664) U8.R5@201.257,339.26
  L1 w0.155: R45.1@158.737,343.411 159.037,343.111 v1(159.576,343.111)
  L12 (Sign) w0.081: 165.251,340.06 166.076,340.06 166.576,339.56 167.178,339.56 168.741,341.123 169.061,341.123 169.645,341.707 172.945,341.707 174.592,340.06 174.994,340.06 175.035,340.06 ccw(c175.035,340.176) 175.151,340.176 175.151,340.617 cw(c175.266,340.617) 175.266,340.733 175.421,340.733 cw(c175.421,340.617) 175.537,340.617 175.537,339.898 ccw(c175.652,339.898) 175.652,339.782 175.807,339.782 ccw(c175.807,339.898) 175.923,339.898 175.923,339.945 cw(c176.038,339.945) 176.038,340.06 176.318,340.06 177.396,340.06 177.437,340.06 ccw(c177.437,340.178) 177.554,340.178 177.554,340.306 cw(c177.671,340.306) 177.671,340.423 177.772,340.423 cw(c177.772,340.306) 177.889,340.306 177.889,340.178 ccw(c178.006,340.178) 178.006,340.06 178.332,340.06 v1(178.735,339.657) 178.926,339.657 179.33,340.062 179.824,340.062 181.428,341.666 184.938,341.666 185.038,341.566 186.98,341.566 187.406,341.566 cw(c187.406,341.45) 187.522,341.45 187.522,341.316 ccw(c187.638,341.316) 187.638,341.2 187.792,341.2 ccw(c187.792,341.316) 187.908,341.316 187.908,341.45 cw(c188.024,341.45) 188.024,341.566 188.286,341.566 v1(190.195,339.657) 192.192,341.653 193.731,341.653 194.003,341.925 194.277,342.199 cw(c194.336,342.14) 194.42,342.14 194.42,342.044 ccw(c194.504,342.044) 194.504,341.96 194.672,341.96 ccw(c194.672,342.044) 194.755,342.044 194.755,342.287 cw(c194.839,342.287) 194.839,342.371 195.618,342.371 196.787,342.371 199.382,339.776 199.494,339.664 199.553,339.664 199.594,339.664 ccw(c199.594,339.748) 199.677,339.748 199.677,340.049 cw(c199.761,340.049) 199.761,340.133 199.929,340.133 cw(c199.929,340.049) 200.013,340.049 200.013,339.538 ccw(c200.096,339.538) 200.096,339.454 200.264,339.454 ccw(c200.264,339.538) 200.348,339.538 200.348,339.58 cw(c200.432,339.58) 200.432,339.664 200.614,339.664 v1@200.846,339.664
  L12 (Sign) w0.151: v1(159.576,343.111) 161.163,343.111 164.214,340.06 165.251,340.06
  L3 (Sign) w0.079: 193.002,327.8 193.002,327.817 193.232,328.046 193.568,328.046 193.782,328.261 193.782,329.096 193.782,330.218 193.54,330.46 193.406,330.46 192.878,330.989 192.878,331.799 193.125,332.046 193.621,332.046 193.764,332.189 193.764,333.502 ; 193.853,333.591 193.937,333.674 194.354,333.674 194.585,333.905 194.658,333.905
  L3 (Sign) w0.081: v2(186.884,315.027) 186.884,315.074 186.615,315.344 185.419,316.539 185.419,317.004 185.788,317.373 186.627,317.373 187.413,318.148 187.804,318.539 ; 193.002,327.8 193.002,327.337 193.223,327.116 193.597,327.116 193.661,327.052 193.661,326.785 ; 193.764,333.502 193.853,333.591 ; 194.658,333.905 196.03,335.277 196.03,335.652 199.618,339.241 199.993,339.241 200.199,339.447 200.374,339.447 200.541,339.615 200.804,339.615 v1(200.853,339.664)
  L3 (Sign) w0.172: 187.804,318.539 188.907,319.642 190.018,319.642 190.051,319.676 ; 193.661,323.286 193.661,323.615 193.661,323.701 ccw(c193.489,323.701) 193.489,323.873 192.683,323.873 cw(c192.683,323.989) 192.567,323.989 192.567,324.336 cw(c192.683,324.336) 192.683,324.451 193.548,324.451 ccw(c193.548,324.567) 193.664,324.567 193.664,324.914 ccw(c193.548,324.914) 193.548,325.03 193.049,325.03 cw(c193.049,325.145) 192.933,325.145 192.933,325.493 cw(c193.049,325.493) 193.049,325.608 193.489,325.608 ccw(c193.489,325.78) 193.661,325.78 193.661,326.785
  L3 (Sign) w0.173: 190.051,319.676 190.109,319.733 190.389,320.014 ccw(c190.296,320.107) 190.389,320.201 189.751,320.839 cw(c189.844,320.933) 189.751,321.026 189.938,321.213 cw(c190.031,321.12) 190.125,321.213 190.763,320.575 ccw(c190.857,320.668) 190.95,320.575 191.137,320.762 ccw(c191.044,320.855) 191.137,320.949 190.499,321.587 cw(c190.592,321.681) 190.499,321.774 190.686,321.961 cw(c190.779,321.868) 190.872,321.961 191.511,321.323 ccw(c191.604,321.416) 191.698,321.323 191.885,321.51 ccw(c191.791,321.603) 191.885,321.696 191.246,322.335 cw(c191.34,322.428) 191.246,322.522 191.433,322.709 cw(c191.527,322.615) 191.62,322.709 192.259,322.07 ccw(c192.352,322.164) 192.446,322.07 192.633,322.257 ccw(c192.539,322.351) 192.633,322.444 191.994,323.083 cw(c192.088,323.176) 191.994,323.27 192.181,323.457 cw(c192.275,323.363) 192.368,323.457 193.007,322.818 ccw(c193.1,322.912) 193.193,322.818 193.474,323.099 193.661,323.286
DDR4_A8: R47.1 U1.AF26 U8.R2 U9.R2 U10.R2 U11.R2 | length 104.3
  L1 w0.1: U9.R2@171.676,339.26 v1(172.079,339.664) ; U11.R2@183.136,339.26 v1(183.54,339.664) ; U1.AF26@187.397,313.539 187.397,313.475 187.778,313.094 v2(187.778,313.052) ; U10.R2@194.597,339.26 v1(195,339.664) ; U8.R2@206.057,339.26 v1(206.461,339.664)
  L1 w0.155: v2(177.272,343.555) R47.1@177.272,344.8
  L5 (Sign) w0.081: v1(172.079,339.664) 173.045,339.664 174.416,341.035 177.207,341.035 177.247,341.035 ccw(c177.247,341.151) 177.363,341.151 177.363,341.22 cw(c177.479,341.22) 177.479,341.335 177.633,341.335 cw(c177.633,341.22) 177.749,341.22 177.749,340.357 ccw(c177.865,340.357) 177.865,340.241 178.019,340.241 ccw(c178.019,340.357) 178.135,340.357 178.135,341.177 cw(c178.251,341.177) 178.251,341.293 178.405,341.293 cw(c178.405,341.177) 178.521,341.177 178.521,341.151 ccw(c178.637,341.151) 178.637,341.035 179.331,341.035 179.665,341.035 181.44,339.26 182.336,339.26 182.74,339.664 v1(183.54,339.664) 183.548,339.664 184.242,340.358 184.242,340.366 184.803,340.927 184.976,340.927 185.253,340.927 cw(c185.253,340.858) 185.322,340.858 185.322,340.784 ccw(c185.391,340.784) 185.391,340.715 185.599,340.715 ccw(c185.599,340.784) 185.668,340.784 185.668,340.927 185.668,341.037 cw(c185.737,341.037) 185.737,341.106 185.945,341.106 cw(c185.945,341.037) 186.014,341.037 186.014,340.996 ccw(c186.084,340.996) 186.084,340.927 186.118,340.927 189.587,340.927 189.639,340.979 190.679,340.979 190.731,340.927 191.377,340.927 193.044,339.26 193.797,339.26 194.2,339.664 v1(195,339.664) 195.408,339.664 195.846,340.102 195.846,340.481 196.292,340.927 196.472,340.927 196.512,340.927 ccw(c196.512,341.011) 196.596,341.011 196.596,341.289 cw(c196.68,341.289) 196.68,341.373 196.847,341.373 cw(c196.847,341.289) 196.931,341.289 196.931,340.319 ccw(c197.015,340.319) 197.015,340.235 197.182,340.235 ccw(c197.182,340.319) 197.266,340.319 197.266,341.289 cw(c197.35,341.289) 197.35,341.373 197.518,341.373 cw(c197.518,341.289) 197.601,341.289 197.601,340.817 ccw(c197.685,340.817) 197.685,340.734 197.853,340.734 ccw(c197.853,340.817) 197.937,340.817 197.937,340.843 cw(c198.02,340.843) 198.02,340.927 198.282,340.927 203.218,340.927 204.038,340.107 204.038,339.801 204.579,339.26 205.257,339.26 205.661,339.664 v1(206.461,339.664)
  L3 (Sign) w0.079: 205.247,327.071 205.261,327.057 ; 205.247,334.241 205.247,335.034 205.282,335.069 205.282,335.145 205.405,335.267 205.928,335.267 206.12,335.459 206.256,335.459 ; 205.264,327.054 205.282,327.035
  L3 (Sign) w0.081: v1(172.079,339.664) 172.613,340.198 173.716,340.198 177.074,343.555 v2(177.272,343.555) ; v2(187.778,313.052) 187.778,311.571 188.657,310.692 189.596,310.692 189.702,310.586 192.067,310.586 192.397,310.916 ; 205.247,327.071 205.247,330.51 205.247,330.885 cw(c205.331,330.885) 205.331,330.969 205.791,330.969 ccw(c205.791,331.053) 205.874,331.053 205.874,331.22 ccw(c205.791,331.22) 205.791,331.304 204.614,331.304 cw(c204.614,331.388) 204.53,331.388 204.53,331.556 cw(c204.614,331.556) 204.614,331.639 205.785,331.639 ccw(c205.785,331.723) 205.869,331.723 205.869,331.891 ccw(c205.785,331.891) 205.785,331.975 205.328,331.975 cw(c205.328,332.058) 205.244,332.058 205.244,332.226 cw(c205.328,332.226) 205.328,332.31 205.515,332.31 ccw(c205.515,332.394) 205.599,332.394 205.599,332.561 ccw(c205.515,332.561) 205.515,332.645 205.331,332.645 cw(c205.331,332.729) 205.247,332.729 205.247,333.055 205.247,334.241 ; 205.261,327.057 205.264,327.054 ; 206.256,335.459 206.256,337.66 206.042,337.873 206.042,338.3 206.203,338.46 206.67,338.46 206.851,338.641 206.851,339.026 206.67,339.207 206.67,339.343 206.461,339.553 v1(206.461,339.664)
  L3 (Sign) w0.172: 192.397,310.916 193.056,311.575 195.683,311.575 205.282,321.175 205.282,327.035
DDR4_A9: R48.1 U1.AG26 U8.R4 U9.R4 U10.R4 U11.R4 | length 103.7
  L1 w0.1: U9.R4@167.676,339.26 v1(168.079,339.664) ; U11.R4@179.136,339.26 179.533,339.657 v1(179.535,339.657) ; U1.AG26@188.397,313.539 188.884,314.027 v2(188.884,314.079) ; U10.R4@190.597,339.26 190.993,339.657 v1(190.995,339.657) ; v1(201.653,339.664) U8.R4@202.057,339.26
  L1 w0.155: R48.1@158.737,342.322 R48.1@158.787,342.322 v1(159.982,342.322)
  L12 (Sign) w0.081: 165.251,339.26 167.443,339.26 167.847,339.664 v1(168.079,339.664) 168.837,340.422 168.837,340.643 169.72,341.526 172.87,341.526 175.136,339.26 175.35,339.26 175.391,339.26 ccw(c175.391,339.376) 175.507,339.376 175.507,339.485 cw(c175.623,339.485) 175.623,339.601 175.777,339.601 cw(c175.777,339.485) 175.893,339.485 175.893,339.376 ccw(c176.009,339.376) 176.009,339.26 176.291,339.26 177.445,339.26 177.486,339.26 ccw(c177.486,339.376) 177.602,339.376 177.602,339.764 cw(c177.717,339.764) 177.717,339.879 177.872,339.879 cw(c177.872,339.764) 177.988,339.764 177.988,339.376 ccw(c178.103,339.376) 178.103,339.26 178.429,339.26 179.13,339.26 179.527,339.657 v1(179.535,339.657) 179.613,339.657 179.837,339.881 179.899,339.881 181.503,341.485 184.01,341.485 184.109,341.385 186.081,341.385 188.227,339.239 189.804,339.239 189.832,339.266 190.573,339.266 190.963,339.657 v1(190.995,339.657) 191.173,339.835 192.231,340.892 192.811,341.472 195.997,341.472 196.037,341.472 ccw(c196.037,341.556) 196.121,341.556 196.121,342.052 cw(c196.205,342.052) 196.205,342.136 196.373,342.136 cw(c196.373,342.052) 196.456,342.052 196.456,341.556 ccw(c196.54,341.556) 196.54,341.472 197.167,341.472 199.366,339.273 201.263,339.273 v1(201.653,339.664)
  L12 (Sign) w0.151: v1(159.982,342.322) 163.044,339.26 165.251,339.26
  L3 (Sign) w0.079: 187.413,317.13 187.425,317.13 187.688,317.393 188.052,317.393 188.309,317.136 188.309,317.043 188.442,316.911 ; 194.571,328.003 194.807,328.239 194.807,328.89 194.807,328.929 ccw(c194.711,328.929) 194.711,329.025 194.057,329.025 cw(c194.057,329.121) 193.961,329.121 193.961,329.313 cw(c194.057,329.313) 194.057,329.409 194.936,329.409 ccw(c194.936,329.505) 195.032,329.505 195.032,329.697 ccw(c194.936,329.697) 194.936,329.793 194.678,329.793 cw(c194.678,329.889) 194.582,329.889 194.582,330.081 cw(c194.678,330.081) 194.678,330.177 194.936,330.177 ccw(c194.936,330.273) 195.032,330.273 195.032,330.465 ccw(c194.936,330.465) 194.936,330.561 193.789,330.561 cw(c193.789,330.657) 193.693,330.657 193.693,330.849 cw(c193.789,330.849) 193.789,330.945 194.711,330.945 ccw(c194.711,331.041) 194.807,331.041 194.807,331.28 194.591,331.495 ; 194.591,331.811 194.834,332.053 195.929,332.053 196.222,332.346
  L3 (Sign) w0.081: 187.413,317.13 187.413,316.905 187.22,316.713 186.991,316.713 186.76,316.944 186.76,317.167 187.715,318.122 187.935,318.122 188.352,318.539 ; 188.442,316.911 189.127,316.225 189.127,315.862 188.527,315.261 188.527,314.836 188.884,314.479 v2(188.884,314.079) ; 193.936,326.785 193.936,327.368 194.571,328.003 ; 194.591,331.495 194.591,331.811 ; 196.222,332.346 196.222,332.498 196.222,332.538 ccw(c196.125,332.538) 196.125,332.635 194.664,332.635 cw(c194.664,332.731) 194.567,332.731 194.567,332.924 cw(c194.664,332.924) 194.664,333.021 196.16,333.021 ccw(c196.16,333.117) 196.257,333.117 196.257,333.31 ccw(c196.16,333.31) 196.16,333.407 194.898,333.407 cw(c194.898,333.503) 194.801,333.503 194.801,333.696 cw(c194.898,333.696) 194.898,333.793 196.125,333.793 ccw(c196.125,333.889) 196.222,333.889 196.222,334.386 196.222,335.573 199.698,339.049 200.073,339.049 200.279,339.255 201.536,339.255 201.653,339.372 v1(201.653,339.664)
  L3 (Sign) w0.172: 188.352,318.539 189.128,319.316 190.077,319.316 193.936,323.175 193.936,326.785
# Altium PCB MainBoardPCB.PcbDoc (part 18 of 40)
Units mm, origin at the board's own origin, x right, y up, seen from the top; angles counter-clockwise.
Board outline 258.95 x 308.86 mm, 16 copper layers (L1, L2 (GND), L3 (Sign), L4 (GND), L5 (Sign), L6 (PWR/GND), L7(12V+Other), L8 (Plane_GND), L9 (PWR/GND), L10 (3V3+Other), L11 (PWR/GND), L12 (Sign), L13 (GND), L14 (Sign), L15 (GND), L16), stack 2.503 mm thick; 2578 components, 1867 nets, 8817 pads, 8021 vias.
Unrouted connection lines stored in the file: 25.

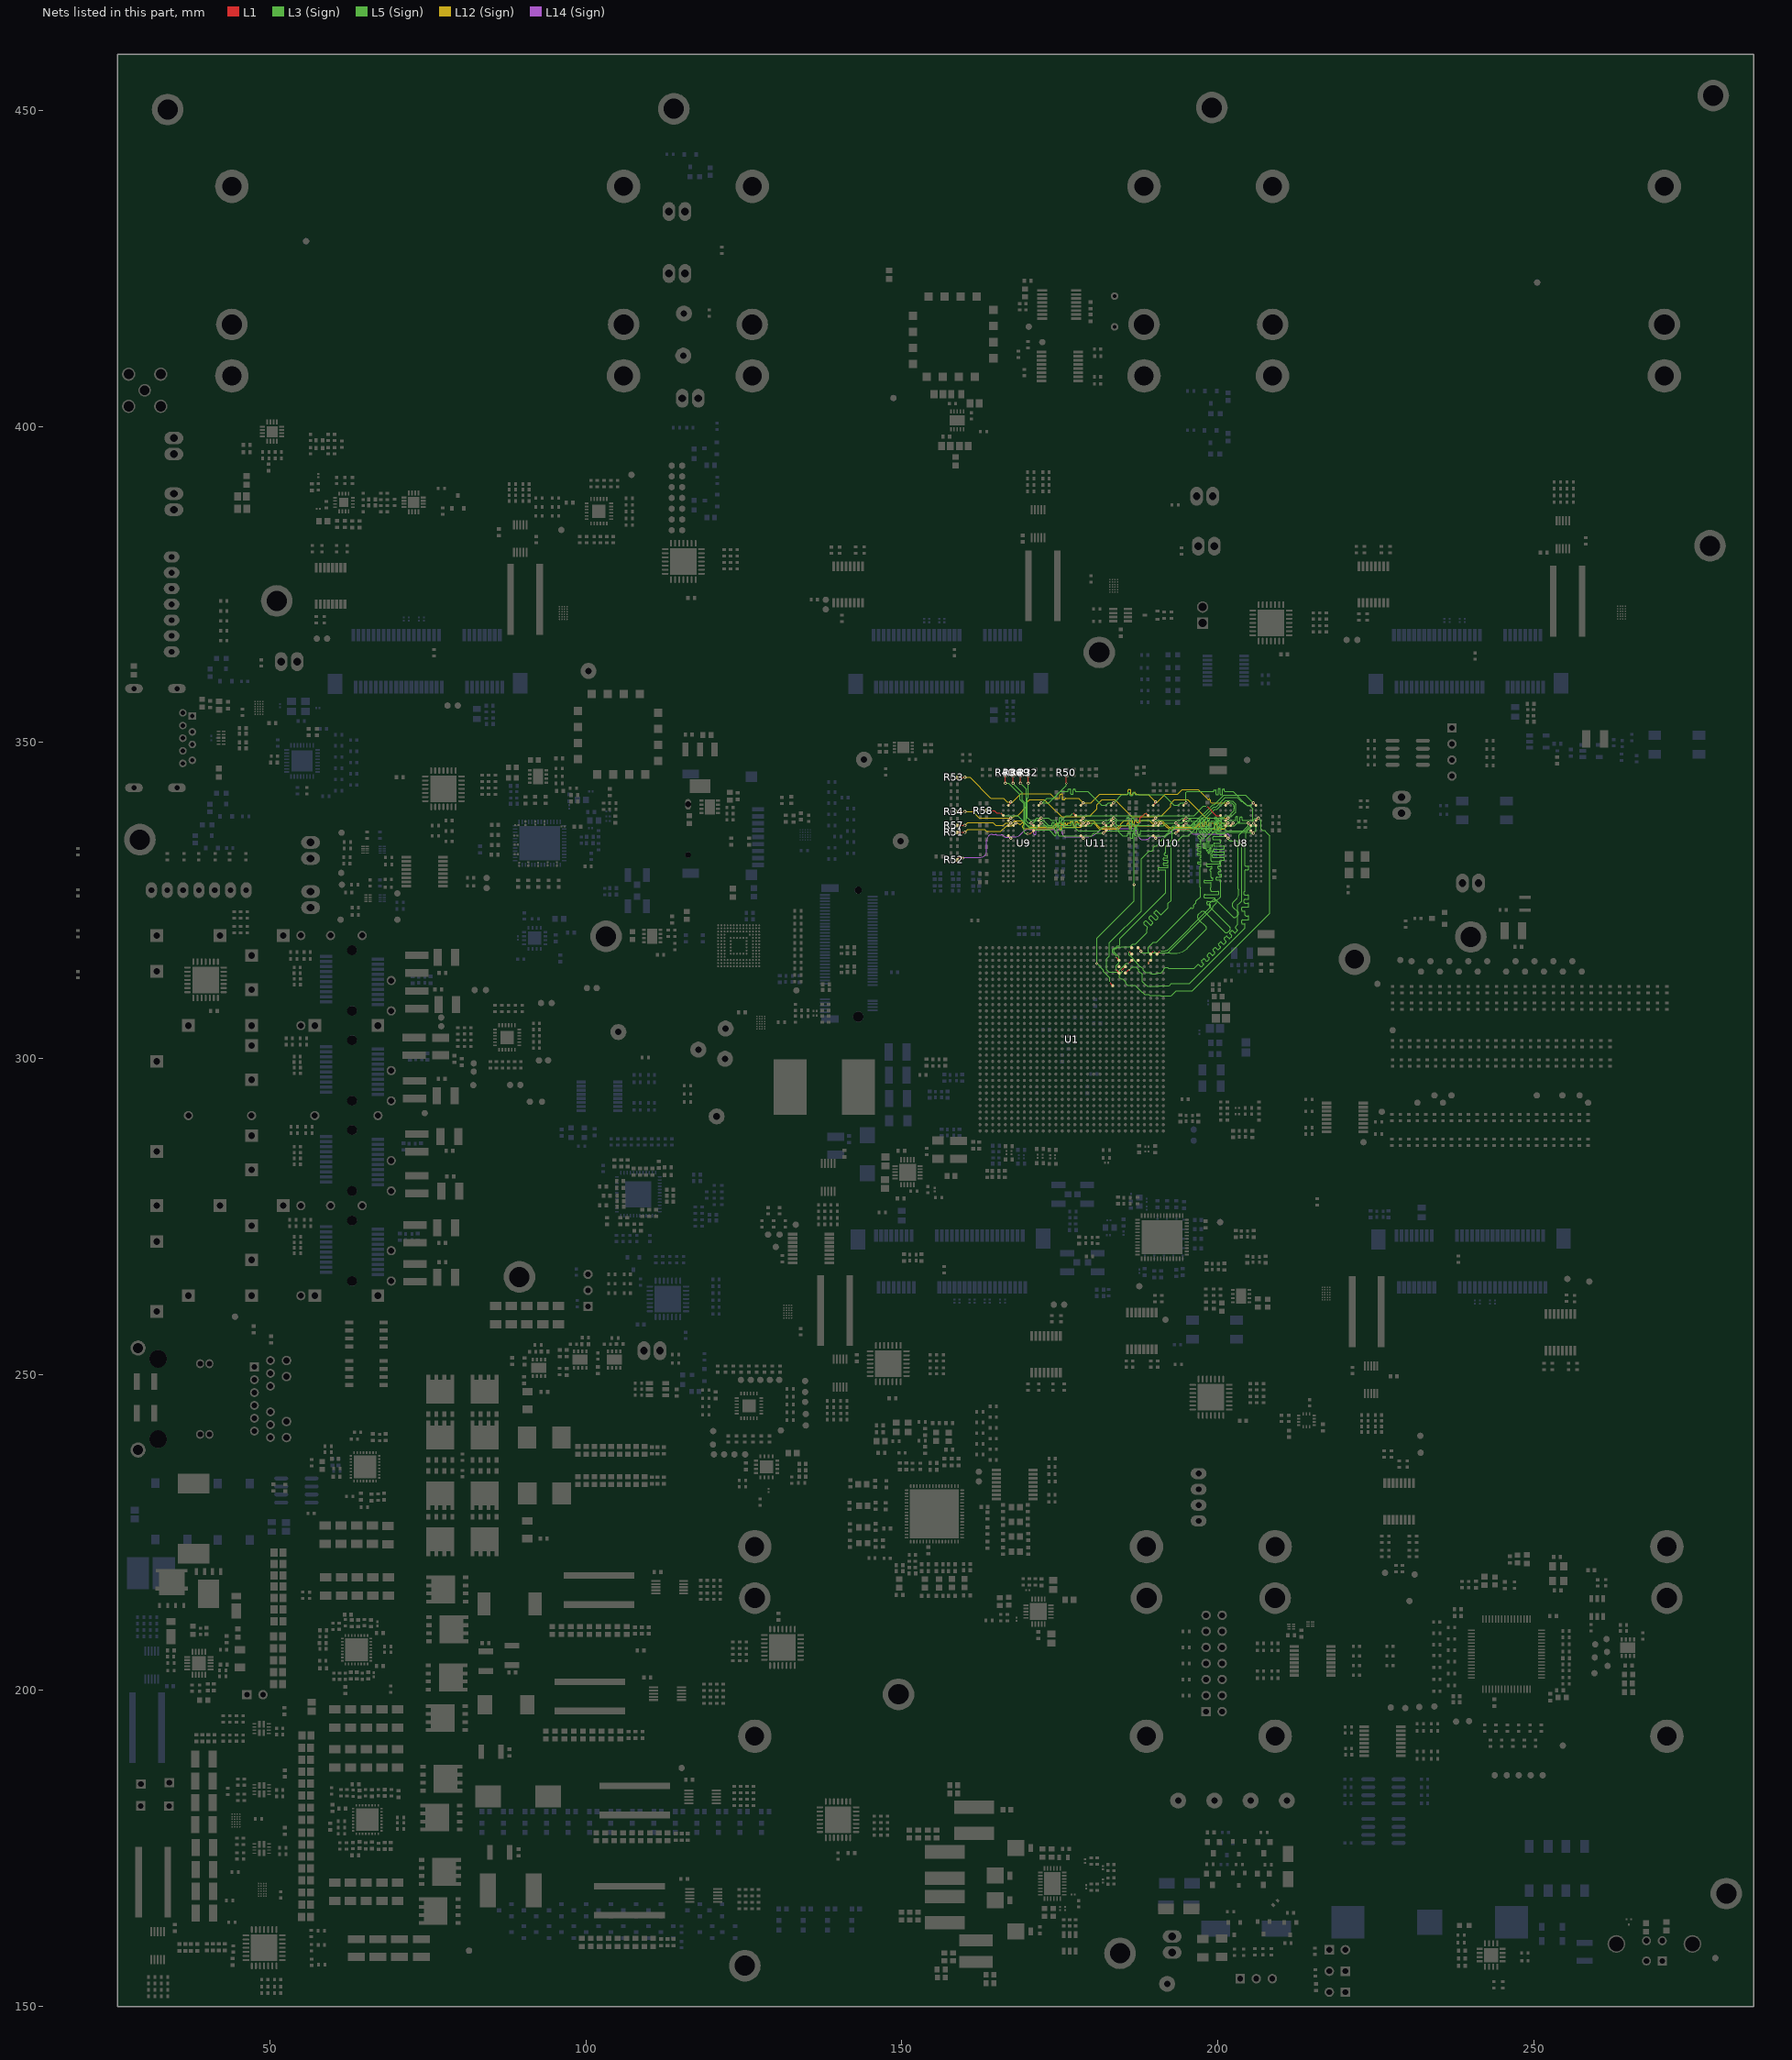
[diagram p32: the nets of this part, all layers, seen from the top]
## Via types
v1: diameter 0.5, hole 0.25, L1 to L16, tented both sides, 4341 vias
v2: diameter 0.254, hole 0.1, L1 to L3 (Sign), tented both sides, 781 vias
v3: diameter 0.5, hole 0.25, L1 to L16, 565 vias
v4: diameter 0.254, hole 0.1, L15 (GND) to L16, tented both sides, 406 vias
v5: diameter 0.254, hole 0.1, L1 to L2 (GND), tented both sides, 283 vias
v6: diameter 0.457, hole 0.2, L3 (Sign) to L6 (PWR/GND), tented both sides, 254 vias
v7: diameter 0.254, hole 0.1, L1 to L3 (Sign), 237 vias
v8: diameter 0.75, hole 0.4, L1 to L16, 200 vias
v9: diameter 0.8, hole 0.4, L1 to L16, tented both sides, 182 vias
v10: diameter 0.254, hole 0.1, L14 (Sign) to L16, tented both sides, 170 vias
v11: diameter 0.75/0/0/0/0/0/0/0/0/0/0/0/0/0/0/0.75 (per signal layer), hole 0.4, L1 to L16, 160 vias
v12: diameter 0.457, hole 0.2, L3 (Sign) to L6 (PWR/GND), 158 vias
v13: diameter 1.4, hole 0.5, L1 to L16, tented both sides, 80 vias
v14: diameter 0.254, hole 0.1, L14 (Sign) to L16, 65 vias
v15: diameter 0.254, hole 0.1, L1 to L2 (GND), 45 vias
v16: diameter 0.457, hole 0.2, L11 (PWR/GND) to L14 (Sign), tented both sides, 26 vias
v17: diameter 0.457, hole 0.2, L11 (PWR/GND) to L14 (Sign), 25 vias
v18: diameter 0.457, hole 0.2, L7(12V+Other) to L10 (3V3+Other), tented both sides, 11 vias
v19: diameter 0.254/0/0.254 (per signal layer), hole 0.1, L1 to L3 (Sign), 9 vias
v20: diameter 0.2/0/0.2 (per signal layer), hole 0.1, L1 to L3 (Sign), 6 vias
v21: diameter 1.65, hole 1.65, L1 to L16, 5 vias
v22: diameter 1.15, hole 1.15, L1 to L16, 5 vias
v23: diameter 0.457, hole 0.2, L1 to L16, 3 vias
v24: diameter 0.5, hole 0.3, L1 to L16, 2 vias
v25: diameter 0.5/0/0.5 (per signal layer), hole 0.2, L14 (Sign) to L16, 1 vias
v26: diameter 0.5, hole 0.25, L1 to L16, tented bottom, 1 vias

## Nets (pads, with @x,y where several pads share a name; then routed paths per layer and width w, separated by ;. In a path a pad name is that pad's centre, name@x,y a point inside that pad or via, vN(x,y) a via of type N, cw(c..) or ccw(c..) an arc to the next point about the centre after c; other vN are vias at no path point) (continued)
DDR4_A10: R49.1 U1.AE29 U8.M3 U9.M3 U10.M3 U11.M3 | length 104.3
  L1 w0.1: v1(170.472,337.264) U9.M3@170.876,336.86 ; v1(181.933,337.264) U11.M3@182.336,336.86 ; v2(185.91,317.027) U1.AE29@186.397,316.539 ; v1(193.393,337.264) U10.M3@193.797,336.86 ; v1(204.853,337.264) U8.M3@205.257,336.86
  L1 w0.155: v1(168.812,343.555) R49.1@168.812,344.799
  L5 (Sign) w0.081: v1(168.812,343.555) 169.698,342.668 169.698,337.566 170.001,337.264 v1(170.472,337.264) 170.838,337.264 171.242,337.668 172.431,337.668 173.231,336.868 173.637,336.868 173.678,336.868 ccw(c173.678,336.983) 173.794,336.983 173.794,337.221 cw(c173.91,337.221) 173.91,337.337 174.064,337.337 cw(c174.064,337.221) 174.18,337.221 174.18,336.983 ccw(c174.296,336.983) 174.296,336.868 174.65,336.868 176.679,336.868 176.72,336.868 ccw(c176.72,336.983) 176.835,336.983 176.835,337.22 cw(c176.951,337.22) 176.951,337.336 177.106,337.336 cw(c177.106,337.22) 177.221,337.22 177.221,336.842 ccw(c177.337,336.842) 177.337,336.726 177.492,336.726 ccw(c177.492,336.842) 177.607,336.842 177.607,337.021 cw(c177.723,337.021) 177.723,337.137 177.878,337.137 cw(c177.878,337.021) 177.993,337.021 177.993,336.983 ccw(c178.109,336.983) 178.109,336.868 178.572,336.868 178.573,336.866 179.928,336.866 180.325,337.264 v1(181.933,337.264) 182.776,337.264 183.18,337.668 183.711,337.668 183.937,337.442 183.937,337.051 184.121,336.868 185.508,336.868 185.935,336.868 cw(c185.935,336.752) 186.051,336.752 186.051,336.357 ccw(c186.166,336.357) 186.166,336.241 186.321,336.241 ccw(c186.321,336.357) 186.437,336.357 186.437,336.942 cw(c186.552,336.942) 186.552,337.058 186.707,337.058 cw(c186.707,336.942) 186.823,336.942 186.823,336.684 ccw(c186.938,336.684) 186.938,336.568 187.093,336.568 ccw(c187.093,336.684) 187.209,336.684 187.209,336.752 cw(c187.324,336.752) 187.324,336.868 187.87,336.868 190.033,336.868 190.034,336.866 191.388,336.866 191.785,337.264 v1(193.393,337.264) 194.347,337.264 194.738,337.654 195.162,337.654 195.271,337.545 195.327,337.545 195.368,337.545 ccw(c195.368,337.629) 195.451,337.629 195.451,337.799 cw(c195.535,337.799) 195.535,337.883 195.703,337.883 cw(c195.703,337.799) 195.787,337.799 195.787,337.629 ccw(c195.87,337.629) 195.87,337.545 196.088,337.545 196.847,337.545 197.223,337.545 cw(c197.223,337.462) 197.307,337.462 197.307,336.753 ccw(c197.391,336.753) 197.391,336.67 197.558,336.67 ccw(c197.558,336.753) 197.642,336.753 197.642,337.462 cw(c197.726,337.462) 197.726,337.545 197.893,337.545 cw(c197.893,337.462) 197.977,337.462 197.977,336.753 ccw(c198.061,336.753) 198.061,336.67 198.229,336.67 ccw(c198.229,336.753) 198.312,336.753 198.312,337.462 cw(c198.396,337.462) 198.396,337.545 198.564,337.545 cw(c198.564,337.462) 198.648,337.462 198.648,336.931 ccw(c198.731,336.931) 198.731,336.847 198.899,336.847 ccw(c198.899,336.931) 198.983,336.931 198.983,337.462 cw(c199.067,337.462) 199.067,337.545 199.292,337.545 200.492,337.545 201.19,336.847 202.673,336.847 203.089,337.264 v1(204.853,337.264)
  L3 (Sign) w0.079: 186.239,316.126 187.205,315.16
  L3 (Sign) w0.081: v2(185.91,317.027) 185.995,316.941 185.995,316.37 186.239,316.126 ; 187.205,315.16 187.205,315.071 187.699,314.578 187.813,314.578 188.205,314.185 188.205,313.98 188.555,313.631 189.306,313.631 189.53,313.407 190.281,313.407 190.454,313.581 191.069,313.581 191.513,314.025 191.513,314.18 191.731,314.398 192.038,314.398 192.187,314.249 192.397,314.249 ; 203.378,324.508 203.803,324.933 203.803,333.798 203.405,334.196 203.405,335.374 204.853,336.822 v1(204.853,337.264)
  L3 (Sign) w0.172: 192.397,314.249 192.41,314.249 192.421,314.238 192.602,314.238 192.603,314.239 196.231,314.239 196.266,314.274 ; 203.195,321.203 203.195,324.326 203.378,324.508
  L3 (Sign) w0.173: 196.266,314.274 196.489,314.496 196.845,314.853 cw(c196.934,314.764) 197.023,314.853 197.3,314.577 ccw(c197.389,314.666) 197.478,314.577 197.745,314.844 ccw(c197.656,314.933) 197.745,315.022 197.469,315.298 cw(c197.558,315.388) 197.469,315.477 197.736,315.744 cw(c197.825,315.655) 197.915,315.744 198.191,315.468 ccw(c198.28,315.557) 198.369,315.468 198.636,315.735 ccw(c198.547,315.824) 198.636,315.913 198.36,316.19 cw(c198.449,316.279) 198.36,316.368 198.627,316.635 cw(c198.717,316.546) 198.806,316.635 199.082,316.359 ccw(c199.171,316.448) 199.26,316.359 199.528,316.626 ccw(c199.438,316.715) 199.528,316.805 199.251,317.081 cw(c199.34,317.17) 199.251,317.259 199.519,317.526 cw(c199.608,317.437) 199.697,317.526 199.973,317.25 ccw(c200.062,317.339) 200.151,317.25 200.419,317.518 ccw(c200.33,317.607) 200.419,317.696 200.143,317.972 cw(c200.232,318.061) 200.143,318.15 200.41,318.418 cw(c200.499,318.328) 200.588,318.418 200.864,318.141 ccw(c200.953,318.23) 201.043,318.141 201.31,318.409 ccw(c201.221,318.498) 201.31,318.587 201.034,318.863 cw(c201.123,318.952) 201.034,319.041 201.301,319.309 cw(c201.39,319.22) 201.479,319.309 201.756,319.033 ccw(c201.845,319.122) 201.934,319.033 202.201,319.3 ccw(c202.112,319.389) 202.201,319.478 201.925,319.754 cw(c202.014,319.844) 201.925,319.933 202.192,320.2 cw(c202.281,320.111) 202.371,320.2 202.647,319.924 ccw(c202.736,320.013) 202.825,319.924 203.092,320.191 ccw(c203.003,320.28) 203.092,320.369 202.816,320.646 cw(c202.905,320.735) 202.816,320.824 203.195,321.203
DDR4_A11: R50.1 U1.AE28 U8.T2 U9.T2 U10.T2 U11.T2 | length 103.3
  L1 w0.1: U9.T2@171.676,340.06 v1(172.079,340.464) ; U11.T2@183.136,340.06 v1(183.54,340.464) ; v2(185.91,315.052) U1.AE28@186.397,315.539 ; U10.T2@194.597,340.06 v1(195,340.464) ; v1(205.653,340.464) U8.T2@206.057,340.06
  L1 w0.155: v2(176.063,343.555) R50.1@176.063,344.8
  L5 (Sign) w0.081: v1(172.079,340.464) 172.3,340.464 173.009,341.173 173.042,341.206 173.419,341.206 173.424,341.212 174.081,341.212 175.109,342.24 176.194,342.24 176.234,342.24 ccw(c176.234,342.356) 176.35,342.356 176.35,342.54 cw(c176.466,342.54) 176.466,342.655 176.62,342.655 cw(c176.62,342.54) 176.736,342.54 176.736,341.934 ccw(c176.852,341.934) 176.852,341.819 177.006,341.819 ccw(c177.006,341.934) 177.122,341.934 177.122,342.498 cw(c177.238,342.498) 177.238,342.614 177.392,342.614 cw(c177.392,342.498) 177.508,342.498 177.508,342.356 ccw(c177.624,342.356) 177.624,342.24 178.405,342.24 179.471,342.24 181.643,340.068 182.344,340.068 182.74,340.464 v1(183.54,340.464) 183.774,340.698 184.845,341.77 185.599,341.77 185.639,341.77 ccw(c185.639,341.885) 185.755,341.885 185.755,341.935 cw(c185.871,341.935) 185.871,342.051 186.026,342.051 cw(c186.026,341.935) 186.141,341.935 186.141,341.718 ccw(c186.257,341.718) 186.257,341.602 186.412,341.602 ccw(c186.412,341.718) 186.527,341.718 186.527,341.933 cw(c186.643,341.933) 186.643,342.049 186.798,342.049 cw(c186.798,341.933) 186.913,341.933 186.913,341.885 ccw(c187.029,341.885) 187.029,341.77 187.922,341.77 188.773,341.77 189.624,341.77 191.402,341.77 193.103,340.068 193.804,340.068 194.2,340.464 v1(195,340.464) 195,342.104 195.149,342.253 199.292,342.253 199.332,342.253 ccw(c199.332,342.337) 199.416,342.337 199.416,342.438 cw(c199.5,342.438) 199.5,342.522 199.667,342.522 cw(c199.667,342.438) 199.751,342.438 199.751,341.819 ccw(c199.835,341.819) 199.835,341.735 200.003,341.735 ccw(c200.003,341.819) 200.086,341.819 200.086,342.63 cw(c200.17,342.63) 200.17,342.714 200.338,342.714 cw(c200.338,342.63) 200.422,342.63 200.422,341.819 ccw(c200.505,341.819) 200.505,341.735 200.673,341.735 ccw(c200.673,341.819) 200.757,341.819 200.757,342.546 cw(c200.841,342.546) 200.841,342.63 201.008,342.63 cw(c201.008,342.546) 201.092,342.546 201.092,342.337 ccw(c201.176,342.337) 201.176,342.253 202.31,342.253 202.404,342.253 204.411,340.246 204.411,340.236 204.579,340.068 205.265,340.068 v1(205.653,340.464)
  L3 (Sign) w0.079: 189.05,332.726 189.178,332.853 189.602,332.853 189.804,333.055 189.804,333.418 190.032,333.646 190.333,333.646 190.702,334.015 190.702,334.112
  L3 (Sign) w0.081: v1(172.079,340.464) 173.308,340.464 176.063,343.22 v2(176.063,343.555) ; 183.093,318.539 182.867,318.313 182.867,316.206 182.435,315.774 182.435,314.047 182.805,313.677 184.187,313.677 185.561,315.052 v2(185.91,315.052) v2@185.847,314.99 ; 187.909,327.035 187.909,331.585 189.05,332.726 ; 190.702,334.112 192.253,335.662 192.253,336.164 192.927,336.839 195.858,336.839 199.22,340.201 199.485,340.201 200.99,341.706 204.411,341.706 v1(205.653,340.464)
  L3 (Sign) w0.172: 183.093,318.539 187.909,323.355 187.909,327.035
DDR4_A12: R51.1 U1.AH29 U8.M4 U9.M4 U10.M4 U11.M4 | length 101.3
  L1 w0.1: U9.M4@167.676,336.86 168.072,337.257 v1(168.075,337.257) ; U11.M4@179.136,336.86 179.533,337.257 v1(179.535,337.257) ; U1.AH29@189.397,316.539 v2(189.884,317.027) ; U10.M4@190.597,336.86 190.993,337.257 v1(190.995,337.257) ; U8.M4@202.057,336.86 202.453,337.257 v1(202.456,337.257) v1@202.41,337.303
  L1 w0.155: R51.1@158.737,335.789 v1(159.982,335.789)
  L12 (Sign) w0.081: 165.251,335.943 165.692,335.943 166.604,336.855 167.425,336.855 167.598,337.028 167.778,337.028 168.006,337.257 v1(168.075,337.257) 168.084,337.248 168.445,337.248 168.616,337.076 168.645,337.047 ccw(c168.727,337.129) 168.809,337.047 169.036,337.275 cw(c169.118,337.193) 169.2,337.275 169.309,337.166 cw(c169.227,337.084) 169.309,337.002 169.082,336.774 ccw(c169.163,336.692) 169.082,336.611 169.271,336.421 169.279,336.413 173.91,336.413 174.135,336.638 174.321,336.638 174.362,336.638 ccw(c174.362,336.754) 174.478,336.754 174.478,336.865 cw(c174.594,336.865) 174.594,336.981 174.748,336.981 cw(c174.748,336.865) 174.864,336.865 174.864,336.433 ccw(c174.98,336.433) 174.98,336.317 175.134,336.317 ccw(c175.134,336.433) 175.25,336.433 175.25,336.96 cw(c175.366,336.96) 175.366,337.076 175.52,337.076 cw(c175.52,336.96) 175.636,336.96 175.636,336.754 ccw(c175.752,336.754) 175.752,336.638 176.28,336.638 178.37,336.638 178.417,336.685 178.422,336.69 cw(c178.735,336.457) 178.502,336.77 178.592,336.86 179.109,336.86 179.505,337.257 v1(179.535,337.257) 180.367,337.257 181.267,336.357 184.286,336.357 184.789,336.86 185.543,336.86 185.583,336.86 ccw(c185.583,336.978) 185.701,336.978 185.701,337.156 cw(c185.818,337.156) 185.818,337.274 185.918,337.274 cw(c185.918,337.156) 186.036,337.156 186.036,336.659 ccw(c186.153,336.659) 186.153,336.542 186.253,336.542 ccw(c186.253,336.659) 186.371,336.659 186.371,336.743 cw(c186.488,336.743) 186.488,336.86 186.662,336.86 190.391,336.86 190.788,337.257 v1(190.995,337.257) 191.254,337.257 191.915,336.596 192.002,336.596 192.183,336.415 196.914,336.415 196.954,336.415 ccw(c196.954,336.499) 197.038,336.499 197.038,336.7 cw(c197.122,336.7) 197.122,336.784 197.289,336.784 cw(c197.289,336.7) 197.373,336.7 197.373,336.499 ccw(c197.457,336.499) 197.457,336.415 197.638,336.415 199.26,336.415 199.382,336.293 199.422,336.293 ccw(c199.422,336.41) 199.54,336.41 199.54,336.912 cw(c199.657,336.912) 199.657,337.029 199.757,337.029 cw(c199.757,336.912) 199.875,336.912 199.875,336.41 ccw(c199.992,336.41) 199.992,336.293 200.092,336.293 ccw(c200.092,336.41) 200.21,336.41 cw(c200.327,336.41) 200.327,336.527 200.427,336.527 cw(c200.427,336.41) 200.545,336.41 ccw(c200.662,336.41) 200.662,336.293 200.861,336.293 201.035,336.293 201.178,336.436 201.178,336.531 201.513,336.866 202.065,336.866 v1(202.456,337.257)
  L12 (Sign) w0.151: v1(159.982,335.789) 160.426,336.233 163.162,336.233 163.452,335.943 165.251,335.943
  L3 (Sign) w0.081: v2(189.884,317.027) 190.205,316.706 192.106,316.706 192.397,316.997 ; 200.457,326.785 200.457,328.019 200.457,328.131 ccw(c200.345,328.131) 200.345,328.243 199.875,328.243 cw(c199.875,328.355) 199.763,328.355 199.763,328.578 cw(c199.875,328.578) 199.875,328.69 200.457,328.69 200.491,328.69 ccw(c200.491,328.802) 200.603,328.802 200.603,329.026 ccw(c200.491,329.026) 200.491,329.138 200.457,329.138 200.216,329.138 cw(c200.216,329.25) 200.104,329.25 200.104,329.473 cw(c200.216,329.473) 200.216,329.585 200.457,329.585 ccw(c200.457,329.643) 200.515,329.643 200.515,329.975 ccw(c200.457,329.975) 200.457,330.033 200.159,330.033 cw(c200.159,330.145) 200.047,330.145 200.047,330.368 cw(c200.159,330.368) 200.159,330.48 200.345,330.48 ccw(c200.345,330.592) 200.457,330.592 200.457,330.928 200.457,331.264 cw(c200.569,331.264) 200.569,331.375 200.951,331.375 ccw(c200.951,331.487) 201.063,331.487 201.063,331.711 ccw(c200.951,331.711) 200.951,331.823 200.457,331.823 199.276,331.823 cw(c199.276,331.935) 199.165,331.935 199.165,332.159 cw(c199.276,332.159) 199.276,332.27 200.457,332.27 200.951,332.27 ccw(c200.951,332.382) 201.063,332.382 201.063,332.606 ccw(c200.951,332.606) 200.951,332.718 200.457,332.718 199.439,332.718 cw(c199.439,332.83) 199.327,332.83 199.327,333.054 cw(c199.439,333.054) 199.439,333.165 200.457,333.165 200.951,333.165 ccw(c200.951,333.277) 201.063,333.277 201.063,333.501 ccw(c200.951,333.501) 200.951,333.613 200.457,333.613 199.488,333.613 cw(c199.488,333.725) 199.377,333.725 199.377,333.949 cw(c199.488,333.949) 199.488,334.061 200.345,334.061 ccw(c200.345,334.172) 200.457,334.172 200.457,334.379 200.457,334.503 ccw(c200.332,334.503) 200.332,334.628 199.362,334.628 cw(c199.362,334.752) 199.238,334.752 199.238,335.002 cw(c199.362,335.002) 199.362,335.126 200.457,335.126 201.013,335.126 ccw(c201.013,335.251) 201.138,335.251 201.138,335.5 ccw(c201.013,335.5) 201.013,335.624 200.457,335.624 199.897,335.624 cw(c199.897,335.749) 199.772,335.749 199.772,335.998 cw(c199.897,335.998) 199.897,336.123 200.332,336.123 ccw(c200.332,336.247) 200.457,336.247 200.457,336.51 200.807,336.86 202.059,336.86 v1(202.456,337.257)
  L3 (Sign) w0.172: 192.397,316.997 199.278,323.878 199.278,324.038 199.856,324.616 199.856,324.989 200.457,325.59 200.457,326.785
DDR4_A13: R53.1 U1.AH28 U8.T5 U9.T5 U10.T5 U11.T5 | length 103.5
  L1 w0.1: U9.T5@166.876,340.06 167.274,340.459 v1(167.274,340.589) ; U11.T5@178.336,340.06 178.733,340.457 v1(178.735,340.457) ; v2(189.04,315.049) 189.04,315.182 U1.AH28@189.397,315.539 ; U10.T5@189.797,340.06 190.195,340.459 v1(190.195,340.589) ; U8.T5@201.257,340.06 201.653,340.457 v1(201.656,340.457)
  L1 w0.155: R53.1@158.737,344.5 R53.1@158.787,344.5 v1(159.982,344.5)
  L12 (Sign) w0.081: 165.251,341.173 166.094,341.173 166.678,340.589 v1(167.274,340.589) 167.571,340.589 168.871,341.888 173.532,341.888 174.247,341.173 174.896,341.173 174.936,341.173 ccw(c174.936,341.289) 175.052,341.289 175.052,341.726 cw(c175.168,341.726) 175.168,341.842 175.322,341.842 cw(c175.322,341.726) 175.438,341.726 175.438,341.057 ccw(c175.554,341.057) 175.554,340.941 175.708,340.941 ccw(c175.708,341.057) 175.824,341.057 cw(c175.94,341.057) 175.94,341.173 176.261,341.173 178.019,341.173 v1(178.735,340.457) 179.963,340.457 181.353,341.847 185.701,341.847 185.741,341.847 ccw(c185.741,341.963) 185.857,341.963 185.857,342.455 cw(c185.973,342.455) 185.973,342.57 186.127,342.57 cw(c186.127,342.455) 186.243,342.455 186.243,341.863 ccw(c186.359,341.863) 186.359,341.747 186.513,341.747 ccw(c186.513,341.863) 186.629,341.863 186.629,341.986 cw(c186.745,341.986) 186.745,342.102 186.899,342.102 cw(c186.899,341.986) 187.015,341.986 187.015,341.963 ccw(c187.131,341.963) 187.131,341.847 187.433,341.847 187.522,341.758 189.026,341.758 v1(190.195,340.589) 190.492,340.589 191.738,341.834 193.644,341.834 194.361,342.552 196.904,342.552 198.434,341.022 198.463,340.994 ccw(c198.522,341.053) 198.581,340.994 198.647,341.059 cw(c198.706,341) 198.766,341.059 198.884,340.941 cw(c198.825,340.882) 198.884,340.822 198.818,340.757 ccw(c198.878,340.697) 198.818,340.638 199,340.457 v1(201.656,340.457)
  L12 (Sign) w0.15: 164.028,341.254 164.109,341.173 165.251,341.173
  L12 (Sign) w0.151: v1(159.982,344.5) 160.782,344.5 164.028,341.254
  L3 (Sign) w0.081: v2(189.04,315.049) 189.04,315.182 189.524,315.666 189.524,316.392 189.04,316.876 189.04,317.636 189.793,318.389 190.308,318.389 190.459,318.539 ; 197.269,327.035 197.224,327.08 197.224,330.276 197.224,330.356 cw(c197.306,330.356) 197.306,330.438 ccw(c197.306,330.525) 197.393,330.525 197.393,330.698 ccw(c197.306,330.698) 197.306,330.784 197.224,330.784 196.952,330.784 cw(c196.952,330.871) 196.866,330.871 196.866,331.044 cw(c196.952,331.044) 196.952,331.13 197.224,331.13 197.306,331.13 ccw(c197.306,331.217) 197.393,331.217 197.393,331.39 ccw(c197.306,331.39) 197.306,331.476 cw(c197.306,331.558) 197.224,331.558 197.224,331.74 cw(c197.306,331.74) 197.306,331.822 ccw(c197.306,331.908) 197.393,331.908 197.393,332.081 ccw(c197.306,332.081) 197.306,332.168 197.224,332.168 196.897,332.168 cw(c196.897,332.254) 196.811,332.254 196.811,332.427 cw(c196.897,332.427) 196.897,332.514 197.224,332.514 197.306,332.514 ccw(c197.306,332.6) 197.393,332.6 197.393,332.773 ccw(c197.306,332.773) 197.306,332.86 197.224,332.86 196.897,332.86 cw(c196.897,332.946) 196.811,332.946 196.811,333.119 cw(c196.897,333.119) 196.897,333.206 197.224,333.206 197.306,333.206 ccw(c197.306,333.292) 197.393,333.292 197.393,333.465 ccw(c197.306,333.465) 197.306,333.552 197.224,333.552 196.897,333.552 cw(c196.897,333.638) 196.811,333.638 196.811,333.811 cw(c196.897,333.811) 196.897,333.898 197.224,333.898 197.306,333.898 ccw(c197.306,333.984) 197.393,333.984 197.393,334.157 ccw(c197.306,334.157) 197.306,334.243 cw(c197.306,334.326) 197.224,334.326 197.224,334.416 197.275,334.467 197.304,334.496 ccw(c197.245,334.555) 197.304,334.614 196.87,335.048 cw(c196.929,335.108) 196.87,335.167 196.988,335.285 cw(c197.047,335.226) 197.107,335.285 197.606,334.786 ccw(c197.666,334.845) 197.725,334.786 197.843,334.904 ccw(c197.784,334.963) 197.843,335.022 197.216,335.65 cw(c197.275,335.709) 197.216,335.768 197.334,335.887 cw(c197.393,335.828) 197.453,335.887 198.08,335.259 ccw(c198.139,335.319) 198.199,335.259 198.317,335.378 ccw(c198.258,335.437) 198.317,335.496 197.69,336.124 cw(c197.749,336.183) 197.69,336.242 197.808,336.361 cw(c197.867,336.301) 197.926,336.361 198.554,335.733 ccw(c198.613,335.792) 198.672,335.733 198.791,335.852 ccw(c198.732,335.911) 198.791,335.97 198.163,336.597 cw(c198.223,336.657) 198.163,336.716 198.282,336.834 cw(c198.341,336.775) 198.4,336.834 198.962,336.273 ccw(c199.021,336.332) 199.08,336.273 199.24,336.432 199.575,336.768 199.604,336.796 ccw(c199.545,336.855) 199.604,336.915 199.441,337.078 cw(c199.5,337.137) 199.441,337.196 199.56,337.314 cw(c199.619,337.255) 199.678,337.314 199.907,337.086 ccw(c199.966,337.145) 200.025,337.086 200.144,337.204 ccw(c200.084,337.263) 200.144,337.323 199.516,337.95 cw(c199.575,338.009) 199.516,338.069 199.635,338.187 cw(c199.694,338.128) 199.753,338.187 200.38,337.56 ccw(c200.44,337.619) 200.499,337.56 200.617,337.678 ccw(c200.558,337.737) 200.617,337.796 200.43,337.983 cw(c200.49,338.043) 200.43,338.102 200.549,338.22 cw(c200.608,338.161) 200.667,338.22 200.788,338.099 ccw(c200.848,338.158) 200.907,338.099 201.059,338.251 201.255,338.447 201.92,338.447 202.1,338.628 202.1,338.752 202.581,339.233 202.581,339.356 202.581,339.566 cw(c202.615,339.566) 202.615,339.6 ccw(c202.615,339.661) 202.676,339.661 202.676,339.784 ccw(c202.615,339.784) 202.615,339.845 cw(c202.615,339.878) 202.581,339.878 202.581,340.089 202.581,340.115 202.239,340.457 v1(201.656,340.457)
  L3 (Sign) w0.172: 190.459,318.539 195.548,323.628 ; 196.548,324.629 196.548,324.9 197.269,325.621 197.269,327.035
  L3 (Sign) w0.173: 195.548,323.628 195.717,323.798 cw(c195.793,323.722) 195.868,323.798 195.887,323.779 ccw(c195.963,323.854) 196.038,323.779 196.189,323.93 ccw(c196.114,324.005) 196.189,324.081 196.17,324.1 cw(c196.246,324.175) 196.17,324.251 196.397,324.478 196.548,324.629
DDR4_ACT_N: R40.1 U1.AD26 U8.L3 U9.L3 U10.L3 U11.L3 | length 107.1
  L1 w0.1: v1(169.974,335.562) 170.377,335.562 U9.L3@170.876,336.06 ; v1(181.933,335.657) U11.L3@182.336,336.06 ; U1.AD26@185.397,313.539 185.89,314.033 v2(186.017,314.033) ; v1(193.393,335.657) U10.L3@193.797,336.06 ; U8.L3@205.257,336.06 v1(205.661,335.657)
  L1 w0.155: v1(166.395,343.555) R40.1@166.395,344.799
  L5 (Sign) w0.081: v1(166.395,343.555) 166.913,343.555 168.694,341.774 168.694,340.953 169.336,340.311 169.336,335.797 169.572,335.562 v1(169.974,335.562) 170.377,335.562 170.962,336.147 173.364,336.147 174.251,335.26 174.291,335.26 ccw(c174.291,335.376) 174.407,335.376 174.407,335.722 cw(c174.523,335.722) 174.523,335.838 174.677,335.838 cw(c174.677,335.722) 174.793,335.722 174.793,335.376 ccw(c174.909,335.376) 174.909,335.26 175.449,335.26 180.028,335.26 180.425,335.657 v1(181.933,335.657) 182.336,336.06 184.142,336.06 184.965,335.238 185.324,335.238 185.353,335.267 185.624,335.267 185.665,335.267 ccw(c185.665,335.383) 185.78,335.383 185.78,335.57 cw(c185.896,335.57) 185.896,335.686 186.051,335.686 cw(c186.051,335.57) 186.166,335.57 186.166,334.965 ccw(c186.282,334.965) 186.282,334.849 186.437,334.849 ccw(c186.437,334.965) 186.552,334.965 186.552,335.535 cw(c186.668,335.535) 186.668,335.651 186.823,335.651 cw(c186.823,335.535) 186.938,335.535 186.938,335.383 ccw(c187.054,335.383) 187.054,335.267 187.228,335.267 191.656,335.267 192.045,335.657 v1(193.393,335.657) 193.816,336.08 195.631,336.08 195.885,335.826 196.596,335.826 196.636,335.826 ccw(c196.636,335.91) 196.72,335.91 196.72,336.209 cw(c196.804,336.209) 196.804,336.293 196.972,336.293 cw(c196.972,336.209) 197.055,336.209 197.055,335.899 ccw(c197.139,335.899) 197.139,335.815 197.307,335.815 ccw(c197.307,335.899) 197.391,335.899 197.391,336.209 cw(c197.474,336.209) 197.474,336.293 197.642,336.293 cw(c197.642,336.209) 197.726,336.209 197.726,335.91 ccw(c197.81,335.91) 197.81,335.826 197.977,335.826 ccw(c197.977,335.91) 198.061,335.91 198.061,336.209 cw(c198.145,336.209) 198.145,336.293 198.312,336.293 cw(c198.312,336.209) 198.396,336.209 198.396,335.91 ccw(c198.48,335.91) 198.48,335.826 198.648,335.826 ccw(c198.648,335.91) 198.731,335.91 198.731,335.989 cw(c198.815,335.989) 198.815,336.073 198.983,336.073 cw(c198.983,335.989) 199.067,335.989 199.067,335.91 ccw(c199.15,335.91) 199.15,335.826 199.332,335.826 204.451,335.826 205.466,336.841 205.836,336.841 206.084,336.594 206.084,336.087 205.661,335.664 v1(205.661,335.657)
  L3 (Sign) w0.079: 188.572,311.656 188.661,311.656 188.851,311.466 190.702,311.466 190.732,311.496 192.281,311.496 192.397,311.611 ; 204.463,334.499 204.463,335.636 204.675,335.847 205.025,335.847 205.216,335.657 v1@205.621,335.657
  L3 (Sign) w0.081: v2(186.017,314.033) 186.498,314.514 187.085,314.514 187.528,314.071 187.528,313.862 188.046,313.345 188.046,312.182 188.572,311.656 ; 204.349,326.785 204.349,329.705 204.349,329.785 cw(c204.459,329.785) 204.459,329.895 204.797,329.895 ccw(c204.797,330.005) 204.907,330.005 204.907,330.334 ccw(c204.797,330.334) 204.797,330.444 204.459,330.444 cw(c204.459,330.554) 204.349,330.554 204.349,330.718 204.349,334.062 204.463,334.175 204.463,334.499 ; v1@205.621,335.657 v1(205.661,335.657)
  L3 (Sign) w0.171: 192.397,311.611 192.634,311.848
  L3 (Sign) w0.172: 192.634,311.848 195.566,311.848 204.349,320.631 204.349,321.001 204.349,321.19 ccw(c204.224,321.19) 204.224,321.316 203.917,321.316 cw(c203.917,321.442) 203.791,321.442 203.791,321.819 cw(c203.917,321.819) 203.917,321.945 204.349,321.945 204.782,321.945 ccw(c204.782,322.071) 204.908,322.071 204.908,322.448 ccw(c204.782,322.448) 204.782,322.574 204.475,322.574 cw(c204.475,322.7) 204.349,322.7 204.349,323.012
  L3 (Sign) w0.173: 204.349,323.012 204.349,323.201 ccw(c204.223,323.201) 204.223,323.327 203.918,323.327 cw(c203.918,323.453) 203.792,323.453 203.792,323.831 cw(c203.918,323.831) 203.918,323.957 204.349,323.957 204.781,323.957 ccw(c204.781,324.083) 204.907,324.083 204.907,324.461 ccw(c204.781,324.461) 204.781,324.587 204.349,324.587 204.337,324.587 cw(c204.337,324.713) 204.211,324.713 204.211,325.091 cw(c204.337,325.091) 204.337,325.217 204.349,325.217 204.781,325.217 ccw(c204.781,325.343) 204.907,325.343 204.907,325.722 ccw(c204.781,325.722) 204.781,325.848 204.349,325.848 204.337,325.848 cw(c204.337,325.974) 204.211,325.974 204.211,326.352 cw(c204.337,326.352) 204.337,326.478 204.349,326.478 204.349,326.785
DDR4_ALERT_N: R58.1 U1.AB24 U8.P6 U9.P6 U10.P6 U11.P6 | length 73.9
  L1 w0.1: 165.251,338.856 v2(165.665,338.856) 166.061,338.46 U9.P6@166.076,338.46 ; v2@177.125,338.856 U11.P6@177.529,338.453 ; v2(182.909,312.027) U1.AB24@183.397,311.539 ; v2(187.744,337.325) 187.744,338.031 188.569,338.856 v2(188.586,338.856) U10.P6@188.989,338.453 ; v2(198.298,339.928) 199.766,338.46 U8.P6@200.457,338.46
  L1 w0.155: R58.1@163.36,339.242 164.63,339.242 165.016,338.856 165.251,338.856
  L5 (Sign) w0.081: v6(180.873,315.036) 180.873,318.539 ; 186.754,327.035 186.754,327.52 v6(186.766,327.533)
  L5 (Sign) w0.171: 180.882,318.539 180.882,319.085 186.754,324.956 186.754,327.035
  L3 (Sign) w0.081: v2(165.665,338.856) 166.061,338.46 168.322,338.46 169.953,336.829 174.409,336.829 176.04,338.46 176.721,338.46 v2(177.117,338.857) 177.514,338.46 188.189,338.46 v2(188.586,338.856) 188.982,338.46 196.259,338.46 197.727,339.928 v2(198.298,339.928) ; v6(180.873,315.036) 181.927,313.982 181.927,313.733 182.909,312.751 v2(182.909,312.027) ; v6(186.766,327.533) 186.766,336.347 v2(187.744,337.325)
DDR4_BA0: R32.1 U1.AD27 U8.N2 U9.N2 U10.N2 U11.N2 | length 105.1
  L1 w0.1: U9.N2@171.676,337.66 v1(172.079,338.064) ; U11.N2@183.136,337.66 v1(183.54,338.064) ; v2(184.912,313.919) 184.912,314.054 U1.AD27@185.397,314.539 ; U10.N2@194.597,337.66 v1(195,338.064) ; U8.N2@206.057,337.66 v1(206.439,338.042)
  L1 w0.155: v1(170.02,343.555) R32.1@170.02,344.75 R32.1@170.02,344.799
  L5 (Sign) w0.081: v1(170.02,343.555) 170.02,341.341 169.879,341.2 169.879,338.057 169.927,338.057 170.31,337.673 170.976,337.673 170.996,337.693 171.367,338.064 v1(172.079,338.064) 173.24,338.064 173.551,337.753 173.637,337.666 174.006,337.666 174.432,337.666 cw(c174.432,337.551) 174.548,337.551 174.548,337.313 ccw(c174.664,337.313) 174.664,337.197 174.818,337.197 ccw(c174.818,337.313) 174.934,337.313 174.934,338.02 cw(c175.05,338.02) 175.05,338.136 175.204,338.136 cw(c175.204,338.02) 175.32,338.02 175.32,337.313 ccw(c175.436,337.313) 175.436,337.197 175.59,337.197 ccw(c175.59,337.313) 175.706,337.313 175.706,337.551 cw(c175.822,337.551) 175.822,337.666 176.334,337.666 176.461,337.666 182.724,337.666 183.122,338.064 v1(183.54,338.064) 183.822,338.064 183.909,337.977 183.909,337.857 184.098,337.668 185.468,337.668 185.508,337.668 ccw(c185.508,337.783) 185.624,337.783 185.624,338.021 cw(c185.74,338.021) 185.74,338.137 185.894,338.137 cw(c185.894,338.021) 186.01,338.021 186.01,337.314 ccw(c186.126,337.314) 186.126,337.198 186.28,337.198 ccw(c186.28,337.314) 186.396,337.314 186.396,337.975 cw(c186.512,337.975) 186.512,338.091 186.666,338.091 cw(c186.666,337.975) 186.782,337.975 186.782,337.783 ccw(c186.898,337.783) 186.898,337.668 187.111,337.668 189.683,337.668 189.684,337.666 191.157,337.666 191.158,337.668 194.056,337.668 194.452,338.064 v1(195,338.064) 196.596,338.064 196.972,338.064 cw(c196.972,337.98) 197.055,337.98 197.055,337.81 ccw(c197.139,337.81) 197.139,337.726 197.307,337.726 ccw(c197.307,337.81) 197.391,337.81 197.391,337.988 cw(c197.474,337.988) 197.474,338.071 197.642,338.071 cw(c197.642,337.988) 197.726,337.988 197.726,337.81 ccw(c197.81,337.81) 197.81,337.726 197.977,337.726 ccw(c197.977,337.81) 198.061,337.81 198.061,337.987 cw(c198.145,337.987) 198.145,338.071 198.312,338.071 cw(c198.312,337.987) 198.396,337.987 198.396,337.81 ccw(c198.48,337.81) 198.48,337.726 198.648,337.726 ccw(c198.648,337.81) 198.731,337.81 198.731,337.98 cw(c198.815,337.98) 198.815,338.064 199.356,338.064 199.408,338.064 199.783,338.064 cw(c199.783,337.98) 199.867,337.98 199.867,337.81 ccw(c199.951,337.81) 199.951,337.726 200.118,337.726 ccw(c200.118,337.81) 200.202,337.81 200.202,337.98 cw(c200.286,337.98) 200.286,338.064 200.645,338.064 201.042,337.666 202.724,337.666 202.765,337.666 ccw(c202.765,337.75) 202.849,337.75 202.849,338.206 cw(c202.932,338.206) 202.932,338.29 203.1,338.29 cw(c203.1,338.206) 203.184,338.206 203.184,337.529 ccw(c203.268,337.529) 203.268,337.445 203.435,337.445 ccw(c203.435,337.529) 203.519,337.529 203.519,338.129 cw(c203.603,338.129) 203.603,338.212 203.77,338.212 cw(c203.77,338.129) 203.854,338.129 203.854,337.752 ccw(c203.938,337.752) 203.938,337.668 204.251,337.668 205.646,337.668 206.02,338.042 v1(206.439,338.042)
  L3 (Sign) w0.079: 184.649,313.451 184.878,313.68 184.878,313.885 v2(184.912,313.919) ; 184.859,312.587 184.99,312.587 185.182,312.395 ; 188.091,310.491 188.434,310.149
  L3 (Sign) w0.081: 184.649,313.451 184.649,313.39 184.469,313.209 184.469,312.844 184.727,312.586 184.859,312.586 ; 185.182,312.395 185.454,312.123 185.454,311.859 185.727,311.586 186.172,311.586 186.208,311.622 186.895,311.622 188.027,310.49 188.091,310.49 ; 188.434,310.149 189.069,310.149 189.24,309.978 190.881,309.978 190.951,309.908 192.397,309.908 ; v1(206.439,338.042) 206.87,337.61 206.87,336.302 207.099,336.073 207.44,336.073 207.668,335.845 207.668,335.803 207.932,335.539
  L3 (Sign) w0.171: 192.397,309.908 192.598,309.908 192.716,310.026
  L3 (Sign) w0.172: 192.716,310.026 193.421,310.731 196.017,310.731 208.238,322.952 208.238,335.233 207.932,335.539
DDR4_BA1: R34.1 U1.AC26 U8.N5 U9.N5 U10.N5 U11.N5 | length 101.8
  L1 w0.1: U9.N5@166.876,337.66 167.272,338.057 v1(167.275,338.057) ; U11.N5@178.336,337.66 178.733,338.057 v1(178.735,338.057) ; v2(183.91,314.027) U1.AC26@184.397,313.539 ; U10.N5@189.797,337.66 190.193,338.057 v1(190.195,338.057) ; U8.N5@201.257,337.66 201.653,338.057 v1(201.656,338.057)
  L1 w0.155: R34.1@158.737,339.055 v1(159.982,339.056)
  L12 (Sign) w0.081: 165.251,338.057 v1(167.275,338.057) 167.511,338.057 167.915,338.46 168.318,338.46 169.901,340.043 169.901,340.625 170.258,340.983 172.549,340.983 173.551,339.981 175.283,338.248 176.461,338.248 176.561,338.248 178.019,338.248 178.484,338.248 v1@178.675,338.057 ; v1@178.743,338.057 179.047,338.36 179.286,338.36 179.373,338.447 179.824,338.447 180.924,339.547 180.924,340.138 181.715,340.929 183.733,340.929 183.752,340.91 183.817,340.91 186.43,338.297 189.956,338.297 v1(190.195,338.057) 190.204,338.057 190.594,338.447 191.143,338.447 192.543,339.848 192.543,340.29 193.182,340.929 195.273,340.929 196.472,339.731 198.146,338.057 199.382,338.057 v1(201.656,338.057)
  L12 (Sign) w0.151: v1(159.982,339.056) 161.223,339.056 162.221,338.057 165.251,338.057
  L3 (Sign) w0.079: 192.661,333.825 192.661,333.876 193.253,334.467 193.648,334.467 193.851,334.67 ; 201.227,340.778 201.296,340.846 201.886,340.846 201.954,340.778 202.345,340.778
  L3 (Sign) w0.081: v2(183.91,314.027) 183.91,314.68 184.362,315.132 184.362,316.073 183.563,316.872 183.563,317.185 183.751,317.373 183.934,317.373 184.164,317.603 184.62,317.603 184.723,317.707 185.751,317.707 ; 185.751,317.706 186.114,317.706 186.535,318.126 186.999,318.126 187.412,318.539 ; 192.661,326.785 192.661,333.825 ; 193.851,334.67 194.441,335.26 195.366,335.26 199.539,339.433 199.882,339.433 201.227,340.778 ; v1(201.656,338.057) 201.762,338.057 201.972,338.266 202.113,338.266 202.777,338.93 202.857,338.93 202.857,340.266 202.345,340.778
  L3 (Sign) w0.172: 187.412,318.539 188.788,319.915 ; 192.164,323.85 192.164,324.546 192.661,325.044 192.661,326.785
  L3 (Sign) w0.173: 188.788,319.915 188.788,320.474 188.849,320.535 ccw(c188.727,320.657) 188.849,320.78 188.32,321.308 cw(c188.423,321.411) 188.32,321.513 188.525,321.718 cw(c188.628,321.616) 188.73,321.718 189.291,321.157 ccw(c189.393,321.26) 189.496,321.157 189.701,321.362 ccw(c189.598,321.464) 189.701,321.567 189.14,322.128 cw(c189.242,322.23) 189.14,322.333 189.344,322.538 cw(c189.447,322.435) 189.549,322.538 190.11,321.977 ccw(c190.213,322.079) 190.315,321.977 190.52,322.181 ccw(c190.417,322.284) 190.52,322.386 189.959,322.947 cw(c190.061,323.05) 189.959,323.152 190.164,323.357 cw(c190.266,323.254) 190.369,323.357 190.897,322.828 ccw(c191.02,322.95) 191.142,322.828 192.096,323.782 192.164,323.85
DDR4_BG0: R36.1 U1.AC28 U8.M2 U9.M2 U10.M2 U11.M2 | length 107.4
  L1 w0.1: U9.M2@171.676,336.86 v1(172.079,337.264) ; U11.M2@183.136,336.86 v1(183.54,337.264) ; v2(183.909,316.027) U1.AC28@184.397,315.539 ; U10.M2@194.597,336.86 v1(195,337.264) ; v1(205.684,337.233) U8.M2@206.057,336.86 U8.M2@206.088,336.829
  L1 w0.155: v1(167.603,343.555) R36.1@167.603,344.8
  L5 (Sign) w0.081: v1@167.603,343.566 167.603,343.534 169.102,342.035 169.102,340.891 169.517,340.476 169.517,337.202 170.231,336.488 171.303,336.488 v1(172.079,337.264) 172.324,337.264 173.043,336.545 173.678,336.545 174.104,336.545 cw(c174.104,336.429) 174.22,336.429 174.22,336.191 ccw(c174.336,336.191) 174.336,336.075 174.49,336.075 ccw(c174.49,336.191) 174.606,336.191 174.606,336.571 cw(c174.722,336.571) 174.722,336.686 174.876,336.686 cw(c174.876,336.571) 174.992,336.571 174.992,336.191 ccw(c175.108,336.191) 175.108,336.075 175.262,336.075 ccw(c175.262,336.191) 175.378,336.191 175.378,336.429 cw(c175.494,336.429) 175.494,336.545 175.822,336.545 177.437,336.545 177.921,336.06 181.217,336.06 181.292,336.136 181.922,336.766 183.042,336.766 v1(183.54,337.264) 183.54,336.919 183.998,336.461 184.398,336.06 186.61,336.06 186.877,336.06 ccw(c186.877,336.176) 186.993,336.176 186.993,336.245 cw(c187.109,336.245) 187.109,336.361 187.263,336.361 cw(c187.263,336.245) 187.379,336.245 187.379,335.564 ccw(c187.495,335.564) 187.495,335.448 187.649,335.448 ccw(c187.649,335.564) 187.765,335.564 187.765,335.945 cw(c187.881,335.945) 187.881,336.06 187.922,336.06 192.677,336.06 193.383,336.766 194.502,336.766 v1(195,337.264) 195.503,336.761 ccw(c195.562,336.821) 195.621,336.761 196.122,337.262 cw(c196.181,337.203) 196.241,337.262 196.359,337.143 cw(c196.3,337.084) 196.359,337.025 195.951,336.617 ccw(c196.01,336.557) 196.01,336.474 196.195,336.474 199.479,336.474 199.52,336.474 ccw(c199.52,336.557) 199.603,336.557 199.603,337.265 cw(c199.687,337.265) 199.687,337.349 199.855,337.349 cw(c199.855,337.265) 199.939,337.265 199.939,336.091 ccw(c200.022,336.091) 200.022,336.007 200.19,336.007 ccw(c200.19,336.091) 200.274,336.091 200.274,336.844 cw(c200.358,336.844) 200.358,336.927 200.525,336.927 cw(c200.525,336.844) 200.609,336.844 200.609,336.557 ccw(c200.693,336.557) 200.693,336.474 200.965,336.474 201.378,336.061 202.045,336.061 202.619,336.061 204.43,336.061 205.602,337.233 v1(205.684,337.233)
  L3 (Sign) w0.081: v2(183.909,316.027) 183.909,316.254 183.371,316.792 183.371,317.264 183.672,317.565 183.854,317.565 184.084,317.795 184.327,317.795 184.533,318.001 184.533,318.539 ; 191.783,326.785 191.783,329.697 191.783,329.737 ccw(c191.686,329.737) 191.686,329.834 190.68,329.834 cw(c190.68,329.93) 190.584,329.93 190.584,330.123 cw(c190.68,330.123) 190.68,330.22 192.043,330.22 ccw(c192.043,330.316) 192.14,330.316 192.14,330.509 ccw(c192.043,330.509) 192.043,330.606 191.487,330.606 cw(c191.487,330.702) 191.391,330.702 191.391,330.895 cw(c191.487,330.895) 191.487,330.991 192.043,330.991 ccw(c192.043,331.088) 192.14,331.088 192.14,331.281 ccw(c192.043,331.281) 192.043,331.377 191.487,331.377 cw(c191.487,331.474) 191.391,331.474 191.391,331.666 cw(c191.487,331.666) 191.487,331.763 191.977,331.763 ccw(c191.977,331.859) 192.073,331.859 192.073,332.052 ccw(c191.977,332.052) 191.977,332.149 191.686,332.149 cw(c191.686,332.245) 191.59,332.245 191.59,332.438 cw(c191.686,332.438) 191.686,332.535 ccw(c191.686,332.631) 191.783,332.631 191.783,333.515 191.783,333.628 192.824,334.669 192.824,336.048 193.253,336.477 196.04,336.477 199.379,339.817 199.723,339.817 201.206,341.3 203.073,341.3 203.733,340.639 203.979,340.639 204.128,340.49 204.275,340.49 204.711,340.054 205.015,340.054 205.58,339.49 205.58,337.579 205.621,337.538 205.621,337.296 v1(205.684,337.233)
  L3 (Sign) w0.172: 184.533,318.539 184.533,318.962 191.783,326.212 191.783,326.785
DDR4_BG1: U1.AC27
DDR4_CAS: R57.1 U1.AJ29 U8.M5 U9.M5 U10.M5 U11.M5 | length 101.4
  L1 w0.1: U9.M5@166.876,336.86 167.272,337.257 v1(167.275,337.257) ; U11.M5@178.336,336.86 178.733,337.257 v1(178.735,337.257) ; U10.M5@189.797,336.86 190.193,337.257 v1(190.195,337.257) ; U1.AJ29@190.397,316.539 v2(190.884,317.027) ; U8.M5@201.257,336.86 201.259,336.86 v1(201.656,337.257)
  L1 w0.155: R57.1@158.737,336.878 v1(159.982,336.878)
  L12 (Sign) w0.081: 165.251,336.878 166.093,336.878 166.472,337.257 v1(167.275,337.257) 167.486,337.257 167.807,337.578 167.876,337.647 169.083,337.647 170.137,336.594 173.835,336.594 174.498,337.257 175.525,337.257 175.85,337.257 cw(c175.85,337.172) 175.936,337.172 175.936,337.072 ccw(c176.021,337.072) 176.021,336.987 176.135,336.987 ccw(c176.135,337.072) 176.22,337.072 176.22,337.172 cw(c176.305,337.172) 176.305,337.257 176.435,337.257 176.553,337.257 176.593,337.257 ccw(c176.593,337.373) 176.709,337.373 176.709,337.402 cw(c176.825,337.402) 176.825,337.517 176.979,337.517 cw(c176.979,337.402) 177.095,337.402 177.095,336.946 ccw(c177.211,336.946) 177.211,336.83 177.365,336.83 ccw(c177.365,336.946) 177.481,336.946 177.481,337.402 cw(c177.597,337.402) 177.597,337.517 177.751,337.517 cw(c177.751,337.402) 177.867,337.402 177.867,337.373 ccw(c177.983,337.373) 177.983,337.257 178.233,337.257 v1(178.735,337.257) 178.911,337.257 179.248,337.593 179.302,337.647 179.803,337.647 179.857,337.593 180.287,337.593 181.342,336.538 184.13,336.538 185.212,337.621 186.032,337.621 186.408,337.621 cw(c186.408,337.503) 186.525,337.503 186.525,337.172 ccw(c186.642,337.172) 186.642,337.055 186.743,337.055 ccw(c186.743,337.172) 186.86,337.172 186.86,337.564 cw(c186.977,337.564) 186.977,337.681 187.078,337.681 cw(c187.078,337.564) 187.195,337.564 187.195,337.435 ccw(c187.312,337.435) 187.312,337.318 187.413,337.318 ccw(c187.413,337.435) 187.53,337.435 187.53,337.503 cw(c187.647,337.503) 187.647,337.621 187.868,337.621 188.069,337.621 188.13,337.681 189.083,337.681 189.143,337.621 189.237,337.621 189.601,337.257 v1(190.195,337.257) 190.407,337.257 190.797,337.647 191.157,337.647 191.227,337.578 191.276,337.578 192.258,336.596 196.456,336.596 197.117,337.257 197.493,337.257 cw(c197.493,337.173) 197.577,337.173 197.577,336.871 ccw(c197.66,336.871) 197.66,336.788 197.828,336.788 ccw(c197.828,336.871) 197.912,336.871 197.912,337.344 cw(c197.996,337.344) 197.996,337.428 198.163,337.428 cw(c198.163,337.344) 198.247,337.344 198.247,337.012 ccw(c198.331,337.012) 198.331,336.928 198.498,336.928 ccw(c198.498,337.012) 198.582,337.012 198.582,337.173 cw(c198.666,337.173) 198.666,337.257 198.873,337.257 v1(201.656,337.257)
  L12 (Sign) w0.151: v1(159.982,336.878) 160.457,337.353 163.15,337.353 163.2,337.303 164.434,337.303 164.859,336.878 165.251,336.878
  L3 (Sign) w0.081: v2(190.884,317.027) 191.737,317.027 191.8,317.09 191.99,317.09 192.397,317.496 ; 198.886,327.035 198.984,327.133 198.984,327.674 198.984,327.715 ccw(c198.887,327.715) 198.887,327.811 197.958,327.811 cw(c197.958,327.908) 197.862,327.908 197.862,328.101 cw(c197.958,328.101) 197.958,328.197 199.135,328.197 ccw(c199.135,328.294) 199.231,328.294 199.231,328.487 ccw(c199.135,328.487) 199.135,328.583 199.08,328.583 cw(c199.08,328.68) 198.984,328.68 198.984,329.414 198.984,329.513 ccw(c198.884,329.513) 198.884,329.612 cw(c198.884,329.712) 198.785,329.712 198.785,329.91 cw(c198.884,329.91) 198.884,330.009 198.984,330.009 ccw(c198.984,330.109) 199.083,330.109 199.083,330.307 ccw(c198.984,330.307) 198.984,330.406 198.299,330.406 cw(c198.299,330.506) 198.2,330.506 198.2,330.704 cw(c198.299,330.704) 198.299,330.803 198.984,330.803 200.267,330.803 ccw(c200.267,330.903) 200.367,330.903 200.367,331.101 ccw(c200.267,331.101) 200.267,331.2 199.083,331.2 cw(c199.083,331.3) 198.984,331.3 198.984,332.19 198.984,332.202 198.901,332.285 cw(c198.958,332.343) 198.901,332.4 199.156,332.655 ccw(c199.114,332.696) 199.156,332.737 199.073,332.82 ccw(c199.032,332.779) 198.991,332.82 198.628,332.457 cw(c198.587,332.498) 198.545,332.457 198.463,332.54 cw(c198.504,332.581) 198.463,332.622 198.974,333.133 ccw(c198.932,333.174) 198.974,333.216 198.891,333.298 ccw(c198.85,333.257) 198.809,333.298 198.406,332.895 cw(c198.348,332.952) 198.291,332.895 198.262,332.924 198.207,332.979 198.207,333.123 198.207,333.163 ccw(c198.126,333.163) 198.126,333.244 197.826,333.244 cw(c197.826,333.315) 197.755,333.315 197.755,333.457 cw(c197.826,333.457) 197.826,333.528 199.125,333.528 ccw(c199.125,333.599) 199.196,333.599 199.196,333.741 ccw(c199.125,333.741) 199.125,333.812 197.826,333.812 cw(c197.826,333.883) 197.755,333.883 197.755,334.026 cw(c197.826,334.026) 197.826,334.097 198.593,334.097 ccw(c198.593,334.168) 198.664,334.168 198.664,334.31 ccw(c198.593,334.31) 198.593,334.381 198.288,334.381 cw(c198.288,334.462) 198.207,334.462 198.207,334.613 198.207,334.741 200.724,337.257 v1(201.656,337.257)
  L3 (Sign) w0.172: 192.397,317.496 198.886,323.986
  L3 (Sign) w0.173: 198.886,323.986 198.886,324.095 198.886,324.182 ccw(c198.713,324.182) 198.713,324.355 198.407,324.355 cw(c198.407,324.487) 198.275,324.487 198.275,324.751 cw(c198.407,324.751) 198.407,324.883 199.451,324.883 ccw(c199.451,325.016) 199.584,325.016 199.584,325.28 ccw(c199.451,325.28) 199.451,325.412 197.979,325.412 cw(c197.979,325.544) 197.846,325.544 197.846,325.808 cw(c197.979,325.808) 197.979,325.941 200.052,325.941 ccw(c200.052,326.073) 200.184,326.073 200.184,326.337 ccw(c200.052,326.337) 200.052,326.469 199.059,326.469 cw(c199.059,326.642) 198.886,326.642 198.886,327.035
DDR4_CK0: U1.AE30
DDR4_CK1: U1.AF28
DDR4_CK_N: R52.1 U1.AF30 U8.K5 U9.K5 U10.K5 U11.K5 | length 104.2
  L1 w0.135: U9.K5@166.876,335.26 v1(167.279,334.857) ; U11.K5@178.336,335.26 v1(178.74,334.857) ; U1.AF30@187.397,317.539 187.87,317.066 v1(187.87,316.954) ; U10.K5@189.797,335.26 189.803,335.26 v1(190.192,334.87) ; v1(190.192,334.87) v1(190.192,334.87) ; U8.K5@201.257,335.26 201.653,334.864 v1(201.653,334.862)
  L1 w0.159: R52.1@158.787,331.433 158.933,331.579 158.933,331.747 159.026,331.84 159.431,331.84 159.574,331.698 v23(159.654,331.698)
  L5 (Sign) w0.1: 202.221,334.46 202.622,334.461 202.771,334.462
  L5 (Sign) w0.103: v1(187.87,316.954) ccw(c188.076,316.954) 188.076,316.748 192.123,316.748 192.396,316.748 ; 192.397,316.748 192.47,316.674 ; v1(201.653,334.862) ccw(c202.055,334.862) 202.055,334.46 202.221,334.46
  L5 (Sign) w0.111: 202.771,334.462 202.883,334.462 cw(c202.883,334.077) 203.268,334.077 203.268,326.785
  L5 (Sign) w0.115: 192.47,316.674 193.357,316.674 ccw(c193.357,319.214) 195.153,317.418 195.182,317.447 195.938,318.203 198.03,320.295 198.147,320.412 ccw(c197.918,320.642) 198.147,320.872 196.957,322.061 ; 196.957,322.061 cw(c197.34,322.445) 196.957,322.829 197.262,323.134 cw(c197.646,322.751) 197.994,323.166 197.997,323.166 198.029,323.134 ; 198.029,323.134 201.162,320.002 ccw(c201.39,320.232) 201.619,320.003 ; 198.794,323.897 201.924,320.768 cw(c201.695,320.538) 201.924,320.308 201.62,320.003 ; 198.794,323.898 cw(c199.177,324.282) 198.793,324.665 199.099,324.971 cw(c199.482,324.587) 199.831,325.003 199.834,325.003 202.436,322.4 ccw(c202.666,322.629) 202.896,322.4 ; 202.434,324.699 ccw(c202.817,324.315) 202.433,323.931 203.201,323.164 cw(c202.972,322.934) 203.2,322.705 202.896,322.4 ; 202.434,324.699 202.825,325.09 ; 202.825,325.09 202.943,325.208 202.947,325.212 ccw(c201.999,326.159) 203.339,326.159 203.339,326.663 ccw(c203.217,326.663) 203.304,326.749 ; 203.268,326.785 203.303,326.75
  L14 (Sign) w0.1: 199.822,335.496 201.555,335.496
  L14 (Sign) w0.103: 165.705,335.414 cw(c165.705,334.89) 166.076,335.26 166.078,335.259 ccw(c166.599,335.78) 166.599,335.043 167.165,335.043 cw(c167.165,334.928) 167.279,334.928 v1(167.279,334.857) ; v1(178.74,334.857) cw(c178.966,334.857) 178.966,335.083 179.306,335.083 ccw(c179.306,337.44) 180.972,335.773 ; 188.563,334.651 ccw(c188.563,335.494) 189.159,334.898 189.16,334.899 cw(c189.595,334.464) 189.595,335.079 189.978,335.079 cw(c189.978,334.857) 190.193,334.913 190.192,334.911 v1(190.192,334.87) ; 190.36,335.08 190.721,335.08 ccw(c190.721,337.822) 192.66,335.883 192.857,336.08 cw(c193.256,335.682) 193.256,336.245 194.894,336.245 cw(c194.894,335.261) 195.59,335.957 195.743,335.804 ccw(c196.487,336.547) 196.487,335.496 197.164,335.496 197.624,335.496 cw(c197.624,335.373) 197.746,335.373 197.746,335.251 ccw(c197.869,335.251) 197.869,335.128 198.032,335.128 ccw(c198.032,335.251) 198.154,335.251 198.154,335.373 cw(c198.277,335.373) 198.277,335.496 199.022,335.496 199.822,335.496 ; 201.555,335.496 cw(c201.555,335.178) 201.872,335.178 201.872,335.08 cw(c201.653,335.08) v1(201.653,334.862)
  L14 (Sign) w0.111: 165.001,335.414 165.705,335.414 ; v1(167.279,334.857) cw(c167.502,334.857) 167.502,335.08 167.978,335.08 ccw(c167.978,336.231) 168.792,335.417 169.254,335.879 cw(c170.148,334.986) 170.148,336.249 170.268,336.249 170.739,336.249 cw(c170.739,336.125) 170.864,336.125 170.864,335.593 ccw(c170.989,335.593) 170.989,335.468 171.155,335.468 ccw(c171.155,335.593) 171.28,335.593 171.28,336.125 cw(c171.405,336.125) 171.405,336.249 171.861,336.249 173.627,336.249 174.099,336.249 cw(c174.099,336.125) 174.223,336.125 174.223,335.861 ccw(c174.348,335.861) 174.348,335.736 174.515,335.736 ccw(c174.515,335.861) 174.639,335.861 174.639,336.125 cw(c174.764,336.125) 174.764,336.249 174.957,336.249 174.997,336.249 cw(c174.997,335.828) 175.419,335.828 175.419,335.66 ccw(c175.999,335.66) 175.999,335.08 178.517,335.08 cw(c178.517,334.857) v1(178.74,334.857) ; 180.972,335.774 181.304,336.106 cw(c181.933,335.477) 181.835,336.361 cw(c181.933,335.477) 181.933,336.366 182.404,336.366 cw(c182.404,336.241) 182.529,336.241 182.529,336.179 ccw(c182.654,336.179) 182.654,336.054 182.82,336.054 ccw(c182.82,336.179) 182.945,336.179 182.945,336.241 cw(c183.07,336.241) 183.07,336.366 183.54,336.366 186.468,336.366 cw(c186.468,335.441) 187.393,335.441 187.393,335.426 ccw(c188.168,335.426) 188.168,334.652 188.562,334.652
  L14 (Sign) w0.128: v23(159.654,331.698) 159.73,331.698 159.894,331.862 162.446,331.862 ccw(c162.446,332.85) 163.434,332.85 163.434,334.527 cw(c164.386,334.527) 164.386,335.479 164.844,335.479 cw(c164.844,335.258) 165.001,335.414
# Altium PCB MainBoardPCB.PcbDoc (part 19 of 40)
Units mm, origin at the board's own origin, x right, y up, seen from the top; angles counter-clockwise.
Board outline 258.95 x 308.86 mm, 16 copper layers (L1, L2 (GND), L3 (Sign), L4 (GND), L5 (Sign), L6 (PWR/GND), L7(12V+Other), L8 (Plane_GND), L9 (PWR/GND), L10 (3V3+Other), L11 (PWR/GND), L12 (Sign), L13 (GND), L14 (Sign), L15 (GND), L16), stack 2.503 mm thick; 2578 components, 1867 nets, 8817 pads, 8021 vias.
Unrouted connection lines stored in the file: 25.

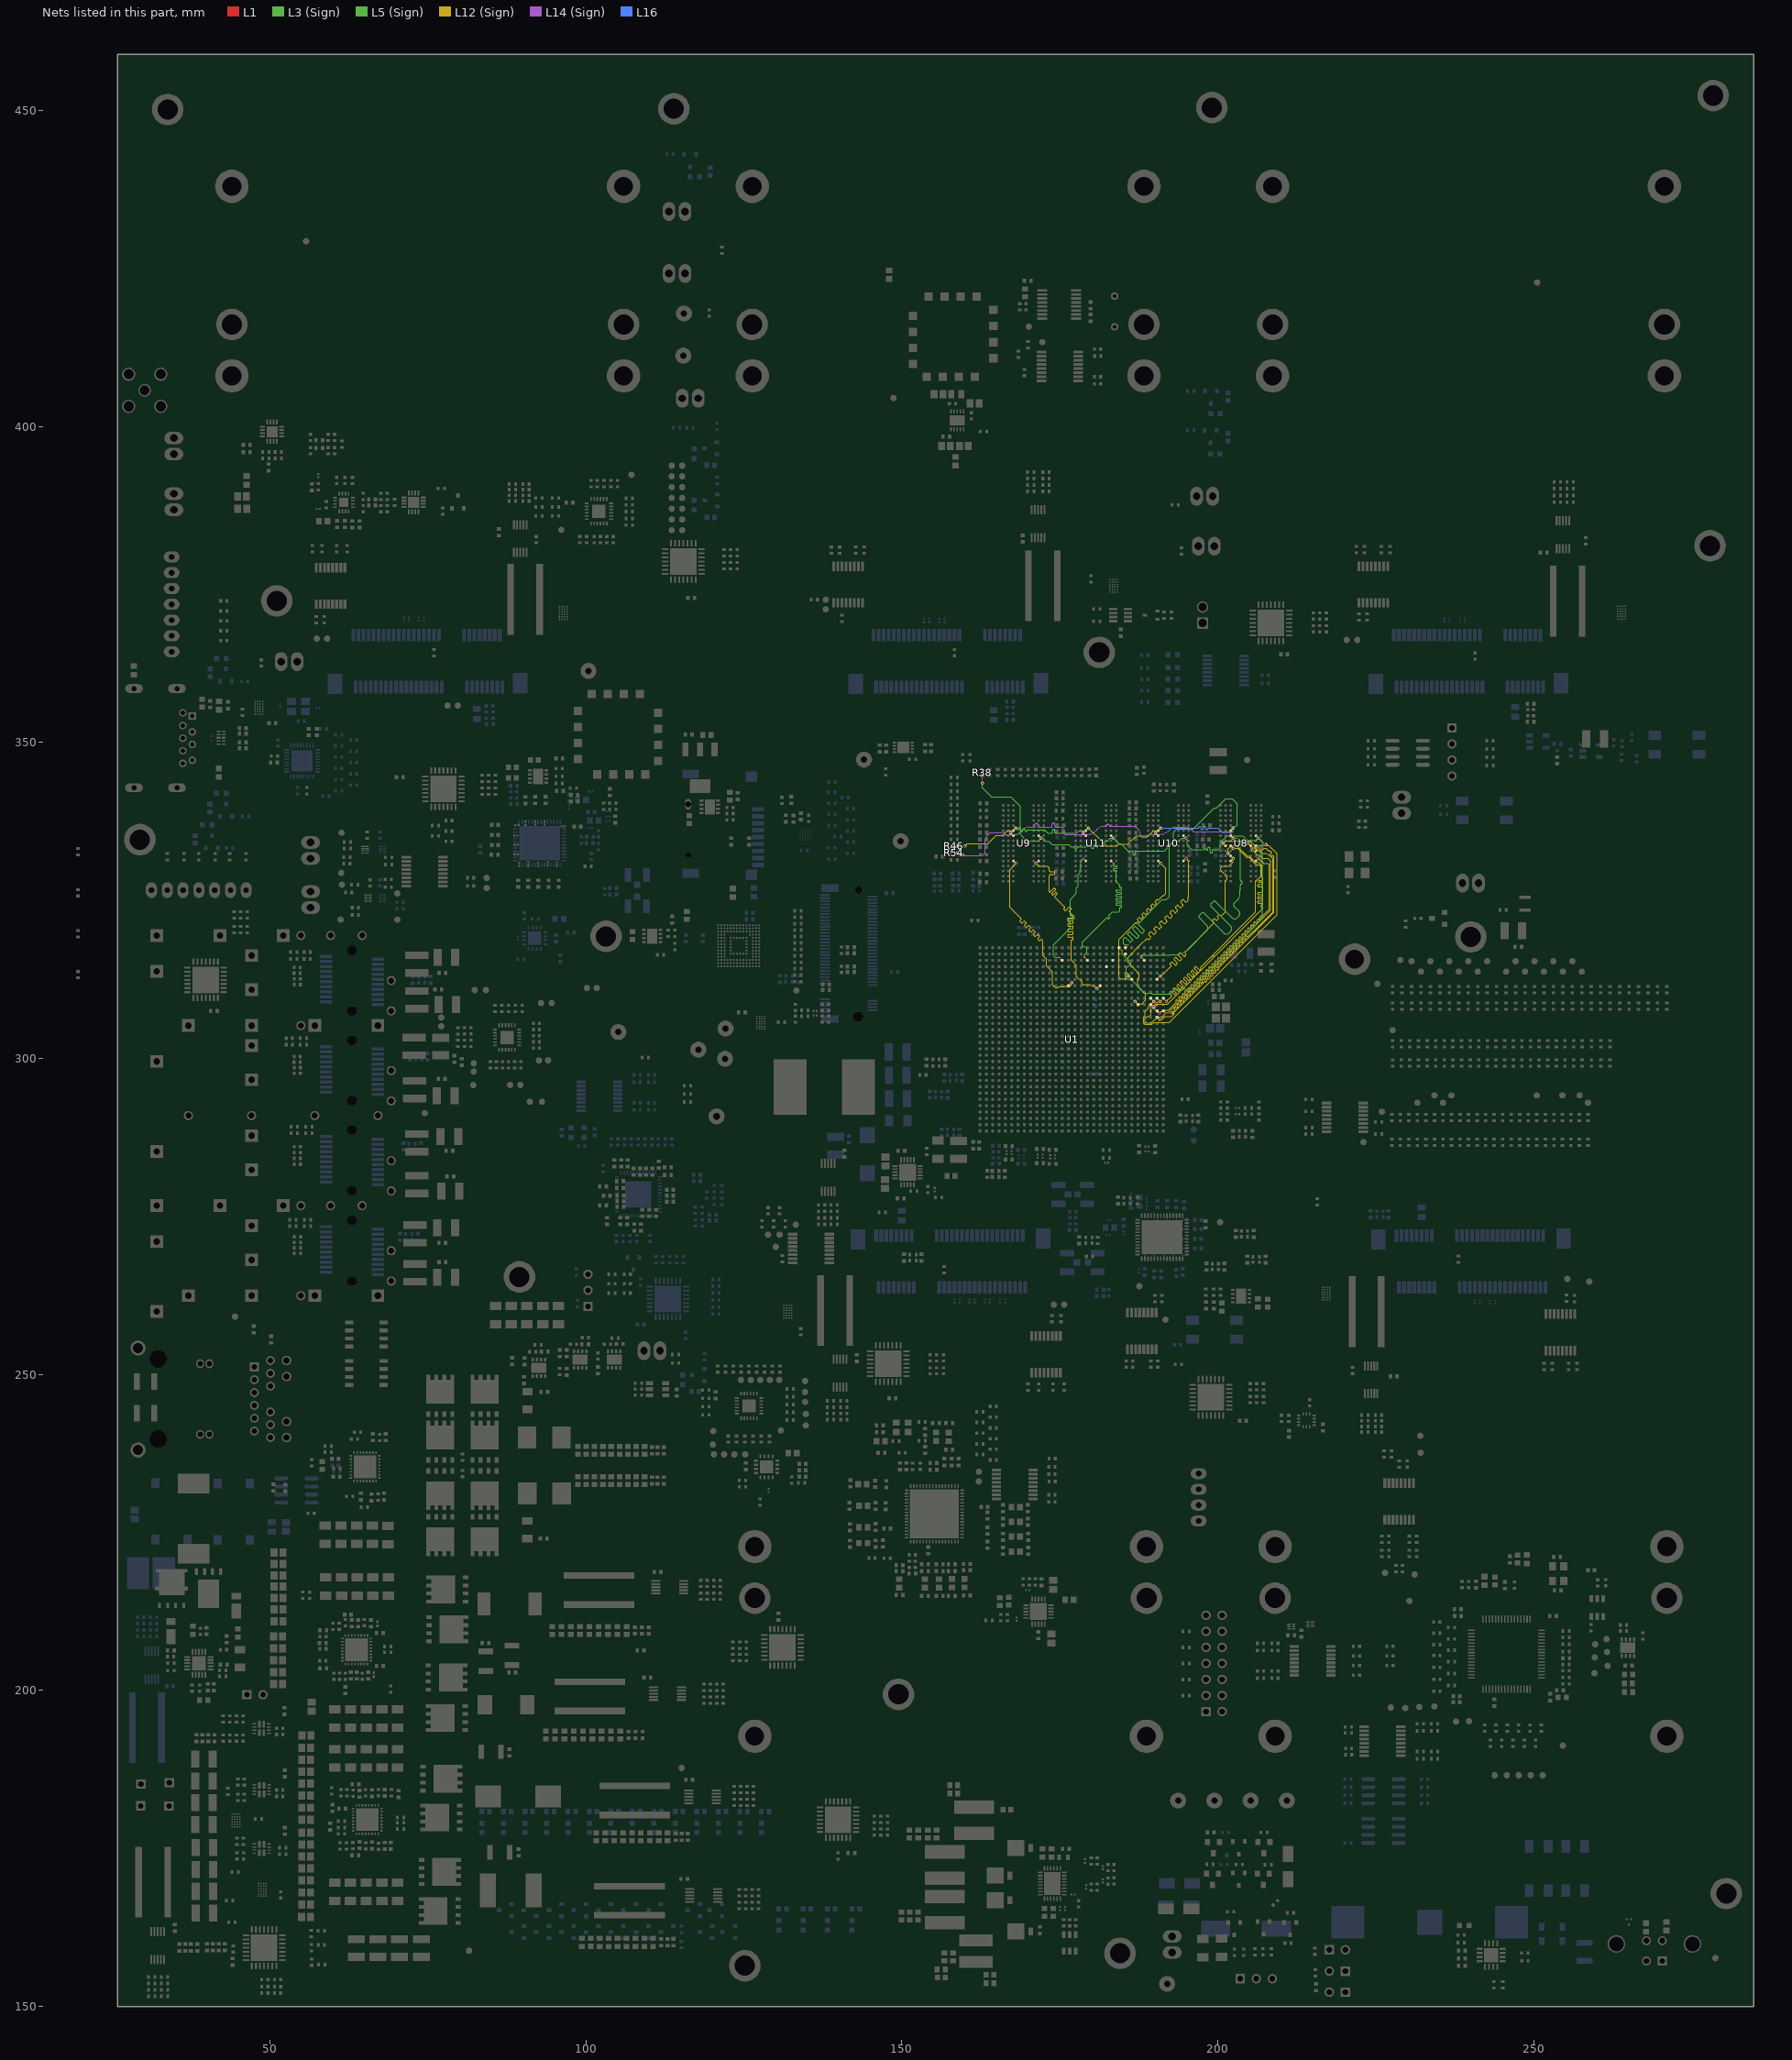
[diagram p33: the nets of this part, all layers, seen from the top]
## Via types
v1: diameter 0.5, hole 0.25, L1 to L16, tented both sides, 4341 vias
v2: diameter 0.254, hole 0.1, L1 to L3 (Sign), tented both sides, 781 vias
v3: diameter 0.5, hole 0.25, L1 to L16, 565 vias
v4: diameter 0.254, hole 0.1, L15 (GND) to L16, tented both sides, 406 vias
v5: diameter 0.254, hole 0.1, L1 to L2 (GND), tented both sides, 283 vias
v6: diameter 0.457, hole 0.2, L3 (Sign) to L6 (PWR/GND), tented both sides, 254 vias
v7: diameter 0.254, hole 0.1, L1 to L3 (Sign), 237 vias
v8: diameter 0.75, hole 0.4, L1 to L16, 200 vias
v9: diameter 0.8, hole 0.4, L1 to L16, tented both sides, 182 vias
v10: diameter 0.254, hole 0.1, L14 (Sign) to L16, tented both sides, 170 vias
v11: diameter 0.75/0/0/0/0/0/0/0/0/0/0/0/0/0/0/0.75 (per signal layer), hole 0.4, L1 to L16, 160 vias
v12: diameter 0.457, hole 0.2, L3 (Sign) to L6 (PWR/GND), 158 vias
v13: diameter 1.4, hole 0.5, L1 to L16, tented both sides, 80 vias
v14: diameter 0.254, hole 0.1, L14 (Sign) to L16, 65 vias
v15: diameter 0.254, hole 0.1, L1 to L2 (GND), 45 vias
v16: diameter 0.457, hole 0.2, L11 (PWR/GND) to L14 (Sign), tented both sides, 26 vias
v17: diameter 0.457, hole 0.2, L11 (PWR/GND) to L14 (Sign), 25 vias
v18: diameter 0.457, hole 0.2, L7(12V+Other) to L10 (3V3+Other), tented both sides, 11 vias
v19: diameter 0.254/0/0.254 (per signal layer), hole 0.1, L1 to L3 (Sign), 9 vias
v20: diameter 0.2/0/0.2 (per signal layer), hole 0.1, L1 to L3 (Sign), 6 vias
v21: diameter 1.65, hole 1.65, L1 to L16, 5 vias
v22: diameter 1.15, hole 1.15, L1 to L16, 5 vias
v23: diameter 0.457, hole 0.2, L1 to L16, 3 vias
v24: diameter 0.5, hole 0.3, L1 to L16, 2 vias
v25: diameter 0.5/0/0.5 (per signal layer), hole 0.2, L14 (Sign) to L16, 1 vias
v26: diameter 0.5, hole 0.25, L1 to L16, tented bottom, 1 vias

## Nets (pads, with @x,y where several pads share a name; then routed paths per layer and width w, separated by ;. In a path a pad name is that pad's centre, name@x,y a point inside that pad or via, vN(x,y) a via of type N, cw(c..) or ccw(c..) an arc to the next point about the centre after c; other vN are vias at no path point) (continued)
DDR4_CK_P: R54.1 U1.AG28 U8.K4 U9.K4 U10.K4 U11.K4 | length 104.5
  L1 w0.135: v1(167.272,335.664) U9.K4@167.676,335.26 ; v1(178.733,335.664) U11.K4@179.136,335.26 ; v1(187.897,316.075) 187.897,316.04 U1.AG28@188.397,315.539 ; v1(190.193,335.664) U10.K4@190.597,335.26 ; U8.K4@202.057,335.26 v1@202.453,334.863
  L1 w0.159: R54.1@158.787,332.522 158.933,332.376 158.933,332.208 159.026,332.115 159.431,332.115
  L5 (Sign) w0.103: v1(187.897,316.075) 187.897,316.179 cw(c188.103,316.179) 188.103,316.385 192.397,316.385 192.47,316.459 ; v1(202.453,334.862) 202.771,334.862
  L5 (Sign) w0.111: 202.771,334.862 202.844,334.862 cw(c202.844,334.077) 203.629,334.077 203.629,328.225 203.629,328.169 ccw(c203.753,328.169) 203.753,328.044 cw(c203.753,327.92) 203.878,327.92 203.878,327.753 cw(c203.753,327.753) 203.753,327.628 ccw(c203.753,327.504) 203.629,327.504 203.629,327.225 203.629,326.785
  L5 (Sign) w0.115: 192.47,316.459 193.359,316.459 ccw(c193.359,319.215) 195.307,317.266 195.309,317.266 198.184,320.141 198.301,320.258 ; 198.302,320.259 ccw(c197.918,320.642) 198.334,320.99 198.334,320.993 198.302,321.025 197.11,322.217 cw(c197.34,322.445) 197.111,322.675 197.416,322.979 cw(c197.646,322.751) 197.876,322.979 201.006,319.849 ccw(c201.39,320.232) 201.773,319.849 202.079,320.154 ccw(c201.695,320.538) 202.111,320.886 202.111,320.889 202.079,320.921 198.946,324.053 cw(c199.177,324.282) 198.948,324.511 199.252,324.816 cw(c199.482,324.587) 199.712,324.816 202.283,322.245 ccw(c202.666,322.629) 203.05,322.246 203.355,322.551 ccw(c202.972,322.934) 203.355,323.318 ; 202.587,324.544 ccw(c202.817,324.315) 202.588,324.085 203.354,323.319 ; 202.588,324.545 202.979,324.936 203.097,325.054 203.133,325.089 ccw(c202.108,326.114) 203.557,326.114 203.557,326.663 cw(c203.679,326.663) 203.593,326.75 203.629,326.785
  L14 (Sign) w0.103: 165.708,335.776 cw(c165.708,334.898) 166.33,335.519 166.332,335.517 ccw(c166.601,335.786) 166.601,335.405 167.165,335.405 ccw(c167.165,335.512) 167.272,335.512 v1(167.272,335.664) ; v1(178.733,335.664) ccw(c178.951,335.664) 178.951,335.445 179.302,335.445 ccw(c179.302,337.449) 180.719,336.032 ; 188.561,335.013 ccw(c188.561,335.497) 188.904,335.155 188.905,335.156 cw(c189.594,334.467) 189.594,335.441 189.971,335.441 ccw(c189.971,335.664) v1(190.193,335.664) 190.193,335.609 ccw(c190.36,335.609) 190.36,335.442 190.655,335.442 ccw(c190.655,337.982) 192.451,336.186 192.602,336.337 cw(c193.254,335.685) 193.254,336.607 194.896,336.607 cw(c194.896,335.266) 195.845,336.214 195.999,336.06 ccw(c196.487,336.549) 196.487,335.858 201.555,335.858 cw(c201.555,335.178) 202.235,335.178 202.235,335.08 ccw(c202.453,335.08) v1(202.453,334.862)
  L14 (Sign) w0.111: 165.001,335.775 165.708,335.775 ; v1(167.272,335.664) ccw(c167.495,335.664) 167.495,335.441 167.976,335.441 ccw(c167.976,336.235) 168.538,335.673 169.001,336.136 cw(c170.145,334.992) 170.145,336.61 170.959,336.61 171.014,336.61 ccw(c171.014,336.735) 171.139,336.735 171.139,337.088 cw(c171.264,337.088) 171.264,337.212 171.43,337.212 cw(c171.43,337.088) 171.555,337.088 171.555,336.735 ccw(c171.68,336.735) 171.68,336.61 172.091,336.61 173.641,336.61 173.696,336.61 ccw(c173.696,336.735) 173.821,336.735 173.821,337.112 cw(c173.946,337.112) 173.946,337.237 174.112,337.237 cw(c174.112,337.112) 174.237,337.112 174.237,336.735 ccw(c174.362,336.735) 174.362,336.61 174.997,336.61 cw(c174.997,335.828) 175.78,335.828 175.78,335.66 ccw(c175.999,335.66) 175.999,335.441 178.51,335.441 ccw(c178.51,335.664) v1(178.733,335.664) ; 180.72,336.032 181.05,336.362 cw(c181.931,335.48) 181.931,336.727 182.244,336.727 182.3,336.727 ccw(c182.3,336.852) 182.425,336.852 182.425,336.919 cw(c182.549,336.919) 182.549,337.044 182.716,337.044 cw(c182.716,336.919) 182.841,336.919 182.841,336.852 ccw(c182.965,336.852) 182.965,336.727 183.207,336.727 183.213,336.727 186.468,336.727 cw(c186.468,335.441) 187.754,335.441 187.754,335.43 ccw(c188.171,335.43) 188.171,335.013 188.561,335.013
  L14 (Sign) w0.128: v23(159.654,332.257) 159.73,332.257 159.894,332.093 162.446,332.093 ccw(c162.446,332.85) 163.203,332.85 163.203,334.527 cw(c164.386,334.527) 164.386,335.711 164.844,335.711 ccw(c164.844,335.932) 165.001,335.775
DDR4_CKE0: R38.1 U1.AC30 U8.K2 U9.K2 U10.K2 U11.K2 | length 113.4
  L1 w0.1: U9.K2@171.676,335.26 v1(172.079,334.857) ; U11.K2@183.136,335.26 v1(183.54,334.857) ; U1.AC30@184.397,317.539 v2(184.884,317.052) ; U10.K2@194.597,335.26 194.997,334.86 v1(195.005,334.86) ; U8.K2@206.057,335.26 v1(206.461,334.857)
  L1 w0.155: v1(162.769,343.555) R38.1@162.769,344.75 R38.1@162.769,344.8
  L5 (Sign) w0.081: 165.251,341.376 167.28,341.376 168.793,339.863 168.793,335.418 169.751,334.46 171.683,334.46 v1(172.079,334.857) 172.333,334.857 172.828,334.362 173.295,334.362 173.804,333.853 173.808,333.858 176.446,333.858 176.802,333.501 177.228,333.501 cw(c177.228,333.386) 177.344,333.386 177.344,333.322 ccw(c177.46,333.322) 177.46,333.206 177.614,333.206 ccw(c177.614,333.322) 177.73,333.322 177.73,333.386 cw(c177.846,333.386) 177.846,333.501 178.397,333.501 179.331,333.501 179.565,333.736 179.941,333.736 cw(c179.941,333.619) 180.058,333.619 180.058,333.38 ccw(c180.175,333.38) 180.175,333.263 180.276,333.263 ccw(c180.276,333.38) 180.393,333.38 180.393,333.736 cw(c180.51,333.736) 180.51,333.853 180.611,333.853 cw(c180.611,333.736) 180.728,333.736 180.728,333.619 ccw(c180.845,333.619) 180.845,333.501 180.946,333.501 ccw(c180.946,333.619) 181.063,333.619 cw(c181.18,333.619) 181.18,333.736 181.524,333.736 181.612,333.736 182.336,334.46 182.629,334.46 183.025,334.857 v1(183.54,334.857) 184.385,334.012 184.654,334.012 185.805,332.86 186.051,332.86 186.477,332.86 cw(c186.477,332.745) 186.593,332.745 186.593,332.338 ccw(c186.709,332.338) 186.709,332.222 186.863,332.222 ccw(c186.863,332.338) 186.979,332.338 186.979,332.745 cw(c187.095,332.745) 187.095,332.86 187.258,332.86 191.573,332.86 193.173,334.46 193.955,334.46 194.352,334.857 195,334.857 195,334.751 195.204,334.547 195.204,333.727 195.861,333.07 197.583,333.07 197.73,333.07 ccw(c197.73,333.154) 197.814,333.154 cw(c197.897,333.154) 197.897,333.238 198.065,333.238 cw(c198.065,333.154) 198.149,333.154 198.149,333.07 ccw(c198.233,333.07) 198.233,332.986 198.4,332.986 ccw(c198.4,333.07) 198.484,333.07 198.484,333.316 cw(c198.568,333.316) 198.568,333.399 198.735,333.399 cw(c198.735,333.316) 198.819,333.316 198.819,332.634 ccw(c198.903,332.634) 198.903,332.55 199.071,332.55 ccw(c199.071,332.634) 199.154,332.634 199.154,332.986 cw(c199.238,332.986) 199.238,333.07 199.279,333.07 200.101,333.07 200.416,333.385 200.416,334.179 201.489,335.252 203.956,335.252 204.728,334.48 206.084,334.48 v1(206.461,334.857)
  L5 (Sign) w0.151: v1(162.769,343.555) 162.769,342.831 164.224,341.376 165.251,341.376
  L3 (Sign) w0.079: 185.504,314.372 185.504,313.625 185.47,313.591 185.47,312.845 185.753,312.562 186.211,312.562 186.349,312.424
  L3 (Sign) w0.081: v2(184.884,317.052) 184.884,316.531 186.231,315.185 186.231,314.919 185.857,314.546 185.678,314.546 185.504,314.372 ; 186.349,312.424 188.102,310.671 188.166,310.671 188.507,310.33 189.446,310.33 189.597,310.179 192.397,310.179 ; v1(206.461,334.857) 207.05,334.268 207.05,334.227 ccw(c207.146,334.227) 207.146,334.131 207.151,334.131 cw(c207.151,334.034) 207.247,334.034 207.247,333.841 cw(c207.151,333.841) 207.151,333.745 206.381,333.745 ccw(c206.381,333.649) 206.285,333.649 206.285,333.456 ccw(c206.381,333.456) 206.381,333.359 207.029,333.359 cw(c207.029,333.263) 207.125,333.263 207.125,333.07 cw(c207.029,333.07) 207.029,332.973 206.813,332.973 ccw(c206.813,332.877) 206.716,332.877 206.716,332.684 ccw(c206.813,332.684) 206.813,332.588 206.953,332.588 cw(c206.953,332.491) 207.05,332.491 207.05,331.891 207.05,326.785
  L3 (Sign) w0.171: 192.397,310.179 192.48,310.179 192.556,310.255
  L3 (Sign) w0.172: 192.556,310.255 193.311,311.01 195.891,311.01 207.05,322.169 207.05,326.785
DDR4_CKE1: U1.AB28
DDR4_CS_B: R46.1 U1.AD30 U8.L4 U9.L4 U10.L4 U11.L4 | length 102.5
  L1 w0.1: U9.L4@167.676,336.06 168.072,336.457 v1(168.075,336.457) ; U11.L4@179.136,336.06 179.533,336.457 v1(179.535,336.457) ; U1.AD30@185.397,317.539 v2(185.884,318.027) ; U10.L4@190.597,336.06 190.993,336.457 v1(190.995,336.457) ; U8.L4@202.057,336.06 202.453,336.457 v1(202.456,336.457)
  L1 w0.155: R46.1@158.787,333.611 v1(159.982,333.611)
  L12 (Sign) w0.081: 165.251,335.311 165.921,335.311 166.661,336.051 167.218,336.051 cw(c167.272,335.664) 167.326,336.051 167.668,336.051 v1(168.075,336.457) ; v1(179.535,336.457) 181.588,334.404 182.372,333.62 183.98,333.62 184.274,333.914 185.774,333.914 187.12,335.26 188.997,335.26 189.797,336.06 190.599,336.06 v1(190.995,336.457)
  L12 (Sign) w0.151: v1(159.982,333.611) 160.365,333.994 163.608,333.994 164.926,335.311 165.251,335.311
  L3 (Sign) w0.079: 192.917,334.386 193.004,334.473 193.004,335.818 193.232,336.046
  L3 (Sign) w0.081: v1(168.075,336.457) 168.339,336.192 168.38,336.192 ccw(c168.38,336.309) 168.497,336.309 168.497,336.437 cw(c168.614,336.437) 168.614,336.555 168.715,336.555 cw(c168.715,336.437) 168.832,336.437 168.832,336.04 ccw(c168.949,336.04) 168.949,335.923 169.05,335.923 ccw(c169.05,336.04) 169.167,336.04 169.167,336.192 cw(c169.284,336.192) 169.284,336.31 169.385,336.31 cw(c169.385,336.192) 169.502,336.192 169.502,336.075 ccw(c169.619,336.075) 169.619,335.958 169.72,335.958 ccw(c169.72,336.075) 169.837,336.075 cw(c169.954,336.075) 169.954,336.192 170.136,336.192 172.613,336.192 173.167,335.638 173.716,335.638 173.757,335.638 ccw(c173.757,335.754) 173.873,335.754 173.873,336.121 cw(c173.989,336.121) 173.989,336.236 174.143,336.236 cw(c174.143,336.121) 174.259,336.121 174.259,335.754 ccw(c174.375,335.754) 174.375,335.638 174.91,335.638 177.655,335.638 178.071,336.054 179.133,336.054 v1(179.535,336.457) ; 185.115,318.539 185.115,318.173 185.261,318.027 v2(185.884,318.027) ; 192.321,326.785 192.321,333.79 192.917,334.386 ; 193.232,336.046 193.481,336.296 196.13,336.296 199.459,339.625 199.803,339.625 201.263,341.085 202.309,341.085 203.057,340.338 203.057,336.918 202.905,336.766 202.765,336.766 v1(202.456,336.457)
  L3 (Sign) w0.172: 185.115,318.539 185.115,319.008 ; 187.562,321.454 191.227,325.12 191.846,325.12 192.321,325.594 192.321,326.785
  L3 (Sign) w0.173: 185.115,319.008 185.218,319.11 cw(c185.32,319.008) 185.423,319.11 186.087,318.446 ccw(c186.189,318.548) 186.292,318.446 186.497,318.651 ccw(c186.394,318.753) 186.497,318.856 185.73,319.623 cw(c185.805,319.698) 185.73,319.773 185.989,320.032 cw(c186.064,319.957) 186.14,320.032 187.107,319.065 ccw(c187.21,319.167) 187.312,319.065 187.517,319.27 ccw(c187.415,319.372) 187.517,319.475 186.55,320.442 cw(c186.625,320.518) 186.55,320.593 ; 186.55,320.593 186.808,320.852 cw(c186.884,320.777) 186.959,320.852 187.927,319.884 ccw(c188.029,319.987) 188.132,319.884 188.337,320.089 ccw(c188.234,320.192) 188.337,320.294 187.472,321.159 cw(c187.574,321.262) 187.472,321.364 187.562,321.454
  L16 w0.101: v1(190.995,336.457) 191.001,336.451 196.841,336.451 196.892,336.451 ccw(c196.892,336.552) 196.993,336.552 196.993,336.577 cw(c197.081,336.577) 197.081,336.666 197.259,336.666 cw(c197.259,336.577) 197.348,336.577 197.348,336.324 ccw(c197.437,336.324) 197.437,336.236 197.614,336.236 ccw(c197.614,336.324) 197.703,336.324 197.703,336.564 cw(c197.792,336.564) 197.792,336.653 197.969,336.653 cw(c197.969,336.564) 198.058,336.564 198.058,336.35 ccw(c198.147,336.35) 198.147,336.261 198.325,336.261 ccw(c198.325,336.35) 198.413,336.35 cw(c198.514,336.35) 198.514,336.451 198.847,336.451 200.059,336.451 200.702,335.807 202.286,335.807 202.427,335.948 202.427,336.428 v1(202.456,336.457)
DDR4_CS_N1: U1.AD29
DDR4_DM0: U1.AJ20 U8.E2 | length 46.3
  L1 w0.116: U1.AJ20@190.397,307.539 v1(190.8,307.136) ; U8.E2@206.057,331.26 v1(206.461,331.664)
  L12 (Sign) w0.081: v1(190.8,307.136) 191.086,307.422 191.664,307.422 191.885,307.642 192.202,307.642 193.392,308.832 193.421,308.86 ccw(c193.349,308.932) 193.421,309.003 193.385,309.038 cw(c193.457,309.109) 193.385,309.18 193.48,309.275 cw(c193.551,309.204) 193.622,309.275 193.69,309.207 ccw(c193.761,309.278) 193.832,309.207 193.927,309.302 ccw(c193.856,309.373) 193.927,309.444 193.859,309.512 cw(c193.931,309.583) 193.859,309.654 193.954,309.749 cw(c194.025,309.678) 194.096,309.749 194.164,309.681 ccw(c194.235,309.752) 194.306,309.681 194.401,309.776 ccw(c194.33,309.847) 194.401,309.918 194.334,309.986 cw(c194.405,310.057) 194.334,310.128 194.428,310.223 cw(c194.499,310.152) 194.571,310.223 194.638,310.155 ccw(c194.709,310.226) 194.78,310.155 194.875,310.25 ccw(c194.804,310.321) 194.875,310.392 194.808,310.46 cw(c194.879,310.531) 194.808,310.602 194.902,310.697 cw(c194.973,310.626) 195.045,310.697 195.112,310.629 ccw(c195.183,310.701) 195.254,310.629 195.349,310.724 ccw(c195.278,310.795) 195.349,310.866 195.282,310.934 cw(c195.353,311.005) 195.282,311.076 195.376,311.171 cw(c195.448,311.1) 195.519,311.171 195.586,311.103 ccw(c195.657,311.175) 195.728,311.103 195.823,311.198 ccw(c195.752,311.269) 195.823,311.34 195.756,311.408 cw(c195.827,311.479) 195.756,311.55 195.85,311.645 cw(c195.922,311.574) 195.993,311.645 196.06,311.578 ccw(c196.131,311.649) 196.202,311.578 196.297,311.672 ccw(c196.226,311.743) 196.297,311.815 196.23,311.882 cw(c196.301,311.953) 196.23,312.024 196.325,312.119 cw(c196.396,312.048) 196.467,312.119 196.534,312.052 ccw(c196.605,312.123) 196.677,312.052 196.771,312.146 ccw(c196.7,312.217) 196.771,312.289 196.704,312.356 cw(c196.775,312.427) 196.704,312.498 196.799,312.593 cw(c196.87,312.522) 196.941,312.593 197.008,312.526 ccw(c197.079,312.597) 197.151,312.526 197.245,312.62 ccw(c197.174,312.692) 197.245,312.763 197.178,312.83 cw(c197.249,312.901) 197.178,312.972 197.273,313.067 cw(c197.344,312.996) 197.415,313.067 197.482,313 ccw(c197.554,313.071) 197.625,313 197.719,313.094 ccw(c197.648,313.166) 197.719,313.237 197.652,313.304 cw(c197.723,313.375) 197.652,313.446 197.747,313.541 cw(c197.818,313.47) 197.889,313.541 197.956,313.474 ccw(c198.028,313.545) 198.099,313.474 198.193,313.569 ccw(c198.122,313.64) 198.193,313.711 198.126,313.778 cw(c198.197,313.849) 198.126,313.921 198.221,314.015 cw(c198.292,313.944) 198.363,314.015 198.431,313.948 ccw(c198.502,314.019) 198.573,313.948 198.668,314.043 ccw(c198.596,314.114) 198.668,314.185 198.6,314.252 cw(c198.671,314.323) 198.6,314.395 198.695,314.489 cw(c198.766,314.418) 198.837,314.489 198.905,314.422 ccw(c198.976,314.493) 199.047,314.422 199.142,314.517 ccw(c199.07,314.588) 199.142,314.659 199.074,314.726 cw(c199.145,314.798) 199.074,314.869 199.169,314.963 cw(c199.24,314.892) 199.311,314.963 199.379,314.896 ccw(c199.45,314.967) 199.521,314.896 199.616,314.991 ccw(c199.545,315.062) 199.616,315.133 199.548,315.2 cw(c199.619,315.272) 199.548,315.343 199.643,315.437 cw(c199.714,315.366) 199.785,315.437 199.853,315.37 ccw(c199.924,315.441) 199.995,315.37 200.09,315.465 ccw(c200.019,315.536) 200.09,315.607 200.022,315.675 cw(c200.093,315.746) 200.022,315.817 200.117,315.912 cw(c200.188,315.84) 200.259,315.912 200.327,315.844 ccw(c200.398,315.915) 200.469,315.844 200.564,315.939 ccw(c200.493,316.01) 200.564,316.081 200.496,316.149 cw(c200.567,316.22) 200.496,316.291 200.591,316.386 cw(c200.662,316.314) 200.733,316.386 200.801,316.318 ccw(c200.872,316.389) 200.943,316.318 201.038,316.413 ccw(c200.967,316.484) 201.038,316.555 200.97,316.623 cw(c201.041,316.694) 200.97,316.765 201.065,316.86 cw(c201.136,316.789) 201.207,316.86 201.275,316.792 ccw(c201.346,316.863) 201.417,316.792 201.512,316.887 ccw(c201.441,316.958) 201.512,317.029 201.444,317.097 cw(c201.515,317.168) 201.444,317.239 201.539,317.334 cw(c201.61,317.263) 201.681,317.334 201.749,317.266 ccw(c201.82,317.337) 201.891,317.266 201.986,317.361 ccw(c201.915,317.432) 201.986,317.503 201.918,317.571 cw(c201.989,317.642) 201.918,317.713 202.013,317.808 cw(c202.084,317.737) 202.155,317.808 202.223,317.74 ccw(c202.294,317.811) 202.365,317.74 202.46,317.835 ccw(c202.389,317.906) 202.46,317.977 202.392,318.045 cw(c202.463,318.116) 202.392,318.187 202.487,318.282 cw(c202.558,318.211) 202.629,318.282 202.697,318.214 ccw(c202.768,318.285) 202.839,318.214 202.934,318.309 ccw(c202.863,318.38) 202.934,318.451 202.866,318.519 cw(c202.937,318.59) 202.866,318.661 202.961,318.756 cw(c203.032,318.685) 203.103,318.756 203.171,318.688 ccw(c203.242,318.759) 203.313,318.688 203.408,318.783 ccw(c203.337,318.854) 203.408,318.925 203.34,318.993 cw(c203.411,319.064) 203.34,319.135 203.435,319.23 cw(c203.506,319.159) 203.577,319.23 203.645,319.162 ccw(c203.716,319.233) 203.787,319.162 203.882,319.257 ccw(c203.811,319.328) 203.882,319.399 203.814,319.467 cw(c203.886,319.538) 203.814,319.609 203.909,319.704 cw(c203.98,319.633) 204.051,319.704 204.119,319.636 ccw(c204.19,319.707) 204.261,319.636 204.356,319.731 ccw(c204.285,319.802) 204.356,319.873 204.288,319.941 cw(c204.36,320.012) 204.288,320.083 204.383,320.178 cw(c204.454,320.107) 204.526,320.178 204.593,320.11 ccw(c204.664,320.181) 204.735,320.11 204.83,320.205 ccw(c204.759,320.276) 204.83,320.347 204.763,320.415 cw(c204.834,320.486) 204.763,320.557 204.857,320.652 cw(c204.928,320.581) 205,320.652 205.067,320.584 ccw(c205.138,320.655) 205.209,320.584 205.304,320.679 ccw(c205.233,320.75) 205.304,320.821 205.237,320.889 cw(c205.308,320.96) 205.237,321.031 205.331,321.126 cw(c205.402,321.055) 205.474,321.126 205.541,321.058 ccw(c205.612,321.13) 205.683,321.058 205.778,321.153 ccw(c205.707,321.224) 205.778,321.295 205.712,321.362 cw(c205.783,321.433) 205.712,321.504 205.806,321.599 cw(c205.877,321.528) 205.949,321.599 206.015,321.532 ccw(c206.086,321.604) 206.157,321.532 206.252,321.627 ccw(c206.181,321.698) 206.252,321.769 cw(c206.323,321.841) 206.252,321.912 206.347,322.007 cw(c206.418,321.935) 206.489,322.007 ccw(c206.56,322.078) 206.632,322.007 206.726,322.101 ccw(c206.655,322.172) 206.726,322.244 206.694,322.276 cw(c206.765,322.347) 206.694,322.418 206.789,322.513 cw(c206.86,322.442) 206.931,322.513 ccw(c207.002,322.584) 207.073,322.513 208.164,323.603 208.164,330.641 207.948,330.857 207.682,330.857 207.268,330.857 v1(206.461,331.664)
DDR4_DM1: U1.AJ25 U8.E4 | length 32.1
  L1 w0.116: U1.AJ25@190.397,312.539 v1(190.884,313.027) ; U8.E4@202.07,331.241 202.07,331.277 202.442,331.649 v1(202.442,331.653)
  L12 (Sign) w0.081: v1@190.835,313.051 190.862,313.078 191.072,313.078 191.564,313.57 191.574,313.57 192.552,314.548 192.581,314.577 ; 192.581,314.784 192.5,314.864 cw(c192.604,314.968) 192.5,315.071 192.638,315.209 cw(c192.742,315.106) 192.845,315.209 193.224,314.83 ccw(c193.328,314.933) 193.431,314.83 193.569,314.968 ccw(c193.466,315.071) 193.569,315.174 193.113,315.63 cw(c193.216,315.734) 193.113,315.837 193.251,315.975 cw(c193.354,315.872) 193.458,315.975 193.914,315.519 ccw(c194.017,315.622) 194.12,315.519 194.258,315.657 ccw(c194.155,315.76) 194.258,315.864 193.802,316.32 cw(c193.906,316.423) 193.802,316.526 193.94,316.664 cw(c194.043,316.561) 194.147,316.664 194.603,316.208 ccw(c194.706,316.312) 194.81,316.208 194.948,316.346 ccw(c194.844,316.449) 194.948,316.553 194.856,316.645 cw(c194.959,316.748) 194.856,316.852 195.154,317.15 199.351,321.347 199.379,321.375 ccw(c199.276,321.479) 199.379,321.582 199.222,321.739 cw(c199.325,321.843) 199.222,321.946 199.36,322.084 cw(c199.463,321.981) 199.567,322.084 199.728,321.923 ccw(c199.831,322.026) 199.934,321.923 200.072,322.061 ccw(c199.969,322.164) 200.072,322.268 199.977,322.363 cw(c200.08,322.466) 199.977,322.57 200.115,322.708 cw(c200.218,322.604) 200.321,322.708 200.413,322.616 ccw(c200.517,322.72) 200.62,322.616 201.06,323.056 201.178,323.174 201.178,328.1 201.46,328.382 201.46,328.841 200.5,329.802 200.5,330.193 200.738,330.432 201.773,330.432 202.442,331.101 v1(202.442,331.653) ; 192.581,314.577 ccw(c192.478,314.68) 192.581,314.784
DDR4_DM2: U1.AF21 U10.E2 | length 39.4
  L1 w0.116: v1(186.909,309.027) U1.AF21@187.397,308.539 ; U10.E2@194.597,331.26 194.993,331.657 v1(195,331.657)
  L12 (Sign) w0.081: v1(186.909,309.027) 187.261,308.675 187.597,308.675 187.631,308.641 187.966,308.641 187.986,308.661 188.046,308.661 188.62,309.235 188.62,310.15 187.357,311.413 187.357,312.539 187.596,312.777 187.596,313.416 185.814,315.198 185.814,316.001 187.966,318.154 188.705,318.893 cw(c188.811,318.787) 188.917,318.893 188.945,318.865 ccw(c189.051,318.971) 189.157,318.865 189.37,319.077 ccw(c189.263,319.183) 189.37,319.289 189.236,319.423 189.102,319.557 cw(c189.208,319.663) 189.102,319.769 189.314,319.982 cw(c189.42,319.876) 189.526,319.982 189.66,319.848 189.794,319.714 ccw(c189.9,319.82) 190.006,319.714 190.218,319.926 ccw(c190.112,320.032) 190.218,320.138 190.084,320.272 189.951,320.406 cw(c190.057,320.512) 189.951,320.618 190.163,320.83 cw(c190.269,320.724) 190.375,320.83 190.509,320.697 190.643,320.563 ccw(c190.749,320.669) 190.855,320.563 191.067,320.775 ccw(c190.961,320.881) 191.067,320.987 190.933,321.121 190.799,321.255 cw(c190.905,321.361) 190.799,321.467 191.012,321.679 cw(c191.118,321.573) 191.224,321.679 191.358,321.545 191.492,321.411 ccw(c191.598,321.518) 191.704,321.411 191.916,321.624 ccw(c191.81,321.73) 191.916,321.836 191.782,321.97 191.648,322.104 cw(c191.754,322.21) 191.648,322.316 191.86,322.528 cw(c191.966,322.422) 192.073,322.528 192.206,322.394 192.34,322.26 ccw(c192.446,322.366) 192.553,322.26 192.765,322.472 ccw(c192.659,322.579) 192.765,322.685 192.631,322.819 192.497,322.952 cw(c192.603,323.059) 192.497,323.165 192.709,323.377 cw(c192.815,323.271) 192.921,323.377 193.055,323.243 193.189,323.109 ccw(c193.295,323.215) 193.401,323.109 193.614,323.321 ccw(c193.507,323.427) 193.614,323.533 193.48,323.667 193.346,323.801 cw(c193.452,323.907) 193.346,324.013 193.558,324.226 cw(c193.664,324.12) 193.77,324.226 193.904,324.092 194.038,323.958 ccw(c194.144,324.064) 194.25,323.958 194.462,324.17 ccw(c194.356,324.276) 194.462,324.382 194.328,324.516 194.195,324.65 cw(c194.301,324.756) 194.195,324.862 194.407,325.074 cw(c194.513,324.968) 194.619,325.074 194.753,324.941 194.887,324.807 ccw(c194.993,324.913) 195.099,324.807 195.311,325.019 ccw(c195.205,325.125) 195.311,325.231 195.283,325.259 cw(c195.39,325.365) 195.283,325.471 195.389,325.577 195.389,331.267 v1(195,331.657)
DDR4_DM3: U1.AE25 U10.E4 | length 28.8
  L1 w0.116: v1(185.909,313.027) U1.AE25@186.397,312.539 ; U10.E4@190.597,331.26 v1(191,330.857)
  L12 (Sign) w0.081: v1(185.909,313.027) 185.909,313.251 ccw(c185.712,313.251) 185.712,313.449 185.603,313.449 ccw(c185.603,313.278) 185.433,313.278 185.433,312.793 cw(c185.255,312.793) 185.255,312.615 184.596,312.615 184.396,312.814 184.396,318.867 186.505,320.975 186.681,321.152 186.963,321.434 cw(c187.034,321.363) 187.104,321.434 187.107,321.431 ccw(c187.177,321.502) 187.248,321.431 187.459,321.643 ccw(c187.389,321.713) 187.459,321.784 187.386,321.857 187.313,321.93 cw(c187.384,322) 187.313,322.071 187.525,322.283 cw(c187.595,322.212) 187.666,322.283 187.739,322.209 187.812,322.136 ccw(c187.882,322.207) 187.953,322.136 188.165,322.348 ccw(c188.094,322.418) 188.165,322.489 188.091,322.562 188.018,322.635 cw(c188.089,322.706) 188.018,322.776 188.23,322.988 cw(c188.3,322.917) 188.371,322.988 188.444,322.914 188.517,322.841 ccw(c188.588,322.912) 188.658,322.841 188.87,323.053 ccw(c188.799,323.123) 188.87,323.194 188.796,323.267 188.723,323.34 cw(c188.794,323.411) 188.723,323.481 188.935,323.693 cw(c189.005,323.622) 189.076,323.693 189.149,323.62 189.222,323.546 ccw(c189.293,323.617) 189.363,323.546 189.575,323.758 ccw(c189.504,323.828) 189.575,323.899 189.502,323.972 189.428,324.045 cw(c189.499,324.116) 189.428,324.186 189.64,324.398 cw(c189.71,324.327) 189.781,324.398 189.854,324.325 189.927,324.252 ccw(c189.998,324.322) 190.068,324.252 190.28,324.463 ccw(c190.209,324.534) 190.28,324.604 190.207,324.677 190.134,324.75 cw(c190.204,324.821) 190.134,324.892 190.345,325.103 cw(c190.416,325.033) 190.486,325.103 190.489,325.1 ccw(c190.559,325.171) 190.63,325.1 191.253,325.723 191.358,325.829 191.476,325.829 191.771,326.125 ; v1(191,330.857) 191.771,330.085 191.771,326.125 ; 191.771,326.432 191.771,326.125
DDR4_DM4: U1.Y24 U9.E2 | length 39.1
  L1 w0.116: v1(171.272,330.857) U9.E2@171.676,331.26 ; v1(180.909,311.052) U1.Y24@181.397,311.539
  L12 (Sign) w0.081: v1(171.272,330.857) 171.669,330.46 173.074,330.46 173.36,330.175 173.36,329.73 ccw(c173.494,329.73) 173.494,329.597 174.117,329.597 cw(c174.117,329.466) 174.247,329.466 174.247,329.349 cw(c174.025,329.349) 174.025,329.127 173.632,329.127 ccw(c173.632,328.855) 173.36,328.855 173.36,326.385 173.389,326.356 ccw(c173.446,326.413) 173.503,326.356 174.09,326.943 cw(c174.137,326.895) 174.185,326.943 174.327,326.8 cw(c174.279,326.753) 174.327,326.706 173.731,326.109 ccw(c173.778,326.062) 173.731,326.014 173.873,325.872 ccw(c173.92,325.92) 173.968,325.872 174.364,326.269 cw(c174.411,326.221) 174.459,326.269 174.601,326.126 cw(c174.554,326.079) 174.601,326.032 174.214,325.645 ccw(c174.272,325.588) 174.214,325.531 174.412,325.333 175.438,324.307 175.775,323.97 cw(c175.714,323.908) 175.775,323.846 175.659,323.729 ccw(c175.72,323.668) 175.659,323.606 175.844,323.42 ccw(c175.906,323.482) 175.967,323.42 176.491,323.944 cw(c176.553,323.882) 176.615,323.944 176.8,323.759 cw(c176.738,323.697) 176.8,323.635 176.517,323.352 ccw(c176.578,323.29) 176.517,323.228 176.807,322.938 176.807,322.829 176.807,322.789 ccw(c176.894,322.789) 176.894,322.701 177.018,322.701 cw(c177.018,322.614) 177.106,322.614 177.106,322.352 cw(c177.018,322.352) 177.018,322.265 176.417,322.265 ccw(c176.417,322.177) 176.33,322.177 176.33,321.915 ccw(c176.417,321.915) 176.417,321.828 177.018,321.828 cw(c177.018,321.74) 177.106,321.74 177.106,321.478 cw(c177.018,321.478) 177.018,321.391 176.417,321.391 ccw(c176.417,321.304) 176.33,321.304 176.33,321.041 ccw(c176.417,321.041) 176.417,320.954 177.018,320.954 cw(c177.018,320.867) 177.106,320.867 177.106,320.605 cw(c177.018,320.605) 177.018,320.517 176.417,320.517 ccw(c176.417,320.43) 176.33,320.43 176.33,320.168 ccw(c176.417,320.168) 176.417,320.081 177.018,320.081 cw(c177.018,319.993) 177.106,319.993 177.106,319.731 cw(c177.018,319.731) 177.018,319.644 176.417,319.644 ccw(c176.417,319.556) 176.33,319.556 176.33,319.294 ccw(c176.417,319.294) 176.417,319.207 177.018,319.207 cw(c177.018,319.12) 177.106,319.12 177.106,318.857 cw(c177.018,318.857) 177.018,318.77 176.894,318.77 ccw(c176.894,318.683) 176.807,318.683 176.807,318.539 176.807,318.208 176.809,318.205 176.809,315.583 177.662,314.731 177.662,312.978 178.488,312.151 178.488,311.863 178.72,311.631 179.048,311.631 179.124,311.706 179.695,311.706 179.812,311.589 180.325,311.589 180.862,311.052 v1(180.909,311.052)
DDR4_DM5: U1.R24 U9.E4 | length 31.7
  L1 w0.116: U9.E4@167.676,331.26 v1(168.079,330.857) ; U1.R24@176.397,311.539 v1(176.884,312.027)
  L12 (Sign) w0.081: v1(168.079,330.857) 167.118,329.895 167.118,323.904 167.781,323.241 168.875,322.147 cw(c168.787,322.059) 168.875,321.971 168.742,321.839 ccw(c168.83,321.751) 168.742,321.662 168.919,321.486 ccw(c169.007,321.574) 169.095,321.486 169.315,321.707 cw(c169.395,321.627) 169.475,321.707 169.668,321.514 cw(c169.588,321.434) 169.668,321.354 169.447,321.134 ccw(c169.536,321.045) 169.447,320.957 169.624,320.781 ccw(c169.712,320.869) 169.8,320.781 170.021,321.002 cw(c170.101,320.922) 170.181,321.002 170.373,320.809 cw(c170.293,320.729) 170.373,320.649 170.152,320.428 ccw(c170.241,320.34) 170.152,320.252 170.329,320.076 ccw(c170.417,320.164) 170.505,320.076 170.726,320.296 cw(c170.806,320.216) 170.886,320.296 171.078,320.104 cw(c170.998,320.024) 171.078,319.944 170.858,319.723 ccw(c170.946,319.635) 170.858,319.547 171.034,319.371 ccw(c171.122,319.459) 171.21,319.371 171.431,319.591 cw(c171.511,319.511) 171.591,319.591 171.783,319.399 cw(c171.703,319.319) 171.783,319.239 171.563,319.018 ccw(c171.651,318.93) 171.563,318.842 171.739,318.666 ccw(c171.827,318.754) 171.915,318.666 172.048,318.798 cw(c172.136,318.71) 172.224,318.798 172.312,318.71 172.312,316.282 172.885,315.709 172.885,314.617 173.825,313.677 173.825,311.669 174.076,311.418 174.076,311.406 174.264,311.218 174.276,311.218 174.293,311.201 174.701,311.201 174.892,311.391 175.689,311.391 175.72,311.423 176.048,311.423 176.08,311.391 176.545,311.391 176.884,311.73 v1(176.884,312.027)
DDR4_DM6: U1.V28 U11.E2 | length 28.2
  L1 w0.116: v2(178.91,316.027) U1.V28@179.397,315.539 ; U11.E2@183.136,331.26 183.533,330.864 v2(183.533,330.862)
  L3 (Sign) w0.081: v2(178.91,316.027) 178.91,316.425 179.324,316.84 179.324,317.462 179.08,317.706 178.751,317.706 178.563,317.894 178.563,318.416 182.062,321.915 182.21,322.063 182.394,322.246 cw(c182.455,322.185) 182.516,322.246 182.642,322.12 ccw(c182.704,322.181) 182.765,322.12 182.887,322.242 ccw(c182.826,322.304) 182.887,322.365 182.761,322.491 cw(c182.822,322.552) 182.761,322.613 182.945,322.797 183.189,323.042 183.312,323.164 184.273,323.164 184.507,323.398 184.507,323.571 184.507,323.831 cw(c184.593,323.831) 184.593,323.917 184.692,323.917 ccw(c184.692,324.004) 184.779,324.004 184.779,324.177 ccw(c184.692,324.177) 184.692,324.263 184.507,324.263 184.039,324.263 cw(c184.039,324.35) 183.952,324.35 183.952,324.523 cw(c184.039,324.523) 184.039,324.61 184.507,324.61 184.692,324.61 ccw(c184.692,324.696) 184.779,324.696 184.779,324.869 ccw(c184.692,324.869) 184.692,324.956 184.507,324.956 184.039,324.956 cw(c184.039,325.042) 183.952,325.042 183.952,325.215 cw(c184.039,325.215) 184.039,325.302 184.507,325.302 184.692,325.302 ccw(c184.692,325.389) 184.779,325.389 184.779,325.562 ccw(c184.692,325.562) 184.692,325.648 184.507,325.648 184.039,325.648 cw(c184.039,325.735) 183.952,325.735 183.952,325.908 cw(c184.039,325.908) 184.039,325.994 184.507,325.994 184.692,325.994 ccw(c184.692,326.081) 184.779,326.081 184.779,326.254 ccw(c184.692,326.254) 184.692,326.341 184.507,326.341 184.039,326.341 cw(c184.039,326.427) 183.952,326.427 183.952,326.6 cw(c184.039,326.6) 184.039,326.687 184.507,326.687 184.692,326.687 ccw(c184.692,326.773) 184.779,326.773 184.779,326.946 ccw(c184.692,326.946) 184.692,327.033 184.593,327.033 cw(c184.593,327.12) 184.507,327.12 184.507,327.379 184.507,327.381 184.507,327.411 183.909,328.009 183.909,329.603 ccw(c183.777,329.603) 183.777,329.735 183.642,329.735 cw(c183.642,329.862) 183.515,329.862 183.515,329.991 cw(c183.623,329.991) 183.623,330.098 183.972,330.098 ccw(c183.972,330.247) 184.121,330.247 184.121,330.276 ccw(c183.962,330.276) 183.962,330.436 183.693,330.436 cw(c183.693,330.596) 183.533,330.596 v2(183.533,330.862)
DDR4_DM7: U1.P28 U11.E4 | length 21.5
  L1 w0.116: v2(174.91,316.027) U1.P28@175.397,315.539 ; v2(178.74,331.659) 178.74,331.657 U11.E4@179.136,331.26
  L3 (Sign) w0.081: v2(174.91,316.027) 174.249,316.027 174.001,316.274 174.001,317.963 176.682,320.645 176.682,321.549 176.682,321.59 ccw(c176.573,321.59) 176.573,321.699 176.4,321.699 cw(c176.4,321.808) 176.29,321.808 176.29,322.026 cw(c176.4,322.026) 176.4,322.136 177.25,322.136 ccw(c177.25,322.245) 177.359,322.245 177.359,322.463 ccw(c177.25,322.463) 177.25,322.572 176.792,322.572 cw(c176.792,322.682) 176.682,322.682 176.682,323.658 176.682,325.153 177.662,326.133 177.662,327.004 177.927,327.269 177.927,329.115 178.192,329.38 178.192,329.857 178.384,330.05 178.384,331.304 v2(178.74,331.659)
DDR4_DM8: U1.AA27
DDR4_DQ0: U1.AH22 U8.G2 | length 47.2
  L1 w0.116: U1.AH22@189.397,309.539 v1(189.884,309.052) ; U8.G2@206.057,332.86 206.489,333.292 207.009,333.292 207.559,333.842 v1(207.638,333.842)
  L12 (Sign) w0.081: v1(189.884,309.052) 189.128,308.296 189.128,308.056 188.5,307.427 188.5,306.761 188.265,306.526 188.265,305.671 188.539,305.397 189.635,305.397 189.947,305.709 192.339,305.709 192.397,305.768 209.396,322.767 209.396,332.421 208.083,333.734 207.746,333.734 v1(207.638,333.842)
DDR4_DQ1: U1.AH21 U8.F4 | length 47.3
  L1 w0.116: U1.AH21@189.397,308.539 v1(189.884,308.052) ; v1(201.653,332.464) U8.F4@202.057,332.06
  L12 (Sign) w0.081: v1(189.884,308.052) 190.468,308.635 192.034,308.635 192.397,308.998 199.232,315.834 199.261,315.862 ccw(c199.202,315.921) 199.261,315.981 199.248,315.993 cw(c199.308,316.052) 199.248,316.112 199.367,316.23 cw(c199.426,316.171) 199.485,316.23 199.498,316.218 ccw(c199.557,316.277) 199.616,316.218 199.827,316.428 207.166,323.767 207.166,323.791 207.166,323.832 ccw(c207.065,323.832) 207.065,323.932 206.958,323.932 cw(c206.958,324.033) 206.857,324.033 206.857,324.167 cw(c206.958,324.167) 206.958,324.267 207.07,324.267 ccw(c207.07,324.368) 207.171,324.368 207.171,324.502 ccw(c207.07,324.502) 207.07,324.603 206.441,324.603 cw(c206.441,324.703) 206.341,324.703 206.341,324.837 cw(c206.441,324.837) 206.441,324.938 207.07,324.938 ccw(c207.07,325.038) 207.171,325.038 207.171,325.172 ccw(c207.07,325.172) 207.07,325.273 206.441,325.273 cw(c206.441,325.374) 206.341,325.374 206.341,325.508 cw(c206.441,325.508) 206.441,325.608 207.07,325.608 ccw(c207.07,325.709) 207.171,325.709 207.171,325.843 ccw(c207.07,325.843) 207.07,325.943 206.441,325.943 cw(c206.441,326.044) 206.341,326.044 206.341,326.178 cw(c206.441,326.178) 206.441,326.279 207.065,326.279 ccw(c207.065,326.379) 207.166,326.379 207.166,326.755 207.166,327.076 207.166,327.116 ccw(c207.065,327.116) 207.065,327.217 206.441,327.217 cw(c206.441,327.318) 206.341,327.318 206.341,327.452 cw(c206.441,327.452) 206.441,327.552 207.076,327.552 ccw(c207.076,327.653) 207.177,327.653 207.177,327.787 ccw(c207.076,327.787) 207.076,327.887 206.568,327.887 cw(c206.568,327.988) 206.468,327.988 206.468,328.122 cw(c206.568,328.122) 206.568,328.223 207.065,328.223 ccw(c207.065,328.323) 207.166,328.323 207.166,328.548 207.166,328.765 207.044,328.887 207.044,330.478 206.527,330.994 206.028,330.994 205.008,332.014 204.659,332.014 203.019,333.654 202.129,333.654 201.653,333.179 v1(201.653,332.464)
DDR4_DQ2: U1.AJ22 U8.H3 | length 46
  L1 w0.116: U1.AJ22@190.397,309.539 v1(190.884,309.052) ; v1(204.853,334.064) U8.H3@205.257,333.66
  L12 (Sign) w0.081: v1(190.884,309.052) 190.812,308.979 190.479,308.979 189.985,308.486 189.766,308.486 189.451,308.171 189.451,306.958 189.122,306.629 188.84,306.629 188.506,306.294 188.506,305.829 188.709,305.626 189.535,305.626 190.511,306.602 191.174,306.602 191.901,307.329 192.21,307.329 192.397,307.516 208.362,323.481 208.362,331.236 207.942,331.656 207.932,331.656 207.682,331.656 207.092,331.656 206.549,332.198 206.266,332.198 205.312,333.152 205.312,333.606 v1(204.853,334.064)
DDR4_DQ3: U1.AK22 U8.H4 | length 46.1
  L1 w0.116: U1.AK22@191.397,309.539 v1(191.884,309.052) ; U8.H4@202.06,333.66 U8.H4@202.057,333.66 v1(202.461,333.257)
  L12 (Sign) w0.081: v1(191.884,309.052) 192.625,309.793 192.682,309.849 ccw(c192.597,309.933) 192.682,310.018 192.409,310.29 cw(c192.493,310.374) 192.409,310.458 192.521,310.57 cw(c192.606,310.486) 192.69,310.57 193.046,310.214 193.117,310.143 ccw(c193.201,310.227) 193.286,310.143 193.398,310.255 ccw(c193.314,310.339) 193.398,310.424 193.327,310.495 192.97,310.851 cw(c193.055,310.935) 192.97,311.019 193.083,311.132 cw(c193.167,311.047) 193.251,311.132 193.607,310.775 193.678,310.704 ccw(c193.763,310.788) 193.847,310.704 193.959,310.816 ccw(c193.875,310.9) 193.959,310.985 193.888,311.056 193.532,311.412 cw(c193.616,311.496) 193.532,311.581 193.644,311.693 cw(c193.728,311.609) 193.812,311.693 194.169,311.336 194.24,311.265 ccw(c194.324,311.349) 194.408,311.265 194.52,311.377 ccw(c194.436,311.462) 194.52,311.546 194.449,311.617 194.093,311.973 cw(c194.177,312.057) 194.093,312.142 194.205,312.254 cw(c194.289,312.17) 194.373,312.254 194.73,311.897 194.801,311.826 ccw(c194.885,311.911) 194.969,311.826 195.081,311.939 ccw(c194.997,312.023) 195.081,312.107 195.01,312.178 194.654,312.534 cw(c194.738,312.619) 194.654,312.703 194.766,312.815 cw(c194.85,312.731) 194.934,312.815 195.291,312.459 195.362,312.388 ccw(c195.446,312.472) 195.53,312.388 195.643,312.5 ccw(c195.558,312.584) 195.643,312.668 195.572,312.739 195.215,313.096 cw(c195.299,313.18) 195.215,313.264 195.327,313.376 cw(c195.411,313.292) 195.496,313.376 195.852,313.02 195.923,312.949 ccw(c196.007,313.033) 196.091,312.949 196.204,313.061 ccw(c196.12,313.145) 196.204,313.229 196.133,313.3 195.776,313.657 cw(c195.86,313.741) 195.776,313.825 195.888,313.937 cw(c195.973,313.853) 196.057,313.937 196.413,313.581 196.484,313.51 ccw(c196.568,313.594) 196.653,313.51 196.765,313.622 ccw(c196.681,313.706) 196.765,313.79 196.694,313.861 196.337,314.218 cw(c196.422,314.302) 196.337,314.386 196.45,314.499 cw(c196.534,314.414) 196.618,314.499 196.974,314.142 197.045,314.071 ccw(c197.13,314.155) 197.214,314.071 197.326,314.183 ccw(c197.242,314.267) 197.326,314.352 cw(c197.397,314.423) 197.326,314.494 197.33,314.497 206.029,323.196 206.029,328.039 206.863,328.874 206.863,330.387 206.562,330.688 206.078,330.688 204.944,331.822 204.579,331.822 203.145,333.257 v1(202.461,333.257)
DDR4_DQ4: U1.AK20 U8.H2 | length 45.8
  L1 w0.116: U1.AK20@191.397,307.539 191.693,307.243 v1(192.76,307.243) ; v1(205.702,333.314) 205.71,333.314 U8.H2@206.057,333.66
  L12 (Sign) w0.081: v1@192.653,307.136 192.776,307.258 193.02,307.503 193.204,307.687 ccw(c193.143,307.748) 193.204,307.809 193.141,307.872 cw(c193.202,307.933) 193.141,307.994 193.263,308.117 cw(c193.324,308.056) 193.386,308.117 193.449,308.054 ccw(c193.51,308.115) 193.571,308.054 193.694,308.176 ccw(c193.632,308.237) 193.694,308.299 193.63,308.362 cw(c193.692,308.423) 193.63,308.484 193.753,308.606 cw(c193.814,308.545) 193.875,308.606 193.938,308.543 ccw(c194,308.605) 194.061,308.543 194.183,308.666 ccw(c194.122,308.727) 194.183,308.788 194.12,308.851 cw(c194.181,308.912) 194.12,308.974 194.242,309.096 cw(c194.304,309.035) 194.365,309.096 194.428,309.033 ccw(c194.489,309.094) 194.55,309.033 194.673,309.155 ccw(c194.612,309.217) 194.673,309.278 194.61,309.341 cw(c194.671,309.402) 194.61,309.463 194.732,309.586 cw(c194.793,309.524) 194.854,309.586 194.918,309.523 ccw(c194.979,309.584) 195.04,309.523 195.162,309.645 ccw(c195.101,309.706) 195.162,309.767 195.099,309.83 cw(c195.16,309.892) 195.099,309.953 195.222,310.075 cw(c195.283,310.014) 195.344,310.075 195.407,310.012 ccw(c195.468,310.073) 195.53,310.012 195.652,310.135 ccw(c195.591,310.196) 195.652,310.257 195.589,310.32 cw(c195.65,310.381) 195.589,310.442 195.711,310.565 cw(c195.772,310.504) 195.834,310.565 195.897,310.502 ccw(c195.958,310.563) 196.019,310.502 196.142,310.624 ccw(c196.08,310.685) 196.142,310.747 196.078,310.81 cw(c196.14,310.871) 196.078,310.932 196.201,311.054 cw(c196.262,310.993) 196.323,311.054 196.386,310.991 ccw(c196.448,311.053) 196.509,310.991 196.631,311.114 ccw(c196.57,311.175) 196.631,311.236 196.568,311.299 cw(c196.629,311.36) 196.568,311.422 196.69,311.544 cw(c196.752,311.483) 196.813,311.544 196.876,311.481 ccw(c196.937,311.542) 196.998,311.481 197.121,311.603 ccw(c197.06,311.665) 197.121,311.726 197.058,311.789 cw(c197.119,311.85) 197.058,311.911 197.18,312.034 cw(c197.241,311.972) 197.302,312.034 197.366,311.971 ccw(c197.427,312.032) 197.488,311.971 197.61,312.093 ccw(c197.549,312.154) 197.61,312.215 197.547,312.278 cw(c197.608,312.34) 197.547,312.401 197.67,312.523 cw(c197.731,312.462) 197.792,312.523 197.855,312.46 ccw(c197.916,312.521) 197.978,312.46 198.1,312.583 ccw(c198.039,312.644) 198.1,312.705 198.037,312.768 cw(c198.098,312.829) 198.037,312.89 198.159,313.013 cw(c198.22,312.952) 198.282,313.013 198.345,312.95 ccw(c198.406,313.011) 198.467,312.95 198.59,313.072 ccw(c198.528,313.133) 198.59,313.195 198.526,313.258 cw(c198.588,313.319) 198.526,313.38 198.649,313.502 cw(c198.71,313.441) 198.771,313.502 198.834,313.439 ccw(c198.896,313.501) 198.957,313.439 199.079,313.562 ccw(c199.018,313.623) 199.079,313.684 199.016,313.747 cw(c199.077,313.808) 199.016,313.87 199.138,313.992 cw(c199.2,313.931) 199.261,313.992 199.324,313.929 ccw(c199.385,313.99) 199.446,313.929 199.569,314.051 ccw(c199.508,314.113) 199.569,314.174 199.506,314.237 cw(c199.567,314.298) 199.506,314.359 199.628,314.482 cw(c199.689,314.42) 199.75,314.482 199.814,314.419 ccw(c199.875,314.48) 199.936,314.419 200.058,314.541 ccw(c199.997,314.602) 200.058,314.663 199.995,314.726 cw(c200.056,314.788) 199.995,314.849 200.118,314.971 cw(c200.179,314.91) 200.24,314.971 200.303,314.908 ccw(c200.364,314.969) 200.426,314.908 200.548,315.031 ccw(c200.487,315.092) 200.548,315.153 200.485,315.216 cw(c200.546,315.277) 200.485,315.338 200.607,315.461 cw(c200.668,315.4) 200.73,315.461 200.793,315.398 ccw(c200.854,315.459) 200.915,315.398 201.038,315.52 ccw(c200.976,315.581) 201.038,315.643 200.974,315.706 cw(c201.036,315.767) 200.974,315.828 201.097,315.95 cw(c201.158,315.889) 201.219,315.95 201.282,315.887 ccw(c201.344,315.949) 201.405,315.887 201.527,316.01 ccw(c201.466,316.071) 201.527,316.132 201.464,316.195 cw(c201.525,316.256) 201.464,316.318 201.586,316.44 cw(c201.648,316.379) 201.709,316.44 201.772,316.377 ccw(c201.833,316.438) 201.894,316.377 202.017,316.499 ccw(c201.956,316.561) 202.017,316.622 201.954,316.685 cw(c202.015,316.746) 201.954,316.807 202.076,316.93 cw(c202.137,316.868) 202.198,316.93 202.262,316.867 ccw(c202.323,316.928) 202.384,316.867 202.506,316.989 ccw(c202.445,317.05) 202.506,317.111 202.443,317.174 cw(c202.504,317.236) 202.443,317.297 202.566,317.419 cw(c202.627,317.358) 202.688,317.419 202.751,317.356 ccw(c202.812,317.417) 202.874,317.356 202.996,317.479 ccw(c202.935,317.54) 202.996,317.601 202.933,317.664 cw(c202.994,317.725) 202.933,317.786 203.055,317.909 cw(c203.116,317.848) 203.178,317.909 203.241,317.846 ccw(c203.302,317.907) 203.363,317.846 203.486,317.968 ccw(c203.424,318.029) 203.486,318.091 203.422,318.154 cw(c203.484,318.215) 203.422,318.276 203.545,318.398 cw(c203.606,318.337) 203.667,318.398 203.73,318.335 ccw(c203.792,318.397) 203.853,318.335 203.975,318.458 ccw(c203.914,318.519) 203.975,318.58 203.912,318.643 cw(c203.973,318.704) 203.912,318.766 204.034,318.888 cw(c204.096,318.827) 204.157,318.888 204.22,318.825 ccw(c204.281,318.886) 204.342,318.825 204.465,318.947 ccw(c204.404,319.009) 204.465,319.07 204.402,319.133 cw(c204.463,319.194) 204.402,319.255 204.524,319.378 cw(c204.585,319.316) 204.646,319.378 204.71,319.315 ccw(c204.771,319.376) 204.832,319.315 206.263,320.746 208.715,323.198 208.715,331.594 207.985,332.324 207.961,332.348 207.932,332.356 207.682,332.425 207.589,332.451 206.878,332.451 206.015,333.314 v1(205.702,333.314)
DDR4_DQ5: U1.AJ19 U8.H5 | length 46.8
  L1 w0.116: U1.AJ19@190.397,306.539 v1(190.8,306.136) ; v1(200.853,334.064) U8.H5@201.257,333.66
  L12 (Sign) w0.081: v1(190.8,306.136) 191.125,306.136 191.618,306.629 192.698,306.629 193.151,307.081 193.151,307.362 197.66,311.872 197.926,312.137 cw(c197.985,312.078) 198.045,312.137 198.066,312.115 ccw(c198.126,312.175) 198.185,312.115 198.303,312.234 ccw(c198.244,312.293) 198.303,312.352 198.278,312.378 cw(c198.337,312.437) 198.278,312.497 198.396,312.615 cw(c198.455,312.556) 198.515,312.615 198.54,312.589 ccw(c198.6,312.649) 198.659,312.589 198.777,312.708 ccw(c198.718,312.767) 198.777,312.826 198.752,312.852 cw(c198.811,312.911) 198.752,312.971 198.87,313.089 cw(c198.929,313.03) 198.989,313.089 199.014,313.063 ccw(c199.074,313.123) 199.133,313.063 199.251,313.182 ccw(c199.192,313.241) 199.251,313.3 199.226,313.326 cw(c199.285,313.385) 199.226,313.445 199.344,313.563 cw(c199.404,313.504) 199.463,313.563 199.475,313.551 ccw(c199.535,313.61) 199.594,313.551 199.712,313.669 ccw(c199.653,313.728) 199.712,313.788 199.7,313.8 cw(c199.759,313.859) 199.7,313.919 199.818,314.037 cw(c199.878,313.978) 199.937,314.037 199.941,314.033 ccw(c200,314.093) 200.059,314.033 200.178,314.152 ccw(c200.118,314.211) 200.178,314.27 cw(c200.237,314.33) 200.178,314.389 201.419,315.63 208.907,323.118 208.907,332 208.812,332.095 ccw(c208.748,332.031) 208.685,332.095 208.665,332.075 cw(c208.602,332.138) 208.539,332.075 208.349,332.265 cw(c208.412,332.328) 208.349,332.391 208.432,332.474 208.48,332.523 ccw(c208.417,332.586) 208.48,332.65 208.29,332.84 ccw(c208.227,332.776) 208.164,332.84 208.178,332.854 cw(c208.115,332.918) 208.052,332.854 207.956,332.95 207.898,333.009 207.898,333.05 207.677,333.27 207.354,333.27 207.191,333.107 207.191,333.097 207.01,332.916 206.872,332.916 206.084,333.704 205.828,333.704 205.078,334.454 204.304,334.454 204.138,334.289 203.815,334.289 203.656,334.447 201.764,334.447 201.739,334.423 201.212,334.423 v1(200.853,334.064)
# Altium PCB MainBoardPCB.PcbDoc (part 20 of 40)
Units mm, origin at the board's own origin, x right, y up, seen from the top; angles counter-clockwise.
Board outline 258.95 x 308.86 mm, 16 copper layers (L1, L2 (GND), L3 (Sign), L4 (GND), L5 (Sign), L6 (PWR/GND), L7(12V+Other), L8 (Plane_GND), L9 (PWR/GND), L10 (3V3+Other), L11 (PWR/GND), L12 (Sign), L13 (GND), L14 (Sign), L15 (GND), L16), stack 2.503 mm thick; 2578 components, 1867 nets, 8817 pads, 8021 vias.
Unrouted connection lines stored in the file: 25.

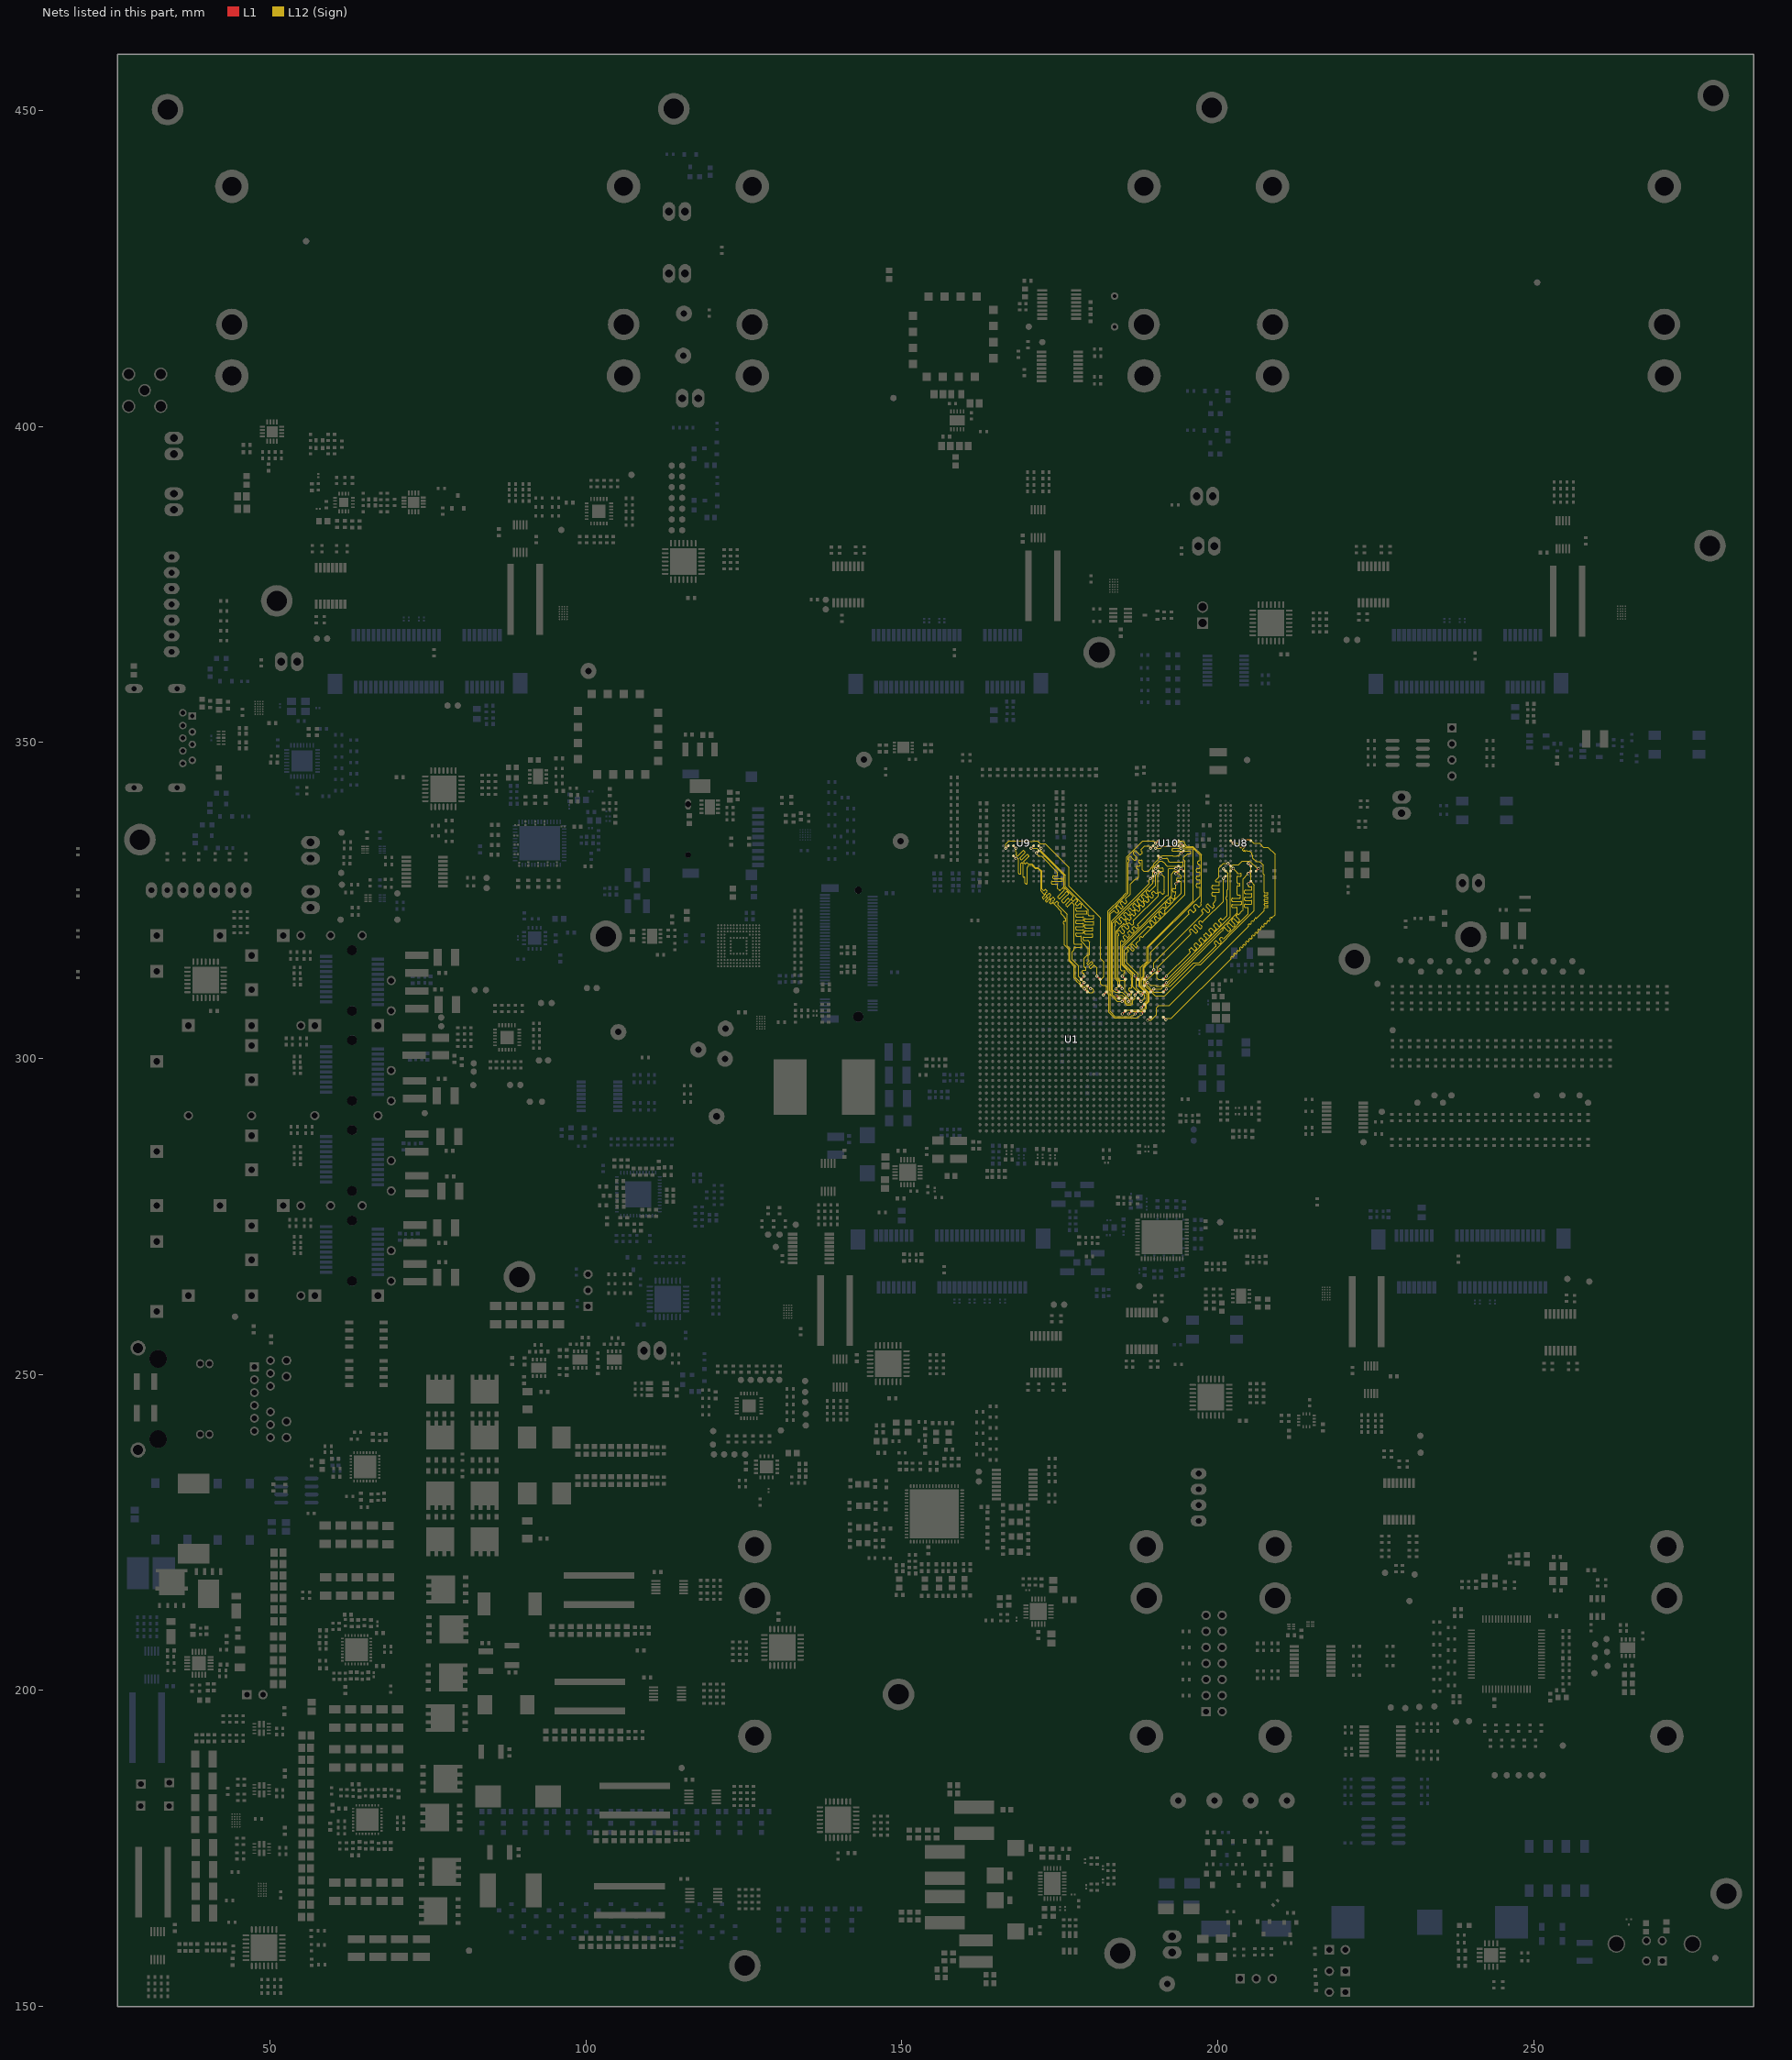
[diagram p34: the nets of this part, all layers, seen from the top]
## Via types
v1: diameter 0.5, hole 0.25, L1 to L16, tented both sides, 4341 vias
v2: diameter 0.254, hole 0.1, L1 to L3 (Sign), tented both sides, 781 vias
v3: diameter 0.5, hole 0.25, L1 to L16, 565 vias
v4: diameter 0.254, hole 0.1, L15 (GND) to L16, tented both sides, 406 vias
v5: diameter 0.254, hole 0.1, L1 to L2 (GND), tented both sides, 283 vias
v6: diameter 0.457, hole 0.2, L3 (Sign) to L6 (PWR/GND), tented both sides, 254 vias
v7: diameter 0.254, hole 0.1, L1 to L3 (Sign), 237 vias
v8: diameter 0.75, hole 0.4, L1 to L16, 200 vias
v9: diameter 0.8, hole 0.4, L1 to L16, tented both sides, 182 vias
v10: diameter 0.254, hole 0.1, L14 (Sign) to L16, tented both sides, 170 vias
v11: diameter 0.75/0/0/0/0/0/0/0/0/0/0/0/0/0/0/0.75 (per signal layer), hole 0.4, L1 to L16, 160 vias
v12: diameter 0.457, hole 0.2, L3 (Sign) to L6 (PWR/GND), 158 vias
v13: diameter 1.4, hole 0.5, L1 to L16, tented both sides, 80 vias
v14: diameter 0.254, hole 0.1, L14 (Sign) to L16, 65 vias
v15: diameter 0.254, hole 0.1, L1 to L2 (GND), 45 vias
v16: diameter 0.457, hole 0.2, L11 (PWR/GND) to L14 (Sign), tented both sides, 26 vias
v17: diameter 0.457, hole 0.2, L11 (PWR/GND) to L14 (Sign), 25 vias
v18: diameter 0.457, hole 0.2, L7(12V+Other) to L10 (3V3+Other), tented both sides, 11 vias
v19: diameter 0.254/0/0.254 (per signal layer), hole 0.1, L1 to L3 (Sign), 9 vias
v20: diameter 0.2/0/0.2 (per signal layer), hole 0.1, L1 to L3 (Sign), 6 vias
v21: diameter 1.65, hole 1.65, L1 to L16, 5 vias
v22: diameter 1.15, hole 1.15, L1 to L16, 5 vias
v23: diameter 0.457, hole 0.2, L1 to L16, 3 vias
v24: diameter 0.5, hole 0.3, L1 to L16, 2 vias
v25: diameter 0.5/0/0.5 (per signal layer), hole 0.2, L14 (Sign) to L16, 1 vias
v26: diameter 0.5, hole 0.25, L1 to L16, tented bottom, 1 vias

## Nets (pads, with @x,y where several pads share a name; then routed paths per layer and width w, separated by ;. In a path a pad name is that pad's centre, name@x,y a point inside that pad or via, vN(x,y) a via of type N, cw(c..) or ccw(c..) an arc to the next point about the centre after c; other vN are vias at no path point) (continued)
DDR4_DQ6: U1.AK19 U8.J3 | length 46
  L1 w0.116: U1.AK19@191.397,306.539 v1(191.8,306.136) ; v1(203.977,334.679) 205.038,334.679 U8.J3@205.257,334.46
  L12 (Sign) w0.081: v1(191.8,306.136) 192.001,306.337 192.662,306.337 202.071,315.746 202.1,315.774 ccw(c202.04,315.834) 202.1,315.893 202.078,315.915 cw(c202.137,315.974) 202.078,316.033 202.196,316.152 cw(c202.256,316.092) 202.315,316.152 202.361,316.106 ccw(c202.42,316.165) 202.479,316.106 202.598,316.224 ccw(c202.538,316.284) 202.598,316.343 202.552,316.389 cw(c202.611,316.448) 202.552,316.507 202.67,316.626 cw(c202.73,316.566) 202.789,316.626 202.835,316.58 ccw(c202.894,316.639) 202.953,316.58 203.072,316.698 ccw(c203.013,316.758) 203.072,316.817 203.026,316.863 cw(c203.085,316.922) 203.026,316.981 203.144,317.1 cw(c203.204,317.04) 203.263,317.1 203.309,317.054 ccw(c203.368,317.113) 203.427,317.054 203.546,317.172 ccw(c203.487,317.232) 203.546,317.291 203.5,317.337 cw(c203.559,317.396) 203.5,317.455 203.619,317.574 cw(c203.678,317.515) 203.737,317.574 203.783,317.528 ccw(c203.842,317.587) 203.901,317.528 204.02,317.647 ccw(c203.961,317.706) 204.02,317.765 203.974,317.811 cw(c204.033,317.87) 203.974,317.929 204.093,318.048 cw(c204.152,317.989) 204.211,318.048 204.257,318.002 ccw(c204.316,318.061) 204.375,318.002 204.494,318.121 ccw(c204.435,318.18) 204.494,318.239 204.448,318.285 cw(c204.507,318.344) 204.448,318.403 204.567,318.522 cw(c204.626,318.463) 204.685,318.522 204.731,318.476 ccw(c204.79,318.535) 204.849,318.476 204.968,318.595 ccw(c204.909,318.654) 204.968,318.713 204.922,318.759 cw(c204.981,318.818) 204.922,318.877 205.041,318.996 cw(c205.1,318.937) 205.159,318.996 205.205,318.95 ccw(c205.264,319.009) 205.323,318.95 205.442,319.069 ccw(c205.383,319.128) 205.442,319.187 205.396,319.233 cw(c205.455,319.292) 205.396,319.351 205.515,319.47 cw(c205.574,319.411) 205.633,319.47 205.679,319.424 ccw(c205.738,319.483) 205.798,319.424 205.916,319.543 ccw(c205.857,319.602) 205.916,319.661 205.87,319.707 cw(c205.93,319.766) 205.87,319.825 205.989,319.944 cw(c206.048,319.885) 206.107,319.944 206.153,319.898 ccw(c206.212,319.957) 206.272,319.898 206.39,320.017 ccw(c206.331,320.076) 206.39,320.135 206.344,320.181 cw(c206.404,320.24) 206.344,320.3 206.463,320.418 cw(c206.522,320.359) 206.581,320.418 206.627,320.372 ccw(c206.686,320.432) 206.746,320.372 206.864,320.491 ccw(c206.805,320.55) 206.864,320.609 206.818,320.655 cw(c206.878,320.714) 206.818,320.774 206.937,320.892 cw(c206.996,320.833) 207.055,320.892 207.101,320.846 ccw(c207.16,320.906) 207.22,320.846 207.338,320.965 ccw(c207.279,321.024) 207.338,321.083 207.302,321.119 cw(c207.362,321.178) 207.302,321.238 207.421,321.356 cw(c207.48,321.297) 207.54,321.356 207.575,321.32 ccw(c207.634,321.38) 207.694,321.32 207.812,321.439 ccw(c207.753,321.498) 207.812,321.557 cw(c207.871,321.617) 207.812,321.676 207.931,321.794 cw(c207.99,321.735) 208.049,321.794 ccw(c208.108,321.854) 208.168,321.794 208.286,321.913 ccw(c208.227,321.972) 208.286,322.031 208.262,322.055 cw(c208.322,322.115) 208.262,322.174 208.381,322.292 cw(c208.44,322.233) 208.499,322.292 ccw(c208.559,322.352) 208.618,322.292 209.099,322.773 209.099,332.336 207.984,333.451 207.261,333.451 206.647,334.065 205.723,334.065 205.109,334.679 v1(203.977,334.679)
DDR4_DQ7: U1.AH19 U8.J4 | length 47.8
  L1 w0.116: v1(188.909,306.052) U1.AH19@189.397,306.539 ; U8.J4@202.06,334.46 U8.J4@202.057,334.46 v1(202.461,334.057)
  L12 (Sign) w0.081: v1(188.909,306.052) 189.436,306.052 190.332,306.948 190.335,306.948 190.335,308.067 190.69,308.423 192.372,308.423 204.83,320.881 204.859,320.909 ccw(c204.8,320.969) 204.859,321.028 204.83,321.057 cw(c204.889,321.116) 204.83,321.175 204.948,321.294 cw(c205.008,321.235) 205.067,321.294 205.096,321.265 ccw(c205.155,321.324) 205.214,321.265 205.333,321.383 ccw(c205.274,321.443) 205.333,321.502 205.326,321.509 cw(c205.385,321.568) 205.326,321.627 205.444,321.746 cw(c205.504,321.687) 205.563,321.746 205.571,321.738 ccw(c205.63,321.797) 205.689,321.738 205.808,321.857 ccw(c205.749,321.916) 205.808,321.975 ; v1(202.461,334.057) 203.078,334.057 203.222,333.913 203.452,333.683 cw(c203.41,333.642) 203.452,333.6 203.493,333.642 ccw(c203.554,333.581) 203.493,333.519 203.616,333.397 ccw(c203.677,333.458) 203.738,333.397 204.057,333.716 cw(c204.118,333.655) 204.18,333.716 204.302,333.594 cw(c204.241,333.533) 204.302,333.471 203.983,333.152 203.941,333.111 ccw(c204.002,333.049) 203.941,332.988 204.064,332.866 ccw(c204.125,332.927) 204.186,332.866 cw(c204.228,332.824) 204.269,332.866 204.35,332.785 ; 204.228,332.907 204.65,332.907 204.689,332.868 205.009,332.868 205.039,332.838 205.377,332.5 205.377,332.234 205.579,332.031 205.579,331.699 206.103,331.175 206.602,331.175 206.836,330.941 206.852,330.941 207.225,330.568 207.225,329.218 207.358,329.086 207.358,326.748 207.358,326.331 ccw(c207.458,326.331) 207.458,326.231 207.864,326.231 cw(c207.864,326.13) 207.965,326.13 207.965,325.996 cw(c207.864,325.996) 207.864,325.896 207.453,325.896 ccw(c207.453,325.795) 207.352,325.795 207.352,325.661 ccw(c207.453,325.661) 207.453,325.56 207.864,325.56 cw(c207.864,325.46) 207.965,325.46 207.965,325.326 cw(c207.864,325.326) 207.864,325.225 207.453,325.225 ccw(c207.453,325.125) 207.352,325.125 207.352,324.991 ccw(c207.453,324.991) 207.453,324.89 207.864,324.89 cw(c207.864,324.789) 207.965,324.789 207.965,324.655 cw(c207.864,324.655) 207.864,324.555 207.453,324.555 ccw(c207.453,324.454) 207.352,324.454 207.352,324.32 ccw(c207.453,324.32) 207.453,324.22 207.864,324.22 cw(c207.864,324.119) 207.965,324.119 207.965,323.985 cw(c207.864,323.985) 207.864,323.884 207.458,323.884 ccw(c207.458,323.784) 207.358,323.784 207.358,323.408 206.162,322.213 cw(c206.103,322.272) 206.044,322.213 ccw(c205.985,322.154) 205.925,322.213 205.807,322.095 ccw(c205.866,322.035) 205.807,321.976 ; 205.807,321.976 205.808,321.975
DDR4_DQ8: U1.AH23 U8.A3 | length 34
  L1 w0.116: U1.AH23@189.397,310.539 v1(189.884,311.027) ; v1(204.853,327.657) U8.A3@205.257,328.06
  L12 (Sign) w0.081: v1(189.884,311.027) 191.02,311.027 191.449,311.455 192.471,311.455 196.166,315.15 197.098,315.15 199.696,317.748 199.724,317.777 ccw(c199.621,317.88) 199.724,317.984 199.495,318.213 cw(c199.599,318.316) 199.495,318.42 199.633,318.557 cw(c199.736,318.454) 199.84,318.557 200.177,318.22 ccw(c200.281,318.323) 200.384,318.22 200.522,318.358 ccw(c200.419,318.461) 200.522,318.564 200.326,318.76 cw(c200.43,318.863) 200.326,318.967 200.464,319.105 cw(c200.568,319.001) 200.671,319.105 200.758,319.018 ccw(c200.862,319.121) 200.965,319.018 201.246,319.299 204.853,322.906 204.853,323.497 204.853,323.784 ccw(c204.744,323.784) 204.744,323.894 204.388,323.894 cw(c204.388,324.004) 204.278,324.004 204.278,324.334 cw(c204.388,324.334) 204.388,324.444 204.853,324.444 205.319,324.444 ccw(c205.319,324.554) 205.429,324.554 205.429,324.883 ccw(c205.319,324.883) 205.319,324.993 204.853,324.993 204.388,324.993 cw(c204.388,325.103) 204.278,325.103 204.278,325.433 cw(c204.388,325.433) 204.388,325.543 204.853,325.543 205.319,325.543 ccw(c205.319,325.652) 205.429,325.652 205.429,325.982 ccw(c205.319,325.982) 205.319,326.092 204.853,326.092 204.388,326.092 cw(c204.388,326.202) 204.278,326.202 204.278,326.531 cw(c204.388,326.531) 204.388,326.641 204.853,326.641 205.319,326.641 ccw(c205.319,326.751) 205.429,326.751 205.429,327.081 ccw(c205.319,327.081) 205.319,327.191 204.963,327.191 cw(c204.963,327.301) 204.853,327.301 204.853,327.465 v1(204.853,327.657)
DDR4_DQ9: U1.AK23 U8.B5 | length 31.6
  L1 w0.116: U1.AK23@191.397,310.539 v1(191.884,311.027) ; v1(200.903,328.515) 200.911,328.515 U8.B5@201.257,328.86
  L12 (Sign) w0.081: v1(191.884,311.027) 191.334,310.477 189.882,310.477 189.42,310.939 189.42,310.966 188.509,311.877 188.509,312.201 188.75,312.441 188.826,312.441 189.29,312.906 189.29,312.925 190.01,313.645 190.247,313.645 190.494,313.892 190.494,314.452 195.731,319.69 195.731,319.709 ccw(c195.628,319.812) 195.731,319.915 195.574,320.073 cw(c195.677,320.176) 195.574,320.279 195.712,320.417 cw(c195.815,320.314) 195.919,320.417 196.44,319.896 ccw(c196.543,319.999) 196.647,319.896 196.785,320.034 ccw(c196.681,320.137) 196.785,320.241 196.263,320.762 cw(c196.367,320.865) 196.263,320.969 196.401,321.107 cw(c196.505,321.003) 196.608,321.107 197.129,320.585 ccw(c197.233,320.689) 197.336,320.585 197.474,320.723 ccw(c197.37,320.827) 197.474,320.93 197.017,321.387 cw(c197.12,321.49) 197.017,321.594 197.155,321.732 cw(c197.258,321.628) 197.362,321.732 197.454,321.639 ccw(c197.558,321.742) 197.661,321.639 197.889,321.866 200.903,324.881 v1(200.903,328.515)
DDR4_DQ10: U1.AG24 U8.C3 | length 33.1
  L1 w0.116: U1.AG24@188.4,311.539 v1(188.9,312.039) ; v1(204.853,329.257) U8.C3@205.257,329.66
  L12 (Sign) w0.081: v1(188.9,312.039) 189.367,311.572 190.179,311.572 190.334,311.417 191.146,311.417 191.276,311.546 191.283,311.546 191.374,311.636 192.121,311.636 200.633,320.148 200.809,320.324 cw(c200.902,320.417) 200.809,320.51 200.975,320.676 cw(c201.068,320.583) 201.161,320.676 201.659,320.179 ccw(c201.764,320.285) 201.87,320.179 202.011,320.32 ccw(c201.905,320.425) 202.011,320.531 201.514,321.029 cw(c201.607,321.122) 201.514,321.215 201.68,321.381 cw(c201.773,321.288) 201.866,321.381 202.364,320.884 ccw(c202.469,320.989) 202.575,320.884 202.716,321.025 ccw(c202.61,321.13) 202.716,321.236 202.219,321.734 cw(c202.312,321.827) 202.219,321.92 202.385,322.086 cw(c202.478,321.993) 202.571,322.086 203.068,321.588 ccw(c203.174,321.694) 203.28,321.588 203.421,321.729 ccw(c203.315,321.835) 203.421,321.941 202.923,322.438 cw(c203.016,322.531) 202.923,322.624 203.09,322.791 cw(c203.183,322.698) 203.276,322.791 203.907,323.422 204,323.515 204,328.404 v1(204.853,329.257)
DDR4_DQ11: U1.AK24 U8.C4 | length 31.5
  L1 w0.116: U1.AK24@191.397,311.539 v1(191.884,312.027) ; U8.C4@202.057,329.66 v1(202.461,330.064)
  L12 (Sign) w0.081: v1(191.884,312.027) 192.07,312.027 203.086,323.043 203.086,323.716 203.086,323.757 ccw(c202.939,323.757) 202.939,323.903 202.361,323.903 cw(c202.361,324.049) 202.215,324.049 202.215,324.244 cw(c202.361,324.244) 202.361,324.39 203.673,324.39 ccw(c203.673,324.536) 203.819,324.536 203.819,324.731 ccw(c203.673,324.731) 203.673,324.878 202.361,324.878 cw(c202.361,325.024) 202.215,325.024 202.215,325.219 cw(c202.361,325.219) 202.361,325.365 203.434,325.365 ccw(c203.434,325.511) 203.58,325.511 203.58,325.706 ccw(c203.434,325.706) 203.434,325.852 203.232,325.852 cw(c203.232,325.999) 203.086,325.999 203.086,326.2 203.086,327.035 203.086,327.236 cw(c203.182,327.236) 203.182,327.333 203.429,327.333 ccw(c203.429,327.429) 203.525,327.429 203.525,327.622 ccw(c203.429,327.622) 203.429,327.719 203.182,327.719 cw(c203.182,327.815) 203.086,327.815 203.086,327.856 203.086,328.535 203.086,328.783 cw(c203.182,328.783) 203.182,328.88 203.621,328.88 ccw(c203.621,328.976) 203.718,328.976 203.718,329.169 ccw(c203.621,329.169) 203.621,329.266 203.182,329.266 cw(c203.182,329.362) 203.086,329.362 203.086,329.403 203.086,329.439 v1(202.461,330.064) 202.451,330.073 v1@202.423,330.073
DDR4_DQ12: U1.AJ26 U8.C2 | length 31.8
  L1 w0.116: U1.AJ26@190.397,313.539 v1(190.884,314.027) ; U8.C2@206.057,329.66 v1(206.461,330.064)
  L12 (Sign) w0.081: v1(190.884,314.027) 190.375,313.517 190.375,312.732 190.593,312.514 192.097,312.514 202.026,322.443 202.026,330.224 202.281,330.479 202.281,330.532 202.437,330.688 203.294,330.688 203.867,331.26 205.081,331.26 206.277,330.064 v1(206.461,330.064)
DDR4_DQ13: U1.AK25 U8.C5 | length 31.2
  L1 w0.116: U1.AK25@191.397,312.539 v1(191.884,313.027) ; v1(200.903,330.014) U8.C5@201.257,329.66
  L12 (Sign) w0.081: v1(191.884,313.027) 195.527,316.67 195.644,316.787 ccw(c195.566,316.864) 195.644,316.942 195.501,317.085 cw(c195.578,317.163) 195.501,317.241 195.734,317.474 cw(c195.811,317.396) 195.889,317.474 196.11,317.253 196.267,317.096 ccw(c196.345,317.173) 196.423,317.096 196.656,317.329 ccw(c196.578,317.406) 196.656,317.484 196.499,317.641 196.277,317.862 cw(c196.355,317.94) 196.277,318.018 196.511,318.251 cw(c196.588,318.173) 196.666,318.251 196.887,318.03 197.044,317.873 ccw(c197.122,317.95) 197.2,317.873 197.433,318.106 ccw(c197.355,318.183) 197.433,318.261 197.276,318.418 197.054,318.639 cw(c197.132,318.717) 197.054,318.795 197.288,319.028 cw(c197.365,318.95) 197.443,319.028 197.664,318.807 197.821,318.65 ccw(c197.899,318.727) 197.977,318.65 198.21,318.883 ccw(c198.132,318.96) 198.21,319.038 198.053,319.195 197.831,319.416 cw(c197.909,319.494) 197.831,319.572 198.064,319.805 cw(c198.142,319.727) 198.22,319.805 198.441,319.584 198.598,319.427 ccw(c198.676,319.504) 198.754,319.427 198.987,319.66 ccw(c198.909,319.737) 198.987,319.815 198.83,319.972 198.608,320.193 cw(c198.686,320.271) 198.608,320.349 198.841,320.582 cw(c198.919,320.504) 198.997,320.582 199.218,320.361 199.375,320.203 ccw(c199.453,320.281) 199.531,320.203 199.764,320.437 ccw(c199.686,320.514) 199.764,320.592 199.607,320.749 199.385,320.97 cw(c199.463,321.048) 199.385,321.126 199.618,321.359 cw(c199.696,321.281) 199.774,321.359 199.995,321.138 200.152,320.98 ccw(c200.23,321.058) 200.308,320.98 200.541,321.214 ccw(c200.463,321.291) 200.541,321.369 200.384,321.526 200.166,321.743 cw(c200.244,321.821) 200.166,321.899 200.399,322.132 cw(c200.477,322.054) 200.555,322.132 200.694,321.992 ccw(c200.772,322.07) 200.85,321.992 201.136,322.278 201.46,322.603 201.46,324.875 201.46,325.124 cw(c201.46,325.225) 201.359,325.225 201.359,325.521 cw(c201.46,325.521) 201.46,325.623 201.46,326.511 201.46,326.643 201.641,326.824 201.641,329.276 v1(200.903,330.014)
DDR4_DQ14: U1.AG25 U8.D3 | length 34.6
  L1 w0.116: U1.AG25@188.403,312.539 188.9,313.036 v1(188.9,313.068) ; v1(204.853,330.864) U8.D3@205.257,330.46
  L12 (Sign) w0.081: v1(188.9,313.068) 188.366,312.534 188.366,312.313 188.328,312.276 188.328,311.767 189.607,310.488 189.607,310.436 190.134,309.91 191.605,309.91 196.554,314.858 197.279,314.858 205.811,323.391 205.811,327.506 205.245,328.072 205.245,330.472 v1(204.853,330.864)
DDR4_DQ15: U1.AH26 U8.D4 | length 31.2
  L1 w0.116: U1.AH26@189.397,313.539 v1(189.884,314.027) ; v1(201.649,330.86) 201.657,330.86 U8.D4@202.057,330.46
  L12 (Sign) w0.081: v1(189.884,314.027) 189.884,315.174 197.575,322.865 197.646,322.935 ccw(c197.54,323.041) 197.646,323.147 197.493,323.299 cw(c197.599,323.405) 197.493,323.511 197.634,323.652 cw(c197.74,323.546) 197.846,323.652 198.104,323.393 198.362,323.135 ccw(c198.468,323.241) 198.574,323.135 198.715,323.276 ccw(c198.609,323.382) 198.715,323.487 198.456,323.746 198.198,324.004 cw(c198.304,324.11) 198.198,324.216 198.339,324.356 cw(c198.445,324.251) 198.551,324.356 198.809,324.098 199.067,323.84 ccw(c199.173,323.946) 199.279,323.84 199.42,323.981 ccw(c199.314,324.087) 199.42,324.192 199.267,324.345 cw(c199.373,324.451) 199.267,324.556 199.37,324.66 199.704,324.993 199.704,325.166 199.704,325.199 199.704,325.638 ccw(c199.594,325.638) 199.594,325.748 199.22,325.748 cw(c199.22,325.858) 199.11,325.858 199.11,326.188 cw(c199.22,326.188) 199.22,326.298 199.704,326.298 200.187,326.298 ccw(c200.187,326.408) 200.297,326.408 200.297,326.737 ccw(c200.187,326.737) 200.187,326.847 199.704,326.847 199.22,326.847 cw(c199.22,326.957) 199.11,326.957 199.11,327.287 cw(c199.22,327.287) 199.22,327.397 199.704,327.397 200.187,327.397 ccw(c200.187,327.506) 200.297,327.506 200.297,327.836 ccw(c200.187,327.836) 200.187,327.946 199.813,327.946 cw(c199.813,328.056) 199.704,328.056 199.704,328.221 200.207,328.724 200.207,330.157 200.911,330.86 v1(201.649,330.86)
DDR4_DQ16: U1.AD22 U10.G2 | length 41
  L1 w0.116: v1(184.897,309.027) 184.897,309.039 U1.AD22@185.397,309.539 ; v1(194.193,332.457) U10.G2@194.597,332.86
  L12 (Sign) w0.081: v1(184.897,309.027) 184.093,309.027 183.163,309.958 183.163,310.592 183.035,310.719 183.035,322.892 183.105,322.962 183.478,323.335 cw(c183.582,323.232) 183.685,323.335 183.959,323.061 ccw(c184.063,323.164) 184.166,323.061 184.304,323.198 ccw(c184.201,323.302) 184.304,323.405 183.934,323.775 cw(c184.037,323.879) 183.934,323.982 184.072,324.12 cw(c184.175,324.017) 184.279,324.12 184.649,323.75 ccw(c184.752,323.853) 184.855,323.75 184.993,323.888 ccw(c184.89,323.991) 184.993,324.095 184.623,324.465 cw(c184.727,324.568) 184.623,324.671 184.761,324.809 cw(c184.864,324.706) 184.968,324.809 185.232,324.546 ccw(c185.335,324.649) 185.438,324.546 185.576,324.683 ccw(c185.473,324.787) 185.576,324.89 185.408,325.058 cw(c185.512,325.162) 185.408,325.265 186.169,326.026 186.169,326.058 186.169,327.624 186.993,328.447 187.173,328.447 ccw(c187.173,328.743) 187.469,328.743 187.469,329.833 ccw(c187.319,329.833) 187.319,329.982 187.308,329.982 cw(c187.308,330.132) 187.158,330.132 187.158,330.331 cw(c187.308,330.331) 187.308,330.481 187.469,330.481 187.629,330.481 ccw(c187.629,330.63) 187.779,330.63 187.779,330.83 ccw(c187.629,330.83) 187.629,330.979 187.618,330.979 cw(c187.618,331.129) 187.469,331.129 187.469,331.229 cw(c187.621,331.229) 187.621,331.381 187.897,331.381 cw(c187.897,331.179) 188.098,331.179 188.098,329.843 188.267,329.673 189.001,329.673 189.897,330.569 189.897,330.826 190.597,331.525 190.597,331.813 190.836,332.053 190.958,332.053 190.966,332.061 191.165,332.061 191.24,332.136 192.85,332.136 192.92,332.066 193.552,332.066 193.621,332.136 193.872,332.136 v1(194.193,332.457)
DDR4_DQ17: U1.AE22 U10.F4 | length 36.9
  L1 w0.116: v1(185.909,309.052) U1.AE22@186.397,309.539 ; U10.F4@190.597,332.06 v1(191,331.657)
  L12 (Sign) w0.081: v1(185.909,309.052) 186.095,309.238 184.856,310.477 183.789,310.477 183.397,310.869 183.397,321.424 189.714,327.741 189.714,328.145 189.784,328.214 189.784,328.665 189.714,328.735 189.714,330.13 190.031,330.447 190.036,330.447 190.805,331.216 190.836,331.247 191.162,331.247 191.339,331.071 191.395,331.071 192.024,330.441 192.762,330.441 192.775,330.454 194.355,330.454 194.368,330.441 194.404,330.441 ccw(c194.404,330.581) 194.543,330.581 194.543,330.955 ccw(c194.409,330.955) 194.409,331.089 192.497,331.089 cw(c192.497,331.457) 192.129,331.457 ccw(c191.929,331.457) 191.929,331.657 v1(191,331.657)
DDR4_DQ18: U1.AF22 U10.H3 | length 39.4
  L1 w0.116: U1.AF22@187.397,309.539 v1(187.884,309.052) ; U10.H3@193.797,333.66 v1(194.2,333.257)
  L12 (Sign) w0.081: v1(187.884,309.052) 187.906,309.052 188.428,309.573 188.428,309.987 188.3,310.115 188.3,310.214 187.835,310.678 187.666,310.678 187.165,311.179 187.165,312.714 187.415,312.964 187.415,313.325 185.622,315.118 185.622,316.741 185.827,316.947 185.856,316.975 ccw(c185.788,317.043) 185.856,317.112 185.726,317.242 cw(c185.794,317.31) 185.726,317.378 185.862,317.515 cw(c185.931,317.446) 185.999,317.515 186.467,317.047 ccw(c186.535,317.115) 186.603,317.047 186.74,317.183 ccw(c186.671,317.251) 186.74,317.32 186.272,317.788 cw(c186.34,317.856) 186.272,317.924 186.408,318.061 cw(c186.476,317.992) 186.545,318.061 187.013,317.593 ccw(c187.081,317.661) 187.149,317.593 187.285,317.729 ccw(c187.217,317.797) 187.285,317.866 187.084,318.067 cw(c187.152,318.135) 187.084,318.203 187.335,318.454 187.679,318.798 187.707,318.827 ccw(c187.639,318.895) 187.707,318.963 187.664,319.007 cw(c187.732,319.075) 187.664,319.143 187.8,319.28 cw(c187.869,319.211) 187.937,319.28 187.98,319.236 ccw(c188.049,319.304) 188.117,319.236 188.449,319.569 194.831,325.95 194.831,329.997 194.831,331.219 194.591,331.459 194.591,331.808 194.892,332.108 194.947,332.108 195.229,332.39 195.598,332.39 ccw(c195.598,332.524) 195.732,332.524 195.732,332.699 ccw(c195.616,332.699) 195.616,332.816 194.386,332.816 194.355,332.847 193.163,332.847 193.132,332.816 192.918,332.816 cw(c192.918,332.947) 192.788,332.947 192.788,333.081 cw(c192.955,333.081) 192.955,333.248 194.2,333.248 v1(194.2,333.257)
DDR4_DQ19: U1.AG21 U10.H4 | length 37.1
  L1 w0.116: v1(187.909,308.052) U1.AG21@188.397,308.539 ; v1(190.193,333.257) U10.H4@190.597,333.66
  L12 (Sign) w0.081: v1(187.909,308.052) 188.402,308.544 188.402,308.761 188.812,309.171 188.812,310.214 187.549,311.477 187.549,312.398 187.823,312.672 187.823,314.402 188.785,315.365 188.785,317.598 196.098,324.911 196.098,333.027 195.906,333.219 194.685,333.219 194.591,333.313 194.591,333.419 194.362,333.647 193.624,333.647 193.549,333.572 191.261,333.572 190.945,333.257 v1(190.193,333.257)
DDR4_DQ20: U1.AD20 U10.H2 | length 41
  L1 w0.116: v1(184.909,307.052) U1.AD20@185.397,307.539 ; v1(194.193,334.064) U10.H2@194.597,333.66
  L12 (Sign) w0.081: v1(184.909,307.052) 185.513,307.656 188.098,307.656 188.583,308.141 188.583,308.686 189.004,309.107 189.004,310.278 187.741,311.541 187.741,312.334 188.004,312.597 188.004,312.853 188.205,313.054 188.205,314.513 189.04,315.348 189.04,317.58 197.208,325.749 197.208,325.831 197.208,326.937 ccw(c197.058,326.937) 197.058,327.087 196.765,327.087 cw(c196.765,327.237) 196.614,327.237 196.614,327.537 cw(c196.765,327.537) 196.765,327.687 197.058,327.687 ccw(c197.058,327.837) 197.208,327.837 197.208,328.137 ccw(c197.058,328.137) 197.058,328.287 196.765,328.287 cw(c196.765,328.437) 196.614,328.437 196.614,328.737 cw(c196.765,328.737) 196.765,328.887 197.058,328.887 ccw(c197.058,329.038) 197.208,329.038 197.208,329.338 ccw(c197.058,329.338) 197.058,329.488 196.765,329.488 cw(c196.765,329.638) 196.614,329.638 196.614,329.938 cw(c196.765,329.938) 196.765,330.088 197.058,330.088 ccw(c197.058,330.238) 197.208,330.238 197.208,330.538 ccw(c197.058,330.538) 197.058,330.688 197.033,330.688 cw(c197.033,330.838) 196.883,330.838 196.883,331.138 cw(c197.033,331.138) 197.033,331.288 197.058,331.288 ccw(c197.058,331.438) 197.208,331.438 197.208,331.888 197.208,332.189 195.997,333.4 194.866,333.4 v1@194.201,334.064
DDR4_DQ21: U1.AF20 U10.H5 | length 39.1
  L1 w0.116: v1(186.909,307.052) U1.AF20@187.397,307.539 ; v1(189.393,333.257) U10.H5@189.797,333.66
  L12 (Sign) w0.081: v1(186.909,307.052) 186.656,306.799 186.385,306.799 186.24,306.654 183.747,306.654 182.982,307.42 182.982,310.144 182.821,310.305 182.821,323.125 185.852,326.156 185.852,331.058 185.958,331.164 ccw(c185.852,331.27) 185.958,331.376 185.819,331.514 cw(c185.926,331.62) 185.819,331.726 186.032,331.939 cw(c186.138,331.833) 186.244,331.939 186.488,331.694 186.758,331.424 ccw(c186.865,331.53) 186.971,331.424 187.183,331.636 ccw(c187.077,331.742) 187.183,331.849 186.913,332.119 186.643,332.389 cw(c186.749,332.495) 186.643,332.601 186.855,332.813 cw(c186.961,332.707) 187.067,332.813 187.337,332.543 187.607,332.273 ccw(c187.713,332.379) 187.819,332.273 188.032,332.485 ccw(c187.926,332.591) 188.032,332.697 187.868,332.861 cw(c187.974,332.967) 187.868,333.073 188.058,333.264 188.455,333.66 189.195,333.66 189.393,333.462 v1(189.393,333.257)
DDR4_DQ22: U1.AE20 U10.J3 | length 41
  L1 w0.116: v1(185.909,307.052) U1.AE20@186.397,307.539 ; v1(193.393,334.057) U10.J3@193.797,334.46
  L12 (Sign) w0.081: v1(185.909,307.052) 186.332,307.475 188.284,307.475 188.764,307.955 188.764,308.611 189.196,309.043 189.196,310.342 187.933,311.604 187.933,312.27 188.185,312.522 188.185,312.762 188.386,312.964 188.386,314.423 189.397,315.434 189.397,316.791 193.735,321.129 195.406,322.799 ccw(c195.299,322.905) 195.406,323.011 195.362,323.055 cw(c195.468,323.161) 195.362,323.267 195.574,323.479 cw(c195.68,323.373) 195.787,323.479 195.936,323.33 196.086,323.18 ccw(c196.192,323.286) 196.298,323.18 196.51,323.392 ccw(c196.404,323.499) 196.51,323.605 196.36,323.754 196.211,323.904 cw(c196.317,324.01) 196.211,324.116 196.423,324.328 ; v1(193.393,334.057) 193.733,334.057 193.803,334.126 193.803,334.226 194.031,334.454 194.468,334.454 194.723,334.2 194.723,333.98 195.123,333.581 196.087,333.581 197.421,332.246 197.421,324.815 197.315,324.709 ccw(c197.422,324.603) 197.315,324.497 197.359,324.453 cw(c197.253,324.347) 197.359,324.241 197.147,324.029 cw(c197.041,324.135) 196.934,324.029 196.785,324.179 196.635,324.328 ; 196.423,324.328 cw(c196.529,324.222) 196.635,324.328
DDR4_DQ23: U1.AG20 U10.J4 | length 38.7
  L1 w0.116: v1(187.909,307.052) U1.AG20@188.397,307.539 ; v1(190.193,334.057) U10.J4@190.597,334.46
  L12 (Sign) w0.081: v1(187.909,307.052) 187.308,306.451 183.642,306.451 183.23,306.863 183.23,306.899 182.79,307.34 182.79,310.077 182.629,310.238 182.629,318.539 182.629,323.307 184.721,325.399 185.484,326.162 185.59,326.267 185.59,331.501 185.587,331.503 185.587,331.717 185.59,331.72 185.59,331.906 188.144,334.46 189.789,334.46 v1(190.193,334.057)
DDR4_DQ24: U1.AG23 U10.A3 | length 25.9
  L1 w0.116: v1(187.909,310.052) U1.AG23@188.397,310.539 ; v1(193.393,327.657) U10.A3@193.797,328.06
  L12 (Sign) w0.081: v1(187.909,310.052) 186.578,311.384 186.578,312.887 186.553,312.912 186.553,313.373 185.046,314.88 185.046,317.652 191.062,323.669 191.288,323.894 cw(c191.368,323.814) 191.448,323.894 ccw(c191.589,324.035) 191.73,323.894 191.8,323.964 ccw(c191.659,324.105) 191.8,324.246 191.72,324.326 cw(c191.824,324.431) 191.72,324.535 191.864,324.679 cw(c191.969,324.575) 192.073,324.679 192.153,324.599 ccw(c192.294,324.74) 192.435,324.599 192.505,324.67 ccw(c192.364,324.811) 192.505,324.952 192.425,325.032 cw(c192.53,325.136) 192.425,325.24 192.569,325.384 cw(c192.674,325.28) 192.778,325.384 192.858,325.304 ccw(c192.999,325.445) 193.14,325.304 193.21,325.375 ccw(c193.069,325.516) 193.21,325.657 cw(c193.29,325.737) 193.21,325.817 193.307,325.913 193.393,325.999 193.393,326.263 193.393,326.311 ccw(c193.293,326.311) 193.293,326.41 192.988,326.41 cw(c192.988,326.51) 192.888,326.51 192.888,326.809 cw(c192.988,326.809) 192.988,326.909 193.293,326.909 ccw(c193.293,327.009) 193.393,327.009 193.393,327.408 v1(193.393,327.657)
DDR4_DQ25: U1.AF23 U10.B5 | length 28.1
  L1 w0.116: v1(186.909,310.052) U1.AF23@187.397,310.539 ; v1(189.393,328.457) U10.B5@189.797,328.86
  L12 (Sign) w0.081: v1(186.909,310.052) 186.909,309.481 186.846,309.417 186.748,309.417 186.519,309.189 186.519,308.704 186.257,308.442 185.624,308.442 185.287,308.779 185.287,309.189 184.936,309.539 183.837,309.539 183.344,310.033 183.344,310.667 183.216,310.794 183.216,321.735 188.747,327.266 188.755,327.266 189.187,327.698 189.187,328.251 v1(189.393,328.457)
DDR4_DQ26: U1.AF25 U10.C3 | length 27.5
  L1 w0.116: v1(186.943,313.074) 186.943,312.993 U1.AF25@187.397,312.539 ; v1(193.393,329.257) U10.C3@193.797,329.66
  L12 (Sign) w0.081: v1(186.943,313.074) 186.943,313.254 185.238,314.959 185.238,317.146 188.243,320.151 188.905,320.814 cw(c189.031,320.688) 189.156,320.814 ccw(c189.297,320.955) 189.438,320.814 189.509,320.884 ccw(c189.368,321.025) 189.509,321.166 189.383,321.292 189.303,321.372 cw(c189.444,321.513) 189.303,321.654 189.374,321.724 cw(c189.515,321.583) 189.656,321.724 189.736,321.644 189.861,321.519 ccw(c190.002,321.66) 190.143,321.519 190.214,321.589 ccw(c190.073,321.73) 190.214,321.871 190.088,321.997 190.008,322.077 cw(c190.149,322.218) 190.008,322.359 190.079,322.429 cw(c190.22,322.288) 190.361,322.429 190.441,322.349 190.567,322.224 ccw(c190.708,322.365) 190.849,322.224 190.919,322.294 ccw(c190.778,322.435) 190.919,322.576 190.794,322.702 190.714,322.782 cw(c190.855,322.923) 190.714,323.064 190.784,323.134 cw(c190.925,322.993) 191.066,323.134 191.146,323.054 191.272,322.929 ccw(c191.413,323.07) 191.554,322.929 191.624,322.999 ccw(c191.483,323.14) 191.624,323.281 cw(c191.75,323.407) 191.624,323.533 191.675,323.583 194.246,326.155 194.246,327.8 194.246,327.949 ccw(c194.147,327.949) 194.147,328.049 193.59,328.049 cw(c193.59,328.149) 193.49,328.149 193.49,328.448 cw(c193.59,328.448) 193.59,328.548 194.147,328.548 ccw(c194.147,328.647) 194.246,328.647 194.246,328.879 193.84,329.286 193.422,329.286 v1(193.393,329.257)
DDR4_DQ27: U1.AE23 U10.C4 | length 29.5
  L1 w0.116: v1(185.909,310.052) U1.AE23@186.397,310.539 ; U10.C4@190.597,329.66 v1(191,329.257)
  L12 (Sign) w0.081: v1(185.909,310.052) 185.331,310.63 185.331,312.165 185.073,312.423 184.532,312.423 184.204,312.75 184.204,319.358 184.239,319.392 184.309,319.463 ccw(c184.204,319.569) 184.309,319.674 184.136,319.847 cw(c184.242,319.953) 184.136,320.059 184.277,320.2 cw(c184.383,320.094) 184.489,320.2 184.768,319.921 184.875,319.813 ccw(c184.981,319.919) 185.087,319.813 185.228,319.954 ccw(c185.122,320.06) 185.228,320.166 185.12,320.274 184.827,320.567 cw(c184.933,320.673) 184.827,320.779 184.968,320.92 cw(c185.074,320.814) 185.18,320.92 185.473,320.626 185.581,320.519 ccw(c185.686,320.624) 185.792,320.519 185.933,320.66 ccw(c185.827,320.765) 185.933,320.871 185.825,320.979 185.73,321.074 cw(c185.836,321.18) 185.73,321.286 185.871,321.427 cw(c185.977,321.321) 186.082,321.427 186.178,321.331 186.319,321.19 ccw(c186.425,321.296) 186.531,321.19 186.672,321.331 ccw(c186.566,321.437) 186.672,321.543 186.636,321.578 cw(c186.742,321.684) 186.636,321.79 186.938,322.091 190.525,325.679 190.604,325.757 ccw(c190.509,325.851) 190.604,325.946 cw(c190.71,326.052) 190.604,326.157 190.745,326.298 cw(c190.851,326.193) 190.956,326.298 191.051,326.204 191.194,326.061 ccw(c191.3,326.166) 191.406,326.061 191.547,326.202 ccw(c191.441,326.307) 191.547,326.413 191.509,326.451 cw(c191.615,326.557) 191.509,326.662 191.579,326.733 191.579,328.677 v1(191,329.257)
DDR4_DQ28: U1.AC22 U10.C2 | length 31.5
  L1 w0.116: v1(183.909,310.027) U1.AC22@184.397,309.539 ; v1(194.193,330.064) U10.C2@194.597,329.66
  L12 (Sign) w0.081: v1(183.909,310.027) 184.909,310.027 185.481,309.455 185.481,308.84 185.66,308.661 186.221,308.661 186.338,308.779 186.338,310.188 186.386,310.236 186.386,310.578 ccw(c186.286,310.578) 186.286,310.678 186.094,310.678 cw(c186.094,310.778) 185.995,310.778 185.995,311.077 cw(c186.094,311.077) 186.094,311.177 186.286,311.177 ccw(c186.286,311.277) 186.386,311.277 186.386,311.675 186.386,311.925 186.386,312.823 186.372,312.837 186.372,313.282 184.854,314.8 184.854,317.924 192.708,325.778 192.708,329.237 193.16,329.69 193.183,329.666 193.555,329.666 193.578,329.69 193.819,329.69 v1(194.193,330.064)
DDR4_DQ29: U1.AC23 U10.C5 | length 31.3
  L1 w0.116: v1(183.909,311.027) U1.AC23@184.397,310.539 ; U10.C5@189.797,329.66 v1(190.2,329.257)
  L12 (Sign) w0.081: v1(183.909,311.027) 184.266,311.383 184.266,312.156 183.72,312.702 183.72,320.943 183.79,321.014 ccw(c183.684,321.119) 183.79,321.225 183.746,321.269 cw(c183.852,321.375) 183.746,321.481 183.887,321.622 cw(c183.993,321.516) 184.099,321.622 184.249,321.472 184.398,321.322 ccw(c184.504,321.428) 184.61,321.322 184.751,321.463 ccw(c184.645,321.569) 184.751,321.675 184.601,321.825 184.451,321.974 cw(c184.557,322.08) 184.451,322.186 184.592,322.327 cw(c184.698,322.221) 184.804,322.327 184.954,322.177 185.103,322.028 ccw(c185.209,322.133) 185.315,322.028 185.456,322.169 ccw(c185.35,322.274) 185.456,322.38 185.306,322.53 185.157,322.679 cw(c185.262,322.785) 185.157,322.891 185.298,323.032 cw(c185.403,322.926) 185.509,323.032 185.659,322.882 185.808,322.733 ccw(c185.914,322.838) 186.02,322.733 186.161,322.874 ccw(c186.055,322.979) 186.161,323.085 186.011,323.235 185.862,323.385 cw(c185.967,323.49) 185.862,323.596 186.003,323.737 cw(c186.108,323.631) 186.214,323.737 186.364,323.587 186.514,323.438 ccw(c186.619,323.544) 186.725,323.438 186.866,323.579 ccw(c186.76,323.685) 186.866,323.79 186.716,323.94 186.567,324.09 cw(c186.673,324.195) 186.567,324.301 186.708,324.442 cw(c186.814,324.336) 186.919,324.442 187.069,324.293 187.219,324.143 ccw(c187.324,324.249) 187.43,324.143 187.571,324.284 ccw(c187.465,324.39) 187.571,324.495 187.422,324.645 187.272,324.795 cw(c187.378,324.901) 187.272,325.006 187.413,325.147 cw(c187.519,325.042) 187.625,325.147 187.774,324.998 187.924,324.848 ccw(c188.03,324.954) 188.135,324.848 188.276,324.989 ccw(c188.171,325.095) 188.276,325.201 188.127,325.35 187.977,325.5 cw(c188.083,325.606) 187.977,325.711 188.118,325.852 cw(c188.224,325.747) 188.33,325.852 188.479,325.703 188.629,325.553 ccw(c188.735,325.659) 188.84,325.553 188.982,325.694 ccw(c188.876,325.8) 188.982,325.906 188.832,326.055 188.682,326.205 cw(c188.788,326.311) 188.682,326.417 188.823,326.558 cw(c188.929,326.452) 189.035,326.558 189.079,326.514 ccw(c189.184,326.619) 189.29,326.514 190.2,327.424 190.2,327.469 v1(190.2,329.257)
DDR4_DQ30: U1.AD25 U10.D3 | length 27.2
  L1 w0.116: v1(184.909,313.027) U1.AD25@185.397,312.539 ; v1(193.393,330.057) U10.D3@193.797,330.46
  L12 (Sign) w0.081: v1(184.909,313.027) 184.998,313.027 ccw(c184.998,313.195) 185.166,313.195 185.166,313.521 cw(c185.255,313.521) 185.255,313.61 ccw(c185.255,313.711) 185.356,313.711 185.356,313.826 ccw(c185.272,313.826) 185.272,313.911 184.831,313.911 cw(c184.831,314.084) 184.658,314.084 184.658,318.524 184.683,318.549 184.725,318.591 cw(c184.795,318.52) 184.866,318.591 184.976,318.48 ccw(c185.047,318.551) 185.117,318.48 185.329,318.692 ccw(c185.258,318.762) 185.329,318.833 185.148,319.014 185.044,319.117 cw(c185.114,319.188) 185.044,319.259 185.255,319.47 cw(c185.326,319.4) 185.396,319.47 185.5,319.366 185.681,319.185 ccw(c185.752,319.256) 185.822,319.185 186.034,319.397 ccw(c185.963,319.467) 186.034,319.538 185.853,319.719 185.749,319.823 cw(c185.819,319.893) 185.749,319.964 185.96,320.175 cw(c186.031,320.105) 186.102,320.175 186.205,320.071 186.386,319.89 ccw(c186.457,319.961) 186.527,319.89 186.739,320.102 ccw(c186.668,320.172) 186.739,320.243 186.558,320.424 186.454,320.528 cw(c186.525,320.598) 186.454,320.669 186.666,320.88 cw(c186.736,320.81) 186.807,320.88 186.91,320.776 187.091,320.596 ccw(c187.162,320.666) 187.232,320.596 187.444,320.807 ccw(c187.373,320.878) 187.444,320.948 187.334,321.059 cw(c187.404,321.129) 187.334,321.2 187.439,321.305 191.955,325.821 192.174,325.821 192.176,325.823 192.176,329.946 192.287,330.057 v1(193.393,330.057)
DDR4_DQ31: U1.AC24 U10.D4 | length 30.7
  L1 w0.116: U1.AC24@184.397,311.539 v1(184.884,311.052) ; v1(190.193,330.057) U10.D4@190.597,330.46
  L12 (Sign) w0.081: v1(184.884,311.052) 184.884,311.372 184.519,311.737 184.519,312.175 183.912,312.782 183.912,320.157 184.849,321.094 185.002,321.248 cw(c185.108,321.142) 185.214,321.248 185.22,321.241 ccw(c185.326,321.347) 185.432,321.241 185.573,321.383 ccw(c185.467,321.488) 185.573,321.594 185.461,321.706 cw(c185.566,321.812) 185.461,321.917 185.602,322.059 cw(c185.708,321.953) 185.813,322.059 185.926,321.947 ccw(c186.031,322.052) 186.137,321.947 186.278,322.088 ccw(c186.172,322.193) 186.278,322.299 186.166,322.411 cw(c186.271,322.517) 186.166,322.623 186.307,322.764 cw(c186.413,322.658) 186.518,322.764 186.631,322.652 ccw(c186.736,322.758) 186.842,322.652 186.983,322.793 ccw(c186.877,322.899) 186.983,323.004 186.871,323.117 cw(c186.977,323.222) 186.871,323.328 187.012,323.469 cw(c187.118,323.364) 187.224,323.469 187.336,323.357 ccw(c187.442,323.463) 187.547,323.357 187.688,323.498 ccw(c187.583,323.604) 187.688,323.709 187.576,323.822 cw(c187.682,323.927) 187.576,324.033 187.718,324.174 cw(c187.823,324.069) 187.929,324.174 188.041,324.062 ccw(c188.147,324.168) 188.252,324.062 188.394,324.203 ccw(c188.288,324.309) 188.394,324.415 188.281,324.527 cw(c188.387,324.632) 188.281,324.738 188.423,324.879 cw(c188.528,324.774) 188.634,324.879 188.746,324.767 ccw(c188.852,324.873) 188.958,324.767 189.099,324.908 ccw(c188.993,325.014) 189.099,325.12 188.986,325.232 cw(c189.092,325.338) 188.986,325.443 189.128,325.585 cw(c189.233,325.479) 189.339,325.585 189.451,325.472 ccw(c189.557,325.578) 189.663,325.472 189.804,325.613 ccw(c189.698,325.719) 189.804,325.825 189.691,325.937 189.579,326.049 cw(c189.685,326.155) 189.579,326.261 189.72,326.402 cw(c189.826,326.296) 189.932,326.402 190.044,326.29 190.156,326.177 ccw(c190.262,326.283) 190.368,326.177 190.509,326.318 ccw(c190.403,326.424) 190.509,326.53 190.502,326.536 cw(c190.608,326.642) 190.502,326.748 190.573,326.818 190.573,329.077 190.591,329.095 190.591,329.42 cw(c190.818,329.42) 190.818,329.647 191.332,329.647 ccw(c191.332,329.73) 191.414,329.73 191.414,329.933 ccw(c191.173,329.933) 191.173,330.175 190.311,330.175 ccw(c190.311,330.057) v1(190.193,330.057)
DDR4_DQ32: U1.U24 U9.G2 | length 40.5
  L1 w0.116: v1(171.334,332.526) 171.342,332.526 U9.G2@171.676,332.86 ; U1.U24@178.397,311.539 v1(178.884,312.027)
  L12 (Sign) w0.081: v1(171.334,332.526) 171.334,332.395 171.704,332.025 172.12,332.025 174.69,329.455 174.69,329.237 174.69,329.035 cw(c174.6,329.035) 174.6,328.946 174.033,328.946 ccw(c174.033,328.856) 173.944,328.856 173.944,328.588 ccw(c174.033,328.588) 174.033,328.498 174.69,328.498 175.383,328.498 cw(c175.383,328.408) 175.473,328.408 175.473,328.14 cw(c175.383,328.14) 175.383,328.05 174.69,328.05 173.798,328.05 ccw(c173.798,327.961) 173.708,327.961 173.708,327.692 ccw(c173.798,327.692) 173.798,327.602 174.6,327.602 cw(c174.6,327.513) 174.69,327.513 174.69,327.379 174.69,326.904 174.859,326.736 174.954,326.641 ccw(c175.017,326.704) 175.08,326.641 175.429,326.989 cw(c175.492,326.926) 175.555,326.989 175.745,326.799 cw(c175.682,326.736) 175.745,326.672 175.334,326.261 174.703,325.63 ccw(c174.766,325.566) 174.703,325.503 174.893,325.313 ccw(c174.956,325.376) 175.019,325.313 175.65,325.944 176.062,326.356 cw(c176.125,326.293) 176.189,326.356 176.379,326.166 cw(c176.315,326.103) 176.379,326.039 175.967,325.627 175.336,324.996 ccw(c175.399,324.933) 175.336,324.87 175.526,324.68 ccw(c175.589,324.743) 175.652,324.68 176.283,325.311 176.287,325.314 cw(c176.35,325.251) 176.413,325.314 176.603,325.124 cw(c176.54,325.061) 176.603,324.997 176.6,324.994 175.969,324.363 ccw(c176.032,324.3) 175.969,324.236 176.159,324.046 ccw(c176.222,324.11) 176.286,324.046 176.853,324.614 cw(c176.917,324.551) 176.98,324.614 177.233,324.361 177.283,324.311 177.292,324.302 177.292,318.333 177.292,318.184 ccw(c177.392,318.184) 177.392,318.084 178.39,318.084 cw(c178.39,317.984) 178.489,317.984 178.489,317.685 cw(c178.39,317.685) 178.39,317.585 177.392,317.585 ccw(c177.392,317.486) 177.292,317.486 177.292,317.195 176.99,316.894 176.99,315.658 177.978,314.671 177.978,312.933 v1(178.884,312.027)
DDR4_DQ33: U1.V23 U9.F4 | length 40.2
  L1 w0.116: U9.F4@167.676,332.06 v1(168.079,331.657) ; v1(178.909,311.027) U1.V23@179.397,310.539
  L12 (Sign) w0.081: v1(168.079,331.657) 168.415,331.657 cw(c168.415,331.568) 168.504,331.568 168.504,329.324 ccw(c168.618,329.324) 168.618,329.209 168.732,329.209 ccw(c168.732,329.349) 168.872,329.349 168.872,330.848 cw(c168.974,330.848) 168.974,330.949 169.086,330.949 cw(c169.086,330.848) 169.188,330.848 169.188,328.792 ccw(c169.304,328.792) 169.304,328.676 169.398,328.676 cw(c169.398,328.542) 169.532,328.542 169.532,327.79 ccw(c169.675,327.79) 169.675,327.647 169.783,327.647 ccw(c169.783,327.762) 169.897,327.762 169.897,330.26 cw(c170.197,330.26) 169.974,330.46 cw(c170.197,330.26) 170.197,330.56 170.582,330.56 171.071,330.072 171.505,330.072 172.025,329.552 172.025,326.501 172.322,326.204 172.587,325.938 cw(c172.53,325.881) 172.587,325.824 172.264,325.501 ccw(c172.312,325.453) 172.264,325.406 172.406,325.264 ccw(c172.454,325.311) 172.501,325.264 172.852,325.615 cw(c172.9,325.567) 172.947,325.615 173.089,325.473 cw(c173.042,325.425) 173.089,325.378 172.738,325.027 ccw(c172.786,324.979) 172.738,324.932 172.88,324.79 ccw(c172.928,324.837) 172.975,324.79 173.308,325.123 cw(c173.356,325.075) 173.403,325.123 173.545,324.98 cw(c173.498,324.933) 173.545,324.886 173.396,324.736 ccw(c173.443,324.689) 173.396,324.641 173.538,324.499 ccw(c173.586,324.547) 173.633,324.499 173.773,324.639 cw(c173.83,324.581) 173.887,324.639 174.19,324.335 175.244,323.281 175.244,322.923 175.778,322.389 175.778,322.244 ccw(c175.856,322.244) 175.856,322.166 cw(c175.856,322.054) 175.968,322.054 175.968,321.83 cw(c175.856,321.83) 175.856,321.718 175.778,321.718 175.72,321.718 ccw(c175.72,321.606) 175.608,321.606 175.608,321.382 ccw(c175.72,321.382) 175.72,321.27 ; 175.691,321.27 cw(c175.691,321.183) 175.778,321.183 175.778,317.947 176.447,317.278 176.447,315.422 177.3,314.57 177.3,312.714 177.664,312.35 177.664,312.272 178.104,311.832 178.104,311.704 178.561,311.247 178.581,311.247 178.801,311.027 v1(178.909,311.027)
DDR4_DQ34: U1.U25 U9.H3 | length 40.7
  L1 w0.116: v1(170.472,333.257) U9.H3@170.876,333.66 ; U1.U25@178.397,312.539 v1(178.884,313.027)
  L12 (Sign) w0.081: v1(170.472,333.257) 171.372,333.257 175.654,328.975 175.654,327.147 176.623,326.178 176.823,325.977 177.105,325.695 cw(c177.035,325.625) 177.105,325.554 176.815,325.264 ccw(c176.886,325.194) 176.815,325.123 177.027,324.912 ccw(c177.097,324.982) 177.168,324.912 177.458,325.202 cw(c177.528,325.131) 177.599,325.202 177.81,324.99 cw(c177.74,324.92) 177.81,324.849 177.52,324.559 ccw(c177.591,324.489) 177.52,324.418 177.732,324.207 ccw(c177.802,324.277) 177.873,324.207 178.163,324.497 cw(c178.233,324.426) 178.304,324.497 178.41,324.391 178.41,324.155 178.41,323.966 cw(c178.31,323.966) 178.31,323.867 177.646,323.867 ccw(c177.646,323.767) 177.546,323.767 177.546,323.468 ccw(c177.646,323.468) 177.646,323.368 178.41,323.368 179.173,323.368 cw(c179.173,323.268) 179.273,323.268 179.273,322.969 cw(c179.173,322.969) 179.173,322.869 178.41,322.869 177.646,322.869 ccw(c177.646,322.77) 177.546,322.77 177.546,322.47 ccw(c177.646,322.47) 177.646,322.371 178.41,322.371 178.677,322.371 cw(c178.677,322.271) 178.777,322.271 178.777,321.972 cw(c178.677,321.972) 178.677,321.872 178.41,321.872 177.646,321.872 ccw(c177.646,321.772) 177.546,321.772 177.546,321.473 ccw(c177.646,321.473) 177.646,321.374 178.41,321.374 178.677,321.374 cw(c178.677,321.274) 178.777,321.274 178.777,320.975 cw(c178.677,320.975) 178.677,320.875 178.41,320.875 177.646,320.875 ccw(c177.646,320.775) 177.546,320.775 177.546,320.476 ccw(c177.646,320.476) 177.646,320.376 178.41,320.376 178.677,320.376 cw(c178.677,320.277) 178.777,320.277 178.777,319.977 cw(c178.677,319.977) 178.677,319.878 178.41,319.878 177.646,319.878 ccw(c177.646,319.778) 177.546,319.778 177.546,319.479 ccw(c177.646,319.479) 177.646,319.379 178.31,319.379 cw(c178.31,319.279) 178.41,319.279 178.41,319.13 178.41,318.558 179.553,317.415 179.553,316.533 178.884,315.864 178.884,314.831 178.884,314.509 ccw(c178.996,314.509) 178.996,314.397 179.033,314.397 cw(c179.033,314.285) 179.144,314.285 179.144,314.062 cw(c179.033,314.062) 179.033,313.95 178.884,313.95 178.683,313.95 ccw(c178.683,313.838) 178.571,313.838 178.571,313.614 ccw(c178.683,313.614) 178.683,313.502 178.773,313.502 cw(c178.773,313.39) 178.884,313.39 178.884,313.278 v1(178.884,313.027)
DDR4_DQ35: U1.V24 U9.H4 | length 39.9
  L1 w0.116: U9.H4@167.676,333.66 v1(168.079,333.257) ; U1.V24@179.397,311.539 v1(179.884,311.052)
  L12 (Sign) w0.081: v1(168.079,333.257) 168.079,332.72 168.181,332.618 cw(c168.119,332.556) 168.181,332.495 168.049,332.363 ccw(c168.111,332.301) 168.049,332.239 168.234,332.054 ccw(c168.296,332.116) 168.358,332.054 169.184,332.88 cw(c169.246,332.818) 169.308,332.88 169.493,332.695 cw(c169.431,332.633) 169.493,332.571 168.704,331.783 ccw(c168.766,331.721) 168.704,331.659 168.89,331.474 ccw(c168.951,331.536) 169.013,331.474 169.802,332.262 cw(c169.864,332.201) 169.925,332.262 170.111,332.077 cw(c170.049,332.015) 170.111,331.954 169.307,331.15 ccw(c169.369,331.088) 169.307,331.026 169.492,330.841 ccw(c169.554,330.903) 169.616,330.841 169.725,330.95 cw(c169.787,330.889) 169.849,330.95 169.877,330.922 169.989,330.81 170.588,330.81 171.134,330.263 171.569,330.263 172.206,329.626 172.206,326.803 172.385,326.623 172.414,326.594 ccw(c172.476,326.656) 172.538,326.594 172.667,326.724 cw(c172.729,326.662) 172.79,326.724 172.976,326.538 cw(c172.914,326.477) 172.976,326.415 172.733,326.172 ccw(c172.795,326.11) 172.733,326.049 172.918,325.863 ccw(c172.98,325.925) 173.042,325.863 173.272,326.093 cw(c173.334,326.032) 173.396,326.093 173.581,325.908 cw(c173.519,325.846) 173.581,325.785 173.351,325.554 ccw(c173.413,325.493) 173.351,325.431 173.536,325.246 ccw(c173.598,325.307) 173.66,325.246 173.89,325.476 cw(c173.952,325.414) 174.013,325.476 174.199,325.29 cw(c174.137,325.229) 174.199,325.167 173.969,324.937 ccw(c174.03,324.875) 173.969,324.813 174.154,324.628 ccw(c174.216,324.69) 174.277,324.628 174.494,324.844 cw(c174.556,324.783) 174.618,324.844 174.803,324.659 cw(c174.741,324.597) 174.803,324.536 174.7,324.432 ccw(c174.761,324.371) 174.7,324.309 176.149,322.859 176.149,317.848 176.628,317.368 176.628,315.508 177.481,314.656 177.481,312.828 178.296,312.013 178.296,311.783 178.65,311.429 179.197,311.429 cw(c179.197,311.233) 179.393,311.233 179.393,310.801 ccw(c179.743,310.801) 179.743,310.452 180.111,310.452 ccw(c180.111,310.718) 180.378,310.718 ccw(c180.044,310.718) 180.044,311.052 v1(179.884,311.052)
DDR4_DQ36: U1.Y25 U9.H2 | length 38.8
  L1 w0.116: U9.H2@171.676,333.66 v1(172.079,333.257) ; v1(180.909,313.027) U1.Y25@181.397,312.539
  L12 (Sign) w0.081: v1(172.079,333.257) 172.079,332.822 175.91,328.992 175.91,327.163 178.602,324.47 178.602,324.445 179.553,323.494 179.553,323.281 179.553,322.726 ccw(c179.65,322.726) 179.65,322.629 180.319,322.629 cw(c180.319,322.531) 180.416,322.531 180.416,322.239 cw(c180.319,322.239) 180.319,322.141 179.055,322.141 ccw(c179.055,322.044) 178.958,322.044 178.958,321.751 ccw(c179.055,321.751) 179.055,321.654 180.319,321.654 cw(c180.319,321.556) 180.416,321.556 180.416,321.263 cw(c180.319,321.263) 180.319,321.166 179.055,321.166 ccw(c179.055,321.068) 178.958,321.068 178.958,320.776 ccw(c179.055,320.776) 179.055,320.678 180.13,320.678 cw(c180.13,320.581) 180.227,320.581 180.227,320.288 cw(c180.13,320.288) 180.13,320.191 179.055,320.191 ccw(c179.055,320.093) 178.958,320.093 178.958,319.801 ccw(c179.055,319.801) 179.055,319.703 180.13,319.703 cw(c180.13,319.606) 180.227,319.606 180.227,319.313 cw(c180.13,319.313) 180.13,319.216 178.787,319.216 ccw(c178.787,319.118) 178.689,319.118 178.689,318.825 ccw(c178.787,318.825) 178.787,318.728 179.455,318.728 cw(c179.455,318.63) 179.553,318.63 179.553,318.59 179.603,318.539 179.739,318.403 179.739,316.455 179.553,316.269 179.553,315.683 179.668,315.568 cw(c179.611,315.51) 179.668,315.453 179.317,315.101 ccw(c179.364,315.054) 179.317,315.007 179.459,314.864 ccw(c179.506,314.912) 179.554,314.864 179.989,315.3 cw(c180.037,315.253) 180.084,315.3 180.226,315.158 cw(c180.179,315.11) 180.226,315.063 179.696,314.533 ccw(c179.744,314.486) 179.696,314.438 179.839,314.296 ccw(c179.886,314.343) 179.933,314.296 180.379,314.742 cw(c180.437,314.685) 180.494,314.742 180.523,314.713 180.909,314.326 180.909,313.974 v1(180.909,313.027)
DDR4_DQ37: U1.AA23 U9.H5 | length 37.5
  L1 w0.116: v1(166.472,333.257) U9.H5@166.876,333.66 ; v1(181.909,310.052) U1.AA23@182.397,310.539
  L12 (Sign) w0.081: v1@166.472,333.257 166.472,333.934 166.998,334.46 169.872,334.46 169.882,334.45 169.972,334.36 170.702,334.36 170.802,334.46 171.432,334.46 171.869,334.023 172.683,334.023 173.551,333.155 176.246,330.46 176.451,330.255 176.451,327.244 181.47,322.224 181.47,315.824 181.985,315.309 181.985,312.941 181.508,312.464 181.508,311.839 181.781,311.566 182.172,311.566 182.397,311.341 182.397,310.539 v1(181.909,310.052)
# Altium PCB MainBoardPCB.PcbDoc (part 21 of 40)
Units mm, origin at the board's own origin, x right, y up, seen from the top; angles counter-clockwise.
Board outline 258.95 x 308.86 mm, 16 copper layers (L1, L2 (GND), L3 (Sign), L4 (GND), L5 (Sign), L6 (PWR/GND), L7(12V+Other), L8 (Plane_GND), L9 (PWR/GND), L10 (3V3+Other), L11 (PWR/GND), L12 (Sign), L13 (GND), L14 (Sign), L15 (GND), L16), stack 2.503 mm thick; 2578 components, 1867 nets, 8817 pads, 8021 vias.
Unrouted connection lines stored in the file: 25.

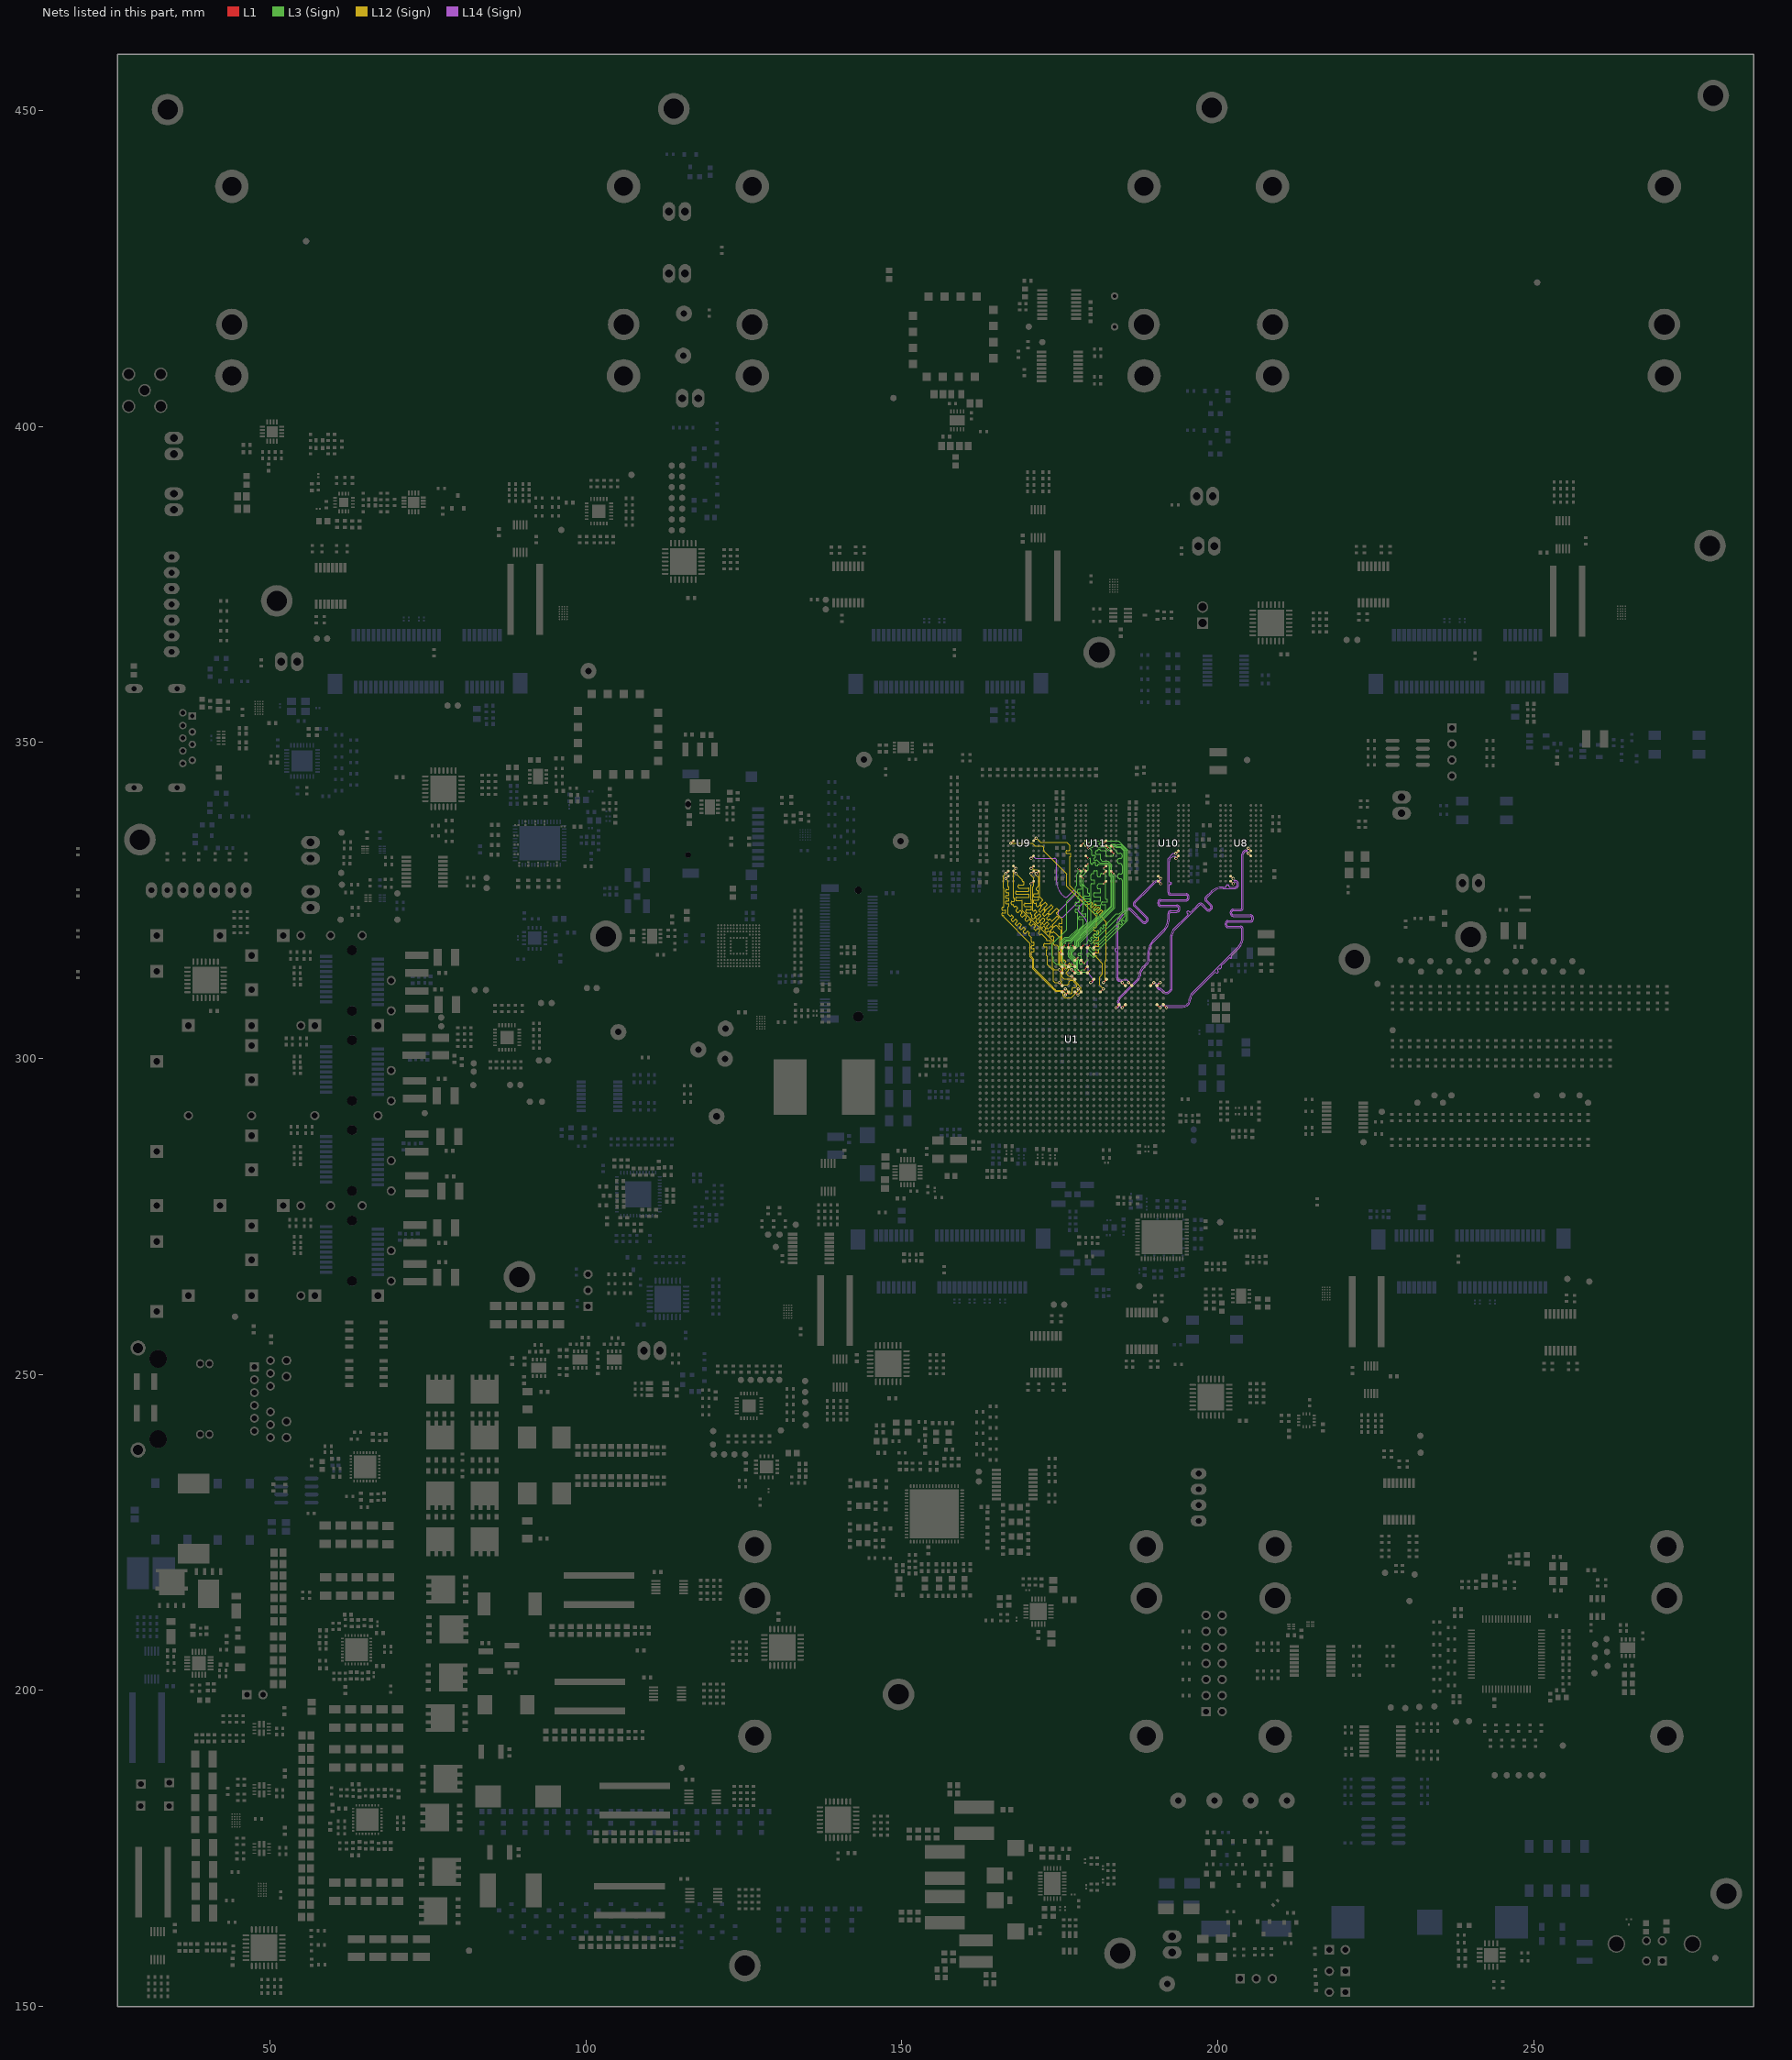
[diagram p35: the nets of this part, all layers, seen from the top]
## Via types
v1: diameter 0.5, hole 0.25, L1 to L16, tented both sides, 4341 vias
v2: diameter 0.254, hole 0.1, L1 to L3 (Sign), tented both sides, 781 vias
v3: diameter 0.5, hole 0.25, L1 to L16, 565 vias
v4: diameter 0.254, hole 0.1, L15 (GND) to L16, tented both sides, 406 vias
v5: diameter 0.254, hole 0.1, L1 to L2 (GND), tented both sides, 283 vias
v6: diameter 0.457, hole 0.2, L3 (Sign) to L6 (PWR/GND), tented both sides, 254 vias
v7: diameter 0.254, hole 0.1, L1 to L3 (Sign), 237 vias
v8: diameter 0.75, hole 0.4, L1 to L16, 200 vias
v9: diameter 0.8, hole 0.4, L1 to L16, tented both sides, 182 vias
v10: diameter 0.254, hole 0.1, L14 (Sign) to L16, tented both sides, 170 vias
v11: diameter 0.75/0/0/0/0/0/0/0/0/0/0/0/0/0/0/0.75 (per signal layer), hole 0.4, L1 to L16, 160 vias
v12: diameter 0.457, hole 0.2, L3 (Sign) to L6 (PWR/GND), 158 vias
v13: diameter 1.4, hole 0.5, L1 to L16, tented both sides, 80 vias
v14: diameter 0.254, hole 0.1, L14 (Sign) to L16, 65 vias
v15: diameter 0.254, hole 0.1, L1 to L2 (GND), 45 vias
v16: diameter 0.457, hole 0.2, L11 (PWR/GND) to L14 (Sign), tented both sides, 26 vias
v17: diameter 0.457, hole 0.2, L11 (PWR/GND) to L14 (Sign), 25 vias
v18: diameter 0.457, hole 0.2, L7(12V+Other) to L10 (3V3+Other), tented both sides, 11 vias
v19: diameter 0.254/0/0.254 (per signal layer), hole 0.1, L1 to L3 (Sign), 9 vias
v20: diameter 0.2/0/0.2 (per signal layer), hole 0.1, L1 to L3 (Sign), 6 vias
v21: diameter 1.65, hole 1.65, L1 to L16, 5 vias
v22: diameter 1.15, hole 1.15, L1 to L16, 5 vias
v23: diameter 0.457, hole 0.2, L1 to L16, 3 vias
v24: diameter 0.5, hole 0.3, L1 to L16, 2 vias
v25: diameter 0.5/0/0.5 (per signal layer), hole 0.2, L14 (Sign) to L16, 1 vias
v26: diameter 0.5, hole 0.25, L1 to L16, tented bottom, 1 vias

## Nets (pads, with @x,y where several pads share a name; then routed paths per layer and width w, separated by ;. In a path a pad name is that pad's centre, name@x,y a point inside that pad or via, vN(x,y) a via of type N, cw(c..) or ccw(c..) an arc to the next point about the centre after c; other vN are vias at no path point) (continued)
DDR4_DQ38: U1.AA25 U9.J3 | length 37.9
  L1 w0.116: U9.J3@170.876,334.46 v1(171.279,334.864) ; v1(181.909,312.052) U1.AA25@182.397,312.539
  L12 (Sign) w0.081: v1(171.279,334.864) 171.338,334.864 171.987,334.215 175.844,334.215 176.122,334.215 176.643,333.694 176.643,333.445 176.643,333.046 cw(c176.543,333.046) 176.543,332.946 176.133,332.946 ccw(c176.133,332.846) 176.033,332.846 176.033,332.547 ccw(c176.133,332.547) 176.133,332.448 176.643,332.448 176.655,332.448 cw(c176.655,332.348) 176.754,332.348 176.754,332.049 cw(c176.655,332.049) 176.655,331.949 176.643,331.949 176.643,331.483 176.643,327.352 178.485,325.51 179.36,324.634 179.36,324.617 179.553,324.424 ccw(c179.61,324.482) 179.668,324.424 179.938,324.694 cw(c179.985,324.647) 180.033,324.694 180.175,324.552 cw(c180.127,324.505) 180.175,324.457 179.881,324.164 ccw(c179.929,324.117) 179.881,324.069 180.024,323.927 ccw(c180.071,323.974) 180.118,323.927 180.588,324.396 cw(c180.635,324.349) 180.682,324.396 180.825,324.254 cw(c180.777,324.207) 180.825,324.159 180.355,323.69 ccw(c180.403,323.643) 180.355,323.595 180.498,323.453 ccw(c180.545,323.5) 180.592,323.453 181.062,323.922 cw(c181.109,323.875) 181.157,323.922 181.299,323.78 cw(c181.251,323.733) 181.299,323.685 180.83,323.216 ccw(c180.877,323.169) 180.83,323.121 180.972,322.979 ccw(c181.019,323.026) 181.067,322.979 181.536,323.448 cw(c181.583,323.401) 181.631,323.448 181.773,323.306 cw(c181.725,323.259) 181.773,323.211 181.327,322.765 ccw(c181.384,322.708) 181.327,322.651 181.592,322.385 182.372,321.605 182.372,315.584 182.177,315.389 182.177,312.319 v1(181.909,312.052)
DDR4_DQ39: U1.Y23 U9.J4 | length 39.7
  L1 w0.116: v1(167.272,334.057) U9.J4@167.676,334.46 ; U1.Y23@181.397,310.539 v1(181.884,311.027)
  L12 (Sign) w0.081: v1(167.272,334.057) 170.679,334.057 171.071,333.665 172.224,333.665 172.49,333.4 172.49,332.842 176.102,329.23 176.102,327.262 180.81,322.554 180.81,321.462 180.81,320.825 cw(c180.71,320.825) 180.71,320.725 180.516,320.725 ccw(c180.516,320.626) 180.416,320.626 180.416,320.327 ccw(c180.516,320.327) 180.516,320.227 180.81,320.227 181.108,320.227 cw(c181.108,320.127) 181.208,320.127 181.208,319.828 cw(c181.108,319.828) 181.108,319.728 180.81,319.728 180.516,319.728 ccw(c180.516,319.628) 180.416,319.628 180.416,319.329 ccw(c180.516,319.329) 180.516,319.23 180.81,319.23 181.108,319.23 cw(c181.108,319.13) 181.208,319.13 181.208,318.831 cw(c181.108,318.831) 181.108,318.731 180.81,318.731 180.511,318.731 ccw(c180.511,318.631) 180.412,318.631 180.412,318.332 ccw(c180.511,318.332) 180.511,318.232 180.81,318.232 181.108,318.232 cw(c181.108,318.133) 181.208,318.133 181.208,317.834 cw(c181.108,317.834) 181.108,317.734 180.81,317.734 180.511,317.734 ccw(c180.511,317.634) 180.412,317.634 180.412,317.335 ccw(c180.511,317.335) 180.511,317.235 180.81,317.235 181.108,317.235 cw(c181.108,317.135) 181.208,317.135 181.208,316.836 cw(c181.108,316.836) 181.108,316.737 180.81,316.737 180.511,316.737 ccw(c180.511,316.637) 180.412,316.637 180.412,316.338 ccw(c180.511,316.338) 180.511,316.238 180.71,316.238 cw(c180.71,316.138) 180.81,316.138 180.81,315.989 181.793,315.006 181.793,313.375 181.316,312.899 181.316,311.595 v1(181.884,311.027)
DDR4_DQ40: U1.P23 U9.A3 | length 32.8
  L1 w0.116: v1(170.472,327.657) U9.A3@170.876,328.06 ; U1.P23@175.397,310.539 v1(175.884,311.027)
  L12 (Sign) w0.081: v1(170.472,327.657) 170.472,325.12 170.472,325.056 cw(c170.472,325) 170.528,325 170.528,324.614 cw(c170.472,324.614) 170.472,324.558 169.524,324.558 ccw(c169.524,324.433) 169.399,324.433 169.399,324.184 ccw(c169.524,324.184) 169.524,324.059 170.472,324.059 cw(c170.472,324.003) 170.528,324.003 170.528,323.617 cw(c170.472,323.617) 170.472,323.56 169.764,323.56 ccw(c169.764,323.436) 169.64,323.436 169.64,323.186 ccw(c169.764,323.186) 169.764,323.062 170.348,323.062 cw(c170.348,322.937) 170.472,322.937 170.472,322.813 170.574,322.711 170.582,322.703 cw(c170.494,322.615) 170.582,322.527 170.538,322.483 ccw(c170.627,322.395) 170.538,322.307 170.715,322.13 ccw(c170.803,322.219) 170.891,322.13 171.023,322.262 cw(c171.103,322.182) 171.183,322.262 171.375,322.07 cw(c171.295,321.99) 171.375,321.91 171.244,321.778 ccw(c171.332,321.69) 171.244,321.602 171.42,321.425 ccw(c171.508,321.513) 171.596,321.425 171.728,321.557 cw(c171.805,321.48) 171.882,321.557 172.08,321.359 cw(c172.003,321.282) 172.08,321.204 171.949,321.073 ccw(c172.037,320.985) 171.949,320.897 172.125,320.72 ccw(c172.213,320.808) 172.301,320.72 172.433,320.852 cw(c172.492,320.793) 172.551,320.852 172.785,320.618 cw(c172.726,320.559) 172.785,320.499 172.654,320.368 ccw(c172.742,320.28) 172.654,320.191 172.83,320.015 ccw(c172.918,320.103) 173.006,320.015 173.138,320.147 cw(c173.197,320.088) 173.256,320.147 173.491,319.912 cw(c173.431,319.853) 173.491,319.794 173.359,319.663 ccw(c173.447,319.574) 173.359,319.486 173.535,319.31 ccw(c173.623,319.398) 173.712,319.31 173.755,319.353 cw(c173.843,319.265) 173.931,319.353 174.019,319.265 174.079,319.206 174.079,318.072 174.249,317.901 cw(c174.397,317.539) 174.758,317.392 174.794,317.356 174.83,317.32 174.854,317.296 174.854,314.826 175.035,314.645 175.035,314.601 175.059,314.577 175.362,314.274 175.362,313.919 175.158,313.716 175.158,312.338 175.305,312.191 175.305,311.875 175.524,311.656 176.073,311.656 176.076,311.658 176.234,311.658 176.488,311.912 176.488,312.191 176.72,312.423 177.048,312.423 177.28,312.191 177.28,312.113 177.718,311.675 177.718,311.406 177.508,311.196 177.032,311.196 ccw(c177.032,311.114) 176.949,311.114 176.949,310.483 cw(c176.771,310.483) 176.771,310.306 176.371,310.306 cw(c176.371,310.452) 176.225,310.452 176.225,310.686 ccw(c175.884,310.686) v1(175.884,311.027)
DDR4_DQ41: U1.R23 U9.B5 | length 32.7
  L1 w0.116: v1(166.472,328.457) U9.B5@166.876,328.86 ; v1(175.909,310.052) U1.R23@176.397,310.539
  L12 (Sign) w0.081: v1(166.472,328.457) 166.859,328.07 166.859,327.453 166.795,327.389 166.795,327.217 ccw(c166.847,327.217) 166.847,327.165 cw(c166.847,327.075) 166.937,327.075 166.937,326.806 cw(c166.847,326.806) 166.847,326.717 166.795,326.717 166.579,326.717 ccw(c166.579,326.627) 166.49,326.627 166.49,326.359 ccw(c166.579,326.359) 166.579,326.269 166.795,326.269 166.847,326.269 cw(c166.847,326.18) 166.937,326.18 166.937,325.911 cw(c166.847,325.911) 166.847,325.821 166.795,325.821 166.579,325.821 ccw(c166.579,325.732) 166.49,325.732 166.49,325.463 ccw(c166.579,325.463) 166.579,325.374 166.795,325.374 166.847,325.374 cw(c166.847,325.284) 166.937,325.284 166.937,325.015 cw(c166.847,325.015) 166.847,324.926 166.795,324.926 166.579,324.926 ccw(c166.579,324.836) 166.49,324.836 166.49,324.567 ccw(c166.579,324.567) 166.579,324.478 166.795,324.478 166.847,324.478 cw(c166.847,324.388) 166.937,324.388 166.937,324.12 cw(c166.847,324.12) 166.847,324.03 ccw(c166.847,323.977) 166.795,323.977 166.795,323.698 166.795,322.866 166.96,322.7 167.111,322.549 ccw(c167.174,322.613) 167.238,322.549 167.326,322.638 cw(c167.39,322.575) 167.453,322.638 167.643,322.448 cw(c167.58,322.385) 167.643,322.322 167.491,322.169 167.339,322.017 ccw(c167.402,321.954) 167.339,321.89 167.529,321.701 ccw(c167.592,321.764) 167.655,321.701 167.808,321.853 167.96,322.005 cw(c168.023,321.942) 168.086,322.005 168.276,321.815 cw(c168.213,321.752) 168.276,321.688 168.124,321.536 167.972,321.384 ccw(c168.035,321.321) 167.972,321.257 168.162,321.067 ccw(c168.225,321.131) 168.289,321.067 168.441,321.219 168.593,321.372 cw(c168.656,321.308) 168.72,321.372 168.91,321.182 cw(c168.846,321.118) 168.91,321.055 168.757,320.903 168.605,320.751 ccw(c168.669,320.687) 168.605,320.624 168.795,320.434 ccw(c168.859,320.497) 168.922,320.434 169.074,320.586 169.226,320.738 cw(c169.29,320.675) 169.353,320.738 169.543,320.548 cw(c169.48,320.485) 169.543,320.422 169.391,320.269 169.239,320.117 ccw(c169.302,320.054) 169.239,319.991 169.429,319.801 ccw(c169.492,319.864) 169.555,319.801 169.707,319.953 169.86,320.105 cw(c169.923,320.042) 169.986,320.105 170.176,319.915 cw(c170.113,319.852) 170.176,319.788 170.087,319.7 ccw(c170.151,319.636) 170.087,319.573 170.341,319.32 170.499,319.161 170.499,318.91 170.499,318.536 ccw(c170.624,318.536) 170.624,318.411 170.828,318.411 cw(c170.828,318.286) 170.952,318.286 170.952,318.037 cw(c170.828,318.037) 170.828,317.912 170.624,317.912 ccw(c170.624,317.788) 170.499,317.788 170.499,317.538 ccw(c170.624,317.538) 170.624,317.414 170.828,317.414 cw(c170.828,317.289) 170.952,317.289 170.952,317.04 cw(c170.828,317.04) 170.828,316.915 170.624,316.915 ccw(c170.624,316.79) 170.499,316.79 170.499,316.417 170.499,316.167 170.912,315.754 170.912,314.311 173.884,311.339 173.884,311.327 174.184,311.026 174.196,311.026 174.401,310.822 175.433,310.822 175.909,310.346 v1(175.909,310.052)
DDR4_DQ42: U1.T23 U9.C3 | length 30.8
  L1 w0.116: v1(170.472,329.257) U9.C3@170.876,329.66 ; U1.T23@177.397,310.539 v1(177.884,310.052)
  L12 (Sign) w0.081: v1(170.472,329.257) 170.472,328.975 170.862,328.586 170.862,328.041 170.863,328.04 170.863,327.316 170.709,327.163 170.709,323.429 170.788,323.35 ccw(c170.868,323.429) 170.947,323.35 171.028,323.432 cw(c171.107,323.353) 171.187,323.432 171.345,323.273 cw(c171.266,323.194) 171.345,323.115 171.184,322.954 171.023,322.794 ccw(c171.103,322.715) 171.023,322.635 171.182,322.477 ccw(c171.261,322.556) 171.34,322.477 171.501,322.638 171.662,322.799 cw(c171.741,322.719) 171.82,322.799 171.978,322.64 cw(c171.899,322.561) 171.978,322.482 171.817,322.321 171.657,322.16 ccw(c171.736,322.081) 171.657,322.002 171.815,321.844 ccw(c171.894,321.923) 171.973,321.844 172.134,322.004 172.295,322.165 cw(c172.374,322.086) 172.453,322.165 172.611,322.007 cw(c172.532,321.928) 172.611,321.849 172.451,321.688 172.29,321.527 ccw(c172.369,321.448) 172.29,321.369 172.448,321.21 ccw(c172.527,321.29) 172.607,321.21 172.767,321.371 172.928,321.532 cw(c173.007,321.453) 173.086,321.532 173.245,321.374 cw(c173.166,321.294) 173.245,321.215 173.084,321.055 172.923,320.894 ccw(c173.002,320.815) 172.923,320.735 173.082,320.577 ccw(c173.161,320.656) 173.24,320.577 173.401,320.738 173.561,320.899 cw(c173.641,320.82) 173.72,320.899 173.878,320.74 cw(c173.799,320.661) 173.878,320.582 173.717,320.421 173.557,320.261 ccw(c173.636,320.181) 173.557,320.102 173.715,319.944 ccw(c173.794,320.023) 173.873,319.944 173.955,320.025 cw(c174.034,319.946) 174.113,320.025 174.387,319.751 175.035,319.104 175.035,314.901 175.552,314.384 175.552,314.355 175.554,314.354 175.554,313.839 175.552,313.838 175.552,313.779 175.362,313.588 175.362,312.885 175.592,312.655 175.734,312.613 ccw(c175.845,312.987) 175.856,312.597 177.045,312.631 177.112,312.631 177.136,312.607 177.472,312.27 177.472,312.192 177.91,311.755 177.91,311.627 178.371,311.165 178.371,310.539 v1(177.884,310.052)
DDR4_DQ43: U1.P26 U9.C4 | length 29.3
  L1 w0.116: U9.C4@167.676,329.66 v1(168.079,329.257) ; v1(174.909,314.027) U1.P26@175.397,313.539
  L12 (Sign) w0.081: v1(168.079,329.257) 169.1,328.236 169.1,328.111 ccw(c169.225,328.111) 169.225,327.986 cw(c169.225,327.862) 169.35,327.862 169.35,327.612 cw(c169.225,327.612) 169.225,327.488 169.1,327.488 168.574,327.488 ccw(c168.574,327.363) 168.449,327.363 168.449,327.114 ccw(c168.574,327.114) 168.574,326.989 169.1,326.989 170.028,326.989 cw(c170.028,326.864) 170.153,326.864 170.153,326.615 cw(c170.028,326.615) 170.028,326.491 169.1,326.491 168.173,326.491 ccw(c168.173,326.366) 168.048,326.366 168.048,326.117 ccw(c168.173,326.117) 168.173,325.992 169.1,325.992 170.028,325.992 cw(c170.028,325.867) 170.153,325.867 170.153,325.618 cw(c170.028,325.618) 170.028,325.493 169.1,325.493 168.173,325.493 ccw(c168.173,325.369) 168.048,325.369 168.048,325.119 ccw(c168.173,325.119) 168.173,324.995 168.997,324.995 cw(c168.997,324.891) 169.1,324.891 169.1,323.418 173.838,318.681 173.838,314.328 174.139,314.027 v1(174.909,314.027)
DDR4_DQ44: U1.T25 U9.C2 | length 29.8
  L1 w0.116: v1(171.272,329.257) U9.C2@171.676,329.66 ; v1(176.909,313.027) U1.T25@177.397,312.539
  L12 (Sign) w0.081: v1(171.272,329.257) 171.272,328.944 171.368,328.847 171.503,328.847 171.607,328.743 171.607,328.675 171.663,328.619 171.663,327.419 171.607,327.363 171.607,327.254 171.352,327 171.352,326.768 171.352,326.674 ccw(c171.452,326.674) 171.452,326.574 171.514,326.574 cw(c171.514,326.474) 171.613,326.474 171.613,326.175 cw(c171.514,326.175) 171.514,326.076 171.352,326.076 170.99,326.076 ccw(c170.99,325.976) 170.89,325.976 170.89,325.677 ccw(c170.99,325.677) 170.99,325.577 171.352,325.577 171.553,325.577 cw(c171.553,325.477) 171.652,325.477 171.652,325.178 cw(c171.553,325.178) 171.553,325.078 171.352,325.078 170.99,325.078 ccw(c170.99,324.979) 170.89,324.979 170.89,324.679 ccw(c170.99,324.679) 170.99,324.58 171.253,324.58 cw(c171.253,324.48) 171.352,324.48 171.352,324.33 171.352,324.136 171.432,324.057 ccw(c171.511,324.136) 171.59,324.057 171.723,324.19 cw(c171.802,324.111) 171.882,324.19 172.04,324.032 cw(c171.961,323.953) 172.04,323.874 171.827,323.661 171.696,323.53 ccw(c171.775,323.45) 171.696,323.371 171.854,323.213 ccw(c171.933,323.292) 172.012,323.213 172.144,323.345 172.321,323.521 cw(c172.4,323.442) 172.479,323.521 172.637,323.363 cw(c172.558,323.284) 172.637,323.205 172.461,323.028 172.329,322.896 ccw(c172.408,322.817) 172.329,322.738 172.487,322.58 ccw(c172.567,322.659) 172.646,322.58 172.777,322.711 172.954,322.888 cw(c173.033,322.809) 173.112,322.888 173.271,322.73 cw(c173.192,322.651) 173.271,322.571 173.094,322.395 172.962,322.263 ccw(c173.041,322.184) 172.962,322.105 173.121,321.946 ccw(c173.2,322.026) 173.279,321.946 173.332,321.999 cw(c173.411,321.92) 173.49,321.999 173.493,321.996 173.609,321.88 173.688,321.801 ccw(c173.767,321.88) 173.846,321.801 174.514,322.468 cw(c174.593,322.389) 174.672,322.468 174.83,322.309 cw(c174.751,322.23) 174.83,322.151 174.084,321.405 173.865,321.186 ccw(c173.944,321.107) 173.865,321.028 174.023,320.869 ccw(c174.103,320.948) 174.182,320.869 174.321,321.009 cw(c174.401,320.93) 174.48,321.009 174.91,320.579 175.216,320.273 175.216,315.464 175.397,315.283 175.397,315.052 175.87,314.579 175.87,314.338 ccw(c175.979,314.338) 176.056,314.261 cw(c176.133,314.183) 176.21,314.261 176.365,314.106 cw(c176.288,314.029) 176.365,313.952 176.019,313.606 ccw(c176.097,313.529) 176.019,313.452 176.261,313.21 176.328,313.143 176.357,313.114 176.444,313.027 v1(176.909,313.027)
DDR4_DQ45: U1.U23 U9.C5 | length 30.1
  L1 w0.116: v1(166.472,329.257) U9.C5@166.876,329.66 ; v1(177.909,311.027) U1.U23@178.397,310.539
  L12 (Sign) w0.081: v1(166.472,329.257) 166.467,329.257 166.067,328.857 166.067,326.959 166.151,326.874 166.151,326.022 166.151,324.036 cw(c166.062,324.036) 166.062,323.946 165.936,323.946 ccw(c165.936,323.857) 165.846,323.857 165.846,323.588 ccw(c165.936,323.588) 165.936,323.498 166.151,323.498 166.366,323.498 cw(c166.366,323.409) 166.456,323.409 166.456,323.14 cw(c166.366,323.14) 166.366,323.051 166.151,323.051 165.936,323.051 ccw(c165.936,322.961) 165.846,322.961 165.846,322.692 ccw(c165.936,322.692) 165.936,322.603 166.062,322.603 cw(c166.062,322.513) 166.151,322.513 166.151,322.379 170.307,318.223 170.307,316.088 170.72,315.675 170.72,314.231 173.692,311.259 173.692,311.247 174.105,310.834 174.117,310.834 174.321,310.63 175.306,310.63 175.513,310.423 175.513,309.888 175.749,309.652 176.848,309.652 177.909,310.713 v1(177.909,311.027)
DDR4_DQ46: U1.T26 U9.D3 | length 29
  L1 w0.116: v1(170.472,330.057) U9.D3@170.876,330.46 ; v1(176.909,314.027) U1.T26@177.397,313.539
  L12 (Sign) w0.081: v1(170.472,330.057) 170.482,330.047 170.785,330.047 170.953,329.88 171.441,329.88 171.844,329.477 171.844,327.344 171.794,327.295 171.794,325.62 171.904,325.51 172.277,325.137 cw(c172.208,325.068) 172.277,324.999 171.876,324.598 ccw(c171.945,324.529) 171.876,324.46 172.083,324.253 ccw(c172.152,324.322) 172.221,324.253 172.622,324.654 cw(c172.691,324.585) 172.76,324.654 172.967,324.447 cw(c172.898,324.378) 172.967,324.309 172.526,323.868 ccw(c172.595,323.8) 172.526,323.731 172.733,323.524 ccw(c172.802,323.593) 172.871,323.524 173.587,324.24 cw(c173.656,324.171) 173.725,324.24 173.931,324.033 cw(c173.862,323.964) 173.931,323.895 173.215,323.179 ccw(c173.284,323.11) 173.215,323.041 173.422,322.834 ccw(c173.491,322.903) 173.56,322.834 174.429,323.703 cw(c174.498,323.634) 174.567,323.703 174.774,323.496 cw(c174.705,323.427) 174.774,323.358 174.484,323.068 ccw(c174.553,322.999) 174.484,322.93 174.602,322.813 175.397,322.017 175.397,321.489 cw(c175.299,321.489) 175.299,321.392 174.946,321.392 ccw(c174.946,321.294) 174.849,321.294 174.849,321.001 ccw(c174.946,321.001) 174.946,320.904 175.299,320.904 cw(c175.299,320.806) 175.397,320.806 175.397,320.626 175.397,315.539 175.426,315.511 ccw(c175.495,315.58) 175.563,315.511 175.596,315.544 cw(c175.665,315.475) 175.734,315.544 175.941,315.337 cw(c175.872,315.268) 175.941,315.199 175.792,315.05 ccw(c175.861,314.981) 175.792,314.912 175.999,314.705 ccw(c176.068,314.774) 176.137,314.705 176.454,315.022 cw(c176.523,314.953) 176.592,315.022 176.799,314.815 cw(c176.73,314.746) 176.799,314.677 176.598,314.476 ccw(c176.667,314.407) 176.598,314.338 176.705,314.231 v1(176.909,314.027)
DDR4_DQ47: U1.P24 U9.D4 | length 30.5
  L1 w0.116: U9.D4@167.676,330.46 v1(168.079,330.057) ; v1(174.909,312.027) U1.P24@175.397,311.539
  L12 (Sign) w0.081: v1(168.079,330.057) 167.676,329.653 167.676,325.704 167.676,325.443 ccw(c167.742,325.443) 167.742,325.376 cw(c167.742,325.252) 167.867,325.252 167.867,325.003 cw(c167.742,325.003) 167.742,324.878 167.676,324.878 167.423,324.878 ccw(c167.423,324.753) 167.299,324.753 167.299,324.504 ccw(c167.423,324.504) 167.423,324.379 167.551,324.379 cw(c167.551,324.255) 167.676,324.255 167.676,324.13 167.764,324.042 ccw(c167.852,324.13) 167.94,324.042 167.948,324.049 cw(c168.036,323.961) 168.124,324.049 168.3,323.873 cw(c168.212,323.785) 168.3,323.697 168.205,323.601 168.109,323.505 ccw(c168.197,323.417) 168.109,323.329 168.285,323.153 ccw(c168.373,323.241) 168.461,323.153 168.557,323.249 168.653,323.344 cw(c168.741,323.256) 168.829,323.344 169.005,323.168 cw(c168.917,323.08) 169.005,322.992 168.91,322.896 168.814,322.8 ccw(c168.902,322.712) 168.814,322.624 168.99,322.448 ccw(c169.078,322.536) 169.167,322.448 169.262,322.543 169.358,322.639 cw(c169.446,322.551) 169.534,322.639 169.71,322.463 cw(c169.622,322.375) 169.71,322.287 169.615,322.191 169.519,322.095 ccw(c169.607,322.007) 169.519,321.919 169.695,321.743 ccw(c169.784,321.831) 169.872,321.743 169.967,321.838 170.063,321.934 cw(c170.151,321.846) 170.239,321.934 170.416,321.758 cw(c170.327,321.67) 170.416,321.581 170.32,321.486 170.224,321.39 ccw(c170.312,321.302) 170.224,321.214 170.401,321.037 ccw(c170.489,321.126) 170.577,321.037 170.672,321.133 170.768,321.229 cw(c170.856,321.141) 170.944,321.229 171.121,321.053 cw(c171.033,320.964) 171.121,320.876 171.025,320.781 170.929,320.685 ccw(c171.018,320.597) 170.929,320.509 171.106,320.332 ccw(c171.194,320.421) 171.282,320.332 171.378,320.428 171.473,320.524 cw(c171.561,320.436) 171.65,320.524 171.826,320.347 cw(c171.738,320.259) 171.826,320.171 171.73,320.075 171.635,319.98 ccw(c171.723,319.892) 171.635,319.804 171.811,319.627 ccw(c171.899,319.715) 171.987,319.627 171.995,319.635 cw(c172.083,319.547) 172.171,319.635 172.344,319.461 172.892,318.913 172.892,318.789 ccw(c173.017,318.789) 173.017,318.664 173.434,318.664 cw(c173.434,318.539) 173.559,318.539 173.559,318.29 cw(c173.434,318.29) 173.434,318.165 172.892,318.165 172.618,318.165 ccw(c172.618,318.041) 172.493,318.041 172.493,317.792 ccw(c172.618,317.792) 172.618,317.667 172.892,317.667 cw(c172.892,317.553) 173.006,317.553 173.006,317.282 cw(c172.892,317.282) 172.892,317.168 172.892,316.903 172.892,316.272 173.077,316.088 173.077,314.833 174.006,313.904 174.006,312.226 174.205,312.027 v1(174.909,312.027)
DDR4_DQ48: U1.U26 U11.G2 | length 29.3
  L1 w0.116: v2(177.91,314.027) U1.U26@178.397,313.539 ; U11.G2@183.136,332.86 v2(183.54,332.457)
  L3 (Sign) w0.081: v2(177.91,314.027) 177.875,314.062 177.875,315.495 177.001,316.369 177.001,316.841 178.003,317.843 178.003,318.452 183.485,323.934 183.485,328.855 183.212,329.129 183.212,330.646 182.62,331.238 181.842,331.238 cw(c181.842,331.572) 181.508,331.572 181.508,332.13 ccw(c181.318,332.13) 181.318,332.321 180.823,332.321 cw(c180.823,332.475) 180.668,332.475 180.668,332.726 cw(c180.823,332.726) 180.823,332.88 180.835,332.88 180.915,332.88 ccw(c180.915,332.999) 181.034,332.999 cw(c181.153,332.999) 181.153,333.118 181.312,333.118 cw(c181.312,332.999) 181.431,332.999 ccw(c181.55,332.999) 181.55,332.88 181.839,332.88 182.155,332.88 cw(c182.155,332.688) 182.347,332.688 182.347,332.181 ccw(c182.474,332.181) 182.474,332.054 183.403,332.054 ccw(c183.403,332.192) 183.54,332.192 v2(183.54,332.457) ; v2(183.54,332.457) v2@183.54,332.464
DDR4_DQ49: U1.V26 U11.F4 | length 28.9
  L1 w0.116: U11.F4@179.136,332.06 179.533,331.664 v2(179.533,331.662) ; U1.V26@179.397,313.539 v2(179.884,314.027)
  L3 (Sign) w0.081: v2(179.533,331.662) 179.533,331.657 179.794,331.657 cw(c179.794,331.541) 179.909,331.541 179.909,330.924 ccw(c180.062,330.924) 180.062,330.772 180.141,330.772 ccw(c180.141,330.891) 180.26,330.891 cw(c180.379,330.891) 180.379,331.01 180.538,331.01 cw(c180.538,330.891) 180.657,330.891 180.657,330.772 180.657,330.62 ccw(c180.776,330.62) 180.776,330.501 180.935,330.501 ccw(c180.935,330.62) 181.054,330.62 181.054,330.652 cw(c181.173,330.652) 181.173,330.772 181.316,330.772 182.538,330.772 182.828,330.482 182.828,328.913 183.123,328.618 183.123,324.166 179.478,320.521 179.478,320.517 178.95,319.988 178.945,319.988 177.597,318.639 177.597,317.98 176.617,317 176.617,316.138 177.491,315.264 177.491,314.333 177.397,314.239 177.397,313.814 177.775,313.436 178.435,313.436 178.676,313.677 179.535,313.677 v2(179.884,314.027)
DDR4_DQ50: U1.U28 U11.H3 | length 28.8
  L1 w0.116: U1.U28@178.397,315.539 v2(178.884,315.052) ; U11.H3@182.336,333.66 v2(182.74,333.257)
  L3 (Sign) w0.081: v2(178.884,315.052) 179.397,315.565 179.397,316.049 179.481,316.133 ccw(c179.425,316.189) 179.481,316.245 179.336,316.39 cw(c179.392,316.446) 179.336,316.503 179.505,316.671 cw(c179.561,316.615) 179.617,316.671 179.818,316.47 180.288,316 ccw(c180.344,316.056) 180.4,316 180.569,316.168 ccw(c180.513,316.224) 180.569,316.281 180.099,316.751 179.575,317.274 cw(c179.631,317.331) 179.575,317.387 179.743,317.555 cw(c179.8,317.499) 179.856,317.555 180.323,317.088 ccw(c180.379,317.144) 180.436,317.088 180.513,317.165 180.513,318.11 180.751,318.348 181.126,318.348 185.343,322.565 185.343,332.883 184.637,333.589 183.933,333.589 183.752,333.77 183.306,333.77 182.984,333.448 182.931,333.448 v2(182.74,333.257)
DDR4_DQ51: U1.V27 U11.H4 | length 28.5
  L1 w0.116: v2(178.91,314.052) U1.V27@179.397,314.539 ; U11.H4@179.136,333.66 v2(179.54,333.257)
  L3 (Sign) w0.081: v2(178.91,314.052) 178.884,314.026 178.529,314.026 178.208,313.706 177.777,313.706 177.589,313.894 177.589,314.16 177.683,314.254 177.683,315.344 176.809,316.218 176.809,316.92 177.789,317.9 177.789,318.56 179.025,319.796 179.029,319.796 179.67,320.437 179.67,320.442 183.304,324.075 183.304,328.765 183.02,329.049 183.02,330.561 182.617,330.963 181.316,330.963 181.064,331.216 180.895,331.384 ccw(c180.811,331.3) 180.727,331.384 180.668,331.326 cw(c180.584,331.41) 180.5,331.326 180.388,331.438 cw(c180.472,331.522) 180.388,331.606 180.53,331.749 180.623,331.842 ccw(c180.538,331.926) 180.623,332.01 180.51,332.122 ccw(c180.426,332.038) 180.342,332.122 180.334,332.114 cw(c180.25,332.199) 180.166,332.114 180.109,332.17 180.074,332.206 180.074,332.722 ccw(c179.54,332.722) v2(179.54,333.257)
DDR4_DQ52: U1.U30 U11.H2 | length 26
  L1 w0.116: U1.U30@178.397,317.539 v2(178.884,318.027) ; U11.H2@183.136,333.66 v2(183.54,333.257)
  L3 (Sign) w0.081: v2(178.884,318.027) 179.102,318.027 179.349,318.274 179.411,318.335 ccw(c179.349,318.396) 179.411,318.457 179.396,318.472 cw(c179.457,318.533) 179.396,318.594 179.519,318.717 cw(c179.58,318.656) 179.641,318.717 179.717,318.641 179.792,318.565 ccw(c179.853,318.627) 179.915,318.565 180.037,318.688 ccw(c179.976,318.749) 180.037,318.81 179.961,318.886 179.886,318.962 cw(c179.947,319.023) 179.886,319.084 180.008,319.206 cw(c180.069,319.145) 180.131,319.206 180.206,319.131 180.282,319.055 ccw(c180.343,319.116) 180.404,319.055 180.527,319.177 ccw(c180.465,319.239) 180.527,319.3 180.451,319.375 180.375,319.451 cw(c180.437,319.512) 180.375,319.574 180.498,319.696 cw(c180.559,319.635) 180.62,319.696 180.696,319.62 180.771,319.545 ccw(c180.833,319.606) 180.894,319.545 181.016,319.667 ccw(c180.955,319.728) 181.016,319.789 180.941,319.865 180.865,319.941 cw(c180.926,320.002) 180.865,320.063 180.987,320.186 cw(c181.049,320.124) 181.11,320.186 181.185,320.11 181.261,320.034 ccw(c181.322,320.095) 181.383,320.034 181.506,320.157 ccw(c181.445,320.218) 181.506,320.279 181.43,320.355 181.355,320.43 cw(c181.416,320.492) 181.355,320.553 181.477,320.675 cw(c181.538,320.614) 181.599,320.675 181.675,320.599 181.751,320.524 ccw(c181.812,320.585) 181.873,320.524 181.995,320.646 ccw(c181.934,320.707) 181.995,320.769 181.92,320.844 181.844,320.92 cw(c181.905,320.981) 181.844,321.042 181.967,321.165 cw(c182.028,321.104) 182.089,321.165 182.165,321.089 182.24,321.013 ccw(c182.301,321.075) 182.363,321.013 182.485,321.136 ccw(c182.424,321.197) 182.485,321.258 182.471,321.273 cw(c182.532,321.334) 182.471,321.395 182.563,321.487 183.968,322.892 184.478,322.892 184.959,323.373 184.959,328.021 ccw(c184.533,328.021) 184.533,328.448 184.528,328.448 cw(c184.528,328.855) 184.121,328.855 cw(c184.492,328.855) 184.399,329.214 ccw(c184.379,329.293) 184.402,329.215 cw(c184.517,328.842) 184.497,329.232 184.761,329.232 ccw(c184.761,329.396) 184.925,329.396 184.925,330.445 ccw(c184.507,330.445) 184.507,330.864 184.481,330.864 cw(c184.481,331.26) 184.084,331.26 cw(c184.485,331.26) 184.485,331.662 184.533,331.662 ccw(c184.533,332.054) 184.925,332.054 184.925,332.067 ccw(c184.528,332.067) 184.528,332.464 184.197,332.464 cw(c184.197,332.626) 184.036,332.626 184.036,332.761 v2(183.54,333.257)
DDR4_DQ53: U1.V30 U11.H5 | length 26.1
  L1 w0.116: U11.H5@178.336,333.66 v2(178.74,334.064) ; U1.V30@179.397,317.539 v2(179.884,318.027)
  L3 (Sign) w0.081: v2(178.74,334.064) 179.143,333.66 179.66,333.66 179.933,333.388 179.943,333.388 180.139,333.388 ccw(c180.139,333.518) 180.269,333.518 180.269,333.549 cw(c180.399,333.549) 180.399,333.679 180.79,333.679 cw(c180.79,333.549) 180.92,333.549 180.92,333.518 ccw(c181.05,333.518) 181.05,333.388 181.458,333.388 182.155,333.388 182.607,332.936 182.873,332.936 183.061,333.124 183.061,333.268 183.37,333.578 183.673,333.578 183.842,333.408 184.562,333.408 185.151,332.819 185.151,323.294 v2(179.884,318.027)
DDR4_DQ54: U1.W30 U11.J3 | length 25.7
  L1 w0.116: U1.W30@180.397,317.539 v2(180.884,318.027) ; v2(181.933,334.057) U11.J3@182.336,334.46
  L3 (Sign) w0.081: v2(180.884,318.027) 180.913,318.056 181.34,318.056 183.159,319.875 183.935,320.651 cw(c183.991,320.595) 184.048,320.651 184.082,320.617 ccw(c184.138,320.673) 184.194,320.617 184.362,320.785 ccw(c184.306,320.841) 184.362,320.898 184.272,320.988 184.221,321.039 cw(c184.277,321.095) 184.221,321.151 184.39,321.32 cw(c184.446,321.263) 184.502,321.32 184.553,321.268 184.643,321.178 ccw(c184.699,321.234) 184.755,321.178 184.924,321.347 ccw(c184.868,321.403) 184.924,321.459 184.834,321.549 184.783,321.6 cw(c184.839,321.656) 184.783,321.713 184.951,321.881 cw(c185.007,321.825) 185.063,321.881 185.114,321.83 185.205,321.74 ccw(c185.261,321.796) 185.317,321.74 185.485,321.908 ccw(c185.429,321.964) 185.485,322.02 185.451,322.054 cw(c185.507,322.111) 185.451,322.167 185.535,322.251 185.535,332.947 185.298,333.185 184.637,333.845 183.948,333.845 183.832,333.962 183.242,333.962 182.909,333.629 181.445,333.629 181.241,333.833 181.241,334.027 181.391,334.177 181.813,334.177 v2(181.933,334.057)
DDR4_DQ55: U1.W29 U11.J4 | length 26.2
  L1 w0.116: U11.J4@179.136,334.46 v2(179.54,334.057) ; U1.W29@180.403,316.535 v2(180.891,317.022)
  L3 (Sign) w0.081: v2(179.54,334.057) 179.93,334.447 184.272,334.447 184.517,334.202 184.536,334.202 185.727,333.011 185.727,321.859 v2(180.891,317.022)
DDR4_DQ56: U1.R30 U11.A3 | length 19.4
  L1 w0.116: U1.R30@176.397,317.539 v2(176.397,318.229) ; v2(181.937,327.664) 181.94,327.664 U11.A3@182.336,328.06
  L3 (Sign) w0.081: v2(176.397,318.229) 176.446,318.278 176.692,318.278 178.786,320.372 178.791,320.372 179.094,320.676 179.094,320.68 180.95,322.535 180.95,322.643 180.95,322.839 ccw(c180.819,322.839) 180.819,322.969 180.529,322.969 cw(c180.529,323.099) 180.399,323.099 180.399,323.49 cw(c180.529,323.49) 180.529,323.62 180.95,323.62 181.37,323.62 ccw(c181.37,323.75) 181.5,323.75 181.5,324.141 ccw(c181.37,324.141) 181.37,324.271 180.95,324.271 180.529,324.271 cw(c180.529,324.401) 180.399,324.401 180.399,324.792 cw(c180.529,324.792) 180.529,324.922 180.95,324.922 181.37,324.922 ccw(c181.37,325.052) 181.5,325.052 181.5,325.443 ccw(c181.37,325.443) 181.37,325.573 180.95,325.573 180.529,325.573 cw(c180.529,325.703) 180.399,325.703 180.399,326.094 cw(c180.529,326.094) 180.529,326.224 180.95,326.224 181.37,326.224 ccw(c181.37,326.354) 181.5,326.354 181.5,326.745 ccw(c181.37,326.745) 181.37,326.875 181.08,326.875 cw(c181.08,327.005) 180.95,327.005 180.95,327.393 180.95,327.406 181.208,327.664 v2(181.937,327.664)
DDR4_DQ57: U1.T30 U11.B5 | length 18.9
  L1 w0.116: v2(176.91,318.027) U1.T30@177.397,317.539 ; U11.B5@178.336,328.86 v2(178.733,328.462)
  L3 (Sign) w0.081: v2(176.91,318.027) 176.446,317.563 175.874,317.563 175.514,317.924 175.514,318.275 176.023,318.783 176.655,318.783 179.464,321.592 179.464,324.243 179.464,324.283 ccw(c179.355,324.283) 179.355,324.392 179.005,324.392 cw(c179.005,324.502) 178.895,324.502 178.895,324.72 cw(c179.005,324.72) 179.005,324.829 179.669,324.829 ccw(c179.669,324.938) 179.778,324.938 179.778,325.157 ccw(c179.669,325.157) 179.669,325.266 179.005,325.266 cw(c179.005,325.375) 178.895,325.375 178.895,325.594 cw(c179.005,325.594) 179.005,325.703 179.658,325.703 ccw(c179.658,325.812) 179.767,325.812 179.767,326.03 ccw(c179.658,326.03) 179.658,326.14 179.573,326.14 cw(c179.573,326.249) 179.464,326.249 179.464,326.576 179.464,326.785 178.895,327.354 178.895,327.419 178.733,327.582 v2(178.733,328.462)
DDR4_DQ58: U1.P30 U11.C3 | length 19
  L1 w0.116: U1.P30@175.397,317.539 v2(175.884,318.027) ; v2(181.937,329.264) 181.94,329.264 U11.C3@182.336,329.66
  L3 (Sign) w0.081: v2(175.884,318.027) 175.884,318.339 176.136,318.591 176.734,318.591 178.707,320.564 178.711,320.564 178.902,320.755 178.902,320.76 179.959,321.816 179.959,327.139 179.959,327.577 cw(c180.069,327.577) 180.069,327.687 180.452,327.687 ccw(c180.452,327.797) 180.562,327.797 180.562,328.126 ccw(c180.452,328.126) 180.452,328.236 180.069,328.236 cw(c180.069,328.346) 179.959,328.346 179.959,328.511 179.959,329.105 180.118,329.264 180.283,329.264 ccw(c180.283,329.374) 180.393,329.374 180.393,329.611 cw(c180.503,329.611) 180.503,329.721 180.832,329.721 cw(c180.832,329.611) 180.942,329.611 180.942,329.264 180.942,328.917 ccw(c181.052,328.917) 181.052,328.807 181.382,328.807 ccw(c181.382,328.917) 181.492,328.917 181.492,329.154 cw(c181.602,329.154) 181.602,329.264 v2(181.937,329.264)
DDR4_DQ59: U1.P29 U11.C4 | length 19.6
  L1 w0.116: v2(174.91,317.027) U1.P29@175.397,316.539 ; v2@178.74,330.057 U11.C4@179.136,329.66
  L3 (Sign) w0.081: v2(174.91,317.027) 174.884,317.052 174.884,317.556 175.119,317.791 175.119,318.469 175.828,319.178 176.506,319.178 177.825,320.497 177.825,322.77 177.825,322.987 ccw(c177.716,322.987) 177.716,323.097 177.601,323.097 cw(c177.601,323.207) 177.491,323.207 177.491,323.537 cw(c177.601,323.537) 177.601,323.647 177.825,323.647 178.05,323.647 ccw(c178.05,323.757) 178.16,323.757 178.16,324.086 ccw(c178.05,324.086) 178.05,324.196 177.825,324.196 177.601,324.196 cw(c177.601,324.306) 177.491,324.306 177.491,324.636 cw(c177.601,324.636) 177.601,324.745 177.825,324.745 178.05,324.745 ccw(c178.05,324.855) 178.16,324.855 178.16,325.185 ccw(c178.05,325.185) 178.05,325.295 177.935,325.295 cw(c177.935,325.405) 177.825,325.405 177.825,325.57 178.219,325.963 178.219,326.128 ccw(c178.109,326.128) 178.109,326.238 177.953,326.238 cw(c177.953,326.348) 177.843,326.348 177.843,326.677 cw(c177.953,326.677) 177.953,326.787 178.219,326.787 178.42,326.787 ccw(c178.42,326.897) 178.53,326.897 178.53,327.227 ccw(c178.42,327.227) 178.42,327.337 178.329,327.337 cw(c178.329,327.447) 178.219,327.447 178.219,327.749 178.219,329.136 178.74,329.656 v2@178.74,330.057
  other v2: 178.74,330.059
DDR4_DQ60: U1.T28 U11.C2 | length 20.4
  L1 w0.116: U1.T28@177.397,315.539 v2(177.884,316.027) ; U11.C2@183.136,329.66 v2(183.533,329.262) v2(183.533,329.262)
  L3 (Sign) w0.081: v2(177.884,316.027) 177.884,315.772 178.118,315.539 178.118,315.08 ccw(c178.248,315.08) 178.248,314.95 178.438,314.95 ccw(c178.438,315.061) 178.549,315.061 178.549,315.633 178.41,315.773 178.41,316.116 178.41,316.202 ccw(c178.323,316.202) 178.323,316.289 178.002,316.289 cw(c178.002,316.375) 177.915,316.375 177.915,316.548 cw(c178.002,316.548) 178.002,316.635 178.323,316.635 ccw(c178.323,316.722) 178.41,316.722 178.41,316.916 178.41,317.498 178.206,317.701 178.206,318.352 183.709,323.855 183.709,329.085 v2(183.533,329.262)
DDR4_DQ61: U1.T27 U11.C5 | length 21
  L1 w0.116: v2(176.91,315.027) U1.T27@177.397,314.539 ; v2@177.94,330.057 U11.C5@178.336,329.66
  L3 (Sign) w0.081: v2(176.91,315.027) 176.589,314.706 175.777,314.706 175.532,314.95 174.426,314.95 174.001,315.375 174.001,315.381 173.988,315.394 173.988,316.016 173.809,316.195 173.809,318.081 176.109,320.381 176.109,324.852 177.47,326.213 177.47,327.133 177.705,327.367 177.705,329.165 177.94,329.399 v2@177.94,330.057
  other v2: 177.94,330.059
DDR4_DQ62: U1.P27 U11.D3 | length 22.8
  L1 w0.116: U1.P27@175.397,314.539 v2(175.884,314.052) ; v2(181.937,330.064) 181.94,330.064 U11.D3@182.336,330.46
  L3 (Sign) w0.081: v2(175.884,314.052) 176.346,314.514 176.668,314.514 176.706,314.552 177.138,314.552 177.299,314.713 177.299,315.182 176.403,316.078 176.403,317.036 176.425,317.058 176.425,317.079 177.405,318.059 177.405,318.719 178.866,320.18 178.87,320.18 179.286,320.596 179.286,320.601 182.266,323.58 182.266,324.182 182.266,324.222 ccw(c182.157,324.222) 182.157,324.332 181.732,324.332 cw(c181.732,324.441) 181.623,324.441 181.623,324.659 cw(c181.732,324.659) 181.732,324.768 182.46,324.768 ccw(c182.46,324.878) 182.57,324.878 182.57,325.096 ccw(c182.46,325.096) 182.46,325.205 182.375,325.205 cw(c182.375,325.314) 182.266,325.314 182.266,326.616 182.266,329.735 v2(181.937,330.064)
DDR4_DQ63: U1.R27 U11.D4 | length 22.1
  L1 w0.116: v2(175.91,315.027) U1.R27@176.397,314.539 ; U11.D4@179.136,330.46 179.533,330.857 v2(179.535,330.857)
  L3 (Sign) w0.081: 175.514,315.862 175.514,315.422 v2(175.91,315.027) ; 175.514,315.863 175.514,317.577 175.311,317.779 175.311,318.389 175.908,318.986 176.586,318.986 178.714,321.115 178.714,321.874 178.714,321.915 ccw(c178.605,321.915) 178.605,322.024 178.116,322.024 cw(c178.116,322.133) 178.006,322.133 178.006,322.352 cw(c178.116,322.352) 178.116,322.461 179.066,322.461 ccw(c179.066,322.57) 179.175,322.57 179.175,322.789 ccw(c179.066,322.789) 179.066,322.898 178.605,322.898 cw(c178.605,323.007) 178.496,323.007 178.496,323.225 cw(c178.605,323.225) 178.605,323.335 ccw(c178.605,323.444) 178.714,323.444 178.714,323.989 178.714,327.344 178.412,327.647 178.412,328.729 179.535,329.852 v2(179.535,330.857)
DDR4_DQS_0_N: U1.AK21 U8.F3 | length 45.3
  L1 w0.116: U1.AK21@191.397,308.539 191.884,308.052 v1(191.884,308.032) ; v1(204.853,332.464) U8.F3@205.257,332.06
  L14 (Sign) w0.105: v1(191.884,308.032) cw(c191.985,308.032) 191.985,308.133 194.467,308.133 ccw(c194.467,309.408) 195.742,309.408 cw(c196.754,309.408) 196.038,310.124 199.241,313.327 199.568,313.654 cw(c199.643,313.58) 199.717,313.654 199.812,313.559 ccw(c199.884,313.632) 199.957,313.559 200.102,313.704 ccw(c200.029,313.777) 200.102,313.85 200.005,313.946 cw(c200.078,314.019) 200.005,314.091 200.15,314.236 cw(c200.223,314.164) 200.295,314.236 200.297,314.234 ccw(c200.37,314.307) 200.442,314.234 200.588,314.379 ccw(c200.515,314.452) 200.588,314.524 cw(c200.662,314.599) 200.587,314.673 201.105,315.191 201.574,315.66 201.794,315.88 cw(c201.885,315.789) 201.976,315.88 ccw(c202.067,315.971) 202.158,315.88 ccw(c202.067,315.971) 202.158,316.062 cw(c202.249,316.153) 202.158,316.244 203.091,317.177 203.256,317.342 ccw(c201.298,319.3) 204.067,319.3 204.067,320.308 204.067,320.477 ccw(c203.602,320.477) 203.602,320.942 201.664,320.942 cw(c201.664,321.174) 201.432,321.174 201.432,321.373 cw(c201.664,321.373) 201.664,321.606 205.206,321.606 ccw(c205.206,322.071) 205.67,322.071 205.67,322.27 ccw(c205.206,322.27) 205.206,322.735 202.463,322.735 cw(c202.463,322.967) 202.23,322.967 202.23,323.166 cw(c202.463,323.166) 202.463,323.399 203.602,323.399 ccw(c203.602,323.863) 204.067,323.863 204.067,325.841 204.067,327.942 204.067,332.324 cw(c204.495,332.324) 204.495,332.753 204.565,332.753 cw(c204.565,332.464) v1(204.853,332.464)
DDR4_DQS_0_P: U1.AJ21 U8.G3 | length 45.4
  L1 w0.116: U1.AJ21@190.397,308.539 190.884,308.052 v1(190.884,308.032) ; v1(204.853,333.264) U8.G3@205.257,332.86
  L14 (Sign) w0.105: v1(190.884,308.032) cw(c191.218,308.032) 191.218,308.366 194.466,308.366 ccw(c194.466,309.409) 195.509,309.408 ; 195.509,309.409 cw(c196.751,309.409) 195.873,310.288 203.091,317.505 ccw(c201.295,319.301) 203.835,319.301 203.835,320.308 203.835,320.477 ccw(c203.602,320.477) 203.602,320.709 201.664,320.709 cw(c201.664,321.174) 201.2,321.174 201.2,321.373 cw(c201.664,321.373) 201.664,321.838 205.206,321.838 ccw(c205.206,322.071) 205.438,322.071 205.438,322.27 ccw(c205.206,322.27) 205.206,322.502 202.463,322.502 cw(c202.463,322.967) 201.998,322.967 201.998,323.166 cw(c202.463,323.166) 202.463,323.631 203.602,323.631 ccw(c203.602,323.863) 203.835,323.863 203.835,325.841 203.835,327.942 ; 203.835,327.945 203.835,332.324 cw(c204.495,332.324) 204.495,332.985 204.574,332.985 ccw(c204.574,333.264) v1(204.853,333.264)
DDR4_DQS_1_N: U1.AJ24 U8.A4 | length 32.4
  L1 w0.116: U1.AJ24@190.397,311.539 v1(190.884,312.027) ; U8.A4@202.057,328.06 v1(202.461,327.657)
  L14 (Sign) w0.105: v1(190.884,312.027) ccw(c190.884,311.643) 190.5,311.643 190.5,311.467 ccw(c190.856,311.467) 190.856,311.112 190.857,311.112 cw(c190.857,310.762) 191.105,311.009 191.423,310.691 ccw(c191.884,311.151) 191.884,310.5 ccw(c191.884,311.064) 192.283,310.665 192.483,310.865 ccw(c192.259,311.088) 192.575,311.088 192.575,319.406 cw(c194.122,319.406) 193.028,320.5 195.238,322.71 195.275,322.747 ccw(c195.201,322.821) 195.275,322.896 195.147,323.024 cw(c195.22,323.096) 195.147,323.169 195.292,323.314 cw(c195.365,323.241) 195.438,323.314 195.566,323.186 ccw(c195.64,323.26) 195.715,323.186 195.975,323.446 196.209,323.681 196.328,323.8 ; 196.329,323.8 196.962,324.433 cw(c197.291,324.105) 197.582,324.468 197.586,324.468 198.409,323.645 ; 198.409,323.645 ccw(c198.574,323.809) 198.738,323.645 ; 198.738,323.645 198.878,323.785 ccw(c198.714,323.95) 198.879,324.114 198.089,324.904 cw(c198.418,325.232) 198.09,325.561 198.534,326.005 198.653,326.125 198.859,326.33 cw(c200.817,324.372) 200.817,327.142 201.2,327.142 201.252,327.142 ccw(c201.252,327.247) 201.358,327.247 201.358,327.361 cw(c201.46,327.361) 201.46,327.464 201.665,327.464 cw(c201.665,327.361) 201.768,327.361 201.768,327.247 ccw(c201.873,327.247) 201.873,327.142 202.121,327.142 202.728,327.142 ccw(c202.728,327.499) 203.085,327.499 203.085,327.583 ccw(c202.728,327.583) 202.728,327.941 ccw(c202.728,327.674) 202.461,327.674 v1(202.461,327.657)
DDR4_DQS_1_P: U1.AH24 U8.B4 | length 32.4
  L1 w0.116: U1.AH24@189.397,311.539 v1(189.884,312.027) ; U8.B4@202.057,328.86 v1(202.461,328.457)
  L14 (Sign) w0.105: v1(189.884,312.027) cw(c189.884,311.643) 190.268,311.643 190.268,311.467 ccw(c190.856,311.467) 190.856,310.88 cw(c190.856,310.759) 190.941,310.844 ; 190.941,310.844 191.261,310.525 ccw(c191.882,311.146) 191.882,310.267 191.886,310.267 ccw(c191.886,311.059) 192.446,310.499 192.648,310.702 ccw(c192.263,311.086) 192.808,311.086 192.808,319.405 cw(c194.124,319.405) 193.193,320.336 196.374,323.516 196.493,323.636 ; 196.493,323.636 197.126,324.269 ; 197.126,324.269 cw(c197.291,324.105) 197.456,324.269 ; 197.456,324.269 198.245,323.48 ccw(c198.574,323.809) 198.903,323.481 199.042,323.621 ; 198.254,325.067 199.042,324.279 cw(c198.714,323.95) 199.043,323.621 ; 198.254,325.067 cw(c198.418,325.232) 198.254,325.397 198.698,325.841 ; 198.699,325.842 198.818,325.961 199.022,326.165 cw(c200.818,324.369) 200.818,326.909 202.728,326.909 ccw(c202.728,327.499) 203.317,327.499 203.317,327.583 ccw(c202.728,327.583) 202.728,328.173 cw(c202.728,328.44) 202.461,328.44 v1(202.461,328.457)
DDR4_DQS_2_N: U1.AD21 U10.F3 | length 41.3
  L1 w0.116: v1(184.909,308.052) U1.AD21@185.397,308.539 ; v1(193.393,331.657) U10.F3@193.797,332.06
  L14 (Sign) w0.105: v1(184.909,308.052) 184.784,308.052 cw(c184.784,308.242) 184.594,308.242 184.595,308.455 ccw(c184.189,308.455) 184.476,308.742 cw(c184.644,308.911) 184.406,308.911 184.406,309.093 cw(c185.058,309.093) 184.597,309.553 187.514,312.471 ccw(c186.933,313.051) 187.754,313.051 cw(c189.513,313.052) 188.269,314.295 188.747,314.772 ccw(c187.68,315.839) 189.189,315.839 189.189,316.749 cw(c191.729,316.749) 189.932,318.545 191.532,320.145 ccw(c189.573,322.103) 192.343,322.103 192.343,322.3 192.343,322.924 cw(c192.575,322.924) 192.575,323.156 193.548,323.156 ccw(c193.548,323.621) 194.013,323.621 194.013,323.82 ccw(c193.548,323.82) 193.548,324.285 190.972,324.285 cw(c190.972,324.517) 190.74,324.517 190.74,324.716 cw(c190.972,324.716) 190.972,324.949 195.018,324.949 ccw(c195.018,325.414) 195.483,325.414 195.483,325.613 ccw(c195.018,325.613) 195.018,326.078 192.575,326.078 cw(c192.575,326.31) 192.343,326.31 192.343,326.479 192.343,327.142 192.343,327.452 cw(c192.472,327.452) 192.472,327.581 192.567,327.581 ccw(c192.567,327.71) 192.696,327.71 ccw(c192.567,327.71) 192.567,327.838 192.472,327.838 cw(c192.472,327.967) 192.343,327.967 192.343,328.384 192.343,331.178 cw(c193.118,331.178) 193.102,331.952 cw(c193.102,331.661) 193.393,331.661 v1(193.393,331.657)
DDR4_DQS_2_P: U1.AC21 U10.G3 | length 41.3
  L1 w0.116: v1(183.909,308.052) U1.AC21@184.397,308.539 ; v1(193.375,332.457) 193.384,332.457 193.787,332.86 U10.G3@193.797,332.86
  L14 (Sign) w0.105: v1(183.909,308.052) 184.173,308.052 ccw(c184.173,308.242) 184.362,308.242 184.362,308.454 ccw(c184.185,308.454) 184.31,308.579 cw(c184.639,308.909) 184.174,308.909 184.174,309.093 cw(c185.057,309.093) 184.432,309.717 187.349,312.635 ccw(c186.932,313.052) 187.522,313.052 187.522,313.055 cw(c189.505,313.055) 188.103,314.457 188.582,314.936 ccw(c187.679,315.839) 188.956,315.839 188.956,316.75 cw(c191.726,316.75) 189.767,318.709 191.367,320.308 ccw(c189.571,322.104) 192.111,322.104 192.111,322.3 192.111,322.924 cw(c192.575,322.924) 192.575,323.388 193.548,323.388 ccw(c193.548,323.621) 193.781,323.621 193.781,323.82 ccw(c193.548,323.82) 193.548,324.052 190.972,324.052 cw(c190.972,324.517) 190.507,324.517 190.507,324.716 cw(c190.972,324.716) 190.972,325.181 195.018,325.181 ccw(c195.018,325.414) 195.25,325.414 195.25,325.613 ccw(c195.018,325.613) 195.018,325.845 192.575,325.845 cw(c192.575,326.31) 192.111,326.31 192.111,326.479 192.111,328.384 192.111,331.595 192.967,332.451 193.369,332.451 v1(193.375,332.457)
DDR4_DQS_3_N: U1.AE24 U10.A4 | length 28.3
  L1 w0.116: U10.A4@190.597,328.06 v1(191,327.657)
  L1 w0.124: v1(185.909,312.027) U1.AE24@186.397,311.539
  L14 (Sign) w0.105: v1(185.909,312.027) ccw(c185.478,312.027) 185.478,312.458 184.477,312.458 cw(c184.477,312.719) 184.216,312.719 184.216,320.921 cw(c186.61,320.921) 184.917,322.614 185.033,322.73 185.152,322.849 185.786,323.483 cw(c185.951,323.319) 186.116,323.483 188.085,321.514 ccw(c188.413,321.842) 188.742,321.514 188.882,321.654 ccw(c188.554,321.983) 188.882,322.312 186.914,324.281 cw(c187.077,324.446) 186.913,324.611 188.092,325.789 188.211,325.908 190.066,327.763 cw(c190.522,327.307) 190.522,327.952 190.805,327.952 cw(c190.805,327.757) 191,327.757 v1(191,327.657)
DDR4_DQS_3_P: U1.AD24 U10.B4 | length 28.1
  L1 w0.116: U10.B4@190.597,328.86 v1(191,328.457)
  L1 w0.124: v1(184.909,312.027) U1.AD24@185.397,311.539
  L14 (Sign) w0.105: v1(184.909,312.027) 184.909,312.07 ccw(c184.754,312.07) 184.754,312.226 184.477,312.226 cw(c184.477,312.719) 183.984,312.719 183.984,316.82 183.984,316.873 ccw(c183.878,316.873) 183.878,316.978 cw(c183.878,317.081) 183.776,317.081 183.776,317.286 cw(c183.878,317.286) 183.878,317.389 ccw(c183.878,317.494) 183.984,317.494 183.984,317.861 183.984,320.922 cw(c186.609,320.922) 184.753,322.778 184.869,322.894 184.988,323.013 ; 184.988,323.014 185.621,323.647 cw(c185.951,323.319) 186.241,323.682 186.245,323.682 188.248,321.679 ccw(c188.413,321.842) 188.578,321.678 ; 187.927,325.953 186.749,324.775 ccw(c187.077,324.446) 186.749,324.117 188.718,322.148 cw(c188.554,321.983) 188.718,321.819 ; 187.928,325.954 188.047,326.073 189.903,327.928 cw(c190.521,327.31) 190.521,328.184 190.805,328.184 ccw(c190.805,328.38) 191,328.38 v1(191,328.457) ; 188.578,321.679 188.718,321.818
DDR4_DQS_4_N: U1.W25 U9.F3 | length 38.7
  L1 w0.116: v1(170.472,331.657) U9.F3@170.876,332.06 ; v1(179.909,312.052) U1.W25@180.397,312.539
  L14 (Sign) w0.105: v1(170.472,331.657) cw(c170.756,331.657) 170.756,331.941 170.832,331.941 170.9,331.873 ccw(c171.371,332.344) 171.371,331.677 174.148,331.677 cw(c174.148,331.305) 174.52,331.305 174.52,330.149 174.52,327.92 ccw(c177.29,327.92) 175.331,325.962 175.496,325.796 175.615,325.678 ; 175.616,325.677 ccw(c175.944,326.006) 176.274,325.677 177.052,326.456 cw(c177.217,326.292) 177.382,326.457 ; 175.63,322.498 cw(c175.301,322.827) 174.972,322.499 174.832,322.638 cw(c175.16,322.968) 174.798,323.258 174.798,323.262 177.522,325.987 ; 175.63,322.499 178.191,325.059 cw(c178.356,324.895) 178.52,325.06 ; 177.382,326.456 177.522,326.317 ; 177.523,325.987 ccw(c177.358,326.152) 177.523,326.316 ; 178.463,322.829 178.011,323.282 cw(c178.339,323.611) 178.011,323.94 178.66,324.59 ; 178.464,322.829 178.583,322.71 178.653,322.64 cw(c176.857,320.844) 179.397,320.844 179.397,320.709 179.397,320.399 cw(c179.268,320.399) 179.268,320.27 179.247,320.27 ccw(c179.247,320.141) 179.119,320.141 ccw(c179.247,320.141) 179.247,320.012 179.268,320.012 cw(c179.268,319.884) 179.397,319.884 179.397,319.621 179.397,314.479 ccw(c181.798,314.479) 180.1,312.78 180.102,312.779 cw(c179.669,312.346) 180.281,312.346 180.281,312.226 cw(c180.107,312.226) 180.107,312.052 v1(179.909,312.052) ; 178.521,325.059 178.66,324.92 cw(c178.497,324.755) 178.661,324.59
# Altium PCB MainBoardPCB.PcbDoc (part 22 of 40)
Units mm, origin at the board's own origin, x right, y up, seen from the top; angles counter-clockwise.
Board outline 258.95 x 308.86 mm, 16 copper layers (L1, L2 (GND), L3 (Sign), L4 (GND), L5 (Sign), L6 (PWR/GND), L7(12V+Other), L8 (Plane_GND), L9 (PWR/GND), L10 (3V3+Other), L11 (PWR/GND), L12 (Sign), L13 (GND), L14 (Sign), L15 (GND), L16), stack 2.503 mm thick; 2578 components, 1867 nets, 8817 pads, 8021 vias.
Unrouted connection lines stored in the file: 25.

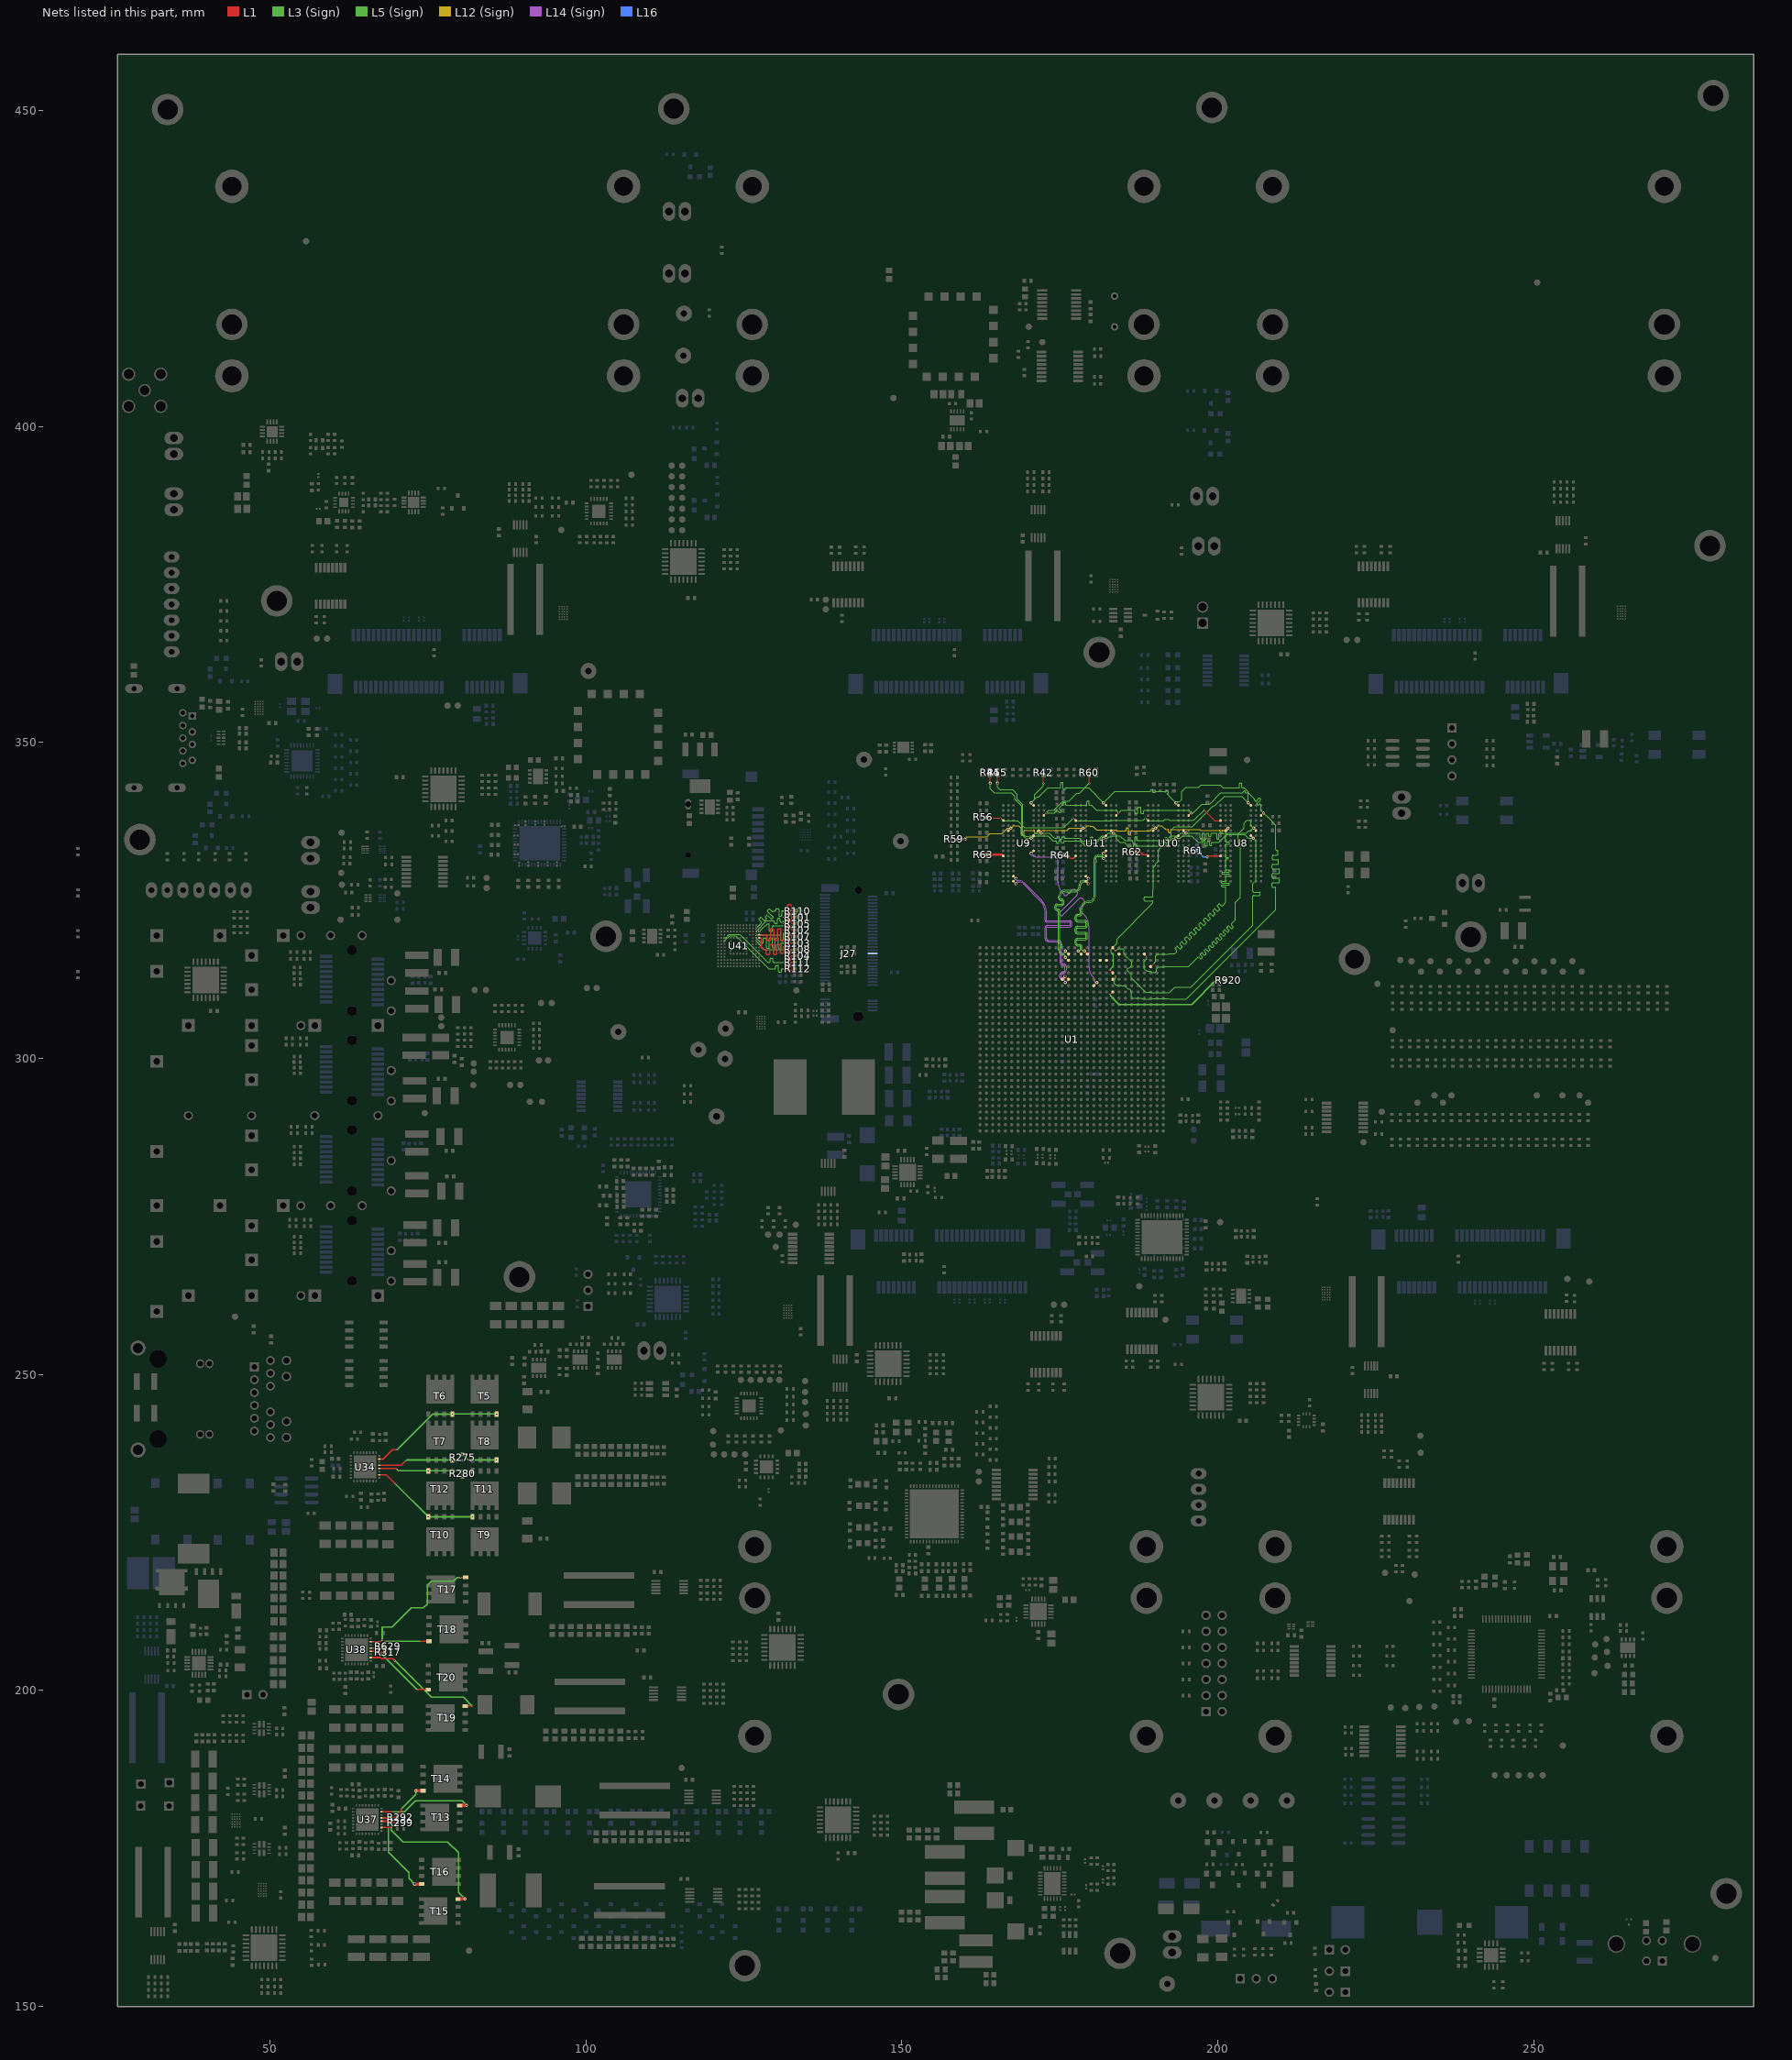
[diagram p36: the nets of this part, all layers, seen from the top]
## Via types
v1: diameter 0.5, hole 0.25, L1 to L16, tented both sides, 4341 vias
v2: diameter 0.254, hole 0.1, L1 to L3 (Sign), tented both sides, 781 vias
v3: diameter 0.5, hole 0.25, L1 to L16, 565 vias
v4: diameter 0.254, hole 0.1, L15 (GND) to L16, tented both sides, 406 vias
v5: diameter 0.254, hole 0.1, L1 to L2 (GND), tented both sides, 283 vias
v6: diameter 0.457, hole 0.2, L3 (Sign) to L6 (PWR/GND), tented both sides, 254 vias
v7: diameter 0.254, hole 0.1, L1 to L3 (Sign), 237 vias
v8: diameter 0.75, hole 0.4, L1 to L16, 200 vias
v9: diameter 0.8, hole 0.4, L1 to L16, tented both sides, 182 vias
v10: diameter 0.254, hole 0.1, L14 (Sign) to L16, tented both sides, 170 vias
v11: diameter 0.75/0/0/0/0/0/0/0/0/0/0/0/0/0/0/0.75 (per signal layer), hole 0.4, L1 to L16, 160 vias
v12: diameter 0.457, hole 0.2, L3 (Sign) to L6 (PWR/GND), 158 vias
v13: diameter 1.4, hole 0.5, L1 to L16, tented both sides, 80 vias
v14: diameter 0.254, hole 0.1, L14 (Sign) to L16, 65 vias
v15: diameter 0.254, hole 0.1, L1 to L2 (GND), 45 vias
v16: diameter 0.457, hole 0.2, L11 (PWR/GND) to L14 (Sign), tented both sides, 26 vias
v17: diameter 0.457, hole 0.2, L11 (PWR/GND) to L14 (Sign), 25 vias
v18: diameter 0.457, hole 0.2, L7(12V+Other) to L10 (3V3+Other), tented both sides, 11 vias
v19: diameter 0.254/0/0.254 (per signal layer), hole 0.1, L1 to L3 (Sign), 9 vias
v20: diameter 0.2/0/0.2 (per signal layer), hole 0.1, L1 to L3 (Sign), 6 vias
v21: diameter 1.65, hole 1.65, L1 to L16, 5 vias
v22: diameter 1.15, hole 1.15, L1 to L16, 5 vias
v23: diameter 0.457, hole 0.2, L1 to L16, 3 vias
v24: diameter 0.5, hole 0.3, L1 to L16, 2 vias
v25: diameter 0.5/0/0.5 (per signal layer), hole 0.2, L14 (Sign) to L16, 1 vias
v26: diameter 0.5, hole 0.25, L1 to L16, tented bottom, 1 vias

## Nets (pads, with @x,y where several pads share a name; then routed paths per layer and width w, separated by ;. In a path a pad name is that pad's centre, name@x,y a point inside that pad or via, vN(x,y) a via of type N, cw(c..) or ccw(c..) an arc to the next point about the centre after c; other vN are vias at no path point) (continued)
DDR4_DQS_4_P: U1.W24 U9.G3 | length 38.8
  L1 w0.116: v1(170.472,332.457) U9.G3@170.876,332.86 ; U1.W24@180.397,311.539 v1(180.884,312.027)
  L14 (Sign) w0.105: v1(170.472,332.457) ccw(c170.756,332.457) 170.756,332.173 170.833,332.173 cw(c170.833,331.943) 170.995,332.106 171.064,332.037 ccw(c171.371,332.345) 171.371,331.91 174.148,331.91 cw(c174.148,331.305) 174.752,331.305 174.752,330.149 174.752,327.921 ccw(c177.292,327.921) 175.496,326.125 175.661,325.961 175.78,325.842 ccw(c175.944,326.006) 176.109,325.842 176.923,326.655 176.927,326.655 cw(c177.217,326.292) 177.546,326.621 ; 174.996,323.132 ccw(c175.16,322.968) 174.995,322.804 175.137,322.662 ccw(c175.301,322.827) 175.465,322.662 178.027,325.224 cw(c178.356,324.895) 178.685,325.224 ; 174.997,323.133 177.686,325.822 ; 177.547,326.62 177.686,326.481 ; 177.686,325.823 ccw(c177.358,326.152) 177.686,326.481 ; 178.175,323.446 cw(c178.339,323.611) 178.175,323.776 ; 178.175,323.446 178.628,322.994 ; 178.175,323.776 178.825,324.425 ccw(c178.497,324.755) 178.825,325.084 ; 178.628,322.993 178.747,322.874 178.819,322.802 cw(c176.863,320.847) 179.629,320.847 179.629,314.481 ccw(c181.803,314.481) 180.266,312.943 180.268,312.941 cw(c179.675,312.349) 180.513,312.349 180.513,312.226 ccw(c180.712,312.226) 180.712,312.027 v1(180.884,312.027) ; 178.685,325.223 178.825,325.084
DDR4_DQS_5_N: U1.R25 U9.A4 | length 30.7
  L1 w0.116: U9.A4@167.676,328.06 v1(168.079,327.657) ; v1(175.909,312.052) U1.R25@176.397,312.539
  L14 (Sign) w0.105: v1(168.079,327.657) 168.079,327.669 cw(c168.351,327.669) 168.351,327.941 168.517,327.941 cw(c168.517,326.972) 169.202,327.657 171.933,324.926 cw(c170.137,323.13) 172.677,323.13 172.677,322.082 172.677,321.913 ccw(c173.015,321.913) 173.015,321.575 176.58,321.575 cw(c176.58,321.473) 176.682,321.473 176.682,321.166 cw(c176.58,321.166) 176.58,321.063 173.015,321.063 ccw(c173.015,320.726) 172.677,320.726 172.677,319.327 172.677,319 ccw(c173.186,319) 173.186,318.492 174.752,318.492 cw(c174.752,318.175) 175.069,318.175 175.069,315.247 ccw(c175.548,315.247) 175.548,314.768 cw(c175.548,314.471) 175.845,314.471 175.845,314.029 cw(c175.496,314.029) 175.496,313.681 ccw(c175.496,313.164) 174.98,313.164 174.98,313.002 ccw(c175.558,313.002) 175.558,312.423 175.603,312.423 cw(c175.603,312.117) 175.909,312.117 v1(175.909,312.052)
DDR4_DQS_5_P: U1.P25 U9.B4 | length 30.6
  L1 w0.116: U9.B4@167.676,328.86 v1(168.079,328.457) ; U1.P25@175.397,312.539 v1(175.845,312.987)
  L14 (Sign) w0.105: v1(168.079,328.457) 168.079,328.445 ccw(c168.351,328.445) 168.351,328.173 168.518,328.173 cw(c168.518,326.975) 169.365,327.822 172.099,325.088 cw(c170.144,323.132) 172.909,323.132 172.909,322.082 172.909,321.913 ccw(c173.015,321.913) 173.015,321.808 176.58,321.808 cw(c176.58,321.473) 176.914,321.473 176.914,321.166 cw(c176.58,321.166) 176.58,320.831 173.015,320.831 ccw(c173.015,320.726) 172.909,320.726 172.909,319.327 172.909,319 ccw(c173.186,319) 173.186,318.724 174.752,318.724 cw(c174.752,318.175) 175.301,318.175 175.301,315.247 ccw(c175.548,315.247) 175.548,315 cw(c175.548,314.471) 176.077,314.471 176.077,314.029 cw(c175.496,314.029) 175.496,313.449 ccw(c175.496,313.164) 175.212,313.164 175.212,313.002 ccw(c175.558,313.002) 175.558,312.656 175.603,312.656 ccw(c175.603,312.937) 175.884,312.937 175.884,312.947 v1(175.845,312.987)
DDR4_DQS_6_N: U1.V29 U11.F3 | length 26.5
  L1 w0.116: v1(181.933,331.657) U11.F3@182.336,332.06
  L1 w0.124: v3(178.91,317.027) U1.V29@179.397,316.539
  L5 (Sign) w0.105: v3(178.91,317.027) 178.745,317.027 cw(c178.745,317.246) 178.526,317.246 178.526,317.677 ccw(c178.125,317.677) 178.125,318.077 177.815,318.077 cw(c177.815,318.245) 177.647,318.245 177.647,318.624 cw(c177.815,318.624) 177.815,318.792 179.004,318.792 ccw(c179.004,319.192) 179.404,319.192 179.404,319.571 ccw(c179.004,319.571) 179.004,319.971 177.815,319.971 cw(c177.815,320.139) 177.647,320.139 177.647,320.518 cw(c177.815,320.518) 177.815,320.686 179.004,320.686 ccw(c179.004,321.086) 179.404,321.086 179.404,321.465 ccw(c179.004,321.465) 179.004,321.865 177.815,321.865 cw(c177.815,322.033) 177.647,322.033 177.647,322.412 cw(c177.815,322.412) 177.815,322.58 178.125,322.58 ccw(c178.125,322.981) 178.526,322.981 178.526,323.632 cw(c179.565,323.632) 179.565,324.672 ccw(c179.565,325.777) 180.67,325.777 180.67,330.835 180.67,331.044 cw(c180.747,331.044) 180.747,331.121 ccw(c180.747,331.199) 180.824,331.199 180.824,331.353 ccw(c180.747,331.353) 180.747,331.43 cw(c180.747,331.507) 180.67,331.507 180.67,331.584 cw(c181.026,331.584) 181.026,331.94 181.65,331.94 cw(c181.65,331.657) v1(181.933,331.657)
DDR4_DQS_6_P: U1.U29 U11.G3 | length 26.6
  L1 w0.116: v1(181.933,332.457) U11.G3@182.336,332.86
  L1 w0.124: v3(177.91,317.027) U1.U29@178.397,316.539
  L5 (Sign) w0.105: v3(177.91,317.027) 178.075,317.027 ccw(c178.075,317.245) 178.293,317.245 178.293,317.677 ccw(c178.125,317.677) 178.125,317.845 177.815,317.845 cw(c177.815,318.245) 177.415,318.245 177.415,318.624 cw(c177.815,318.624) 177.815,319.024 179.004,319.024 ccw(c179.004,319.192) 179.172,319.192 179.172,319.571 ccw(c179.004,319.571) 179.004,319.739 177.815,319.739 cw(c177.815,320.139) 177.415,320.139 177.415,320.518 cw(c177.815,320.518) 177.815,320.918 179.004,320.918 ccw(c179.004,321.086) 179.172,321.086 179.172,321.465 ccw(c179.004,321.465) 179.004,321.633 177.815,321.633 cw(c177.815,322.033) 177.415,322.033 177.415,322.412 cw(c177.815,322.412) 177.815,322.812 178.125,322.812 ccw(c178.125,322.981) 178.293,322.981 178.293,323.632 cw(c179.565,323.632) 179.565,324.904 ccw(c179.565,325.777) 180.438,325.777 180.438,331.584 cw(c181.026,331.584) 181.026,332.172 181.648,332.172 ccw(c181.648,332.457) v1@181.933,332.457
DDR4_DQS_7_N: U1.R29 U11.A4 | length 19.7
  L1 w0.116: U11.A4@179.136,328.06 v1(179.54,327.657)
  L1 w0.124: v3(175.91,317.027) U1.R29@176.397,316.539
  L5 (Sign) w0.105: v3(175.91,317.027) 175.91,317.01 cw(c175.542,317.01) 175.542,316.643 cw(c175.542,317.128) 175.057,317.128 175.057,317.308 175.057,317.541 cw(c175.183,317.541) 175.183,317.667 175.283,317.667 ccw(c175.283,317.793) 175.409,317.793 175.409,317.901 ccw(c175.283,317.901) 175.283,318.026 175.183,318.026 cw(c175.183,318.152) 175.057,318.152 175.057,318.237 175.057,323.254 ccw(c174.663,323.254) 174.663,323.649 174.602,323.649 cw(c174.602,323.811) 174.44,323.811 174.44,324.049 cw(c174.602,324.049) 174.602,324.211 175.28,324.211 ccw(c175.28,324.605) 175.674,324.605 175.674,324.844 ccw(c175.28,324.844) 175.28,325.238 175.219,325.238 cw(c175.219,325.4) 175.057,325.4 175.057,325.688 cw(c175.781,325.688) 175.781,326.412 175.96,326.412 176.194,326.412 cw(c176.194,326.286) 176.32,326.286 ccw(c176.446,326.286) 176.446,326.16 176.553,326.16 ccw(c176.553,326.286) 176.679,326.286 cw(c176.805,326.286) 176.805,326.412 177.356,326.412 177.508,326.412 ccw(c177.508,327.225) 178.321,327.225 178.321,327.406 cw(c178.855,327.406) 178.855,327.941 179.286,327.941 cw(c179.286,327.687) 179.54,327.687 v1(179.54,327.657)
DDR4_DQS_7_P: U1.R28 U11.B4 | length 19.7
  L1 w0.116: U11.B4@179.136,328.86 v1(179.54,328.457)
  L1 w0.124: v3(175.91,316.027) U1.R28@176.397,315.539
  L5 (Sign) w0.105: v3(175.91,316.027) 175.91,316.043 ccw(c175.542,316.043) 175.542,316.411 cw(c175.542,317.128) 174.825,317.128 174.825,323.254 ccw(c174.663,323.254) 174.663,323.416 174.602,323.416 cw(c174.602,323.811) 174.207,323.811 174.207,324.049 cw(c174.602,324.049) 174.602,324.443 175.28,324.443 ccw(c175.28,324.605) 175.442,324.605 175.442,324.844 ccw(c175.28,324.844) 175.28,325.006 175.219,325.006 cw(c175.219,325.4) 174.825,325.4 174.825,325.688 cw(c175.781,325.688) 175.781,326.644 177.508,326.644 ccw(c177.508,327.225) 178.089,327.225 178.089,327.406 cw(c178.855,327.406) 178.855,328.173 179.286,328.173 ccw(c179.286,328.427) 179.54,328.427 v1(179.54,328.457)
DDR4_DQS_8_N: U1.AA28
DDR4_DQS_8_P: U1.Y28
DDR4_DQS_ODT0: R44.1 U1.AB30 U8.K3 U9.K3 U10.K3 U11.K3 | length 110.6
  L1 w0.1: v1(170.472,334.857) U9.K3@170.876,335.26 ; v1(181.933,334.857) U11.K3@182.336,335.26 ; U1.AB30@183.397,317.539 v2(183.884,317.052) ; v1(193.393,334.857) U10.K3@193.797,335.26 ; U8.K3@205.257,335.26 205.637,334.881 v1(205.637,334.873)
  L1 w0.155: v1(163.977,343.555) R44.1@163.977,344.75 R44.1@163.977,344.8
  L5 (Sign) w0.081: 167.145,342.062 167.361,342.062 167.944,341.478 167.944,341.002 168.974,339.971 168.974,335.493 169.61,334.857 v1(170.472,334.857) 170.709,334.857 171.12,335.267 173.139,335.267 173.954,334.453 174.38,334.453 cw(c174.38,334.337) 174.496,334.337 174.496,334.154 ccw(c174.612,334.154) 174.612,334.039 174.766,334.039 ccw(c174.766,334.154) 174.882,334.154 174.882,334.39 cw(c174.998,334.39) 174.998,334.506 175.152,334.506 cw(c175.152,334.39) 175.268,334.39 175.268,334.233 ccw(c175.384,334.233) 175.384,334.118 175.538,334.118 ccw(c175.538,334.233) 175.654,334.233 175.654,334.337 cw(c175.77,334.337) 175.77,334.453 176.111,334.453 178.208,334.453 178.601,334.06 178.751,334.06 cw(c178.751,333.945) 178.867,333.945 178.867,333.798 ccw(c178.982,333.798) 178.982,333.682 179.137,333.682 ccw(c179.137,333.798) 179.253,333.798 179.253,333.945 cw(c179.368,333.945) 179.368,334.06 179.678,334.06 180.755,334.06 181.551,334.857 v1(181.933,334.857) 182.566,334.857 182.771,335.062 183.193,335.062 183.378,335.247 183.727,335.247 183.747,335.267 183.949,335.066 183.949,334.77 184.517,334.202 185.228,334.202 185.77,333.66 186.196,333.66 cw(c186.196,333.545) 186.312,333.545 186.312,333.248 ccw(c186.428,333.248) 186.428,333.132 186.582,333.132 ccw(c186.582,333.248) 186.698,333.248 186.698,333.776 cw(c186.814,333.776) 186.814,333.892 186.968,333.892 cw(c186.968,333.776) 187.084,333.776 ccw(c187.2,333.776) 187.2,333.66 187.535,333.66 191.687,333.66 192.884,334.857 v1(193.393,334.857) 194.029,334.857 194.434,335.262 195.863,335.262 196.91,334.215 197.583,334.215 197.623,334.215 ccw(c197.623,334.299) 197.707,334.299 197.707,334.494 cw(c197.791,334.494) 197.791,334.577 197.958,334.577 cw(c197.958,334.494) 198.042,334.494 198.042,333.717 ccw(c198.126,333.717) 198.126,333.633 198.294,333.633 ccw(c198.294,333.717) 198.377,333.717 198.377,334.275 cw(c198.461,334.275) 198.461,334.359 198.629,334.359 cw(c198.629,334.275) 198.713,334.275 198.713,333.801 ccw(c198.796,333.801) 198.796,333.717 198.964,333.717 ccw(c198.964,333.801) 199.048,333.801 199.048,334.131 cw(c199.132,334.131) 199.132,334.215 199.376,334.215 200.186,334.215 201.424,335.453 204.276,335.453 204.856,334.873 v1(205.637,334.873)
  L5 (Sign) w0.151: v1(163.977,343.555) 163.977,342.74 164.655,342.062 167.145,342.062
  L3 (Sign) w0.079: 186.28,313.315 186.349,313.247 186.349,312.68 186.43,312.599 ; v1(205.637,334.873) 206.055,334.454
  L3 (Sign) w0.081: v2(183.884,317.052) 184.243,317.411 184.979,317.411 185.205,317.185 185.205,316.482 186.422,315.264 186.422,314.708 186.421,314.706 186.418,314.706 186.066,314.354 185.884,314.354 185.696,314.166 185.696,313.9 186.28,313.315 ; 186.43,312.599 186.495,312.599 188.582,310.511 189.521,310.511 189.627,310.405 192.32,310.405 192.397,310.482 ; 205.578,326.785 205.578,327.676 206.055,328.153 206.055,331.953 206.055,333.107 206.098,333.15 206.098,334.411 206.055,334.454
  L3 (Sign) w0.171: 205.578,324.792 205.578,325.102 205.578,325.663 cw(c205.749,325.663) 205.749,325.834 206.629,325.834 ccw(c206.629,325.953) 206.748,325.953 206.748,326.191 ccw(c206.629,326.191) 206.629,326.31 205.749,326.31 cw(c205.749,326.481) 205.578,326.481 205.578,326.785
  L3 (Sign) w0.172: 192.397,310.482 193.217,311.302 195.797,311.302 205.578,321.083 205.578,324.792
DDR4_DQS_ODT1: U1.AC29
DDR4_PARITY: R42.1 U1.AB26 U8.T3 U9.T3 U10.T3 U11.T3 | length 102.1
  L1 w0.1: v1(170.472,340.464) U9.T3@170.876,340.06 ; v1(181.933,340.464) U11.T3@182.336,340.06 ; v2(182.909,314.027) U1.AB26@183.397,313.539 ; v1(193.393,340.464) U10.T3@193.797,340.06 ; v1(204.853,340.464) U8.T3@205.257,340.06
  L1 w0.155: v2(172.438,343.555) R42.1@172.438,344.75 R42.1@172.438,344.799
  L5 (Sign) w0.081: v1(170.472,340.464) 171.401,341.393 171.705,341.393 173.149,342.837 174.992,342.837 175.033,342.837 ccw(c175.033,342.952) 175.149,342.952 175.149,343.546 cw(c175.264,343.546) 175.264,343.661 175.419,343.661 cw(c175.419,343.546) 175.535,343.546 175.535,342.699 ccw(c175.65,342.699) 175.65,342.583 175.805,342.583 ccw(c175.805,342.699) 175.921,342.699 175.921,342.721 cw(c176.036,342.721) 176.036,342.837 176.472,342.837 179.56,342.837 v1(181.933,340.464) 183.734,342.265 188.493,342.265 189.337,342.265 ccw(c189.337,342.334) 189.406,342.334 189.406,342.488 cw(c189.475,342.488) 189.475,342.557 189.683,342.557 cw(c189.683,342.488) 189.752,342.488 189.752,342.265 189.752,342.187 ccw(c189.821,342.187) 189.821,342.118 190.029,342.118 ccw(c190.029,342.187) 190.098,342.187 190.098,342.196 cw(c190.168,342.196) 190.168,342.265 190.271,342.265 191.592,342.265 191.621,342.236 ccw(c191.702,342.318) 191.784,342.236 191.879,342.331 cw(c191.961,342.25) 192.043,342.331 192.152,342.222 cw(c192.071,342.14) 192.152,342.059 192.057,341.963 ccw(c192.139,341.882) 192.057,341.8 192.423,341.434 v1(193.393,340.464) 193.568,340.639 193.943,340.639 194.285,340.982 194.285,342.24 194.956,342.911 196.973,342.911 197.37,343.309 200.416,343.309 200.863,342.862 203.346,342.862 203.387,342.862 ccw(c203.387,342.946) 203.471,342.946 203.471,343.504 cw(c203.555,343.504) 203.555,343.588 203.722,343.588 cw(c203.722,343.504) 203.806,343.504 203.806,342.946 ccw(c203.89,342.946) 203.89,342.862 204.191,342.862 204.853,342.199 v1(204.853,340.464)
  L3 (Sign) w0.079: 189.804,326.785 189.804,330.218 190.171,330.586 190.171,330.805
  L3 (Sign) w0.081: v1(170.472,340.464) 171.013,341.005 171.013,341.734 172.428,343.149 v2@172.428,343.545 ; v2(182.909,314.027) 183.49,314.607 183.49,316.403 183.179,316.713 183.179,317.344 184.061,318.226 184.061,318.539 ; 190.171,330.805 190.592,331.226 190.592,332.996 190.956,333.36 190.985,333.389 ccw(c190.925,333.448) 190.985,333.507 190.776,333.716 cw(c190.835,333.775) 190.776,333.835 190.894,333.953 cw(c190.954,333.894) 191.013,333.953 191.369,333.597 ccw(c191.428,333.656) 191.488,333.597 191.606,333.715 ccw(c191.547,333.775) 191.606,333.834 191.202,334.238 cw(c191.262,334.297) 191.202,334.356 191.321,334.475 cw(c191.38,334.415) 191.439,334.475 191.847,334.067 ccw(c191.906,334.126) 191.966,334.067 192.084,334.186 ccw(c192.025,334.245) 192.084,334.304 191.676,334.712 cw(c191.736,334.771) 191.676,334.83 191.795,334.949 cw(c191.854,334.89) 191.913,334.949 192.321,334.541 ccw(c192.38,334.6) 192.44,334.541 192.558,334.66 ccw(c192.499,334.719) 192.558,334.778 192.525,334.811 cw(c192.585,334.87) 192.525,334.93 192.643,335.047 192.643,336.123 193.178,336.658 195.949,336.658 199.3,340.009 199.564,340.009 201.059,341.503 203.814,341.503 v1(204.853,340.464)
  L3 (Sign) w0.171: 189.751,326.678 189.804,326.731 189.804,326.785
  L3 (Sign) w0.172: 184.061,318.539 184.061,318.922 189.751,324.612 ; 189.751,325.929 189.751,326.678
  L3 (Sign) w0.173: 189.751,324.612 189.751,324.801 ccw(c189.625,324.801) 189.625,324.927 188.498,324.927 cw(c188.498,325.053) 188.372,325.053 188.372,325.431 cw(c188.498,325.431) 188.498,325.557 189.625,325.557 ccw(c189.625,325.683) 189.751,325.683 189.751,325.929
DDR4_RAM_RST_N: R60.1 U1.AB25 U8.P1 U9.P1 U10.P1 U11.P1 | length 117.1
  L1 w0.1: U9.P1@172.476,338.46 v2(172.879,338.864) ; U1.AB25@183.397,312.539 v2(183.884,313.027) ; U11.P1@183.936,338.46 v2(184.34,338.864) ; U10.P1@195.397,338.46 v1(195.8,338.864) ; U8.P1@206.857,338.46 v1(207.261,338.864)
  L1 w0.155: v2(179.689,343.555) R60.1@179.689,344.799
  L3 (Sign) w0.079: v2(183.884,313.027) 183.884,312.731 183.693,312.539 183.693,312.298 183.593,312.199 183.593,311.958 183.944,311.607 184.708,311.607 184.823,311.491 185.331,311.491 185.446,311.376 185.446,311.375 185.562,311.259 ; 186.28,310.757 186.28,310.422 186.349,310.354 186.349,309.68 186.443,309.586 187.935,309.586 188.029,309.491 188.066,309.491 188.135,309.423 189.634,309.423 189.702,309.491 192.304,309.491 192.397,309.398
  L3 (Sign) w0.081: v2(179.689,343.555) 178.133,341.998 177.696,341.998 176.449,340.751 175.543,340.751 174.052,339.26 173.276,339.26 v2(172.879,338.864) 174.191,338.864 174.229,338.902 174.531,339.204 cw(c174.612,339.122) 174.694,339.204 174.934,338.964 ccw(c175.016,339.046) 175.098,338.964 175.207,339.073 ccw(c175.125,339.155) 175.207,339.237 174.967,339.477 cw(c175.049,339.559) 174.967,339.641 175.387,340.06 175.428,340.06 ccw(c175.428,340.176) 175.543,340.176 175.543,340.407 cw(c175.659,340.407) 175.659,340.523 175.814,340.523 cw(c175.814,340.407) 175.929,340.407 175.929,340.176 ccw(c176.045,340.176) 176.045,340.06 176.397,340.06 179.143,340.06 179.184,340.06 ccw(c179.184,340.176) 179.3,340.176 179.3,340.626 cw(c179.415,340.626) 179.415,340.742 179.57,340.742 cw(c179.57,340.626) 179.686,340.626 179.686,340.176 ccw(c179.801,340.176) 179.801,340.06 179.992,340.06 180.792,339.26 183.943,339.26 v2(184.34,338.864) 184.736,339.26 185.89,339.26 186.849,339.26 cw(c186.849,339.171) 186.939,339.171 186.939,338.851 ccw(c187.028,338.851) 187.028,338.762 187.297,338.762 ccw(c187.297,338.851) 187.387,338.851 187.387,339.26 187.387,339.67 cw(c187.476,339.67) 187.476,339.759 187.745,339.759 cw(c187.745,339.67) 187.834,339.67 187.834,339.26 187.834,338.851 ccw(c187.924,338.851) 187.924,338.762 188.193,338.762 ccw(c188.193,338.851) 188.282,338.851 188.282,339.171 cw(c188.372,339.171) 188.372,339.26 188.506,339.26 195.404,339.26 v1(195.8,338.864) 196.148,338.864 197.528,340.244 198.692,340.244 198.786,340.338 198.786,340.34 200.506,342.061 203.906,342.061 203.946,342.061 ccw(c203.946,342.145) 204.03,342.145 204.03,342.231 cw(c204.114,342.231) 204.114,342.315 204.281,342.315 cw(c204.281,342.231) 204.365,342.231 204.365,342.145 ccw(c204.449,342.145) 204.449,342.061 204.863,342.061 205.589,341.335 205.855,341.07 cw(c205.795,341.01) 205.855,340.951 205.846,340.942 ccw(c205.905,340.883) 205.846,340.824 205.964,340.705 ccw(c206.024,340.765) 206.083,340.705 206.531,341.154 cw(c206.59,341.095) 206.65,341.154 206.768,341.035 cw(c206.709,340.976) 206.768,340.917 206.202,340.351 ccw(c206.261,340.291) 206.202,340.232 206.321,340.114 ccw(c206.38,340.173) 206.439,340.114 206.566,340.24 cw(c206.625,340.181) 206.684,340.24 206.848,340.077 206.851,340.073 206.851,339.282 207.261,338.872 v1(207.261,338.864) 207.932,338.193 ; 185.562,311.259 185.813,311.008 186.029,311.008 186.28,310.757
  L3 (Sign) w0.172: 192.397,309.398 195.07,309.398 209.194,323.522 209.194,326.83 209.194,326.916 ccw(c209.022,326.916) 209.022,327.088 208.782,327.088 cw(c208.782,327.234) 208.636,327.234 208.636,327.672 cw(c208.782,327.672) 208.782,327.818 209.607,327.818 ccw(c209.607,327.965) 209.753,327.965 209.753,328.403 ccw(c209.607,328.403) 209.607,328.549 208.782,328.549 cw(c208.782,328.695) 208.636,328.695 208.636,329.134 cw(c208.782,329.134) 208.782,329.28 209.607,329.28 ccw(c209.607,329.426) 209.753,329.426 209.753,329.865 ccw(c209.607,329.865) 209.607,330.011 208.782,330.011 cw(c208.782,330.157) 208.636,330.157 208.636,330.595 cw(c208.782,330.595) 208.782,330.742 209.458,330.742 ccw(c209.458,330.888) 209.604,330.888 209.604,331.326 ccw(c209.458,331.326) 209.458,331.472 208.837,331.472 cw(c208.837,331.619) 208.691,331.619 208.691,332.057 cw(c208.837,332.057) 208.837,332.203 209.366,332.203 ccw(c209.366,332.349) 209.513,332.349 209.513,332.788 ccw(c209.366,332.788) 209.366,332.934 cw(c209.366,333.106) 209.194,333.106 209.194,336.93 207.932,338.193
DDR4_RAS: R59.1 U1.AH27 U8.L5 U9.L5 U10.L5 U11.L5 | length 102.5
  L1 w0.1: U9.L5@166.876,336.06 167.272,336.457 v1(167.275,336.457) ; U11.L5@178.336,336.06 178.733,336.457 v1(178.735,336.457) ; U1.AH27@189.397,314.539 v2(189.884,315.027) ; U10.L5@189.797,336.06 190.193,336.457 v1(190.195,336.457) ; U8.L5@201.257,336.06 201.653,336.457 v1(201.656,336.457)
  L1 w0.155: R59.1@158.737,334.7 R59.1@158.787,334.7 v1(159.982,334.7)
  L12 (Sign) w0.081: 165.251,335.562 165.863,335.562 166.758,336.457 v1(167.275,336.457) 167.323,336.457 167.713,336.847 168.405,336.847 168.491,336.847 168.913,336.425 cw(c168.831,336.343) 168.947,336.343 168.947,335.427 ccw(c169.063,335.427) 169.063,335.311 169.217,335.311 ccw(c169.217,335.427) 169.333,335.427 169.333,336.02 cw(c169.449,336.02) 169.449,336.136 169.989,336.136 170.506,336.136 170.932,336.136 cw(c170.932,336.02) 171.048,336.02 171.048,335.805 ccw(c171.164,335.805) 171.164,335.69 171.318,335.69 ccw(c171.318,335.805) 171.434,335.805 171.434,336.02 cw(c171.55,336.02) 171.55,336.136 171.828,336.136 173.551,336.136 176.178,336.136 176.461,336.419 176.499,336.457 v1(178.735,336.457) 178.977,336.457 179.349,336.829 179.367,336.847 179.759,336.847 179.828,336.778 180.214,336.778 180.815,336.176 181.578,336.176 183.925,336.176 184.041,336.06 185.356,336.06 185.397,336.06 ccw(c185.397,336.176) 185.513,336.176 185.513,336.376 cw(c185.629,336.376) 185.629,336.492 185.783,336.492 cw(c185.783,336.376) 185.899,336.376 185.899,335.504 ccw(c186.015,335.504) 186.015,335.388 186.169,335.388 ccw(c186.169,335.504) 186.285,335.504 186.285,335.945 cw(c186.401,335.945) 186.401,336.06 186.662,336.06 187.868,336.06 189.282,336.06 189.679,336.457 v1(190.195,336.457) 190.244,336.457 190.634,336.847 191.157,336.847 191.771,336.234 192.147,336.234 cw(c192.147,336.15) 192.23,336.15 192.23,335.835 ccw(c192.314,335.835) 192.314,335.751 192.482,335.751 ccw(c192.482,335.835) 192.566,335.835 192.566,336.15 cw(c192.649,336.15) 192.649,336.234 192.906,336.234 197.173,336.234 197.295,336.112 198.901,336.112 199.89,336.112 200.266,336.112 cw(c200.266,335.994) 200.383,335.994 200.383,335.714 ccw(c200.5,335.714) 200.5,335.597 200.601,335.597 ccw(c200.601,335.714) 200.718,335.714 200.718,335.994 cw(c200.835,335.994) 200.835,336.112 201.062,336.112 201.11,336.112 201.427,336.429 201.628,336.429 v1(201.656,336.457)
  L12 (Sign) w0.151: v1(159.982,334.7) 160.395,335.113 163.503,335.113 163.952,335.562 165.251,335.562
  L3 (Sign) w0.079: 201.224,335.03 201.224,334.753 201.243,334.734 201.243,334.604 201.243,334.377 ccw(c201.326,334.377) 201.326,334.293 201.788,334.293 cw(c201.788,334.21) 201.872,334.21 201.872,334.044 cw(c201.788,334.044) 201.788,333.96 201.326,333.96 ccw(c201.326,333.877) 201.243,333.877 201.243,332.838 ; 201.243,330.521 201.293,330.471 201.293,329.991 201.293,329.952 ccw(c201.376,329.952) 201.376,329.869 201.794,329.869 cw(c201.794,329.785) 201.877,329.785 201.877,329.619 cw(c201.794,329.619) 201.794,329.535 200.769,329.535 ccw(c200.769,329.452) 200.686,329.452 200.686,329.286 ccw(c200.769,329.286) 200.769,329.202 201.794,329.202 cw(c201.794,329.119) 201.877,329.119 201.877,328.953 cw(c201.794,328.953) 201.794,328.869 201.376,328.869 ccw(c201.376,328.786) 201.293,328.786 201.293,328.285
  L3 (Sign) w0.081: v2(189.884,315.027) 190.193,315.336 190.193,316.211 190.496,316.514 190.938,316.514 192.269,316.514 192.348,316.593 192.397,316.593 ; 201.224,335.03 201.371,335.177 201.371,335.877 201.656,336.162 v1(201.656,336.457) ; 201.243,332.838 201.243,332.665 201.244,332.664 201.244,332.321 201.244,331.902 ccw(c201.325,331.902) 201.325,331.821 201.664,331.821 cw(c201.664,331.763) 201.722,331.763 201.722,331.646 cw(c201.664,331.646) 201.664,331.587 201.325,331.587 ccw(c201.325,331.506) 201.244,331.506 201.244,331.232 ; 201.244,330.521 201.244,331.232 ; 201.244,331.041 201.244,331.232 ; 201.293,326.785 201.293,327.075 201.293,327.116 ccw(c201.212,327.116) 201.212,327.197 200.714,327.197 cw(c200.714,327.268) 200.643,327.268 200.643,327.41 cw(c200.714,327.41) 200.714,327.481 201.799,327.481 ccw(c201.799,327.552) 201.871,327.552 201.871,327.694 ccw(c201.799,327.694) 201.799,327.766 200.714,327.766 cw(c200.714,327.837) 200.643,327.837 200.643,327.979 cw(c200.714,327.979) 200.714,328.05 201.212,328.05 ccw(c201.212,328.131) 201.293,328.131 201.293,328.285
  L3 (Sign) w0.171: 192.397,316.593 193.195,316.593 193.429,316.828 193.489,316.888 ccw(c193.369,317.009) 193.489,317.13 193.295,317.324 cw(c193.388,317.418) 193.295,317.511 193.481,317.697 cw(c193.574,317.604) 193.667,317.697 193.974,317.39 ccw(c194.067,317.483) 194.16,317.39 194.347,317.577 ccw(c194.253,317.67) 194.347,317.763 194.04,318.069 cw(c194.133,318.163) 194.04,318.256 194.226,318.442 cw(c194.319,318.349) 194.412,318.442 194.712,318.142 ccw(c194.805,318.235) 194.899,318.142 195.085,318.328 ccw(c194.992,318.422) 195.085,318.515 194.785,318.814 cw(c194.878,318.908) 194.785,319.001 194.971,319.187 cw(c195.064,319.094) 195.157,319.187 195.457,318.888 ccw(c195.55,318.981) 195.643,318.888 195.829,319.074 ccw(c195.736,319.167) 195.829,319.26 195.53,319.559 cw(c195.623,319.653) 195.53,319.746 195.716,319.932 cw(c195.809,319.839) 195.902,319.932 196.201,319.633 ccw(c196.295,319.726) 196.388,319.633 196.574,319.819 ccw(c196.481,319.912) 196.574,320.005 196.275,320.304 cw(c196.368,320.398) 196.275,320.491 196.461,320.677 cw(c196.554,320.584) 196.648,320.677 196.946,320.378 ccw(c197.039,320.471) 197.132,320.378 197.319,320.565 ccw(c197.226,320.658) 197.319,320.751 197.02,321.049 cw(c197.113,321.143) 197.02,321.236 197.206,321.422 cw(c197.299,321.329) 197.393,321.422 197.691,321.124 ccw(c197.784,321.217) 197.877,321.124 198.063,321.31 ccw(c197.97,321.403) 198.063,321.496 197.765,321.795 cw(c197.858,321.888) 197.765,321.981 197.951,322.167 cw(c198.044,322.074) 198.138,322.167 198.436,321.869 ccw(c198.529,321.962) 198.622,321.869 198.808,322.055 ccw(c198.715,322.148) 198.808,322.241 198.51,322.54 cw(c198.603,322.633) 198.51,322.726 198.696,322.912 cw(c198.789,322.819) 198.883,322.912 199.18,322.614 ccw(c199.274,322.707) 199.367,322.614 199.553,322.8 ccw(c199.46,322.894) 199.553,322.987 199.255,323.285 cw(c199.348,323.378) 199.255,323.471 199.441,323.657 cw(c199.534,323.564) 199.628,323.657 199.925,323.359 ccw(c200.018,323.453) 200.111,323.359 200.298,323.546 ccw(c200.205,323.639) 200.298,323.732 199.969,324.061 cw(c200.062,324.154) 199.969,324.247 200.155,324.433 cw(c200.248,324.34) 200.341,324.433 200.567,324.208 ccw(c200.688,324.328) 200.809,324.208 201.293,324.692 201.293,326.785
DDR4_TEN: R56.1 U8.N6 U9.N6 U10.N6 U11.N6 | length 42.1
  L1 w0.1: 165.251,338.056 v2(165.665,338.056) U9.N6@166.068,337.653 ; v2(177.125,338.056) U11.N6@177.529,337.653 ; v2(188.586,338.056) U10.N6@188.989,337.653 ; v2(197.878,339.319) 199.536,337.66 U8.N6@200.457,337.66
  L1 w0.155: R56.1@163.36,338.184 164.159,338.184 164.287,338.056 165.251,338.056
  L3 (Sign) w0.081: v2(165.665,338.056) 166.061,337.66 168.338,337.66 169.439,336.56 175.628,336.56 176.729,337.66 v2(177.125,338.056) 177.521,337.66 183.136,337.66 183.143,337.668 188.197,337.668 v2(188.586,338.056) 188.982,337.66 191.479,337.66 191.651,337.833 192.222,337.833 192.387,337.668 196.227,337.668 v2(197.878,339.319)
DDR4_WE: R55.1 U1.AG29 U8.L2 U9.L2 U10.L2 U11.L2 | length 111.8
  L1 w0.1: U9.L2@171.676,336.06 v1(172.076,335.66) ; U11.L2@183.136,336.06 v1(183.54,335.657) ; U1.AG29@188.397,316.539 188.811,316.125 188.798,316.113 v2(188.798,316.09) ; U10.L2@194.597,336.06 194.997,335.66 v1(194.997,335.652) ; v1(205.675,336.451) 205.702,336.451 206.075,336.078 U8.L2@206.057,336.06
  L1 w0.155: v1(165.186,343.555) R55.1@165.186,344.8
  L5 (Sign) w0.081: 165.535,342.544 167.529,342.544 168.291,341.782 168.291,341.007 169.155,340.143 169.155,335.568 169.594,335.129 170.093,335.129 170.212,335.247 170.634,335.247 170.635,335.246 170.686,335.246 171.097,335.657 172.076,335.657 173.34,335.657 174.157,334.84 174.416,334.84 174.457,334.84 ccw(c174.457,334.956) 174.573,334.956 174.573,334.964 cw(c174.688,334.964) 174.688,335.079 174.843,335.079 cw(c174.843,334.964) 174.959,334.964 174.959,334.803 ccw(c175.074,334.803) 175.074,334.687 175.229,334.687 ccw(c175.229,334.803) 175.345,334.803 175.345,334.956 cw(c175.46,334.956) 175.46,335.072 175.615,335.072 cw(c175.615,334.956) 175.731,334.956 ccw(c175.846,334.956) 175.846,334.84 176.146,334.84 178.119,334.84 178.493,334.466 179.73,334.466 179.742,334.478 179.783,334.478 ccw(c179.783,334.595) 179.9,334.595 179.9,334.927 cw(c180.017,334.927) 180.017,335.044 180.118,335.044 cw(c180.118,334.927) 180.235,334.927 180.235,334.595 ccw(c180.352,334.595) 180.352,334.478 180.793,334.478 180.897,334.478 181.669,335.25 182.326,335.25 182.733,335.657 v1(183.54,335.657) 183.614,335.657 184.004,335.266 184.555,335.266 184.556,335.267 185.344,334.48 185.624,334.48 185.998,334.48 186.424,334.48 cw(c186.424,334.364) 186.54,334.364 186.54,334.189 ccw(c186.656,334.189) 186.656,334.073 186.81,334.073 ccw(c186.81,334.189) 186.926,334.189 186.926,334.97 cw(c187.042,334.97) 187.042,335.086 187.196,335.086 cw(c187.196,334.97) 187.312,334.97 187.312,334.596 ccw(c187.428,334.596) 187.428,334.48 187.748,334.48 190.03,334.48 191.777,334.48 192.558,335.26 193.797,335.26 194.189,335.652 v1(194.997,335.652) 195.009,335.64 196.472,335.64 196.477,335.634 196.788,335.634 197.164,335.634 cw(c197.164,335.55) 197.247,335.55 197.247,334.842 ccw(c197.331,334.842) 197.331,334.758 197.499,334.758 ccw(c197.499,334.842) 197.583,334.842 197.583,335.561 cw(c197.666,335.561) 197.666,335.645 197.834,335.645 cw(c197.834,335.561) 197.918,335.561 197.918,334.842 ccw(c198.002,334.842) 198.002,334.758 198.169,334.758 ccw(c198.169,334.842) 198.253,334.842 198.253,335.561 cw(c198.337,335.561) 198.337,335.645 198.504,335.645 cw(c198.504,335.561) 198.588,335.561 198.588,335.224 ccw(c198.672,335.224) 198.672,335.14 198.84,335.14 ccw(c198.84,335.224) 198.923,335.224 198.923,335.55 cw(c199.007,335.55) 199.007,335.634 199.356,335.634 199.405,335.634 199.781,335.634 cw(c199.781,335.55) 199.864,335.55 199.864,334.814 ccw(c199.948,334.814) 199.948,334.73 200.116,334.73 ccw(c200.116,334.814) 200.2,334.814 200.2,335.55 cw(c200.283,335.55) 200.283,335.634 200.965,335.634 204.515,335.634 204.89,336.009 205.198,336.009 205.64,336.451 v1(205.675,336.451)
  L5 (Sign) w0.151: v1(165.186,343.555) 165.186,342.893 165.535,342.544
  L3 (Sign) w0.079: 189.517,313.675 189.606,313.587 190.076,313.587 190.33,313.842 ; 191.872,314.59 192.397,314.59
  L3 (Sign) w0.081: v2(188.798,316.09) 188.798,315.805 188.335,315.341 188.335,314.555 188.386,314.503 188.386,314.199 188.773,313.812 189.381,313.812 189.517,313.675 ; 190.33,313.842 190.33,314.212 190.592,314.473 191.534,314.473 191.651,314.59 191.872,314.59 ; 203.238,325.145 203.622,325.529 203.622,333.723 203.224,334.121 203.224,335.494 204.165,336.435 204.165,337.203 204.419,337.456 204.423,337.456 204.635,337.668 205.034,337.668 205.263,337.439 205.263,336.863 v1(205.675,336.451)
  L3 (Sign) w0.171: 192.397,314.59 193.36,314.59
  L3 (Sign) w0.172: 193.36,314.59 195.417,314.59 196.459,315.632 196.821,315.994 cw(c196.943,315.872) 197.064,315.994 197.257,315.801 ccw(c197.333,315.876) 197.408,315.801 197.559,315.952 ccw(c197.483,316.027) 197.559,316.102 197.27,316.391 cw(c197.345,316.467) 197.27,316.542 197.42,316.692 cw(c197.496,316.617) 197.571,316.692 197.86,316.404 ccw(c197.935,316.479) 198.01,316.404 198.161,316.554 ccw(c198.086,316.629) 198.161,316.705 197.889,316.977 cw(c197.964,317.052) 197.889,317.127 198.04,317.278 cw(c198.115,317.203) 198.19,317.278 198.474,316.994 ccw(c198.549,317.07) 198.625,316.994 198.775,317.145 ccw(c198.7,317.22) 198.775,317.296 198.524,317.546 cw(c198.6,317.622) 198.524,317.697 198.675,317.848 cw(c198.75,317.772) 198.826,317.848 199.065,317.608 ccw(c199.14,317.684) 199.215,317.608 199.366,317.759 ccw(c199.291,317.834) 199.366,317.91 199.124,318.151 cw(c199.2,318.227) 199.124,318.302 199.275,318.453 cw(c199.35,318.377) 199.426,318.453 199.667,318.211 ccw(c199.743,318.286) 199.818,318.211 199.968,318.362 ccw(c199.893,318.437) 199.968,318.512 199.707,318.773 cw(c199.783,318.848) 199.707,318.924 199.858,319.074 cw(c199.933,318.999) 200.009,319.074 200.292,318.791 ccw(c200.368,318.866) 200.443,318.791 200.594,318.941 ccw(c200.518,319.017) 200.594,319.092 200.287,319.399 cw(c200.362,319.474) 200.287,319.549 200.438,319.7 cw(c200.513,319.624) 200.588,319.7 200.872,319.416 ccw(c200.947,319.491) 201.023,319.416 201.173,319.566 ccw(c201.098,319.642) 201.173,319.717 200.879,320.012 cw(c200.954,320.087) 200.879,320.162 201.03,320.313 cw(c201.105,320.237) 201.18,320.313 201.475,320.018 ccw(c201.55,320.094) 201.625,320.018 201.776,320.169 ccw(c201.701,320.244) 201.776,320.32 201.484,320.612 cw(c201.559,320.687) 201.484,320.762 201.634,320.913 cw(c201.709,320.838) 201.785,320.913 202.116,320.582 ccw(c202.191,320.657) 202.266,320.582 202.417,320.733 ccw(c202.342,320.808) 202.417,320.883 202.185,321.115 cw(c202.307,321.237) 202.185,321.358 202.819,321.992 202.819,324.726 203.238,325.145
DDR4_ZQ: R920.1 U1.AB23 | length 21.2
  L1 w0.12: v2(182.909,310.052) U1.AB23@183.397,310.539
  L1 w0.2: v2(200.812,312.356) R920.1@201.26,312.356
  L3 (Sign) w0.2: v2(182.909,310.052) 184.396,308.565 195.915,308.565 199.706,312.356 v2(200.812,312.356)
DDR4_ZQ_1: R61.1 U8.F6 | length 4.5
  L1 w0.254: v1(198.343,331.916) 198.475,332.048 200.445,332.048 U8.F6@200.457,332.06
  L16 w0.2: R61.1@196.69,332.943 197.143,332.943 197.26,332.826 197.26,332.388 197.732,331.916 v1(198.343,331.916)
DDR4_ZQ_2: R62.1 U10.F6 | length 2.3
  L1 w0.2: R62.1@186.988,332.702 187.681,332.702 188.125,332.257 188.8,332.257
  L1 w0.25: 188.8,332.257 U10.F6@188.997,332.06
DDR4_ZQ_3: R63.1 U9.F6 | length 2.7
  L1 w0.4: R63.1@163.416,332.27 165.866,332.27 U9.F6@166.076,332.06
DDR4_ZQ_4: R64.1 U11.F6 | length 2.3
  L1 w0.2: R64.1@175.627,332.21 176.225,332.21 176.719,331.716 177.192,331.716 U11.F6@177.536,332.06
DEVSLP: J27.38
DH1: T5.4 T6.4 U34.23 | length 21.5
  L1 w0.254: U34.23@67.322,236.639 67.949,236.639 69.436,238.125 v2(70.117,238.125) ; T5.4@85.882,243.723 v2(85.882,243.755)
  L3 (Sign) w0.254: v2(70.117,238.125) 75.714,243.723 v2(78.882,243.723) 78.914,243.755 v2(85.882,243.755)
DH1_1: T13.4 U37.23 | length 15.5
  L1 w0.2: U37.23@67.675,180.817 69.373,180.817 v2(69.38,180.81)
  L1 w0.5: T13.4@80.042,181.813 v1(81.129,181.813)
  L3 (Sign) w0.2: v2(69.38,180.81) 71.323,180.81 73.038,182.524 80.418,182.524 v1(81.129,181.813)
DH1_2: T17.4 U38.23 | length 22.2
  L1 w0.254: U38.23@65.953,207.714 67.479,207.714 v2(67.796,208.031) ; v2(80.18,217.889) T17.4@80.998,217.889
  L3 (Sign) w0.2: 67.796,210.036 69.345,210.036 72.39,213.081 74.308,213.081 74.923,213.696
  L3 (Sign) w0.254: v2(67.796,208.031) 67.796,210.036 ; 74.923,213.696 74.923,216.666 75.567,217.31 79.083,217.31 79.662,217.889 v2(80.18,217.889)
DH2: T9.4 T10.4 U34.18 | length 17.5
  L1 w0.254: U34.18@67.322,234.139 67.324,234.137 68.428,234.137 v2(69.863,232.702) ; v2(82.067,227.505) T9.4@82.072,227.501
  L3 (Sign) w0.254: v2(69.863,232.702) 75.064,227.501 v2(75.078,227.501) 75.082,227.505 v2(82.067,227.505)
DH2_1: T15.4 U37.18 | length 23
  L1 w0.2: U37.18@67.675,178.317 69.112,178.317 69.187,178.392 v2(69.228,178.392)
  L1 w0.5: T15.4@79.789,167.011 v1(80.876,167.011)
  L3 (Sign) w0.2: v2(69.228,178.392) 69.228,177.891 71.062,176.057 78.121,176.057 79.835,174.342 79.835,168.052 v1(80.876,167.011)
DH2_2: T19.4 U38.18 | length 20.3
  L1 w0.2: 67.744,205.006 69.479,205.006 v2(69.757,204.728) ; T19.4@80.929,197.556 80.972,197.599 v2(81.985,197.599)
  L1 w0.254: U38.18@65.953,205.214 67.536,205.214 67.744,205.006
  L3 (Sign) w0.2: v2(69.757,204.728) 75.552,198.933 80.651,198.933 v2(81.985,197.599)
DL1: R275.2 T7.4 T8.4 U34.21 | length 19.6
  L1 w0.254: U34.21@67.322,235.639 70.805,235.639 v2(71.387,236.22) ; v2(85.869,236.489) T8.4@85.882,236.489
  L3 (Sign) w0.254: v2(71.387,236.22) 71.655,236.489 v2(78.867,236.489) 79.613,236.489 v2(80.488,237.364) 81.363,236.489 v2(85.869,236.489)
DL1_1: R292.2 T14.4 U37.21 | length 9.1
  L1 w0.2: R292.2@70.161,179.917 70.161,180.308 70.802,180.95 v2(70.802,181.242)
  L1 w0.254: U37.21@67.675,179.817 68.726,179.817 68.825,179.915 R292.2@70.161,179.917
  L1 w0.5: v1(73.127,184.15) T14.4@74.214,184.15
  L3 (Sign) w0.2: v2(70.802,181.242) 73.127,183.567 v1(73.127,184.15)
DL1_2: R629.2 T18.4 U38.21 | length 10.5
  L1 w0.254: U38.21@65.953,206.714 66.916,206.714 67.166,206.964 R629.2@68.206,206.964 ; v2(73.85,207.802) 73.855,207.797 T18.4@75.173,207.797
  L3 (Sign) w0.254: v2(67.43,206.951) 68.28,207.802 v2(73.85,207.802)
DL2: R280.2 T11.4 T12.4 U34.20 | length 15.8
  L1 w0.254: U34.20@67.322,235.139 69.941,235.139 v2(70.129,234.95)
  L3 (Sign) w0.254: v2(70.129,234.95) 70.316,234.764 v2(75.072,234.764) v2(82.072,234.764) ; v2(80.488,233.889) 80.488,234.764
DL2_1: R299.2 T16.4 U37.20 | length 15.7
  L1 w0.254: U37.20@67.675,179.317 v2(69.396,179.317) 69.646,179.067 R299.2@70.211,179.067
  L1 w0.5: v1(72.923,169.38) T16.4@74.01,169.38
  L3 (Sign) w0.2: v2(69.396,179.317) 69.396,179.276 68.724,178.604 68.724,174.443 72.034,171.132 72.034,170.269 v1(72.923,169.38)
DL2_2: R317.2 T20.4 U38.20 | length 12.7
  L1 w0.2: v2(73.292,200.165) 73.304,200.165 73.292,200.152 T20.4@75.074,200.152
  L1 w0.254: U38.20@65.953,206.214 66.991,206.214 v2(67.166,206.039) R317.2@68.206,206.039
  L3 (Sign) w0.2: v2(67.166,206.039) 67.417,206.039 v2(73.292,200.165)
eMMC_clk: R112.2 U41.M6 | length 15.6
  L1 w0.2: v2(131.416,314.211) 131.67,313.957 132.799,313.957 132.891,314.048 132.941,314.048 133.066,314.173 R112.2@133.066,314.223
  L3 (Sign) w0.12: v2(121.938,318.591) 122.773,319.426 123.765,319.426 128.981,314.211 129.794,314.211 129.896,314.211 ccw(c129.896,314.33) 130.015,314.33 130.015,314.612 cw(c130.134,314.612) 130.134,314.731 130.371,314.731 cw(c130.371,314.612) 130.49,314.612 130.49,314.211 130.49,313.822 ccw(c130.609,313.822) 130.609,313.703 130.847,313.703 ccw(c130.847,313.822) 130.966,313.822 130.966,314.092 cw(c131.085,314.092) 131.085,314.211 131.204,314.211 v2(131.416,314.211)
eMMC_cmd: R111.2 U41.M5 | length 15.5
  L1 w0.2: v2(131.407,315.214) 131.597,315.214 131.731,315.214 cw(c131.731,315.075) 131.87,315.075 131.87,314.65 ccw(c132.009,314.65) 132.009,314.511 132.286,314.511 ccw(c132.286,314.65) 132.425,314.65 132.425,315.075 cw(c132.564,315.075) 132.564,315.214 132.703,315.214 R111.2@133.116,315.214
  L3 (Sign) w0.12: v2(121.938,319.091) 122.127,319.091 122.682,319.646 124.383,319.646 128.815,315.214 128.93,315.214 129.049,315.214 ccw(c129.049,315.333) 129.168,315.333 129.168,315.752 cw(c129.287,315.752) 129.287,315.87 129.525,315.87 cw(c129.525,315.752) 129.644,315.752 129.644,315.333 ccw(c129.763,315.333) 129.763,315.214 129.857,315.214 v2(131.407,315.214)
eMMC_data0: R105.2 U41.A3 | length 15.4
  L1 w0.2: v2(131.407,321.335) 131.634,321.335 131.734,321.335 ccw(c131.734,321.535) 131.934,321.535 131.934,321.906 cw(c132.085,321.906) 132.085,322.058 132.389,322.058 cw(c132.389,321.906) 132.54,321.906 132.54,321.535 ccw(c132.74,321.535) 132.74,321.335 R105.2@133.066,321.335 R105.2@133.116,321.335
  L3 (Sign) w0.12: v2(127.438,320.091) 128.352,321.005 128.471,321.005 ccw(c128.471,321.124) 128.589,321.124 128.589,321.167 cw(c128.708,321.167) 128.708,321.286 128.946,321.286 cw(c128.946,321.167) 129.065,321.167 129.065,321.005 129.065,320.283 ccw(c129.184,320.283) 129.184,320.164 129.422,320.164 ccw(c129.422,320.283) 129.541,320.283 129.541,320.886 cw(c129.66,320.886) 129.66,321.005 129.731,321.005 132.74,321.005 133.794,322.059 133.794,322.478 133.642,322.631 132.956,322.631 131.661,321.335 v2(131.407,321.335)
eMMC_data1: R107.2 U41.A4 | length 16.3
  L1 w0.2: U41.A4@127.438,319.591 128.041,319.591 128.522,319.591 cw(c128.522,319.452) 128.661,319.452 128.661,318.827 ccw(c128.8,318.827) 128.8,318.688 129.078,318.688 ccw(c129.078,318.827) 129.217,318.827 129.217,319.591 129.217,320.356 cw(c129.355,320.356) 129.355,320.495 129.633,320.495 cw(c129.633,320.356) 129.772,320.356 129.772,319.591 129.772,318.827 ccw(c129.911,318.827) 129.911,318.688 130.189,318.688 ccw(c130.189,318.827) 130.328,318.827 130.328,319.591 130.328,320.356 cw(c130.467,320.356) 130.467,320.495 130.744,320.495 cw(c130.744,320.356) 130.883,320.356 130.883,319.591 130.883,318.851 ccw(c131.022,318.851) 131.022,318.712 131.3,318.712 ccw(c131.3,318.851) 131.439,318.851 131.439,319.591 131.439,319.774 cw(c131.578,319.774) 131.578,319.913 131.856,319.913 cw(c131.856,319.774) 131.995,319.774 131.995,319.591 131.995,318.827 ccw(c132.133,318.827) 132.133,318.688 132.411,318.688 ccw(c132.411,318.827) 132.55,318.827 132.55,319.452 cw(c132.689,319.452) 132.689,319.591 132.828,319.591 R107.2@133.116,319.303
eMMC_data2: R108.2 U41.A5 | length 16.3
  L1 w0.2: U41.A5@127.438,319.091 127.669,319.091 127.813,318.948 127.813,317.535 128.076,317.271 128.143,317.271 128.422,317.271 cw(c128.422,317.133) 128.561,317.133 128.561,316.622 ccw(c128.7,316.622) 128.7,316.483 128.977,316.483 ccw(c128.977,316.622) 129.116,316.622 129.116,317.271 129.116,317.921 cw(c129.255,317.921) 129.255,318.06 129.533,318.06 cw(c129.533,317.921) 129.672,317.921 129.672,317.271 129.672,316.622 ccw(c129.811,316.622) 129.811,316.483 130.089,316.483 ccw(c130.089,316.622) 130.228,316.622 130.228,317.271 130.228,317.921 cw(c130.366,317.921) 130.366,318.06 130.644,318.06 cw(c130.644,317.921) 130.783,317.921 130.783,317.271 130.783,316.796 ccw(c130.922,316.796) 130.922,316.657 131.2,316.657 ccw(c131.2,316.796) 131.339,316.796 131.339,317.271 131.339,317.704 cw(c131.478,317.704) 131.478,317.843 131.755,317.843 cw(c131.755,317.704) 131.894,317.704 131.894,317.271 131.894,316.769 ccw(c132.033,316.769) 132.033,316.63 132.311,316.63 ccw(c132.311,316.769) 132.45,316.769 132.45,317.133 cw(c132.589,317.133) 132.589,317.271 132.728,317.271 R108.2@133.116,317.271
eMMC_data3: R110.2 U41.B2 | length 15.5
  L1 w0.2: v2@131.416,323.367 131.62,323.367 131.72,323.367 ccw(c131.72,323.567) 131.92,323.567 131.92,324.193 cw(c132.072,324.193) 132.072,324.344 132.375,324.344 cw(c132.375,324.193) 132.527,324.193 132.527,323.567 ccw(c132.727,323.567) 132.727,323.367 R110.2@133.116,323.367
  L3 (Sign) w0.12: v2(126.938,320.591) 127.735,321.388 127.78,321.434 ccw(c127.696,321.518) 127.78,321.602 127.431,321.951 cw(c127.515,322.035) 127.431,322.119 127.599,322.287 cw(c127.683,322.203) 127.768,322.287 128.201,321.854 ccw(c128.285,321.938) 128.369,321.854 128.537,322.022 ccw(c128.453,322.106) 128.537,322.19 128.417,322.311 cw(c128.501,322.395) 128.417,322.479 128.585,322.647 cw(c128.669,322.563) 128.753,322.647 128.873,322.527 129.296,322.104 ccw(c129.38,322.188) 129.464,322.104 129.632,322.272 ccw(c129.548,322.356) 129.632,322.441 129.209,322.863 128.776,323.296 cw(c128.86,323.38) 128.776,323.464 128.945,323.632 cw(c129.029,323.548) 129.113,323.632 129.462,323.283 ccw(c129.546,323.367) 129.63,323.283 129.714,323.367 129.807,323.367 129.934,323.367 ccw(c129.934,323.486) 130.053,323.486 130.053,323.561 cw(c130.172,323.561) 130.172,323.68 130.409,323.68 cw(c130.409,323.561) 130.528,323.561 130.528,323.367 130.528,322.675 ccw(c130.647,322.675) 130.647,322.556 130.885,322.556 ccw(c130.885,322.675) 131.004,322.675 131.004,323.248 cw(c131.123,323.248) 131.123,323.367 131.242,323.367 v2@131.416,323.367
  other v2: 131.39,323.367
eMMC_data4: R101.2 U41.B3 | length 15.4
  L1 w0.2: v2(131.407,322.351) 131.623,322.351 131.723,322.351 ccw(c131.723,322.551) 131.923,322.551 131.923,322.919 cw(c132.074,322.919) 132.074,323.071 132.378,323.071 cw(c132.378,322.919) 132.529,322.919 132.529,322.551 ccw(c132.729,322.551) 132.729,322.351 R101.2@133.116,322.351
  L3 (Sign) w0.12: v2(126.938,320.091) 126.938,320.1 128.63,321.793 129.527,321.793 129.74,321.793 cw(c129.74,321.674) 129.859,321.674 129.859,321.525 ccw(c129.978,321.525) 129.978,321.406 130.215,321.406 ccw(c130.215,321.525) 130.334,321.525 130.334,321.793 130.334,322.036 cw(c130.453,322.036) 130.453,322.155 130.691,322.155 cw(c130.691,322.036) 130.81,322.036 130.81,321.793 130.81,321.72 ccw(c130.929,321.72) 130.929,321.602 131.167,321.602 ccw(c131.167,321.72) 131.286,321.72 cw(c131.358,321.72) 131.358,321.793 131.523,321.793 132.755,323.024 133.325,323.024 133.604,323.304 133.604,323.571 133.507,323.667 132.698,323.667 131.407,322.377 v2(131.407,322.351)
eMMC_data5: R102.2 U41.B4 | length 15.4
  L1 w0.2: v2(131.407,320.319) 131.618,320.319 131.718,320.319 ccw(c131.718,320.519) 131.918,320.519 131.918,320.88 cw(c132.069,320.88) 132.069,321.032 132.373,321.032 cw(c132.373,320.88) 132.524,320.88 132.524,320.519 ccw(c132.724,320.519) 132.724,320.319 R102.2@133.066,320.319 R102.2@133.116,320.319
  L3 (Sign) w0.12: v2(126.938,319.591) 130.581,319.591 130.72,319.591 cw(c130.72,319.472) 130.838,319.472 130.838,318.784 ccw(c130.957,318.784) 130.957,318.665 131.195,318.665 ccw(c131.195,318.784) 131.314,318.784 131.314,319.591 131.314,319.871 cw(c131.433,319.871) 131.433,319.99 131.671,319.99 cw(c131.671,319.871) 131.79,319.871 131.79,319.591 131.79,318.74 ccw(c131.909,318.74) 131.909,318.621 132.146,318.621 ccw(c132.146,318.74) 132.265,318.74 132.265,319.472 cw(c132.384,319.472) 132.384,319.591 132.503,319.591 132.88,319.968 132.88,320.497 132.677,320.7 131.788,320.7 v2(131.407,320.319)
eMMC_data6: R103.2 U41.B5 | length 15.4
  L1 w0.2: v2(131.407,318.287) R103.2@133.116,318.287
  L3 (Sign) w0.12: v2(126.938,319.091) 127.742,318.287 127.813,318.287 127.981,318.287 ccw(c127.981,318.406) 128.1,318.406 128.1,318.972 cw(c128.219,318.972) 128.219,319.091 128.456,319.091 cw(c128.456,318.972) 128.575,318.972 128.575,318.287 128.575,317.603 ccw(c128.694,317.603) 128.694,317.484 128.932,317.484 ccw(c128.932,317.603) 129.051,317.603 129.051,318.287 129.051,318.972 cw(c129.17,318.972) 129.17,319.091 129.408,319.091 cw(c129.408,318.972) 129.526,318.972 129.526,318.287 129.526,317.603 ccw(c129.645,317.603) 129.645,317.484 129.883,317.484 ccw(c129.883,317.603) 130.002,317.603 130.002,318.287 130.002,318.972 cw(c130.121,318.972) 130.121,319.091 130.359,319.091 cw(c130.359,318.972) 130.478,318.972 130.478,318.287 130.478,317.603 ccw(c130.597,317.603) 130.597,317.484 130.834,317.484 ccw(c130.834,317.603) 130.953,317.603 130.953,318.169 cw(c131.072,318.169) 131.072,318.287 131.191,318.287 v2(131.407,318.287)
eMMC_data7: R104.2 U41.B6 | length 15.3
  L1 w0.2: v2(131.416,316.255) 131.636,316.255 131.781,316.255 cw(c131.781,316.117) 131.92,316.117 131.92,315.728 ccw(c132.059,315.728) 132.059,315.589 132.336,315.589 ccw(c132.336,315.728) 132.475,315.728 132.475,316.117 cw(c132.614,316.117) 132.614,316.255 132.753,316.255 R104.2@133.116,316.255
  L3 (Sign) w0.12: v2(126.938,318.591) 128.271,317.259 131.089,317.259 131.242,317.259 ccw(c131.242,317.378) 131.361,317.378 131.361,317.746 cw(c131.48,317.746) 131.48,317.865 131.718,317.865 cw(c131.718,317.746) 131.837,317.746 131.837,317.259 131.837,316.406 ccw(c131.955,316.406) 131.955,316.287 132.193,316.287 ccw(c132.193,316.406) 132.312,316.406 132.312,317.14 cw(c132.431,317.14) 132.431,317.259 132.55,317.259 133.02,316.789 133.02,316.001 132.753,315.735 131.788,315.735 131.416,316.107 v2(131.416,316.255)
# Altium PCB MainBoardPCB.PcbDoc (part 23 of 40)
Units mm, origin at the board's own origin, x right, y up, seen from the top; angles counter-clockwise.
Board outline 258.95 x 308.86 mm, 16 copper layers (L1, L2 (GND), L3 (Sign), L4 (GND), L5 (Sign), L6 (PWR/GND), L7(12V+Other), L8 (Plane_GND), L9 (PWR/GND), L10 (3V3+Other), L11 (PWR/GND), L12 (Sign), L13 (GND), L14 (Sign), L15 (GND), L16), stack 2.503 mm thick; 2578 components, 1867 nets, 8817 pads, 8021 vias.
Unrouted connection lines stored in the file: 25.

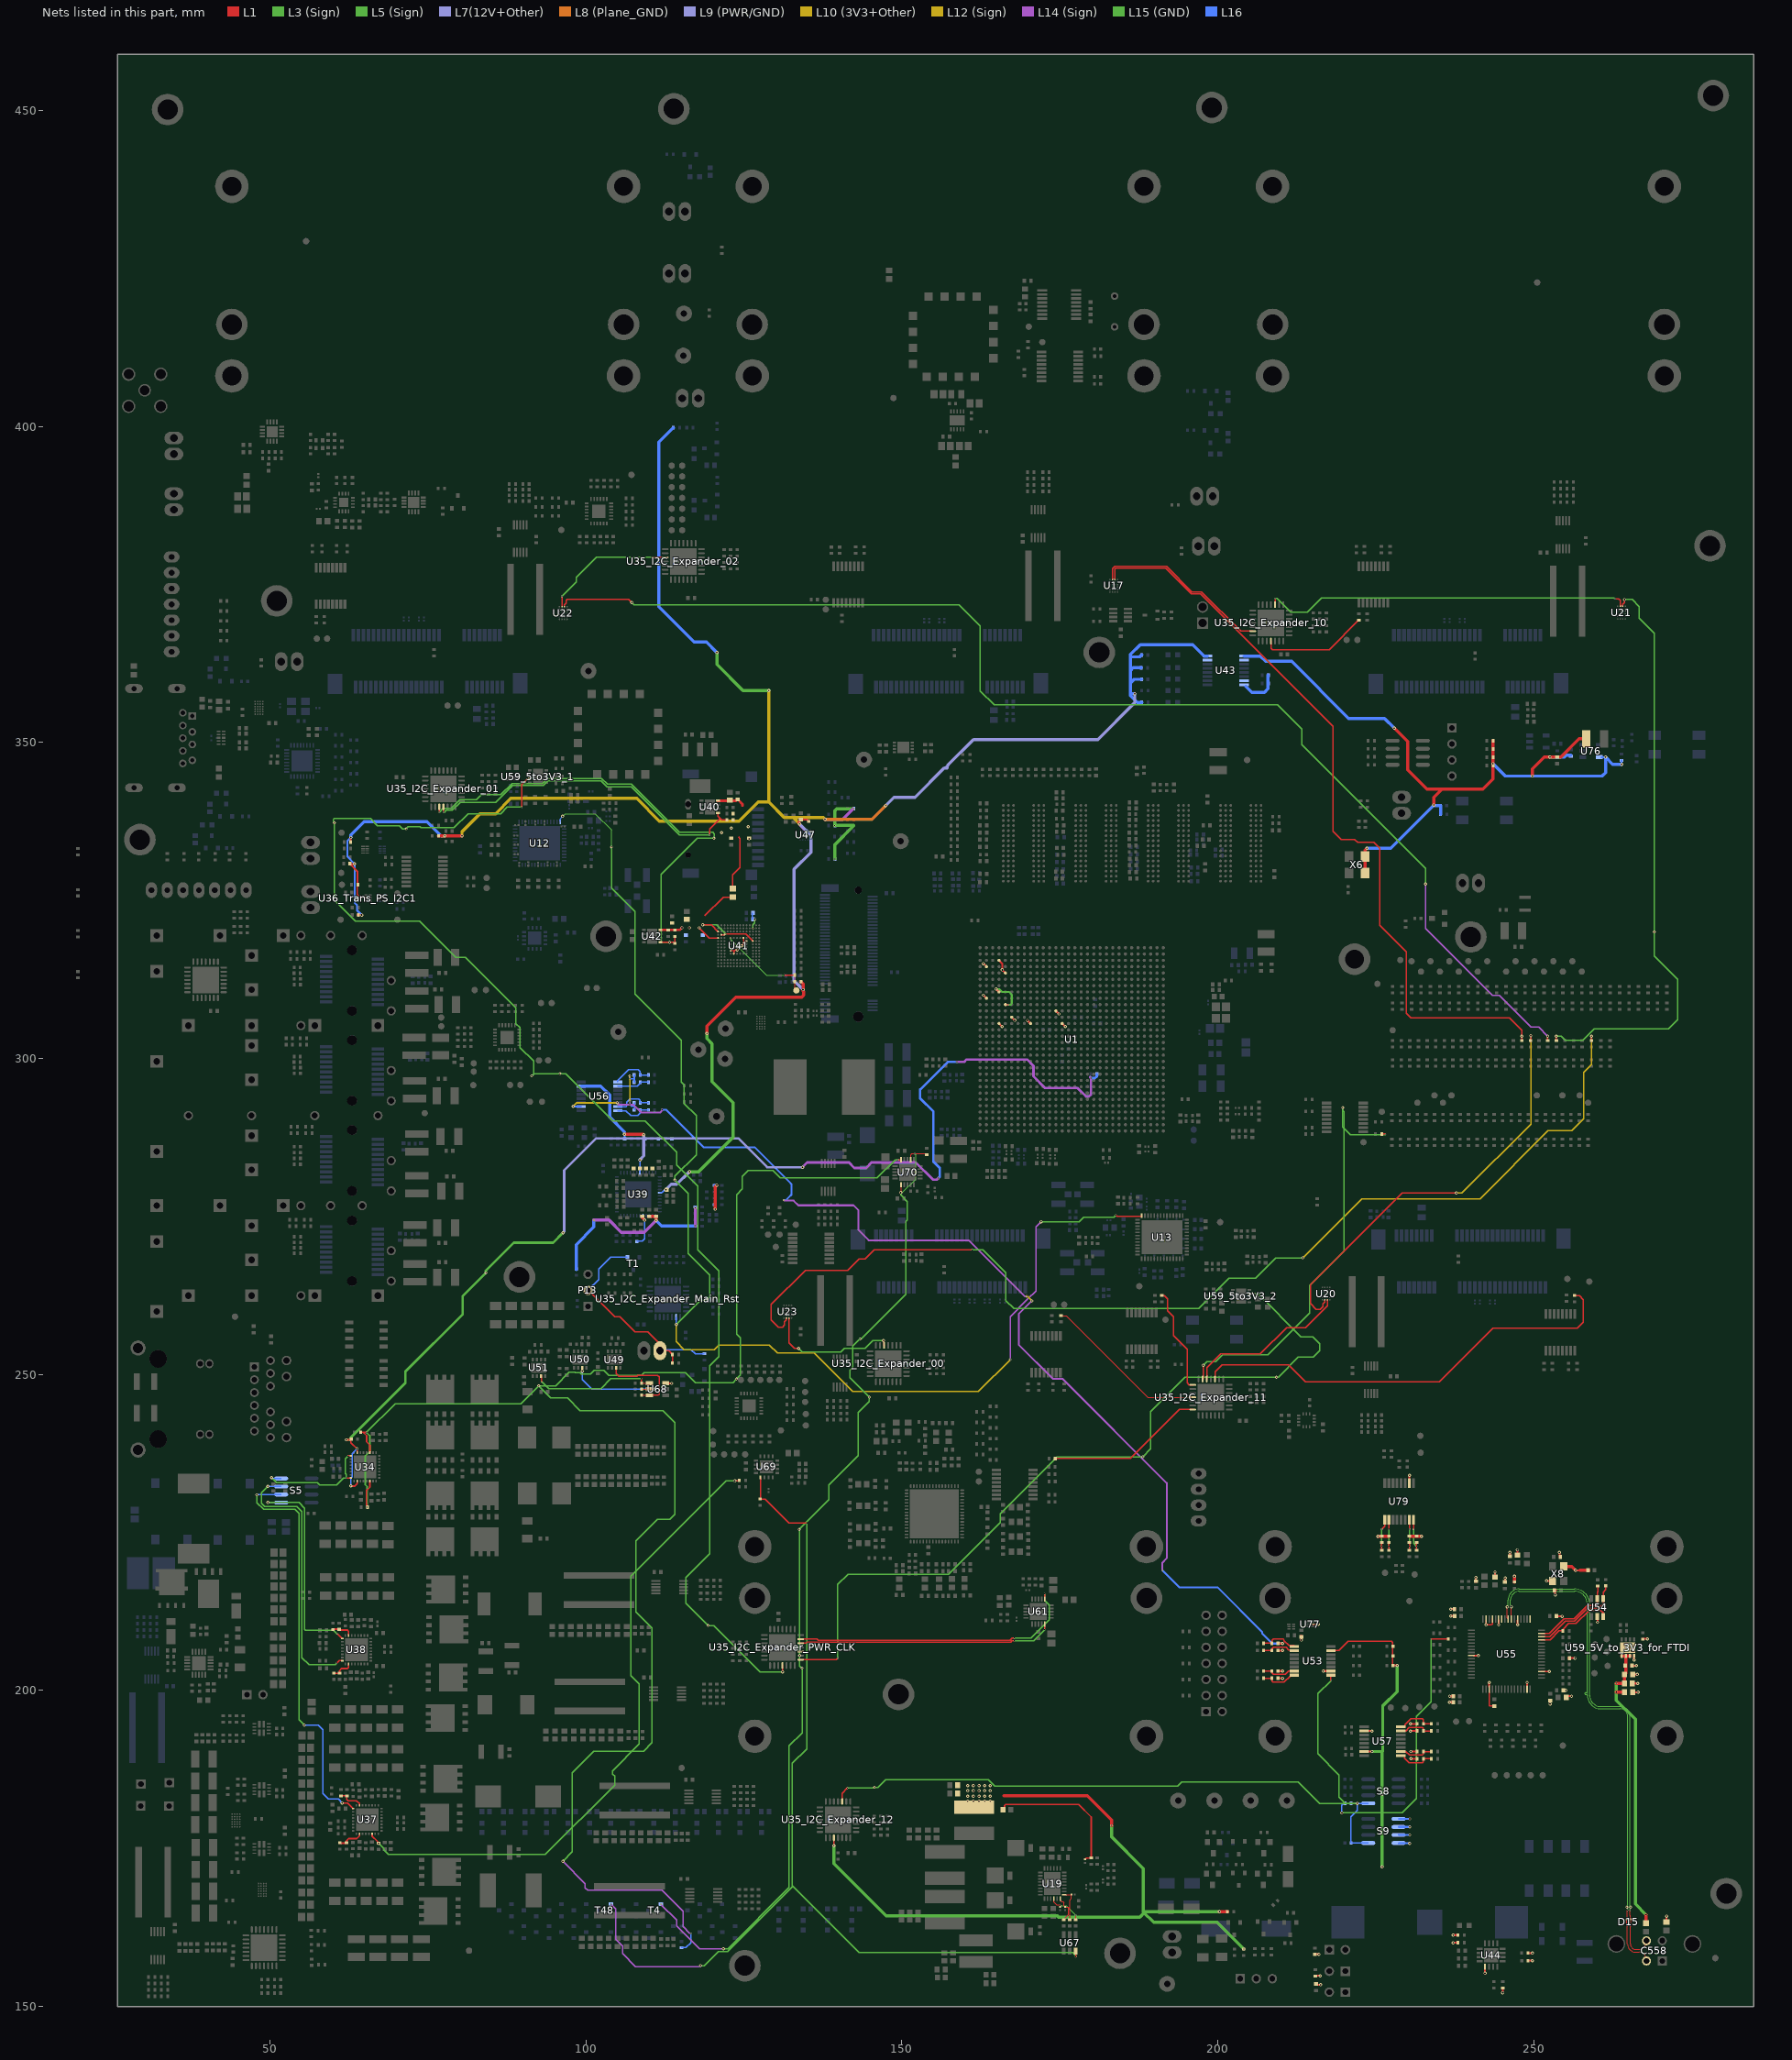
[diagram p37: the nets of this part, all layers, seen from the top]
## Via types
v1: diameter 0.5, hole 0.25, L1 to L16, tented both sides, 4341 vias
v2: diameter 0.254, hole 0.1, L1 to L3 (Sign), tented both sides, 781 vias
v3: diameter 0.5, hole 0.25, L1 to L16, 565 vias
v4: diameter 0.254, hole 0.1, L15 (GND) to L16, tented both sides, 406 vias
v5: diameter 0.254, hole 0.1, L1 to L2 (GND), tented both sides, 283 vias
v6: diameter 0.457, hole 0.2, L3 (Sign) to L6 (PWR/GND), tented both sides, 254 vias
v7: diameter 0.254, hole 0.1, L1 to L3 (Sign), 237 vias
v8: diameter 0.75, hole 0.4, L1 to L16, 200 vias
v9: diameter 0.8, hole 0.4, L1 to L16, tented both sides, 182 vias
v10: diameter 0.254, hole 0.1, L14 (Sign) to L16, tented both sides, 170 vias
v11: diameter 0.75/0/0/0/0/0/0/0/0/0/0/0/0/0/0/0.75 (per signal layer), hole 0.4, L1 to L16, 160 vias
v12: diameter 0.457, hole 0.2, L3 (Sign) to L6 (PWR/GND), 158 vias
v13: diameter 1.4, hole 0.5, L1 to L16, tented both sides, 80 vias
v14: diameter 0.254, hole 0.1, L14 (Sign) to L16, 65 vias
v15: diameter 0.254, hole 0.1, L1 to L2 (GND), 45 vias
v16: diameter 0.457, hole 0.2, L11 (PWR/GND) to L14 (Sign), tented both sides, 26 vias
v17: diameter 0.457, hole 0.2, L11 (PWR/GND) to L14 (Sign), 25 vias
v18: diameter 0.457, hole 0.2, L7(12V+Other) to L10 (3V3+Other), tented both sides, 11 vias
v19: diameter 0.254/0/0.254 (per signal layer), hole 0.1, L1 to L3 (Sign), 9 vias
v20: diameter 0.2/0/0.2 (per signal layer), hole 0.1, L1 to L3 (Sign), 6 vias
v21: diameter 1.65, hole 1.65, L1 to L16, 5 vias
v22: diameter 1.15, hole 1.15, L1 to L16, 5 vias
v23: diameter 0.457, hole 0.2, L1 to L16, 3 vias
v24: diameter 0.5, hole 0.3, L1 to L16, 2 vias
v25: diameter 0.5/0/0.5 (per signal layer), hole 0.2, L14 (Sign) to L16, 1 vias
v26: diameter 0.5, hole 0.25, L1 to L16, tented bottom, 1 vias

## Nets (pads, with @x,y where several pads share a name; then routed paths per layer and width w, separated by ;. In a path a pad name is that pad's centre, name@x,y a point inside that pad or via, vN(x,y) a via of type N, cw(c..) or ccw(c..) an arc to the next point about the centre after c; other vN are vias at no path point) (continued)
eMMC_PG1: R340.1 U35_I2C_Expander_01.4 U40.5 | length 54.1
  L1 w0.2: v2(77.463,338.963) U35_I2C_Expander_01.4@77.463,339.814 ; v2(119.579,335.404) 119.579,336.305 121.133,337.858 121.133,338.112 ; U40.5@120.909,338.844 120.909,338.336 121.133,338.112 ; R340.1@122.354,337.782 121.463,337.782 121.133,338.112
  L3 (Sign) w0.2: v2(77.463,338.963) 77.632,338.963 77.932,339.262 78.849,339.262 80.111,340.525 85.75,340.525 88.443,343.218 93.256,343.218 94.004,343.966 102.427,343.966 103.365,343.027 107.17,343.027 114.794,335.404 v2(119.579,335.404)
eMMC_PG2: R343.1 R345.1 U35_I2C_Expander_01.3 U42.5 | length 76.9
  L1 w0.2: v2(76.813,338.963) U35_I2C_Expander_01.3@76.813,339.814 ; U42.5@111.793,318.401 v1(113.259,318.401) 113.861,318.401 R345.1@113.875,318.387 ; R345.1@114.1,318.175 R343.1@114.1,319.355
  L5 (Sign) w0.2: v1(113.259,318.401) 112.111,318.401 111.925,318.587 111.925,329.132 117.668,334.875 v12(120.277,334.875)
  L3 (Sign) w0.2: v2(76.813,338.963) 77.412,339.562 78.697,339.562 80.092,340.957 82.682,340.957 83.469,341.744 86.545,341.744 88.318,343.518 93.131,343.518 93.916,344.302 102.515,344.302 103.397,343.419 107.202,343.419 114.817,335.804 120.1,335.804 120.364,335.541 120.364,335.09 120.334,335.06 120.334,334.932 v12(120.277,334.875)
eMMC_rst: R99.1 R797.1 SP19.1 U41.K5 | length 15.3
  L1 w0.12: R797.1@133.103,313.22 133.103,312.204 133.129,312.179 133.129,310.977 SP19.1@133.324,310.782
  L1 w0.2: v2(131.416,313.22) R797.1@133.103,313.22
  L1 w0.254: U41.K5@122.938,319.091 v2(122.949,319.091)
  L3 (Sign) w0.12: v2@122.943,319.097 v2(122.949,319.091) 122.949,318.874 128.602,313.22 v2(131.416,313.22)
eMMC_Vcc: C517.2 C518.2 C523.2 C586.2 FB25.1 R339.2 R340.2 U40.8 U41.E6 U41.F5 U41.J10 U41.K9 | length 16.9
  L1 w0.2: U41.K9@122.938,317.091 122.957,317.072 123.351,317.072 123.457,316.966 ; FB25.1@123.254,326.881 123.254,329.058 124.408,330.212 124.408,334.832 124.15,335.09 ; U41.J10@123.438,316.591 123.457,316.611 123.457,316.966 ; v1(123.947,317.202) 123.89,317.144 123.635,317.144 123.457,316.966 ; v1(124.688,317.841) 124.688,317.923 124.938,318.173 ; U41.F5@124.938,319.091 124.938,318.173 ; U41.E6@125.438,318.591 125.411,318.591 125.295,318.475 125.241,318.475 124.938,318.173
  L1 w0.4: U40.8@120.909,340.794 123.761,340.794 123.958,340.991 C517.2@124.008,340.991 124.058,340.991 124.803,340.246 124.803,340.034
  other v1: 125.856,334.778 121.51,335.739 123.002,336.469 125.688,336.697
eMMC_VccQ: C519.2 C520.2 C524.2 C587.2 FB25.2 R342.2 R343.2 U41.C6 U41.M4 U41.N4 U41.P3 U41.P5 U42.8 | length 25.5
  L1 w0.2: v1(117.919,320.691) 119.52,319.091 U41.P5@120.938,319.091 ; v1(118.496,321.151) 119.878,321.151 U41.P3@120.938,320.091 ; 118.841,322.624 121.747,325.531 FB25.2@123.254,325.531 ; U41.N4@121.438,319.591 U41.M4@121.938,319.591 122.031,319.684 v2(122.161,319.684) 125.345,319.684 U41.C6@126.438,318.591
  L1 w0.4: U42.8@111.793,320.351 114.85,320.351 115.191,320.691 v1(115.218,320.691)
  L3 (Sign) w0.2: v1(118.496,321.151) 120.694,321.151 v2(122.161,319.684)
  other v1: 116.385,320.691
eMMC_Vddim: C521.2 C522.1 U41.C2 | length 2.9
  L3 (Sign) w0.2: v2@126.433,320.591 126.433,321.136 126.723,321.426 v1@126.723,322.051
  L16 w0.2: C521.2@126.338,322.059 C522.1@126.338,323.067 ; C521.2@126.448,322.074 126.463,322.059 v1(126.748,322.059)
  other v2: 126.438,320.591
EN1: U35_I2C_Expander_PWR_CLK.26 U61.20 | length 40.4
  L1 w0.2: U35_I2C_Expander_PWR_CLK.26@134.003,207.478 134.866,207.478 135.047,207.659 167.225,207.659 167.427,207.861 v2(167.818,207.861) ; v2(172.628,209.628) U61.20@172.628,210.523
  L3 (Sign) w0.2: v2(167.818,207.861) 170.86,207.861 v2(172.628,209.628)
EN1_TPS: R277.2 R278.2 R916.1 U34.14 U34.27 U70.20 | length 284.5
  L1 w0.2: 64.783,240.856 64.795,240.843 v2(65.288,240.843) ; v2(149.365,283.972) 149.371,283.979 U70.20@149.914,283.979
  L1 w0.254: R278.2@64.339,240.856 64.783,240.856 ; 64.795,240.843 65.308,240.33 65.308,239.357 65.822,238.844 U34.27@65.822,237.639 ; v2(65.39,229.024) 65.39,229.317 65.295,229.412 65.295,231.638 65.815,232.158 65.815,232.984 65.82,232.989 65.82,233.137 U34.14@65.822,233.139
  L5 (Sign) w0.2: v6(92.545,248.221) 95.212,248.221 97.348,250.358 98.295,250.358 98.385,250.269 99.093,250.269 99.266,250.095 100.753,250.095 101.296,250.638 102.827,250.638 103.621,249.844 108.794,249.844 109.219,250.269 115.797,250.269 117.329,248.737 123.273,248.737 v6(123.838,249.301)
  L3 (Sign) w0.2: 65.39,240.741 v2(65.288,240.843) 69.848,245.402 89.725,245.402 v6(92.545,248.221) 94.463,246.304 97.091,246.304 99.085,244.31 112.217,244.31 114.122,242.405 114.122,227.876 113.317,227.071 111.306,227.071 107.925,223.69 107.925,212.446 110.49,209.88 110.49,191.745 109.131,190.386 101.239,190.386 97.854,187 97.854,174.473 v1(96.368,172.987) ; v6(123.838,249.301) 124.498,249.961 124.498,255.778 123.888,256.388 123.888,278.458 124.79,279.36 124.79,281.343 125.723,282.276 129.649,282.276 130.797,281.127 146.108,281.127 148.953,283.972 v2(149.365,283.972)
  L3 (Sign) w0.254: v2(65.39,229.024) 65.39,232.269 65.1,232.559 65.1,237.122 65.822,237.843 65.822,240.309 65.39,240.741
  L14 (Sign) w0.2: v1(96.368,172.987) 99.911,169.443 99.911,168.758 100.279,168.389 112.065,168.389 115.379,165.075 115.379,162.649 116.446,161.582 v10(116.635,161.582)
  L16 w0.2: R916.1@115.133,159.329 115.87,159.329 116.635,160.095 v10(116.635,161.582)
EN2: U35_I2C_Expander_PWR_CLK.27 U61.6 | length 46
  L1 w0.2: U35_I2C_Expander_PWR_CLK.27@134.003,208.128 136.593,208.128 136.762,207.959 167.101,207.959 167.453,208.311 v2(167.818,208.311) ; U61.6@172.628,214.473 172.631,214.476 v2(172.631,215.303)
  L3 (Sign) w0.2: v2(167.818,208.311) 170.473,208.311 173.355,211.193 173.355,213.527 172.631,214.251 v2(172.631,215.303)
EN2_TPS: R745.2 T4.1 U70.6 U70.17 | length 161.2
  L1 w0.12: v1(149.822,278.774) 149.935,278.887 149.935,280.008 U70.6@149.914,280.028 ; U70.17@151.414,283.979 151.414,284.726 151.625,284.937 v7(152.082,284.937) 153.855,284.937 R745.2@153.962,284.83
  L5 (Sign) w0.2: v6(133.769,225.501) 138.493,230.226 138.493,232.562 143.129,237.198 143.129,243.98 144.869,245.72 v6(144.869,246.418) ; v6(133.858,205.549) 133.858,203.898 v6(134.226,203.53) ; v6(143.421,255.638) 143.358,255.702 143.623,255.702 150.647,262.726 150.647,274.231 150.901,274.485 150.901,277.368 149.822,278.447 v1(149.822,278.774)
  L3 (Sign) w0.12: v1(149.822,278.774) 150.065,278.774 152.224,280.934 152.224,284.795 v7(152.082,284.937)
  L3 (Sign) w0.2: v1(121.755,159.106) 122.474,159.106 132.182,168.814 132.182,191.237 134.226,193.281 v6(134.226,203.53) ; v6(133.769,225.501) 133.858,225.412 v6(133.858,205.549) ; v6(143.421,255.638) 142.253,254.47 142.253,251.092 141.821,250.66 141.821,249.504 144.869,246.456 v6(144.869,246.418)
  L14 (Sign) w0.2: v10(111.865,166.174) 114.364,163.676 114.364,162.725 117.983,159.106 v1(121.755,159.106)
EN_0.85V_REG1: S5.8 U34.1 U34.8 | length 19.2
  L1 w0.2: v2(62.09,233.639) U34.8@62.822,233.639 ; v2(62.382,237.084) 62.402,237.084 62.457,237.139 U34.1@62.822,237.139
  L3 (Sign) w0.2: v1(50.267,233.682) 51.069,232.88 57.532,232.88 57.901,232.512 60.547,232.512 61.675,233.639 v2(62.09,233.639) 62.09,234.194 61.945,234.339 61.945,236.646 v2(62.382,237.084)
  L16 w0.2: v1(50.267,233.682) 50.396,233.553 S5.8@51.794,233.553
En_0V85@2A: R296.2 R435.2 U37.14 | length 103.5
  L1 w0.2: v1(123.568,233.157) R435.2@124.25,233.157
  L1 w0.254: U37.14@66.175,177.317 66.177,177.315 66.177,176.988 67.106,176.059 67.106,175.965 R296.2@67.204,175.867 v1(67.204,175.817)
  L5 (Sign) w0.2: v1(67.204,175.817) 68.006,175.015 68.006,174.79 68.751,174.046 93.59,174.046 104.572,185.027 104.572,186.438 104.221,186.79 104.221,187.287 108.45,191.516 108.45,201.049 107.15,202.349 107.15,218.069 122.238,233.157 v1(123.568,233.157)
EN_1V0@1.5A: R634.1 U51.3 U68.4 | length 19.8
  L1 w0.12: R634.1@108.791,248.634 U68.4@110.064,248.634
  L1 w0.2: U51.3@92.894,249.763 92.961,249.696 92.961,248.975 93.036,248.9 v2(93.036,248.859) ; R634.1@108.791,248.634 v2(108.791,249.349)
  L3 (Sign) w0.2: v2(93.036,248.859) 94.112,247.784 102.394,247.784 103.959,249.349 v2(108.791,249.349)
EN_1V8@1.5A: R633.1 U50.3 U68.5 | length 16
  L1 w0.12: R633.1@108.791,247.684 U68.5@110.064,247.684
  L1 w0.2: U50.3@99.426,251.071 99.439,251.058 99.439,250.559 v1(99.452,250.545) ; U68.5@110.064,247.684 v1(110.864,247.684)
  L16 w0.2: v1(99.452,250.545) 99.452,249.217 100.986,247.684 v1(110.864,247.684)
EN_2V5@1.5A: R632.1 U49.3 U68.6 | length 13.7
  L1 w0.12: R632.1@108.791,246.733 U68.6@110.064,246.733
  L1 w0.2: U49.3@104.82,251.048 104.82,250.144 105.227,249.737 108.101,249.737 108.248,249.884 111.361,249.884 111.599,249.646 111.599,246.851 111.482,246.733 U68.6@110.064,246.733
EN_3V3V_REG0: S5.6 U37.1 | length 65.5
  L1 w0.2: v1(61.442,182.217) 62.274,182.217 63.075,181.417 63.075,181.342 63.1,181.317 U37.1@63.175,181.317
  L3 (Sign) w0.2: v1(47.942,230.972) 47.942,229.723 48.995,228.671 53.937,228.671 54.582,228.026 54.582,195.39 v1(55.453,194.519)
  L16 w0.2: v1(47.942,230.972) 47.963,230.992 51.774,230.992 S5.6@51.794,231.013 ; v1(55.453,194.519) 57.634,194.519 58.352,193.802 58.352,183.748 59.271,182.829 60.83,182.829 v1(61.442,182.217)
EN_5V_REG0: S5.7 U38.8 | length 42.3
  L1 w0.2: v2(60.58,204.33) 60.964,204.714 U38.8@61.453,204.714
  L3 (Sign) w0.2: v1(49.667,232.29) 48.698,231.321 48.698,229.609 49.159,229.148 54.235,229.148 55.084,228.299 55.084,205.216 56.202,204.097 60.347,204.097 v2(60.58,204.33)
  L16 w0.2: v1(49.667,232.29) 49.671,232.287 51.791,232.287 S5.7@51.794,232.283
EN_12@8A: S5.5 U38.1 | length 34.1
  L1 w0.2: v2(60.668,208.966) 60.701,208.966 U38.1@61.453,208.214
  L3 (Sign) w0.2: v1(49.671,229.743) 54.582,229.743 55.503,228.822 55.503,209.674 55.62,209.557 60.077,209.557 v2(60.668,208.966)
  L16 w0.2: v1(49.671,229.743) S5.5@51.794,229.743 S5.5@51.764,229.773
EN_Detect: R655.1 U35_I2C_Expander_12.3 | length 70.2
  L1 w0.2: v1(139.266,175.425) U35_I2C_Expander_12.3@139.266,176.69
  L1 w0.5: v1(200.289,164.999) R655.1@201.589,164.999
  L5 (Sign) w0.5: v1(139.266,175.425) 139.266,172.639 147.551,164.354 174.627,164.354 174.83,164.151 187.678,164.151 188.527,164.999 v1(200.289,164.999)
EN_PS_LTC6952_1: U35_I2C_Expander_PWR_CLK.18 U59_5to3V3_1.3 | length 223.3
  L1 w0.2: v2(89.852,339.771) 89.852,343.324 90.756,344.227 91.056,344.227 U59_5to3V3_1.3@91.131,344.302 ; U35_I2C_Expander_PWR_CLK.18@131.129,203.953 131.129,202.96 131.127,202.959 v1(131.14,202.959)
  L5 (Sign) w0.2: v6(60.196,337.287) 60.046,337.437 60.046,337.854 60.151,337.96 65.922,337.96 67.035,336.847 70.518,336.847 71.018,336.347 v6(71.564,336.347) ; v6(91.447,297.269) 91.79,297.612 v6(95.91,297.612) ; v6(119.367,210.287) 120.238,210.287 127.588,202.936 v1@131.14,202.936
  L3 (Sign) w0.2: v6(60.196,337.287) 60.196,325.098 63.551,321.742 73.664,321.742 79.404,316.001 80.972,316.001 86.953,310.021 86.955,310.021 87.395,309.581 87.395,309.579 88.938,308.036 88.938,305.531 89.574,304.895 89.574,301.731 91.719,299.586 91.719,297.541 v6(91.447,297.269) ; v6(71.564,336.347) 71.57,336.347 71.894,336.671 73.737,336.671 73.897,336.511 79.159,336.511 81.373,338.725 86.515,338.725 87.562,339.771 v2(89.852,339.771) ; v6(95.91,297.612) 96.816,297.612 104.279,290.149 109.405,290.149 114.4,285.155 114.4,283.123 117.718,279.805 117.718,269.765 121.083,266.4 121.083,252.824 119.614,251.355 119.614,221.648 115.869,217.902 115.869,213.785 v6(119.367,210.287)
EN_PS_LTC6952_2: U35_I2C_Expander_PWR_CLK.22 U59_5to3V3_2.3 | length 129
  L1 w0.2: U35_I2C_Expander_PWR_CLK.22@134.003,204.878 139.602,204.878 v2(139.865,205.141) ; U59_5to3V3_2.3@204.995,262.738 v2(205.882,262.738)
  L5 (Sign) w0.2: v6(188.154,236.982) 189.406,238.234 189.406,244.129 194.854,249.578 v6(209.313,249.578)
  L3 (Sign) w0.2: v2(139.865,205.141) 139.865,216.776 141.477,218.388 157.389,218.388 165.597,226.596 165.597,227.971 174.608,236.982 v6(188.154,236.982) ; v2(205.882,262.738) 206.443,262.738 213.2,255.981 215.036,255.981 216.129,254.889 216.129,253.746 215.113,252.73 212.749,252.73 209.596,249.578 v6(209.313,249.578)
EN_PS_LTC6952_3: U35_I2C_Expander_PWR_CLK.24
EN_PWR_PCIE_3: U22.A2 U35_I2C_Expander_02.24 | length 20.9
  L1 w0.2: U22.A2@96.228,371.507 v7(96.228,373.137) ; v7(110.567,379.315) 110.571,379.311 112.551,379.311 U35_I2C_Expander_02.24@112.555,379.307
  L3 (Sign) w0.2: v7(96.228,373.137) 98.509,375.418 98.509,376.109 101.715,379.315 v7(110.567,379.315)
EN_PWR_PCIE_4: U23.A2 U35_I2C_Expander_00.19 | length 21
  L1 w0.2: U23.A2@132.155,258.938 132.155,255.047 133.055,254.147 v1(133.69,254.147) ; v1(147.117,255.382) 147.117,255.3 147.203,255.214 147.203,254.626 U35_I2C_Expander_00.19@147.222,254.607
  L5 (Sign) w0.2: v1(133.69,254.147) 134.244,253.594 140.386,253.594 140.947,254.155 144.194,254.155 145.421,255.382 v1(147.117,255.382)
En_PWRSwitch_PCIE0: U17.A2 U35_I2C_Expander_10.27 | length 28.3
  L1 w0.2: U17.A2@183.345,375.802 183.345,377.507 183.738,377.9 191.894,377.9 195.936,373.858 197.463,373.858 203.681,367.64 U35_I2C_Expander_10.27@205.555,367.64
En_PWRSwitch_PCIE1: U20.A2 U35_I2C_Expander_11.19 | length 25.8
  L1 w0.2: U35_I2C_Expander_11.19@198.289,249.285 198.289,251.07 200.455,253.236 206.717,253.236 210.902,257.421 213.871,257.421 217.356,260.906 U20.A2@217.356,261.804
En_PWRSwitch_PCIE2: U21.A2 U35_I2C_Expander_10.17 | length 58.5
  L1 w0.2: U35_I2C_Expander_10.17@209.08,371.815 v7(209.08,372.807) ; v7(262.883,372.741) 263.455,372.741 263.709,372.487 U21.A2@263.709,371.567
  L3 (Sign) w0.2: v7(209.08,372.807) 209.378,372.807 211.566,370.62 214.181,370.62 216.428,372.867 262.718,372.867 262.843,372.741 v7(262.883,372.741)
EN_SEQ_LT3504: R646.2 T48.1 U67.3 U69.5 | length 163.2
  L1 w0.2: U69.5@127.63,233.718 127.63,230.335 127.572,230.276 128.384,230.276 132.158,226.503 v2(134.981,226.503) ; v2(177.539,157.823) U67.3@177.539,158.785
  L3 (Sign) w0.2: v1(118.135,156.477) 118.77,156.477 120.949,158.656 122.448,158.656 132.69,168.897 132.69,169.113 ; v2(134.981,226.503) 134.981,190.773 132.69,188.482 132.69,169.113 ; v2(177.539,157.823) 177.539,158.063 177.078,158.524 143.279,158.524 132.69,169.113
  L14 (Sign) w0.2: v10(103.993,166.174) 104.712,165.456 104.712,160.655 105.804,159.563 105.804,158.382 107.874,156.312 118.135,156.312 v1(118.135,156.477)
EN_SPI_Q0_MAIN: R232_SPI_bridge_Main.1 U35_I2C_Expander_11.20 | length 68.4
  L1 w0.2: U35_I2C_Expander_11.20@197.639,249.285 197.703,249.35 v1(197.703,251.476) ; R232_SPI_bridge_Main.1@225.907,288.068 226.555,288.068 v2(226.603,288.02)
  L5 (Sign) w0.2: v1(197.703,251.476) 198.272,252.044 199.713,252.044 200.768,253.098 207.92,253.098 214.566,259.745 214.566,264.101 219.997,269.532 219.997,291.571 219.786,291.782 v6(219.786,292.227)
  L3 (Sign) w0.2: v6(219.786,292.227) 219.786,289.157 220.971,287.972 226.555,287.972 v2(226.603,288.02)
EN_SPI_Q1: R234_SPI_bridge_PCIe.1 U35_I2C_Expander_11.17 | length 70.1
  L1 w0.2: U35_I2C_Expander_11.17@199.589,249.285 199.589,250.439 200.685,251.536 211.226,251.536 213.893,248.869 235.102,248.869 243.54,257.307 256.901,257.307 257.873,258.279 257.873,261.843 257.253,262.464 R234_SPI_bridge_PCIe.1@256.491,262.464
EN_SPI_Q1_MAIN: R234_SPI_bridge_Main.1 U35_I2C_Expander_11.22 | length 16.7
  L1 w0.2: R234_SPI_bridge_Main.1@191.148,262.461 191.556,262.461 192.037,261.981 192.037,260.096 192.989,259.144 192.989,256.168 195.174,253.984 195.174,248.679 195.492,248.36 U35_I2C_Expander_11.22@196.064,248.36
EN_SPI_Q2: R235_SPI_bridge_PCIe.2 U35_I2C_Expander_10.4 | length 17.2
  L1 w0.2: U35_I2C_Expander_10.4@208.43,366.065 208.43,364.914 208.655,364.689 217.639,364.689 R235_SPI_bridge_PCIe.2@222.34,369.39 R235_SPI_bridge_PCIe.2@222.34,369.44
EN_SPI_Q4: R239_SPI_bridge_PCIe.1 U35_I2C_Expander_11.25 | length 26.3
  L1 w0.12: R239_SPI_bridge_PCIe.1@175.098,259.299 176.033,259.299 179.678,255.653 188.922,246.41 U35_I2C_Expander_11.25@196.064,246.41
EN_SPI_Q4_MAIN: R239_SPI_bridge_Main.1 U35_I2C_Expander_11.28 | length 25
  L1 w0.2: R239_SPI_bridge_Main.1@174.253,236.703 186.22,236.703 193.978,244.46 U35_I2C_Expander_11.28@196.064,244.46
EN_VSUP_1V2: C626.2 R309.2 U19.12 | length 5.8
  L1 w0.12: U19.12@174.078,167.05 174.078,166.489 174.481,166.087 174.892,166.087 175.016,165.963 v7(175.078,165.963) C626.2@175.078,165.753 ; R309.2@177.539,163.705 v7(177.539,164.439)
  L3 (Sign) w0.12: v7(175.078,165.963) 176.015,165.963 v7(177.539,164.439)
EN_VSUP_1V8: C625.2 R308.1 U19.15 | length 5.2
  L1 w0.12: U19.15@175.728,167.7 C625.2@176.862,167.7 176.862,167.108 176.589,166.835 R308.1@176.589,163.705
EN_VSUP_3V3: C624.2 R305.2 U19.14 | length 4.6
  L1 w0.12: U19.14@175.078,167.05 175.078,166.825 175.313,166.59 175.525,166.59 175.676,166.44 175.676,165.918 175.741,165.853 175.741,165.843 175.831,165.753 C624.2@175.841,165.753 176.298,165.753 176.369,165.683 176.369,164.532 175.879,164.042 175.879,163.945 R305.2@175.639,163.705
Enable_CLK: U12.40 U13.40 U35_I2C_Expander_Main_Rst.2 | length 203.3
  L1 w0.2: v7(183.876,275.229) 184.069,275.036 187.948,275.036 187.973,275.061 U13.40@187.973,275.131
  L5 (Sign) w0.2: v6(104.059,333.477) 104.059,326.972 107.785,323.247 107.785,310.234 115.11,302.909 115.11,296.284 115.568,295.825 115.568,292.889 117.475,290.982 117.475,284.777 114.1,281.402 v6(114.1,280.775)
  L12 (Sign) w0.2: v1(114.298,257.92) 114.298,255.209 115.561,253.946 120.355,253.946 121.088,254.678 129.031,254.678 130.308,253.401 136.132,253.401 142.242,247.292 162.102,247.292 v17(167.173,252.363)
  L3 (Sign) w0.12: v1(96.329,338.328) 96.728,338.726 101.508,338.726 104.059,336.175 v6(104.059,333.477)
  L3 (Sign) w0.2: v6(114.1,280.775) 116.218,278.657 116.218,269.144 119.583,265.778 119.583,262.318 119.037,261.772 118.15,261.772 v1(114.298,257.92) ; v3(172.035,274.184) 178.064,274.184 178.797,274.917 183.563,274.917 v7(183.876,275.229)
  L14 (Sign) w0.2: v17(167.173,252.363) 167.173,259.142 169.973,261.942 171.247,263.216 171.247,273.395 v3(172.035,274.184)
  L16 w0.12: U12.40@95.947,337.461 95.947,337.946 v1(96.329,338.328)
  L16 w0.2: v1(114.298,257.92) U35_I2C_Expander_Main_Rst.2@114.298,259.093
ETH_VDDIO: C491.1 C492.1 C493.1 C494.2 C495.2 C496.2 C497.2 C498.2 C531.2 C547.2 C612.2 C613.2 C614.2 C615.2 C742.1 C743.2 C790.1 L17.2 R83.2 R84.2 R85.2 R86.2 R97.2 R98.2 R99.2 R106.1 R123.2 R216.1 R319.2 R320.2 R322.2 R323.2 R333.1 R336.1 R337.1 R338.1 R346.1 R347.1 R348.1 R349.2 R350.2 R351.2 R352.2 R353.1 R354.2 R355.1 R356.1 R357.2 R367.2 R368.2 R369.2 R370.2 R371.2 R372.2 R381.2 R382.2 R709.1 R710.2 R715.2 R716.2 R717.2 R718.2 R719.2 R737.2 R911.1 U1.B22 U1.B27 U1.D18 U1.D23 U1.D28 U1.E21 U1.E26 U1.F19 U1.J18 U1.N20 U1.P18 U36_Trans_PS_I2C1.2 U39.19 U39.30 U39.41 U43.1 U43.2 U43.7 U43.8 U43.15 U43.16 U44.1 U47.B3 U53.15 U56.15 U57.15 U68.3 U76.5 X6.1 X6.4 | length 713.9
  L1 w0.2: R83.2@63.859,327.515 63.825,327.481 63.825,325.955 64.244,325.536 U36_Trans_PS_I2C1.2@65.197,325.536 ; v1(112.673,279.259) C495.2@112.805,279.259 C495.2@112.94,279.259 ; C612.2@179.024,173.275 179.214,173.465 R216.1@179.984,173.465 ; U53.15@217.924,206.333 219.158,206.333 220.616,207.791 227.507,207.791 227.697,207.601 227.697,206.983 R346.1@227.697,203.962 ; X6.1@223.317,331.972 X6.1@223.317,332.123
  L1 w0.254: C614.2@166.001,181.153 166.274,181.426 166.274,181.83 166.424,181.98 177.976,181.98 179.984,179.972 R216.1@179.984,173.515 R216.1@179.984,173.465
  L1 w0.3: R86.2@62.616,330.848 R86.2@62.666,330.848 62.816,330.698 62.816,330.648 63.859,329.605 R83.2@63.859,327.515 ; R86.2@62.72,330.803 v1(63.409,330.803) ; R85.2@62.801,334.29 v1(62.801,334.979) ; R84.2@63.84,322.715 v1(64.53,322.715) ; U68.3@112.895,248.59 v1(113.584,248.59) ; C547.2@134.066,337.795 135.032,337.795 135.274,337.553 R911.1@135.274,337.503 ; v1(162.909,310.027) U1.B22@163.397,309.539 ; v1(162.909,315.027) U1.B27@163.397,314.539 ; v1(164.909,311.027) U1.D23@165.397,310.539 ; U1.D18@165.397,305.539 v1(165.884,305.052) ; U1.D28@165.397,315.539 165.897,315.039 165.897,314.039 v1(165.909,314.027) U1.E26@166.397,313.539 ; U1.E21@166.397,308.539 166.423,308.513 166.86,308.513 v7(166.869,308.503) ; U1.F19@167.397,306.539 v1(167.884,306.052) ; v1(169.909,306.027) U1.J18@170.397,305.539 ; U1.N20@174.397,307.539 v1(174.884,307.052) ; U1.P18@175.397,305.539 v1(175.884,305.052) ; R354.2@215.343,158.27 v1(216.032,158.27) ; R355.1@215.524,154.865 v1(216.213,154.864) ; C531.2@215.6,153.437 v1(216.29,153.437) ; U57.15@223.72,190.348 v1(224.409,190.348) ; R346.1@227.72,203.956 v1(228.409,203.956) ; v1(237.284,160.081) R371.2@237.973,160.081 ; v1(237.284,161.303) R368.2@237.973,161.303 ; v1(242.3,155.255) U44.1@242.3,155.945 ; v1(245.115,152.188) R372.2@245.115,152.878 ; R369.2@249.11,157.246 v1(249.799,157.246) ; R370.2@249.11,158.439 v1(249.799,158.439)
  L1 w0.4: v1(133.842,337.129) 133.728,337.243 133.728,337.457 133.941,337.67 133.941,337.72 134.016,337.795 C547.2@134.066,337.795
  L1 w0.5: R123.2@76.649,335.229 R123.2@76.699,335.229 v1(77.665,335.229) 80.391,335.229 v1(80.404,335.242) ; v1(106.134,288.023) 109.087,288.023 v1(109.18,287.93) ; C491.1@108.948,275.047 108.948,274.794 v1(109.315,274.427) ; C498.2@110.049,275.047 C494.2@111.136,275.047 111.13,275.041 v1(111.13,274.369) ; v1(119.177,303.963) 119.177,305.154 123.725,309.702 134.163,309.702 134.493,310.032 134.493,310.543 134.382,310.653 v1(134.382,310.902) 134.382,311.816 134.024,312.174 R99.2@134.029,312.179 ; v1(120.459,276.153) 120.459,279.719 v1(120.732,279.992) ; 166.192,183.337 179.362,183.337 183.192,179.507 v2(183.192,178.663) ; X6.4@223.317,329.372 X6.1@223.317,331.972 ; X6.1@223.317,332.123 223.317,332.973 v1(223.618,333.273) ; v1(227.949,352.285) 230.073,350.161 230.073,345.695 233.147,342.621 235.53,342.621 ; v1(234.22,340.116) 234.22,341.311 235.53,342.621 ; R352.2@243.559,350.291 v1(243.559,346.654) 243.559,344.221 241.959,342.621 235.53,342.621 ; v1(249.81,344.703) 249.81,345.801 251.71,347.701 v1(252.591,347.701) 254.334,347.701 257.217,350.583 C742.1@258.34,350.583
  L5 (Sign) w0.5: v1(116.408,282.1) 117.84,282.1 123.279,287.539 123.279,293.04 119.987,296.332 119.987,302.337 119.177,303.148 v1(119.177,303.963) ; v1(120.739,364.261) 120.739,362.367 124.864,358.242 v1(128.949,358.242) ; v1(226.035,172.11) v6(226.035,183.541)
  L8 (Plane_GND) w0.5: v1(137.858,337.845) 145.275,337.845 v18(147.434,340.004)
  L9 (PWR/GND) w0.5: v1(133.842,337.129) 135.623,335.348 135.623,332.638 132.956,329.971 132.956,312.328 v1(134.382,310.902) ; v18(147.434,340.004) 148.78,341.351 152.089,341.351 156.712,345.973 157.159,345.973 157.159,346.235 157.34,346.416 157.34,346.469 161.353,350.482 181.038,350.482 186.88,356.324 v1(186.88,357.708)
  L3 (Sign) w0.3: v1(164.909,311.027) 164.948,310.989 165.439,310.989 165.771,310.657 165.862,310.566 166.945,310.566 167.402,310.109 167.402,309.468 167.409,309.46 167.409,308.703 167.22,308.513 166.879,308.513 v7(166.869,308.503)
  L3 (Sign) w0.5: v2(183.192,178.663) 183.192,176.853 188.233,171.812 188.233,164.943 189.867,163.309 199.904,163.309 v2(204.114,159.098) ; v1(224.409,190.348) 226.035,190.348 ; v6(226.035,183.541) 226.035,190.348 ; v1(228.409,203.956) 228.409,199.834 226.123,197.548 226.123,190.436 226.035,190.348
  L7(12V+Other) w0.5: v1(108.549,283.974) 109.18,284.605 v1(109.18,287.93) ; v1(112.673,279.259) 113.493,280.08 114.388,280.08 v1(116.408,282.1)
  L10 (3V3+Other) w0.5: v1(80.404,335.242) 80.404,335.911 83.236,338.744 85.724,338.744 88.153,341.173 108.046,341.173 111.649,337.57 124.261,337.57 127.266,340.575 128.949,340.575 ; v1(128.949,358.242) 128.949,340.575 ; v1(133.842,337.129) 132.841,338.13 ; v1(137.858,337.845) 137.574,338.13 132.841,338.13 ; 128.949,340.575 131.393,338.13 132.841,338.13
  L14 (Sign) w0.2: v1@133.831,336.886 134.729,335.988 v10(134.729,335.804)
  L14 (Sign) w0.5: v14(101.28,274.428) 103.682,274.428 105.635,272.475 109.237,272.475 v1(111.13,274.369) ; v10(117.334,273.531) v10(117.334,276.363) ; v1(137.858,337.845) 140.651,337.845 v10(142.327,339.522)
  L15 (GND) w0.5: v4(139.375,331.584) 139.375,333.794 142.411,336.83 142.365,336.877 v4(139.375,336.877) 139.375,339.177 139.72,339.522 139.745,339.496 139.77,339.522 v10(142.327,339.522)
  L16 w0.2: R709.1@108.074,271.094 108.952,271.094 109.315,271.457 v1(109.315,274.427) 109.049,274.693 U39.41@109.049,275.125 ; U39.19@108.549,281.925 v1(108.549,283.974) ; U39.30@111.699,278.775 112.046,278.775 112.53,279.259 v1(112.673,279.259) ; C790.1@255.891,347.987 C790.1@255.918,347.987
  L16 w0.3: v1(62.801,334.979) 62.261,334.439 62.261,331.951 v1(63.409,330.803) 63.409,324.652 63.799,324.263 63.799,323.446 v1(64.53,322.715) ; R333.1@106.134,287.334 v1(106.134,288.023) ; v1(109.18,287.93) 109.18,287.443 R337.1@109.354,287.269 ; R319.2@120.332,279.937 120.425,280.029 120.462,279.992 v1(120.732,279.992) ; R320.2@120.373,276.872 120.459,276.785 v1(120.459,276.153) ; U76.5@260.689,347.701 v1(261.379,347.701) ; v1(263.919,346.559) R710.2@263.919,347.157 R710.2@263.919,347.207
  L16 w0.5: v1(62.801,334.979) 62.801,335.384 64.907,337.49 74.867,337.49 77.127,335.229 v1(77.665,335.229) ; R737.2@98.501,266.643 R737.2@98.501,266.693 98.501,270.563 101.28,273.343 v14(101.28,274.428) ; U56.15@99.259,295.63 102.365,295.63 103.762,294.232 103.762,290.776 106.134,288.404 v1(106.134,288.023) ; v1(111.13,274.369) 111.973,273.527 R323.2@117.33,273.527 ; R98.2@113.883,399.809 R98.2@113.833,399.809 111.546,397.521 111.546,371.492 117.151,365.887 119.109,365.887 120.734,364.261 v1(120.739,364.261) ; R323.2@117.323,273.52 R323.2@117.33,273.527 ; R323.2@117.334,273.527 R323.2@117.33,273.527 ; v10(117.334,273.531) R323.2@117.33,273.527 ; v10(117.334,276.363) R322.2@117.334,276.472 ; v1(186.88,357.708) 186.28,357.708 186.191,357.797 ; R717.2@187.962,361.831 R717.2@187.912,361.831 186.639,361.831 186.191,361.384 ; R716.2@188.002,363.868 R716.2@187.952,363.868 187.644,363.56 186.191,363.56 ; R718.2@188.005,360.007 R718.2@187.955,360.007 186.786,360.007 186.191,359.412 ; R719.2@188.012,356.362 R719.2@187.962,356.362 187.258,356.362 186.191,357.429 186.191,357.797 ; U43.16@198.37,363.679 197.895,363.679 196.068,365.505 187.748,365.505 186.191,363.948 186.191,363.56 ; U43.1@204.17,363.679 206.739,363.679 207.56,362.859 211.703,362.859 220.736,353.826 226.408,353.826 v1(227.949,352.285) ; 204.47,358.854 205.395,357.929 207.404,357.929 207.968,358.493 207.968,359.346 R353.1@207.968,360.667 ; v1(223.618,333.273) 227.378,333.273 v1(234.22,340.116) 234.307,340.03 235.294,340.03 235.301,340.023 235.301,338.639 R356.1@235.307,338.633 ; v1(243.559,346.654) 245.51,344.703 v1(249.81,344.703) 260.83,344.703 261.379,345.252 v1(261.379,347.701) 262.52,346.559 v1(263.919,346.559) ; v1(252.591,347.701) 252.606,347.716 254.874,347.716 255.01,347.852 ; 255.146,347.987 C790.1@255.891,347.987 ; 186.191,357.797 186.191,359.412 ; 186.191,359.412 186.191,361.384 ; 186.191,361.384 186.191,363.56
  other v1: 160.445,182.472 161.332,182.472 162.233,182.472 163.116,182.472 164.002,182.472 160.445,183.296 161.332,183.296 162.233,183.296 163.116,183.296 164.002,183.296 160.445,184.121 161.332,184.121 162.233,184.121 163.116,184.121 164.002,184.121 160.445,184.946 161.332,184.946 162.233,184.946 163.116,184.946 164.002,184.946
EXPANDER_RESET: J21.2 P13.2 R811.1 R1003.2 R1115.2 T1.1 | length 36.3
  L1 w0.2: P13.2@100.343,263.322 100.362,263.322 104.565,259.118 105.397,259.118 107.785,256.731 109.791,256.731 111.747,254.775 J21.2@111.747,253.771 113.133,253.771 113.755,253.149 113.755,251.835 R1003.2@113.744,251.823
  L16 w0.2: P13.2@100.343,263.322 102.037,265.016 102.037,266.66 103.924,268.548 T1.1@106.581,268.548 ; J21.2@111.747,253.771 111.922,253.946 116.648,253.946 117.34,253.254 R1115.2@118.762,253.254
FB1/FB2: R271.1 R273.2 U34.10 U34.31 | length 189.7
  L1 w0.254: v1(62.07,239.674) 62.683,239.674 62.81,239.802 R273.2@62.814,239.798 ; R273.2@62.814,239.66 62.814,239.21 v1(63.791,238.233) 63.822,238.202 U34.31@63.822,237.639 ; R273.2@62.818,239.66 R273.2@62.935,239.777 ; v1(62.82,232.364) 63.456,232.364 63.82,232.728 63.82,233.137 U34.10@63.822,233.139
  L5 (Sign) w0.4: v6(84.188,266.09) 84.188,266.446 88.598,270.856 94.808,270.856 v1(96.393,272.441)
  L9 (PWR/GND) w0.4: v1(96.393,272.441) 96.571,272.619 96.571,282.321 101.63,287.38 124.151,287.38 128.727,282.804 v1(134.304,282.804)
  L3 (Sign) w0.4: v1(62.07,239.674) 62.651,239.674 62.814,239.837 62.814,240.055 71.45,248.691 71.45,250.495 80.521,259.565 80.521,262.423 v6(84.188,266.09)
  L14 (Sign) w0.4: v1(134.304,282.804) 135.04,283.54 141.649,283.54 142.49,282.699 144.351,282.699 145.205,283.553 152.225,283.553 154.93,280.848 155.562,280.848 v10(155.804,281.089) ; v10(158.744,299.466) 159.865,299.466 160.252,299.852 169.806,299.852 170.832,298.827 170.832,297.185 172.679,295.338 177.821,295.338 179.169,293.989 179.625,293.989 179.947,294.312 179.947,296.767 v10(179.946,296.888) 179.794,297.04
  L16 w0.254: v1(62.82,232.364) 62.82,233.594 63.035,233.808 63.035,237.476 v1(63.791,238.233)
  L16 w0.4: v10(155.804,281.089) 156.019,281.305 156.019,282.659 155.01,283.668 155.01,291.58 152.915,293.675 152.915,295.072 157.309,299.466 v10(158.744,299.466) ; v10(179.946,296.888) 180.581,296.888 180.847,297.154 R271.1@180.847,297.539
FB1_1: R287.1 R290.1 U37.31 | length 4.1
  L1 w0.2: R287.1@61.241,183.359 62.191,183.359 62.191,182.779 62.408,182.562 63.716,182.562 64.175,182.104 U37.31@64.175,181.817
FB1_2: R626.1 R627.2 U38.31 | length 3.3
  L1 w0.254: R626.1@59.997,209.711 60.008,209.722 60.932,209.722 60.944,209.733 61.102,209.575 62.252,209.575 62.453,209.374 U38.31@62.453,208.714
FB2_1: R297.2 R300.1 U37.10 | length 4.1
  L1 w0.254: R300.1@61.068,175.851 62.14,175.851 62.14,176.257 62.455,176.572 63.749,176.572 64.175,176.997 U37.10@64.175,177.317
FB2_2: R315.1 R318.2 U38.10 | length 3.5
  L1 w0.254: R318.2@60.114,202.723 61.041,202.723 61.041,203.148 61.384,203.491 62.28,203.491 62.453,203.664 U38.10@62.453,204.214
Flag_PWRSwitch_PCIE0: R618.2 U17.A3 | length 120.7
  L1 w0.2: U17.A3@183.745,375.802 183.745,377.483 183.862,377.6 191.77,377.6 195.811,373.558 197.295,373.558 218.259,352.595 218.259,335.978 219.592,334.645 221.691,334.645 222.148,334.188 224.714,334.188 225.628,333.273 225.628,321.098 229.823,316.903 229.823,307.18 230.579,306.424 246.197,306.424 248.14,304.482 v1(248.14,303.546) R618.2@248.14,302.785
Flag_PWRSwitch_PCIE1: R688.2 U20.A3 | length 67
  L1 w0.2: U20.A3@216.956,261.804 216.956,261.5 216.656,261.2 216.656,260.744 216.238,260.326 215.603,260.326 214.71,261.219 214.71,264.245 229.185,278.719 v1(237.787,278.719) ; R688.2@249.503,302.635 249.551,302.683 v1(249.551,303.596)
  L12 (Sign) w0.2: v1(237.787,278.719) 238.652,278.719 249.551,289.618 v1(249.551,303.596)
Flag_PWRSwitch_PCIE2: R744.2 U21.A3 | length 93.4
  L1 w0.2: R744.2@253.593,302.785 v1(253.593,303.546) ; U21.A3@264.109,371.567 264.109,371.871 264.409,372.171 v1(264.409,372.627)
  L5 (Sign) w0.2: v1(264.409,372.627) 265.593,372.627 266.687,371.533 266.687,369.722 269.093,367.317 v12(269.093,320.015)
  L3 (Sign) w0.2: v1(253.593,303.546) 254.359,303.546 255.029,302.877 257.787,302.877 259.614,304.704 271.37,304.704 272.797,306.131 272.797,312.55 271.628,313.719 269.093,316.254 v12(269.093,320.015)
Flag_PWRSwitch_PCIE3: R767.2 U22.A3 | length 198.9
  L1 w0.2: U22.A3@96.628,371.507 96.628,371.811 96.928,372.111 96.928,372.546 97.045,372.663 106.796,372.663 v1(107.296,372.163) ; R767.2@252.23,302.785 v1(252.23,303.546)
  L5 (Sign) w0.2: v1(107.296,372.163) 107.652,371.807 159.034,371.807 162.41,368.432 162.41,358.168 164.617,355.962 209.479,355.962 213.308,352.133 213.308,349.705 232.893,330.12 v1(232.893,327.61)
  L14 (Sign) w0.2: v1(232.893,327.61) 232.893,320.587 243.503,309.977 244.61,309.977 249.608,304.979 250.797,304.979 v1(252.23,303.546)
Flag_PWRSwitch_PCIE4: R819.2 U23.A3 | length 171.8
  L1 w0.2: U23.A3@131.755,258.938 131.755,258.633 131.455,258.333 131.455,257.808 131.139,257.492 130.483,257.492 129.34,258.635 129.34,261.08 134.736,266.476 141.445,266.476 143.287,268.318 144.212,268.318 145.661,269.768 148.041,269.768 148.083,269.726 v7(161.123,269.726) ; R819.2@259.161,302.785 v1(259.161,303.546)
  L12 (Sign) w0.2: v1(213.483,268.465) 222.82,277.802 241.504,277.802 252.296,288.595 256.02,288.595 257.925,290.5 257.925,297.836 259.161,299.071 v1(259.161,303.546)
  L3 (Sign) w0.2: v7(161.123,269.726) 162.829,269.726 166.477,266.078 166.477,261.716 167.748,260.445 197.035,260.445 201.796,265.206 205.957,265.206 209.216,268.465 v1(213.483,268.465)
FTD_DS_Dir1: R411.2 R412.2 U56.1 | length 6.5
  L16 w0.2: U56.1@105.059,296.28 105.059,296.499 106.794,298.234 108.28,298.234 108.583,297.931 108.583,297.394 R411.2@109.944,297.394
FTD_DS_Dir2: R413.2 R414.2 U56.2 | length 5.1
  L16 w0.2: U56.2@105.059,295.63 108.153,295.63 108.778,296.255 R413.2@109.944,296.255
FTD_DS_Dir3: R415.2 R416.2 U56.7 | length 6.2
  L16 w0.2: U56.7@105.059,292.38 106.387,292.38 106.504,292.497 106.504,293.118 106.999,293.613 108.367,293.613 108.583,293.397 108.583,293.005 109.287,293.005 109.296,293.014 109.935,293.014 R415.2@109.944,293.005
FTD_DS_Dir4: R418.2 R421.2 U56.8 | length 5.9
  L16 w0.2: U56.8@105.059,291.73 106.264,291.73 106.266,291.732 106.362,291.732 107.123,290.972 108.206,290.972 108.583,291.349 108.583,291.866 R418.2@109.944,291.866
FTD_JTAG_Dir1: R402.2 R403.2 U53.1 | length 6
  L1 w0.2: R402.2@207.239,207.472 208.599,207.472 208.599,207.923 208.816,208.14 210.39,208.14 210.507,208.023 210.507,207.864 211.263,207.108 211.999,207.108 U53.1@212.124,206.983
FTD_JTAG_Dir2: R404.2 R405.2 U53.2 | length 5.5
  L1 w0.2: R404.2@207.239,206.333 208.599,206.333 208.599,206.616 208.816,206.833 210.854,206.833 211.239,206.448 212.009,206.448 U53.2@212.124,206.333
FTD_JTAG_Dir3: R406.2 R407.2 U53.7 | length 5.5
  L1 w0.2: R406.2@207.239,203.083 208.599,203.083 208.599,202.8 208.816,202.583 210.704,202.583 211.204,203.083 U53.7@212.124,203.083
FTD_JTAG_Dir4: R408.2 R409.2 U53.8 | length 5.8
  L1 w0.2: R408.2@207.239,201.944 208.599,201.944 208.599,201.499 208.749,201.349 210.517,201.349 211.474,202.305 211.474,202.308 211.599,202.433 U53.8@212.124,202.433
FTD_U1_DIR1: R722.2 R723.2 U79.1 | length 5.8
  L1 w0.2: v2(225.958,225.527) 226.448,226.016 U79.1@226.448,227.025 ; R722.2@225.959,222.14 v2(225.958,222.821) ; v2(225.958,222.821) R723.2@225.959,223.5
  L3 (Sign) w0.2: v2(225.958,222.821) v2(225.958,225.527)
FTD_U1_DIR2: R724.2 R725.2 U79.2 | length 5.6
  L1 w0.2: R724.2@227.098,222.14 v2(227.098,222.821) R725.2@227.098,223.5 ; U79.2@227.098,227.025 227.101,227.022 v2(227.101,225.501)
  L3 (Sign) w0.2: v2(227.098,222.821) v2(227.098,222.821) 227.1,225.499 v2(227.101,225.501)
FTD_U1_DIR3: R726.2 R727.2 U79.7 | length 5.6
  L1 w0.2: R726.2@230.348,222.14 v7(230.348,222.82) R727.2@230.348,223.5 ; v7(230.348,225.527) U79.7@230.348,227.025
  L3 (Sign) w0.2: v7(230.348,222.82) v7(230.348,225.527)
FTD_U1_DIR4: R728.2 R729.2 U79.8 | length 5.8
  L1 w0.2: v7(230.998,225.527) U79.8@230.998,227.025 ; R728.2@231.487,222.14 v7(231.487,222.82) R729.2@231.487,223.5
  L3 (Sign) w0.2: v7(230.998,225.527) 230.998,223.309 v7(231.487,222.82)
FTD_U_DIR1: R636.2 R637.2 U57.1 | length 6.1
  L1 w0.2: U57.1@228.998,189.698 229.456,189.698 229.581,189.573 229.581,189.29 230.295,188.576 232.405,188.576 232.523,188.694 232.523,189.21 R636.2@233.883,189.21
FTD_U_DIR2: R638.2 R639.2 U57.2 | length 5.6
  L1 w0.2: U57.2@228.998,190.348 229.023,190.323 229.813,190.323 230.365,189.771 232.405,189.771 232.523,189.888 232.523,190.348 R638.2@233.883,190.348
FTD_U_DIR3: R640.2 R641.2 U57.7 | length 5.6
  L1 w0.2: U57.7@228.998,193.598 229.793,193.598 230.317,194.122 232.405,194.122 232.523,194.005 232.523,193.598 R640.2@233.883,193.598
FTD_U_DIR4: R642.2 R643.2 U57.8 | length 6.2
  L1 w0.2: U57.8@228.998,194.248 229.519,194.248 229.644,194.373 229.644,194.601 230.551,195.509 232.405,195.509 232.523,195.391 232.523,194.737 R642.2@233.883,194.737
FTDI_5V: C559.1 C560.2 C563_5V_to_3V3_for_FTDI.2 C564_5V_to_3V3_for_FTDI.2 FB31.1 U59_5V_to_3V3_for_FTDI.1 U59_5V_to_3V3_for_FTDI.2 U59_5V_to_3V3_for_FTDI.3 | length 48.2
  L1 w0.5: v2@263.096,199.737 v2(263.101,199.737) C563_5V_to_3V3_for_FTDI.2@264.408,199.737 ; v2(263.106,201.13) 263.11,201.125 C564_5V_to_3V3_for_FTDI.2@264.395,201.125 ; U59_5V_to_3V3_for_FTDI.1@263.944,205.477 U59_5V_to_3V3_for_FTDI.2@264.594,205.477 ; C564_5V_to_3V3_for_FTDI.2@264.408,201.138 C560.2@264.408,202.548 264.594,202.733 U59_5V_to_3V3_for_FTDI.2@264.594,205.477 ; U59_5V_to_3V3_for_FTDI.3@265.244,205.477 U59_5V_to_3V3_for_FTDI.2@264.594,205.477 ; FB31.1@267.792,163.19 v2(267.792,164.516)
  L3 (Sign) w0.5: v2(263.101,199.737) v2@263.106,199.733 ; v2(263.106,201.13) v2@263.106,199.733 ; v2(267.792,164.516) 266.103,166.205 266.103,195.453 263.106,198.45 v2@263.106,199.733
FTDI_D_N: C558.2 D15.2 U55.7 | length 81.4
  L1 w0.135: v3(246.445,213.264) 246.445,211.341 ccw(c246.47,211.341) U55.7@246.47,211.316 ; 264.834,165.029 264.837,165.031 ; 264.837,165.029 264.837,165.031 ; v19(264.879,165.271) 264.837,165.229 264.837,165.031 ; C558.2@267.858,157.207 267.858,157.412 ccw(c266.679,157.412) 266.679,158.591 266.199,158.591 cw(c266.199,159.946) 264.844,159.946 264.844,162.651 264.716,162.778 D15.2@264.716,163.815 264.844,163.943 264.844,164.213 264.837,164.22 264.837,165.032
  L5 (Sign) w0.1: 247.852,215.7 256.46,215.7 cw(c256.46,213.639) 258.521,213.639 258.521,199.936 258.521,199.76 cw(c258.43,199.76) 258.43,199.669 258.26,199.669 ccw(c258.26,199.578) 258.169,199.578 258.169,199.457 ccw(c258.26,199.457) 258.26,199.366 258.43,199.366 cw(c258.43,199.275) 258.521,199.275 258.521,199.214 ccw(c260.631,199.214) 260.631,197.104 263.715,197.104 cw(c263.715,195.941) 264.878,195.941
  L5 (Sign) w0.111: v3(246.445,213.264) 246.445,213.369 246.325,213.489 246.325,213.68 246.325,214.296 cw(c247.729,214.296) 247.729,215.7 247.852,215.7 ; v12(264.759,165.735) 264.879,165.615 v12@264.879,165.604 ; v12@264.879,165.735 264.879,195.941
  L3 (Sign) w0.111: v12(264.759,165.735) 264.759,165.629 264.879,165.51 v19(264.879,165.271)
FTDI_D_P: C558.3 D15.1 U55.8 | length 81.4
  L1 w0.135: v3(245.845,213.236) 245.845,211.491 245.995,211.341 cw(c245.97,211.341) U55.8@245.97,211.316 ; v19(265.24,165.271) 265.24,165.255 265.282,165.213 265.282,165.029 ; 265.284,165.029 265.284,165.057 265.282,165.059 265.282,164.404 265.289,164.397 265.289,163.943 D15.1@265.416,163.815 265.416,162.778 265.289,162.651 265.289,159.946 ccw(c266.199,159.946) 266.199,159.036 266.679,159.036 ccw(c266.679,160.215) 267.858,160.215 C558.3@267.858,160.407
  L5 (Sign) w0.1: 247.852,216.062 256.46,216.062 cw(c256.46,213.639) 258.883,213.639 258.883,199.214 ccw(c260.631,199.214) 260.631,197.466 263.715,197.466 cw(c263.715,195.941) 265.24,195.941
  L5 (Sign) w0.111: v3(245.845,213.236) 245.845,213.341 245.964,213.461 245.964,213.83 245.964,214.296 cw(c247.731,214.296) 247.731,216.062 247.852,216.062 ; v12@265.24,165.604 265.359,165.723 v12(265.359,165.735) ; v12@265.24,165.735 265.24,195.941
  L3 (Sign) w0.111: v19(265.24,165.271) 265.24,165.51 265.359,165.629 v12(265.359,165.735)
FTDI_EECLK: R417.2 U54.4 U55.62 | length 15
  L1 w0.2: U55.62@251.27,208.516 252.544,208.516 255.033,211.005 256.484,211.005 258.483,213.004 260.274,213.004 261.021,213.751 U54.4@261.021,214.539 261.021,215.562 261.417,215.959 R417.2@261.417,216.626
FTDI_EECS: R420.2 U54.5 U55.63 | length 13.7
  L1 w0.2: U55.63@251.27,209.016 252.501,209.016 254.825,211.341 256.389,211.341 258.508,213.46 259.891,213.46 260.071,213.639 U54.5@260.071,214.539 260.071,215.564 260.159,215.653 R420.2@260.159,216.563
FTDI_EED: R419.1 U54.3 U55.61 | length 12.5
  L1 w0.2: U55.61@251.27,208.016 252.606,208.016 254.021,209.431 254.665,209.431 254.665,209.697 255.563,210.595 256.691,210.595 258.771,212.674 260.631,212.674 261.021,212.284 U54.3@261.021,211.739
FTDI_GND: C559.2 C560.1 C563_5V_to_3V3_for_FTDI.1 C564_5V_to_3V3_for_FTDI.1 C565_5V_to_3V3_for_FTDI.1 C566_5V_to_3V3_for_FTDI.1 C567_5V_to_3V3_for_FTDI.1 C658.1 C659.1 C660.1 C661.1 C662.1 C663.1 C664.1 C665.1 C666.1 C667.1 C668.1 C669.1 C670.1 C671.1 C673.1 C791.1 FB32.1 R403.1 R405.1 R407.1 R409.1 R412.1 R414.1 R416.1 R421.1 R423.2 R432_5V_to_3V3_for_FTDI.1 R637.1 R639.1 R641.1 R643.1 R723.1 R725.1 R727.1 R729.1 S9.5 S9.6 S9.7 S9.8 U53.10 U54.2 U55.1 U55.5 U55.10 U55.11 U55.13 U55.15 U55.25 U55.35 U55.47 U55.51 U56.10 U57.10 U59_5V_to_3V3_for_FTDI.4 U59_5V_to_3V3_for_FTDI.9 U77.2 U79.10 X8.2 X8.4 | length 236.1
  L1 w0.2: U77.2@215.024,210.512 215.903,210.512 v1(215.913,210.502) ; U55.15@242.47,211.067 v1(242.47,210.378) 243.352,210.378 243.47,210.495 U55.13@243.47,211.316 ; U55.35@242.97,200.216 242.969,197.661 243.086,197.544 C666.1@243.813,197.544 ; U55.51@251.27,203.016 252.501,203.016 v1(252.501,203.023) ; C566_5V_to_3V3_for_FTDI.1@254.712,200.046 v1(255.127,200.046)
  L1 w0.3: R407.1@209.567,203.083 v1(210.256,203.083) ; R409.1@209.574,201.944 v1(210.263,201.944) ; R405.1@209.574,206.333 v1(210.263,206.333) ; R403.1@209.574,207.428 v1(210.263,207.428) ; v1(213.222,207.973) C791.1@213.222,208.662 ; v1(216.706,203.083) U53.10@217.396,203.083 ; U57.10@223.72,193.59 v1(224.409,193.59) ; U79.10@230.348,232.825 v1(230.348,234.063) ; v1(230.504,193.587) 230.515,193.598 R641.1@231.573,193.598 R641.1@231.623,193.598 ; v1(230.504,194.723) R643.1@231.573,194.723 ; v1(230.582,189.21) R637.1@231.573,189.21 R637.1@231.586,189.21 ; v1(230.582,190.348) R639.1@231.506,190.348 ; v1(236.683,198.151) C669.1@237.373,198.151 ; v1(236.709,199.087) C668.1@237.398,199.087 ; v1(236.901,211.789) C670.1@237.59,211.789 ; v1(236.901,212.887) C671.1@237.59,212.887 ; U55.25@240.562,205.516 v1(241.251,205.516) ; C667.1@240.851,217.199 v1(240.851,217.888) ; U55.35@242.98,200.574 v1(242.98,201.263) ; C659.1@243.891,218.067 v1(243.891,218.756) ; v1(244.47,210.404) U55.11@244.47,211.094 ; C660.1@245.492,217.127 v1(245.492,217.816) ; C662.1@246.246,221.148 v1(246.246,221.838) ; C661.1@247.434,221.575 v1(247.434,222.265) ; v1(247.47,210.404) U55.5@247.47,211.094 ; U55.47@248.97,200.574 v1(248.97,201.263) ; v1(252.065,217.341) X8.4@252.754,217.341 ; v1(252.605,197.889) C673.1@252.606,198.422 ; v1(253.406,215.142) 253.406,215.824 C663.1@253.406,215.831 ; C665.1@253.443,211.739 v1(254.512,211.739) ; C664.1@254.102,221.148 v1(254.102,221.838) ; C565_5V_to_3V3_for_FTDI.1@255.312,199.095 v1(256.002,199.095) ; C567_5V_to_3V3_for_FTDI.1@255.506,205.136 v1(256.575,205.136) ; v1(256.642,219.018) 257.331,219.018 ; v1(260.11,210.801) U54.2@260.11,211.491 ; C559.2@265.423,203.945 C559.2@265.558,203.945 v1(266.255,203.944) v1(266.255,203.944) ; C564_5V_to_3V3_for_FTDI.1@265.645,201.125 266.48,201.125 v1(266.488,201.117) ; C563_5V_to_3V3_for_FTDI.1@265.658,199.737 v1(266.535,199.737) ; C560.1@265.658,202.548 266.406,202.548 v1(266.408,202.549) ; U59_5V_to_3V3_for_FTDI.4@265.894,205.477 265.894,204.818 v1(265.9,204.818) ; R432_5V_to_3V3_for_FTDI.1@267.268,208.162 v1(267.995,208.162) ; FB32.1@271.043,163.368 v1(271.043,164.3)
  L1 w0.5: v1(225.342,224.421) ccw(c225.362,224.421) 225.362,224.4 225.959,224.4 R725.1@227.098,224.4 ; R727.1@230.348,224.4 231.487,224.4 232.212,224.4 ccw(c232.212,224.421) v1(232.232,224.421) ; R423.2@246.959,217.125 R423.2@246.959,217.175 v1(246.959,218.071) ; C663.1@253.406,215.824 C663.1@253.411,215.824 ; X8.2@254.777,219.641 256.018,219.641 v1(256.642,219.018) ; 257.331,219.018 C658.1@258.596,219.018 C658.1@258.731,219.018
  L12 (Sign) w0.2: v16(106.954,293.256) 106.959,293.261 v16(106.959,297.243)
  L12 (Sign) w0.3: v1(98.006,292.456) 98.552,293.002 v16(104.958,293.002) ; v16(169.786,262.392) 169.853,262.392 v16(170.586,261.658)
  L14 (Sign) w0.2: v10(106.954,292.724) v16(106.954,293.256) ; v10(106.959,296.824) v16(106.959,297.243)
  L14 (Sign) w0.3: v16(104.958,293.002) 105.236,292.724 v10(106.954,292.724) 107.517,292.724 108.774,291.466 111.761,291.466 112.065,291.77 v10(112.065,291.922) ; v10(131.305,277.619) 131.404,277.52 132.893,277.52 133.636,276.777 142.361,276.777 143.116,276.022 143.116,272.91 144.774,271.253 160.598,271.253 169.459,262.392 v16(169.786,262.392) ; v16(170.586,261.658) 168.51,259.582 168.51,254.723 173.914,249.32 175.444,249.32 191.948,232.816 191.948,220.929 191.257,220.238 v10(191.257,218.994)
  L16 w0.2: v10(106.954,292.724) 107.248,292.43 107.678,292.43 107.683,292.436 ; v10(106.959,296.824) 107.683,296.824 ; R421.1@107.683,291.866 107.683,292.436 ; R416.1@107.683,293.005 107.683,292.436
  L16 w0.3: v1(98.006,292.456) 98.082,292.38 U56.10@99.259,292.38 ; R414.1@107.683,296.255 107.683,296.824 R412.1@107.683,297.394 ; v10(112.065,291.922) 112.674,291.922 118.629,285.968 126.719,285.968 132.448,280.238 132.448,280.22 132.556,280.112 132.556,278.472 132.448,278.364 132.448,278.346 131.722,277.619 v10(131.305,277.619) ; v10(191.257,218.994) 193.913,216.338 199.971,216.338 207.048,209.261 207.048,209.017 208.636,207.428 v1(210.263,207.428) ; S9.8@228.629,175.874 228.656,175.848 230.368,175.848 v1(230.395,175.821) ; S9.7@228.629,177.144 S9.7@228.629,177.144 230.395,177.146 v1(230.396,177.147) ; S9.6@228.629,178.414 v1(230.396,178.414) ; S9.5@228.629,179.684 v1(230.396,179.684)
  other v3: 264.419,206.277 265.419,206.277 264.419,207.277 265.419,207.277
FTDI_JTAG_ON: R1001.2 R1034.2 | length 43.6
  L1 w0.2: v2(233.756,208.14) 236.547,208.14 R1034.2@236.559,208.152
  L3 (Sign) w0.2: v1(219.659,180.632) 229.171,180.632 231.421,182.883 231.421,195.912 233.756,198.247 v2(233.756,208.14)
  L16 w0.2: v1(219.659,180.632) 219.659,181.839 219.969,182.148 R1001.2@220.192,182.148
FTDI_JTAG_ON_1: R401.1 R1001.1 S8.1 S9.1 U35_I2C_Expander_12.17 U53.9 | length 122.8
  L1 w0.2: U35_I2C_Expander_12.17@140.566,182.44 140.566,183.72 v2(141.402,184.556) ; U53.9@217.924,202.433 217.924,201.621 v2(217.957,201.587)
  L5 (Sign) w0.2: v6(145.704,184.673) 146.255,184.673 147.468,185.885 163.699,185.885 164.715,184.87 193.634,184.87 194.323,185.559 212.764,185.559 216.175,182.148 v1(222.102,182.148)
  L3 (Sign) w0.2: v2(141.402,184.556) 145.588,184.556 v6(145.704,184.673) ; v2(217.957,201.587) 215.862,199.492 215.862,189.987 219.215,186.634 219.215,183.165 220.232,182.148 v1(222.102,182.148)
  L16 w0.2: R1001.1@221.092,182.148 v1(222.102,182.148) ; S9.1@223.829,175.874 221.092,175.874 221.092,180.003 222.102,181.014 v1(222.102,182.148) ; S8.1@223.829,182.148 v1(222.102,182.148)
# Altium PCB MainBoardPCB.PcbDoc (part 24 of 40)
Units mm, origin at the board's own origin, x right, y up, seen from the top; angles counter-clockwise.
Board outline 258.95 x 308.86 mm, 16 copper layers (L1, L2 (GND), L3 (Sign), L4 (GND), L5 (Sign), L6 (PWR/GND), L7(12V+Other), L8 (Plane_GND), L9 (PWR/GND), L10 (3V3+Other), L11 (PWR/GND), L12 (Sign), L13 (GND), L14 (Sign), L15 (GND), L16), stack 2.503 mm thick; 2578 components, 1867 nets, 8817 pads, 8021 vias.
Unrouted connection lines stored in the file: 25.

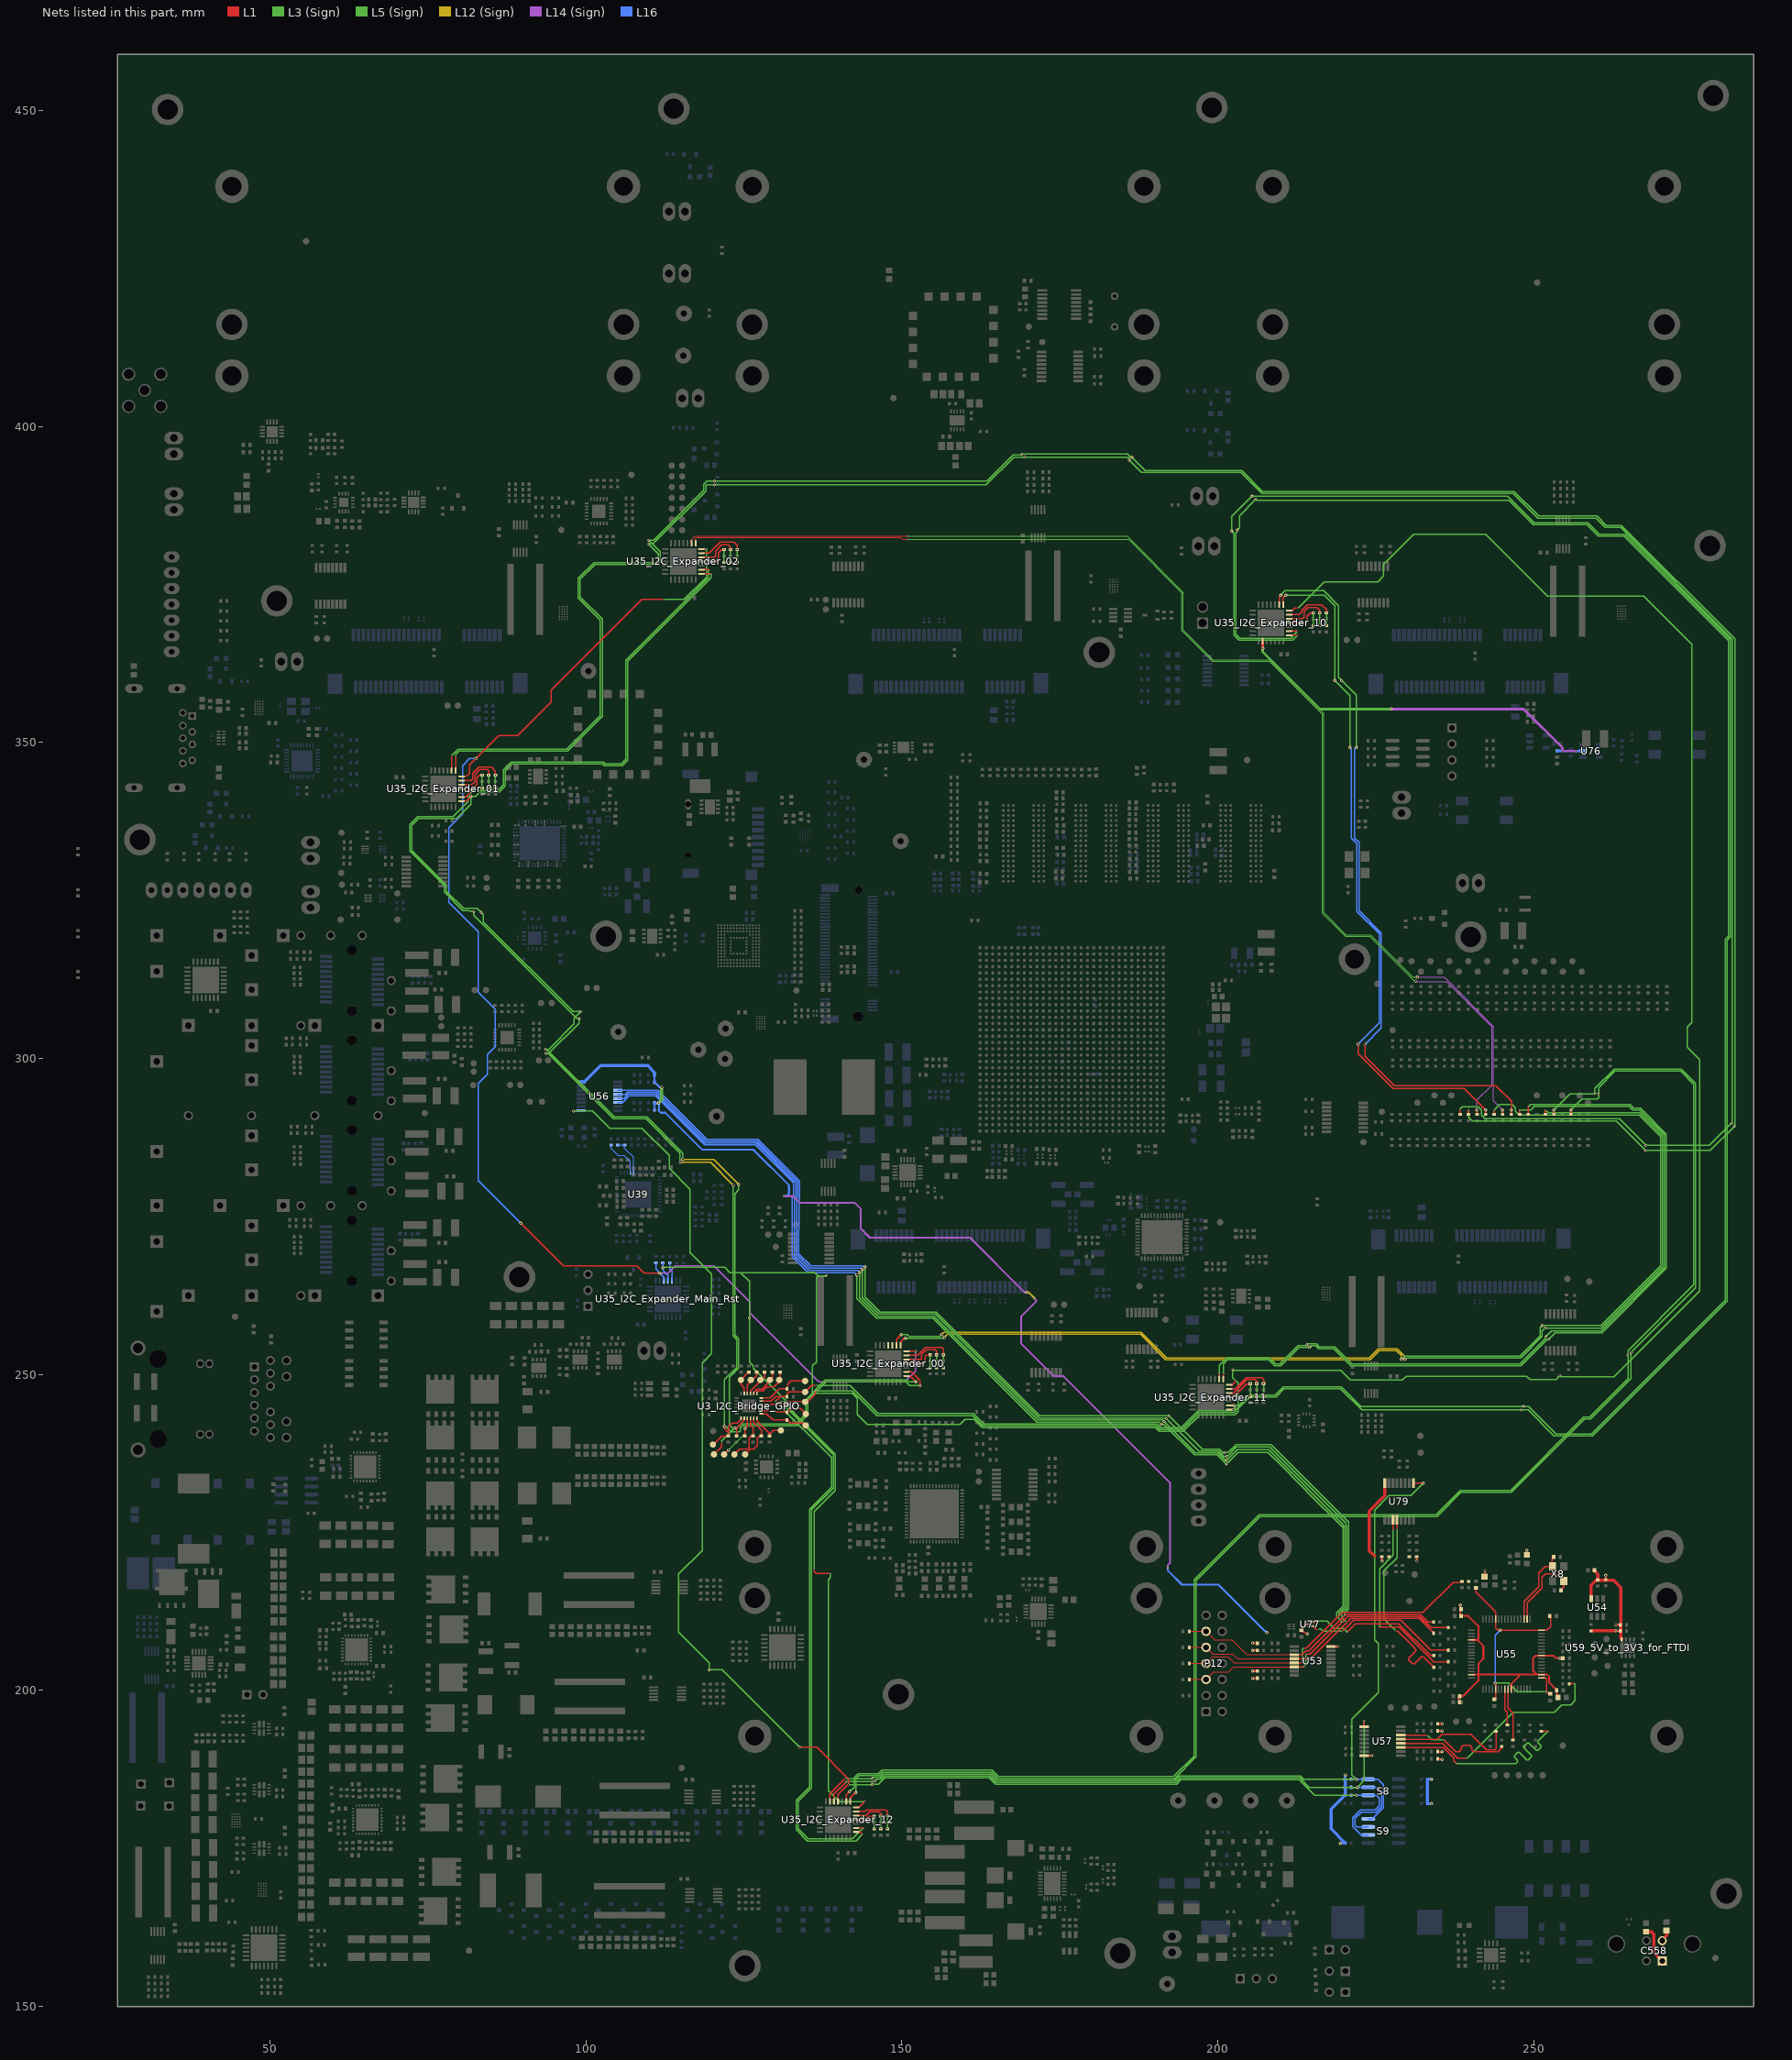
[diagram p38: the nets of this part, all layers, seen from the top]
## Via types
v1: diameter 0.5, hole 0.25, L1 to L16, tented both sides, 4341 vias
v2: diameter 0.254, hole 0.1, L1 to L3 (Sign), tented both sides, 781 vias
v3: diameter 0.5, hole 0.25, L1 to L16, 565 vias
v4: diameter 0.254, hole 0.1, L15 (GND) to L16, tented both sides, 406 vias
v5: diameter 0.254, hole 0.1, L1 to L2 (GND), tented both sides, 283 vias
v6: diameter 0.457, hole 0.2, L3 (Sign) to L6 (PWR/GND), tented both sides, 254 vias
v7: diameter 0.254, hole 0.1, L1 to L3 (Sign), 237 vias
v8: diameter 0.75, hole 0.4, L1 to L16, 200 vias
v9: diameter 0.8, hole 0.4, L1 to L16, tented both sides, 182 vias
v10: diameter 0.254, hole 0.1, L14 (Sign) to L16, tented both sides, 170 vias
v11: diameter 0.75/0/0/0/0/0/0/0/0/0/0/0/0/0/0/0.75 (per signal layer), hole 0.4, L1 to L16, 160 vias
v12: diameter 0.457, hole 0.2, L3 (Sign) to L6 (PWR/GND), 158 vias
v13: diameter 1.4, hole 0.5, L1 to L16, tented both sides, 80 vias
v14: diameter 0.254, hole 0.1, L14 (Sign) to L16, 65 vias
v15: diameter 0.254, hole 0.1, L1 to L2 (GND), 45 vias
v16: diameter 0.457, hole 0.2, L11 (PWR/GND) to L14 (Sign), tented both sides, 26 vias
v17: diameter 0.457, hole 0.2, L11 (PWR/GND) to L14 (Sign), 25 vias
v18: diameter 0.457, hole 0.2, L7(12V+Other) to L10 (3V3+Other), tented both sides, 11 vias
v19: diameter 0.254/0/0.254 (per signal layer), hole 0.1, L1 to L3 (Sign), 9 vias
v20: diameter 0.2/0/0.2 (per signal layer), hole 0.1, L1 to L3 (Sign), 6 vias
v21: diameter 1.65, hole 1.65, L1 to L16, 5 vias
v22: diameter 1.15, hole 1.15, L1 to L16, 5 vias
v23: diameter 0.457, hole 0.2, L1 to L16, 3 vias
v24: diameter 0.5, hole 0.3, L1 to L16, 2 vias
v25: diameter 0.5/0/0.5 (per signal layer), hole 0.2, L14 (Sign) to L16, 1 vias
v26: diameter 0.5, hole 0.25, L1 to L16, tented bottom, 1 vias

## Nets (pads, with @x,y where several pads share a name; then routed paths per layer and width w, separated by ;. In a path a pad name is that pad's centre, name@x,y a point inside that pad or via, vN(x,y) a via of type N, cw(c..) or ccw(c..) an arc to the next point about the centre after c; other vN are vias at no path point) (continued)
FTDI_JTAG_ON_2: R410.1 S8.2 S9.2 U35_I2C_Expander_12.18 U56.9 | length 238.8
  L1 w0.2: v1(133.858,191.008) 136.546,191.008 141.567,185.987 v2(141.567,185.115) ; U35_I2C_Expander_12.18@139.916,182.44 139.916,183.601 141.43,185.115 v2@141.512,185.115
  L5 (Sign) w0.2: v6(119.538,203.282) 121.584,203.282 v1(133.858,191.008) ; v6(145.339,185.166) 145.344,185.161 146.319,185.161 147.344,186.185 163.823,186.185 164.839,185.17 193.51,185.17 194.199,185.859 212.888,185.859 215.329,183.418 v1(221.988,183.418)
  L3 (Sign) w0.2: v1(98.082,291.681) 101.05,291.681 103.782,288.949 108.904,288.949 113.2,284.653 113.2,282.626 116.518,279.308 116.518,269.268 119.883,265.903 119.883,253.321 118.414,251.852 118.414,222.173 114.669,218.428 114.669,209.264 119.538,204.395 v6(119.538,203.282) ; v2(141.567,185.115) 145.288,185.115 v6(145.339,185.166)
  L16 w0.2: v1(98.082,291.681) 99.21,291.681 U56.9@99.259,291.73 ; R410.1@221.092,183.418 S8.2@223.829,183.418 225.105,183.418 225.604,182.92 225.604,181.72 224.955,181.07 222.596,181.07 221.392,179.866 221.392,178.509 222.756,177.144 S9.2@223.829,177.144
FTDI_JTAG_ON_3: R635.1 S8.3 S9.3 U35_I2C_Expander_12.19 U57.9 | length 114.1
  L1 w0.2: U35_I2C_Expander_12.19@139.266,182.44 139.266,183.614 141.192,185.54 v2(141.192,185.55) ; U57.9@223.198,194.248 223.198,195.202 v2(223.215,195.219)
  L5 (Sign) w0.2: v6(145.745,185.611) 146.087,185.952 146.686,185.952 147.219,186.485 163.948,186.485 164.963,185.47 193.385,185.47 194.074,186.159 213.013,186.159 214.483,184.688 v1(222.102,184.688)
  L3 (Sign) w0.2: v2(141.192,185.55) 141.201,185.55 141.268,185.616 145.74,185.616 v6(145.745,185.611) ; v1(222.102,184.688) 223.215,185.801 v2(223.215,195.219)
  L16 w0.2: R635.1@221.092,184.688 S8.3@223.829,184.688 225.105,184.688 225.904,183.89 225.904,181.595 225.079,180.77 222.72,180.77 221.738,179.788 221.738,178.696 222.019,178.414 S9.3@223.829,178.414
FTDI_JTAG_ON_4: R721.1 S8.4 S9.4 U35_I2C_Expander_12.20 U79.9 | length 154.9
  L1 w0.2: U35_I2C_Expander_12.20@138.616,182.44 138.616,183.641 v2(140.999,186.024) ; U79.9@230.998,232.825 v1(232.562,232.825)
  L5 (Sign) w0.2: v6(145.313,186.068) 145.498,186.252 146.562,186.252 147.095,186.785 164.072,186.785 165.088,185.77 193.261,185.77 193.95,186.459 213.137,186.459 213.637,185.958 v1(221.924,185.958)
  L3 (Sign) w0.2: v2(140.999,186.024) 141.042,186.068 v6(145.313,186.068) ; v1(221.924,185.958) 221.239,186.643 221.239,195.471 225.412,199.644 225.412,207.428 224.828,208.013 224.828,228.575 227.089,230.835 230.573,230.835 v1(232.562,232.825)
  L16 w0.2: R721.1@221.092,185.958 S8.4@223.829,185.958 225.366,185.958 226.204,185.12 226.204,181.471 224.417,179.684 S9.4@223.829,179.684
FTDI_LS_UART0_RXD: R1039.2 U79.4 | length 31.1
  L1 w0.2: v2(228.181,209.476) 228.436,209.476 230.729,207.183 231.25,206.662 cw(c230.981,206.394) 231.25,206.125 230.357,205.231 ccw(c230.625,204.963) 230.357,204.694 230.715,204.335 ccw(c230.984,204.604) 231.252,204.335 232.146,205.229 cw(c232.415,204.96) 232.684,205.229 232.863,205.05 R1039.2@234.26,203.652 ; U79.4@228.398,227.025 228.409,227.013 v2(228.409,225.539)
  L3 (Sign) w0.2: v2(228.181,209.476) 226.334,211.324 226.334,218.93 228.409,221.005 v2(228.409,225.539)
FTDI_LS_UART0_TXD: R1038.2 U79.3 | length 31.1
  L1 w0.2: v2(225.628,210.033) 228.714,210.033 234.202,204.545 R1038.2@236.571,204.545 ; U79.3@227.748,227.025 227.782,226.99 v2(227.782,225.412)
  L3 (Sign) w0.2: v2(225.628,210.033) 225.628,219.24 227.782,221.394 v2(227.782,225.412)
FTDI_LS_UART2_CTS_B: R1011.1 U55.41 | length 8.4
  L1 w0.2: U55.41@245.97,200.216 245.97,197.2 246.729,196.44 R1011.1@246.729,192.101
FTDI_LS_UART2_RTS_B: R1010.1 U55.40 | length 5.9
  L1 w0.2: U55.40@245.47,200.216 245.47,196.935 245.839,196.566 R1010.1@245.839,194.487
FTDI_LS_UART2_RXD: R1045.2 U57.6 | length 18.8
  L1 w0.2: U57.6@228.998,192.948 229.263,192.948 229.273,192.938 v2(233.197,192.938) ; v2(235.788,192.202) 237.692,190.298 238.026,190.298 ccw(c238.026,190.8) 238.528,190.8 238.528,190.824 cw(c239.031,190.824) 239.031,191.326 239.7,191.326 cw(c239.7,190.824) 240.202,190.824 240.202,190.8 ccw(c240.704,190.8) 240.704,190.298 240.805,190.298 244.342,190.298 244.942,190.897 R1045.2@244.942,191.201
  L3 (Sign) w0.2: v2(233.197,192.938) 233.934,192.202 v2(235.788,192.202)
FTDI_LS_UART2_TXD: R1044.2 U57.5 | length 19.3
  L1 w0.2: U57.5@228.998,192.298 234.724,192.298 235.479,193.053 240.111,193.053 242.566,190.598 243.849,190.598 244.046,190.795 R1044.2@244.046,193.587
FTDI_LS_UART_RXD: R1047.2 U57.4 | length 36
  L1 w0.2: U57.4@228.998,191.648 235.605,191.648 237.972,189.281 v7(239.479,189.281) ; R1047.2@255.593,201.037 255.638,200.992 255.785,201.138 v2(256.389,201.138)
  L3 (Sign) w0.2: v7(239.479,189.281) 246.76,196.562 253.258,196.562 254.438,197.742 255.871,197.742 256.575,198.445 256.575,200.946 256.389,201.131 v2(256.389,201.138)
FTDI_LS_UART_TXD: R1046.2 U57.3 | length 35
  L1 w0.2: U57.3@228.998,190.998 235.709,190.998 237.359,189.349 237.375,189.349 ; 237.375,189.368 237.375,189.349 ; v7(237.799,188.41) 237.375,188.834 237.375,189.349 ; R1046.2@251.219,193.587 v2(252.298,193.587)
  L3 (Sign) w0.2: v7(237.799,188.41) 247.121,188.41 247.304,188.593 247.375,188.664 ccw(c247.187,188.852) 247.375,189.04 247.028,189.387 cw(c247.216,189.575) 247.028,189.763 247.404,190.139 cw(c247.592,189.951) 247.78,190.139 248.85,189.069 ccw(c249.038,189.257) 249.226,189.069 249.602,189.445 ccw(c249.414,189.633) 249.602,189.821 248.532,190.891 cw(c248.72,191.079) 248.532,191.267 248.908,191.643 cw(c249.096,191.455) 249.284,191.643 250.355,190.573 ccw(c250.543,190.761) 250.731,190.573 251.107,190.949 ccw(c250.919,191.137) 251.107,191.325 250.759,191.672 cw(c250.947,191.86) 250.759,192.048 251.755,193.044 v2(252.298,193.587)
FTDI_PS_POR: R1036.2 U77.1 | length 24.6
  L1 w0.2: U77.1@215.024,210.162 215.417,209.769 v2(215.862,209.769) ; v2(219.773,209.359) 221.539,211.125 228.994,211.125 233.732,206.387 R1036.2@236.571,206.387
  L3 (Sign) w0.2: v2(215.862,209.769) 216.297,209.769 216.706,209.359 v2(219.773,209.359)
FTDI_PS_SRST+B: R1037.2 U77.3 | length 22.6
  L1 w0.2: U77.3@215.024,210.862 215.483,210.862 215.605,210.985 v2(215.646,210.985) ; v2(220.51,209.271) 221.81,210.571 228.633,210.571 233.668,205.536 R1037.2@234.26,205.536
  L3 (Sign) w0.2: v2(215.646,210.985) 217.31,210.985 218.44,209.855 219.926,209.855 v2(220.51,209.271)
FTDI_Sock_GND: C558.4 FB32.2 | length 2.1
  L1 w0.5: C558.4@270.2,160.249 270.2,160.375 271.043,161.218 FB32.2@271.043,162.018
FTDI_TCK: P12.7 R733.1 R1030.2 U53.5 U56.5 | length 219.6
  L1 w0.12: R733.1@195.466,204.289 P12.7@198.171,204.289 199.183,205.301 201.642,205.301 202.56,204.383 U53.5@212.124,204.383
  L1 w0.2: U53.5@212.124,204.383 212.126,204.381 v2(213.398,204.381) ; v2(213.625,206.694) 214.035,206.694 219.672,212.331 232.483,212.331 237.233,217.081 238.538,217.081 R1030.2@238.684,217.226
  L5 (Sign) w0.2: v6(191.483,242.575) 196.459,237.599 200.024,237.599 201.184,236.439 v6(201.397,236.439)
  L3 (Sign) w0.2: v1(143.337,266.197) 143.363,266.171 143.363,265.587 143.337,265.561 143.337,262.108 146.191,259.255 155.083,259.255 171.527,242.811 191.248,242.811 v6(191.483,242.575) ; v6(201.397,236.439) 201.433,236.439 203.083,238.088 208.091,238.088 219.868,226.312 219.868,226.136 220.124,225.879 220.124,213.151 219.227,212.254 v2(219.227,211.898) ; v2(213.398,204.381) 213.398,206.468 v2(213.625,206.694)
  L16 w0.2: U56.5@105.059,293.68 106.02,293.68 106.72,294.38 111.141,294.38 118.904,286.618 126.988,286.618 133.098,280.507 133.098,280.489 133.206,280.381 133.206,278.203 133.098,278.095 133.098,278.077 133.031,278.009 133.031,268.789 135.344,266.476 143.058,266.476 v1(143.337,266.197)
FTDI_TDI: P12.11 R730.1 R1031.2 U53.3 U56.3 | length 213.3
  L1 w0.12: R730.1@195.466,209.369 P12.11@198.171,209.369 199.555,207.985 202.324,207.985 204.625,205.683 U53.3@212.124,205.683
  L1 w0.2: U53.3@212.124,205.683 213.357,205.683 213.919,206.245 214.411,206.245 v2(220.053,211.887) 220.197,212.031 232.106,212.031 233.292,210.844 R1031.2@234.196,210.844
  L5 (Sign) w0.2: v6(192.332,243.424) 197.556,238.199 200.272,238.199 200.833,237.639 201.095,237.639 v6(201.117,237.617)
  L3 (Sign) w0.2: v1(144.186,267.046) 144.212,267.02 144.212,266.435 144.186,266.409 144.186,262.241 146.572,259.855 155.464,259.855 171.814,243.504 192.251,243.504 v6(192.332,243.424) ; v6(201.117,237.617) 201.163,237.662 201.659,237.662 202.941,238.944 208.445,238.944 220.723,226.666 220.723,226.129 220.724,226.128 220.724,212.902 220.053,212.231 v2(220.053,211.887)
  L16 w0.2: U56.3@105.059,294.98 111.39,294.98 119.152,287.218 127.237,287.218 133.698,280.756 133.698,280.737 133.806,280.63 133.806,277.955 133.725,277.873 133.725,273.096 133.687,273.059 133.687,272.686 133.69,272.683 133.69,269.111 135.631,267.17 143.637,267.17 143.704,267.103 144.128,267.103 v1(144.186,267.046)
FTDI_TDO: P12.5 R732.1 R1032.2 U53.6 U56.6 | length 217
  L1 w0.12: R732.1@195.466,201.749 P12.5@198.171,201.749 199.326,202.905 201.714,202.905 202.542,203.733 U53.6@212.124,203.733
  L1 w0.2: U53.6@212.124,203.733 213.626,203.733 v2(213.639,203.746) ; v2(213.984,205.78) 214.644,205.78 v2(219.723,210.858) 220.596,211.731 231.981,211.731 233.757,209.955 R1032.2@236.533,209.955
  L5 (Sign) w0.2: v6(191.059,242.151) 191.271,242.151 191.297,242.125 191.509,242.125 196.334,237.299 199.899,237.299 201.21,235.989 201.247,235.989 v6(201.397,235.839)
  L3 (Sign) w0.2: v1(142.913,265.773) 142.913,262.05 146.008,258.955 154.9,258.955 171.386,242.469 190.74,242.469 v6(191.059,242.151) ; v6(201.397,235.839) 201.433,235.839 203.258,237.664 207.915,237.664 209.017,236.563 209.094,236.563 214.039,231.618 214.039,231.541 219.824,225.755 219.824,213.275 218.834,212.284 218.834,211.747 v2(219.723,210.858) ; v2(213.639,203.746) 213.639,203.786 213.984,204.131 v2(213.984,205.78)
  L16 w0.2: U56.6@105.059,293.03 105.794,293.03 106.844,294.08 111.017,294.08 118.78,286.318 126.864,286.318 132.798,280.383 132.798,280.365 132.906,280.257 132.906,278.327 132.798,278.219 132.798,278.201 132.69,278.092 132.69,268.648 135.202,266.135 142.551,266.135 v1(142.913,265.773)
FTDI_TMS: P12.9 R734.1 R1033.2 U53.4 U56.4 | length 213.9
  L1 w0.12: R734.1@195.466,206.829 P12.9@198.171,206.829 199.212,205.787 202.374,205.787 203.129,205.033 U53.4@212.124,205.033
  L1 w0.2: U53.4@212.124,205.033 214.685,205.033 221.083,211.431 231.857,211.431 R1033.2@234.222,209.066
  L5 (Sign) w0.2: v6(191.907,242.999) 197.007,237.899 200.148,237.899 201.009,237.039 v6(201.397,237.039)
  L3 (Sign) w0.2: v1(143.762,266.621) 143.787,266.596 143.787,266.011 143.762,265.985 143.762,262.192 146.399,259.555 155.291,259.555 171.735,243.111 191.796,243.111 v6(191.907,242.999) ; v6(201.397,237.039) 201.46,237.039 202.934,238.513 208.267,238.513 220.292,226.488 220.292,226.136 220.424,226.004 220.424,213.026 219.659,212.261 219.659,211.544 v2(220.421,210.782)
  L16 w0.2: U56.4@105.059,294.33 106.245,294.33 106.595,294.68 111.266,294.68 119.028,286.918 127.112,286.918 133.398,280.632 133.398,280.613 133.506,280.505 133.506,278.079 133.398,277.971 133.398,277.952 133.39,277.944 133.39,273.186 133.387,273.183 133.387,268.94 135.493,266.835 143.548,266.835 v1(143.762,266.621)
FTDI_VBUS: C558.1 FB31.2 | length 6.2
  L1 w0.5: FB31.2@267.792,161.84 268.642,161.84 269.049,161.433 269.049,158.516 C558.1@270.358,157.207
FTDI_VCC1P8: C665.2 C666.2 C667.2 C673.2 U55.12 U55.37 U55.49 U55.64 | length 42.1
  L1 w0.2: C667.2@240.851,216.388 240.851,215.549 243.97,212.43 U55.12@243.97,211.316 243.97,209.927 244.362,209.535 244.703,209.535 v1(244.722,209.516) U55.64@251.27,209.516 252.065,209.516 252.691,210.141 C665.2@252.691,211.766 ; C666.2@243.803,198.6 243.971,198.768 U55.37@243.97,200.216 243.965,200.221 243.965,201.182 v1(243.96,201.187) ; U55.49@251.27,202.016 251.87,202.016 252.02,201.867 v2(252.02,199.788) 252.296,199.512 252.436,199.512 252.606,199.342 C673.2@252.606,199.337
  L3 (Sign) w0.2: v1(243.96,201.187) 245.998,201.187 247.398,199.788 v2(252.02,199.788)
  L16 w0.2: v1(243.96,201.187) 243.96,208.754 v1(244.722,209.516)
FTDI_VccIO: C565_5V_to_3V3_for_FTDI.2 C566_5V_to_3V3_for_FTDI.2 C567_5V_to_3V3_for_FTDI.2 C658.2 C668.2 C669.2 C670.2 C671.2 C791.2 FB43.1 FB44.1 R401.2 R402.1 R404.1 R406.1 R408.1 R410.2 R411.1 R413.1 R415.1 R417.1 R418.1 R420.1 R422.2 R424.1 R430_5V_to_3V3_for_FTDI.2 R431_5V_to_3V3_for_FTDI.2 R635.2 R636.1 R638.1 R640.1 R642.1 R721.2 R722.1 R724.1 R726.1 R728.1 R1048.1 R1049.1 R1050.1 R1051.1 U53.16 U54.6 U55.20 U55.31 U55.42 U55.50 U55.56 U56.16 U57.16 U59_5V_to_3V3_for_FTDI.8 U77.5 U79.16 | length 289.6
  L1 w0.2: v1(214.159,208.969) 214.016,208.969 213.766,209.22 213.392,209.22 213.222,209.39 213.222,209.395 213.222,209.733 214.001,210.512 U77.5@214.294,210.512
  L1 w0.3: v1(205.568,201.942) R408.1@206.258,201.942 ; v1(205.568,203.083) R406.1@206.258,203.083 ; v1(205.568,206.358) R404.1@206.258,206.358 ; v1(205.568,207.477) R402.1@206.258,207.477 ; U53.16@218.383,206.963 v1(219.072,206.963) ; U57.16@223.612,189.698 223.614,189.697 v1(224.422,189.697) ; v1(225.995,220.458) R722.1@225.995,221.148 ; v1(231.487,220.458) R728.1@231.487,221.148 ; R636.1@234.832,189.102 v1(235.522,189.102) ; R638.1@234.832,190.298 v1(235.522,190.298) ; R640.1@234.832,193.602 v1(235.522,193.602) ; R642.1@234.858,194.737 v1(235.547,194.737) ; C671.2@238.389,212.902 C671.2@238.399,212.892 ; v1(238.399,213.536) C671.2@238.399,212.892 ; v1(238.6,198.151) 238.19,198.151 238.19,199.095 238.809,199.095 241.251,201.537 241.251,202.516 ; U55.31@240.17,202.516 241.251,202.516 ; U55.20@240.17,208.016 241.075,208.016 ; FB43.1@242.298,218.3 v1(242.298,218.99) ; U55.42@246.47,200.216 246.47,201.04 247.945,202.516 ; FB44.1@248.933,221.437 FB44.1@248.933,221.452 v1(248.933,222.127) ; C565_5V_to_3V3_for_FTDI.2@253.887,198.717 253.687,198.917 253.687,200.046 252.47,201.263 252.47,202.188 252.142,202.516 U55.50@251.27,202.516 250.532,202.516 ; C567_5V_to_3V3_for_FTDI.2@254.839,205.136 C567_5V_to_3V3_for_FTDI.2@254.618,205.136 v1(254.149,205.136) 253.521,205.136 253.141,205.516 U55.56@251.27,205.516 250.3,205.516 249.904,205.121 249.904,203.144 250.532,202.516 ; R417.1@261.417,217.518 261.417,217.526 v1(261.417,218.208) ; v1(263.042,209.456) R430_5V_to_3V3_for_FTDI.2@263.732,209.456 ; v1(263.042,210.426) R431_5V_to_3V3_for_FTDI.2@263.732,210.426 ; C671.2@238.399,212.892 238.399,211.8 238.409,211.789 239.667,211.789 241.251,210.206 241.251,208.192 241.075,208.016 ; 241.075,208.016 242.044,207.047 242.044,205.016 241.251,204.223 241.251,202.516 ; 241.251,202.516 247.945,202.516 ; 247.945,202.516 250.532,202.516
  L1 w0.5: 224.828,221.272 223.99,222.11 223.99,228.397 226.448,230.855 U79.16@226.448,232.825 ; R422.2@259.093,209.476 259.113,209.456 v1(263.042,209.456) ; U54.6@259.121,214.539 259.093,214.567 259.093,216.641 259.815,217.363 260.11,217.363 260.159,217.413 R420.1@260.159,217.461 ; C658.2@259.511,219.018 259.516,219.018 260.159,218.374 260.159,217.463 R420.1@260.159,217.461 ; R430_5V_to_3V3_for_FTDI.2@263.732,209.456 263.763,209.456 R430_5V_to_3V3_for_FTDI.2@263.783,209.436 ; U59_5V_to_3V3_for_FTDI.8@263.944,208.077 263.919,208.077 263.783,208.212 R430_5V_to_3V3_for_FTDI.2@263.783,209.436 ; R420.1@260.159,217.461 260.209,217.411 262.674,217.411 263.783,216.302 263.783,210.378 R430_5V_to_3V3_for_FTDI.2@263.783,209.436
  L5 (Sign) w0.5: v1(111.494,292.935) 112.015,293.456 v1(112.015,295.438)
  L12 (Sign) w0.3: v16(169.786,262.992) 170.101,262.992 v16(171.011,262.082)
  L14 (Sign) w0.3: v10(131.305,278.219) 132.778,278.219 133.807,277.19 142.532,277.19 143.529,276.193 143.529,273.081 144.958,271.653 160.782,271.653 169.443,262.992 v16(169.786,262.992) ; v16(171.011,262.082) 171.011,262.059 171.263,261.807 171.263,261.558 168.91,259.206 168.91,254.889 174.066,249.733 175.616,249.733 192.443,232.905 192.443,220.18 192.113,219.85 v10(192.113,219.418)
  L16 w0.3: R418.1@110.844,291.866 R415.1@110.844,292.815 ; R411.1@110.844,297.394 110.844,296.255 R413.1@110.894,296.255 111.705,295.444 v1@111.793,295.444 ; 111.239,293.005 110.844,293.005 R415.1@110.844,292.815 ; v1@111.318,292.815 R415.1@110.844,292.815 ; v1(111.494,292.935) 111.587,292.841 111.587,292.151 111.565,292.129 111.565,291.968 111.557,291.96 111.557,291.76 111.565,291.752 111.565,291.715 111.858,291.422 112.59,291.422 118.445,285.568 126.535,285.568 132.156,279.946 132.156,278.638 131.738,278.219 v10(131.305,278.219) ; 111.667,295.444 111.674,295.438 v1(112.015,295.438) ; v10(192.113,219.418) 192.113,218.986 194.348,216.751 200.143,216.751 207.461,209.432 207.521,209.432 v1(207.81,209.144) ; v1(219.407,175.821) R401.2@220.096,175.821 ; R721.2@220.192,185.945 220.192,185.958 v1(220.192,186.634) ; R1048.1@233.146,182.085 v1(233.835,182.085) ; R1051.1@233.146,185.958 233.207,185.958 v1(233.835,185.958)
  L16 w0.5: U56.16@99.259,296.28 99.734,296.28 102.336,298.882 109.793,298.882 110.844,297.831 R411.1@110.844,297.394 ; R401.2@220.192,175.874 R401.2@220.142,175.874 220.092,175.924 220.092,175.974 217.957,178.109 217.957,181.234 R410.2@220.142,183.418 220.192,183.418 R721.2@220.192,185.945 ; R1048.1@233.207,182.148 R1051.1@233.207,185.958
FTDI_X_IN: C663.2 U55.2 X8.1 | length 13.5
  L1 w0.2: U55.2@248.97,211.316 248.97,213.854 251.333,216.218 251.333,217.945 251.88,218.491 253.627,218.491 X8.1@254.777,217.341 254.777,216.41 C663.2@254.191,215.824
FTDI_X_OUT: C664.2 U55.3 X8.3 | length 12.6
  L1 w0.2: U55.3@248.47,211.316 248.47,214.129 250.8,216.459 250.8,218.628 251.813,219.641 X8.3@252.977,219.641 252.922,219.696 252.922,220.771 C664.2@253.322,221.171
GEM3_MDC: R815.1 U39.16 | length 6.2
  L16 w0.12: R815.1@104.005,286.337 104.005,285.783 105.105,284.683 106.007,284.683 107.049,283.641 U39.16@107.049,281.925
GEM3_MDIO: R333.2 R816.1 U39.17 | length 6.1
  L16 w0.12: R816.1@105.075,286.337 106.145,286.337 106.145,285.765 107.549,284.36 U39.17@107.549,281.925
GPIO_ETH_EXPANDER: R715.1 U35_I2C_Expander_10.2 U76.2 | length 60
  L1 w0.4: v1(207.13,364.884) U35_I2C_Expander_10.2@207.13,366.065
  L5 (Sign) w0.4: v1(207.13,364.884) 207.13,364.345 216.167,355.308 v1(227.47,355.308)
  L14 (Sign) w0.4: v1(227.47,355.308) 248.425,355.308 254.549,349.184 v10(254.549,348.679) 254.562,348.666 v10(256.712,348.666)
  L16 w0.4: R715.1@253.771,348.616 253.835,348.679 v10(254.549,348.679) ; v10(256.712,348.666) U76.2@257.78,348.666
GPIO_Exp10_Adress0: R492.2 R493.1 U35_I2C_Expander_00.13 | length 9.5
  L1 w0.2: U35_I2C_Expander_00.13@150.747,253.032 152.561,253.032 153.789,254.26 156.348,254.26 156.598,254.01 R492.2@156.598,253.07 ; R493.1@156.598,251.038 v7(156.598,251.163)
  L3 (Sign) w0.2: v7(156.598,251.163) v7(156.598,253.12)
GPIO_Exp10_Adress1: R494.2 R495.1 U35_I2C_Expander_00.12 | length 8.6
  L1 w0.2: U35_I2C_Expander_00.12@150.747,252.381 153.009,252.381 153.126,252.499 153.126,253.173 153.88,253.926 155.325,253.926 155.524,253.727 v7(155.524,253.07) ; R495.1@155.524,251.038 v7(155.524,251.163)
  L3 (Sign) w0.2: v7(155.524,251.163) v7(155.524,253.07)
GPIO_Exp10_Adress2: R496.2 R497.1 U35_I2C_Expander_00.11 | length 6.8
  L1 w0.2: U35_I2C_Expander_00.11@150.747,251.732 153.308,251.731 153.672,252.095 153.672,252.914 153.789,253.032 154.469,253.032 v7(154.508,253.07) ; R497.1@154.508,251.038 v7(154.508,251.163)
  L3 (Sign) w0.2: v7(154.508,251.163) v7(154.508,253.07)
GPIO_Exp10_Int0: R871.2 U35_I2C_Expander_00.16 | length 174.5
  L1 w0.2: U35_I2C_Expander_00.16@149.172,254.607 149.172,255.582 v1(149.927,256.337) ; R871.2@251.85,291.11 v2(251.85,291.871)
  L5 (Sign) w0.2: v1(149.927,256.337) 150.876,256.337 151.168,256.045 156.083,256.045 v1(156.337,256.299) ; v1(229.648,252.371) 229.901,252.625 247.975,252.625 251.346,255.995 251.346,256.896 v6(251.803,257.353)
  L12 (Sign) w0.2: v1(156.337,256.299) 156.705,256.667 187.895,256.667 191.921,252.641 223.982,252.641 225.421,254.08 227.949,254.08 227.953,254.085 228.408,254.085 229.59,252.902 229.59,252.429 v1(229.648,252.371)
  L3 (Sign) w0.2: v6(251.803,257.353) 260.667,257.353 270.397,267.082 270.397,287.783 266.775,291.405 252.317,291.405 v2(251.85,291.871)
GPIO_Exp10_Int1: R872.2 U35_I2C_Expander_00.15 | length 181.9
  L1 w0.2: U35_I2C_Expander_00.15@149.822,254.607 149.822,255.182 150.368,255.727 v1(150.574,255.727) ; R872.2@243.753,291.11 v2(243.753,291.871)
  L5 (Sign) w0.2: v1(150.574,255.727) 150.586,255.74 156.627,255.74 v1(156.772,255.885) ; v1(229.048,252.371) 229.048,252.408 229.569,252.93 247.849,252.93 251.041,256.122 251.041,257.439 v6(251.379,257.777)
  L12 (Sign) w0.2: v1(156.772,255.885) 157.249,256.362 187.769,256.362 191.795,252.336 224.108,252.336 225.552,253.78 228.288,253.78 229.048,253.021 v1(229.048,252.371)
  L3 (Sign) w0.2: v2(243.753,291.871) 244.593,292.712 246.643,292.712 247.115,292.24 247.115,291.621 247.688,291.049 266.707,291.049 270.097,287.659 270.097,267.211 260.689,257.803 251.404,257.803 v6(251.379,257.777)
GPIO_Exp11_Adress0: R500.2 R501.1 U35_I2C_Expander_01.13 | length 9.8
  L1 w0.2: U35_I2C_Expander_01.13@80.338,343.989 81.864,343.989 82.137,344.262 82.137,345.205 83.013,346.081 85.073,346.081 85.683,345.471 R500.2@85.683,344.784 ; R501.1@85.683,342.752 v7(85.683,342.877)
  L3 (Sign) w0.2: v7(85.683,342.877) v7(85.683,344.834)
GPIO_Exp11_Adress1: R502.2 R503.1 U35_I2C_Expander_01.12 | length 8.9
  L1 w0.2: U35_I2C_Expander_01.12@80.338,343.339 81.984,343.339 82.437,343.792 82.437,344.978 83.198,345.739 84.396,345.739 84.625,345.51 84.625,344.8 R502.2@84.609,344.784 ; R503.1@84.609,342.752 v7(84.609,342.877)
  L3 (Sign) w0.2: v7(84.609,342.877) v7(84.609,344.834)
GPIO_Exp11_Adress2: R504.2 R505.1 U35_I2C_Expander_01.11 | length 6.8
  L1 w0.2: U35_I2C_Expander_01.11@80.338,342.689 82.105,342.689 82.785,343.369 82.785,344.456 83.112,344.784 R504.2@83.593,344.784 ; R505.1@83.593,342.752 v7(83.593,342.877)
  L3 (Sign) w0.2: v7(83.593,342.877) v7(83.593,344.834)
GPIO_Exp11_Int0: R873.2 U35_I2C_Expander_01.16 | length 383.8
  L1 w0.2: U35_I2C_Expander_01.16@78.763,345.564 v2(78.763,347.907) ; v2(238.354,291.986) 238.354,291.128 R873.2@238.379,291.102
  L5 (Sign) w0.2: v6(109.906,381.406) 110.6,381.406 118.989,389.795 118.989,390.766 v6(120.371,390.766) ; v6(169.487,395.181) 185.717,395.181 185.988,394.91 v6(185.988,394.712) ; v6(267.767,286.245) 277.8,286.245 281.357,289.803 v6(281.383,289.803)
  L3 (Sign) w0.2: v2(78.763,347.907) 79.777,348.922 96.968,348.922 102.269,354.223 102.269,369.422 98.809,372.882 98.809,375.985 101.322,378.498 111.136,378.498 111.48,378.842 111.48,379.832 v6(109.906,381.406) ; v6(120.371,390.766) 163.36,390.766 167.767,395.173 168.478,395.173 168.486,395.181 168.85,395.181 168.876,395.155 169.461,395.155 v6(169.487,395.181) ; v6(185.988,394.712) 187.962,392.738 203.668,392.738 206.986,389.419 246.774,389.419 250.663,385.531 259.87,385.531 261.356,384.045 263.802,384.045 281.46,366.387 281.46,289.881 v6(281.383,289.803) ; v2(238.354,291.986) 238.735,292.367 241.211,292.367 241.732,291.846 241.732,291.032 242.315,290.449 263.563,290.449 v6(267.767,286.245)
GPIO_Exp11_Int1: R874.2 U35_I2C_Expander_01.15 | length 384.6
  L1 w0.2: U35_I2C_Expander_01.15@79.413,345.564 v2(79.413,347.907) ; R874.2@239.704,291.102 v2(239.704,291.892)
  L5 (Sign) w0.2: v6(109.906,382.006) 110.747,382.006 118.689,389.949 118.689,390.891 119.165,391.366 v6(120.371,391.366) ; v6(169.062,395.605) 169.088,395.631 185.721,395.631 186.215,395.137 v6(186.412,395.137) ; v6(267.704,285.445) 277.927,285.445 v6(281.76,289.279)
  L3 (Sign) w0.2: v2(79.413,347.907) 79.442,347.936 79.442,348.148 79.915,348.622 97.092,348.622 102.62,354.15 102.62,369.524 99.109,373.035 99.109,375.86 101.447,378.198 111.261,378.198 111.78,378.717 111.78,380.214 109.988,382.006 v6(109.906,382.006) ; v6(120.371,391.366) 163.507,391.366 167.634,395.494 168.951,395.494 v6(169.062,395.605) ; v6(186.412,395.137) 188.511,393.038 203.792,393.038 207.09,389.74 246.907,389.74 250.796,385.851 260.003,385.851 261.489,384.365 263.906,384.365 281.833,366.439 281.833,289.351 v6(281.76,289.279) ; v2(239.704,291.892) 239.704,290.707 240.322,290.09 263.059,290.09 v6(267.704,285.445)
GPIO_Exp12_Adress0: R508.2 R509.1 U35_I2C_Expander_02.13 | length 9.4
  L1 w0.2: U35_I2C_Expander_02.13@118.305,379.957 119.527,379.957 121.277,381.707 123.48,381.707 123.963,381.224 R508.2@123.963,380.478 ; R509.1@123.963,378.446 v7(123.963,378.571)
  L3 (Sign) w0.2: v7(123.963,378.571) v7(123.963,380.528)
GPIO_Exp12_Adress1: R510.2 R511.1 U35_I2C_Expander_02.12 | length 8.4
  L1 w0.2: U35_I2C_Expander_02.12@118.305,379.307 120.297,379.307 120.517,379.528 120.517,380.31 121.509,381.302 122.489,381.302 122.889,380.903 v7(122.889,380.528) R510.2@122.889,380.478
  L3 (Sign) w0.2: v7(122.889,378.571) v7(122.889,380.528)
GPIO_Exp12_Adress2: R512.2 R513.1 U35_I2C_Expander_02.11 | length 6.9
  L1 w0.2: U35_I2C_Expander_02.11@118.305,378.657 120.517,378.657 121.018,379.159 121.018,380.023 121.473,380.478 R512.2@121.873,380.478 ; R513.1@121.873,378.446 v7(121.873,378.571)
  L3 (Sign) w0.2: v7(121.873,378.571) v7(121.873,380.528)
GPIO_Exp12_Int0: R875.2 U35_I2C_Expander_02.16 | length 196.4
  L1 w0.12: U35_I2C_Expander_02.16@116.73,381.532 116.73,382.123 117.3,382.693 150.961,382.693 v7(150.992,382.663)
  L1 w0.2: R875.2@245.102,291.11 v1(245.102,291.871)
  L3 (Sign) w0.12: v7(150.992,382.663) 185.663,382.663 194.558,373.768 194.558,367.813 199.252,363.119 208.237,363.119 216.789,354.567 216.789,323.087 220.293,319.584 224.163,319.584 230.873,312.874 v1(231.61,312.874)
  L14 (Sign) w0.12: v1(231.61,312.874) 235.846,312.874 243.65,305.07 243.65,293.324 v1(245.102,291.871)
GPIO_Exp12_Int1: R876.2 U35_I2C_Expander_02.15 | length 195.8
  L1 w0.12: U35_I2C_Expander_02.15@117.38,381.532 117.38,382.307 117.546,382.473 149.796,382.473 150.139,382.13 v7(150.992,382.13)
  L1 w0.2: R876.2@241.054,291.11 v1(241.054,291.871)
  L3 (Sign) w0.12: v7(150.992,382.13) 185.884,382.13 194.338,373.677 194.338,367.722 199.161,362.899 208.146,362.899 216.569,354.476 216.569,322.991 220.197,319.364 224.072,319.364 231.164,312.271 v1(231.346,312.271)
  L14 (Sign) w0.12: v1(231.346,312.271) 231.415,312.203 236.206,312.203 243.43,304.979 243.43,295.799 241.054,293.423 v1(241.054,291.871)
GPIO_Exp13_Adress0: R516.2 R517.1 U35_I2C_Expander_10.13 | length 9.6
  L1 w0.2: U35_I2C_Expander_10.13@211.305,370.24 212.89,370.24 213.296,370.646 213.296,370.92 214.184,371.807 216.441,371.807 217.215,371.033 v7(217.215,370.495) ; R517.1@217.215,368.463 v7(217.215,368.588)
  L3 (Sign) w0.2: v7(217.215,368.588) v7(217.215,370.495)
GPIO_Exp13_Adress1: R518.2 R519.1 U35_I2C_Expander_10.12 | length 8.8
  L1 w0.2: U35_I2C_Expander_10.12@211.305,369.59 213.466,369.59 213.676,369.8 213.676,370.765 214.259,371.348 215.713,371.348 216.141,370.92 v7(216.141,370.495) ; R519.1@216.141,368.463 v7(216.141,368.588)
  L3 (Sign) w0.2: v7(216.141,368.588) v7(216.141,370.495)
GPIO_Exp13_Adress2: R520.2 R521.1 U35_I2C_Expander_10.11 | length 7
  L1 w0.2: U35_I2C_Expander_10.11@211.305,368.94 213.944,368.94 214.084,369.08 214.084,369.989 214.589,370.495 v7(215.125,370.495) ; R521.1@215.125,368.463 v7(215.125,368.588)
  L3 (Sign) w0.2: v7(215.125,368.588) v7(215.125,370.495)
GPIO_Exp13_Int0: R877.2 U35_I2C_Expander_10.16 | length 115.7
  L1 w0.2: U35_I2C_Expander_10.16@209.73,371.815 209.73,373.015 209.963,373.248 v1(209.963,373.329) ; v1(223.298,302.265) 223.298,300.365 227.949,295.714 244.004,295.714 246.507,293.212 246.507,291.926 v1(246.452,291.871) R877.2@246.452,291.11
  L5 (Sign) w0.2: v1(209.963,373.329) 210.644,374.01 216.772,374.01 219.104,371.678 219.104,360.323 v12(219.595,359.832)
  L3 (Sign) w0.2: v12(219.595,359.832) 221.94,357.487 v1(221.94,349.229)
  L16 w0.2: v1(221.94,349.229) 221.668,348.957 221.668,334.891 222.356,334.203 222.356,323.388 225.857,319.888 225.857,304.824 v1(223.298,302.265)
GPIO_Exp13_Int1: R878.2 U35_I2C_Expander_10.15 | length 109.9
  L1 w0.2: U35_I2C_Expander_10.15@210.38,371.815 210.38,372.921 v1(210.788,373.329) ; v1(222.263,302.335) 222.263,300.765 227.753,295.274 239,295.274 v1(242.403,291.871) R878.2@242.403,291.11
  L5 (Sign) w0.2: v1(210.788,373.329) 216.891,373.329 218.542,371.678 v12(218.542,359.832)
  L3 (Sign) w0.2: v12(218.542,359.832) 220.95,357.424 v1(220.95,349.229)
  L16 w0.2: v1(220.95,349.229) 220.95,349.197 221.185,348.962 221.185,334.845 222.056,333.973 222.056,323.264 225.557,319.764 225.557,305.629 v1(222.263,302.335)
GPIO_Exp14_Adress0: R524.2 R525.1 U35_I2C_Expander_11.13 | length 9.1
  L1 w0.2: U35_I2C_Expander_11.13@201.814,247.71 202.714,247.71 204.53,249.526 206.954,249.526 207.265,249.215 R524.2@207.265,248.51 ; R525.1@207.265,246.478 v7(207.265,246.603)
  L3 (Sign) w0.2: v7(207.265,246.603) v7(207.265,248.56)
GPIO_Exp14_Adress1: R526.2 R527.1 U35_I2C_Expander_11.12 | length 7.8
  L1 w0.2: U35_I2C_Expander_11.12@201.814,247.06 202.488,247.06 204.629,249.201 205.925,249.201 206.191,248.935 v7(206.191,248.56) R526.2@206.191,248.51
  L3 (Sign) w0.2: v7(206.191,246.603) v7(206.191,248.56)
GPIO_Exp14_Adress2: R528.2 R529.1 U35_I2C_Expander_11.11 | length 6.3
  L1 w0.2: U35_I2C_Expander_11.11@201.814,246.41 202.418,246.41 204.518,248.51 R528.2@205.175,248.51 ; R529.1@205.175,246.478 v7(205.175,246.603)
  L3 (Sign) w0.2: v7(205.175,246.603) v7(205.175,248.56)
GPIO_Exp14_Int0: R879.2 U35_I2C_Expander_11.16 | length 129.3
  L1 w0.2: U35_I2C_Expander_11.16@200.239,249.285 v2(200.239,250.139) ; R879.2@247.801,291.11 v2(247.801,291.871)
  L5 (Sign) w0.2: v6(214.135,254.724) 214.27,254.859 215.618,254.859 216.1,254.376 218.539,254.376 221.214,251.701 247.866,251.701 251.932,255.767 v6(251.932,255.979)
  L3 (Sign) w0.2: v2(200.239,250.139) 200.239,251.476 201.407,252.644 208.199,252.644 209.167,251.676 209.853,251.676 212.731,254.554 213.965,254.554 v6(214.135,254.724) ; v2(247.801,291.871) 249.589,291.871 250.122,292.405 265.134,292.405 265.709,291.829 266.775,291.829 270.697,287.907 270.697,266.938 260.688,256.929 252.881,256.929 v6(251.932,255.979)
GPIO_Exp14_Int1: R880.2 U35_I2C_Expander_11.15 | length 128.6
  L1 w0.2: U35_I2C_Expander_11.15@200.889,249.285 v2(200.889,250.139) ; R880.2@249.136,291.125 249.151,291.11 249.151,292.337 v2(249.242,292.428) v2@249.242,292.468
  L5 (Sign) w0.2: v6(214.559,254.3) 214.818,254.559 215.494,254.559 215.976,254.076 218.415,254.076 221.09,251.401 247.99,251.401 252.144,255.555 v6(252.356,255.555)
  L3 (Sign) w0.2: v2(200.889,250.139) 200.889,251.701 201.531,252.344 208.074,252.344 209.043,251.376 209.977,251.376 212.856,254.254 214.513,254.254 v6(214.559,254.3) ; v2@249.242,292.468 249.478,292.705 265.264,292.705 265.84,292.129 266.899,292.129 270.997,288.032 270.997,266.813 260.812,256.629 253.43,256.629 v6(252.356,255.555)
GPIO_Exp15_Adress0: R697.2 R698.1 U35_I2C_Expander_12.13 | length 7.9
  L1 w0.2: U35_I2C_Expander_12.13@142.791,180.865 144.152,180.865 144.423,181.137 147.489,181.137 147.739,180.887 v7(147.739,180.115) R697.2@147.739,180.065
  L3 (Sign) w0.2: v7(147.739,178.19) v7(147.739,180.115)
GPIO_Exp15_Adress1: R699.2 R700.1 U35_I2C_Expander_12.12 | length 6.6
  L1 w0.2: U35_I2C_Expander_12.12@142.791,180.215 144.347,180.215 144.947,180.815 146.373,180.815 146.698,180.49 v7(146.698,180.115) R699.2@146.698,180.065
  L3 (Sign) w0.2: v7(146.698,178.19) v7(146.698,180.115)
GPIO_Exp15_Adress2: R701.2 R702.1 U35_I2C_Expander_12.11 | length 5.1
  L1 w0.2: U35_I2C_Expander_12.11@142.791,179.565 144.197,179.565 144.697,180.065 R701.2@145.653,180.065 ; R702.1@145.653,178.065 v7(145.653,178.19)
  L3 (Sign) w0.2: v7(145.653,178.19) v7(145.653,180.115)
GPIO_Exp15_Int0: R881.2 U35_I2C_Expander_12.16 | length 245.5
  L1 w0.2: U35_I2C_Expander_12.16@141.216,182.44 141.216,183.469 v1(141.719,183.972) ; R881.2@255.898,291.11 v1(255.898,291.871)
  L5 (Sign) w0.2: v1(141.719,183.972) 142.435,184.688 142.435,186.154 143.134,186.852 146.313,186.852 146.847,187.385 164.32,187.385 165.336,186.37 193.013,186.37 196.256,189.613 196.256,217.499 206.58,227.823 234.067,227.823 234.071,227.827 234.557,227.827 238.392,231.663 246.375,231.663 257.96,243.248 258.865,243.248 264.947,249.331 v6(264.947,253.086) ; v1(255.898,291.871) 257.6,293.573 260.058,293.573 260.3,293.815 v6(260.3,294.411)
  L3 (Sign) w0.2: v6(260.3,294.411) 260.3,295.43 262.877,298.007 273.279,298.007 275.346,295.941 275.346,264.205 264.947,253.807 v6(264.947,253.086)
GPIO_Exp15_Int1: R882.2 U35_I2C_Expander_12.15 | length 248.3
  L1 w0.2: U35_I2C_Expander_12.15@141.866,182.44 141.866,183.082 142.643,183.86 v1(142.735,183.86) ; R882.2@253.199,291.11 v1(253.199,291.871)
  L5 (Sign) w0.2: v1(142.735,183.86) 142.735,186.03 143.258,186.552 146.438,186.552 146.971,187.085 164.196,187.085 165.212,186.07 193.137,186.07 196.556,189.489 196.556,217.375 206.704,227.523 234.191,227.523 234.196,227.527 234.681,227.527 238.516,231.363 246.499,231.363 258.085,242.948 258.989,242.948 265.43,249.389 v6(265.43,253.467) ; v1(253.199,291.871) 255.739,294.411 v6(259.7,294.411)
  L3 (Sign) w0.2: v6(259.7,294.411) 259.7,295.254 262.753,298.307 273.404,298.307 275.646,296.065 275.646,263.683 v6(265.43,253.467)
GPIO_Exp_Reset0: R746.1 U35_I2C_Expander_00.14 U35_I2C_Expander_01.14 U35_I2C_Expander_02.14 U35_I2C_Expander_Main_Rst.17 | length 225.1
  L1 w0.12: U35_I2C_Expander_02.14@118.305,380.607 118.307,380.605 119.077,380.605 v7(119.08,380.603)
  L1 w0.2: U35_I2C_Expander_01.14@80.338,344.639 80.35,344.651 81.101,344.651 81.584,345.134 81.584,346.463 v1(82.588,347.467) 86.26,351.139 89.202,351.139 94.509,356.445 94.509,358.269 108.903,372.663 v7(112.29,372.663) ; v1(89.707,273.914) 89.752,273.914 96.48,267.185 108.077,267.185 109.218,266.044 v1(111.717,266.044) ; U35_I2C_Expander_00.14@150.747,253.681 152.13,253.681 v1(152.142,253.67)
  L3 (Sign) w0.2: v7(112.29,372.663) 115.577,372.663 119.078,376.164 119.078,380.6 v7(119.08,380.603)
  L14 (Sign) w0.2: v1(111.717,266.044) 113.005,266.044 114.156,267.195 120.257,267.195 125.962,261.491 125.962,259.737 136.855,248.844 150.467,248.844 152.142,250.519 v1(152.142,253.67)
  L16 w0.2: v1(82.588,347.467) 81.62,347.467 80.493,346.339 80.493,338.697 78.329,336.533 78.329,324.694 82.958,320.066 82.958,310.503 85.642,307.82 85.642,301.863 84.406,300.628 84.406,297.536 82.958,296.087 82.958,280.663 v1(89.707,273.914) ; R746.1@111.087,267.731 111.087,266.675 v1(111.717,266.044) 112.348,265.414 U35_I2C_Expander_Main_Rst.17@112.348,264.843
GPIO_Exp_Reset1: R747.1 U35_I2C_Expander_10.14 U35_I2C_Expander_11.14 U35_I2C_Expander_12.14 U35_I2C_Expander_Main_Rst.18 | length 493.2
  L1 w0.2: v2(136.119,219.177) 136.119,218.841 136.418,218.542 v2(138.671,218.542) ; U35_I2C_Expander_12.14@142.791,181.515 143.27,181.515 v2(144.152,182.397) ; U35_I2C_Expander_11.14@201.814,248.36 202.328,248.36 202.73,248.762 v2(202.73,249.149) ; U35_I2C_Expander_10.14@211.305,370.89 211.86,370.89 212.242,371.272 v2(212.729,371.272)
  L5 (Sign) w0.2: v1(112.211,266.922) 112.185,266.948 121.998,266.948 122.805,266.141 124.461,266.141 ; v6(125.882,258.96) 125.882,264.719 124.461,266.141 ; v6(138.074,265.626) 136.763,265.626 136.248,266.141 124.461,266.141 ; v6(202.39,250.793) 202.555,250.628 219.496,250.628 220.996,249.128 229.227,249.128 229.851,249.751 248.894,249.751 249.443,249.201 253.545,249.201 v6(254.178,249.834)
  L3 (Sign) w0.2: v6(125.882,258.96) 125.882,251.973 126.467,251.389 126.467,251.047 132.066,245.448 132.066,244.821 139.465,237.422 139.465,231.667 136.119,228.321 v2(136.119,219.177) ; v6(138.074,265.626) 136.729,265.626 136.471,265.369 136.471,251.968 135.877,251.374 135.877,247.171 135.994,247.054 142.128,247.054 142.981,246.201 142.981,243.664 144.574,242.072 159.196,242.072 159.996,242.871 161.442,242.871 162.744,241.569 190.156,241.569 190.745,240.98 194.521,240.98 197.195,243.654 202.706,243.654 203.201,244.15 203.201,248.678 v2(202.73,249.149) 202.39,249.489 v6(202.39,250.793) ; v2(138.671,218.542) 138.671,217.856 138.365,217.549 138.365,184.164 140.132,182.397 v2(144.152,182.397) ; v2(212.729,371.272) 216.903,375.446 225.345,375.446 226.265,376.366 226.265,378.208 231.03,382.973 242.426,382.973 252.199,373.2 267.435,373.2 275.053,365.582 275.053,305.721 274.294,304.962 274.294,301.791 276.253,299.832 276.253,263.187 262.745,249.679 254.385,249.679
  L16 w0.2: R747.1@112.185,267.731 112.185,266.974 112.211,266.948 v1(112.211,266.922) 112.211,266.492 112.998,265.705 U35_I2C_Expander_Main_Rst.18@112.998,264.843
GPIO_Exp_Reset2: R748.1 U35_I2C_Expander_Main_Rst.19 | length 3
  L16 w0.2: R748.1@113.284,267.731 113.284,266.687 113.648,266.324 U35_I2C_Expander_Main_Rst.19@113.648,264.843
GPIO_I2C0.SCL: R559_I2C_Bridge_GPIO.2 SP3_I2C_Bridge_GPIO.1 U3_I2C_Bridge_GPIO.2 U35_I2C_Expander_00.8 U35_I2C_Expander_01.8 U35_I2C_Expander_02.8 | length 254.5
  L1 w0.2: U35_I2C_Expander_01.8@80.338,340.739 81.075,340.739 v1(81.801,341.465) ; U35_I2C_Expander_02.8@118.305,376.707 119.725,376.707 119.755,376.678 v2(119.799,376.678) ; SP3_I2C_Bridge_GPIO.1@120.279,237.364 121.475,238.56 v2(121.475,239.268) ; v1(123.568,241.525) 123.867,241.525 ; R559_I2C_Bridge_GPIO.2@123.867,240.299 123.867,241.525 ; U3_I2C_Bridge_GPIO.2@125.063,243.104 125.063,242.72 123.867,241.525 ; U35_I2C_Expander_00.8@150.747,249.781 151.315,249.781 v1(152.253,248.844)
  L5 (Sign) w0.2: v1(81.801,341.465) 81.801,340.246 79.558,338.003 73.549,338.003 72.476,336.93 72.476,332.933 77.908,327.501 77.908,326.493 80.626,323.775 82.79,323.775 v6(83.452,323.113) ; v6(93.599,301.46) 94.146,301.46 98.158,305.472 98.158,306.4 v6(99.2,307.442) ; v1(123.568,241.525) 123.867,241.525 124.551,242.208 133.263,242.208 134.813,243.758 134.813,246.044 137.914,249.144 150.761,249.144 151.061,248.844 v1(152.253,248.844)
  L12 (Sign) w0.2: v1(115.354,284.047) 120.263,284.047 v1(124.198,280.111)
  L3 (Sign) w0.2: v1(81.801,341.465) 82.553,341.465 83.201,342.113 86.238,342.113 87.282,343.157 87.282,345.545 88.358,346.621 102.649,346.621 102.916,346.354 105.761,346.354 106.629,347.222 106.629,362.867 119.799,376.037 v2(119.799,376.678) ; v6(83.452,323.113) 83.809,322.756 83.809,321.626 97.993,307.442 v6(99.2,307.442) ; v6(93.599,301.46) 93.817,301.46 104.527,290.749 109.654,290.749 115.354,285.049 v1(115.354,284.047) ; v2(121.475,239.268) 121.475,239.497 v1@123.38,241.402 ; v1(123.568,241.525) 123.503,241.525 v1@123.38,241.402 ; v1(124.198,280.111) 124.198,279.221 123.589,278.611 123.589,256.263 124.198,255.654 124.198,251.006 122.748,249.556 122.748,242.034 v1@123.38,241.402
GPIO_I2C0.SDA: R560_I2C_Bridge_GPIO.2 SP2_I2C_Bridge_PCIE.1@120.119,238.919 U3_I2C_Bridge_GPIO.1 U35_I2C_Expander_00.9 U35_I2C_Expander_01.9 U35_I2C_Expander_02.9 | length 256.5
  L1 w0.2: U35_I2C_Expander_01.9@80.338,341.389 81.012,341.389 v1(81.812,342.189) ; U35_I2C_Expander_02.9@118.305,377.357 119.38,377.357 v2(119.453,377.285) ; SP2_I2C_Bridge_PCIE.1@120.119,238.919 120.164,238.919 121.489,240.244 122.562,240.244 122.562,240.855 122.562,240.873 122.461,240.974 ; v1(121.949,241.802) 121.949,241.486 122.461,240.974 ; U3_I2C_Bridge_GPIO.1@124.563,243.104 124.563,242.934 123.936,242.308 123.164,242.308 122.588,241.732 122.588,241.101 122.461,240.974 ; U35_I2C_Expander_00.9@150.747,250.432 151.508,250.432 152.883,249.057 v1(152.883,248.234)
  L5 (Sign) w0.2: v1(81.812,342.189) 81.351,341.728 81.351,340.657 78.997,338.303 73.425,338.303 72.176,337.054 72.176,332.809 77.608,327.377 77.608,326.369 80.539,323.438 81.547,323.438 81.732,323.253 v6(82.283,323.253) ; v6(93.701,300.825) 94.164,300.825 98.933,305.594 v6(98.933,306.349) ; v1(121.949,241.802) 122.142,241.802 122.992,240.952 124.308,240.952 124.465,241.109 124.465,241.61 124.748,241.893 133.372,241.893 135.113,243.634 135.113,245.919 138.038,248.844 150.637,248.844 151.247,248.234 v1(152.883,248.234)
  L12 (Sign) w0.2: v1(114.93,283.622) 114.956,283.597 119.729,283.597 v1(123.341,279.985)
  L3 (Sign) w0.2: v1(81.812,342.189) 82.036,342.413 86.114,342.413 86.982,343.281 86.982,345.67 88.234,346.921 102.773,346.921 103.04,346.654 105.637,346.654 106.329,347.347 106.329,362.991 119.424,376.086 119.424,377.256 v2(119.453,377.285) ; v6(82.283,323.253) 82.283,322.699 98.594,306.388 98.894,306.388 v6(98.933,306.349) ; v6(93.701,300.825) 94.028,300.825 104.403,290.449 109.529,290.449 114.904,285.075 114.904,283.648 v1(114.93,283.622) ; v1(121.949,241.802) 121.949,249.181 123.898,251.13 123.898,255.529 123.289,256.139 123.289,279.932 v1(123.341,279.985)
GPIO_I2C1.SCL: R227_I2C_Bridge_GPIO.2 SP5_I2C_Bridge_GPIO.1 U3_I2C_Bridge_GPIO.4 | length 8
  L1 w0.2: SP5_I2C_Bridge_GPIO.1@123.52,237.364 124.332,238.176 125.513,238.176 125.819,238.482 125.819,239.955 126.108,240.244 126.479,240.244 126.479,241.517 126.063,241.932 U3_I2C_Bridge_GPIO.4@126.063,243.104
GPIO_I2C1.SDA: R558_I2C_Bridge_GPIO.2 SP4_I2C_Bridge_GPIO.1 U3_I2C_Bridge_GPIO.3 | length 8.5
  L1 w0.2: SP4_I2C_Bridge_GPIO.1@121.888,237.364 v1(122.588,238.064) ; R558_I2C_Bridge_GPIO.2@125.173,240.244 v1(125.173,241.443) 125.563,241.833 U3_I2C_Bridge_GPIO.3@125.563,243.104
  L5 (Sign) w0.12: v1(122.588,238.064) 125.173,240.649 v1(125.173,241.443)
GPIO_I2C2.SCL: R225_I2C_Bridge_GPIO.2 SP7_I2C_Bridge_GPIO.1 U3_I2C_Bridge_GPIO.6 | length 5.7
  L1 w0.2: U3_I2C_Bridge_GPIO.6@127.063,243.104 127.063,242.659 129.09,240.633 129.09,240.582 ; R225_I2C_Bridge_GPIO.2@129.09,240.244 129.09,240.582 ; SP7_I2C_Bridge_GPIO.1@130.861,241.158 129.666,241.158 129.09,240.582
GPIO_I2C2.SDA: R226_I2C_Bridge_GPIO.2 SP6_I2C_Bridge_GPIO.1 U3_I2C_Bridge_GPIO.5 | length 7.8
  L1 w0.2: SP6_I2C_Bridge_GPIO.1@125.216,237.364 126.016,238.163 126.565,238.163 127.165,238.763 127.165,239.966 127.443,240.244 127.784,240.244 127.784,241.202 126.563,242.423 U3_I2C_Bridge_GPIO.5@126.563,243.104
GPIO_I2C3.SCL: R223_I2C_Bridge_GPIO.2 SP9_I2C_Bridge_GPIO.1 U3_I2C_Bridge_GPIO.8 | length 7.8
  L1 w0.2: U3_I2C_Bridge_GPIO.8@127.748,244.289 129.933,244.289 130.196,244.026 131.904,244.026 131.954,244.026 132.254,244.326 132.254,244.409 132.459,244.615 133.957,244.615 SP9_I2C_Bridge_GPIO.1@134.813,243.758
GPIO_I2C3.SDA: R224_I2C_Bridge_GPIO.2 SP8_I2C_Bridge_GPIO.1 U3_I2C_Bridge_GPIO.7 | length 7.9
  L1 w0.2: U3_I2C_Bridge_GPIO.7@127.748,243.789 128.605,243.789 129.603,242.791 131.954,242.791 132.254,242.491 132.254,242.408 132.371,242.291 134.296,242.291 134.64,241.948 SP8_I2C_Bridge_GPIO.1@134.813,241.948
GPIO_I2C4.SCL: R9_I2C_Bridge_GPIO.2 SP11_I2C_Bridge_GPIO.1 U3_I2C_Bridge_GPIO.11 U35_I2C_Expander_10.8 U35_I2C_Expander_11.8 U35_I2C_Expander_12.8 | length 484.5
  L1 w0.2: U3_I2C_Bridge_GPIO.11@127.748,245.789 129.315,245.789 130.022,246.497 130.668,246.497 ; v2(130.041,245.784) 130.668,246.411 130.668,246.497 ; v2(136.436,248.247) 135.727,248.247 SP11_I2C_Bridge_GPIO.1@134.714,247.233 134.712,247.232 132.111,247.232 131.904,247.024 131.904,246.497 130.668,246.497 ; U35_I2C_Expander_12.8@142.791,177.615 143.403,177.615 v2(143.777,177.241) ; U35_I2C_Expander_10.8@211.305,366.99 v2(212.661,366.99)
  L5 (Sign) w0.2: v6(202.22,383.471) 202.22,385.78 v6(205.415,388.976) ; v1(202.451,244.46) 203.089,244.46 205.097,246.469 209.244,246.469 210.517,247.742 219.44,247.742 222.795,244.388 v6(248.007,244.388)
  L3 (Sign) w0.2: v2(130.041,245.784) 130.041,245.744 130.106,245.678 130.106,245.613 138.865,236.854 138.865,232.177 135.382,228.694 135.382,184.703 133.291,182.612 133.291,177.968 135.055,176.205 142.74,176.205 v2(143.777,177.241) ; v2(136.436,248.247) 141.784,248.247 146.217,243.814 161.348,243.814 162.992,242.169 190.404,242.169 190.994,241.58 194.272,241.58 196.947,244.254 202.245,244.254 v1(202.451,244.46) ; v6(202.22,383.471) 202.603,383.088 202.603,367.035 203.408,366.23 211.902,366.23 v2(212.661,366.99) ; v6(205.415,388.976) 245.868,388.976 250.077,384.767 258.59,384.767 260.368,382.989 264.434,382.989 281.16,366.262 281.16,319.255 280.632,318.727 280.632,261.626 259.282,240.276 253.231,240.276 249.119,244.388 v6(248.007,244.388)
GPIO_I2C4.SDA: R10_I2C_Bridge_GPIO.2 SP10_I2C_Bridge_GPIO.1 U3_I2C_Bridge_GPIO.10 U35_I2C_Expander_10.9 U35_I2C_Expander_11.9 U35_I2C_Expander_12.9 | length 483.2
  L1 w0.2: U3_I2C_Bridge_GPIO.10@127.748,245.289 130.543,245.289 ; v2(130.869,245.712) 130.543,245.387 130.543,245.289 ; v2(136.411,247.429) 136.411,247.344 136.207,247.141 136.207,246.786 135.083,245.661 SP10_I2C_Bridge_GPIO.1@134.714,245.661 134.614,245.761 132.072,245.761 131.955,245.644 131.955,245.313 131.904,245.261 131.876,245.289 130.543,245.289 ; U35_I2C_Expander_12.9@142.791,178.265 v2(143.929,178.265) ; U35_I2C_Expander_11.9@201.814,245.11 201.839,245.085 v1(202.589,245.085) ; U35_I2C_Expander_10.9@211.305,367.64 v2(212.661,367.64)
  L5 (Sign) w0.2: v1(202.589,245.085) 203.289,245.085 204.978,246.774 209.125,246.774 210.393,248.042 219.565,248.042 222.664,244.943 v6(248.432,244.943) ; v6(203.098,383.629) 203.42,383.95 203.42,385.887 v6(206.023,388.491)
  L3 (Sign) w0.2: v2(130.869,245.712) 131.35,245.712 131.766,245.296 131.766,244.697 139.165,237.298 139.165,232.053 135.701,228.589 135.701,184.597 133.591,182.488 133.591,178.092 135.179,176.505 142.168,176.505 v2(143.929,178.265) ; v2(136.411,247.429) 142.177,247.429 146.092,243.514 161.223,243.514 162.868,241.869 190.28,241.869 190.869,241.28 194.396,241.28 197.071,243.954 202.581,243.954 202.901,244.274 202.901,244.732 202.589,245.044 v1(202.589,245.085) ; v6(203.098,383.629) 203.098,383.407 202.903,383.212 202.903,367.175 203.548,366.53 211.552,366.53 v2(212.661,367.64) ; v6(206.023,388.491) 206.173,388.341 246.079,388.341 249.953,384.467 258.465,384.467 260.243,382.689 264.31,382.689 280.861,366.138 280.861,319.38 280.332,318.851 280.332,261.75 259.158,240.576 253.566,240.576 249.199,244.943 v6(248.432,244.943)
GPIO_I2C5.SCL: R7_I2C_Bridge_GPIO.2 SP14_I2C_Bridge_GPIO.1 U3_I2C_Bridge_GPIO.13 | length 6.1
  L1 w0.2: U3_I2C_Bridge_GPIO.13@127.063,246.974 127.063,247.276 127.194,247.407 128.02,247.407 128.656,248.044 129.769,248.044 130.753,249.029 R7_I2C_Bridge_GPIO.2@130.753,250.419
GPIO_I2C5.SDA: R8_I2C_Bridge_GPIO.2 SP13_I2C_Bridge_GPIO.1 U3_I2C_Bridge_GPIO.12 | length 8.5
  L1 w0.2: U3_I2C_Bridge_GPIO.12@127.748,246.289 129.195,246.289 130.638,247.732 131.904,247.732 131.904,248.421 132.454,248.972 SP13_I2C_Bridge_GPIO.1@134.714,248.972
GPIO_I2C6.SCL: R5_I2C_Bridge_GPIO.2 SP16_I2C_Bridge_GPIO.1 U3_I2C_Bridge_GPIO.15 | length 4.4
  L1 w0.2: U3_I2C_Bridge_GPIO.15@126.063,246.974 126.063,247.412 128.28,249.629 R5_I2C_Bridge_GPIO.2@128.28,250.419
GPIO_I2C6.SDA: R6_I2C_Bridge_GPIO.2 SP15_I2C_Bridge_GPIO.1 U3_I2C_Bridge_GPIO.14 | length 5.2
  L1 w0.2: U3_I2C_Bridge_GPIO.14@126.563,246.974 126.563,247.2 127.07,247.707 127.896,247.707 129.517,249.329 R6_I2C_Bridge_GPIO.2@129.517,250.419
GPIO_I2C7.SCL: R3_I2C_Bridge_GPIO.2 SP18_I2C_Bridge_GPIO.1 U3_I2C_Bridge_GPIO.17 | length 4.2
  L1 w0.2: U3_I2C_Bridge_GPIO.17@125.063,246.974 125.063,247.939 124.549,248.453 124.549,249.161 R3_I2C_Bridge_GPIO.2@125.807,250.419
GPIO_I2C7.SDA: R4_I2C_Bridge_GPIO.2 SP17_I2C_Bridge_GPIO.1 U3_I2C_Bridge_GPIO.16 | length 4.1
  L1 w0.2: U3_I2C_Bridge_GPIO.16@125.563,246.974 125.563,248.359 126.146,248.942 126.517,249.314 127.043,249.84 R4_I2C_Bridge_GPIO.2@127.043,250.419
GPIOa_00.GPIO0: U35_I2C_Expander_00.17
GPIOa_00.GPIO1: U35_I2C_Expander_00.18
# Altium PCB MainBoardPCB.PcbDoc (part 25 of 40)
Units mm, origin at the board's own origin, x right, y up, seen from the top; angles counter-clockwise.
Board outline 258.95 x 308.86 mm, 16 copper layers (L1, L2 (GND), L3 (Sign), L4 (GND), L5 (Sign), L6 (PWR/GND), L7(12V+Other), L8 (Plane_GND), L9 (PWR/GND), L10 (3V3+Other), L11 (PWR/GND), L12 (Sign), L13 (GND), L14 (Sign), L15 (GND), L16), stack 2.503 mm thick; 2578 components, 1867 nets, 8817 pads, 8021 vias.
Unrouted connection lines stored in the file: 25.

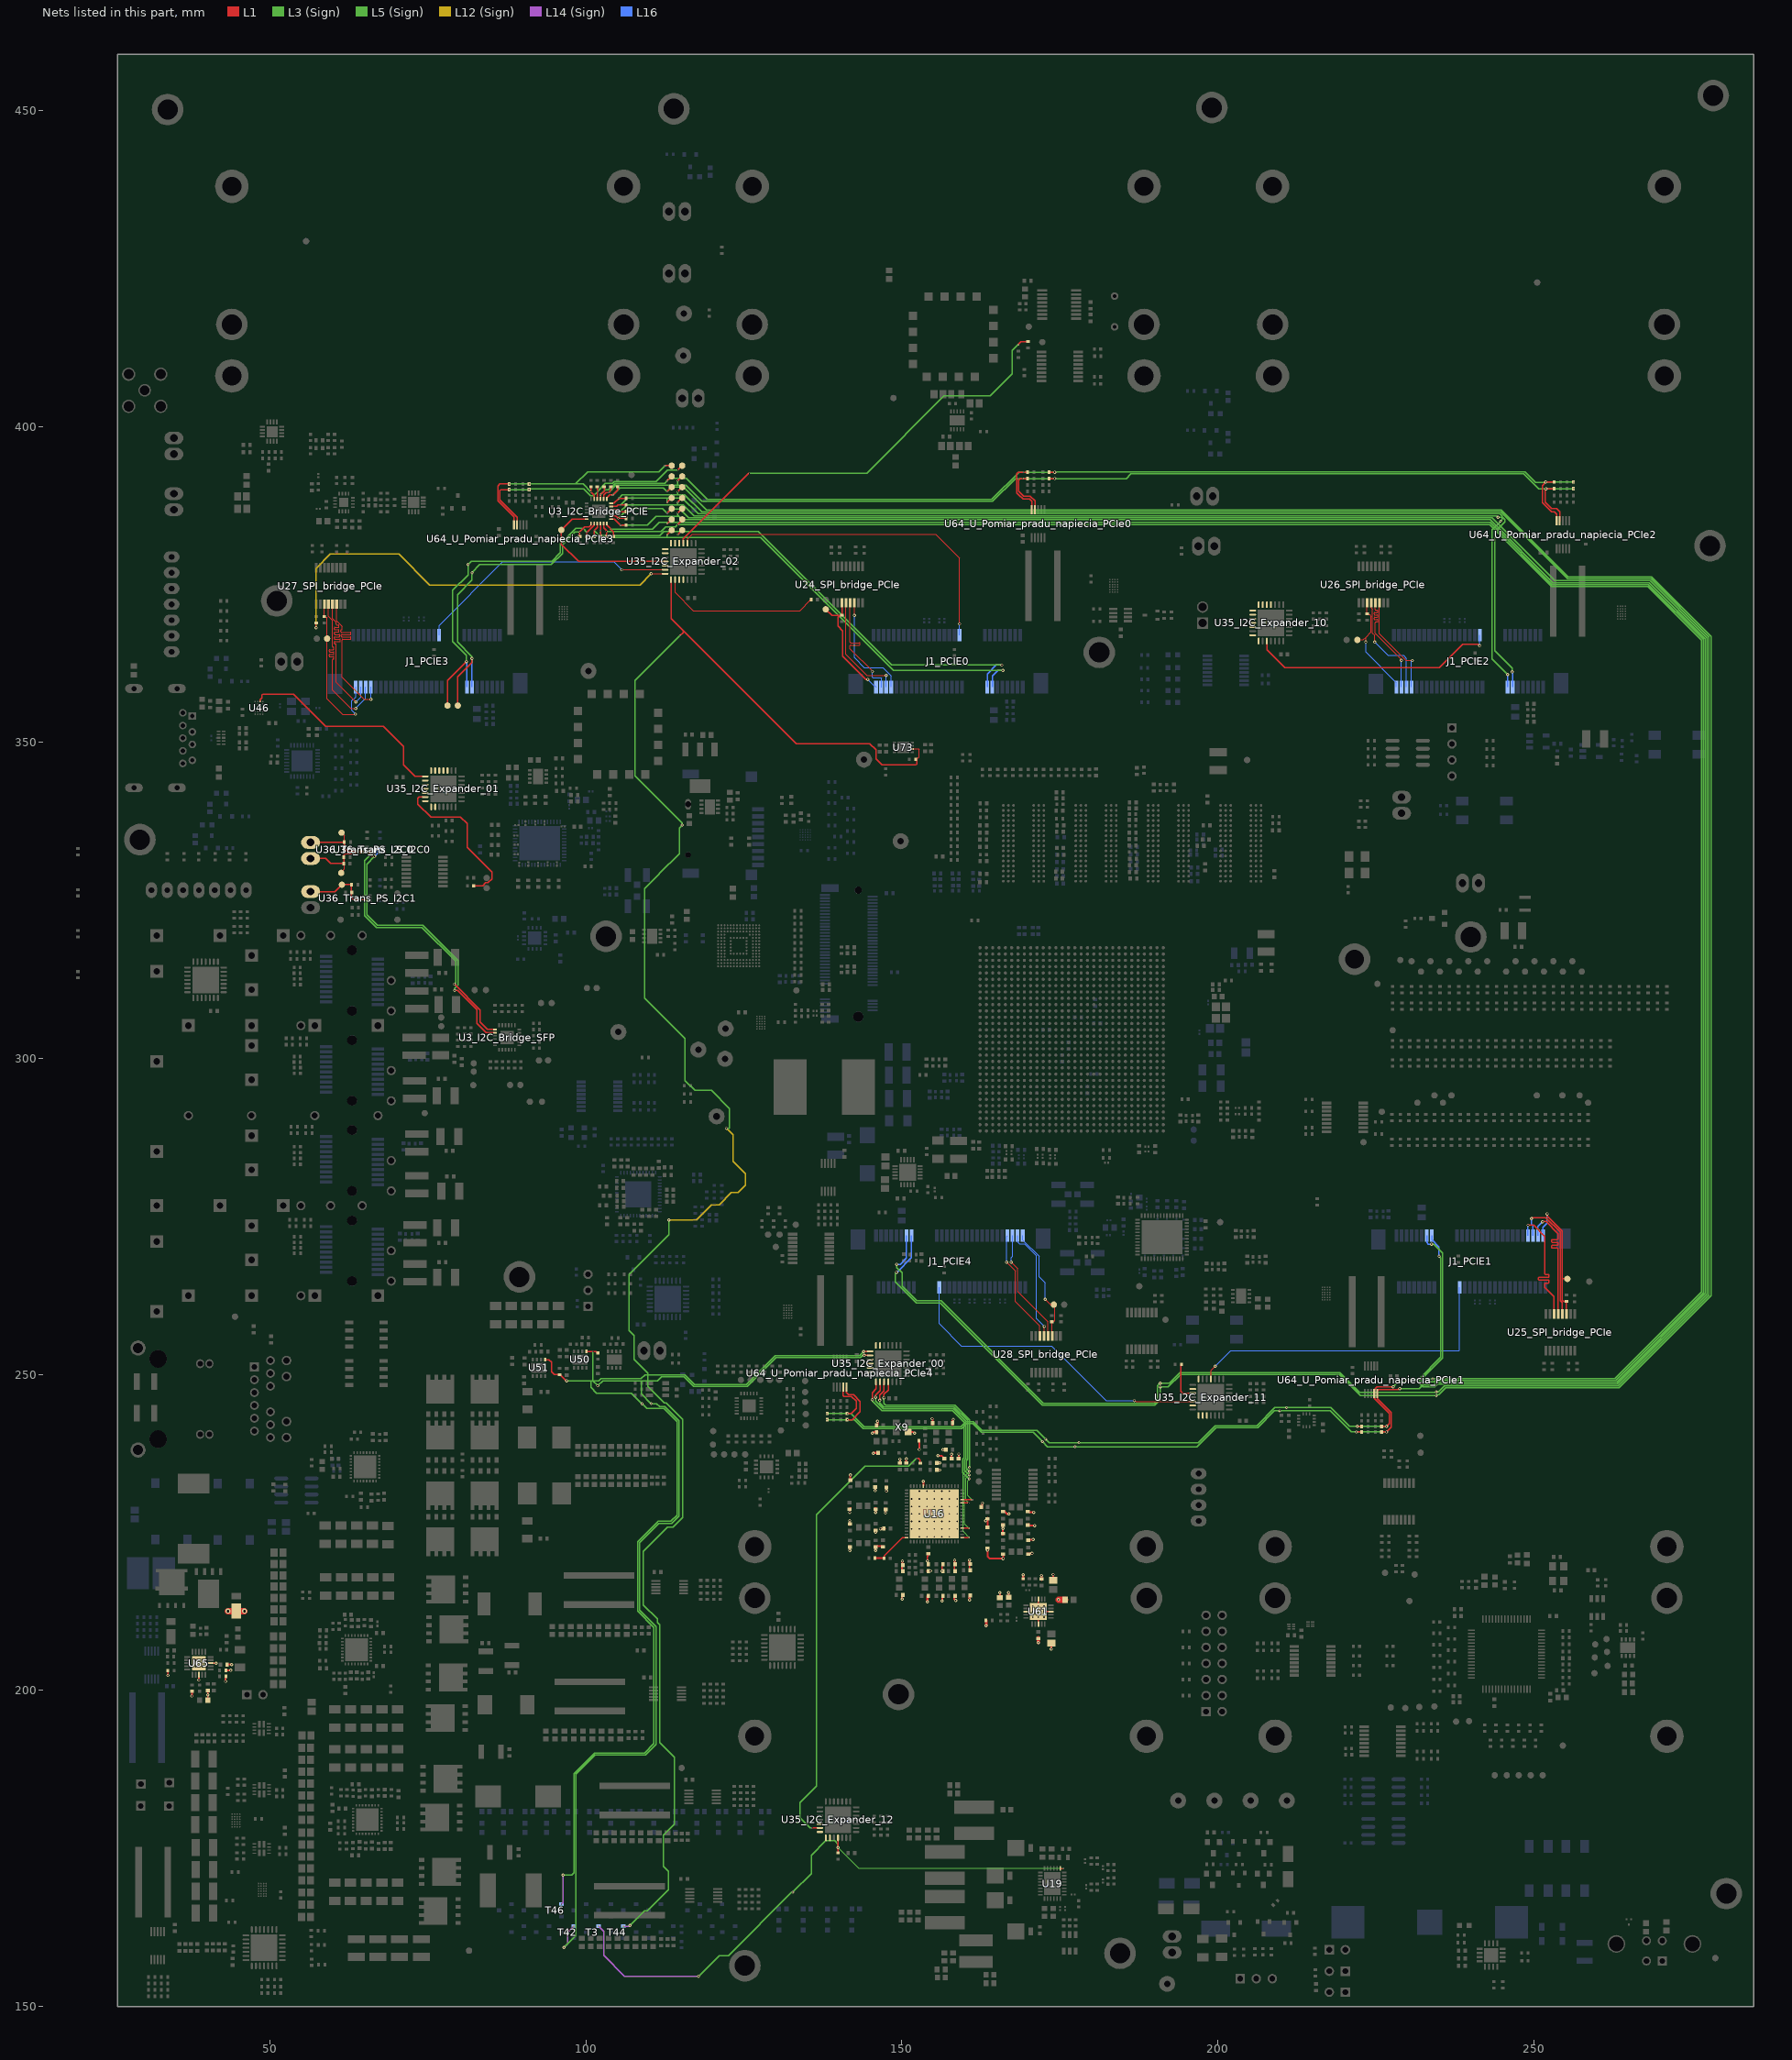
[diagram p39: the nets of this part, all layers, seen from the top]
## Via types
v1: diameter 0.5, hole 0.25, L1 to L16, tented both sides, 4341 vias
v2: diameter 0.254, hole 0.1, L1 to L3 (Sign), tented both sides, 781 vias
v3: diameter 0.5, hole 0.25, L1 to L16, 565 vias
v4: diameter 0.254, hole 0.1, L15 (GND) to L16, tented both sides, 406 vias
v5: diameter 0.254, hole 0.1, L1 to L2 (GND), tented both sides, 283 vias
v6: diameter 0.457, hole 0.2, L3 (Sign) to L6 (PWR/GND), tented both sides, 254 vias
v7: diameter 0.254, hole 0.1, L1 to L3 (Sign), 237 vias
v8: diameter 0.75, hole 0.4, L1 to L16, 200 vias
v9: diameter 0.8, hole 0.4, L1 to L16, tented both sides, 182 vias
v10: diameter 0.254, hole 0.1, L14 (Sign) to L16, tented both sides, 170 vias
v11: diameter 0.75/0/0/0/0/0/0/0/0/0/0/0/0/0/0/0.75 (per signal layer), hole 0.4, L1 to L16, 160 vias
v12: diameter 0.457, hole 0.2, L3 (Sign) to L6 (PWR/GND), 158 vias
v13: diameter 1.4, hole 0.5, L1 to L16, tented both sides, 80 vias
v14: diameter 0.254, hole 0.1, L14 (Sign) to L16, 65 vias
v15: diameter 0.254, hole 0.1, L1 to L2 (GND), 45 vias
v16: diameter 0.457, hole 0.2, L11 (PWR/GND) to L14 (Sign), tented both sides, 26 vias
v17: diameter 0.457, hole 0.2, L11 (PWR/GND) to L14 (Sign), 25 vias
v18: diameter 0.457, hole 0.2, L7(12V+Other) to L10 (3V3+Other), tented both sides, 11 vias
v19: diameter 0.254/0/0.254 (per signal layer), hole 0.1, L1 to L3 (Sign), 9 vias
v20: diameter 0.2/0/0.2 (per signal layer), hole 0.1, L1 to L3 (Sign), 6 vias
v21: diameter 1.65, hole 1.65, L1 to L16, 5 vias
v22: diameter 1.15, hole 1.15, L1 to L16, 5 vias
v23: diameter 0.457, hole 0.2, L1 to L16, 3 vias
v24: diameter 0.5, hole 0.3, L1 to L16, 2 vias
v25: diameter 0.5/0/0.5 (per signal layer), hole 0.2, L14 (Sign) to L16, 1 vias
v26: diameter 0.5, hole 0.25, L1 to L16, tented bottom, 1 vias

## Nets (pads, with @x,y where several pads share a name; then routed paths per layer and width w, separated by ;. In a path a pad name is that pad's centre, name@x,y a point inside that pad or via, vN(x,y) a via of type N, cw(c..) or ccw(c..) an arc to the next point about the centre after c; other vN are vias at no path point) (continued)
GPIOa_00.GPIO3: U35_I2C_Expander_00.20
GPIOa_00.GPIO4: U35_I2C_Expander_00.21
GPIOa_00.GPIO5: R827.2 T46.1 U35_I2C_Expander_00.22 U51.5 | length 166.5
  L1 w0.2: U51.5@93.544,252.363 94.17,252.363 94.564,251.97 94.564,250.47 95.009,250.025 95.868,250.025 96.871,249.022 v1(96.964,249.022) ; v1(143.98,253.632) 144.947,253.632 U35_I2C_Expander_00.22@144.997,253.681
  L5 (Sign) w0.2: v1(96.964,249.022) 100.796,249.022 ; v6(108.915,245.377) 108.877,245.377 107.188,247.066 101.689,247.066 100.796,247.959 100.796,249.022 ; v1(143.98,253.632) 143.98,253.63 143.354,253.004 130.008,253.004 125.441,248.437 117.204,248.437 115.672,249.969 109.343,249.969 108.743,249.369 102.414,249.369 102.067,249.022 100.796,249.022
  L3 (Sign) w0.2: v1(96.393,170.802) 97.765,170.802 98.154,171.191 98.154,186.858 101.381,190.086 109.288,190.086 110.79,191.587 110.79,210.005 108.225,212.57 108.225,223.566 111.318,226.66 111.43,226.771 113.442,226.771 114.422,227.752 114.422,242.529 112.341,244.61 111.549,244.61 111.531,244.627 109.664,244.627 v6(108.915,245.377)
  L14 (Sign) w0.2: v10(96.121,166.174) 96.393,166.447 v1(96.393,170.802)
GPIOa_00.GPIO6: R826.2 T42.1 U35_I2C_Expander_00.23 U50.5 | length 166.7
  L1 w0.2: U50.5@100.076,253.671 100.115,253.632 v2(101.117,253.632) 101.644,253.632 R826.2@101.905,253.371 ; v1(144.031,253.032) U35_I2C_Expander_00.23@144.997,253.032
  L5 (Sign) w0.2: v1(101.881,248.234) 102.676,249.029 108.763,249.029 ; v6(110.376,245.402) 110.287,245.402 108.763,246.926 108.763,249.029 ; v1(144.031,253.032) 143.973,252.974 143.749,252.974 143.478,252.704 130.132,252.704 125.557,248.129 117.088,248.129 115.548,249.669 111.983,249.669 111.343,249.029 108.763,249.029
  L3 (Sign) w0.2: v1(96.545,159.341) 98.454,161.249 98.454,186.731 101.508,189.786 109.433,189.786 111.09,191.443 111.09,210.149 108.525,212.715 108.525,223.421 111.574,226.471 113.566,226.471 114.722,227.628 114.722,242.653 112.466,244.91 111.693,244.91 111.201,245.402 v6(110.376,245.402) ; v2(101.117,253.632) 101.117,248.997 v1(101.881,248.234)
  L14 (Sign) w0.2: v1(96.545,159.341) 97.105,159.9 97.105,161.721 v10(98.089,162.705)
GPIOa_00.GPIO7: U35_I2C_Expander_00.24
GPIOa_01.GPIO0: U35_I2C_Expander_01.17 | length 0
  L1 w0.12: U35_I2C_Expander_01.17@78.109,345.568 U35_I2C_Expander_01.17@78.113,345.564
GPIOa_01.GPIO1: U35_I2C_Expander_01.18 | length 0
  L1 w0.12: U35_I2C_Expander_01.18@77.463,345.564 U35_I2C_Expander_01.18@77.467,345.567
GPIOa_01.GPIO2: U35_I2C_Expander_01.19
GPIOa_01.GPIO3: U35_I2C_Expander_01.20
GPIOa_01.GPIO4: U35_I2C_Expander_01.21
GPIOa_01.GPIO5: U35_I2C_Expander_01.22 U46.A3 | length 34.1
  L1 w0.2: U46.A3@48.475,356.49 48.475,356.795 48.775,357.095 48.775,357.551 48.854,357.629 53.768,357.629 58.846,352.551 67.985,352.551 71.13,349.406 71.13,346.482 72.973,344.639 U35_I2C_Expander_01.22@74.588,344.639
GPIOa_01.GPIO6: U35_I2C_Expander_01.23
GPIOa_01.GPIO7: U35_I2C_Expander_01.24
GPIOa_02.GPIO0: J1_PCIE0.18 U35_I2C_Expander_02.17 | length 57.9
  L1 w0.12: U35_I2C_Expander_02.17@116.08,381.532 116.103,381.556 116.103,382.228 116.873,382.998 155.343,382.998 159.162,379.178 v1(159.162,368.785)
  L16 w0.12: J1_PCIE0.18@159.137,366.992 159.162,367.017 v1(159.162,368.785)
GPIOa_02.GPIO1: R237_SPI_bridge_Main.2 U35_I2C_Expander_02.18 | length 70.3
  L1 w0.2: U35_I2C_Expander_02.18@115.43,381.532 115.418,381.545 115.418,382.249 125.781,392.612 v2(125.873,392.612) ; v2(168.454,412.961) 168.892,413.4 R237_SPI_bridge_Main.2@169.979,413.4
  L3 (Sign) w0.2: v2(125.873,392.612) 144.471,392.612 156.692,404.834 163.971,404.834 167.51,408.374 167.51,412.018 v2(168.454,412.961)
GPIOa_02.GPIO2: U35_I2C_Expander_02.19
GPIOa_02.GPIO3: U35_I2C_Expander_02.20
GPIOa_02.GPIO4: U35_I2C_Expander_02.21
GPIOa_02.GPIO5: U35_I2C_Expander_02.22
GPIOa_02.GPIO6: U35_I2C_Expander_02.23
GPIOa_10.GPIO1: U35_I2C_Expander_10.18
GPIOa_10.GPIO2: U35_I2C_Expander_10.19
GPIOa_10.GPIO3: U35_I2C_Expander_10.20
GPIOa_10.GPIO4: U35_I2C_Expander_10.21
GPIOa_10.GPIO5: U35_I2C_Expander_10.22
GPIOa_10.GPIO6: U35_I2C_Expander_10.23
GPIOa_10.GPIO7: U35_I2C_Expander_10.24
GPIOa_11.GPIO1: J1_PCIE1.18 U35_I2C_Expander_11.18 | length 52
  L1 w0.12: U35_I2C_Expander_11.18@198.939,249.285 198.939,250.653 v1(199.612,251.326)
  L16 w0.12: v1(199.612,251.326) 202.066,253.78 238.219,253.78 238.29,253.85 J1_PCIE1.18@238.29,263.794
GPIOa_11.GPIO4: U35_I2C_Expander_11.21
GPIOa_11.GPIO6: U35_I2C_Expander_11.23
GPIOa_11.GPIO7: R499.1 U35_I2C_Expander_11.24 | length 6.3
  L1 w0.2: R499.1@194.201,251.6 194.201,247.299 194.44,247.06 U35_I2C_Expander_11.24@196.064,247.06
GPIOb_00.GPIO0: U35_I2C_Expander_00.25
GPIOb_00.GPIO1: U35_I2C_Expander_00.26
GPIOb_00.GPIO2: U35_I2C_Expander_00.27
GPIOb_00.GPIO4: U16.29 U35_I2C_Expander_00.1 | length 34.1
  L1 w0.2: v1(145.319,246.018) 145.319,247.122 145.922,247.725 U35_I2C_Expander_00.1@145.922,248.856 ; U16.29@159.565,230.195 159.573,230.188 161.114,230.188 v7(161.137,230.165)
  L5 (Sign) w0.2: v1(145.319,246.018) 145.319,245.82 146.866,244.273 158.051,244.273 159.837,242.486 159.837,236.812 159.656,236.631 159.656,234.479 160.633,233.502 v12(160.706,233.502)
  L3 (Sign) w0.12: v12(160.706,233.502) 160.706,233.461 160.422,233.178 160.422,230.88 v7(161.137,230.165)
GPIOb_00.GPIO5: U16.28 U35_I2C_Expander_00.2 | length 33.7
  L1 w0.2: v1(145.86,246.411) 145.86,246.747 146.572,247.46 U35_I2C_Expander_00.2@146.572,248.856 ; U16.28@159.565,229.695 v7(160.559,229.695)
  L5 (Sign) w0.2: v1(145.86,246.411) 145.86,245.778 147.065,244.573 158.175,244.573 160.137,242.61 160.137,236.688 159.956,236.507 159.956,234.816 160.67,234.102 v12(160.685,234.102)
  L3 (Sign) w0.12: v7(160.559,229.695) 160.133,230.121 160.133,233.604 160.631,234.102 v12(160.685,234.102)
GPIOb_00.GPIO6: U16.20 U35_I2C_Expander_00.3 | length 37.7
  L1 w0.2: v1(146.533,245.923) 146.533,246.775 147.175,247.417 147.175,248.809 U35_I2C_Expander_00.3@147.222,248.856 ; U16.20@159.565,225.695 159.573,225.688 160.62,225.688 v7(160.642,225.665)
  L5 (Sign) w0.2: v1(146.533,245.923) 146.533,245.529 147.189,244.873 158.299,244.873 160.437,242.734 160.437,236.564 160.256,236.382 160.256,235.116 160.669,234.702 v12(160.706,234.702)
  L3 (Sign) w0.12: v7(160.642,225.665) 159.913,226.394 159.913,233.91 v12(160.706,234.702)
GPIOb_00.GPIO7: U16.17 U35_I2C_Expander_00.4 | length 38.9
  L1 w0.2: v1(147.195,246.329) 147.195,246.881 147.872,247.558 U35_I2C_Expander_00.4@147.872,248.856 ; U16.17@159.565,224.195 159.573,224.203 160.627,224.203 v7(160.642,224.218)
  L5 (Sign) w0.2: v1(147.195,246.329) 147.195,245.466 147.489,245.173 158.423,245.173 160.737,242.859 160.737,235.334 v12(160.706,235.302)
  L3 (Sign) w0.12: v7(160.642,224.218) 159.693,225.167 159.693,234.339 160.657,235.302 v12(160.706,235.302)
GPIOb_01.GPIO0: U35_I2C_Expander_01.25
GPIOb_01.GPIO1: U35_I2C_Expander_01.26
GPIOb_01.GPIO2: R235_SPI_bridge_Main.2 U35_I2C_Expander_01.27 | length 25
  L1 w0.2: U35_I2C_Expander_01.27@74.588,341.389 73.648,341.389 73.437,341.178 73.437,340.252 75.47,338.218 80.152,338.218 81.207,337.163 81.207,333.442 85.166,329.484 85.166,328.451 84.532,327.817 84.16,327.817 83.683,327.34 R235_SPI_bridge_Main.2@82.205,327.34
GPIOb_01.GPIO3: U35_I2C_Expander_01.28
GPIOb_01.GPIO4: U35_I2C_Expander_01.1
GPIOb_01.GPIO5: U35_I2C_Expander_01.2
GPIOb_02.GPIO0: SP12_I2C_Bridge_PCIE.1 U3_I2C_Bridge_PCIE.24 U35_I2C_Expander_02.25 | length 24.5
  L1 w0.2: U3_I2C_Bridge_PCIE.24@100.135,385.363 97.845,385.363 SP12_I2C_Bridge_PCIE.1@96.126,383.645 96.126,381.381 98.85,378.657 U35_I2C_Expander_02.25@112.555,378.657
GPIOb_02.GPIO1: U35_I2C_Expander_02.26
GPIOb_02.GPIO2: J1_PCIE3.18 U35_I2C_Expander_02.27 | length 42
  L1 w0.12: v1(105.702,377.342) 105.71,377.35 112.547,377.35 U35_I2C_Expander_02.27@112.555,377.357
  L16 w0.12: J1_PCIE3.18@76.785,366.992 76.785,368.513 86.846,378.574 104.47,378.574 v1(105.702,377.342)
GPIOb_02.GPIO3: R237_SPI_bridge_PCIe.2 U35_I2C_Expander_02.28 | length 69.1
  L1 w0.12: v1@57.313,368.177 57.328,368.191 R237_SPI_bridge_PCIe.2@57.328,368.963 ; v1(110.353,376.707) U35_I2C_Expander_02.28@112.555,376.707
  L12 (Sign) w0.2: v1(57.328,368.163) 57.313,368.177 57.313,377.557 59.564,379.808 70.398,379.808 75.289,374.917 108.563,374.917 v1(110.353,376.707)
GPIOb_02.GPIO4: R691.2 T44.1 U35_I2C_Expander_02.1 U73.6 | length 307.2
  L1 w0.12: U73.6@151.644,348.985 152.676,348.985 152.746,348.914 152.746,347.716 152.597,347.567 152.432,347.567 152.387,347.523 R691.2@152.387,347.358
  L1 w0.2: U35_I2C_Expander_02.1@113.48,375.782 113.48,369.626 115.378,367.727 ; v2(114.922,366.916) 115.378,367.372 115.378,367.727 ; R691.2@152.142,347.358 R691.2@152.387,347.358 ; R691.2@152.387,347.36 R691.2@152.387,347.358 ; 115.378,367.727 133.304,349.802 144.941,349.802 145.901,348.842 145.901,347.44 146.872,346.469 152.27,346.469 152.387,346.586 R691.2@152.387,347.358
  L5 (Sign) w0.2: v6(115.252,336.931) 114.808,336.486 114.808,332.44 111.625,329.257 111.625,329.205 109.283,326.863 109.283,309.584 115.71,303.157 115.71,296.532 117.272,294.97 119.875,294.97 122.758,292.087 122.758,288.988 v1(122.255,288.988)
  L12 (Sign) w0.2: v1(113.132,274.447) 117.513,274.447 119.926,276.86 121.107,276.86 123.05,278.803 124.13,278.803 125.281,279.954 125.281,281.754 123.279,283.756 123.279,287.965 v1(122.255,288.988)
  L3 (Sign) w0.2: v1(106.972,162.814) 109.283,165.125 109.728,165.125 113.081,168.478 113.081,171.356 112.281,172.156 112.281,177.114 114.021,178.854 114.021,189.408 111.69,191.738 111.69,210.431 111.341,210.78 111.341,211.315 109.125,213.532 109.125,222.028 112.968,225.871 113.814,225.871 115.322,227.379 115.322,242.902 112.714,245.511 112.4,245.511 109.791,248.119 109.791,250.241 107.632,252.4 107.632,256.166 106.845,256.954 106.845,265.847 113.132,272.133 v1(113.132,274.447) ; v2(114.922,366.916) 107.798,359.791 107.798,344.754 115.252,337.299 v6(115.252,336.931)
  L14 (Sign) w0.2: v10(105.961,162.705) 106.863,162.705 v1(106.972,162.814)
GPIOb_02.GPIO5: R232_SPI_bridge_PCIe.1 U35_I2C_Expander_02.2 | length 25.5
  L1 w0.12: U35_I2C_Expander_02.2@114.13,375.782 114.13,373.741 116.992,370.878 133.879,370.878 R232_SPI_bridge_PCIe.1@135.644,372.643 R232_SPI_bridge_PCIe.1@135.694,372.643
GPIOb_02.GPIO6: U35_I2C_Expander_02.3
GPIOb_02.GPIO7: U35_I2C_Expander_02.4
GPIOb_10.GPIO0: U35_I2C_Expander_10.25
GPIOb_10.GPIO1: U35_I2C_Expander_10.26
GPIOb_10.GPIO3: U35_I2C_Expander_10.28
GPIOb_10.GPIO4: U35_I2C_Expander_10.1
GPIOb_10.GPIO6: J1_PCIE2.18 U35_I2C_Expander_10.3 | length 39.6
  L1 w0.2: U35_I2C_Expander_10.3@207.78,366.065 207.78,364.693 210.599,361.874 235.074,361.874 238.747,365.547 241.222,365.547 241.465,365.304 v1(241.49,365.304)
  L16 w0.12: v1(241.49,365.304) J1_PCIE2.18@241.49,366.992
GPIOb_11.GPIO1: J1_PCIE4.18 U35_I2C_Expander_11.26 | length 51
  L1 w0.12: v1(186.804,245.897) 186.907,245.897 187.044,245.76 U35_I2C_Expander_11.26@196.064,245.76
  L16 w0.12: J1_PCIE4.18@155.937,263.794 155.937,258.045 159.448,254.533 173.726,254.533 182.362,245.897 v1(186.804,245.897)
GPIOb_11.GPIO2: U35_I2C_Expander_11.27
GPIOb_11.GPIO4: U35_I2C_Expander_11.1 | length 0
  L1 w0.2: U35_I2C_Expander_11.1@196.979,243.525 U35_I2C_Expander_11.1@196.989,243.535
GPIOb_11.GPIO5: U35_I2C_Expander_11.2
GPIOb_11.GPIO6: U35_I2C_Expander_11.3 | length 0
  L1 w0.2: U35_I2C_Expander_11.3@198.273,243.52 U35_I2C_Expander_11.3@198.289,243.535
GPIOb_12.GPIO1: U35_I2C_Expander_12.26
GPIOb_12.GPIO2: R540.2 U35_I2C_Expander_12.27 | length 73.6
  L1 w0.2: v7(135.796,178.282) 135.805,178.274 137.032,178.274 U35_I2C_Expander_12.27@137.041,178.265 ; v2(152.349,236.73) 152.654,236.73 152.915,236.469 R540.2@152.915,235.95
  L3 (Sign) w0.2: v7(135.796,178.282) 135.479,178.282 133.921,179.84 133.921,182.272 136.494,184.844 136.494,227.828 144.165,235.5 151.119,235.5 v2(152.349,236.73)
GPIOb_12.GPIO3: U35_I2C_Expander_12.28
GPIOb_12.GPIO4: U35_I2C_Expander_12.1
GPIOb_12.GPIO5: U35_I2C_Expander_12.2
GPIOb_12.GPIO7: R825.2 T3.1 U19.23 U35_I2C_Expander_12.4 | length 94.7
  L1 w0.12: U19.23@175.078,171.85 175.597,171.85 v2(175.603,171.856)
  L1 w0.2: R825.2@139.916,174.28 v1(139.916,175.171) U35_I2C_Expander_12.4@139.916,176.69
  L5 (Sign) w0.2: v6(132.753,168.084) 135.712,171.044 135.712,173.946 137.991,176.225 139.382,176.225 139.916,175.692 v1(139.916,175.171)
  L3 (Sign) w0.12: v1(139.916,175.171) 143.175,171.912 168.727,171.912 168.783,171.856 v2(175.603,171.856)
  L3 (Sign) w0.2: v1(117.831,154.788) 121.094,158.052 122.566,158.052 132.599,168.084 v6(132.753,168.084)
  L14 (Sign) w0.2: v10(102.025,162.705) 102.819,161.911 102.819,158.077 106.108,154.788 v1(117.831,154.788)
Ground: C63.2 C64.2 C67.2 C70.2 C75.2 C76.2 C77.2 C78.1 C79.1 C80.1 C81.2 C82.2 C83.2 C88.2 C89.2 C90.2 C91.2 C92.2 C93.2 C96.2 C99.1 C100.1 C101.1 C102.1 C103.1 C104.1 C105.1 C106.1 C107.1 C108.1 C109.1 C110.1 C124.1 C125.1 C126.1 C127.1 C141.1 C142.1 C143.1 C144.1 C145.1 C146.1 C147.1 C148.1 C162.1 C163.1 C164.1 C165.1 C179.1 C180.1 C572.1 C574.1 C575.1 C576.1 C578.1 C579.1 C590.1 C591.1 C592.1 FB36.2 R437.1 R439.1 R545.1 U16.44 U16.65 U61.3 U61.8 U61.13 U61.18 U61.21 X9.2 | length 62.3
  L1 w0.2: v1(154.07,220.509) 154.07,221.263 154.17,221.362 ; v1(156.389,218.896) C93.2@156.389,219.97 ; C67.2@158.305,219.978 158.308,219.976 158.308,218.926 C109.1@158.31,218.923 ; C105.1@160.718,219.01 C64.2@160.718,220.015
  L1 w0.254: U61.13@169.653,212.498 v3(170.728,212.498) v3(171.628,212.498) ; U61.18@171.628,210.523 v3(171.628,211.598) v3(171.628,212.498) ; U61.8@171.628,214.473 v3(171.628,213.398) v3(171.628,212.498) ; U61.3@173.603,212.498 v3(172.528,212.498) v3(171.628,212.498)
  L1 w0.3: C162.1@141.763,226.196 v1(141.763,226.885) ; v1(141.763,228.199) C104.1@141.763,228.822 ; v1(141.777,222.154) C179.1@141.777,222.843 ; C108.1@141.861,233.156 v1(141.861,234.102) ; C104.1@141.901,228.818 C104.1@141.901,228.885 ; v1(145.339,240.728) 145.393,240.728 145.553,240.889 C591.1@146.155,240.889 ; v1(145.504,237.541) 145.565,237.602 C590.1@146.395,237.602 ; v1(145.797,231.636) C110.1@145.797,232.325 ; v1(145.847,222.154) C180.1@145.847,222.843 ; C180.1@145.847,222.837 145.857,222.847 147.022,222.847 C81.2@147.032,222.858 ; v1(145.847,225.076) C164.1@145.847,225.351 C164.1@145.847,225.444 ; v1(145.86,228.195) C106.1@145.86,228.885 ; C592.1@146.18,241.924 v1(146.18,242.613) ; v1(146.639,225.585) C77.2@147.328,225.585 ; C81.2@146.984,222.794 C81.2@147.019,222.759 ; v1(147.422,228.089) C83.2@147.422,228.778 ; v1(147.579,231.558) C88.2@147.579,232.248 ; C80.1@149.717,235.927 v1(149.717,236.617) ; C101.1@150.047,218.898 C63.2@150.047,219.834 ; v1(150.052,214.457) C99.1@150.052,215.146 ; C63.2@150.109,219.8 v1(150.109,220.489) ; C96.2@150.717,235.95 v1(150.717,236.639) ; X9.2@151.013,240.893 151.8,240.893 151.965,240.728 v1(152.019,240.728) ; v1(152.776,238.147) R545.1@152.776,239.511 ; U16.44@153.422,232.406 v1(153.422,233.095) ; C124.1@154.06,214.95 154.06,214.037 v1(154.064,214.033) ; C126.1@154.06,218.896 C126.1@154.195,218.896 154.516,218.896 v1(154.546,218.926) ; C70.2@154.07,219.819 v1(154.07,220.509) ; 154.17,221.362 C78.1@154.17,221.775 ; v1(154.808,243.006) 154.808,242.952 154.89,242.87 C142.1@154.89,242.049 ; C90.2@155.554,236.017 v1(156.022,236.017) ; C144.1@155.554,234.888 v1(156.022,234.888) ; v1(155.739,237.15) 156.289,237.15 C91.2@156.761,236.678 ; v1(156.375,214.185) 156.389,214.2 C163.1@156.389,214.95 ; v1(156.521,238.086) C127.1@157.122,238.086 ; C79.1@157.879,236.678 v1(157.879,237.397) ; C125.1@158.037,242.032 158.037,242.744 158.157,242.864 v1(158.157,242.918) ; C107.1@158.31,214.977 158.31,214.467 v1(158.533,214.244) ; C67.2@158.372,219.944 v1(158.372,220.634) ; C89.2@158.972,236.68 159.03,236.738 v1(159.03,237.408) ; C64.2@160.718,220.015 v1(160.718,220.661) ; v1(160.732,214.344) C103.1@160.732,215.033 ; C82.2@162.731,228.97 v1(162.731,229.66) ; v1(163.297,226.886) 163.607,226.886 ; C92.2@163.59,222.651 v1(163.59,222.241) 163.59,221.189 163.901,220.878 v1(166.058,220.878) C148.1@166.058,221.567 ; C75.2@163.59,225.694 163.59,226.576 ; 163.607,226.576 163.607,226.886 ; C76.2@163.607,227.336 163.607,226.886 ; C572.1@165.532,214.804 v1(165.532,215.493) ; C147.1@166.003,226.296 166.019,226.28 v1(166.019,225.645) ; C143.1@166.007,224.633 v1@166.007,225.645 ; C102.1@166.141,228.445 166.641,227.945 v1(166.952,227.945) ; C576.1@166.929,214.804 v1(166.929,215.493) ; R439.1@169.219,217.639 v1(169.219,218.328) ; C100.1@169.918,228.445 170.155,228.208 v1(170.884,228.208) ; C146.1@169.929,221.692 v1(170.619,221.692) ; C145.1@169.992,226.335 170.228,226.099 v1(171.015,226.099) ; C141.1@170.099,223.886 v1(170.788,223.886) ; C578.1@172.128,217.515 v1(172.128,218.204) ; v1(173.673,206.579) C574.1@173.673,207.026 ; C575.1@173.955,217.898 v1(173.955,218.345)
  L1 w0.5: v1(163.328,210.249) 163.328,210.363 163.38,210.415 R437.1@163.38,211.087 ; v1(171.628,207.569) C579.1@171.628,208.224 C579.1@171.628,208.359
  L1 w1: v1(174.803,214.363) FB36.2@175.842,214.363
  other v3: 170.728,211.598 172.528,211.598 170.728,213.398 172.528,213.398 152.785,224.345 153.975,224.345 155.165,224.345 156.355,224.345 157.545,224.345 151.565,225.565 152.785,225.565 153.975,225.565 155.165,225.565 156.355,225.565 157.545,225.565 158.765,225.565 151.565,226.755 152.785,226.755 153.975,226.755 155.165,226.755 156.355,226.755 157.545,226.755 158.765,226.755 151.565,227.945 152.785,227.945 153.975,227.945 155.165,227.945 156.355,227.945 157.545,227.945 158.765,227.945 151.565,229.135 152.785,229.135 153.975,229.135 155.165,229.135 156.355,229.135 157.545,229.135 158.765,229.135 151.565,230.325 152.785,230.325 153.975,230.325 155.165,230.325 156.355,230.325 157.545,230.325 158.765,230.325 152.785,231.545 153.975,231.545 155.165,231.545 156.355,231.545 157.545,231.545
Ground_PWR_PoE: C702.1 C703.1 C704.1 D27.2 R159.1 R160.1 R667.1 R670.2 U65.3 U65.8 U65.21 | length 10
  L1 w0.2: v1(33.873,202.387) R159.1@33.873,203.149 ; C704.1@40.157,198.489 40.157,199.307 v1(40.17,199.307)
  L1 w0.254: v1(37.668,199.124) R670.2@37.668,199.938 ; v1(38.76,201.663) U65.3@38.76,202.478 ; v1(40.17,199.307) C702.1@40.17,200.121 ; U65.8@40.6,204.318 v1(41.478,204.318) ; v1(42.978,201.451) R667.1@42.978,202.265 ; R160.1@42.978,203.203 v1(43.793,203.203)
  L1 w0.3: C703.1@43.104,204.102 43.95,204.102 v1(43.954,204.106)
  L1 w1: v9(43.359,212.56) D27.2@44.666,212.56 v9(45.987,212.56)
  other v3: 38.21,203.768 39.31,203.768 38.21,204.868 39.31,204.868
HiSpeedModule_I2C0.SCL: R185.2 R189.2 R213.2 R221.2 R225_I2C_Bridge_PCIE.2 SP7_I2C_Bridge_PCIE.1 U3_I2C_Bridge_PCIE.6 U64_U_Pomiar_pradu_napiecia_PCIe1.5 U64_U_Pomiar_pradu_napiecia_PCIe4.5 | length 458.3
  L1 w0.2: U3_I2C_Bridge_PCIE.6@103.32,384.678 103.32,384.508 103.896,383.932 103.896,383.8 v2(103.925,383.771) ; v2@103.925,383.77 104.356,383.339 R225_I2C_Bridge_PCIE.2@104.356,382.549 ; v2(112.889,384.679) 112.925,384.679 113.552,385.305 SP7_I2C_Bridge_PCIE.1@113.589,385.305 ; U64_U_Pomiar_pradu_napiecia_PCIe4.5@141.229,248.004 141.229,247.171 141.565,246.835 142.346,246.835 143.427,245.755 143.427,244.115 142.155,242.844 R213.2@141.294,242.844 ; v1(221.939,240.907) R189.2@222.832,240.907 ; R185.2@225.891,240.907 226.016,240.907 v1(226.716,240.907) 227.475,241.666 227.475,243.926 227.44,243.961 227.44,243.989 225.281,246.148 U64_U_Pomiar_pradu_napiecia_PCIe1.5@225.281,246.97 225.281,247.545 225.331,247.595 228.564,247.595 228.729,247.76 v1(228.811,247.76)
  L5 (Sign) w0.2: v6(172.275,239.395) 173.088,238.583 v6(177.411,238.583) ; v12(209.825,244.26) 217.817,244.26 221.171,240.907 v1(221.939,240.907) v1(226.716,240.907) ; v1(228.811,247.76) 231.885,247.76 232.956,248.831 v6(233.502,248.831)
  L3 (Sign) w0.2: v2(103.925,383.771) 103.927,383.77 110.567,383.77 111.646,384.848 112.889,384.848 ; v2(112.889,384.679) 112.889,384.848 ; v7(138.14,242.844) v7(141.419,242.844) 142.508,242.844 143.579,241.772 143.609,241.772 143.909,241.472 159.47,241.472 160.258,242.259 161.205,242.259 162.586,240.878 170.792,240.878 v6(172.275,239.395) ; v6(177.411,238.583) 196.711,238.583 199.744,241.616 206.353,241.616 208.998,244.26 v12(209.825,244.26) ; v6(233.502,248.831) 234.28,248.831 234.527,249.079 262.994,249.079 276.853,262.938 276.853,366.327 268.181,375 252.945,375 243.096,384.848 112.889,384.848
HiSpeedModule_I2C0.SDA: R186.2 R190.2 R215.2 R222.2 R226_I2C_Bridge_PCIE.2 SP6_I2C_Bridge_PCIE.1 U3_I2C_Bridge_PCIE.5 U64_U_Pomiar_pradu_napiecia_PCIe1.4 U64_U_Pomiar_pradu_napiecia_PCIe4.4 | length 456
  L1 w0.2: U3_I2C_Bridge_PCIE.5@102.82,384.678 102.82,383.971 103.266,383.525 v2(103.266,383.394) 103.266,382.603 R226_I2C_Bridge_PCIE.2@103.32,382.549 ; v2(114.552,384.473) 114.552,384.514 115.252,385.214 SP6_I2C_Bridge_PCIE.1@115.252,385.305 ; U64_U_Pomiar_pradu_napiecia_PCIe4.4@140.729,248.004 140.729,246.653 140.847,246.535 142.029,246.535 142.786,245.779 142.786,244.615 141.999,243.828 R215.2@141.294,243.828 ; v1(222.095,241.796) R190.2@222.832,241.796 ; R186.2@225.891,241.796 v1(226.716,241.796) 227.14,242.22 227.14,243.865 224.781,246.224 U64_U_Pomiar_pradu_napiecia_PCIe1.4@224.781,246.97 224.781,247.545 224.931,247.695 224.931,247.777 225.213,248.06 v1(227.782,248.06)
  L5 (Sign) w0.2: v6(172.796,239.761) 173.338,239.219 v6(178.048,239.219) ; v12(210.9,244.76) 217.897,244.76 220.861,241.796 v1(222.095,241.796) v1(226.716,241.796) ; v1(227.782,248.06) 228.392,248.67 229.294,248.67 229.925,249.301 v6(234.023,249.301)
  L3 (Sign) w0.2: v2(103.266,383.394) 103.268,383.396 111.926,383.396 112.654,384.124 114.181,384.124 v2@114.53,384.473 ; v2@114.524,384.473 243.047,384.473 252.82,374.7 268.056,374.7 276.553,366.203 276.553,263.062 262.869,249.379 234.1,249.379 v6(234.023,249.301) ; v7(138.14,243.828) v7(141.419,243.828) 141.978,243.828 142.681,243.124 144.034,241.772 159.346,241.772 160.133,242.559 161.329,242.559 162.71,241.178 171.379,241.178 v6(172.796,239.761) ; v6(178.048,239.219) 196.923,239.219 199.62,241.916 206.229,241.916 209.073,244.76 v12(210.9,244.76)
HiSpeedModule_I2C1.SCL: J1_PCIE0.15 R227_I2C_Bridge_PCIE.2 SP5_I2C_Bridge_PCIE.1 U3_I2C_Bridge_PCIE.4 | length 81.9
  L1 w0.2: R227_I2C_Bridge_PCIE.2@102.32,382.549 v2(102.32,383.54) U3_I2C_Bridge_PCIE.4@102.32,384.678 ; v2(114.552,382.903) SP5_I2C_Bridge_PCIE.1@115.252,383.603
  L3 (Sign) w0.2: v2(102.32,383.54) 102.32,382.973 102.519,382.773 111.728,382.773 112.349,383.395 115.044,383.395 ; v2(114.552,382.903) 115.044,383.395 ; v1(165.837,362.255) 148.437,362.255 127.297,383.395 115.044,383.395
  L16 w0.2: J1_PCIE0.15@163.537,358.792 163.537,360.818 164.974,362.255 v1(165.837,362.255)
HiSpeedModule_I2C1.SDA: J1_PCIE0.13 R558_I2C_Bridge_PCIE.2 SP4_I2C_Bridge_PCIE.1 U3_I2C_Bridge_PCIE.3 | length 81.4
  L1 w0.2: R558_I2C_Bridge_PCIE.2@101.32,382.549 v2(101.32,383.557) 101.82,384.057 U3_I2C_Bridge_PCIE.3@101.82,384.678 ; v2(112.889,382.903) SP4_I2C_Bridge_PCIE.1@113.589,383.603
  L3 (Sign) w0.2: v2(101.32,383.557) 101.32,383.548 102.395,382.473 112.878,382.473 ; v2(112.889,382.903) 112.889,382.484 112.878,382.473 ; v1(166.002,361.417) 148.704,361.417 127.648,382.473 112.878,382.473
  L16 w0.2: J1_PCIE0.13@164.337,358.792 164.337,360.552 165.202,361.417 v1(166.002,361.417)
HiSpeedModule_I2C2.SCL: J1_PCIE1.15 R223_I2C_Bridge_PCIE.2 SP9_I2C_Bridge_PCIE.1 U3_I2C_Bridge_PCIE.8 | length 366.6
  L1 w0.2: U3_I2C_Bridge_PCIE.8@104.005,385.863 104.763,385.863 v2(105.147,385.48) R223_I2C_Bridge_PCIE.2@106.446,385.48 ; v2(112.889,386.307) SP9_I2C_Bridge_PCIE.1@113.589,387.007
  L3 (Sign) w0.2: v2(105.147,385.48) 106.712,387.045 112.151,387.045 v2(112.889,386.307) 113.513,386.931 114.922,386.931 116.262,385.591 243.389,385.591 253.38,375.6 268.429,375.6 277.453,366.576 277.453,262.69 263.242,248.479 234.776,248.479 234.366,248.069 232.446,248.069 231.932,248.583 231.932,249.376 235.306,252.749 235.306,268.453 v1(235.039,268.719)
  L16 w0.2: J1_PCIE1.15@233.89,271.994 233.89,271.316 235.039,270.167 v1(235.039,268.719)
HiSpeedModule_I2C2.SDA: J1_PCIE1.13 R224_I2C_Bridge_PCIE.2 SP8_I2C_Bridge_PCIE.1 U3_I2C_Bridge_PCIE.7 | length 365.6
  L1 w0.2: U3_I2C_Bridge_PCIE.7@104.005,385.363 104.552,385.363 v2(105.491,384.424) R224_I2C_Bridge_PCIE.2@106.446,384.424 ; v2(114.552,386.307) SP8_I2C_Bridge_PCIE.1@115.252,387.007
  L3 (Sign) w0.2: v2(105.491,384.424) 109.711,384.424 111.112,385.826 114.732,385.826 ; v2(114.552,386.307) 114.552,386.005 114.732,385.826 ; v1(233.845,270.637) 234.206,270.637 235.606,269.237 235.606,252.625 232.232,249.252 232.232,248.707 232.57,248.369 234.242,248.369 234.651,248.779 263.118,248.779 277.153,262.814 277.153,366.451 268.305,375.3 253.096,375.3 243.105,385.291 242.526,385.291 115.267,385.291 114.732,385.826
  L16 w0.2: J1_PCIE1.13@233.09,271.994 233.09,270.872 233.324,270.637 v1(233.845,270.637)
HiSpeedModule_I2C3.SCL: J1_PCIE2.15 R9_I2C_Bridge_PCIE.2 SP11_I2C_Bridge_PCIE.1 U3_I2C_Bridge_PCIE.11 | length 174.1
  L1 w0.2: U3_I2C_Bridge_PCIE.11@104.005,387.363 104.89,387.363 105.117,387.59 v2(105.499,387.59) R9_I2C_Bridge_PCIE.2@106.446,387.59 ; v2(112.889,388.009) SP11_I2C_Bridge_PCIE.1@113.589,388.709
  L5 (Sign) w0.2: v6(244.767,385.026) 243.421,383.68 243.421,363.245 v1(245.885,360.782)
  L3 (Sign) w0.2: v2(105.499,387.59) 106.618,388.709 112.852,388.709 ; v2(112.889,388.009) 112.889,388.672 112.852,388.709 ; v6(244.767,385.026) 244.767,385.064 244.996,385.293 244.996,385.845 244.649,386.191 117.77,386.191 115.252,388.709 112.852,388.709
  L16 w0.2: v1(245.885,360.782) 245.885,358.797 J1_PCIE2.15@245.89,358.792
HiSpeedModule_I2C3.SDA: J1_PCIE2.13 R10_I2C_Bridge_PCIE.2 SP10_I2C_Bridge_PCIE.1 U3_I2C_Bridge_PCIE.10 | length 173.7
  L1 w0.2: U3_I2C_Bridge_PCIE.10@104.005,386.863 105.097,386.863 v2(105.425,386.535) R10_I2C_Bridge_PCIE.2@106.446,386.535 ; v2(114.552,388.009) SP10_I2C_Bridge_PCIE.1@115.252,388.709
  L5 (Sign) w0.2: v6(244.373,385.635) 245.085,385.635 245.423,385.297 245.423,384.895 243.84,383.312 243.84,364.531 246.613,361.759 v1(246.613,361.175)
  L3 (Sign) w0.2: v2(105.425,386.535) 106.524,387.634 114.552,387.634 ; v2(114.552,388.009) 114.552,387.634 ; v6(244.373,385.635) 244.118,385.891 117.118,385.891 115.375,387.634 114.552,387.634
  L16 w0.2: v1(246.613,361.175) 246.69,361.099 J1_PCIE2.13@246.69,358.792
HiSpeedModule_I2C4.SCL: J1_PCIE3.15 R559_I2C_Bridge_PCIE.2 SP3_I2C_Bridge_PCIE.1 U3_I2C_Bridge_PCIE.2 | length 54.4
  L1 w0.2: SP3_I2C_Bridge_PCIE.1@78.118,355.854 78.118,359.834 v1(81.102,362.818) ; R559_I2C_Bridge_PCIE.2@100.135,382.549 100.135,383.205 v2(100.165,383.235) 101.32,384.39 U3_I2C_Bridge_PCIE.2@101.32,384.678
  L5 (Sign) w0.2: v1(81.102,362.818) 81.102,363.804 78.943,365.963 78.943,374.117 81.369,376.542 v6(81.369,378.181)
  L3 (Sign) w0.2: v6(81.369,378.181) 81.902,378.714 94.64,378.714 95.987,380.06 95.987,381.445 98.438,383.896 99.555,383.896 100.165,383.285 v2(100.165,383.235)
  L16 w0.2: v1(81.102,362.818) 81.185,362.736 J1_PCIE3.15@81.185,358.792
HiSpeedModule_I2C4.SDA: J1_PCIE3.13 R560_I2C_Bridge_PCIE.2 SP2_I2C_Bridge_PCIE.1@79.743,355.854 U3_I2C_Bridge_PCIE.1 | length 52.4
  L1 w0.2: SP2_I2C_Bridge_PCIE.1@79.743,355.854 79.743,360.439 81.991,362.687 v1(81.991,363.286) ; R560_I2C_Bridge_PCIE.2@99.022,382.549 v2(99.022,383.299) 99.822,384.099 100.507,384.099 100.82,384.412 U3_I2C_Bridge_PCIE.1@100.82,384.678
  L5 (Sign) w0.2: v1(81.991,363.286) 81.991,363.588 79.68,365.9 79.68,373.401 81.991,375.713 v6(81.991,376.863)
  L3 (Sign) w0.2: v6(81.991,376.863) 83.178,378.168 87.874,378.168 87.876,378.17 88.249,378.17 88.251,378.168 92.571,378.168 92.573,378.17 92.946,378.17 92.948,378.168 94.519,378.168 96.287,379.936 96.287,381.32 98.265,383.299 v2(99.022,383.299)
  L16 w0.2: J1_PCIE3.13@81.985,358.792 81.985,363.391 v1(81.991,363.286)
HiSpeedModule_I2C5.SCL: J1_PCIE4.15 R7_I2C_Bridge_PCIE.2 SP14_I2C_Bridge_PCIE.1 U3_I2C_Bridge_PCIE.13 | length 449.7
  L1 w0.2: U3_I2C_Bridge_PCIE.13@103.32,388.548 103.32,388.702 103.797,389.179 v2(104.267,389.179) 105.028,389.94 R7_I2C_Bridge_PCIE.2@105.028,390.539 ; v2(112.889,389.711) SP14_I2C_Bridge_PCIE.1@113.589,390.411
  L5 (Sign) w0.2: v6(190.906,248.026) 192.166,248.026 194.168,250.028 219.247,250.028 222.62,246.655 234.584,246.655 v6(234.594,246.645)
  L3 (Sign) w0.2: v2(104.267,389.179) 105.397,390.309 112.29,390.309 v2(112.889,389.711) 113.581,390.403 115.476,390.403 119.088,386.791 244.898,386.791 255.49,376.2 268.678,376.2 278.062,366.816 278.062,262.45 263.491,247.879 236.074,247.879 234.99,246.795 234.744,246.795 v6(234.594,246.645) ; v1(149.172,266.205) 149.172,266.157 148.953,265.938 148.953,264.694 152.292,261.355 156.085,261.355 172.292,245.147 190.06,245.147 190.906,245.994 v6(190.906,248.026)
  L16 w0.2: v1(149.172,266.205) 149.25,266.205 151.537,268.491 J1_PCIE4.15@151.537,271.994
HiSpeedModule_I2C5.SDA: J1_PCIE4.13 R8_I2C_Bridge_PCIE.2 SP13_I2C_Bridge_PCIE.1 U3_I2C_Bridge_PCIE.12 | length 446.3
  L1 w0.2: U3_I2C_Bridge_PCIE.12@104.005,387.863 104.437,387.863 v2(105.219,388.645) R8_I2C_Bridge_PCIE.2@106.446,388.645 ; v2(114.552,389.711) SP13_I2C_Bridge_PCIE.1@115.252,390.411
  L5 (Sign) w0.2: v6(190.906,248.626) 192.341,248.626 194.044,250.328 219.372,250.328 222.489,247.21 234.56,247.21 v6(234.594,247.245)
  L3 (Sign) w0.2: v2(105.219,388.645) 105.783,389.209 114.44,389.209 ; v2(114.552,389.711) 114.552,389.322 114.44,389.209 ; v1(149.187,267.437) 149.187,266.941 150.05,266.078 150.05,264.02 152.416,261.655 156.209,261.655 172.417,245.447 189.936,245.447 190.456,245.968 190.456,248.212 190.72,248.476 190.906,248.476 v6(190.906,248.626) ; v6(234.594,247.245) 234.926,247.245 235.86,248.179 263.366,248.179 277.762,262.574 277.762,366.691 268.553,375.9 255.365,375.9 244.774,386.491 118.346,386.491 115.629,389.209 114.44,389.209
  L16 w0.2: v1(149.187,267.437) 149.771,267.437 150.737,268.403 J1_PCIE4.13@150.737,271.994
HiSpeedModule_I2C6.SCL: R5_I2C_Bridge_PCIE.2 R176.2 R180.2 R194.2 R198.2 SP16_I2C_Bridge_PCIE.1 U3_I2C_Bridge_PCIE.15 U64_U_Pomiar_pradu_napiecia_PCIe0.5 U64_U_Pomiar_pradu_napiecia_PCIe2.5 | length 181.4
  L1 w0.2: U3_I2C_Bridge_PCIE.15@102.32,388.548 v2(102.32,389.238) 102.895,389.813 R5_I2C_Bridge_PCIE.2@102.895,390.539 ; v2(112.889,391.412) SP16_I2C_Bridge_PCIE.1@113.589,392.113 ; R176.2@169.977,392.788 168.454,392.788 168.204,392.538 168.204,389.523 168.504,389.223 169.209,388.518 170.256,388.518 170.587,388.187 U64_U_Pomiar_pradu_napiecia_PCIe0.5@170.587,386.83 ; R180.2@173.29,392.788 173.293,392.786 v1(174.193,392.786) ; R194.2@253.324,391.218 v1(251.93,391.218) 251.39,390.678 251.39,387.942 252.824,386.508 253.274,386.508 253.646,386.136 U64_U_Pomiar_pradu_napiecia_PCIe2.5@253.646,385.075 ; R198.2@256.256,391.218 v7(256.381,391.218)
  L5 (Sign) w0.2: v1(174.193,392.786) 174.239,392.832 248.63,392.832 250.294,391.168 251.88,391.168 v1(251.93,391.218)
  L3 (Sign) w0.2: v2(102.32,389.238) 103.05,389.968 103.603,389.968 104.638,391.003 112.479,391.003 v2(112.889,391.412) 113.297,391.82 115.9,391.82 119.253,388.467 164.247,388.467 168.568,392.788 v7(169.287,392.788) 169.289,392.786 v1(174.193,392.786) ; v1(251.93,391.218) v7(256.381,391.218)
HiSpeedModule_I2C6.SDA: R6_I2C_Bridge_PCIE.2 R177.2 R181.2 R195.2 R199.2 SP15_I2C_Bridge_PCIE.1 U3_I2C_Bridge_PCIE.14 U64_U_Pomiar_pradu_napiecia_PCIe0.4 U64_U_Pomiar_pradu_napiecia_PCIe2.4 | length 178.3
  L1 w0.2: U3_I2C_Bridge_PCIE.14@102.82,388.548 102.82,389.167 103.213,389.56 v2(103.619,389.56) 103.955,389.895 R6_I2C_Bridge_PCIE.2@103.955,390.539 ; v2(114.552,391.412) SP15_I2C_Bridge_PCIE.1@115.252,392.113 ; R177.2@169.977,391.772 v7(169.209,391.772) 168.737,391.772 168.504,391.538 168.504,389.773 169.287,388.99 170.331,388.99 171.087,388.234 U64_U_Pomiar_pradu_napiecia_PCIe0.4@171.087,386.83 ; R181.2@173.29,391.772 v1(174.191,391.772) ; R195.2@253.324,390.16 v1(251.951,390.16) 251.834,390.042 251.834,388.029 252.855,387.008 253.646,387.008 254.146,386.508 U64_U_Pomiar_pradu_napiecia_PCIe2.4@254.146,385.075
  L5 (Sign) w0.2: v1(174.191,391.772) 185.504,391.772 186.264,392.532 248.42,392.532 250.792,390.16 v1(251.951,390.16)
  L3 (Sign) w0.2: v2(103.619,389.56) 104.762,390.703 114.552,390.703 ; v2(114.552,391.412) 114.552,390.703 ; v1(174.191,391.772) v7(169.209,391.772) 167.976,391.772 164.372,388.167 118.347,388.167 115.811,390.703 114.552,390.703 ; v1(251.951,390.16) v7(256.381,390.16)
HiSpeedModule_I2C7.SCL: R3_I2C_Bridge_PCIE.2 R203.2 R207.2 SP18_I2C_Bridge_PCIE.1 U3_I2C_Bridge_PCIE.17 U64_U_Pomiar_pradu_napiecia_PCIe3.5 | length 41.3
  L1 w0.2: v7(87.913,390.907) 86.396,390.907 86.085,390.596 86.085,388.24 88.633,385.692 U64_U_Pomiar_pradu_napiecia_PCIe3.5@88.633,384.471 ; R207.2@90.972,390.907 v7(91.097,390.907) ; R3_I2C_Bridge_PCIE.2@100.82,390.539 v2(100.82,389.654) 101.32,389.154 U3_I2C_Bridge_PCIE.17@101.32,388.548 ; v2(112.522,393.789) 112.547,393.814 SP18_I2C_Bridge_PCIE.1@113.589,393.814
  L3 (Sign) w0.2: v7(87.913,390.907) v7(91.097,390.907) 98.376,390.907 ; v2(100.82,389.654) 99.567,390.907 98.376,390.907 ; v2(112.522,393.789) 111.546,392.813 100.281,392.813 98.376,390.907
HiSpeedModule_I2C7.SDA: R4_I2C_Bridge_PCIE.2 R204.2 R208.2 SP17_I2C_Bridge_PCIE.1 U3_I2C_Bridge_PCIE.16 U64_U_Pomiar_pradu_napiecia_PCIe3.4 | length 40.1
  L1 w0.2: v7(87.913,390.018) 86.502,390.018 86.385,389.901 86.385,388.377 87.472,387.29 87.482,387.29 89.133,385.639 U64_U_Pomiar_pradu_napiecia_PCIe3.4@89.133,384.471 ; R208.2@90.972,390.018 v7(91.022,390.018) ; U3_I2C_Bridge_PCIE.16@101.82,388.548 v2(101.82,389.718) R4_I2C_Bridge_PCIE.2@101.82,390.539 ; v2(114.552,393.114) SP17_I2C_Bridge_PCIE.1@115.252,393.814
  L3 (Sign) w0.2: v7(87.913,390.018) v7(91.022,390.018) 91.164,390.161 99.64,390.161 100.749,389.052 101.218,389.052 101.82,389.654 v2(101.82,389.718) 103.091,390.989 104.2,390.989 104.514,391.303 111.103,391.303 112.914,393.114 v2(114.552,393.114)
HiSpeedModule_SPI0.C\S\: J1_PCIE0.51 R231_SPI_bridge_PCIe.1 SP21_SPI_bridge_PCIe.1 U24_SPI_bridge_PCIe.11 | length 19.1
  L1 w0.2: SP21_SPI_bridge_PCIe.1@137.973,371.081 138.944,370.11 140.176,370.11 ; U24_SPI_bridge_PCIe.11@140.532,372.107 140.532,370.11 140.176,370.11 ; v1(144.628,359.994) 144.375,359.994 140.665,363.704 140.665,367.642 139.882,368.425 139.882,369.815 140.176,370.11
  L16 w0.12: v1(144.628,359.994) 144.656,359.994 145.599,359.051 145.678,359.051 J1_PCIE0.51@145.937,358.792
HiSpeedModule_SPI0.CLK: J1_PCIE0.45 U24_SPI_bridge_PCIe.14 | length 17.5
  L1 w0.12: U24_SPI_bridge_PCIe.14@142.482,372.107 142.503,372.087 v1(142.503,370.11)
  L16 w0.12: v1(142.503,370.11) 142.503,363.418 144.047,361.874 147.039,361.874 148.337,360.576 J1_PCIE0.45@148.337,358.792
HiSpeedModule_SPI0.MISO: J1_PCIE0.49 U24_SPI_bridge_PCIe.13 | length 19.3
  L1 w0.12: U24_SPI_bridge_PCIe.13@141.832,372.107 141.832,366.052 141.832,365.905 ccw(c141.944,365.905) 141.944,365.793 143.283,365.793 cw(c143.283,365.681) 143.395,365.681 143.395,365.531 cw(c143.283,365.531) 143.283,365.419 141.944,365.419 ccw(c141.944,365.307) 141.832,365.307 141.832,365.045 141.832,364.858 145.451,361.239 v1(145.326,361.239)
  L16 w0.12: v1(145.326,361.239) 145.326,360.344 145.396,360.274 146.707,360.274 146.777,360.203 146.777,358.832 J1_PCIE0.49@146.737,358.792
HiSpeedModule_SPI0.MOSI: J1_PCIE0.47 U24_SPI_bridge_PCIe.12 | length 18
  L1 w0.12: U24_SPI_bridge_PCIe.12@141.182,372.107 141.182,363.973 144.52,360.636 v1(147.537,360.636)
  L16 w0.12: J1_PCIE0.47@147.537,358.792 v1(147.537,360.636) 147.739,360.838
HiSpeedModule_SPI1.C\S\: J1_PCIE1.51 R233_SPI_bridge_PCIe.1 SP23_SPI_bridge_PCIe.1 U25_SPI_bridge_PCIe.11 | length 22
  L1 w0.2: v1(252.144,275.421) 252.144,275.097 254.541,272.7 254.541,265.134 ; U25_SPI_bridge_PCIe.11@255.191,259.567 255.191,261.614 255.091,261.514 254.813,261.514 254.541,261.785 254.541,265.134 ; SP23_SPI_bridge_PCIe.1@255.34,265.138 254.545,265.138 254.541,265.134
  L16 w0.2: J1_PCIE1.51@251.49,271.994 251.49,273.27 252.144,273.924 v1(252.144,275.421)
HiSpeedModule_SPI1.CLK: J1_PCIE1.45 U25_SPI_bridge_PCIe.14 | length 22.2
  L1 w0.2: v1(249.111,273.621) 249.987,273.621 251.765,271.844 251.765,266.205 251.765,265.974 ccw(c251.901,265.974) 251.901,265.838 252.311,265.838 cw(c252.311,265.702) 252.447,265.702 252.447,265.52 cw(c252.311,265.52) 252.311,265.384 251.765,265.384 250.911,265.384 ccw(c250.911,265.247) 250.775,265.247 250.775,265.066 ccw(c250.911,265.066) 250.911,264.93 251.765,264.93 252.311,264.93 cw(c252.311,264.793) 252.447,264.793 252.447,264.612 cw(c252.311,264.612) 252.311,264.475 251.901,264.475 ccw(c251.901,264.339) 251.765,264.339 251.765,264.021 251.765,263.794 253.241,262.318 U25_SPI_bridge_PCIe.14@253.241,259.567
  L16 w0.2: J1_PCIE1.45@249.09,271.994 249.111,272.015 v1(249.111,273.621)
HiSpeedModule_SPI1.MISO: J1_PCIE1.49 U25_SPI_bridge_PCIe.13 | length 22.1
  L1 w0.2: v1@251.574,274.232 251.971,274.228 253.891,272.308 253.891,272.047 253.891,271.82 253.891,271.502 cw(c253.755,271.502) 253.755,271.365 252.997,271.365 ccw(c252.997,271.229) 252.861,271.229 252.861,271.047 ccw(c252.997,271.047) 252.997,270.911 253.755,270.911 cw(c253.755,270.775) 253.891,270.775 253.891,270.593 cw(c253.755,270.593) 253.755,270.457 252.997,270.457 ccw(c252.997,270.321) 252.861,270.321 252.861,270.139 ccw(c252.997,270.139) 252.997,270.003 253.755,270.003 cw(c253.755,269.867) 253.891,269.867 253.891,269.57 U25_SPI_bridge_PCIe.13@253.891,259.567
  L16 w0.2: J1_PCIE1.49@250.69,271.994 250.69,273.439 v1(251.419,274.168) v1@251.473,274.221
HiSpeedModule_SPI1.MOSI: J1_PCIE1.47 U25_SPI_bridge_PCIe.12 | length 21.5
  L1 w0.2: v1(249.644,274.688) 249.777,274.821 251.928,274.821 254.216,272.534 254.216,261.686 254.541,261.361 U25_SPI_bridge_PCIe.12@254.541,259.567
  L16 w0.2: v1(249.644,274.688) 249.644,273.812 249.89,273.566 J1_PCIE1.47@249.89,271.994
HiSpeedModule_SPI2.C\S\: J1_PCIE2.51 R236_SPI_bridge_PCIe.1 SP25_SPI_bridge_PCIe.1 U26_SPI_bridge_PCIe.11 | length 17.6
  L1 w0.12: SP25_SPI_bridge_PCIe.1@222.1,366.247 223.038,366.247 223.44,366.648 ; v1(223.44,365.89) 223.44,366.648 ; U26_SPI_bridge_PCIe.11@223.64,372.107 223.64,370.34 223.747,370.233 224.04,370.233 224.281,369.992 224.281,367.49 223.44,366.648
  L16 w0.12: v1(223.44,365.89) 223.44,364.342 228.29,359.492 J1_PCIE2.51@228.29,358.792
HiSpeedModule_SPI2.CLK: J1_PCIE2.45 U26_SPI_bridge_PCIe.14 | length 16.1
  L1 w0.12: U26_SPI_bridge_PCIe.14@225.59,372.107 225.59,367.195 229.806,362.979 v1(230.81,362.979)
  L16 w0.12: J1_PCIE2.45@230.69,358.792 230.69,362.859 v1(230.81,362.979)
HiSpeedModule_SPI2.MISO: J1_PCIE2.49 U26_SPI_bridge_PCIe.13 | length 17.9
  L1 w0.12: U26_SPI_bridge_PCIe.13@224.94,372.107 224.94,371.132 224.94,371.057 ccw(c225.052,371.057) 225.052,370.945 225.228,370.945 cw(c225.228,370.833) 225.34,370.833 225.34,370.683 cw(c225.228,370.683) 225.228,370.571 224.94,370.571 224.863,370.571 ccw(c224.863,370.459) 224.751,370.459 224.751,370.309 ccw(c224.863,370.309) 224.863,370.197 224.94,370.197 225.228,370.197 cw(c225.228,370.084) 225.34,370.084 225.34,369.935 cw(c225.228,369.935) 225.228,369.822 224.94,369.822 224.863,369.822 ccw(c224.863,369.71) 224.751,369.71 224.751,369.56 ccw(c224.863,369.56) 224.863,369.448 224.94,369.448 225.228,369.448 cw(c225.228,369.336) 225.34,369.336 225.34,369.186 cw(c225.228,369.186) 225.228,369.074 225.052,369.074 ccw(c225.052,368.962) 224.94,368.962 224.94,368.668 224.94,367.304 229.09,363.154 v1(229.09,363.004)
  L16 w0.12: J1_PCIE2.49@229.09,358.792 229.09,363.154 v1(229.09,363.004)
HiSpeedModule_SPI2.MOSI: J1_PCIE2.47 U26_SPI_bridge_PCIe.12 | length 17.1
  L1 w0.12: U26_SPI_bridge_PCIe.12@224.29,372.107 224.29,371.327 224.501,371.116 224.501,367.312 224.84,366.974 v1(224.84,365.89)
  L16 w0.12: v1(224.84,365.89) 226.951,363.779 229.409,363.779 229.89,363.298 J1_PCIE2.47@229.89,358.792
HiSpeedModule_SPI3.C\S\: J1_PCIE3.51 R238_SPI_bridge_PCIe.1 SP27_SPI_bridge_PCIe.1 U27_SPI_bridge_PCIe.11 | length 25.7
  L1 w0.12: U27_SPI_bridge_PCIe.11@58.613,371.89 58.613,369.863 58.994,369.863 59.073,369.783 59.073,368.547 59.064,368.537 59.064,356.932 61.506,354.49 v1(63.551,354.49)
  L16 w0.12: v1(63.551,354.49) 63.551,354.535 62.951,355.135 62.951,356.614 63.585,357.248 J1_PCIE3.51@63.585,358.792
HiSpeedModule_SPI3.CLK: J1_PCIE3.45 U27_SPI_bridge_PCIe.14 | length 25.7
  L1 w0.12: U27_SPI_bridge_PCIe.14@60.563,371.89 60.563,369.274 61.43,368.408 61.43,368.221 61.43,367.959 cw(c61.318,367.959) 61.318,367.847 ccw(c61.318,367.734) 61.205,367.734 61.205,367.585 ccw(c61.318,367.585) 61.318,367.472 61.43,367.472 62.73,367.472 cw(c62.73,367.36) 62.842,367.36 62.842,367.21 cw(c62.73,367.21) 62.73,367.098 61.43,367.098 ccw(c61.43,366.986) 61.318,366.986 61.318,366.836 ccw(c61.43,366.836) 61.43,366.724 62.73,366.724 cw(c62.73,366.612) 62.842,366.612 62.842,366.462 cw(c62.73,366.462) 62.73,366.35 61.542,366.35 ccw(c61.542,366.238) 61.43,366.238 61.43,365.544 61.43,360.319 64.892,356.857 v1(65.977,356.857)
  L16 w0.12: v1(65.977,356.857) 65.977,358.784 J1_PCIE3.45@65.985,358.792
HiSpeedModule_SPI3.MISO: J1_PCIE3.49 U27_SPI_bridge_PCIe.13 | length 25.7
  L1 w0.12: U27_SPI_bridge_PCIe.13@59.913,371.89 59.913,369.613 60.486,369.041 60.486,368.791 60.486,368.716 ccw(c60.598,368.716) 60.598,368.604 60.838,368.604 cw(c60.838,368.491) 60.95,368.491 60.95,368.342 cw(c60.838,368.342) 60.838,368.229 60.486,368.229 60.29,368.229 ccw(c60.29,368.117) 60.177,368.117 60.177,367.967 ccw(c60.29,367.967) 60.29,367.855 60.486,367.855 60.834,367.855 cw(c60.834,367.743) 60.947,367.743 60.947,367.593 cw(c60.834,367.593) 60.834,367.481 60.486,367.481 60.29,367.481 ccw(c60.29,367.369) 60.177,367.369 60.177,367.219 ccw(c60.29,367.219) 60.29,367.107 60.486,367.107 60.947,367.107 cw(c60.947,366.994) 61.059,366.994 61.059,366.845 cw(c60.947,366.845) 60.947,366.733 60.486,366.733 60.29,366.733 ccw(c60.29,366.62) 60.177,366.62 60.177,366.471 ccw(c60.29,366.471) 60.29,366.358 60.486,366.358 61.059,366.358 cw(c61.059,366.246) 61.171,366.246 61.171,366.096 cw(c61.059,366.096) 61.059,365.984 60.486,365.984 60.29,365.984 ccw(c60.29,365.872) 60.177,365.872 60.177,365.722 ccw(c60.29,365.722) 60.29,365.61 60.373,365.61 cw(c60.373,365.498) 60.486,365.498 60.486,365.011 60.486,359.524 v1(63.602,356.408)
  L16 w0.12: v1(63.602,356.408) 64.385,357.191 J1_PCIE3.49@64.385,358.792
HiSpeedModule_SPI3.MOSI: J1_PCIE3.47 U27_SPI_bridge_PCIe.12 | length 25.7
  L1 w0.12: U27_SPI_bridge_PCIe.12@59.263,371.89 59.263,369.952 59.919,369.297 59.919,365.277 59.919,365.203 ccw(c60.031,365.203) 60.031,365.09 60.041,365.09 cw(c60.041,364.978) 60.154,364.978 60.154,364.828 cw(c60.041,364.828) 60.041,364.716 59.919,364.716 59.508,364.716 ccw(c59.508,364.604) 59.396,364.604 59.396,364.454 ccw(c59.508,364.454) 59.508,364.342 59.919,364.342 60.041,364.342 cw(c60.041,364.23) 60.154,364.23 60.154,364.08 cw(c60.041,364.08) 60.041,363.968 59.919,363.968 59.508,363.968 ccw(c59.508,363.855) 59.396,363.855 59.396,363.706 ccw(c59.508,363.706) 59.508,363.593 59.919,363.593 60.041,363.593 cw(c60.041,363.481) 60.154,363.481 60.154,363.332 cw(c60.041,363.332) 60.041,363.219 60.031,363.219 ccw(c60.031,363.107) 59.919,363.107 59.919,362.915 59.919,358.285 62.796,355.408 v1(63.585,355.408)
  L16 w0.12: v1(63.585,355.408) 63.585,355.448 65.14,357.003 65.14,358.747 J1_PCIE3.47@65.185,358.792
HiSpeedModule_SPI4.C\S\: J1_PCIE4.51 R240_SPI_bridge_PCIe.1 SP29_SPI_bridge_PCIe.1 U28_SPI_bridge_PCIe.11 | length 18.7
  L1 w0.12: v1(172.707,261.899) 173.546,261.061 SP29_SPI_bridge_PCIe.1@174.072,261.061 174.206,260.927 174.206,258.509 174.096,258.399 173.746,258.399 173.798,258.347 U28_SPI_bridge_PCIe.11@173.798,256.078
  L16 w0.12: J1_PCIE4.51@169.137,271.994 169.137,271.294 171.729,268.702 171.729,265.467 172.707,264.489 v1(172.707,261.899)
HiSpeedModule_SPI4.CLK: J1_PCIE4.45 U28_SPI_bridge_PCIe.14 | length 18.2
  L1 w0.12: v1(166.581,267.794) 167.967,266.408 167.967,261.556 171.848,257.675 U28_SPI_bridge_PCIe.14@171.848,256.078
  L16 w0.12: v1(166.581,267.794) 166.581,271.837 J1_PCIE4.45@166.737,271.994
HiSpeedModule_SPI4.MISO: J1_PCIE4.49 U28_SPI_bridge_PCIe.13 | length 18.2
  L1 w0.12: U28_SPI_bridge_PCIe.13@172.498,256.078 172.587,256.168 v1(172.587,257.645)
  L16 w0.12: J1_PCIE4.49@168.337,271.994 168.337,271 168.662,270.675 169.445,270.675 171.357,268.762 171.357,258.875 v1(172.587,257.645)
HiSpeedModule_SPI4.MOSI: J1_PCIE4.47 U28_SPI_bridge_PCIe.12 | length 18.4
  L1 w0.12: v1(167.31,267.794) 168.337,266.767 168.337,263.133 173.148,258.322 U28_SPI_bridge_PCIe.12@173.148,256.078
  L16 w0.12: v1(167.31,267.794) 167.31,268.489 167.537,268.716 J1_PCIE4.47@167.537,271.994
HW_Conf_05028: R127.1 R139.2 U16.64 | length 6.6
  L1 w0.254: R139.2@145.733,220.955 145.742,220.945 147.231,220.945 147.241,220.935 147.241,221.321 150.108,224.188 150.758,224.188 U16.64@150.765,224.195
I2C0_PS.SCL: J12.1 R85.1 R774.1 SP34_Trans_PS_I2C0.1 U36_Trans_PS_I2C0.3 | length 11.2
  L1 w0.12: SP34_Trans_PS_I2C0.1@61.445,335.639 61.811,335.273 R85.1@61.811,334.259
  L1 w0.2: J12.1@56.439,334.2 61.753,334.2 R85.1@61.805,334.253 ; R85.1@61.811,334.259 R85.1@61.805,334.253 ; U36_Trans_PS_I2C0.3@64.727,332.87 63.273,332.87 63.138,332.735 62.273,332.735 62.055,332.952 62.055,333.035 61.855,333.235 61.805,333.235 R85.1@61.805,334.253
I2C0_PS.SDA: J12.2 R86.1 R775.1 SP35_Trans_PS_I2C0.1 U36_Trans_PS_I2C0.4 | length 11.9
  L1 w0.12: SP35_Trans_PS_I2C0.1@61.292,329.375 61.292,329.49 61.825,330.023 61.825,330.74 R86.1@61.717,330.848
  L1 w0.2: J12.2@56.439,331.661 58.814,331.661 59.627,330.848 61.717,330.848 61.729,330.86 61.729,331.864 61.729,332.232 61.932,332.435 63.263,332.435 63.347,332.52 U36_Trans_PS_I2C0.4@64.727,332.52
I2C0_Rail.SCL: U3_I2C_Bridge_SFP.19 U36_Trans_LS_I2C0.6 U36_Trans_PS_I2C0.6 | length 44.5
  L1 w0.2: U36_Trans_PS_I2C0.6@65.397,332.87 65.775,332.87 65.981,332.664 66.345,332.664 v1(66.345,332.676) ; v1(79.173,311.772) 83.248,307.697 83.248,305.765 84.418,304.596 U3_I2C_Bridge_SFP.19@85.6,304.596
  L5 (Sign) w0.2: v1(66.345,332.676) 65.017,331.348 65.017,322.639 66.892,320.764 74.079,320.764 79.444,315.399 79.444,312.044 v1(79.173,311.772)
  L16 w0.2: v1(66.345,332.676) 66.769,332.676 66.952,332.86 U36_Trans_LS_I2C0.6@67.43,332.86
I2C0_Rail.SDA: U3_I2C_Bridge_SFP.20 U36_Trans_LS_I2C0.5 U36_Trans_PS_I2C0.5 | length 45
  L1 w0.2: U36_Trans_PS_I2C0.5@65.397,332.52 65.676,332.52 66.18,332.016 v1(66.561,332.016) ; v1(79.244,310.794) 79.703,310.794 82.748,307.749 82.748,305.558 84.211,304.096 U3_I2C_Bridge_SFP.20@85.6,304.096
  L5 (Sign) w0.2: v1(66.561,332.016) 65.317,330.772 65.317,322.77 67.018,321.069 74.205,321.069 79.761,315.513 79.761,311.643 79.244,311.126 v1(79.244,310.794)
  L16 w0.2: v1(66.561,332.016) 67.055,332.51 U36_Trans_LS_I2C0.5@67.43,332.51
I2C1_PS.SCL: J13.1 R83.1 R772.1 SP34_Trans_PS_I2C1.1 U36_Trans_PS_I2C1.3 | length 11.4
  L1 w0.2: J13.1@56.446,326.428 56.459,326.416 60.302,326.416 SP34_Trans_PS_I2C1.1@61.401,327.515 62.959,327.515 62.916,327.472 62.916,326.479 62.916,325.534 63.263,325.186 U36_Trans_PS_I2C1.3@65.197,325.186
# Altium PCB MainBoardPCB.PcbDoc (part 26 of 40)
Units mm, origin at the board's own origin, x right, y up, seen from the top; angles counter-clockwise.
Board outline 258.95 x 308.86 mm, 16 copper layers (L1, L2 (GND), L3 (Sign), L4 (GND), L5 (Sign), L6 (PWR/GND), L7(12V+Other), L8 (Plane_GND), L9 (PWR/GND), L10 (3V3+Other), L11 (PWR/GND), L12 (Sign), L13 (GND), L14 (Sign), L15 (GND), L16), stack 2.503 mm thick; 2578 components, 1867 nets, 8817 pads, 8021 vias.
Unrouted connection lines stored in the file: 25.

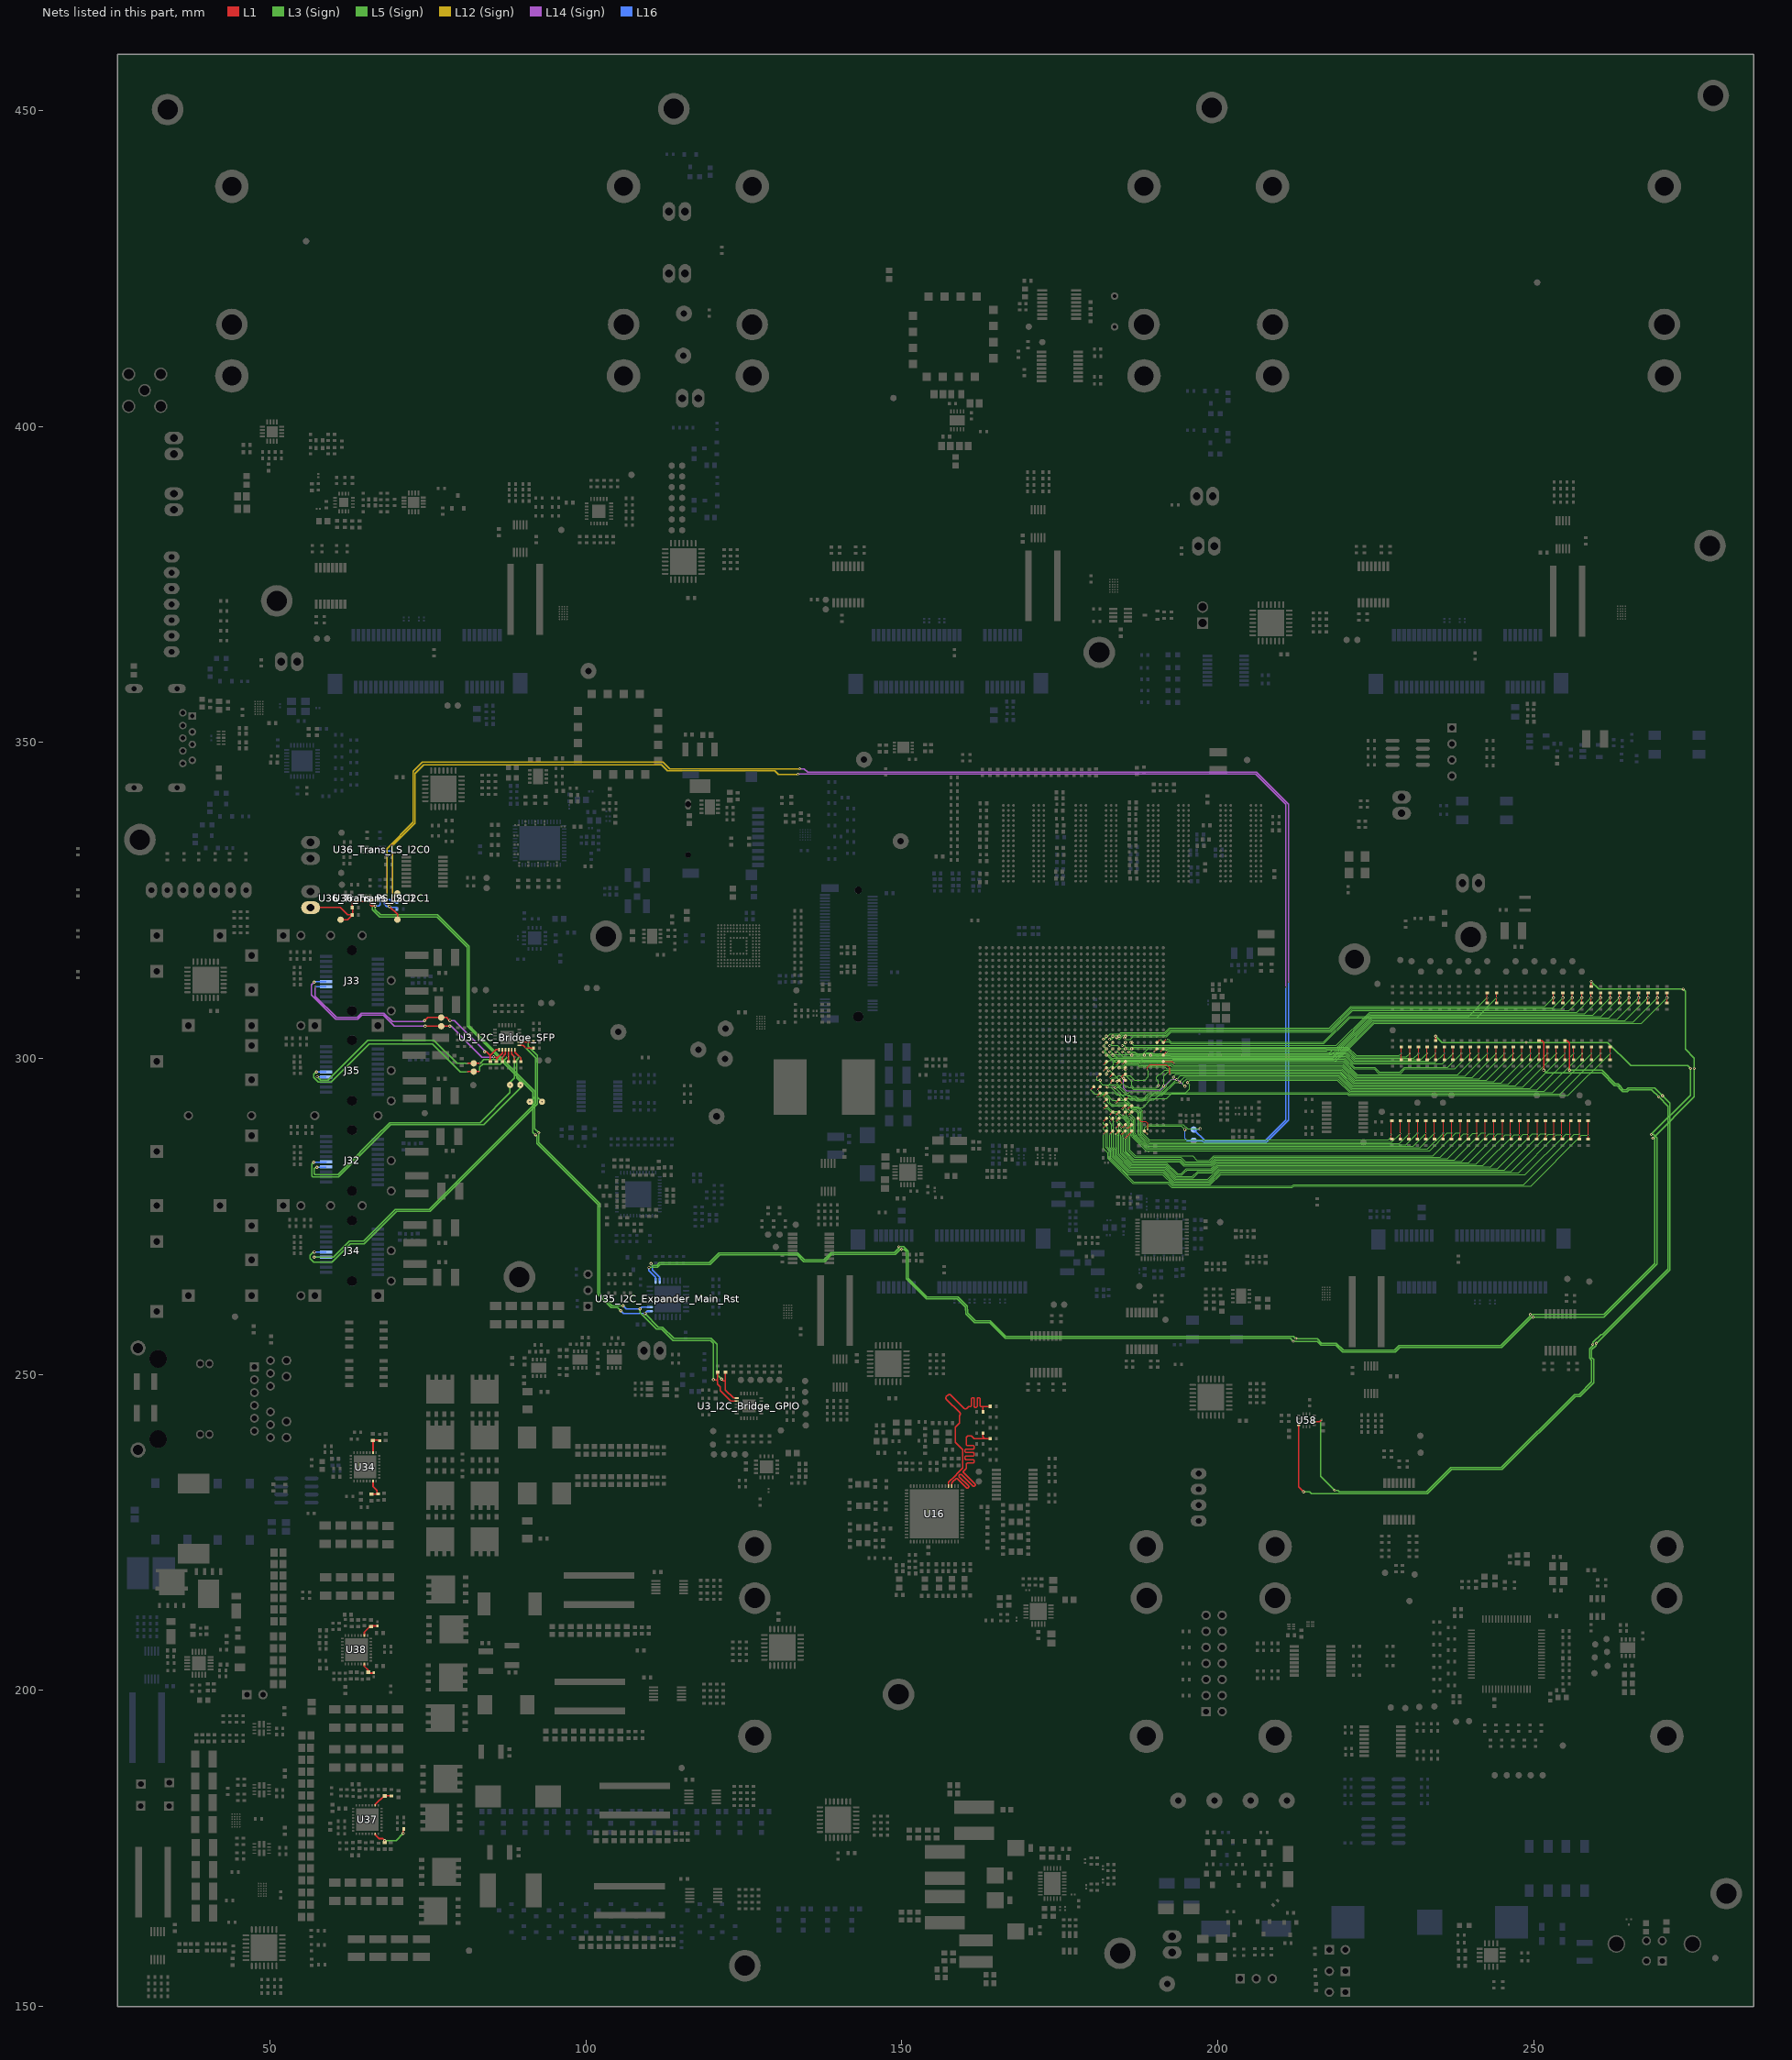
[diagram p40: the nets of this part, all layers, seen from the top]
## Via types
v1: diameter 0.5, hole 0.25, L1 to L16, tented both sides, 4341 vias
v2: diameter 0.254, hole 0.1, L1 to L3 (Sign), tented both sides, 781 vias
v3: diameter 0.5, hole 0.25, L1 to L16, 565 vias
v4: diameter 0.254, hole 0.1, L15 (GND) to L16, tented both sides, 406 vias
v5: diameter 0.254, hole 0.1, L1 to L2 (GND), tented both sides, 283 vias
v6: diameter 0.457, hole 0.2, L3 (Sign) to L6 (PWR/GND), tented both sides, 254 vias
v7: diameter 0.254, hole 0.1, L1 to L3 (Sign), 237 vias
v8: diameter 0.75, hole 0.4, L1 to L16, 200 vias
v9: diameter 0.8, hole 0.4, L1 to L16, tented both sides, 182 vias
v10: diameter 0.254, hole 0.1, L14 (Sign) to L16, tented both sides, 170 vias
v11: diameter 0.75/0/0/0/0/0/0/0/0/0/0/0/0/0/0/0.75 (per signal layer), hole 0.4, L1 to L16, 160 vias
v12: diameter 0.457, hole 0.2, L3 (Sign) to L6 (PWR/GND), 158 vias
v13: diameter 1.4, hole 0.5, L1 to L16, tented both sides, 80 vias
v14: diameter 0.254, hole 0.1, L14 (Sign) to L16, 65 vias
v15: diameter 0.254, hole 0.1, L1 to L2 (GND), 45 vias
v16: diameter 0.457, hole 0.2, L11 (PWR/GND) to L14 (Sign), tented both sides, 26 vias
v17: diameter 0.457, hole 0.2, L11 (PWR/GND) to L14 (Sign), 25 vias
v18: diameter 0.457, hole 0.2, L7(12V+Other) to L10 (3V3+Other), tented both sides, 11 vias
v19: diameter 0.254/0/0.254 (per signal layer), hole 0.1, L1 to L3 (Sign), 9 vias
v20: diameter 0.2/0/0.2 (per signal layer), hole 0.1, L1 to L3 (Sign), 6 vias
v21: diameter 1.65, hole 1.65, L1 to L16, 5 vias
v22: diameter 1.15, hole 1.15, L1 to L16, 5 vias
v23: diameter 0.457, hole 0.2, L1 to L16, 3 vias
v24: diameter 0.5, hole 0.3, L1 to L16, 2 vias
v25: diameter 0.5/0/0.5 (per signal layer), hole 0.2, L14 (Sign) to L16, 1 vias
v26: diameter 0.5, hole 0.25, L1 to L16, tented bottom, 1 vias

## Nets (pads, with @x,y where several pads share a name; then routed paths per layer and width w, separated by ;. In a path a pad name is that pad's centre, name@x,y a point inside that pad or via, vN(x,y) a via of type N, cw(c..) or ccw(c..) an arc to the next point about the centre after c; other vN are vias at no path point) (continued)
I2C1_PS.SDA: J13.2 R84.1 R773.1 SP35_Trans_PS_I2C1.1 U36_Trans_PS_I2C1.4 | length 13.4
  L1 w0.2: J13.2@56.446,323.888 61.177,323.888 62.34,322.724 R84.1@62.95,322.724 ; SP35_Trans_PS_I2C1.1@61.19,321.971 62.273,321.971 62.95,322.649 R84.1@62.95,322.724 ; U36_Trans_PS_I2C1.4@65.197,324.836 63.266,324.836 63.066,324.636 63.066,323.878 63.081,323.863 63.081,322.73 63.075,322.724 R84.1@62.95,322.724
I2C1_Rail.SCL: R599.1 U3_I2C_Bridge_GPIO.19 U35_I2C_Expander_Main_Rst.8 U36_Trans_LS_I2C1.6 U36_Trans_PS_I2C1.6 | length 119
  L1 w0.2: U36_Trans_PS_I2C1.6@65.867,325.186 66.165,325.186 66.332,325.019 v1(66.674,325.019) ; v1(121.488,249.288) 121.78,248.996 122.097,248.996 ; R599.1@122.097,250.419 122.097,248.996 ; U3_I2C_Bridge_GPIO.19@123.878,246.289 123.382,246.289 122.097,247.575 122.097,248.996
  L5 (Sign) w0.2: v1(66.674,325.019) 66.227,324.572 66.227,323.575 67.374,322.429 76.415,322.429 81.207,317.636 81.207,305.103 91.63,294.679 91.63,288.332 v6(92.032,287.93) ; v1(109.348,259.678) 111.512,257.513 112.108,257.513 113.915,255.706 119.855,255.706 120.749,254.812 120.749,250.028 v1(121.488,249.288)
  L3 (Sign) w0.2: v6(92.032,287.93) 92.27,287.692 92.27,286.566 101.897,276.939 101.897,262.695 104.008,260.583 105.037,260.583 v1(105.537,260.083)
  L16 w0.2: v1(66.674,325.019) 66.904,325.019 67.071,325.186 U36_Trans_LS_I2C1.6@67.43,325.186 ; v1(105.537,260.083) 105.943,259.678 v1(109.348,259.678) 109.348,259.69 109.676,260.018 U35_I2C_Expander_Main_Rst.8@110.123,260.018
I2C1_Rail.SDA: R428.1 U3_I2C_Bridge_GPIO.20 U35_I2C_Expander_Main_Rst.9 U36_Trans_LS_I2C1.5 U36_Trans_PS_I2C1.5 | length 120.3
  L1 w0.2: U36_Trans_PS_I2C1.5@65.867,324.836 65.867,324.332 66.057,324.142 v1(66.677,324.142) ; v1(120.192,249.187) 120.215,249.164 120.717,249.164 120.86,249.022 ; R428.1@120.86,250.419 120.86,249.022 ; U3_I2C_Bridge_GPIO.20@123.878,245.789 122.93,245.789 121.285,247.434 121.285,248.044 120.86,248.469 120.86,249.022
  L5 (Sign) w0.2: v1(66.677,324.142) 66.677,323.549 67.498,322.729 76.539,322.729 81.507,317.76 81.507,305.227 91.93,294.804 91.93,288.88 92.534,288.277 92.516,288.259 92.523,288.252 v6(92.57,288.252) ; v1(108.598,260.363) 108.598,259.791 111.176,257.213 111.983,257.213 113.802,255.395 119.742,255.395 120.167,254.969 120.167,249.212 v1(120.192,249.187)
  L3 (Sign) w0.2: v6@92.57,288.256 v6(92.57,288.252) 92.57,286.69 102.197,277.063 102.197,262.819 104.132,260.883 v1(105.905,260.883)
  L16 w0.2: v1(66.677,324.142) 67.234,324.142 67.43,324.338 U36_Trans_LS_I2C1.5@67.43,324.836 ; v1(105.905,260.883) 106.426,260.363 v1(108.598,260.363) 108.903,260.668 U35_I2C_Expander_Main_Rst.9@110.123,260.668
I2C_05028_SCL: R130.1 R132.2 U16.36 | length 31.1
  L1 w0.2: U16.36@157.415,232.345 157.415,232.967 158.454,234.007 158.84,234.393 159.656,235.208 159.656,238.095 158.485,239.265 158.485,241.693 159.118,242.325 159.118,243.484 159.189,243.555 ccw(c158.985,243.759) 159.189,243.963 157.063,246.089 cw(c157.267,246.293) 157.063,246.497 157.335,246.769 cw(c157.539,246.565) 157.743,246.769 159.869,244.643 ccw(c160.074,244.847) 160.278,244.643 160.585,244.951 160.795,244.951 160.886,244.951 ccw(c160.886,245.087) 161.022,245.087 161.022,246.164 cw(c161.158,246.164) 161.158,246.3 161.34,246.3 cw(c161.34,246.164) 161.476,246.164 161.476,244.951 ccw(c161.612,244.951) 161.612,244.815 161.794,244.815 ccw(c161.794,244.951) 161.93,244.951 161.93,246.164 cw(c162.066,246.164) 162.066,246.3 162.248,246.3 cw(c162.248,246.164) 162.384,246.164 162.384,245.087 ccw(c162.521,245.087) 162.521,244.951 162.547,244.951 162.827,244.951 ; R130.1@162.832,244.11 162.832,244.945 162.827,244.951 ; R132.2@164.051,244.951 162.827,244.951
I2C_05028_SDA: R131.1 R134.2 U16.35 | length 31.1
  L1 w0.2: U16.35@157.915,232.345 157.915,232.854 158.157,233.095 158.549,233.487 cw(c158.69,233.346) 158.831,233.487 160.276,232.042 ccw(c160.373,232.139) 160.469,232.042 160.598,232.171 ccw(c160.501,232.267) 160.598,232.363 159.093,233.868 cw(c159.19,233.964) 159.093,234.06 159.222,234.189 cw(c159.318,234.093) 159.414,234.189 161.286,232.318 ccw(c161.382,232.414) 161.479,232.318 161.607,232.446 ccw(c161.511,232.542) 161.607,232.639 159.795,234.451 cw(c159.936,234.592) 159.795,234.734 160.154,235.093 160.188,235.126 160.216,235.155 160.216,235.782 cw(c160.416,235.782) 160.416,235.982 161.295,235.982 ccw(c161.295,236.121) 161.434,236.121 161.434,236.399 ccw(c161.295,236.399) 161.295,236.538 160.173,236.538 cw(c160.173,236.676) 160.034,236.676 160.034,236.954 cw(c160.173,236.954) 160.173,237.093 161.295,237.093 ccw(c161.295,237.232) 161.434,237.232 161.434,237.51 ccw(c161.295,237.51) 161.295,237.649 160.173,237.649 cw(c160.173,237.788) 160.034,237.788 160.034,238.065 cw(c160.173,238.065) 160.173,238.204 161.295,238.204 ccw(c161.295,238.343) 161.434,238.343 161.434,238.621 ccw(c161.295,238.621) 161.295,238.76 160.416,238.76 cw(c160.416,238.96) 160.216,238.96 160.216,239.553 160.216,240.049 160.447,240.28 161.023,240.28 161.437,239.866 163.092,239.866 ; R131.1@162.832,240.725 162.832,240.126 163.092,239.866 ; R134.2@164.051,239.866 163.092,239.866
I2C_LS.SCL: R363.2 SP34_Trans_LS_I2C0.1 SP34_Trans_LS_I2C1.1 U1.AG1 U36_Trans_LS_I2C0.3 U36_Trans_LS_I2C1.3 | length 255.1
  L1 w0.12: U1.AG1@188.397,288.539 v7(188.884,288.052)
  L1 w0.2: v1(69.432,324.703) 69.432,325.38 SP34_Trans_LS_I2C0.1@70.18,326.128
  L12 (Sign) w0.2: v1@69.431,324.714 69.431,333.738 72.949,337.256 72.949,345.123 74.329,346.502 111.986,346.502 112.941,345.546 129.938,345.546 130.513,344.972 v16(133.572,344.972)
  L3 (Sign) w0.12: v7(188.884,288.052) 188.463,288.473 188.463,289.002 189.034,289.573 192.397,289.573 194.568,289.573 195.283,288.858 v3(197.244,288.858)
  L14 (Sign) w0.2: v10(69.417,332.614) 69.424,332.607 69.424,324.72 v1@69.431,324.714 ; v16(133.572,344.972) 133.626,345.026 158.259,345.026 185.298,345.026 206.022,345.026 210.784,340.264 v14(210.784,311.3)
  L16 w0.12: SP34_Trans_LS_I2C1.1@196.207,288.76 196.256,288.809 197.194,288.809 v3(197.244,288.858)
  L16 w0.2: U36_Trans_LS_I2C1.3@68.1,325.186 68.958,325.186 69.431,324.714 R363.2@70.18,324.714 ; U36_Trans_LS_I2C0.3@68.1,332.86 69.171,332.86 v10(69.417,332.614) ; SP34_Trans_LS_I2C1.1@196.207,288.76 197.991,286.976 207.506,286.976 210.784,290.255 v14(210.784,311.3)
I2C_LS.SDA: R364.2 SP35_Trans_LS_I2C0.1 SP35_Trans_LS_I2C1.1 U1.AF3 U36_Trans_LS_I2C0.4 U36_Trans_LS_I2C1.4 | length 258.6
  L1 w0.12: U1.AF3@187.397,290.539 187.883,290.053 188.596,290.053 188.916,289.733 v7(188.916,288.76)
  L1 w0.2: v1(68.93,324.092) 70.18,322.842 SP35_Trans_LS_I2C0.1@70.18,321.971
  L12 (Sign) w0.2: v1(68.93,324.092) 68.508,324.514 68.508,333.24 72.649,337.38 72.649,345.45 74.145,346.946 112.219,346.946 113.32,345.846 v16(133.842,345.846)
  L3 (Sign) w0.12: v7(188.916,288.76) 188.916,289.143 189.126,289.353 192.397,289.353 194.208,289.353 v3(194.799,288.762)
  L14 (Sign) w0.2: v10(68.604,332.021) 68.547,331.964 68.547,331.792 68.508,331.754 68.508,324.514 v1(68.93,324.092) ; v16(133.842,345.846) 134.576,345.846 135.097,345.326 206.146,345.326 207.62,343.852 207.682,343.79 211.234,340.238 v14(211.234,312.093)
  L16 w0.12: v3(194.799,288.762) 194.799,287.355 195.147,287.007 SP35_Trans_LS_I2C1.1@196.207,287.007
  L16 w0.2: U36_Trans_LS_I2C1.4@68.1,324.836 68.1,324.483 68.49,324.092 v1(68.93,324.092) 69.011,324.092 69.219,323.885 69.98,323.885 R364.2@70.18,323.685 ; U36_Trans_LS_I2C0.4@68.1,332.51 68.265,332.51 68.547,332.228 68.547,332.078 v10(68.604,332.021) ; SP35_Trans_LS_I2C1.1@196.207,287.007 197.535,287.007 197.866,286.676 207.63,286.676 211.234,290.28 v14(211.234,312.093)
I2C_SCL_SFP0: J32.5 R225_I2C_Bridge_SFP.2 SP7_I2C_Bridge_SFP.1 U3_I2C_Bridge_SFP.6 | length 50.9
  L1 w0.2: U3_I2C_Bridge_SFP.6@88.785,301.411 88.785,300.978 v2(89.51,300.253) 89.707,300.056 R225_I2C_Bridge_SFP.2@89.707,299.448
  L3 (Sign) w0.2: v1(56.947,283.604) 56.629,283.286 56.629,281.401 56.784,281.247 60.821,281.247 69.113,289.539 83.844,289.539 89.643,295.338 89.643,296.327 89.042,296.928 89.042,299.786 v2(89.51,300.253)
  L16 w0.2: v1(56.947,283.604) 58.861,283.604 J32.5@58.904,283.647
  other v7: 89.643,295.821
I2C_SCL_SFP1: J33.5 R559_I2C_Bridge_SFP.2 SP3_I2C_Bridge_SFP.1 U3_I2C_Bridge_SFP.2 | length 40.7
  L1 w0.2: v1(74.549,305.113) SP3_I2C_Bridge_SFP.1@77.13,305.113 77.144,305.127 v1(78.484,305.127) ; v1(85.405,300.269) 85.458,300.215 86.123,300.215 ; R559_I2C_Bridge_SFP.2@85.846,299.448 85.846,299.938 86.123,300.215 ; U3_I2C_Bridge_SFP.2@86.785,301.411 86.785,300.877 86.123,300.215
  L14 (Sign) w0.2: v1(57.023,312.115) 56.578,311.671 56.578,310.045 60.414,306.21 63.923,306.21 64.584,306.87 67.945,306.87 69.634,305.181 69.702,305.113 v1(74.549,305.113) ; v1(78.484,305.127) 78.68,305.127 83.591,300.215 85.351,300.215 v1(85.405,300.269)
  L16 w0.2: v1(57.023,312.115) 57.054,312.147 J33.5@58.904,312.147
I2C_SCL_SFP2: J34.5 R223_I2C_Bridge_SFP.2 SP9_I2C_Bridge_SFP.1 U3_I2C_Bridge_SFP.8 | length 63.6
  L1 w0.2: U3_I2C_Bridge_SFP.8@89.47,302.596 89.488,302.577 90.564,302.577 v2(90.868,302.577) 91.677,302.577 R223_I2C_Bridge_SFP.2@91.738,302.638
  L3 (Sign) w0.2: v1(57.036,269.405) 56.871,269.405 56.363,268.897 56.363,268.352 56.938,267.776 59.864,267.776 62.751,270.662 64.899,270.662 70.072,275.835 75.353,275.835 92.319,292.802 92.319,293.913 ; v2(90.868,302.577) 90.868,301.93 92.319,300.479 92.319,293.913 ; v7(93.064,293.168) 92.319,293.913
  L16 w0.2: v1(57.036,269.405) 57.044,269.397 J34.5@58.904,269.397
I2C_SCL_SFP3: J35.5 R227_I2C_Bridge_SFP.2 SP5_I2C_Bridge_SFP.1 U3_I2C_Bridge_SFP.4 | length 41.5
  L1 w0.2: v7(81.207,297.897) 81.228,297.918 82.237,297.918 SP5_I2C_Bridge_SFP.1@82.258,297.938 82.259,297.938 v7(83.209,297.937) v7(83.209,297.937) ; v2(87.592,300.279) 87.747,300.279 87.785,300.241 ; R227_I2C_Bridge_SFP.2@87.777,299.448 87.785,299.456 87.785,300.241 ; U3_I2C_Bridge_SFP.4@87.785,301.411 87.785,300.241
  L3 (Sign) w0.2: v1(57.359,297.897) 56.947,297.485 56.947,296.989 57.658,296.278 59.707,296.278 65.743,302.315 75.725,302.315 80.144,297.897 v7(81.207,297.897) ; v7(83.209,297.937) 83.209,298.671 83.676,299.138 86.451,299.138 v2(87.592,300.279)
  L16 w0.2: v1(57.359,297.897) J35.5@58.904,297.897
I2C_SDA_SFP0: J32.4 R226_I2C_Bridge_SFP.2 SP6_I2C_Bridge_SFP.1 U3_I2C_Bridge_SFP.5 | length 47.3
  L1 w0.2: U3_I2C_Bridge_SFP.5@88.285,301.411 88.285,300.697 v2(88.742,300.241) R226_I2C_Bridge_SFP.2@88.742,299.448
  L3 (Sign) w0.2: v1(57.455,282.804) 57.366,282.892 57.033,282.56 57.033,281.764 57.15,281.647 60.756,281.647 67.763,288.653 67.803,288.653 68.989,289.839 83.237,289.839 88.012,294.614 v7(88.012,295.821) 88.012,296.198 88.742,296.928 v2(88.742,300.241)
  L16 w0.2: v1(57.455,282.804) 58.861,282.804 J32.4@58.904,282.847
I2C_SDA_SFP1: J33.4 R560_I2C_Bridge_SFP.2 SP2_I2C_Bridge_PCIE.1@77.123,306.49 U3_I2C_Bridge_SFP.1 | length 38.8
  L1 w0.2: v1(74.474,305.984) 74.98,306.49 77.943,306.49 78.344,306.089 78.454,306.089 v1(78.511,306.032) ; v1(83.972,301.066) 84.277,301.066 84.88,300.463 ; R560_I2C_Bridge_SFP.2@84.88,299.448 84.88,300.463 ; U3_I2C_Bridge_SFP.1@86.285,301.411 85.828,301.411 84.88,300.463
  L14 (Sign) w0.2: v10(57.182,311.347) 57.182,309.866 60.538,306.51 63.799,306.51 64.459,307.17 68.069,307.17 69.38,305.86 74.268,305.86 74.393,305.984 v1(74.474,305.984) ; v1(78.511,306.032) 79.175,306.032 83.972,301.234 83.972,301.071 v1(83.972,301.066)
  L16 w0.2: v10(57.182,311.347) J33.4@58.904,311.347
I2C_SDA_SFP2: J34.4 R224_I2C_Bridge_SFP.2 SP8_I2C_Bridge_SFP.1 U3_I2C_Bridge_SFP.7 | length 60
  L1 w0.2: U3_I2C_Bridge_SFP.7@89.47,302.096 90.086,302.096 v2(90.517,301.665) R224_I2C_Bridge_SFP.2@91.738,301.665
  L3 (Sign) w0.2: v1(56.998,268.592) 60.068,268.592 62.571,271.096 64.814,271.096 69.853,276.135 75.22,276.135 92.019,292.935 92.019,294.038 ; v2(90.517,301.665) 92.019,300.162 92.019,294.038 ; v7(91.149,293.168) 92.019,294.038
  L16 w0.2: v1(56.998,268.592) 57.002,268.597 J34.4@58.904,268.597
I2C_SDA_SFP3: J35.4 R558_I2C_Bridge_SFP.2 SP4_I2C_Bridge_SFP.1 U3_I2C_Bridge_SFP.3 | length 37.8
  L1 w0.2: v7(81.207,299.239) SP4_I2C_Bridge_SFP.1@82.258,299.239 82.285,299.267 83.204,299.267 v7(83.232,299.295) ; R558_I2C_Bridge_SFP.2@86.811,299.448 v2(86.811,300.232) 87.285,300.706 U3_I2C_Bridge_SFP.3@87.285,301.411
  L3 (Sign) w0.2: v1(57.493,297.116) 58.001,296.608 59.22,296.608 65.508,302.897 75.967,302.897 79.624,299.239 v7(81.207,299.239) ; v7(83.232,299.295) 83.342,299.295 83.866,299.819 86.611,299.819 86.782,299.991 86.782,300.203 v2(86.811,300.232)
  L16 w0.2: v1(57.493,297.116) 58.851,297.116 58.888,297.08 J35.4@58.904,297.097
ILIM1: C345.2 R610.1 U34.26 | length 3.2
  L1 w0.254: U34.26@66.321,237.64 66.321,239.689 66.38,239.63 67.318,239.63 R610.1@67.378,239.57
ILIM1_1: C389.2 R619.1 U37.26 | length 3.3
  L1 w0.2: C389.2@68.211,183.433 68.274,183.369 R619.1@69.228,183.369
  L1 w0.254: U37.26@66.675,181.817 66.675,181.963 67.408,182.696 67.474,182.696 C389.2@68.211,183.433
ILIM1_2: C430.2 R625.2 U38.26 | length 3
  L1 w0.254: U38.26@64.953,208.714 64.953,209.219 65.973,210.239 66.991,210.239 R625.2@67.001,210.229
ILIM2: C349.2 R611.1 U34.15 | length 3.5
  L1 w0.254: C349.2@66.055,231.087 66.075,231.067 R611.1@67.093,231.067 ; U34.15@66.322,233.139 66.322,232.29 66.315,232.283 66.94,231.658 66.94,231.22 R611.1@67.093,231.067 ; R611.1@67.113,231.047 R611.1@67.093,231.067
ILIM2_1: C393.2 R620.1 U37.15 | length 6.6
  L1 w0.2: v1@68.023,176.422 v1(68.185,176.26) C393.2@68.185,175.817 ; v1(71.111,177.397) 71.111,178.081 R620.1@71.13,178.1
  L1 w0.254: U37.15@66.675,177.317 66.675,177.171 67.262,176.584 67.861,176.584 v1@68.023,176.422
  L5 (Sign) w0.2: v1(68.185,176.26) 69.993,176.26 71.111,177.378 v1(71.111,177.397)
ILIM2_2: C434.2 R302.2 U38.15 | length 2.6
  L1 w0.254: U38.15@64.953,204.214 64.955,204.212 64.955,203.839 65.578,203.216 65.578,202.764 66.405,202.764 66.453,202.812 R302.2@66.453,202.813
IMU_INT1: R822.2 U58.4 | length 137.2
  L1 w0.2: U58.4@212.803,242.004 212.803,232.218 v1(213.589,231.432) ; R822.2@254.956,302.785 255.342,302.785 255.689,302.438 v1(255.689,298.158)
  L5 (Sign) w0.2: v1(213.589,231.432) 214.541,231.432 214.846,231.127 233.19,231.127 237.025,234.963 245.008,234.963 256.593,246.548 257.323,246.548 259.494,248.72 259.494,252.397 259.194,252.697 259.194,253.891 259.876,254.572 259.876,254.883 v6(259.933,254.941) ; v1(255.689,298.158) 260.806,298.158 262.941,296.023 263.37,296.023 263.809,295.584 263.809,295.459 264.19,295.079 264.707,295.079 264.976,295.348 269.177,295.348 v6(270.408,294.116)
  L3 (Sign) w0.2: v6(259.933,254.941) 259.983,254.941 271.597,266.555 271.597,292.928 v6(270.408,294.116)
IMU_INT2: R851.2 U58.9 | length 138.1
  L1 w0.2: U58.9@215.303,242.504 216.114,242.504 v2(216.459,242.849) ; R851.2@250.866,302.785 251.316,302.785 251.587,302.514 v1(251.587,298.145)
  L5 (Sign) w0.2: v6(218.529,231.673) 219.024,231.673 219.27,231.427 233.066,231.427 236.901,235.263 244.884,235.263 256.469,246.848 257.199,246.848 259.194,248.844 259.194,252.273 258.865,252.602 258.865,254.082 259.377,254.595 259.377,254.76 v6(259.354,254.784) ; v1(251.587,298.145) 252.031,297.701 260.839,297.701 262.817,295.723 263.246,295.723 263.509,295.459 263.509,295.335 264.065,294.779 264.831,294.779 265.1,295.048 268.687,295.048 v6(269.797,293.938)
  L3 (Sign) w0.2: v2(216.459,242.849) 216.459,242.842 216.274,242.657 216.274,233.928 v6(218.529,231.673) ; v6(259.354,254.784) 259.411,254.841 259.411,255.056 260.684,256.329 260.936,256.329 271.297,266.689 271.297,292.438 v6(269.797,293.938)
INTA_EXP_MAIN: R972.2 U35_I2C_Expander_Main_Rst.16 | length 243.1
  L1 w0.2: R972.2@259.122,311.363 v1(259.122,312.162)
  L5 (Sign) w0.2: v1(110.317,267.531) 110.542,267.306 111.238,267.306 111.663,267.731 119.56,267.731 121.074,269.245 133.554,269.245 134.625,268.174 137.681,268.174 138.809,269.301 148.829,269.301 149.546,270.018 v6(149.546,270.227) ; v6(212.4,255.682) 215.76,255.682 216.466,254.976 218.788,254.976 219.916,253.848 227.964,253.848 228.726,254.61 244.792,254.61 249.482,259.299 v6(249.482,259.508) ; v1(259.122,312.162) 260.299,310.985 v6(273.672,310.985) ; v6(268.872,287.388) 275.433,293.949 v6(275.433,298.437)
  L3 (Sign) w0.2: v6(149.546,270.227) 149.572,270.253 150.313,270.253 151.017,269.549 151.017,265.276 154.01,262.282 158.919,262.282 160.387,260.813 160.387,260.316 160.439,260.264 160.439,259.702 161.658,258.483 164.025,258.483 166.494,256.014 211.986,256.014 212.319,255.682 v6(212.4,255.682) ; v6(249.482,259.508) 249.508,259.534 261.148,259.534 269.197,267.583 269.197,287.286 269.095,287.388 v6(268.872,287.388) ; v6(273.672,310.985) 273.994,310.663 273.994,301.481 275.433,300.042 v6@275.433,298.474
  L16 w0.2: v1(110.317,267.531) 110.549,267.299 110.549,266.526 111.698,265.378 U35_I2C_Expander_Main_Rst.16@111.698,264.843
INTB_EXP_MAIN: R973.2 U35_I2C_Expander_Main_Rst.15 | length 257
  L1 w0.2: R973.2@234.506,302.785 v1(234.506,303.546)
  L5 (Sign) w0.2: v1(109.993,266.929) 110.071,267.006 111.363,267.006 111.78,267.424 119.684,267.424 121.201,268.94 133.434,268.94 134.501,267.874 136.487,267.874 137.812,267.874 138.935,268.997 148.955,268.997 149.762,269.803 v6(149.97,269.803) ; v6(211.976,255.257) 212.001,255.232 215.786,255.232 216.341,254.676 218.663,254.676 219.792,253.548 228.088,253.548 228.85,254.31 244.923,254.31 249.64,259.027 249.849,259.027 v6(249.907,259.084) ; v1(234.506,303.546) 235.5,302.552 v6(248.817,302.552) ; v6(268.62,287.985) 274.833,294.198 v6(274.833,298.437)
  L3 (Sign) w0.2: v6(149.97,269.803) 150.332,269.803 150.717,269.418 150.717,265.145 153.884,261.977 158.792,261.977 160.087,260.683 160.087,260.192 160.134,260.145 160.134,259.583 161.539,258.178 163.899,258.178 166.363,255.714 211.518,255.714 v6(211.976,255.257) ; v6(248.817,302.552) 261.722,302.552 265.366,298.907 274.363,298.907 v6(274.833,298.437) ; v6(249.907,259.084) 261.122,259.084 269.497,267.459 269.497,287.41 268.922,287.985 v6(268.62,287.985)
  L16 w0.2: v1(109.993,266.929) 109.993,266.458 111.048,265.404 U35_I2C_Expander_Main_Rst.15@111.048,264.843
Interrupt0: R515.2 R530.1 U1.AC12 | length 64.4
  L1 w0.12: v2(183.886,299.112) 183.922,299.112 184.35,299.539 U1.AC12@184.397,299.539 ; R515.2@242.686,299.747 v2(242.686,300.816) R530.1@242.686,301.885
  L3 (Sign) w0.12: v2(183.886,299.112) 183.908,299.089 184.269,299.089 184.772,299.592 187.694,299.592 187.914,299.372 192.397,299.372 192.907,299.372 193.012,299.477 219.813,299.477 222.036,297.254 239.125,297.254 v2(242.686,300.816)
Interrupt1: R522.2 R547.1 U1.AD12 | length 66.1
  L1 w0.12: v2(184.909,299.1) 184.933,299.1 185.373,299.539 U1.AD12@185.397,299.539 ; R522.2@245.413,299.747 v2(245.413,300.816) R547.1@245.413,301.885
  L3 (Sign) w0.12: v2(184.909,299.1) 185.182,299.372 187.602,299.372 187.832,299.143 192.397,299.143 192.772,299.143 193.012,298.903 219.765,298.903 221.853,296.814 241.412,296.814 v2(245.413,300.816)
Interrupt2: R531.2 R550.1 U1.AA12 | length 63.6
  L1 w0.12: v2(181.909,299.052) U1.AA12@182.397,299.539 ; R531.2@239.96,299.747 v2(239.96,300.816) R550.1@239.96,301.885
  L3 (Sign) w0.12: v2(181.909,299.052) 182.195,299.052 182.86,299.717 183.048,299.717 183.364,300.032 187.876,300.032 188.096,299.812 192.397,299.812 192.725,299.812 192.829,299.917 219.996,299.917 221.56,298.352 224.793,298.352 225.449,297.695 228.957,297.695 229.626,298.365 237.508,298.365 v2(239.96,300.816)
Interrupt3: R548.2 R553.1 U1.AA11 | length 65.6
  L1 w0.12: v2(181.909,298.052) U1.AA11@182.397,298.539 ; R548.2@241.323,299.747 v2(241.323,300.816) R553.1@241.323,301.885
  L3 (Sign) w0.12: v2(181.909,298.052) 182.382,298.525 182.962,298.525 183.476,299.039 183.476,299.379 183.91,299.812 187.785,299.812 188.005,299.592 192.397,299.592 192.816,299.592 192.92,299.697 219.904,299.697 222.127,297.474 237.981,297.474 v2(241.323,300.816)
Interrupt4: R551.2 R556.1 U1.AB11 | length 69.5
  L1 w0.12: v2(183.17,298.166) 183.195,298.192 183.195,298.235 183.397,298.437 U1.AB11@183.397,298.539 ; R551.2@246.776,299.747 v2(246.776,300.816) R556.1@246.776,301.885
  L3 (Sign) w0.12: v2(183.17,298.166) 183.183,298.152 183.311,298.152 184.013,298.855 184.749,298.855 184.791,298.813 185.076,298.813 185.415,299.152 187.428,299.152 187.657,298.923 192.574,298.923 192.814,298.683 219.674,298.683 221.762,296.594 242.555,296.594 v2(246.776,300.816)
Interrupt5: R554.2 R618.1 U1.AC11 | length 69
  L1 w0.12: R554.2@248.14,299.747 v2(248.14,300.816) R618.1@248.14,301.885
  L3 (Sign) w0.12: v7(184.397,298.52) 185.094,298.52 185.507,298.932 187.332,298.932 187.562,298.703 191.664,298.703 191.954,298.413 193.432,298.413 193.439,298.42 219.625,298.42 221.671,296.374 243.698,296.374 v2(248.14,300.816)
Interrupt6: R557.2 R688.1 U1.AD11 | length 74.5
  L1 w0.12: v2(185.064,298.17) 185.064,298.188 185.397,298.521 U1.AD11@185.397,298.539 ; R557.2@249.503,299.747 v2(249.503,300.816) R688.1@249.503,301.885
  L5 (Sign) w0.12: v12(185.447,298.293) 185.447,297.316 186.392,296.371 186.392,295.697 186.715,295.373 190.249,295.373 v12(190.615,295.739)
  L3 (Sign) w0.12: v2(185.064,298.17) 185.101,298.17 185.151,298.22 185.374,298.22 v12(185.447,298.293) ; v12(190.615,295.739) 190.615,296.46 190.33,296.744 190.33,297.092 190.778,297.539 190.952,297.539 191.605,298.193 193.523,298.193 193.53,298.2 219.534,298.2 221.58,296.154 244.842,296.154 v2(249.503,300.816)
Interrupt7: R659.2 R744.1 U1.AD10 | length 78.9
  L1 w0.12: v2(184.651,296.98) 185.137,297.467 185.324,297.467 U1.AD10@185.397,297.539 ; R659.2@253.593,299.747 v2(253.593,300.816) R744.1@253.593,301.885
  L5 (Sign) w0.12: v12(184.092,296.371) 184.092,296.02 185.578,294.534 185.909,294.534 186.108,294.733 191.067,294.733 191.94,295.606 191.94,295.885 193.007,296.952 v12(193.007,297.052)
  L3 (Sign) w0.12: v12(184.092,296.371) 184.608,296.888 184.608,296.902 184.651,296.944 v2(184.651,296.98) ; v12(193.007,297.052) 193.007,297.127 193.368,297.487 219.314,297.487 221.307,295.494 248.272,295.494 v2(253.593,300.816)
Interrupt8: R661.2 R767.1 U1.AB10 | length 78.9
  L1 w0.12: v2(183.005,296.957) 183.03,296.982 183.03,297.173 U1.AB10@183.397,297.539 ; v7(188.884,298.235) 188.884,298.623 189.313,299.052 191.884,299.052 192.397,298.539 192.397,297.71 192.436,297.67 192.436,297.531 v7(192.48,297.487) ; R661.2@252.23,299.747 v2(252.23,300.816) R767.1@252.23,301.885
  L3 (Sign) w0.12: v2(183.005,296.957) 183.998,296.957 184.308,297.267 186.137,297.267 186.83,296.574 188.496,296.574 189.049,297.127 189.049,298.008 188.884,298.173 v7(188.884,298.235) ; v7(192.48,297.487) 192.504,297.487 192.743,297.726 195.974,297.726 219.386,297.726 221.398,295.714 247.128,295.714 v2(252.23,300.816)
Interrupt9: R663.2 R819.1 U1.AB9 | length 87.8
  L1 w0.12: v7(183.093,296.177) 183.083,296.187 183.083,296.299 183.323,296.539 U1.AB9@183.397,296.539 ; R663.2@259.161,299.747 v2(259.161,300.816) R819.1@259.161,301.885
  L5 (Sign) w0.12: v12(182.537,295.462) 183.07,295.462 186.274,292.258 188.124,292.258 189.518,293.652 191.885,293.652 192.772,294.539 194.874,294.539 195.564,295.229 195.564,295.878 v6(195.237,296.204)
  L3 (Sign) w0.12: v12(182.537,295.462) 182.537,295.559 183.093,296.115 v7(183.093,296.177) ; v6(195.237,296.204) 195.628,296.596 218.935,296.596 220.917,294.614 252.959,294.614 v2(259.161,300.816)
Interrupt10: R735.2 R822.1 U1.Y10 | length 83.5
  L1 w0.12: v7(180.909,297.052) U1.Y10@181.397,297.539 ; R735.2@254.956,299.747 v2(254.956,300.816) R822.1@254.956,301.885
  L5 (Sign) w0.12: v12(181.397,296.574) 181.397,296.272 181.783,295.885 183.841,295.885 185.412,294.314 185.625,294.314 185.93,294.009 187.023,294.009 187.486,293.547 188.127,293.547 189.024,294.444 191.188,294.444 193.426,296.683 v12(193.501,296.683)
  L3 (Sign) w0.12: v7(180.909,297.052) 180.865,297.008 180.865,296.76 180.828,296.723 180.828,296.666 180.92,296.574 v12(181.397,296.574) ; v12(193.501,296.683) 194.086,297.267 219.223,297.267 221.215,295.274 249.415,295.274 v2(254.956,300.816)
Interrupt11: R765.2 R851.1 U1.AA10 | length 77.1
  L1 w0.12: R765.2@250.866,299.747 R765.2@250.866,299.797 v2(250.866,300.816) R851.1@250.866,301.835 R851.1@250.866,301.885
  L5 (Sign) w0.12: v12(182.7,298.083) 182.709,298.092 182.961,298.092 185.399,295.654 185.702,295.654 185.909,295.447 186.33,295.447 186.661,295.116 190.8,295.116 191.381,295.697 v12(191.451,295.697)
  L3 (Sign) w0.12: v7(182.397,297.539) 182.397,297.78 v12(182.7,298.083) ; v12(191.451,295.697) 191.451,297.199 192.225,297.973 195.966,297.973 195.974,297.98 219.443,297.98 221.489,295.934 245.985,295.934 v2(250.866,300.816)
Interrupt12: R817.2 R854.1 U1.AC9 | length 82.4
  L1 w0.12: U1.AC9@184.397,296.539 v7@184.884,296.052 ; R817.2@256.32,299.747 v2(256.32,300.816) R854.1@256.32,301.885
  L5 (Sign) w0.12: v12(183.773,295.373) 183.773,295.327 185.402,293.698 186.777,293.698 187.148,293.327 188.218,293.327 189.068,294.176 191.231,294.176 193.295,296.24 193.934,296.24 v12(193.969,296.276)
  L3 (Sign) w0.12: v12(183.773,295.373) 183.83,295.431 184.265,295.431 v7(184.886,296.052) ; v12(193.969,296.276) 194.74,297.047 219.132,297.047 221.124,295.054 250.558,295.054 v2(256.32,300.816)
Interrupt13: R820.2 R857.1 U1.AD9 | length 82.3
  L1 w0.12: U1.AD9@185.397,296.519 U1.AD9@185.397,296.539 ; R820.2@257.683,299.747 v2(257.683,300.816) R857.1@257.683,301.885
  L3 (Sign) w0.12: v3(185.122,296.857) 185.162,296.817 v3@185.162,296.753 ; v3(194.81,295.602) 194.81,295.614 194.562,295.862 194.562,296.289 195.1,296.827 219.041,296.827 221.033,294.834 251.702,294.834 v2(257.683,300.816)
  L14 (Sign) w0.12: v3(185.122,296.857) 185.122,295.32 185.526,294.917 189.151,294.917 189.169,294.899 190.856,294.899 192.664,296.707 193.62,296.707 194.725,295.602 v3(194.81,295.602)
Interrupt14: R823.2 R860.1 U1.AC6 | length 53.9
  L1 w0.12: v2(183.909,293.052) U1.AC6@184.397,293.539 ; R823.2@228.908,287.208 228.905,287.211 v2(228.905,288.138) 228.905,290.207 R860.1@228.908,290.21
  L3 (Sign) w0.12: v2(183.909,293.052) 185.663,293.052 186.572,292.143 187.343,292.143 187.884,291.601 187.884,288.118 188.463,287.539 189.228,286.775 227.558,286.775 228.905,288.121 v2(228.905,288.138)
Interrupt15: R847.2 R862.1 U1.AD6 | length 82.4
  L1 w0.12: U1.AD6@185.397,293.539 v2(185.742,293.885) ; R847.2@262.116,299.747 v2(262.116,300.816) R862.1@262.116,301.885
  L3 (Sign) w0.12: v2(185.742,293.885) 186.2,293.427 189.904,293.427 190.87,294.393 192.397,294.393 220.491,294.393 220.71,294.174 255.475,294.174 v2(262.116,300.816)
Interrupt16: R849.2 R863.1 U1.W8 | length 57.2
  L1 w0.12: v2(179.909,295.052) U1.W8@180.397,295.539 ; R849.2@227.559,287.208 227.475,287.291 v2(227.475,287.974) 227.475,290.127 R863.1@227.559,290.21
  L3 (Sign) w0.12: v2(179.909,295.052) 180.568,294.393 182.39,294.393 183.373,293.41 185.616,293.41 186.663,292.363 187.434,292.363 188.104,291.692 188.104,288.209 188.709,287.605 188.774,287.539 189.159,287.155 227.063,287.155 227.475,287.567 v2(227.475,287.974)
Interrupt17: R852.2 R864.1 U1.Y8 | length 86.1
  L1 w0.12: v2(181.007,294.97) 181.032,294.996 181.032,295.175 U1.Y8@181.397,295.539 ; R852.2@260.639,299.747 v2(260.639,300.816) R864.1@260.639,301.885
  L3 (Sign) w0.12: v2(181.007,294.97) 181.363,294.613 183.658,294.613 184.04,294.231 185.986,294.231 186.451,293.766 189.187,293.766 190.034,294.613 192.397,294.613 220.594,294.613 220.813,294.394 254.217,294.394 v2(260.639,300.816)
Interrupt18: R855.2 R865.1 U1.Y7 | length 59.3
  L1 w0.12: v2(180.909,294.052) U1.Y7@181.397,294.539 ; R855.2@230.258,287.208 230.314,287.264 v2(230.314,288.074) 230.314,290.154 R865.1@230.258,290.21
  L3 (Sign) w0.12: v2(180.909,294.052) 181.39,294.052 181.512,294.173 182.299,294.173 182.956,293.516 182.956,293.04 183.279,292.717 185.687,292.717 186.481,291.923 187.165,291.923 187.608,291.479 187.608,288.006 188.075,287.539 189.06,286.555 228.795,286.555 v2(230.314,288.074)
Interrupt19: R858.2 R866.1 U1.AA7 | length 60.6
  L1 w0.12: v2(181.909,293.886) 181.909,294.052 U1.AA7@182.397,294.539 ; R858.2@232.957,287.208 232.984,287.235 232.965,287.254 v2(232.965,288.15) 232.965,290.164 232.984,290.183 R866.1@232.957,290.21
  L3 (Sign) w0.12: v2(181.909,293.886) 181.935,293.912 182.035,293.912 182.042,293.92 182.587,293.374 182.587,293.098 183.188,292.497 184.964,292.497 185.441,292.021 185.441,291.91 186.902,290.45 186.902,288.139 187.168,287.872 187.168,287.824 187.453,287.539 188.878,286.115 230.929,286.115 v2(232.965,288.15)
Interrupt20: R861.1 R867.1 U1.AD5 | length 59.7
  L1 w0.12: v2(184.909,292.052) U1.AD5@185.397,292.539 ; R861.1@235.656,287.208 235.712,287.264 v2(235.712,288.188) 235.712,290.154 R867.1@235.656,290.21
  L3 (Sign) w0.12: v2(184.909,292.052) 185.562,291.399 185.562,290.912 186.462,290.013 186.462,287.957 186.728,287.69 186.728,287.642 186.831,287.539 188.696,285.675 233.198,285.675 v2(235.712,288.188)
Interrupt21: R523.1 R868.1 U1.AE5 | length 54.9
  L1 w0.12: v2(185.776,292.049) 186.266,292.539 U1.AE5@186.397,292.539 ; R523.1@231.607,287.208 231.648,287.248 v2(231.648,288.201) 231.648,290.17 R868.1@231.607,290.21
  L3 (Sign) w0.12: v2(185.776,292.049) 186.122,291.703 186.994,291.703 187.388,291.308 187.388,288.226 187.388,287.915 187.764,287.539 188.969,286.335 189.28,286.335 229.782,286.335 v2(231.648,288.201)
Interrupt22: R546.1 R869.1 U1.AD4 | length 60.4
  L1 w0.12: v2@185.005,291.147 U1.AD4@185.397,291.539 ; R546.1@237.005,287.208 237.046,287.248 v2(237.046,288.201) 237.046,290.17 R869.1@237.005,290.21
  L3 (Sign) w0.12: v2(185.001,291.147) 185.016,291.147 186.065,290.098 186.065,289.755 186.242,289.579 186.242,287.865 186.508,287.599 186.508,287.551 186.52,287.539 188.625,285.434 233.565,285.434 236.332,288.201 v2(237.046,288.201)
Interrupt23: R549.1 R870.1 U1.AE4 | length 56.5
  L1 w0.12: v2(185.901,291.044) U1.AE4@186.397,291.539 ; R549.1@234.306,287.208 234.302,287.211 v2(234.302,288.163) 234.302,290.207 R870.1@234.306,290.21
  L3 (Sign) w0.12: v2(185.901,291.044) 186.682,290.264 186.682,288.048 186.948,287.781 186.948,287.733 187.142,287.539 188.787,285.895 232.034,285.895 v2(234.302,288.163)
Interrupt24: R552.1 R871.1 U1.AB4 | length 83.4
  L1 w0.12: v2(182.909,291.052) U1.AB4@183.397,291.539 ; R552.1@251.85,287.158 251.879,287.187 v2(251.879,288.061) 251.879,290.131 R871.1@251.85,290.16
  L3 (Sign) w0.12: v2(182.909,291.052) 182.909,290.674 183.104,290.479 183.146,290.479 183.342,290.283 183.342,290.241 183.515,290.068 183.515,285.946 183.753,285.708 183.753,284.61 186.005,282.357 191.517,282.357 193.206,280.669 198.564,280.669 200.27,282.375 245.4,282.375 251.087,288.061 v2(251.879,288.061)
Interrupt25: R555.1 R872.1 U1.AC4 | length 71.8
  L1 w0.12: v2(183.909,291.052) U1.AC4@184.397,291.539 ; R555.1@243.753,287.208 243.698,287.262 v2(243.698,288.061) 243.698,290.156 R872.1@243.753,290.21
  L3 (Sign) w0.12: v2(183.909,291.052) 183.928,291.034 183.928,290.511 184.04,290.398 184.04,290.396 184.499,289.937 184.499,289.873 185.187,289.185 185.187,287.641 185.073,287.527 185.073,285.156 186.535,283.695 193.928,283.695 194.588,283.035 199.063,283.035 199.758,283.73 238.608,283.73 242.94,288.061 v2(243.698,288.061)
Interrupt26: R607.1 R873.1 U1.AA6 | length 68.1
  L1 w0.12: v2(181.965,293.041) 181.965,293.074 182.397,293.506 U1.AA6@182.397,293.539 ; R607.1@238.355,287.258 R607.1@238.355,287.258 v2(238.354,288.226) 238.379,288.252 R873.1@238.379,290.152 R873.1@238.379,290.202
  L3 (Sign) w0.12: v2(181.965,293.041) 182.661,292.345 182.661,292.301 183.331,291.63 184.112,291.63 184.924,290.819 185.034,290.819 185.845,290.007 185.845,289.664 186.022,289.488 186.022,287.774 186.137,287.658 186.137,285.443 186.97,284.61 196.027,284.61 196.722,283.915 198.699,283.915 199.394,284.61 234.04,284.61 237.657,288.226 v2(238.354,288.226)
Interrupt27: R660.1 R874.1 U1.AA5 | length 69.3
  L1 w0.12: v2(181.909,292.052) U1.AA5@182.397,292.539 ; R660.1@239.704,287.208 239.611,287.301 v2(239.611,288.099) 239.611,290.109 R874.1@239.704,290.202
  L3 (Sign) w0.12: v2(181.909,292.052) 182.598,292.052 183.24,291.41 183.96,291.41 184.771,290.599 184.943,290.599 185.625,289.916 185.625,289.573 185.802,289.397 185.802,287.683 185.867,287.618 185.867,285.296 186.808,284.355 194.202,284.355 194.862,283.695 198.79,283.695 199.485,284.39 235.22,284.39 238.93,288.099 v2(239.611,288.099)
Interrupt28: R662.1 R875.1 U1.AD2 | length 72.2
  L1 w0.12: v2(184.771,289.146) 185.004,289.146 U1.AD2@185.397,289.539 ; R662.1@245.102,287.208 245.072,287.238 v2(245.072,288.087) 245.072,290.18 R875.1@245.102,290.21
  L3 (Sign) w0.12: v2(184.771,289.146) 184.771,288.564 184.967,288.368 184.967,287.732 184.853,287.618 184.853,285.065 186.444,283.475 191.956,283.475 193.662,281.769 194.247,281.769 195.073,282.595 198.934,282.595 199.849,283.51 239.738,283.51 244.315,288.087 v2(245.072,288.087)
Interrupt29: R664.1 R876.1 U1.AE2 | length 66.1
  L1 w0.12: v2(185.515,289.052) 185.909,289.052 U1.AE2@186.397,289.539 ; R664.1@241.054,287.208 241.017,287.245 v2(241.017,288.188) 241.017,290.173 R876.1@241.054,290.21
  L3 (Sign) w0.12: v2(185.515,289.052) 185.515,287.659 185.647,287.527 185.647,285.205 186.717,284.135 194.111,284.135 194.771,283.475 198.881,283.475 199.576,284.17 236.349,284.17 240.368,288.188 v2(241.017,288.188)
Interrupt30: R736.1 R877.1 U1.AD1 | length 72.9
  L1 w0.12: v2(184.633,288.091) 184.935,288.091 185.383,288.539 U1.AD1@185.397,288.539 ; R736.1@246.452,287.208 246.342,287.317 v2(246.342,287.972) 246.342,290.101 R877.1@246.452,290.21
  L3 (Sign) w0.12: v2(184.633,288.091) 184.633,284.974 186.352,283.255 191.864,283.255 193.13,281.989 193.57,281.549 194.339,281.549 194.779,281.989 195.165,282.375 199.025,282.375 199.94,283.29 240.867,283.29 245.55,287.972 v2(246.342,287.972)
Interrupt31: R766.1 R878.1 U1.AE1 | length 66.7
  L1 w0.12: v2(185.36,287.408) 186.397,288.445 U1.AE1@186.397,288.539 ; R766.1@242.403,287.208 242.329,287.282 v2(242.329,288.201) 242.329,290.136 R878.1@242.403,290.21
  L3 (Sign) w0.12: v2(185.36,287.408) 185.36,285.18 186.626,283.915 194.019,283.915 194.679,283.255 198.972,283.255 199.667,283.95 237.479,283.95 241.73,288.201 v2(242.329,288.201)
Interrupt32: R818.1 R879.1 U1.AC3 | length 76.7
  L1 w0.12: v2(183.909,290.052) U1.AC3@184.397,290.539 ; R818.1@247.801,287.208 247.752,287.257 v2(247.752,287.947) 247.752,290.161 R879.1@247.801,290.21
  L3 (Sign) w0.12: v2(183.909,290.052) 184.346,289.615 184.346,287.973 184.413,287.906 184.413,284.883 186.261,283.035 191.773,283.035 193.479,281.329 196.013,281.329 196.839,282.155 199.116,282.155 200.031,283.07 241.997,283.07 246.874,287.947 v2(247.752,287.947)
Interrupt33: R821.1 R880.1 U1.AC2 | length 77.5
  L1 w0.12: v2(183.909,289.052) U1.AC2@184.397,289.539 ; R821.1@249.151,287.158 249.151,287.208 249.167,287.224 v2(249.167,288.011) 249.167,290.144 R880.1@249.151,290.16
  L3 (Sign) w0.12: v2(183.909,289.052) 183.909,288.785 184.126,288.568 184.126,287.881 184.193,287.814 184.193,284.792 186.17,282.815 191.682,282.815 193.388,281.109 196.104,281.109 196.93,281.935 199.208,281.935 200.123,282.85 243.106,282.85 243.141,282.815 248.337,288.011 v2(249.167,288.011)
Interrupt34: R824.1 R881.1 U1.AA3 | length 87.9
  L1 w0.12: v2(181.909,290.052) U1.AA3@182.397,290.539 ; R824.1@255.898,287.208 255.778,287.328 v2(255.778,288.011) 255.778,290.09 R881.1@255.898,290.21
  L3 (Sign) w0.12: v2(181.909,290.052) 181.909,289.692 182.55,289.052 182.55,285.978 183.093,285.434 183.093,284.336 185.776,281.654 191.288,281.654 192.933,280.009 198.837,280.009 200.482,281.654 248.678,281.654 255.136,288.112 255.238,288.011 v2(255.778,288.011)
Interrupt35: R848.1 R882.1 U1.AB3 | length 84
  L1 w0.12: v2@183.007,290.15 U1.AB3@183.397,290.539 ; R848.1@253.199,287.208 253.241,287.249 v2(253.241,288.036) 253.241,290.169 R882.1@253.199,290.21
  L3 (Sign) w0.12: v2(183.007,290.144) 183.007,289.895 182.909,289.797 183.248,289.458 183.248,285.901 183.533,285.617 183.533,284.519 185.914,282.137 191.426,282.137 193.115,280.449 198.655,280.449 200.361,282.155 246.48,282.155 252.361,288.036 v2(253.241,288.036)
Interrupt36: R850.1 R883.1 U1.AB1 | length 83.6
  L1 w0.12: v2(182.909,288.052) U1.AB1@183.397,288.539 ; R850.1@254.549,287.208 254.419,287.337 v2(254.419,287.959) 254.419,290.081 R883.1@254.549,290.21
  L3 (Sign) w0.12: v2(182.909,288.052) 182.909,285.929 183.313,285.525 183.313,284.427 185.823,281.917 191.335,281.917 193.024,280.229 198.746,280.229 200.452,281.935 247.609,281.935 253.376,287.701 253.38,287.701 253.576,287.897 253.576,287.901 253.633,287.959 v2(254.419,287.959)
Interrupt37: R853.1 R884.1 U1.AC1 | length 78.4
  L1 w0.12: v2(183.839,288.052) 183.91,288.052 U1.AC1@184.397,288.539 ; R853.1@250.5,287.158 250.5,287.208 250.566,287.274 v2(250.566,288.099) 250.566,290.094 R884.1@250.5,290.16
  L3 (Sign) w0.12: v2(183.839,288.052) 183.839,285.933 183.973,285.799 183.973,284.701 186.097,282.577 191.609,282.577 193.297,280.889 198.473,280.889 200.179,282.595 244.271,282.595 249.776,288.099 v2(250.566,288.099)
Interrupt38: R856.1 R885.1 U1.AA2 | length 88.6
  L1 w0.12: v2(181.909,289.052) U1.AA2@182.397,289.539 ; R856.1@257.248,287.208 257.277,287.236 v2(257.277,288.036) 257.277,290.182 R885.1@257.248,290.21
  L3 (Sign) w0.12: v2(181.909,289.052) 181.909,288.816 182.244,288.481 182.244,285.972 182.873,285.343 182.873,284.245 186.669,280.449 192.181,280.449 192.841,279.789 211.713,279.789 211.987,280.062 248.436,280.062 256.41,288.036 v2(257.277,288.036)
Interrupt39: R859.1 R886.1 U1.AA1 | length 89.2
  L1 w0.12: v2(181.909,288.052) U1.AA1@182.397,288.539 ; R859.1@258.597,287.208 258.623,287.233 v2(258.623,287.858) 258.623,290.185 R886.1@258.597,290.21
  L3 (Sign) w0.12: v2(181.909,288.052) 181.909,287.539 181.909,285.792 182.653,285.048 182.653,284.154 186.578,280.229 192.09,280.229 192.75,279.569 211.804,279.569 212.078,279.842 249.565,279.842 257.581,287.858 v2(258.623,287.858)
Interrupt40: R921.2 R961.1 U1.AA13 | length 50.3
  L1 w0.12: R921.2@229.053,299.747 v2(229.053,300.816) R961.1@229.053,301.885
  L3 (Sign) w0.12: v2(182.397,300.539) 182.966,300.539 183.21,300.783 183.599,300.783 183.734,300.647 186.074,300.647 186.253,300.826 187.21,300.826 187.265,300.771 188.222,300.771 189.253,301.802 192.199,301.802 192.314,301.687 217.081,301.687 217.223,301.828 220.573,301.828 221.92,300.481 227.828,300.481 227.841,300.494 228.731,300.494 v2(229.053,300.816)
Interrupt41: R923.2 R962.1 U1.AB13 | length 59.7
  L1 w0.12: R923.2@238.596,299.747 v2(238.596,300.816) R962.1@238.596,301.885
  L3 (Sign) w0.12: v2(183.397,300.496) 183.641,300.252 187.967,300.252 188.187,300.032 192.397,300.032 192.634,300.032 192.738,300.137 220.087,300.137 221.651,298.572 224.884,298.572 225.541,297.915 228.865,297.915 229.535,298.585 236.365,298.585 v2(238.596,300.816)
Interrupt42: R925.2 R963.1 U1.AE14 | length 83.9
  L1 w0.12: R925.2@263.613,308.751 v1(263.613,309.607) R963.1@263.613,310.463
  L5 (Sign) w0.12: v12(185.904,301.057) 186.863,301.057 187.149,300.771 196.396,300.771 196.425,300.799 217.585,300.799 218.172,301.387 219.059,301.387 224.317,306.644 260.65,306.644 v1(263.613,309.607)
  L3 (Sign) w0.12: v12(185.904,301.057) 185.909,301.057 186.392,301.539 v2(186.397,301.539)
Interrupt43: R927.2 R964.1 U1.AE13 | length 54.3
  L1 w0.12: R927.2@237.233,299.747 v2(237.233,300.816) R964.1@237.233,301.885
  L3 (Sign) w0.12: v2(186.406,300.539) 187.991,300.539 188.278,300.252 192.397,300.252 192.543,300.252 192.647,300.357 220.178,300.357 221.385,299.15 235.567,299.15 v2(237.233,300.816)
Interrupt44: R929.2 R965.1 U1.AC14 | length 89.3
  L1 w0.12: R929.2@266.607,308.751 v1(266.607,309.607) R965.1@266.607,310.463
  L5 (Sign) w0.12: v12(183.904,301.057) 184.26,301.057 185.014,300.304 218.155,300.304 218.797,300.947 219.241,300.947 224.499,306.204 263.204,306.204 v1(266.607,309.607)
  L3 (Sign) w0.12: v12(183.904,301.057) 183.909,301.057 184.392,301.539 v2(184.397,301.539)
Interrupt45: R931.2 R966.1 U1.AD14 | length 86.6
  L1 w0.12: R931.2@265.11,308.751 v1(265.11,309.607) R966.1@265.11,310.463
  L5 (Sign) w0.12: v12@184.904,301.057 185.213,301.057 185.649,300.622 186.987,300.622 187.058,300.551 217.647,300.551 217.718,300.622 218.023,300.622 218.568,301.167 219.15,301.167 224.408,306.424 261.927,306.424 v1(265.11,309.607)
  L3 (Sign) w0.12: v12(184.897,301.057) 184.906,301.057 185.388,301.539 v2(185.397,301.539)
Interrupt46: R933.2 R967.1 U1.AA14 | length 96.5
  L1 w0.12: R933.2@271.098,308.751 v1(271.098,309.607) R967.1@271.098,310.463
  L5 (Sign) w0.12: v12@181.904,301.057 183.508,299.453 218.507,299.453 219.341,300.287 219.514,300.287 224.772,305.544 267.035,305.544 v1(271.098,309.607)
  L3 (Sign) w0.12: v12(181.886,301.057) 181.9,301.057 182.382,301.539 v2(182.397,301.539)
Interrupt47: R935.2 R968.1 U1.AB14 | length 92
  L1 w0.12: R935.2@268.104,308.751 v1(268.104,309.607) R968.1@268.104,310.463
  L5 (Sign) w0.12: v12(182.904,301.057) 183.143,301.057 184.137,300.063 218.255,300.063 218.918,300.727 219.332,300.727 224.59,305.984 264.481,305.984 v1(268.104,309.607)
  L3 (Sign) w0.12: v12(182.904,301.057) 182.909,301.057 183.392,301.539 v2(183.397,301.539)
Interrupt48: R937.2 R969.1 U1.AA15 | length 95.3
  L1 w0.12: R937.2@269.601,308.751 v1(269.601,309.607) R969.1@269.601,310.463
  L5 (Sign) w0.12: v12(181.989,301.972) 182.296,301.666 182.296,300.977 183.489,299.784 218.37,299.784 219.094,300.507 219.423,300.507 224.681,305.764 265.758,305.764 v1(269.601,309.607)
  L3 (Sign) w0.12: v12(181.989,301.972) 181.989,302.045 182.361,302.417 v2(182.397,302.417)
Interrupt49: R939.2 R970.1 U1.AB15 | length 85.2
  L1 w0.12: R939.2@262.116,308.751 v1(262.116,309.607) R970.1@262.116,310.463
  L5 (Sign) w0.12: v12(182.904,302.057) 184.124,302.057 184.575,301.607 185.57,301.607 185.68,301.497 186.139,301.497 186.249,301.607 218.968,301.607 224.225,306.864 259.373,306.864 v1(262.116,309.607)
  L3 (Sign) w0.12: v12(182.904,302.057) 183.001,302.057 183.361,302.417 v2(183.397,302.417)
Interrupt50: R941.2 R971.1 U1.AD15 | length 81.5
  L1 w0.12: R941.2@260.619,308.751 v1(260.619,309.607) R971.1@260.619,310.463
  L5 (Sign) w0.12: v12(184.904,302.057) 185.267,302.057 185.498,301.827 185.661,301.827 185.771,301.717 186.048,301.717 186.158,301.827 218.877,301.827 224.134,307.084 258.096,307.084 v1(260.619,309.607)
  L3 (Sign) w0.12: v12(184.904,302.057) 184.909,302.057 185.392,302.539 v2(185.397,302.539)
Interrupt51: R943.2 R972.1 U1.AE15 | length 78.3
  L1 w0.12: R943.2@259.122,308.751 v1(259.122,309.607) R972.1@259.122,310.463
  L5 (Sign) w0.12: v12(186.215,302.539) 186.702,302.052 218.791,302.052 224.043,307.304 256.819,307.304 v1(259.122,309.607)
  L3 (Sign) w0.12: v12(186.215,302.539) 186.225,302.53 v2(186.606,302.53)
Interrupt52: R945.2 R973.1 U1.AG13 | length 49.5
  L1 w0.12: R945.2@234.506,299.747 v2(234.506,300.816) R973.1@234.506,301.885
  L3 (Sign) w0.12: v2(188.397,300.539) 188.76,300.902 189.581,300.902 189.743,300.74 192.397,300.74 192.408,300.74 192.465,300.797 220.36,300.797 221.556,299.601 233.291,299.601 v2(234.506,300.816)
Interrupt53: R947.2 R974.1 U1.AH13 | length 49.7
  L1 w0.12: R947.2@235.87,299.747 v2(235.87,300.816) R974.1@235.87,301.885
  L3 (Sign) w0.12: v2(189.397,300.539) 189.416,300.52 192.397,300.52 192.499,300.52 192.556,300.577 220.269,300.577 221.476,299.37 234.423,299.37 v2(235.87,300.816)
Interrupt54: R949.2 R975.1 U1.AK13 | length 45
  L1 w0.12: U1.AK13@191.397,300.539 v2@191.884,301.027 ; R949.2@233.143,299.747 v2(233.143,300.816) R975.1@233.143,301.885
  L3 (Sign) w0.12: v2(191.878,301.027) 220.441,301.027 221.647,299.821 232.148,299.821 v2(233.143,300.816)
Interrupt55: R951.2 R976.1 U1.AK12 | length 57.4
  L1 w0.12: U1.AK12@191.397,299.539 192.397,299.539 192.781,299.539 v2(193.13,299.19) ; R951.2@244.05,299.747 v2(244.05,300.816) R976.1@244.05,301.885
  L3 (Sign) w0.12: v2(193.13,299.19) 219.789,299.19 221.944,297.034 240.268,297.034 v2(244.05,300.816)
Interrupt56: R953.2 R977.1 U1.AJ14 | length 44.4
  L1 w0.12: v2(189.909,301.052) U1.AJ14@190.397,301.539 ; R953.2@230.416,299.747 v2(230.416,300.816) R977.1@230.416,301.885
  L3 (Sign) w0.12: v2(189.909,301.052) 190.439,301.582 192.108,301.582 192.223,301.467 217.172,301.467 217.292,301.587 220.503,301.587 221.829,300.261 229.861,300.261 v2(230.416,300.816)
Interrupt57: R955.2 R978.1 U1.AK14 | length 44.8
  L1 w0.12: v2(190.909,301.052) U1.AK14@191.397,301.539 ; R955.2@231.78,299.747 v2(231.78,300.816) R978.1@231.78,301.885
  L3 (Sign) w0.12: v2(190.909,301.052) 191.219,301.362 192.017,301.362 192.132,301.247 217.263,301.247 217.384,301.367 220.412,301.367 221.738,300.041 231.005,300.041 v2(231.78,300.816)
Interrupt58: R957.2 R979.1 U1.AJ15 | length 59
  L1 w0.12: U1.AJ15@190.397,302.539 v2(190.884,303.027) ; R957.2@244.152,308.751 v2(244.152,309.607) R979.1@244.152,310.463
  L3 (Sign) w0.12: v2(190.884,303.027) 191.257,302.654 192.28,302.654 192.587,302.347 216.808,302.347 220.929,306.468 241.013,306.468 v2(244.152,309.607)
Interrupt59: R959.2 R980.1 U1.AK15 | length 56.3
  L1 w0.12: U1.AK15@191.397,302.539 v2@191.884,303.027 ; R959.2@242.655,308.751 v2(242.655,309.607) R980.1@242.655,310.463
  L3 (Sign) w0.12: v2(191.878,303.027) 192.218,303.027 192.678,302.567 216.717,302.567 220.838,306.688 239.736,306.688 v2(242.655,309.607)
Interrupt60: R922.1 R981.1 U1.AC16 | length 77.1
  L1 w0.12: R922.1@256.128,308.751 v1(256.128,309.607) R981.1@256.128,310.463
  L5 (Sign) w0.12: v12(184.008,303.296) 184.111,303.296 184.35,303.057 184.43,303.057 185.047,303.674 191.818,303.674 192.547,304.403 209.705,304.403 209.722,304.42 217.88,304.42 221.274,307.814 254.335,307.814 v1(256.128,309.607)
  L3 (Sign) w0.12: v12(184.008,303.296) 184.081,303.369 184.19,303.369 184.361,303.539 v2(184.397,303.539)
Interrupt61: R924.1 R982.1 U1.AD16 | length 77.2
  L1 w0.12: R924.1@257.625,308.751 v1(257.625,309.607) R982.1@257.625,310.463
  L5 (Sign) w0.12: v12(185.255,303.264) 185.353,303.264 185.559,303.057 186.215,303.057 186.611,303.454 191.909,303.454 192.638,304.183 209.796,304.183 209.813,304.2 217.971,304.2 221.366,307.594 255.612,307.594 v1(257.625,309.607)
  L3 (Sign) w0.12: v12(185.255,303.264) 185.255,303.361 185.397,303.503 v2(185.397,303.539)
Interrupt62: R926.1 R983.1 U1.AA16 | length 76.3
  L1 w0.12: R926.1@253.134,308.751 v1(253.134,309.607) R983.1@253.134,310.463
  L5 (Sign) w0.12: v12(181.904,303.057) 182.141,303.057 183.009,303.926 184.495,303.926 184.683,304.114 191.636,304.114 192.364,304.843 209.523,304.843 209.54,304.86 217.698,304.86 221.092,308.254 247.037,308.254 247.041,308.258 249.079,308.258 ; 249.079,308.254 251.781,308.254 v1(253.134,309.607)
  L3 (Sign) w0.12: v12(181.904,303.057) 181.909,303.057 182.392,303.539 v2(182.397,303.539)
Interrupt63: R928.1 R984.1 U1.AB16 | length 76.9
  L1 w0.12: R928.1@254.631,308.751 v1(254.631,309.607) R984.1@254.631,310.463
  L5 (Sign) w0.12: v12@182.904,303.057 183.19,303.057 183.838,303.706 184.656,303.706 184.844,303.894 191.727,303.894 192.456,304.623 209.614,304.623 209.631,304.64 217.789,304.64 221.183,308.034 253.058,308.034 v1(254.631,309.607)
  L3 (Sign) w0.12: v12(182.897,303.052) 182.903,303.052 183.39,303.539 v2(183.397,303.539)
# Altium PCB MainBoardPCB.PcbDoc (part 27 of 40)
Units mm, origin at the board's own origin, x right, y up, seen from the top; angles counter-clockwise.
Board outline 258.95 x 308.86 mm, 16 copper layers (L1, L2 (GND), L3 (Sign), L4 (GND), L5 (Sign), L6 (PWR/GND), L7(12V+Other), L8 (Plane_GND), L9 (PWR/GND), L10 (3V3+Other), L11 (PWR/GND), L12 (Sign), L13 (GND), L14 (Sign), L15 (GND), L16), stack 2.503 mm thick; 2578 components, 1867 nets, 8817 pads, 8021 vias.
Unrouted connection lines stored in the file: 25.

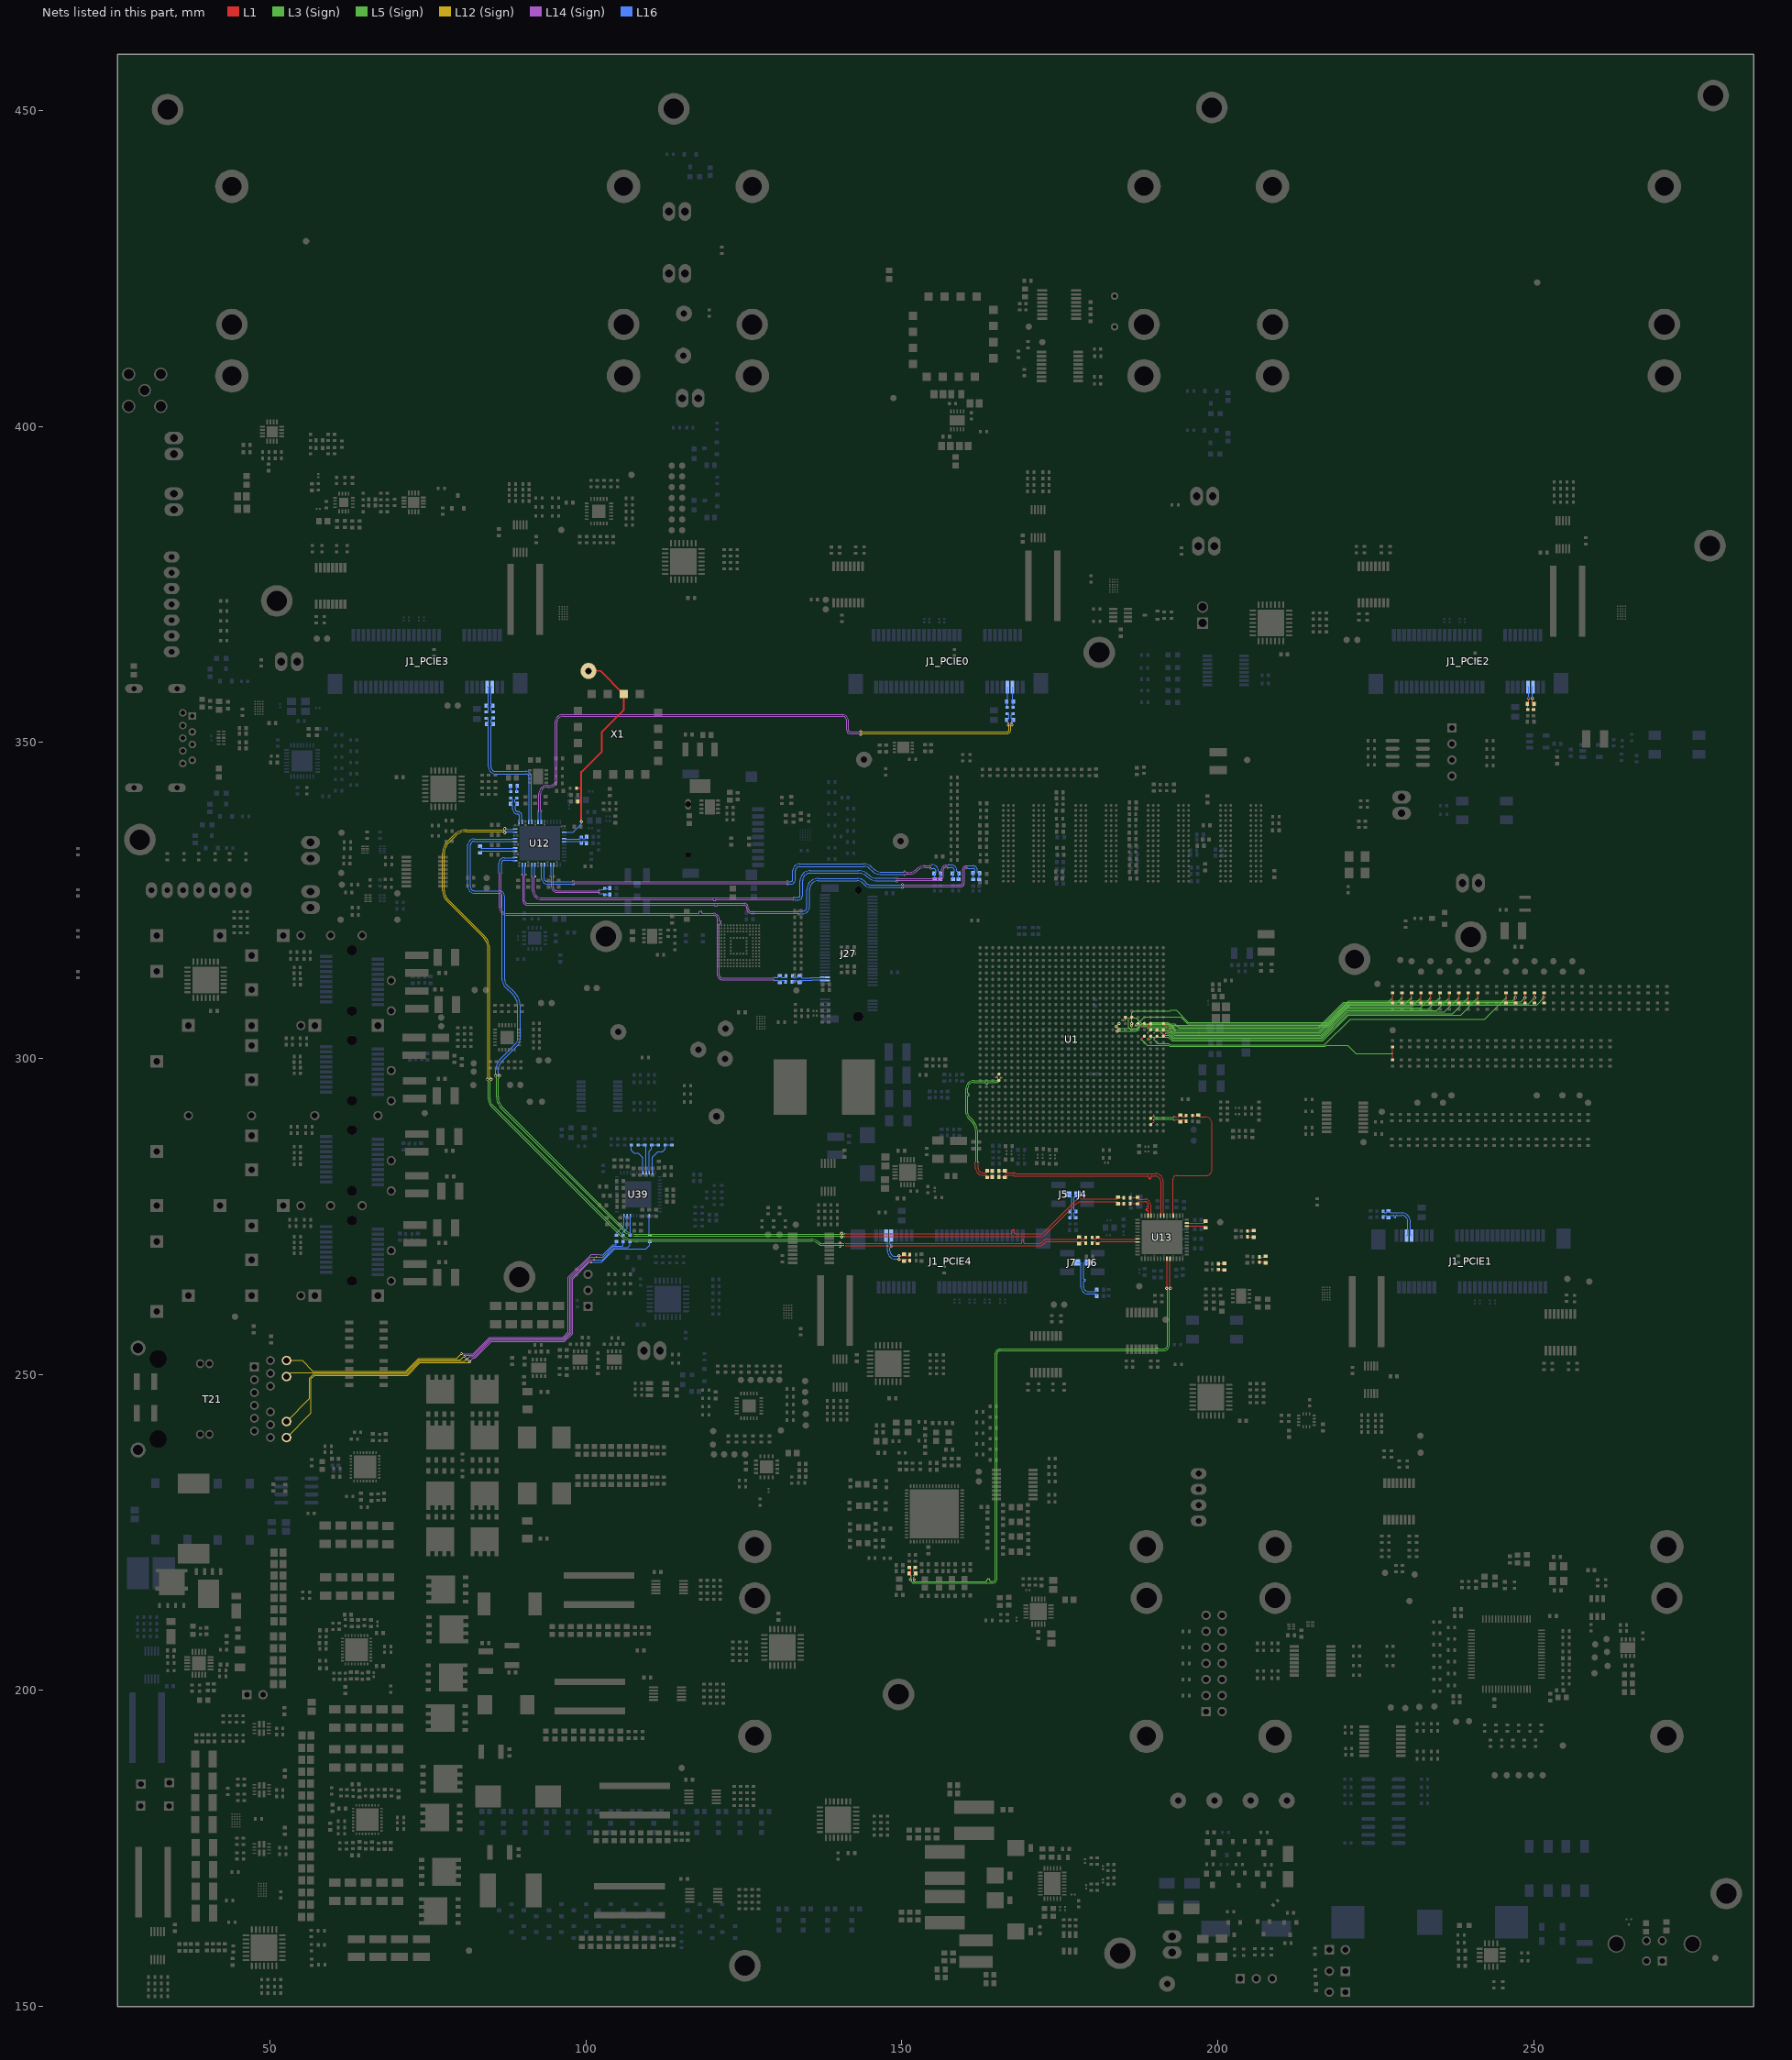
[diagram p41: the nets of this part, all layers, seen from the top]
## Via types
v1: diameter 0.5, hole 0.25, L1 to L16, tented both sides, 4341 vias
v2: diameter 0.254, hole 0.1, L1 to L3 (Sign), tented both sides, 781 vias
v3: diameter 0.5, hole 0.25, L1 to L16, 565 vias
v4: diameter 0.254, hole 0.1, L15 (GND) to L16, tented both sides, 406 vias
v5: diameter 0.254, hole 0.1, L1 to L2 (GND), tented both sides, 283 vias
v6: diameter 0.457, hole 0.2, L3 (Sign) to L6 (PWR/GND), tented both sides, 254 vias
v7: diameter 0.254, hole 0.1, L1 to L3 (Sign), 237 vias
v8: diameter 0.75, hole 0.4, L1 to L16, 200 vias
v9: diameter 0.8, hole 0.4, L1 to L16, tented both sides, 182 vias
v10: diameter 0.254, hole 0.1, L14 (Sign) to L16, tented both sides, 170 vias
v11: diameter 0.75/0/0/0/0/0/0/0/0/0/0/0/0/0/0/0.75 (per signal layer), hole 0.4, L1 to L16, 160 vias
v12: diameter 0.457, hole 0.2, L3 (Sign) to L6 (PWR/GND), 158 vias
v13: diameter 1.4, hole 0.5, L1 to L16, tented both sides, 80 vias
v14: diameter 0.254, hole 0.1, L14 (Sign) to L16, 65 vias
v15: diameter 0.254, hole 0.1, L1 to L2 (GND), 45 vias
v16: diameter 0.457, hole 0.2, L11 (PWR/GND) to L14 (Sign), tented both sides, 26 vias
v17: diameter 0.457, hole 0.2, L11 (PWR/GND) to L14 (Sign), 25 vias
v18: diameter 0.457, hole 0.2, L7(12V+Other) to L10 (3V3+Other), tented both sides, 11 vias
v19: diameter 0.254/0/0.254 (per signal layer), hole 0.1, L1 to L3 (Sign), 9 vias
v20: diameter 0.2/0/0.2 (per signal layer), hole 0.1, L1 to L3 (Sign), 6 vias
v21: diameter 1.65, hole 1.65, L1 to L16, 5 vias
v22: diameter 1.15, hole 1.15, L1 to L16, 5 vias
v23: diameter 0.457, hole 0.2, L1 to L16, 3 vias
v24: diameter 0.5, hole 0.3, L1 to L16, 2 vias
v25: diameter 0.5/0/0.5 (per signal layer), hole 0.2, L14 (Sign) to L16, 1 vias
v26: diameter 0.5, hole 0.25, L1 to L16, tented bottom, 1 vias

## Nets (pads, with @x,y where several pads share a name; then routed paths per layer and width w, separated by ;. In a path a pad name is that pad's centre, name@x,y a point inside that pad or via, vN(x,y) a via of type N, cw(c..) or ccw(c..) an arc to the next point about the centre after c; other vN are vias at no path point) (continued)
Interrupt64: R930.1 R985.1 U1.AC17 | length 72.2
  L1 w0.12: R930.1@251.637,308.751 v1(251.637,309.607) R985.1@251.637,310.463
  L5 (Sign) w0.12: v12(184.092,304.336) 187.033,304.336 187.911,305.214 189.492,305.214 189.74,305.462 192.056,305.462 192.456,305.063 209.432,305.063 209.449,305.08 217.607,305.08 221.001,308.474 246.946,308.474 246.962,308.49 250.508,308.49 ; 250.514,308.484 v1(251.637,309.607)
  L3 (Sign) w0.12: v12(184.092,304.336) 184.157,304.336 184.361,304.539 v2(184.397,304.539)
Interrupt65: R932.1 R986.1 U1.AC18 | length 71
  L1 w0.12: R932.1@250.14,308.751 v1(250.14,309.607) R986.1@250.14,310.463
  L5 (Sign) w0.12: v12@183.95,305.057 184.215,304.792 187.178,304.792 187.82,305.434 189.125,305.434 189.397,305.706 192.123,305.706 192.547,305.283 209.341,305.283 209.358,305.3 217.516,305.3 220.91,308.694 246.855,308.694 246.879,308.718 249.251,308.718 v1(250.14,309.607)
  L3 (Sign) w0.12: v12(183.934,305.07) 183.934,305.073 184.397,305.536 v2(184.397,305.539)
Interrupt66: R934.1 R987.1 U1.AD19 | length 48
  L1 w0.12: v2(184.909,306.052) U1.AD19@185.397,306.539 ; R934.1@227.686,308.751 v2(227.686,309.607) R987.1@227.686,310.463
  L3 (Sign) w0.076: v2(184.909,306.052) 185.316,306.052 185.67,306.405 187.07,306.405 187.983,305.493 193.228,305.493 193.896,304.825
  L3 (Sign) w0.12: 193.896,304.825 215.864,304.825 219.926,308.888 226.966,308.888 v2(227.686,309.607)
Interrupt67: R936.1 R988.1 U1.AE19 | length 49.6
  L1 w0.12: v2(185.909,306.052) U1.AE19@186.397,306.539 ; R936.1@229.183,308.751 v2(229.183,309.607) R988.1@229.183,310.463
  L3 (Sign) w0.076: v2(185.909,306.052) 185.909,304.9 186.197,304.612 187.108,304.612 187.813,305.317 192.397,305.317 192.604,305.317 193.316,304.605 193.805,304.605
  L3 (Sign) w0.12: 193.805,304.605 215.955,304.605 220.018,308.668 228.243,308.668 v2(229.183,309.607)
Interrupt68: R938.1 R989.1 U1.AG16 | length 43.7
  L1 w0.12: v2(187.909,303.052) U1.AG16@188.397,303.539 ; R938.1@227.69,299.747 v2(227.69,300.816) R989.1@227.69,301.885
  L3 (Sign) w0.12: v2(187.909,303.052) 188.854,302.108 192.204,302.108 192.405,301.907 216.99,301.907 217.191,302.108 220.605,302.108 221.896,300.816 v2(227.69,300.816)
Interrupt69: R940.1 R990.1 U1.AH16 | length 57.9
  L1 w0.12: v2(188.909,303.052) U1.AH16@189.397,303.539 ; R940.1@241.158,308.751 v2(241.158,309.607) R990.1@241.158,310.463
  L3 (Sign) w0.12: v2(188.909,303.052) 189.319,303.052 189.695,303.428 192.128,303.428 192.77,302.787 216.626,302.787 220.747,306.908 238.459,306.908 v2(241.158,309.607)
Interrupt70: R942.1 R991.1 U1.AJ16 | length 61.6
  L1 w0.12: v2(189.909,303.052) U1.AJ16@190.397,303.539 ; R942.1@245.649,308.751 v2(245.649,309.607) R991.1@245.649,310.463
  L3 (Sign) w0.12: v2(189.909,303.052) 190.562,302.4 192.223,302.4 192.496,302.127 216.899,302.127 221.02,306.248 242.29,306.248 v2(245.649,309.607)
Interrupt71: R944.1 R992.1 U1.AK16 | length 51.7
  L1 w0.12: U1.AK16@191.397,303.539 191.397,303.543 191.869,304.014 v2(191.869,304.017) ; R944.1@238.164,308.751 v2(238.164,309.607) R992.1@238.164,310.463
  L3 (Sign) w0.12: v2(191.869,304.017) 191.905,304.017 192.037,303.885 192.294,303.885 192.952,303.227 216.443,303.227 220.564,307.348 235.905,307.348 v2(238.164,309.607)
Interrupt72: R946.1 R993.1 U1.AH17 | length 51.7
  L1 w0.12: v2(188.909,304.052) U1.AH17@189.397,304.539 ; R946.1@235.17,308.751 v2(235.17,309.607) R993.1@235.17,310.463
  L3 (Sign) w0.12: v2(188.909,304.052) 189.416,304.559 191.647,304.559 191.654,304.551 192.052,304.551 192.278,304.325 192.397,304.325 192.476,304.325 193.134,303.667 216.261,303.667 220.382,307.788 233.351,307.788 v2(235.17,309.607)
Interrupt73: R948.1 R994.1 U1.AJ17 | length 52.2
  L1 w0.12: v2(189.909,304.052) U1.AJ17@190.397,304.539 ; R948.1@236.667,308.751 v2(236.667,309.607) R994.1@236.667,310.463
  L3 (Sign) w0.12: v2(189.909,304.052) 190.196,304.339 191.555,304.339 191.563,304.331 191.961,304.331 192.187,304.105 192.385,304.105 192.397,304.093 193.043,303.447 216.352,303.447 220.473,307.568 234.628,307.568 v2(236.667,309.607)
Interrupt74: R950.1 R995.1 U1.AK17 | length 54.3
  L1 w0.12: v2(190.909,304.052) U1.AK17@191.397,304.539 ; R950.1@239.661,308.751 v2(239.661,309.607) R995.1@239.661,310.463
  L3 (Sign) w0.12: v2(190.909,304.052) 191.209,304.052 191.604,303.657 192.211,303.657 192.861,303.007 216.534,303.007 220.655,307.128 237.182,307.128 v2(239.661,309.607)
Interrupt75: R952.1 R996.1 U1.AK18 | length 47.1
  L1 w0.12: U1.AK18@191.397,305.539 191.397,305.51 192.069,304.838 192.149,304.838 192.375,304.612 v2(192.397,304.612) ; R952.1@233.674,308.751 v2(233.674,309.607) R996.1@233.674,310.463
  L3 (Sign) w0.12: v2(192.397,304.612) 192.423,304.586 192.526,304.586 193.225,303.887 216.17,303.887 220.291,308.008 232.074,308.008 v2(233.674,309.607)
Interrupt76: R954.1 R997.1 U1.AG18 | length 47.6
  L1 w0.12: v2(187.922,305.052) 187.922,305.058 188.397,305.533 U1.AG18@188.397,305.539 ; R954.1@230.68,308.751 v2(230.68,309.607) R997.1@230.68,310.463
  L3 (Sign) w0.076: v2(187.922,305.052) 192.213,305.052 192.214,305.053 192.397,305.053 192.58,305.053 192.581,305.052 192.62,305.052 193.345,304.327 193.407,304.327
  L3 (Sign) w0.12: 193.407,304.327 215.988,304.327 220.109,308.448 229.52,308.448 v2(230.68,309.607)
Interrupt77: R956.1 R998.1 U1.AH18 | length 48.7
  L1 w0.12: v2(188.92,304.705) 188.92,305.062 U1.AH18@189.397,305.539 ; R956.1@232.177,308.751 v2(232.177,309.607) R998.1@232.177,310.463
  L3 (Sign) w0.076: v2(188.92,304.705) 189.091,304.876 192.286,304.876 192.287,304.877 192.397,304.877 192.546,304.877 193.316,304.107
  L3 (Sign) w0.12: 193.316,304.107 216.079,304.107 220.2,308.228 230.797,308.228 v2(232.177,309.607)
Interrupt78: R958.1 R999.1 U1.AE18 | length 67.4
  L1 w0.12: R958.1@247.146,308.751 v1(247.146,309.607) R999.1@247.146,310.463
  L5 (Sign) w0.12: v12(186.392,305.202) 186.392,307.219 186.702,307.529 189.78,307.529 189.796,307.546 192.483,307.546 192.59,307.653 193.435,307.653 195.348,305.74 217.333,305.74 220.728,309.134 246.673,309.134 v1(247.146,309.607)
  L3 (Sign) w0.12: v12(186.392,305.202) 186.394,305.205 186.394,305.537 v7(186.397,305.539)
Interrupt79: R960.1 R1000.1 U1.AF18 | length 66.9
  L1 w0.12: v2(186.909,305.052) U1.AF18@187.397,305.539 ; R960.1@248.643,308.751 v1(248.643,309.607) R1000.1@248.643,310.463
  L5 (Sign) w0.12: v12(187.165,305.359) 187.242,305.359 188.458,306.574 194.202,306.574 195.257,305.52 217.425,305.52 220.819,308.914 246.764,308.914 246.797,308.947 247.983,308.947 v1(248.643,309.607)
  L3 (Sign) w0.12: v2(186.909,305.052) 186.909,305.104 v12(187.165,305.359)
JTAG_CLK: R1042.1 U39.20 | length 5.5
  L16 w0.12: R1042.1@107.214,286.337 107.214,285.495 107.632,285.077 108.269,285.077 109.049,284.297 U39.20@109.049,281.925
JTAG_TDI: R336.2 R1040.1 U39.23 | length 6.7
  L16 w0.12: U39.23@110.549,281.925 110.549,284.412 111.43,285.293 112.141,285.293 112.563,285.715 112.563,286.337 R336.2@113.633,286.337
JTAG_TDO: R337.2 R1043.1 U39.21 | length 5.6
  L16 w0.12: R1043.1@108.284,286.337 109.354,286.337 109.549,286.141 U39.21@109.549,281.925
JTAG_TMS: R338.2 R1041.1 U39.22 | length 5.6
  L16 w0.12: U39.22@110.049,281.925 110.049,285.322 110.424,285.696 110.424,286.337 R338.2@111.494,286.337
LED_0: R329.1 U39.47 | length 3.6
  L16 w0.12: R329.1@104.826,271.994 104.826,272.339 106.049,273.562 U39.47@106.049,275.125
LED_0_RJ: R329.2 T21.17 | length 66.8
  L12 (Sign) w0.12: T21.17@52.632,252.221 55.119,252.221 56.794,250.546 71.52,250.546 73.514,252.54 79.553,252.54 v16(80.315,253.301)
  L14 (Sign) w0.12: v16(80.315,253.301) 82.182,253.301 84.785,255.905 96.368,255.905 97.227,256.765 97.227,265.369 100.882,269.024 v10(102.129,269.024)
  L16 w0.12: v10(102.129,269.024) 102.235,268.917 102.719,268.917 104.311,270.51 104.787,270.51 104.826,270.548 R329.2@104.826,271.094
LED_1: R330.1 U39.46 | length 3.4
  L16 w0.12: R330.1@105.908,271.994 105.908,272.507 106.549,273.148 U39.46@106.549,275.125
LED_1_RJ: R330.2 T21.18 | length 67.6
  L12 (Sign) w0.12: T21.18@52.632,249.681 52.672,249.681 53.317,250.326 71.612,250.326 73.605,252.32 80.181,252.32 v16(80.739,252.877)
  L14 (Sign) w0.12: v16(80.739,252.877) 80.943,253.082 82.273,253.082 84.876,255.685 96.459,255.685 97.447,256.673 97.447,265.278 100.769,268.6 v10(101.704,268.6)
  L16 w0.12: v10(101.704,268.6) 102.712,268.6 104.402,270.29 105.774,270.29 105.908,270.424 R330.2@105.908,271.094
LED_2: R331.1 U39.45 | length 3.2
  L16 w0.12: R331.1@106.991,271.994 107.049,272.052 U39.45@107.049,275.125
LED_2_RJ: R331.2 T21.19 | length 73.5
  L12 (Sign) w0.12: T21.19@52.632,242.571 56.295,246.234 56.295,249.446 56.955,250.106 71.703,250.106 73.697,252.1 80.81,252.1 v16(81.163,252.453)
  L14 (Sign) w0.12: v16(81.163,252.453) 81.572,252.862 82.364,252.862 84.967,255.465 96.55,255.465 97.667,256.582 97.667,265.187 100.656,268.176 v10(101.28,268.176)
  L16 w0.12: v10(101.28,268.176) 102.599,268.176 104.493,270.07 106.595,270.07 106.991,270.466 R331.2@106.991,271.094
LED_3: R332.2 U39.39 | length 3.2
  L16 w0.12: U39.39@110.049,275.125 110.049,272.066 R332.2@110.122,271.994
LED_3_RJ: R332.1 T21.20 | length 78.9
  L12 (Sign) w0.12: T21.20@52.632,240.031 56.515,243.914 56.515,249.354 57.046,249.886 71.794,249.886 73.788,251.88 81.438,251.88 v16(81.588,252.029)
  L14 (Sign) w0.12: v16(81.588,252.029) 82.2,252.642 82.455,252.642 85.059,255.245 96.641,255.245 97.887,256.491 97.887,265.096 100.543,267.751 v10(100.856,267.751)
  L16 w0.12: v10(100.856,267.751) 102.486,267.751 104.584,269.85 109.497,269.85 110.122,270.475 R332.1@110.122,271.094
LTC6952_0_MATCH_Out0_N: C315.1 J1_PCIE0.7 R1054.1 | length 3.3
  L16 w0.101: R1054.1@166.682,355.586 166.682,356.378 ccw(c166.602,356.378) C315.1@166.602,356.458 ccw(c166.602,356.593) 166.737,356.593 J1_PCIE0.7@166.737,358.792
LTC6952_0_MATCH_Out0_P: C315.2 J1_PCIE0.5 R539.1 | length 3.3
  L16 w0.101: J1_PCIE0.5@167.537,358.792 167.537,356.573 ccw(c167.652,356.573) C315.2@167.652,356.458 ccw(c167.652,356.421) 167.615,356.421 R539.1@167.615,355.586
LTC6952_0_MATCH_Out1_N: C317.1 J1_PCIE3.7 R1056.1 | length 4.6
  L16 w0.101: C317.1@84.247,355.805 84.591,355.461 84.591,355.188 cw(c84.264,355.188) R1056.1@84.264,354.861 ; C317.1@84.251,355.809 ccw(c84.251,356.143) 84.585,356.143 84.585,358.592 ccw(c84.385,358.592) J1_PCIE3.7@84.385,358.792
LTC6952_0_MATCH_Out1_P: C317.2 J1_PCIE3.5 R1055.1 | length 4.7
  L16 w0.101: J1_PCIE3.5@85.185,358.792 ccw(c85.185,358.593) 84.986,358.593 84.986,356.125 ccw(c85.301,356.125) C317.2@85.301,355.809 84.992,355.809 84.992,355.201 ccw(c85.319,355.201) R1055.1@85.319,354.874
LTC6952_0_MATCH_Out2_N: C319.1 R1058.1 | length 1
  L16 w0.101: C319.1@88.078,343.159 cw(c88.078,343.104) 88.133,343.104 R1058.1@88.133,342.219
LTC6952_0_MATCH_Out2_P: C319.2 R1057.1 | length 1
  L16 w0.101: R1057.1@89.073,342.219 89.073,343.104 cw(c89.128,343.104) C319.2@89.128,343.159
LTC6952_0_MATCH_Out3_N: R535.1 R1074.1 U13.48 | length 7.5
  L1 w0.101: R1074.1@180.136,270.771 180.186,270.771 180.36,270.946 180.36,270.971 180.42,271.031 180.652,271.031 180.717,270.966 180.851,270.966 181.026,270.791 181.2,270.966 181.461,270.966 181.526,271.031 187.273,271.031 U13.48@187.323,270.981
LTC6952_0_MATCH_Out3_P: R535.2 R1073.1 U13.47 | length 7.5
  L1 w0.101: R1073.1@180.136,271.691 180.186,271.691 180.361,271.517 180.361,271.491 180.42,271.432 180.766,271.432 181.026,271.691 181.2,271.517 181.441,271.517 181.526,271.432 187.273,271.432 U13.47@187.323,271.481
LTC6952_0_MATCH_Out4_N: R534.2 R1072.2 U13.37 | length 5.6
  L1 w0.101: R1072.2@186.161,277.99 R534.2@187.263,277.99 ; R534.2@187.323,278.05 ccw(c187.622,278.05) 187.622,277.75 188.461,277.75 cw(c188.461,276.788) 189.423,276.788 189.423,275.181 ccw(c189.473,275.181) U13.37@189.473,275.131
LTC6952_0_MATCH_Out4_P: R534.1 R1071.2 U13.38 | length 5.6
  L1 w0.101: R1071.2@186.161,277.035 186.161,277.05 R534.1@187.323,277.05 cw(c187.622,277.05) 187.622,277.349 188.461,277.349 cw(c188.461,276.788) 189.022,276.788 189.022,276.71 189.022,276.355 cw(c188.916,276.355) 188.916,276.249 188.759,276.249 ccw(c188.759,276.142) 188.653,276.142 188.653,276.051 ccw(c188.759,276.051) 188.759,275.945 188.916,275.945 cw(c188.916,275.838) 189.022,275.838 189.022,275.374 189.022,275.181 cw(c188.973,275.181) U13.38@188.973,275.131
LTC6952_0_MATCH_Out5_N: C599.1 U12.18 | length 5.8
  L16 w0.101: C599.1@83.248,332.545 cw(c83.564,332.545) 83.564,332.86 88.748,332.86 cw(c88.748,332.811) U12.18@88.797,332.811
LTC6952_0_MATCH_Out5_P: C599.2 U12.19 | length 5.8
  L16 w0.101: C599.2@83.248,333.595 ccw(c83.582,333.595) 83.582,333.261 88.748,333.261 ccw(c88.748,333.311) U12.19@88.797,333.311
LTC6952_0_MATCH_Out6_N: C602.2 J27.53 R1068.1 | length 5.6
  L16 w0.101: R1068.1@132.674,313.055 132.724,313.055 132.898,312.88 132.898,312.845 132.958,312.786 133.103,312.786 133.197,312.879 133.658,312.879 133.883,313.104 134.107,312.879 134.107,312.838 134.166,312.779 135.615,312.779 135.66,312.824 137.794,312.824 J27.53@137.843,312.874
LTC6952_0_MATCH_Out6_P: C602.1 J27.55 R1067.1 | length 5.7
  L16 w0.101: R1067.1@132.631,312.115 132.681,312.115 132.855,312.29 132.855,312.317 132.923,312.385 133.103,312.385 133.21,312.278 133.658,312.278 133.883,312.054 134.107,312.278 134.107,312.319 134.166,312.378 135.781,312.378 135.826,312.423 137.794,312.423 J27.55@137.843,312.374
LTC6952_0_MATCH_Out7_N: C526.2 C608.1 U12.12 | length 88.2
  L14 (Sign) w0.081: v14(90.498,329.106) ccw(c90.498,328.946) 90.339,328.946 90.339,324.962 ccw(c90.746,324.962) 90.746,324.555 125.048,324.555 cw(c125.048,323.87) 125.733,323.87 125.733,323.723 ccw(c126.212,323.723) 126.212,323.244 133.475,323.244 ccw(c133.475,323.403) v14(133.635,323.403) ; v14(150.117,327.599) ccw(c150.277,327.599) 150.231,327.446 ccw(c150.277,327.599) 150.277,327.439 159.272,327.439 ccw(c159.272,327.8) 159.632,327.8 159.632,329.907 cw(c160.166,329.907) 160.166,330.441 160.208,330.441 ccw(c160.208,330.6) v14(160.368,330.6)
  L16 w0.101: 90.398,330.13 90.398,330.541 cw(c90.567,330.541) U12.12@90.447,330.661 ; 90.399,330.129 90.399,329.205 ccw(c90.498,329.205) v14(90.498,329.106) ; v14(133.635,323.403) ccw(c133.734,323.403) 133.734,323.304 134.318,323.304 ccw(c134.318,323.99) 135.004,323.99 135.004,326.773 cw(c136.737,326.773) 136.737,328.506 142.97,328.506 cw(c142.97,326.907) 144.101,328.038 144.412,327.727 ccw(c144.962,328.277) 144.962,327.499 150.018,327.499 ccw(c150.018,327.599) v14(150.117,327.599) ; v14(160.368,330.6) ccw(c160.467,330.6) 160.467,330.501 161.248,330.501 cw(c161.248,329.756) 161.993,329.756 161.993,329.485 ccw(c162.122,329.485) 162.122,329.356 C608.1@162.318,329.356 ccw(c162.318,329.27) 162.232,329.27 C526.2@162.232,328.355
LTC6952_0_MATCH_Out7_P: C525.2 C608.2 U12.13 | length 88.2
  L14 (Sign) w0.081: v14(89.898,329.106) cw(c89.898,328.946) 90.058,328.946 90.058,324.962 ccw(c90.746,324.962) 90.746,324.274 119.816,324.274 120.292,324.274 cw(c120.292,324.193) 120.373,324.193 120.373,324.179 ccw(c120.431,324.179) 120.431,324.121 120.701,324.121 ccw(c120.701,324.179) 120.759,324.179 120.759,324.193 cw(c120.84,324.193) 120.84,324.274 120.88,324.274 125.048,324.274 cw(c125.048,323.87) 125.452,323.87 125.452,323.723 ccw(c126.212,323.723) 126.212,322.963 133.475,322.963 cw(c133.475,322.803) v14(133.635,322.803) ; v14(150.117,326.999) cw(c150.277,326.999) 150.277,327.158 159.272,327.158 ccw(c159.272,327.8) 159.913,327.8 159.913,329.907 cw(c160.166,329.907) 160.166,330.16 160.208,330.16 cw(c160.208,330) v14(160.368,330)
  L16 w0.101: v14(89.898,329.106) ccw(c89.898,329.205) 89.998,329.205 89.998,329.963 ; U12.13@89.947,330.661 cw(c89.828,330.541) 89.997,330.541 89.997,329.964 ; v14(133.635,322.803) cw(c133.734,322.803) 133.734,322.903 134.318,322.903 ccw(c134.318,323.99) 135.405,323.99 135.405,326.773 cw(c136.737,326.773) 136.737,328.105 142.969,328.105 cw(c142.969,326.905) 143.818,327.754 144.13,327.442 ccw(c144.959,328.271) 144.959,327.098 150.018,327.098 cw(c150.018,326.999) v14(150.117,326.999) ; v14(160.368,330) cw(c160.467,330) 160.467,330.1 161.248,330.1 cw(c161.248,329.756) 161.592,329.756 161.592,329.485 cw(c161.462,329.485) 161.462,329.356 C608.2@161.267,329.356 cw(c161.267,329.28) 161.343,329.28 C525.2@161.343,328.348
LTC6952_0_MATCH_Out8_N: C528.2 C682.1 U12.9 | length 79.7
  L14 (Sign) w0.081: v14(91.997,328.803) ccw(c91.997,328.644) 91.838,328.644 91.838,326.541 ccw(c92.938,326.541) 92.938,325.441 132.81,325.441 ccw(c132.81,325.601) v14(132.969,325.601) ; v14(149.219,328.633) ccw(c149.379,328.633) 149.379,328.473 155.875,328.473 ccw(c155.875,328.933) 156.335,328.933 156.335,329.945 cw(c156.963,329.945) 156.963,330.573 157.082,330.573 ccw(c157.082,330.732) v14(157.241,330.732)
  L16 w0.101: U12.9@91.947,330.661 ccw(c92.067,330.541) 91.898,330.541 91.898,328.902 ccw(c91.997,328.902) v14(91.997,328.803) ; v14(132.969,325.601) ccw(c133.068,325.601) 133.068,325.501 133.559,325.501 ccw(c133.559,325.838) 133.896,325.838 133.896,328.108 cw(c135.523,328.108) 135.523,329.735 143.172,329.735 cw(c143.172,327.461) 144.78,329.069 144.788,329.061 ccw(c146.062,330.335) 146.062,328.533 149.12,328.533 ccw(c149.12,328.633) v14(149.219,328.633) ; v14(157.241,330.732) ccw(c157.341,330.732) 157.341,330.633 157.852,330.633 cw(c157.852,329.75) 158.735,329.75 158.735,329.645 ccw(c159.072,329.645) C682.1@159.072,329.308 ccw(c159.072,329.236) 159,329.236 C528.2@159,328.397
LTC6952_0_MATCH_Out8_P: C527.2 C682.2 U12.10 | length 79.7
  L14 (Sign) w0.081: v14(91.397,328.803) cw(c91.397,328.644) 91.557,328.644 91.557,326.541 ccw(c92.938,326.541) 92.938,325.16 119.835,325.16 120.072,325.16 cw(c120.072,325.079) 120.153,325.079 120.153,325.059 ccw(c120.211,325.059) 120.211,325.001 120.481,325.001 ccw(c120.481,325.059) 120.538,325.059 120.538,325.079 cw(c120.619,325.079) 120.619,325.16 120.66,325.16 132.81,325.16 cw(c132.81,325.001) v14(132.969,325.001) ; v14(149.219,328.033) cw(c149.379,328.033) 149.379,328.192 155.875,328.192 ccw(c155.875,328.933) 156.616,328.933 156.616,329.945 cw(c156.963,329.945) 156.963,330.292 157.082,330.292 cw(c157.082,330.132) v14(157.241,330.132)
  L16 w0.101: v14(91.397,328.803) ccw(c91.397,328.902) 91.497,328.902 91.497,330.541 ccw(c91.328,330.541) U12.10@91.447,330.661 ; v14(132.969,325.001) cw(c133.068,325.001) 133.068,325.1 133.559,325.1 ccw(c133.559,325.838) 134.297,325.838 134.297,328.108 cw(c135.523,328.108) 135.523,329.334 143.171,329.334 cw(c143.171,327.459) 144.497,328.785 144.507,328.775 ccw(c146.058,330.327) 146.058,328.132 149.12,328.132 cw(c149.12,328.033) v14(149.219,328.033) ; v14(157.241,330.132) cw(c157.341,330.132) 157.341,330.232 157.852,330.232 cw(c157.852,329.75) 158.334,329.75 158.334,329.62 cw(c158.022,329.62) C682.2@158.022,329.308 cw(c158.022,329.23) 158.101,329.23 C527.2@158.101,328.397
LTC6952_0_MATCH_Out9_N: C530.2 C684.1 U12.6 | length 70.3
  L14 (Sign) w0.081: v14(98.019,328.114) ccw(c98.179,328.114) 98.179,327.955 131.855,327.955 ccw(c131.855,328.047) 131.947,328.047 v14(131.947,328.114) ; v14(150.443,329.622) cw(c150.443,329.387) 150.609,329.553 ccw(c150.828,329.772) 150.828,329.463 151.115,329.463 ccw(c151.115,331.233) 152.367,329.981 cw(c153.618,328.73) 153.618,330.5 154.524,330.5 ccw(c154.524,330.581) 154.582,330.523 ccw(c154.524,330.581) 154.605,330.581 v14(154.605,330.659)
  L16 w0.101: U12.6@93.447,330.661 ccw(c93.567,330.541) 93.398,330.541 93.398,328.52 ccw(c93.903,328.52) 93.903,328.015 97.92,328.015 ccw(c97.92,328.114) v14(98.019,328.114) ; v14(131.947,328.114) ccw(c132.047,328.114) 132.047,328.015 132.473,328.015 ccw(c132.473,328.298) 132.756,328.298 132.756,329.718 cw(c133.839,329.718) 133.839,330.801 143.975,330.801 cw(c143.975,328.918) 145.307,330.25 145.491,330.065 ccw(c146.801,331.375) 146.801,329.523 150.283,329.523 ccw(c150.283,329.668) 150.386,329.565 v14(150.443,329.622) ; v14(154.605,330.659) 154.796,330.659 cw(c154.796,329.612) 155.843,329.612 155.843,329.587 ccw(c156.17,329.587) C684.1@156.17,329.26 ccw(c156.17,329.199) 156.108,329.199 C530.2@156.108,328.376
LTC6952_0_MATCH_Out9_P: C529.2 C684.2 U12.7 | length 70.2
  L14 (Sign) w0.081: v14(98.019,327.514) cw(c98.179,327.514) 98.179,327.674 131.855,327.674 cw(c131.855,327.582) 131.947,327.582 v14(131.947,327.514) ; v14(150.443,329.022) ccw(c150.443,329.258) 150.609,329.091 cw(c150.828,328.873) 150.828,329.182 151.232,329.182 ccw(c151.232,330.952) 152.483,329.7 cw(c153.735,328.449) 153.735,330.219 154.524,330.219 cw(c154.524,330.138) 154.582,330.195 cw(c154.524,330.138) 154.605,330.138 v14(154.605,330.059)
  L16 w0.101: U12.7@92.947,330.661 cw(c92.828,330.541) 92.997,330.541 92.997,328.52 ccw(c93.903,328.52) 93.903,327.614 97.92,327.614 cw(c97.92,327.514) v14(98.019,327.514) ; v14(131.947,327.514) cw(c132.047,327.514) 132.047,327.614 132.473,327.614 ccw(c132.473,328.298) 133.157,328.298 133.157,329.718 cw(c133.839,329.718) 133.839,330.4 143.97,330.4 cw(c143.97,328.907) 145.026,329.963 145.208,329.781 ccw(c146.8,331.373) 146.8,329.122 150.283,329.122 150.34,329.065 ccw(c150.443,329.167) v14(150.443,329.022) ; v14(154.605,330.059) 154.995,330.059 cw(c154.995,329.612) 155.442,329.612 155.442,329.582 cw(c155.12,329.582) C684.2@155.12,329.26 cw(c155.12,329.171) 155.208,329.171 C529.2@155.208,328.376
LTC6952_0_Out0_N: C54.2 R1054.2 U12.33 | length 96.4
  L12 (Sign) w0.081: v17(143.513,351.831) 143.513,351.765 143.509,351.761 143.496,351.774 ccw(c143.606,351.774) 143.606,351.664 144.35,351.664 166.576,351.664 ccw(c166.576,352.085) 166.997,352.085 166.997,352.385 166.997,352.621 ccw(c166.837,352.621) v17(166.837,352.781)
  L14 (Sign) w0.081: v14(92.397,339.175) ccw(c92.397,339.335) 92.557,339.335 92.557,341.865 cw(c93.931,341.865) 93.931,343.239 94.397,343.239 ccw(c94.397,344.008) 95.166,344.008 95.166,353.277 cw(c96.314,353.277) 96.314,354.425 96.62,354.425 140.58,354.425 cw(c140.58,353.443) 141.562,353.443 141.562,352.001 ccw(c141.899,352.001) 141.899,351.664 143.387,351.664 ccw(c143.387,351.774) 143.496,351.774 143.509,351.761 143.513,351.765 v17(143.513,351.831) ; v17(166.837,352.781) ccw(c166.837,352.94) 166.997,352.94 166.997,353.154 166.837,353.154 v14(166.837,353.046)
  L16 w0.101: v14(92.397,339.175) cw(c92.397,339.076) 92.497,339.076 92.497,337.51 cw(c92.447,337.51) U12.33@92.447,337.461 ; R1054.2@166.682,354.586 cw(c166.682,354.321) 166.948,354.321 166.948,353.896 cw(c166.612,353.896) C54.2@166.612,353.56 cw(c166.612,353.335) 166.837,353.335 v14(166.837,353.046)
LTC6952_0_Out0_P: C54.1 R539.2 U12.34 | length 96.4
  L12 (Sign) w0.081: v17(143.504,351.224) 143.504,351.266 143.496,351.274 cw(c143.606,351.274) 143.606,351.383 144.35,351.383 166.576,351.383 ccw(c166.576,352.085) 167.278,352.085 167.278,352.621 cw(c167.437,352.621) v17(167.437,352.781)
  L14 (Sign) w0.081: v14(92.997,339.175) cw(c92.997,339.335) 92.838,339.335 92.838,341.865 cw(c93.931,341.865) 93.931,342.958 94.397,342.958 ccw(c94.397,344.008) 95.447,344.008 95.447,353.277 cw(c96.314,353.277) 96.314,354.144 96.62,354.144 140.58,354.144 cw(c140.58,353.443) 141.281,353.443 141.281,352.001 ccw(c141.899,352.001) 141.899,351.383 143.387,351.383 cw(c143.387,351.274) 143.496,351.274 143.504,351.266 v17(143.504,351.224) ; v17(167.437,352.781) cw(c167.437,352.94) 167.278,352.94 167.278,353.154 167.437,353.154 v14(167.437,353.046)
  L16 w0.101: U12.34@92.947,337.461 cw(c92.947,337.51) 92.898,337.51 92.898,339.076 cw(c92.997,339.076) v14(92.997,339.175) ; v14(167.437,353.046) 167.437,353.335 cw(c167.662,353.335) C54.1@167.662,353.56 cw(c167.662,353.874) 167.349,353.874 167.349,354.321 cw(c167.615,354.321) R539.2@167.615,354.587
LTC6952_0_Out1_N: C316.2 R1056.2 U12.30 | length 22.7
  L16 w0.101: R1056.2@84.264,353.861 cw(c84.264,353.535) 84.591,353.535 84.591,353.219 cw(c84.273,353.219) C316.2@84.273,352.901 cw(c84.273,352.576) 84.597,352.576 84.597,346.121 ccw(c85.683,346.121) 85.683,345.036 90.542,345.036 cw(c90.542,344.581) 90.997,344.581 90.997,337.51 cw(c90.947,337.51) U12.30@90.947,337.461
LTC6952_0_Out1_P: C316.1 R1055.2 U12.31 | length 22.7
  L16 w0.101: R1055.2@85.319,353.874 ccw(c85.319,353.548) 84.992,353.548 84.992,353.232 ccw(c85.323,353.232) C316.1@85.323,352.901 ccw(c85.323,352.576) 84.998,352.576 84.998,346.121 ccw(c85.683,346.121) 85.683,345.437 90.542,345.437 cw(c90.542,344.581) 91.398,344.581 91.398,337.51 ccw(c91.447,337.51) U12.31@91.447,337.461
LTC6952_0_Out2_N: C318.2 R1058.2 U12.27 | length 4.9
  L16 w0.101: R1058.2@88.133,341.219 cw(c88.133,340.949) 88.403,340.949 88.403,340.601 cw(c88.091,340.601) C318.2@88.091,340.289 cw(c88.091,339.965) 88.415,339.965 88.415,339.472 ccw(c89.19,339.472) 89.19,338.697 cw(c89.19,338.39) 89.497,338.39 89.497,337.51 cw(c89.447,337.51) U12.27@89.447,337.461
LTC6952_0_Out2_P: C318.1 R1057.2 U12.28 | length 4.9
  L16 w0.101: R1057.2@89.073,341.219 ccw(c89.073,340.95) 88.804,340.95 88.804,340.626 ccw(c89.141,340.626) C318.1@89.141,340.289 ccw(c89.141,339.965) 88.816,339.965 88.816,339.472 ccw(c89.19,339.472) 89.19,339.098 cw(c89.19,338.39) 89.898,338.39 89.898,337.51 ccw(c89.947,337.51) U12.28@89.947,337.461
LTC6952_0_Out3_N: C594.1 R1073.2 U12.24 | length 160.6
  L1 w0.101: v20@140.947,270.763 168.86,270.763 168.911,270.763 ccw(c168.911,270.87) 169.017,270.87 169.017,271.218 cw(c169.124,271.218) 169.124,271.325 169.215,271.325 cw(c169.215,271.218) 169.321,271.218 169.321,270.87 ccw(c169.428,270.87) 169.428,270.763 169.62,270.763 171.694,270.763 ccw(c171.694,271.53) 172.236,270.988 172.35,271.101 cw(c173.145,270.306) 173.145,271.43 173.146,271.432 173.784,271.432 173.787,271.429 176.14,271.429 177.758,271.429 177.818,271.488 177.818,271.529 178.042,271.753 C594.1@178.092,271.753 178.142,271.753 178.367,271.529 178.367,271.488 178.426,271.429 178.514,271.429 178.517,271.432 178.852,271.432 178.912,271.491 178.912,271.517 179.086,271.691 R1073.2@179.136,271.691
  L5 (Sign) w0.081: v1(85.006,296.697) 85.006,296.599 84.847,296.44 84.847,296.331 84.847,293.594 ccw(c86.275,293.594) 85.265,292.584 105.72,272.129 ccw(c107.516,273.925) 107.516,271.385 135.71,271.385 cw(c135.71,269.556) 137.004,270.85 ccw(c137.316,271.161) 137.316,270.72 139.967,270.72 140.126,270.879 v12(140.224,270.879)
  L12 (Sign) w0.081: 83.035,320.307 78.216,325.126 cw(c79.729,326.639) 77.589,326.639 77.589,332.417 cw(c80.064,332.417) 78.314,334.167 79.323,335.176 cw(c81.119,333.38) 81.119,335.92 86.999,335.92 cw(c86.999,335.759) v1(87.16,335.759) ; 83.063,320.279 83.971,319.37 cw(c81.979,317.378) 84.797,317.378 84.797,297.021 ccw(c84.984,297.021) 84.852,296.889 cw(c84.719,296.757) 84.906,296.757 84.967,296.697 v1(85.006,296.697)
  L3 (Sign) w0.081: v12(140.224,270.879) 140.224,270.741 140.202,270.72 140.938,270.72 v20(140.947,270.729)
  L16 w0.101: v1(87.16,335.759) cw(c87.262,335.759) 87.262,335.86 88.748,335.86 cw(c88.748,335.811) U12.24@88.797,335.811
LTC6952_0_Out3_P: C594.2 R1074.2 U12.25 | length 160.6
  L1 w0.101: v20(140.947,270.429) 141.015,270.362 171.696,270.362 ccw(c171.696,271.525) 172.518,270.703 172.63,270.814 cw(c173.149,270.295) 173.149,271.029 173.151,271.028 175.974,271.028 177.758,271.028 177.818,270.969 177.818,270.928 178.042,270.703 C594.2@178.092,270.703 178.142,270.703 178.367,270.928 178.367,270.969 178.426,271.028 178.68,271.028 178.683,271.031 178.852,271.031 178.911,270.971 178.911,270.946 179.086,270.771 R1074.2@179.136,270.771
  L5 (Sign) w0.081: v1(84.406,296.697) 84.406,296.599 84.566,296.44 84.566,296.214 84.566,293.591 ccw(c86.269,293.591) 85.065,292.387 105.522,271.93 ccw(c107.515,273.924) 107.515,271.104 135.709,271.104 cw(c135.709,269.554) 136.805,270.65 ; 136.806,270.65 ccw(c137.315,271.16) 137.315,270.439 139.967,270.439 140.126,270.279 v12(140.224,270.279)
  L12 (Sign) w0.081: v1(84.406,296.697) 84.406,296.757 cw(c84.593,296.757) 84.461,296.889 ccw(c84.329,297.021) 84.516,297.021 84.516,317.377 ccw(c81.976,317.377) 83.772,319.173 78.016,324.929 cw(c79.725,326.637) 77.308,326.637 77.308,332.418 cw(c80.062,332.418) 78.115,334.365 79.125,335.376 cw(c81.118,333.383) 81.118,336.201 86.999,336.201 ccw(c86.999,336.363) v1(87.16,336.363)
  L3 (Sign) w0.081: v12(140.224,270.279) 140.224,270.417 140.202,270.439 140.938,270.439 v20(140.947,270.429)
  L16 w0.101: v1(87.16,336.363) ccw(c87.262,336.363) 87.262,336.261 88.748,336.261 ccw(c88.748,336.311) U12.25@88.797,336.311
LTC6952_0_Out4_N: C478.2 R1072.1 U12.21 | length 166.1
  L1 w0.101: v20(141.025,272.259) 141.445,272.259 167.203,272.259 167.254,272.259 ccw(c167.254,272.419) 167.414,272.419 167.414,272.737 cw(c167.574,272.737) 167.574,272.897 167.711,272.897 cw(c167.711,272.737) 167.87,272.737 167.87,272.419 ccw(c168.03,272.419) 168.03,272.259 168.58,272.259 171.857,272.259 ccw(c171.857,273.291) 172.587,272.562 177.351,277.326 cw(c178.397,276.28) 178.397,277.759 183.914,277.759 ccw(c183.914,278.084) C478.2@184.239,278.084 ; C478.2@184.332,277.99 R1072.1@185.161,277.99
  L5 (Sign) w0.081: v3(86.303,297.269) cw(c86.067,297.269) 86.234,297.103 ccw(c86.453,296.884) 86.143,296.884 86.143,293.946 ccw(c88.512,293.946) 86.837,292.271 106.205,272.903 ccw(c107.869,274.567) 107.869,272.213 124.394,272.213 ccw(c124.427,272.247) 124.427,272.199 140.24,272.199 140.4,272.359 v12(140.497,272.359)
  L3 (Sign) w0.081: v12(140.497,272.359) 140.57,272.359 140.729,272.199 140.932,272.199 140.992,272.259 v20(141.025,272.259)
  L16 w0.101: v3(86.303,297.269) 86.203,297.269 cw(c86.322,297.388) 86.153,297.388 86.153,298.228 cw(c88.002,298.228) 86.695,299.535 89.173,302.014 ccw(c88.095,303.093) 89.62,303.093 89.62,308.32 ccw(c86.687,308.32) 88.761,310.394 87.471,311.684 cw(c88.249,312.462) 87.148,312.462 87.148,325.661 ccw(c86.243,325.661) 86.243,326.566 82.358,326.566 cw(c82.358,327.207) 81.718,327.207 81.718,333.753 cw(c82.325,333.753) 82.325,334.36 88.748,334.36 cw(c88.748,334.311) U12.21@88.797,334.311
LTC6952_0_Out4_P: C478.1 R1071.1 U12.22 | length 166.2
  L1 w0.101: v20(141.025,271.858) 141.445,271.858 171.86,271.858 ccw(c171.86,273.285) 172.869,272.276 177.517,276.925 cw(c178.563,275.879) 178.563,277.358 183.914,277.358 cw(c183.914,277.033) C478.1@184.239,277.035 ; C478.1@184.239,277.033 ccw(c183.914,277.033) C478.1@184.239,277.035 ; R1071.1@185.161,277.035 C478.1@184.239,277.035
  L5 (Sign) w0.081: v3(85.703,297.269) ccw(c85.938,297.269) 85.771,297.103 cw(c85.553,296.884) 85.862,296.884 85.862,293.944 ccw(c88.508,293.944) 86.637,292.073 106.008,272.702 ccw(c107.867,274.562) 107.867,271.932 124.277,271.932 ccw(c124.311,271.966) 124.311,271.918 140.24,271.918 140.4,271.759 v12(140.497,271.759)
  L3 (Sign) w0.081: v12(140.497,271.759) 140.57,271.759 140.729,271.918 140.932,271.918 140.992,271.858 v20(141.025,271.858)
  L16 w0.101: v3(85.703,297.269) ccw(c85.583,297.388) 85.752,297.388 85.752,298.233 cw(c87.99,298.233) 86.408,299.815 88.888,302.295 ccw(c88.087,303.096) 89.219,303.096 89.219,308.316 ccw(c86.679,308.316) 88.475,310.113 87.186,311.402 cw(c88.244,312.46) 86.747,312.46 86.747,325.661 ccw(c86.243,325.661) 86.243,326.165 82.358,326.165 cw(c82.358,327.207) 81.317,327.207 81.317,333.753 cw(c82.325,333.753) 82.325,334.761 88.748,334.761 ccw(c88.748,334.811) U12.22@88.797,334.811
LTC6952_0_Out6_N: C601.1 R1068.2 U12.15 | length 66.5
  L14 (Sign) w0.081: v14(86.747,329.438) ccw(c86.747,329.279) 86.588,329.279 86.588,323.908 ccw(c87.535,323.908) 87.535,322.961 117.676,322.961 117.892,322.961 ccw(c117.892,323.042) 117.973,323.042 117.973,323.26 cw(c118.03,323.26) 118.03,323.318 118.301,323.318 cw(c118.301,323.26) 118.358,323.26 118.358,323.042 ccw(c118.439,323.042) 118.439,322.961 118.866,322.961 120.236,322.961 cw(c120.236,322.059) 121.137,322.059 121.137,321.858 121.137,321.818 ccw(c121.218,321.818) 121.218,321.737 121.361,321.737 cw(c121.361,321.679) 121.419,321.679 121.419,321.409 cw(c121.361,321.409) 121.361,321.351 121.218,321.351 ccw(c121.218,321.27) 121.137,321.27 121.137,321.002 121.137,313.172 ccw(c121.57,313.172) 121.57,312.738 128.739,312.738 129.647,312.738 ccw(c129.647,312.898) v10(129.807,312.898)
  L16 w0.101: v14(86.747,329.438) cw(c86.747,329.537) 86.648,329.537 86.648,330.899 cw(c87.109,330.899) 87.109,331.36 88.678,331.36 cw(c88.678,331.191) U12.15@88.797,331.311 ; v10(129.807,312.898) 129.883,312.821 130.042,312.821 130.065,312.798 130.354,312.798 130.413,312.857 130.413,312.898 130.638,313.123 C601.1@130.688,313.123 130.738,313.123 130.962,312.898 130.962,312.857 131.025,312.795 131.39,312.795 131.449,312.854 131.449,312.88 131.624,313.055 R1068.2@131.674,313.055
LTC6952_0_Out6_P: C601.2 R1067.2 U12.16 | length 66.5
  L14 (Sign) w0.081: v14(86.147,329.438) cw(c86.147,329.279) 86.307,329.279 86.307,323.908 ccw(c87.535,323.908) 87.535,322.68 120.236,322.68 cw(c120.236,322.059) 120.856,322.059 120.856,313.172 ccw(c121.57,313.172) 121.57,312.457 128.739,312.457 129.647,312.457 cw(c129.647,312.298) v10(129.807,312.298)
  L16 w0.101: v14(86.147,329.438) ccw(c86.147,329.537) 86.247,329.537 86.247,330.899 cw(c87.109,330.899) 87.109,331.761 88.678,331.761 ccw(c88.678,331.93) U12.16@88.797,331.811 ; v10(129.807,312.298) 129.883,312.374 130.042,312.374 130.065,312.397 130.354,312.397 130.413,312.338 130.413,312.297 130.638,312.073 C601.2@130.688,312.073 130.738,312.073 130.962,312.297 130.962,312.334 131.022,312.394 131.347,312.394 131.406,312.334 131.406,312.29 131.581,312.115 R1067.2@131.631,312.115
LTC6952_0_Out10_N: C48.2 R82.1 U12.3 | length 13.4
  L14 (Sign) w0.081: v14(94.997,328.803) ccw(c94.997,328.644) 94.838,328.644 94.838,327.197 ccw(c95.468,327.197) 95.468,326.567 102.046,326.567 ccw(c102.046,326.726) v10(102.206,326.726) cw(c102.096,326.726) 102.096,326.616
  L16 w0.101: U12.3@94.947,330.661 ccw(c94.947,330.611) 94.898,330.611 94.898,328.902 ccw(c94.997,328.902) v14(94.997,328.803) ; v10(102.206,326.726) 102.789,326.726 ccw(c102.789,326.921) R82.1@102.984,326.921 103.802,326.921 C48.2@103.802,326.935
LTC6952_0_Out10_P: C47.2 R82.2 U12.4 | length 13.6
  L14 (Sign) w0.081: v14(94.397,328.803) cw(c94.397,328.644) 94.557,328.644 94.557,327.197 ccw(c95.468,327.197) 95.468,326.286 102.046,326.286 cw(c102.046,326.126) v10(102.206,326.126)
  L16 w0.101: v14(94.397,328.803) ccw(c94.397,328.902) 94.497,328.902 94.497,330.611 ccw(c94.447,330.611) U12.4@94.447,330.661 ; v10(102.206,326.126) 102.779,326.126 cw(c102.779,325.921) R82.2@102.984,325.921 C47.2@103.802,325.921
LTC6952_0_REF_N: C43.1 R78.2 U12.45 | length 4.1
  L16 w0.101: U12.45@96.597,334.811 96.647,334.761 98.979,334.761 ccw(c98.979,335.075) R78.2@99.293,335.075 ccw(c99.592,335.075) 99.592,334.775 99.837,334.775 ccw(c99.837,335.064) C43.1@100.126,335.064
LTC6952_0_REF_P: C44.1 R78.1 U12.46 | length 4
  L16 w0.101: U12.46@96.597,334.311 96.647,334.36 99.007,334.36 cw(c99.007,334.075) R78.1@99.293,334.075 cw(c99.592,334.075) 99.592,334.374 99.792,334.374 cw(c99.792,334.061) C44.1@100.106,334.061
LTC6952_1_C_N: J5.2 R270.1 R1080.2 | length 4.5
  L16 w0.101: J5.2@176.331,278.518 cw(c176.331,277.97) 176.88,277.97 176.88,276.111 cw(c176.58,276.111) R270.1@176.58,275.811 cw(c176.58,275.512) 176.88,275.512 176.88,275.071 cw(c176.63,275.071) R1080.2@176.63,274.822
LTC6952_1_C_Out10_N: C52.1 J6.2 | length 7.7
  L16 w0.101: J6.2@179.47,267.716 178.844,267.716 178.785,267.657 178.785,266.931 178.785,265.419 178.785,265.168 ccw(c178.899,265.168) 178.899,265.054 178.999,265.054 cw(c178.999,264.94) 179.113,264.94 179.113,264.914 cw(c178.999,264.914) 178.999,264.8 178.899,264.8 ccw(c178.899,264.686) 178.785,264.686 178.785,264.383 178.785,263.827 ccw(c179.465,263.827) 179.465,263.148 180.577,263.148 ccw(c180.577,263.449) C52.1@180.878,263.449
LTC6952_1_C_Out10_P: C51.1 J7.2 | length 7.8
  L16 w0.101: J7.2@177.699,267.716 178.325,267.716 178.384,267.657 178.384,266.765 178.384,263.827 ccw(c179.465,263.827) 179.465,262.747 180.577,262.747 cw(c180.577,262.445) C51.1@180.878,262.445
LTC6952_1_C_P: J4.2 R270.2 R1077.2 | length 4.5
  L16 w0.101: R1077.2@177.53,274.822 cw(c177.53,275.071) 177.281,275.071 177.281,275.512 cw(c177.58,275.512) R270.2@177.58,275.811 cw(c177.58,276.111) 177.281,276.111 177.281,277.979 cw(c177.82,277.979) J4.2@177.82,278.518
LTC6952_1_CP_Out: C46.2 R77.2 TP19.1 U12.43 X1.2 | length 35.2
  L1 w0.2: R77.2@98.489,342.772 99.287,342.772 99.289,342.773 ; C46.2@98.57,340.652 99.238,340.652 99.289,340.601 ; TP19.1@100.425,361.34 102.311,361.34 X1.2@105.994,357.657
  L1 w0.3: v1(99.289,337.49) 99.289,340.601 99.289,342.773 99.289,345.338 102.538,348.588 102.538,351.674 105.994,355.13 X1.2@105.994,357.657
  L16 w0.12: U12.43@96.597,335.811 97.989,335.811 99.289,337.11 v1(99.289,337.49)
LTC6952_1_MATCH_Out0_N: C41.2 C119.2 U1.D9 | length 23.8
  L1 w0.1: U1.D9@165.397,296.539 v2(165.884,297.027)
  L1 w0.101: v7(162.133,283.502) ccw(c162.133,283.477) 162.109,283.477 162.109,282.6 ccw(c162.769,282.6) 162.769,281.94 163.216,281.94 ccw(c163.216,282.249) C41.2@163.525,282.249 ccw(c163.595,282.249) 163.595,282.179 C119.2@164.31,282.179
  L3 (Sign) w0.081: v7(162.133,283.502) cw(c162.133,283.595) 162.04,283.595 162.04,288.283 ccw(c159.221,288.283) 161.214,290.276 160.668,290.822 cw(c161.232,291.386) 160.434,291.386 160.434,293.634 160.434,294.009 cw(c160.534,294.009) 160.534,294.109 160.579,294.109 ccw(c160.579,294.209) 160.679,294.209 160.679,294.343 ccw(c160.579,294.343) 160.579,294.443 160.534,294.443 cw(c160.534,294.543) 160.434,294.543 160.434,294.894 160.434,295.284 cw(c161.389,295.284) 161.389,296.239 162.828,296.239 163.202,296.239 cw(c163.202,296.138) 163.302,296.138 163.302,296.085 ccw(c163.403,296.085) 163.403,295.985 163.536,295.985 ccw(c163.536,296.085) 163.636,296.085 163.636,296.138 cw(c163.737,296.138) 163.737,296.239 164.098,296.239 165.031,296.239 ccw(c165.031,296.745) 165.537,296.745 cw(c165.819,296.745) 165.819,297.027 v2(165.884,297.027)
LTC6952_1_MATCH_Out0_P: C41.1 C118.2 U1.D10 | length 23.8
  L1 w0.1: v2(164.909,297.052) U1.D10@165.397,297.539
  L1 w0.101: v7(161.683,283.502) cw(c161.683,283.477) 161.708,283.477 161.708,282.6 ccw(c162.769,282.6) 162.769,281.539 163.185,281.539 cw(c163.185,281.199) C41.1@163.525,281.199 cw(c163.593,281.199) 163.593,281.267 C118.2@164.313,281.267
  L3 (Sign) w0.081: v7(161.683,283.502) ccw(c161.683,283.577) 161.759,283.577 161.759,288.282 ccw(c159.219,288.282) 161.015,290.078 160.468,290.624 cw(c161.229,291.385) 160.153,291.385 160.153,295.284 cw(c161.389,295.284) 161.389,296.52 165.031,296.52 ccw(c165.031,296.745) 165.256,296.745 ccw(c164.949,296.745) 164.949,297.052 v2(164.909,297.052)
LTC6952_1_MATCH_Out1_N: C799.2 R1092.1 U1.AH2 | length 6.7
  L1 w0.1: U1.AH2@189.397,289.539 v2(189.884,290.027)
  L1 w0.101: v2(193.167,290.242) 193.234,290.242 193.327,290.335 193.773,290.335 193.832,290.275 193.832,290.239 194.057,290.014 C799.2@194.107,290.014 194.157,290.014 194.381,290.239 194.381,290.28 194.44,290.339 194.721,290.339 194.785,290.275 194.785,290.243 194.959,290.068 R1092.1@195.009,290.068
  L3 (Sign) w0.081: v2(189.884,290.027) 189.884,290.339 189.932,290.386 192.892,290.386 192.9,290.395 192.985,290.395 193.137,290.242 v2(193.167,290.242)
LTC6952_1_MATCH_Out1_P: C799.1 R1091.1 U1.AH3 | length 6.7
  L1 w0.1: U1.AH3@189.397,290.539 189.873,291.015 v2(189.908,291.015)
  L1 w0.101: v2(193.167,290.828) 193.234,290.828 193.327,290.736 193.769,290.736 193.832,290.799 193.832,290.84 194.057,291.064 C799.1@194.107,291.064 194.157,291.064 194.381,290.84 194.381,290.799 194.44,290.74 194.726,290.74 194.785,290.799 194.785,290.828 194.959,291.002 R1091.1@195.009,291.002
  L3 (Sign) w0.081: v2(189.908,291.015) 189.932,290.992 189.932,290.667 192.775,290.667 192.783,290.676 192.985,290.676 193.137,290.828 v2(193.167,290.828)
LTC6952_1_MATCH_Out2_N: C802.2 J1_PCIE2.7 R1094.1 | length 3.7
  L1 w0.101: R1094.1@249.072,355.244 249.072,356.053 ccw(c249.005,356.053) C802.2@249.005,356.121 ccw(c249.005,356.304) 249.188,356.304 v1(249.188,357.022)
  L16 w0.101: J1_PCIE2.7@249.09,358.792 cw(c249.09,358.694) 249.188,358.694 v1(249.188,357.022)
LTC6952_1_MATCH_Out2_P: C802.1 J1_PCIE2.5 R1093.1 | length 3.8
  L1 w0.101: v1(249.792,357.022) 249.792,356.383 ccw(c250.055,356.383) C802.1@250.055,356.121 ccw(c250.055,356.053) 249.987,356.053 R1093.1@249.987,355.244
  L16 w0.101: v1(249.792,357.022) 249.792,358.694 cw(c249.89,358.694) J1_PCIE2.5@249.89,358.792
LTC6952_1_MATCH_Out3_N: C797.2 U13.24 | length 3.2
  L1 w0.101: U13.24@195.123,273.481 195.172,273.531 197.86,273.531 197.86,273.444 198.085,273.22 C797.2@198.12,273.22
LTC6952_1_MATCH_Out3_P: C797.1 U13.25 | length 3.2
  L1 w0.101: U13.25@195.123,273.981 195.172,273.932 197.86,273.932 197.86,274.045 198.085,274.27 C797.1@198.12,274.27
LTC6952_1_MATCH_Out4_N: C806.2 R1098.1 | length 1
  L1 w0.101: R1098.1@204.749,271.798 205.616,271.798 cw(c205.616,271.738) C806.2@205.677,271.738
LTC6952_1_MATCH_Out4_P: C806.1 R1097.1 | length 1
  L1 w0.101: R1097.1@204.749,272.723 205.612,272.723 ccw(c205.612,272.788) C806.1@205.677,272.788
LTC6952_1_MATCH_Out5_N: C808.2 R1101.1 | length 1
  L1 w0.101: R1101.1@206.596,267.773 207.469,267.773 cw(c207.469,267.661) C808.2@207.582,267.661
LTC6952_1_MATCH_Out5_P: C808.1 R1100.1 | length 1
  L1 w0.101: R1100.1@206.596,268.605 207.476,268.605 ccw(c207.476,268.711) C808.1@207.582,268.711
LTC6952_1_MATCH_Out6_N: C812.2 R1104.1 | length 0.9
  L1 w0.101: R1104.1@200.125,266.611 200.963,266.611 cw(c200.963,266.543) C812.2@201.031,266.543
LTC6952_1_MATCH_Out6_P: C812.1 R1103.1 | length 0.9
  L1 w0.101: R1103.1@200.125,267.525 200.963,267.525 ccw(c200.963,267.593) C812.1@201.031,267.593
LTC6952_1_MATCH_Out7_N: C814.2 J1_PCIE1.7 R1106.1 | length 7.8
  L16 w0.101: R1106.1@226.175,275.838 226.225,275.838 226.4,275.664 226.4,275.645 226.459,275.586 226.662,275.586 226.722,275.645 226.722,275.686 226.946,275.911 C814.2@226.996,275.911 227.046,275.911 227.371,275.586 229.095,275.586 cw(c229.095,274.191) 230.491,274.191 230.491,272.193 ccw(c230.69,272.193) J1_PCIE1.7@230.69,271.994
LTC6952_1_MATCH_Out7_P: C814.1 J1_PCIE1.5 R1105.1 | length 7.8
  L16 w0.101: R1105.1@226.175,274.924 226.225,274.924 226.4,275.098 226.4,275.121 226.464,275.185 226.662,275.185 226.722,275.126 226.722,275.085 226.946,274.861 C814.1@226.996,274.861 227.046,274.861 227.371,275.185 227.547,275.185 227.851,275.185 cw(c227.851,275.071) 227.965,275.071 227.965,274.896 ccw(c228.079,274.896) 228.079,274.782 228.105,274.782 ccw(c228.105,274.896) 228.219,274.896 228.219,275.071 cw(c228.333,275.071) 228.333,275.185 228.761,275.185 229.095,275.185 cw(c229.095,274.191) 230.09,274.191 230.09,272.194 cw(c229.89,272.194) J1_PCIE1.5@229.89,271.994
LTC6952_1_MATCH_Out8_N: C690.2 R1084.1 U13.9 | length 94.3
  L1 w0.101: v19(151.872,218.061) 151.872,218.236 cw(c152.196,218.236) C690.2@152.196,218.561 152.132,218.561 cw(c152.132,218.821) 151.872,218.821 151.872,219.2 cw(c152.141,219.2) R1084.1@152.141,219.47 ; v3(191.923,263.652) ccw(c191.923,263.752) 192.022,263.752 192.022,268.282 U13.9@191.973,268.331
  L5 (Sign) w0.081: v12(151.971,217.549) 151.949,217.549 ccw(c151.949,217.412) 151.812,217.412 ccw(c151.965,217.412) 151.965,217.259 163.29,217.259 163.331,217.259 ccw(c163.331,217.412) 163.484,217.412 163.484,217.499 cw(c163.636,217.499) 163.636,217.652 163.767,217.652 cw(c163.767,217.499) 163.92,217.499 163.92,217.412 ccw(c164.073,217.412) 164.073,217.259 164.364,217.259 164.384,217.259 ccw(c164.384,217.653) 164.777,217.653 164.777,253.363 164.787,253.374 cw(c165.57,253.247) 165.443,254.03 165.454,254.04 190.033,254.04 190.073,254.04 ccw(c190.073,254.14) 190.173,254.14 cw(c190.273,254.14) 190.273,254.24 190.407,254.24 cw(c190.407,254.14) 190.507,254.14 ccw(c190.607,254.14) 190.607,254.04 191.232,254.04 191.398,254.04 ccw(c191.398,254.724) 192.082,254.724 192.082,263.493 ccw(c191.923,263.493) v3(191.923,263.652)
  L3 (Sign) w0.081: v19(151.872,218.061) 151.872,217.649 ccw(c151.971,217.649) v12(151.971,217.549)
LTC6952_1_MATCH_Out8_P: C690.1 R1083.1 U13.10 | length 94.4
  L1 w0.101: R1083.1@151.201,219.47 cw(c151.201,219.2) 151.471,219.2 151.471,218.821 cw(c151.211,218.821) 151.211,218.561 C690.1@151.146,218.561 cw(c151.146,218.236) 151.471,218.236 v19(151.471,218.061) ; U13.10@192.473,268.331 192.423,268.282 192.423,263.752 ccw(c192.523,263.752) v3(192.523,263.652)
  L5 (Sign) w0.081: v12(151.371,217.549) 151.394,217.549 cw(c151.394,217.412) 151.531,217.412 ccw(c151.965,217.412) 151.965,216.978 164.384,216.978 ccw(c164.384,217.653) 165.058,217.653 165.058,253.247 cw(c165.57,253.247) 165.57,253.759 191.398,253.759 ccw(c191.398,254.724) 192.363,254.724 192.363,263.493 cw(c192.523,263.493) v3(192.523,263.652)
  L3 (Sign) w0.081: v12(151.371,217.549) ccw(c151.371,217.627) 151.449,217.627 v19@151.449,218.037
LTC6952_1_MATCH_Out9_N: C818.2 J1_PCIE4.7 R1110.1 | length 6.9
  L1 w0.101: v1(149.581,268.805) 151.13,268.805 ccw(c151.13,268.961) R1110.1@151.286,268.961
  L16 w0.101: J1_PCIE4.7@148.337,271.994 ccw(c148.337,271.801) 148.144,271.801 148.144,270.971 148.144,270.66 ccw(c148.245,270.66) 148.245,270.559 148.44,270.559 cw(c148.44,270.498) 148.501,270.498 148.501,270.214 cw(c148.44,270.214) 148.44,270.153 148.245,270.153 ccw(c148.245,270.052) 148.144,270.052 148.144,269.595 148.144,269.499 ccw(c148.939,269.499) 148.939,268.704 149.479,268.704 ccw(c149.479,268.805) v1(149.581,268.805)
LTC6952_1_MATCH_Out9_P: C818.1 J1_PCIE4.5 R1109.1 | length 7
  L1 w0.101: v1(149.581,268.201) 151.13,268.201 cw(c151.13,268.046) R1109.1@151.286,268.046
  L16 w0.101: J1_PCIE4.5@147.537,271.994 cw(c147.537,271.788) 147.743,271.788 147.743,269.499 ccw(c148.939,269.499) 148.939,268.303 149.479,268.303 cw(c149.479,268.201) v1(149.581,268.201)
LTC6952_1_Out0_N: C119.1 C796.1 U13.33 | length 32.4
  L1 w0.101: C119.1@165.36,282.179 166.222,282.179 ccw(c166.46,282.179) 166.46,281.94 167.702,281.94 cw(c167.702,281.714) 167.861,281.874 ccw(c168.021,282.034) 168.021,281.808 190.073,281.808 cw(c190.073,280.458) 191.423,280.458 191.423,275.181 ccw(c191.473,275.181) U13.33@191.473,275.131
LTC6952_1_Out0_P: C118.1 C796.2 U13.34 | length 32.4
  L1 w0.101: C118.1@165.363,281.267 166.224,281.267 cw(c166.495,281.267) 166.495,281.539 167.536,281.539 cw(c167.536,281.313) 167.695,281.473 ccw(c167.855,281.633) 167.855,281.407 188.596,281.407 189.002,281.407 cw(c189.002,281.3) 189.108,281.3 189.108,281.115 ccw(c189.215,281.115) 189.215,281.008 189.357,281.008 ccw(c189.357,281.115) 189.463,281.115 189.463,281.3 cw(c189.57,281.3) 189.57,281.407 189.775,281.407 190.073,281.407 cw(c190.073,280.458) 191.022,280.458 191.022,275.181 cw(c190.973,275.181) U13.34@190.973,275.131
LTC6952_1_Out1_N: C798.2 R1091.2 U13.30 | length 24
  L1 w0.101: U13.30@192.973,275.131 cw(c192.973,275.181) 192.923,275.181 192.923,280.896 cw(c193.522,280.896) 193.522,281.495 198.208,281.495 ccw(c198.208,282.375) 199.088,282.375 199.088,289.749 ccw(c198.085,289.749) 198.085,290.753 197.212,290.753 cw(c197.212,291.064) C798.2@196.901,291.064 cw(c196.839,291.064) 196.839,291.002 R1091.2@196.009,291.002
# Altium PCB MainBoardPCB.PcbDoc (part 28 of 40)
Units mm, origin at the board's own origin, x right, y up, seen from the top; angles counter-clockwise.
Board outline 258.95 x 308.86 mm, 16 copper layers (L1, L2 (GND), L3 (Sign), L4 (GND), L5 (Sign), L6 (PWR/GND), L7(12V+Other), L8 (Plane_GND), L9 (PWR/GND), L10 (3V3+Other), L11 (PWR/GND), L12 (Sign), L13 (GND), L14 (Sign), L15 (GND), L16), stack 2.503 mm thick; 2578 components, 1867 nets, 8817 pads, 8021 vias.
Unrouted connection lines stored in the file: 25.

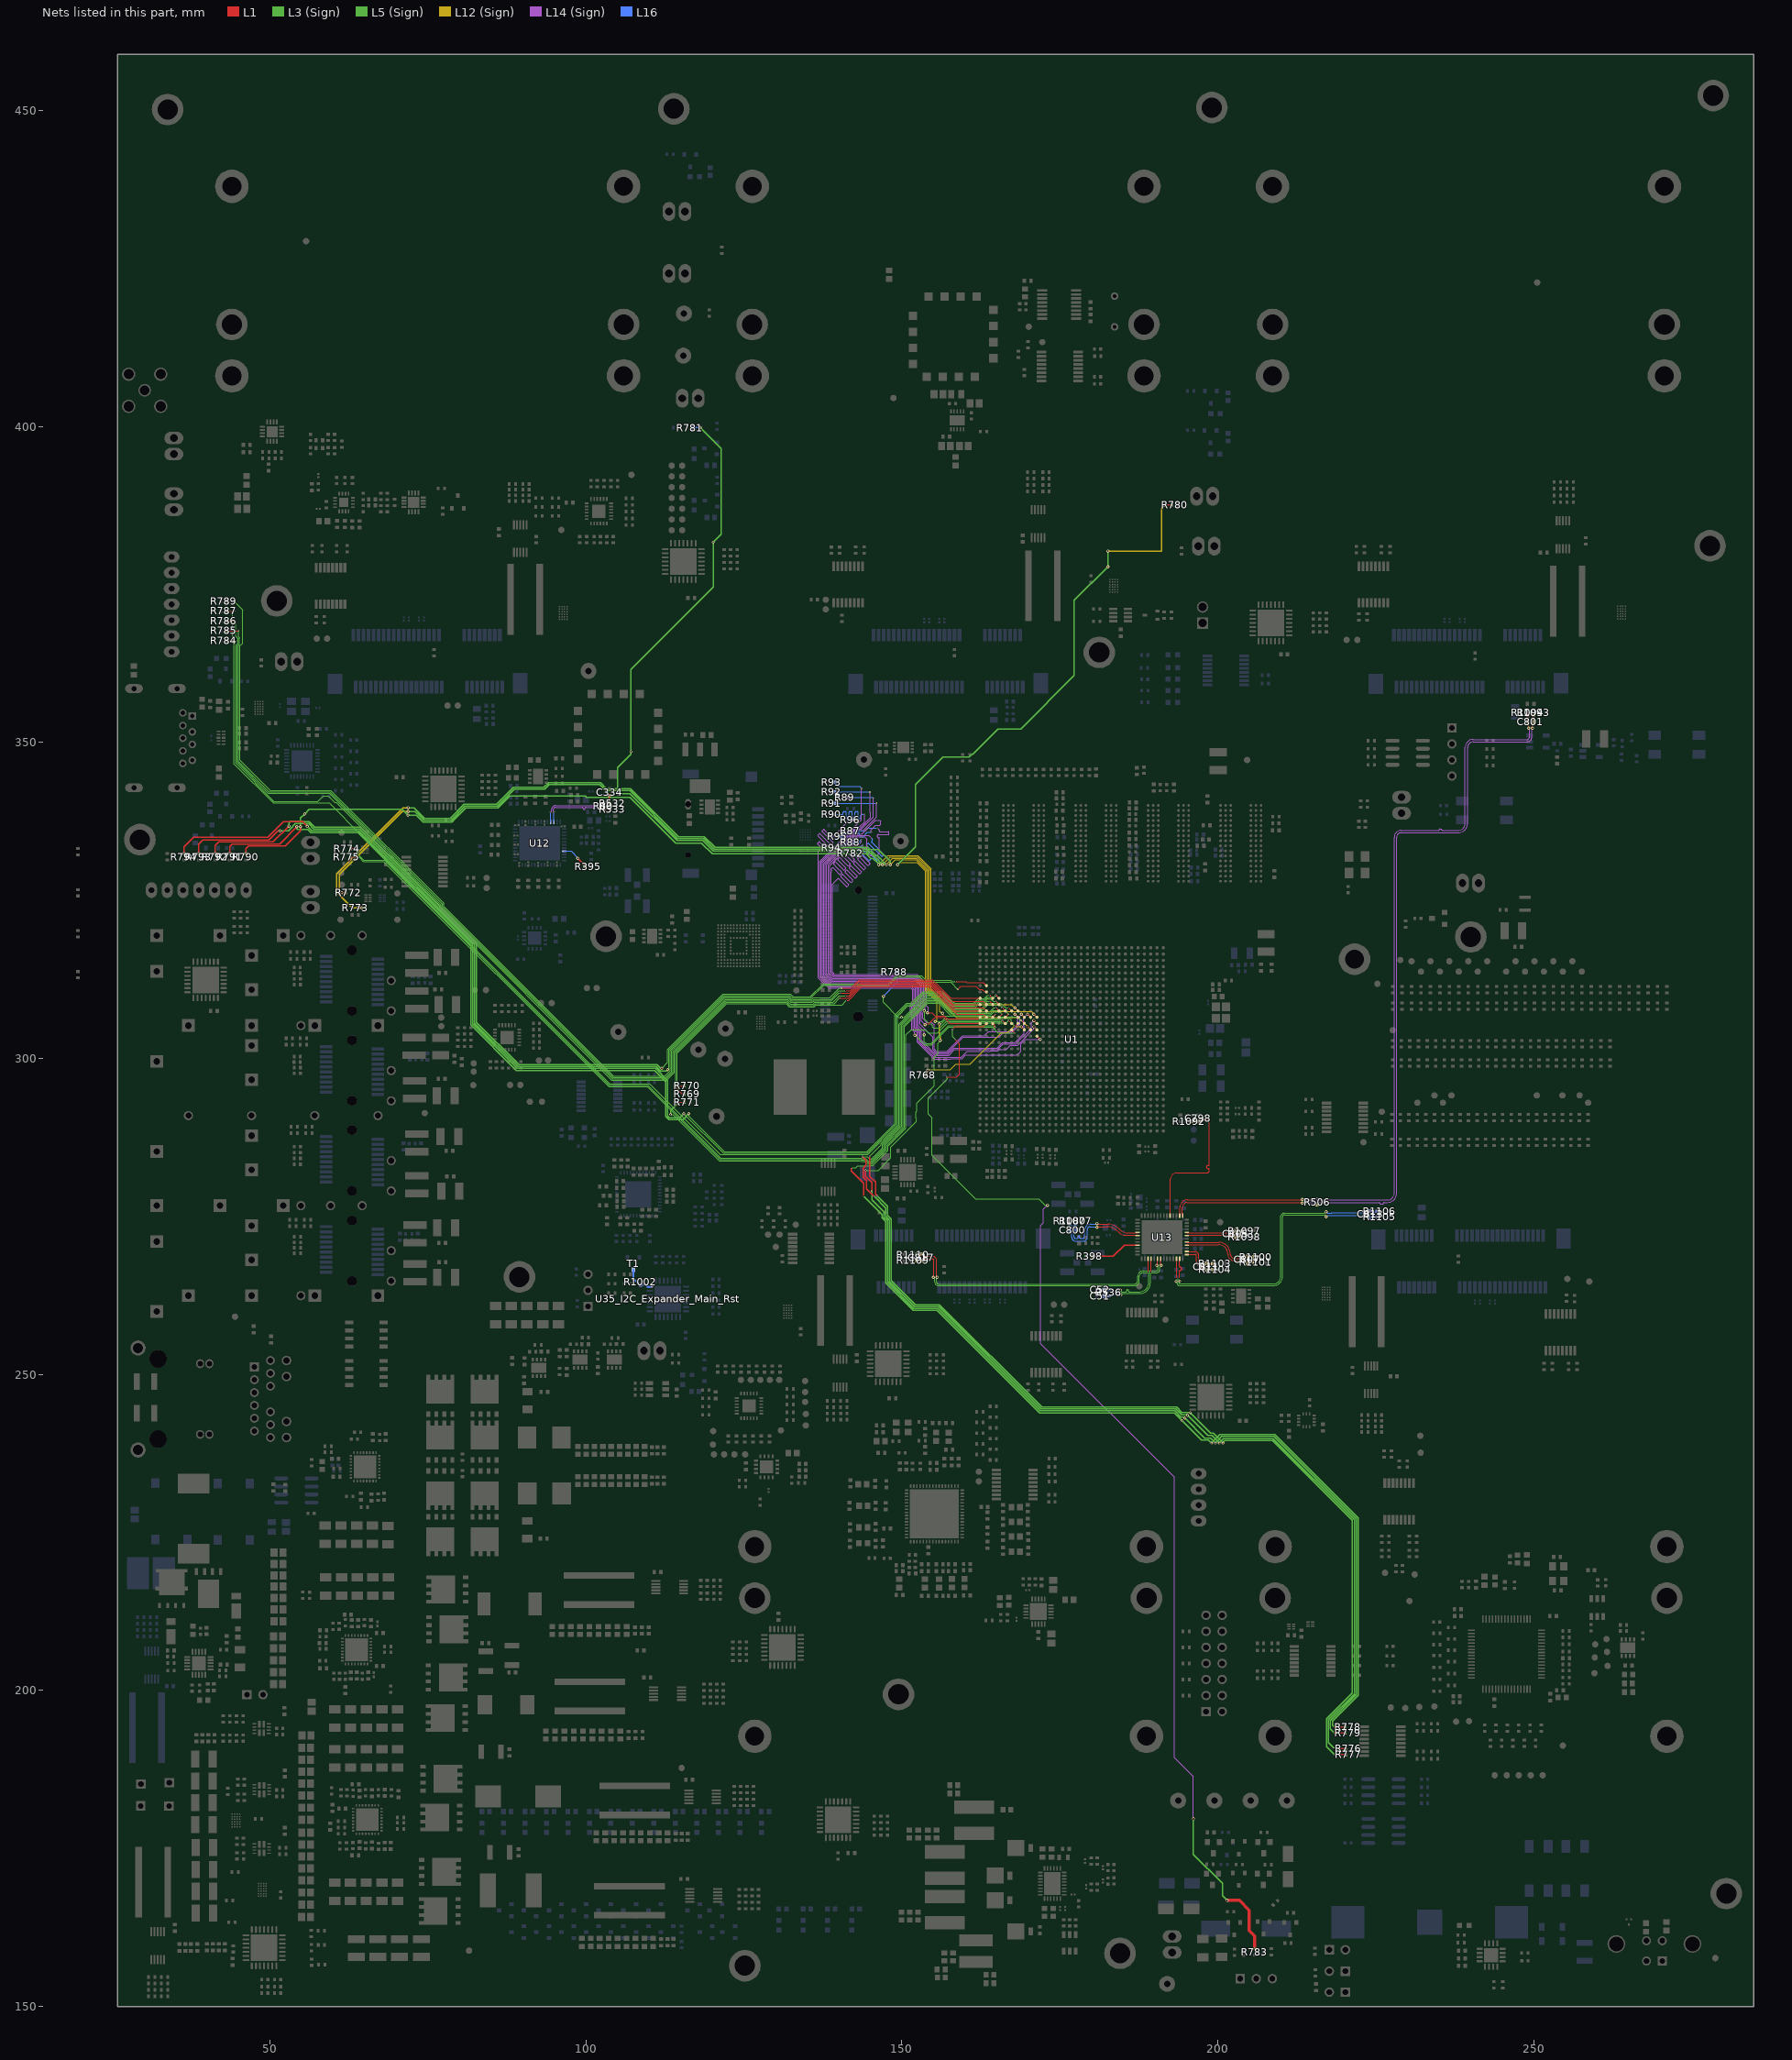
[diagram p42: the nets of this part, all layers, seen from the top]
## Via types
v1: diameter 0.5, hole 0.25, L1 to L16, tented both sides, 4341 vias
v2: diameter 0.254, hole 0.1, L1 to L3 (Sign), tented both sides, 781 vias
v3: diameter 0.5, hole 0.25, L1 to L16, 565 vias
v4: diameter 0.254, hole 0.1, L15 (GND) to L16, tented both sides, 406 vias
v5: diameter 0.254, hole 0.1, L1 to L2 (GND), tented both sides, 283 vias
v6: diameter 0.457, hole 0.2, L3 (Sign) to L6 (PWR/GND), tented both sides, 254 vias
v7: diameter 0.254, hole 0.1, L1 to L3 (Sign), 237 vias
v8: diameter 0.75, hole 0.4, L1 to L16, 200 vias
v9: diameter 0.8, hole 0.4, L1 to L16, tented both sides, 182 vias
v10: diameter 0.254, hole 0.1, L14 (Sign) to L16, tented both sides, 170 vias
v11: diameter 0.75/0/0/0/0/0/0/0/0/0/0/0/0/0/0/0.75 (per signal layer), hole 0.4, L1 to L16, 160 vias
v12: diameter 0.457, hole 0.2, L3 (Sign) to L6 (PWR/GND), 158 vias
v13: diameter 1.4, hole 0.5, L1 to L16, tented both sides, 80 vias
v14: diameter 0.254, hole 0.1, L14 (Sign) to L16, 65 vias
v15: diameter 0.254, hole 0.1, L1 to L2 (GND), 45 vias
v16: diameter 0.457, hole 0.2, L11 (PWR/GND) to L14 (Sign), tented both sides, 26 vias
v17: diameter 0.457, hole 0.2, L11 (PWR/GND) to L14 (Sign), 25 vias
v18: diameter 0.457, hole 0.2, L7(12V+Other) to L10 (3V3+Other), tented both sides, 11 vias
v19: diameter 0.254/0/0.254 (per signal layer), hole 0.1, L1 to L3 (Sign), 9 vias
v20: diameter 0.2/0/0.2 (per signal layer), hole 0.1, L1 to L3 (Sign), 6 vias
v21: diameter 1.65, hole 1.65, L1 to L16, 5 vias
v22: diameter 1.15, hole 1.15, L1 to L16, 5 vias
v23: diameter 0.457, hole 0.2, L1 to L16, 3 vias
v24: diameter 0.5, hole 0.3, L1 to L16, 2 vias
v25: diameter 0.5/0/0.5 (per signal layer), hole 0.2, L14 (Sign) to L16, 1 vias
v26: diameter 0.5, hole 0.25, L1 to L16, tented bottom, 1 vias

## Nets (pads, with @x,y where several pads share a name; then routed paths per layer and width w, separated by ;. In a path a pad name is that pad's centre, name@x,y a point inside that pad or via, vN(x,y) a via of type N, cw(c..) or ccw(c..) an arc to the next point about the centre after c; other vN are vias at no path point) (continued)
LTC6952_1_Out1_P: C798.1 R1092.2 U13.31 | length 24
  L1 w0.101: U13.31@192.473,275.131 ccw(c192.473,275.181) 192.522,275.181 192.522,280.896 cw(c193.522,280.896) 193.522,281.896 198.208,281.896 ccw(c198.208,282.375) 198.687,282.375 198.687,282.39 198.687,282.441 ccw(c198.527,282.441) 198.527,282.601 198.4,282.601 cw(c198.4,282.76) 198.24,282.76 198.24,282.897 cw(c198.4,282.897) 198.4,283.057 198.527,283.057 ccw(c198.527,283.217) 198.687,283.217 198.687,283.482 198.687,289.749 ccw(c198.085,289.749) 198.085,290.352 197.239,290.352 ccw(c197.239,290.014) C798.1@196.901,290.014 ccw(c196.847,290.014) 196.847,290.068 R1092.2@196.009,290.068
LTC6952_1_Out2_N: C801.2 R1093.2 U13.27 | length 132.5
  L1 w0.101: U13.27@194.473,275.131 cw(c194.473,275.181) 194.423,275.181 194.423,276.486 cw(c195.169,276.486) 195.169,277.232 213.273,277.232 cw(c213.273,277.132) v1(213.373,277.132) ; v1(249.832,352.285) 249.832,353.078 cw(c250.055,353.078) C801.2@250.055,353.301 cw(c250.055,353.369) 249.987,353.369 R1093.2@249.987,354.244
  L14 (Sign) w0.081: v1(213.373,277.132) cw(c213.483,277.132) 213.483,277.242 225.298,277.242 225.543,277.242 cw(c225.543,277.125) 225.661,277.125 225.661,277.1 ccw(c225.778,277.1) 225.778,276.983 226.131,276.983 ccw(c226.131,277.1) 226.249,277.1 226.249,277.125 cw(c226.366,277.125) 226.366,277.242 226.543,277.242 226.887,277.242 ccw(c226.887,278.684) 228.328,278.684 228.328,335.034 cw(c229.02,335.034) 229.02,335.726 238.061,335.726 ccw(c238.061,337.212) 239.547,337.212 239.547,349.234 cw(c240.415,349.234) 240.415,350.102 248.92,350.102 ccw(c248.92,350.902) 249.72,350.902 249.72,352.173 v1(249.832,352.285)
LTC6952_1_Out2_P: C801.1 R1094.2 U13.28 | length 132.5
  L1 w0.101: U13.28@193.973,275.131 ccw(c193.973,275.181) 194.022,275.181 194.022,276.486 cw(c195.169,276.486) 195.169,277.633 213.273,277.633 ccw(c213.273,277.732) v1(213.373,277.732) ; R1094.2@249.072,354.244 249.072,353.369 cw(c249.005,353.369) C801.1@249.005,353.301 cw(c249.005,353.078) 249.228,353.078 v1(249.228,352.285)
  L14 (Sign) w0.081: v1(213.373,277.732) ccw(c213.483,277.732) 213.483,277.622 226.887,277.622 ccw(c226.887,278.684) 227.949,278.684 227.949,335.034 cw(c229.02,335.034) 229.02,336.106 234.965,336.106 235.005,336.106 ccw(c235.005,336.187) 235.086,336.187 235.086,336.249 cw(c235.144,336.249) 235.144,336.307 235.414,336.307 cw(c235.414,336.249) 235.472,336.249 235.472,336.187 ccw(c235.553,336.187) 235.553,336.106 235.686,336.106 238.061,336.106 ccw(c238.061,337.212) 239.168,337.212 239.168,349.234 cw(c240.415,349.234) 240.415,350.482 248.92,350.482 ccw(c248.92,350.902) 249.34,350.902 249.34,352.173 v1(249.228,352.285)
LTC6952_1_Out4_N: C805.1 R1098.2 U13.21 | length 8.8
  L1 w0.101: U13.21@195.123,271.981 cw(c195.172,271.981) 195.172,272.031 203.516,272.031 cw(c203.516,271.798) R1098.2@203.749,271.798
LTC6952_1_Out4_P: C805.2 R1097.2 U13.22 | length 8.9
  L1 w0.101: U13.22@195.123,272.481 ccw(c195.172,272.481) 195.172,272.432 202.51,272.432 ccw(c202.51,272.786) C805.2@202.864,272.786 ccw(c202.927,272.786) 202.927,272.723 R1097.2@203.749,272.723
LTC6952_1_Out5_N: C807.1 R1101.2 U13.18 | length 12.2
  L1 w0.101: U13.18@195.123,270.481 cw(c195.172,270.481) 195.172,270.531 200.127,270.531 cw(c200.127,269.047) 201.61,269.047 ccw(c202.672,269.047) 202.672,267.985 204.33,267.985 cw(c204.33,267.661) C807.1@204.655,267.661 cw(c204.767,267.661) 204.767,267.773 R1101.2@205.596,267.773
LTC6952_1_Out5_P: C807.2 R1100.2 U13.19 | length 12.2
  L1 w0.101: U13.19@195.123,270.981 ccw(c195.172,270.981) 195.172,270.932 200.127,270.932 cw(c200.127,269.047) 202.011,269.047 ccw(c202.672,269.047) 202.672,268.386 204.33,268.386 ccw(c204.33,268.711) C807.2@204.655,268.711 ccw(c204.761,268.711) 204.761,268.605 R1100.2@205.596,268.605
LTC6952_1_Out6_N: C811.1 R1104.2 U13.15 | length 5.9
  L1 w0.101: U13.15@195.123,268.981 cw(c195.172,268.981) 195.172,269.031 196.438,269.031 cw(c196.438,268.846) 196.623,268.846 196.623,267.896 ccw(c197.651,267.896) 197.651,266.868 197.941,266.868 cw(c197.941,266.543) C811.1@198.265,266.543 cw(c198.333,266.543) 198.333,266.611 R1104.2@199.125,266.611
LTC6952_1_Out6_P: C811.2 R1103.2 U13.16 | length 5.9
  L1 w0.101: U13.16@195.123,269.481 ccw(c195.172,269.481) 195.172,269.432 196.438,269.432 cw(c196.438,268.846) 197.024,268.846 197.024,267.896 ccw(c197.651,267.896) 197.651,267.269 197.941,267.269 ccw(c197.941,267.593) C811.2@198.265,267.593 ccw(c198.333,267.593) 198.333,267.525 R1103.2@199.125,267.525
LTC6952_1_Out7_N: C813.2 R1105.2 U13.12 | length 47.3
  L1 w0.101: U13.12@193.473,268.331 193.522,268.282 v20(193.522,265.206)
  L5 (Sign) w0.081: v12(193.407,264.742) 193.485,264.742 193.498,264.755 cw(c193.498,264.67) 193.582,264.67 193.582,264.452 ccw(c193.977,264.452) 193.977,264.057 208.809,264.057 ccw(c208.809,265.506) 210.258,265.506 210.258,274.973 cw(c210.566,274.973) 210.566,275.281 216.961,275.281 217.161,275.081 v3(217.161,274.976)
  L3 (Sign) w0.081: v12(193.407,264.742) 193.557,264.742 193.557,264.916 193.582,264.941 193.582,265.146 ccw(c193.522,265.146) v20(193.522,265.206)
  L16 w0.101: v3(217.161,274.976) 217.236,274.976 217.419,275.16 218.17,275.16 218.196,275.185 223.873,275.185 223.932,275.126 223.932,275.085 224.157,274.861 C813.2@224.207,274.861 224.257,274.861 224.481,275.085 224.481,275.126 224.541,275.185 224.887,275.185 224.951,275.121 224.951,275.098 225.126,274.924 R1105.2@225.176,274.924
LTC6952_1_Out7_P: C813.1 R1106.2 U13.13 | length 47.1
  L1 w0.101: v20(193.923,265.206) 193.923,265.829 193.923,266.336 cw(c194.083,266.336) 194.083,266.496 194.13,266.496 ccw(c194.13,266.656) 194.29,266.656 194.29,266.793 ccw(c194.13,266.793) 194.13,266.952 194.083,266.952 cw(c194.083,267.112) 193.923,267.112 193.923,267.427 193.923,268.282 U13.13@193.973,268.331
  L5 (Sign) w0.081: v12(194.007,264.754) 193.948,264.754 ccw(c193.948,264.67) 193.863,264.67 193.863,264.452 ccw(c193.977,264.452) 193.977,264.338 208.809,264.338 ccw(c208.809,265.506) 209.977,265.506 209.977,275.089 209.991,275.104 cw(c210.566,274.973) 210.435,275.547 210.45,275.562 216.931,275.562 216.956,275.587 216.986,275.587 217.134,275.735 v3(217.134,275.744)
  L3 (Sign) w0.081: v20(193.923,265.206) ccw(c193.923,265.146) 193.863,265.146 193.863,264.755 v12(194.007,264.754)
  L16 w0.101: v3(217.134,275.744) 217.209,275.744 217.392,275.561 218.004,275.561 218.03,275.586 223.873,275.586 223.932,275.645 223.932,275.686 224.157,275.911 C813.1@224.207,275.911 224.257,275.911 224.481,275.686 224.481,275.645 224.541,275.586 224.892,275.586 224.951,275.645 224.951,275.664 225.125,275.838 R1106.2@225.175,275.838
LTC6952_1_Out9_N: C817.1 R1110.2 U13.6 | length 46.1
  L1 w0.101: R1110.2@152.286,268.961 153.077,268.961 ccw(c153.077,269.028) C817.1@153.145,269.028 ccw(c153.47,269.028) 153.47,268.704 154.853,268.704 cw(c154.853,268.046) 155.511,268.046 155.511,265.491 ccw(c155.61,265.491) v1(155.61,265.392) ; v1(190.369,267.284) 190.43,267.284 ccw(c190.43,267.327) 190.473,267.327 U13.6@190.473,268.331
  L5 (Sign) w0.081: v1(155.61,265.392) 155.55,265.392 ccw(c155.55,265.252) 155.538,265.391 155.491,265.378 155.491,264.693 ccw(c155.855,264.693) 155.855,264.33 186.891,264.33 ccw(c186.891,264.755) 187.316,264.755 187.316,265.506 cw(c188.203,265.506) 188.203,266.394 190.26,266.394 ccw(c190.26,266.708) 190.574,266.708 190.574,267.08 ccw(c190.369,267.08) v1(190.369,267.284)
LTC6952_1_Out9_P: C817.2 R1109.2 U13.7 | length 46.4
  L1 w0.101: R1109.2@152.286,268.046 153.077,268.046 cw(c153.077,267.978) C817.2@153.145,267.978 cw(c153.47,267.978) 153.47,268.303 154.853,268.303 cw(c154.853,268.046) 155.11,268.046 155.11,265.491 cw(c155.01,265.491) v1(155.01,265.392) ; U13.7@190.973,268.331 190.973,267.327 ccw(c191.015,267.327) 191.015,267.284 v1(191.059,267.284)
  L5 (Sign) w0.081: v1(155.01,265.392) 155.071,265.392 cw(c155.071,265.252) 155.21,265.252 155.21,264.693 ccw(c155.855,264.693) 155.855,264.049 186.891,264.049 ccw(c186.891,264.755) 187.597,264.755 187.597,265.506 cw(c188.203,265.506) 188.203,266.113 190.26,266.113 ccw(c190.26,266.708) 190.855,266.708 190.855,267.08 cw(c191.059,267.08) v1(191.059,267.284)
LTC6952_1_Out10_N: C52.2 R536.1 U13.3 | length 12.8
  L1 w0.101: U13.3@188.973,268.331 189.022,268.282 189.022,266.21 v2(188.992,266.179)
  L3 (Sign) w0.081: v3(184.631,263.335) 184.631,263.188 184.637,263.182 ccw(c184.722,263.182) 184.722,263.098 185.187,263.098 185.482,263.098 ccw(c185.482,263.198) 185.582,263.198 185.582,263.302 cw(c185.683,263.302) 185.683,263.402 185.816,263.402 cw(c185.816,263.302) 185.916,263.302 185.916,263.198 ccw(c186.017,263.198) 186.017,263.098 186.391,263.098 187.634,263.098 ccw(c187.634,264.54) 189.076,264.54 189.076,266.095 ccw(c188.992,266.095) v2(188.992,266.179) cw(c188.992,266.144) v2@189.027,266.144
  L16 w0.101: C52.2@181.928,263.449 ccw(c182.127,263.449) 182.127,263.25 183.794,263.25 183.887,263.158 184.065,263.158 184.072,263.165 184.373,263.165 184.542,263.335 v3(184.631,263.335)
LTC6952_1_Out10_P: C51.2 R536.2 U13.4 | length 12.8
  L1 w0.101: v2(189.442,266.179) 189.423,266.198 189.423,268.282 U13.4@189.473,268.331
  L3 (Sign) w0.081: v3(184.637,262.595) v3@184.637,262.732 ; v3@184.637,262.732 cw(c184.722,262.732) 184.722,262.817 187.634,262.817 ccw(c187.634,264.54) 189.357,264.54 189.357,266.095 cw(c189.442,266.095) v2(189.442,266.179) ccw(c189.442,266.144) v2@189.407,266.144
  L16 w0.101: C51.2@181.928,262.445 cw(c182.147,262.445) 182.147,262.665 183.794,262.665 183.887,262.757 184.231,262.757 184.239,262.764 184.378,262.764 184.548,262.595 v3(184.637,262.595)
LTC6952_1_REF_MATCH_N: C800.2 R1080.1 U13.46 | length 15.6
  L1 w0.101: v1(180.899,273.291) cw(c181.083,273.107) 181.083,273.368 181.114,273.368 ccw(c181.114,273.411) 181.145,273.38 cw(c181.175,273.35) 181.175,273.393 182.401,273.393 cw(c182.401,270.853) 184.197,272.649 184.291,272.555 ccw(c185.556,273.82) 185.556,272.031 187.203,272.031 cw(c187.203,271.862) U13.46@187.323,271.981
  L16 w0.101: R1080.1@176.63,273.822 cw(c176.63,273.572) 176.88,273.572 176.88,273.179 cw(c176.555,273.179) C800.2@176.555,272.854 cw(c176.555,272.53) 176.88,272.53 176.88,271.753 ccw(c177.49,271.753) 177.49,271.143 178.786,271.143 ccw(c178.786,271.724) 179.367,271.724 179.367,272.919 cw(c179.841,272.919) 179.841,273.393 180.797,273.393 cw(c180.797,273.291) v1(180.899,273.291)
LTC6952_1_REF_MATCH_P: C800.1 R1077.1 U13.45 | length 15.6
  L1 w0.101: v1(180.899,273.895) ccw(c181.083,274.08) 181.083,273.819 181.114,273.819 cw(c181.114,273.776) 181.145,273.807 ccw(c181.175,273.837) 181.175,273.794 182.688,273.794 cw(c182.688,271.545) 184.278,273.135 184.572,272.841 ccw(c185.559,273.828) 185.559,272.432 187.203,272.432 ccw(c187.203,272.601) U13.45@187.323,272.481
  L16 w0.101: R1077.1@177.53,273.822 ccw(c177.53,273.572) 177.281,273.572 177.281,273.179 ccw(c177.605,273.179) C800.1@177.605,272.854 ccw(c177.605,272.53) 177.281,272.53 177.281,271.753 ccw(c177.49,271.753) 177.49,271.544 177.501,271.544 177.799,271.544 ccw(c177.799,271.658) 177.913,271.658 177.913,271.843 cw(c178.027,271.843) 178.027,271.957 178.052,271.957 cw(c178.052,271.843) 178.166,271.843 178.166,271.658 ccw(c178.28,271.658) 178.28,271.544 178.584,271.544 178.618,271.544 ccw(c178.618,271.892) 178.966,271.892 178.966,272.919 cw(c179.841,272.919) 179.841,273.794 180.797,273.794 ccw(c180.797,273.895) v1(180.899,273.895)
LTC6952_1_Temp: R395.2 U12.49 | length 4.5
  L1 w0.2: v1(98.743,331.686) 99.933,330.495 R395.2@99.933,330.39
  L16 w0.12: U12.49@96.597,332.811 97.707,332.811 98.742,331.775 v1(98.743,331.686)
LTC6952_1_VCO_N: C334.1 R80.2 R532.2 U12.37 | length 13.1
  L1 w0.101: v1(102.108,340.195) 102.568,340.195 ccw(c102.568,340.434) R80.2@102.806,340.434 ccw(c102.829,340.434) 102.829,340.411 R532.2@103.747,340.411 103.747,341.554 cw(c103.797,341.554) C334.1@103.797,341.604 C334.1@103.783,341.604
  L14 (Sign) w0.081: v14(94.397,338.988) ccw(c94.397,339.148) 94.557,339.148 94.557,339.335 cw(c95.257,339.335) 95.257,340.035 101.949,340.035 ccw(c101.949,340.195) v1(102.108,340.195)
  L16 w0.101: v14(94.397,338.988) cw(c94.397,338.938) 94.447,338.938 U12.37@94.447,337.461
LTC6952_1_VCO_P: R80.1 R533.2 U12.38 | length 11.8
  L1 w0.101: v1(102.108,339.595) 102.461,339.595 102.553,339.687 cw(c102.553,339.434) R80.1@102.806,339.434 R533.2@103.747,339.432 R533.2@103.747,339.432
  L14 (Sign) w0.081: v14(94.997,338.988) cw(c94.997,339.148) 94.838,339.148 94.838,339.335 cw(c95.257,339.335) 95.257,339.754 98.522,339.754 99.084,339.754 99.459,339.754 cw(c99.459,339.654) 99.559,339.654 99.559,339.558 ccw(c99.659,339.558) 99.659,339.458 99.793,339.458 ccw(c99.793,339.558) 99.893,339.558 99.893,339.654 cw(c99.993,339.654) 99.993,339.754 100.314,339.754 101.471,339.754 101.949,339.754 cw(c101.949,339.595) v1(102.108,339.595)
  L16 w0.101: U12.38@94.947,337.461 94.947,338.938 cw(c94.997,338.938) v14(94.997,338.988)
LTC6952_2_Temp: R398.2 U13.49 | length 7.9
  L1 w0.2: R398.2@180.18,268.694 183.426,268.694 185.213,270.481 U13.49@187.323,270.481
LTC6952_3_Temp: R506.2
MainExpReset: R1002.1 T1.3 U35_I2C_Expander_Main_Rst.14 | length 4.5
  L16 w0.3: T1.3@107.531,266.58 107.531,265.194 108.345,264.38 108.499,264.38 108.648,264.23 108.648,264.18 109.485,264.18 109.748,263.918 U35_I2C_Expander_Main_Rst.14@110.123,263.918
MIO_0: R768.2 U1.H17 | length 19.3
  L1 w0.12: v1(168.909,305.027) U1.H17@169.397,304.539
  L1 w0.2: R768.2@153.79,297.394 154.185,297.788 154.102,297.871 154.102,298.039 cw(c154.302,298.039) v1(154.164,298.183)
  L12 (Sign) w0.12: v1(154.164,298.183) cw(c154.275,298.139) 154.275,298.259 157.698,298.26 158.534,299.095 160.78,299.095 165.786,304.101 166.784,304.101 167.709,305.027 v1(168.909,305.027)
MIO_1: R769.2 U1.A20 | length 61.9
  L1 w0.12: v2(114.337,295.325) 115.198,294.465 115.568,294.465 R769.2@115.628,294.405 ; v2(140.195,309.549) 141.611,309.549 143.628,311.567 154.462,311.567 158.489,307.539 U1.A20@162.397,307.539
  L3 (Sign) w0.12: v2(114.337,295.325) 114.245,295.417 114.245,297.712 114.245,300.917 122.222,308.894 131.79,308.894 132.254,308.43 136.054,308.43 136.331,308.707 139.302,308.707 140.145,309.549 v2(140.195,309.549)
MIO_2: R770.2 U1.B19 | length 61.9
  L1 w0.12: v2(114.656,295.643) 115.167,295.643 115.218,295.694 R770.2@115.628,295.694 ; v2(141.249,309.194) 141.567,309.194 143.72,311.347 154.349,311.347 158.669,307.027 162.909,307.027 U1.B19@163.397,306.539
  L3 (Sign) w0.12: 114.465,297.621 114.465,295.834 v2(114.656,295.643) ; 114.465,297.621 114.465,300.826 122.314,308.674 131.699,308.674 132.163,308.21 136.146,308.21 136.422,308.487 140.542,308.487 v2(141.249,309.194)
MIO_3: R771.2 U1.D19 | length 81.2
  L1 w0.12: v1(114.63,292.976) 114.769,293.115 R771.2@115.628,293.115 ; U1.D19@165.397,306.539 v2(165.884,307.027)
  L5 (Sign) w0.2: v6(113.411,291.147) 113.411,291.757 v1(114.63,292.976)
  L3 (Sign) w0.12: v6(113.411,291.147) 113.824,291.147 121.155,283.817 143.355,283.817 143.466,283.705 144.097,283.705 144.52,283.282 145.31,283.282 147.621,285.593 147.621,286.235 150.434,289.048 150.434,305.063 153.324,307.952 153.324,307.954 153.564,308.194 153.566,308.194 154.143,308.772 155.853,308.772 157.649,306.976 164.139,306.976 164.546,307.383 165.529,307.383 v2(165.884,307.027)
MIO_4: R772.2 U1.J17 | length 148.3
  L1 w0.12: v1(169.909,305.027) U1.J17@170.397,304.539
  L1 w0.2: v1(61.401,326.225) cw(c61.452,326.225) 61.452,326.276 R772.2@62.001,326.276
  L12 (Sign) w0.12: v1(147.565,330.683) 148.572,331.69 152.339,331.69 154.2,329.829 154.2,310.934 158.608,306.526 161.397,306.526 168.41,306.526 v1(169.909,305.027)
  L12 (Sign) w0.2: v1(61.401,326.225) 61.113,326.225 60.977,326.362 60.977,329.175 70.904,339.103 71.868,339.103 v1(71.88,339.091)
  L3 (Sign) w0.2: v1(71.88,339.091) 72.986,339.091 73.286,338.791 73.314,338.791 74.395,337.711 78.662,337.711 80.876,339.925 85.998,339.925 88.691,342.618 93.506,342.618 94.241,343.352 102.192,343.352 103.153,342.391 106.958,342.391 114.545,334.804 118.637,334.804 120.325,333.115 144.491,333.115 144.827,332.78 145.235,332.78 145.901,332.114 146.134,332.114 v1(147.565,330.683)
MIO_5: R773.2 U1.C19 | length 149.3
  L1 w0.12: U1.C19@164.397,306.539 v2(164.884,307.027)
  L1 w0.2: R773.2@63.981,323.863 v1(64.567,323.863)
  L12 (Sign) w0.12: v1(148.165,330.683) 148.952,331.47 152.248,331.47 153.98,329.738 153.98,310.843 155.99,308.833 155.99,307.433 156.074,307.349 156.207,307.349 156.375,307.181 v1(156.477,307.181)
  L12 (Sign) w0.2: v1(64.567,323.863) 63.052,323.863 60.592,326.323 60.592,329.215 71.068,339.691 v1(71.88,339.691)
  L3 (Sign) w0.12: v1(156.477,307.181) 156.439,307.142 156.439,306.984 156.683,306.74 164.598,306.74 v2(164.884,307.027)
  L3 (Sign) w0.2: v1(71.88,339.691) 72.839,339.691 74.519,338.01 78.537,338.01 80.752,340.225 85.874,340.225 88.567,342.918 93.38,342.918 94.114,343.652 102.316,343.652 103.241,342.727 107.046,342.727 114.669,335.104 118.762,335.104 120.45,333.415 144.616,333.415 144.948,333.083 146.317,333.083 148.165,331.235 v1(148.165,330.683)
MIO_6: R774.2 U1.D20 | length 145.2
  L1 w0.12: R774.2@62.705,333.235 62.715,333.245 v2(63.602,333.245) ; v2(164.909,308.027) U1.D20@165.397,307.539
  L3 (Sign) w0.12: v2(63.602,333.245) 63.833,333.245 63.995,333.083 63.995,332.27 64.86,331.405 68.09,331.405 103.716,295.779 109.849,295.779 121.371,284.257 143.537,284.257 143.649,284.145 144.279,284.145 144.702,283.722 145.127,283.722 147.181,285.776 147.181,286.418 149.994,289.23 149.994,305.245 152.884,308.135 152.884,308.137 153.381,308.634 153.383,308.634 153.961,309.212 156.036,309.212 157.832,307.416 163.957,307.416 164.568,308.027 v2(164.909,308.027)
MIO_7: R775.2 U1.E19 | length 146.4
  L1 w0.12: R775.2@62.629,331.864 v2(63.665,331.864) ; U1.E19@166.397,306.539 v2(166.884,307.027)
  L3 (Sign) w0.12: v2(63.665,331.864) 64.084,331.864 64.763,331.185 67.993,331.185 103.623,295.554 109.762,295.554 121.28,284.037 143.446,284.037 143.557,283.925 144.188,283.925 144.611,283.502 145.219,283.502 147.401,285.684 147.401,286.327 150.214,289.139 150.214,305.154 153.104,308.044 153.104,308.045 153.473,308.414 153.474,308.414 154.052,308.992 155.945,308.992 157.741,307.196 164.048,307.196 164.455,307.603 166.309,307.603 v2(166.884,307.027)
MIO_8: R776.2 U1.E20 | length 196.3
  L1 w0.12: v2(165.909,308.027) U1.E20@166.397,307.539
  L1 w0.2: v2(143.787,284.48) 144.361,283.906 144.361,283.121 143.882,282.642 143.882,281.232 144.401,280.714 144.401,279.388 145.581,278.208 v2(145.635,278.208) ; v2(218.465,190.809) R776.2@220.217,190.809 R776.2@220.267,190.809
  L5 (Sign) w0.2: v6(195.222,243.546) 198.432,240.336 199.105,240.336 200.251,239.19 v6(200.251,239.154)
  L3 (Sign) w0.12: v2(143.787,284.48) 144.529,284.48 144.908,284.101 145.195,284.101 146.961,285.867 146.961,286.509 149.774,289.322 149.774,305.338 153.29,308.854 153.292,308.854 153.87,309.432 156.127,309.432 157.918,307.641 162.765,307.641 163.562,308.437 165.499,308.437 v2(165.909,308.027)
  L3 (Sign) w0.2: v2(145.635,278.208) 147.48,276.363 147.48,275.034 148.039,274.475 148.039,273.254 148.041,273.252 148.041,264.757 152.043,260.755 155.837,260.755 172.044,244.547 193.372,244.547 194.328,243.591 195.177,243.591 v6(195.222,243.546) ; v6(200.251,239.154) 200.251,239.19 200.946,239.885 208.778,239.885 221.625,227.039 221.625,199.471 217.538,195.384 217.538,191.736 v2(218.465,190.809)
MIO_9: R777.2 U1.F20 | length 195.3
  L1 w0.12: v2(166.909,308.027) U1.F20@167.397,307.539
  L1 w0.2: v2(144.926,284.557) 144.926,281.36 145.841,280.445 145.841,278.532 v2(146.104,278.27) ; v2(218.465,189.856) R777.2@220.268,189.856
  L5 (Sign) w0.2: v6(195.646,243.97) 198.892,240.724 199.317,240.724 200.85,239.19 v6(200.85,239.154)
  L3 (Sign) w0.12: v2(144.926,284.557) 144.934,284.557 146.741,286.365 146.741,286.6 149.546,289.405 149.546,305.422 153.199,309.074 153.201,309.074 153.779,309.652 156.218,309.652 158.009,307.861 161.397,307.861 162.625,307.861 163.536,308.772 165.662,308.772 166.407,308.027 v2(166.909,308.027)
  L3 (Sign) w0.2: v2(146.104,278.27) 147.78,276.593 147.78,275.158 148.339,274.599 148.339,273.378 148.341,273.377 148.341,264.881 152.168,261.055 155.961,261.055 172.168,244.847 193.496,244.847 194.348,243.996 195.621,243.996 v6(195.646,243.97) ; v6(200.85,239.154) 200.85,239.268 201.168,239.585 208.653,239.585 221.325,226.914 221.325,199.595 217.238,195.509 217.238,191.083 v2(218.465,189.856)
MIO_10: R778.2 U1.F18 | length 193.1
  L1 w0.12: v2(166.909,306.027) U1.F18@167.397,305.539
  L1 w0.2: v2(142.014,282.729) 142.014,282.2 143.973,280.241 v2(143.973,278.238) ; v2(218.465,194.229) R778.2@220.214,194.229
  L5 (Sign) w0.2: v6(194.373,242.697) 197.423,239.648 198.556,239.648 v6(199.051,239.154)
  L3 (Sign) w0.12: v2(142.014,282.729) 142.736,282.729 143.023,283.016 144.97,283.016 145.01,283.056 145.395,283.056 147.841,285.502 147.841,286.144 150.654,288.957 150.654,303.727 151.511,304.584 153.67,304.584 154.197,304.057 155.669,304.057 157.258,305.646 166.529,305.646 v2(166.909,306.027)
  L3 (Sign) w0.2: v2(143.973,278.238) 146.88,275.331 146.88,274.785 147.439,274.226 147.439,264.6 147.441,264.598 147.441,264.509 151.795,260.155 155.588,260.155 171.795,243.947 193.123,243.947 v6(194.373,242.697) ; v6(199.051,239.154) 199.051,239.19 200.356,240.495 202.408,240.495 202.418,240.485 209.026,240.485 222.225,227.287 222.225,199.222 218.148,195.145 218.148,194.546 v2(218.465,194.229)
MIO_11: R779.2 U1.G18 | length 190.5
  L1 w0.12: v2(167.909,305.052) U1.G18@168.397,305.539
  L1 w0.2: v2(144.293,282.305) 144.293,281.352 145.26,280.384 v2(145.26,279.059) ; v2(218.465,193.302) R779.2@220.218,193.302
  L5 (Sign) w0.2: v6(194.798,243.121) 197.971,239.948 198.893,239.948 199.651,239.19 v6(199.651,239.154)
  L12 (Sign) w0.2: v1(155.931,305.473) 155.931,303.606 156.058,303.479 v1(156.058,302.877)
  L3 (Sign) w0.12: v2(144.293,282.305) 146.296,282.305 148.281,284.29 148.281,285.962 152.352,290.033 152.352,290.436 152.229,290.559 152.229,291.519 152.416,291.706 152.416,292.959 155.142,295.685 155.142,300.177 155.717,300.752 155.717,302.405 155.957,302.645 156.058,302.645 v1(156.058,302.877) ; v1(155.931,305.473) 156.235,305.473 156.849,306.086 164.912,306.086 165.496,306.087 165.771,306.362 167.048,306.362 167.348,306.062 167.348,305.614 v2(167.909,305.052)
  L3 (Sign) w0.2: v2(145.26,279.059) 145.26,277.644 147.18,275.724 147.18,274.909 147.739,274.351 147.739,273.123 147.741,273.121 147.741,264.633 151.919,260.455 155.712,260.455 171.92,244.247 193.247,244.247 194.204,243.291 194.628,243.291 v6(194.798,243.121) ; v6(199.651,239.154) 199.651,239.19 200.651,240.19 202.282,240.19 202.287,240.185 208.902,240.185 221.925,227.163 221.925,199.346 217.843,195.265 217.843,193.924 v2(218.465,193.302)
MIO_12: R780.2 U1.H18 | length 129.8
  L1 w0.12: v2(168.909,306.027) U1.H18@169.397,305.539
  L1 w0.2: v1(191.579,387.515) 191.656,387.591 R780.2@192.799,387.591
  L5 (Sign) w0.2: v1(182.625,377.825) 182.625,380.294 v1(182.639,380.307)
  L12 (Sign) w0.12: v1(149.365,330.683) 149.365,330.733 149.661,331.03 152.377,331.03 153.76,329.647 153.76,310.752 155.55,308.962 155.55,306.108 v1(155.308,305.866)
  L12 (Sign) w0.2: v1@182.612,377.812 v1(182.625,377.825) ; v1(182.639,380.307) 191.123,380.307 191.123,387.046 191.592,387.515 v1(191.579,387.515)
  L3 (Sign) w0.12: v1(155.308,305.866) 155.325,305.883 156.303,305.883 156.731,306.311 165.409,306.311 165.68,306.582 167.139,306.582 167.156,306.565 168.371,306.565 v2(168.909,306.027)
  L3 (Sign) w0.2: v1(149.365,330.683) 152.146,333.464 152.146,343.368 156.517,347.739 160.68,347.739 161.103,348.162 161.27,348.162 165.241,352.133 168.849,352.133 177.305,360.588 177.305,372.505 v1(182.625,377.825)
MIO_13: R87.1 U1.G19 | length 85.6
  L1 w0.12: v1(167.909,307.027) U1.G19@168.397,306.539
  L14 (Sign) w0.12: v10(146.136,336.464) 146.152,336.448 146.444,336.156 146.444,336.037 ccw(c146.563,336.037) 146.563,335.919 147.878,335.919 cw(c147.878,335.8) 147.997,335.8 147.997,335.562 cw(c147.878,335.562) 147.878,335.443 146.444,335.443 146.264,335.443 ccw(c146.264,335.324) 146.145,335.324 146.145,335.086 ccw(c146.264,335.086) 146.264,334.967 146.325,334.967 cw(c146.325,334.848) 146.444,334.848 146.444,332.539 146.047,332.143 145.021,332.143 144.463,332.702 144.463,334.704 144.095,335.072 143.098,335.072 138.577,330.551 138.577,313.505 139.169,312.913 152.175,312.913 153.485,311.603 153.485,308.304 153.324,308.143 153.324,307.929 153.133,307.738 153.133,307.399 153.324,307.208 153.324,306.34 153.937,305.727 154.724,305.727 155.118,305.333 155.118,301.498 155.461,301.155 157.157,301.155 159.644,303.642 163.079,303.642 163.672,304.234 167.227,304.234 168.351,305.359 168.351,306.585 v1(167.909,307.027)
  L16 w0.12: R87.1@142.358,336.008 144.182,336.008 144.638,336.464 v10(146.136,336.464)
MIO_14: R88.1 U1.E18 | length 80.9
  L1 w0.12: v2(165.909,306.027) U1.E18@166.397,305.539
  L3 (Sign) w0.12: v1(153.543,307.569) 153.64,307.569 153.733,307.475 153.654,307.396 153.654,306.213 154.372,305.495 154.615,305.495 154.855,305.255 154.855,305.012 155.004,304.863 156.007,304.863 157.01,305.866 165.003,305.866 165.749,305.867 v2(165.909,306.027)
  L14 (Sign) w0.12: v10(143.599,334.645) 143.599,334.297 143.322,334.02 143.085,333.783 ccw(c143.169,333.699) 143.085,333.614 143.56,333.139 cw(c143.476,333.055) 143.56,332.971 143.392,332.803 cw(c143.308,332.887) 143.224,332.803 142.665,333.362 142.266,333.761 ccw(c142.182,333.677) 142.098,333.761 141.93,333.593 ccw(c142.014,333.509) 141.93,333.425 142.328,333.026 143.153,332.202 cw(c143.069,332.117) 143.153,332.033 142.985,331.865 cw(c142.9,331.949) 142.816,331.865 141.992,332.69 141.593,333.088 ccw(c141.509,333.004) 141.425,333.088 141.257,332.92 ccw(c141.341,332.836) 141.257,332.752 141.656,332.353 142.48,331.529 cw(c142.396,331.445) 142.48,331.361 142.312,331.193 cw(c142.228,331.277) 142.144,331.193 141.319,332.017 140.921,332.416 ccw(c140.837,332.332) 140.753,332.416 140.584,332.247 ccw(c140.669,332.163) 140.584,332.079 140.983,331.681 141.807,330.856 cw(c141.723,330.772) 141.807,330.688 141.639,330.52 cw(c141.555,330.604) 141.471,330.52 140.647,331.344 140.248,331.743 ccw(c140.164,331.659) 140.08,331.743 139.912,331.575 ccw(c139.996,331.491) 139.912,331.407 140.31,331.008 141.135,330.184 cw(c141.051,330.1) 141.135,330.016 140.967,329.847 cw(c140.883,329.931) 140.799,329.847 139.974,330.672 139.576,331.07 ccw(c139.491,330.986) 139.407,331.07 139.239,330.902 ccw(c139.323,330.818) 139.239,330.734 139.638,330.336 140.462,329.511 cw(c140.378,329.427) 140.462,329.343 140.294,329.175 cw(c140.21,329.259) 140.126,329.175 139.302,329.999 139.168,330.133 ccw(c139.084,330.049) 139,330.133 138.832,329.964 ccw(c138.916,329.88) 138.832,329.796 138.881,329.747 cw(c138.797,329.663) 138.881,329.579 138.797,329.495 138.797,313.596 139.26,313.133 152.266,313.133 153.705,311.694 153.705,307.569 v1(153.543,307.569)
  L16 w0.12: R88.1@142.358,334.241 143.195,334.241 v10(143.599,334.645)
MIO_15: R89.1 U1.J19 | length 82.8
  L1 w0.12: v1(169.909,307.027) U1.J19@170.397,306.539
  L14 (Sign) w0.12: v10(145.517,341.173) 145.517,338.232 143.609,336.325 143.106,336.325 137.697,330.916 137.697,313.14 138.804,312.033 151.811,312.033 152.605,311.239 152.605,308.669 152.444,308.507 152.444,308.293 152.253,308.103 152.253,307.034 152.444,306.844 152.444,304.991 153.14,304.295 153.14,302.854 155.278,300.715 157.339,300.715 158.209,301.585 ; 158.217,301.578 158.281,301.642 165.054,301.642 165.928,302.516 167.94,302.516 169.365,303.941 169.365,305.151 169.296,305.22 169.296,306.414 v1(169.909,307.027)
  L16 w0.12: R89.1@141.458,341.31 145.375,341.31 145.377,341.312 v10(145.517,341.173)
MIO_16: R90.1 U1.K17 | length 85.1
  L1 w0.12: v1(170.909,305.027) U1.K17@171.397,304.539
  L14 (Sign) w0.12: v10(144.102,338.645) 144.102,337.44 143.427,336.765 142.924,336.765 137.257,331.098 137.257,312.958 138.622,311.593 151.628,311.593 152.165,311.057 152.165,308.851 152.004,308.69 152.004,308.476 151.813,308.285 151.813,306.852 152.004,306.662 152.004,304.809 152.7,304.113 152.7,302.659 155.171,300.188 159.446,300.188 160.405,301.147 164.004,301.147 164.059,301.202 165.236,301.202 165.471,301.437 166.564,301.437 167.203,302.076 168.328,302.076 168.536,302.284 168.536,302.331 170.909,304.704 v1(170.909,305.027)
  L16 w0.12: R90.1@139.375,338.641 139.38,338.645 140.437,338.645 140.597,338.645 ccw(c140.597,338.764) 140.716,338.764 140.716,338.966 cw(c140.834,338.966) 140.834,339.085 141.072,339.085 cw(c141.072,338.966) 141.191,338.966 141.191,338.645 141.191,338.354 ccw(c141.31,338.354) 141.31,338.235 141.548,338.235 ccw(c141.548,338.354) 141.667,338.354 141.667,338.645 141.667,338.964 cw(c141.786,338.964) 141.786,339.083 142.023,339.083 cw(c142.023,338.964) 142.142,338.964 142.142,338.645 142.142,338.354 ccw(c142.261,338.354) 142.261,338.235 142.499,338.235 ccw(c142.499,338.354) 142.618,338.354 142.618,338.645 142.618,338.966 cw(c142.737,338.966) 142.737,339.085 142.975,339.085 cw(c142.975,338.966) 143.094,338.966 143.094,338.645 143.094,338.129 ccw(c143.212,338.129) 143.212,338.01 143.45,338.01 ccw(c143.45,338.129) 143.569,338.129 143.569,338.527 cw(c143.688,338.527) 143.688,338.645 143.807,338.645 v10(144.102,338.645)
MIO_17: R91.2 U1.C18 | length 75.9
  L1 w0.12: U1.C18@164.397,305.539 164.743,305.194 164.743,304.962 v2(164.768,304.936)
  L3 (Sign) w0.12: v1(153.568,303.746) 153.568,302.698 153.892,302.374 154.246,302.374 154.608,302.374 157.411,305.177 161.397,305.177 164.534,305.177 164.768,304.943 v2(164.768,304.936)
  L14 (Sign) w0.12: v10(145.999,340.436) 145.999,338.214 143.89,336.105 143.197,336.105 137.917,330.825 137.917,313.231 138.895,312.253 151.902,312.253 152.825,311.33 152.825,308.578 152.664,308.416 152.664,308.202 152.473,308.012 152.473,307.125 152.664,306.935 152.664,305.133 153.568,304.228 v1(153.568,303.746)
  L16 w0.12: R91.2@139.375,340.405 139.381,340.411 v10@145.999,340.411
MIO_18: R92.2 U1.K18 | length 85.3
  L1 w0.12: v1(170.909,306.027) U1.K18@171.397,305.539
  L14 (Sign) w0.12: v10@144.958,342.169 144.958,338.952 145.082,338.828 145.082,338.109 143.518,336.545 143.015,336.545 137.477,331.007 137.477,313.049 138.713,311.813 151.719,311.813 152.385,311.148 152.385,308.76 152.224,308.599 152.224,308.385 152.033,308.194 152.033,306.943 152.224,306.753 152.224,304.9 152.92,304.204 152.92,302.75 155.185,300.485 157.435,300.485 158.372,301.422 165.145,301.422 166.019,302.296 168.167,302.296 168.237,302.366 168.237,302.501 170.502,304.766 170.499,304.768 170.499,305.237 170.502,305.239 170.502,305.619 v1(170.909,306.027)
  L16 w0.12: R92.2@139.375,342.169 139.382,342.176 v10(144.958,342.176)
MIO_19: R93.2 U1.K16 | length 85.1
  L1 w0.12: U1.K16@171.397,303.539 v1(171.884,303.052)
  L14 (Sign) w0.12: v10(143.65,342.722) 143.65,337.802 137.037,331.189 137.037,312.867 138.531,311.373 151.537,311.373 151.945,310.965 151.945,308.942 151.784,308.781 151.784,308.567 151.593,308.376 151.593,306.761 151.784,306.57 151.784,304.718 152.48,304.022 152.48,302.568 155.144,299.903 157.676,299.903 157.74,299.968 159.537,299.968 160.109,300.539 168.237,300.539 168.844,301.147 168.844,302.296 169.6,303.052 v1(171.884,303.052)
  L16 w0.12: R93.2@139.368,343.738 140.028,343.078 143.345,343.078 143.65,342.773 v10(143.65,342.722)
MIO_20: R94.2 U1.A19 | length 78
  L1 w0.12: v1(154.064,307.226) 154.786,307.226 155.269,306.743 156.755,306.743 157.238,306.26 162.118,306.26 U1.A19@162.397,306.539
  L14 (Sign) w0.12: v10(143.815,333.832) 143.815,332.384 143.731,332.3 ccw(c143.815,332.216) 143.731,332.132 144.925,330.938 cw(c144.841,330.853) 144.925,330.769 144.757,330.601 cw(c144.673,330.685) 144.589,330.601 143.394,331.796 ccw(c143.31,331.712) 143.226,331.796 143.058,331.628 ccw(c143.142,331.544) 143.058,331.46 144.253,330.265 cw(c144.169,330.181) 144.253,330.097 144.085,329.929 cw(c144.001,330.013) 143.916,329.929 142.722,331.123 ccw(c142.638,331.039) 142.554,331.123 142.386,330.955 ccw(c142.47,330.871) 142.386,330.787 143.58,329.592 cw(c143.496,329.508) 143.58,329.424 143.412,329.256 cw(c143.328,329.34) 143.244,329.256 142.049,330.451 ccw(c141.965,330.367) 141.881,330.451 141.713,330.283 ccw(c141.797,330.198) 141.713,330.114 142.908,328.92 cw(c142.824,328.836) 142.908,328.752 142.739,328.583 cw(c142.655,328.667) 142.571,328.583 141.377,329.778 ccw(c141.293,329.694) 141.208,329.778 141.04,329.61 ccw(c141.124,329.526) 141.04,329.442 142.235,328.247 cw(c142.151,328.163) 142.235,328.079 142.067,327.911 cw(c141.983,327.995) 141.899,327.911 140.704,329.105 ccw(c140.62,329.021) 140.536,329.105 140.368,328.937 ccw(c140.452,328.853) 140.368,328.769 141.562,327.575 cw(c141.478,327.49) 141.562,327.406 141.394,327.238 cw(c141.31,327.322) 141.226,327.238 140.031,328.433 ccw(c139.947,328.349) 139.863,328.433 139.243,327.812 139.23,327.8 139.017,327.587 139.017,313.687 139.351,313.353 152.357,313.353 153.925,311.786 153.925,308.304 154.178,308.051 154.178,307.492 154.064,307.378 v1(154.064,307.226)
  L16 w0.12: R94.2@139.375,333.348 139.376,333.35 143.332,333.35 v10(143.815,333.832) ; v1@154.064,307.175 v1(154.064,307.226)
MIO_21: R95.1 U1.H19 | length 85.7
  L1 w0.12: v1(168.909,307.027) U1.H19@169.397,306.539
  L14 (Sign) w0.12: v10(145.161,335.801) 145.161,336.193 145.886,336.918 146.486,336.918 146.639,337.071 146.639,337.553 146.486,337.706 145.885,337.706 143.691,335.512 142.916,335.512 138.137,330.733 138.137,313.322 138.986,312.473 151.993,312.473 153.045,311.421 153.045,308.487 152.884,308.325 152.884,308.111 152.693,307.921 152.693,307.217 152.884,307.026 152.884,305.406 154.898,303.391 154.898,301.407 155.37,300.935 157.248,300.935 159.697,303.384 165.397,303.384 166.028,304.014 167.318,304.014 168.571,305.268 168.571,305.274 168.747,305.45 168.747,306.694 168.909,306.857 v1(168.909,307.027)
  L16 w0.12: R95.1@140.31,335.115 140.696,335.115 140.815,335.115 ccw(c140.815,335.234) 140.934,335.234 140.934,335.429 cw(c141.052,335.429) 141.052,335.548 141.29,335.548 cw(c141.29,335.429) 141.409,335.429 141.409,335.115 141.409,334.82 ccw(c141.528,334.82) 141.528,334.701 141.766,334.701 ccw(c141.766,334.82) 141.885,334.82 141.885,335.115 141.885,335.429 cw(c142.004,335.429) 142.004,335.548 142.241,335.548 cw(c142.241,335.429) 142.36,335.429 142.36,335.115 142.36,334.82 ccw(c142.479,334.82) 142.479,334.701 142.717,334.701 ccw(c142.717,334.82) 142.836,334.82 142.836,335.115 142.836,335.579 cw(c142.955,335.579) 142.955,335.698 143.193,335.698 cw(c143.193,335.579) 143.312,335.579 143.312,335.234 ccw(c143.43,335.234) 143.43,335.115 143.535,335.115 143.904,335.115 144.589,335.801 v10(145.161,335.801)
MIO_22: R96.1 U1.F17 | length 82.5
  L1 w0.12: U1.F17@167.397,304.539 v2(167.884,304.052)
  L3 (Sign) w0.12: v1(152.07,303.682) 153.606,302.146 154.691,302.146 157.502,304.957 161.397,304.957 164.341,304.957 165.247,304.052 v2(167.884,304.052)
  L14 (Sign) w0.12: v10(142.929,337.682) 141.679,337.682 139.304,335.308 139.068,335.072 cw(c138.984,335.156) 138.9,335.072 137.763,336.209 ccw(c137.679,336.125) 137.595,336.209 137.427,336.041 ccw(c137.511,335.956) 137.427,335.872 138.648,334.652 139.095,334.204 cw(c139.011,334.12) 139.095,334.036 138.927,333.868 cw(c138.843,333.952) 138.759,333.868 138.312,334.315 137.091,335.536 ccw(c137.007,335.452) 136.923,335.536 136.755,335.368 ccw(c136.839,335.284) 136.755,335.2 137.975,333.979 138.423,333.532 cw(c138.339,333.448) 138.423,333.364 138.254,333.195 cw(c138.17,333.279) 138.086,333.195 137.639,333.643 137.042,334.24 ccw(c136.958,334.156) 136.874,334.24 136.706,334.071 ccw(c136.79,333.987) 136.706,333.903 137.219,333.39 cw(c137.135,333.306) 137.219,333.222 137.135,333.138 136.817,332.821 136.817,312.776 138.44,311.153 151.446,311.153 151.725,310.874 151.725,309.033 151.564,308.872 151.564,308.658 151.373,308.467 151.373,306.67 151.564,306.479 151.564,304.627 152.004,304.187 152.004,303.749 v1(152.07,303.682)
  L16 w0.12: R96.1@142.358,337.776 142.836,337.776 v10(142.929,337.682)
MIO_23: R781.2 U1.K19 | length 161.3
  L1 w0.12: v1(170.909,307.027) U1.K19@171.397,306.539
  L5 (Sign) w0.2: v6(105.057,341.906) 105.057,346.074 107.158,348.176 v6(107.158,348.564) ; v1(118.085,399.859) 121.399,396.545 121.399,382.956 v6(120.151,381.707)
  L12 (Sign) w0.12: v1(146.947,330.664) 148.192,331.91 152.43,331.91 154.42,329.92 154.42,311.025 158.012,307.433 161.397,307.433 167.736,307.433 167.74,307.437 170.499,307.437 v1(170.909,307.027)
  L3 (Sign) w0.12: 118.53,334.544 118.541,334.532 ; 144.384,332.855 144.719,332.52 145.128,332.52 145.139,332.508
  L3 (Sign) w0.2: v6(105.057,341.906) 107.019,341.906 114.421,334.504 118.513,334.504 120.201,332.815 144.367,332.815 144.703,332.48 145.111,332.48 145.777,331.814 145.834,331.814 146.947,330.701 v1(146.947,330.664) ; v6(107.158,348.564) 107.158,361.577 120.174,374.593 120.174,381.684 v6(120.151,381.707)
  L16 w0.2: R781.2@116.924,399.809 116.975,399.859 v1(118.085,399.859)
MIO_24: R782.2 U1.A18 | length 78
  L1 w0.12: v1(153.683,305.359) 153.786,305.359 153.922,305.495 154.295,305.495 155.3,306.5 156.687,306.5 157.648,305.539 U1.A18@162.397,305.539
  L14 (Sign) w0.12: v10(145.123,334.95) 144.78,335.292 143.007,335.292 138.357,330.642 138.357,313.413 139.077,312.693 152.084,312.693 153.265,311.512 153.265,308.395 153.104,308.234 153.104,308.02 152.913,307.83 152.913,307.308 153.104,307.117 153.104,305.938 v1(153.683,305.359)
  L16 w0.12: R782.2@142.358,332.473 142.739,332.092 142.964,332.092 143.212,332.34 143.405,332.533 cw(c143.489,332.449) 143.573,332.533 144.761,331.346 ccw(c144.845,331.43) 144.929,331.346 145.097,331.514 ccw(c145.013,331.598) 145.097,331.682 143.825,332.954 cw(c143.91,333.038) 143.825,333.122 143.994,333.29 cw(c144.078,333.206) 144.162,333.29 146.103,331.349 ccw(c146.187,331.433) 146.271,331.349 146.439,331.517 ccw(c146.355,331.601) 146.439,331.686 144.498,333.626 144.446,333.679 cw(c144.53,333.763) 144.446,333.847 144.614,334.015 cw(c144.698,333.931) 144.782,334.015 144.834,333.963 146.775,332.022 ccw(c146.859,332.106) 146.943,332.022 147.112,332.19 ccw(c147.028,332.274) 147.112,332.358 145.255,334.215 cw(c145.339,334.299) 145.255,334.383 145.339,334.467 145.339,334.734 v10(145.123,334.95)
MIO_25: R783.2 U1.B18 | length 184.3
  L1 w0.12: v2(157.118,297.109) 157.144,297.084 157.245,297.084 157.277,297.052 158.724,297.052 159.165,297.494 159.165,302.327 v2(158.483,303.009) ; v2(158.026,304.635) 158.436,305.045 162.902,305.045 U1.B18@163.397,305.539
  L1 w0.5: v1(201.471,166.789) 203.441,166.789 204.995,165.235 204.995,162.051 205.867,161.18 R783.2@205.867,159.149
  L5 (Sign) w0.2: v1(196.162,179.692) 196.162,174.066 200.753,169.475 200.753,167.507 v1(201.471,166.789)
  L3 (Sign) w0.12: v2(157.118,297.109) 157.144,297.084 157.144,296.863 157.185,296.822 157.185,296.702 154.225,293.741 154.225,291.178 154.776,290.627 154.776,284.701 161.667,277.81 171.703,277.81 172.716,276.796 v1(173.05,276.796) ; v2(158.026,304.635) 158.026,303.466 v2(158.483,303.009)
  L14 (Sign) w0.12: v1(173.05,276.796) 172.415,276.161 172.415,274.383 172.445,274.353 172.445,274.014 172.009,273.577 172.009,254.889 193.154,233.743 193.154,189.395 196.162,186.387 v1(196.162,179.692)
MIO_26: R784.2 U1.B20 | length 171.8
  L1 w0.12: R784.2@43.16,366.145 v2(44.628,366.145) ; v2(141.139,309.889) 141.639,309.889 143.537,311.787 154.557,311.787 158.317,308.027 162.909,308.027 U1.B20@163.397,307.539
  L3 (Sign) w0.12: v2(44.628,366.145) 44.615,366.133 44.615,365.582 44.571,365.538 44.571,346.741 50.629,340.683 57.587,340.683 58.445,341.541 59.29,341.541 60.292,340.539 60.504,340.539 76.856,324.187 76.856,323.822 104.112,296.567 112.789,296.567 114.025,297.804 114.025,301.008 122.131,309.114 131.881,309.114 132.345,308.65 135.963,308.65 136.24,308.927 139.099,308.927 140.057,309.884 140.078,309.884 140.083,309.889 v2(141.139,309.889)
MIO_27: R785.2 U1.B21 | length 172.1
  L1 w0.12: R785.2@43.176,367.69 v2(45.034,367.69) ; v2(141.09,310.718) 141.846,310.718 143.355,312.227 154.748,312.227 157.948,309.027 162.909,309.027 U1.B21@163.397,308.539
  L3 (Sign) w0.12: v2(45.034,367.69) 45.034,366.688 45.183,366.54 45.183,365.528 45.055,365.4 45.055,346.968 49.82,342.203 59.485,342.203 77.296,324.392 77.296,324.005 104.294,297.007 112.607,297.007 113.585,297.986 113.585,301.191 121.949,309.554 132.063,309.554 132.527,309.09 135.781,309.09 136.058,309.367 138.729,309.367 140.081,310.718 v2(141.09,310.718)
MIO_28: R786.2 U1.A21 | length 172.6
  L1 w0.12: R786.2@43.175,369.252 v2(44.602,369.252) ; v2(140.297,310.35) 141.789,310.35 143.446,312.007 154.655,312.007 158.122,308.539 U1.A21@162.397,308.539
  L3 (Sign) w0.12: v2(44.602,369.252) 44.602,366.809 44.963,366.448 44.963,365.619 44.791,365.447 44.791,346.877 49.685,341.983 59.371,341.983 77.076,324.278 77.076,323.913 104.203,296.787 112.698,296.787 113.805,297.895 113.805,301.099 122.04,309.334 131.972,309.334 132.436,308.87 135.872,308.87 136.149,309.147 138.831,309.147 140.034,310.35 v2(140.297,310.35)
MIO_29: R787.2 U1.D21 | length 194.4
  L1 w0.12: R787.2@43.16,370.828 43.186,370.802 v2(44.374,370.802) ; v2(164.909,309.059) 164.909,309.027 U1.D21@165.397,308.539
  L3 (Sign) w0.12: v2(44.374,370.802) 44.069,370.497 44.069,365.999 44.351,365.717 44.351,346.643 50.565,340.43 59.378,340.43 64.393,335.416 64.397,335.416 103.809,296.003 110.079,296.003 121.267,284.815 144.645,284.815 149.326,289.496 149.326,306.657 150.962,308.293 151.655,308.293 153.47,310.109 156.384,310.109 158.183,308.309 161.554,308.309 162.322,309.077 163.219,309.077 163.56,309.419 164.096,309.419 164.488,309.027 164.608,309.027 164.615,309.033 164.884,309.033 v2(164.909,309.059)
MIO_30: R788.2 U1.C21 | length 26.7
  L1 w0.12: v2(163.909,309.059) 163.909,309.027 U1.C21@164.397,308.539
  L5 (Sign) w0.12: v1(147.104,309.88) 147.104,308.87 149.447,306.527 v6(149.956,306.527)
  L3 (Sign) w0.12: v6(149.956,306.527) 150.34,306.527 153.702,309.889 156.293,309.889 158.092,308.089 161.645,308.089 162.413,308.857 163.31,308.857 163.512,309.059 v2(163.909,309.059)
  L16 w0.12: v1(147.104,309.88) 147.113,309.88 149.299,312.067 R788.2@149.299,313.665
MIO_31: R789.2 U1.A22 | length 174.9
  L1 w0.12: R789.2@43.16,372.389 v2(44.285,372.389) ; v2(140.466,311.125) 141.942,311.125 143.264,312.447 154.85,312.447 157.757,309.539 U1.A22@162.397,309.539
  L3 (Sign) w0.12: v2(44.285,372.389) 45.682,370.992 45.682,365.716 45.275,365.309 45.275,347.167 50.019,342.423 59.648,342.423 77.516,324.555 77.516,324.096 104.385,297.227 112.516,297.227 113.365,298.077 113.365,301.282 121.858,309.774 132.154,309.774 132.619,309.31 135.69,309.31 135.977,309.597 138.628,309.597 140.156,311.125 v2(140.466,311.125)
MIO_32: R790.2 U1.G20 | length 155.8
  L1 w0.12: v1(167.909,308.027) U1.G20@168.397,307.539
  L1 w0.2: R790.2@46.199,332.365 46.199,333.225 46.632,333.659 52.466,333.659 54.841,336.034 v1(54.841,336.69)
  L5 (Sign) w0.2: v6(55.528,338.714) 56.232,339.419 70.916,339.419 v6(71.844,338.491)
  L12 (Sign) w0.12: v1(146.347,330.664) 147.812,332.13 152.521,332.13 154.64,330.011 154.64,311.117 157.184,308.572 167.364,308.572 v1(167.909,308.027)
  L3 (Sign) w0.2: v1(54.841,336.69) 54.841,338.028 v6(55.528,338.714) ; v6(71.844,338.491) 73.19,338.491 74.27,337.411 78.786,337.411 81,339.625 86.122,339.625 88.012,341.514 99.918,341.514 100.069,341.363 106.965,341.363 114.254,334.075 118.331,334.075 120.026,332.379 144.379,332.379 145.047,331.711 145.449,331.711 146.347,330.814 v1(146.347,330.664)
MIO_33: R791.2 U1.C22 | length 178.4
  L1 w0.12: v2(163.909,310.027) U1.C22@164.397,309.539
  L1 w0.2: R791.2@43.646,332.365 43.646,333.575 44.03,333.959 51.547,333.959 54.241,336.653 v1(54.241,336.69)
  L5 (Sign) w0.2: v1(54.241,336.69) 54.241,336.419 54.42,336.24 55.989,336.24 56.49,335.739 63.953,335.739 81.807,317.884 81.807,305.351 89.029,298.129 110.888,298.129 112.661,296.356 112.661,290.837 112.664,290.834 112.664,290.81 113.126,290.347 115.367,290.347 v6(116.294,291.274)
  L3 (Sign) w0.12: v6(116.294,291.274) 116.318,291.25 116.318,290.845 121.908,285.255 144.463,285.255 148.886,289.678 148.886,306.84 150.78,308.733 151.473,308.733 153.305,310.566 156.549,310.566 158.365,308.749 161.372,308.749 162.14,309.517 163.036,309.517 163.546,310.027 v2(163.909,310.027)
MIO_34: R792.2 U1.B24 | length 157.1
  L1 w0.12: v2(158.505,312.166) 160.146,312.166 160.286,312.027 162.909,312.027 U1.B24@163.397,311.539
  L1 w0.2: R792.2@41.335,332.365 41.335,333.689 41.905,334.259 50.515,334.259 v1(53.035,336.779)
  L5 (Sign) w0.2: v1(53.035,336.779) 53.035,337.257 53.263,337.485 56.229,337.485 57.075,336.639 64.325,336.639 82.707,318.257 82.707,305.724 89.402,299.029 111.261,299.029 111.815,298.475 v1(112.027,298.475)
  L3 (Sign) w0.12: v1(112.027,298.475) 112.925,299.374 112.925,301.464 121.676,310.214 132.336,310.214 132.801,309.75 135.508,309.75 137.581,311.824 147.898,311.824 149.182,313.107 153.122,313.107 153.85,312.379 157.775,312.379 157.987,312.166 v2(158.505,312.166)
MIO_35: R793.2 U1.B23 | length 160.8
  L1 w0.12: v2(158.877,310.965) 159.366,311.455 161.742,311.455 162.237,310.959 162.691,310.959 163.111,310.539 U1.B23@163.397,310.539
  L1 w0.2: R793.2@38.731,332.365 38.731,333.894 39.396,334.559 49.815,334.559 51.295,336.039 v1(51.606,336.039)
  L5 (Sign) w0.2: v1(51.606,336.039) 52.932,336.039 53.607,336.714 53.607,336.791 54,337.185 56.104,337.185 56.951,336.339 64.201,336.339 82.407,318.133 82.407,305.6 89.278,298.729 111.136,298.729 111.84,298.025 112.734,298.025 v6(112.955,298.247)
  L3 (Sign) w0.12: v6(112.955,298.247) 113.145,298.437 113.145,301.373 121.767,309.994 132.245,309.994 132.71,309.53 135.599,309.53 137.673,311.604 147.989,311.604 149.273,312.887 152.894,312.887 153.662,312.119 157.723,312.119 v2(158.877,310.965)
MIO_36: R794.2 U1.D22 | length 186.7
  L1 w0.12: v2(164.909,310.027) U1.D22@165.397,309.539
  L1 w0.2: R794.2@36.407,332.365 36.407,333.486 37.919,334.997 49.704,334.997 52.172,337.464 55.189,337.464 v1(55.918,336.735)
  L5 (Sign) w0.2: v1(55.918,336.735) 56.614,336.039 64.077,336.039 82.107,318.009 82.107,305.475 89.153,298.429 111.012,298.429 112.961,296.48 112.961,290.961 112.964,290.958 112.964,290.934 113.251,290.647 114.879,290.647 v6(115.506,291.274)
  L3 (Sign) w0.12: v6(115.506,291.274) 121.746,285.035 144.554,285.035 149.106,289.587 149.106,306.748 150.871,308.513 151.564,308.513 153.388,310.337 156.466,310.337 158.274,308.529 161.463,308.529 162.231,309.297 163.127,309.297 163.469,309.639 164.521,309.639 v2(164.909,310.027)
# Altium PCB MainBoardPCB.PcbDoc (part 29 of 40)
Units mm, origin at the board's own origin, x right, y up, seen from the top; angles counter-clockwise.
Board outline 258.95 x 308.86 mm, 16 copper layers (L1, L2 (GND), L3 (Sign), L4 (GND), L5 (Sign), L6 (PWR/GND), L7(12V+Other), L8 (Plane_GND), L9 (PWR/GND), L10 (3V3+Other), L11 (PWR/GND), L12 (Sign), L13 (GND), L14 (Sign), L15 (GND), L16), stack 2.503 mm thick; 2578 components, 1867 nets, 8817 pads, 8021 vias.
Unrouted connection lines stored in the file: 25.

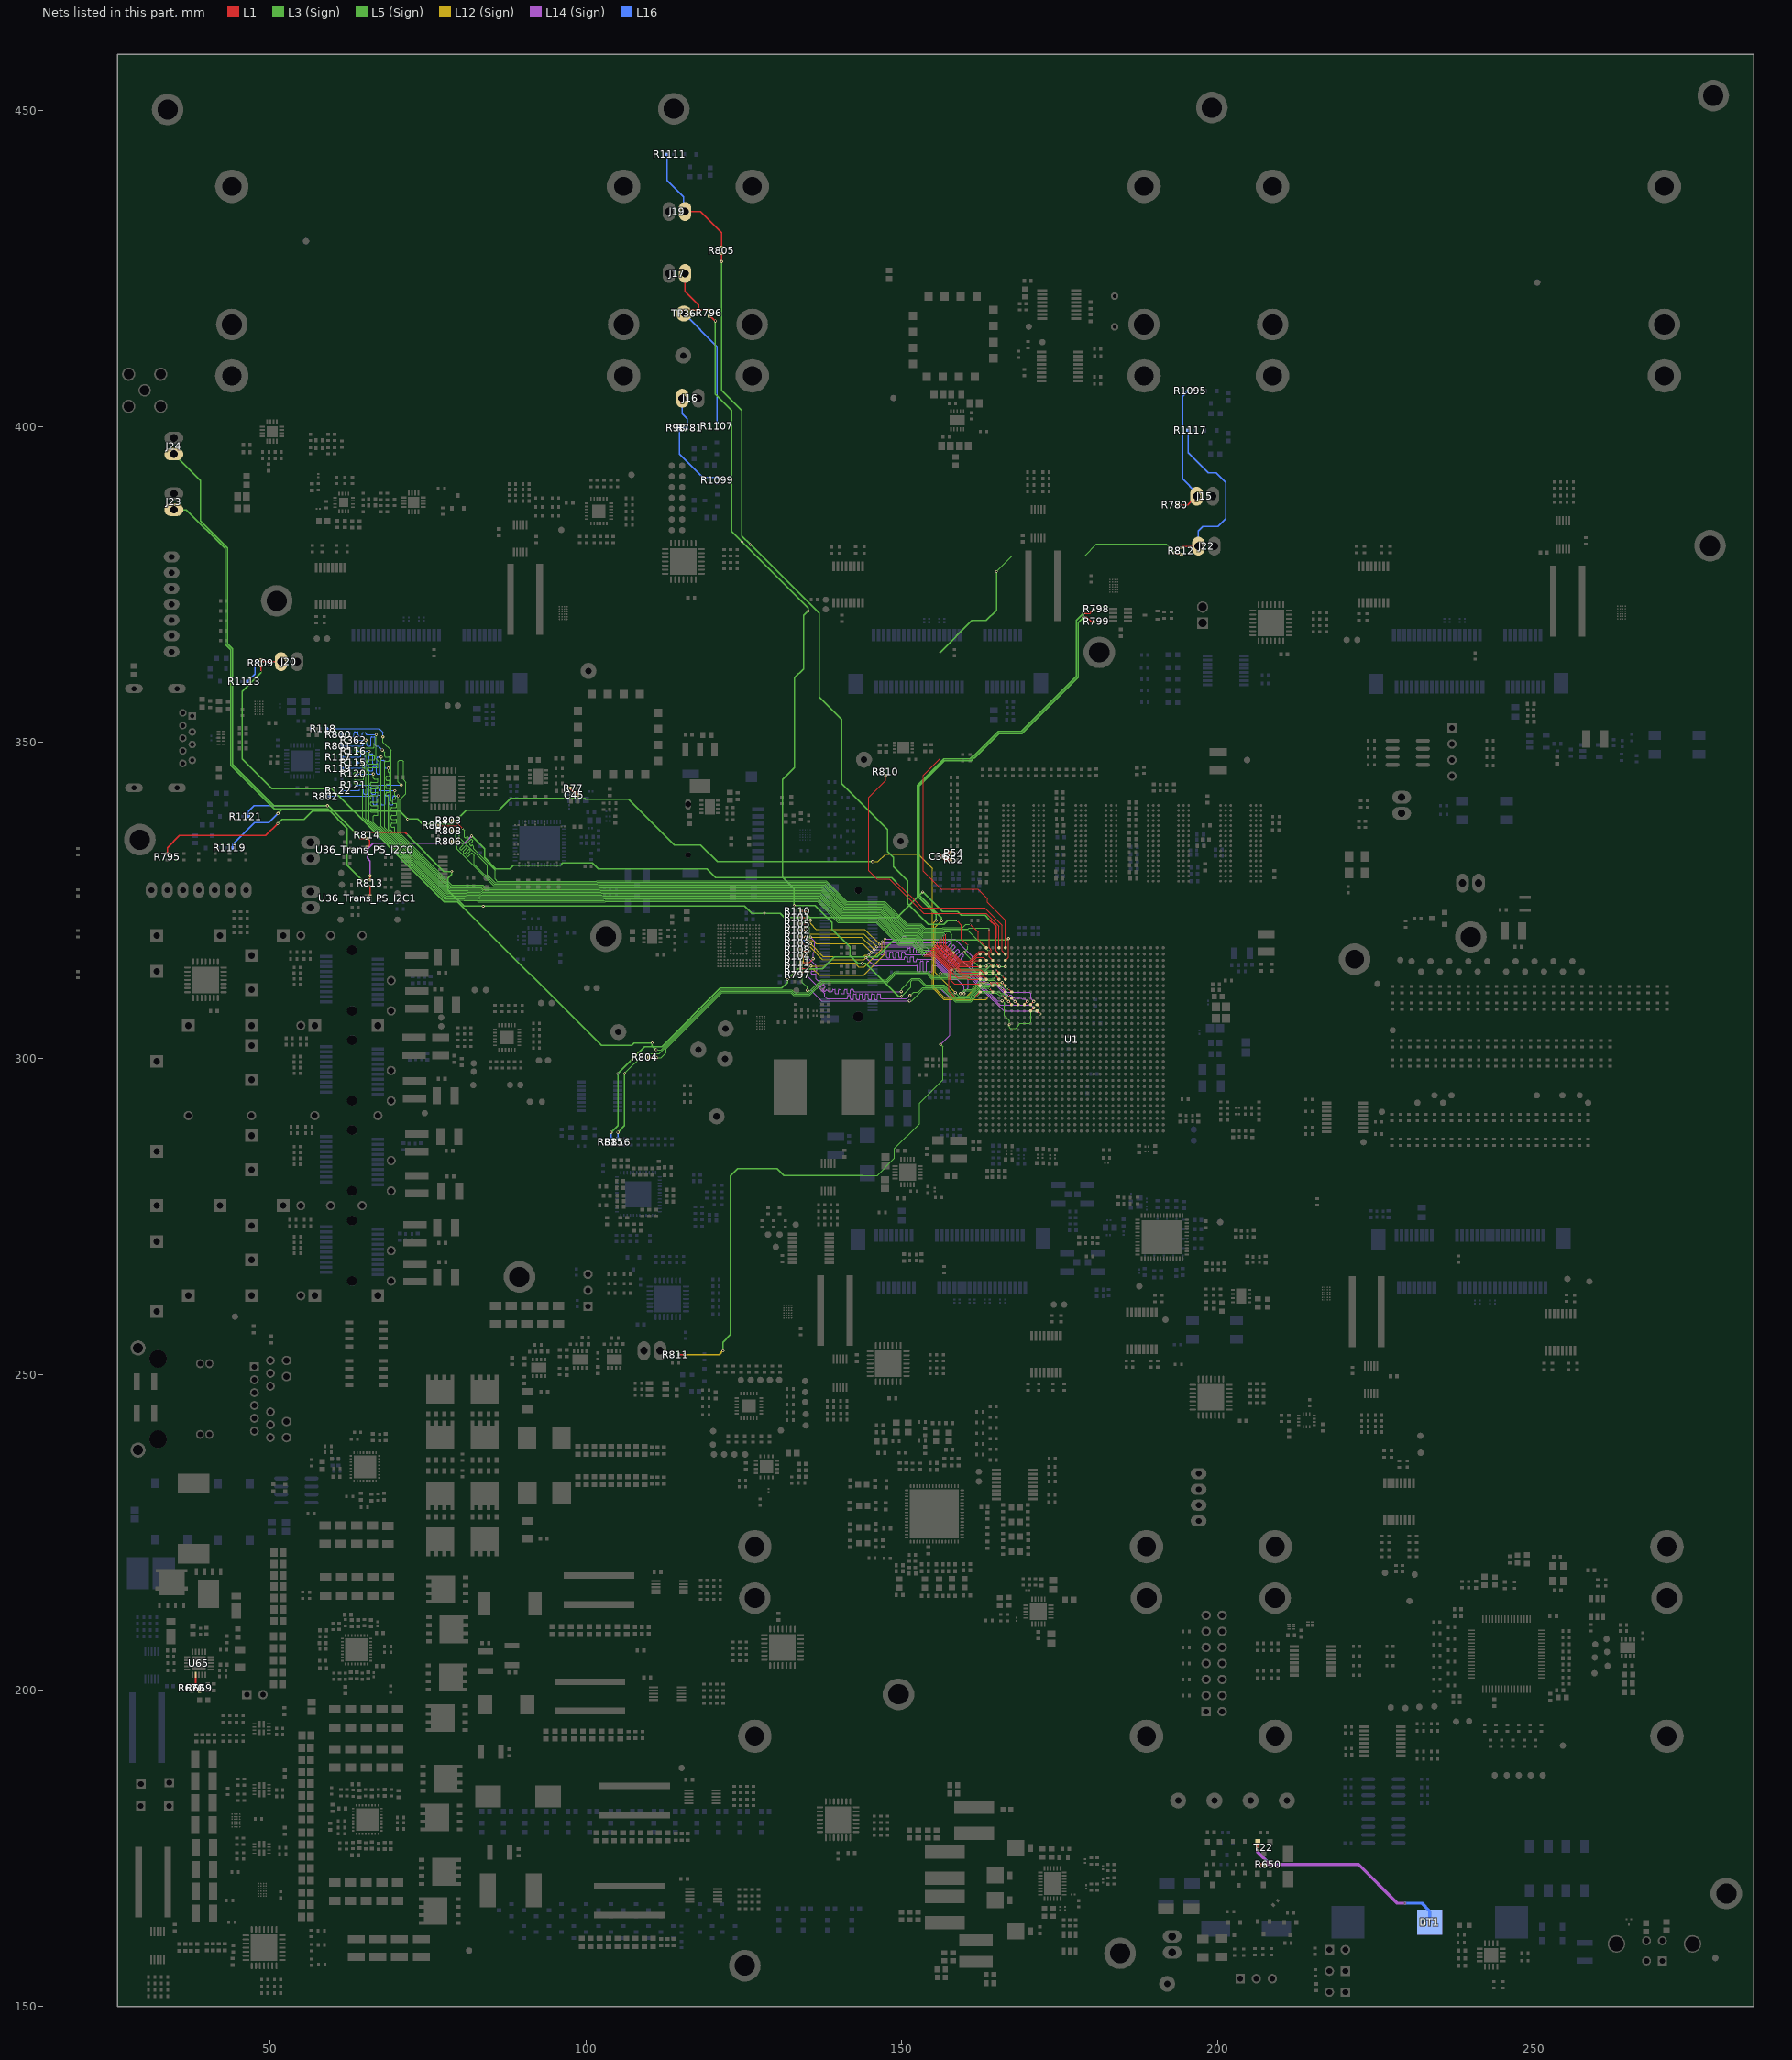
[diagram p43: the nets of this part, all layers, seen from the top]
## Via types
v1: diameter 0.5, hole 0.25, L1 to L16, tented both sides, 4341 vias
v2: diameter 0.254, hole 0.1, L1 to L3 (Sign), tented both sides, 781 vias
v3: diameter 0.5, hole 0.25, L1 to L16, 565 vias
v4: diameter 0.254, hole 0.1, L15 (GND) to L16, tented both sides, 406 vias
v5: diameter 0.254, hole 0.1, L1 to L2 (GND), tented both sides, 283 vias
v6: diameter 0.457, hole 0.2, L3 (Sign) to L6 (PWR/GND), tented both sides, 254 vias
v7: diameter 0.254, hole 0.1, L1 to L3 (Sign), 237 vias
v8: diameter 0.75, hole 0.4, L1 to L16, 200 vias
v9: diameter 0.8, hole 0.4, L1 to L16, tented both sides, 182 vias
v10: diameter 0.254, hole 0.1, L14 (Sign) to L16, tented both sides, 170 vias
v11: diameter 0.75/0/0/0/0/0/0/0/0/0/0/0/0/0/0/0.75 (per signal layer), hole 0.4, L1 to L16, 160 vias
v12: diameter 0.457, hole 0.2, L3 (Sign) to L6 (PWR/GND), 158 vias
v13: diameter 1.4, hole 0.5, L1 to L16, tented both sides, 80 vias
v14: diameter 0.254, hole 0.1, L14 (Sign) to L16, 65 vias
v15: diameter 0.254, hole 0.1, L1 to L2 (GND), 45 vias
v16: diameter 0.457, hole 0.2, L11 (PWR/GND) to L14 (Sign), tented both sides, 26 vias
v17: diameter 0.457, hole 0.2, L11 (PWR/GND) to L14 (Sign), 25 vias
v18: diameter 0.457, hole 0.2, L7(12V+Other) to L10 (3V3+Other), tented both sides, 11 vias
v19: diameter 0.254/0/0.254 (per signal layer), hole 0.1, L1 to L3 (Sign), 9 vias
v20: diameter 0.2/0/0.2 (per signal layer), hole 0.1, L1 to L3 (Sign), 6 vias
v21: diameter 1.65, hole 1.65, L1 to L16, 5 vias
v22: diameter 1.15, hole 1.15, L1 to L16, 5 vias
v23: diameter 0.457, hole 0.2, L1 to L16, 3 vias
v24: diameter 0.5, hole 0.3, L1 to L16, 2 vias
v25: diameter 0.5/0/0.5 (per signal layer), hole 0.2, L14 (Sign) to L16, 1 vias
v26: diameter 0.5, hole 0.25, L1 to L16, tented bottom, 1 vias

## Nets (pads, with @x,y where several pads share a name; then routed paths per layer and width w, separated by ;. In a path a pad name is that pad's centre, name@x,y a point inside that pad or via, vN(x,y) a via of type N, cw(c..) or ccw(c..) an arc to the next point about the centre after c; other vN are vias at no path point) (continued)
MIO_37: R795.2 U1.F21 | length 165.5
  L1 w0.12: v1(166.909,309.027) U1.F21@167.397,308.539
  L1 w0.2: R795.2@33.766,332.365 33.766,333.384 35.679,335.297 49.344,335.297 v1(51.244,337.198)
  L5 (Sign) w0.2: v1(51.244,337.198) 51.905,337.858 55.45,337.858 56.71,339.119 70.545,339.119 v6(71.78,337.883)
  L12 (Sign) w0.12: v1(145.377,331.147) 146.229,331.147 147.432,332.35 152.612,332.35 154.86,330.102 154.86,311.208 156.704,309.364 160.094,309.364 160.1,309.369 163.326,309.369 163.697,309.74 166.196,309.74 v1(166.909,309.027)
  L3 (Sign) w0.2: v6(71.78,337.883) 73.373,337.883 74.146,337.111 78.91,337.111 81.124,339.325 86.247,339.325 88.136,341.214 99.793,341.214 99.944,341.063 106.757,341.063 114.046,333.775 118.177,333.775 120.805,331.147 v1(145.377,331.147)
MIO_38: R796.2 U1.C23 | length 145
  L1 w0.12: v2(163.909,311.027) U1.C23@164.397,310.539
  L1 w0.2: R796.2@119.532,417.514 119.706,417.514 v1(120.51,416.71)
  L5 (Sign) w0.2: v1(120.51,416.71) 120.51,405.143 123.101,402.552 123.101,383.375 v6(124.727,381.749) ; v6(132.969,324.231) 132.969,326.857 131.153,328.674 131.153,344.132 133.058,346.037 133.058,360.261 134.468,361.671 134.468,370.106 135.179,370.817 v6(135.206,370.817) ; v1(143.774,315.1) 144.247,315.1 149.505,309.842 v6(149.974,309.842)
  L3 (Sign) w0.12: v6(149.974,309.842) 151.427,311.294 151.427,312.177 151.697,312.447 152.712,312.447 153.7,311.459 156.589,311.459 158.639,309.409 160.788,309.409 161.397,310.019 162.545,311.167 163.707,311.167 163.847,311.027 v2(163.909,311.027)
  L3 (Sign) w0.2: v6(124.727,381.749) 135.206,371.27 v6(135.206,370.817) ; v6(132.969,324.231) 136.322,324.231 139.001,321.551 139.001,320.471 141.821,317.652 141.821,316.338 143.06,315.1 v1(143.774,315.1)
MIO_39: R101.1 U1.E22 | length 47.5
  L1 w0.12: R101.1@134.016,322.351 134.026,322.341 v2(134.788,322.341) ; v2(165.909,309.969) 165.938,309.969 166.368,309.539 U1.E22@166.397,309.539
  L3 (Sign) w0.12: v2(134.788,322.341) 134.788,321.795 134.29,321.297 134.29,312.052 135.064,311.277 v1(135.064,310.82) ; v1(151.255,309.143) 151.572,309.143 153.447,311.019 156.407,311.019 158.456,308.969 160.97,308.969 162.437,310.437 163.95,310.437 164.003,310.384 165.003,310.384 165.418,309.969 v2(165.909,309.969)
  L14 (Sign) w0.12: v1(135.064,310.82) 135.628,310.82 137.304,309.143 v1(151.255,309.143)
MIO_40: R102.1 U1.C24 | length 42.4
  L1 w0.12: R102.1@134.016,320.319 134.556,320.319 v1(134.722,320.484) v1@134.734,320.497 ; v2(163.909,312.075) 163.909,312.027 U1.C24@164.397,311.539
  L12 (Sign) w0.12: v1(135.547,318.198) 137.554,316.192 143.993,316.192 144.19,316.39 v16(144.787,316.39)
  L3 (Sign) w0.12: v1(159.88,310.261) 159.88,310.515 160.109,310.744 161.188,310.744 161.397,310.952 162.289,311.844 163.504,311.844 163.709,312.049 163.884,312.049 v2(163.909,312.075)
  L14 (Sign) w0.12: v16(144.787,316.39) 145.455,315.722 150.292,315.722 150.331,315.722 ccw(c150.331,315.841) 150.45,315.841 150.45,315.982 cw(c150.569,315.982) 150.569,316.101 150.807,316.101 cw(c150.807,315.982) 150.926,315.982 150.926,315.722 150.926,315.462 ccw(c151.045,315.462) 151.045,315.343 151.283,315.343 ccw(c151.283,315.462) 151.402,315.462 151.402,315.722 151.402,315.982 cw(c151.52,315.982) 151.52,316.101 151.758,316.101 cw(c151.758,315.982) 151.877,315.982 151.877,315.722 151.877,315.462 ccw(c151.996,315.462) 151.996,315.343 152.234,315.343 ccw(c152.234,315.462) 152.353,315.462 152.353,315.603 cw(c152.472,315.603) 152.472,315.722 152.59,315.722 154.805,315.722 157.748,312.779 160.254,312.779 160.541,312.493 160.541,311.175 159.88,310.515 v1(159.88,310.261)
  L16 w0.12: v1(134.722,320.484) 134.722,320.434 134.141,319.853 134.141,319.053 134.995,318.198 v1(135.547,318.198)
MIO_41: R103.1 U1.D24 | length 45.8
  L1 w0.12: R103.1@134.016,318.287 134.325,318.287 v1(134.95,317.662) ; v2(164.909,312.114) 164.909,312.027 U1.D24@165.397,311.539
  L12 (Sign) w0.12: v1(134.95,317.662) 135.461,317.662 137.465,315.659 144.056,315.659 v16(144.363,315.965)
  L3 (Sign) w0.12: v1(159.271,310.261) 159.982,310.972 161.106,310.972 161.397,311.263 162.496,312.362 164.662,312.362 v2(164.909,312.114)
  L14 (Sign) w0.12: v16(144.363,315.965) 145.586,314.742 152.159,314.742 152.345,314.742 cw(c152.345,314.623) 152.464,314.623 152.464,313.871 ccw(c152.583,313.871) 152.583,313.752 152.821,313.752 ccw(c152.821,313.871) 152.94,313.871 152.94,314.742 152.94,315.307 cw(c153.058,315.307) 153.058,315.426 153.296,315.426 cw(c153.296,315.307) 153.415,315.307 153.415,314.742 153.415,313.871 ccw(c153.534,313.871) 153.534,313.752 153.772,313.752 ccw(c153.772,313.871) 153.891,313.871 153.891,314.742 153.891,315.307 cw(c154.01,315.307) 154.01,315.426 154.247,315.426 cw(c154.247,315.307) 154.366,315.307 154.366,314.742 154.366,313.871 ccw(c154.485,313.871) 154.485,313.752 154.723,313.752 ccw(c154.723,313.871) 154.842,313.871 154.842,314.623 cw(c154.961,314.623) 154.961,314.742 155.08,314.742 155.474,314.742 157.669,312.547 158.744,312.547 159.832,311.459 159.832,310.822 v1(159.271,310.261)
MIO_42: R104.1 U1.E23 | length 47.2
  L1 w0.12: R104.1@134.016,316.255 v1(134.996,316.255) ; v2(165.922,311.039) 165.922,311.027 166.397,310.552 U1.E23@166.397,310.539
  L12 (Sign) w0.12: v1@149.914,310.591 v1(149.927,310.604)
  L3 (Sign) w0.12: v1(149.927,310.604) 149.973,310.65 149.973,311.034 151.606,312.667 152.803,312.667 153.791,311.679 156.68,311.679 158.73,309.629 160.696,309.629 161.397,310.33 162.472,311.404 163.956,311.404 164.159,311.607 165.329,311.607 165.897,311.039 v2(165.922,311.039)
  L14 (Sign) w0.12: v1(134.996,316.255) 134.996,316.178 136.449,314.725 136.449,314.579 136.449,314.371 ccw(c136.478,314.371) 136.478,314.341 cw(c136.478,314.222) 136.597,314.222 136.597,313.985 cw(c136.478,313.985) 136.478,313.866 136.449,313.866 135.807,313.866 ccw(c135.807,313.747) 135.688,313.747 135.688,313.509 ccw(c135.807,313.509) 135.807,313.39 136.33,313.39 cw(c136.33,313.271) 136.449,313.271 136.449,313.195 136.449,312.585 136.61,312.424 136.739,312.295 ccw(c136.778,312.335) 136.818,312.295 cw(c136.902,312.211) 136.986,312.295 137.155,312.127 cw(c137.07,312.043) 137.155,311.959 137.115,311.919 136.876,311.681 ccw(c136.96,311.596) 136.876,311.512 137.044,311.344 ccw(c137.128,311.428) 137.212,311.344 137.451,311.583 137.491,311.623 cw(c137.575,311.539) 137.659,311.623 137.827,311.454 cw(c137.743,311.37) 137.827,311.286 137.787,311.247 137.549,311.008 ccw(c137.633,310.924) 137.549,310.84 137.717,310.672 ccw(c137.801,310.756) 137.885,310.672 138.04,310.826 cw(c138.124,310.742) 138.208,310.826 138.303,310.731 138.43,310.604 138.786,310.604 138.904,310.604 ccw(c138.904,310.723) 139.023,310.723 139.023,310.812 cw(c139.142,310.812) 139.142,310.931 139.38,310.931 cw(c139.38,310.812) 139.499,310.812 139.499,310.604 139.499,310.37 ccw(c139.618,310.37) 139.618,310.251 139.856,310.251 ccw(c139.856,310.37) 139.975,310.37 139.975,310.604 139.975,310.812 cw(c140.093,310.812) 140.093,310.931 140.331,310.931 cw(c140.331,310.812) 140.45,310.812 140.45,310.604 140.45,310.37 ccw(c140.569,310.37) 140.569,310.251 140.807,310.251 ccw(c140.807,310.37) 140.926,310.37 140.926,310.604 140.926,310.812 cw(c141.045,310.812) 141.045,310.931 141.282,310.931 cw(c141.282,310.812) 141.401,310.812 141.401,310.604 141.401,310.37 ccw(c141.52,310.37) 141.52,310.251 141.758,310.251 ccw(c141.758,310.37) 141.877,310.37 141.877,310.604 141.877,310.812 cw(c141.996,310.812) 141.996,310.931 142.234,310.931 cw(c142.234,310.812) 142.353,310.812 142.353,310.723 ccw(c142.471,310.723) 142.471,310.604 142.659,310.604 v1(149.927,310.604)
MIO_43: R797.2 U1.F22 | length 47.4
  L1 w0.12: R797.2@134.016,313.233 134.025,313.224 134.555,313.753 v1(135.217,313.753) ; v2(166.909,310.027) U1.F22@167.397,309.539
  L3 (Sign) w0.12: v1(151.315,309.969) 151.863,310.517 152.635,310.517 153.356,311.239 156.498,311.239 158.548,309.189 160.879,309.189 162.346,310.657 164.7,310.657 164.753,310.604 165.345,310.604 165.693,310.256 166.086,310.256 166.315,310.027 v2(166.909,310.027)
  L14 (Sign) w0.12: v1(135.217,313.753) 135.217,312.861 137.8,310.277 137.8,309.811 138.141,309.47 140.957,309.47 141.287,309.47 ccw(c141.287,309.589) 141.406,309.589 141.406,309.865 cw(c141.525,309.865) 141.525,309.984 141.763,309.984 cw(c141.763,309.865) 141.882,309.865 141.882,309.47 ccw(c141.988,309.47) 141.988,309.363 142.251,309.363 ccw(c142.251,309.47) 142.357,309.47 142.357,310.115 cw(c142.476,310.115) 142.476,310.234 142.714,310.234 cw(c142.714,310.115) 142.833,310.115 142.833,309.47 ccw(c142.94,309.47) 142.94,309.363 143.202,309.363 ccw(c143.202,309.47) 143.309,309.47 143.309,310.115 cw(c143.427,310.115) 143.427,310.234 143.665,310.234 cw(c143.665,310.115) 143.784,310.115 143.784,309.47 ccw(c143.891,309.47) 143.891,309.363 144.153,309.363 ccw(c144.153,309.47) 144.26,309.47 144.26,310.115 cw(c144.379,310.115) 144.379,310.234 144.616,310.234 cw(c144.616,310.115) 144.735,310.115 144.735,309.47 ccw(c144.842,309.47) 144.842,309.363 145.104,309.363 ccw(c145.104,309.47) 145.211,309.47 145.211,310.115 cw(c145.33,310.115) 145.33,310.234 145.568,310.234 cw(c145.568,310.115) 145.687,310.115 145.687,309.47 ccw(c145.793,309.47) 145.793,309.363 146.055,309.363 ccw(c146.055,309.47) 146.162,309.47 146.162,310.115 cw(c146.281,310.115) 146.281,310.234 146.519,310.234 cw(c146.519,310.115) 146.638,310.115 146.638,309.589 ccw(c146.757,309.589) 146.757,309.47 146.875,309.47 150.816,309.47 v1(151.315,309.969)
MIO_44: R798.2 U1.E24 | length 91.3
  L1 w0.12: v1(165.909,312.027) U1.E24@166.397,311.539
  L1 w0.2: v1(178.765,370.449) 179.713,370.449 R798.2@180.405,371.142
  L12 (Sign) w0.12: v1(155.419,321.853) 155.08,321.513 155.08,311.299 156.795,309.584 160.003,309.584 162.446,312.027 v1(165.909,312.027)
  L3 (Sign) w0.2: v1(155.419,321.853) 155.419,322.776 152.446,325.749 152.446,343.243 156.641,347.439 160.804,347.439 161.227,347.862 161.394,347.862 165.285,351.753 168.894,351.753 177.605,360.464 177.605,364.569 177.605,368.865 177.605,369.113 177.605,369.325 178.729,370.449 v1(178.765,370.449)
MIO_45: R799.2 U1.F23 | length 90.6
  L1 w0.12: v2(166.909,311.027) U1.F23@167.397,310.539
  L1 w0.2: v1(178.765,369.849) 179.298,369.849 179.955,369.192 R799.2@180.405,369.192
  L12 (Sign) w0.12: v1(156.337,321.843) 155.308,320.815 155.308,313.631 v1(158.483,310.456)
  L3 (Sign) w0.12: v1(158.483,310.456) 159.09,309.849 160.605,309.849 161.397,310.641 162.38,311.624 163.865,311.624 164.068,311.827 165.42,311.827 165.64,311.607 165.947,311.607 166.527,311.027 v2(166.909,311.027)
  L3 (Sign) w0.2: v1(156.337,321.843) 156.337,322.283 152.746,325.874 152.746,343.119 156.766,347.139 161.088,347.139 161.088,347.298 161.351,347.562 161.518,347.562 165.381,351.424 168.989,351.424 177.905,360.34 177.905,364.445 177.905,368.989 v1(178.765,369.849)
MIO_46: R105.1 U1.K20 | length 51.3
  L1 w0.12: R105.1@134.016,321.335 134.818,321.335 v2(134.912,321.242) ; U1.K20@171.397,307.539 v1(171.884,307.052)
  L12 (Sign) w0.12: v1(135.217,318.732) 135.865,318.732 136.398,318.198 143.827,318.198 v16(145.211,316.814)
  L3 (Sign) w0.12: v2(134.912,321.242) 135.445,320.708 135.445,318.96 v1(135.217,318.732)
  L14 (Sign) w0.12: v16(145.211,316.814) 146.413,316.814 146.743,316.484 146.926,316.484 147.045,316.484 ccw(c147.045,316.603) 147.164,316.603 147.164,316.726 cw(c147.283,316.726) 147.283,316.845 147.521,316.845 cw(c147.521,316.726) 147.64,316.726 147.64,316.484 147.64,316.065 ccw(c147.759,316.065) 147.759,315.946 147.996,315.946 ccw(c147.996,316.065) 148.115,316.065 148.115,316.484 148.115,316.726 cw(c148.234,316.726) 148.234,316.845 148.472,316.845 cw(c148.472,316.726) 148.591,316.726 148.591,316.484 148.591,316.065 ccw(c148.71,316.065) 148.71,315.946 148.948,315.946 ccw(c148.948,316.065) 149.066,316.065 149.066,316.484 149.066,316.726 cw(c149.185,316.726) 149.185,316.845 149.423,316.845 cw(c149.423,316.726) 149.542,316.726 149.542,316.484 149.542,316.065 ccw(c149.661,316.065) 149.661,315.946 149.899,315.946 ccw(c149.899,316.065) 150.018,316.065 150.018,316.484 150.018,316.726 cw(c150.137,316.726) 150.137,316.845 150.374,316.845 cw(c150.374,316.726) 150.493,316.726 150.493,316.603 ccw(c150.612,316.603) 150.612,316.484 151.003,316.484 154.354,316.484 157.837,313.002 160.625,313.002 162.832,310.794 162.856,310.794 166.158,307.492 171.024,307.492 171.145,307.371 171.565,307.371 v1(171.884,307.052)
MIO_47: R107.1 U1.K21 | length 49.3
  L1 w0.12: R107.1@134.016,319.303 134.143,319.176 v1(134.785,319.176) ; U1.K21@171.397,308.539 v2(171.884,308.052)
  L5 (Sign) w0.12: v3(165.884,309.143) 165.917,309.143 166.251,308.809 166.251,306.804 167.016,306.04 v12(167.016,305.359)
  L12 (Sign) w0.12: v1(134.785,319.176) 135.357,319.748 143.974,319.748 v16(146.06,317.662)
  L3 (Sign) w0.12: v12(167.016,305.359) 167.016,305.256 166.879,305.119 166.879,305.104 167.218,304.765 168.029,304.765 168.397,305.133 168.397,305.202 168.74,305.545 170.237,305.545 170.472,305.781 170.472,307.341 170.668,307.537 171.369,307.537 v2(171.884,308.052)
  L14 (Sign) w0.12: v16(146.06,317.662) 153.798,317.662 153.885,317.576 158.012,313.449 160.824,313.449 165.13,309.143 v3(165.884,309.143)
MIO_48: R108.1 U1.J21 | length 52
  L1 w0.12: R108.1@134.016,317.271 134.27,317.017 v1(135.313,317.017) ; U1.J21@170.397,308.539 v1(170.884,309.027)
  L12 (Sign) w0.12: v1(135.313,317.017) 134.81,317.017 134.442,316.649 134.442,315.163 135.395,314.211 135.941,314.211 136.995,313.157 143.954,313.157 147.333,316.535 v16(147.333,318.935)
  L14 (Sign) w0.12: v16(147.333,318.935) 149.911,318.935 150.03,318.935 ccw(c150.03,319.054) 150.149,319.054 150.149,319.208 cw(c150.267,319.208) 150.267,319.327 150.505,319.327 cw(c150.505,319.208) 150.624,319.208 150.624,319.054 ccw(c150.743,319.054) 150.743,318.935 150.863,318.935 158.401,318.935 161.162,316.175 161.162,314.263 163.373,312.052 165.113,312.052 166.649,310.515 170.243,310.515 170.458,310.301 170.458,309.485 170.884,309.058 v1(170.884,309.027)
MIO_49: R110.1 U1.G21 | length 49.4
  L1 w0.12: R110.1@134.016,323.367 v2(135.026,323.367) ; v1(167.909,309.027) U1.G21@168.397,308.539
  L12 (Sign) w0.12: v1(135.534,321.869) 135.534,321.387 136.469,320.453 144.118,320.453 v16(146.484,318.087)
  L3 (Sign) w0.12: v2(135.026,323.367) 135.026,322.743 135.534,322.235 v1(135.534,321.869)
  L14 (Sign) w0.12: v16(146.484,318.087) 148.041,318.087 148.188,317.94 155.008,317.94 155.15,317.798 155.554,317.394 ccw(c155.638,317.478) 155.722,317.394 156.103,317.775 cw(c156.187,317.691) 156.271,317.775 156.439,317.607 cw(c156.355,317.522) 156.439,317.438 155.974,316.974 ccw(c156.058,316.89) 155.974,316.806 156.142,316.637 ccw(c156.226,316.722) 156.311,316.637 156.775,317.102 cw(c156.859,317.018) 156.943,317.102 157.111,316.934 cw(c157.027,316.85) 157.111,316.766 156.647,316.301 ccw(c156.731,316.217) 156.647,316.133 156.815,315.965 ccw(c156.899,316.049) 156.983,315.965 157.448,316.429 cw(c157.532,316.345) 157.616,316.429 157.784,316.261 cw(c157.7,316.177) 157.784,316.093 157.319,315.629 ccw(c157.404,315.544) 157.319,315.46 157.488,315.292 ccw(c157.572,315.376) 157.656,315.292 158.12,315.757 cw(c158.204,315.673) 158.289,315.757 158.457,315.589 cw(c158.373,315.505) 158.457,315.421 157.992,314.956 ccw(c158.076,314.872) 157.992,314.788 158.16,314.62 ccw(c158.244,314.704) 158.328,314.62 158.793,315.084 cw(c158.877,315) 158.961,315.084 159.129,314.916 cw(c159.045,314.832) 159.129,314.748 158.665,314.283 158.581,314.199 ccw(c158.665,314.115) 158.581,314.031 158.749,313.863 ccw(c158.833,313.947) 158.917,313.863 cw(c159.001,313.779) 159.085,313.863 159.169,313.779 160.961,313.779 163.158,311.582 164.96,311.582 166.662,309.88 167.056,309.88 v1(167.909,309.027)
MIO_50: R111.1 U1.J20 | length 50.4
  L1 w0.12: R111.1@134.016,315.214 135.393,315.214 v1(135.966,315.787) ; U1.J20@170.397,307.539 v1(170.884,308.027)
  L12 (Sign) w0.12: v16(135.56,319.24) 143.634,319.24 v16(145.636,317.238)
  L14 (Sign) w0.12: v16(135.56,319.24) 135.56,319.223 136.23,318.553 136.23,317.023 135.966,316.759 v1(135.966,315.787) ; v16(145.636,317.238) 146.527,317.238 146.696,317.068 150.635,317.068 150.79,317.068 ccw(c150.79,317.187) 150.909,317.187 150.909,317.322 cw(c151.028,317.322) 151.028,317.441 151.266,317.441 cw(c151.266,317.322) 151.384,317.322 151.384,317.068 151.384,316.825 ccw(c151.503,316.825) 151.503,316.706 151.741,316.706 ccw(c151.741,316.825) 151.86,316.825 151.86,317.068 151.86,317.322 cw(c151.979,317.322) 151.979,317.441 152.217,317.441 cw(c152.217,317.322) 152.336,317.322 152.336,317.068 152.336,316.825 ccw(c152.455,316.825) 152.455,316.706 152.692,316.706 ccw(c152.692,316.825) 152.811,316.825 152.811,317.068 152.811,317.322 cw(c152.93,317.322) 152.93,317.441 153.168,317.441 cw(c153.168,317.322) 153.287,317.322 153.287,317.068 153.287,316.825 ccw(c153.406,316.825) 153.406,316.706 153.644,316.706 ccw(c153.644,316.825) 153.762,316.825 153.762,316.949 cw(c153.881,316.949) 153.881,317.068 154,317.068 154.081,317.068 157.926,313.224 160.731,313.224 162.928,311.027 162.935,311.027 165.508,308.454 170.458,308.454 v1(170.884,308.027)
MIO_51: R112.1 U1.H21 | length 51.5
  L1 w0.12: R112.1@134.016,314.223 134.041,314.249 135.103,314.249 135.484,314.63 v1(135.623,314.63) ; U1.H21@169.397,308.539 v1(169.884,309.027)
  L12 (Sign) w0.12: v1(135.623,314.63) 137.744,314.63 138.227,315.112 142.598,315.112 143.195,314.515 144.069,314.515 146.908,317.355 v16(146.908,318.511)
  L14 (Sign) w0.12: v16(146.908,318.511) 147.049,318.37 156.712,318.37 156.794,318.288 156.878,318.204 ccw(c156.962,318.288) 157.046,318.204 157.418,318.576 cw(c157.502,318.492) 157.586,318.576 157.754,318.408 cw(c157.67,318.324) 157.754,318.24 157.299,317.784 157.054,317.539 ccw(c157.138,317.455) 157.054,317.371 157.222,317.203 ccw(c157.306,317.287) 157.39,317.203 157.635,317.448 158.091,317.903 cw(c158.175,317.819) 158.259,317.903 158.427,317.735 cw(c158.343,317.651) 158.427,317.567 157.971,317.111 157.726,316.866 ccw(c157.81,316.782) 157.726,316.698 157.894,316.53 ccw(c157.979,316.614) 158.063,316.53 158.308,316.775 158.763,317.231 cw(c158.847,317.147) 158.931,317.231 159.1,317.063 cw(c159.016,316.979) 159.1,316.895 158.644,316.439 158.399,316.194 ccw(c158.483,316.11) 158.399,316.026 158.567,315.858 ccw(c158.651,315.942) 158.735,315.858 158.98,316.102 159.436,316.558 cw(c159.52,316.474) 159.604,316.558 159.772,316.39 cw(c159.688,316.306) 159.772,316.222 159.401,315.85 ccw(c159.485,315.766) 159.401,315.682 159.513,315.57 163.258,311.824 165.029,311.824 166.753,310.1 167.282,310.1 167.807,309.574 168.942,309.574 169.085,309.431 169.48,309.431 v1(169.884,309.027)
MIO_52: R362.1 U1.A24 | length 128.8
  L1 w0.12: v2(153.756,316.545) 153.773,316.528 155.201,316.528 157.675,314.054 157.675,312.492 158.36,311.807 162.129,311.807 U1.A24@162.397,311.539
  L3 (Sign) w0.12: v1(65.177,350.398) 65.177,350.114 65.177,349.957 ccw(c65.334,349.957) 65.334,349.8 66.371,349.8 cw(c66.371,349.643) 66.528,349.643 66.528,349.329 cw(c66.371,349.329) 66.371,349.172 65.177,349.172 63.594,349.172 ccw(c63.594,349.015) 63.437,349.015 63.437,348.701 ccw(c63.594,348.701) 63.594,348.544 65.02,348.544 cw(c65.02,348.387) 65.177,348.387 65.177,347.472 65.177,337.941 77.823,325.295 80.742,325.295 80.791,325.246 82.831,325.246 83.076,325.001 102.954,325.001 103.034,325.081 136.736,325.081 140.038,321.779 146.019,321.779 149.596,318.203 151.773,318.203 153.414,316.562 153.739,316.562 v2(153.756,316.545)
  L16 w0.12: R362.1@63.701,350.397 v1(65.177,350.398)
MIO_53: R800.2 U1.B25 | length 129.1
  L1 w0.12: v2(154.711,317.499) 154.728,317.482 155.199,317.482 159.654,313.027 162.909,313.027 U1.B25@163.397,312.539
  L3 (Sign) w0.12: v1(66.835,351.248) 66.835,347.426 67.335,346.926 67.335,336.716 78.096,325.955 81.016,325.955 81.065,325.906 83.105,325.906 83.35,325.661 102.681,325.661 102.761,325.741 137.01,325.741 140.312,322.439 146.293,322.439 149.869,318.863 152.046,318.863 153.393,317.516 154.694,317.516 v2(154.711,317.499)
  L16 w0.12: R800.2@61.327,351.248 61.868,351.248 61.928,351.248 ccw(c61.928,351.405) 62.085,351.405 62.085,351.552 cw(c62.242,351.552) 62.242,351.709 62.556,351.709 cw(c62.556,351.552) 62.713,351.552 62.713,351.071 ccw(c62.87,351.071) 62.87,350.914 63.184,350.914 ccw(c63.184,351.071) 63.341,351.071 63.341,351.552 cw(c63.498,351.552) 63.498,351.709 63.812,351.709 cw(c63.812,351.552) 63.969,351.552 63.969,351.215 ccw(c64.126,351.215) 64.126,351.058 64.44,351.058 ccw(c64.44,351.215) 64.597,351.215 64.597,351.405 cw(c64.754,351.405) 64.754,351.562 65.068,351.562 cw(c65.068,351.405) 65.225,351.405 ccw(c65.382,351.405) 65.382,351.248 66.098,351.248 v1(66.835,351.248)
MIO_54: R115.1 U1.A23 | length 127.1
  L1 w0.12: v2(153.438,316.227) 153.455,316.21 155.202,316.21 157.455,313.957 157.455,310.653 158.349,309.759 161.617,309.759 U1.A23@162.397,310.539
  L3 (Sign) w0.12: v1(64.706,346.837) 64.706,346.278 64.706,346.058 ccw(c64.8,346.058) 64.8,345.964 cw(c64.8,345.807) 64.957,345.807 64.957,345.493 cw(c64.8,345.493) 64.8,345.336 64.706,345.336 63.506,345.336 ccw(c63.506,345.179) 63.349,345.179 63.349,344.865 ccw(c63.506,344.865) 63.506,344.708 64.706,344.708 cw(c64.706,344.551) 64.863,344.551 64.863,344.237 cw(c64.706,344.237) 64.706,344.08 63.506,344.08 ccw(c63.506,343.923) 63.349,343.923 63.349,343.609 ccw(c63.506,343.609) 63.506,343.452 64.55,343.452 cw(c64.55,343.295) 64.706,343.295 64.706,342.417 64.706,338.1 77.732,325.075 80.651,325.075 80.7,325.026 82.74,325.026 82.985,324.781 103.046,324.781 103.125,324.861 136.645,324.861 139.947,321.559 145.928,321.559 149.504,317.983 151.682,317.983 v2(153.438,316.227)
  L16 w0.12: R115.1@63.701,346.841 63.705,346.837 v1(64.706,346.837)
MIO_55: R801.2 U1.B26 | length 128.8
  L1 w0.12: v2(155.347,318.136) 155.347,317.973 155.364,317.956 155.364,317.94 159.277,314.027 162.503,314.027 162.99,313.539 U1.B26@163.397,313.539
  L3 (Sign) w0.12: v1(67.788,348.822) 68.148,348.463 68.148,347.936 68.148,347.876 ccw(c68.305,347.876) 68.305,347.719 68.787,347.719 cw(c68.787,347.562) 68.944,347.562 68.944,347.248 cw(c68.787,347.248) 68.787,347.091 68.305,347.091 ccw(c68.305,346.934) 68.148,346.934 68.148,346.429 68.148,336.526 78.279,326.395 81.198,326.395 81.247,326.346 83.287,326.346 83.532,326.101 102.499,326.101 102.579,326.181 137.192,326.181 140.494,322.879 146.475,322.879 150.051,319.303 152.229,319.303 153.379,318.153 155.33,318.153 v2(155.347,318.136)
  L16 w0.12: R801.2@61.327,349.475 64.439,349.475 64.596,349.475 ccw(c64.596,349.632) 64.753,349.632 64.753,349.8 cw(c64.91,349.8) 64.91,349.957 65.224,349.957 cw(c65.224,349.8) 65.381,349.8 65.381,349.632 ccw(c65.538,349.632) 65.538,349.475 65.852,349.475 ccw(c65.852,349.632) 66.009,349.632 66.009,350.773 cw(c66.166,350.773) 66.166,350.93 66.48,350.93 cw(c66.48,350.773) 66.637,350.773 66.637,349.632 ccw(c66.794,349.632) 66.794,349.475 67.136,349.475 v1(67.788,348.822)
MIO_56: R116.1 U1.A25 | length 125.6
  L1 w0.12: v2(154.074,316.863) 154.091,316.846 155.194,316.846 157.895,314.145 157.895,313.707 158.877,312.725 160.309,312.725 160.494,312.539 U1.A25@162.397,312.539
  L3 (Sign) w0.12: v1(65.719,348.619) 65.719,348.209 65.719,348.052 ccw(c65.876,348.052) 65.876,347.895 66.458,347.895 cw(c66.458,347.738) 66.615,347.738 66.615,347.424 cw(c66.458,347.424) 66.458,347.267 65.719,347.267 65.554,347.267 ccw(c65.554,347.11) 65.397,347.11 65.397,346.796 ccw(c65.554,346.796) 65.554,346.639 65.719,346.639 66.958,346.639 cw(c66.958,346.482) 67.115,346.482 67.115,346.168 cw(c66.958,346.168) 66.958,346.011 65.719,346.011 65.554,346.011 ccw(c65.554,345.854) 65.397,345.854 65.397,345.54 ccw(c65.554,345.54) 65.554,345.383 65.562,345.383 cw(c65.562,345.226) 65.719,345.226 65.719,345.135 65.719,337.71 77.914,325.515 80.833,325.515 80.882,325.466 82.922,325.466 83.167,325.221 102.863,325.221 102.943,325.301 136.827,325.301 140.13,321.999 146.11,321.999 149.687,318.423 151.864,318.423 153.407,316.88 154.058,316.88 v2(154.074,316.863)
  L16 w0.12: R116.1@63.701,348.619 v1(65.719,348.619)
MIO_57: R117.1 U1.A26 | length 127.3
  L1 w0.12: v2(155.029,317.817) 155.175,317.817 159.186,313.807 159.192,313.807 159.459,313.539 U1.A26@162.397,313.539
  L3 (Sign) w0.12: v1(67.627,347.726) 67.632,347.721 67.632,336.73 78.187,326.175 81.107,326.175 81.156,326.126 83.196,326.126 83.441,325.881 102.59,325.881 102.67,325.961 137.101,325.961 140.403,322.659 146.384,322.659 149.96,319.083 152.137,319.083 153.386,317.834 155.012,317.834 v2(155.029,317.817)
  L16 w0.12: R117.1@61.327,347.702 61.351,347.726 64.113,347.726 64.27,347.726 ccw(c64.27,347.883) 64.427,347.883 64.427,348.222 cw(c64.584,348.222) 64.584,348.379 64.898,348.379 cw(c64.898,348.222) 65.055,348.222 65.055,347.726 65.055,347.115 ccw(c65.212,347.115) 65.212,346.958 65.526,346.958 ccw(c65.526,347.115) 65.683,347.115 65.683,347.726 65.683,348.055 cw(c65.84,348.055) 65.84,348.212 66.154,348.212 cw(c66.154,348.055) 66.311,348.055 66.311,347.726 66.311,346.675 ccw(c66.468,346.675) 66.468,346.518 66.782,346.518 ccw(c66.782,346.675) 66.939,346.675 66.939,347.569 cw(c67.096,347.569) 67.096,347.726 67.498,347.726 v1(67.627,347.726)
MIO_58: R118.1 U1.A28 | length 128.3
  L1 w0.12: v2(155.983,318.772) 156,318.755 156,317.926 159.156,314.77 160.981,314.77 161.75,315.539 U1.A28@162.397,315.539
  L3 (Sign) w0.12: v1(67.894,350.901) 67.894,350.037 69.164,348.767 69.164,340.79 68.952,340.578 68.952,336.344 78.461,326.835 81.38,326.835 81.429,326.786 83.469,326.786 83.714,326.541 102.317,326.541 102.396,326.621 137.374,326.621 140.676,323.319 146.657,323.319 150.233,319.743 152.411,319.743 153.365,318.789 155.967,318.789 v2(155.983,318.772)
  L16 w0.12: R118.1@58.915,352.175 67.319,352.175 67.894,351.599 v1(67.894,350.901)
MIO_59: R119.1 U1.A27 | length 128.9
  L1 w0.12: v2(155.665,318.454) 155.682,318.437 155.682,317.933 159.075,314.539 U1.A27@162.397,314.539
  L3 (Sign) w0.12: v1(68.732,345.948) 68.732,345.605 68.732,345.346 ccw(c68.787,345.346) 68.787,345.291 cw(c68.787,345.134) 68.944,345.134 68.944,344.82 cw(c68.787,344.82) 68.787,344.663 68.732,344.663 68.525,344.663 ccw(c68.525,344.506) 68.368,344.506 68.368,344.192 ccw(c68.525,344.192) 68.525,344.035 68.732,344.035 68.787,344.035 cw(c68.787,343.878) 68.944,343.878 68.944,343.564 cw(c68.787,343.564) 68.787,343.407 68.732,343.407 68.525,343.407 ccw(c68.525,343.25) 68.368,343.25 68.368,342.936 ccw(c68.525,342.936) 68.525,342.779 68.732,342.779 68.787,342.779 cw(c68.787,342.622) 68.944,342.622 68.944,342.308 cw(c68.787,342.308) 68.787,342.151 68.732,342.151 68.525,342.151 ccw(c68.525,341.994) 68.368,341.994 68.368,341.68 ccw(c68.525,341.68) 68.525,341.523 68.575,341.523 cw(c68.575,341.366) 68.732,341.366 68.732,341.185 68.732,336.252 78.37,326.615 81.289,326.615 81.338,326.566 83.378,326.566 83.623,326.321 102.408,326.321 102.487,326.401 137.283,326.401 140.585,323.099 146.566,323.099 150.142,319.523 152.32,319.523 153.372,318.471 155.648,318.471 v2(155.665,318.454)
  L16 w0.12: R119.1@61.327,345.929 61.345,345.948 64.706,345.948 64.863,345.948 ccw(c64.863,346.105) 65.02,346.105 65.02,346.377 cw(c65.177,346.377) 65.177,346.534 65.491,346.534 cw(c65.491,346.377) 65.648,346.377 65.648,345.948 65.648,345.686 ccw(c65.805,345.686) 65.805,345.529 66.119,345.529 ccw(c66.119,345.686) 66.276,345.686 66.276,345.948 66.276,346.121 cw(c66.433,346.121) 66.433,346.278 66.747,346.278 cw(c66.747,346.121) 66.904,346.121 66.904,345.948 66.904,345.175 ccw(c67.061,345.175) 67.061,345.018 67.375,345.018 ccw(c67.375,345.175) 67.532,345.175 67.532,345.948 67.532,347.018 cw(c67.689,347.018) 67.689,347.175 68.003,347.175 cw(c68.003,347.018) 68.16,347.018 68.16,346.105 ccw(c68.317,346.105) 68.317,345.948 v1(68.732,345.948)
MIO_60: R120.1 U1.C26 | length 130.6
  L1 w0.12: v2(154.393,317.181) 154.409,317.164 155.187,317.164 158.14,314.211 158.14,313.977 v2(158.389,313.728) ; U1.C26@164.397,313.539 v2(164.397,313.885)
  L3 (Sign) w0.12: v1(66.396,345.046) 66.396,344.526 66.396,344.394 ccw(c66.527,344.394) 66.527,344.263 66.983,344.263 cw(c66.983,344.131) 67.115,344.131 67.115,343.868 cw(c66.983,343.868) 66.983,343.737 66.396,343.737 66.071,343.737 ccw(c66.071,343.605) 65.939,343.605 65.939,343.342 ccw(c66.071,343.342) 66.071,343.211 66.396,343.211 66.983,343.211 cw(c66.983,343.079) 67.115,343.079 67.115,342.816 cw(c66.983,342.816) 66.983,342.685 66.396,342.685 66.071,342.685 ccw(c66.071,342.553) 65.939,342.553 65.939,342.29 ccw(c66.071,342.29) 66.071,342.159 66.396,342.159 66.983,342.159 cw(c66.983,342.027) 67.115,342.027 67.115,341.764 cw(c66.983,341.764) 66.983,341.633 66.396,341.633 66.071,341.633 ccw(c66.071,341.501) 65.939,341.501 65.939,341.238 ccw(c66.071,341.238) 66.071,341.107 66.396,341.107 66.983,341.107 cw(c66.983,340.975) 67.115,340.975 67.115,340.712 cw(c66.983,340.712) 66.983,340.581 66.396,340.581 66.071,340.581 ccw(c66.071,340.449) 65.939,340.449 65.939,340.186 ccw(c66.071,340.186) 66.071,340.055 66.396,340.055 66.983,340.055 cw(c66.983,339.923) 67.115,339.923 67.115,339.66 cw(c66.983,339.66) 66.983,339.529 66.396,339.529 66.071,339.529 ccw(c66.071,339.397) 65.939,339.397 65.939,339.134 ccw(c66.071,339.134) 66.071,339.003 66.396,339.003 66.983,339.003 cw(c66.983,338.871) 67.115,338.871 67.115,338.608 cw(c66.983,338.608) 66.983,338.477 66.527,338.477 ccw(c66.527,338.345) 66.396,338.345 66.396,338.061 66.396,337.345 78.005,325.735 80.924,325.735 80.974,325.686 83.014,325.686 83.258,325.441 102.772,325.441 102.852,325.521 136.919,325.521 140.221,322.219 146.201,322.219 149.778,318.643 151.955,318.643 153.4,317.198 154.376,317.198 v2(154.393,317.181) ; v2(158.389,313.728) 158.546,313.885 v2(164.397,313.885)
  L16 w0.12: R120.1@63.701,345.063 63.718,345.046 v1(66.396,345.046)
MIO_61: R121.1 U1.B29 | length 126.9
  L1 w0.12: v2(156.938,319.727) 156.955,319.71 156.955,317.904 159.429,315.43 160.708,315.43 162.227,316.949 162.987,316.949 U1.B29@163.397,316.539
  L3 (Sign) w0.12: v1(70.79,343.285) 70.294,343.78 70.294,346.951 70.51,347.167 70.904,347.167 71.12,346.951 71.12,344.157 71.526,343.751 71.526,341.883 70.574,340.931 70.574,335.655 78.734,327.495 83.693,327.495 83.987,327.201 102.043,327.201 102.123,327.281 137.648,327.281 140.95,323.979 146.93,323.979 150.507,320.403 152.684,320.403 153.343,319.743 156.921,319.743 v2(156.938,319.727)
  L16 w0.12: R121.1@63.702,343.285 v1(70.79,343.285)
MIO_62: R122.1 U1.B28 | length 128.5
  L1 w0.12: v2(156.302,319.09) 156.318,319.073 156.318,317.918 159.247,314.99 160.89,314.99 161.927,316.027 162.909,316.027 U1.B28@163.397,315.539
  L3 (Sign) w0.12: v1(69.774,342.379) 69.774,341.947 69.774,341.634 cw(c69.774,341.505) 69.902,341.505 69.902,341.134 cw(c69.774,341.134) 69.774,341.006 69.541,341.006 ccw(c69.541,340.849) 69.384,340.849 69.384,340.535 ccw(c69.541,340.535) 69.541,340.378 69.774,340.378 69.93,340.378 cw(c69.93,340.221) 70.087,340.221 70.087,339.907 cw(c69.93,339.907) 69.93,339.75 69.774,339.75 69.329,339.75 ccw(c69.329,339.593) 69.172,339.593 69.172,339.279 ccw(c69.329,339.279) 69.329,339.122 69.774,339.122 69.93,339.122 cw(c69.93,338.965) 70.087,338.965 70.087,338.651 cw(c69.93,338.651) 69.93,338.494 69.774,338.494 69.329,338.494 ccw(c69.329,338.337) 69.172,338.337 69.172,338.023 ccw(c69.329,338.023) 69.329,337.866 69.774,337.866 69.93,337.866 cw(c69.93,337.709) 70.087,337.709 70.087,337.395 cw(c69.93,337.395) 69.93,337.238 69.774,337.238 69.329,337.238 ccw(c69.329,337.081) 69.172,337.081 69.172,336.767 ccw(c69.329,336.767) 69.329,336.61 69.617,336.61 cw(c69.617,336.453) 69.774,336.453 69.774,336.309 69.774,335.833 78.552,327.055 83.511,327.055 83.805,326.761 102.225,326.761 102.305,326.841 137.465,326.841 140.767,323.539 146.748,323.539 150.325,319.963 152.502,319.963 153.357,319.107 156.285,319.107 v2(156.302,319.09)
  L16 w0.12: R122.1@61.327,342.379 63.909,342.379 64.066,342.379 ccw(c64.066,342.536) 64.223,342.536 64.223,342.736 cw(c64.38,342.736) 64.38,342.893 64.694,342.893 cw(c64.694,342.736) 64.851,342.736 64.851,342.379 64.851,341.979 ccw(c65.008,341.979) 65.008,341.822 65.322,341.822 ccw(c65.322,341.979) 65.479,341.979 65.479,342.379 65.479,342.736 cw(c65.636,342.736) 65.636,342.893 65.95,342.893 cw(c65.95,342.736) 66.107,342.736 66.107,342.379 66.107,341.973 ccw(c66.264,341.973) 66.264,341.816 66.578,341.816 ccw(c66.578,341.973) 66.735,341.973 66.735,342.379 66.735,342.736 cw(c66.892,342.736) 66.892,342.893 67.206,342.893 cw(c67.206,342.736) 67.363,342.736 67.363,342.536 ccw(c67.52,342.536) 67.52,342.379 67.818,342.379 v1(69.774,342.379)
MIO_63: R802.2 U1.A29 | length 127.3
  L1 w0.12: v2(156.62,319.408) 156.637,319.392 156.637,317.911 159.338,315.21 160.799,315.21 162.128,316.539 U1.A29@162.397,316.539
  L3 (Sign) w0.12: v1(70.307,341.579) 70.307,335.611 78.643,327.275 83.602,327.275 83.896,326.981 102.134,326.981 102.214,327.061 137.556,327.061 140.859,323.759 146.839,323.759 150.416,320.183 152.593,320.183 153.35,319.425 156.603,319.425 v2(156.62,319.408)
  L16 w0.12: R802.2@59.289,341.507 59.361,341.579 65.397,341.579 65.711,341.579 66.182,341.579 cw(c66.182,341.422) 66.339,341.422 66.339,340.312 ccw(c66.496,340.312) 66.496,340.155 66.81,340.155 ccw(c66.81,340.312) 66.967,340.312 66.967,341.579 cw(c67.064,341.579) 67.064,341.676 67.498,341.676 cw(c67.498,341.579) 67.595,341.579 67.595,340.312 ccw(c67.752,340.312) 67.752,340.155 68.066,340.155 ccw(c68.066,340.312) 68.223,340.312 68.223,341.579 cw(c68.32,341.579) 68.32,341.676 68.754,341.676 cw(c68.754,341.579) 68.851,341.579 68.851,340.312 ccw(c69.008,340.312) 69.008,340.155 69.322,340.155 ccw(c69.322,340.312) 69.479,340.312 69.479,341.422 cw(c69.636,341.422) 69.636,341.579 69.659,341.579 v1(70.307,341.579)
MIO_64: R803.2 U1.B30 | length 98.3
  L1 w0.12: R803.2@78.796,337.668 79.219,337.668 v2(80.476,336.41) ; v2(160.824,321.242) 162.077,319.989 162.077,318.859 U1.B30@163.397,317.539
  L3 (Sign) w0.12: v2(80.476,336.41) 80.814,336.072 80.814,335.035 80.848,335.001 80.901,334.948 ccw(c80.98,335.027) 81.06,334.948 81.179,335.067 cw(c81.259,334.988) 81.338,335.067 81.444,334.961 cw(c81.365,334.882) 81.444,334.803 81.245,334.604 81.135,334.494 ccw(c81.215,334.415) 81.135,334.335 81.241,334.229 ccw(c81.321,334.309) 81.4,334.229 81.51,334.339 81.813,334.642 cw(c81.892,334.563) 81.972,334.642 82.077,334.536 cw(c81.998,334.457) 82.077,334.378 81.774,334.075 81.665,333.965 ccw(c81.744,333.885) 81.665,333.806 81.771,333.7 ccw(c81.85,333.78) 81.929,333.7 81.96,333.731 cw(c82.039,333.651) 82.118,333.731 82.22,333.629 82.22,333.203 85.647,329.776 85.647,328.417 85.982,328.081 101.679,328.081 101.758,328.161 138.022,328.161 141.317,324.866 147.256,324.866 147.264,324.859 147.295,324.859 150.871,321.283 153.049,321.283 153.708,320.623 156.428,320.623 156.526,320.722 159.632,320.722 160.152,321.242 v2(160.824,321.242)
MIO_65: R804.2 U1.D25 | length 62.4
  L1 w0.12: v2(164.909,313.027) U1.D25@165.397,312.539
  L1 w0.2: R804.2@109.855,300.177 109.893,300.139 v1(111.227,300.139)
  L3 (Sign) w0.12: v1(111.227,300.139) 111.887,300.139 112.705,300.958 112.705,301.555 121.585,310.434 132.428,310.434 132.892,309.97 135.417,309.97 137.49,312.044 147.807,312.044 147.845,312.081 149.09,313.327 153.961,313.327 154.689,312.599 164.481,312.599 v2(164.909,313.027)
MIO_66: R805.2 U1.C27 | length 136.3
  L1 w0.12: v2(158.788,321.781) 159.459,321.11 159.459,318.943 v19(160.439,317.963) ; v19(163.727,315.018) 163.752,315.044 163.809,315.044 163.817,315.052 163.884,315.052 U1.C27@164.397,314.539
  L1 w0.2: v1(121.488,426.123) 121.526,426.161 R805.2@121.526,427.438
  L5 (Sign) w0.12: v12(159.88,316.825) 162.088,314.617 163.348,314.617 v12(163.365,314.633)
  L5 (Sign) w0.2: v1(121.488,426.123) 121.488,405.73 124.688,402.53 124.688,382.708 v6(126.047,381.348)
  L3 (Sign) w0.12: v12(159.88,316.825) 160.439,317.384 v19(160.439,317.963) ; v12(163.365,314.633) 163.365,314.656 v19(163.727,315.018)
  L3 (Sign) w0.2: v6(126.047,381.348) 136.943,370.453 136.943,357.218 140.5,353.66 140.5,343.484 147.763,336.222 147.763,332.781 148.704,331.839 148.704,330.403 150.962,328.145 150.962,324.505 154.225,321.242 156.685,321.242 157.225,321.781 v2(158.788,321.781)
MIO_67: R806.2 U1.C28 | length 100.5
  L1 w0.12: R806.2@78.796,334.353 79.539,334.353 79.815,334.629 v2(79.815,334.683) ; v2(163.839,317.097) 163.846,317.09 163.846,316.09 U1.C28@164.397,315.539
  L3 (Sign) w0.12: v2(79.815,334.683) 80.401,334.096 80.56,333.938 cw(c80.481,333.858) 80.56,333.779 80.083,333.302 ccw(c80.162,333.222) 80.083,333.143 80.189,333.037 ccw(c80.268,333.116) 80.348,333.037 80.904,333.594 cw(c80.984,333.514) 81.063,333.594 81.169,333.488 cw(c81.089,333.408) 81.169,333.329 80.612,332.772 ccw(c80.692,332.693) 80.612,332.614 80.718,332.508 ccw(c80.797,332.587) 80.877,332.508 81.433,333.064 cw(c81.513,332.985) 81.592,333.064 81.698,332.959 cw(c81.619,332.879) 81.698,332.8 81.141,332.243 ccw(c81.221,332.164) 81.141,332.084 81.247,331.979 ccw(c81.327,332.058) 81.406,331.979 81.883,332.456 cw(c81.963,332.376) 82.042,332.456 82.227,332.271 82.359,332.138 82.359,330.769 85.488,327.641 101.861,327.641 101.941,327.721 137.83,327.721 141.132,324.419 147.113,324.419 150.689,320.843 152.866,320.843 153.526,320.183 156.61,320.183 156.708,320.282 160.428,320.282 163.605,317.104 163.832,317.104 v2(163.839,317.097)
MIO_68: R807.2 U1.C29 | length 100.1
  L1 w0.12: R807.2@76.649,336.88 76.719,336.811 79.563,336.811 v2(79.908,336.465) ; v2(163.817,320.484) 163.817,318.539 163.817,317.539 164.161,317.195 164.161,316.8 164.397,316.564 U1.C29@164.397,316.539
  L3 (Sign) w0.12: v2(79.908,336.465) 79.952,336.421 79.952,336.241 79.994,336.199 79.994,334.978 84.406,330.565 84.406,329.089 85.634,327.861 101.77,327.861 101.85,327.941 137.921,327.941 141.223,324.639 147.204,324.639 150.78,321.063 152.958,321.063 153.617,320.403 156.519,320.403 156.617,320.502 160.519,320.502 160.666,320.649 163.653,320.649 v2(163.817,320.484)
MIO_69: R808.2 U1.D27 | length 101.9
  L1 w0.12: R808.2@78.847,336.182 78.939,336.09 v2(79.629,336.09) ; v19(164.909,314.836) 165.1,314.836 U1.D27@165.397,314.539
  L5 (Sign) w0.12: v12(157.845,314.027) 157.845,315.939 158.25,316.344 v12(158.25,316.766)
  L3 (Sign) w0.12: v2(79.629,336.09) 79.388,335.849 79.388,334.009 79.676,333.721 79.676,333.103 82.399,330.379 83.512,329.266 85.357,327.421 101.952,327.421 102.032,327.501 137.739,327.501 141.041,324.199 147.022,324.199 150.598,320.623 152.775,320.623 153.434,319.963 156.701,319.963 156.799,320.062 157.539,320.062 157.924,319.676 157.924,317.092 v12(158.25,316.766) ; v12(157.845,314.027) 157.902,314.027 158.099,314.223 163.534,314.223 164.147,314.836 v19(164.909,314.836)
MIO_70: R809.2 U1.D26 | length 161.9
  L1 w0.12: v2(164.909,314.027) U1.D26@165.397,313.539
  L1 w0.2: v2(48.59,361.264) 48.59,362.11 R809.2@48.616,362.135
  L5 (Sign) w0.2: v6(110.503,302.463) 110.503,302.044 v1(111.15,301.396)
  L3 (Sign) w0.12: v1(111.15,301.396) 111.924,301.396 121.402,310.874 132.61,310.874 133.074,310.41 135.234,310.41 137.308,312.483 147.625,312.483 148.908,313.767 154.143,313.767 154.871,313.039 160.546,313.039 161.164,313.657 164.219,313.657 164.278,313.598 164.516,313.598 164.909,313.992 v2(164.909,314.027)
  L3 (Sign) w0.2: v2(48.59,361.264) 48.59,361.048 45.606,358.064 45.606,347.421 50.344,342.683 59.756,342.683 77.624,324.815 79.743,324.815 102.476,302.082 107.264,302.082 107.645,302.463 v6(110.503,302.463)
MIO_71: R810.2 U1.D30 | length 44
  L1 w0.12: R810.2@147.447,344.914 147.447,344.326 147.461,344.313 147.461,344.015 144.778,341.333 144.778,329.758 146.089,328.447 148.047,328.447 153.511,322.983 163.372,322.983 165.397,320.958 U1.D30@165.397,317.539
MIO_72: R811.2 U1.E27 | length 108
  L1 w0.12: v19(166.398,314.539) v19(166.398,314.539)
  L1 w0.2: R811.2@114.655,253.149 v1(115.598,253.149)
  L5 (Sign) w0.12: v1(156.124,313.449) 162.76,313.449 163.915,314.604 v12(165.487,314.604)
  L12 (Sign) w0.2: v1(115.598,253.149) 121.098,253.149 v1(121.697,253.747)
  L3 (Sign) w0.12: 143.882,281.517 146.13,281.517 148.845,284.232 148.845,285.756 152.803,289.714 152.803,292.942 156.528,296.666 156.528,301.835 v1(156.127,302.235) ; v12(165.487,314.604) 165.552,314.539 v19(166.398,314.539)
  L3 (Sign) w0.2: v1(121.697,253.747) 121.697,255.091 122.891,256.285 122.891,281.409 124.058,282.576 130.265,282.576 131.324,281.517 143.882,281.517
  L14 (Sign) w0.12: v1(156.124,313.449) 156.124,311.09 157.582,309.632 157.582,303.69 v1(156.127,302.235)
MIO_73: R812.2 U1.E30 | length 106.2
  L1 w0.12: v7(156.063,364.262) 156.063,347.47 153.393,344.8 153.393,329.66 156.244,326.809 162.052,326.809 163.577,325.284 163.577,324.691 166.397,321.871 U1.E30@166.397,317.539
  L1 w0.2: v1(193.249,380.058) 193.33,380.058 193.517,379.871 R812.2@194.259,379.871
  L5 (Sign) w0.12: v12(164.998,377.057) 167.493,379.552 178.975,379.552 180.855,381.432 191.875,381.432 v1(193.249,380.058)
  L3 (Sign) w0.2: v7(156.063,364.262) 161.097,369.297 163.35,369.297 164.998,370.945 v12(164.998,377.057)
MIO_74: R813.2 U1.E29 | length 118.7
  L1 w0.12: v7(149.186,327.851) 149.222,327.851 153.236,323.837 163.136,323.837 165.909,321.064 165.909,317.027 U1.E29@166.397,316.539
  L1 w0.2: R813.2@65.867,328.217 v1(65.867,328.94)
  L3 (Sign) w0.2: v1(81.925,335.244) 83.987,333.182 83.987,331.803 85.764,330.026 87.951,330.026 88.547,330.622 96.035,330.622 96.347,330.934 101.072,330.934 101.984,330.022 119.153,330.022 120.528,328.647 148.39,328.647 v7(149.186,327.851)
  L14 (Sign) w0.2: v1(65.867,328.94) 65.867,331.259 65.397,331.729 65.397,333.136 66.37,334.109 80.79,334.109 v1(81.925,335.244)
MIO_75: R814.2 U1.D29 | length 116.2
  L1 w0.12: 164.909,319.119 164.909,317.027 U1.D29@165.397,316.539
  L1 w0.2: R814.2@65.39,335.812 71.35,335.812 71.717,335.445 v2(71.717,335.429) ; v2(163.884,321.971) 164.909,320.946 164.909,319.119
  L5 (Sign) w0.2: v6(78.789,329.59) 78.789,329.133 78.208,328.552 78.208,326.617 80.72,324.105 83.777,324.105 v6(83.781,324.109) ; v6(128.257,323.012) 130.772,323.012 131.432,322.351 149.305,322.351 v6(153.319,326.366)
  L3 (Sign) w0.2: v2(71.717,335.429) 71.733,335.429 77.572,329.59 v6(78.789,329.59) ; v6(83.781,324.109) 83.822,324.15 125.125,324.15 126.263,323.012 v6(128.257,323.012) ; v6(153.319,326.366) 153.341,326.366 156.453,323.254 158.86,323.254 159.435,322.68 163.176,322.68 v2(163.884,321.971)
MIO_76: R815.2 U1.E28 | length 85.4
  L1 w0.12: U1.E28@166.397,315.539 166.891,316.033 v1(166.891,318.973)
  L5 (Sign) w0.2: v1(104.005,288.332) 105.064,289.391 v6(105.064,297.637) ; v6(131.915,312.492) 133.626,314.203 135.403,314.203 135.427,314.18 137.433,314.18 139.318,316.065 146.089,316.065 148.768,318.745 166.662,318.745 v1(166.891,318.973)
  L3 (Sign) w0.2: v6(105.064,297.637) 109.302,301.876 112.036,301.876 121.295,311.134 131.023,311.134 131.915,312.026 v6(131.915,312.492)
  L16 w0.2: R815.2@104.005,287.237 v1(104.005,288.332)
MIO_77: R816.2 U1.E25 | length 79
  L1 w0.12: v2(165.909,313.027) U1.E25@166.397,312.539
  L5 (Sign) w0.2: v1(105.075,288.332) 106.134,289.391 v6(106.134,297.637)
  L3 (Sign) w0.12: v6(106.134,297.637) 109.283,300.787 111.626,300.787 121.493,310.654 132.519,310.654 132.983,310.19 135.325,310.19 137.399,312.264 147.716,312.264 147.754,312.301 ; 147.754,312.301 148.999,313.547 154.052,313.547 154.78,312.819 160.637,312.819 161.229,313.411 161.397,313.411 163.713,313.411 163.74,313.437 164.079,313.437 164.138,313.378 165.558,313.378 v2(165.909,313.027)
  L16 w0.2: R816.2@105.075,287.237 v1(105.075,288.332)
MIO_GPIO_0_12: J15.2 R780.1 R1095.2 | length 21.5
  L1 w0.2: R780.1@193.699,387.591 195.288,387.591 J15.2@196.672,388.976
  L16 w0.2: R1095.2@195.264,405.644 R1095.2@195.214,405.644 195.014,405.444 195.014,405.394 194.439,404.819 194.439,391.709 196.672,389.476 J15.2@196.672,388.976
MIO_GPIO_0_23: J16.2 R98.1 R781.1 R1099.2 | length 17.9
  L16 w0.2: J16.2@115.265,404.482 115.265,402.006 116.024,401.247 116.024,399.809 114.783,399.809 114.783,395.683 118.516,391.95 R1099.2@120.821,391.95
MIO_GPIO_1_38: J17.2 R796.1 R1107.2 TP36.1 | length 30.5
  L1 w0.2: TP36.1@115.532,417.893 116.053,418.414 117.831,418.414 ; J17.2@115.697,424.222 115.697,421.373 117.831,419.24 117.831,418.414 ; R796.1@119.532,418.414 117.831,418.414
  L16 w0.2: TP36.1@115.532,417.893 120.767,412.659 R1107.2@120.767,400.495
MIO_GPIO_2_66: J19.2 R805.1 R1111.2 | length 19.8
  L1 w0.2: J19.2@115.697,434.037 118.171,434.037 121.526,430.682 R805.1@121.526,428.338
  L16 w0.2: R1111.2@112.864,443.088 112.864,438.963 115.504,436.323 115.504,434.23 J19.2@115.697,434.037
MIO_GPIO_2_70: J20.2 R809.1 R1113.2 | length 11
  L1 w0.2: R809.1@48.616,363.035 48.616,363.014 48.816,362.814 J20.2@51.778,362.814
  L16 w0.2: R1113.2@46.442,359.688 R1113.2@46.492,359.688 46.692,359.888 46.692,359.938 47.619,360.864 47.619,362.696 47.736,362.814 J20.2@51.778,362.814
MIO_GPIO_2_73: J22.2 R812.1 R1117.2 | length 27.5
  L1 w0.2: R812.1@194.259,380.771 R812.1@194.259,380.821 194.459,381.021 196.873,381.021 J22.2@196.926,381.074
  L16 w0.2: R1117.2@195.264,399.412 195.314,399.362 195.314,395.87 198.51,392.674 199.741,392.674 201.244,391.17 201.244,385.402 200.017,384.175 197.637,384.175 196.926,383.464 J22.2@196.926,381.074
MIO_GPIO_2_74: J23.2 R813.1 R1119.2 U36_Trans_PS_I2C1.8 | length 91.2
  L1 w0.2: v2(65.007,327.331) 65.853,327.331 65.867,327.317 U36_Trans_PS_I2C1.8@65.867,325.886
  L3 (Sign) w0.2: J23.2@34.799,386.842 36.805,386.842 42.951,380.695 42.951,365.544 43.791,364.704 43.791,346.411 50.719,339.484 52.018,339.484 ; v1(51.295,338.761) 52.018,339.484 ; v2(65.007,327.331) 65.007,327.846 62.249,330.604 62.249,336.418 59.183,339.484 52.018,339.484
  L16 w0.2: R1119.2@44.108,333.313 44.108,333.847 47.572,337.311 49.844,337.311 v1(51.295,338.761)
MIO_GPIO_2_75: J24.2 R814.1 R1121.2 U36_Trans_PS_I2C0.8 | length 94.8
  L1 w0.2: v2(64.284,334.806) 65.284,334.806 65.39,334.912 R814.1@65.39,334.862 65.59,334.662 65.64,334.662 65.807,334.495 65.807,333.815 65.562,333.57 U36_Trans_PS_I2C0.8@65.397,333.57
  L3 (Sign) w0.2: J24.2@34.799,395.643 38.989,391.453 38.989,385.082 43.272,380.799 43.272,365.648 44.091,364.828 44.091,346.535 50.627,340 v1(59.123,340) 59.245,340 64.256,334.989 64.256,334.835 v2(64.284,334.806)
  L16 w0.2: R1121.2@46.672,338.307 46.622,338.307 46.622,339.129 47.492,340 v1(59.123,340) v1@59.143,339.979
MODE: R669.2 R670.1 U65.2 | length 3.6
  L1 w0.254: R670.1@37.668,200.838 38.26,200.838 ; U65.2@38.26,202.478 38.26,200.838 ; R669.2@38.887,199.931 38.537,199.931 38.26,200.208 38.26,200.838
NetBT1_2: BT1.2 R650.1 T22.2 | length 37
  L1 w0.5: v1(206.308,174.955) 206.377,175.024 T22.2@206.377,176.006 ; v1(206.629,172.479) R650.1@207.501,172.479
  L14 (Sign) w0.5: v1(206.308,174.955) 206.308,174.471 208.301,172.479 ; v1(206.629,172.479) 208.301,172.479 ; v10(229.616,166.345) 228.419,166.345 222.285,172.479 208.301,172.479
  L16 w0.5: v10(229.616,166.345) 232.321,166.345 233.566,165.1 BT1.2@233.566,163.335
NetC36_1: C36.1 R52.2 R54.2 | length 3.3
  L1 w0.5: R52.2@157.787,331.433 156.878,331.433 156.346,331.965 156.903,332.522 R54.2@157.787,332.522
NetC45_2: C45.2 R77.1 | length 1.7
  L1 w0.2: R77.1@97.589,342.772 97.664,342.697 97.664,342.584 98.034,342.214 98.361,342.214 98.57,342.006 C45.2@98.57,341.655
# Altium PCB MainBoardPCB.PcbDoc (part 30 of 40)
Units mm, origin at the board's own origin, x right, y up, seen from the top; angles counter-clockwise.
Board outline 258.95 x 308.86 mm, 16 copper layers (L1, L2 (GND), L3 (Sign), L4 (GND), L5 (Sign), L6 (PWR/GND), L7(12V+Other), L8 (Plane_GND), L9 (PWR/GND), L10 (3V3+Other), L11 (PWR/GND), L12 (Sign), L13 (GND), L14 (Sign), L15 (GND), L16), stack 2.503 mm thick; 2578 components, 1867 nets, 8817 pads, 8021 vias.
Unrouted connection lines stored in the file: 25.

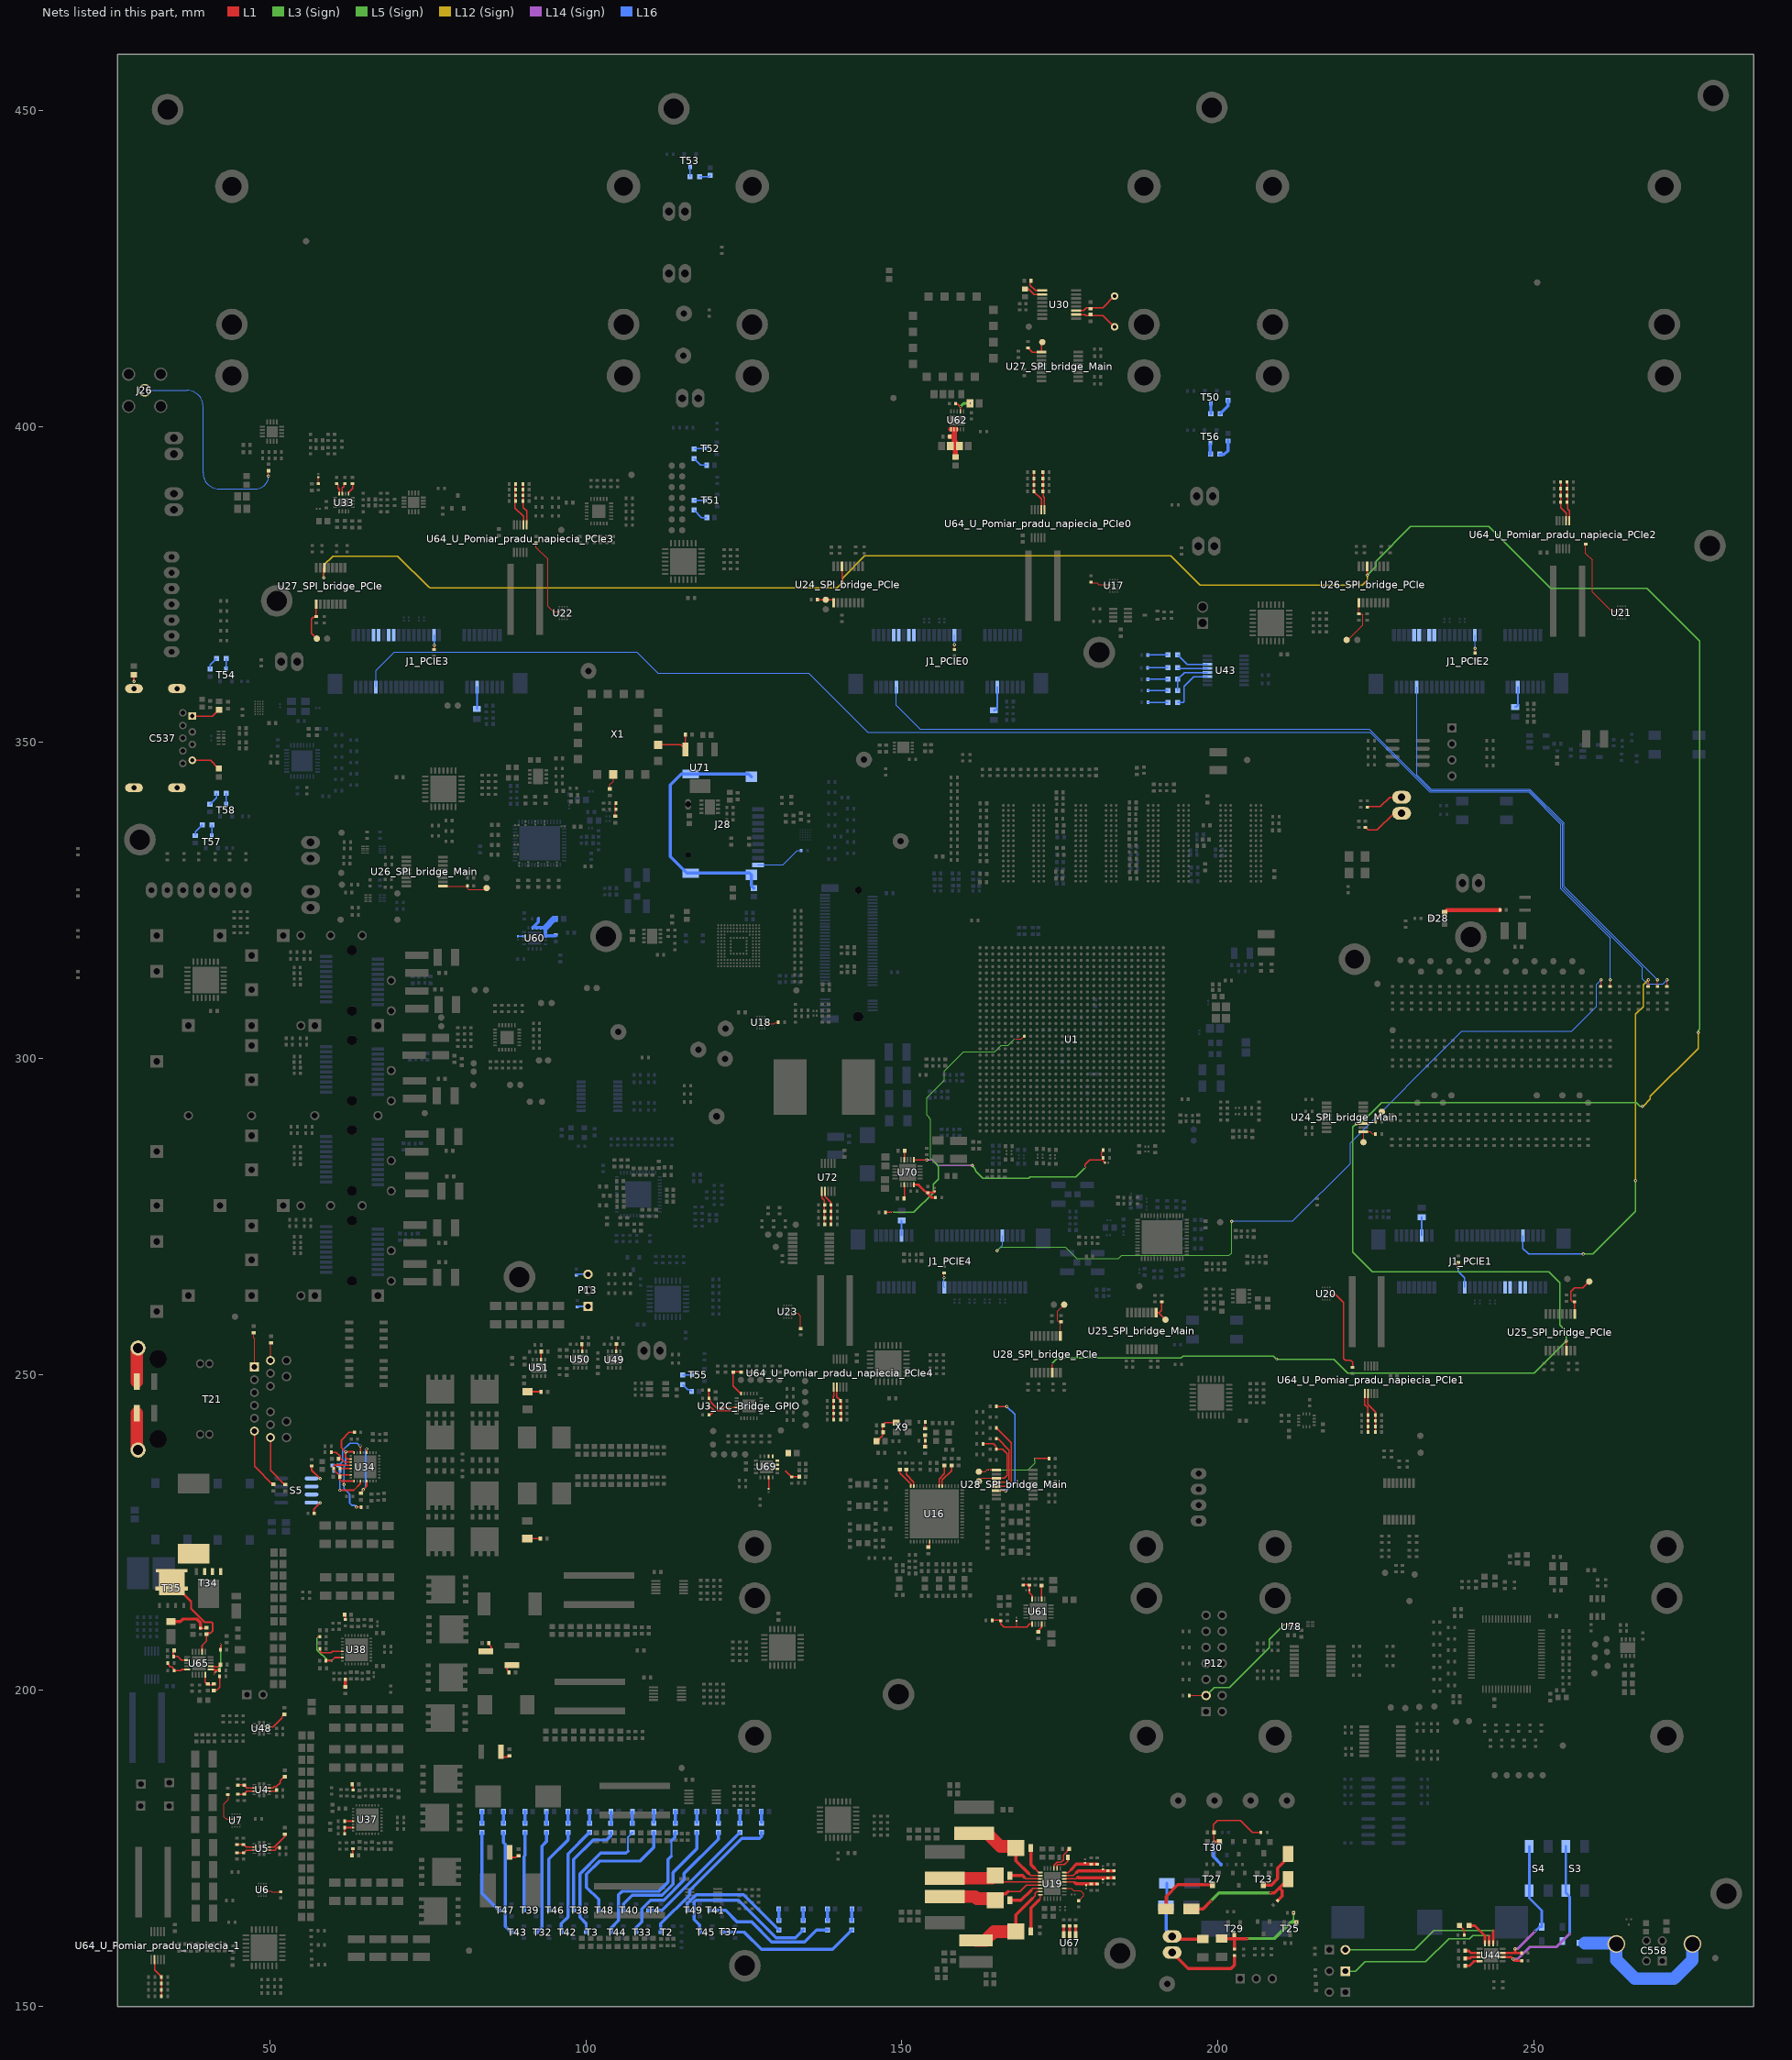
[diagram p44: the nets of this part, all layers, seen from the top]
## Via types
v1: diameter 0.5, hole 0.25, L1 to L16, tented both sides, 4341 vias
v2: diameter 0.254, hole 0.1, L1 to L3 (Sign), tented both sides, 781 vias
v3: diameter 0.5, hole 0.25, L1 to L16, 565 vias
v4: diameter 0.254, hole 0.1, L15 (GND) to L16, tented both sides, 406 vias
v5: diameter 0.254, hole 0.1, L1 to L2 (GND), tented both sides, 283 vias
v6: diameter 0.457, hole 0.2, L3 (Sign) to L6 (PWR/GND), tented both sides, 254 vias
v7: diameter 0.254, hole 0.1, L1 to L3 (Sign), 237 vias
v8: diameter 0.75, hole 0.4, L1 to L16, 200 vias
v9: diameter 0.8, hole 0.4, L1 to L16, tented both sides, 182 vias
v10: diameter 0.254, hole 0.1, L14 (Sign) to L16, tented both sides, 170 vias
v11: diameter 0.75/0/0/0/0/0/0/0/0/0/0/0/0/0/0/0.75 (per signal layer), hole 0.4, L1 to L16, 160 vias
v12: diameter 0.457, hole 0.2, L3 (Sign) to L6 (PWR/GND), 158 vias
v13: diameter 1.4, hole 0.5, L1 to L16, tented both sides, 80 vias
v14: diameter 0.254, hole 0.1, L14 (Sign) to L16, 65 vias
v15: diameter 0.254, hole 0.1, L1 to L2 (GND), 45 vias
v16: diameter 0.457, hole 0.2, L11 (PWR/GND) to L14 (Sign), tented both sides, 26 vias
v17: diameter 0.457, hole 0.2, L11 (PWR/GND) to L14 (Sign), 25 vias
v18: diameter 0.457, hole 0.2, L7(12V+Other) to L10 (3V3+Other), tented both sides, 11 vias
v19: diameter 0.254/0/0.254 (per signal layer), hole 0.1, L1 to L3 (Sign), 9 vias
v20: diameter 0.2/0/0.2 (per signal layer), hole 0.1, L1 to L3 (Sign), 6 vias
v21: diameter 1.65, hole 1.65, L1 to L16, 5 vias
v22: diameter 1.15, hole 1.15, L1 to L16, 5 vias
v23: diameter 0.457, hole 0.2, L1 to L16, 3 vias
v24: diameter 0.5, hole 0.3, L1 to L16, 2 vias
v25: diameter 0.5/0/0.5 (per signal layer), hole 0.2, L14 (Sign) to L16, 1 vias
v26: diameter 0.5, hole 0.25, L1 to L16, tented bottom, 1 vias

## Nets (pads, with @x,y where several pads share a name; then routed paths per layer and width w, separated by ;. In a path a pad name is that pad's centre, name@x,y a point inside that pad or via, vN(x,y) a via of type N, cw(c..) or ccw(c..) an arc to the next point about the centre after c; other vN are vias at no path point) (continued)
NetC78_2: C78.2 U16.7 | length 1
  L1 w0.2: C78.2@154.182,222.68 154.42,222.919 154.42,223.545 U16.7@154.415,223.545
NetC79_2: C79.2 U16.38 | length 3.9
  L1 w0.2: U16.38@156.415,232.345 156.415,233.336 157.879,234.799 C79.2@157.879,235.628
NetC80_2: C80.2 U16.48 | length 3.4
  L1 w0.2: C80.2@149.717,235.087 149.717,234.407 151.415,232.709 U16.48@151.415,232.345
NetC91_1: C91.1 U16.39 | length 3.6
  L1 w0.2: U16.39@155.915,232.345 155.915,233.461 156.761,234.307 C91.1@156.761,235.628
NetC96_1: C96.1 U16.47 | length 3.2
  L1 w0.2: C96.1@150.717,235.087 150.717,234.182 151.915,232.984 U16.47@151.915,232.345
NetC312_2: C312.2 U4.11 | length 3.5
  L1 w0.2: U4.11@49.86,184.571 50.482,184.571 50.685,184.774 51.02,184.774 51.606,185.36 51.606,185.716 52.362,186.472 C312.2@52.362,186.477
NetC313_2: C313.2 U5.11 | length 3.7
  L1 w0.2: U5.11@49.86,175.25 50.715,175.25 52.362,176.897 C313.2@52.362,177.397
NetC314_1: C314.1 U48.11 | length 3.5
  L1 w0.2: U48.11@49.827,194.233 50.449,194.233 51.899,195.683 51.899,195.931 52.016,196.048 52.074,196.048 52.299,196.273 C314.1@52.299,196.353
NetC320_2: C320.2 U30.9 | length 3
  L1 w0.2: C320.2@170.305,423.06 170.305,422.378 171.145,421.538 U30.9@172.25,421.538
NetC321_1: C321.1 U30.10 | length 3.1
  L1 w0.2: C321.1@169.496,421.792 170.103,421.792 170.991,420.903 U30.10@172.25,420.903
NetC322_2: C322.2 U30.3 X3.1 | length 7
  L1 w0.2: U30.3@177.584,418.363 178.767,418.363 179.192,418.789 179.87,418.789 181.816,418.789 X3.1@183.68,420.653
NetC323_2: C323.2 U30.2 X3.2 | length 6.9
  L1 w0.2: U30.2@177.584,417.728 178.98,417.728 179.119,417.589 179.87,417.589 181.864,417.589 X3.2@183.68,415.773
NetC333_2: C333.2 R537.2 | length 1.1
  L1 w0.101: R537.2@57.675,390.918 C333.2@57.675,391.973
NetC334_2: C334.2 X1.10 | length 2.7
  L1 w0.101: C334.2@103.797,342.519 103.797,343.325 104.343,343.871 X1.10@104.343,344.957
NetC335_2: C335.2 R532.1 R533.1 | length 2.2
  L1 w0.101: C335.2@104.697,338.21 104.697,339.432 R532.1@104.697,340.411
NetC341_2: C341.2 J26.1 | length 35.2
  L1 w0.101: v1(49.788,392.176) 49.788,393.156 C341.2@49.793,393.156
  L16 w0.101: J26.1@30.188,405.74 36.894,405.74 cw(c36.894,403.2) 39.434,403.2 39.434,392.674 ccw(c41.974,392.674) 41.974,390.134 47.746,390.134 ccw(c47.746,392.176) v1(49.788,392.176)
NetC351_1: C351.1 R268.2 U34.3 | length 4
  L1 w0.2: R268.2@59.692,237.714 60.508,237.714 61.146,237.075 61.146,236.764 61.771,236.139 U34.3@62.822,236.139
NetC356_1: C356.1 R272.2 R277.1 R278.1 U34.2 U34.4 U34.7 U34.9 U34.32 | length 29
  L1 w0.2: C356.1@60.931,233.839 60.926,233.839 61.226,234.139 U34.7@62.822,234.139 ; v1(63.675,229.018) 63.681,229.024 R277.1@64.44,229.024 R277.1@64.49,229.024
  L1 w0.254: C356.1@60.926,233.839 60.926,234.119 60.156,234.889 60.156,235.139 60.109,235.185 60.109,235.49 60.285,235.666 61.667,235.666 61.694,235.639 U34.4@62.822,235.639 ; C356.1@60.931,233.839 60.931,233.48 61.273,233.139 61.719,233.139 ; v1(61.735,232.588) 61.735,233.123 ; U34.2@62.822,236.639 62.82,236.641 62.257,236.641 61.968,236.929 v1@61.968,237.771 ; U34.9@63.322,233.139 61.735,233.139 ; U34.32@63.322,237.639 63.322,237.703 63.253,237.771 62.002,237.771 v1@61.968,237.771 ; R278.1@63.439,240.856 62.54,240.856 61.334,239.649 61.334,238.406 v1@61.968,237.771 ; 61.719,233.139 61.735,233.123 ; 61.719,233.139 61.735,233.139 ; 61.735,233.123 61.735,233.139
  L16 w0.254: v1(62.012,237.771) 61.968,237.728 61.968,235.666 61.735,235.433 v1(61.735,232.588) 61.735,231.947 62.624,231.058 62.624,229.64 62.953,229.311 63.387,229.311 v1@63.678,229.021
NetC357_2: C357.2 U34.13 U34.28 | length 9.5
  L1 w0.254: C357.2@64.44,231.222 64.44,231.457 64.629,231.647 v3(64.757,231.775) 65.315,232.332 65.315,232.984 65.32,232.989 65.32,233.137 U34.13@65.322,233.139 ; U34.28@65.322,237.639 v1(65.322,238.22)
  L16 w0.254: v3(64.757,231.775) 65.185,232.202 65.185,238.016 65.322,238.153 v1(65.322,238.22)
NetC471_2: C471.2 T21.12 | length 8.5
  L1 w0.2: T21.12@50.092,240.036 50.092,234.853 52.467,232.478 C471.2@52.467,232.473
NetC472_2: C472.2 T21.6 | length 9.8
  L1 w0.2: T21.6@47.552,241.051 47.552,235.516 50.578,232.49 C472.2@50.578,232.485
NetC473_2: C473.2 T21.1 | length 5.5
  L1 w0.12: C473.2@47.42,256.621 47.42,255.79 47.552,255.658 T21.1@47.552,251.201
NetC474_2: C474.2 T21.7 | length 3
  L1 w0.12: T21.7@50.092,252.216 50.092,255.055 C474.2@50.178,255.14
NetC475_2: C475.2 T21.S1 | length 5.9
  L1 w2: C475.2@28.928,243.887 28.928,238.374 29.132,238.169 T21.S1@29.132,238.061
NetC476_2: C476.2 T21.S2 | length 5.4
  L1 w2: C476.2@28.928,248.856 28.928,253.878 29.132,254.083 T21.S2@29.132,254.191
NetC532_2: C532.2 U44.14 | length 2.4
  L1 w0.4: C532.2@239.179,158.839 239.712,158.839 240.095,158.457 U44.14@241.435,158.457
NetC533_2: C533.2 U44.15 | length 2.3
  L1 w0.4: C533.2@239.179,157.633 239.954,157.633 240.128,157.807 U44.15@241.435,157.807
NetC534_2: C534.2 U44.16 | length 2.6
  L1 w0.4: C534.2@239.179,156.426 239.84,156.426 240.57,157.156 U44.16@241.435,157.156
NetC537_1: C537.1 FB26.2 | length 4.6
  L1 w0.2: C537.1@37.721,354.198 40.907,354.198 41.898,355.189 FB26.2@41.948,355.189
NetC537_4: C537.4 FB27.2 | length 4.7
  L1 w0.2: C537.4@37.721,347.198 40.594,347.198 41.88,345.912 FB27.2@41.93,345.912
NetC537_Z1: C537.Z1 FB28.2 | length 1.1
  L1 w0.3: v3(28.49,359.696) FB28.2@28.49,360.751
NetC549_2: C549.2 R687.1 | length 0.8
  L1 w0.254: C549.2@61.948,211.976 61.951,211.973 61.951,211.171 R687.1@61.953,211.169
NetC558_Z1: C558.Z1 C558.Z2 C672.2 | length 24.7
  L16 w2: C672.2@258.076,160.042 262.953,160.042 C558.Z1@263.088,159.907 263.088,157.345 266.014,154.419 272.224,154.419 275.128,157.324 C558.Z2@275.128,159.907
NetC568_2: C568.2 FB33.1 R433.2 U60.10 U60.11 U60.12 U60.13 U60.14 | length 8.9
  L16 w0.5: U60.10@91.589,320.703 U60.10@91.639,320.703 ; R433.2@92.461,322.096 92.461,321.575 91.689,320.803 91.689,320.753 U60.10@91.639,320.703 ; C568.2@95.25,319.439 93.675,319.439 U60.14@93.589,319.353 93.589,320.703 U60.12@92.889,320.703 U60.11@92.239,320.703 U60.10@91.639,320.703
  L16 w1: 93.589,320.703 94.996,322.11 FB33.1@95.147,322.11
NetC571_1: C571.1 U60.7 | length 1
  L16 w0.2: C571.1@89.245,319.353 U60.7@90.239,319.353
NetC573_1: C573.1 R436.1 R437.2 U61.16 | length 8.3
  L1 w0.12: C573.1@168.186,210.992 168.186,210.109 168.247,210.048
  L1 w0.2: R437.2@164.28,211.087 164.291,211.098 165.659,211.098 165.659,210.562 166.173,210.048 168.247,210.048 169.769,210.048 170.244,210.523 U61.16@170.628,210.523
NetC577_1: C577.1 R438.1 R439.2 U61.10 | length 3.4
  L1 w0.254: R439.2@169.215,216.75 170.181,216.75 C577.1@170.181,215.87 170.181,215.479 170.628,215.032 U61.10@170.628,214.473
NetC578_2: C578.2 U61.7 | length 2.3
  L1 w0.254: U61.7@172.128,214.473 C578.2@172.128,216.75
NetC579_2: C579.2 U61.19 | length 1.6
  L1 w0.2: C579.2@171.628,209.139 171.628,209.505 172.128,210.005 U61.19@172.128,210.523
NetC581_2: C581.2 C582.2 C583.2 FB34.2 U62.1 U62.2 U62.3 | length 6.2
  L1 w0.8: C583.2@157.585,398.424 158.119,398.424 158.319,398.625 ; U62.1@157.785,399.561 U62.2@158.285,399.561 ; FB34.2@158.498,395.184 158.498,397.543 158.319,397.722 158.319,398.625 ; 158.66,399.561 U62.2@158.285,399.561 ; U62.2@158.285,399.561 158.319,399.528 158.319,398.625
NetC584_2: C584.2 R445.2 U62.7 | length 3.5
  L1 w0.2: R445.2@158.487,403.631 158.801,403.631 v2(159.285,403.147) U62.7@159.285,402.411
  L1 w0.4: v2(160.824,403.653) C584.2@160.832,403.653
  L3 (Sign) w0.4: v2(159.285,403.147) 159.792,403.653 v2(160.824,403.653)
NetC588_1: C588.1 C589.2 R545.2 | length 2.1
  L1 w0.101: C589.2@153.67,238.444 153.67,239.511 C588.1@153.67,240.527
NetC588_2: C588.2 R543.2 | length 1.2
  L1 w0.101: C588.2@153.67,241.307 R543.2@153.67,242.481
NetC591_2: C591.2 C592.2 FB37.2 X9.4 | length 5
  L1 w0.2: 146.545,239.532 146.545,239.89 146.935,240.28 146.935,240.889 146.935,241.974 147.355,242.393 X9.4@149.113,242.393
NetC597_2: C597.2 R140.1 U65.17 | length 3.4
  L1 w0.254: C597.2@34.722,206.35 34.722,205.41 34.747,205.384 35.433,205.384 36,204.818 U65.17@36.92,204.818
NetC603_1: C603.1 R113.1 R114.2 U19.20 | length 8
  L1 w0.2: U19.20@175.728,170.2 177.607,170.2 177.832,170.425
  L1 w0.5: 177.832,170.425 177.911,170.425 177.976,170.36 R114.2@183.592,170.36
NetC604_1: C604.1 U19.25 | length 4.4
  L1 w0.254: U19.25@174.078,171.85 174.08,171.852 174.08,172.319 174.58,172.819 175.206,172.819 175.603,173.217 175.603,173.963 176.22,174.58 176.22,174.765 176.363,174.908 C604.1@176.368,174.908
NetC605_1: C605.1 R212.1 R214.2 U19.21 | length 8.2
  L1 w0.2: U19.21@175.728,170.7 177.129,170.7 177.629,171.2
  L1 w0.5: 177.629,171.2 177.895,171.465 R214.2@183.592,171.465
NetC612_1: C612.1 R216.2 R218.2 U19.22 | length 5.8
  L1 w0.2: U19.22@175.728,171.2 176.314,171.2 176.816,171.702
  L1 w0.5: 176.816,171.702 177.629,172.515 R218.2@180.95,172.515
NetC616_1: C616.1 R220.1 R274.2 U19.19 | length 5.3
  L1 w0.2: U19.19@175.728,169.7 177.287,169.7 177.382,169.606
  L1 w0.5: 177.382,169.606 177.593,169.394 R274.2@180.95,169.394
NetC633_2: C633.2 R613.1 | length 2.3
  L1 w0.254: R613.1@90.765,247.284 C633.2@93.052,247.284
NetC634_2: C634.2 R615.2 U34.11 U34.30 | length 15.1
  L1 w0.254: v1(61.056,231.693) 63.286,231.693 64.315,232.722 64.315,232.984 64.32,232.989 64.32,233.137 U34.11@64.322,233.139 ; v1(64.297,238.715) 64.32,238.692 U34.30@64.322,237.639 U34.30@64.322,237.639
  L16 w0.254: v1(61.056,231.693) 61.056,234.739 61.042,234.753 61.042,235.71 61.028,235.724 61.028,235.729 61.525,236.226 61.525,238.002 62.645,239.123 63.823,239.123 64.23,238.715 v1(64.297,238.715)
NetC635_2: C635.2 R615.1 | length 1
  L16 w0.254: C635.2@60.062,235.724 60.109,235.677 60.109,234.785 R615.1@60.156,234.739
NetC636_2: C636.2 R616.1 | length 2.2
  L1 w0.254: R616.1@90.717,224.031 C636.2@92.942,224.031
NetC637_2: C637.2 R288.1 | length 1
  L1 w0.254: 87.033,189.468 87.568,189.468 C637.2@87.909,189.81
NetC638_2: C638.2 R298.1 | length 1.1
  L1 w0.254: 88.405,173.59 88.411,173.596 88.938,173.596 C638.2@89.332,173.99
NetC643_2: C643.2 R623.1 | length 1.1
  L1 w0.254: C643.2@63.12,173.949 R623.1@63.12,175.007
NetC644_2: C644.2 R624.1 | length 1
  L1 w0.254: R624.1@63.175,184.21 C644.2@63.175,185.176
NetC645_2: C645.2 R306.1 | length 0.9
  L1 w0.254: 87.566,203.543 87.564,203.54 87.564,203.257 C645.2@87.964,202.857
NetC646_2: C646.2 R316.1 | length 1.1
  L1 w0.254: C646.2@84.502,207.488 85.052,206.938 85.052,206.654
NetC652_2: C652.2 R631.1 | length 1.4
  L1 w0.5: C652.2@61.925,200.449 61.932,200.455 61.932,201.817 R631.1@61.938,201.823
NetC655_1: C655.1 U49.6 | length 1.2
  L1 w0.2: U49.6@104.82,253.648 104.82,254.678 C655.1@104.972,254.83
NetC656_1: C656.1 U50.6 | length 1.2
  L1 w0.2: U50.6@99.426,253.671 99.426,254.732 C656.1@99.49,254.796
NetC657_1: C657.1 U51.6 | length 1.3
  L1 w0.2: U51.6@92.894,252.363 92.894,253.435 C657.1@93.076,253.617
NetC674_2: C674.2 FB45.1 R644.2 U69.10 U69.11 U69.12 U69.13 U69.14 | length 2.8
  L1 w0.2: 131.54,234.808 132.588,233.759 132.666,233.837 C674.2@133.907,233.837
NetC678_2: C678.2 R652.2 R654.1 T25.1 T29.3 | length 17
  L1 w0.2: R652.2@212.006,164.834 v19(212.009,164.831)
  L1 w0.5: C678.2@200.596,160.734 202.629,160.734 ; T29.3@202.629,161.361 202.629,160.734 ; R654.1@202.667,159.023 202.629,159.061 202.629,160.734 ; v2(204.673,160.757) 204.651,160.734 202.629,160.734
  L3 (Sign) w0.2: 211.551,163.329 212.009,163.787 v19(212.009,164.831)
  L3 (Sign) w0.5: v2(204.673,160.757) 208.978,160.757 211.551,163.329 v2(212.443,163.329)
NetC679_2: C679.2 D23.1 D24.1 J36.1 | length 13.9
  L1 w0.5: J36.1@192.799,161.087 193.705,161.087 194.133,160.658 C679.2@197.637,160.658
  L16 w0.5: D24.1@191.954,169.495 191.954,166.08 D23.1@191.826,165.952 191.826,162.059 J36.1@192.799,161.087
NetC680_1: C680.1 R656.2 R657.2 T30.1 | length 16.4
  L1 w0.2: v1(199.425,176.006) 199.368,176.064 199.368,177.477 199.285,177.56 199.285,178.76 199.975,179.45 203.603,179.45 205.506,177.547 R656.2@206.89,177.547
  L1 w0.5: v1(199.425,176.006) T30.1@200.289,176.006
  L16 w0.5: v1(199.425,176.006) 199.352,175.933 199.352,173.693 R657.2@200.578,172.467
NetC693_1: C693.1 L22.1 T34.1 T34.2 T34.3 T35.5 U65.12 | length 15.3
  L1 w0.254: U65.12@39.26,206.158 39.26,207.104 39.98,207.823 C693.1@39.98,209.037
  L1 w0.3: T35.5@34.455,216.925 34.671,216.925 37.532,214.064 37.532,212.967 39.69,210.809 40.782,210.809 40.967,210.623 40.967,209.435 40.569,209.037 C693.1@39.98,209.037
NetC693_2: C693.2 D26.1 R665.1 | length 6.9
  L1 w0.254: R665.1@39.014,209.828 39.025,209.817 C693.2@39.98,209.817
  L1 w0.5: D26.1@34.353,210.921 35.856,210.921 36.25,211.315 38.427,211.315 39.014,210.728 R665.1@39.014,209.828
NetC701_1: C701.1 R667.2 | length 2.9
  L1 w0.254: C701.1@41.097,200.121 41.676,200.121 42.078,200.524 R667.2@42.078,202.265
NetC701_2: C701.2 C702.2 U65.5 | length 2.7
  L1 w0.254: U65.5@39.76,202.478 39.76,201.311 40.17,200.901 C701.2@41.097,200.901
NetC703_2: C703.2 U65.7 | length 1.7
  L1 w0.254: U65.7@40.6,203.818 41.292,203.818 41.38,203.73 41.759,203.73 C703.2@42.127,204.097
NetC706_1: C706.1 R671.1 R672.2 U70.16 | length 35.4
  L1 w0.2: U70.16@151.914,283.979 151.959,283.934 v1(153.966,283.934) ; v2(178.994,282.74) 178.994,283.21 179.755,283.972 181.599,283.972 181.726,284.099 181.776,284.099 R671.1@181.901,284.224 ; R672.2@181.901,285.514 181.901,285.464 181.776,285.339 181.726,285.339 181.599,285.212 181.599,284.575 181.726,284.449 181.776,284.449 181.901,284.324 R671.1@181.901,284.224 ; C706.1@182.141,283.52 182.141,283.53 182.091,283.58 182.081,283.58 181.901,283.76 R671.1@181.901,284.224
  L3 (Sign) w0.2: v1(161.173,283.067) 161.652,282.446 161.693,282.324 161.693,282.179 162.828,281.044 170.056,281.044 170.315,281.303 177.557,281.303 v2(178.994,282.74)
  L14 (Sign) w0.2: v1(153.966,283.934) 154.831,283.934 155.698,283.067 v1(161.173,283.067)
NetC710_1: C710.1 R673.1 R674.2 U70.10 | length 5.5
  L1 w0.4: U70.10@151.914,280.028 152.673,280.028 154.686,278.016 R674.2@155.366,278.016 ; R673.1@154.127,278.798 155.017,278.798 C710.1@155.232,279.013
NetC711_2: C711.2 U70.7 | length 2.3
  L1 w0.2: C711.2@150.212,277.838 150.414,278.04 U70.7@150.414,280.028
NetC712_2: C712.2 U70.19 | length 1.4
  L1 w0.2: C712.2@150.318,285.388 150.414,285.292 U70.19@150.414,283.979
NetC713_2: C713.2 U71.3 X1.14 | length 7
  L1 w0.2: X1.14@111.455,349.656 115.032,349.656 U71.3@115.764,348.924 115.764,351.098 C713.2@115.897,351.231
NetC719_2: C719.2 U69.7 | length 1.8
  L1 w0.2: C719.2@128.93,231.915 U69.7@128.93,233.718
NetD5_1: D5.1 R716.1 | length 3.3
  L16 w0.2: R716.1@188.902,363.868 D5.1@192.166,363.868
NetD5_2: D5.2 U43.14 | length 5.3
  L16 w0.2: D5.2@193.666,363.868 195.155,362.379 U43.14@198.37,362.379
NetD6_1: D6.1 R717.1 | length 3.3
  L16 w0.2: R717.1@188.862,361.831 D6.1@192.166,361.831
NetD6_2: D6.2 U43.13 | length 4.7
  L16 w0.2: D6.2@193.666,361.831 193.768,361.729 U43.13@198.37,361.729
NetD7_1: D7.1 R718.1 | length 3.3
  L16 w0.2: R718.1@188.905,360.007 D7.1@192.166,360.007
NetD7_2: D7.2 D9.1 U43.12 | length 6.9
  L16 w0.2: D9.1@193.666,358.229 D7.2@193.666,360.007 194.738,361.079 U43.12@198.37,361.079
NetD8_1: D8.1 R719.1 | length 3.3
  L16 w0.2: R719.1@188.912,356.362 D8.1@192.166,356.362
NetD8_2: D8.2 U43.11 | length 7.8
  L16 w0.2: D8.2@193.666,356.362 194.552,356.362 194.669,356.479 194.669,358.902 196.196,360.429 U43.11@198.37,360.429
NetD9_2: D9.2 R720.1 | length 3.3
  L16 w0.2: R720.1@188.912,358.229 D9.2@192.166,358.229
NetD10_1: D10.1 R368.1 | length 1.8
  L1 w0.2: D10.1@238.294,162.789 239.013,162.07 R368.1@239.013,161.303
NetD10_2: D10.2 U44.12 | length 4.4
  L1 w0.4: D10.2@239.794,162.789 240.678,162.789 242.3,161.166 U44.12@242.3,159.972
NetD11_2: D11.2 R370.1 S4.1 S4.2 U44.7 | length 23
  L1 w0.4: U44.7@245.115,158.457 246.951,158.457 ; v1(247.066,159.131) 247.066,158.571 246.951,158.457 ; R370.1@248.153,158.458 248.151,158.457 247.332,158.457 246.951,158.457
  L14 (Sign) w0.4: v1(247.066,159.131) 247.459,159.131 v10(250.215,161.887)
  L16 w0.4: S4.1@249.314,175.345 S4.2@249.314,168.345 249.314,167.157 251.285,165.186 D11.2@251.285,162.598 250.927,162.598 v10(250.215,161.887)
NetD12_2: D12.2 R369.1 S3.1 S3.2 U44.6 | length 29.7
  L1 w0.4: U44.6@245.115,157.807 246.436,157.807 v1(246.748,157.494) 247.017,157.226 R369.1@248.178,157.226
  L14 (Sign) w0.4: v1(246.748,157.494) 247.461,157.494 249.377,159.41 253.619,159.41 v10(255.74,161.531)
  L16 w0.4: D12.2@254.555,160.333 v10@255.727,161.505 ; S3.1@255.093,175.345 S3.2@255.093,168.345 255.093,167.992 255.727,167.357 v10@255.727,161.531
NetD16_1: D16.1 L13.1 U19.5 | length 16.3
  L1 w0.2: 166.804,168.213 168.734,168.213 169.72,169.2 U19.5@171.928,169.2
  L1 w0.5: D16.1@164.771,166.813 165.791,167.833 166.424,167.833 166.804,168.213
  L1 w2: L13.1@156.819,167.401 161.588,167.401 161.905,167.083 164.501,167.083 D16.1@164.771,166.813
NetD16_2: D16.2 U19.6 | length 5.6
  L1 w0.2: 170.422,168.35 170.772,168.7 U19.6@171.928,168.7
  L1 w0.5: D16.2@167.122,166.813 168.886,166.813 170.422,168.35
NetD17_1: D17.1 L16.1 U19.4 | length 15.7
  L1 w0.2: D17.1@164.771,170.7 165.771,169.7 U19.4@171.928,169.7
  L1 w2: L16.1@156.819,170.293 164.299,170.293 164.706,170.7 D17.1@164.771,170.7
NetD17_2: D17.2 U19.3 | length 5
  L1 w0.2: 169.372,170.471 169.643,170.2 U19.3@171.928,170.2
  L1 w0.5: D17.2@167.122,170.7 169.143,170.7 169.372,170.471
NetD18_1: D18.1 L17.1 U19.2 | length 14.4
  L1 w0.2: 170.122,171.004 170.426,170.7 U19.2@171.928,170.7
  L1 w0.5: D18.1@168.071,175.069 168.071,173.055 170.122,171.004
  L1 w2: L17.1@161.461,177.397 163.536,177.397 165.593,175.339 167.801,175.339 D18.1@168.071,175.069
NetD18_2: D18.2 U19.1 | length 4.7
  L1 w0.2: 171.004,171.856 171.047,171.856 171.703,171.2 U19.1@171.928,171.2
  L1 w0.5: D18.2@170.422,175.069 170.426,175.065 170.426,172.434 171.004,171.856
NetD19_1: D19.1 L18.1 U19.7 | length 15.3
  L1 w0.2: 170.672,167.108 171.102,167.537 171.102,167.907 171.394,168.2 U19.7@171.928,168.2
  L1 w0.5: D19.1@168.071,161.863 168.071,164.507 170.672,167.108
  L1 w2: L18.1@161.768,160.443 163.368,160.443 163.418,160.493 163.418,160.692 164.59,161.863 D19.1@168.071,161.863
NetD19_2: D19.2 U19.8 | length 6.5
  L1 w0.2: 171.678,166.813 171.928,167.063 U19.8@171.928,167.7
  L1 w0.5: D19.2@170.422,161.863 170.422,165.557 171.678,166.813
NetD20_1: D20.1 D21.1 R647.2 | length 19.8
  L1 w0.5: D21.1@195.826,165.452 197.684,165.452 v2(198.895,166.662) ; v2(208.389,167.983) 208.988,167.983 209.758,168.753 ; R647.2@209.461,166.713 210.185,167.437 210.185,168.326 209.758,168.753 ; D20.1@211.142,170.137 209.758,168.753
  L3 (Sign) w0.5: v2(198.895,166.662) 200.203,167.97 208.376,167.97 v2(208.389,167.983)
NetD20_2: D20.2 T23.3 | length 7.3
  L1 w0.5: T23.3@207.239,169.232 208.501,169.232 209.461,170.193 209.461,171.883 211.142,173.564 D20.2@211.142,174.137
NetD21_2: D21.2 T27.3 | length 10.1
  L1 w0.5: D21.2@191.826,165.452 191.826,167.41 193.674,169.258 T27.3@199.161,169.258
NetD22_1: D22.1 R913.1 | length 1.8
  L16 w0.5: D22.1@127.795,179.107 R913.1@127.795,180.952
NetD22_2: D22.2 T2.3 | length 24
  L16 w0.5: T2.3@111.865,161.755 111.865,163.107 116.393,167.635 116.393,168.321 124.664,176.591 127.488,176.591 127.781,176.884 D22.2@127.781,177.523
NetD25_1: D25.1 R914.1 | length 1.8
  L16 w0.5: D25.1@107.374,178.878 R914.1@107.374,180.723
NetD25_2: D25.2 T3.3 | length 22
  L16 w0.3: 106.667,174.597 106.667,176.816 D25.2@107.374,177.523
  L16 w0.5: T3.3@100.057,161.755 100.057,163.118 99.07,164.104 99.07,170.986 102.365,174.28 106.35,174.28 106.667,174.597
NetD28_2: D28.2 R276.2 | length 8.9
  L1 w0.65: D28.2@235.92,323.149 235.97,323.149 236.331,323.51 R276.2@244.713,323.51
NetD29_1: D29.1 R915.1 | length 1.8
  L16 w0.5: D29.1@124.379,179.027 R915.1@124.379,180.871
NetD29_2: D29.2 T4.3 | length 19.6
  L16 w0.5: T4.3@109.897,165.224 112.081,165.224 117.577,170.72 D29.2@124.379,177.523
NetD30_1: D30.1 R917.1 | length 1.8
  L16 w0.5: D30.1@93.776,178.928 R917.1@93.776,180.773
NetD30_2: D30.2 T32.3 | length 16.5
  L16 w0.5: T32.3@92.185,161.755 92.247,161.755 93.033,162.541 93.033,175.392 93.769,176.128 D30.2@93.769,177.523
NetD31_1: D31.1 R1060.1 | length 1.8
  L16 w0.5: D31.1@120.978,179.107 R1060.1@120.978,180.952
NetD31_2: D31.2 T33.3 | length 22.4
  L16 w0.5: T33.3@107.929,161.755 107.929,162.488 108.858,163.417 108.858,165.444 110.239,166.824 112.349,166.824 115.566,170.041 115.566,171.053 120.978,176.465 D31.2@120.978,177.523
NetD32_1: D32.1 R1061.1 | length 1.8
  L16 w0.5: D32.1@142.113,163.599 R1061.1@142.113,165.444
NetD32_2: D32.2 T37.3 | length 22.9
  L16 w0.5: T37.3@121.635,161.773 125.048,161.773 127.774,159.047 139.061,159.047 D32.2@142.113,162.099
NetD33_1: D33.1 R1062.1 | length 1.8
  L16 w0.5: D33.1@103.98,178.878 R1062.1@103.98,180.723
NetD33_2: D33.2 T38.3 | length 16
  L16 w0.5: T38.3@98.089,165.224 98.089,173.278 101.163,176.352 103.289,176.352 103.973,177.036 D33.2@103.973,177.523
NetD34_1: D34.1 R1063.1 | length 1.8
  L16 w0.5: D34.1@90.368,179.011 R1063.1@90.368,180.856
NetD34_2: D34.2 T39.3 | length 12.4
  L16 w0.5: T39.3@90.217,165.224 90.217,173.74 90.368,173.891 D34.2@90.368,177.523
NetD35_1: D35.1 R1064.1 | length 1.8
  L16 w0.5: D35.1@117.565,179.107 R1064.1@117.565,180.952
NetD35_2: D35.2 T40.3 | length 19.9
  L16 w0.5: T40.3@105.961,165.224 105.961,166.257 107.329,167.625 112.075,167.625 113.805,169.354 113.805,171.198 117.577,174.97 D35.2@117.577,177.523
NetD36_1: D36.1 R1065.1 | length 1.8
  L16 w0.5: D36.1@138.253,163.599 R1065.1@138.253,165.444
NetD36_2: D36.2 T41.3 | length 21.5
  L16 w0.5: T41.3@119.596,165.224 122.132,165.224 123.984,163.373 126.276,163.373 129.425,160.223 134.612,160.223 136.489,162.099 D36.2@138.253,162.099
NetD37_1: D37.1 R1066.1 | length 1.8
  L16 w0.5: D37.1@100.572,179.027 R1066.1@100.572,180.871
NetD37_2: D37.2 T42.3 | length 17.6
  L16 w0.5: T42.3@96.121,161.755 96.121,163.118 97.17,164.167 97.17,174.122 D37.2@100.572,177.523
NetD38_1: D38.1 R1069.1 | length 1.8
  L16 w0.5: D38.1@86.967,179.011 R1069.1@86.967,180.856
NetD38_2: D38.2 T43.3 | length 16.3
  L16 w0.5: D38.2@86.967,177.523 86.967,175.948 87.262,175.654 87.262,162.68 88.187,161.755 T43.3@88.249,161.755
NetD39_1: D39.1 R1070.1 | length 1.8
  L16 w0.5: D39.1@114.176,179.027 R1070.1@114.176,180.871
NetD39_2: D39.2 T44.3 | length 23.4
  L16 w0.3: 113.541,173.792 113.541,176.201
  L16 w0.5: T44.3@103.993,161.755 103.993,162.429 105.173,163.609 105.173,167.665 105.732,168.225 111.544,168.225 113.002,169.682 113.002,173.253 113.541,173.792 ; 113.541,176.201 114.089,176.749 114.089,177.436 D39.2@114.176,177.523
NetD40_1: D40.1 R1075.1 | length 1.8
  L16 w0.5: D40.1@134.393,163.599 R1075.1@134.393,165.444
NetD40_2: D40.2 T45.3 | length 25.5
  L16 w0.5: T45.3@118.037,161.755 118.037,162.906 117.152,163.791 117.152,166.512 117.465,166.824 124.151,166.824 130.105,160.871 133.165,160.871 D40.2@134.393,162.099
NetD41_1: D41.1 R1076.1 | length 1.8
  L16 w0.5: D41.1@97.17,179.011 R1076.1@97.17,180.856
NetD41_2: D41.2 T46.3 | length 13.5
  L16 w0.5: T46.3@94.153,165.224 94.153,173.335 97.17,176.352 D41.2@97.17,177.523
NetD42_1: D42.1 R1078.1 | length 1.8
  L16 w0.5: D42.1@83.566,179.023 R1078.1@83.566,180.867
NetD42_2: D42.2 T47.3 | length 13.5
  L16 w0.5: D42.2@83.566,177.523 83.566,167.877 86.219,165.224 T47.3@86.281,165.224
NetD43_1: D43.1 R1079.1 | length 1.8
  L16 w0.5: D43.1@110.775,179.107 R1079.1@110.775,180.952
NetD43_2: D43.2 T48.3 | length 21.3
  L16 w0.5: T48.3@102.025,165.224 102.025,166.936 100.103,168.858 100.103,170.926 102.189,173.012 108.6,173.012 110.775,175.187 D43.2@110.775,177.523
NetD44_1: D44.1 R1081.1 | length 1.8
  L16 w0.5: D44.1@130.533,163.599 R1081.1@130.533,165.444
NetD44_2: D44.2 T49.3 | length 18.4
  L16 w0.5: T49.3@116.069,165.224 116.069,166.277 117.47,167.678 124.955,167.678 D44.2@130.533,162.099
NetD45_1: D45.1 R1090.1 | length 2.6
  L16 w0.5: D45.1@200.42,402.046 201.638,403.264 R1090.1@201.638,404.136
NetD45_2: D45.2 T50.3 | length 1.6
  L16 w0.5: D45.2@198.92,402.046 T50.3@198.92,403.676
NetD46_1: D46.1 R1096.1 | length 2.6
  L16 w0.2: D46.1@117.11,386.794 118.315,385.589 R1096.1@119.174,385.589
NetD46_2: D46.2 T51.3 | length 1.7
  L16 w0.2: D46.2@117.11,388.294 T51.3@118.853,388.294
NetD47_1: D47.1 R1102.1 | length 2.4
  L16 w0.2: D47.1@117.138,394.92 118.165,393.893 R1102.1@119.154,393.893
NetD47_2: D47.2 T52.3 | length 1.7
  L16 w0.2: D47.2@117.138,396.42 117.263,396.545 T52.3@118.771,396.545
NetD48_1: D48.1 R1108.1 | length 1.7
  L16 w0.2: D48.1@118.02,439.511 119.436,439.511 R1108.1@119.67,439.745
NetD48_2: D48.2 T53.3 | length 1.6
  L16 w0.2: D48.2@116.52,439.511 T53.3@116.52,441.12
NetD49_1: D49.1 R1112.1 | length 2.1
  L16 w0.2: R1112.1@40.551,361.631 40.551,362.293 D49.1@41.553,363.294
NetD49_2: D49.2 T54.3 | length 1.6
  L16 w0.2: T54.3@43.053,361.7 D49.2@43.053,363.294
NetD50_1: D50.1 R1114.1 | length 1.9
  L16 w0.2: D50.1@115.316,248.437 116.103,247.65 116.449,247.65 116.724,247.375 R1114.1@116.724,247.325
NetD50_2: D50.2 T55.3 | length 1.5
  L16 w0.2: D50.2@115.316,249.937 115.325,249.928 T55.3@116.794,249.928
NetD51_1: D51.1 R1116.1 | length 3.1
  L16 w0.5: D51.1@200.343,395.556 201.017,395.556 201.638,396.177 R1116.1@201.638,397.728
NetD51_2: D51.2 T56.3 | length 1.6
  L16 w0.5: D51.2@198.82,395.556 T56.3@198.82,397.186
NetD52_1: D52.1 R1118.1 | length 2.2
  L16 w0.2: R1118.1@38.205,335.288 38.205,335.886 D52.1@39.321,337.002
NetD52_2: D52.2 T57.3 | length 1.7
  L16 w0.2: T57.3@40.821,335.281 D52.2@40.821,337.002
NetD53_1: D53.1 R1120.1 | length 2.2
  L16 w0.2: R1120.1@40.488,340.243 40.538,340.243 41.578,341.284 D53.1@41.578,341.983
NetD53_2: D53.2 T58.3 | length 1.7
  L16 w0.2: T58.3@43.078,340.275 D53.2@43.078,341.983
NetF1_PCIE0_1: F1_PCIE0.1 J1_PCIE0.11 | length 4
  L16 w0.3: F1_PCIE0.1@164.592,355.11 ccw(c164.592,355.655) 165.137,355.655 J1_PCIE0.11@165.137,358.792
NetF1_PCIE1_1: F1_PCIE1.1 J1_PCIE1.11 | length 2.9
  L16 w0.3: J1_PCIE1.11@232.29,271.994 F1_PCIE1.1@232.29,274.886
NetF1_PCIE2_1: F1_PCIE2.1 J1_PCIE2.11 | length 3.4
  L16 w0.3: F1_PCIE2.1@247.088,355.642 ccw(c247.088,356.044) 247.49,356.044 J1_PCIE2.11@247.49,358.792
NetF1_PCIE3_1: F1_PCIE3.1 J1_PCIE3.11 | length 3.5
  L16 w0.3: F1_PCIE3.1@82.785,355.308 J1_PCIE3.11@82.785,358.792
NetF1_PCIE4_1: F1_PCIE4.1 J1_PCIE4.11 | length 2.4
  L16 w0.3: J1_PCIE4.11@149.937,271.994 149.937,274.313 cw(c149.974,274.313) F1_PCIE4.1@149.974,274.35
NetFB29_1: FB29.1 J28.10 J28.11 J28.12 J28.13 | length 41.4
  L16 w0.5: J28.11@126.187,344.582 125.737,345.032 J28.13@116.587,345.032 115.114,345.032 113.376,343.294 113.376,331.944 115.987,329.332 J28.12@116.587,329.332 125.937,329.332 J28.10@126.187,329.082 126.187,327.333 126.556,326.963 FB29.1@126.606,326.963
NetJ1_PCIE0_20: J1_PCIE0.20 R507.2 | length 2.3
  L1 w0.12: R507.2@158.337,364.693 v1(158.337,365.505)
  L16 w0.12: v1(158.337,365.505) J1_PCIE0.20@158.337,366.992
NetJ1_PCIE0_36: J1_PCIE0.36
NetJ1_PCIE0_38: J1_PCIE0.38
NetJ1_PCIE0_42: J1_PCIE0.42
NetJ1_PCIE0_43: J1_PCIE0.43 R967.2 | length 151.4
  L1 w0.12: R967.2@271.098,311.364 v1(271.098,312.44)
  L16 w0.12: J1_PCIE0.43@149.137,358.792 149.137,355.927 152.931,352.133 223.946,352.133 233.678,342.401 248.986,342.401 249.297,342.401 254.555,337.143 254.555,336.832 254.555,327.057 267.195,314.416 267.195,312.618 268.025,311.788 270.447,311.788 v1(271.098,312.44)
NetJ1_PCIE0_44: J1_PCIE0.44
NetJ1_PCIE1_20: J1_PCIE1.20 R514.2 | length 4.4
  L1 w0.2: v1(238.061,266.967) 238.061,267.769 R514.2@238.087,267.794
  L16 w0.2: v1(238.061,266.967) 238.061,266.335 239.09,265.306 J1_PCIE1.20@239.09,263.794
NetJ1_PCIE1_36: J1_PCIE1.36
NetJ1_PCIE1_38: J1_PCIE1.38
NetJ1_PCIE1_42: J1_PCIE1.42
NetJ1_PCIE1_43: J1_PCIE1.43 R968.2 | length 61.6
  L1 w0.2: R968.2@268.104,311.363 268.178,311.437 v1(268.178,312.44) v1@268.178,312.453
  L12 (Sign) w0.2: v1(266.154,280.708) 266.154,306.993 267.373,308.212 267.373,311.635 v1(268.178,312.44)
  L3 (Sign) w0.2: v1(257.848,269.062) 259.372,269.062 266.154,275.844 v1(266.154,280.708)
  L16 w0.2: J1_PCIE1.43@248.29,271.994 248.29,269.987 249.215,269.062 v1(257.848,269.062)
NetJ1_PCIE1_44: J1_PCIE1.44
NetJ1_PCIE2_20: J1_PCIE2.20 R901.2 | length 2.9
  L1 w0.12: R901.2@240.741,364.127 v1(240.741,364.894)
  L16 w0.12: J1_PCIE2.20@240.69,366.992 240.741,366.941 v1(240.741,364.894)
NetJ1_PCIE2_36: J1_PCIE2.36
NetJ1_PCIE2_38: J1_PCIE2.38
NetJ1_PCIE2_42: J1_PCIE2.42
NetJ1_PCIE2_43: J1_PCIE2.43 R969.2 | length 72.4
  L1 w0.12: R969.2@269.601,311.363 v1(269.601,312.44)
  L16 w0.12: J1_PCIE2.43@231.49,358.792 231.49,344.9 233.769,342.621 249.131,342.621 249.388,342.621 254.775,337.234 254.775,336.977 254.775,327.279 269.601,312.453 v1(269.601,312.44)
NetJ1_PCIE2_44: J1_PCIE2.44
NetJ1_PCIE3_20: J1_PCIE3.20 R902.2 | length 2.3
  L1 w0.2: R902.2@75.985,364.68 v1(75.985,365.391)
  L16 w0.2: v1(75.985,365.391) J1_PCIE3.20@75.985,366.992
NetJ1_PCIE3_36: J1_PCIE3.36
NetJ1_PCIE3_38: J1_PCIE3.38
NetJ1_PCIE3_42: J1_PCIE3.42
NetJ1_PCIE3_43: J1_PCIE3.43 R970.2 | length 231.6
  L1 w0.12: R970.2@262.116,311.363 262.153,311.401 v1(262.153,312.44)
  L16 w0.12: J1_PCIE3.43@66.785,358.792 66.785,361.392 69.717,364.325 108.087,364.325 111.393,361.019 135.271,361.019 144.666,351.624 224.144,351.624 233.587,342.181 249.206,342.181 254.335,337.052 254.335,326.897 262.153,319.078 v1(262.153,312.44)
NetJ1_PCIE3_44: J1_PCIE3.44
NetJ1_PCIE4_20: J1_PCIE4.20 R903.2 | length 2.4
  L1 w0.12: v1(156.704,265.328) 156.704,266.126 R903.2@156.719,266.141
  L16 w0.12: v1(156.704,265.328) 156.704,263.827 J1_PCIE4.20@156.737,263.794
NetJ1_PCIE4_43: J1_PCIE4.43 R971.2 | length 125.7
  L1 w0.12: R971.2@260.619,311.363 260.68,311.424 v1(260.68,312.44)
  L3 (Sign) w0.12: v1(165.076,269.583) 165.675,270.182 175.901,270.182 177.725,268.359 184.334,268.359 184.821,268.846 201.81,268.846 202.212,269.248 v1(202.212,274.245)
  L16 w0.12: v1(165.076,269.583) 165.937,270.444 J1_PCIE4.43@165.937,271.994 ; v1(202.212,274.245) 202.163,274.294 211.898,274.294 220.98,283.375 220.98,286.664 238.651,304.336 256.034,304.336 259.952,308.254 259.952,311.712 v1(260.68,312.44)
NetJ28_9: J28.9 R845.1 | length 7.8
  L16 w0.12: J28.9@127.237,330.632 131.217,330.632 133.494,332.909 R845.1@134.126,332.909
NetJ30_1: J30.1 R283.2 | length 6
  L1 w0.2: R283.2@223.698,339.847 225.716,339.847 227.22,341.351 J30.1@229.108,341.351
NetJ30_2: J30.2 R286.2 | length 7
  L1 w0.2: R286.2@223.368,336.608 223.819,336.156 225.222,336.156 227.876,338.811 J30.2@229.108,338.811
NetJ36_2: J36.2 R654.2 | length 12.7
  L1 w0.5: J36.2@192.799,158.547 195.351,155.994 202.108,155.994 202.667,156.553 R654.2@202.667,158.073
NetL15_2: L15.2 U19.24 | length 3.1
  L1 w0.254: U19.24@174.578,171.85 174.578,172.317 174.727,172.465 175.755,172.465 176.303,173.013 L15.2@176.303,173.617
NetP3_1: P3.1 U44.11 | length 26.4
  L1 w0.4: U44.11@242.95,159.972 v2(242.951,161.239)
  L3 (Sign) w0.2: P3.1@220.209,155.588 221.831,155.588 223.304,157.061 232.918,157.061 236.588,160.731 239.878,160.731 240.386,161.239 v2(242.951,161.239)
NetP4_2: P4.2 U44.10 | length 26.7
  L1 w0.4: U44.10@243.6,159.972 v2@243.6,162.014
  L3 (Sign) w0.2: P4.2@220.209,158.979 231.153,158.979 234.188,162.014 v2(243.599,162.014)
NetP12_3: P12.3 R731.1 U78.1 | length 21.2
  L1 w0.12: R731.1@195.466,199.209 P12.3@198.171,199.209
  L1 w0.2: v2(210.576,210.47) 210.58,210.474 U78.1@211.267,210.474
  L3 (Sign) w0.2: P12.3@198.171,199.209 199.431,200.469 201.892,200.469 208.174,206.752 208.174,208.06 210.576,210.462 v2(210.576,210.47)
NetP13_1: P13.1 R675.2 | length 1.7
  L16 w0.3: R675.2@98.654,260.782 P13.1@100.343,260.782
NetP13_3: P13.3 R737.1 | length 1.9
  L16 w0.2: R737.1@98.501,265.743 cw(c98.62,265.743) 98.62,265.862 P13.3@100.343,265.862
NetR12_1: R12.1 R19.2 U5.5 | length 4.2
  L1 w0.2: R19.2@44.801,174.289 45.844,174.289 45.844,174.314 46.28,174.75 U5.5@47.56,174.75 46.345,174.75
NetR14_1: R14.1 R16.1 R22.1 R24.1 U72.2 | length 5.6
  L1 w0.2: U72.2@137.853,279.003 137.853,278.122 138.729,277.246 138.729,276.971 138.854,276.846 138.854,274.797 R22.1@138.854,273.772
NetR15_1: R15.1 R23.2 U4.5 | length 2.9
  L1 w0.2: R23.2@44.92,183.563 45.94,183.563 45.94,183.667 46.345,184.071 U4.5@47.56,184.071
NetR17_1: R17.1 R25.2 U4.4 | length 2.9
  L1 w0.2: R25.2@44.92,185.074 45.94,185.074 45.94,184.98 46.349,184.571 U4.4@47.56,184.571
NetR18_2: R18.2 U4.10 | length 1.3
  L1 w0.2: U4.10@49.86,184.071 50.865,184.071 R18.2@51.068,184.274 R18.2@51.118,184.274
NetR20_1: R20.1 R26.2 U5.4 | length 4.2
  L1 w0.2: R26.2@44.801,175.686 45.822,175.686 46.258,175.25 U5.4@47.56,175.25 46.349,175.25
NetR21_2: R21.2 U5.10 | length 1.9
  L1 w0.2: U5.10@49.86,174.75 50.762,174.75 51.138,175.125 R21.2@51.6,175.125
NetR27_2: R27.2 U6.C1 | length 2.4
  L1 w0.12: U6.C1@49.406,168.256 49.416,168.266 50.217,168.266 50.366,168.118 50.728,168.118 50.73,168.119 R27.2@51.717,168.119
NetR28_1: R28.1 U7.C1 | length 5.4
  L1 w0.12: R28.1@43.358,183.571 43.463,183.467 43.463,182.749 42.726,182.012 42.726,180.02 43.123,179.624 44.018,179.624 U7.C1@44.028,179.634
NetR75_1: R75.1 U1.H16 | length 45.3
  L1 w0.12: v2(167.852,303.098) 168.956,303.098 U1.H16@169.397,303.539
  L1 w0.2: R75.1@147.358,275.653 148.476,275.653 v2(148.501,275.679)
  L3 (Sign) w0.12: 155.27,283.494 154.556,284.208 154.556,290.381 154.365,290.572 154.365,290.727 154.005,291.087 154.005,293.833 156.747,296.575 156.747,298.007 159.819,301.079 161.397,301.079 164.706,301.079 165.703,302.076 166.83,302.076 v2(167.852,303.098)
  L3 (Sign) w0.2: v2(148.501,275.679) 151.917,275.679 155.004,278.765 155.004,280.092 155.816,280.905 155.816,282.948 155.27,283.494
NetR132_1: R132.1 U28_SPI_bridge_Main.14 | length 17.7
  L1 w0.2: R132.1@164.951,244.951 v1(166.637,244.951) ; U28_SPI_bridge_Main.14@164.969,231.638 164.993,231.614 166.408,231.614 v1(166.432,231.59)
  L16 w0.2: v1(166.432,231.59) 167.897,233.054 167.897,243.691 v1(166.637,244.951)
NetR133_1: R133.1 U28_SPI_bridge_Main.13 | length 12.1
  L1 w0.2: R133.1@164.951,241.561 167.297,239.215 167.297,233.096 166.49,232.288 U28_SPI_bridge_Main.13@164.969,232.288
NetR134_1: R134.1 U28_SPI_bridge_Main.12 | length 9.6
  L1 w0.2: R134.1@164.951,239.866 165.2,239.866 166.992,238.074 166.992,233.477 166.454,232.938 U28_SPI_bridge_Main.12@164.969,232.938
NetR149_1: R149.1 R159.2 U65.20 | length 3.9
  L1 w0.2: R149.1@33.873,204.343 33.947,204.269 33.947,204.06 34.27,203.737 34.548,203.737 34.773,203.513 R159.2@34.773,203.149
  L1 w0.254: R159.2@34.773,203.149 35.891,203.149 36.059,203.318 U65.20@36.92,203.318
NetR150_1: R150.1 R160.2 U65.6 | length 8.3
  L1 w0.254: U65.6@40.6,203.318 41.282,203.318 ; v2(41.123,202.654) 41.282,202.814 41.282,203.318 ; R160.2@42.078,203.203 41.397,203.203 41.282,203.318 ; R150.1@42.202,206.468 v2(42.202,207.35)
  L3 (Sign) w0.254: v2(41.123,202.654) 42.202,203.733 v2(42.202,207.35)
NetR174_1: R174.1 R175.1 R176.1 R177.1 U64_U_Pomiar_pradu_napiecia_PCIe0.2 | length 6.5
  L1 w0.2: R176.1@170.877,392.788 170.877,391.772 170.877,390.756 170.877,389.74 172.087,388.53 U64_U_Pomiar_pradu_napiecia_PCIe0.2@172.087,386.83
NetR178_1: R178.1 R179.1 R180.1 R181.1 U64_U_Pomiar_pradu_napiecia_PCIe0.1 | length 6
  L1 w0.2: R180.1@172.39,392.788 172.39,391.772 172.39,390.756 172.39,389.74 172.39,388.99 172.587,388.793 U64_U_Pomiar_pradu_napiecia_PCIe0.1@172.587,386.83
NetR182_2: R182.2 U17.C1 | length 3.2
  L1 w0.12: R182.2@179.955,375.457 180.162,375.25 180.915,375.25 181.172,374.992 182.935,374.992 U17.C1@182.945,375.002
NetR183_1: R183.1 R184.1 R185.1 R186.1 U64_U_Pomiar_pradu_napiecia_PCIe1.2 | length 6.6
  L1 w0.2: U64_U_Pomiar_pradu_napiecia_PCIe1.2@223.781,246.97 223.781,245.26 224.991,244.05 224.991,242.685 224.991,241.796 R185.1@224.991,240.907
NetR187_1: R187.1 R188.1 R189.1 R190.1 U64_U_Pomiar_pradu_napiecia_PCIe1.1 | length 6.2
  L1 w0.2: U64_U_Pomiar_pradu_napiecia_PCIe1.1@223.281,246.97 223.281,245.235 223.732,244.784 223.732,243.574 223.732,242.685 223.732,241.796 R189.1@223.732,240.907
NetR191_2: R191.2 U20.C1 | length 14.1
  L1 w0.12: U20.C1@217.756,262.604 U20.C1@217.766,262.614
  L1 w0.2: U20.C1@217.756,262.604 218.721,262.604 219.928,261.398 219.928,252.518 220.199,252.247 221.035,252.247 221.342,251.94 R191.2@221.342,251.101
NetR192_1: R192.1 R193.1 R194.1 R195.1 U64_U_Pomiar_pradu_napiecia_PCIe2.2 | length 6.5
  L1 w0.2: R194.1@254.224,391.218 254.274,391.168 254.274,387.158 255.146,386.286 U64_U_Pomiar_pradu_napiecia_PCIe2.2@255.146,385.075
NetR196_1: R196.1 R197.1 R198.1 R199.1 U64_U_Pomiar_pradu_napiecia_PCIe2.1 | length 6.3
  L1 w0.2: R198.1@255.356,391.218 255.356,390.159 255.356,389.101 255.356,388.043 255.356,386.984 255.649,386.691 255.649,385.079 U64_U_Pomiar_pradu_napiecia_PCIe2.1@255.646,385.075
NetR200_2: R200.2 U21.C1 | length 13.4
  L1 w0.12: R200.2@258.249,381.457 258.249,379.942 259.296,378.895 259.296,373.814 262.354,370.757 263.299,370.757 U21.C1@263.309,370.767
NetR201_1: R201.1 R202.1 R203.1 R204.1 U64_U_Pomiar_pradu_napiecia_PCIe3.2 | length 7
  L1 w0.2: R203.1@88.813,390.907 88.813,390.018 88.813,389.129 88.813,388.24 88.813,387.1 90.133,385.78 U64_U_Pomiar_pradu_napiecia_PCIe3.2@90.133,384.471
NetR205_1: R205.1 R206.1 R207.1 R208.1 U64_U_Pomiar_pradu_napiecia_PCIe3.1 | length 6.7
  L1 w0.2: R207.1@90.072,390.907 90.072,390.018 90.072,388.24 90.072,387.19 90.633,386.629 U64_U_Pomiar_pradu_napiecia_PCIe3.1@90.633,384.471
NetR209_2: R209.2 U22.C1 | length 13
  L1 w0.12: R209.2@92.133,381.649 92.133,380.872 93.982,379.022 93.982,371.587 94.873,370.696 95.818,370.696 U22.C1@95.828,370.707
NetR210_1: R210.1 R211.1 R213.1 R215.1 U64_U_Pomiar_pradu_napiecia_PCIe4.2 | length 5.5
  L1 w0.2: U64_U_Pomiar_pradu_napiecia_PCIe4.2@139.729,248.004 139.729,246.48 140.141,246.068 140.141,246.018 R211.1@140.341,245.818 140.391,245.818 140.394,245.815 R213.1@140.394,242.844
NetR217_1: R217.1 R219.1 R221.1 R222.1 U64_U_Pomiar_pradu_napiecia_PCIe4.1 | length 5.2
  L1 w0.2: R221.1@139.165,242.844 139.165,245.818 139.164,246.621 139.229,246.685 U64_U_Pomiar_pradu_napiecia_PCIe4.1@139.229,248.004
NetR228_2: R228.2 U23.C1 | length 3.7
  L1 w0.12: U23.C1@132.555,259.738 132.565,259.748 133.51,259.748 134.003,259.256 R228.2@134.003,257.207
NetR229_1: R229.1 R230.1 R457.1 R459.1 U64_U_Pomiar_pradu_napiecia_1.2 | length 6.3
  L1 w0.2: U64_U_Pomiar_pradu_napiecia_1.2@31.745,157.414 31.738,157.407 31.738,155.801 32.87,154.669 R457.1@32.87,151.621
NetR231_SPI_bridge_Main_1: R231_SPI_bridge_Main.1 SP21_SPI_bridge_Main.1 U24_SPI_bridge_Main.11 U24_SPI_bridge_PCIe.6 U25_SPI_bridge_PCIe.6 U26_SPI_bridge_PCIe.6 U27_SPI_bridge_PCIe.6 U28_SPI_bridge_PCIe.6 | length 527.4
  L1 w0.12: U24_SPI_bridge_Main.11@223.032,289.702 223.972,289.702 224.253,289.983 R231_SPI_bridge_Main.1@225.007,289.983
  L1 w0.2: v1(58.529,376.077) 58.529,377.606 U27_SPI_bridge_PCIe.6@58.613,377.69 ; U24_SPI_bridge_PCIe.6@140.532,377.907 140.532,375.384 v1(140.552,375.363) ; v2(173.787,251.739) 173.787,250.787 173.798,250.776 U28_SPI_bridge_PCIe.6@173.798,250.278 ; v1(221.933,289.712) 221.943,289.702 U24_SPI_bridge_Main.11@223.032,289.702 ; U26_SPI_bridge_PCIe.6@223.64,377.907 223.64,377.057 223.689,377.008 v1(223.689,376.504) ; R231_SPI_bridge_Main.1@225.007,289.983 225.133,290.108 225.133,290.73 SP21_SPI_bridge_Main.1@225.979,291.576 ; v1(255.181,255.295) 255.181,253.777 U25_SPI_bridge_PCIe.6@255.191,253.767
  L5 (Sign) w0.2: v6(209.357,252.422) 218.372,252.422 220.593,250.201 250.087,250.201 v1(255.181,255.295) 255.181,256.832 254.141,257.872 254.141,264.486 252.403,266.225 224.519,266.225 221.392,269.351 221.392,289.172 v1(221.933,289.712)
  L12 (Sign) w0.2: v1(58.529,376.077) 58.529,378.078 59.959,379.508 70.228,379.508 75.143,374.593 75.189,374.593 75.297,374.485 139.78,374.485 140.552,375.257 v1(140.552,375.363) ; v1@140.605,375.31 140.605,376.002 144.156,379.552 192.57,379.552 197.212,374.91 222.904,374.91 223.689,375.695 v1(223.689,376.504) ; v1(267.225,292.44) 267.325,292.44 268.478,293.593 268.478,294.015 276.07,301.607 v1(276.07,304.117)
  L3 (Sign) w0.2: v2(173.787,251.739) 174.673,252.626 194.202,252.626 194.52,252.944 208.835,252.944 v6(209.357,252.422) ; v1(221.933,289.712) 222.603,289.712 225.905,293.014 266.276,293.014 266.828,292.462 267.036,292.462 267.051,292.448 267.101,292.448 267.109,292.44 v1(267.225,292.44) ; v1(223.689,376.504) 223.689,376.541 225.065,377.917 225.065,378.705 230.533,384.173 242.923,384.173 252.696,374.4 267.932,374.4 276.253,366.079 276.253,304.651 276.07,304.468 v1(276.07,304.117)
NetR232_SPI_bridge_Main_2: R232_SPI_bridge_Main.2 SP20_SPI_bridge_Main.1 U24_SPI_bridge_Main.9 | length 3.8
  L1 w0.12: SP20_SPI_bridge_Main.1@223.078,286.766 223.078,288.448 224.134,288.448 224.514,288.068 R232_SPI_bridge_Main.2@225.007,288.068
NetR232_SPI_bridge_PCIe_2: R232_SPI_bridge_PCIe.2 SP20_SPI_bridge_PCIe.1 U24_SPI_bridge_PCIe.9 | length 3.1
  L1 w0.2: R232_SPI_bridge_PCIe.2@136.594,372.643 136.645,372.593 SP20_SPI_bridge_PCIe.1@137.973,372.593 139.107,372.593 139.232,372.468 U24_SPI_bridge_PCIe.9@139.232,372.107
NetR234_SPI_bridge_Main_2: R234_SPI_bridge_Main.2 SP22_SPI_bridge_Main.1 U25_SPI_bridge_Main.9 | length 4
  L1 w0.2: U25_SPI_bridge_Main.9@190.248,259.821 190.772,259.821 ; R234_SPI_bridge_Main.2@191.148,261.561 191.148,260.196 190.772,259.821 ; SP22_SPI_bridge_Main.1@191.745,258.674 190.772,259.646 190.772,259.821
NetR234_SPI_bridge_PCIe_2: R234_SPI_bridge_PCIe.2 SP22_SPI_bridge_PCIe.1 U25_SPI_bridge_PCIe.9 | length 7.6
  L1 w0.2: U25_SPI_bridge_PCIe.9@256.491,259.567 256.491,261.564 256.141,261.564 255.898,261.806 255.898,263.141 256.44,263.683 257.785,263.683 SP22_SPI_bridge_PCIe.1@258.814,264.712
NetR235_SPI_bridge_Main_1: R235_SPI_bridge_Main.1 SP24_SPI_bridge_Main.1 U26_SPI_bridge_Main.9 | length 7.5
  L1 w0.12: U26_SPI_bridge_Main.9@77.373,327.29 R235_SPI_bridge_Main.1@81.305,327.29 ; R235_SPI_bridge_Main.1@81.305,327.34 R235_SPI_bridge_Main.1@81.305,327.29 ; SP24_SPI_bridge_Main.1@84.309,326.976 84.071,326.976 83.851,326.756 81.459,326.756 81.305,326.91 R235_SPI_bridge_Main.1@81.305,327.29
NetR235_SPI_bridge_PCIe_1: R235_SPI_bridge_PCIe.1 SP24_SPI_bridge_PCIe.1 U26_SPI_bridge_PCIe.9 | length 7.7
  L1 w0.12: SP24_SPI_bridge_PCIe.1@220.405,366.247 220.64,366.247 222.99,368.597 222.99,370.263 222.913,370.34 222.34,370.34 U26_SPI_bridge_PCIe.9@222.34,372.107
NetR237_SPI_bridge_Main_1: R237_SPI_bridge_Main.1 SP26_SPI_bridge_Main.1 U27_SPI_bridge_Main.9 | length 4.1
  L1 w0.2: R237_SPI_bridge_Main.1@169.979,412.5 170.688,411.791 U27_SPI_bridge_Main.9@172.108,411.791 172.108,413.217 SP26_SPI_bridge_Main.1@172.25,413.36
NetR237_SPI_bridge_PCIe_1: R237_SPI_bridge_PCIe.1 SP26_SPI_bridge_PCIe.1 U27_SPI_bridge_PCIe.9 | length 6.3
  L1 w0.2: U27_SPI_bridge_PCIe.9@57.313,371.89 R237_SPI_bridge_PCIe.1@57.313,369.863 ; R237_SPI_bridge_PCIe.1@57.328,369.863 R237_SPI_bridge_PCIe.1@57.313,369.863 ; SP26_SPI_bridge_PCIe.1@57.429,366.448 56.608,367.27 56.608,369.574 56.897,369.863 R237_SPI_bridge_PCIe.1@57.313,369.863
NetR239_SPI_bridge_Main_2: R239_SPI_bridge_Main.2 SP28_SPI_bridge_Main.1 U28_SPI_bridge_Main.9 | length 14
  L1 w0.12: SP28_SPI_bridge_Main.1@162.201,234.625 163.187,234.625 163.462,234.899 163.488,234.925 163.88,234.925 v2(163.881,234.926)
  L1 w0.2: 163.462,234.899 163.478,234.916 v2@163.784,234.916 ; v2@163.795,234.888 163.843,234.888 v2(163.881,234.926) ; v2@163.881,234.888 U28_SPI_bridge_Main.9@164.969,234.888 ; v2(171.044,236.703) R239_SPI_bridge_Main.2@173.303,236.703 R239_SPI_bridge_Main.2@173.353,236.703
  L3 (Sign) w0.12: v2(163.881,234.926) 170.027,234.926 171.128,236.027 171.128,236.305 171.044,236.389 v2(171.044,236.703)
NetR239_SPI_bridge_PCIe_2: R239_SPI_bridge_PCIe.2 SP28_SPI_bridge_PCIe.1 U28_SPI_bridge_PCIe.9 | length 5.3
  L1 w0.12: U28_SPI_bridge_PCIe.9@175.098,256.653 R239_SPI_bridge_PCIe.2@175.098,258.399 ; R239_SPI_bridge_PCIe.2@175.192,258.399 R239_SPI_bridge_PCIe.2@175.098,258.399 ; SP28_SPI_bridge_PCIe.1@175.706,261.061 174.692,260.048 174.692,258.509 174.802,258.399 R239_SPI_bridge_PCIe.2@175.098,258.399
NetR240_SPI_bridge_Main_1: R240_SPI_bridge_Main.1 R912.1 SP29_SPI_bridge_Main.1 U28_SPI_bridge_Main.11 | length 13
  L1 w0.12: SP29_SPI_bridge_Main.1@162.201,233.095 162.694,233.588 U28_SPI_bridge_Main.11@164.969,233.588
  L1 w0.2: R912.1@162.832,239.033 164.535,239.033 164.951,238.617 164.951,238.172 165.923,238.172 166.662,237.433 166.662,234.023 166.243,233.604 164.953,233.604 U28_SPI_bridge_Main.11@164.969,233.588
NetR241_2: R241.2 R242.1 U3_I2C_Bridge_GPIO.22 | length 6.5
  L1 w0.2: R241.2@119.456,247.554 119.456,246.246 R242.1@119.506,246.246 119.706,246.046 119.706,245.701 120.618,244.789 U3_I2C_Bridge_GPIO.22@123.878,244.789
NetR243_2: R243.2 R244.1 U3_I2C_Bridge_GPIO.23 | length 5.8
  L1 w0.2: R244.1@119.456,243.63 119.643,243.63 120.302,244.289 ; R243.2@119.456,244.938 119.654,244.938 120.302,244.289 ; U3_I2C_Bridge_GPIO.23@123.878,244.289 120.302,244.289
NetR263_2: R263.2 U33.16 | length 1.8
  L1 w0.2: R263.2@60.573,391.006 60.773,390.806 60.773,390.269 60.969,390.073 U33.16@60.969,389.385
NetR264_2: R264.2 U33.13 | length 1.9
  L1 w0.2: U33.13@62.469,389.385 62.469,389.565 63.083,390.179 R264.2@63.083,391.006
NetR265_2: R265.2 U33.15 | length 1.8
  L1 w0.2: U33.15@61.469,389.385 61.469,390.266 61.696,390.494 61.696,390.845 R265.2@61.858,391.006
NetR266_1: R266.1 R267.2 S5.1 S5.2 S5.3 S5.4 | length 4.7
  L1 w0.3: R266.1@56.594,235.589 56.594,234.883 v1(57.944,233.533) ; R267.2@56.952,228.016 56.952,228.701 v1(57.944,229.693)
NetR269_2: R269.2 U18.C1 | length 2.3
  L1 w0.12: U18.C1@128.298,305.481 128.308,305.491 129.797,305.491 130.027,305.721 R269.2@130.499,305.721
NetR272_1: R272.1 U34.5 | length 1.8
  L1 w0.254: R272.1@61.056,235.139 U34.5@62.822,235.139
NetR281_2: R281.2 R400.1 U3_I2C_Bridge_GPIO.18 | length 5.2
  L1 w0.2: U3_I2C_Bridge_GPIO.18@124.563,246.974 123.333,248.204 123.333,250.419 R281.2@124.57,250.419
NetR284_2: R284.2 U19.17 | length 4.9
  L1 w0.12: U19.17@175.728,168.7 176.816,168.7 177.166,168.35 178.269,168.35 178.803,167.816 178.803,167.506 R284.2@177.98,166.683
NetR289_1: R289.1 U37.5 | length 1.4
  L1 w0.254: R289.1@61.781,179.317 U37.5@63.175,179.317
NetR293_1: R293.1 R294.1 U37.7 | length 2.4
  L1 w0.254: R294.1@61.781,177.317 61.781,178.317 U37.7@63.175,178.317
NetR304_1: R304.1 R388.1 R389.1 R390.1 U72.1 | length 5.4
  L1 w0.2: U72.1@137.353,279.003 137.353,277.965 137.766,277.552 137.766,276.846 137.766,275.821 137.766,274.797 R389.1@137.766,273.772
NetR305_1: R305.1 U67.6 | length 1.4
  L1 w0.4: U67.6@175.639,161.385 R305.1@175.639,162.805
NetR307_1: R307.1 U38.5 | length 4.1
  L1 w0.254: R307.1@57.945,206.596 57.945,206.233 58.189,205.989 59.673,205.989 59.898,206.214 U38.5@61.453,206.214
NetR308_2: R308.2 U67.5 | length 1.4
  L1 w0.4: U67.5@176.589,161.385 R308.2@176.589,162.805
NetR309_1: R309.1 U67.4 | length 1.4
  L1 w0.4: U67.4@177.539,161.385 R309.1@177.539,162.805
NetR310_1: R310.1 R312.1 U38.7 | length 8.5
  L1 w0.2: v2(57.434,208.526) R310.1@57.945,208.526
  L1 w0.254: R312.1@58.826,204.716 v2(59.784,204.716) 60.282,205.214 U38.7@61.453,205.214
  L3 (Sign) w0.2: v2(57.434,208.526) 57.434,206.432 59.15,204.716 v2(59.784,204.716)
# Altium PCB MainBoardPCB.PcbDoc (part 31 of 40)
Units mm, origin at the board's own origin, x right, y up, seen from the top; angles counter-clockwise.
Board outline 258.95 x 308.86 mm, 16 copper layers (L1, L2 (GND), L3 (Sign), L4 (GND), L5 (Sign), L6 (PWR/GND), L7(12V+Other), L8 (Plane_GND), L9 (PWR/GND), L10 (3V3+Other), L11 (PWR/GND), L12 (Sign), L13 (GND), L14 (Sign), L15 (GND), L16), stack 2.503 mm thick; 2578 components, 1867 nets, 8817 pads, 8021 vias.
Unrouted connection lines stored in the file: 25.

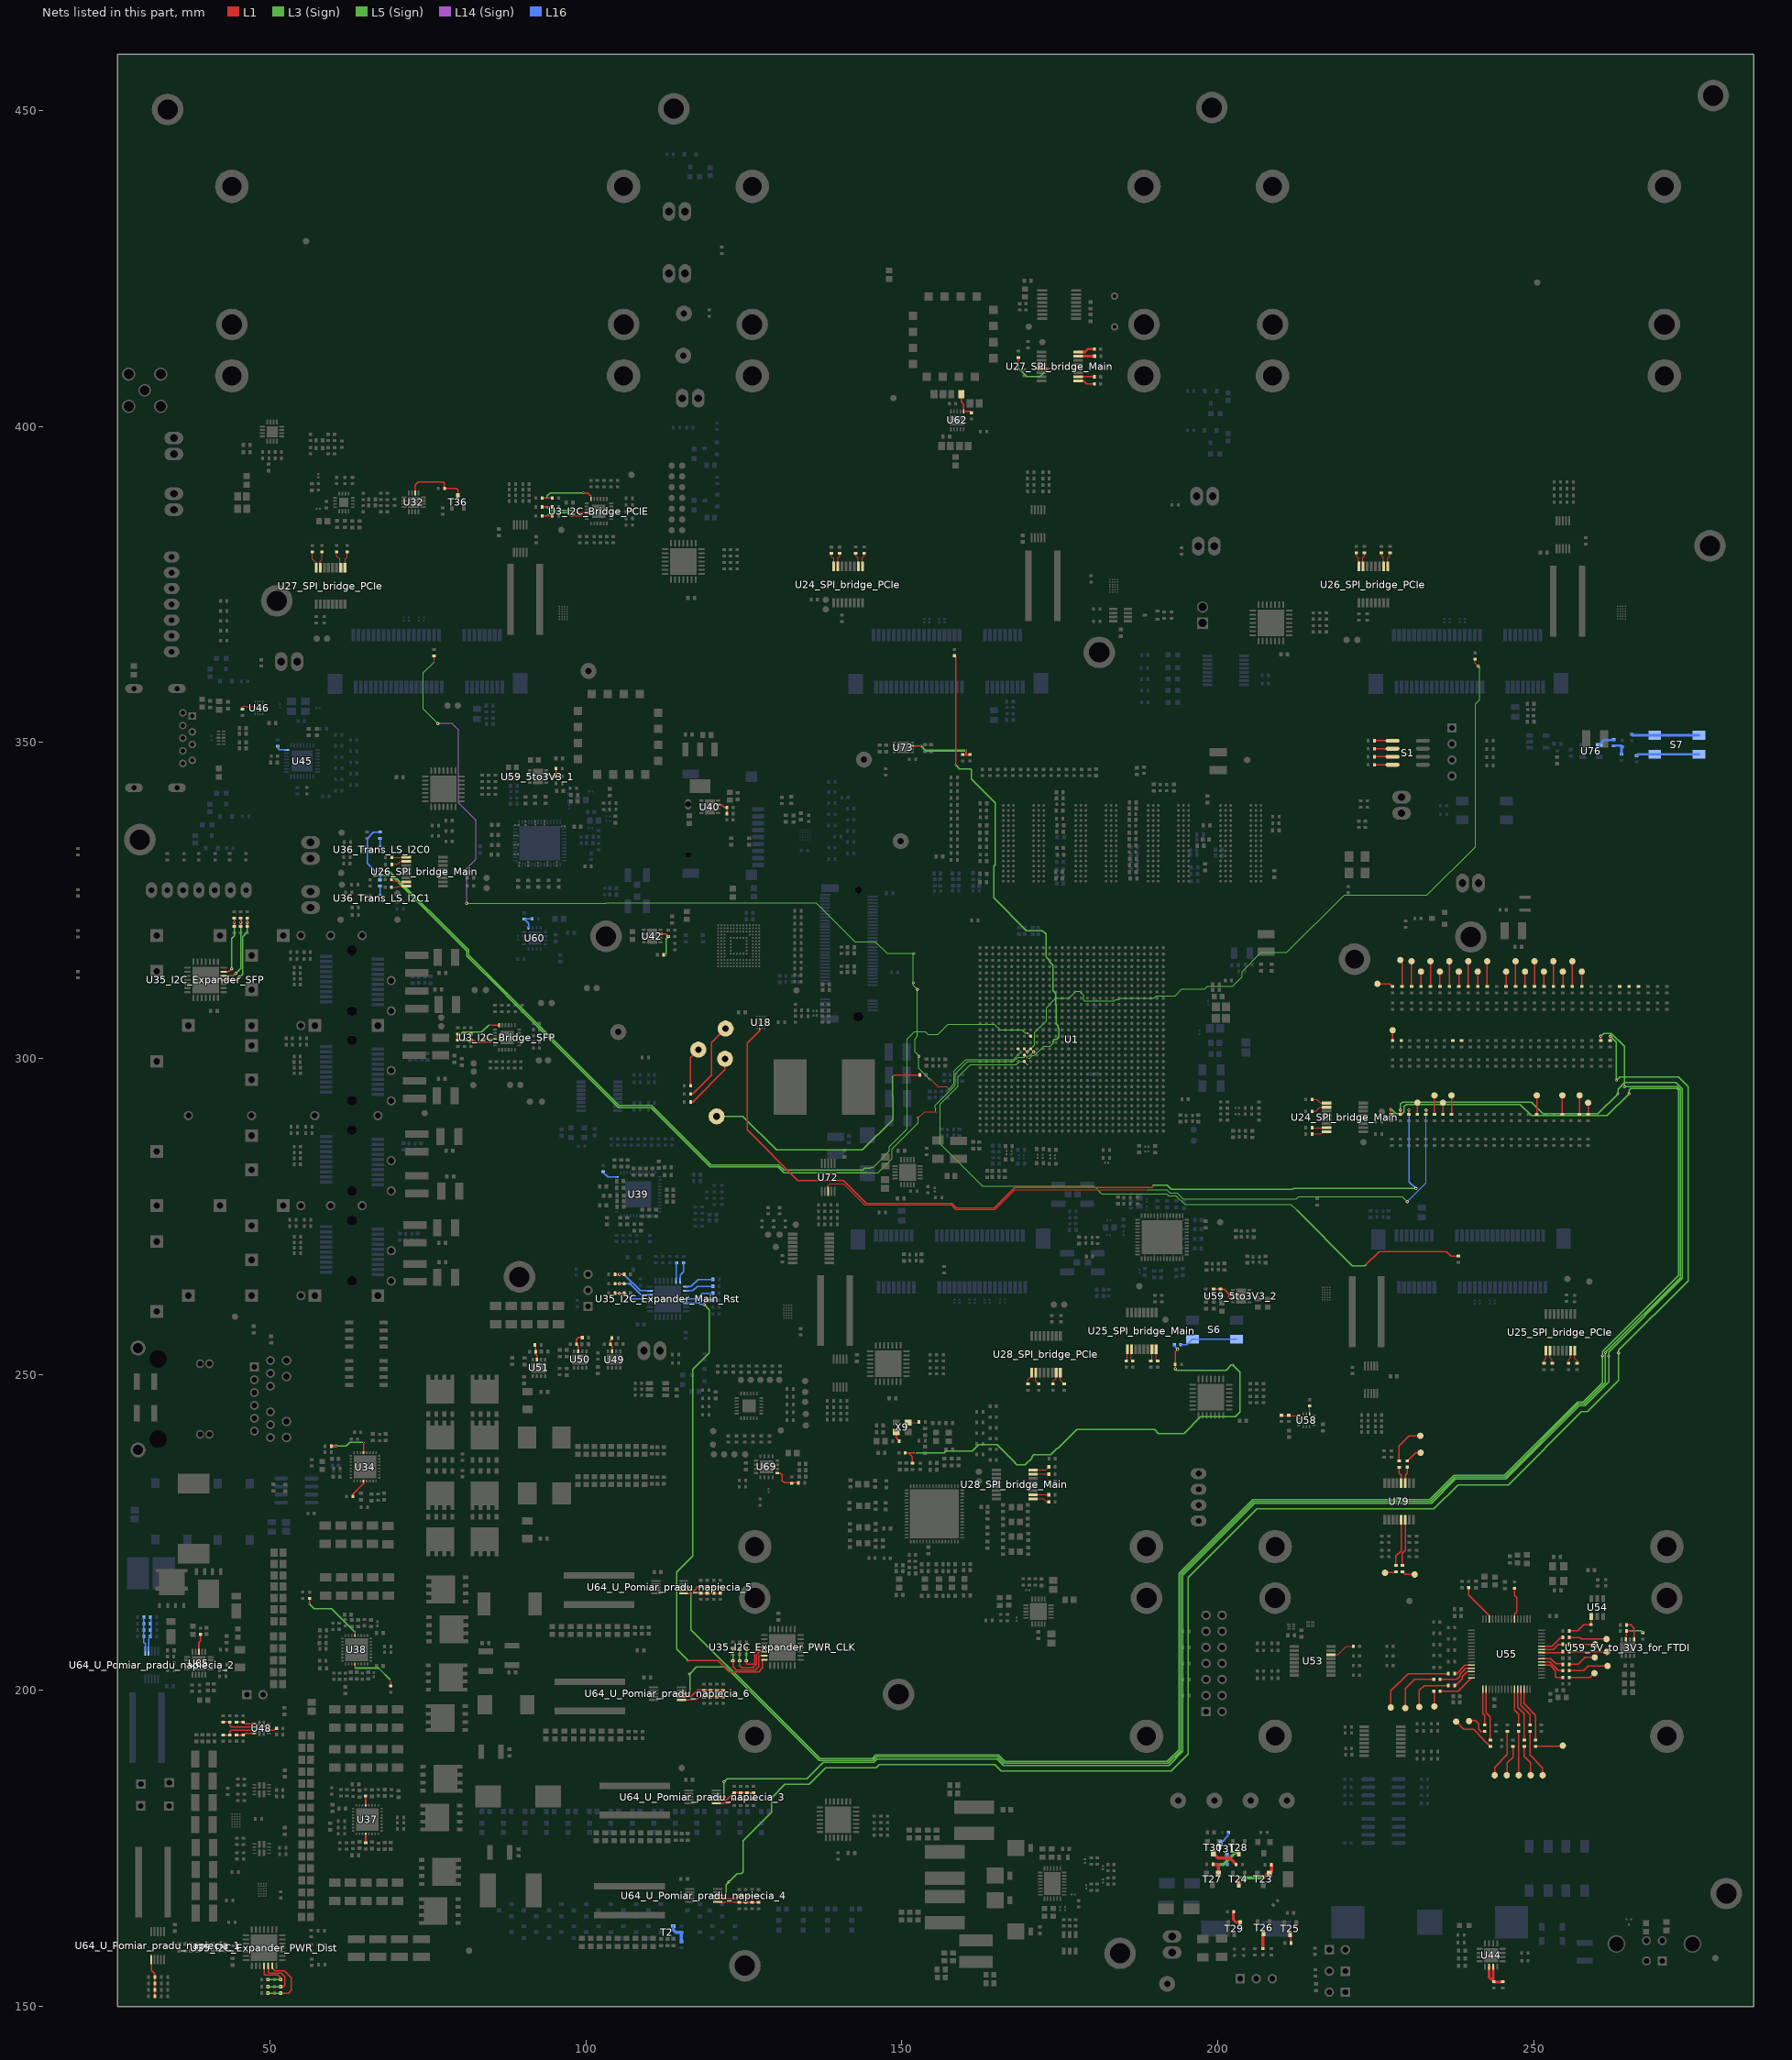
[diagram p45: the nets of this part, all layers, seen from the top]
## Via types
v1: diameter 0.5, hole 0.25, L1 to L16, tented both sides, 4341 vias
v2: diameter 0.254, hole 0.1, L1 to L3 (Sign), tented both sides, 781 vias
v3: diameter 0.5, hole 0.25, L1 to L16, 565 vias
v4: diameter 0.254, hole 0.1, L15 (GND) to L16, tented both sides, 406 vias
v5: diameter 0.254, hole 0.1, L1 to L2 (GND), tented both sides, 283 vias
v6: diameter 0.457, hole 0.2, L3 (Sign) to L6 (PWR/GND), tented both sides, 254 vias
v7: diameter 0.254, hole 0.1, L1 to L3 (Sign), 237 vias
v8: diameter 0.75, hole 0.4, L1 to L16, 200 vias
v9: diameter 0.8, hole 0.4, L1 to L16, tented both sides, 182 vias
v10: diameter 0.254, hole 0.1, L14 (Sign) to L16, tented both sides, 170 vias
v11: diameter 0.75/0/0/0/0/0/0/0/0/0/0/0/0/0/0/0.75 (per signal layer), hole 0.4, L1 to L16, 160 vias
v12: diameter 0.457, hole 0.2, L3 (Sign) to L6 (PWR/GND), 158 vias
v13: diameter 1.4, hole 0.5, L1 to L16, tented both sides, 80 vias
v14: diameter 0.254, hole 0.1, L14 (Sign) to L16, 65 vias
v15: diameter 0.254, hole 0.1, L1 to L2 (GND), 45 vias
v16: diameter 0.457, hole 0.2, L11 (PWR/GND) to L14 (Sign), tented both sides, 26 vias
v17: diameter 0.457, hole 0.2, L11 (PWR/GND) to L14 (Sign), 25 vias
v18: diameter 0.457, hole 0.2, L7(12V+Other) to L10 (3V3+Other), tented both sides, 11 vias
v19: diameter 0.254/0/0.254 (per signal layer), hole 0.1, L1 to L3 (Sign), 9 vias
v20: diameter 0.2/0/0.2 (per signal layer), hole 0.1, L1 to L3 (Sign), 6 vias
v21: diameter 1.65, hole 1.65, L1 to L16, 5 vias
v22: diameter 1.15, hole 1.15, L1 to L16, 5 vias
v23: diameter 0.457, hole 0.2, L1 to L16, 3 vias
v24: diameter 0.5, hole 0.3, L1 to L16, 2 vias
v25: diameter 0.5/0/0.5 (per signal layer), hole 0.2, L14 (Sign) to L16, 1 vias
v26: diameter 0.5, hole 0.25, L1 to L16, tented bottom, 1 vias

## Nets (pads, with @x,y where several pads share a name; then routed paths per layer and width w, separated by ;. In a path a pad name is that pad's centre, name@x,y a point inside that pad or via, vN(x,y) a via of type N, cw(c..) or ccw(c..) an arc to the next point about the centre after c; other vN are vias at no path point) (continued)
NetR334_1: R334.1 U39.12 | length 2.5
  L16 w0.2: R334.1@102.761,282.01 102.761,281.935 102.961,281.735 103.036,281.735 103.496,281.275 U39.12@104.899,281.275
NetR339_1: R339.1 R341.2 U40.7 | length 2.6
  L1 w0.2: U40.7@120.909,340.144 121.51,340.144 121.923,339.731 R341.2@122.354,339.731 ; R339.1@122.354,338.747 R341.2@122.354,339.731 ; R341.2@122.359,339.731 R341.2@122.354,339.731
NetR342_1: R342.1 R344.2 U42.7 | length 4.9
  L1 w0.2: U42.7@111.793,319.701 112.744,319.701 113.04,319.405 v2(113.04,319.355) ; R344.2@112.29,316.411 v2(112.715,316.411)
  L3 (Sign) w0.2: v2(112.715,316.411) 112.715,318.905 113.04,319.23 v2(113.04,319.355)
NetR358_1: R358.1 S1.8 | length 2.9
  L1 w0.2: R358.1@224.765,346.481 S1.8@227.673,346.481
NetR359_1: R359.1 S1.7 | length 2.9
  L1 w0.2: R359.1@224.765,347.751 S1.7@227.673,347.751
NetR360_1: R360.1 S1.6 | length 2.9
  L1 w0.2: R360.1@224.765,349.021 S1.6@227.673,349.021
NetR361_1: R361.1 S1.5 | length 2.9
  L1 w0.2: R361.1@224.765,350.291 S1.5@227.673,350.291
NetR366_2: R366.2 R498.2 R499.2 R692.1 | length 82.7
  L1 w0.2: 151.064,237.602 v2(152.121,237.602) ; v1(193.294,250.906) 193.301,250.913 193.301,253.634 v1(193.643,253.976)
  L1 w0.254: R366.2@150.506,237.602 151.064,237.602 151.671,236.995 151.671,235.938 R498.2@151.701,235.908
  L5 (Sign) w0.2: v1(193.294,250.906) 193.547,250.653 201.331,250.653 202.178,251.5 v6(202.383,251.5)
  L3 (Sign) w0.2: v2(152.121,237.602) 156.723,237.602 157.043,237.922 161.198,237.922 162.17,238.894 165.072,238.894 167.897,236.069 167.897,235.992 168.186,235.702 169.519,235.702 170.581,236.764 170.581,236.982 170.884,237.285 173.587,237.285 174.602,238.301 174.724,238.301 177.693,241.269 190.031,241.269 190.621,240.68 194.645,240.68 197.32,243.354 202.83,243.354 203.501,244.025 203.501,250.382 v6(202.383,251.5)
  L16 w0.2: R692.1@193.2,254.724 193.047,254.571 v1(193.643,253.976)
NetR372_1: R372.1 R373.2 U44.2 U44.3 | length 6.4
  L1 w0.4: U44.2@242.95,156.292 242.95,154.634 R373.2@243.6,153.984 ; U44.3@243.6,156.292 R373.2@243.6,153.984 ; R372.1@245.11,153.871 243.713,153.871 R373.2@243.6,153.984
NetR379_2: R379.2 U45.24 | length 1.9
  L16 w0.2: R379.2@51.256,349.491 51.256,349.066 51.481,348.841 U45.24@52.655,348.841
NetR380_2: R380.2 U46.C1 | length 2.6
  L1 w0.12: R380.2@45.649,355.229 45.649,355.697 45.747,355.795 46.149,355.795 46.264,355.68 47.665,355.68 U46.C1@47.675,355.69
NetR391_1: R391.1 R393.2 U49.7 | length 2.4
  L1 w0.2: U49.7@104.17,253.648 104.17,254.496 103.87,254.796 103.87,255.47 R393.2@104.17,255.77
NetR394_1: R394.1 R396.2 U50.7 | length 3.1
  L1 w0.2: U50.7@98.776,253.671 98.776,254.521 98.501,254.796 98.501,255.511 98.857,255.867 R396.2@99.494,255.867
NetR397_1: R397.1 R399.2 U51.7 | length 2.4
  L1 w0.2: R399.2@92.011,254.68 92.011,253.238 92.244,253.005 U51.7@92.244,252.363
NetR419_2: R419.2 R422.1 U54.1 | length 5.3
  L1 w0.2: R419.2@255.565,209.431 256.971,209.431 257.915,210.376 259.093,210.376 259.121,210.404 U54.1@259.121,211.739
NetR423_1: R423.1 U55.6 | length 5.2
  L1 w0.2: R423.1@246.959,216.225 246.959,215.054 247.32,214.694 247.32,212.407 246.97,212.057 U55.6@246.97,211.316
NetR424_2: R424.2 U55.14 | length 6.4
  L1 w0.2: R424.2@239.72,216.326 239.72,215.142 242.97,211.892 U55.14@242.97,211.316
NetR425_SPI_bridge_Main_1: R425_SPI_bridge_Main.1 U24_SPI_bridge_Main.1 | length 2.6
  L1 w0.12: R425_SPI_bridge_Main.1@214.902,293.539 215.68,293.539 216.267,292.952 U24_SPI_bridge_Main.1@217.232,292.952
NetR425_SPI_bridge_PCIe_1: R425_SPI_bridge_PCIe.1 U24_SPI_bridge_PCIe.1 | length 2.3
  L1 w0.12: U24_SPI_bridge_PCIe.1@143.782,377.907 143.757,377.932 143.757,379.157 144.057,379.457 R425_SPI_bridge_PCIe.1@144.057,380.027
NetR426_SPI_bridge_Main_2: R426_SPI_bridge_Main.2 U24_SPI_bridge_Main.7 | length 2.3
  L1 w0.12: R426_SPI_bridge_Main.2@214.902,289.052 U24_SPI_bridge_Main.7@217.232,289.052
NetR426_SPI_bridge_PCIe_2: R426_SPI_bridge_PCIe.2 U24_SPI_bridge_PCIe.7 | length 2.2
  L1 w0.12: U24_SPI_bridge_PCIe.7@139.882,377.907 139.882,379.157 140.183,379.458 R426_SPI_bridge_PCIe.2@140.183,379.977
NetR429_1: R429.1 U58.12 | length 1.3
  L1 w0.12: U58.12@214.553,243.754 R429.1@214.553,245.065
NetR430_5to3V3_1_1: R430_5to3V3_1.1 R432_5to3V3_1.2 U59_5to3V3_1.7 | length 2.9
  L1 w0.2: U59_5to3V3_1.7@93.731,344.952 94.323,344.952 94.597,344.678 95.189,344.678 95.314,344.803 R430_5to3V3_1.1@95.314,345.91
NetR430_5to3V3_2_1: R430_5to3V3_2.1 R432_5to3V3_2.2 U59_5to3V3_2.7 | length 3.9
  L1 w0.2: R430_5to3V3_2.1@199.36,263.463 200.435,263.463 201.057,263.463 201.691,262.829 201.691,262.289 201.892,262.088 U59_5to3V3_2.7@202.395,262.088
NetR430_5V_to_3V3_for_FTDI_1: R430_5V_to_3V3_for_FTDI.1 R432_5V_to_3V3_for_FTDI.2 U59_5V_to_3V3_for_FTDI.7 | length 4.1
  L1 w0.2: U59_5V_to_3V3_for_FTDI.7@264.594,208.077 264.594,208.612 264.683,208.701 264.683,209.436 v7(265.423,209.436)
  L3 (Sign) w0.2: v7(265.423,209.436) 267.019,209.436 v7(267.268,209.187)
NetR431_5V_to_3V3_for_FTDI_1: R431_5V_to_3V3_for_FTDI.1 U59_5V_to_3V3_for_FTDI.5 | length 3.2
  L1 w0.2: R431_5V_to_3V3_for_FTDI.1@264.683,210.378 265.366,210.378 265.908,209.836 265.908,208.091 U59_5V_to_3V3_for_FTDI.5@265.894,208.077
NetR433_1: R433.1 R434.1 U60.9 | length 2.9
  L16 w0.2: U60.9@90.939,320.703 90.947,320.711 90.947,321.386 R434.1@90.287,322.046 90.287,322.096 R433.1@91.561,322.096
NetR443_1: R443.1 R444.2 U62.6 | length 4.2
  L1 w0.2: R443.1@159.413,405.114 159.413,403.896 159.785,403.523 U62.6@159.785,402.411 160.751,402.411 R444.2@161.032,402.131
NetR449_2: R449.2 R450.1 U3_I2C_Bridge_PCIE.22 | length 8.4
  L1 w0.2: R450.1@93.032,387.28 v2(93.815,387.28) R449.2@94.744,387.28 ; v2(98.412,386.372) 98.421,386.363 U3_I2C_Bridge_PCIE.22@100.135,386.363
  L3 (Sign) w0.2: v2(93.815,387.28) 94.383,386.712 98.072,386.712 v2(98.412,386.372)
NetR451_2: R451.2 R452.1 U3_I2C_Bridge_PCIE.23 | length 8.4
  L1 w0.2: R452.1@93.032,385.877 v2(93.866,385.877) R451.2@94.745,385.877 ; v2(97.727,385.877) 100.121,385.877 U3_I2C_Bridge_PCIE.23@100.135,385.863
  L3 (Sign) w0.2: v2(93.866,385.877) 94.375,386.386 97.218,386.386 v2(97.727,385.877)
NetR453_2: R453.2 R454.1 U3_I2C_Bridge_PCIE.18 | length 9.8
  L1 w0.2: R454.1@93.032,388.683 v2(93.889,388.683) R453.2@94.745,388.683 ; v2(99.619,389.509) 100.292,389.509 100.82,388.981 U3_I2C_Bridge_PCIE.18@100.82,388.548
  L3 (Sign) w0.2: v2(93.889,388.683) 93.889,389.037 94.361,389.509 v2(99.619,389.509)
NetR455_2: R455.2 R456.1 U35_I2C_Expander_PWR_Dist.13 | length 9.9
  L1 w0.2: U35_I2C_Expander_PWR_Dist.13@50.393,156.428 50.393,156.053 50.793,155.653 52.271,155.653 53.404,154.521 53.404,152.589 52.925,152.11 v7(51.667,152.11)
  L3 (Sign) w0.2: v7(49.685,152.11) v7(51.667,152.11)
NetR458_2: R458.2 R460.1 U35_I2C_Expander_PWR_Dist.12 | length 8
  L1 w0.2: U35_I2C_Expander_PWR_Dist.12@49.743,156.428 49.743,155.392 49.861,155.275 51.77,155.275 52.362,154.682 52.362,153.397 52.092,153.126 v7(51.667,153.126)
  L3 (Sign) w0.2: v7(49.685,153.126) v7(51.667,153.126)
NetR461_1: R461.1 R463.1 R465.1 R466.1 U64_U_Pomiar_pradu_napiecia_1.1 | length 6
  L1 w0.2: U64_U_Pomiar_pradu_napiecia_1.1@31.245,157.414 31.245,155.724 31.745,155.224 31.745,153.653 31.745,151.628 R465.1@31.738,151.621
NetR462_2: R462.2 R464.1 U35_I2C_Expander_PWR_Dist.11 | length 6.4
  L1 w0.2: U35_I2C_Expander_PWR_Dist.11@49.093,156.428 49.093,155.11 49.234,154.969 51.3,154.969 51.667,154.603 v7(51.667,154.269)
  L3 (Sign) w0.2: v7(49.685,154.269) v7(51.667,154.269)
NetR467_1: R467.1 R468.1 R593.1 R594.1 U64_U_Pomiar_pradu_napiecia_2.2 | length 5.5
  L16 w0.2: U64_U_Pomiar_pradu_napiecia_2.2@30.798,206.235 30.798,208.179 30.908,208.289 30.908,208.339 R468.1@31.108,208.539 31.158,208.539 R593.1@31.158,211.587
NetR469_2: R469.2 R470.1 U3_I2C_Bridge_SFP.22 | length 6.4
  L1 w0.2: R470.1@80.807,302.877 v2(80.807,303.414) R469.2@80.807,303.951 ; v2(83.795,303.124) 83.823,303.096 U3_I2C_Bridge_SFP.22@85.6,303.096
  L3 (Sign) w0.2: v2(80.807,303.414) 81.593,302.628 83.299,302.628 v2(83.795,303.124)
NetR471_2: R471.2 R472.1 U3_I2C_Bridge_SFP.23 | length 5
  L1 w0.2: R471.2@81.823,303.951 81.823,302.877 82.264,302.877 82.545,302.596 U3_I2C_Bridge_SFP.23@85.6,302.596
NetR473_2: R473.2 R474.1 U3_I2C_Bridge_SFP.18 | length 8.4
  L1 w0.2: R474.1@79.743,302.865 v2(79.743,303.417) R473.2@79.743,303.939 ; v2(84.874,305.283) 86.287,305.283 U3_I2C_Bridge_SFP.18@86.285,305.281
  L3 (Sign) w0.2: v2(79.743,303.417) 80.492,304.165 83.502,304.165 84.62,305.283 v2(84.874,305.283)
NetR475_2: R475.2 R476.1 U35_I2C_Expander_SFP.13 | length 10.4
  L1 w0.2: U35_I2C_Expander_SFP.13@42.702,313.753 43.523,313.753 v1(43.955,314.185) ; R476.1@44.356,320.853 v1(44.356,321.558) R475.2@44.356,322.262
  L5 (Sign) w0.2: v1(43.955,314.185) 43.955,319.011 44.356,319.413 v1(44.356,321.558)
NetR477_2: R477.2 R478.1 U35_I2C_Expander_SFP.12 | length 11.8
  L1 w0.2: U35_I2C_Expander_SFP.12@42.702,313.103 44.194,313.103 v1(44.577,313.487) ; R478.1@45.372,320.853 v1(45.372,321.558) R477.2@45.372,322.262
  L5 (Sign) w0.2: v1(44.577,313.487) 45.372,314.282 v1(45.372,321.558)
NetR479_2: R479.2 R480.1 U35_I2C_Expander_SFP.11 | length 13.3
  L1 w0.2: U35_I2C_Expander_SFP.11@42.702,312.453 44.788,312.453 v1(45.212,312.877) ; R480.1@46.434,320.853 v1(46.434,321.558) R479.2@46.434,322.262
  L5 (Sign) w0.2: v1(45.212,312.877) 45.672,313.338 45.672,319.281 46.434,320.043 v1(46.434,321.558)
NetR481_2: R481.2 U27_SPI_bridge_Main.13 | length 8.9
  L1 w0.2: R481.2@168.442,410.963 168.442,410.054 v7(168.455,410.041) ; U27_SPI_bridge_Main.13@172.108,409.191 173.309,409.191 v7(173.335,409.165)
  L3 (Sign) w0.2: v7(168.455,410.041) 168.455,409.228 169.069,408.614 169.792,407.891 171.904,407.891 173.15,409.136 173.306,409.136 v7(173.335,409.165) v7@173.344,409.165
NetR488_1: R488.1 T36.3 U32.2 | length 10.1
  L1 w0.2: U32.2@72.995,389.511 72.995,390.756 73.456,391.218 77.379,391.218 77.597,391 77.597,390.204 79.474,390.204 79.761,389.917 T36.3@79.761,389.058
NetR507_1: R507.1 U1.H13 | length 77.2
  L1 w0.12: U1.H13@169.397,300.539 v2(169.884,300.052)
  L1 w0.2: R507.1@158.337,363.793 158.533,363.597 v7(158.533,346.446)
  L3 (Sign) w0.12: v2(169.884,300.052) 170.277,300.052 170.69,300.464 170.986,300.464 172.471,301.949 173.515,301.949 173.909,302.344
  L3 (Sign) w0.2: v7(158.533,346.446) 159.155,345.824 160.871,345.824 160.988,345.707 160.988,344.219 164.77,340.436 164.77,330.673 164.557,330.46 164.557,325.418 169.729,320.246 172.273,320.246 172.831,319.688 172.831,316.091 172.948,315.974 172.963,315.974 173.397,315.539 173.397,315.318 173.898,314.816 173.898,310.746 174.397,310.248 174.397,308.539 174.422,308.514 174.422,305.495 174.704,305.212 174.704,304.96 174.87,304.795 174.87,303.376 174.501,303.007 174.172,303.007 173.909,302.744 173.909,302.344
NetR514_1: R514.1 U1.H12 | length 115.9
  L1 w0.12: U1.H12@169.397,299.539 v2(169.884,299.052)
  L1 w0.2: v2(223.431,267.311) 225.551,269.43 236.195,269.43 236.932,268.694 R514.1@238.087,268.694
  L3 (Sign) w0.12: v2(169.884,299.052) 169.383,299.554 168.676,299.554 168.145,299.023 161.397,299.023 160.875,299.023 158.945,297.094 158.945,295.618 156.096,292.769 156.096,286.493 162.761,279.828 180.433,279.828 181.649,278.611 191.926,278.611 192.228,278.309 193.404,278.309 194.801,276.911 211.607,276.911 212.56,275.958
  L3 (Sign) w0.2: 212.56,275.958 221.323,267.195 223.315,267.195 v2(223.431,267.311)
NetR543_1: R543.1 X9.3 | length 1.8
  L1 w0.101: X9.3@151.013,242.393 152.682,242.393 R543.1@152.77,242.481
NetR544_1: R544.1 X9.1 | length 1.6
  L1 w0.2: X9.1@149.113,240.893 149.113,239.972 149.591,239.494 R544.1@149.591,239.444
NetR561_1: R561.1 R562.1 R563.1 R564.1 U64_U_Pomiar_pradu_napiecia_3.2 | length 6.3
  L1 w0.2: U64_U_Pomiar_pradu_napiecia_3.2@120.678,182.659 122.233,182.659 123.433,183.86 123.482,183.86 124.498,183.86 125.514,183.86 R563.1@126.53,183.86
NetR565_1: R565.1 R566.1 R567.1 R568.1 U64_U_Pomiar_pradu_napiecia_3.1 | length 6.1
  L1 w0.2: U64_U_Pomiar_pradu_napiecia_3.1@120.678,182.159 122.584,182.159 123.152,182.728 123.482,182.728 124.498,182.728 125.514,182.728 R567.1@126.53,182.728
NetR569_1: R569.1 R570.1 R571.1 R572.1 U64_U_Pomiar_pradu_napiecia_4.2 | length 7
  L1 w0.2: U64_U_Pomiar_pradu_napiecia_4.2@120.552,167.055 123.809,167.055 R570.1@124.265,167.511 124.265,167.561 125.281,167.561 126.297,167.561 R571.1@127.313,167.561
NetR573_1: R573.1 R574.1 R575.1 R576.1 U64_U_Pomiar_pradu_napiecia_4.1 | length 6.6
  L1 w0.2: U64_U_Pomiar_pradu_napiecia_4.1@120.722,166.543 124.151,166.543 124.265,166.429 125.281,166.429 126.297,166.429 R575.1@127.313,166.429
NetR577_1: R577.1 R578.1 R579.1 R580.1 U64_U_Pomiar_pradu_napiecia_5.2 | length 6.1
  L1 w0.2: U64_U_Pomiar_pradu_napiecia_5.2@115.471,215.848 117.187,215.848 117.729,216.389 118.16,216.389 R578.1@118.212,216.441 121.21,216.441 R579.1@121.26,216.491
NetR581_1: R581.1 R582.1 R583.1 R584.1 U64_U_Pomiar_pradu_napiecia_5.1 | length 5.8
  L1 w0.2: U64_U_Pomiar_pradu_napiecia_5.1@115.471,215.348 118.2,215.348 118.212,215.359 119.228,215.359 120.244,215.359 R583.1@121.26,215.359
NetR585_1: R585.1 R586.1 R587.1 R588.1 U64_U_Pomiar_pradu_napiecia_6.2 | length 7
  L1 w0.2: U64_U_Pomiar_pradu_napiecia_6.2@115.141,199.008 116.635,199.008 117.698,200.071 118.682,200.071 120.714,200.071 R587.1@121.73,200.071
NetR589_1: R589.1 R590.1 R591.1 R592.1 U64_U_Pomiar_pradu_napiecia_6.1 | length 6.8
  L1 w0.2: U64_U_Pomiar_pradu_napiecia_6.1@115.141,198.508 115.161,198.489 117.398,198.489 117.848,198.939 118.682,198.939 119.698,198.939 120.714,198.939 R591.1@121.73,198.939
NetR595_1: R595.1 R596.1 R597.1 R598.1 U64_U_Pomiar_pradu_napiecia_2.1 | length 5.5
  L16 w0.2: R597.1@30.026,211.587 30.026,208.539 30.026,207.655 30.298,207.383 U64_U_Pomiar_pradu_napiecia_2.1@30.298,206.235
NetR600_1: R600.1 R601.2 U58.1 | length 2.7
  L1 w0.12: R600.1@210.075,243.504 211.261,243.504 U58.1@212.803,243.504
NetR602_SPI_bridge_Main_1: R602_SPI_bridge_Main.1 U24_SPI_bridge_Main.2 | length 2.6
  L1 w0.12: R602_SPI_bridge_Main.1@214.902,291.652 215.491,291.652 216.141,292.302 U24_SPI_bridge_Main.2@217.232,292.302
NetR602_SPI_bridge_PCIe_1: R602_SPI_bridge_PCIe.1 U24_SPI_bridge_PCIe.2 | length 2.3
  L1 w0.12: R602_SPI_bridge_PCIe.1@142.687,380.027 142.687,379.602 143.132,379.157 U24_SPI_bridge_PCIe.2@143.132,377.907
NetR603_SPI_bridge_Main_2: R603_SPI_bridge_Main.2 U24_SPI_bridge_Main.8 | length 2.5
  L1 w0.12: R603_SPI_bridge_Main.2@214.902,288.068 216.373,288.068 216.707,288.402 U24_SPI_bridge_Main.8@217.232,288.402
NetR603_SPI_bridge_PCIe_2: R603_SPI_bridge_PCIe.2 U24_SPI_bridge_PCIe.8 | length 2.2
  L1 w0.12: R603_SPI_bridge_PCIe.2@138.857,379.977 138.857,379.457 139.232,379.082 U24_SPI_bridge_PCIe.8@139.232,377.907
NetR604_SPI_bridge_Main_1: R604_SPI_bridge_Main.1 U25_SPI_bridge_Main.1 | length 2
  L1 w0.12: R604_SPI_bridge_Main.1@185.538,252.123 185.698,252.284 U25_SPI_bridge_Main.1@185.698,254.021
NetR604_SPI_bridge_PCIe_1: R604_SPI_bridge_PCIe.1 U25_SPI_bridge_PCIe.1 | length 2.2
  L1 w0.12: R604_SPI_bridge_PCIe.1@251.666,251.739 251.666,252.314 251.993,252.641 251.993,253.715 U25_SPI_bridge_PCIe.1@251.941,253.767
NetR605_SPI_bridge_Main_2: R605_SPI_bridge_Main.2 U25_SPI_bridge_Main.7 | length 2
  L1 w0.12: R605_SPI_bridge_Main.2@189.416,252.123 189.598,252.306 U25_SPI_bridge_Main.7@189.598,254.021
NetR605_SPI_bridge_PCIe_2: R605_SPI_bridge_PCIe.2 U25_SPI_bridge_PCIe.7 | length 2.2
  L1 w0.12: R605_SPI_bridge_PCIe.2@255.537,251.739 255.537,252.337 255.841,252.641 U25_SPI_bridge_PCIe.7@255.841,253.767
NetR606_SPI_bridge_Main_1: R606_SPI_bridge_Main.1 U25_SPI_bridge_Main.2 | length 2
  L1 w0.12: U25_SPI_bridge_Main.2@186.348,254.021 186.348,252.323 R606_SPI_bridge_Main.1@186.548,252.123
NetR606_SPI_bridge_PCIe_1: R606_SPI_bridge_PCIe.1 U25_SPI_bridge_PCIe.2 | length 2.2
  L1 w0.12: U25_SPI_bridge_PCIe.2@252.591,253.767 252.591,252.69 252.94,252.341 R606_SPI_bridge_PCIe.1@252.94,251.739
NetR612_1: R612.1 U34.29 | length 7
  L1 w0.254: U34.29@64.822,237.639 64.822,237.71 64.831,237.72 v2(64.831,239.268)
  L1 w0.4: R612.1@59.692,238.671 v1(60.452,238.671)
  L3 (Sign) w0.2: v1(60.452,238.671) 62.078,238.671 62.674,239.268 v2(64.831,239.268)
NetR614_1: R614.1 U34.12 | length 3.1
  L1 w0.254: R614.1@63.088,230.712 63.088,230.995 64.815,232.722 64.815,232.984 64.82,232.989 64.82,233.137 U34.12@64.822,233.139
NetR621_1: R621.1 U37.29 | length 1.6
  L1 w0.254: R621.1@65.137,183.369 65.116,183.348 65.116,182.714 65.175,182.655 U37.29@65.175,181.817
NetR622_1: R622.1 U37.12 | length 1.4
  L1 w0.254: R622.1@65.175,175.893 U37.12@65.175,177.317
NetR628_1: R628.1 U38.12 | length 8.1
  L1 w0.254: v2(63.453,203.556) U38.12@63.453,204.214 ; R628.1@69.132,200.683 v2(69.132,201.631)
  L3 (Sign) w0.254: v2(63.453,203.556) 67.207,203.556 v2@69.138,201.625
NetR644_1: R644.1 R645.2 U69.9 | length 4.6
  L1 w0.2: U69.9@130.28,234.418 130.732,234.418 131.053,234.097 131.053,233.213 131.407,232.859 132.588,232.859 R645.2@133.706,232.859
NetR648_2: R648.2 T25.3 | length 1.4
  L1 w0.2: T25.3@211.493,161.361 211.587,161.267 R648.2@211.587,160.033
NetR649_2: R649.2 T26.3 | length 2.3
  L1 w0.5: R649.2@207.162,159.186 207.162,161.348 T26.3@207.264,161.45
NetR650_2: R650.2 T23.1 T24.3 | length 7.7
  L1 w0.5: T24.3@203.34,169.146 203.41,169.217 v2(203.41,170.155) ; v1(207.261,170.383) 207.88,171.002 T23.1@208.189,171.002 208.501,171.314 R650.2@208.501,172.453
  L3 (Sign) w0.5: v2(203.41,170.155) 203.639,170.383 v1(207.261,170.383)
NetR651_1: R651.1 T27.1 T28.3 | length 7.3
  L1 w0.5: R651.1@199.238,172.492 199.289,172.441 v2(200.215,172.441) 200.111,172.337 T27.1@200.111,171.028 ; T28.3@203.327,174.137 v2(203.327,174.866)
  L3 (Sign) w0.5: v2(200.215,172.441) 200.901,172.441 v2(203.327,174.866)
NetR653_2: R653.2 T30.3 | length 4.4
  L1 w0.5: T30.3@199.339,174.236 200.06,173.515 201.917,173.515 R653.2@202.966,172.467
NetR655_2: R655.2 T29.1 | length 2.5
  L1 w0.4: R655.2@202.489,164.999 202.489,163.769 202.929,163.329 T29.1@203.579,163.329
NetR657_1: R657.1 T31.3 | length 1.5
  L16 w0.4: T31.3@201.435,173.934 201.478,173.89 R657.1@201.478,172.467
NetR658_1: R658.1 T31.1 | length 2.2
  L16 w0.2: T31.1@200.485,175.902 200.527,175.902 201.656,177.031 R658.1@201.656,177.56
NetR665_2: R665.2 U65.13 | length 2.9
  L1 w0.254: U65.13@38.76,206.158 38.76,207.602 39.014,207.856 R665.2@39.014,208.928
NetR677_1: R677.1 R682.2 U48.6 | length 2.9
  L1 w0.2: R677.1@44.716,192.933 45.775,192.933 45.914,192.933 46.214,193.233 U48.6@47.527,193.233
NetR678_1: R678.1 R683.2 U48.5 | length 5.6
  L1 w0.2: R683.2@42.6,192.933 43.658,192.933 43.658,193.501 43.89,193.733 U48.5@47.527,193.733
NetR679_1: R679.1 R684.2 U48.3 | length 2.9
  L1 w0.2: R684.2@44.716,195.033 45.775,195.033 46.075,194.733 U48.3@47.527,194.733
NetR680_1: R680.1 R685.2 U48.4 | length 5.6
  L1 w0.2: R685.2@42.6,195.033 43.658,195.033 43.658,194.466 43.89,194.233 U48.4@47.527,194.233
NetR681_2: R681.2 U48.10 | length 1.4
  L1 w0.2: U48.10@49.827,193.733 50.729,193.733 R681.2@51.105,194.109
NetR686_1: R686.1 U38.29 | length 10.5
  L1 w0.2: v2(56.258,213.703) 56.27,213.714 R686.1@56.27,214.612
  L1 w0.254: U38.29@63.453,208.714 v2@63.453,209.276
  L3 (Sign) w0.2: v2(56.258,213.703) 57.02,212.941 59.784,212.941 v2(63.449,209.276)
NetR689_2: R689.2 R690.2 U73.7 | length 10.7
  L1 w0.2: U73.7@151.644,349.484 153.033,349.484 v2(153.035,349.482)
  L1 w0.3: R690.2@159.652,348.062 160.213,348.062 ; v2(160.213,348.729) 160.213,348.062 ; R689.2@160.795,348.062 160.213,348.062
  L3 (Sign) w0.2: v2(153.035,349.482) v2@153.035,349.491
  L3 (Sign) w0.3: v2@153.035,349.491 153.797,348.729 v2(160.213,348.729)
NetR692_2: R692.2 S6.3 S6.4 | length 9.3
  L16 w0.2: R692.2@194.1,254.724 195.12,254.724 S6.4@195.999,255.603 S6.3@202.999,255.603
NetR710_1: R710.1 R711.1 R712.2 | length 2.7
  L16 w0.4: R711.1@262.674,349.511 263.868,349.511 R712.2@263.919,349.46 ; R710.1@263.919,348.107 R712.2@263.919,349.46 ; R712.2@264.008,349.371 R712.2@263.919,349.46
NetR711_2: R711.2 U76.4 | length 2.6
  L16 w0.4: U76.4@260.38,349.616 261.175,350.411 R711.2@262.674,350.411
NetR713_1: R713.1 S7.1 S7.2 | length 10.7
  L16 w0.4: R713.1@265.532,351.244 265.619,351.156 S7.2@269.169,351.156 S7.1@276.169,351.156
NetR714_2: R714.2 S7.3 S7.4 | length 10
  L16 w0.4: R714.2@266.306,347.884 266.579,348.156 S7.4@269.169,348.156 S7.3@276.169,348.156
NetR738_2: R738.2 R739.2 U35_I2C_Expander_PWR_CLK.13 | length 10
  L1 w0.2: R738.2@123.273,204.778 123.273,203.787 123.824,203.236 126.795,203.236 127.366,203.807 127.366,205.306 127.588,205.528 U35_I2C_Expander_PWR_CLK.13@128.253,205.528
  L3 (Sign) w0.2: v7(123.273,204.728) v7(123.273,206.659)
NetR740_2: R740.2 R741.2 U35_I2C_Expander_PWR_CLK.12 | length 8.7
  L1 w0.2: R740.2@124.34,204.778 v7(124.34,204.728) 124.34,203.972 124.706,203.606 126.447,203.606 127.037,204.196 127.037,205.627 127.588,206.178 U35_I2C_Expander_PWR_CLK.12@128.253,206.178
  L3 (Sign) w0.2: v7(124.34,204.728) v7(124.34,206.659)
NetR742_2: R742.2 R743.2 U35_I2C_Expander_PWR_CLK.11 | length 7.4
  L1 w0.2: R742.2@125.394,204.778 125.394,204.315 125.511,204.198 125.677,204.198 125.683,204.203 126.62,204.203 126.737,204.32 126.737,206.087 127.479,206.828 U35_I2C_Expander_PWR_CLK.11@128.253,206.828
  L3 (Sign) w0.2: v7(125.394,204.728) v7(125.394,206.659)
NetR749_1: R749.1 U35_I2C_Expander_Main_Rst.20 | length 2.9
  L16 w0.2: U35_I2C_Expander_Main_Rst.20@114.298,264.843 114.298,267.646 R749.1@114.383,267.731
NetR750_1: R750.1 U35_I2C_Expander_Main_Rst.21 | length 3.1
  L16 w0.2: U35_I2C_Expander_Main_Rst.21@114.948,264.843 114.948,265.722 115.481,266.255 R750.1@115.481,267.731
NetR751_1: R751.1 U35_I2C_Expander_Main_Rst.22 | length 4.8
  L16 w0.2: U35_I2C_Expander_Main_Rst.22@115.873,263.918 116.648,263.918 117.78,265.049 R751.1@120.169,265.049
NetR752_1: R752.1 U35_I2C_Expander_Main_Rst.23 | length 4.6
  L16 w0.2: U35_I2C_Expander_Main_Rst.23@115.873,263.268 116.958,263.268 117.647,263.957 R752.1@120.169,263.957
NetR753_1: R753.1 U35_I2C_Expander_Main_Rst.25 | length 4.7
  L16 w0.2: U35_I2C_Expander_Main_Rst.25@115.873,261.968 117.544,261.968 118.441,262.865 R753.1@120.169,262.865
NetR754_1: R754.1 U35_I2C_Expander_Main_Rst.26 U35_I2C_Expander_PWR_CLK.14 | length 79.4
  L1 w0.2: v7(116.169,204.727) 120.94,204.727 122.731,202.936 127.361,202.936 127.978,203.553 127.978,204.832 128.025,204.878 U35_I2C_Expander_PWR_CLK.14@128.253,204.878
  L3 (Sign) w0.2: v7(116.169,204.727) 114.369,206.527 114.369,218.711 116.923,221.265 116.923,250.785 119.565,253.427 119.565,260.259 v1(118.706,261.118)
  L16 w0.2: U35_I2C_Expander_Main_Rst.26@115.873,261.318 117.935,261.318 ; v1(118.706,261.118) 118.135,261.118 117.935,261.318 ; R754.1@120.169,261.772 118.389,261.772 117.935,261.318
NetR758_2: R758.2 R759.1 U35_I2C_Expander_Main_Rst.13 | length 7.4
  L1 w0.2: R759.1@104.583,265.852 105.346,265.852 R758.2@106.108,265.852
  L16 w0.2: v1(105.34,265.849) 106.046,265.849 108.628,263.268 U35_I2C_Expander_Main_Rst.13@110.123,263.268
NetR760_2: R760.2 R761.1 U35_I2C_Expander_Main_Rst.12 | length 7.1
  L1 w0.2: R761.1@104.583,264.358 105.314,264.358 R760.2@106.108,264.358
  L16 w0.2: v1(105.308,264.355) 106.982,264.355 108.719,262.618 U35_I2C_Expander_Main_Rst.12@110.123,262.618
NetR762_2: R762.2 R763.1 U35_I2C_Expander_Main_Rst.11 | length 6.7
  L1 w0.2: R763.1@104.583,262.865 105.314,262.865 R762.2@106.108,262.865
  L16 w0.2: v1(105.308,262.861) 106.253,262.861 107.146,261.968 U35_I2C_Expander_Main_Rst.11@110.123,261.968
NetR768_1: R768.1 TP21.1 | length 44.3
  L1 w0.2: v2(148.551,297.394) R768.1@152.84,297.394 R768.1@152.89,297.394
  L3 (Sign) w0.2: TP21.1@120.439,289.684 121.623,290.868 124.808,290.868 130.161,285.515 143.772,285.515 148.626,290.37 148.626,294.03 148.551,294.105 v2(148.551,297.394)
NetR769_1: R769.1 TP22.1 | length 12.9
  L1 w0.2: R769.1@116.528,294.405 116.922,294.405 119.875,297.358 119.875,302.501 TP22.1@122.123,304.749
NetR770_1: R770.1 TP23.1 | length 6.2
  L1 w0.2: R770.1@116.528,295.694 116.528,300.137 TP23.1@117.805,301.415
NetR771_1: R771.1 TP25.1 | length 9.4
  L1 w0.2: R771.1@116.528,293.115 116.908,293.115 122.034,298.242 TP25.1@122.034,299.966
NetR860_2: R860.2 U64_U_Pomiar_pradu_napiecia_3.3 | length 288.6
  L1 w0.2: U64_U_Pomiar_pradu_napiecia_3.3@120.678,183.159 v2(122.047,183.159) ; R860.2@228.908,291.11 v1(228.908,291.871)
  L5 (Sign) w0.2: v6(121.857,185.562) 122.343,186.048 134.968,186.048 137.572,188.652 145.568,188.652 146.101,189.185 165.066,189.185 166.082,188.17 192.267,188.17 194.456,190.359 194.456,218.244 205.834,229.623 233.321,229.623 233.326,229.627 233.811,229.627 237.647,233.463 245.629,233.463 257.215,245.048 258.119,245.048 261.887,248.816 v6(261.887,252.908) ; v1(228.908,291.871) 228.908,292.789 229.248,293.129 249.637,293.129 251.506,291.26 260.183,291.26 263.334,294.412 v6(263.334,294.437)
  L3 (Sign) w0.2: v6(121.857,185.562) 121.857,183.349 v2(122.047,183.159) ; v6(261.887,252.908) 261.887,253.55 273.546,265.209 273.546,295.195 272.534,296.207 264.418,296.207 263.334,295.124 v6(263.334,294.437)
NetR862_2: R862.2 U64_U_Pomiar_pradu_napiecia_4.3 | length 270.6
  L1 w0.2: U64_U_Pomiar_pradu_napiecia_4.3@120.497,167.568 v2(122.204,167.568) ; R862.2@262.116,302.785 v1(262.116,303.546)
  L5 (Sign) w0.2: v6(122.628,169.713) 123.95,171.035 124.595,171.035 124.895,171.335 124.895,176.241 129.381,180.727 129.381,183.02 131.509,185.148 135.341,185.148 137.945,187.752 145.941,187.752 146.474,188.285 164.693,188.285 165.709,187.27 192.64,187.27 195.356,189.986 195.356,217.872 206.207,228.723 233.694,228.723 233.699,228.727 234.184,228.727 238.019,232.563 246.002,232.563 257.588,244.148 258.492,244.148 263.436,249.092 v6(263.436,253.416) ; v1(262.116,303.546) 263.093,302.569 v6(263.093,296.52)
  L3 (Sign) w0.2: v2(122.204,167.568) 122.204,169.289 v6(122.628,169.713) ; v6(263.093,296.52) 263.1,296.52 263.688,297.107 272.906,297.107 274.446,295.568 274.446,264.836 263.436,253.827 v6(263.436,253.416)
NetR863_2: R863.2 U64_U_Pomiar_pradu_napiecia_5.3 | length 304.5
  L1 w0.2: U64_U_Pomiar_pradu_napiecia_5.3@115.471,216.348 v1(116.635,216.348) ; v1(227.38,291.969) 227.38,291.29 R863.2@227.559,291.11
  L5 (Sign) w0.2: v1(116.635,216.348) 116.635,209.602 122.198,204.039 122.27,204.039 137.056,189.252 145.319,189.252 145.852,189.785 165.315,189.785 166.33,188.77 192.019,188.77 193.856,190.607 193.856,218.493 205.585,230.223 233.072,230.223 233.077,230.227 233.563,230.227 237.398,234.063 245.381,234.063 256.966,245.648 257.871,245.648 260.909,248.686 v6(260.909,252.959) ; v1(227.38,291.969) 227.461,291.969 228.155,291.274 229.197,291.274 229.514,291.592 229.514,292.406 229.843,292.735 247.852,292.735 249.627,290.96 261.649,290.96 v6(265.1,294.411)
  L3 (Sign) w0.2: v6(260.909,252.959) 260.909,253.632 260.916,253.639 260.916,253.64 261.18,253.904 261.181,253.904 272.946,265.669 272.946,294.947 272.617,295.275 265.379,295.275 265.1,294.996 v6(265.1,294.411)
NetR864_2: R864.2 U64_U_Pomiar_pradu_napiecia_6.3 | length 270.3
  L1 w0.2: U64_U_Pomiar_pradu_napiecia_6.3@115.141,199.508 v2(116.462,199.508) ; R864.2@260.639,302.785 v1(260.639,303.546)
  L5 (Sign) w0.2: v6(116.387,202.602) 117.524,203.739 122.145,203.739 136.932,188.952 145.444,188.952 145.977,189.485 165.19,189.485 166.206,188.47 192.143,188.47 194.156,190.483 194.156,218.369 205.71,229.923 233.197,229.923 233.202,229.927 233.687,229.927 237.522,233.763 245.505,233.763 257.091,245.348 257.995,245.348 261.366,248.719 v6(261.366,253.454) ; v1(260.639,303.546) 261.089,303.996 262.303,303.996 264.376,301.923 v6(264.376,295.529)
  L3 (Sign) w0.2: v6(116.387,202.602) 116.392,202.602 116.509,202.485 116.509,199.556 v2(116.462,199.508) ; v6(261.366,253.454) 273.246,265.334 273.246,295.071 272.742,295.575 264.46,295.575 264.414,295.529 v6(264.376,295.529)
NetR865_2: R865.2 U18.A3 | length 143.3
  L1 w0.2: U18.A3@127.498,304.681 127.499,304.376 125.552,302.43 125.552,288.709 133.558,280.703 140.768,280.703 144.401,277.07 157.918,277.07 158.623,276.365 164.682,276.365 167.94,279.623 189.62,279.623 189.727,279.73 189.727,279.924 v7(189.737,279.935) ; R865.2@230.258,291.11 v1(230.258,291.871)
  L3 (Sign) w0.2: v7(189.737,279.935) 192.017,279.935 192.643,279.309 211.912,279.309 212.035,279.432 v1(231.386,279.432)
  L16 w0.2: v1(230.258,291.871) 230.314,291.815 230.314,280.503 v1(231.386,279.432)
NetR866_2: R866.2 U72.3 | length 113.2
  L1 w0.12: U72.3@138.353,279.003 138.353,279.856 138.659,280.162 140.765,280.162 144.116,276.81 157.81,276.81 158.515,276.105 164.789,276.105 167.92,279.235 v7(188.733,279.235)
  L1 w0.2: R866.2@232.957,291.11 v1(232.957,291.871)
  L3 (Sign) w0.12: v7(188.733,279.235) 191.924,279.235 192.411,278.749 193.586,278.749 194.522,277.813 212.448,277.813 212.777,278.142 229.226,278.142 v1(230.016,277.352)
  L16 w0.12: v1(230.016,277.352) 232.957,280.292 v1(232.957,291.871)
NetR867_2: R867.2 SP36.1 | length 1.9
  L1 w0.2: R867.2@235.656,291.11 SP36.1@235.656,293.014
NetR868_2: R868.2 SP37.1 | length 1.9
  L1 w0.2: R868.2@231.607,291.11 SP37.1@231.607,293.014
NetR869_2: R869.2 SP38.1 | length 3.1
  L1 w0.2: R869.2@237.005,291.11 SP38.1@237.005,294.174
NetR870_2: R870.2 SP39.1 | length 3.1
  L1 w0.2: R870.2@234.306,291.11 SP39.1@234.306,294.174
NetR883_2: R883.2 SP40.1 | length 3.1
  L1 w0.2: R883.2@254.549,291.11 SP40.1@254.549,294.174
NetR884_2: R884.2 SP41.1 | length 3.1
  L1 w0.2: R884.2@250.5,291.11 SP41.1@250.5,294.174
NetR885_2: R885.2 SP42.1 | length 3.1
  L1 w0.2: R885.2@257.248,291.11 257.277,291.139 SP42.1@257.277,294.174
NetR886_2: R886.2 SP43.1 | length 1.9
  L1 w0.2: R886.2@258.597,291.11 258.623,291.136 SP43.1@258.623,293.014
NetR887_SPI_bridge_Main_2: R887_SPI_bridge_Main.2 U25_SPI_bridge_Main.8 | length 2
  L1 w0.12: 190.248,252.872 U25_SPI_bridge_Main.8@190.248,254.021 ; 190.248,252.872 190.248,252.363 R887_SPI_bridge_Main.2@190.488,252.123
NetR887_SPI_bridge_PCIe_2: R887_SPI_bridge_PCIe.2 U25_SPI_bridge_PCIe.8 | length 2.2
  L1 w0.12: U25_SPI_bridge_PCIe.8@256.491,253.767 256.491,252.564 256.891,252.164 R887_SPI_bridge_PCIe.2@256.891,251.739
NetR888_SPI_bridge_Main_1: R888_SPI_bridge_Main.1 U26_SPI_bridge_Main.1 | length 2.5
  L1 w0.12: 69.068,331.84 U26_SPI_bridge_Main.1@71.57,331.84
NetR888_SPI_bridge_PCIe_1: R888_SPI_bridge_PCIe.1 U26_SPI_bridge_PCIe.1 | length 2.3
  L1 w0.12: U26_SPI_bridge_PCIe.1@226.89,377.907 226.89,379.096 227.265,379.471 R888_SPI_bridge_PCIe.1@227.265,380.08
NetR889_SPI_bridge_Main_2: R889_SPI_bridge_Main.2 U26_SPI_bridge_Main.7 | length 2.5
  L1 w0.12: R889_SPI_bridge_Main.2@69.204,328.34 69.444,328.1 70.107,328.1 70.267,327.94 U26_SPI_bridge_Main.7@71.57,327.94
NetR889_SPI_bridge_PCIe_2: R889_SPI_bridge_PCIe.2 U26_SPI_bridge_PCIe.7 | length 2.3
  L1 w0.12: U26_SPI_bridge_PCIe.7@222.99,377.907 222.99,379.296 223.24,379.546 R889_SPI_bridge_PCIe.2@223.24,380.08
NetR890_SPI_bridge_Main_1: R890_SPI_bridge_Main.1 U26_SPI_bridge_Main.2 | length 2.5
  L1 w0.12: R890_SPI_bridge_Main.1@69.254,330.703 69.354,330.803 70.267,330.803 70.667,331.203 71.558,331.203 U26_SPI_bridge_Main.2@71.57,331.19
NetR890_SPI_bridge_PCIe_1: R890_SPI_bridge_PCIe.1 U26_SPI_bridge_PCIe.2 | length 2.3
  L1 w0.12: R890_SPI_bridge_PCIe.1@225.92,380.08 225.92,379.546 226.24,379.226 U26_SPI_bridge_PCIe.2@226.24,377.907
NetR891_SPI_bridge_Main_2: R891_SPI_bridge_Main.2 U26_SPI_bridge_Main.8 | length 2.4
  L1 w0.12: R891_SPI_bridge_Main.2@69.204,327.115 70.143,327.115 70.317,327.29 U26_SPI_bridge_Main.8@71.57,327.29
NetR891_SPI_bridge_PCIe_2: R891_SPI_bridge_PCIe.2 U26_SPI_bridge_PCIe.8 | length 2.3
  L1 w0.12: R891_SPI_bridge_PCIe.2@221.965,380.08 221.965,379.546 222.34,379.171 U26_SPI_bridge_PCIe.8@222.34,377.907
NetR892_SPI_bridge_Main_1: R892_SPI_bridge_Main.1 U27_SPI_bridge_Main.1 | length 2.8
  L1 w0.2: U27_SPI_bridge_Main.1@177.908,407.241 178.775,407.241 179.264,406.752 R892_SPI_bridge_Main.1@180.532,406.752
NetR892_SPI_bridge_PCIe_1: R892_SPI_bridge_PCIe.1 U27_SPI_bridge_PCIe.1 | length 2.5
  L1 w0.12: U27_SPI_bridge_PCIe.1@61.863,377.907 61.938,377.982 61.938,379.027 62.238,379.327 R892_SPI_bridge_PCIe.1@62.238,380.232
NetR893_SPI_bridge_Main_2: R893_SPI_bridge_Main.2 U27_SPI_bridge_Main.7 | length 2.7
  L1 w0.4: U27_SPI_bridge_Main.7@177.908,411.141 R893_SPI_bridge_Main.2@180.582,411.141
NetR893_SPI_bridge_PCIe_2: R893_SPI_bridge_PCIe.2 U27_SPI_bridge_PCIe.7 | length 2.4
  L1 w0.12: U27_SPI_bridge_PCIe.7@57.963,377.907 57.963,378.717 58.229,378.983 R893_SPI_bridge_PCIe.2@58.229,380.232
NetR894_SPI_bridge_Main_1: R894_SPI_bridge_Main.1 U27_SPI_bridge_Main.2 | length 2.6
  L1 w0.2: U27_SPI_bridge_Main.2@177.908,407.891 R894_SPI_bridge_Main.1@180.532,407.891
NetR894_SPI_bridge_PCIe_1: R894_SPI_bridge_PCIe.1 U27_SPI_bridge_PCIe.2 | length 2.6
  L1 w0.12: R894_SPI_bridge_PCIe.1@60.563,380.233 60.563,379.512 61.048,379.027 61.048,378.072 U27_SPI_bridge_PCIe.2@61.213,377.907
NetR895_SPI_bridge_Main_2: R895_SPI_bridge_Main.2 U27_SPI_bridge_Main.8 | length 2.8
  L1 w0.4: U27_SPI_bridge_Main.8@177.908,411.791 179,411.791 179.489,412.28 R895_SPI_bridge_Main.2@180.532,412.28
NetR895_SPI_bridge_PCIe_2: R895_SPI_bridge_PCIe.2 U27_SPI_bridge_PCIe.8 | length 2.6
  L1 w0.12: R895_SPI_bridge_PCIe.2@56.733,380.232 56.733,379.012 57.313,378.432 U27_SPI_bridge_PCIe.8@57.313,377.907
NetR896_SPI_bridge_Main_1: R896_SPI_bridge_Main.1 U28_SPI_bridge_Main.1 | length 2.8
  L1 w0.12: U28_SPI_bridge_Main.1@170.769,230.338 172.416,230.338 172.905,229.85 R896_SPI_bridge_Main.1@173.33,229.85
NetR896_SPI_bridge_PCIe_1: R896_SPI_bridge_PCIe.1 U28_SPI_bridge_PCIe.1 | length 1.5
  L1 w0.12: R896_SPI_bridge_PCIe.1@169.964,248.456 169.964,249.17 U28_SPI_bridge_PCIe.1@170.548,249.753
NetR897_SPI_bridge_Main_2: R897_SPI_bridge_Main.2 U28_SPI_bridge_Main.7 | length 2.6
  L1 w0.12: U28_SPI_bridge_Main.7@170.769,234.238 R897_SPI_bridge_Main.2@173.33,234.238
NetR897_SPI_bridge_PCIe_2: R897_SPI_bridge_PCIe.2 U28_SPI_bridge_PCIe.7 | length 2
  L1 w0.12: R897_SPI_bridge_PCIe.2@173.938,248.456 173.938,248.911 174.448,249.421 U28_SPI_bridge_PCIe.7@174.448,250.278
NetR898_SPI_bridge_Main_1: R898_SPI_bridge_Main.1 U28_SPI_bridge_Main.2 | length 2.6
  L1 w0.12: U28_SPI_bridge_Main.2@170.769,230.988 R898_SPI_bridge_Main.1@173.33,230.988
NetR898_SPI_bridge_PCIe_1: R898_SPI_bridge_PCIe.1 U28_SPI_bridge_PCIe.2 | length 2
  L1 w0.12: U28_SPI_bridge_PCIe.2@171.198,250.278 171.198,248.981 R898_SPI_bridge_PCIe.1@171.673,248.506 R898_SPI_bridge_PCIe.1@171.673,248.456
NetR899_SPI_bridge_Main_2: R899_SPI_bridge_Main.2 U28_SPI_bridge_Main.8 | length 2.8
  L1 w0.12: U28_SPI_bridge_Main.8@170.769,234.888 172.791,234.888 R899_SPI_bridge_Main.2@173.28,235.377 R899_SPI_bridge_Main.2@173.33,235.377
NetR899_SPI_bridge_PCIe_2: R899_SPI_bridge_PCIe.2 U28_SPI_bridge_PCIe.8 | length 2.1
  L1 w0.12: U28_SPI_bridge_PCIe.8@175.098,250.278 175.098,249.114 R899_SPI_bridge_PCIe.2@175.706,248.506 R899_SPI_bridge_PCIe.2@175.706,248.456
NetR901_1: R901.1 U1.H14 | length 119.8
  L1 w0.12: U1.H14@169.397,301.539 v1(169.884,301.052) ; R901.1@240.741,363.227 240.741,362.579 v1(241.247,362.073)
  L5 (Sign) w0.12: v1(169.884,301.052) 170.996,302.164 170.996,304.141 172.884,306.03 172.884,308.052 174.372,309.539 176.493,309.539 177.571,310.617 178.17,310.617 178.817,309.97 178.817,309.238 178.954,309.102 183.662,309.102 183.904,309.344 184.343,309.344 184.538,309.539 189.897,309.539 190.313,309.955 193.28,309.955 194.342,311.017 197.936,311.017 198.363,311.444 202.334,311.444 203.86,312.97 203.86,313.761 206.876,316.776 210.96,316.776 220.033,325.849 233.125,325.849 240.778,333.502 240.778,356.113 241.443,356.779 241.443,361.813 241.247,362.01 v1(241.247,362.073)
NetR902_1: R902.1 U1.G14 | length 160.6
  L1 w0.12: v7(75.985,362.736) R902.1@75.985,363.78 ; v2(154.442,296.69) 154.597,296.69 155.745,295.542 157.086,295.542 v2(157.416,295.212) ; U1.G14@168.397,301.539 v2(168.884,301.052)
  L5 (Sign) w0.12: v6(151.837,312.007) 151.837,316.556 v6(151.924,316.643) ; v6@152.459,311.074 v6@152.459,310.933 ; v6(152.465,310.927) v6@152.459,310.933 ; v6(152.693,300.343) 152.693,300.416 152.066,301.043 152.066,303.099 152.48,303.513 152.48,303.852 152.459,303.873 v6@152.459,310.933
  L3 (Sign) w0.12: v7(75.985,362.736) 74.285,361.035 74.285,355.299 v1(76.594,352.99) ; v1(81.133,324.555) 103.131,324.555 103.214,324.639 132.797,324.639 132.799,324.641 133.139,324.641 133.141,324.639 136.447,324.639 142.583,318.503 145.798,318.503 147.658,316.643 v6(151.924,316.643) ; v6@151.837,312.136 v6(151.837,312.007) 151.837,311.555 v6(152.465,310.927) ; v6(152.693,300.343) 152.661,300.311 152.661,298.47 v2(154.442,296.69) ; v2(157.416,295.212) 157.521,295.212 158.285,295.975 158.285,297.989 160.168,299.872 161.397,299.872 167.675,299.872 168.74,300.937 168.769,300.937 v2(168.884,301.052)
  L14 (Sign) w0.12: v1(76.594,352.99) 76.594,353.02 76.664,353.09 78.804,353.09 79.869,352.025 79.869,340.432 82.588,337.713 82.588,331.509 81.133,330.054 v1(81.133,324.555)
NetR916_2: R916.2 R1059.1 T2.1 | length 3.5
  L16 w0.5: T2.1@113.833,162.705 113.833,162.152 114.238,161.747 115.133,161.747 R916.2@115.133,160.229
NetR918_1: R918.1 U1.J14 | length 145
  L1 w0.12: v2(152.516,290.688) 152.703,290.688 153.589,291.574 v2(155.479,291.574) ; U1.J14@170.397,301.539 v1(170.884,301.052)
  L3 (Sign) w0.12: 144.488,281.94 146.242,281.94 148.501,284.199 148.501,285.723 152.583,289.805 152.583,290.517 152.542,290.558 152.542,290.662 v2(152.516,290.688) ; v2(155.479,291.574) 155.443,291.574 155.373,291.644 155.369,291.644 155.369,292.071 155.325,292.115 155.325,292.62 158.505,295.8 158.505,297.587 160.439,299.521 167.71,299.521 168.402,300.214 169.357,300.214 169.549,300.406 170.238,300.406 v1(170.884,301.052)
  L3 (Sign) w0.2: v1(66.561,328.99) 66.626,328.925 69.25,328.925 81.155,317.019 81.155,316.243 87.078,310.32 87.08,310.32 87.695,309.705 87.695,309.703 105.149,292.249 110.305,292.249 119.679,282.876 130.389,282.876 131.335,281.93 144.448,281.93 144.459,281.94 144.488,281.94
  L16 w0.2: v1(66.561,328.99) 66.561,329.73 65.397,330.894 65.397,334.816 66.393,335.812 R918.1@67.43,335.812
NetR918_2: R918.2 U36_Trans_LS_I2C0.8 | length 1.4
  L16 w0.2: U36_Trans_LS_I2C0.8@67.43,333.56 R918.2@67.43,334.912
NetR919_1: R919.1 U1.J16 | length 144
  L1 w0.12: v2(169.909,304.027) U1.J16@170.397,303.539
  L3 (Sign) w0.12: 145.117,282.796 145.479,282.796 148.061,285.378 148.061,286.053 150.874,288.866 150.874,303.109 151.994,304.228 153.708,304.228 154.099,303.837 155.76,303.837 157.349,305.426 161.397,305.426 164.684,305.426 165.59,304.521 168.999,304.521 169.493,304.027 v2(169.909,304.027)
  L3 (Sign) w0.2: v1(67.43,329.731) 68.867,329.731 81.455,317.143 81.455,316.367 87.202,310.62 87.204,310.62 87.995,309.83 87.995,309.828 105.273,292.549 110.429,292.549 119.803,283.176 130.513,283.176 131.335,282.354 141.859,282.354 142.169,282.354 143.812,282.354 144.138,282.68 145.001,282.68 145.117,282.796
  L16 w0.2: R919.1@67.43,328.267 67.38,328.317 67.43,328.367 v1(67.43,329.731)
NetR919_2: R919.2 U36_Trans_LS_I2C1.8 | length 1.4
  L16 w0.2: U36_Trans_LS_I2C1.8@67.43,325.886 R919.2@67.43,327.317
NetR961_2: R961.2
NetR962_2: R962.2
NetR963_2: R963.2
NetR964_2: R964.2
NetR965_2: R965.2
NetR966_2: R966.2
NetR980_2: R980.2 SP44.1 | length 4
  L1 w0.2: R980.2@242.655,311.363 SP44.1@242.655,315.397
NetR981_2: R981.2 SP45.1 | length 4
  L1 w0.2: R981.2@256.128,311.364 SP45.1@256.128,315.397
NetR982_2: R982.2 SP46.1 | length 2.4
  L1 w0.2: R982.2@257.625,311.363 SP46.1@257.625,313.762
NetR983_2: R983.2 SP47.1 | length 4
  L1 w0.2: R983.2@253.134,311.364 SP47.1@253.134,315.397
NetR984_2: R984.2 SP48.1 | length 2.4
  L1 w0.2: R984.2@254.631,311.364 SP48.1@254.631,313.762
NetR985_2: R985.2 SP49.1 | length 2.4
  L1 w0.2: R985.2@251.637,311.363 SP49.1@251.637,313.762
NetR986_2: R986.2 SP50.1 | length 4
  L1 w0.2: R986.2@250.14,311.363 SP50.1@250.14,315.397
NetR987_2: R987.2 SP51.1 | length 2.6
  L1 w0.2: SP51.1@225.282,311.823 227.226,311.823 227.436,311.613 227.486,311.613 R987.2@227.686,311.413 R987.2@227.686,311.363
NetR988_2: R988.2 SP52.1 | length 4.3
  L1 w0.2: SP52.1@228.905,315.59 228.905,315.373 229.183,315.095 R988.2@229.183,311.363
NetR989_2: R989.2 SP53.1 | length 1.6
  L1 w0.2: R989.2@227.69,302.835 SP53.1@227.69,304.482
NetR990_2: R990.2 SP54.1 | length 2.4
  L1 w0.2: R990.2@241.159,311.364 SP54.1@241.159,313.762
NetR991_2: R991.2 SP55.1 | length 2.4
  L1 w0.2: R991.2@245.649,311.363 SP55.1@245.649,313.762
NetR992_2: R992.2 SP56.1 | length 2.4
  L1 w0.2: R992.2@238.165,311.364 SP56.1@238.165,313.762
NetR993_2: R993.2 SP57.1 | length 2.4
  L1 w0.2: R993.2@235.17,311.363 235.172,311.365 SP57.1@235.172,313.762
NetR994_2: R994.2 SP58.1 | length 4
  L1 w0.2: R994.2@236.667,311.363 SP58.1@236.667,315.397
NetR995_2: R995.2 SP59.1 | length 4
  L1 w0.2: R995.2@239.662,311.364 SP59.1@239.662,315.397
NetR996_2: R996.2 SP60.1 | length 4
  L1 w0.2: R996.2@233.674,311.363 SP60.1@233.674,315.397
NetR997_2: R997.2 SP61.1 | length 4
  L1 w0.2: R997.2@230.68,311.364 SP61.1@230.68,315.397
NetR998_2: R998.2 SP62.1 | length 2.4
  L1 w0.2: R998.2@232.177,311.364 SP62.1@232.177,313.762
NetR999_2: R999.2 SP63.1 | length 4
  L1 w0.2: R999.2@247.146,311.363 SP63.1@247.146,315.397
NetR1000_2: R1000.2 SP64.1 | length 2.4
  L1 w0.2: R1000.2@248.643,311.363 SP64.1@248.643,313.762
NetR1004_1: R1004.1 U55.28 | length 3.3
  L1 w0.12: R1004.1@237.471,202.666 237.807,202.666
  L1 w0.2: 237.807,202.666 239.157,204.016 U55.28@240.17,204.016
NetR1004_2: R1004.2 SP66.1 | length 12.9
  L1 w0.2: SP66.1@227.392,197.308 227.392,199.938 230.12,202.666 R1004.2@236.521,202.666
NetR1005_1: R1005.1 U55.29 | length 5.9
  L1 w0.2: R1005.1@235.16,201.769 237.824,201.769 238.341,202.286 238.341,202.578 239.279,203.516 U55.29@240.17,203.516
NetR1005_2: R1005.2 SP67.1 | length 8.2
  L1 w0.2: SP67.1@229.694,197.223 229.694,200.334 231.129,201.769 R1005.2@234.21,201.769
NetR1006_1: R1006.1 U55.30 | length 3.8
  L1 w0.12: R1006.1@237.471,200.787 R1006.1@237.592,200.787
  L1 w0.2: R1006.1@237.592,200.787 238.684,201.879 238.684,202.194 239.505,203.016 U55.30@240.17,203.016
NetR1006_2: R1006.2 SP68.1 | length 7.6
  L1 w0.2: SP68.1@231.911,197.394 231.911,200.032 232.666,200.787 R1006.2@236.521,200.787
NetR1007_1: R1007.1 U55.32 | length 5.9
  L1 w0.2: R1007.1@235.16,199.885 238.039,199.885 U55.32@240.17,202.016
NetR1007_2: R1007.2 SP69.1 | length 2.4
  L1 w0.2: R1007.2@234.21,199.885 234.253,199.843 234.253,197.517 SP69.1@234.295,197.475
NetR1008_1: R1008.1 U55.33 | length 5.8
  L1 w0.2: U55.33@241.97,200.216 241.97,196.354 242.252,196.071 R1008.1@242.252,194.487
NetR1008_2: R1008.2 SP70.1 | length 3.7
  L1 w0.2: SP70.1@239.784,195.158 239.845,195.219 240.838,195.219 241.32,194.737 241.32,193.872 241.656,193.537 R1008.2@242.252,193.537
NetR1009_1: R1009.1 U55.34 | length 8.4
  L1 w0.2: U55.34@242.47,200.216 242.47,196.497 243.154,195.812 R1009.1@243.154,192.101
NetR1009_2: R1009.2 SP71.1 | length 7.1
  L1 w0.2: SP71.1@237.733,195.081 238.941,193.872 240.487,193.872 242.06,192.298 242.06,192.195 243.104,191.151 R1009.2@243.154,191.151
NetR1010_2: R1010.2 SP72.1 | length 7.8
  L1 w0.2: SP72.1@243.849,186.59 243.849,187.875 245.839,189.865 R1010.2@245.839,193.537
NetR1011_2: R1011.2 SP73.1 | length 5
  L1 w0.2: SP73.1@245.745,186.59 245.839,186.684 245.839,188.576 246.729,189.467 R1011.2@246.729,191.151
NetR1012_1: R1012.1 U55.43 | length 6
  L1 w0.2: U55.43@246.97,200.216 246.97,196.946 247.632,196.284 R1012.1@247.632,194.487
NetR1012_2: R1012.2 SP74.1 | length 7
  L1 w0.2: R1012.2@247.632,193.537 247.637,193.532 247.637,186.595 SP74.1@247.641,186.59
NetR1013_1: R1013.1 U55.44 | length 8.5
  L1 w0.2: U55.44@247.47,200.216 247.47,197.348 248.517,196.301 R1013.1@248.517,192.101
NetR1013_2: R1013.2 SP75.1 | length 5
  L1 w0.2: R1013.2@248.517,191.151 248.517,189.597 249.537,188.576 SP75.1@249.537,186.59
NetR1014_1: R1014.1 U55.45 | length 6.3
  L1 w0.2: U55.45@247.97,200.216 247.97,197.667 249.425,196.211 R1014.1@249.425,194.487
NetR1014_2: R1014.2 SP76.1 | length 7.8
  L1 w0.2: R1014.2@249.425,193.537 249.425,189.808 251.433,187.801 SP76.1@251.433,186.59
NetR1015_1: R1015.1 U55.46 | length 8.9
  L1 w0.2: U55.46@248.47,200.216 248.47,197.897 250.304,196.063 R1015.1@250.304,192.101
NetR1015_2: R1015.2 SP77.1 | length 4.4
  L1 w0.2: R1015.2@250.304,191.151 250.37,191.217 254.554,191.217 SP77.1@254.62,191.283
NetR1016_1: R1016.1 U55.53 | length 4.8
  L1 w0.2: U55.53@251.27,204.016 252.615,204.016 253.454,203.177 253.454,202.19 253.571,202.073 R1016.1@254.693,202.073
NetR1016_2: R1016.2 SP78.1 | length 4.3
  L1 w0.2: R1016.2@255.643,202.073 258.971,202.073 SP78.1@259.627,202.728
NetR1017_1: R1017.1 U55.54 | length 4.2
  L1 w0.2: U55.54@251.27,204.516 252.539,204.516 253.907,203.148 R1017.1@254.627,203.148 254.894,203.148
NetR1017_2: R1017.2 SP79.1 | length 6.4
  L1 w0.2: R1017.2@255.627,203.148 257.915,203.148 258.662,203.895 SP79.1@261.708,203.895
NetR1018_1: R1018.1 U55.55 | length 3.8
  L1 w0.2: U55.55@251.27,205.016 252.691,205.016 253.502,204.205 R1018.1@254.693,204.205
NetR1018_2: R1018.2 SP80.1 | length 4.5
  L1 w0.2: R1018.2@255.643,204.145 257.045,204.145 258.137,205.237 SP80.1@259.673,205.237
NetR1019_1: R1019.1 U55.57 | length 3.5
  L1 w0.2: U55.57@251.27,206.016 254.508,206.016 R1019.1@254.663,206.17
NetR1019_2: R1019.2 SP81.1 | length 6
  L1 w0.2: R1019.2@255.627,206.177 255.66,206.144 261.585,206.144 SP81.1@261.618,206.111
NetR1020_1: R1020.1 U55.58 | length 3.7
  L1 w0.2: U55.58@251.27,206.516 253.123,206.516 253.91,207.303 R1020.1@254.643,207.303
NetR1020_2: R1020.2 SP82.1 | length 4.1
  L1 w0.2: R1020.2@255.643,207.303 255.646,207.305 259.748,207.305 SP82.1@259.75,207.308
NetR1021_1: R1021.1 U55.59 | length 4.2
  L1 w0.2: U55.59@251.27,207.016 252.938,207.016 254.324,208.402 R1021.1@254.846,208.402
NetR1021_2: R1021.2 SP83.1 | length 6
  L1 w0.2: R1021.2@255.643,208.402 257.331,208.402 257.599,208.134 SP83.1@261.544,208.134
NetR1022_1: R1022.1 SP84.1 | length 1.8
  L1 w0.2: SP84.1@226.486,218.626 226.568,218.708 228.141,218.708 R1022.1@228.223,218.79
NetR1022_2: R1022.2 U79.5 | length 7.6
  L1 w0.2: R1022.2@228.223,219.74 228.223,221.267 229.048,222.092 U79.5@229.048,227.025
NetR1023_1: R1023.1 U79.12 | length 2.7
  L1 w0.2: R1023.1@228.723,235.397 228.723,234.411 229.048,234.086 U79.12@229.048,232.825
NetR1023_2: R1023.2 SP85.1 | length 6.4
  L1 w0.2: R1023.2@228.723,236.347 228.723,238.718 230.307,240.302 SP85.1@232.068,240.302
NetR1024_1: R1024.1 SP86.1 | length 2.1
  L1 w0.2: R1024.1@229.223,218.79 229.273,218.79 229.703,218.359 SP86.1@231.172,218.359
NetR1024_2: R1024.2 U79.6 | length 7.5
  L1 w0.2: R1024.2@229.223,219.74 229.223,221.756 229.71,222.243 229.71,227.013 U79.6@229.698,227.025
NetR1025_1: R1025.1 U79.11 | length 2.7
  L1 w0.2: U79.11@229.698,232.825 229.698,234.086 230.01,234.398 R1025.1@230.01,235.401
NetR1025_2: R1025.2 SP87.1 | length 2.6
  L1 w0.2: R1025.2@230.01,236.351 230.06,236.351 231.316,237.607 232.094,237.607 SP87.1@232.116,237.63
NetR1026_1: R1026.1 U53.14 | length 4.1
  L1 w0.12: U53.14@217.924,205.683 219.072,205.683 220.372,206.983 R1026.1@221.513,206.983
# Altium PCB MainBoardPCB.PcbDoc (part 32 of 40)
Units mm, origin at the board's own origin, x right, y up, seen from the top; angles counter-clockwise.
Board outline 258.95 x 308.86 mm, 16 copper layers (L1, L2 (GND), L3 (Sign), L4 (GND), L5 (Sign), L6 (PWR/GND), L7(12V+Other), L8 (Plane_GND), L9 (PWR/GND), L10 (3V3+Other), L11 (PWR/GND), L12 (Sign), L13 (GND), L14 (Sign), L15 (GND), L16), stack 2.503 mm thick; 2578 components, 1867 nets, 8817 pads, 8021 vias.
Unrouted connection lines stored in the file: 25.

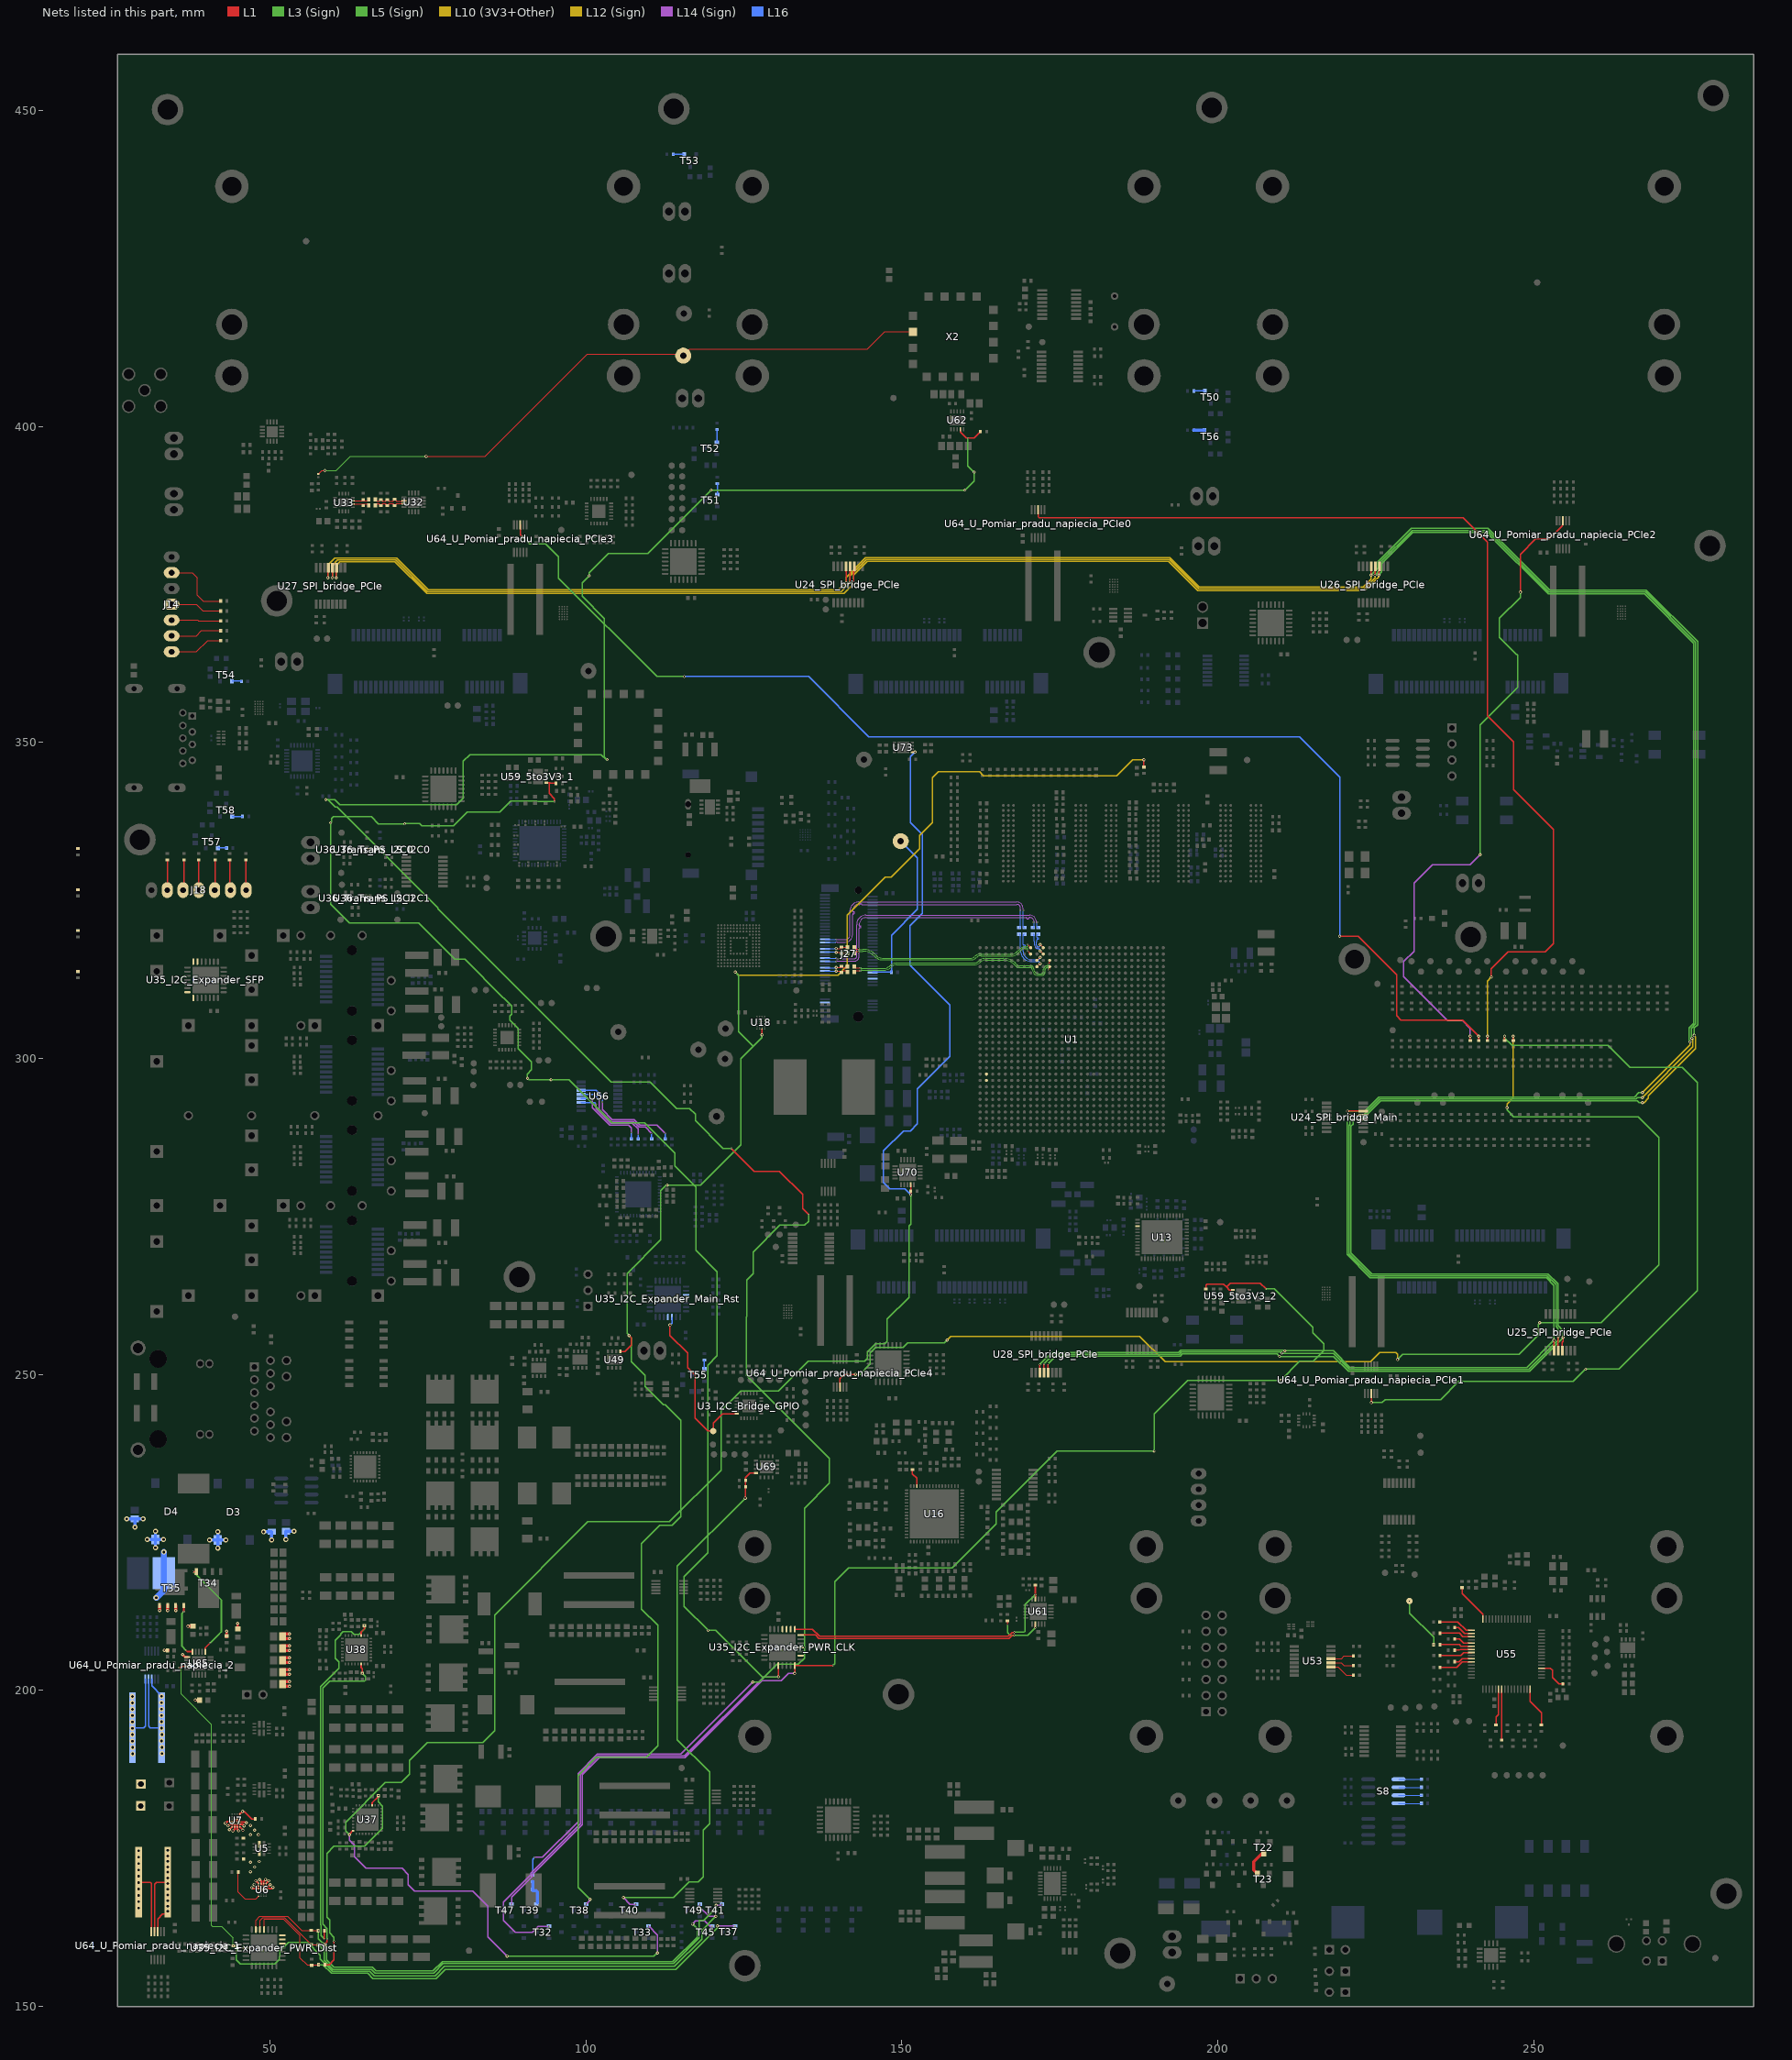
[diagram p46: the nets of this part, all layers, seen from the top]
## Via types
v1: diameter 0.5, hole 0.25, L1 to L16, tented both sides, 4341 vias
v2: diameter 0.254, hole 0.1, L1 to L3 (Sign), tented both sides, 781 vias
v3: diameter 0.5, hole 0.25, L1 to L16, 565 vias
v4: diameter 0.254, hole 0.1, L15 (GND) to L16, tented both sides, 406 vias
v5: diameter 0.254, hole 0.1, L1 to L2 (GND), tented both sides, 283 vias
v6: diameter 0.457, hole 0.2, L3 (Sign) to L6 (PWR/GND), tented both sides, 254 vias
v7: diameter 0.254, hole 0.1, L1 to L3 (Sign), 237 vias
v8: diameter 0.75, hole 0.4, L1 to L16, 200 vias
v9: diameter 0.8, hole 0.4, L1 to L16, tented both sides, 182 vias
v10: diameter 0.254, hole 0.1, L14 (Sign) to L16, tented both sides, 170 vias
v11: diameter 0.75/0/0/0/0/0/0/0/0/0/0/0/0/0/0/0.75 (per signal layer), hole 0.4, L1 to L16, 160 vias
v12: diameter 0.457, hole 0.2, L3 (Sign) to L6 (PWR/GND), 158 vias
v13: diameter 1.4, hole 0.5, L1 to L16, tented both sides, 80 vias
v14: diameter 0.254, hole 0.1, L14 (Sign) to L16, 65 vias
v15: diameter 0.254, hole 0.1, L1 to L2 (GND), 45 vias
v16: diameter 0.457, hole 0.2, L11 (PWR/GND) to L14 (Sign), tented both sides, 26 vias
v17: diameter 0.457, hole 0.2, L11 (PWR/GND) to L14 (Sign), 25 vias
v18: diameter 0.457, hole 0.2, L7(12V+Other) to L10 (3V3+Other), tented both sides, 11 vias
v19: diameter 0.254/0/0.254 (per signal layer), hole 0.1, L1 to L3 (Sign), 9 vias
v20: diameter 0.2/0/0.2 (per signal layer), hole 0.1, L1 to L3 (Sign), 6 vias
v21: diameter 1.65, hole 1.65, L1 to L16, 5 vias
v22: diameter 1.15, hole 1.15, L1 to L16, 5 vias
v23: diameter 0.457, hole 0.2, L1 to L16, 3 vias
v24: diameter 0.5, hole 0.3, L1 to L16, 2 vias
v25: diameter 0.5/0/0.5 (per signal layer), hole 0.2, L14 (Sign) to L16, 1 vias
v26: diameter 0.5, hole 0.25, L1 to L16, tented bottom, 1 vias

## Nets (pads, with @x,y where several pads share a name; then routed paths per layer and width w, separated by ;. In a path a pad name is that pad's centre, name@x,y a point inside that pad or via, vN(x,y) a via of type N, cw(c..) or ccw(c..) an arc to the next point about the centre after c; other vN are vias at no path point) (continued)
NetR1027_1: R1027.1 U53.13 | length 3.8
  L1 w0.12: U53.13@217.924,205.033 219.594,205.033 220.028,205.466 R1027.1@221.513,205.466
NetR1028_1: R1028.1 U53.12 | length 3.8
  L1 w0.12: U53.12@217.924,204.383 219.591,204.383 220.024,203.95 R1028.1@221.513,203.95
NetR1029_1: R1029.1 U53.11 | length 4.1
  L1 w0.12: U53.11@217.924,203.733 219.034,203.733 220.334,202.433 R1029.1@221.513,202.433
NetR1030_1: R1030.1 U55.16 | length 6.4
  L1 w0.2: R1030.1@238.684,216.326 238.692,216.319 238.692,215.346 241.97,212.068 U55.16@241.97,211.316
NetR1031_1: R1031.1 U55.17 | length 5.6
  L1 w0.2: R1031.1@235.097,210.844 237.999,210.844 239.328,209.516 U55.17@240.17,209.516
NetR1032_1: R1032.1 U55.18 | length 3.1
  L1 w0.2: R1032.1@237.433,209.955 238.113,209.955 239.053,209.016 U55.18@240.17,209.016
NetR1033_1: R1033.1 U55.19 | length 5.3
  L1 w0.2: R1033.1@235.122,209.066 238.24,209.066 238.791,208.516 U55.19@240.17,208.516
NetR1034_1: R1034.1 U55.21 | length 3
  L1 w0.2: R1034.1@237.459,208.152 238.275,208.152 238.911,207.516 U55.21@240.17,207.516
NetR1035_1: R1035.1 U55.22 | length 5.1
  L1 w0.2: R1035.1@235.135,207.263 238.266,207.263 238.513,207.016 U55.22@240.17,207.016
NetR1035_2: R1035.2 SP65.1 | length 8.5
  L1 w0.2: v7(234.172,207.263) R1035.2@234.185,207.263
  L3 (Sign) w0.2: v7(230.348,214.156) 230.348,212.236 234.172,208.412 v7(234.172,207.263)
NetR1036_1: R1036.1 U55.23 | length 2.8
  L1 w0.2: R1036.1@237.471,206.387 238.289,206.387 238.418,206.516 U55.23@240.17,206.516
NetR1037_1: R1037.1 U55.24 | length 5.2
  L1 w0.2: R1037.1@235.16,205.536 238.454,205.536 238.934,206.016 U55.24@240.17,206.016
NetR1038_1: R1038.1 U55.26 | length 2.9
  L1 w0.2: R1038.1@237.471,204.545 238.226,204.545 238.696,205.016 U55.26@240.17,205.016
NetR1039_1: R1039.1 U55.27 | length 5.4
  L1 w0.2: R1039.1@235.16,203.652 237.828,203.652 238.692,204.516 U55.27@240.17,204.516
NetR1040_2: R1040.2 U56.14 | length 18.3
  L14 (Sign) w0.2: v10(102.629,293.116) 102.629,291.909 104.167,290.371 107.619,290.371 108.545,289.446 111.29,289.446 v10(112.56,288.176)
  L16 w0.2: U56.14@99.259,294.98 101.624,294.98 102.629,293.975 v10(102.629,293.116) ; v10(112.56,288.176) 112.563,288.172 R1040.2@112.563,287.237
NetR1041_2: R1041.2 U56.13 | length 15.6
  L14 (Sign) w0.2: v10(102.159,293.505) 102.159,291.955 104.042,290.071 107.495,290.071 108.42,289.146 109.439,289.146 110.422,288.163 v10(110.401,288.163)
  L16 w0.2: U56.13@99.259,294.33 101.334,294.33 v10(102.159,293.505) ; v10(110.401,288.163) 110.401,287.259 R1041.2@110.424,287.237
NetR1042_2: R1042.2 U56.12 | length 12.6
  L14 (Sign) w0.2: v10(101.041,293.7) 101.041,292.224 103.794,289.471 106.782,289.471 107.214,289.038 v10(107.214,288.28)
  L16 w0.2: U56.12@99.259,293.68 101.063,293.68 101.083,293.7 v10(101.041,293.7) ; R1042.2@107.214,287.237 v10(107.214,288.28)
NetR1043_2: R1043.2 U56.11 | length 12.8
  L14 (Sign) w0.2: v10(101.638,292.811) 101.638,292.051 103.918,289.771 107.371,289.771 108.28,288.861 v10(108.28,287.998)
  L16 w0.2: U56.11@99.259,293.03 101.419,293.03 v10(101.638,292.811) v10@101.638,292.798 ; v10(108.28,287.998) 108.284,287.994 R1043.2@108.284,287.237
NetR1044_1: R1044.1 U55.38 | length 5.9
  L1 w0.2: R1044.1@244.046,194.487 244.046,195.793 244.47,196.217 U55.38@244.47,200.216
NetR1045_1: R1045.1 U55.39 | length 8.1
  L1 w0.12: R1045.1@244.942,192.101 R1045.1@244.97,192.129
  L1 w0.2: R1045.1@244.97,192.129 U55.39@244.97,200.216
NetR1046_1: R1046.1 U55.48 | length 6.5
  L1 w0.2: U55.48@249.47,200.216 249.47,198.264 251.219,196.515 R1046.1@251.219,194.487
NetR1047_1: R1047.1 U55.52 | length 5.3
  L1 w0.2: U55.52@251.27,203.516 252.658,203.516 252.961,203.213 252.961,202.078 254.002,201.037 R1047.1@254.643,201.037 254.884,201.037
NetR1048_2: R1048.2 S8.8 | length 3.7
  L16 w0.12: S8.8@228.629,182.148 R1048.2@232.307,182.148
NetR1049_2: R1049.2 S8.7 | length 3.7
  L16 w0.12: S8.7@228.629,183.418 R1049.2@232.307,183.418
NetR1050_2: R1050.2 S8.6 | length 3.7
  L16 w0.12: S8.6@228.629,184.688 R1050.2@232.307,184.688
NetR1051_2: R1051.2 S8.5 | length 3.7
  L16 w0.12: S8.5@228.629,185.958 R1051.2@232.257,185.958 R1051.2@232.307,185.958
NetR1052_1: R1052.1 U6.A4 | length 7
  L1 w0.12: R1052.1@44.945,171.26 44.945,168.15 46.08,167.016 47.766,167.016 U6.A4@48.206,167.456
NetR1053_1: R1053.1 U7.A4 | length 3.2
  L1 w0.2: v1(45.668,180.874) 45.714,180.828 46,180.828 47.148,179.68 R1053.1@47.766,179.68
  L1 w0.3: U7.A4@45.228,180.434 v1(45.668,180.874)
NetR1082_2: R1082.2 R1089.1 T39.1 | length 4
  L16 w0.5: R1082.2@91.594,169.815 91.64,169.77 91.64,168.488 91.59,168.438 91.59,168.388 91.64,168.338 92.099,168.338 92.31,168.126 T39.1@92.31,166.415
NetR1095_1: R1095.1 T50.1 | length 1.8
  L16 w0.2: R1095.1@196.164,405.644 T50.1@197.97,405.644
NetR1099_1: R1099.1 T51.1 | length 1.8
  L16 w0.2: T51.1@120.821,389.244 R1099.1@120.821,391.05
NetR1107_1: R1107.1 T52.1 | length 2.1
  L16 w0.2: T52.1@120.739,397.495 120.767,397.523 R1107.1@120.767,399.595
NetR1111_1: R1111.1 T53.1 | length 1.8
  L16 w0.2: R1111.1@113.764,443.088 T53.1@115.57,443.088
NetR1113_1: R1113.1 T54.1 | length 1.6
  L16 w0.2: T54.1@44.003,359.732 45.498,359.732 R1113.1@45.542,359.688
NetR1115_1: R1115.1 T55.1 | length 1.5
  L16 w0.2: T55.1@118.762,250.878 R1115.1@118.762,252.354
NetR1117_1: R1117.1 T56.1 | length 1.8
  L16 w0.5: R1117.1@196.164,399.412 T56.1@197.92,399.412
NetR1119_1: R1119.1 T57.1 | length 1.4
  L16 w0.2: T57.1@41.771,333.313 R1119.1@43.208,333.313
NetR1121_1: R1121.1 T58.1 | length 1.7
  L16 w0.2: T58.1@44.028,338.307 R1121.1@45.722,338.307
NetR1122_Trans_LS_I2C0_2: R1122_Trans_LS_I2C0.2 U36_Trans_LS_I2C0.7
NetR1122_Trans_LS_I2C1_2: R1122_Trans_LS_I2C1.2 U36_Trans_LS_I2C1.7
NetR1122_Trans_PS_I2C0_2: R1122_Trans_PS_I2C0.2 U36_Trans_PS_I2C0.7
NetR1122_Trans_PS_I2C1_2: R1122_Trans_PS_I2C1.2 U36_Trans_PS_I2C1.7
NetSP12_I2C_Bridge_GPIO_1: SP12_I2C_Bridge_GPIO.1 U3_I2C_Bridge_GPIO.24 U35_I2C_Expander_Main_Rst.3 | length 27.1
  L1 w0.2: v1(113.322,257.81) 113.322,256.184 116.091,253.416 116.091,251.115 117.278,249.928 117.278,243.12 119.344,241.054 SP12_I2C_Bridge_GPIO.1@120.157,241.054 120.157,242.292 121.654,243.789 U3_I2C_Bridge_GPIO.24@123.878,243.789
  L16 w0.2: v1(113.322,257.81) 113.648,258.136 U35_I2C_Expander_Main_Rst.3@113.648,259.093
NetT22_3: T22.3 T23.2 | length 4.3
  L1 w0.5: T23.2@206.289,171.002 205.715,171.576 205.715,172.923 207.028,174.236 T22.3@207.327,174.236
NetT34_4: T34.4 U65.11 | length 16.1
  L1 w0.254: v2(37.846,218.796) 37.85,218.791 T34.4@38.377,218.791 ; U65.11@39.76,206.158 39.76,206.746 v2@40.514,207.5
  L3 (Sign) w0.254: v2(37.846,218.796) 42.329,214.312 42.329,209.291 41.754,208.716 v2(40.526,207.488)
NetT35_4: T35.4 U65.15 | length 8.6
  L1 w0.254: v2(36.36,212.471) T35.4@36.36,213.464 ; v2(36.71,206.368) 36.92,206.158 U65.15@37.76,206.158
  L3 (Sign) w0.254: v2(36.36,212.471) 36.093,212.204 36.093,206.985 v2(36.71,206.368)
NetU1_B9: U1.B9
NetU1_B10: U1.B10
NetU13_43: U13.43
NetU24_SPI_bridge_PCIe_3: U24_SPI_bridge_Main.14 U24_SPI_bridge_PCIe.3 U25_SPI_bridge_PCIe.3 U26_SPI_bridge_PCIe.3 U27_SPI_bridge_PCIe.3 U28_SPI_bridge_PCIe.3 | length 521.1
  L1 w0.2: v1(60.49,376.072) 60.49,377.616 U27_SPI_bridge_PCIe.3@60.563,377.69 ; v1(142.405,375.31) 142.405,376.981 142.482,377.057 U24_SPI_bridge_PCIe.3@142.482,377.907 ; U28_SPI_bridge_PCIe.3@171.848,250.278 v2(171.848,251.576) ; v1(220.548,291.681) 223.004,291.681 U24_SPI_bridge_Main.14@223.032,291.652 ; v1(225.488,376.504) 225.488,376.956 225.59,377.057 U26_SPI_bridge_PCIe.3@225.59,377.907 ; U25_SPI_bridge_PCIe.3@253.241,253.767 v1(253.241,255.422)
  L5 (Sign) w0.2: v6(210.629,253.764) 218.303,253.764 220.966,251.101 248.92,251.101 v1(253.241,255.422) 253.241,264.114 252.03,265.325 224.146,265.325 220.492,268.978 220.492,291.625 v1(220.548,291.681)
  L12 (Sign) w0.2: v1(60.49,376.072) 60.49,377.991 61.106,378.608 69.799,378.608 74.822,373.585 140.835,373.585 142.405,375.155 v1(142.405,375.31) 142.405,376.529 144.528,378.652 192.197,378.652 196.839,374.01 223.277,374.01 225.488,376.222 v1(225.488,376.504) ; v1(267.195,294.598) 274.759,302.161 v1(274.759,302.63)
  L3 (Sign) w0.2: v2(171.848,251.576) 173.797,253.526 193.829,253.526 194.148,253.844 210.55,253.844 v6(210.629,253.764) ; v1(220.548,291.681) 223.298,291.681 225.532,293.914 265.952,293.914 266.636,294.598 v1(267.195,294.598) ; v1(225.488,376.504) 225.965,376.981 225.965,378.332 230.906,383.273 242.55,383.273 252.323,373.5 267.559,373.5 275.353,365.706 275.353,305.597 274.594,304.838 274.594,302.795 v1(274.759,302.63)
NetU24_SPI_bridge_PCIe_4: U24_SPI_bridge_Main.13 U24_SPI_bridge_PCIe.4 U25_SPI_bridge_PCIe.4 U26_SPI_bridge_PCIe.4 U27_SPI_bridge_PCIe.4 U28_SPI_bridge_PCIe.4 | length 522.4
  L1 w0.2: v1(59.878,376.077) 59.878,377.655 U27_SPI_bridge_PCIe.4@59.913,377.69 ; v1(141.805,375.31) 141.805,377.031 141.832,377.057 U24_SPI_bridge_PCIe.4@141.832,377.907 ; U28_SPI_bridge_PCIe.4@172.498,250.278 172.498,250.906 172.509,250.894 v2(172.509,251.689) ; v1(220.985,291.02) 220.995,291.011 223.023,291.011 U24_SPI_bridge_Main.13@223.032,291.002 ; v1@224.889,376.504 224.889,377.006 224.94,377.057 U26_SPI_bridge_PCIe.4@224.94,377.907 ; U25_SPI_bridge_PCIe.4@253.891,253.767 253.891,256.012 v1(253.898,256.019)
  L5 (Sign) w0.2: v6(210.157,253.394) 210.169,253.394 210.248,253.314 218.328,253.314 220.841,250.801 249.256,250.801 253.898,255.443 v1(253.898,256.019) 253.898,257.266 253.541,257.624 253.541,264.238 252.154,265.625 224.27,265.625 220.792,269.103 220.792,289.421 220.967,289.596 220.967,291.002 v1(220.985,291.02)
  L12 (Sign) w0.2: v1(59.878,376.077) 59.878,378.043 60.742,378.908 69.948,378.908 74.953,373.902 75.031,373.902 75.048,373.885 140.416,373.885 141.805,375.274 141.805,376.353 144.404,378.952 192.322,378.952 196.964,374.31 223.152,374.31 224.889,376.046 v1(224.889,376.468) ; v1(267.195,293.834) 275.209,301.848 275.209,303.035 v1(275.044,303.2)
  L3 (Sign) w0.2: v2(172.509,251.689) 174.046,253.226 193.954,253.226 194.272,253.544 210.007,253.544 v6(210.157,253.394) ; v1(220.985,291.02) 223.062,291.02 225.656,293.614 266.18,293.614 266.4,293.834 v1(267.195,293.834) ; v1(224.889,376.468) 224.889,376.541 225.665,377.317 225.665,378.456 230.782,383.573 242.674,383.573 252.448,373.8 267.684,373.8 275.653,365.83 275.653,305.473 274.985,304.805 274.985,303.259 v1(275.044,303.2)
NetU24_SPI_bridge_PCIe_5: U24_SPI_bridge_Main.12 U24_SPI_bridge_PCIe.5 U25_SPI_bridge_PCIe.5 U26_SPI_bridge_PCIe.5 U27_SPI_bridge_PCIe.5 U28_SPI_bridge_PCIe.5 | length 523.4
  L1 w0.2: v1(59.164,376.077) 59.164,377.59 U27_SPI_bridge_PCIe.5@59.263,377.69 ; U24_SPI_bridge_PCIe.5@141.182,377.907 141.182,377.057 141.205,377.034 v1(141.205,375.31) ; v2(173.131,251.689) 173.131,250.85 173.148,250.834 U28_SPI_bridge_PCIe.5@173.148,250.278 ; v1(221.437,290.322) 223.002,290.322 U24_SPI_bridge_Main.12@223.032,290.352 ; v1(224.289,376.504) 224.29,376.506 U26_SPI_bridge_PCIe.5@224.29,377.907 ; U25_SPI_bridge_PCIe.5@254.541,253.767 254.541,255.112 254.66,255.232 v1(254.66,255.88)
  L5 (Sign) w0.2: v6(209.781,252.872) 218.346,252.872 220.717,250.501 249.38,250.501 254.66,255.781 v1(254.66,255.88) 254.66,256.929 253.841,257.748 253.841,264.362 252.279,265.925 224.395,265.925 221.092,269.227 221.092,289.297 221.437,289.641 v1(221.437,290.322)
  L12 (Sign) w0.2: v1(59.164,376.077) 59.164,378.117 60.254,379.208 70.097,379.208 75.085,374.22 75.137,374.22 75.172,374.185 140.01,374.185 141.135,375.31 v1(141.205,375.31) ; v1@141.205,375.274 141.205,376.178 144.28,379.252 192.446,379.252 197.088,374.61 223.028,374.61 224.289,375.871 v1(224.289,376.504) ; v1(267.201,293.04) 267.232,293.008 267.469,293.008 268.178,293.718 268.178,294.139 275.621,301.582 275.621,303.393 275.438,303.576 v1(275.438,303.657)
  L3 (Sign) w0.2: v2(173.131,251.689) 174.369,252.926 194.078,252.926 194.396,253.244 209.383,253.244 209.755,252.872 v6(209.781,252.872) ; v1(221.437,290.322) 222.788,290.322 225.781,293.314 266.4,293.314 266.706,293.008 267.169,293.008 v1(267.201,293.04) ; v1(224.289,376.504) 225.365,377.581 225.365,378.58 230.658,383.873 242.798,383.873 252.572,374.1 267.808,374.1 275.953,365.954 275.953,305.349 275.438,304.833 v1(275.438,303.657)
NetU35_I2C_Expander_Main_Rst_4: U35_I2C_Expander_Main_Rst.4
NetU35_I2C_Expander_Main_Rst_24: U35_I2C_Expander_Main_Rst.24
NetU35_I2C_Expander_PWR_CLK_2: U35_I2C_Expander_PWR_CLK.2
NetU35_I2C_Expander_PWR_CLK_3: U35_I2C_Expander_PWR_CLK.3
NetU35_I2C_Expander_PWR_CLK_4: U35_I2C_Expander_PWR_CLK.4
NetU35_I2C_Expander_PWR_Dist_19: U35_I2C_Expander_PWR_Dist.19
NetU35_I2C_Expander_PWR_Dist_20: U35_I2C_Expander_PWR_Dist.20
NetU35_I2C_Expander_PWR_Dist_21: U35_I2C_Expander_PWR_Dist.21
NetU35_I2C_Expander_SFP_1: U35_I2C_Expander_SFP.1
NetU35_I2C_Expander_SFP_20: U35_I2C_Expander_SFP.20
NetU35_I2C_Expander_SFP_21: U35_I2C_Expander_SFP.21
NetU35_I2C_Expander_SFP_28: U35_I2C_Expander_SFP.28
NVME_C_RX_1_N: C718.1 U1.K28 | length 7.7
  L1 w0.09: U1.K28@171.397,315.539 v1(171.884,316.027)
  L16 w0.09: 169.197,318.539 169.197,318.482 169.197,318.059 ccw(c169.306,318.059) 169.306,317.95 169.441,317.95 cw(c169.441,317.841) 169.55,317.841 169.55,317.817 cw(c169.441,317.817) 169.441,317.708 169.306,317.708 ccw(c169.306,317.599) 169.197,317.599 169.197,317.312 169.197,316.985 ccw(c170.51,316.985) 170.51,315.672 171.529,315.672 ccw(c171.529,316.027) v1(171.884,316.027)
  L16 w0.101: 169.197,318.539 169.197,319.41 cw(c169.451,319.41) C718.1@169.451,319.664
NVME_C_RX_1_P: C717.1 U1.K27 | length 7.7
  L1 w0.09: U1.K27@171.397,314.539 v1(171.884,315.027)
  L16 w0.09: 168.796,318.539 168.796,317.096 ccw(c170.51,317.096) 170.51,315.382 171.529,315.382 cw(c171.529,315.027) v1(171.884,315.027)
  L16 w0.101: C717.1@168.542,319.664 cw(c168.542,319.41) 168.796,319.41 168.796,318.539
NVME_C_RX_O_N: C677.1 U1.M28 | length 34.1
  L1 w0.1: v2(173.177,314.994) 173.207,314.994 173.395,315.182 173.395,315.537 U1.M28@173.397,315.539
  L1 w0.101: C677.1@142.469,314.574 142.469,314.549 142.694,314.324 143.437,314.324 v2(143.446,314.334)
  L3 (Sign) w0.081: v2(143.446,314.334) cw(c143.446,314.22) 143.526,314.3 ccw(c143.651,314.424) 143.651,314.249 147.022,314.249 ccw(c147.022,315.892) 148.183,314.73 148.192,314.739 cw(c149.106,313.825) 149.106,315.117 161.517,315.117 ccw(c161.517,315.998) 162.14,315.375 ; 162.14,315.376 cw(c163.253,314.264) 163.253,315.837 166.089,315.837 cw(c166.089,313.017) 168.083,315.011 168.228,314.867 ccw(c168.616,315.255) 168.616,314.706 170.388,314.706 cw(c170.388,314.223) 170.871,314.223 ccw(c171.657,314.223) 171.657,313.437 172.158,313.437 ccw(c172.158,313.721) 172.442,313.721 172.442,314.115 cw(c172.996,314.115) 172.996,314.668 ccw(c172.996,314.849) 173.177,314.849 v2(173.177,314.994)
NVME_C_RX_O_P: C653.1 U1.M27 | length 34.1
  L1 w0.1: v2(173.219,314.062) 173.246,314.062 173.395,314.211 U1.M27@173.397,314.539 U1.M27@173.397,314.539
  L1 w0.101: C653.1@142.469,313.674 142.469,313.699 142.694,313.923 143.407,313.923 v2(143.446,313.884)
  L3 (Sign) w0.081: v2(143.446,313.884) ccw(c143.446,313.997) 143.526,313.917 cw(c143.651,313.793) 143.651,313.968 147.138,313.968 ccw(c147.138,315.611) 148.3,314.449 148.39,314.539 cw(c149.107,313.822) 149.107,314.836 161.518,314.836 ccw(c161.518,315.995) 162.337,315.176 ; 162.338,315.177 cw(c163.254,314.261) 163.254,315.556 166.089,315.556 cw(c166.089,313.016) 167.885,314.812 168.03,314.667 ccw(c168.614,315.251) 168.614,314.425 170.388,314.425 cw(c170.388,314.223) 170.59,314.223 ccw(c171.657,314.223) 171.657,313.156 172.158,313.156 ccw(c172.158,313.721) 172.723,313.721 172.723,314.115 cw(c172.996,314.115) 172.996,314.387 cw(c172.996,314.164) 173.219,314.164 v2(173.219,314.062)
NVME_C_TX_1_N: C716.1 U1.J30 | length 29.6
  L1 w0.1: v2(169.909,318.027) U1.J30@170.397,317.539
  L1 w0.101: C716.1@142.469,317.575 142.469,317.55 142.694,317.325 143.022,317.325 143.112,317.415 v2(143.18,317.415)
  L3 (Sign) w0.081: v2(143.18,317.415) ccw(c143.33,317.415) 143.33,317.265 143.848,317.265 cw(c143.848,314.446) 145.842,316.439 145.976,316.305 ccw(c146.945,317.274) 146.945,315.904 161.019,315.904 ccw(c161.019,316.662) 161.554,316.126 161.556,316.128 cw(c162.539,315.145) 162.539,316.535 167.442,316.535 ccw(c167.442,317.625) 168.213,316.854 168.693,317.335 cw(c169.495,316.533) 169.495,317.667 169.828,317.667 ccw(c169.828,317.748) 169.886,317.691 ccw(c169.828,317.748) 169.909,317.748 v2(169.909,318.027)
NVME_C_TX_1_P: C715.1 U1.J29 | length 29.6
  L1 w0.1: v2(169.909,317.027) U1.J29@170.397,316.539
  L1 w0.101: C715.1@142.469,316.674 142.469,316.7 142.694,316.924 143.022,316.924 143.112,316.834 v2(143.18,316.834)
  L3 (Sign) w0.081: v2(143.18,316.834) cw(c143.33,316.834) 143.33,316.984 143.848,316.984 cw(c143.848,314.444) 145.644,316.24 145.78,316.104 ccw(c146.941,317.266) 146.941,315.623 161.02,315.623 ccw(c161.02,316.659) 161.752,315.926 ; 161.753,315.927 cw(c162.542,315.138) 162.542,316.254 167.443,316.254 ccw(c167.443,317.623) 168.411,316.655 168.891,317.135 cw(c169.497,316.529) 169.497,317.386 169.828,317.386 cw(c169.828,317.305) 169.886,317.363 cw(c169.828,317.305) 169.909,317.305 v2(169.909,317.027)
NVME_C_TX_O_N: C651.1 U1.L30 | length 4
  L1 w0.1: v1(171.909,318.027) U1.L30@172.397,317.539
  L16 w0.09: 171.38,318.528 ccw(c171.38,318.476) 171.328,318.476 171.328,317.977 ccw(c171.633,317.977) 171.633,317.672 ccw(c171.633,317.948) 171.909,317.948 v1(171.909,318.027)
  L16 w0.101: 171.381,318.539 171.381,318.542 171.381,318.795 cw(c171.482,318.795) 171.482,318.896 171.614,318.896 ccw(c171.614,318.997) 171.614,319.099 171.482,319.099 cw(c171.482,319.2) 171.381,319.2 171.381,319.394 171.381,319.41 cw(c171.635,319.41) C651.1@171.635,319.664
NVME_C_TX_O_P: C649.1 U1.L29 | length 4
  L1 w0.1: v1(171.909,317.027) U1.L29@172.397,316.539
  L16 w0.09: 171.038,318.539 171.038,317.977 ccw(c171.633,317.977) 171.633,317.382 cw(c171.633,317.106) 171.909,317.106 v1(171.909,317.027)
  L16 w0.101: C649.1@170.726,319.664 cw(c170.726,319.41) 170.98,319.41 170.98,318.539 171.038,318.539
NVMe_Rx_0_N: C677.2 J27.47 R541.2 | length 4.1
  L1 w0.101: v1(139.624,314.424) 140.462,314.424 R541.2@140.462,314.624 140.512,314.624 140.687,314.449 140.687,314.383 140.746,314.324 141.195,314.324 141.419,314.549 C677.2@141.419,314.574
  L16 w0.101: J27.47@137.843,314.374 139.574,314.374 ccw(c139.574,314.424) v1(139.624,314.424)
NVMe_Rx_0_P: C653.2 J27.49 R541.1 | length 4.1
  L1 w0.101: v1(139.624,313.824) 140.462,313.824 R541.1@140.462,313.624 140.512,313.624 140.687,313.798 140.687,313.864 140.746,313.923 141.195,313.923 141.419,313.699 C653.2@141.419,313.674
  L16 w0.101: J27.49@137.843,313.874 139.574,313.874 cw(c139.574,313.824) v1(139.624,313.824)
NVMe_Rx_1_N: C716.2 J27.35 R542.1 | length 3.8
  L1 w0.101: v1(139.636,317.425) 140.462,317.425 R542.1@140.462,317.575 ; R542.1@140.462,317.625 R542.1@140.462,317.575 ; C716.2@141.419,317.575 R542.1@140.462,317.575
  L16 w0.101: J27.35@137.843,317.374 139.586,317.374 ccw(c139.586,317.425) v1(139.636,317.425)
NVMe_Rx_1_P: C715.2 J27.37 R542.2 | length 3.8
  L1 w0.101: v1(139.636,316.825) 140.462,316.825 R542.2@140.462,316.674 ; R542.2@140.462,316.625 R542.2@140.462,316.674 ; C715.2@141.419,316.674 R542.2@140.462,316.674
  L16 w0.101: J27.37@137.843,316.874 139.587,316.874 cw(c139.587,316.825) v1(139.636,316.825)
NVMe_Tx_0_N: C651.2 J27.41 | length 41.4
  L14 (Sign) w0.081: v10(139.636,315.908) ccw(c139.747,315.908) 139.747,315.798 142.507,315.798 ccw(c142.507,316.154) 142.862,316.154 142.862,321.196 cw(c144.346,321.196) 144.346,322.68 170.243,322.68 cw(c170.243,321.601) 171.322,321.601 ccw(c171.371,321.601) 171.371,321.551 v10(171.432,321.551)
  L16 w0.101: J27.41@137.843,315.874 139.602,315.874 ccw(c139.602,315.908) v10(139.636,315.908) ; v10(171.432,321.551) ccw(c171.432,321.501) 171.381,321.501 171.381,320.968 ccw(c171.635,320.968) C651.2@171.635,320.714
NVMe_Tx_0_P: C649.2 J27.43 | length 41.5
  L14 (Sign) w0.081: v10(139.636,315.308) cw(c139.747,315.308) 139.747,315.418 142.507,315.418 ccw(c142.507,316.154) 143.242,316.154 143.242,320.535 143.242,320.596 cw(c143.341,320.596) 143.341,320.695 143.418,320.695 ccw(c143.418,320.794) 143.517,320.794 143.517,320.879 ccw(c143.418,320.879) 143.418,320.978 143.341,320.978 cw(c143.341,321.077) 143.242,321.077 143.242,321.119 143.242,321.196 cw(c144.346,321.196) 144.346,322.3 169.608,322.3 169.719,322.3 cw(c169.719,322.201) 169.818,322.201 169.818,322.181 ccw(c169.918,322.181) 169.918,322.082 170.003,322.082 ccw(c170.003,322.181) 170.102,322.181 170.102,322.201 cw(c170.201,322.201) 170.201,322.3 170.243,322.3 cw(c170.243,321.601) 170.942,321.601 cw(c170.892,321.601) 170.892,321.551 v10(170.832,321.551)
  L16 w0.101: J27.43@137.843,315.374 139.571,315.374 cw(c139.571,315.308) v10(139.636,315.308) ; C649.2@170.726,320.714 ccw(c170.726,320.968) 170.98,320.968 170.98,321.403 ccw(c170.832,321.403) v10(170.832,321.551)
NVMe_Tx_1_N: C718.2 J27.29 | length 40.4
  L14 (Sign) w0.081: v10(139.636,318.924) ccw(c139.747,318.924) 139.747,318.814 141.09,318.814 ccw(c141.09,319.545) 141.821,319.545 141.821,323.393 cw(c143.191,323.393) 143.191,324.763 168.237,324.763 cw(c168.237,323.814) 169.186,323.814 169.186,323.541 ccw(c169.296,323.541) v10(169.296,323.431)
  L16 w0.101: J27.29@137.843,318.874 139.587,318.874 ccw(c139.587,318.924) v10(139.636,318.924) ; v10(169.296,323.431) ccw(c169.296,323.331) 169.197,323.331 169.197,320.968 ccw(c169.451,320.968) C718.2@169.451,320.714
NVMe_Tx_1_P: C717.2 J27.31 | length 40.3
  L14 (Sign) w0.081: v10(139.636,318.324) cw(c139.747,318.324) 139.747,318.434 141.09,318.434 ccw(c141.09,319.545) 142.201,319.545 142.201,322.707 142.201,322.792 cw(c142.301,322.792) 142.301,322.892 142.405,322.892 ccw(c142.405,322.992) 142.505,322.992 142.505,323.126 ccw(c142.405,323.126) 142.405,323.226 142.301,323.226 cw(c142.301,323.326) 142.201,323.326 142.201,323.393 cw(c143.191,323.393) 143.191,324.383 143.358,324.383 cw(c143.457,324.383) 143.457,324.482 143.593,324.482 cw(c143.593,324.383) 143.692,324.383 143.916,324.383 168.237,324.383 cw(c168.237,323.814) 168.806,323.814 168.806,323.541 cw(c168.696,323.541) v10(168.696,323.431)
  L16 w0.101: J27.31@137.843,318.374 139.587,318.374 cw(c139.587,318.324) v10(139.636,318.324) ; C717.2@168.542,320.714 ccw(c168.542,320.968) 168.796,320.968 168.796,323.331 ccw(c168.696,323.331) v10(168.696,323.431)
OSC_500Out: C333.1 TP20.1 X2.10 | length 103.7
  L1 w0.101: C333.1@57.675,392.493 58.209,393.027 v1(58.712,393.027) ; v1(74.739,395.313) 84.087,395.313 100.248,411.475 115.169,411.475 TP20.1@115.418,411.226 116.446,412.255 144.539,412.255 147.295,415.011 X2.10@151.803,415.011
  L5 (Sign) w0.081: v1(58.712,393.027) 60.465,393.027 62.751,395.313 v1(74.739,395.313)
Osc_in_Si53323_2_N: C343.1 R259.2 R261.2 R489.2 U32.6 | length 5.6
  L1 w0.101: C343.1@66.692,388.497 66.692,388.447 66.952,388.187 67.28,388.187 67.339,388.246 67.339,388.28 67.514,388.455 R261.2@67.564,388.455 67.614,388.455 67.788,388.28 67.788,388.246 67.847,388.187 68.296,388.187 68.355,388.246 68.355,388.28 68.53,388.455 R259.2@68.58,388.455 68.63,388.455 68.804,388.28 68.804,388.246 68.863,388.187 69.006,388.187 69.008,388.189 69.464,388.189 69.523,388.248 69.523,388.314 69.698,388.489 R489.2@69.748,388.489 69.798,388.489 69.972,388.314 69.972,388.248 70.032,388.189 70.285,388.189 70.307,388.211 71.196,388.211 U32.6@71.245,388.261
Osc_in_Si53323_2_P: C342.1 R260.2 R262.2 R489.1 U32.7 | length 5.6
  L1 w0.101: C342.1@66.692,387.497 66.692,387.547 66.916,387.771 66.961,387.771 66.975,387.786 67.28,387.786 67.339,387.727 67.339,387.692 67.514,387.518 R262.2@67.564,387.518 67.614,387.518 67.788,387.692 67.788,387.727 67.847,387.786 68.296,387.786 68.355,387.727 68.355,387.692 68.53,387.518 R260.2@68.58,387.518 68.63,387.518 68.804,387.692 68.804,387.727 68.863,387.786 69.172,387.786 69.174,387.788 69.464,387.788 69.523,387.729 69.523,387.663 69.698,387.489 R489.1@69.748,387.489 69.798,387.489 69.972,387.663 69.972,387.729 70.032,387.788 70.451,387.788 70.473,387.81 71.196,387.81 U32.7@71.245,387.761
OSC_Out_DIV_N: C343.2 R258.1 U33.11 | length 2.7
  L1 w0.101: U33.11@63.119,388.235 65.38,388.235 ccw(c65.38,388.497) C343.2@65.642,388.497
OSC_Out_DIV_P: C342.2 R256.2 U33.10 | length 2.7
  L1 w0.101: U33.10@63.119,387.735 65.404,387.735 cw(c65.404,387.497) C342.2@65.642,387.497
P4HS_PowerAlert_Pcie0: R530.2 U64_U_Pomiar_pradu_napiecia_PCIe0.3 | length 164.9
  L1 w0.2: U64_U_Pomiar_pradu_napiecia_PCIe0.3@171.587,386.83 171.587,385.708 171.704,385.591 238.847,385.591 242.676,381.762 242.676,354.262 246.863,350.075 246.863,342.557 253.134,336.285 253.134,318.21 251.828,316.903 245.99,316.903 243.31,314.223 v1(243.31,312.896) ; R530.2@242.686,302.785 v1(242.686,303.546)
  L12 (Sign) w0.2: v1(242.686,303.546) 242.686,312.273 v1(243.31,312.896)
P4HS_PowerAlert_Pcie1: R547.2 U64_U_Pomiar_pradu_napiecia_PCIe1.3 | length 127.8
  L1 w0.2: U64_U_Pomiar_pradu_napiecia_PCIe1.3@224.281,246.97 224.322,246.928 v1(224.322,245.556) ; R547.2@245.413,302.785 v1(245.413,303.546)
  L5 (Sign) w0.2: v1(224.322,245.556) 226.045,245.556 226.513,246.024 235.28,246.024 238.157,248.901 256.28,248.901 v6(258.242,250.863)
  L3 (Sign) w0.2: v1(245.413,303.546) 245.413,303.252 246.61,302.056 261.794,302.056 265.242,298.607 273.528,298.607 275.946,296.189 275.946,263.303 263.505,250.863 v6(258.242,250.863)
P4HS_PowerAlert_Pcie2: R550.2 U64_U_Pomiar_pradu_napiecia_PCIe2.3 | length 105.6
  L1 w0.2: R550.2@239.96,302.785 v1(239.96,303.546) ; v1(247.888,373.8) 247.89,373.802 247.89,379.803 250.294,382.207 252.435,382.207 254.496,384.268 254.496,384.35 254.646,384.5 U64_U_Pomiar_pradu_napiecia_PCIe2.3@254.646,385.075
  L5 (Sign) w0.2: v1(241.541,332.272) 241.541,352.753 247.49,358.702 247.49,363.797 247.31,363.977 247.279,363.977 244.615,366.642 244.615,369.688 247.888,372.961 v1(247.888,373.8)
  L14 (Sign) w0.2: v1(239.96,303.546) 239.96,304.804 238.779,305.984 236.412,305.984 229.453,312.943 229.453,315.347 231.08,316.973 231.08,327.778 233.974,330.672 239.941,330.672 v1(241.541,332.272)
P4HS_PowerAlert_Pcie3: R553.2 U64_U_Pomiar_pradu_napiecia_PCIe3.3 | length 207.4
  L1 w0.2: U64_U_Pomiar_pradu_napiecia_PCIe3.3@89.633,384.471 89.633,382.865 v1(89.948,382.549) ; v1(219.304,319.354) 222.233,319.354 228.346,313.241 228.346,306.768 229.019,306.095 238.774,306.095 v1(241.323,303.546) R553.2@241.323,302.785
  L5 (Sign) w0.2: v1(89.948,382.549) 91.091,381.406 93.628,381.406 95.658,379.377 95.658,376.033 111.249,360.442 v1(115.577,360.442)
  L16 w0.2: v1(115.577,360.442) 135.252,360.442 144.778,350.915 212.939,350.915 219.304,344.551 v1(219.304,319.354)
P4HS_PowerAlert_Pcie4: R556.2 U64_U_Pomiar_pradu_napiecia_PCIe4.3 | length 204
  L1 w0.2: U64_U_Pomiar_pradu_napiecia_PCIe4.3@140.229,248.004 140.229,249.335 140.932,250.038 v1(142.662,250.038) ; R556.2@246.776,302.785 v1(246.776,303.546)
  L5 (Sign) w0.2: v1(142.662,250.038) 143.37,250.038 144.997,251.664 144.997,253.448 145.841,254.292 150.182,254.292 150.931,255.041 156.776,255.041 v1(157.186,255.45) ; v1(228.448,252.371) 228.448,252.408 229.274,253.235 247.723,253.235 250.736,256.248 250.736,257.934 250.954,258.152 v6(250.954,258.201)
  L12 (Sign) w0.2: v1(157.186,255.45) 157.793,256.057 187.642,256.057 191.668,252.031 224.234,252.031 225.683,253.48 228.164,253.48 228.448,253.196 v1(228.448,252.371) ; v1(245.783,292.24) 245.783,292.802 ; 245.783,292.815 246.776,293.809 v1(246.776,303.546)
  L3 (Sign) w0.2: v1(245.783,292.24) 245.783,291.829 246.863,290.749 266.583,290.749 269.797,287.535 269.797,267.335 260.689,258.227 250.98,258.227 v6(250.954,258.201)
PCIe_Reset: J27.50 R788.1 TP35.1 | length 26.5
  L16 w0.2: J27.50@145.393,313.624 145.434,313.665 R788.1@148.399,313.665 ; R788.1@148.35,313.665 148.367,313.665 148.367,319.525 152.446,323.605 152.446,331.782 150.229,334 150.15,334.079 TP35.1@149.836,334.393
PDN: R498.1 U16.46 | length 3
  L1 w0.2: R498.1@151.701,235.008 151.701,234.302 152.415,233.589 U16.46@152.415,232.345
PEDET: J27.61
PEwake: J27.54
PG1_1: R295.2 R835.1 U37.27 | length 37.1
  L1 w0.2: R835.1@58.647,156.615 59.398,156.615 60.147,157.364 v7(60.147,160.325)
  L1 w0.254: U37.27@66.175,181.817 66.175,182.221 67.071,183.117 67.071,183.252 R295.2@67.169,183.35
  L3 (Sign) w0.2: v7(60.147,160.325) 60.147,160.954 59.448,161.653 59.448,163.729 59.021,164.156 59.021,174.236 60.12,175.336 65.011,175.336 67.853,178.178 67.853,181.716 67.169,182.399 v7(67.169,183.4)
PG1_2: R313.2 R838.1 U38.27 | length 58.4
  L1 w0.2: R838.1@58.597,162 58.597,161.6 58.623,161.573 v2(58.623,160.63)
  L1 w0.254: U38.27@64.453,208.714 64.453,209.276 64.953,209.776 v7(64.953,210.304)
  L3 (Sign) w0.2: v2(58.623,160.63) 58.623,160.685 58.072,161.237 58.072,162.878 58.052,162.898 58.052,200.63 60.955,203.534 60.955,204.542 60.358,205.14 60.358,207.916 61.246,208.804 61.246,208.947 61.582,209.283 62.911,209.283 63.293,208.901 63.604,208.901 63.615,208.912 64.089,208.912 64.953,209.776 v7(64.953,210.304)
PG1_TPS7A8801: R440.2 U35_I2C_Expander_PWR_CLK.28 U61.17 | length 41.8
  L1 w0.2: U35_I2C_Expander_PWR_CLK.28@134.003,208.778 136.368,208.778 136.886,208.259 166.977,208.259 167.478,208.761 v2(167.818,208.761) ; R440.2@166.736,211.098 166.751,211.083 v2(166.751,210.423) ; v2(171.128,209.918) U61.17@171.128,210.523
  L3 (Sign) w0.2: v2(166.751,210.423) 166.751,209.149 167.139,208.761 v2(167.818,208.761) 169.97,208.761 v2(171.128,209.918)
PG2_2: R314.2 R836.1 U38.14 | length 51.3
  L1 w0.2: R836.1@58.607,159.75 59.073,160.216 v2(59.073,160.63)
  L1 w0.254: U38.14@64.453,204.214 64.455,204.212 64.455,203.6 64.623,203.432 v7(64.623,202.723)
  L3 (Sign) w0.2: v2(59.073,160.63) 59.073,162.3 58.352,163.022 58.352,200.373 59.445,201.466 64.206,201.466 64.223,201.448 64.911,201.448 65.123,201.661 65.123,202.223 v7(64.623,202.723)
PG2_TPS7A8801: R441.2 U35_I2C_Expander_PWR_CLK.1 U61.9 | length 46.1
  L1 w0.2: U35_I2C_Expander_PWR_CLK.1@133.079,209.703 135.867,209.703 137.011,208.559 166.853,208.559 167.475,209.182 167.789,209.182 v2(167.818,209.211) ; U61.9@171.128,214.473 171.145,214.49 v2(171.145,215.201)
  L1 w0.254: R441.2@171.128,216.75 171.137,216.741 171.137,215.21 v2(171.145,215.201)
  L3 (Sign) w0.2: v2(167.818,209.211) 169.384,209.211 169.512,209.339 169.512,213.568 v2(171.145,215.201) v2@171.178,215.169
PG2_TPS7A8801_0V9: R676.2 T33.1 U37.8 U70.9 U73.5 | length 315.1
  L1 w0.2: v1(62.591,177.194) 62.648,177.251 62.648,177.366 63.1,177.817 U37.8@63.175,177.817 ; v1(151.414,278.447) U70.9@151.414,280.028 ; U73.5@151.644,348.484 151.645,348.483 v1(152.111,348.482) v1(152.111,348.482)
  L5 (Sign) w0.2: v1(62.591,177.194) 61.989,177.796 61.989,179.131 68.278,185.42 70.783,185.42 72.092,186.729 72.092,188.905 74.947,191.759 83.73,191.759 85.613,193.642 85.613,211.964 100.34,226.691 113.211,226.691 121.392,234.872 121.392,244.252 124.548,247.407 130.463,247.407 135.169,252.113 144.129,252.113 144.539,252.523 144.539,253.568 145.859,254.889 147.345,254.889 147.701,255.245 147.701,258.764 151.133,262.196 151.133,273.522 151.414,273.804 v1(151.414,278.447)
  L3 (Sign) w0.2: v1(87.554,157.988) 87.605,157.937 110.782,157.937 111.328,158.483 v1(111.341,158.471)
  L14 (Sign) w0.2: v1(62.591,177.194) 62.591,176.317 63.36,175.548 63.36,173.736 65.24,171.856 70.904,171.856 71.857,170.904 71.857,169.278 72.86,168.275 82.08,168.275 84.506,165.849 84.506,161.036 v1(87.554,157.988) ; v10(109.93,162.738) 109.931,162.738 111.341,161.328 v1(111.341,158.471)
  L16 w0.2: T33.1@109.897,162.705 v10(109.93,162.738) ; v1(151.414,278.447) 150.512,279.349 148.144,279.349 147.114,280.379 147.114,285.392 150.279,288.557 151.341,288.557 152.459,289.675 152.459,295.182 157.598,300.321 157.598,308.472 151.386,314.683 151.329,314.741 151.329,314.824 151.329,321.019 153.282,322.972 153.282,335.458 151.386,337.353 151.386,347.758 v1(152.111,348.482)
PG_2V5@1.5A: R392.1 T38.1 U18.A2 U49.5 | length 277.5
  L1 w0.2: U49.5@105.47,253.648 106.185,253.648 107.175,254.639 107.175,255.854 v1(106.845,256.184) ; v1(127.898,303.76) U18.A2@127.898,304.681 ; R392.1@188.316,346.064 v1(188.316,347.256)
  L5 (Sign) w0.2: v6(112.876,279.958) 118.173,279.958 124.549,286.334 124.549,299.987 126.528,301.966 ; v1(123.642,313.703) 124.197,313.147 124.197,304.297 126.528,301.966 ; v1(127.898,303.76) 127.898,303.336 126.528,301.966
  L3 (Sign) w0.2: v1(100.66,166.941) 98.754,168.848 98.754,186.574 101.648,189.469 109.573,189.469 111.39,191.286 111.39,210.306 108.825,212.872 108.825,223.264 111.732,226.171 113.69,226.171 115.022,227.503 115.022,242.778 112.589,245.211 112.276,245.211 109.385,248.101 109.385,249.841 107.205,252.021 107.205,255.824 v1(106.845,256.184) 106.845,256.266 106.545,256.566 106.545,265.971 111.874,271.301 111.874,279.097 112.736,279.958 v6(112.876,279.958)
  L10 (3V3+Other) w0.2: v1(123.642,313.703) 124.159,313.186 139.882,313.186 141.388,314.691 141.388,322.718 147.373,328.703 148.321,328.703 152.806,333.188 152.806,335.319 154.826,337.339 154.826,344.424 155.766,345.364 162.295,345.364 162.942,344.716 184.036,344.716 186.576,347.256 v1(188.316,347.256)
  L14 (Sign) w0.2: v10(100.057,166.174) 100.66,166.778 v1(100.66,166.941)
PG_3V3@14A_EXP: R835.2 R837.1 T37.1 U35_I2C_Expander_PWR_Dist.25 | length 85.7
  L1 w0.12: U35_I2C_Expander_PWR_Dist.25@49.093,162.178 49.093,163.753 49.164,163.823 52.185,163.823 54.758,161.25 54.758,157.699 55.892,156.565 56.608,156.565 56.658,156.615 v2(57.747,156.615)
  L3 (Sign) w0.2: v2(57.747,156.615) 58.411,156.615 59.738,155.288 65.464,155.288 66.318,154.433 76.313,154.433 77.772,155.892 114.229,155.892 120.815,162.479 v1(120.815,162.738)
  L14 (Sign) w0.2: v1(120.815,162.738) 121.831,162.738 121.846,162.723 v10(123.603,162.723)
PG_5V@10A_EXP: R836.2 R839.1 T41.1 U35_I2C_Expander_PWR_Dist.26 | length 85.6
  L1 w0.12: U35_I2C_Expander_PWR_Dist.26@48.443,162.178 48.443,163.585 48.901,164.043 52.326,164.043 R839.1@56.569,159.8 56.569,159.75 v2(57.707,159.75)
  L3 (Sign) w0.2: v2(57.707,159.75) 58.623,158.834 58.623,157.282 60.017,155.888 66.108,155.888 66.683,155.313 75.948,155.313 77.408,156.773 113.864,156.773 117.927,160.836 117.927,163.589 118.643,163.589 120.625,165.57 v1(120.625,166.014)
  L14 (Sign) w0.2: v1(120.625,166.014) 121.404,166.014 v10(121.564,166.174)
PG_12@8A_EXP: R838.2 R840.1 T45.1 U35_I2C_Expander_PWR_Dist.27 | length 85.4
  L1 w0.12: U35_I2C_Expander_PWR_Dist.27@47.793,162.178 47.793,163.651 48.406,164.263 52.808,164.263 55.072,162 56.558,162 v2(57.697,162)
  L3 (Sign) w0.2: v2(57.697,162) 57.697,160.724 58.966,159.454 58.966,157.363 60.142,156.188 66.233,156.188 66.807,155.613 75.824,155.613 77.283,157.073 113.74,157.073 117.627,160.96 117.627,162.331 v1(116.891,163.068)
  L14 (Sign) w0.2: v1(116.891,163.068) 117.373,163.551 118.821,163.551 119.667,162.705 v10(120.005,162.705)
PG_48_20V: R828.2 T49.1 U35_I2C_Expander_PWR_Dist.4 U65.19 | length 143.4
  L1 w0.12: v7(44.197,159.616) 44.508,159.616 44.821,159.303 U35_I2C_Expander_PWR_Dist.4@46.218,159.303
  L1 w0.254: v2(35.662,203.606) 35.847,203.606 36.059,203.818 U65.19@36.92,203.818
  L3 (Sign) w0.12: v2(35.662,203.606) 35.954,203.314 35.954,199.453 40.716,194.691 40.716,162.902 40.905,162.712 42.367,162.712 44.183,160.896 44.197,160.883 v7(44.197,159.616)
  L3 (Sign) w0.2: v7(44.197,159.616) 44.697,159.116 44.697,157.399 45.333,156.762 50.806,156.762 51.465,157.421 51.465,157.924 51.6,158.059 51.6,158.775 52.934,160.109 55.969,160.109 57.979,158.098 57.979,157.501 59.893,155.588 65.786,155.588 66.501,154.873 76.13,154.873 77.59,156.333 114.047,156.333 118.367,160.653 118.367,162.055 v1(120.574,164.262)
  L14 (Sign) w0.2: v10(118.037,166.174) 118.037,165.732 119.507,164.262 v1(120.574,164.262)
PG_ADP1850_1V2_REG4: R435.1 R668.1 T40.1 U69.4 | length 88.6
  L1 w0.2: v1(125.243,230.447) 125.288,230.492 125.288,232.235 R668.1@125.277,232.245 125.282,232.249 125.282,233.243 125.282,233.701 125.999,234.418 U69.4@126.93,234.418
  L5 (Sign) w0.2: v1(105.949,167.238) 113.889,167.238 116.364,169.713 117.785,169.713 118.596,170.523 118.596,177.885 119.628,178.917 119.628,187.095 114.491,192.232 114.491,219.695 v1(125.243,230.447)
  L14 (Sign) w0.2: v1(105.949,167.238) 107.013,166.174 v10(107.929,166.174)
PG_LT3042: R442.1 R1082.1 U35_I2C_Expander_PWR_CLK.25 U62.4 | length 415.3
  L1 w0.2: v2(123.038,285.788) 126.65,282.176 130.652,282.176 134.304,278.524 134.304,276.259 v2(135.252,275.311) ; U35_I2C_Expander_PWR_CLK.25@134.003,206.828 134.628,206.828 134.628,206.854 v2(134.594,206.854) ; U62.4@159.285,399.561 159.285,399.146 160.249,398.183 v2(160.464,398.183) 161.462,398.183 R442.1@162.491,399.212
  L5 (Sign) w0.2: v6(58.839,340.97) 60.246,340.97 61.046,340.169 79.566,340.169 80.581,341.185 80.581,347.045 81.643,348.107 102.451,348.107 103.264,347.294 v6(103.372,347.294) ; v6(100.52,376.39) 100.52,376.863 103.554,379.897 109.795,379.897 v6(119.837,389.94) ; v12(159.988,389.94) 161.458,391.41 v12(161.458,392.786)
  L3 (Sign) w0.2: v6(58.839,340.97) 59.207,340.97 60.35,339.827 60.637,339.827 76.596,323.867 76.596,323.715 104.004,296.307 110.143,296.307 114.35,292.1 116.408,292.1 117.334,291.174 117.334,290.196 121.742,285.788 v2(123.038,285.788) ; v6(100.52,376.39) 99.409,375.278 99.409,373.159 102.94,369.628 102.94,347.726 v6(103.372,347.294) ; v6(119.837,389.94) v12(159.988,389.94) ; v1(126.437,201.321) 127.42,201.321 130.251,204.153 133.617,204.153 134.594,205.13 v2(134.594,206.854) 134.594,228.828 138.565,232.799 138.565,236.729 125.432,249.862 125.432,259.147 125.463,259.178 125.463,264.946 126.467,265.95 126.467,269.392 130.696,273.621 134.645,273.621 135.252,274.228 v2(135.252,275.311) ; v2(160.464,398.183) 160.464,393.779 v12(161.458,392.786)
  L14 (Sign) w0.2: v10(91.901,173.596) 93.141,173.596 98.754,179.209 98.754,186.821 101.868,189.935 115.051,189.935 v1(126.437,201.321)
  L16 w0.2: R1082.1@91.594,170.715 91.594,173.289 v10(91.901,173.596)
PG_PS_LTC6952_1: R431_5to3V3_1.1 T32.1 U35_I2C_Expander_PWR_CLK.17 U59_5to3V3_1.5 | length 305.5
  L1 w0.2: U59_5to3V3_1.5@93.731,343.652 94.183,343.652 ; v2(95.047,340.652) 95.047,341.135 94.183,341.999 94.183,343.652 ; R431_5to3V3_1.1@95.314,343.56 94.394,343.56 94.302,343.652 94.183,343.652 ; U35_I2C_Expander_PWR_CLK.17@130.479,203.953 130.479,202.173 130.48,202.171 v1(130.505,202.171)
  L5 (Sign) w0.2: v6(59.596,337.287) 59.746,337.437 59.746,337.978 60.027,338.26 66.046,338.26 67.159,337.147 v6(71.336,337.147) ; v6(90.792,296.875) 91.021,296.647 v6(94.488,296.647) ; v6(119.355,209.522) 120.579,209.522 127.929,202.171 v1(130.505,202.171)
  L3 (Sign) w0.2: v6(59.596,337.287) 59.596,324.463 62.616,321.442 73.54,321.442 79.28,315.701 80.848,315.701 86.829,309.721 86.831,309.721 87.095,309.457 87.095,309.455 88.235,308.314 88.235,307.01 87.965,306.739 87.965,306.08 89.274,304.771 89.274,301.607 91.419,299.462 91.419,298.258 90.703,297.542 90.703,296.964 v6(90.792,296.875) ; v6(71.336,337.147) 71.349,337.16 73.672,337.16 74.022,336.811 79.034,336.811 81.249,339.025 86.371,339.025 88.11,340.763 92.27,340.763 92.382,340.652 v2(95.047,340.652) ; v6(94.488,296.647) 97.357,296.647 104.155,289.849 109.281,289.849 114.1,285.03 114.1,282.999 117.418,279.681 117.418,269.641 120.783,266.276 120.783,252.948 119.314,251.479 119.314,221.772 115.569,218.026 115.569,213.308 v6(119.355,209.522)
  L14 (Sign) w0.2: v10(94.153,162.705) 92.512,162.705 91.516,161.709 88.876,161.709 86.931,163.654 86.931,166.497 91.285,170.85 91.285,171.056 99.138,178.909 99.138,186.781 101.992,189.635 115.594,189.635 128.13,202.171 v1(130.505,202.171)
PG_PS_LTC6952_2: R431_5to3V3_2.1 T47.1 U35_I2C_Expander_PWR_CLK.21 U59_5to3V3_2.5 | length 209.7
  L1 w0.2: v1(133.045,202.692) 133.079,202.725 U35_I2C_Expander_PWR_CLK.21@133.079,203.953 139.114,203.953 v2(139.132,203.972) ; R431_5to3V3_2.1@198.138,263.488 198.138,264.144 198.319,264.325 200.918,264.325 201.405,263.838 ; U59_5to3V3_2.5@202.395,263.388 201.855,263.388 201.405,263.838 ; v2(207.645,263.538) 206.743,264.439 202.006,264.439 201.405,263.838
  L5 (Sign) w0.2: v6(189.936,237.872) 189.936,243.758 195.256,249.079 v6(209.977,249.079)
  L3 (Sign) w0.2: v2(139.132,203.972) 139.415,204.254 139.415,217.227 141.564,219.376 157.953,219.376 164.96,226.384 164.96,228.235 174.597,237.872 v6(189.936,237.872) ; v2(207.645,263.538) 208.966,263.538 215.036,257.467 215.036,256.618 216.765,254.889 216.765,253.746 215.113,252.093 212.992,252.093 v6(209.977,249.079)
  L14 (Sign) w0.2: v10(88.249,166.174) 88.249,167.345 91.585,170.681 91.585,170.932 99.438,178.785 99.438,186.656 102.116,189.335 115.718,189.335 127.907,201.524 130.937,201.524 132.105,202.692 v1(133.045,202.692)
PG_PS_LTC6952_3: U35_I2C_Expander_PWR_CLK.23
PGND: C595.1 C596.1 C597.1 C598.1 C694.1 C695.1 C696.1 C697.1 C698.1 C699.1 C700.1 C704.2 D3.2 D4.2 R324.1 R764.2 T35.1 T35.2 T35.3 U65.16 | length 45.1
  L1 w0.4: v1(33.287,206.368) 33.305,206.35 C597.1@33.942,206.35 ; v1(36.206,205.683) 36.572,205.318 U65.16@36.92,205.318 ; v1(38.202,198.489) C704.2@38.907,198.489 ; C700.1@43.152,208.494 v1(43.152,209.374) ; C694.1@44.911,209.722 v1(44.911,210.629)
  L1 w0.5: T35.1@32.55,213.3 32.55,212.719 v1(32.584,212.684) ; v1(33.82,212.65) T35.2@33.82,213.464 ; v1(35.09,212.65) T35.3@35.09,213.464 ; v1(37.032,210.162) C598.1@37.846,210.162 ; C699.1@51.994,200.664 v1(53.081,200.664) ; C699.1@51.994,201.387 v1(53.081,201.387) ; C696.1@51.994,202.554 v1(53.081,202.554) ; C696.1@51.994,203.278 v1(53.081,203.278) ; C697.1@51.994,204.444 v1(53.081,204.444) ; C697.1@51.994,205.168 v1(53.081,205.168) ; C695.1@51.994,206.335 v1(53.081,206.335) ; C695.1@51.994,207.059 v1(53.081,207.059) ; C698.1@51.994,208.225 v1(53.081,208.225) ; C698.1@51.994,208.949 v1(53.081,208.949)
  L16 w0.5: v9(27.345,227.151) C595.1@28.639,227.151 ; v9(28.639,225.857) C595.1@28.639,227.151 ; v9(29.932,227.151) C595.1@28.639,227.151 ; v9(30.586,223.896) D4.2@31.88,223.896 ; v9(31.88,222.602) D4.2@31.88,223.896 ; v9(31.88,225.19) D4.2@31.88,223.896 ; v9(33.174,223.896) D4.2@31.88,223.896 ; v9(40.454,223.832) D3.2@41.748,223.832 ; v9(41.748,222.539) D3.2@41.748,223.832 ; v9(41.748,225.126) D3.2@41.748,223.832 ; v9(43.041,223.832) D3.2@41.748,223.832 ; v9(48.998,225.107) R324.1@50.292,225.107 v9(50.292,223.813) ; v9(52.54,223.901) C596.1@52.54,225.195 v9(53.834,225.195)
  L16 w1: v9(32.004,214.681) 33.221,215.898 R764.2@33.221,218.554 v9@33.221,221.934
  other v9: 33.235,221.92
PMU_GPI: J14.7 R784.1 | length 8.5
  L1 w0.12: J14.7@34.455,364.376 38.379,364.376 40.149,366.145 R784.1@42.26,366.145
PMU_GPI_1: J14.6 R785.1 | length 8.1
  L1 w0.12: J14.6@34.455,366.876 38.365,366.876 39.195,367.706 R785.1@42.26,367.706
PMU_GPI_2: J14.5 R786.1 | length 7.8
  L1 w0.12: J14.5@34.455,369.376 38.574,369.376 38.682,369.267 R786.1@42.26,369.267
PMU_GPI_3: J14.4 R787.1 | length 8.2
  L1 w0.12: J14.4@34.455,371.876 38.372,371.876 39.42,370.828 R787.1@42.26,370.828
PMU_GPI_5: J14.2 R789.1 | length 11.3
  L1 w0.12: J14.2@34.455,376.876 37.728,376.876 38.527,376.077 38.527,373.296 39.434,372.389 R789.1@42.26,372.389
PMU_GPO_0: J18.7 R790.1 | length 4.8
  L1 w0.2: R790.1@46.199,331.465 46.199,326.714 J18.7@46.257,326.657
PMU_GPO_1: J18.6 R791.1 | length 4.9
  L1 w0.2: R791.1@43.646,331.465 43.646,326.767 J18.6@43.757,326.657
PMU_GPO_2: J18.5 R792.1 | length 4.8
  L1 w0.2: J18.5@41.257,326.657 41.335,326.735 R792.1@41.335,331.465
PMU_GPO_3: J18.4 R793.1 | length 4.8
  L1 w0.2: R793.1@38.731,331.465 38.731,326.682 J18.4@38.757,326.657
PMU_GPO_4: J18.3 R794.1 | length 4.9
  L1 w0.2: J18.3@36.257,326.657 36.407,326.807 R794.1@36.407,331.465
PMU_GPO_5: J18.2 R795.1 | length 4.8
  L1 w0.2: J18.2@33.757,326.657 33.766,326.666 R795.1@33.766,331.465
Power1_In: P8.1 R448_U_Pomiar_pradu_napiecia_1.1 U64_U_Pomiar_pradu_napiecia_1.10 | length 9.7
  L1 w0.2: R448_U_Pomiar_pradu_napiecia_1.1@29.233,169.673 31.033,169.673 31.245,169.461 U64_U_Pomiar_pradu_napiecia_1.10@31.245,161.814
  other v9: 29.233,165.572 29.235,166.579 29.233,167.586 29.233,168.593 29.233,169.6 29.233,170.607 29.233,171.614 29.233,172.621 29.233,173.628 29.233,174.635
Power1_In_CM: R12.2 R448_U_Pomiar_pradu_napiecia_1.2 U5.7 U6.C3 U6.D3 U6.D4 U6.E3 U6.E4 U6.F3 U6.F4 U64_U_Pomiar_pradu_napiecia_1.8 U64_U_Pomiar_pradu_napiecia_1.9 | length 22.9
  L1 w0.2: U64_U_Pomiar_pradu_napiecia_1.9@31.745,161.814 31.745,169.386 32.033,169.673 R448_U_Pomiar_pradu_napiecia_1.2@33.833,169.673 v9(33.833,165.063) 33.408,164.638 33.02,164.638 32.245,163.863 U64_U_Pomiar_pradu_napiecia_1.8@32.245,161.814
  L1 w0.3: v1(47.165,168.808) 47.317,168.656 U6.D3@48.606,168.656 U6.C3@48.606,168.256 ; v1(47.533,169.304) 47.781,169.056 U6.E4@48.206,169.056 ; v1(47.766,169.896) U6.F4@48.206,169.456 ; v1(48.384,170.087) 48.606,169.865 U6.E3@48.606,169.056
  other v1: 46.94,171.336 47.599,172.073 46.939,172.838 48.314,172.942
  other v3: 48.36,174.6
  other v9: 33.833,165.868 33.833,166.729 33.833,167.662 33.833,168.552 33.833,169.477 33.833,170.323 33.833,171.26 33.833,172.067 33.833,172.964 33.82,173.825 33.833,174.703
Power2_In: P10.1 R448_U_Pomiar_pradu_napiecia_2.1 U64_U_Pomiar_pradu_napiecia_2.10 | length 9.6
  L16 w0.2: R448_U_Pomiar_pradu_napiecia_2.1@28.249,194.108 30.049,194.108 30.298,194.358 U64_U_Pomiar_pradu_napiecia_2.10@30.298,201.835
  other v9: 28.291,189.981 28.291,190.989 28.249,191.997 28.249,193.034 28.249,194.014 28.249,195.022 28.249,196.03 28.249,197.038 28.249,198.046 28.249,199.055
Power2_In_CM: R20.2 R448_U_Pomiar_pradu_napiecia_2.2 U5.2 U7.C3 U7.D3 U7.D4 U7.E3 U7.E4 U7.F3 U7.F4 U64_U_Pomiar_pradu_napiecia_2.8 U64_U_Pomiar_pradu_napiecia_2.9 | length 22.4
  L1 w0.3: U7.E3@44.828,178.834 44.828,178.024 v1(45.05,177.802) ; U7.C3@44.828,179.634 U7.D3@44.828,179.234 U7.D4@45.228,179.234 45.287,179.175 46.034,179.175 46.09,179.119 46.231,179.119 v1(46.269,179.081) ; U7.F4@45.228,178.434 v1@45.668,177.993 ; U7.E4@45.228,178.834 45.653,178.834 v1(45.901,178.586)
  L16 w0.2: U64_U_Pomiar_pradu_napiecia_2.9@30.798,201.835 30.798,194.358 31.048,194.108 R448_U_Pomiar_pradu_napiecia_2.2@32.849,194.108 32.849,199.183 31.298,200.734 U64_U_Pomiar_pradu_napiecia_2.8@31.298,201.835 U64_U_Pomiar_pradu_napiecia_2.8@31.308,201.825
  other v1: 46.939,177.161 48.188,177.161 45.728,177.884 47.599,177.926 46.94,178.663
  other v3: 48.36,175.4
  other v9: 32.914,190.009 32.914,191.018 32.872,192.026 32.914,193.034 32.872,194.042 32.872,195.05 32.872,196.058 32.872,197.067 32.872,198.075 32.872,199.083
Power4Charging: U6.C2 U6.D1 U6.D2 U6.E1 U6.E2 U6.F1 U6.F2 U7.C2 U7.D1 U7.D2 U7.E1 U7.E2 U7.F1 U7.F2 | length 9.8
  L1 w0.3: v1(42.966,179.025) 43.021,179.025 43.229,179.234 U7.D2@44.428,179.234 U7.C2@44.428,179.634 ; v1(43.386,178.598) 43.622,178.834 U7.E1@44.028,178.834 U7.E2@44.428,178.834 U7.F2@44.428,178.434 44.428,178.078 v1(44.136,177.786) ; v1(43.588,177.993) U7.F1@44.028,178.434 ; U6.C2@49.006,168.256 U6.D2@49.006,168.656 U6.D1@49.406,168.656 50.271,168.656 v1(50.479,168.865) ; v1(49.298,170.104) 49.006,169.812 U6.F2@49.006,169.456 U6.E2@49.006,169.056 U6.E1@49.406,169.056 49.812,169.056 v1(50.048,169.291) ; U6.F1@49.406,169.456 v1(49.846,169.896)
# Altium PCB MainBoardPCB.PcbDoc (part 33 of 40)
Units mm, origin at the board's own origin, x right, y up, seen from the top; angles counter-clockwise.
Board outline 258.95 x 308.86 mm, 16 copper layers (L1, L2 (GND), L3 (Sign), L4 (GND), L5 (Sign), L6 (PWR/GND), L7(12V+Other), L8 (Plane_GND), L9 (PWR/GND), L10 (3V3+Other), L11 (PWR/GND), L12 (Sign), L13 (GND), L14 (Sign), L15 (GND), L16), stack 2.503 mm thick; 2578 components, 1867 nets, 8817 pads, 8021 vias.
Unrouted connection lines stored in the file: 25.

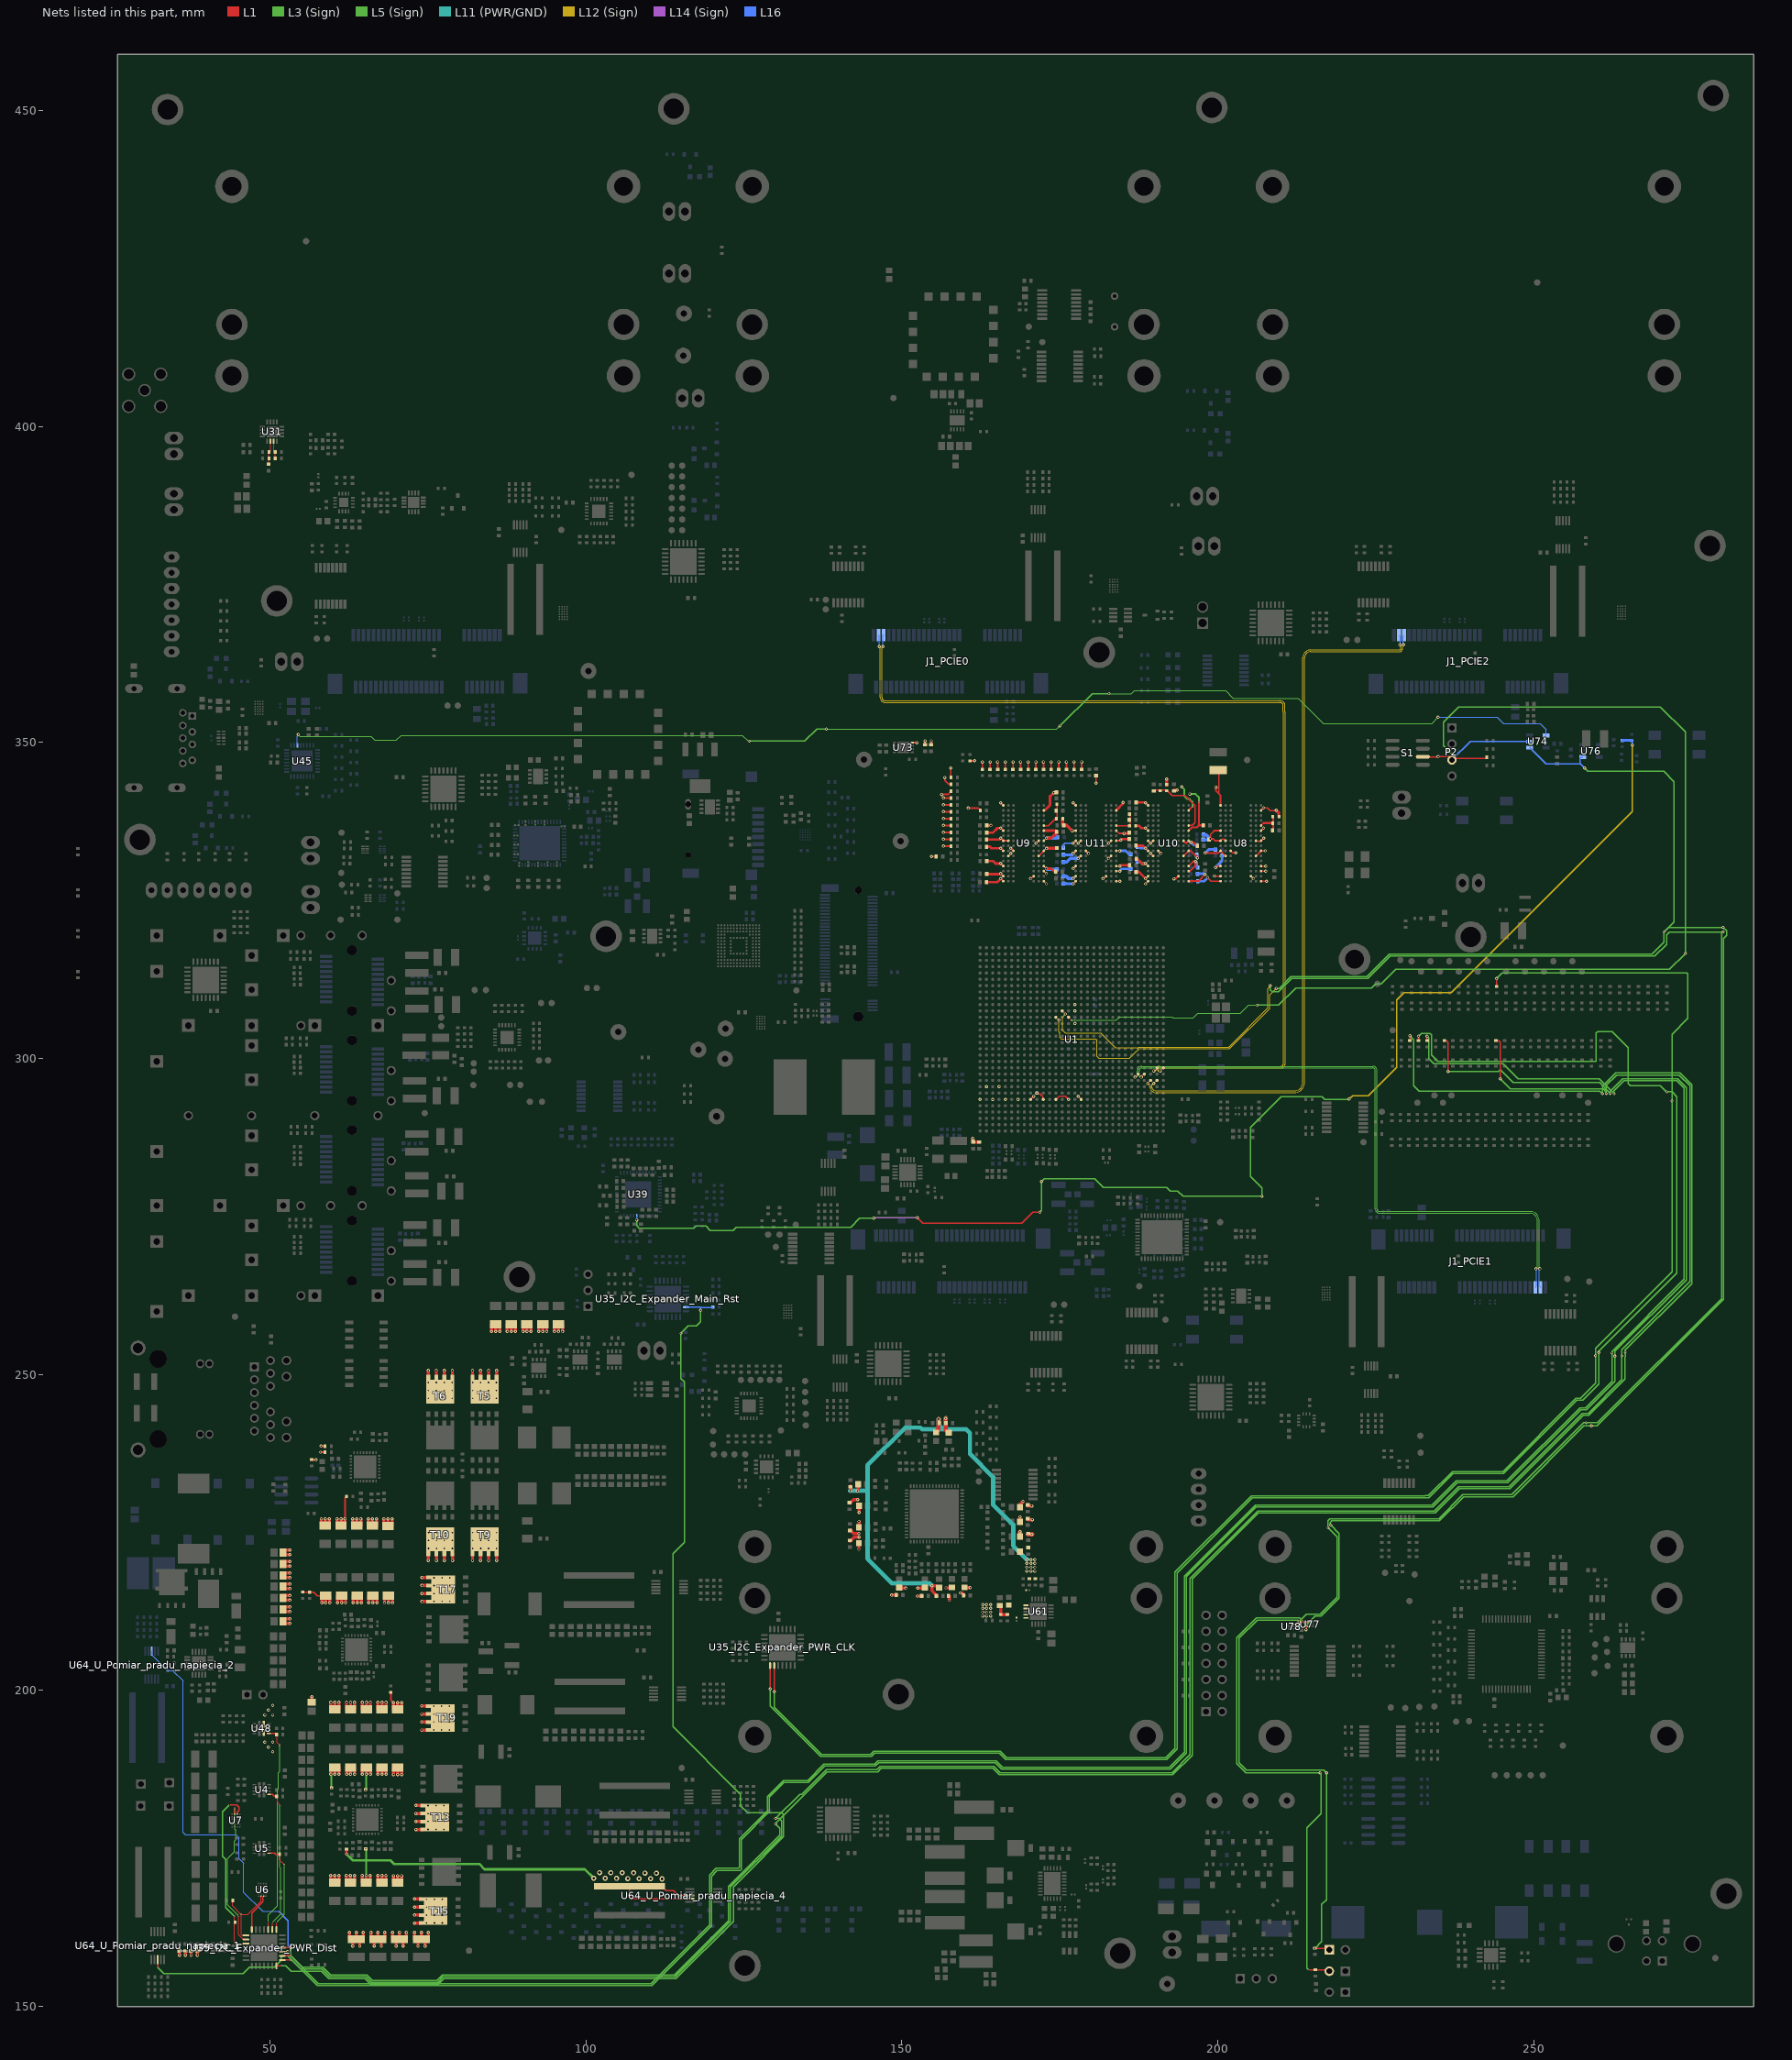
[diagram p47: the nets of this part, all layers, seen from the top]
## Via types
v1: diameter 0.5, hole 0.25, L1 to L16, tented both sides, 4341 vias
v2: diameter 0.254, hole 0.1, L1 to L3 (Sign), tented both sides, 781 vias
v3: diameter 0.5, hole 0.25, L1 to L16, 565 vias
v4: diameter 0.254, hole 0.1, L15 (GND) to L16, tented both sides, 406 vias
v5: diameter 0.254, hole 0.1, L1 to L2 (GND), tented both sides, 283 vias
v6: diameter 0.457, hole 0.2, L3 (Sign) to L6 (PWR/GND), tented both sides, 254 vias
v7: diameter 0.254, hole 0.1, L1 to L3 (Sign), 237 vias
v8: diameter 0.75, hole 0.4, L1 to L16, 200 vias
v9: diameter 0.8, hole 0.4, L1 to L16, tented both sides, 182 vias
v10: diameter 0.254, hole 0.1, L14 (Sign) to L16, tented both sides, 170 vias
v11: diameter 0.75/0/0/0/0/0/0/0/0/0/0/0/0/0/0/0.75 (per signal layer), hole 0.4, L1 to L16, 160 vias
v12: diameter 0.457, hole 0.2, L3 (Sign) to L6 (PWR/GND), 158 vias
v13: diameter 1.4, hole 0.5, L1 to L16, tented both sides, 80 vias
v14: diameter 0.254, hole 0.1, L14 (Sign) to L16, 65 vias
v15: diameter 0.254, hole 0.1, L1 to L2 (GND), 45 vias
v16: diameter 0.457, hole 0.2, L11 (PWR/GND) to L14 (Sign), tented both sides, 26 vias
v17: diameter 0.457, hole 0.2, L11 (PWR/GND) to L14 (Sign), 25 vias
v18: diameter 0.457, hole 0.2, L7(12V+Other) to L10 (3V3+Other), tented both sides, 11 vias
v19: diameter 0.254/0/0.254 (per signal layer), hole 0.1, L1 to L3 (Sign), 9 vias
v20: diameter 0.2/0/0.2 (per signal layer), hole 0.1, L1 to L3 (Sign), 6 vias
v21: diameter 1.65, hole 1.65, L1 to L16, 5 vias
v22: diameter 1.15, hole 1.15, L1 to L16, 5 vias
v23: diameter 0.457, hole 0.2, L1 to L16, 3 vias
v24: diameter 0.5, hole 0.3, L1 to L16, 2 vias
v25: diameter 0.5/0/0.5 (per signal layer), hole 0.2, L14 (Sign) to L16, 1 vias
v26: diameter 0.5, hole 0.25, L1 to L16, tented bottom, 1 vias

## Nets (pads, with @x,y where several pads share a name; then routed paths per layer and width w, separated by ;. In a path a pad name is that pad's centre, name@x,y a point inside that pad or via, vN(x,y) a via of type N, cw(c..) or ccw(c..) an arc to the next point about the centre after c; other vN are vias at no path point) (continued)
Power_3.3_1: C99.2 C100.2 C103.2 C104.2 C107.2 C124.2 C141.2 C145.2 C162.2 C179.2 C572.2 C573.2 FB8.1 FB9.1 FB10.1 FB11.1 FB12.1 FB14.1 FB16.1 FB18.1 FB20.1 FB22.1 R436.2 R440.1 U61.14 U61.15 | length 22.5
  L1 w0.5: C104.2@141.763,229.602 142.377,230.216 v1(143.04,230.216) ; C179.2@141.801,223.617 142.44,224.257 v1(143.243,224.257) ; C162.2@141.801,225.455 142.402,224.853 v1(143.218,224.853) ; v1(143.218,222.339) 143.218,223.309 FB22.1@143.227,223.318 ; FB20.1@143.227,225.818 v1(143.227,226.758) ; FB11.1@143.249,229.212 143.249,228.197 v1(143.251,228.195) ; v1(148.41,215.088) C99.2@149.276,215.088 ; FB8.1@149.588,216.276 149.686,216.178 v1(150.673,216.178) ; v1(152.463,214.935) 153.265,214.935 C124.2@153.28,214.95 ; v1(152.552,216.205) 153.599,216.205 FB14.1@153.67,216.276 ; v1(156.997,216.243) 157.855,216.243 FB12.1@157.915,216.303 ; v1(157.505,214.287) 157.53,214.312 C107.2@157.53,214.977 ; v1(159.267,215.443) 159.558,215.443 C103.2@159.938,215.064 ; FB10.1@159.938,216.303 159.959,216.281 v1(160.832,216.281) ; C572.2@165.532,213.467 cw(c165.532,213.34) 165.659,213.34 165.659,211.998 R440.1@166.736,211.998 ; FB18.1@168.719,226.695 v1(168.719,227.486) ; FB9.1@168.719,229.023 168.719,229.469 v1(169.185,229.935) ; C145.2@169.949,227.076 169.98,227.045 v1(170.65,227.045) ; C100.2@169.949,229.221 170.566,229.221 v1(170.574,229.214)
  L1 w0.7: v1(168.709,225.14) 168.719,225.13 FB16.1@168.719,224.348 ; C141.2@169.989,224.701 170.599,224.701 v1(170.612,224.714)
  other v1: 162.81,211.812 163.437,211.812 164.055,211.812 162.81,212.4 163.437,212.4 164.055,212.4 162.81,213.023 163.437,213.023 164.055,213.023 162.81,213.611 163.437,213.611 164.055,213.611
Power_3.3_2: C108.2 C125.2 C142.2 C146.2 C163.2 C576.2 C577.2 FB13.1 FB15.1 FB17.1 FB19.1 FB21.1 R438.2 R441.1 U61.11 U61.12 | length 85.1
  L1 w0.5: v1(141.859,231.623) 141.861,231.625 C108.2@141.861,232.376 ; v1(142.989,231.597) 143.119,231.727 FB13.1@143.119,232.658 ; C163.2@155.609,214.95 154.797,215.762 v1(154.797,216.586) 155.397,216.586 155.707,216.276 FB21.1@155.893,216.276
  L1 w0.7: FB17.1@155.435,240.832 155.485,240.832 155.585,240.932 155.585,241.122 155.805,241.342 155.805,242.179 C142.2@155.935,242.309 ; C142.2@155.851,242.309 v1(155.851,242.926) ; v1(156.961,243.064) 156.961,241.245 FB15.1@157.404,240.802
  L11 (PWR/GND) w0.7: v1(141.859,231.623) 144.577,231.623 ; v1(154.797,216.586) 154.429,216.954 148.488,216.954 144.577,220.866 144.577,231.623 ; v1(155.851,242.926) 155.851,242.004 156.491,241.363 ; v1(156.961,243.064) 156.961,241.834 156.491,241.363 ; 157.226,241.363 160.173,241.363 160.808,240.728 160.808,237.432 164.459,233.781 164.459,229.388 167.611,226.236 167.652,226.236 167.652,222.89 v1(169.819,220.723) ; 144.577,231.623 144.577,235.624 150.559,241.606 152.963,241.606 153.206,241.363 156.491,241.363
  other v1: 169.819,218.923 170.445,218.923 171.063,218.923 169.819,219.512 170.445,219.512 171.063,219.512 169.819,220.135 170.445,220.135 171.063,220.135 170.445,220.723 171.063,220.723
Power_MUX_Status0: R630.2 U5.9 U35_I2C_Expander_PWR_Dist.22 | length 14.5
  L1 w0.12: U35_I2C_Expander_PWR_Dist.22@51.043,162.178 v7(51.043,163.334) ; R630.2@51.6,174.091 51.6,173.127 v7(52.271,172.456)
  L1 w0.2: U5.9@49.86,174.25 50.769,174.25 50.927,174.091 R630.2@51.6,174.091
  L3 (Sign) w0.12: v7(51.043,163.334) 52.271,164.562 v7(52.271,172.456)
Power_MUX_Status1: R11.1 U4.9 U35_I2C_Expander_PWR_Dist.23 | length 23.3
  L1 w0.12: U35_I2C_Expander_PWR_Dist.23@50.393,162.178 50.397,162.182 50.397,163.334 v7(50.401,163.338) ; R11.1@51.117,183.244 51.194,183.167 51.194,182.322 v7(51.6,181.916)
  L1 w0.2: U4.9@49.86,183.571 50.381,183.571 50.708,183.244 R11.1@51.117,183.244
  L3 (Sign) w0.12: v7(50.401,163.338) 51.717,164.654 51.717,171.951 51.6,172.068 v7(51.6,181.916)
Power_MUX_Status2: R13.2 U35_I2C_Expander_PWR_Dist.24 U48.9 | length 32.9
  L1 w0.12: U35_I2C_Expander_PWR_Dist.24@49.743,162.178 49.746,162.181 49.746,163.335 v7(49.749,163.338) ; R13.2@51.118,193.051 51.118,191.799 v7(51.55,191.367)
  L1 w0.2: U48.9@49.827,193.233 50.736,193.233 R13.2@50.895,193.075
  L3 (Sign) w0.12: v7(49.749,163.338) 49.749,164.488 51.194,165.933 51.194,184.382 51.349,184.537 51.349,187 51.55,187.201 v7(51.55,191.367)
PS_MODE1: P2.3 R350.1 S1.2 U1.R19 U74.2 | length 209
  L1 w0.12: U1.R19@176.397,306.539 v2(176.884,306.052)
  L1 w0.2: S1.2@232.473,347.751 232.508,347.716 234.847,347.716 v1(234.882,347.751) 236.563,347.751 P2.3@237.071,347.243 237.294,347.467 242.459,347.467 R350.1@242.659,347.667
  L5 (Sign) w0.2: v6(206.223,308.44) 209.631,308.44 212.357,311.166 224.372,311.166 225.028,311.823 225.877,311.823 228.17,314.116 271.515,314.116 v6(274.025,316.627)
  L3 (Sign) w0.12: v2(176.884,306.052) 183.909,306.052 184.461,306.603 192.765,306.603 192.963,306.405 196.104,306.405 196.839,307.14 203.599,307.14 204.899,308.44 v6(206.223,308.44)
  L3 (Sign) w0.2: P2.3@237.071,347.243 237.071,348.185 235.744,349.512 235.744,353.23 238.158,355.644 270.047,355.644 274.025,351.666 v6(274.025,316.627)
  L16 w0.2: P2.3@237.071,347.243 239.992,350.164 U74.2@249.385,350.164
PS_POR: P3.2 R355.2 U1.N19 U74.1 U76.1 U77.6 | length 412.9
  L1 w0.12: U1.N19@174.397,306.539 v1(174.884,306.052)
  L1 w0.2: v1(213.982,209.639) 213.982,209.851 U77.6@214.294,210.162 ; v2(214.409,155.771) 217.486,155.771 P3.2@217.669,155.588
  L5 (Sign) w0.2: v1(209.258,311.112) 209.757,311.112 211.611,312.966 223.626,312.966 227.176,316.516 268.723,316.516 270.605,318.398 270.605,319.995 v6(270.631,320.021) 271.366,320.756 v6(279.971,320.756) ; v1(213.982,209.639) 213.982,210.433 212.953,211.462 206.146,211.462 203.035,208.351 203.035,188.451 204.504,186.982 v6(216.204,186.982) ; v6(217.894,226.187) 217.78,226.301 217.78,226.613 218.015,226.848 235.103,226.848 238.93,230.675 246.727,230.675 257.936,241.884 v6(259.161,241.884)
  L12 (Sign) w0.12: v1(174.884,306.052) 174.884,304.16 174.987,304.057 174.987,303.357 175.273,303.072 180.697,303.072 180.891,302.878 180.891,300.375 181.214,300.052 186.042,300.052 187.31,301.32 187.316,301.32 187.586,301.59 201.87,301.59 208.205,307.926 208.205,310.059 v1(209.258,311.112)
  L3 (Sign) w0.2: v1(213.982,209.639) 213.982,210.317 215.417,211.752 216.344,211.752 219.21,214.617 219.21,224.871 v6(217.894,226.187) ; v2(214.409,155.771) 214.135,156.045 214.135,178.268 216.375,180.508 216.375,186.812 v6(216.204,186.982) ; v1(258.064,345.979) 258.59,345.453 270.599,345.453 272.232,343.82 272.232,321.622 v6(270.631,320.021) ; v6(259.161,241.884) 260.042,241.884 280.032,261.874 280.032,318.996 280.53,319.494 280.53,320.197 v6(279.971,320.756)
  L16 w0.2: U74.1@249.385,349.214 251.995,346.604 257.439,346.604 ; U76.1@257.78,347.716 257.543,347.716 257.343,347.516 257.343,346.7 v1(258.064,345.979)
PS_Reset: P4.1 R354.1 U1.P20 U77.4 U78.6 | length 354.1
  L1 w0.12: U1.P20@175.397,307.539 v1(175.884,307.052)
  L1 w0.2: U78.6@211.997,210.474 212.44,210.474 v1(212.865,210.896) ; v1(212.865,210.896) 212.899,210.862 U77.4@214.294,210.862 ; v2(215.392,159.2) 217.448,159.2 P4.1@217.669,158.979
  L5 (Sign) w0.2: v1(208.318,311.506) 208.318,310.871 208.649,310.54 209.61,310.54 211.736,312.666 223.75,312.666 227.3,316.216 268.848,316.216 268.869,316.237 269.198,316.237 271.029,318.069 271.029,319.571 271.473,320.015 v6(279.971,320.015) ; 212.748,211.162 206.27,211.162 203.41,208.302 203.41,188.558 204.537,187.432 216.788,187.432 v6(217.238,186.982) ; v6(217.47,225.763) 217.444,225.788 217.444,226.848 217.744,227.148 234.979,227.148 238.806,230.975 246.545,230.975 257.95,242.379 v6(258.343,242.379)
  L12 (Sign) w0.12: v1(175.884,307.052) 175.433,306.601 175.433,304.483 175.87,304.047 181.47,304.047 183.799,301.717 187.401,301.717 187.495,301.81 201.779,301.81 207.968,308 207.968,311.117 208.318,311.467 v1(208.318,311.506)
  L3 (Sign) w0.2: v1(212.865,210.896) 214.02,212.052 216.22,212.052 218.91,214.742 218.91,224.322 v6(217.47,225.763) ; v2(215.392,159.2) 215.392,159.207 216.459,160.274 216.459,166.141 217.238,166.921 v6(217.238,186.982) ; v6(258.343,242.379) 260.113,242.379 279.732,261.999 279.732,319.775 v6(279.971,320.015)
PWR_ExtIO_INT0: R977.2 U35_I2C_Expander_PWR_Dist.16 | length 383.1
  L1 w0.2: U35_I2C_Expander_PWR_Dist.16@51.968,158.003 v2(53.291,158.003) ; R977.2@230.416,302.835 v1(230.416,303.596)
  L5 (Sign) w0.2: v6(129.991,178.892) 134.131,183.032 134.131,183.089 138.194,187.152 146.189,187.152 146.722,187.685 164.445,187.685 165.46,186.67 192.888,186.67 195.956,189.737 195.956,217.623 206.455,228.123 233.942,228.123 233.947,228.127 234.432,228.127 238.268,231.963 246.251,231.963 257.836,243.548 258.741,243.548 264.49,249.298 264.49,252.818 264.496,252.823 264.496,253.196 264.49,253.201 v6(264.49,253.543) ; v1(230.416,303.596) 231.051,302.961 231.051,295.722 231.912,294.861 260.486,294.861 260.9,294.448 v6(260.9,294.43)
  L3 (Sign) w0.2: v2(53.291,158.003) 55.089,156.205 58.397,156.205 59.614,154.988 65.217,154.988 65.339,154.988 65.547,154.78 66.194,154.133 68.018,154.133 76.437,154.133 77.292,154.988 113.993,154.988 122.579,163.573 122.579,169.019 130.682,177.122 130.682,178.201 v6(129.991,178.892) ; v6(260.9,294.43) 260.9,295.605 263.002,297.707 273.155,297.707 275.046,295.817 275.046,264.39 264.49,253.835 v6(264.49,253.543)
PWR_ExtIO_INT1: R976.2 U35_I2C_Expander_PWR_Dist.15 | length 367.9
  L1 w0.2: U35_I2C_Expander_PWR_Dist.15@51.968,157.353 v2(53.276,157.353) ; R976.2@244.05,302.785 244.509,302.785 244.716,302.577 v1(244.716,296.774)
  L5 (Sign) w0.2: v6(130.061,179.768) 133.895,183.603 134.22,183.603 138.07,187.452 146.065,187.452 146.598,187.985 164.569,187.985 165.585,186.97 192.764,186.97 195.656,189.862 195.656,217.747 206.331,228.423 233.818,228.423 233.823,228.427 234.308,228.427 238.144,232.263 246.126,232.263 257.712,243.848 258.616,243.848 263.969,249.201 v6(263.969,252.946) ; v1(244.716,296.774) 246.316,295.173 261.023,295.173 261.5,294.697 v6(261.5,294.458)
  L3 (Sign) w0.2: v2(53.276,157.353) 53.442,157.353 54.889,155.905 54.965,155.905 58.272,155.905 59.49,154.688 65.215,154.688 65.423,154.48 66.07,153.833 68.143,153.833 76.561,153.833 77.416,154.688 114.118,154.688 122.879,163.449 122.879,168.895 130.982,176.997 130.982,179.356 130.569,179.768 v6(130.061,179.768) ; v6(261.5,294.458) 261.5,295.781 263.126,297.407 273.031,297.407 274.746,295.692 274.746,264.712 263.969,253.936 v6(263.969,252.946)
PWR_ExtIO_INT2: R978.2 U35_I2C_Expander_PWR_CLK.15 | length 290.7
  L1 w0.2: v1(129.172,200.254) 129.179,200.26 U35_I2C_Expander_PWR_CLK.15@129.179,203.953 ; R978.2@231.78,302.785 v1(231.78,303.546)
  L5 (Sign) w0.2: v1(129.172,200.254) 129.172,197.561 137.181,189.552 145.195,189.552 145.728,190.085 165.439,190.085 166.454,189.07 191.894,189.07 193.556,190.731 193.556,218.617 205.461,230.523 232.948,230.523 232.953,230.527 233.438,230.527 237.274,234.363 245.256,234.363 256.842,245.948 257.746,245.948 260.312,248.514 v6(260.312,253.479) ; v1(231.78,303.546) 232.23,303.996 233.581,303.996 233.845,303.733 233.845,300.571 234.837,299.579 259.918,299.579 259.918,304.058 260.157,304.296 262.427,304.296 264.976,301.748 264.976,296.041 265.335,295.681 270.04,295.681 270.98,294.742 v6(271.084,294.742)
  L3 (Sign) w0.2: v6(260.312,253.479) 260.312,253.682 272.646,266.016 272.646,293.989 271.893,294.742 v6(271.084,294.742)
PWR_ExtIO_INT3: R979.2 U35_I2C_Expander_PWR_CLK.16 | length 284
  L1 w0.2: U35_I2C_Expander_PWR_CLK.16@129.828,203.953 129.828,199.813 v1(129.832,199.809) ; R979.2@244.152,311.363 v1(244.152,312.653)
  L5 (Sign) w0.2: v1(129.832,199.809) 129.832,197.325 137.305,189.852 145.071,189.852 145.604,190.385 165.563,190.385 166.579,189.37 191.77,189.37 193.256,190.856 193.256,218.742 205.337,230.822 232.824,230.822 232.829,230.827 233.314,230.827 237.15,234.663 245.132,234.663 256.718,246.248 257.447,246.248 259.794,248.595 259.794,252.521 259.791,252.524 v6(259.791,252.984) ; v1(244.152,312.653) 245.016,313.516 274.266,313.516 274.383,313.399 274.383,306.337 271.897,303.85 v6(271.897,293.314)
  L3 (Sign) w0.2: v6(259.791,252.984) 259.791,254.163 271.897,266.269 v6(271.897,293.314)
PWR_ExtIO_nReset: R755.1 U35_I2C_Expander_Main_Rst.27 U35_I2C_Expander_PWR_Dist.14 | length 195.8
  L1 w0.2: U35_I2C_Expander_PWR_Dist.14@51.043,156.428 51.742,156.428 v2(51.778,156.464)
  L5 (Sign) w0.2: v6(115.049,256.519) 116.194,257.663 117.467,257.663 118.186,258.383 v1(118.186,260.147)
  L3 (Sign) w0.2: v2(51.778,156.464) 52.502,156.464 53.361,155.605 58.148,155.605 59.366,154.388 65.091,154.388 65.946,153.533 76.685,153.533 77.54,154.388 114.242,154.388 123.345,163.491 123.345,168.937 125.3,170.891 131.282,176.873 131.282,180.367 130.991,180.657 125.618,180.657 124.498,181.778 124.498,183.557 113.771,194.284 113.771,221.645 115.622,223.496 115.622,248.812 115.049,249.385 v6(115.049,256.519)
  L16 w0.2: U35_I2C_Expander_Main_Rst.27@115.873,260.668 118.121,260.668 118.186,260.602 ; v1(118.186,260.147) 118.186,260.602 ; R755.1@120.119,260.68 120.041,260.602 118.186,260.602
PWR_OUT_20V: C347.2 C348.2 C352.2 C353.2 C371.2 C372.2 C373.2 C374.2 C375.2 C376.2 C391.1 C392.2 C396.2 C397.1 C400.2 C401.2 C402.2 C403.2 C404.2 C405.2 C432.1 C433.2 C437.2 C438.1 C441.2 C442.2 C443.2 C444.2 C445.2 C446.2 C766.1 C767.1 C768.1 C769.1 C770.2 C771.2 C772.2 C773.2 C774.2 C775.2 C776.2 C777.2 C778.2 C779.2 C780.2 C781.2 R266.2 R268.1 R285.1 R303.1 R612.2 R614.2 R621.2 R622.2 R628.2 R686.2 T5.5 T5.6 T5.7 T5.8 T6.5 T6.6 T6.7 T6.8 T9.5 T9.6 T9.7 T9.8 T10.5 T10.6 T10.7 T10.8 T13.5 T13.6 T13.7 T13.8 T15.5 T15.6 T15.7 T15.8 T17.5 T17.6 T17.7 T17.8 T19.5 T19.6 T19.7 T19.8 U48.1 U48.8 | length 193.9
  L1 w0.2: R303.1@55.203,215.537 56.918,215.537 57.493,214.962 58.214,214.962 58.83,214.962 C397.1@58.852,214.983
  L1 w0.3: R266.2@56.594,236.489 v1(57.315,236.489) ; v1(58.026,237.714) R268.1@58.792,237.714 ; v1(58.083,238.671) R612.2@58.792,238.671 ; v2(59.753,184.552) R285.1@59.753,184.57 ; v1(61.895,227.175) 61.895,230.419 R614.2@62.188,230.712 ; R621.2@65.137,184.269 v2(65.137,184.276) ; v2(65.175,174.97) R622.2@65.175,174.993 ; R628.2@69.132,199.783 69.132,198.528 v1(69.573,198.086)
  L1 w0.5: v1(35.693,158.137) C773.2@35.693,158.816 ; v1(36.624,158.137) C772.2@36.624,158.816 ; v1(37.531,158.137) C771.2@37.531,158.816 ; v1(38.538,158.137) C770.2@38.538,158.816 ; C780.2@52.066,210.593 v1(53.153,210.593) ; C780.2@52.066,211.317 v1(53.153,211.317) ; C779.2@52.066,212.488 v1(53.153,212.488) ; C779.2@52.066,213.212 v1(53.153,213.212) ; C778.2@52.066,214.297 v1(53.153,214.297) ; C778.2@52.066,215.021 v1(53.153,215.021) ; C777.2@52.067,216.111 v1(53.154,216.111) ; C777.2@52.066,216.835 v1(53.153,216.835) ; C776.2@52.066,217.856 v1(53.153,217.856) ; C776.2@52.066,218.58 v1(53.153,218.58) ; C775.2@52.066,219.678 v1(53.153,219.678) ; C775.2@52.066,220.402 v1(53.153,220.402) ; C774.2@52.066,221.492 v1(53.153,221.492) ; C774.2@52.066,222.216 v1(53.153,222.216) ; C781.2@56.629,198.134 v1(56.629,199.028) ; C392.2@58.13,226.088 v1(58.13,227.175) ; v1(58.214,213.896) 58.214,214.962 C397.1@58.214,214.983 ; C392.2@58.776,226.088 v1(58.776,227.175) ; v1(58.852,213.896) C397.1@58.852,214.983 ; C392.2@59.413,226.088 v1(59.413,227.175) ; v1(59.497,213.896) C397.1@59.497,214.983 ; C433.2@59.63,169.623 v1(59.63,170.71) ; C353.2@59.645,197.03 v1(59.645,198.117) ; v1(59.653,186.744) C438.1@59.653,187.831 ; C433.2@60.276,169.623 v1(60.276,170.71) ; v1(60.29,186.744) C438.1@60.29,187.831 ; C353.2@60.29,197.03 v1(60.29,198.117) ; C391.1@60.612,226.088 v1(60.612,227.175) ; v1(60.696,213.896) C396.2@60.696,214.983 ; C433.2@60.913,169.623 v1(60.913,170.71) ; C353.2@60.928,197.03 v1(60.928,198.117) ; v1(60.935,186.744) C438.1@60.935,187.831 ; C391.1@61.258,226.088 v1(61.258,227.175) ; v1(61.334,213.896) C396.2@61.334,214.983 ; C391.1@61.895,226.088 v1(61.895,227.175) ; v1(61.979,213.896) C396.2@61.979,214.983 ; C432.1@62.112,169.623 v1(62.112,170.71) ; C352.2@62.127,197.03 v1(62.127,198.117) ; v1(62.135,186.744) C437.2@62.135,187.831 ; C769.1@62.575,160.649 v1(62.575,161.736) ; C432.1@62.758,169.623 v1(62.758,170.71) ; v1(62.772,186.744) C437.2@62.772,187.831 ; C352.2@62.772,197.03 v1(62.772,198.117) ; C405.2@63.094,226.087 v1(63.094,227.174) ; v1(63.124,159.562) C769.1@63.124,160.649 ; v1(63.179,213.896) C402.2@63.179,214.983 ; C432.1@63.395,169.623 v1(63.395,170.71) ; C352.2@63.41,197.03 v1(63.41,198.117) ; v1(63.417,186.744) C437.2@63.417,187.831 ; C769.1@63.68,160.649 v1(63.68,161.736) ; C405.2@63.74,226.087 v1(63.74,227.174) ; v1(63.816,213.896) C402.2@63.816,214.983 ; v1(64.229,159.562) C769.1@64.229,160.649 ; C405.2@64.377,226.087 v1(64.377,227.174) ; v1(64.461,213.896) C402.2@64.461,214.983 ; C446.2@64.594,169.623 v1(64.594,170.71) ; C374.2@64.609,197.03 v1(64.609,198.117) ; v1(64.617,186.744) C443.2@64.617,187.831 ; C769.1@64.777,160.649 v1(64.777,161.736) ; C446.2@65.24,169.623 v1(65.24,170.71) ; v1(65.254,186.744) C443.2@65.254,187.831 ; C374.2@65.254,197.03 v1(65.254,198.117) ; C404.2@65.576,226.087 v1(65.576,227.174) ; v1(65.661,213.896) C401.2@65.661,214.983 ; C446.2@65.877,169.623 v1(65.877,170.71) ; C374.2@65.892,197.03 v1(65.892,198.117) ; v1(65.899,186.744) C443.2@65.899,187.831 ; C768.1@65.979,160.649 v1(65.979,161.736) ; C404.2@66.222,226.087 v1(66.222,227.174) ; v1(66.298,213.896) C401.2@66.298,214.983 ; v1(66.527,159.563) C768.1@66.527,160.649 ; C404.2@66.859,226.087 v1(66.859,227.174) ; v1(66.943,213.896) C401.2@66.943,214.983 ; C445.2@67.076,169.623 v1(67.076,170.71) ; C768.1@67.084,160.649 v1(67.084,161.736) ; C371.2@67.091,197.03 v1(67.091,198.117) ; v1(67.099,186.744) C442.2@67.099,187.831 ; v1(67.632,159.563) C768.1@67.632,160.649 ; C445.2@67.722,169.623 v1(67.722,170.71) ; v1(67.736,186.744) C442.2@67.736,187.831 ; C371.2@67.736,197.03 v1(67.736,198.117) ; C403.2@68.058,226.057 v1(68.058,227.144) ; v1(68.143,213.866) C400.2@68.143,214.953 ; C768.1@68.181,160.649 v1(68.181,161.736) ; C445.2@68.359,169.623 v1(68.359,170.71) ; C371.2@68.374,197.03 v1(68.374,198.117) ; v1(68.382,186.744) C442.2@68.382,187.831 ; C403.2@68.704,226.057 v1(68.704,227.144) ; v1(68.78,213.866) C400.2@68.78,214.953 ; C403.2@69.341,226.057 v1(69.341,227.144) ; C767.1@69.419,160.65 v1(69.419,161.737) ; v1(69.425,213.866) C400.2@69.425,214.953 ; C444.2@69.558,169.592 v1(69.558,170.679) ; C376.2@69.573,196.999 v1(69.573,198.086) ; v1(69.581,186.713) C441.2@69.581,187.8 ; v1(69.967,159.563) C767.1@69.967,160.65 ; C444.2@70.204,169.592 v1(70.204,170.679) ; v1(70.218,186.713) C441.2@70.218,187.8 ; C376.2@70.218,196.999 v1(70.218,198.086) ; C767.1@70.524,160.65 v1(70.524,161.737) ; C444.2@70.841,169.592 v1(70.841,170.679) ; C376.2@70.856,196.999 v1(70.856,198.086) ; v1(70.864,186.713) C441.2@70.864,187.8 ; v1(71.072,159.563) C767.1@71.072,160.65 ; C767.1@71.621,160.65 v1(71.621,161.737) ; v1(72.877,163.201) T15.8@73.964,163.201 ; v1(72.877,164.471) T15.7@73.964,164.471 ; v1(72.877,165.741) T15.6@73.964,165.741 ; v1(72.877,167.011) T15.5@73.964,167.011 ; C766.1@72.887,160.649 v1(72.887,161.736) ; v1(73.13,178.003) T13.8@74.217,178.003 ; v1(73.13,179.273) T13.7@74.217,179.273 ; v1(73.13,180.543) T13.6@74.217,180.543 ; v1(73.13,181.813) T13.5@74.217,181.813 ; v1(73.435,159.562) C766.1@73.435,160.649 ; C766.1@73.992,160.649 v1(73.992,161.736) ; v1(74.017,193.746) T19.8@75.104,193.746 ; v1(74.017,195.016) T19.7@75.104,195.016 ; v1(74.017,196.286) T19.6@75.104,196.286 ; v1(74.017,197.556) T19.5@75.104,197.556 ; v1(74.086,214.079) T17.8@75.173,214.079 ; v1(74.086,215.349) T17.7@75.173,215.349 ; v1(74.086,216.619) T17.6@75.173,216.619 ; v1(74.086,217.889) T17.5@75.173,217.889 ; v1(74.54,159.562) C766.1@74.54,160.649 ; T6.8@75.072,249.548 v1(75.072,250.635) ; v1(75.078,220.589) T10.5@75.078,221.676 ; C766.1@75.088,160.649 v1(75.088,161.736) ; T6.7@76.342,249.548 v1(76.342,250.635) ; v1(76.348,220.589) T10.6@76.348,221.676 ; T6.6@77.612,249.548 v1(77.612,250.635) ; v1(77.618,220.589) T10.7@77.618,221.676 ; T6.5@78.882,249.548 v1(78.882,250.635) ; v1(78.888,220.589) T10.8@78.888,221.676 ; v1(82.072,220.589) T9.5@82.072,221.676 ; T5.8@82.072,249.548 v1(82.072,250.635) ; v1(83.342,220.589) T9.6@83.342,221.676 ; T5.7@83.342,249.548 v1(83.342,250.635) ; v1(84.612,220.589) T9.7@84.612,221.676 ; T5.6@84.612,249.548 v1(84.612,250.635) ; v1(85.091,256.835) C348.2@85.091,257.922 ; v1(85.728,256.835) C348.2@85.728,257.922 ; v1(85.882,220.589) T9.8@85.882,221.676 ; T5.5@85.882,249.548 v1(85.882,250.635) ; v1(86.374,256.835) C348.2@86.374,257.922 ; v1(87.573,256.835) C347.2@87.573,257.922 ; v1(88.21,256.835) C347.2@88.21,257.922 ; v1(88.856,256.835) C347.2@88.856,257.922 ; v1(90.055,256.835) C372.2@90.055,257.922 ; v1(90.692,256.835) C372.2@90.692,257.922 ; v1(91.338,256.835) C372.2@91.338,257.922 ; v1(92.537,256.835) C375.2@92.537,257.922 ; v1(93.174,256.835) C375.2@93.174,257.922 ; v1(93.82,256.835) C375.2@93.82,257.922 ; v1(95.019,256.804) C373.2@95.019,257.891 ; v1(95.656,256.804) C373.2@95.656,257.891 ; v1(96.302,256.804) C373.2@96.302,257.891
  L3 (Sign) w0.3: v1(59.653,186.744) 59.753,186.644 v2(59.753,184.552) ; v2(65.137,184.276) 65.254,184.393 v1(65.254,186.744) ; v2(65.175,174.97) 65.24,174.904 v1(65.24,170.71)
  other v1: 74.782,163.22 76.034,163.22 77.285,163.22 74.782,164.471 76.034,164.471 77.285,164.471 74.782,165.723 76.034,165.723 77.285,165.723 74.782,166.975 76.034,166.975 77.285,166.975 75.035,178.022 76.287,178.022 77.539,178.022 75.035,179.273 76.287,179.273 77.539,179.273 75.035,180.525 76.287,180.525 77.539,180.525 75.035,181.777 76.287,181.777 77.539,181.777 50.447,190.32 49.788,191.057 49.2,191.821 50.448,191.822 75.922,193.764 77.173,193.764 78.425,193.764 75.922,195.016 77.173,195.016 78.425,195.016 49.2,196.145 50.448,196.145 75.922,196.267 77.173,196.267 78.425,196.267 49.788,196.91 75.922,197.519 77.173,197.519 78.425,197.519 50.447,197.647 75.991,214.097 77.243,214.097 78.495,214.097 75.991,215.349 77.243,215.349 78.495,215.349 75.991,216.6 77.243,216.6 78.495,216.6 75.991,217.852 77.243,217.852 78.495,217.852 75.114,222.494 76.366,222.494 77.618,222.494 78.869,222.494 82.108,222.494 83.36,222.494 84.612,222.494 85.863,222.494 75.114,223.745 76.366,223.745 77.618,223.745 78.869,223.745 82.108,223.745 83.36,223.745 84.612,223.745 85.863,223.745 75.114,224.997 76.366,224.997 77.618,224.997 78.869,224.997 82.108,224.997 83.36,224.997 84.612,224.997 85.863,224.997 75.09,246.226 76.342,246.226 77.593,246.226 78.845,246.226 82.09,246.226 83.342,246.226 84.593,246.226 85.845,246.226 75.09,247.478 76.342,247.478 77.593,247.478 78.845,247.478 82.09,247.478 83.342,247.478 84.593,247.478 85.845,247.478 75.09,248.73 76.342,248.73 77.593,248.73 78.845,248.73 82.09,248.73 83.342,248.73 84.593,248.73 85.845,248.73
  other v3: 49.027,193.583 49.027,194.383
PWR_PowerAlert0: R974.2 U35_I2C_Expander_PWR_Dist.17 U64_U_Pomiar_pradu_napiecia_1.3 | length 400.6
  L1 w0.2: U64_U_Pomiar_pradu_napiecia_1.3@32.245,157.414 32.245,156.197 v2(32.258,156.185) ; U35_I2C_Expander_PWR_Dist.17@51.968,158.653 51.988,158.672 52.799,158.672 v1(52.827,158.699) ; R974.2@235.87,302.785 236.203,302.785 236.449,302.539 v1(236.449,297.955)
  L5 (Sign) w0.2: v1(52.827,158.699) 52.827,158.044 57.538,153.332 110.459,153.332 119.883,162.756 119.883,170.617 120.757,171.491 124.478,171.491 124.595,171.608 124.595,176.381 129.07,180.856 129.07,183.133 131.385,185.448 135.217,185.448 137.821,188.052 145.816,188.052 146.349,188.585 164.818,188.585 165.833,187.57 192.516,187.57 195.056,190.11 195.056,217.996 206.082,229.023 233.57,229.023 233.574,229.027 234.06,229.027 237.895,232.863 245.878,232.863 257.463,244.448 258.368,244.448 262.865,248.945 v6(262.865,252.908) ; v1(236.449,297.955) 244.407,297.955 244.712,298.26 246.782,296.189 260.431,296.189 262.116,294.505 v6(262.116,294.458)
  L3 (Sign) w0.2: v2(32.258,156.185) 33.218,155.224 45.769,155.224 46.787,156.243 50.711,156.243 51.765,157.297 51.765,157.8 52.665,158.699 v1(52.827,158.699) ; v6(262.116,294.458) 262.13,294.472 262.13,294.822 264.116,296.807 272.782,296.807 274.146,295.444 274.146,264.961 262.865,253.68 v6(262.865,252.908)
PWR_PowerAlert1: R975.2 U35_I2C_Expander_PWR_Dist.18 U64_U_Pomiar_pradu_napiecia_2.3 | length 441.5
  L1 w0.2: U35_I2C_Expander_PWR_Dist.18@51.968,159.303 51.987,159.322 53.258,159.322 v1(53.276,159.341) ; R975.2@233.143,302.785 v1(233.143,303.546)
  L5 (Sign) w0.2: v1(53.276,159.341) 53.276,158.018 57.663,153.632 110.335,153.632 119.583,162.88 119.583,170.828 120.637,171.882 124.178,171.882 124.295,171.999 124.295,176.53 128.753,180.988 128.753,183.24 131.261,185.748 135.092,185.748 137.697,188.352 145.692,188.352 146.225,188.885 164.942,188.885 165.957,187.87 192.391,187.87 194.756,190.234 194.756,218.12 205.958,229.323 233.445,229.323 233.45,229.327 233.935,229.327 237.771,233.163 245.754,233.163 257.339,244.748 258.244,244.748 262.395,248.899 v6(262.395,253.403) ; v1(233.143,303.546) 233.426,303.263 233.426,300.016 234.233,299.209 245.184,299.209 247.569,296.824 260.386,296.824 262.725,294.486 v6(262.725,294.439)
  L3 (Sign) w0.2: v6(262.395,253.403) 262.395,253.634 273.846,265.085 273.846,295.32 272.658,296.507 264.293,296.507 262.725,294.939 v6(262.725,294.439)
  L16 w0.12: U64_U_Pomiar_pradu_napiecia_2.3@31.298,206.235 31.298,205.66 31.488,205.47 31.488,205.444 33.783,203.149 34.624,203.149 36.25,201.523 36.25,177.535 36.624,177.161 44.59,177.161 45.101,176.65 45.101,173.412 45.809,172.704 45.809,168.153 45.789,168.133 48.859,165.063 51.398,165.063 51.422,165.039
  L16 w0.2: 51.422,165.039 52.908,163.553 52.908,159.709 v1(53.276,159.341)
PWR_Switch1_En: U6.A2 U35_I2C_Expander_PWR_Dist.28 | length 6
  L1 w0.2: U35_I2C_Expander_PWR_Dist.28@47.143,162.178 47.143,164.808 48.921,166.586 48.921,167.363 49.006,167.448 U6.A2@49.006,167.456
PWR_Switch1_Flag: R29.1 U6.A3 U35_I2C_Expander_PWR_Dist.1 | length 11.5
  L1 w0.12: R29.1@44.071,166.762 44.071,165.956 45.434,164.593 v7@45.434,164.584 ; v7@45.439,164.579 45.495,164.523 45.495,161.368 45.609,161.253 U35_I2C_Expander_PWR_Dist.1@46.218,161.253 ; v7(45.444,164.584) 46.494,164.584 48.606,166.695 U6.A3@48.606,167.456
PWR_Switch2_En: U7.A2 U35_I2C_Expander_PWR_Dist.2 | length 23.7
  L1 w0.12: v7(45.05,164.365) 45.05,161.396 45.843,160.603 U35_I2C_Expander_PWR_Dist.2@46.218,160.603
  L1 w0.2: U7.A2@44.428,180.434 v7(44.428,181.354)
  L3 (Sign) w0.12: v7(44.428,181.354) 44.428,178.084 44.628,177.884 44.628,176.363 44.401,176.136 44.401,174.491 43.298,173.388 43.298,166.118 v7(45.05,164.365)
PWR_Switch2_Flag: R30.1 U7.A3 U35_I2C_Expander_PWR_Dist.3 | length 27.7
  L1 w0.12: v7(44.424,164.271) 44.424,163.338 44.424,160.268 44.739,159.953 U35_I2C_Expander_PWR_Dist.3@46.218,159.953
  L1 w0.2: v7(43.622,181.901) 43.624,181.899 44.739,181.899 45.128,181.51 45.128,181.038 44.828,180.738 U7.A3@44.828,180.434
  L3 (Sign) w0.2: v7(43.622,181.901) 42.516,180.796 42.516,173.775 43.021,173.271 43.021,165.675 v7(44.424,164.271)
RAM_DDR4_VTT: C722.2 C723.2 R31.2 R32.2 R33.2 R34.2 R35.2 R36.2 R37.2 R38.2 R39.2 R40.2 R41.2 R42.2 R43.2 R44.2 R45.2 R46.2 R47.2 R48.2 R49.2 R50.2 R51.2 R53.2 R55.2 R57.2 R59.2 R689.1 U73.8 | length 35.4
  L1 w0.25: v1(156.302,341.788) 157.303,341.788 R48.2@157.837,342.322 ; v1(156.593,333.611) R46.2@157.837,333.611 ; v1(156.593,334.7) R59.2@157.837,334.7 ; v1(156.593,335.789) R51.2@157.837,335.789 ; v1(156.593,336.878) R57.2@157.837,336.878 ; v1(156.593,337.967) R37.2@157.837,337.967 ; v1(156.593,339.056) R34.2@157.837,339.055 ; v1(156.593,340.144) R33.2@157.837,340.144 ; v1(156.593,341.233) R41.2@157.837,341.233 ; v1(156.807,344.475) 156.807,343.992 157.388,343.411 R45.2@157.837,343.411 ; v1(157.759,345.986) 157.759,344.578 R53.2@157.837,344.5 ; R38.2@162.769,345.7 v1(162.769,346.944) ; R44.2@163.977,345.7 v1(163.977,346.944) ; R55.2@165.186,345.7 v1(165.186,346.944) ; R40.2@166.395,345.7 v1(166.395,346.944) ; R36.2@167.603,345.7 v1(167.603,346.944) ; R49.2@168.812,345.7 v1(168.812,346.944) ; R32.2@170.02,345.7 v1(170.02,346.944) ; R39.2@171.229,345.7 v1(171.229,346.944) ; R42.2@172.438,345.7 v1(172.438,346.944) ; R35.2@173.646,345.7 v1(173.646,346.944) ; R31.2@174.855,345.7 v1(174.855,346.944) ; R50.2@176.064,345.7 v1(176.063,346.944) ; R47.2@177.272,345.7 v1(177.272,346.944) ; R43.2@178.481,345.7 v1(178.481,346.944)
  L1 w0.3: U73.8@151.644,349.985 v1(152.387,349.985) ; C722.2@153.683,349.532 v1(153.683,350.275) ; C723.2@154.673,349.532 v1(154.673,350.275) ; R689.1@160.795,347.112 v1(161.538,347.112)
RAM_Vcc1V2: C36.2 C220.1 C222.1 C223.2 C224.2 C225.2 C226.2 C227.2 C228.2 C229.2 C230.2 C231.2 C232.2 C233.2 C234.2 C235.2 C236.2 C237.2 C238.2 C239.2 C240.2 C241.2 C242.2 C244.1 C246.1 C247.2 C248.2 C249.2 C250.2 C251.2 C252.2 C253.2 C254.2 C255.2 C256.2 C257.2 C258.2 C259.2 C260.2 C261.2 C262.2 C263.2 C264.2 C265.2 C266.2 C741.2 C760.1 C761.2 R58.2 R165.2 R166.2 R169.2 R171.2 R297.1 R448_U_Pomiar_pradu_napiecia_4.2 R695.2 U1.A6 U1.B8 U1.C6 U1.D8 U1.E6 U1.G6 U1.J6 U1.K7 U1.L6 U1.N6 U1.R6 U1.T18 U1.T20 U1.T21 U1.U6 U8.A1 U8.A6 U8.B3 U8.B6 U8.C1 U8.D1 U8.D6 U8.F2 U8.F5 U8.G1 U8.G4 U8.G6 U8.J1 U8.J2 U8.J5 U8.J6 U8.L1 U8.L6 U8.R1 U8.T6 U9.A1 U9.A6 U9.B3 U9.B6 U9.C1 U9.D1 U9.D6 U9.F2 U9.F5 U9.G1 U9.G4 U9.G6 U9.J1 U9.J2 U9.J5 U9.J6 U9.L1 U9.L6 U9.R1 U9.T6 U10.A1 U10.A6 U10.B3 U10.B6 U10.C1 U10.D1 U10.D6 U10.F2 U10.F5 U10.G1 U10.G4 U10.G6 U10.J1 U10.J2 U10.J5 U10.J6 U10.L1 U10.L6 U10.R1 U10.T6 U11.A1 U11.A6 U11.B3 U11.B6 U11.C1 U11.D1 U11.D6 U11.F2 U11.F5 U11.G1 U11.G4 U11.G6 U11.J1 U11.J2 U11.J5 U11.J6 U11.L1 U11.L6 U11.R1 U11.T6 U64_U_Pomiar_pradu_napiecia_4.8 U64_U_Pomiar_pradu_napiecia_4.9 | length 237.2
  L1 w0.2: R448_U_Pomiar_pradu_napiecia_4.2@106.904,169.038 106.904,167.422 107.266,167.06 U64_U_Pomiar_pradu_napiecia_4.9@116.449,167.06 ; R448_U_Pomiar_pradu_napiecia_4.2@112.144,168.859 112.693,168.311 113.902,168.311 114.653,167.56 U64_U_Pomiar_pradu_napiecia_4.8@116.449,167.56 ; C225.2@174.624,335.839 C225.2@174.642,335.856 ; v1(189.4,334.057) v1@189.4,334.064 ; v1(198.412,328.613) 198.964,328.06 U8.A6@200.457,328.06 ; v1(199.479,328.887) 200.43,328.887 U8.B6@200.457,328.86 ; v1(199.657,330.225) 199.892,330.46 U8.D6@200.457,330.46 ; U8.G4@202.057,332.86 202.314,332.603 ccw(c202.455,332.745) 202.454,332.545 v1(202.862,332.545) ; U8.J2@206.057,334.46 206.18,334.337 206.734,334.337 U8.J1@206.857,334.46 206.866,334.46 207.27,334.864 v1(207.279,334.864) ; U8.A1@206.857,328.06 206.878,328.039 v1(207.752,328.039) ; U8.C1@206.857,329.66 v1(207.615,329.66) ; U8.D1@206.857,330.46 v1(207.615,330.46) ; U8.G1@206.857,332.86 206.867,332.87 207.506,332.87 v1(207.516,332.88) ; U8.L1@206.857,336.06 v1(207.261,336.464) ; U8.R1@206.857,339.26 v1(207.261,339.664)
  L1 w0.25: v1(154.724,331.965) C36.2@155.431,331.965 C36.2@155.566,331.965 ; v1(160.528,339.636) 162.066,339.636 R58.2@162.46,339.242 ; 165.251,336.464 165.661,336.464 v1(165.667,336.47) ; v1(165.672,328.464) U9.A6@166.076,328.06 ; v1(165.672,329.264) U9.B6@166.076,328.86 ; v1(165.672,330.864) U9.D6@166.076,330.46 ; v1(165.672,333.264) U9.G6@166.076,332.86 ; v1(165.672,334.864) U9.J6@166.076,334.46 U9.J5@166.876,334.46 ; v1@165.672,336.464 U9.L6@166.076,336.06 ; v1(165.672,340.464) U9.T6@166.076,340.06 ; U9.F5@166.876,332.06 v1(167.279,332.464) ; v1(167.272,333.264) U9.G4@167.676,332.86 ; v1(170.401,328.457) 170.472,328.457 U9.B3@170.876,328.86 ; v1(171.272,334.056) U9.J2@171.676,334.46 ; U9.F2@171.676,332.06 U9.G1@172.476,332.86 172.876,333.261 v1@172.908,333.261 ; U9.A1@172.476,328.06 v1(172.879,327.657) ; U9.C1@172.476,329.66 v1(172.879,329.257) ; U9.D1@172.476,330.46 v1(172.879,330.057) ; U9.J1@172.476,334.46 v1(172.879,334.864) ; v1(172.908,333.246) v1@172.908,333.261 ; v1@172.923,333.261 v1@172.908,333.261 ; v1(176.95,336.055) U11.L6@177.521,336.055 ; v1(177.133,327.657) U11.A6@177.536,328.06 ; v1(177.133,328.457) U11.B6@177.536,328.86 ; v1(177.133,330.057) U11.D6@177.536,330.46 ; v1(177.133,332.457) U11.G6@177.536,332.86 ; v1(177.133,334.057) U11.J6@177.536,334.46 ; v1(177.133,340.464) U11.T6@177.536,340.06 ; v1(177.933,331.657) U11.F5@178.336,332.06 ; v1(177.933,334.057) U11.J5@178.336,334.46 ; U11.G4@179.136,332.86 v1(179.54,332.457) ; v1(181.849,328.457) 181.933,328.457 U11.B3@182.336,328.86 ; v1(182.733,331.657) U11.F2@183.136,332.06 ; v1(182.733,334.057) U11.J2@183.136,334.46 ; U11.A1@183.936,328.06 v1(184.507,328.057) ; U11.C1@183.936,329.66 v1(184.507,329.66) ; U11.D1@183.936,330.46 v1(184.507,330.46) ; U11.G1@183.936,332.86 183.941,332.856 184.458,332.856 cw(c184.458,332.606) 184.469,332.856 v1(184.498,332.854) ; U11.J1@183.936,334.46 184.478,334.46 184.611,334.593 v1(184.678,334.593) ; U11.L1@183.936,336.06 184.368,335.628 v1(185.162,335.628) ; v1(188.593,327.657) U10.A6@188.997,328.06 ; v1(188.593,328.457) U10.B6@188.997,328.86 ; v1(188.593,330.864) U10.D6@188.997,330.46 ; v1(188.593,333.264) U10.G6@188.997,332.86 ; v1(188.593,336.464) U10.L6@188.997,336.06 ; v1(188.593,340.464) U10.T6@188.997,340.06 ; U10.J6@188.997,334.46 v1(189.4,334.057) ; v1(189.393,332.464) U10.F5@189.797,332.06 ; v1@189.4,334.064 U10.J5@189.797,334.46 ; U10.G4@190.597,332.86 v1(191,332.457) ; U10.F2@194.597,332.06 U10.G1@195.397,332.86 ; U8.B3@205.257,328.86 v1(205.661,328.457)
  L1 w0.254: U1.K7@171.463,294.539 v1(171.397,294.539) cw(c171.397,293.539) 171.874,294.418 cw(c171.752,294.196) 171.976,294.315 ccw(c172.397,294.539) 172.173,294.118 cw(c172.053,293.894) 172.277,294.015 cw(c171.397,293.539) U1.L6@172.397,293.539 ; U1.N6@174.397,293.539 174.422,293.539 174.91,294.027 175.91,294.027 v1(176.397,293.539) ; v1(177.91,294.031) 177.91,294.029 178.397,293.542 U1.U6@178.397,293.539 ; v1(180.759,343.56) C220.1@180.759,344.785 C220.1@180.759,344.92 ; v1(198.031,332.524) 200.121,332.524 U8.G6@200.457,332.86 U8.F5@201.257,332.06 ; v1(199.733,342.913) 199.733,342.354 200.203,341.884 ; C760.1@200.088,345.64 200.203,345.526 200.203,341.884 ; U8.L6@200.457,336.06 199.439,336.06 198.847,335.469 v1(198.847,334.75) 199.326,334.75 199.615,334.46 U8.J6@200.457,334.46 200.727,334.73 200.987,334.73 U8.J5@201.257,334.46 ; U8.T6@200.457,340.06 200.457,341.63 200.203,341.884 ; U8.F2@206.057,332.06 U8.G1@206.857,332.86 ; v1(207.261,339.664) 207.861,339.664 208.307,339.217 209.182,339.217 v1(209.245,339.28)
  L1 w0.3: U1.J6@170.397,293.539 170.82,293.963 ccw(c170.608,294.175) v1(170.884,294.058) ; v1(193.1,328.448) 193.138,328.486 193.39,328.486 193.764,328.86 U10.B3@193.797,328.86 ; U10.J2@194.597,334.46 195.008,334.049 195.39,334.453 U10.J1@195.397,334.46 v1@195.644,334.213 ; U10.A1@195.397,328.06 196.956,328.06 v1(198.022,329.127) ; U10.C1@195.397,329.66 195.643,329.66 196.494,330.512 v1(196.494,331.178) 196.114,331.178 U10.D1@195.397,330.46 ; U10.G1@195.397,332.86 195.441,332.816 195.791,332.816 196.812,331.795 v1(196.812,331.762) ; U10.L1@195.397,336.06 195.906,336.57 196.472,336.57 196.682,336.57 197.039,336.927 v2(197.039,340.639) ; U10.R1@195.397,339.26 195.988,339.852 v2(196.026,339.852)
  L1 w0.4: v1(62.14,174.104) R297.1@62.14,174.951 ; C261.2@163.287,327.914 165.122,327.914 v1(165.672,328.464) ; C247.2@163.306,329.197 165.605,329.197 v1(165.672,329.264) ; C249.2@163.422,333.518 163.966,333.518 164.22,333.264 v1(165.672,333.264) ; C263.2@163.43,334.638 165.446,334.638 v1(165.672,334.864) ; C253.2@163.435,335.758 164.448,335.758 165.154,336.464 165.251,336.464 ; C229.2@163.435,336.878 v1(164.107,336.878) ; C223.2@163.441,331.241 164.493,331.241 164.87,330.864 v1(165.672,330.864) ; U9.L1@172.476,336.06 174.402,336.06 C225.2@174.624,335.839 ; U9.R1@172.476,339.26 172.604,339.26 172.683,339.339 172.702,339.339 172.949,339.585 172.966,339.585 173.469,340.089 173.469,341.528 173.507,341.528 174.026,342.048 v1(174.053,342.048) ; v1(172.879,330.057) 173.673,330.057 174.14,329.59 C265.2@174.494,329.59 ; v1@174.054,342.113 C244.1@174.625,342.113 ; U11.R1@183.936,339.26 185.015,340.339 v1(185.015,340.52) ; v1(184.507,330.46) 184.653,330.606 C252.2@186.186,330.606 ; v1(184.678,334.593) 184.804,334.718 C235.2@185.999,334.718 ; v1(185.162,335.628) C239.2@186.013,335.628 ; C238.2@186.966,329.527 187.523,329.527 v1(188.593,328.457) ; C230.2@186.991,331.61 187.262,331.61 188.007,330.864 v1(188.593,330.864) ; R171.2@187.048,336.842 187.543,336.842 187.922,336.464 v1(188.593,336.464) ; C234.2@187.049,333.686 188.171,333.686 v1(188.593,333.264) ; C246.1@187.101,340.514 188.543,340.514 v1(188.593,340.464) ; v1@195.644,334.213 v1(195.77,334.213) 196.101,334.213 C248.2@196.66,333.654 ; 197.039,336.927 197.08,336.886 C254.2@197.87,336.886
  L1 w0.5: v1(161.262,287.363) 161.262,286.969 ccw(c161.503,286.969) C761.2@161.332,286.798 161.347,286.783 C741.2@162.238,286.783 ; v1(172.879,334.864) 173.649,334.864 C225.2@174.624,335.839 ; v1@172.923,333.261 C264.2@174.615,333.261 ; R165.2@175.427,337.95 175.427,336.951 175.5,336.878 176.127,336.878 v1(176.95,336.055) ; v1(191.902,344.233) 191.916,344.22 R169.2@191.916,343.311 ; C222.1@193.055,342.487 v1(193.6,342.487) ; v1(209.245,339.28) 209.657,338.869 R166.2@209.657,338.277
  L5 (Sign) w0.4: v1(62.14,174.104) 63.118,173.126 69.063,173.126 69.634,172.555 83.138,172.555 83.976,171.717 99.848,171.717 v9(101.258,170.307)
  L3 (Sign) w0.3: v1(194.323,342.976) 194.694,342.605 194.694,341.572 195.22,341.046 195.567,341.046 196.026,340.587 v2(196.026,339.852) v2@196.026,339.831 ; v1(195.6,341.863) 196.513,341.863 197.039,341.336 v2(197.039,340.639)
  L16 w0.2: v1@199.452,328.887 v1(199.479,328.887)
  L16 w0.25: C250.2@175.581,333.362 175.581,333.807 175.831,334.057 v1(177.133,334.057)
  L16 w0.4: v1(184.498,332.854) 184.535,332.858 cw(c184.576,332.46) 184.576,332.86 185.401,332.86 185.909,332.353 C227.2@186.376,332.353 ; v1(184.507,329.66) 184.869,330.022 C256.2@186.376,330.022 ; C242.2@187.13,333.518 187.582,333.518 187.836,333.264 v1(188.593,333.264) ; C255.2@187.156,331.188 187.658,331.188 187.982,330.864 v1(188.593,330.864) ; v1(195.77,334.213) 196.177,333.807 C236.2@196.841,333.807 ; v1(196.494,331.178) 196.707,330.966 C228.2@196.707,330.2 ; C260.2@196.669,329.24 197.909,329.24 v1(198.022,329.127) ; C266.2@196.707,328.06 197.86,328.06 v1(198.412,328.613) ; C237.2@197.621,334.62 198.717,334.62 v1(198.847,334.75) ; v1(198.031,332.524) 198.59,333.083 C232.2@199.787,333.083 ; v1(199.657,330.225) 200.702,331.271 C233.2@200.702,332.092
  L16 w0.5: v1(172.879,330.057) 172.98,329.956 C251.2@174.666,329.956 ; v1(172.879,334.864) 174.409,334.864 C241.2@174.604,335.06 ; C257.2@175.446,327.685 175.933,327.685 175.962,327.657 v1(177.133,327.657) ; C262.2@175.446,328.821 176.067,328.821 176.431,328.457 v1(177.133,328.457) ; C226.2@175.446,331.091 176.097,331.091 176.663,331.657 v1(177.933,331.657) ; C259.2@175.446,332.227 176.902,332.227 v1(177.133,332.457) ; C258.2@196.567,332.118 196.567,332.007 v1(196.812,331.762) ; C231.2@197.621,335.42 198.177,335.42 v1(198.847,334.75)
  other v1: 162.397,293.539 164.397,293.539 166.397,293.539 168.397,293.539 163.397,295.539 165.397,295.539 177.397,305.539 177.397,307.539 177.397,308.539
  other v9: 112.047,170.186 110.249,170.206 108.45,170.226 104.854,170.267 106.652,170.246 103.056,170.287 111.158,171.095 109.36,171.115 105.763,171.156 107.561,171.135 103.965,171.176 102.167,171.196
RAM_VrefA: C221.1 R166.1 R168.1 U8.M1 | length 4.3
  L1 w0.2: U8.M1@206.857,336.86 207.261,337.264
  L1 w0.3: 207.261,337.264 208.716,337.264 R168.1@208.744,337.236 ; R166.1@208.757,338.277 208.757,337.264 208.757,336.153 C221.1@208.804,336.106
RAM_VrefB: C243.1 R169.1 R170.1 U10.M1 | length 11.4
  L1 w0.2: C243.1@189.878,342.471 190.901,342.471 191.916,342.471 192.77,341.617 194.828,341.617 196.417,340.028 196.417,337.357 195.98,336.92 195.761,336.92 195.744,336.902 195.439,336.902 U10.M1@195.397,336.86
RAM_VrefC: C219.1 R165.1 R167.1 U9.M1 | length 4.8
  L1 w0.2: U9.M1@172.476,336.86 173.192,336.86 174.281,337.95 174.527,337.95 174.581,338.004 R167.1@174.581,340.24
RAM_VrefD: C245.1 R171.1 R172.1 U11.M1 | length 4
  L1 w0.2: U11.M1@183.936,336.86 183.954,336.842 186.098,336.842 R172.1@186.098,338.696
RefClk_Si53323_N: R253.1 R255.2 U31.7 | length 2.9
  L1 w0.101: U31.7@50.593,397.699 50.593,396.222 ccw(c50.847,396.222) R255.2@50.847,395.968 R253.1@50.847,394.952
RefClk_Si53323_P: C341.1 R252.1 R254.2 U31.6 | length 3.8
  L1 w0.101: C341.1@49.762,394.059 C341.1@49.783,394.081 ; C341.1@49.793,394.071 ccw(c49.793,394.135) 49.856,394.135 R252.1@49.856,394.947 ; R252.1@49.843,394.952 R254.2@49.843,395.968 ccw(c49.843,396.218) 50.093,396.218 U31.6@50.093,397.699
RESET_N: R712.1 R713.2 U39.43 | length 221.5
  L1 w0.2: v1(152.434,274.807) 153.302,273.939 169.012,273.939 170.777,275.704 v1(171.869,275.704)
  L5 (Sign) w0.2: v1(108.049,274.477) 108.049,273.548 108.446,273.152 117.069,273.152 117.394,273.477 119.016,273.477 119.71,272.783 123.279,272.783 123.821,273.326 141.917,273.326 143.343,274.752 v1(145.542,274.752) ; v1(171.869,275.704) 171.869,275.713 172.127,275.971 v12(172.127,280.553) ; v12(207.011,278.201) 207.011,279.518 205.162,281.367 205.162,289.123 210.028,293.989 216.521,293.989 216.977,293.533 220.762,293.533 v1(220.815,293.586)
  L12 (Sign) w0.2: v1(220.815,293.586) 221.336,294.107 223.826,294.107 228.321,298.601 228.321,309.293 229.483,310.455 236.974,310.455 265.619,339.1 v1(265.619,349.616)
  L3 (Sign) w0.2: v12(172.127,280.553) 172.577,281.003 180.508,281.003 181.904,279.608 191.919,279.608 192.518,279.009 193.693,279.009 194.501,278.201 v12(207.011,278.201)
  L14 (Sign) w0.2: v1(145.542,274.752) 145.597,274.807 v1(152.434,274.807) v1@152.489,274.862
  L16 w0.12: v1(108.049,274.477) U39.43@108.049,275.125
  L16 w0.2: R713.2@265.532,350.344 265.619,350.256 v1(265.619,349.616)
  L16 w0.4: R712.1@264.008,350.271 264.08,350.344 R713.2@265.532,350.344
RESETB: U45.27 U74.4 | length 207.9
  L5 (Sign) w0.12: v1(54.495,351.248) 54.795,350.948 66.019,350.948 66.576,350.391 70.008,350.391 70.756,351.139 124.784,351.139 125.688,350.234 v12(125.856,350.234) ; v12(138.07,352.146) 174.536,352.146 v12(175.016,352.626) ; v12(182.796,357.751) 186.344,357.751 186.821,358.229 201.246,358.229 202.465,357.01 212.754,357.01 216.738,353.026 233.887,353.026 v1(234.886,354.025)
  L3 (Sign) w0.2: v12(125.856,350.234) 134.632,350.234 136.544,352.147 v12(138.07,352.146) v12(138.07,352.146) ; v12(175.016,352.626) 180.142,357.751 v12(182.796,357.751)
  L16 w0.12: U45.27@54.355,349.541 54.355,351.005 54.495,351.145 v1(54.495,351.248) ; v1(234.886,354.025) 244.218,354.025 245.201,353.041 251.015,353.041 251.985,352.071 U74.4@251.985,351.114
RF_SYSREF_TO_FPGA_PCIE0_N: J1_PCIE0.48 U1.AK11 | length 153.2
  L1 w0.1: v3(190.884,298.052) 190.884,298.027 U1.AK11@191.397,298.539
  L12 (Sign) w0.081: v1(147.037,365.176) ccw(c147.037,365.016) 146.878,365.016 146.878,357.107 ccw(c147.383,357.107) 147.383,356.601 209.918,356.601 cw(c209.918,355.872) 210.648,355.872 210.648,354.889 210.648,299.066 cw(c210.087,299.066) 210.087,298.505 194.073,298.505 190.804,298.505 ccw(c190.804,298.2) 190.499,298.2 ccw(c190.672,298.2) 190.672,298.027 190.697,298.052 v3(190.884,298.052)
  L16 w0.101: v1(147.037,365.176) 147.037,366.892 cw(c147.137,366.892) J1_PCIE0.48@147.137,366.992
RF_SYSREF_TO_FPGA_PCIE0_P: J1_PCIE0.50 U1.AJ11 | length 153.1
  L1 w0.1: v3(189.86,298.057) 189.915,298.057 U1.AJ11@190.397,298.539
  L12 (Sign) w0.081: v1(146.437,365.176) cw(c146.437,365.016) 146.597,365.016 146.597,357.107 ccw(c147.383,357.107) 147.383,356.32 209.918,356.32 cw(c209.918,355.872) 210.367,355.872 210.367,354.889 210.367,299.066 cw(c210.087,299.066) 210.087,298.786 194.073,298.786 190.804,298.786 ccw(c190.804,298.2) 190.218,298.2 cw(c190.069,298.2) 190.069,298.052 189.866,298.052 v3(189.86,298.057)
  L16 w0.101: J1_PCIE0.50@146.337,366.992 cw(c146.337,366.892) 146.437,366.892 v1(146.437,365.176)
RF_SYSREF_TO_FPGA_PCIE1_N: J1_PCIE1.48 U1.AG10 | length 99.2
  L1 w0.1: v3(187.909,297.052) U1.AG10@188.397,297.539
  L5 (Sign) w0.081: v3(187.909,297.052) cw(c187.909,297.4) 187.561,297.4 187.561,298.052 cw(c188.013,298.052) 188.013,298.504 224.586,298.504 cw(c224.586,298.156) 224.933,298.156 224.933,276.225 ccw(c225.645,276.225) 225.645,275.514 249.453,275.514 cw(c249.453,274.383) 250.584,274.383 250.584,266.938 cw(c250.383,266.938) v1(250.383,266.738)
  L16 w0.101: J1_PCIE1.48@250.29,263.794 250.483,263.987 250.483,266.479 250.46,266.503 250.46,266.662 v1(250.383,266.738)
RF_SYSREF_TO_FPGA_PCIE1_P: J1_PCIE1.50 U1.AF10 | length 100
  L1 w0.1: v3(186.932,297.052) 186.932,297.075 U1.AF10@187.397,297.539
  L5 (Sign) w0.081: v3(186.932,297.052) ccw(c186.932,297.4) 187.28,297.4 187.28,298.052 cw(c188.013,298.052) 188.013,298.785 224.586,298.785 cw(c224.586,298.156) 225.214,298.156 225.214,276.225 ccw(c225.645,276.225) 225.645,275.795 249.57,275.795 249.575,275.79 cw(c249.453,274.383) 250.859,274.505 250.865,274.5 250.865,266.822 250.845,266.802 cw(c250.383,266.938) 250.843,266.796 ccw(c250.983,266.938) 250.92,266.748 ccw(c250.983,266.938) v1(250.983,266.738)
  L16 w0.101: v1(250.983,266.738) 250.907,266.662 250.907,266.503 250.884,266.479 250.884,264 J1_PCIE1.50@251.09,263.794
RF_SYSREF_TO_FPGA_PCIE2_N: J1_PCIE2.48 U1.AH9 | length 113.2
  L1 w0.1: v3(188.909,296.052) U1.AH9@189.397,296.539
  L12 (Sign) w0.081: v3(188.909,296.052) cw(c188.909,295.692) 189.269,295.692 189.269,295.539 ccw(c190.172,295.539) 190.172,294.636 193.92,294.636 212.198,294.636 ccw(c212.198,296.184) 213.746,296.184 213.746,363.407 cw(c214.71,363.407) 214.71,364.371 228.736,364.371 ccw(c228.736,364.894) 229.259,364.894 229.259,365.321 cw(c229.419,365.321) v1(229.419,365.481)
  L16 w0.101: v1(229.419,365.481) 229.343,365.557 229.343,365.716 229.319,365.739 229.319,366.821 J1_PCIE2.48@229.49,366.992
RF_SYSREF_TO_FPGA_PCIE2_P: J1_PCIE2.50 U1.AJ9 | length 112.3
  L1 w0.1: v3(189.909,296.052) U1.AJ9@190.397,296.539
  L12 (Sign) w0.081: v3(189.909,296.052) ccw(c189.909,295.692) 189.55,295.692 189.55,295.539 ccw(c190.172,295.539) 190.172,294.917 193.92,294.917 212.198,294.917 ccw(c212.198,296.184) 213.465,296.184 213.465,363.407 cw(c214.71,363.407) 214.71,364.652 228.736,364.652 ccw(c228.736,364.894) 228.978,364.894 228.978,365.321 ccw(c228.819,365.321) v1(228.819,365.481)
  L16 w0.101: J1_PCIE2.50@228.69,366.992 228.918,366.764 228.918,365.739 228.895,365.716 228.895,365.557 v1(228.819,365.481)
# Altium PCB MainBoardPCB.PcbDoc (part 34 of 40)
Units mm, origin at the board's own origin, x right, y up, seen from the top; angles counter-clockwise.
Board outline 258.95 x 308.86 mm, 16 copper layers (L1, L2 (GND), L3 (Sign), L4 (GND), L5 (Sign), L6 (PWR/GND), L7(12V+Other), L8 (Plane_GND), L9 (PWR/GND), L10 (3V3+Other), L11 (PWR/GND), L12 (Sign), L13 (GND), L14 (Sign), L15 (GND), L16), stack 2.503 mm thick; 2578 components, 1867 nets, 8817 pads, 8021 vias.
Unrouted connection lines stored in the file: 25.

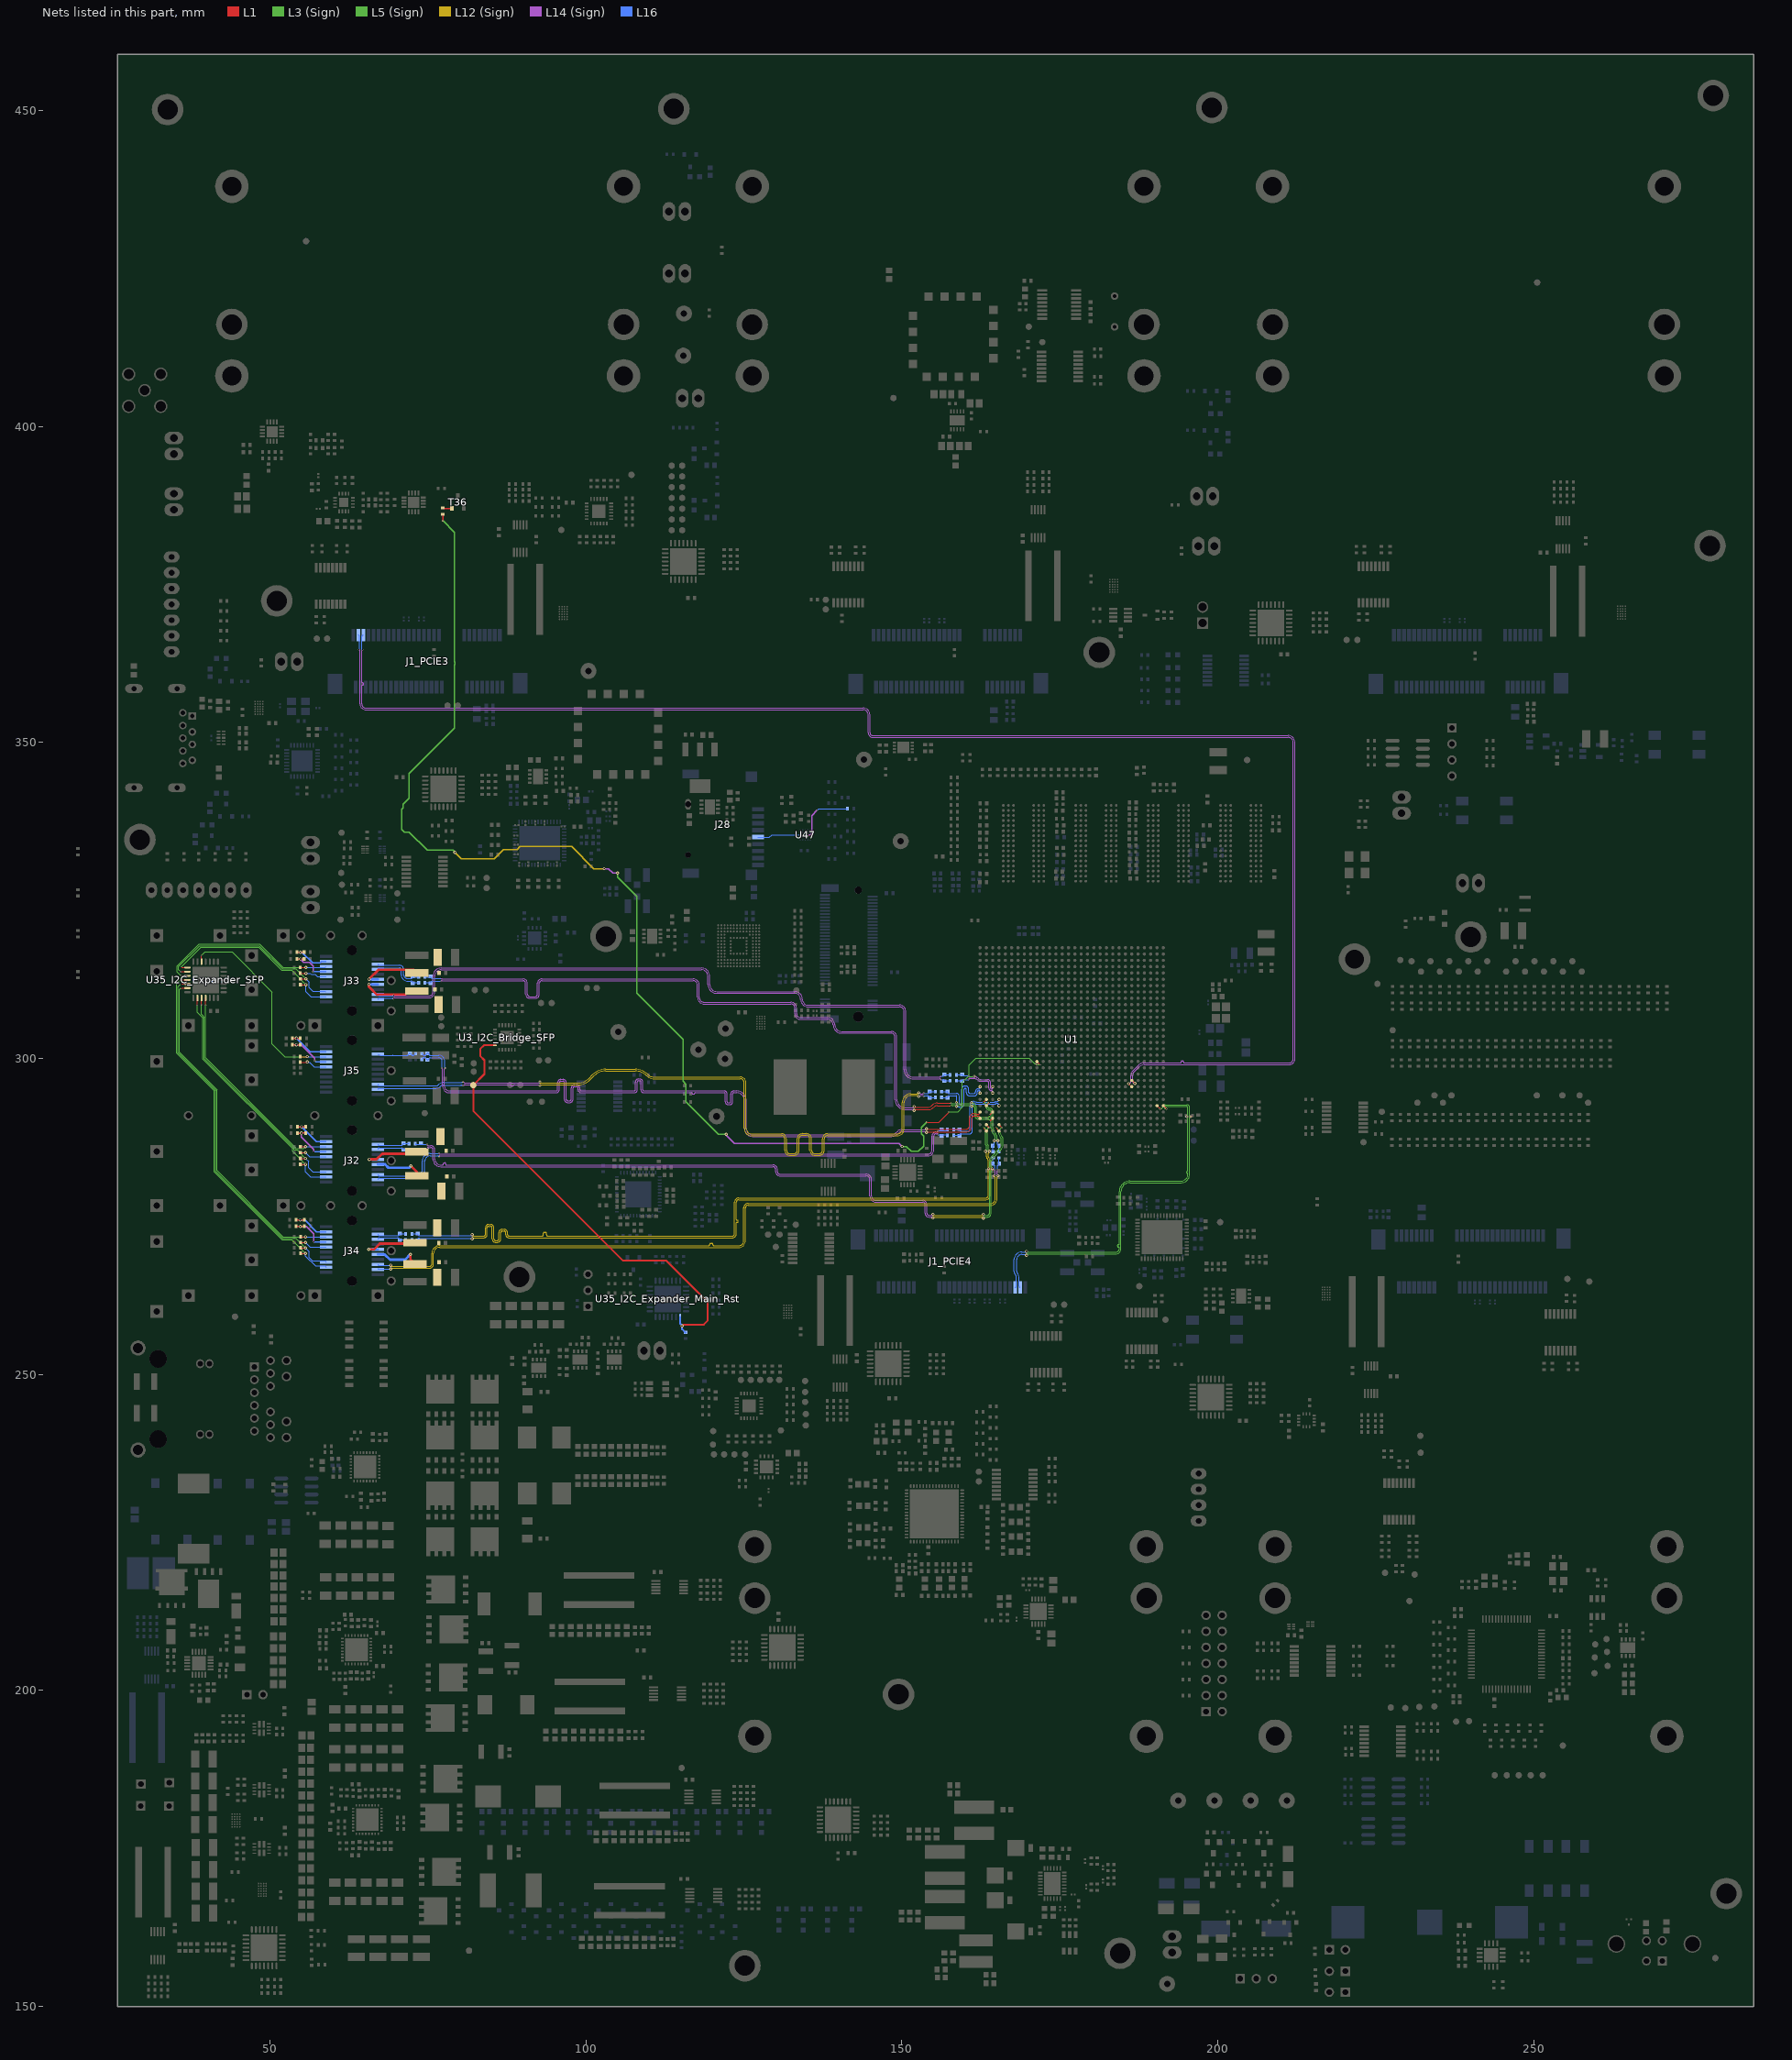
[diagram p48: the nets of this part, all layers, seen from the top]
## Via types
v1: diameter 0.5, hole 0.25, L1 to L16, tented both sides, 4341 vias
v2: diameter 0.254, hole 0.1, L1 to L3 (Sign), tented both sides, 781 vias
v3: diameter 0.5, hole 0.25, L1 to L16, 565 vias
v4: diameter 0.254, hole 0.1, L15 (GND) to L16, tented both sides, 406 vias
v5: diameter 0.254, hole 0.1, L1 to L2 (GND), tented both sides, 283 vias
v6: diameter 0.457, hole 0.2, L3 (Sign) to L6 (PWR/GND), tented both sides, 254 vias
v7: diameter 0.254, hole 0.1, L1 to L3 (Sign), 237 vias
v8: diameter 0.75, hole 0.4, L1 to L16, 200 vias
v9: diameter 0.8, hole 0.4, L1 to L16, tented both sides, 182 vias
v10: diameter 0.254, hole 0.1, L14 (Sign) to L16, tented both sides, 170 vias
v11: diameter 0.75/0/0/0/0/0/0/0/0/0/0/0/0/0/0/0.75 (per signal layer), hole 0.4, L1 to L16, 160 vias
v12: diameter 0.457, hole 0.2, L3 (Sign) to L6 (PWR/GND), 158 vias
v13: diameter 1.4, hole 0.5, L1 to L16, tented both sides, 80 vias
v14: diameter 0.254, hole 0.1, L14 (Sign) to L16, 65 vias
v15: diameter 0.254, hole 0.1, L1 to L2 (GND), 45 vias
v16: diameter 0.457, hole 0.2, L11 (PWR/GND) to L14 (Sign), tented both sides, 26 vias
v17: diameter 0.457, hole 0.2, L11 (PWR/GND) to L14 (Sign), 25 vias
v18: diameter 0.457, hole 0.2, L7(12V+Other) to L10 (3V3+Other), tented both sides, 11 vias
v19: diameter 0.254/0/0.254 (per signal layer), hole 0.1, L1 to L3 (Sign), 9 vias
v20: diameter 0.2/0/0.2 (per signal layer), hole 0.1, L1 to L3 (Sign), 6 vias
v21: diameter 1.65, hole 1.65, L1 to L16, 5 vias
v22: diameter 1.15, hole 1.15, L1 to L16, 5 vias
v23: diameter 0.457, hole 0.2, L1 to L16, 3 vias
v24: diameter 0.5, hole 0.3, L1 to L16, 2 vias
v25: diameter 0.5/0/0.5 (per signal layer), hole 0.2, L14 (Sign) to L16, 1 vias
v26: diameter 0.5, hole 0.25, L1 to L16, tented bottom, 1 vias

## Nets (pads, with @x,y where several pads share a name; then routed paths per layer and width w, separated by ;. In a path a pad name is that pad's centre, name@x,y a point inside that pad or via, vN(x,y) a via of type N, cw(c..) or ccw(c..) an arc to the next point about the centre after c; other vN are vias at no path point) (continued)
RF_SYSREF_TO_FPGA_PCIE3_N: J1_PCIE3.48 U1.AE9 | length 243.2
  L1 w0.1: U1.AE9@186.397,296.539 v3(186.884,296.052)
  L14 (Sign) w0.081: v10(64.685,364.68) ccw(c64.685,364.521) 64.526,364.521 64.526,359.844 64.526,359.509 ccw(c64.609,359.509) 64.609,359.425 64.729,359.425 cw(c64.729,359.341) 64.813,359.341 64.813,359.174 cw(c64.729,359.174) 64.729,359.09 64.609,359.09 ccw(c64.609,359.006) 64.526,359.006 64.526,358.63 64.526,356.124 ccw(c65.177,356.124) 65.177,355.473 143.9,355.473 cw(c143.9,354.415) 144.958,354.415 144.958,353.437 144.958,352.083 144.958,351.574 ccw(c145.426,351.574) 145.426,351.106 211.131,351.106 cw(c211.131,350.009) 212.228,350.009 212.228,299.936 cw(c211.333,299.936) 211.333,299.041 191.737,299.041 189.111,299.041 188.397,299.041 ccw(c188.397,298.023) 187.677,298.743 186.729,297.795 ccw(c187.191,297.333) 186.537,297.333 186.537,296.394 ccw(c186.88,296.394) 186.88,296.052 v3(186.884,296.052)
  L16 w0.101: v10(64.685,364.68) cw(c64.685,364.78) 64.586,364.78 64.586,366.792 cw(c64.785,366.792) J1_PCIE3.48@64.785,366.992
RF_SYSREF_TO_FPGA_PCIE3_P: J1_PCIE3.50 U1.AE8 | length 243.2
  L1 w0.1: v3(185.909,296.027) U1.AE8@186.397,295.539
  L14 (Sign) w0.081: v10(64.085,364.68) cw(c64.085,364.521) 64.245,364.521 64.245,356.124 ccw(c65.177,356.124) 65.177,355.192 143.9,355.192 cw(c143.9,354.415) 144.677,354.415 144.677,351.574 ccw(c145.426,351.574) 145.426,350.825 211.131,350.825 cw(c211.131,350.009) 211.947,350.009 211.947,299.936 cw(c211.333,299.936) 211.333,299.322 195.147,299.322 194.66,299.322 cw(c194.66,299.406) 194.576,299.406 194.576,299.526 ccw(c194.493,299.526) 194.493,299.61 194.325,299.61 ccw(c194.325,299.526) 194.241,299.526 194.241,299.406 cw(c194.157,299.406) 194.157,299.322 194.117,299.322 188.281,299.322 ccw(c188.281,298.304) 187.56,299.024 186.53,297.994 ccw(c187.191,297.333) 186.256,297.333 186.256,296.374 cw(c185.909,296.374) v3(185.909,296.027)
  L16 w0.101: J1_PCIE3.50@63.985,366.992 cw(c63.985,366.792) 64.185,366.792 64.185,364.78 cw(c64.085,364.78) v10(64.085,364.68)
RF_SYSREF_TO_FPGA_PCIE4_N: J1_PCIE4.48 U1.AK5 | length 60.3
  L1 w0.1: U1.AK5@191.397,292.539 v2(191.884,292.052)
  L5 (Sign) w0.081: v1(169.748,269.486) ccw(c169.852,269.486) 169.852,269.382 183.884,269.382 ccw(c183.884,269.92) 184.422,269.92 184.422,270.053 184.422,270.093 ccw(c184.322,270.093) 184.322,270.194 184.227,270.194 cw(c184.227,270.294) 184.127,270.294 184.127,270.427 cw(c184.227,270.427) 184.227,270.528 184.322,270.528 ccw(c184.322,270.628) 184.422,270.628 184.422,270.855 184.422,278.92 cw(c186.136,278.92) 186.136,280.634 194.213,280.634 ccw(c194.213,281.704) 195.283,281.704 195.283,281.744 ccw(c195.182,281.744) 195.182,281.844 cw(c195.182,281.945) 195.082,281.945 195.082,282.078 cw(c195.182,282.078) 195.182,282.178 ccw(c195.182,282.279) 195.283,282.279 195.283,282.526 195.283,290.64 ccw(c195.123,290.64) v12(195.123,290.799)
  L3 (Sign) w0.081: v2(191.884,292.052) 191.736,292.052 cw(c191.736,292.263) 191.525,292.263 cw(c191.673,292.263) 191.673,292.411 195.098,292.411 cw(c195.098,292.227) 195.283,292.227 195.283,290.959 cw(c195.123,290.959) v12(195.123,290.799)
  L16 w0.101: J1_PCIE4.48@167.937,263.794 ccw(c167.937,263.994) 168.137,263.994 168.137,265.456 ccw(c167.632,265.456) 167.989,265.813 167.987,265.815 cw(c168.483,266.31) 167.782,266.31 167.782,268.201 cw(c168.967,268.201) 168.967,269.387 169.649,269.387 ccw(c169.649,269.486) v1(169.748,269.486)
RF_SYSREF_TO_FPGA_PCIE4_P: J1_PCIE4.50 U1.AJ5 | length 60.4
  L1 w0.1: U1.AJ5@190.397,292.539 v2(190.884,292.052)
  L5 (Sign) w0.081: v1(169.748,268.886) cw(c169.948,268.886) 169.948,269.086 180.725,269.086 182.822,269.086 183.884,269.086 ccw(c183.884,269.905) 184.703,269.905 184.703,278.92 cw(c186.136,278.92) 186.136,280.353 194.213,280.353 ccw(c194.213,281.704) 195.564,281.704 195.564,290.64 cw(c195.723,290.64) v12(195.723,290.799)
  L3 (Sign) w0.081: v2(190.884,292.052) 191.032,292.052 ccw(c191.032,292.263) 191.244,292.263 cw(c191.673,292.263) 191.673,292.692 195.098,292.692 cw(c195.098,292.227) 195.564,292.227 195.564,290.959 ccw(c195.723,290.959) v12(195.723,290.799)
  L16 w0.101: J1_PCIE4.50@168.737,263.794 cw(c168.737,263.994) 168.538,263.994 168.538,265.459 ccw(c167.639,265.459) 168.274,266.095 168.272,266.097 cw(c168.487,266.312) 168.183,266.312 168.183,268.201 cw(c168.967,268.201) 168.967,268.986 169.649,268.986 cw(c169.649,268.886) v1(169.748,268.886)
RST_brigde: R757.1 SP12_I2C_Bridge_SFP.1 U3_I2C_Bridge_SFP.24 U35_I2C_Expander_Main_Rst.1 | length 73.1
  L1 w0.3: U3_I2C_Bridge_SFP.24@85.6,302.096 83.887,302.096 83.287,301.496 83.287,300.398 83.955,299.73 83.955,297.557 SP12_I2C_Bridge_SFP.1@82.194,295.796 82.194,291.705 105.835,268.064 112.68,268.064 119.306,261.437 119.306,258.543 118.67,257.907 115.498,257.907 115.285,257.694 v1(115.231,257.694)
  L16 w0.3: U35_I2C_Expander_Main_Rst.1@114.948,259.093 114.948,258.032 115.231,257.748 v1(115.231,257.694) 115.231,257.177 R757.1@115.781,256.627
SD_Card_CLK: J28.5 U47.C5 | length 6.8
  L16 w0.12: J28.5@127.237,335.032 129.062,335.032 129.434,335.404 U47.C5@133.929,335.404
SD_Card_en: R382.1 U47.C2 | length 9.6
  L14 (Sign) w0.2: v10(135.129,335.404) 135.506,335.404 135.763,335.661 135.763,338.442 v10(136.588,339.268)
  L16 w0.12: v10(136.588,339.268) 136.625,339.268 136.879,339.522 R382.1@141.437,339.522
Sel_CLK_R: R900.1 U1.K12 | length 207.3
  L1 w0.12: v7(153.924,289.928) 155.888,289.928 157.416,291.456 v7(157.416,291.574) ; U1.K12@171.397,299.539 v2(171.884,299.052)
  L1 w0.2: v2(77.372,385.114) R900.1@77.372,386.189
  L5 (Sign) w0.12: v12(161.484,297.186) 161.397,297.186 160.753,297.186 160.668,297.271 160.668,298.94 161.397,299.67 161.779,300.052 170.138,300.052 171.02,299.17 171.35,299.17 v12(171.369,299.151)
  L5 (Sign) w0.2: v1(105.029,329.34) 105.029,328.743 108.085,325.687 108.085,310.358 115.41,303.033 115.41,296.408 115.868,295.95 115.868,293.138 120.982,288.023 v1(122.212,288.023)
  L12 (Sign) w0.2: v1(79.299,332.638) 80.315,331.622 85.537,331.622 86.959,333.045 89.114,333.045 89.61,333.54 97.771,333.54 101.265,330.046 v16(102.908,330.046)
  L3 (Sign) w0.12: v7(157.416,291.574) 158.89,291.574 159.605,292.289 159.605,296.289 160.502,297.186 161.397,297.186 v12(161.484,297.186) ; v12(171.369,299.151) 171.468,299.052 v2(171.884,299.052)
  L3 (Sign) w0.2: v2(77.372,385.114) 79.219,383.268 79.219,362.777 79.287,362.708 79.287,362.335 79.219,362.266 79.219,352.315 72.034,345.131 72.034,341.147 71.107,340.22 71.107,339.681 70.864,339.437 70.864,336.219 71.278,335.804 72.06,335.804 74.889,332.975 78.962,332.975 v1(79.299,332.638) ; v3(150.087,286.093) 150.725,286.093 151.5,285.318 152.608,285.318 153.447,286.157 153.447,287.727 153.122,288.052 153.122,289.126 v7(153.924,289.928)
  L14 (Sign) w0.2: v16(102.908,330.046) 103.575,330.046 104.281,329.34 v1(105.029,329.34) ; v1(122.212,288.023) 122.212,287.896 123.507,286.601 149.579,286.601 v3(150.087,286.093)
SetClk_Si53323_2: R900.2 T36.1 | length 1.5
  L1 w0.2: R900.2@77.372,387.089 77.43,387.03 78.751,387.03 T36.1@78.811,387.09
SFP0_ABS: J32.6 R65.1 | length 4.4
  L1 w0.12: R65.1@54.779,285.118 v1(55.639,285.118)
  L16 w0.12: v1(55.639,285.118) 56.31,284.447 J32.6@58.904,284.447
SFP0_LOS: J32.8 R66.1 U35_I2C_Expander_SFP.4 | length 35.6
  L1 w0.12: U35_I2C_Expander_SFP.4@39.827,309.578 39.84,309.566 39.84,308.496 v7(39.853,308.483) ; R66.1@54.779,286.047 v1(55.639,286.047)
  L3 (Sign) w0.12: v7(39.853,308.483) 39.853,300.103 54.029,285.926 54.029,285.75 55.342,285.75 v1(55.639,286.047)
  L16 w0.12: v1(55.639,286.047) J32.8@58.904,286.047
SFP0_RS0: J32.7 R72.2 R74.1 | length 7.1
  L1 w0.2: R74.1@54.293,288.188 54.991,288.188 v1(55.004,288.201) 55.72,288.201 R72.2@55.733,288.188
  L14 (Sign) w0.2: v1(55.004,288.201) 55.004,287.545 56.961,285.588 56.961,285.283 v10(56.997,285.247)
  L16 w0.2: v10(56.997,285.247) J32.7@58.904,285.247
SFP0_RS1: J32.9 R71.2 R73.1 | length 6.3
  L1 w0.2: R73.1@54.293,289.204 v1(55.016,289.204) R71.2@55.733,289.204
  L16 w0.2: v1(55.016,289.204) 57.374,286.847 J32.9@58.904,286.847
SFP0_Rx_FPGA_N: C56.1 R706.1 U1.D5 | length 12.3
  L14 (Sign) w0.081: v1(165.397,292.539) v1@165.397,292.694
  L16 w0.09: 161.397,292.816 161.452,292.872 161.655,292.872 161.711,292.816 164.813,292.816 ccw(c164.813,292.95) 164.908,292.855 cw(c165.002,292.761) 165.002,292.894 165.042,292.894 cw(c165.042,292.539) v1(165.397,292.539)
  L16 w0.101: R706.1@158.208,287.846 159.047,287.846 cw(c159.047,287.778) C56.1@159.115,287.778 cw(c159.439,287.778) 159.439,288.102 160.737,288.102 ; 160.764,288.102 ccw(c160.764,288.512) 161.173,288.512 161.173,292.615 cw(c161.374,292.615) 161.374,292.816 161.397,292.816
SFP0_Rx_FPGA_P: C56.2 R705.1 U1.D6 | length 12.1
  L16 w0.09: 161.397,293.217 161.452,293.162 161.775,293.162 161.831,293.106 164.691,293.106 ccw(c164.691,293.24) 164.786,293.145 cw(c164.88,293.051) 164.88,293.184 165.042,293.184 ccw(c165.042,293.539) v1(165.397,293.539)
  L16 w0.101: R705.1@158.208,288.76 159.047,288.76 ccw(c159.047,288.828) C56.2@159.115,288.828 ccw(c159.439,288.828) 159.439,288.503 160.598,288.503 ccw(c160.598,288.678) 160.772,288.678 160.772,292.615 cw(c161.374,292.615) 161.374,293.217 161.397,293.217
SFP0_Rx_N: C57.2 J32.19 R706.2 | length 96.2
  L14 (Sign) w0.081: v10(76.759,284.447) cw(c76.918,284.447) 76.918,284.607 154.193,284.607 ccw(c154.193,285.465) 155.051,285.465 155.051,287.714 cw(c155.461,287.714) 155.461,288.124 155.56,288.124 cw(c155.56,287.964) v10(155.719,287.964)
  L16 w0.101: J32.19@67.104,280.847 cw(c67.304,280.847) 67.304,281.046 73.397,281.046 ccw(c73.397,282.147) 74.498,282.147 74.498,283.709 cw(c75.393,283.709) 75.393,284.604 76.603,284.604 cw(c76.603,284.447) v10(76.759,284.447) ; v10(155.719,287.964) 157.089,287.964 cw(c157.089,287.846) R706.2@157.208,287.846
SFP0_Rx_P: C57.1 J32.18 R705.2 | length 96.2
  L14 (Sign) w0.081: v10(76.759,285.047) ccw(c76.918,285.047) 76.918,284.888 154.193,284.888 ccw(c154.193,285.465) 154.77,285.465 154.77,287.714 cw(c155.461,287.714) 155.461,288.405 155.56,288.405 ccw(c155.56,288.564) v10(155.719,288.564)
  L16 w0.101: J32.18@67.104,281.647 ccw(c67.304,281.647) 67.304,281.447 73.397,281.447 ccw(c73.397,282.147) 74.097,282.147 74.097,283.709 cw(c75.393,283.709) 75.393,285.005 76.716,285.005 ccw(c76.716,285.047) v10(76.759,285.047) ; v10(155.719,288.564) 157.012,288.564 ccw(c157.012,288.76) R705.2@157.208,288.76
SFP0_Tx_FPGA_N: C55.1 R704.1 U1.D1 | length 116.2
  L1 w0.1: v2(164.909,289.027) U1.D1@165.397,288.539
  L5 (Sign) w0.081: v3(162.909,275.357) ccw(c163.069,275.357) 163.069,275.197 163.531,275.197 ccw(c163.531,275.559) 163.893,275.559 163.893,282.165 ccw(c163.583,282.165) 163.802,282.383 cw(c163.968,282.55) v12(163.733,282.55)
  L12 (Sign) w0.081: v17(154.93,275.357) 154.93,275.278 ccw(c155.01,275.278) 155.01,275.197 162.75,275.197 ccw(c162.75,275.357) v3(162.909,275.357)
  L3 (Sign) w0.081: v12(163.733,282.55) cw(c163.968,282.55) 163.802,282.716 163.813,282.727 ccw(c163.62,282.919) 163.893,282.919 163.893,283.724 cw(c164.945,283.724) 164.201,284.469 165.481,285.749 ccw(c164.781,286.449) 165.771,286.449 165.771,287.158 ccw(c165.259,287.158) 165.621,287.52 165.619,287.521 cw(c166.496,288.398) 165.256,288.398 165.256,288.68 ccw(c164.909,288.68) v2(164.909,289.027)
  L14 (Sign) w0.081: v10(74.892,286.384) ccw(c75.051,286.384) 75.051,286.224 75.426,286.224 cw(c75.426,285.559) 76.092,285.559 76.092,284.11 ccw(c77.025,284.11) 77.025,283.177 77.326,283.177 77.366,283.177 ccw(c77.366,283.277) 77.466,283.277 77.466,283.396 cw(c77.567,283.396) 77.567,283.496 77.7,283.496 cw(c77.7,283.396) 77.8,283.396 77.8,283.277 ccw(c77.901,283.277) 77.901,283.177 78.08,283.177 129.616,283.177 cw(c129.616,282.479) 130.313,282.479 130.313,282.1 ccw(c130.705,282.1) 130.705,281.708 144.351,281.708 cw(c144.351,280.822) 145.237,280.822 145.237,278.219 ccw(c145.884,278.219) 145.884,277.572 153.306,277.572 cw(c153.306,276.912) 153.966,276.912 153.966,275.552 ccw(c154.321,275.552) 154.321,275.197 154.77,275.197 ccw(c154.77,275.357) v17(154.93,275.357)
  L16 w0.101: R704.1@73.027,286.541 ccw(c73.184,286.541) 73.184,286.384 v10(74.892,286.384)
SFP0_Tx_FPGA_P: C55.2 R703.1 U1.D2 | length 116.2
  L1 w0.1: U1.D2@165.397,289.539 v2(165.884,289.052)
  L5 (Sign) w0.081: v3(162.909,274.757) cw(c163.069,274.757) 163.069,274.916 163.531,274.916 ccw(c163.531,275.559) 164.174,275.559 164.174,282.165 cw(c164.483,282.165) 164.264,282.383 ccw(c164.098,282.55) v12(164.333,282.55)
  L12 (Sign) w0.081: v17(154.93,274.757) 154.93,274.836 cw(c155.01,274.836) 155.01,274.916 162.75,274.916 cw(c162.75,274.757) v3(162.909,274.757)
  L3 (Sign) w0.081: v12(164.333,282.55) ccw(c164.098,282.55) 164.264,282.716 164.253,282.727 cw(c164.446,282.919) 164.174,282.919 164.174,283.722 cw(c164.952,283.722) 164.401,284.272 165.682,285.552 ccw(c164.789,286.445) 166.052,286.445 166.052,287.159 ccw(c165.262,287.159) 165.82,287.717 165.819,287.719 cw(c166.5,288.399) 165.537,288.399 165.537,288.705 cw(c165.884,288.705) v2(165.884,289.052)
  L14 (Sign) w0.081: v10(74.892,285.784) cw(c75.051,285.784) 75.051,285.943 75.426,285.943 cw(c75.426,285.559) 75.811,285.559 75.811,284.11 ccw(c77.025,284.11) 77.025,282.896 129.616,282.896 cw(c129.616,282.479) 130.032,282.479 130.032,282.1 ccw(c130.705,282.1) 130.705,281.427 144.351,281.427 cw(c144.351,280.822) 144.956,280.822 144.956,278.219 ccw(c145.884,278.219) 145.884,277.291 153.306,277.291 cw(c153.306,276.912) 153.685,276.912 153.685,275.552 ccw(c154.321,275.552) 154.321,274.916 154.77,274.916 cw(c154.77,274.757) v17(154.93,274.757)
  L16 w0.101: R703.1@73.027,285.627 cw(c73.184,285.627) 73.184,285.784 v10(74.892,285.784)
SFP0_Tx_N: C42.2 J32.12 R704.2 | length 5.3
  L16 w0.101: J32.12@67.104,286.447 ccw(c67.304,286.447) 67.304,286.247 70.758,286.247 ccw(c70.758,286.609) C42.2@71.12,286.609 ccw(c71.187,286.609) 71.187,286.541 R704.2@72.027,286.541
SFP0_Tx_P: C42.1 J32.13 R703.2 | length 5.2
  L16 w0.101: J32.13@67.104,285.647 cw(c67.304,285.647) 67.304,285.846 70.832,285.846 cw(c70.832,285.559) C42.1@71.12,285.559 cw(c71.187,285.559) 71.187,285.627 R703.2@72.027,285.627
SFP0_TxDis: J32.3 R68.1 U35_I2C_Expander_SFP.3 | length 38.1
  L1 w0.12: v7(39.177,308.496) U35_I2C_Expander_SFP.3@39.177,309.578 ; R68.1@54.779,284.205 v1(55.639,284.205)
  L3 (Sign) w0.12: v7(39.177,308.496) 39.177,306.993 39.633,306.538 39.633,300.012 53.809,285.835 53.809,285.53 54.314,285.53 v1(55.639,284.205)
  L16 w0.12: v1(55.639,284.205) 56.134,283.71 56.134,282.74 56.828,282.047 J32.3@58.904,282.047
SFP0_TxF: J32.2 R67.1 U35_I2C_Expander_SFP.2 | length 39.1
  L1 w0.12: v7(38.527,308.483) U35_I2C_Expander_SFP.2@38.527,309.578 ; R67.1@54.779,283.247 54.794,283.261 v1(55.639,283.261)
  L3 (Sign) w0.12: v7(38.527,308.483) 38.527,307.332 39.413,306.446 39.413,299.921 53.589,285.744 53.589,285.31 v1(55.639,283.261)
  L16 w0.12: v1(55.639,283.261) 55.639,282.067 56.459,281.247 J32.2@58.904,281.247
SFP0_VccR: C37.2 C38.1 J32.15 L1.2 | length 9.3
  L1 w0.4: v1(65.743,284.047) 66.877,284.047 67.78,284.95 72.917,284.95 L1.2@73.226,285.26
  L16 w0.4: v1(65.743,284.047) J32.15@67.104,284.047
SFP0_VccT: C39.2 C40.1 J32.16 L2.2 | length 7.5
  L1 w0.4: v1(72.326,282.994) 73.226,282.094 L2.2@73.226,281.447
  L16 w0.4: J32.16@67.104,283.247 68.239,283.247 68.758,282.727 72.06,282.727 v1(72.326,282.994)
SFP1_ABS: J33.6 R135.1 | length 4.4
  L1 w0.12: R135.1@54.767,313.497 v1(55.702,313.497)
  L16 w0.12: v1(55.702,313.497) 56.379,313.497 56.56,313.316 57.134,313.316 57.503,312.947 J33.6@58.904,312.947
SFP1_LOS: J33.8 R136.1 U35_I2C_Expander_SFP.24 | length 30.3
  L1 w0.12: v7(35.903,313.131) 35.917,313.117 36.938,313.117 U35_I2C_Expander_SFP.24@36.952,313.103 ; R136.1@54.776,314.403 v1(55.702,314.403)
  L3 (Sign) w0.12: v7(35.903,313.131) 35.348,313.686 35.348,314.633 38.824,318.11 48.367,318.11 52.073,314.403 v1(55.702,314.403)
  L16 w0.12: v1(55.702,314.403) 58.761,314.403 J33.8@58.904,314.547
SFP1_RS0: J33.7 R142.2 R144.1 | length 6.7
  L1 w0.2: R144.1@54.272,315.759 54.281,315.75 55.402,315.75 R142.2@55.411,315.741
  L14 (Sign) w0.2: v1(54.864,315.759) 55.372,315.251 56.256,315.251 56.883,314.624 56.883,313.817 v10(56.807,313.741)
  L16 w0.2: v10(56.807,313.741) 58.898,313.741 J33.7@58.904,313.747
SFP1_RS1: J33.9 R141.2 R143.1 | length 6.1
  L1 w0.2: R143.1@54.272,316.827 R141.2@55.411,316.827 R141.2@55.461,316.827
  L16 w0.2: v1(54.813,316.827) 54.871,316.77 55.132,316.77 56.761,315.141 57.949,315.141 58.154,315.347 J33.9@58.904,315.347
SFP1_Rx_FPGA_N: C66.1 R830.1 U1.C7 | length 7.6
  L14 (Sign) w0.081: v14(160.598,296.672) cw(c160.76,296.672) 160.645,296.787 160.69,296.831 161.44,296.831 cw(c161.44,296.085) 161.967,296.613 ccw(c162.495,297.14) 162.495,296.394 163.526,296.394 cw(c163.526,296.133) 163.788,296.133 163.788,295.35 ccw(c164.239,295.35) 164.239,294.899 cw(c164.239,294.741) 164.397,294.741 v1(164.397,294.539)
  L16 w0.101: R830.1@158.673,296.507 159.512,296.507 cw(c159.512,296.439) C66.1@159.58,296.439 cw(c159.813,296.439) 159.813,296.672 v14(160.598,296.672)
SFP1_Rx_FPGA_P: C66.2 R829.1 U1.C8 | length 7.6
  L14 (Sign) w0.081: v14(160.598,297.272) ccw(c160.76,297.272) 160.645,297.157 160.69,297.112 161.556,297.112 cw(c161.556,296.366) 162.084,296.894 ccw(c162.611,297.421) 162.611,296.675 163.526,296.675 cw(c163.526,296.133) 164.069,296.133 164.069,295.35 ccw(c164.239,295.35) 164.239,295.18 ccw(c164.239,295.338) 164.397,295.338 v1(164.397,295.539)
  L16 w0.101: R829.1@158.673,297.421 159.512,297.421 ccw(c159.512,297.489) C66.2@159.58,297.489 ccw(c159.797,297.489) 159.797,297.272 v14(160.598,297.272)
SFP1_Rx_N: C68.2 J33.19 R830.2 | length 109
  L14 (Sign) w0.081: v10(69.573,309.447) cw(c69.732,309.447) 69.732,309.606 75.149,309.606 ccw(c75.149,310.563) 76.106,310.563 76.106,313.044 cw(c77.102,313.044) 77.102,314.04 118.326,314.04 cw(c118.326,313.049) 119.317,313.049 119.317,311.764 ccw(c120.759,311.764) 120.759,310.323 133.035,310.323 cw(c133.035,309.363) 133.995,309.363 ccw(c135.186,309.363) 135.186,308.173 149.67,308.173 cw(c149.67,307.468) 150.374,307.468 150.374,298.208 ccw(c151.784,298.208) 151.784,296.799 155.991,296.799 cw(c155.991,296.64) v10(156.151,296.64)
  L16 w0.101: J33.19@67.104,309.347 cw(c67.304,309.347) 67.304,309.546 69.473,309.546 cw(c69.473,309.447) v10(69.573,309.447) ; v10(156.151,296.64) 156.572,296.64 cw(c156.572,296.439) C68.2@156.773,296.439 cw(c156.84,296.439) 156.84,296.507 R830.2@157.673,296.507
SFP1_Rx_P: C68.1 J33.18 R829.2 | length 109.1
  L14 (Sign) w0.081: v10(69.573,310.047) ccw(c69.732,310.047) 69.732,309.887 75.149,309.887 ccw(c75.149,310.563) 75.825,310.563 75.825,313.044 cw(c77.102,313.044) 77.102,314.321 118.326,314.321 cw(c118.326,313.049) 119.598,313.049 119.598,311.764 ccw(c120.759,311.764) 120.759,310.604 133.035,310.604 cw(c133.035,309.363) 134.276,309.363 ccw(c135.186,309.363) 135.186,308.454 149.67,308.454 cw(c149.67,307.468) 150.655,307.468 150.655,298.208 ccw(c151.784,298.208) 151.784,297.08 155.991,297.08 ccw(c155.991,297.24) v10(156.151,297.24)
  L16 w0.101: J33.18@67.104,310.147 ccw(c67.304,310.147) 67.304,309.947 69.473,309.947 ccw(c69.473,310.047) v10(69.573,310.047) ; v10(156.151,297.24) 156.523,297.24 ccw(c156.523,297.489) C68.1@156.773,297.489 ccw(c156.84,297.489) 156.84,297.421 R829.2@157.673,297.421
SFP1_Tx_FPGA_N: C65.1 R708.1 U1.C4 | length 114.9
  L1 w0.1: v2(163.906,291.052) 163.91,291.055 ccw(c163.859,291.129) 163.922,291.065 U1.C4@164.397,291.539
  L1 w0.101: v3(151.937,292.407) 151.942,292.407 152.021,292.327 ccw(c152.07,292.376) 152.07,292.307 154.108,292.307 ccw(c154.108,293.275) 154.793,292.591 154.795,292.593 cw(c155.624,291.763) 155.624,292.936 157.784,292.936 ccw(c157.784,292.961) v7(157.808,292.961)
  L5 (Sign) w0.081: v12(158.65,293.036) ccw(c158.809,293.036) 158.809,292.876 160.876,292.876 ccw(c160.876,293.036) v12(161.036,293.036)
  L3 (Sign) w0.081: v7(157.808,292.961) ccw(c157.893,292.961) 157.893,292.876 158.49,292.876 ccw(c158.49,293.036) v12(158.65,293.036) ; v12(161.036,293.036) 161.036,292.94 ccw(c161.099,292.94) 161.099,292.876 cw(c161.099,292.125) 161.85,292.125 161.85,290.997 ccw(c162.153,290.997) 162.153,290.693 163.672,290.693 ccw(c163.672,290.931) 163.909,290.931 163.909,291.029 ccw(c163.828,291.029) v2(163.906,291.052)
  L14 (Sign) w0.081: v10(77.102,312.758) ccw(c77.261,312.758) 77.261,312.599 88.266,312.599 90.08,312.599 cw(c90.08,311.916) 90.762,311.916 90.762,310.207 ccw(c91.163,310.207) 91.163,309.806 91.966,309.806 ccw(c91.966,310.207) 92.367,310.207 92.367,311.916 cw(c93.049,311.916) 93.049,312.599 93.23,312.599 116.981,312.599 cw(c116.981,311.623) 117.957,311.623 117.957,309.702 ccw(c118.749,309.702) 118.749,308.91 132.453,308.91 cw(c132.453,308.012) 133.352,308.012 133.352,307.123 ccw(c133.995,307.123) 133.995,306.479 138.277,306.479 cw(c138.277,305.333) 139.423,305.333 ccw(c140.462,305.333) 140.462,304.295 148.316,304.295 cw(c148.316,303.391) 149.22,303.391 149.22,293.539 ccw(c150.512,293.539) 150.512,292.247 151.777,292.247 ccw(c151.777,292.407) v3(151.937,292.407)
  L16 w0.101: R708.1@74.541,312.915 75.374,312.915 ccw(c75.374,312.983) C65.1@75.441,312.983 ccw(c75.766,312.983) 75.766,312.659 77.002,312.659 ccw(c77.002,312.758) v10(77.102,312.758)
SFP1_Tx_FPGA_P: C65.2 R707.1 U1.C3 | length 114.9
  L1 w0.1: v2(163.906,290.053) ccw(c163.862,290.132) 163.926,290.068 U1.C3@164.397,290.539
  L1 w0.101: v3(151.937,291.807) 151.942,291.807 152.021,291.886 cw(c152.07,291.838) 152.07,291.906 154.109,291.906 ccw(c154.109,293.273) 155.075,292.307 cw(c155.627,291.757) 155.627,292.535 157.784,292.535 cw(c157.784,292.511) v7(157.808,292.511)
  L5 (Sign) w0.081: v12(158.65,292.436) cw(c158.809,292.436) 158.809,292.595 160.876,292.595 cw(c160.876,292.436) v12(161.036,292.436)
  L3 (Sign) w0.081: v7(157.808,292.511) cw(c157.893,292.511) 157.893,292.595 158.49,292.595 cw(c158.49,292.436) v12(158.65,292.436) ; v12(161.036,292.436) 161.036,292.532 cw(c161.099,292.532) 161.099,292.595 cw(c161.099,292.125) 161.569,292.125 161.569,290.997 ccw(c162.153,290.997) 162.153,290.412 163.672,290.412 cw(c163.672,290.173) 163.911,290.173 163.911,290.081 cw(c163.83,290.081) v2(163.906,290.053)
  L14 (Sign) w0.081: v10(77.102,312.158) cw(c77.261,312.158) 77.261,312.318 88.266,312.318 90.08,312.318 cw(c90.08,311.916) 90.481,311.916 90.481,310.207 ccw(c91.163,310.207) 91.163,309.525 91.966,309.525 ccw(c91.966,310.207) 92.648,310.207 92.648,311.916 cw(c93.049,311.916) 93.049,312.318 93.23,312.318 116.981,312.318 cw(c116.981,311.623) 117.676,311.623 117.676,309.702 ccw(c118.749,309.702) 118.749,308.629 132.453,308.629 cw(c132.453,308.012) 133.071,308.012 133.071,307.123 ccw(c133.995,307.123) 133.995,306.198 138.277,306.198 cw(c138.277,305.333) 139.142,305.333 ccw(c140.462,305.333) 140.462,304.014 148.316,304.014 cw(c148.316,303.391) 148.939,303.391 148.939,293.539 ccw(c150.512,293.539) 150.512,291.966 151.777,291.966 cw(c151.777,291.807) v3(151.937,291.807)
  L16 w0.101: R707.1@74.541,312.001 75.374,312.001 cw(c75.374,311.933) C65.2@75.441,311.933 cw(c75.766,311.933) 75.766,312.258 77.002,312.258 cw(c77.002,312.158) v10(77.102,312.158)
SFP1_Tx_N: C58.2 J33.12 R708.2 | length 8.3
  L16 w0.101: J33.12@67.104,314.947 ccw(c67.304,314.947) 67.304,314.747 70.488,314.747 cw(c70.488,314.058) 71.177,314.058 71.177,313.29 ccw(c71.808,313.29) 71.808,312.659 72.31,312.659 ccw(c72.31,312.983) C58.2@72.634,312.983 ccw(c72.702,312.983) 72.702,312.915 R708.2@73.541,312.915
SFP1_Tx_P: C58.1 J33.13 R707.2 | length 8.3
  L16 w0.101: J33.13@67.104,314.147 cw(c67.304,314.147) 67.304,314.346 70.488,314.346 cw(c70.488,314.058) 70.776,314.058 70.776,313.29 ccw(c71.808,313.29) 71.808,312.258 72.31,312.258 cw(c72.31,311.933) C58.1@72.634,311.933 cw(c72.702,311.933) 72.702,312.001 R707.2@73.541,312.001
SFP1_TxDis: J33.3 R138.1 U35_I2C_Expander_SFP.23 | length 31.1
  L1 w0.12: v7(35.903,313.747) 35.906,313.75 36.949,313.75 U35_I2C_Expander_SFP.23@36.952,313.753 ; R138.1@54.779,312.59 v1(55.702,312.59)
  L3 (Sign) w0.12: v7(35.903,313.747) 35.568,314.082 35.568,314.542 38.882,317.857 48.309,317.857 51.982,314.183 54.109,314.183 v1(55.702,312.59)
  L16 w0.12: v1(55.702,312.59) 56.223,312.069 56.223,311.218 56.769,310.671 58.78,310.671 J33.3@58.904,310.547
SFP1_TxF: J33.2 R137.1 U35_I2C_Expander_SFP.22 | length 30.2
  L1 w0.12: v7(35.903,314.403) U35_I2C_Expander_SFP.22@36.952,314.403 ; R137.1@54.779,311.684 v1(55.702,311.684)
  L3 (Sign) w0.12: v7(35.903,314.403) 39.114,317.614 48.24,317.614 51.891,313.963 53.423,313.963 v1(55.702,311.684)
  L16 w0.12: v1(55.702,311.684) 55.702,310.553 56.514,309.741 58.899,309.741 J33.2@58.904,309.747
SFP1_VccR: C207.2 C208.1 J33.15 L3.2 | length 9.8
  L1 w0.4: v1(65.684,312.56) 67.183,314.058 72.715,314.058 L3.2@73.226,313.547
  L16 w0.4: v1(65.684,312.56) 65.697,312.547 J33.15@67.104,312.547
SFP1_VccT: C209.2 C210.1 J33.16 L4.2 | length 10.1
  L1 w0.4: v1@65.696,311.727 65.696,311.364 66.939,310.121 71.427,310.121 71.976,310.67 L4.2@73.226,310.67
  L16 w0.4: v1(65.676,311.747) J33.16@67.104,311.747
SFP2_ABS: J34.6 R145.1 | length 4.4
  L1 w0.12: R145.1@54.794,270.912 v1(55.639,270.912)
  L16 w0.12: v1(55.639,270.912) 56.355,270.197 J34.6@58.904,270.197
SFP2_LOS: J34.8 R146.1 U35_I2C_Expander_SFP.27 | length 55
  L1 w0.12: v7(35.903,311.153) U35_I2C_Expander_SFP.27@36.952,311.153 ; R146.1@54.794,271.797 v1(55.639,271.797)
  L3 (Sign) w0.12: v7(35.903,311.153) 35.671,310.921 35.671,301.015 41.626,295.06 41.626,282.262 52.091,271.797 v1(55.639,271.797)
  L16 w0.12: v1(55.639,271.797) J34.8@58.904,271.797
SFP2_RS0: J34.7 R152.2 R154.1 | length 7.3
  L1 w0.2: R154.1@54.105,273.456 v1(54.813,273.456) R152.2@55.514,273.456
  L14 (Sign) w0.2: v1(54.813,273.456) 54.847,273.423 55.792,273.423 56.938,272.276 v10(56.938,271.005)
  L16 w0.2: v10(56.938,271.005) 58.896,271.005 J34.7@58.904,270.997
SFP2_RS1: J34.9 R151.2 R153.1 | length 6.3
  L1 w0.2: R153.1@54.105,274.472 R151.2@55.514,274.472
  L16 w0.2: v1(54.794,274.472) 55.524,274.472 57.4,272.597 J34.9@58.904,272.597
SFP2_Rx_FPGA_N: C112.1 R834.1 U1.B5 | length 9.8
  L1 w0.1: U1.B5@163.395,292.538 U1.B5@163.397,292.539 v2(163.883,293.025)
  L3 (Sign) w0.081: v2(163.883,293.025) 163.692,293.025 ccw(c163.692,292.87) 163.537,292.87 163.537,292.511 ccw(c163.906,292.511) 163.906,292.143 cw(c163.906,291.594) 164.455,291.594 164.455,289.036 ccw(c165.731,289.036) 164.828,288.133 ; 164.829,288.133 cw(c164.27,287.573) 165.061,287.573 165.061,287.011 v3(165.221,287.011)
  L16 w0.101: v3(165.221,287.011) ccw(c165.221,286.961) 165.171,286.961 165.171,286.446 ccw(c165.447,286.446) C112.1@165.447,286.169 ccw(c165.447,286.101) 165.38,286.101 R834.1@165.38,285.262
SFP2_Rx_FPGA_P: C112.2 R833.1 U1.B6 | length 9.8
  L1 w0.1: v2(162.911,293.053) U1.B6@163.397,293.539 U1.B6@163.398,293.541
  L3 (Sign) w0.081: v2(162.911,293.053) 163.073,293.053 cw(c163.073,292.87) 163.256,292.87 163.256,292.511 ccw(c163.906,292.511) 163.906,291.862 cw(c163.906,291.594) 164.174,291.594 164.174,289.035 ccw(c165.729,289.035) 164.629,287.936 ; v3(164.621,287.011) 164.78,287.011 164.78,287.572 ccw(c164.267,287.572) 164.63,287.935
  L16 w0.101: R833.1@164.465,285.262 164.465,286.101 ccw(c164.397,286.101) C112.2@164.397,286.169 ccw(c164.397,286.442) 164.671,286.442 164.671,286.961 ccw(c164.621,286.961) v3(164.621,287.011)
SFP2_Rx_N: C113.2 J34.19 R834.2 | length 114.3
  L12 (Sign) w0.081: v1(69.113,266.697) cw(c69.273,266.697) 69.273,266.856 75.332,266.856 ccw(c75.332,267.427) 75.903,267.427 75.903,269.127 cw(c76.892,269.127) 76.892,270.117 124.26,270.117 ccw(c124.26,271.111) 125.254,271.111 125.254,276.375 ; 125.256,276.366 cw(c125.684,276.366) 125.684,276.794 164.142,276.794 ccw(c164.142,277.715) 165.063,277.715 165.063,281.213 165.222,281.373 v17(165.222,281.47)
  L14 (Sign) w0.081: v17(165.222,281.47) 165.222,281.568 165.063,281.727 165.063,282.239 cw(c165.222,282.239) v14(165.222,282.398)
  L16 w0.101: J34.19@67.104,266.597 cw(c67.204,266.597) 67.204,266.697 v1(69.113,266.697) ; v14(165.222,282.398) 165.123,282.498 165.123,282.885 165.123,283.028 165.182,283.087 165.223,283.087 165.447,283.312 C113.2@165.447,283.362 cw(c165.447,283.43) 165.38,283.43 R834.2@165.38,284.262
SFP2_Rx_P: C113.1 J34.18 R833.2 | length 114.3
  L12 (Sign) w0.081: v1(69.113,267.297) ccw(c69.273,267.297) 69.273,267.137 75.332,267.137 ccw(c75.332,267.427) 75.622,267.427 75.622,269.127 cw(c76.892,269.127) 76.892,270.398 119.396,270.398 119.436,270.398 ccw(c119.436,270.569) 119.607,270.569 119.607,270.595 cw(c119.777,270.595) 119.777,270.765 119.924,270.765 cw(c119.924,270.595) 120.094,270.595 120.094,270.569 ccw(c120.265,270.569) 120.265,270.398 120.695,270.398 124.26,270.398 ccw(c124.26,271.111) 124.973,271.111 124.973,276.366 124.973,276.375 ; 124.975,276.366 cw(c125.684,276.366) 125.684,277.075 164.142,277.075 ccw(c164.142,277.715) 164.782,277.715 164.782,281.213 164.622,281.373 v17(164.622,281.47)
  L14 (Sign) w0.081: v17(164.622,281.47) 164.622,281.568 164.782,281.727 164.782,282.239 ccw(c164.622,282.239) v14(164.622,282.398)
  L16 w0.101: J34.18@67.104,267.397 ccw(c67.204,267.397) 67.204,267.297 v1(69.113,267.297) ; R833.2@164.465,284.262 164.465,283.43 cw(c164.397,283.43) C113.1@164.397,283.362 164.397,283.312 164.622,283.087 164.663,283.087 164.722,283.028 164.722,282.719 164.722,282.504 164.622,282.404 v14(164.622,282.398)
SFP2_Tx_FPGA_N: C111.1 R832.1 U1.B1 | length 116.2
  L1 w0.1: v2(162.909,289.027) U1.B1@163.397,288.539
  L12 (Sign) w0.081: v1(82.003,272.129) 82.003,272.09 82.017,272.076 ccw(c82.169,272.076) 82.169,271.924 83.687,271.924 83.868,271.924 ccw(c83.868,272.162) 84.105,272.162 84.105,273.235 cw(c84.623,273.235) 84.623,273.753 84.94,273.753 cw(c84.94,273.235) 85.458,273.235 85.458,271.451 ccw(c85.695,271.451) 85.695,271.213 86.012,271.213 ccw(c86.012,271.451) 86.249,271.451 86.249,272.452 cw(c86.768,272.452) 86.768,272.97 87.084,272.97 cw(c87.084,272.452) 87.602,272.452 87.602,272.162 ccw(c87.84,272.162) 87.84,271.924 89.26,271.924 93.069,271.924 93.11,271.924 ccw(c93.11,272.095) 93.281,272.095 93.281,272.341 cw(c93.451,272.341) 93.451,272.512 93.597,272.512 cw(c93.597,272.341) 93.768,272.341 93.768,272.095 ccw(c93.939,272.095) 93.939,271.924 94.907,271.924 123.177,271.924 ccw(c123.177,272.292) 123.545,272.292 123.545,277.277 cw(c124.203,277.277) 124.203,277.935 163.237,277.935 ccw(c163.237,278.432) 163.735,278.432 163.735,283.676 ccw(c163.057,283.676) 163.536,284.156 ; v3(163.24,285.318) ccw(c163.476,285.318) 163.309,285.152 cw(c163.09,284.933) 163.4,284.933 163.4,284.485 ccw(c163.865,284.485) 163.536,284.157
  L3 (Sign) w0.081: v2(162.909,289.027) 163.014,289.027 cw(c163.014,288.785) 163.256,288.785 163.256,287.007 163.256,286.334 163.4,286.19 163.4,285.478 cw(c163.24,285.478) v3(163.24,285.318)
  L16 w0.101: R832.1@72.468,272.241 73.3,272.241 ccw(c73.3,272.309) C111.1@73.368,272.309 ccw(c73.693,272.309) 73.693,271.984 81.924,271.984 ccw(c81.924,272.076) 82.017,272.076 82.003,272.09 v1(82.003,272.129)
SFP2_Tx_FPGA_P: C111.2 R831.1 U1.B2 | length 116.1
  L1 w0.1: U1.B2@163.397,289.539 v2(163.884,289.052)
  L12 (Sign) w0.081: v1(82.003,271.465) 82.003,271.477 82.017,271.491 cw(c82.169,271.491) 82.169,271.643 83.687,271.643 83.868,271.643 ccw(c83.868,272.162) 84.386,272.162 84.386,273.235 cw(c84.623,273.235) 84.623,273.472 84.94,273.472 cw(c84.94,273.235) 85.177,273.235 85.177,271.451 ccw(c85.695,271.451) 85.695,270.932 86.012,270.932 ccw(c86.012,271.451) 86.53,271.451 86.53,272.452 cw(c86.768,272.452) 86.768,272.689 87.084,272.689 cw(c87.084,272.452) 87.321,272.452 87.321,272.162 ccw(c87.84,272.162) 87.84,271.643 89.26,271.643 123.177,271.643 ccw(c123.177,272.292) 123.826,272.292 123.826,273.207 123.826,274 cw(c123.91,274) 123.91,274.084 124.03,274.084 ccw(c124.03,274.167) 124.114,274.167 124.114,274.335 ccw(c124.03,274.335) 124.03,274.419 123.91,274.419 cw(c123.91,274.503) 123.826,274.503 123.826,274.543 123.826,277.277 cw(c124.203,277.277) 124.203,277.654 163.237,277.654 ccw(c163.237,278.432) 164.016,278.432 164.016,283.678 ccw(c163.059,283.678) 163.736,284.354 ; 163.735,284.355 cw(c163.866,284.486) 163.681,284.486 163.681,284.933 cw(c163.99,284.933) 163.771,285.152 ccw(c163.605,285.318) v3(163.84,285.318)
  L3 (Sign) w0.081: v3(163.84,285.318) cw(c163.84,285.478) 163.681,285.478 163.681,286.307 163.537,286.45 163.537,287.17 163.537,288.785 cw(c163.805,288.785) 163.805,289.052 v2(163.884,289.052)
  L16 w0.101: R831.1@72.468,271.326 73.3,271.326 cw(c73.3,271.259) C111.2@73.368,271.259 cw(c73.693,271.259) 73.693,271.583 81.924,271.583 cw(c81.924,271.491) 82.017,271.491 82.003,271.477 v1(82.003,271.465)
SFP2_Tx_N: C69.2 J34.12 R832.2 | length 4.7
  L16 w0.101: J34.12@67.104,272.197 ccw(c67.304,272.197) 67.304,271.997 70.25,271.997 ccw(c70.25,272.309) C69.2@70.561,272.309 ccw(c70.629,272.309) 70.629,272.241 R832.2@71.468,272.241
SFP2_Tx_P: C69.1 J34.13 R831.2 | length 4.7
  L16 w0.101: J34.13@67.104,271.397 cw(c67.304,271.397) 67.304,271.596 70.224,271.596 cw(c70.224,271.259) C69.1@70.561,271.259 cw(c70.629,271.259) 70.629,271.326 R831.2@71.468,271.326
SFP2_TxDis: J34.3 R148.1 U35_I2C_Expander_SFP.26 | length 58.2
  L1 w0.12: v7(35.903,311.79) 35.909,311.797 36.946,311.797 U35_I2C_Expander_SFP.26@36.952,311.803 ; R148.1@54.794,270.046 v1(55.639,270.046)
  L3 (Sign) w0.12: v7(35.903,311.79) 35.451,311.339 35.451,300.923 41.406,294.968 41.406,282.171 52,271.577 54.108,271.577 v1(55.639,270.046)
  L16 w0.12: v1(55.639,270.046) 56.22,269.466 56.22,268.495 56.728,267.987 58.714,267.987 J34.3@58.904,267.797
SFP2_TxF: J34.2 R147.1 U35_I2C_Expander_SFP.25 | length 59.3
  L1 w0.12: v7(35.903,312.517) 35.935,312.485 36.92,312.485 U35_I2C_Expander_SFP.25@36.952,312.453 ; R147.1@54.798,269.173 v1(55.639,269.173)
  L3 (Sign) w0.12: v7(35.903,312.517) 35.231,311.846 35.231,300.832 41.186,294.877 41.186,282.08 51.909,271.357 53.455,271.357 v1(55.639,269.173)
  L16 w0.12: v1(55.639,269.173) 55.66,269.151 55.66,268.743 57.216,267.187 58.714,267.187 J34.2@58.904,266.997
SFP2_VccR: C211.2 C212.1 J34.15 L5.2 | length 9.2
  L1 w0.4: v1(65.66,269.797) 66.48,269.797 67.397,270.713 72.804,270.713 L5.2@72.948,270.856
  L16 w0.4: v1(65.66,269.797) J34.15@67.104,269.797
SFP2_VccT: C213.2 C214.1 J34.16 L6.2 | length 7.6
  L1 w0.4: v1(72.235,269.011) 72.235,268.198 L6.2@72.948,267.486
  L16 w0.4: J34.16@67.104,268.997 68.176,268.997 68.999,268.173 71.397,268.173 v1(72.235,269.011)
SFP3_ABS: J35.6 R155.1 | length 4.5
  L1 w0.12: R155.1@54.767,299.431 55.905,299.431 v1(55.927,299.453)
  L16 w0.12: v1(55.927,299.453) 55.949,299.431 56.298,299.431 57.033,298.697 J35.6@58.904,298.697
SFP3_LOS: J35.8 R156.1 U35_I2C_Expander_SFP.19 | length 33.7
  L1 w0.12: U35_I2C_Expander_SFP.19@39.177,315.328 v7(39.177,316.297) ; R156.1@54.776,300.308 v1(55.905,300.308)
  L3 (Sign) w0.12: v7(39.177,316.297) 39.732,316.852 43.998,316.852 50.344,310.506 50.344,302.315 52.35,300.308 v1(55.905,300.308)
  L16 w0.12: v1(55.905,300.308) J35.8@58.892,300.308
SFP3_RS0: J35.7 R162.2 R164.1 | length 7.4
  L1 w0.2: R164.1@53.532,302.189 v1(54.204,302.189) R162.2@54.871,302.189
  L14 (Sign) w0.2: v1(54.204,302.189) 54.973,302.189 57.112,300.05 v10(57.112,299.652)
  L16 w0.2: v10(57.112,299.652) 57.267,299.497 J35.7@58.904,299.497
SFP3_RS1: J35.9 R161.2 R163.1 | length 6.9
  L1 w0.2: R163.1@53.532,303.205 R161.2@54.871,303.205
  L16 w0.2: v1(54.204,303.225) 56.332,301.097 J35.9@58.904,301.097
SFP3_Rx_FPGA_N: C116.1 R844.1 U1.A7 | length 12.2
  L16 w0.09: 161.397,294.099 161.529,294.099 ccw(c161.484,294.551) 161.535,294.1 ccw(c161.484,294.551) 161.938,294.551 161.938,294.74 cw(c162.092,294.74) 162.092,294.894 162.246,294.894 cw(c162.246,294.743) 162.397,294.743 v1(162.397,294.539)
  L16 w0.101: R844.1@156.311,293.836 157.15,293.836 cw(c157.15,293.768) C116.1@157.217,293.768 157.217,293.814 cw(c157.532,293.814) 157.374,294.085 cw(c157.532,293.814) 157.4,294.099 157.596,294.099 158.603,294.099 cw(c158.603,293.993) 158.71,293.993 158.71,292.816 ccw(c159.217,292.816) 159.217,292.309 159.359,292.309 ccw(c159.359,292.816) 159.867,292.816 159.867,295.134 cw(c159.973,295.134) 159.973,295.241 160.115,295.241 cw(c160.115,295.134) 160.222,295.134 160.222,294.606 ccw(c160.729,294.606) 160.729,294.099 161.374,294.099 161.397,294.099
SFP3_Rx_FPGA_P: C116.2 R843.1 U1.A8 | length 12.1
  L16 w0.09: 161.397,294.5 161.397,294.499 161.434,294.493 161.505,294.48 ccw(c161.461,294.662) 161.539,294.491 ccw(c161.461,294.662) 161.648,294.662 161.648,294.74 cw(c162.092,294.74) 162.092,295.184 162.246,295.184 ccw(c162.246,295.335) 162.397,295.335 v1(162.397,295.539)
  L16 w0.101: R843.1@156.311,294.75 157.15,294.75 ccw(c157.15,294.818) C116.2@157.217,294.818 157.217,294.766 ccw(c157.509,294.766) 157.367,294.511 ccw(c157.509,294.766) 157.39,294.5 157.596,294.5 158.603,294.5 cw(c158.603,293.993) 159.111,293.993 159.111,292.816 ccw(c159.217,292.816) 159.217,292.71 159.359,292.71 ccw(c159.359,292.816) 159.466,292.816 159.466,295.134 cw(c159.973,295.134) 159.973,295.642 160.115,295.642 cw(c160.115,295.134) 160.623,295.134 160.623,294.606 ccw(c160.729,294.606) 160.729,294.5 161.374,294.5 161.397,294.5
SFP3_Rx_N: C117.2 J35.19 R844.2 | length 114.3
  L12 (Sign) w0.081: v17(92.727,295.749) cw(c92.837,295.749) 92.837,295.859 98.889,295.859 ccw(c98.889,298.316) 100.627,296.579 101.332,297.284 cw(c103.128,295.488) 103.128,298.028 107.834,298.028 cw(c107.834,295.518) 109.609,297.292 109.611,297.29 ccw(c110.822,298.501) 110.822,296.789 124.459,296.789 cw(c124.459,296.179) 125.069,296.179 125.069,288.992 ccw(c126.25,288.992) 126.25,287.811 130.074,287.811 130.963,287.811 cw(c130.963,287.299) 131.475,287.299 131.475,285.489 ccw(c132.268,285.489) 132.268,284.696 132.951,284.696 ccw(c132.951,285.489) 133.744,285.489 133.744,287.335 cw(c134.256,287.335) 134.256,287.847 134.938,287.847 cw(c134.938,287.335) 135.45,287.335 135.45,285.489 ccw(c136.243,285.489) 136.243,284.696 136.926,284.696 ccw(c136.926,285.489) 137.719,285.489 137.719,287.299 cw(c138.231,287.299) 138.231,287.811 138.412,287.811 149.351,287.811 ccw(c149.351,288.827) 150.368,288.827 150.368,293.037 cw(c151.482,293.037) 151.482,294.152 152.499,294.152 152.659,293.993 v17(152.685,293.993)
  L14 (Sign) w0.081: v10(80.531,295.699) ccw(c80.531,295.935) 80.697,295.768 80.708,295.779 cw(c80.9,295.587) 80.9,295.859 87.701,295.859 88.127,295.859 cw(c88.127,295.778) 88.208,295.778 88.208,295.738 ccw(c88.266,295.738) 88.266,295.681 88.536,295.681 ccw(c88.536,295.738) 88.594,295.738 88.594,295.778 cw(c88.675,295.778) 88.675,295.859 88.873,295.859 92.587,295.859 92.674,295.859 92.688,295.845 cw(c92.592,295.749) v17(92.727,295.749) ; v17(152.685,293.993) 152.782,293.993 152.941,294.152 153.306,294.152 cw(c153.306,293.993) v14(153.465,293.993)
  L16 w0.101: J35.19@67.104,295.097 cw(c67.304,295.097) 67.304,295.296 76.28,295.296 ccw(c76.28,296.372) 77.041,295.611 77.042,295.613 cw(c77.491,295.164) 77.491,295.799 80.256,295.799 cw(c80.256,295.759) 80.284,295.787 ccw(c80.312,295.815) 80.312,295.776 80.346,295.776 cw(c80.346,295.515) v10(80.531,295.699) ; v14@153.492,294.092 154.086,294.092 cw(c154.086,293.768) C117.2@154.411,293.768 cw(c154.479,293.768) 154.479,293.836 R844.2@155.311,293.836
SFP3_Rx_P: C117.1 J35.18 R843.2 | length 114.4
  L12 (Sign) w0.081: v17(92.74,296.306) 92.74,296.237 92.727,296.249 ccw(c92.837,296.249) 92.837,296.14 98.886,296.14 ccw(c98.886,298.324) 100.431,296.78 101.134,297.483 cw(c103.127,295.49) 103.127,298.309 107.835,298.309 cw(c107.835,295.519) 109.807,297.492 ; 109.808,297.491 ccw(c110.825,298.508) 110.825,297.07 124.459,297.07 cw(c124.459,296.179) 125.35,296.179 125.35,288.992 ccw(c126.25,288.992) 126.25,288.092 130.074,288.092 130.963,288.092 cw(c130.963,287.299) 131.756,287.299 131.756,285.489 ccw(c132.268,285.489) 132.268,284.977 132.951,284.977 ccw(c132.951,285.489) 133.463,285.489 133.463,287.335 cw(c134.256,287.335) 134.256,288.128 134.938,288.128 cw(c134.938,287.335) 135.731,287.335 135.731,285.489 ccw(c136.243,285.489) 136.243,284.977 136.926,284.977 ccw(c136.926,285.489) 137.438,285.489 137.438,287.299 cw(c138.231,287.299) 138.231,288.092 138.412,288.092 149.351,288.092 ccw(c149.351,288.827) 150.087,288.827 150.087,293.037 cw(c151.482,293.037) 151.482,294.433 152.499,294.433 152.659,294.593 v17(152.685,294.593)
  L14 (Sign) w0.081: v10(80.531,296.299) cw(c80.531,296.064) 80.697,296.231 ; 80.697,296.231 80.708,296.22 ccw(c80.9,296.412) 80.9,296.14 81.246,296.14 92.674,296.14 92.688,296.154 ccw(c92.592,296.249) 92.727,296.249 92.74,296.237 v17(92.74,296.306) ; v17(152.685,294.593) 152.782,294.593 152.941,294.433 153.306,294.433 ccw(c153.306,294.593) v14(153.465,294.593)
  L16 w0.101: J35.18@67.104,295.897 ccw(c67.304,295.897) 67.304,295.697 76.277,295.697 ccw(c76.277,296.378) 76.759,295.897 ; 76.76,295.897 cw(c77.49,295.167) 77.49,296.2 80.256,296.2 ccw(c80.256,296.24) 80.284,296.212 cw(c80.312,296.184) 80.312,296.223 80.346,296.223 ccw(c80.346,296.484) v10(80.531,296.299) ; v14(153.465,294.593) 153.392,294.593 ccw(c153.492,294.593) 153.492,294.493 154.086,294.493 ccw(c154.086,294.818) C117.1@154.411,294.818 ccw(c154.479,294.818) 154.479,294.75 R843.2@155.311,294.75
SFP3_Tx_FPGA_N: C115.1 R842.1 U1.A4 | length 116.2
  L1 w0.09: 161.397,291.295 161.631,291.295 cw(c161.631,291.184) 161.742,291.184
  L1 w0.1: 161.742,291.184 162.042,291.184 ccw(c162.042,291.539) U1.A4@162.397,291.539
  L1 w0.101: v3(153.924,288.898) 154,288.821 154.16,288.821 154.183,288.798 160.136,288.798 ccw(c160.136,289.384) 160.722,289.384 160.722,290.621 cw(c161.397,290.621) 161.397,291.295
  L14 (Sign) w0.081: v10(77.766,298.488) ccw(c77.766,298.329) 77.607,298.329 77.607,295.681 ccw(c78.416,295.681) 78.416,294.871 95.13,294.871 95.311,294.871 ccw(c95.311,295.109) 95.549,295.109 95.549,296.182 cw(c96.067,296.182) 96.067,296.7 96.384,296.7 cw(c96.384,296.182) 96.902,296.182 96.902,293.561 ccw(c97.139,293.561) 97.139,293.324 97.456,293.324 ccw(c97.456,293.561) 97.693,293.561 97.693,295.35 cw(c98.212,295.35) 98.212,295.868 98.528,295.868 cw(c98.528,295.35) 99.046,295.35 99.046,295.109 ccw(c99.284,295.109) 99.284,294.871 100.171,294.871 107.495,294.871 107.676,294.871 ccw(c107.676,295.048) 107.853,295.048 107.853,296.3 cw(c108.31,296.3) 108.31,296.758 108.546,296.758 cw(c108.546,296.3) 109.004,296.3 109.004,295.048 ccw(c109.18,295.048) 109.18,294.871 109.993,294.871 113.132,294.871 115.33,294.871 121.137,294.871 121.903,294.871 cw(c121.903,294.414) 122.36,294.414 122.36,293.162 ccw(c122.537,293.162) 122.537,292.985 122.773,292.985 ccw(c122.773,293.162) 122.949,293.162 122.949,294.414 cw(c123.407,294.414) 123.407,294.871 123.588,294.871 123.852,294.871 cw(c123.852,293.306) 125.417,293.306 125.417,288.868 ccw(c126.32,288.868) 126.32,287.964 148.394,287.964 ccw(c148.394,289.018) 149.139,288.273 149.331,288.465 cw(c149.991,287.805) 149.991,288.738 153.667,288.738 153.827,288.898 v3(153.924,288.898)
  L16 w0.101: R842.1@74.055,300.77 cw(c74.055,300.65) 74.141,300.735 74.28,300.596 ccw(c74.336,300.596) 74.296,300.557 ccw(c74.4,300.66) 74.4,300.514 74.58,300.514 ccw(c74.58,300.615) 74.651,300.543 74.667,300.558 ccw(c74.632,300.593) 74.681,300.593 cw(c74.73,300.593) 74.695,300.628 74.87,300.803 cw(c74.956,300.717) C115.1@74.956,300.838 cw(c74.956,300.717) 75.041,300.803 75.216,300.628 cw(c75.181,300.593) 75.23,300.593 ccw(c75.279,300.593) 75.244,300.558 ccw(c75.352,300.666) 75.352,300.514 76.764,300.514 cw(c76.764,299.611) 77.667,299.611 77.667,298.588 ccw(c77.766,298.588) v10(77.766,298.488)
SFP3_Tx_FPGA_P: C115.2 R841.1 U1.A3 | length 116.2
  L1 w0.09: 161.397,290.894 162.042,290.894
  L1 w0.1: 162.042,290.894 cw(c162.042,290.539) U1.A3@162.397,290.539
  L1 w0.101: v3(153.924,288.298) 154,288.374 154.16,288.374 154.183,288.397 160.136,288.397 ccw(c160.136,289.384) 161.123,289.384 161.123,290.621 cw(c161.397,290.621) 161.397,290.894
  L14 (Sign) w0.081: v10(77.166,298.488) cw(c77.166,298.329) 77.326,298.329 77.326,295.681 ccw(c78.416,295.681) 78.416,294.59 95.13,294.59 95.311,294.59 ccw(c95.311,295.109) 95.83,295.109 95.83,296.182 cw(c96.067,296.182) 96.067,296.419 96.384,296.419 cw(c96.384,296.182) 96.621,296.182 96.621,293.561 ccw(c97.139,293.561) 97.139,293.043 97.456,293.043 ccw(c97.456,293.561) 97.974,293.561 97.974,295.35 cw(c98.212,295.35) 98.212,295.587 98.528,295.587 cw(c98.528,295.35) 98.765,295.35 98.765,295.109 ccw(c99.284,295.109) 99.284,294.59 100.171,294.59 107.495,294.59 107.676,294.59 ccw(c107.676,295.048) 108.134,295.048 108.134,296.3 cw(c108.31,296.3) 108.31,296.477 108.546,296.477 cw(c108.546,296.3) 108.723,296.3 108.723,295.048 ccw(c109.18,295.048) 109.18,294.59 109.993,294.59 113.132,294.59 115.33,294.59 116.408,294.59 116.784,294.59 cw(c116.784,294.507) 116.868,294.507 116.868,294.476 ccw(c116.952,294.476) 116.952,294.393 117.119,294.393 ccw(c117.119,294.476) 117.203,294.476 117.203,294.507 cw(c117.287,294.507) 117.287,294.59 117.581,294.59 121.137,294.59 121.903,294.59 cw(c121.903,294.414) 122.079,294.414 122.079,293.162 ccw(c122.537,293.162) 122.537,292.704 122.773,292.704 ccw(c122.773,293.162) 123.23,293.162 123.23,294.414 cw(c123.407,294.414) 123.407,294.59 123.588,294.59 123.852,294.59 cw(c123.852,293.306) 125.136,293.306 125.136,288.868 ccw(c126.32,288.868) 126.32,287.683 148.395,287.683 ccw(c148.395,289.015) 149.337,288.073 149.529,288.265 cw(c149.993,287.8) 149.993,288.457 ; 149.993,288.457 153.667,288.457 153.827,288.298 v3(153.924,288.298)
  L16 w0.101: R841.1@74.055,299.856 ccw(c74.055,299.977) R841.1@74.141,299.891 ; R841.1@74.141,299.891 74.28,300.03 cw(c74.336,300.03) 74.296,300.07 cw(c74.4,299.966) 74.4,300.113 74.58,300.113 cw(c74.58,300.012) 74.651,300.083 74.667,300.068 cw(c74.632,300.033) 74.681,300.033 ccw(c74.73,300.033) 74.695,299.998 74.87,299.824 ccw(c74.956,299.909) C115.2@74.956,299.788 ccw(c74.956,299.909) C115.2@75.041,299.823 ; C115.2@75.041,299.824 75.216,299.998 ccw(c75.181,300.033) 75.23,300.033 cw(c75.279,300.033) 75.244,300.068 cw(c75.352,299.96) 75.352,300.113 76.764,300.113 cw(c76.764,299.611) 77.266,299.611 77.266,298.588 cw(c77.166,298.588) v10(77.166,298.488)
SFP3_Tx_N: C114.2 J35.12 R842.2 | length 6.4
  L16 w0.101: J35.12@67.104,300.697 ccw(c67.586,301.178) 67.586,300.497 69.418,300.497 cw(c69.458,300.457) 69.458,300.514 71.773,300.514 ccw(c71.773,300.615) 71.844,300.543 ; 71.845,300.543 71.86,300.558 ccw(c71.825,300.593) 71.874,300.593 cw(c71.923,300.593) 71.889,300.628 72.063,300.803 cw(c72.149,300.717) C114.2@72.149,300.838 cw(c72.149,300.717) 72.234,300.803 72.409,300.628 cw(c72.374,300.593) 72.423,300.593 ccw(c72.472,300.593) 72.438,300.558 72.453,300.543 ccw(c72.524,300.615) 72.524,300.514 72.711,300.514 ccw(c72.711,300.66) 72.815,300.557 ccw(c72.775,300.596) 72.831,300.596 72.97,300.735 cw(c73.055,300.65) R842.2@73.055,300.77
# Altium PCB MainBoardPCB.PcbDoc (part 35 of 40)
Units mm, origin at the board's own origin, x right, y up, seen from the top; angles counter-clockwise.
Board outline 258.95 x 308.86 mm, 16 copper layers (L1, L2 (GND), L3 (Sign), L4 (GND), L5 (Sign), L6 (PWR/GND), L7(12V+Other), L8 (Plane_GND), L9 (PWR/GND), L10 (3V3+Other), L11 (PWR/GND), L12 (Sign), L13 (GND), L14 (Sign), L15 (GND), L16), stack 2.503 mm thick; 2578 components, 1867 nets, 8817 pads, 8021 vias.
Unrouted connection lines stored in the file: 25.

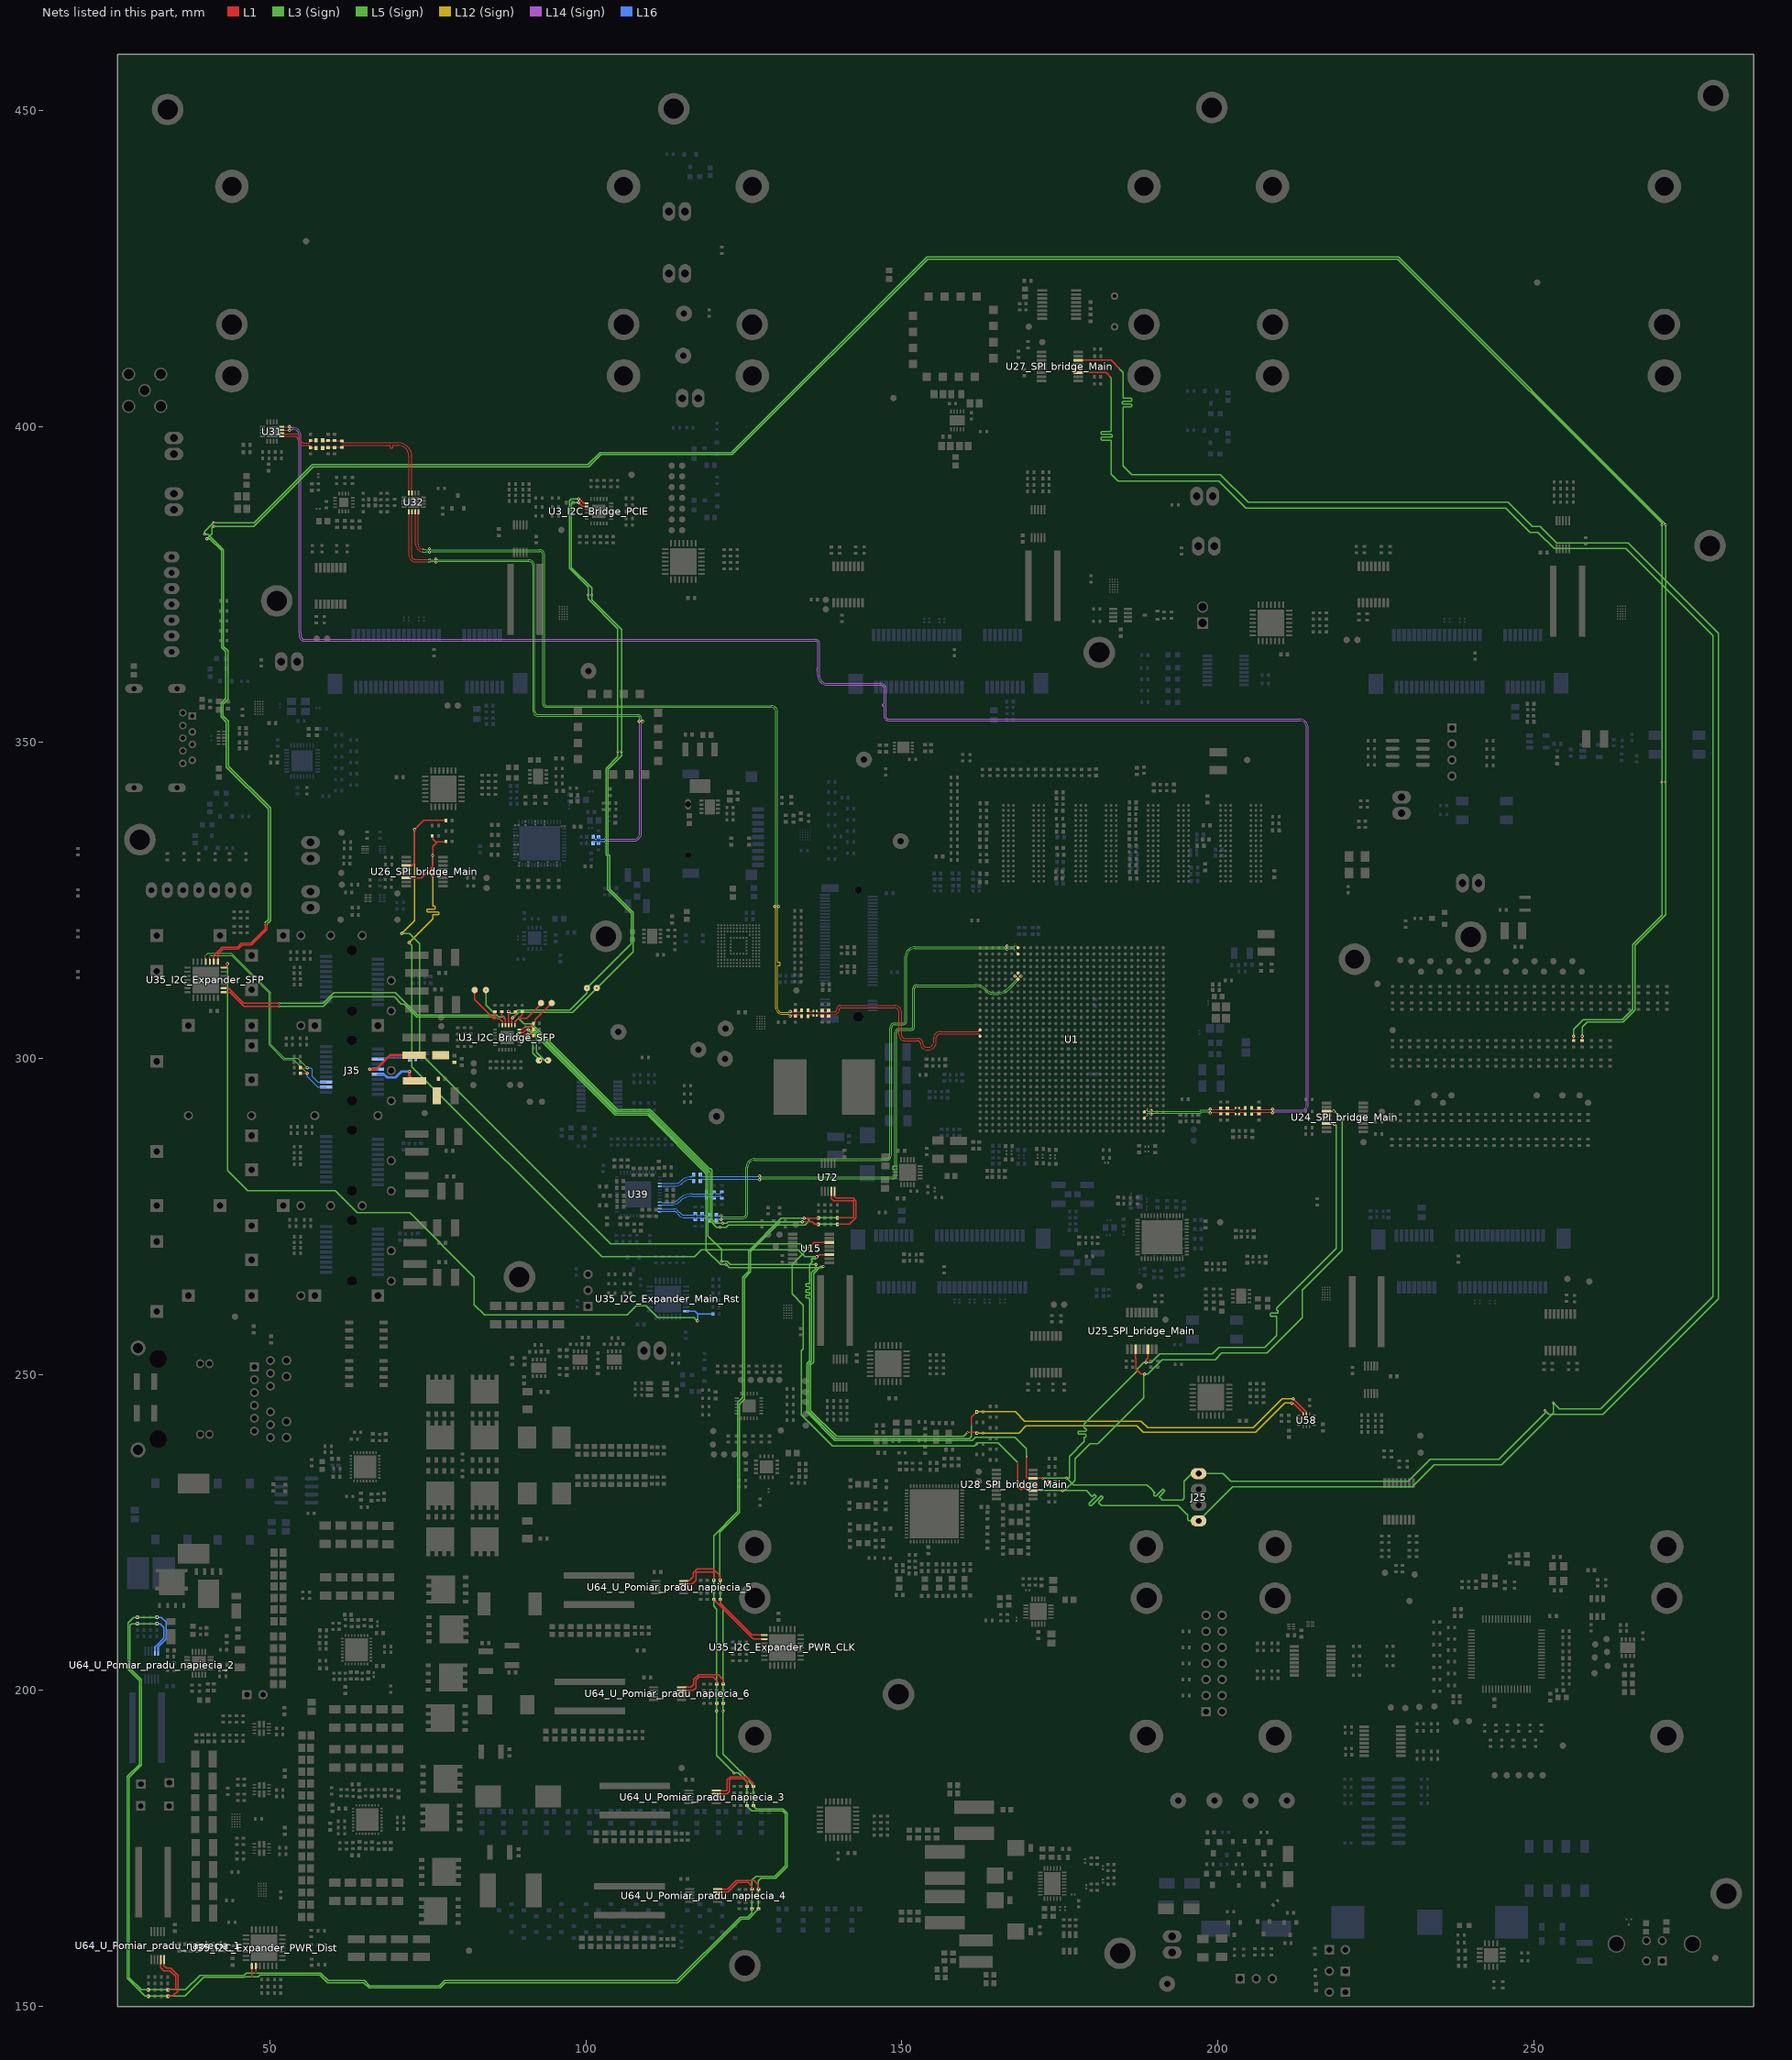
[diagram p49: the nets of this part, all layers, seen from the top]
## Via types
v1: diameter 0.5, hole 0.25, L1 to L16, tented both sides, 4341 vias
v2: diameter 0.254, hole 0.1, L1 to L3 (Sign), tented both sides, 781 vias
v3: diameter 0.5, hole 0.25, L1 to L16, 565 vias
v4: diameter 0.254, hole 0.1, L15 (GND) to L16, tented both sides, 406 vias
v5: diameter 0.254, hole 0.1, L1 to L2 (GND), tented both sides, 283 vias
v6: diameter 0.457, hole 0.2, L3 (Sign) to L6 (PWR/GND), tented both sides, 254 vias
v7: diameter 0.254, hole 0.1, L1 to L3 (Sign), 237 vias
v8: diameter 0.75, hole 0.4, L1 to L16, 200 vias
v9: diameter 0.8, hole 0.4, L1 to L16, tented both sides, 182 vias
v10: diameter 0.254, hole 0.1, L14 (Sign) to L16, tented both sides, 170 vias
v11: diameter 0.75/0/0/0/0/0/0/0/0/0/0/0/0/0/0/0.75 (per signal layer), hole 0.4, L1 to L16, 160 vias
v12: diameter 0.457, hole 0.2, L3 (Sign) to L6 (PWR/GND), 158 vias
v13: diameter 1.4, hole 0.5, L1 to L16, tented both sides, 80 vias
v14: diameter 0.254, hole 0.1, L14 (Sign) to L16, 65 vias
v15: diameter 0.254, hole 0.1, L1 to L2 (GND), 45 vias
v16: diameter 0.457, hole 0.2, L11 (PWR/GND) to L14 (Sign), tented both sides, 26 vias
v17: diameter 0.457, hole 0.2, L11 (PWR/GND) to L14 (Sign), 25 vias
v18: diameter 0.457, hole 0.2, L7(12V+Other) to L10 (3V3+Other), tented both sides, 11 vias
v19: diameter 0.254/0/0.254 (per signal layer), hole 0.1, L1 to L3 (Sign), 9 vias
v20: diameter 0.2/0/0.2 (per signal layer), hole 0.1, L1 to L3 (Sign), 6 vias
v21: diameter 1.65, hole 1.65, L1 to L16, 5 vias
v22: diameter 1.15, hole 1.15, L1 to L16, 5 vias
v23: diameter 0.457, hole 0.2, L1 to L16, 3 vias
v24: diameter 0.5, hole 0.3, L1 to L16, 2 vias
v25: diameter 0.5/0/0.5 (per signal layer), hole 0.2, L14 (Sign) to L16, 1 vias
v26: diameter 0.5, hole 0.25, L1 to L16, tented bottom, 1 vias

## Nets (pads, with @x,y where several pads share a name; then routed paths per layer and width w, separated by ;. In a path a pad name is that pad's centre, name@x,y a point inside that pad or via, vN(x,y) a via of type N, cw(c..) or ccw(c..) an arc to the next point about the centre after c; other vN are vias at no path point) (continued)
SFP3_Tx_P: C114.1 J35.13 R841.2 | length 6.4
  L16 w0.101: J35.13@67.104,299.897 cw(c67.586,299.415) 67.586,300.096 69.584,300.096 cw(c69.624,300.056) 69.624,300.113 71.773,300.113 cw(c71.773,300.012) 71.844,300.083 ; 71.845,300.083 71.86,300.068 cw(c71.825,300.033) 71.874,300.033 ccw(c71.923,300.033) 71.889,299.998 72.063,299.824 ccw(c72.149,299.909) C114.1@72.149,299.788 ccw(c72.149,299.909) C114.1@72.234,299.823 ; C114.1@72.234,299.824 72.409,299.998 ccw(c72.374,300.033) 72.423,300.033 cw(c72.472,300.033) 72.438,300.068 72.453,300.083 ; 72.453,300.083 cw(c72.524,300.012) 72.524,300.113 72.711,300.113 cw(c72.711,299.966) 72.815,300.07 cw(c72.775,300.03) 72.831,300.03 72.97,299.891 ccw(c73.055,299.977) R841.2@73.055,299.856
SFP3_TxDis: J35.3 R158.1 U35_I2C_Expander_SFP.18 | length 35.2
  L1 w0.12: U35_I2C_Expander_SFP.18@39.827,315.328 v7(39.827,316.297) ; R158.1@54.779,298.554 v1(55.905,298.554)
  L3 (Sign) w0.12: v7(39.827,316.297) 40.162,316.632 43.907,316.632 50.124,310.415 50.124,302.224 52.259,300.088 54.371,300.088 v1(55.905,298.554)
  L16 w0.12: v1(55.905,298.554) 56.398,298.554 56.718,298.234 56.718,297.155 57.594,296.278 58.886,296.278 J35.3@58.904,296.297
SFP3_TxF: J35.2 R157.1 U35_I2C_Expander_SFP.17 | length 34.2
  L1 w0.12: U35_I2C_Expander_SFP.17@40.477,315.328 v7(40.477,316.297) ; R157.1@54.779,297.677 v1(55.905,297.677)
  L3 (Sign) w0.12: v7(40.477,316.297) 43.931,316.297 49.904,310.324 49.904,302.133 52.168,299.868 53.714,299.868 v1(55.905,297.677)
  L16 w0.12: v1(55.905,297.677) 55.905,297.16 57.569,295.497 J35.2@58.904,295.497
SFP3_VccR: C215.2 C216.1 J35.15 L7.2 | length 9.3
  L1 w0.4: v1(65.778,298.297) 66.788,298.297 69.018,300.527 L7.2@72.812,300.527
  L16 w0.4: v1(65.778,298.297) J35.15@67.104,298.297
SFP3_VccT: C217.2 C218.1 J35.16 L8.2 | length 7.4
  L1 w0.4: v1(72.072,297.967) 72.072,297.285 L8.2@72.876,296.481
  L16 w0.4: J35.16@67.104,297.497 68.084,297.497 68.566,297.015 69.913,297.015 70.866,297.967 v1(72.072,297.967)
SFP_I2C4.SCL: R9_I2C_Bridge_SFP.2 R130.2 SP11_I2C_Bridge_SFP.1 U3_I2C_Bridge_SFP.11 U58.13 | length 189
  L1 w0.2: U3_I2C_Bridge_SFP.11@89.47,304.096 90.083,304.096 90.573,304.586 R9_I2C_Bridge_SFP.2@91.738,304.586 ; v1(93.837,299.717) SP11_I2C_Bridge_SFP.1@94.03,299.717 ; v2(161.05,241.884) 161.05,243.228 161.932,244.11 v1(161.882,244.11) ; v1(211.94,246.15) 214.053,244.036 U58.13@214.053,243.754
  L5 (Sign) w0.2: v1(90.894,304.553) 91.247,304.553 92.188,303.612 92.188,301.019 93.491,299.717 v1(93.837,299.717) ; v6(121.488,267.894) 122.371,267.894 122.841,267.424 v6(136.423,267.424)
  L12 (Sign) w0.2: v1(161.882,244.11) 167.951,244.11 169.436,242.625 187.866,242.625 188.922,241.569 205.61,241.569 210.191,246.15 v1(211.94,246.15)
  L3 (Sign) w0.2: v1(90.894,304.553) 91.338,304.109 92.016,304.109 104.776,291.349 109.902,291.349 119.35,281.902 119.35,271.933 121.488,269.795 v6(121.488,267.894) ; v6(136.423,267.424) 136.423,266.769 135.738,266.083 135.738,252.084 135.277,251.623 135.277,244.155 139.547,239.885 160.741,239.885 161.05,240.194 v2(161.05,241.884)
SFP_I2C4.SDA: R10_I2C_Bridge_SFP.2 R131.2 SP10_I2C_Bridge_SFP.1 U3_I2C_Bridge_SFP.10 U58.14 | length 184.1
  L1 w0.2: U3_I2C_Bridge_SFP.10@89.47,303.596 90.139,303.596 90.353,303.809 v1(90.805,303.809) 91.541,303.809 R10_I2C_Bridge_SFP.2@91.738,303.612 ; v2(160.422,240.851) 160.433,240.841 161.817,240.841 v1(161.932,240.725) ; v1(211.717,245.462) 211.775,245.404 212.028,245.404 213.553,243.879 U58.14@213.553,243.754
  L5 (Sign) w0.2: v1(90.805,303.809) 90.805,303.257 91.621,302.44 91.621,300.867 v1(92.794,299.695) ; v6(122.174,267.413) 122.174,267.461 122.706,266.929 137.414,266.929 v6(137.579,267.094)
  L12 (Sign) w0.2: v1(161.932,240.725) 168.538,240.725 169.682,241.869 187.232,241.869 188.227,240.874 205.98,240.874 210.6,245.494 211.685,245.494 v1(211.717,245.462)
  L3 (Sign) w0.2: v1(90.805,303.809) 91.892,303.809 104.652,291.049 109.778,291.049 119.05,281.777 119.05,269.685 121.321,267.413 v6(122.174,267.413) ; v6(137.579,267.094) 137.173,267.094 136.078,265.999 136.078,251.999 135.577,251.499 135.577,244.28 139.671,240.185 159.757,240.185 v2(160.422,240.851)
SFP_I2C5.SCL: R7_I2C_Bridge_SFP.2 R22.2 R389.2 R457.2 R465.2 R563.2 R567.2 R571.2 R575.2 R579.2 R583.2 R587.2 R591.2 R593.2 R597.2 SP14_I2C_Bridge_SFP.1 U3_I2C_Bridge_SFP.13 U35_I2C_Expander_PWR_CLK.8 U35_I2C_Expander_PWR_Dist.8 U64_U_Pomiar_pradu_napiecia_1.5 U64_U_Pomiar_pradu_napiecia_2.5 U64_U_Pomiar_pradu_napiecia_3.5 U64_U_Pomiar_pradu_napiecia_4.5 U64_U_Pomiar_pradu_napiecia_5.5 U64_U_Pomiar_pradu_napiecia_6.5 U72.5 | length 444.9
  L1 w0.2: U64_U_Pomiar_pradu_napiecia_1.5@33.245,157.414 33.245,156.428 33.62,156.053 34.279,156.053 35.433,154.898 35.433,152.426 34.629,151.621 34.195,151.621 v7(33.895,151.621) ; v2(47.143,154.724) U35_I2C_Expander_PWR_Dist.8@47.143,156.428 ; U3_I2C_Bridge_SFP.13@88.785,305.281 88.785,305.803 v2(89.373,306.39) ; R7_I2C_Bridge_SFP.2@89.93,307.492 89.93,306.948 v2(89.373,306.39) ; SP14_I2C_Bridge_SFP.1@92.913,308.775 92.913,308.626 90.678,306.39 v2(89.373,306.39) ; U64_U_Pomiar_pradu_napiecia_6.5@115.141,200.508 116.635,200.508 117.098,200.971 117.098,201.775 117.83,202.507 120.948,202.507 121.73,201.725 v7(121.73,201.096) ; U64_U_Pomiar_pradu_napiecia_5.5@115.471,217.348 116.336,217.348 117.003,218.014 117.003,218.623 117.669,219.289 120.147,219.289 121.26,218.177 R579.2@121.26,217.391 ; U64_U_Pomiar_pradu_napiecia_3.5@120.678,184.159 122.237,184.159 122.387,184.31 122.387,185.886 122.849,186.348 125.49,186.348 126.53,185.307 R563.2@126.53,184.76 ; U64_U_Pomiar_pradu_napiecia_4.5@120.849,168.56 120.861,168.572 122.445,168.572 123.794,169.921 126.654,169.921 127.313,169.262 R571.2@127.313,168.461 ; R583.2@121.26,214.459 121.26,213.825 126.306,208.778 U35_I2C_Expander_PWR_CLK.8@128.253,208.778 ; v1(134.277,274.142) 135.818,274.142 136.188,273.772 R389.2@136.866,273.772 ; U72.5@139.353,279.003 139.353,278.153 139.604,277.901 142.332,277.901 142.773,277.461 142.773,274.848 141.697,273.772 R22.2@139.754,273.772
  L5 (Sign) w0.2: v6(121.649,273.939) 122.295,273.939 122.498,274.142 v1(134.277,274.142) ; v6(121.73,196.761) 121.73,189.928 124.591,187.067 v6(124.649,187.067)
  L3 (Sign) w0.2: v1(32.183,211.587) v1(29.001,211.587) 28.44,211.587 27.584,210.731 27.584,203.361 29.38,201.566 29.38,188.311 27.437,186.368 27.437,154.465 30.281,151.621 v7(30.713,151.621) v7(33.895,151.621) 36.521,151.621 39.524,154.624 46.017,154.624 46.117,154.724 v2(47.143,154.724) 48.158,154.724 48.44,155.005 57.9,155.005 59.117,153.788 64.842,153.788 65.697,152.933 76.934,152.933 77.789,153.788 114.536,153.788 124.591,163.843 125.752,163.843 v7(127.313,165.404) v7(127.313,168.586) 127.313,169.846 127.749,170.282 130.044,170.282 131.882,172.119 131.882,180.615 131.239,181.257 126.975,181.257 v7(126.53,181.703) v7(126.53,184.885) 125.814,185.601 125.814,185.901 v6(124.649,187.067) ; v2(89.373,306.39) 90.252,305.511 91.463,305.511 105.025,291.949 110.181,291.949 119.554,282.576 119.725,282.576 119.95,282.351 119.95,274.505 120.515,273.939 v6(121.649,273.939) ; v6(121.73,196.761) v7(121.73,197.989) v7(121.73,201.096) 121.73,213.354 121.26,213.825 v7(121.26,214.334) v7(121.26,217.516) 121.231,217.545 121.231,225.074 124.318,228.161 124.318,245.329 125.098,246.109 125.098,265.248 126.078,266.227 126.078,269.428 130.792,274.142 v1(134.277,274.142) ; v7(136.741,273.772) v7(139.879,273.772)
  L16 w0.2: v1(29.001,211.587) R597.2@29.126,211.587 ; R593.2@32.058,211.587 32.776,211.587 33.553,210.809 33.553,208.145 32.348,206.94 32.348,206.285 U64_U_Pomiar_pradu_napiecia_2.5@32.298,206.235
SFP_I2C5.SDA: R8_I2C_Bridge_SFP.2 R24.2 R390.2 R459.2 R466.2 R564.2 R568.2 R572.2 R576.2 R580.2 R584.2 R588.2 R592.2 R594.2 R598.2 SP13_I2C_Bridge_SFP.1 U3_I2C_Bridge_SFP.12 U35_I2C_Expander_PWR_CLK.9 U35_I2C_Expander_PWR_Dist.9 U64_U_Pomiar_pradu_napiecia_1.4 U64_U_Pomiar_pradu_napiecia_2.4 U64_U_Pomiar_pradu_napiecia_3.4 U64_U_Pomiar_pradu_napiecia_4.4 U64_U_Pomiar_pradu_napiecia_5.4 U64_U_Pomiar_pradu_napiecia_6.4 U72.4 | length 439.6
  L1 w0.2: U64_U_Pomiar_pradu_napiecia_1.4@32.745,157.414 32.745,156.153 33.245,155.653 34.195,155.653 35.079,154.769 35.079,152.754 34.961,152.637 R459.2@33.77,152.637 ; U35_I2C_Expander_PWR_Dist.9@47.793,156.428 47.803,156.419 v2(47.803,155.296) ; U3_I2C_Bridge_SFP.12@89.47,304.596 89.928,304.596 v2(90.411,305.079) 91.208,305.079 R8_I2C_Bridge_SFP.2@91.688,305.56 91.738,305.56 91.788,305.56 91.988,305.76 91.988,306.161 SP13_I2C_Bridge_SFP.1@94.602,308.775 ; U64_U_Pomiar_pradu_napiecia_6.4@115.141,200.008 117.004,200.008 117.398,200.403 117.398,201.651 117.868,202.121 120.17,202.121 120.714,201.577 v7(120.714,201.096) ; U64_U_Pomiar_pradu_napiecia_5.4@115.471,216.848 116.821,216.848 117.437,217.464 117.437,218.633 117.554,218.75 120.126,218.75 120.244,218.633 R580.2@120.244,217.391 ; R584.2@120.244,214.459 v7(120.244,214.334) 120.276,214.334 120.319,214.334 120.444,214.209 120.444,214.167 126.482,208.128 U35_I2C_Expander_PWR_CLK.9@128.253,208.128 ; U64_U_Pomiar_pradu_napiecia_3.4@120.678,183.659 122.387,183.659 122.758,184.03 122.758,185.833 122.973,186.048 125.031,186.048 125.514,185.565 R564.2@125.514,184.76 ; U64_U_Pomiar_pradu_napiecia_4.4@120.986,168.01 121.061,168.084 122.493,168.084 124.03,169.621 125.714,169.621 126.297,169.038 R572.2@126.297,168.461 ; v1(134.556,274.726) 136.678,274.726 R390.2@136.741,274.79 ; U72.4@138.853,279.003 138.853,277.853 139.193,277.513 142.297,277.513 142.414,277.395 142.414,274.914 142.297,274.797 R24.2@139.754,274.797
  L5 (Sign) w0.2: v6(120.688,196.774) 120.688,189.711 v6(123.457,186.942) ; v6(121.234,273.326) 122.234,273.326 122.568,273.66 134.683,273.66 135.325,274.301 135.325,274.466 135.064,274.726 v1(134.556,274.726)
  L3 (Sign) w0.2: v1(32.183,210.571) v1(29.001,210.571) 28.143,210.571 27.884,210.312 27.884,203.485 29.68,201.69 29.68,188.187 27.737,186.244 27.737,154.59 29.689,152.637 v7(30.713,152.637) v7(33.895,152.637) 36.635,152.637 38.922,154.924 45.893,154.924 46.264,155.296 v2(47.803,155.296) 47.812,155.305 58.024,155.305 59.241,154.088 64.967,154.088 65.821,153.233 76.81,153.233 77.664,154.088 114.366,154.088 123.345,163.067 123.391,163.067 124.467,164.143 125.628,164.143 126.297,164.812 v7(126.297,165.404) v7(126.297,168.586) 126.297,169.987 126.901,170.591 129.916,170.591 131.582,172.257 131.582,180.491 131.115,180.957 126.259,180.957 v7(125.514,181.703) v7(125.514,184.885) 125.514,185.565 124.137,186.942 v6(123.457,186.942) ; v2(90.411,305.079) 91.47,305.079 104.9,291.649 110.026,291.649 119.65,282.026 119.65,274.38 120.705,273.326 v6(121.234,273.326) ; v6(120.688,196.774) v7@120.688,197.963 ; v7(120.714,197.989) v7(120.714,201.096) 120.714,212.891 120.244,213.361 v7(120.244,214.334) v7(120.244,217.516) 120.244,224.511 124.018,228.286 124.018,245.611 124.798,246.391 124.798,265.372 125.778,266.352 125.778,269.552 130.952,274.726 v1(134.556,274.726) ; v7(136.741,274.797) v7(139.879,274.797)
  L16 w0.2: v1(29.001,210.571) R598.2@29.126,210.571 ; U64_U_Pomiar_pradu_napiecia_2.4@31.798,206.235 31.798,206.81 31.948,206.96 31.948,207.043 32.065,207.16 32.144,207.16 33.253,208.269 33.253,209.977 32.66,210.571 R594.2@32.058,210.571
SFP_I2C6.SCL: R5_I2C_Bridge_SFP.2 SP16_I2C_Bridge_SFP.1 U3_I2C_Bridge_PCIE.19 U3_I2C_Bridge_SFP.15 | length 105.6
  L1 w0.2: R5_I2C_Bridge_SFP.2@87.775,307.492 v1(87.785,307.482) U3_I2C_Bridge_SFP.15@87.785,305.281 ; v1(98.87,388.569) 99.004,388.569 99.722,387.851 99.735,387.863 U3_I2C_Bridge_PCIE.19@100.135,387.863
  L5 (Sign) w0.2: v1(87.785,307.482) 88.105,307.162 88.725,307.162 89.203,307.64 97.478,307.64 100.171,310.333 v1(100.171,311.154) 107.185,318.168 107.185,322.998 103.459,326.724 103.459,332.008 103.237,332.23 103.237,345.933 105.057,347.753 v6(105.057,348.564) ; v1(98.87,388.569) 97.727,388.569 97.426,388.269 97.426,384.348 97.427,377.561 100.352,374.635 v6(100.352,373.355)
  L3 (Sign) w0.2: v6(100.352,373.355) 100.352,372.749 105.057,368.045 v6(105.057,348.564)
SFP_I2C6.SDA: R6_I2C_Bridge_SFP.2 SP15_I2C_Bridge_SFP.1 U3_I2C_Bridge_PCIE.20 U3_I2C_Bridge_SFP.14 | length 105.3
  L1 w0.2: U3_I2C_Bridge_SFP.14@88.285,305.281 88.285,306.298 v1(88.415,306.428) 88.853,306.866 R6_I2C_Bridge_SFP.2@88.853,307.492 ; v1(98.87,387.96) 99.466,387.363 U3_I2C_Bridge_PCIE.20@100.135,387.363
  L5 (Sign) w0.2: v1(88.415,306.428) 89.327,307.34 97.905,307.34 101.174,310.609 107.485,316.92 107.485,323.122 103.759,326.848 103.759,332.133 103.537,332.355 103.537,345.777 105.657,347.897 v6(105.657,348.564) ; v1(98.87,387.96) 97.892,387.96 97.727,387.794 97.727,377.685 100.952,374.459 v6(100.952,373.355)
  L3 (Sign) w0.2: v6(100.952,373.355) 100.952,372.61 105.657,367.905 v6(105.657,348.564)
  other v1: 101.719,311.154
SFP_I2C7.SCL: R3_I2C_Bridge_SFP.2 SP18_I2C_Bridge_SFP.1 U3_I2C_Bridge_SFP.17 U35_I2C_Expander_SFP.8 | length 55.4
  L1 w0.2: U35_I2C_Expander_SFP.8@42.702,310.503 43.669,310.503 45.898,308.274 v2(51.448,308.274) ; SP18_I2C_Bridge_SFP.1@82.407,310.839 82.407,309.307 85.416,306.299 v2(85.938,306.299) ; R3_I2C_Bridge_SFP.2@85.62,307.492 85.62,306.616 v2(85.938,306.299) ; U3_I2C_Bridge_SFP.17@86.785,305.281 86.785,305.853 86.34,306.299 v2(85.938,306.299)
  L3 (Sign) w0.2: v2(51.448,308.274) 58.427,308.274 59.899,309.747 69.674,309.747 70.775,308.645 71.216,308.645 73.271,306.591 85.645,306.591 v2(85.938,306.299)
SFP_I2C7.SDA: R4_I2C_Bridge_SFP.2 SP17_I2C_Bridge_SFP.1 U3_I2C_Bridge_SFP.16 U35_I2C_Expander_SFP.9 | length 54.7
  L1 w0.2: U35_I2C_Expander_SFP.9@42.702,311.153 43.443,311.153 45.872,308.724 v2(51.448,308.724) ; R4_I2C_Bridge_SFP.2@86.698,307.492 86.698,306.874 v2(87.013,306.558) 87.013,306.518 87.285,306.246 U3_I2C_Bridge_SFP.16@87.285,305.281
  L3 (Sign) w0.2: v2(51.448,308.724) 58.453,308.724 60.143,310.415 69.871,310.415 73.395,306.891 85.77,306.891 ; v7(84.19,310.839) 84.19,308.47 85.77,306.891 ; v2(87.013,306.558) 86.208,306.558 85.893,306.874 85.787,306.874 85.77,306.891
SFP_INT0: R854.2 U35_I2C_Expander_SFP.16 | length 435.5
  L1 w0.2: U35_I2C_Expander_SFP.16@41.127,315.328 41.127,316.311 42.446,317.629 44.871,317.629 45.491,318.249 46.965,318.249 49.225,320.51 49.225,321.282 v2(49.172,321.335) ; R854.2@256.32,302.785 v1(256.32,303.546)
  L5 (Sign) w0.2: v6(40.035,382.238) 40.843,383.046 40.843,383.946 41.097,384.2 v6(41.11,384.2) ; v6(270.294,343.751) v6(270.294,384.454)
  L3 (Sign) w0.2: v6(40.035,382.238) 40.495,382.238 42.329,380.403 42.329,365.049 43.015,364.363 43.015,356.974 42.259,356.218 42.259,354.057 43.116,353.2 43.116,346.138 49.751,339.504 49.751,321.995 49.247,321.491 49.247,321.451 49.172,321.376 v2(49.172,321.335) ; v6(41.11,384.2) 47.424,384.2 56.835,393.611 100.472,393.611 102.415,395.554 123.192,395.554 154.142,426.504 228.486,426.504 270.294,384.696 v6(270.294,384.454) ; v1(256.32,303.546) 256.32,304.621 257.858,306.159 264.02,306.159 265.709,307.848 265.709,318.072 270.294,322.656 v6(270.294,343.751)
SFP_INT1: R857.2 U35_I2C_Expander_SFP.15 | length 436.4
  L1 w0.2: U35_I2C_Expander_SFP.15@41.777,315.328 41.777,316.537 42.57,317.329 44.996,317.329 45.616,317.949 47.089,317.949 49.568,320.429 49.568,321.282 v2(49.622,321.335) ; R857.2@257.683,302.785 v1(257.683,303.546)
  L5 (Sign) w0.2: v6(39.671,382.983) 39.671,383.398 41.074,384.8 v6(41.11,384.8) ; v6(270.894,343.751) v6(270.894,384.454)
  L3 (Sign) w0.2: v6(39.671,382.983) 40.174,382.983 42.651,380.505 42.651,365.211 43.358,364.505 43.358,356.832 42.559,356.033 42.559,354.242 43.459,353.342 43.459,346.281 50.094,339.646 50.094,321.807 v2(49.622,321.335) ; v6(41.11,384.8) 47.539,384.8 56.693,393.954 100.33,393.954 102.273,395.897 123.05,395.897 154,426.847 228.628,426.847 249.732,405.743 249.732,405.682 270.894,384.52 v6(270.894,384.454) ; v1(257.683,303.546) 257.683,305.004 258.495,305.816 264.162,305.816 266.052,307.706 266.052,317.929 270.894,322.771 v6(270.894,343.751)
SFP_IO_nReset: R756.1 U35_I2C_Expander_Main_Rst.28 U35_I2C_Expander_SFP.14 | length 127.3
  L1 w0.2: U35_I2C_Expander_SFP.14@42.702,314.403 43.068,314.403 43.269,314.604 v1(43.269,314.973)
  L5 (Sign) w0.2: v1(43.269,314.973) 43.269,282.296 46.457,279.108 60.325,279.108 63.856,275.577 72.184,275.577 82.359,265.402 82.359,261.036 83.972,259.423 106.528,259.423 107.988,260.883 109.541,260.883 111.416,259.008 117.163,259.008 v1(117.669,258.502)
  L16 w0.2: U35_I2C_Expander_Main_Rst.28@115.873,260.018 117.261,260.018 117.691,259.588 ; v1(117.669,258.502) 117.691,258.524 117.691,259.588 ; R756.1@120.169,259.588 117.691,259.588
SGMI_C_Rx_N: C484.2 U1.G26 | length 83.2
  L1 w0.1: U1.G26@168.397,313.539 168.432,313.505 168.432,313.21 168.555,313.087 168.85,313.087 v1(168.884,313.052)
  L5 (Sign) w0.081: v1(127.483,280.827) cw(c127.642,280.827) 127.642,280.987 148.61,280.987 ccw(c148.61,281.597) 149.22,281.597 149.22,304.137 cw(c149.553,304.137) 149.553,304.47 151.486,304.47 ccw(c151.486,305.016) 152.032,305.016 152.032,311.052 cw(c152.385,311.052) 152.385,311.405 161.61,311.405 cw(c161.61,309.096) 163.243,310.729 163.292,310.679 ccw(c164.617,312.004) 164.617,310.13 165.015,310.13 ccw(c165.015,312.949) 167.008,310.956 168.304,312.252 ccw(c167.742,312.815) 168.537,312.815 cw(c168.774,312.815) 168.774,313.052 v1(168.884,313.052)
  L16 w0.101: C484.2@118.131,280.645 cw(c118.413,280.645) 118.413,280.927 127.383,280.927 cw(c127.383,280.827) v1(127.483,280.827)
SGMI_C_Rx_P: C483.2 U1.G25 | length 83.2
  L1 w0.1: v1(167.909,313.027) 167.944,312.992 168.239,312.992 168.362,312.869 168.362,312.574 U1.G25@168.397,312.539
  L5 (Sign) w0.081: v1(127.483,281.427) ccw(c127.642,281.427) 127.642,281.268 148.61,281.268 ccw(c148.61,281.597) 148.939,281.597 148.939,282.195 148.939,282.236 ccw(c148.769,282.236) 148.769,282.407 148.741,282.407 cw(c148.741,282.577) 148.57,282.577 148.57,282.723 cw(c148.741,282.723) 148.741,282.894 148.769,282.894 ccw(c148.769,283.065) 148.939,283.065 148.939,283.342 148.939,304.137 cw(c149.553,304.137) 149.553,304.751 151.486,304.751 ccw(c151.486,305.016) 151.751,305.016 151.751,311.052 cw(c152.385,311.052) 152.385,311.686 161.61,311.686 cw(c161.61,309.097) 163.441,310.928 163.488,310.88 ccw(c164.621,312.013) 164.621,310.411 165.014,310.411 ccw(c165.014,312.951) 166.81,311.155 168.105,312.451 ccw(c167.741,312.815) 168.256,312.815 ccw(c168.045,312.815) 168.045,313.027 v1(167.909,313.027)
  L16 w0.101: C483.2@118.109,281.61 ccw(c118.391,281.61) 118.391,281.328 127.383,281.328 ccw(c127.383,281.427) v1(127.483,281.427)
SGMI_C_Tx_N: C482.2 U1.G29 | length 89.1
  L1 w0.1: v2(167.909,317.027) U1.G29@168.397,316.539
  L5 (Sign) w0.081: v1(121.437,274.543) cw(c121.597,274.543) 121.597,274.703 124.895,274.703 ccw(c124.895,275.45) 125.643,275.45 125.643,282.804 cw(c126.71,282.804) 126.71,283.87 147.547,283.87 ccw(c147.547,284.692) 148.368,284.692 148.368,304.788 cw(c148.939,304.788) 148.939,305.359 150.208,305.359 ccw(c150.208,305.963) 150.812,305.963 150.812,316.129 cw(c152.07,316.129) 152.07,317.386 166.471,317.386 166.581,317.277 v12(166.667,317.277)
  L3 (Sign) w0.081: v12(166.667,317.277) cw(c166.776,317.277) 166.776,317.386 167.675,317.386 cw(c167.675,317.152) 167.909,317.152 v2(167.909,317.027)
  L16 w0.101: C482.2@120.638,274.345 120.638,274.39 120.862,274.615 121.366,274.615 v1(121.437,274.543)
SGMI_C_Tx_P: C479.2 U1.G30 | length 89.2
  L1 w0.1: v2(167.909,318.027) U1.G30@168.397,317.539
  L5 (Sign) w0.081: v1(121.437,275.143) ccw(c121.597,275.143) 121.597,274.984 124.895,274.984 ccw(c124.895,275.45) 125.362,275.45 125.362,282.804 cw(c126.71,282.804) 126.71,284.151 147.547,284.151 ccw(c147.547,284.692) 148.087,284.692 148.087,304.788 cw(c148.939,304.788) 148.939,305.64 150.208,305.64 ccw(c150.208,305.963) 150.531,305.963 150.531,316.129 cw(c152.07,316.129) 152.07,317.667 166.471,317.667 166.638,317.834 v12(166.665,317.834)
  L3 (Sign) w0.081: v12(166.665,317.834) 166.665,317.779 166.667,317.777 ccw(c166.776,317.777) 166.776,317.667 167.675,317.667 ccw(c167.675,317.902) 167.909,317.902 v2(167.909,318.027)
  L16 w0.101: C479.2@120.638,275.285 120.638,275.24 120.862,275.016 121.202,275.016 121.329,275.143 v1(121.437,275.143)
SGMI_CLK_Out_N: R320.1 R321.1 R326.2 U39.34 | length 11.1
  L16 w0.101: U39.34@111.699,276.775 cw(c111.764,276.711) 111.764,276.802 111.969,276.802 ccw(c111.969,276.841) 111.997,276.813 cw(c112.024,276.785) 112.024,276.825 113.6,276.825 ccw(c113.6,278.563) 114.829,277.334 114.947,277.451 cw(c116.743,275.655) 116.743,278.195 118.828,278.195 cw(c118.828,277.884) R321.1@119.139,277.884 cw(c119.438,277.884) 119.438,278.184 120.05,278.184 cw(c120.05,277.901) R320.1@120.332,277.901 cw(c120.65,277.901) 120.65,278.218 121.221,278.218 cw(c121.221,277.901) R326.2@121.539,277.901
SGMI_CLK_Out_P: R319.1 R321.2 R325.2 U39.33 | length 11.1
  L16 w0.101: U39.33@111.699,277.275 ccw(c111.764,277.339) 111.764,277.248 111.969,277.248 cw(c111.969,277.209) 111.997,277.237 ccw(c112.024,277.265) 112.024,277.226 113.597,277.226 ccw(c113.597,278.57) 114.548,277.619 114.664,277.736 cw(c116.741,275.659) 116.741,278.596 118.851,278.596 ccw(c118.851,278.884) R321.2@119.139,278.884 ccw(c119.438,278.884) 119.438,278.584 119.98,278.584 ccw(c119.98,278.937) R319.1@120.332,278.937 ccw(c120.65,278.937) 120.65,278.619 121.221,278.619 ccw(c121.221,278.937) R325.2@121.539,278.937
SGMI_Rx_N: C484.1 U39.28 | length 5.8
  L16 w0.101: U39.28@111.699,279.775 cw(c111.749,279.775) 111.749,279.825 114.224,279.825 ccw(c114.224,281.246) 115.229,280.241 115.289,280.301 cw(c116.656,278.935) 116.656,280.867 cw(c116.656,280.378) 117.002,280.724 C484.1@117.081,280.645
SGMI_Rx_P: C483.1 U39.27 | length 5.8
  L16 w0.101: U39.27@111.699,280.275 ccw(c111.749,280.275) 111.749,280.226 114.221,280.226 ccw(c114.221,281.253) 114.948,280.526 115.007,280.585 cw(c116.655,278.938) 116.655,281.268 ; 116.656,281.268 116.684,281.296 cw(c116.779,281.201) 116.779,281.335 ccw(c116.779,281.47) 116.874,281.375 117.024,281.524 ccw(c116.938,281.61) C483.1@117.059,281.61
SGMI_Tx_N: C482.1 R323.1 R328.2 U39.36 | length 9.3
  L16 w0.101: U39.36@111.699,275.775 cw(c111.749,275.775) 111.749,275.825 113.964,275.825 cw(c113.964,275.485) 114.204,275.725 114.761,275.168 ccw(c115.595,276.002) 115.595,274.823 116.988,274.823 cw(c116.988,274.477) R323.1@117.334,274.477 cw(c117.656,274.477) 117.656,274.799 118.213,274.799 cw(c118.213,274.584) 118.427,274.584 R328.2@118.427,274.477 118.602,274.652 118.602,274.74 118.661,274.799 118.818,274.799 119.003,274.615 119.363,274.615 119.588,274.39 C482.1@119.588,274.345
SGMI_Tx_P: C479.1 R322.1 R327.2 U39.35 | length 9.2
  L16 w0.101: U39.35@111.699,276.275 ccw(c111.749,276.275) 111.749,276.226 113.966,276.226 cw(c113.966,275.489) 114.487,276.01 115.043,275.454 ccw(c115.598,276.008) 115.598,275.224 116.818,275.224 117.036,275.224 ccw(c117.036,275.522) R322.1@117.334,275.522 ccw(c117.656,275.522) 117.656,275.2 118.213,275.2 ccw(c118.213,275.415) 118.427,275.415 R327.2@118.427,275.522 118.602,275.347 118.602,275.259 118.661,275.2 118.985,275.2 119.169,275.016 119.363,275.016 119.588,275.24 C479.1@119.588,275.285
Si53323_1_Q1_N: C330.2 R249.1 U31.9 | length 6.5
  L1 w0.101: U31.9@51.843,398.449 52.828,398.449 53.908,398.449 cw(c53.908,397.919) 54.439,397.919 ccw(c55.339,397.919) 55.339,397.018 56.086,397.018 cw(c56.086,396.668) R249.1@56.436,396.668 57.249,396.668 cw(c57.249,396.618) C330.2@57.299,396.618
Si53323_1_Q1_P: C325.2 R246.2 U31.10 | length 6.6
  L1 w0.101: U31.10@51.843,398.949 ccw(c51.942,398.949) 51.942,398.85 53.908,398.85 cw(c53.908,397.919) 54.84,397.919 ccw(c55.339,397.919) 55.339,397.419 56.086,397.419 ccw(c56.086,397.769) R246.2@56.436,397.769 57.249,397.769 ccw(c57.249,397.819) C325.2@57.299,397.819
Si53323_1_Q2_C_N: C725.2 R385.1 | length 1.3
  L1 w0.101: C725.2@203.377,291.216 203.437,291.276 203.437,291.449 203.496,291.509 204.029,291.509 204.322,291.216 R385.1@204.372,291.216
Si53323_1_Q2_C_P: C724.2 R384.1 | length 1.3
  L1 w0.101: C724.2@203.377,292.202 203.437,292.142 203.437,291.969 203.496,291.91 204.03,291.91 204.322,292.202 R384.1@204.372,292.202
Si53323_1_Q2_LVDS_N: C725.1 R386.2 R387.2 U1.AG3 | length 15.5
  L1 w0.1: U1.AG3@188.397,290.539 v2(188.884,291.027)
  L1 w0.101: v1(198.806,291.404) 198.882,291.481 199.197,291.481 199.224,291.509 202.738,291.509 202.798,291.449 202.798,291.276 C725.1@202.857,291.216
  L5 (Sign) w0.081: v12(189.472,291.209) 189.551,291.209 189.729,291.386 197.302,291.386 197.479,291.564 198.549,291.564 198.708,291.404 v1(198.806,291.404)
  L3 (Sign) w0.081: v2(188.884,291.027) 188.884,291.339 188.932,291.386 188.999,291.386 189.017,291.368 189.215,291.368 189.375,291.209 v12(189.472,291.209)
Si53323_1_Q2_LVDS_P: C724.1 R100.2 R125.2 U1.AG4 | length 15.5
  L1 w0.1: U1.AG4@188.397,291.539 v2(188.884,292.027)
  L1 w0.101: v1(198.806,292.004) 198.882,291.928 199.206,291.928 199.224,291.91 199.476,291.91 202.738,291.91 202.798,291.969 202.798,292.142 C724.1@202.857,292.202
  L5 (Sign) w0.081: v12(189.472,291.809) 189.586,291.809 189.727,291.667 197.185,291.667 197.363,291.845 198.549,291.845 198.708,292.004 v1(198.806,292.004)
  L3 (Sign) w0.081: v2(188.884,292.027) 188.884,291.715 188.932,291.667 189.115,291.667 189.134,291.649 189.215,291.649 189.375,291.809 v12(189.472,291.809)
Si53323_1_Q2_N: R301.1 R385.2 U31.12 | length 277.2
  L1 w0.101: U31.12@51.843,399.949 53.019,399.949 ccw(c53.019,400.004) v1(53.073,400.004) ; R385.2@205.372,291.216 205.422,291.216 205.596,291.391 205.596,291.449 205.655,291.509 208.318,291.509 208.343,291.483 208.61,291.483 v1(208.686,291.407)
  L14 (Sign) w0.081: v1(53.073,400.004) ccw(c53.233,400.004) 53.233,399.844 53.67,399.844 cw(c53.67,398.608) 54.906,398.608 54.906,367.473 54.906,366.876 ccw(c55.445,366.876) 55.445,366.337 136.364,366.337 cw(c136.364,365.69) 137.011,365.69 137.011,360.528 ccw(c138.178,360.528) 138.178,359.361 146.635,359.361 cw(c146.635,358.459) 147.537,358.459 147.537,354.049 ccw(c147.869,354.049) 147.869,353.718 212.952,353.718 cw(c212.952,352.352) 214.317,352.352 214.317,292.618 cw(c213.267,292.618) 213.267,291.569 208.848,291.569 ccw(c208.848,291.407) v1(208.686,291.407) v1@208.799,291.519
Si53323_1_Q2_P: R291.1 R384.2 U31.11 | length 276.9
  L1 w0.101: U31.11@51.843,399.449 53.028,399.449 cw(c53.028,399.404) v1(53.073,399.404) ; R384.2@205.372,292.202 205.422,292.202 205.596,292.027 205.596,291.969 205.655,291.91 208.318,291.91 208.343,291.935 208.61,291.935 v1(208.686,292.011)
  L14 (Sign) w0.081: v1(53.073,399.404) cw(c53.233,399.404) 53.233,399.563 53.67,399.563 cw(c53.67,398.608) 54.625,398.608 54.625,367.473 54.625,366.876 ccw(c55.445,366.876) 55.445,366.056 136.364,366.056 cw(c136.364,365.69) 136.73,365.69 136.73,362.208 136.73,361.782 cw(c136.646,361.782) 136.646,361.698 ccw(c136.646,361.615) 136.562,361.615 136.562,361.447 ccw(c136.646,361.447) 136.646,361.363 cw(c136.646,361.279) 136.73,361.279 136.73,361.239 136.73,360.528 ccw(c138.178,360.528) 138.178,359.08 146.635,359.08 cw(c146.635,358.459) 147.256,358.459 147.256,356.362 147.256,356.194 cw(c147.172,356.194) 147.172,356.11 147.053,356.11 ccw(c147.053,356.026) 146.969,356.026 146.969,355.859 ccw(c147.053,355.859) 147.053,355.775 147.172,355.775 cw(c147.172,355.691) 147.256,355.691 147.256,355.651 147.256,354.049 ccw(c147.869,354.049) 147.869,353.437 212.952,353.437 cw(c212.952,352.352) 214.036,352.352 214.036,292.618 cw(c213.267,292.618) 213.267,291.85 208.848,291.85 cw(c208.848,292.011) v1(208.686,292.011) v1@208.799,291.899
Si53323_2_CLK1_N: C330.1 R245.1 R248.2 R251.2 U32.4 | length 21.3
  L1 w0.101: C330.1@58.349,396.618 cw(c58.466,396.618) 58.466,396.735 59.23,396.735 60.246,396.735 R245.1@61.419,396.735 cw(c61.718,396.735) 61.718,397.034 68.408,397.034 68.915,397.034 cw(c68.915,396.933) 69.016,396.933 69.016,396.709 ccw(c69.107,396.709) 69.107,396.618 69.38,396.618 ccw(c69.38,396.709) 69.471,396.709 69.471,396.933 cw(c69.572,396.933) 69.572,397.034 69.748,397.034 70.24,397.034 cw(c70.24,395.279) 71.995,395.279 U32.4@71.995,389.511
Si53323_2_CLK1_P: C325.1 R245.2 R247.2 R250.2 U32.3 | length 21.3
  L1 w0.101: C325.1@58.349,397.819 ccw(c58.434,397.819) 58.434,397.735 R245.2@61.419,397.735 ccw(c61.718,397.735) 61.718,397.435 70.24,397.435 cw(c70.24,395.18) 72.495,395.18 U32.3@72.495,389.511
Si53323_2_Q1_N: C44.2 R79.2 U32.10 | length 95.5
  L1 w0.101: U32.10@72.495,386.511 ccw(c72.495,386.461) 72.446,386.461 72.446,379.54 ccw(c72.995,379.54) 72.995,378.99 75.231,378.99 v7(75.256,379.015)
  L5 (Sign) w0.081: v12(76.285,379.04) 76.346,378.979 76.53,378.979 76.579,378.93 90.935,378.93 cw(c90.935,377.934) 91.931,377.934 91.931,354.976 ccw(c92.485,354.976) 92.485,354.422 108.219,354.422 cw(c108.219,353.826) 108.815,353.826 108.815,353.534 108.838,353.512 108.838,353.482 108.973,353.347 v3(109.047,353.347)
  L3 (Sign) w0.081: v7(75.256,379.015) 75.328,379.015 75.413,378.93 76.089,378.93 76.198,379.04 v12(76.285,379.04)
  L14 (Sign) w0.081: v10(103.086,334.262) cw(c103.245,334.262) 103.245,334.422 107.569,334.422 ccw(c107.569,335.666) 108.813,335.666 108.813,353.113 cw(c109.047,353.113) v3(109.047,353.347)
  L16 w0.101: C44.2@101.156,334.061 cw(c101.457,334.061) 101.457,334.362 101.692,334.362 cw(c101.692,334.035) R79.2@102.019,334.035 cw(c102.346,334.035) 102.346,334.362 102.986,334.362 cw(c102.986,334.262) v10(103.086,334.262)
Si53323_2_Q1_P: C43.2 R76.1 U32.9 | length 95.2
  L1 w0.101: U32.9@71.995,386.511 cw(c71.995,386.461) 72.045,386.461 72.045,379.54 ccw(c72.995,379.54) 72.995,378.589 75.231,378.589 v7(75.256,378.565)
  L5 (Sign) w0.081: v12(76.28,378.483) 76.28,378.535 76.339,378.594 76.346,378.601 76.53,378.601 76.579,378.649 90.935,378.649 cw(c90.935,377.934) 91.65,377.934 91.65,354.976 ccw(c92.485,354.976) 92.485,354.141 108.219,354.141 cw(c108.219,353.826) 108.534,353.826 108.534,353.51 108.447,353.423 v3(108.447,353.35)
  L3 (Sign) w0.081: v7(75.256,378.565) 75.328,378.565 75.413,378.649 76.089,378.649 76.198,378.54 76.253,378.594 76.28,378.567 v12(76.28,378.483)
  L14 (Sign) w0.081: v10(103.086,334.862) ccw(c103.245,334.862) 103.245,334.703 107.569,334.703 ccw(c107.569,335.666) 108.532,335.666 108.532,353.265 ccw(c108.447,353.265) v3(108.447,353.35)
  L16 w0.101: C43.2@101.176,335.064 ccw(c101.477,335.064) 101.477,334.763 101.692,334.763 ccw(c101.692,335.09) R76.1@102.019,335.09 ccw(c102.346,335.09) 102.346,334.763 102.986,334.763 ccw(c102.986,334.862) v10(103.086,334.862)
Si53323_2_Q2_C_N: C727.2 R485.1 | length 1.1
  L1 w0.101: R485.1@135.173,306.685 135.223,306.685 135.398,306.86 135.398,306.908 135.457,306.967 135.6,306.967 ; C727.2@136.012,306.81 136.012,306.82 135.866,306.966 135.601,306.966 ; 135.6,306.967 135.601,306.966
Si53323_2_Q2_C_P: C726.2 R484.1 | length 1.1
  L1 w0.101: R484.1@135.173,307.65 135.223,307.65 135.398,307.476 135.398,307.427 135.457,307.368 135.766,307.368 135.767,307.367 135.866,307.367 136.012,307.513 C726.2@136.012,307.523
Si53323_2_Q2_LVDS_N: C727.1 R486.2 R487.2 U1.A16 | length 33.7
  L1 w0.09: 161.397,303.894 162.042,303.894
  L1 w0.1: 162.042,303.894 cw(c162.042,303.539) U1.A16@162.397,303.539
  L1 w0.101: C727.1@136.532,306.81 136.532,306.82 136.678,306.966 138.912,306.966 ; 138.978,306.966 139.257,306.966 ccw(c139.257,307.862) 140.153,307.862 cw(c140.318,307.862) 140.318,308.027 148.79,308.027 cw(c148.79,307.224) 149.593,307.224 149.593,303.682 ccw(c150.492,303.682) 150.492,302.784 152.568,302.784 cw(c152.568,302.416) 152.935,302.416 ccw(c153.968,302.416) 153.968,301.383 154.209,301.383 ccw(c154.209,302.626) 155.452,302.626 155.452,303.217 cw(c156.129,303.217) 156.129,303.894 161.397,303.894
Si53323_2_Q2_LVDS_P: C726.1 R427.2 R538.2 U1.A17 | length 33.7
  L1 w0.09: 161.397,304.295 162.153,304.295
  L1 w0.1: 162.153,304.295 ccw(c162.153,304.539) U1.A17@162.397,304.539
  L1 w0.101: C726.1@136.532,307.523 136.532,307.513 136.678,307.367 139.257,307.367 ccw(c139.257,307.862) 139.752,307.862 cw(c140.318,307.862) 140.318,308.428 148.79,308.428 cw(c148.79,307.224) 149.994,307.224 149.994,303.682 ccw(c150.492,303.682) 150.492,303.185 152.568,303.185 cw(c152.568,302.416) 153.336,302.416 ccw(c153.968,302.416) 153.968,301.784 154.209,301.784 ccw(c154.209,302.626) 155.051,302.626 155.051,303.217 cw(c156.129,303.217) 156.129,304.295 161.397,304.295
Si53323_2_Q2_N: R483.1 R485.2 U32.11 | length 139.8
  L1 w0.101: U32.11@72.995,386.511 cw(c72.995,386.461) 73.045,386.461 73.045,381.414 ccw(c74.285,381.414) v7@74.285,380.174 ; v3(132.344,306.74) 132.344,306.866 132.421,306.944 132.581,306.944 132.604,306.967 133.187,306.967 133.89,306.967 133.949,306.908 133.949,306.86 134.123,306.685 R485.2@134.173,306.685
  L5 (Sign) w0.081: v12(75.256,380.124) 75.342,380.124 75.452,380.234 92.697,380.234 cw(c92.697,379.739) 93.191,379.739 93.191,356.079 ccw(c93.684,356.079) 93.684,355.586 129.317,355.586 cw(c129.317,354.829) 130.074,354.829 130.074,324.239 cw(c129.915,324.239) v1(129.915,324.079)
  L12 (Sign) w0.081: v1(129.915,324.079) cw(c129.915,323.92) 130.074,323.92 130.074,307.969 ccw(c131.016,307.969) 131.016,307.027 132.088,307.027 132.344,306.772 v3(132.344,306.74)
  L3 (Sign) w0.081: v7(74.285,380.149) 74.655,380.149 74.739,380.234 75.06,380.234 75.169,380.124 v12(75.256,380.124)
Si53323_2_Q2_P: R482.1 R484.2 U32.12 | length 139.7
  L1 w0.101: U32.12@73.495,386.511 ccw(c73.495,386.461) 73.446,386.461 73.446,381.414 ccw(c74.285,381.414) v7@74.285,380.575 ; v3(132.345,307.468) 132.421,307.391 132.581,307.391 132.604,307.368 133.353,307.368 133.89,307.368 133.949,307.427 133.949,307.476 134.123,307.65 R484.2@134.173,307.65
  L5 (Sign) w0.081: v12(75.257,380.681) 75.257,380.643 75.309,380.591 75.342,380.624 75.452,380.515 92.697,380.515 cw(c92.697,379.739) 93.472,379.739 93.472,356.079 ccw(c93.684,356.079) 93.684,355.867 129.317,355.867 cw(c129.317,354.829) 130.355,354.829 130.355,324.239 ccw(c130.515,324.239) v1(130.515,324.079)
  L12 (Sign) w0.081: v1(130.515,324.079) ccw(c130.515,323.92) 130.355,323.92 130.355,315.944 130.355,315.347 ccw(c130.477,315.347) 130.477,315.225 130.653,315.225 cw(c130.653,315.103) 130.775,315.103 130.775,314.859 cw(c130.653,314.859) 130.653,314.737 130.477,314.737 ccw(c130.477,314.616) 130.355,314.616 130.355,314.088 130.355,307.969 ccw(c131.016,307.969) 131.016,307.308 132.088,307.308 132.248,307.468 v3(132.345,307.468)
  L3 (Sign) w0.081: v7(74.285,380.599) 74.655,380.599 74.739,380.515 75.06,380.515 75.169,380.624 75.203,380.591 75.257,380.645 v12(75.257,380.681)
SPI1_CLK: J25.1 R803.1 U15.14 U24_SPI_bridge_Main.3 U25_SPI_bridge_Main.3 U26_SPI_bridge_Main.3 U27_SPI_bridge_Main.3 U28_SPI_bridge_Main.3 | length 665.9
  L1 w0.2: U26_SPI_bridge_Main.3@71.573,330.54 72.476,330.54 72.926,330.99 v1(72.926,336.221) 74.373,337.668 77.896,337.668 R803.1@77.939,337.711 ; v1(135.153,269.989) 135.228,269.989 136.139,270.901 U15.14@138.523,270.901 ; v2(168.342,236.077) 168.342,233.168 168.69,232.82 cw(c168.548,232.679) 168.69,232.537 168.498,232.346 ccw(c168.623,232.22) 168.498,232.095 168.748,231.845 ccw(c168.874,231.97) 168.999,231.845 169.191,232.037 cw(c169.332,231.895) 169.473,232.037 169.544,231.966 169.836,231.674 170.733,231.674 U28_SPI_bridge_Main.3@170.769,231.638 172.063,231.638 v2(172.06,231.635) ; U27_SPI_bridge_Main.3@177.908,408.541 182.327,408.541 v2(183.154,407.714) ; U25_SPI_bridge_Main.3@186.998,254.021 186.998,252.606 187.048,252.556 187.048,250.879 187.85,250.076 v1(188.43,250.076) ; U24_SPI_bridge_Main.3@217.232,291.652 218.325,291.652 v1(218.362,291.69)
  L5 (Sign) w0.2: v1(70.879,319.773) 72.082,319.773 73.68,318.176 73.68,300.926 103.936,270.669 134.038,270.669 134.718,269.989 v1(135.153,269.989) ; v6(175.451,231.635) 175.781,231.635 177.417,233.272 177.417,236.675 179.832,239.09 181.064,239.09 188.28,246.306 188.28,249.926 v1(188.43,250.076) 188.963,250.076 191.232,252.344 199.589,252.344 200.643,253.398 207.795,253.398 213.411,259.014 213.411,263.37 219.697,269.656 219.697,290.476 218.483,291.69 v1(218.362,291.69) ; J25.1@196.986,226.835 196.99,226.835 202.376,232.221 230.786,232.221 234.279,235.714 244.91,235.714 253.117,243.92 253.117,245.541 v6(253.091,245.567)
  L12 (Sign) w0.2: v1(70.879,319.773) 72.926,321.82 v1(72.926,336.221)
  L3 (Sign) w0.2: v1(135.153,269.989) 135.153,269.915 132.639,267.4 132.639,262.75 134.406,260.983 134.406,254.089 134.077,253.76 134.077,243.658 139.05,238.686 161.538,238.686 162.046,239.194 165.224,239.194 v2(168.342,236.077) ; v2(172.06,231.635) v6(175.451,231.635) 179.235,231.635 180.124,230.746 ccw(c180.16,230.782) 180.196,230.746 180.394,230.944 cw(c180.49,230.848) 180.587,230.944 180.715,230.816 cw(c180.619,230.719) 180.715,230.623 180.481,230.389 179.684,229.592 ccw(c179.781,229.496) 179.684,229.399 179.813,229.271 ccw(c179.909,229.367) 180.005,229.271 180.802,230.068 181.481,230.746 cw(c181.577,230.65) 181.674,230.746 181.802,230.618 cw(c181.706,230.522) 181.802,230.425 181.22,229.843 ccw(c181.316,229.747) 181.22,229.65 181.445,229.426 181.605,229.265 193.754,229.265 195.244,227.774 195.244,227.044 195.453,226.835 J25.1@196.986,226.835 ; v2(183.154,407.714) 183.154,399.453 183.154,399.362 cw(c183.018,399.362) 183.018,399.226 181.703,399.226 ccw(c181.703,399.09) 181.567,399.09 181.567,398.908 ccw(c181.703,398.908) 181.703,398.772 183.154,398.772 cw(c183.154,398.636) 183.29,398.636 183.29,398.454 cw(c183.154,398.454) 183.154,398.318 181.703,398.318 ccw(c181.703,398.181) 181.567,398.181 181.567,398 ccw(c181.703,398) 181.703,397.863 183.018,397.863 cw(c183.018,397.727) 183.154,397.727 183.154,397.472 183.154,392.474 184.256,391.372 200.194,391.372 204.456,387.11 245.612,387.11 249.456,383.267 250.694,383.267 253.266,380.695 264.606,380.695 278.362,366.94 278.362,262.325 260.626,244.589 254.069,244.589 v6(253.091,245.567)
SPI1_CS: J25.4 R123.1 R124.1 R806.1 U15.11 U24_SPI_bridge_Main.6 U25_SPI_bridge_Main.6 U26_SPI_bridge_Main.6 U27_SPI_bridge_Main.6 U28_SPI_bridge_Main.6 | length 666.1
  L1 w0.2: U26_SPI_bridge_Main.6@71.573,328.59 74.003,328.59 74.795,329.382 74.861,329.447 cw(c74.957,329.351) 75.054,329.447 75.595,328.906 ccw(c75.692,329.002) 75.788,328.906 75.916,329.034 ccw(c75.82,329.131) 75.916,329.227 75.375,329.769 cw(c75.471,329.865) 75.375,329.961 75.6,330.186 75.76,330.347 v1(75.76,332.115) 75.76,333.583 76.359,334.181 ; R123.1@75.801,335.401 75.801,334.739 76.359,334.181 ; R806.1@77.896,334.353 77.817,334.275 76.452,334.275 76.359,334.181 ; v1(136.549,268.624) 136.62,268.624 136.947,268.951 U15.11@138.523,268.951 ; v2(169.745,237.003) 169.745,233.721 169.879,233.588 U28_SPI_bridge_Main.6@170.769,233.588 172.215,233.588 172.224,233.579 v2(172.301,233.579) ; v2@172.253,233.55 172.72,233.083 R124.1@173.353,233.083 ; U27_SPI_bridge_Main.6@177.908,410.491 183.134,410.491 v2(184.533,409.092) ; v1(188.653,251.876) 188.653,252.294 188.948,252.589 U25_SPI_bridge_Main.6@188.948,254.021 ; U24_SPI_bridge_Main.6@217.232,289.702 217.276,289.658 218.448,289.658 v1(218.491,289.614)
  L5 (Sign) w0.2: v1(72.03,318.34) 72.476,317.895 72.476,298.707 102.559,268.624 117.185,268.624 118.33,269.769 133.575,269.769 134.72,268.624 v1(136.549,268.624) ; v6(176.085,233.629) 176.441,233.629 176.517,233.705 176.517,237.048 178.884,239.415 178.884,239.642 178.884,239.96 cw(c179.021,239.96) 179.021,240.097 ccw(c179.021,240.233) 179.157,240.233 179.157,240.415 ccw(c179.021,240.415) 179.021,240.551 178.884,240.551 178.026,240.551 cw(c178.026,240.687) 177.89,240.687 177.89,240.869 cw(c178.026,240.869) 178.026,241.005 178.884,241.005 179.07,241.005 ccw(c179.07,241.141) 179.206,241.141 179.206,241.323 ccw(c179.07,241.323) 179.07,241.459 179.021,241.459 cw(c179.021,241.595) 178.884,241.595 178.884,242.197 187.297,250.609 187.297,250.865 188.307,251.876 v1(188.653,251.876) 189.491,251.876 190.859,253.244 199.142,253.244 199.822,253.924 199.829,253.924 200.203,254.298 207.423,254.298 209.309,256.184 209.309,259.156 ccw(c209.212,259.156) 209.212,259.253 208.453,259.253 cw(c208.453,259.389) 208.317,259.389 208.317,259.571 cw(c208.453,259.571) 208.453,259.707 209.309,259.707 209.445,259.707 ccw(c209.445,259.843) 209.581,259.843 209.581,260.025 ccw(c209.445,260.025) 209.445,260.161 cw(c209.445,260.297) 209.309,260.297 209.309,260.388 209.309,260.541 218.728,269.959 218.728,289.497 218.69,289.497 218.573,289.614 v1(218.491,289.614) ; J25.4@196.986,234.335 200.848,234.335 202.062,233.121 230.111,233.121 233.604,236.614 233.906,236.614 244.538,236.614 251.818,243.894 v6(251.818,244.294)
  L12 (Sign) w0.2: v1(72.03,318.34) 75.76,322.07 75.76,322.298 75.76,322.616 cw(c75.896,322.616) 75.896,322.752 76.577,322.752 ccw(c76.577,322.888) 76.713,322.888 76.713,323.07 ccw(c76.577,323.07) 76.577,323.206 75.76,323.206 74.997,323.206 cw(c74.997,323.342) 74.861,323.342 74.861,323.524 cw(c74.997,323.524) 74.997,323.66 75.76,323.66 76.057,323.66 ccw(c76.057,323.796) 76.194,323.796 76.194,323.978 ccw(c76.057,323.978) 76.057,324.114 75.896,324.114 cw(c75.896,324.251) 75.76,324.251 75.76,324.485 v1(75.76,332.115)
  L3 (Sign) w0.2: v1(136.549,268.624) 136.549,268.553 136.385,268.389 136.313,268.317 cw(c136.217,268.413) 136.12,268.317 136.065,268.372 ccw(c135.969,268.275) 135.873,268.372 135.744,268.243 ccw(c135.841,268.147) 135.744,268.05 135.799,267.996 cw(c135.703,267.899) 135.799,267.803 135.574,267.578 135.414,267.418 135.414,264.668 135.414,264.496 cw(c135.277,264.496) 135.277,264.359 134.942,264.359 ccw(c134.942,264.223) 134.806,264.223 134.806,264.041 ccw(c134.942,264.041) 134.942,263.905 135.277,263.905 cw(c135.277,263.769) 135.414,263.769 135.414,263.587 cw(c135.277,263.587) 135.277,263.451 134.942,263.451 ccw(c134.942,263.315) 134.806,263.315 134.806,263.133 ccw(c134.942,263.133) 134.942,262.997 135.277,262.997 cw(c135.277,262.861) 135.414,262.861 135.414,262.679 cw(c135.277,262.679) 135.277,262.543 134.942,262.543 ccw(c134.942,262.406) 134.806,262.406 134.806,262.225 ccw(c134.942,262.225) 134.942,262.088 135.277,262.088 cw(c135.277,261.952) 135.414,261.952 135.414,261.861 135.414,252.184 134.977,251.747 134.977,244.031 139.423,239.585 161.165,239.585 161.673,240.094 167.902,240.094 169.745,238.25 v2(169.745,237.003) ; v2(172.301,233.579) 172.327,233.604 176.06,233.604 v6(176.085,233.629) 177.179,232.535 188.829,232.535 189.422,231.942 189.978,231.385 cw(c189.882,231.289) 189.978,231.193 189.918,231.133 ccw(c190.015,231.036) 189.918,230.94 190.047,230.812 ccw(c190.143,230.908) 190.24,230.812 190.396,230.968 191.238,231.81 cw(c191.334,231.713) 191.43,231.81 191.559,231.681 cw(c191.462,231.585) 191.559,231.488 190.814,230.743 ccw(c190.91,230.647) 190.814,230.55 191.038,230.326 191.199,230.165 194.427,230.165 194.678,230.416 194.678,233.105 195.908,234.335 J25.4@196.986,234.335 ; v2(184.533,409.092) 185.052,408.574 185.052,404.698 185.052,404.607 ccw(c185.188,404.607) 185.188,404.471 186.257,404.471 cw(c186.257,404.335) 186.394,404.335 186.394,404.153 cw(c186.257,404.153) 186.257,404.017 185.052,404.017 ccw(c185.052,403.881) 184.915,403.881 184.915,403.699 ccw(c185.052,403.699) 185.052,403.563 186.257,403.563 cw(c186.257,403.426) 186.394,403.426 186.394,403.245 cw(c186.257,403.245) 186.257,403.109 185.188,403.109 ccw(c185.188,402.972) 185.052,402.972 185.052,402.73 185.052,393.751 186.401,392.402 200.437,392.402 204.798,388.041 245.955,388.041 249.828,384.167 251.066,384.167 253.638,381.595 264.979,381.595 279.262,367.313 279.262,261.953 260.998,243.689 252.423,243.689 v6(251.818,244.294)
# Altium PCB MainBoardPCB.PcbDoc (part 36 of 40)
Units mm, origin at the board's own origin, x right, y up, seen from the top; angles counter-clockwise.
Board outline 258.95 x 308.86 mm, 16 copper layers (L1, L2 (GND), L3 (Sign), L4 (GND), L5 (Sign), L6 (PWR/GND), L7(12V+Other), L8 (Plane_GND), L9 (PWR/GND), L10 (3V3+Other), L11 (PWR/GND), L12 (Sign), L13 (GND), L14 (Sign), L15 (GND), L16), stack 2.503 mm thick; 2578 components, 1867 nets, 8817 pads, 8021 vias.
Unrouted connection lines stored in the file: 25.

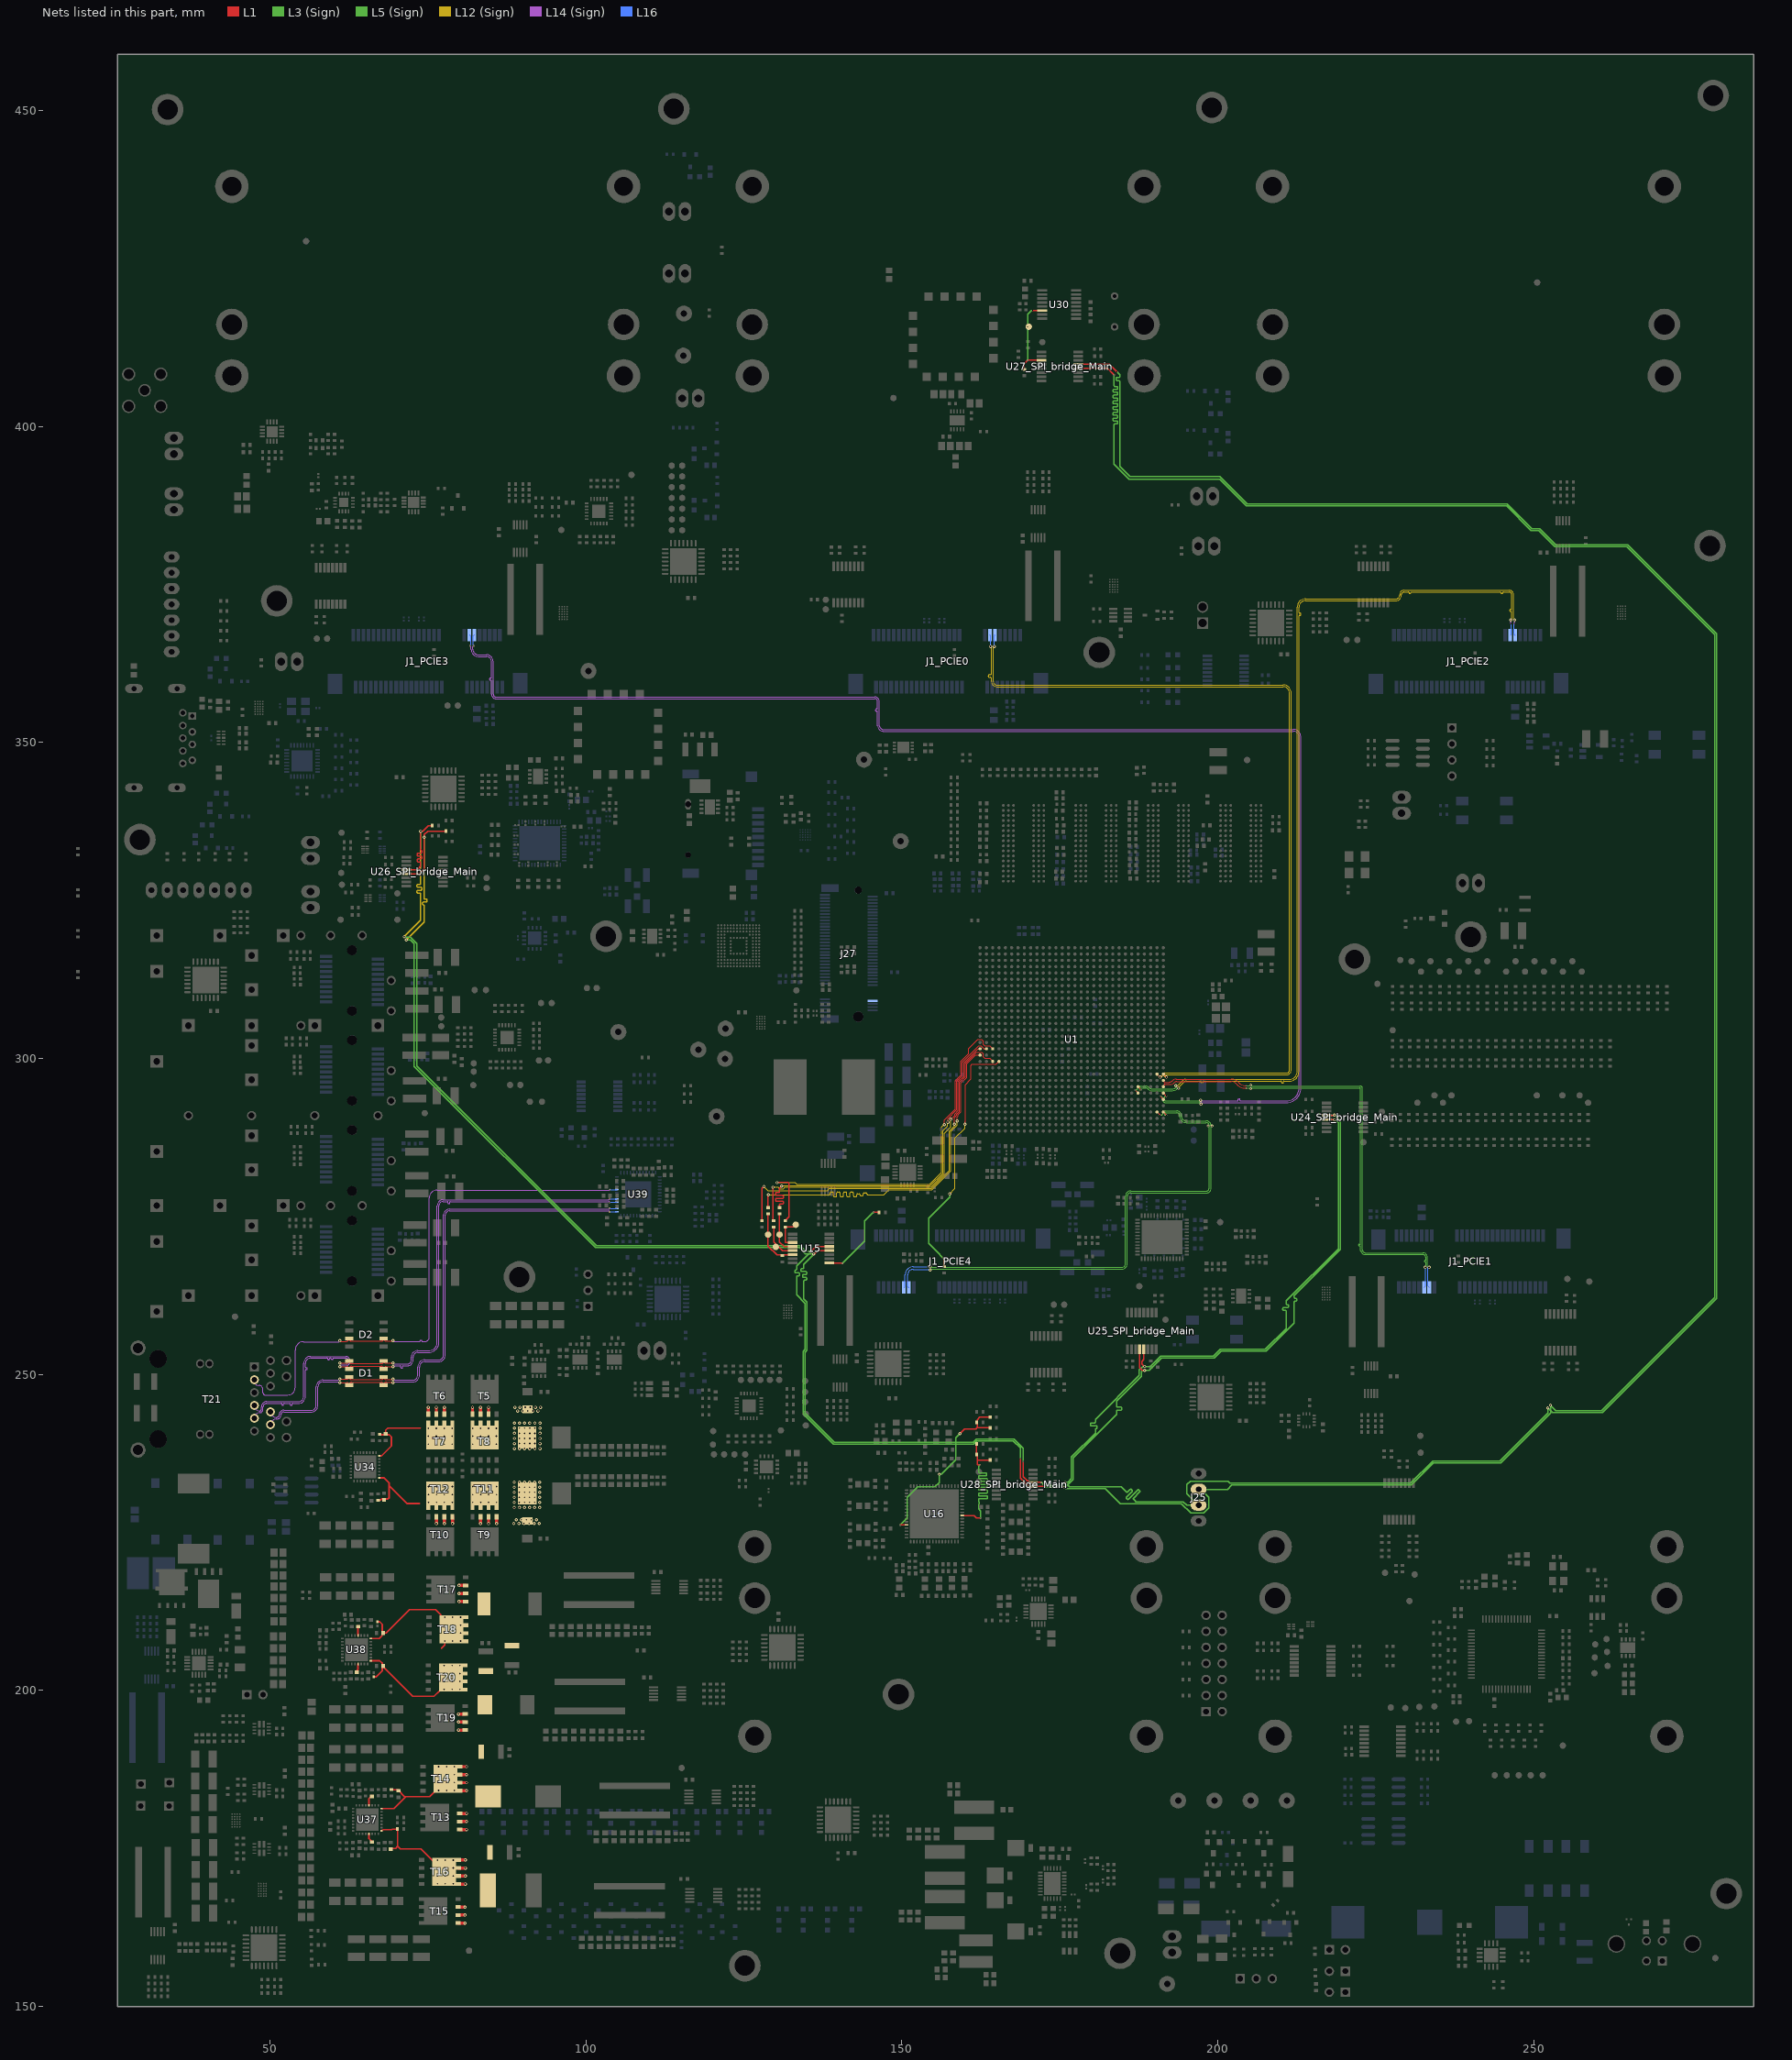
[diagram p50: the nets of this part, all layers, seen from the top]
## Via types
v1: diameter 0.5, hole 0.25, L1 to L16, tented both sides, 4341 vias
v2: diameter 0.254, hole 0.1, L1 to L3 (Sign), tented both sides, 781 vias
v3: diameter 0.5, hole 0.25, L1 to L16, 565 vias
v4: diameter 0.254, hole 0.1, L15 (GND) to L16, tented both sides, 406 vias
v5: diameter 0.254, hole 0.1, L1 to L2 (GND), tented both sides, 283 vias
v6: diameter 0.457, hole 0.2, L3 (Sign) to L6 (PWR/GND), tented both sides, 254 vias
v7: diameter 0.254, hole 0.1, L1 to L3 (Sign), 237 vias
v8: diameter 0.75, hole 0.4, L1 to L16, 200 vias
v9: diameter 0.8, hole 0.4, L1 to L16, tented both sides, 182 vias
v10: diameter 0.254, hole 0.1, L14 (Sign) to L16, tented both sides, 170 vias
v11: diameter 0.75/0/0/0/0/0/0/0/0/0/0/0/0/0/0/0.75 (per signal layer), hole 0.4, L1 to L16, 160 vias
v12: diameter 0.457, hole 0.2, L3 (Sign) to L6 (PWR/GND), 158 vias
v13: diameter 1.4, hole 0.5, L1 to L16, tented both sides, 80 vias
v14: diameter 0.254, hole 0.1, L14 (Sign) to L16, 65 vias
v15: diameter 0.254, hole 0.1, L1 to L2 (GND), 45 vias
v16: diameter 0.457, hole 0.2, L11 (PWR/GND) to L14 (Sign), tented both sides, 26 vias
v17: diameter 0.457, hole 0.2, L11 (PWR/GND) to L14 (Sign), 25 vias
v18: diameter 0.457, hole 0.2, L7(12V+Other) to L10 (3V3+Other), tented both sides, 11 vias
v19: diameter 0.254/0/0.254 (per signal layer), hole 0.1, L1 to L3 (Sign), 9 vias
v20: diameter 0.2/0/0.2 (per signal layer), hole 0.1, L1 to L3 (Sign), 6 vias
v21: diameter 1.65, hole 1.65, L1 to L16, 5 vias
v22: diameter 1.15, hole 1.15, L1 to L16, 5 vias
v23: diameter 0.457, hole 0.2, L1 to L16, 3 vias
v24: diameter 0.5, hole 0.3, L1 to L16, 2 vias
v25: diameter 0.5/0/0.5 (per signal layer), hole 0.2, L14 (Sign) to L16, 1 vias
v26: diameter 0.5, hole 0.25, L1 to L16, tented bottom, 1 vias

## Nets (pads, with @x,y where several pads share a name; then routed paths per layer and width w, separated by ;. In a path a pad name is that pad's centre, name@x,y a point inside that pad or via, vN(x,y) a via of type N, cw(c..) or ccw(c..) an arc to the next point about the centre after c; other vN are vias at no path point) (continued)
SPI1_MISO: J25.3 R807.1 U15.13 U24_SPI_bridge_Main.4 U25_SPI_bridge_Main.4 U26_SPI_bridge_Main.4 U27_SPI_bridge_Main.4 U28_SPI_bridge_Main.4 | length 668.6
  L1 w0.2: U26_SPI_bridge_Main.4@71.573,329.89 73.312,329.89 73.863,330.441 73.863,330.668 73.863,330.986 ccw(c73.727,330.986) 73.727,331.123 73.464,331.123 cw(c73.464,331.259) 73.328,331.259 73.328,331.441 cw(c73.464,331.441) 73.464,331.577 73.863,331.577 73.883,331.577 ccw(c73.883,331.713) 74.02,331.713 74.02,331.895 ccw(c73.883,331.895) 73.883,332.031 73.863,332.031 73.464,332.031 cw(c73.464,332.167) 73.328,332.167 73.328,332.349 cw(c73.464,332.349) 73.464,332.485 73.863,332.485 73.883,332.485 ccw(c73.883,332.621) 74.02,332.621 74.02,332.803 ccw(c73.883,332.803) 73.883,332.939 ; 73.891,332.939 73.978,332.939 ; 73.986,332.939 cw(c73.986,333.062) 73.863,333.062 73.863,333.273 v1(73.863,335.989) 73.871,335.996 74.233,335.996 75.048,336.811 75.68,336.811 R807.1@75.749,336.88 ; v1(135.623,269.532) 135.69,269.532 136.409,270.251 U15.13@138.523,270.251 ; v2(168.771,236.733) 168.771,233.639 170.121,232.288 172.483,232.288 172.616,232.155 v2(172.631,232.155) ; U27_SPI_bridge_Main.4@177.908,409.191 182.596,409.191 v2(183.614,408.173) ; U25_SPI_bridge_Main.4@187.648,254.021 187.648,251.097 188.061,250.684 188.421,250.684 v1(188.43,250.676) ; U24_SPI_bridge_Main.4@217.232,291.002 218.396,291.002 v1(218.465,291.071)
  L5 (Sign) w0.2: v1(71.26,319.291) 71.337,319.213 72.218,319.213 73.226,318.205 73.226,298.805 101.662,270.369 133.913,270.369 134.75,269.532 v1(135.623,269.532) ; v6(175.696,232.187) 175.696,232.228 175.813,232.346 176.067,232.346 177.117,233.396 177.117,236.8 184.013,243.696 184.013,243.923 184.013,244.241 cw(c184.15,244.241) 184.15,244.377 184.707,244.377 ccw(c184.707,244.513) 184.843,244.513 184.843,244.695 ccw(c184.707,244.695) 184.707,244.831 184.15,244.831 cw(c184.15,244.968) 184.013,244.968 184.013,245.827 187.897,249.71 187.897,250.444 188.128,250.676 v1(188.43,250.676) 189.139,250.676 191.108,252.644 199.465,252.644 200.519,253.698 207.671,253.698 212.115,258.143 212.115,261.137 212.115,261.476 cw(c212.252,261.476) 212.252,261.612 212.364,261.612 ccw(c212.364,261.748) 212.501,261.748 212.501,261.93 ccw(c212.364,261.93) 212.364,262.066 212.252,262.066 cw(c212.252,262.202) 212.115,262.202 212.115,262.293 212.115,262.499 219.397,269.781 219.397,290.182 218.508,291.071 v1(218.465,291.071) ; J25.3@196.986,231.835 201.566,231.835 202.252,232.521 230.662,232.521 234.154,236.014 244.786,236.014 252.693,243.92 252.693,245.117 v6(252.667,245.143)
  L12 (Sign) w0.2: v1(71.26,319.291) 73.863,321.894 73.863,325.958 73.863,326.049 ccw(c73.727,326.049) 73.727,326.185 73.422,326.185 cw(c73.422,326.322) 73.286,326.322 73.286,326.503 cw(c73.422,326.503) 73.422,326.639 73.863,326.639 73.925,326.639 ccw(c73.925,326.776) 74.062,326.776 74.062,326.957 ccw(c73.925,326.957) 73.925,327.094 73.863,327.094 73.422,327.094 cw(c73.422,327.23) 73.286,327.23 73.286,327.412 cw(c73.422,327.412) 73.422,327.548 73.727,327.548 ccw(c73.727,327.684) 73.863,327.684 73.863,327.851 v1(73.863,335.989)
  L3 (Sign) w0.2: v1(135.623,269.532) 135.623,269.466 133.375,267.218 133.375,266.991 133.375,266.673 cw(c133.239,266.673) 133.239,266.536 ccw(c133.239,266.4) 133.103,266.4 133.103,266.218 ccw(c133.239,266.218) 133.239,266.082 133.375,266.082 133.699,266.082 cw(c133.699,265.946) 133.836,265.946 133.836,265.764 cw(c133.699,265.764) 133.699,265.628 133.512,265.628 ccw(c133.512,265.492) 133.375,265.492 133.375,265.481 133.375,262.611 134.706,261.28 134.706,253.965 134.377,253.635 134.377,243.783 139.174,238.986 161.413,238.986 161.922,239.494 167.653,239.494 168.771,238.376 v2(168.771,236.733) ; v2(172.631,232.155) 172.641,232.165 175.674,232.165 v6(175.696,232.187) ; v6@175.71,232.201 175.976,231.935 182.212,231.935 184.582,229.565 194.259,229.565 195.732,228.092 197.828,228.092 198.615,228.879 198.615,230.582 197.361,231.835 J25.3@196.986,231.835 ; v2(183.614,408.173) 183.614,406.565 183.614,406.474 ccw(c183.75,406.474) 183.75,406.338 184.057,406.338 cw(c184.057,406.202) 184.193,406.202 184.193,406.02 cw(c184.057,406.02) 184.057,405.884 183.614,405.884 183.59,405.884 ccw(c183.59,405.748) 183.454,405.748 183.454,405.566 ccw(c183.59,405.566) 183.59,405.43 183.614,405.43 184.057,405.43 cw(c184.057,405.293) 184.193,405.293 184.193,405.112 cw(c184.057,405.112) 184.057,404.975 183.614,404.975 183.59,404.975 ccw(c183.59,404.839) 183.454,404.839 183.454,404.657 ccw(c183.59,404.657) 183.59,404.521 183.614,404.521 184.057,404.521 cw(c184.057,404.385) 184.193,404.385 184.193,404.203 cw(c184.057,404.203) 184.057,404.067 183.614,404.067 183.59,404.067 ccw(c183.59,403.931) 183.454,403.931 183.454,403.749 ccw(c183.59,403.749) 183.59,403.613 183.614,403.613 184.057,403.613 cw(c184.057,403.477) 184.193,403.477 184.193,403.295 cw(c184.057,403.295) 184.057,403.159 183.614,403.159 183.59,403.159 ccw(c183.59,403.022) 183.454,403.022 183.454,402.841 ccw(c183.59,402.841) 183.59,402.704 183.614,402.704 184.057,402.704 cw(c184.057,402.568) 184.193,402.568 184.193,402.386 cw(c184.057,402.386) 184.057,402.25 183.614,402.25 183.59,402.25 ccw(c183.59,402.114) 183.454,402.114 183.454,401.932 ccw(c183.59,401.932) 183.59,401.796 183.614,401.796 184.057,401.796 cw(c184.057,401.66) 184.193,401.66 184.193,401.478 cw(c184.057,401.478) 184.057,401.342 183.614,401.342 183.59,401.342 ccw(c183.59,401.206) 183.454,401.206 183.454,401.024 ccw(c183.59,401.024) 183.59,400.888 183.614,400.888 184.057,400.888 cw(c184.057,400.751) 184.193,400.751 184.193,400.57 cw(c184.057,400.57) 184.057,400.433 183.75,400.433 ccw(c183.75,400.297) 183.614,400.297 183.614,399.847 183.614,394.033 185.975,391.672 200.318,391.672 204.561,387.429 245.718,387.429 249.58,383.567 250.818,383.567 253.39,380.995 264.731,380.995 278.662,367.064 278.662,262.201 260.75,244.289 253.52,244.289 v6(252.667,245.143)
SPI1_MOSI: J25.2 R808.1 U15.12 U24_SPI_bridge_Main.5 U25_SPI_bridge_Main.5 U26_SPI_bridge_Main.5 U27_SPI_bridge_Main.5 U28_SPI_bridge_Main.5 | length 664.2
  L1 w0.2: U26_SPI_bridge_Main.5@71.573,329.24 73.614,329.24 74.422,330.048 v1(74.422,335.029) 74.422,335.432 74.965,335.975 77.86,335.975 R808.1@77.896,336.01 ; v1(136.08,269.074) 136.151,269.074 136.678,269.601 U15.12@138.523,269.601 ; v2(169.219,236.276) 169.219,233.824 169.879,233.163 170.019,233.163 170.244,232.938 U28_SPI_bridge_Main.5@170.769,232.938 v2(172.098,232.938) ; U27_SPI_bridge_Main.5@177.908,409.841 182.865,409.841 v2(184.073,408.633) ; U25_SPI_bridge_Main.5@188.298,254.021 188.298,252.38 187.98,252.062 187.98,251.689 188.394,251.276 v1(188.43,251.276) ; U24_SPI_bridge_Main.5@217.232,290.352 217.257,290.328 218.467,290.328 v1(218.491,290.304)
  L5 (Sign) w0.2: v1(71.596,318.763) 71.623,318.79 72.217,318.79 72.839,318.168 72.839,298.769 101.538,270.069 133.789,270.069 134.784,269.074 v1(136.08,269.074) ; v6(175.849,232.938) 175.907,232.996 176.293,232.996 176.817,233.52 176.817,236.924 180.645,240.752 180.645,240.979 180.645,241.297 cw(c180.781,241.297) 180.781,241.433 180.794,241.433 ccw(c180.794,241.569) 180.93,241.569 180.93,241.751 ccw(c180.794,241.751) 180.794,241.887 180.645,241.887 179.985,241.887 cw(c179.985,242.023) 179.848,242.023 179.848,242.205 cw(c179.985,242.205) 179.985,242.341 180.509,242.341 ccw(c180.509,242.477) 180.645,242.477 180.645,242.837 180.645,242.882 187.597,249.834 187.597,250.741 188.131,251.276 v1(188.43,251.276) 189.315,251.276 190.983,252.944 199.341,252.944 200.395,253.998 207.547,253.998 210.845,257.297 210.845,259.791 210.845,260.005 ccw(c210.709,260.005) 210.709,260.142 210.444,260.142 cw(c210.444,260.278) 210.308,260.278 210.308,260.46 cw(c210.444,260.46) 210.444,260.596 210.845,260.596 211.079,260.596 ccw(c211.079,260.732) 211.216,260.732 211.216,260.914 ccw(c211.079,260.914) 211.079,261.05 210.982,261.05 cw(c210.982,261.186) 210.845,261.186 210.845,261.277 210.845,261.653 219.097,269.905 219.097,289.801 218.594,290.304 v1(218.491,290.304) ; J25.2@196.986,229.335 195.148,231.174 195.148,232.579 195.69,233.121 201.638,233.121 201.938,232.821 230.538,232.821 234.03,236.314 244.662,236.314 252.268,243.92 252.268,244.693 v6(252.243,244.719)
  L12 (Sign) w0.2: v1(71.596,318.763) 74.422,321.589 74.422,324.079 74.422,324.183 ccw(c74.299,324.183) 74.299,324.306 cw(c74.299,324.442) 74.163,324.442 74.163,324.624 cw(c74.299,324.624) 74.299,324.76 74.422,324.76 74.741,324.76 ccw(c74.741,324.896) 74.878,324.896 74.878,325.078 ccw(c74.741,325.078) 74.741,325.214 74.558,325.214 cw(c74.558,325.35) 74.422,325.35 74.422,325.768 v1(74.422,335.029)
  L3 (Sign) w0.2: v1(136.08,269.074) 136.08,269.003 134.506,267.429 134.506,267.202 134.506,266.884 cw(c134.369,266.884) 134.369,266.747 134.172,266.747 ccw(c134.172,266.611) 134.036,266.611 134.036,266.429 ccw(c134.172,266.429) 134.172,266.293 134.506,266.293 134.811,266.293 cw(c134.811,266.157) 134.947,266.157 134.947,265.975 cw(c134.811,265.975) 134.811,265.839 134.506,265.839 134.435,265.839 ccw(c134.435,265.703) 134.299,265.703 134.299,265.521 ccw(c134.435,265.521) 134.435,265.385 134.506,265.385 134.811,265.385 cw(c134.811,265.249) 134.947,265.249 134.947,265.067 cw(c134.811,265.067) 134.811,264.931 134.642,264.931 ccw(c134.642,264.794) 134.506,264.794 134.506,264.147 134.506,261.981 135.006,261.48 135.006,253.84 134.677,253.511 134.677,243.907 139.299,239.286 161.289,239.286 161.798,239.794 167.777,239.794 169.219,238.353 v2(169.219,236.276) ; v2(172.098,232.938) 172.554,232.482 175.355,232.482 175.509,232.637 ; 175.51,232.637 175.811,232.938 v6(175.849,232.938) 176.552,232.235 184.706,232.235 185.591,231.35 ccw(c185.631,231.389) 185.67,231.35 186.14,231.82 cw(c186.236,231.723) 186.333,231.82 186.461,231.691 cw(c186.365,231.595) 186.461,231.498 185.952,230.989 185.565,230.602 ccw(c185.661,230.506) 185.565,230.409 185.693,230.281 ccw(c185.79,230.377) 185.886,230.281 186.273,230.668 187.345,231.74 cw(c187.442,231.644) 187.538,231.74 187.667,231.612 cw(c187.57,231.516) 187.667,231.419 186.691,230.443 ccw(c186.787,230.347) 186.691,230.25 186.915,230.026 187.076,229.865 194.551,229.865 195.081,229.335 J25.2@196.986,229.335 ; v2(184.073,408.633) 184.493,408.213 184.493,407.975 184.493,407.884 cw(c184.357,407.884) 184.357,407.748 184.05,407.748 ccw(c184.05,407.611) 183.913,407.611 183.913,407.43 ccw(c184.05,407.43) 184.05,407.294 184.357,407.294 cw(c184.357,407.157) 184.493,407.157 184.493,406.971 184.493,393.708 186.099,392.102 200.313,392.102 204.686,387.729 245.843,387.729 249.704,383.867 250.942,383.867 253.514,381.295 264.855,381.295 278.962,367.188 278.962,262.077 260.874,243.989 252.972,243.989 v6(252.243,244.719)
SPI_05028_CS: R2.2 R129.1 R912.2 U16.24 | length 30.6
  L1 w0.2: U16.24@159.565,227.695 161.454,227.695 161.832,227.317 v7(162.496,227.317) ; R912.2@161.932,239.033 161.806,238.907 161.806,237.466 161.932,237.34 161.932,236.499 ; v7(162.357,235.712) 161.991,235.712 161.932,235.77 161.932,236.499 ; R2.2@164.053,236.477 161.955,236.477 161.932,236.499
  L3 (Sign) w0.2: v7(162.357,235.712) 162.15,235.505 162.15,235.377 162.15,234.571 ccw(c162.286,234.571) 162.286,234.435 163.31,234.435 cw(c163.31,234.299) 163.446,234.299 163.446,234.117 cw(c163.31,234.117) 163.31,233.981 162.286,233.981 ccw(c162.286,233.845) 162.15,233.845 162.15,233.663 ccw(c162.286,233.663) 162.286,233.527 163.434,233.527 cw(c163.434,233.391) 163.57,233.391 163.57,233.209 cw(c163.434,233.209) 163.434,233.073 162.286,233.073 ccw(c162.286,232.936) 162.15,232.936 162.15,232.755 ccw(c162.286,232.755) 162.286,232.618 163.434,232.618 cw(c163.434,232.482) 163.57,232.482 163.57,232.3 cw(c163.434,232.3) 163.434,232.164 162.286,232.164 ccw(c162.286,232.028) 162.15,232.028 162.15,231.846 ccw(c162.286,231.846) 162.286,231.71 163.434,231.71 cw(c163.434,231.574) 163.57,231.574 163.57,231.392 cw(c163.434,231.392) 163.434,231.256 162.286,231.256 ccw(c162.286,231.12) 162.15,231.12 162.15,230.938 ccw(c162.286,230.938) 162.286,230.802 163.434,230.802 cw(c163.434,230.665) 163.57,230.665 163.57,230.484 cw(c163.434,230.484) 163.434,230.347 162.286,230.347 ccw(c162.286,230.211) 162.15,230.211 162.15,229.893 cw(c162.15,229.762) 162.281,229.762 162.281,229.57 cw(c162.15,229.57) 162.15,229.439 162.15,228.985 162.15,228.758 162.496,228.411 v7(162.496,227.317)
SPI_05028_MISO: R1.2 R128.1 R133.2 U16.60 | length 30.1
  L1 w0.2: v2(149.733,226.149) 149.779,226.195 U16.60@150.765,226.195 ; v1(159.224,240.635) 159.224,240.656 159.969,241.402 161.765,241.402 161.925,241.561 ; R133.2@164.051,241.561 161.925,241.561 ; R1.2@164.051,243.256 162.332,243.256 161.932,242.857 161.932,241.568 161.925,241.561
  L5 (Sign) w0.2: v6(155.94,234.222) 156.269,234.222 158.572,236.525 158.572,239.984 v1(159.224,240.635)
  L3 (Sign) w0.2: v2(149.733,226.149) 150.901,227.317 150.901,230.594 152.514,232.207 155.25,232.207 155.94,232.896 v6(155.94,234.222)
SPI_DAC_CS: R238_SPI_bridge_Main.1 SP27_SPI_bridge_Main.1 U27_SPI_bridge_Main.11 U30.14 | length 14
  L1 w0.12: v2(169.91,415.798) SP27_SPI_bridge_Main.1@170.104,415.798
  L1 w0.2: R238_SPI_bridge_Main.1@169.382,409.001 169.382,409.959 v7(169.914,410.491) U27_SPI_bridge_Main.11@172.108,410.491 ; v7(170.686,418.351) 170.686,418.363 U30.14@172.25,418.363
  L3 (Sign) w0.12: v2@169.884,415.823 v2(169.91,415.798)
  L3 (Sign) w0.2: v7(169.914,410.491) v2@169.914,415.798 ; v2@169.914,415.823 169.914,417.753 170.512,418.351 v7(170.686,418.351)
SPI_FPGA_CLK: R905.2 SP30.1 U15.3 | length 5.4
  L1 w0.2: U15.3@132.723,270.901 131.677,270.901 131.572,271.005 131.572,273.4 132.913,273.4 SP30.1@133.223,273.71
SPI_FPGA_CLK_R: R905.1 U1.C14 | length 61.7
  L1 w0.12: v1(156.726,289.535) 156.726,290.251 158.505,292.031 158.505,296.523 159.385,297.403 159.385,299.53 160.611,300.755 160.611,301.593 162.052,303.035 162.617,303.035 162.902,302.75 162.902,302.235 163.111,302.027 163.909,302.027 U1.C14@164.397,301.539
  L1 w0.2: v1(130.258,280.365) 132.038,280.365 132.155,280.248 132.155,274.933 R905.1@131.572,274.35
  L12 (Sign) w0.12: v1(130.258,280.365) 133.121,280.365 133.384,280.101 154.429,280.101 156.3,281.973 156.3,289.147 156.688,289.535 v1(156.726,289.535)
SPI_FPGA_CS: R365.2 R908.2 SP33.1 U15.6 | length 9.6
  L1 w0.2: R908.2@128.841,275.463 SP33.1@128.841,272.136 128.841,270.345 130.236,268.951 U15.6@132.723,268.951
SPI_FPGA_CS_R: R908.1 U1.A13 | length 58.7
  L1 w0.12: v1(158.755,290.116) 158.755,290.753 158.955,290.953 158.955,291.15 159.385,291.581 159.385,296.158 160.265,297.038 160.265,299.165 161.639,300.539 U1.A13@162.397,300.539
  L1 w0.2: R908.1@128.841,276.363 128.841,278.397 v1(128.892,278.447)
  L12 (Sign) w0.12: v1(128.892,278.447) 138.449,278.447 138.509,278.447 ccw(c138.509,278.605) 138.667,278.605 138.667,278.703 cw(c138.825,278.703) 138.825,278.861 139.035,278.861 cw(c139.035,278.703) 139.193,278.703 139.193,278.293 ccw(c139.351,278.293) 139.351,278.135 139.562,278.135 ccw(c139.562,278.293) 139.72,278.293 139.72,278.703 cw(c139.878,278.703) 139.878,278.861 140.088,278.861 cw(c140.088,278.703) 140.246,278.703 140.246,278.293 ccw(c140.404,278.293) 140.404,278.135 140.615,278.135 ccw(c140.615,278.293) 140.772,278.293 140.772,278.703 cw(c140.93,278.703) 140.93,278.861 141.141,278.861 cw(c141.141,278.703) 141.299,278.703 141.299,278.293 ccw(c141.457,278.293) 141.457,278.135 141.667,278.135 ccw(c141.667,278.293) 141.825,278.293 141.825,278.703 cw(c141.983,278.703) 141.983,278.861 142.194,278.861 cw(c142.194,278.703) 142.352,278.703 142.352,278.304 ccw(c142.51,278.304) 142.51,278.146 142.72,278.146 ccw(c142.72,278.304) 142.878,278.304 142.878,278.448 cw(c143.036,278.448) 143.036,278.605 143.247,278.605 cw(c143.247,278.448) 143.404,278.448 ccw(c143.562,278.447) 143.562,278.29 143.773,278.29 ccw(c143.773,278.447) 143.931,278.447 143.931,278.605 cw(c144.089,278.605) 144.089,278.763 144.299,278.763 cw(c144.299,278.605) 144.457,278.605 ccw(c144.615,278.605) 144.615,278.447 145.284,278.447 147.182,278.447 147.956,279.221 154.793,279.221 157.78,282.208 157.78,288.454 158.765,289.439 158.765,290.106 v1(158.755,290.116)
SPI_FPGA_MISO: R906.2 SP31.1 U15.4 | length 6.8
  L1 w0.2: R906.2@130.658,275.413 130.658,271.005 131.412,270.251 U15.4@132.723,270.251
SPI_FPGA_MISO_R: R906.1 U1.B14 | length 58.3
  L1 w0.12: v1(157.296,289.928) 157.296,290.51 158.725,291.94 158.725,296.432 159.605,297.312 159.605,299.439 162.193,302.027 162.552,302.027 163.039,301.539 U1.B14@163.397,301.539
  L1 w0.2: R906.1@130.658,276.363 130.658,276.809 130.658,276.839 cw(c130.794,276.839) 130.794,276.975 131.136,276.975 ccw(c131.136,277.111) 131.272,277.111 131.272,277.293 ccw(c131.136,277.293) 131.136,277.429 130.658,277.429 130.167,277.429 cw(c130.167,277.565) 130.03,277.565 130.03,277.747 cw(c130.167,277.747) 130.167,277.883 130.658,277.883 131.136,277.883 ccw(c131.136,278.019) 131.272,278.019 131.272,278.201 ccw(c131.136,278.201) 131.136,278.337 130.658,278.337 130.167,278.337 cw(c130.167,278.474) 130.03,278.474 130.03,278.655 cw(c130.167,278.655) 130.167,278.792 130.521,278.792 ccw(c130.521,278.928) 130.658,278.928 130.658,279.246 130.658,279.473 v1(131.013,279.828)
  L12 (Sign) w0.12: v1(131.013,279.828) 131.066,279.881 154.52,279.881 156.52,281.881 156.52,288.562 157.286,289.328 157.286,289.918 v1(157.296,289.928)
SPI_FPGA_MOSI: R907.2 SP32.1 U15.5 | length 6
  L1 w0.2: R907.2@129.731,273.4 129.731,271.716 129.731,270.996 131.126,269.601 U15.5@132.723,269.601
SPI_FPGA_MOSI_R: R907.1 U1.A14 | length 55.9
  L1 w0.12: v1(157.757,290.377) 158.388,291.008 158.388,291.205 158.945,291.763 158.945,296.34 159.825,297.22 159.825,299.348 162.017,301.539 U1.A14@162.397,301.539
  L1 w0.2: v1(129.616,279.641) 129.616,274.464 R907.1@129.731,274.35
  L12 (Sign) w0.12: v1(129.616,279.641) 130.381,279.641 130.604,279.418 131.26,279.418 131.503,279.661 154.611,279.661 156.74,281.79 156.74,288.166 157.757,289.183 v1(157.757,290.377)
SPI_FPGA_nOE: R75.2 U15.9 | length 13.1
  L1 w0.2: U15.9@138.523,267.651 138.572,267.602 v2(140.614,267.602) ; v2(145.529,275.666) 145.542,275.653 R75.2@146.458,275.653
  L3 (Sign) w0.2: v2(140.614,267.602) 144.145,271.132 144.145,274.282 v2(145.529,275.666)
SPI_FPGA_OE_R: R903.1 U1.D12 | length 40.4
  L1 w0.12: v1(159.995,289.618) 160.038,289.662 160.038,289.943 160.045,289.95 160.045,295.885 160.925,296.765 160.925,298.892 161.13,299.097 164.954,299.097 U1.D12@165.397,299.539
  L1 w0.2: v7(156.704,268.301) 156.704,267.055 R903.1@156.719,267.041
  L12 (Sign) w0.12: v1(157.582,278.6) 158.44,279.458 158.44,287.408 159.995,288.963 v1(159.995,289.618)
  L3 (Sign) w0.2: v7(156.704,268.301) 155.404,269.601 154.262,270.742 154.262,274.752 157.582,278.071 v1(157.582,278.6)
SS1_1: C639.2 U37.28 | length 1.7
  L1 w0.254: U37.28@65.675,181.817 65.675,182.903 C639.2@66.141,183.369
SS1_2: C647.2 U38.28 | length 1.6
  L1 w0.254: U38.28@63.953,208.714 C647.2@63.953,210.264
SS2_1: C640.2 U37.13 | length 1.6
  L1 w0.254: U37.13@65.675,177.317 65.675,176.584 66.161,176.097 C640.2@66.161,175.893
SS2_2: C648.2 U38.13 | length 1.5
  L1 w0.254: C648.2@63.741,202.763 63.741,203.154 63.953,203.366 U38.13@63.953,204.214
SUSCLK: J27.60
SW1: C346.2 L9.1 R610.2 R613.2 T5.1 T5.2 T5.3 T6.1 T6.2 T6.3 T7.5 T7.6 T7.7 T7.8 T8.5 T8.6 T8.7 T8.8 U34.24 | length 18.8
  L1 w0.254: U34.24@67.322,237.139 67.657,237.139 69.236,238.718 69.236,240.156 68.922,240.47 C346.2@68.336,240.47 ; R610.2@67.378,240.47 C346.2@68.336,240.47 ; 73.8,241.529 68.669,241.529 68.336,241.196 C346.2@68.336,240.47
  L1 w0.5: T6.1@75.072,243.723 v1(75.072,244.81) ; T6.2@76.342,243.723 v1(76.342,244.81) ; T6.3@77.612,243.723 v1(77.612,244.81) ; T5.1@82.072,243.723 v1(82.072,244.81) ; T5.2@83.342,243.723 v1(83.342,244.81) ; T5.3@84.612,243.723 v1(84.612,244.81)
  other v1: 88.711,238.28 89.517,238.28 90.322,238.28 91.128,238.28 91.934,238.28 92.74,238.28 75.09,238.992 76.342,238.992 77.593,238.992 78.845,238.992 82.09,238.992 83.342,238.992 84.593,238.992 85.845,238.992 88.711,239.086 89.517,239.086 90.322,239.086 91.128,239.086 91.934,239.086 92.74,239.086 88.711,239.892 89.517,239.892 90.322,239.892 91.128,239.892 91.934,239.892 92.74,239.892 75.09,240.244 76.342,240.244 77.593,240.244 78.845,240.244 82.09,240.244 83.342,240.244 84.593,240.244 85.845,240.244 88.711,240.697 89.517,240.697 90.322,240.697 91.128,240.697 91.934,240.697 92.74,240.697 75.09,241.496 76.342,241.496 77.593,241.496 78.845,241.496 82.09,241.496 83.342,241.496 84.593,241.496 85.845,241.496 88.711,241.503 89.517,241.503 90.322,241.503 91.128,241.503 91.934,241.503 92.74,241.503 88.711,242.309 89.517,242.309 90.322,242.309 91.128,242.309 91.934,242.309 92.74,242.309 89.212,244.228 90.018,244.228 90.823,244.228 91.629,244.228 92.435,244.228 88.788,244.811 89.594,244.811 90.4,244.811 91.206,244.811 92.011,244.811 92.817,244.811
SW1_1: C390.2 L11.1 R288.2 R619.2 T13.1 T13.2 T13.3 T14.5 T14.6 T14.7 T14.8 U37.24 | length 20
  L1 w0.2: U37.24@67.675,181.395 U37.24@67.675,181.317 69.658,181.317 71.539,183.197 ; R619.2@69.228,184.269 70.256,184.269 71.328,183.197 71.539,183.197 ; T14.8@76.111,183.985 75.324,183.197 71.539,183.197
  L1 w0.5: T14.5@80.039,184.15 v1(81.126,184.15) ; T14.6@80.039,185.42 v1(81.126,185.42) ; T14.7@80.039,186.69 v1(81.126,186.69) ; T14.8@80.039,187.96 v1(81.126,187.96) ; T13.1@80.042,178.003 v1(81.129,178.003) ; T13.2@80.042,179.273 v1(81.129,179.273) ; T13.3@80.042,180.543 v1(81.129,180.543)
  other v1: 76.718,184.187 77.97,184.187 79.221,184.187 76.718,185.438 77.97,185.438 79.221,185.438 76.718,186.69 77.97,186.69 79.221,186.69 76.718,187.942 77.97,187.942 79.221,187.942
SW1_2: C431.2 L19.1 R306.2 R625.1 T17.1 T17.2 T17.3 T18.5 T18.6 T18.7 T18.8 U38.24 | length 20.2
  L1 w0.2: 69.532,210.254 72.092,212.814 76.234,212.814 77.123,211.925
  L1 w0.254: U38.24@65.953,208.214 67.293,208.214 67.758,208.68 C431.2@67.758,209.091 ; R625.1@67.001,210.879 67.377,210.879 67.781,210.475 67.781,209.114 68.392,209.114 69.532,210.254 ; 77.166,206.68 77.677,207.192 77.677,207.477
  L1 w0.5: v1(79.911,214.079) T17.1@80.998,214.079 ; v1(79.911,215.349) T17.2@80.998,215.349 ; v1(79.911,216.619) T17.3@80.998,216.619
  other v1: 77.677,207.834 78.929,207.834 80.18,207.834 77.677,209.086 78.929,209.086 80.18,209.086 77.677,210.337 78.929,210.337 80.18,210.337 77.677,211.589 78.929,211.589 80.18,211.589
SW2: C350.2 L10.1 R611.2 R616.2 T9.1 T9.2 T9.3 T10.1 T10.2 T10.3 T11.5 T11.6 T11.7 T11.8 T12.5 T12.6 T12.7 T12.8 U34.17 | length 18.7
  L1 w0.254: R611.2@67.113,230.147 67.513,230.147 67.688,230.322 C350.2@68.072,230.322 ; U34.17@67.322,233.639 68.085,233.639 68.854,232.87 68.854,232.441 ; C350.2@68.072,230.317 C350.2@68.072,230.322 ; 73.685,229.578 71.717,229.578 68.854,232.441 ; C350.2@68.072,230.322 68.705,230.322 68.854,230.471 68.854,232.441
  L1 w0.5: v1(76.348,226.414) T10.3@76.348,227.501 ; v1(77.618,226.414) T10.2@77.618,227.501 ; v1(78.888,226.414) T10.1@78.888,227.501 ; v1(83.342,226.414) T9.3@83.342,227.501 ; v1(84.612,226.414) T9.2@84.612,227.501 ; v1(85.882,226.414) T9.1@85.882,227.501
  other v1: 88.597,226.45 89.402,226.45 90.208,226.45 91.014,226.45 91.82,226.45 92.625,226.45 88.979,227.033 89.785,227.033 90.59,227.033 91.396,227.033 92.202,227.033 88.674,228.952 89.48,228.952 90.286,228.952 91.091,228.952 91.897,228.952 92.703,228.952 75.108,229.757 76.36,229.757 77.612,229.757 78.863,229.757 82.108,229.757 83.36,229.757 84.612,229.757 85.863,229.757 88.674,229.758 89.48,229.758 90.286,229.758 91.091,229.758 91.897,229.758 92.703,229.758 88.674,230.564 89.48,230.564 90.286,230.564 91.091,230.564 91.897,230.564 92.703,230.564 75.108,231.008 76.36,231.008 77.612,231.008 78.863,231.008 82.108,231.008 83.36,231.008 84.612,231.008 85.863,231.008 88.674,231.369 89.48,231.369 90.286,231.369 91.091,231.369 91.897,231.369 92.703,231.369 88.674,232.175 89.48,232.175 90.286,232.175 91.091,232.175 91.897,232.175 92.703,232.175 75.108,232.26 76.36,232.26 77.612,232.26 78.863,232.26 82.108,232.26 83.36,232.26 84.612,232.26 85.863,232.26 88.674,232.981 89.48,232.981 90.286,232.981 91.091,232.981 91.897,232.981 92.703,232.981
SW2_1: C394.2 L12.1 R298.2 R620.2 T15.1 T15.2 T15.3 T16.5 T16.6 T16.7 T16.8 U37.17 | length 23.3
  L1 w0.2: U37.17@67.675,177.817 67.75,177.817 67.775,177.842 67.775,177.875 67.892,177.992 69.327,177.992 69.373,178.038 70.168,178.038 70.23,178.1 70.23,175.361 ; C394.2@69.151,175.037 69.906,175.037 70.23,175.361 ; T16.8@77.572,171.285 73.94,174.917 70.674,174.917 70.23,175.361
  L1 w0.5: T15.1@79.789,163.201 v1(80.876,163.201) ; T15.2@79.789,164.471 v1(80.876,164.471) ; T15.3@79.789,165.741 v1(80.876,165.741) ; T16.5@79.835,169.38 v1(80.922,169.38) ; T16.6@79.835,170.65 v1(80.922,170.65) ; T16.7@79.835,171.92 v1(80.922,171.92) ; T16.8@79.835,173.19 v1(80.922,173.19)
  other v1: 76.514,169.417 77.766,169.417 79.017,169.417 76.514,170.668 77.766,170.668 79.017,170.668 77.766,171.92 79.017,171.92 76.514,173.172 77.766,173.172 79.017,173.172
SW2_2: C435.2 L20.1 R302.1 R316.2 T19.1 T19.2 T19.3 T20.5 T20.6 T20.7 T20.8 U38.17 | length 19.6
  L1 w0.254: U38.17@65.953,204.714 67.394,204.714 67.796,204.312 C435.2@67.796,203.864 ; R302.1@66.453,202.163 66.794,202.163 67.796,203.166 C435.2@67.796,203.864 ; T20.8@76.873,199.987 75.971,199.083 72.588,199.08 C435.2@67.796,203.864
  L1 w0.5: v1(79.842,193.746) T19.1@80.929,193.746 ; v1(79.842,195.016) T19.2@80.929,195.016 ; v1(79.842,196.286) T19.3@80.929,196.286
  other v1: 77.578,200.189 78.83,200.189 80.081,200.189 77.578,201.44 78.83,201.44 80.081,201.44 77.578,202.692 78.83,202.692 80.081,202.692 77.578,203.944 78.83,203.944 80.081,203.944
SYNC_PCIE0_N: J1_PCIE0.12 U1.AK10 | length 137.1
  L1 w0.1: U1.AK10@191.397,297.539 v3(191.884,297.052)
  L12 (Sign) w0.081: v1(164.637,365.214) ccw(c164.637,365.054) 164.478,365.054 164.478,359.672 ccw(c165.032,359.672) 165.032,359.117 210.367,359.117 cw(c210.367,357.835) 211.649,357.835 211.649,298.2 cw(c210.87,298.2) 210.87,297.421 194.073,297.421 191.606,297.421 ccw(c191.606,297.34) 191.549,297.398 ccw(c191.606,297.34) 191.525,297.34 191.525,297.293 ccw(c191.685,297.293) 191.572,297.179 ccw(c191.685,297.293) 191.685,297.132 191.711,297.132 cw(c191.711,296.908) 191.87,297.067 v3(191.884,297.052)
  L16 w0.101: v1(164.637,365.214) 164.637,366.892 cw(c164.737,366.892) J1_PCIE0.12@164.737,366.992
SYNC_PCIE0_P: J1_PCIE0.14 U1.AJ10 | length 137.8
  L1 w0.1: U1.AJ10@190.397,297.539 v3(190.884,297.052)
  L12 (Sign) w0.081: v1(164.037,365.214) cw(c164.037,365.054) 164.197,365.054 164.197,361.239 164.197,360.922 cw(c164.022,360.922) 164.022,360.747 163.878,360.747 ccw(c163.878,360.573) 163.704,360.573 163.704,360.485 ccw(c163.878,360.485) 163.878,360.311 164.022,360.311 cw(c164.022,360.136) 164.197,360.136 164.197,360.095 164.197,359.672 ccw(c165.032,359.672) 165.032,358.836 210.367,358.836 cw(c210.367,357.835) 211.368,357.835 211.368,298.2 cw(c210.87,298.2) 210.87,297.702 194.073,297.702 191.604,297.702 ccw(c191.604,297.344) 191.351,297.597 191.349,297.595 ccw(c191.602,297.342) 191.244,297.342 191.244,297.293 cw(c191.083,297.293) 191.197,297.179 cw(c191.083,297.293) 191.083,297.132 191.057,297.132 ccw(c191.057,296.908) 190.899,297.067 v3(190.884,297.052)
  L16 w0.101: J1_PCIE0.14@163.937,366.992 cw(c163.937,366.892) 164.037,366.892 v1(164.037,365.214)
SYNC_PCIE1_N: J1_PCIE1.12 U1.AK8 | length 74.1
  L1 w0.1: U1.AK8@191.397,295.539 191.411,295.553 ccw(c191.255,295.709) 191.475,295.709 191.475,295.734 cw(c191.636,295.734) 191.522,295.847 cw(c191.636,295.734) 191.636,295.894 192.397,295.894 192.399,295.894
  L1 w0.101: 192.399,295.894 ccw(c192.399,296.973) 193.161,296.21 cw(c193.499,295.872) 193.499,296.35 202.146,296.35 cw(c202.146,295.246) 202.927,296.027 203.102,295.851 ccw(c204.401,297.15) 204.401,295.313 v7(204.558,295.313)
  L5 (Sign) w0.081: v12(205.22,295.214) cw(c205.379,295.214) 205.379,295.373 222.429,295.373 cw(c222.429,295.173) 222.629,295.173 222.629,271.046 222.629,270.722 cw(c222.544,270.722) 222.544,270.637 222.41,270.637 ccw(c222.41,270.552) 222.325,270.552 222.325,270.439 ccw(c222.41,270.439) 222.41,270.354 222.544,270.354 cw(c222.544,270.269) 222.629,270.269 222.629,269.959 222.629,269.594 222.641,269.582 ccw(c223.359,269.71) 223.231,268.992 223.242,268.981 232.486,268.981 cw(c232.486,268.524) 232.943,268.524 232.943,268.483 232.943,268.16 cw(c232.858,268.16) 232.858,268.075 232.856,268.075 ccw(c232.856,267.99) 232.771,267.99 232.771,267.876 ccw(c232.856,267.876) 232.856,267.791 232.858,267.791 cw(c232.858,267.706) 232.943,267.706 232.943,267.568 232.943,267.108 232.859,267.023 v3(232.859,266.95)
  L3 (Sign) w0.081: v7(204.558,295.313) 205.12,295.313 cw(c205.12,295.214) v12(205.22,295.214)
  L16 w0.101: J1_PCIE1.12@232.69,263.794 232.883,263.987 232.883,266.926 v3(232.859,266.95)
SYNC_PCIE1_P: J1_PCIE1.14 U1.AK9 | length 74.3
  L1 w0.1: U1.AK9@191.397,296.539 191.411,296.525 cw(c191.255,296.37) 191.475,296.37 191.475,296.345 ccw(c191.636,296.345) 191.522,296.232 ccw(c191.636,296.345) 191.636,296.184 192.207,296.184 ccw(c192.207,296.374) 192.341,296.24 192.397,296.295
  L1 w0.101: 192.397,296.295 ccw(c192.397,296.977) 192.879,296.495 192.923,296.539 cw(c193.435,296.028) 193.435,296.751 202.148,296.751 cw(c202.148,295.251) 203.209,296.312 203.384,296.137 ccw(c204.404,297.157) 204.404,295.714 v7(204.558,295.714)
  L5 (Sign) w0.081: v12(205.22,295.814) ccw(c205.379,295.814) 205.379,295.654 222.546,295.654 cw(c222.546,295.29) 222.91,295.29 222.91,269.71 ccw(c223.359,269.71) 223.359,269.262 232.486,269.262 cw(c232.486,268.524) 233.224,268.524 233.224,267.137 233.249,267.112 233.249,267.083 233.382,266.95 v3(233.459,266.95)
  L3 (Sign) w0.081: v7(204.558,295.714) 205.12,295.714 ccw(c205.12,295.814) v12(205.22,295.814)
  L16 w0.101: v3(233.459,266.95) 233.308,266.95 233.284,266.926 233.284,264 J1_PCIE1.14@233.49,263.794
SYNC_PCIE2_N: J1_PCIE2.12 U1.AF7 | length 144.9
  L1 w0.1: v2(186.909,295.027) U1.AF7@187.397,294.539
  L12 (Sign) w0.081: v3(193.356,295.722) 193.356,295.713 193.373,295.697 193.458,295.611 cw(c193.56,295.509) 193.56,295.654 ccw(c193.56,295.798) 193.662,295.696 194.535,296.568 cw(c194.924,296.179) 194.924,296.729 203.085,296.729 204.157,296.729 211.368,296.729 ccw(c211.368,297.941) 212.579,297.941 212.579,371.4 cw(c213.918,371.4) 213.918,372.738 228.214,372.738 ccw(c228.214,373.333) 228.809,373.333 228.809,373.413 cw(c229.476,373.413) 229.476,374.081 246.163,374.081 cw(c246.163,373.413) 246.831,373.413 246.831,369.551 ccw(c246.99,369.551) v17(246.99,369.392)
  L3 (Sign) w0.081: v2(186.909,295.027) 187.072,295.027 ccw(c187.072,295.212) 187.256,295.212 cw(c187.671,295.212) 187.671,295.626 188.596,295.626 cw(c188.596,294.894) 189.113,295.411 189.115,295.41 ccw(c189.594,295.89) 189.594,295.212 192.845,295.212 ccw(c192.845,296.016) 193.414,295.447 193.414,295.516 cw(c193.535,295.516) v3@193.449,295.602 ; v3@193.356,295.695 v3@193.449,295.602 ; v3@193.356,295.695 v3(193.356,295.722) v3@193.356,295.695 ; v3@193.356,295.695 193.373,295.679 v3@193.449,295.602
  L14 (Sign) w0.081: v14(246.99,368.808) v17(246.99,369.392)
  L16 w0.101: v14(246.99,368.808) ccw(c246.99,368.709) 246.891,368.709 246.891,367.191 ccw(c247.09,367.191) J1_PCIE2.12@247.09,366.992
SYNC_PCIE2_P: J1_PCIE2.14 U1.AF8 | length 145.7
  L1 w0.1: U1.AF8@187.397,295.539 v2(187.884,295.052)
  L12 (Sign) w0.081: v3(193.826,295.307) 193.791,295.307 193.777,295.293 ccw(c193.675,295.395) 193.819,295.395 cw(c193.963,295.395) v3@193.861,295.497 ; v3@193.861,295.497 194.651,296.287 cw(c195.04,295.898) 195.04,296.448 196.937,296.448 197.313,296.448 cw(c197.313,296.364) 197.397,296.364 197.397,296.3 ccw(c197.48,296.3) 197.48,296.216 197.648,296.216 ccw(c197.648,296.3) 197.732,296.3 197.732,296.364 cw(c197.816,296.364) 197.816,296.448 198.076,296.448 204.939,296.448 206.987,296.448 209.634,296.448 210.009,296.448 cw(c210.009,296.364) 210.093,296.364 210.093,296.245 ccw(c210.177,296.245) 210.177,296.161 210.345,296.161 ccw(c210.345,296.245) 210.428,296.245 210.428,296.364 cw(c210.512,296.364) 210.512,296.448 210.87,296.448 211.368,296.448 ccw(c211.368,297.941) 212.86,297.941 212.86,365.933 212.86,368.169 212.86,369.678 212.86,370.053 cw(c212.944,370.053) 212.944,370.137 213.064,370.137 ccw(c213.064,370.221) 213.147,370.221 213.147,370.389 ccw(c213.064,370.389) 213.064,370.472 212.944,370.472 cw(c212.944,370.556) 212.86,370.556 212.86,370.74 212.86,371.4 cw(c213.918,371.4) 213.918,372.457 228.214,372.457 ccw(c228.214,373.333) 229.09,373.333 229.09,373.413 cw(c229.476,373.413) 229.476,373.8 229.804,373.8 230.18,373.8 cw(c230.18,373.716) 230.264,373.716 ccw(c230.348,373.716) 230.348,373.632 230.515,373.632 ccw(c230.515,373.716) 230.599,373.716 cw(c230.683,373.716) 230.683,373.8 230.81,373.8 244.347,373.8 244.723,373.8 cw(c244.723,373.716) 244.807,373.716 ccw(c244.891,373.715) 244.891,373.631 245.058,373.631 ccw(c245.058,373.715) 245.142,373.715 cw(c245.226,373.716) 245.226,373.8 245.49,373.8 246.163,373.8 cw(c246.163,373.413) 246.55,373.413 246.55,371.534 246.55,371.159 cw(c246.466,371.159) 246.466,371.075 246.346,371.075 ccw(c246.346,370.991) 246.262,370.991 246.262,370.824 ccw(c246.346,370.824) 246.346,370.74 246.466,370.74 cw(c246.466,370.656) 246.55,370.656 246.55,370.338 246.55,369.551 cw(c246.39,369.551) v17(246.39,369.392)
  L3 (Sign) w0.081: v2(187.884,295.052) 187.697,295.052 cw(c187.697,295.212) 187.537,295.212 cw(c187.671,295.212) 187.671,295.345 188.594,295.345 cw(c188.594,294.89) 188.916,295.211 ccw(c189.594,295.888) 189.594,294.93 192.847,294.93 ccw(c192.847,296.01) 193.611,295.247 193.612,295.248 193.681,295.248 ccw(c193.681,295.37) 193.767,295.284 193.791,295.307 v3(193.826,295.307)
  L14 (Sign) w0.081: v14(246.39,368.808) v17(246.39,369.392)
  L16 w0.101: J1_PCIE2.14@246.29,366.992 ccw(c246.29,367.192) 246.49,367.192 246.49,368.709 ccw(c246.39,368.709) v14(246.39,368.808)
SYNC_PCIE3_N: J1_PCIE3.12 U1.AK6 | length 226.5
  L1 w0.1: v2(190.909,294.027) U1.AK6@191.397,293.539
  L3 (Sign) w0.081: v2(190.909,294.027) 190.996,294.027 cw(c190.996,293.766) 191.256,293.766 191.256,293.559 ccw(c191.8,293.559) 191.8,293.015 197.057,293.015 cw(c197.057,292.93) 197.142,292.93 197.278,292.794 197.292,292.78 v3(197.343,292.78)
  L14 (Sign) w0.081: v10(82.285,365.315) ccw(c82.285,365.156) 82.126,365.156 82.126,364.739 ccw(c82.96,364.739) 82.96,363.905 84.254,363.905 cw(c84.254,362.818) 85.34,362.818 85.34,357.662 ccw(c85.787,357.662) 85.787,357.216 145.746,357.216 cw(c145.746,356.496) 146.466,356.496 146.466,352.668 ccw(c147.051,352.668) 147.051,352.083 211.926,352.083 cw(c211.926,350.825) 213.184,350.825 213.184,295.291 cw(c210.908,295.291) 210.908,293.015 197.226,293.015 ccw(c197.226,292.93) 197.142,292.93 197.292,292.78 v3(197.343,292.78)
  L16 w0.101: v10(82.285,365.315) cw(c82.285,365.415) 82.186,365.415 82.186,366.792 cw(c82.385,366.792) J1_PCIE3.12@82.385,366.992
SYNC_PCIE3_P: J1_PCIE3.14 U1.AK7 | length 226.7
  L1 w0.1: U1.AK7@191.397,294.539 v2(191.884,294.052)
  L3 (Sign) w0.081: v2(191.884,294.052) 191.823,294.052 ccw(c191.823,293.766) 191.537,293.766 191.537,293.559 ccw(c191.8,293.559) 191.8,293.296 197.057,293.296 ccw(c197.057,293.38) 197.142,293.38 197.143,293.379 197.169,293.405 v3(197.293,293.405)
  L14 (Sign) w0.081: v10(81.685,365.315) cw(c81.685,365.156) 81.845,365.156 81.845,364.739 ccw(c82.96,364.739) 82.96,363.624 84.254,363.624 cw(c84.254,362.818) 85.059,362.818 85.059,360.777 85.059,360.298 cw(c84.976,360.298) 84.976,360.215 84.856,360.215 ccw(c84.856,360.131) 84.772,360.131 84.772,359.963 ccw(c84.856,359.963) 84.856,359.879 84.976,359.879 cw(c84.976,359.796) 85.059,359.796 85.059,359.755 85.059,357.662 ccw(c85.787,357.662) 85.787,356.935 145.746,356.935 cw(c145.746,356.496) 146.185,356.496 146.185,355.738 146.185,355.383 cw(c146.102,355.383) 146.102,355.299 145.982,355.299 ccw(c145.982,355.215) 145.898,355.215 145.898,355.048 ccw(c145.982,355.048) 145.982,354.964 146.102,354.964 cw(c146.102,354.88) 146.185,354.88 146.185,354.839 146.185,352.668 ccw(c147.051,352.668) 147.051,351.802 211.926,351.802 cw(c211.926,350.825) 212.903,350.825 212.903,295.291 cw(c210.908,295.291) 210.908,293.296 204.027,293.296 203.634,293.296 cw(c203.634,293.379) 203.55,293.379 203.55,293.499 ccw(c203.467,293.499) 203.467,293.583 203.299,293.583 ccw(c203.299,293.499) 203.215,293.499 203.215,293.379 cw(c203.131,293.379) 203.131,293.296 203.091,293.296 197.226,293.296 cw(c197.226,293.38) 197.142,293.38 197.143,293.379 197.169,293.405 v3(197.293,293.405)
  L16 w0.101: J1_PCIE3.14@81.585,366.992 cw(c81.585,366.792) 81.785,366.792 81.785,365.415 cw(c81.685,365.415) v10(81.685,365.315)
SYNC_PCIE4_N: J1_PCIE4.12 U1.AK4 | length 82.5
  L1 w0.1: U1.AK4@191.397,291.539 v2(191.884,291.052)
  L5 (Sign) w0.081: v3(154.49,267.148) ccw(c154.65,267.148) 154.65,266.989 155.861,266.989 184.909,266.989 ccw(c184.909,267.478) 185.399,267.478 185.399,278.201 cw(c186.229,278.201) 186.229,279.031 198.167,279.031 ccw(c198.167,279.518) 198.653,279.518 198.653,289.178 ccw(c198.494,289.178) v12(198.494,289.337)
  L3 (Sign) w0.081: v2(191.884,291.052) 191.661,291.052 cw(c191.661,291.188) 191.525,291.188 191.525,291.201 cw(c191.731,291.201) 191.731,291.407 193.547,291.407 cw(c193.547,290.981) 193.973,290.981 193.973,290.912 ccw(c195.022,290.912) 195.022,289.863 198.187,289.863 cw(c198.187,289.397) 198.653,289.397 cw(c198.594,289.397) 198.594,289.337 v12(198.494,289.337)
  L16 w0.101: J1_PCIE4.12@150.337,263.794 ccw(c150.337,263.994) 150.537,263.994 150.537,265.773 cw(c151.812,265.773) 151.812,267.049 154.391,267.049 ccw(c154.391,267.148) v3(154.49,267.148)
SYNC_PCIE4_P: J1_PCIE4.14 U1.AJ4 | length 83.3
  L1 w0.1: U1.AJ4@190.397,291.539 v2(190.884,291.052)
  L5 (Sign) w0.081: v3(154.49,266.548) cw(c154.65,266.548) 154.65,266.708 155.861,266.708 184.909,266.708 ccw(c184.909,267.478) 185.68,267.478 185.68,278.201 cw(c186.229,278.201) 186.229,278.75 198.283,278.75 ccw(c198.283,279.402) 198.934,279.402 198.934,289.178 cw(c199.094,289.178) v12(199.094,289.337)
  L3 (Sign) w0.081: v2(190.884,291.052) 191.108,291.052 ccw(c191.108,291.188) 191.244,291.188 191.244,291.201 cw(c191.731,291.201) 191.731,291.688 193.547,291.688 cw(c193.547,290.981) 194.254,290.981 194.254,290.912 ccw(c195.022,290.912) 195.022,290.144 198.187,290.144 cw(c198.187,289.397) 198.934,289.397 ccw(c198.994,289.397) 198.994,289.337 v12(199.094,289.337)
  L16 w0.101: J1_PCIE4.14@151.137,263.794 cw(c151.137,263.994) 150.938,263.994 150.938,265.773 cw(c151.812,265.773) 151.812,266.648 154.391,266.648 cw(c154.391,266.548) v3(154.49,266.548)
SYNC_WR_R: R904.1 U1.C12 | length 60.5
  L1 w0.12: v1(158.355,289.618) 158.335,289.638 158.335,290.644 158.735,291.044 158.735,291.241 159.165,291.672 159.165,296.249 160.045,297.129 160.045,299.257 161.817,301.028 162.635,301.028 162.902,300.761 162.902,300.254 163.129,300.027 163.909,300.027 U1.C12@164.397,299.539
  L1 w0.2: R904.1@127.889,274.3 127.889,279.425 v1(128.2,279.737)
  L12 (Sign) w0.12: v1(128.2,279.737) 128.817,279.121 138.231,279.121 138.552,279.441 154.702,279.441 157.56,282.299 157.56,288.546 158.355,289.34 v1(158.355,289.618)
TD_A_N: D1.2 D1.7 T21.10 U39.2 | length 87
  L1 w0.101: v1(61.087,249.283) 62.193,249.283 ccw(c62.193,249.618) D1.7@62.528,249.618 ccw(c62.963,249.618) 62.963,249.184 67.593,249.184 ccw(c67.593,249.618) D1.2@68.028,249.618 ccw(c68.462,249.618) 68.462,249.184 69.401,249.184 ccw(c69.401,249.283) v1(69.5,249.283)
  L14 (Sign) w0.081: T21.10@50.092,244.096 ccw(c50.967,244.096) 50.967,243.222 51.054,243.222 ccw(c51.054,243.656) 51.489,243.656 51.489,243.665 cw(c52.201,243.665) 52.201,244.377 56.613,244.377 ccw(c56.613,245.08) 57.315,245.08 57.315,248.016 cw(c58.424,248.016) 58.424,249.124 61.087,249.124 v1(61.087,249.283) v1@60.977,249.173 ; v1(69.5,249.283) ccw(c69.66,249.283) 69.66,249.124 72.641,249.124 ccw(c72.641,249.884) 73.402,249.884 73.402,251.2 cw(c74.511,251.2) 74.511,252.31 76.713,252.31 ccw(c76.713,253.082) 77.485,253.082 77.485,275.247 cw(c78.404,275.247) 78.404,276.166 103.612,276.166 ccw(c103.612,276.325) v10(103.772,276.325)
  L16 w0.101: v10(103.772,276.325) ccw(c103.822,276.325) 103.822,276.275 U39.2@104.899,276.275
TD_A_P: D1.1 D1.8 T21.11 U39.1 | length 87
  L1 w0.101: v1(61.087,248.684) 62.193,248.684 cw(c62.193,248.349) D1.8@62.528,248.349 cw(c62.963,248.349) 62.963,248.783 67.593,248.783 cw(c67.593,248.349) D1.1@68.028,248.349 cw(c68.462,248.349) 68.462,248.783 69.401,248.783 cw(c69.401,248.684) v1(69.5,248.684)
  L14 (Sign) w0.081: T21.11@50.092,242.066 cw(c50.967,242.066) 50.967,242.941 51.054,242.941 ccw(c51.054,243.656) 51.77,243.656 51.77,243.665 cw(c52.201,243.665) 52.201,244.096 56.613,244.096 ccw(c56.613,245.08) 57.596,245.08 57.596,248.016 cw(c58.424,248.016) 58.424,248.843 61.087,248.843 v1(61.087,248.684) v1@60.977,248.794 ; v1(69.5,248.684) cw(c69.66,248.684) 69.66,248.843 72.641,248.843 ccw(c72.641,249.884) 73.683,249.884 73.683,251.2 cw(c74.511,251.2) 74.511,252.029 76.713,252.029 ccw(c76.713,253.082) 77.766,253.082 77.766,275.247 cw(c78.404,275.247) 78.404,275.885 103.612,275.885 cw(c103.612,275.725) v10(103.772,275.725)
  L16 w0.101: v10(103.772,275.725) cw(c103.822,275.725) 103.822,275.775 U39.1@104.899,275.775
TD_B_N: D1.4 D1.5 T21.5 U39.5 | length 96.1
  L1 w0.101: v1(61.087,251.823) 62.193,251.823 ccw(c62.193,252.159) D1.5@62.528,252.159 ccw(c62.963,252.159) 62.963,251.724 67.593,251.724 ccw(c67.593,252.159) D1.4@68.028,252.159 ccw(c68.363,252.159) 68.363,251.823 v1(69.5,251.823)
  L14 (Sign) w0.081: T21.5@47.552,243.081 47.552,243.113 cw(c48.395,243.113) 48.395,243.956 ccw(c48.395,244.481) 48.92,244.481 48.92,244.875 cw(c49.468,244.875) 49.468,245.423 51.489,245.423 51.813,245.423 cw(c51.813,245.338) 51.897,245.338 51.897,245.203 ccw(c51.982,245.203) 51.982,245.118 52.096,245.118 ccw(c52.096,245.203) 52.181,245.203 52.181,245.338 cw(c52.266,245.338) 52.266,245.423 52.54,245.423 52.824,245.423 53.147,245.423 cw(c53.147,245.338) 53.232,245.338 53.232,245.203 ccw(c53.317,245.203) 53.317,245.118 53.43,245.118 ccw(c53.43,245.203) 53.515,245.203 53.515,245.338 cw(c53.6,245.338) 53.6,245.423 53.895,245.423 54.545,245.423 ccw(c54.545,246.493) 55.615,246.493 55.615,250.37 55.615,250.694 cw(c55.7,250.694) 55.7,250.779 55.835,250.779 ccw(c55.835,250.864) 55.92,250.864 55.92,250.977 ccw(c55.835,250.977) 55.835,251.062 55.7,251.062 cw(c55.7,251.147) 55.615,251.147 55.615,251.383 55.615,251.757 cw(c56.441,251.757) 56.441,252.584 57.241,252.584 58.424,252.584 58.744,252.584 59.067,252.584 cw(c59.067,252.499) 59.152,252.499 59.152,252.382 ccw(c59.237,252.382) 59.237,252.297 59.351,252.297 ccw(c59.351,252.382) 59.436,252.382 59.436,252.499 cw(c59.521,252.499) 59.521,252.584 59.634,252.584 cw(c59.634,252.499) 59.719,252.499 ccw(c59.804,252.499) 59.804,252.414 59.917,252.414 ccw(c59.917,252.499) 60.002,252.499 cw(c60.087,252.499) 60.087,252.584 60.896,252.584 62.002,252.584 cw(c62.002,252.19) 62.395,252.19 62.395,252.029 cw(c62.03,252.029) 62.03,251.664 61.246,251.664 cw(c61.246,251.823) v1(61.087,251.823) cw(c60.977,251.823) v1@60.977,251.713 ; v1(69.5,251.823) ccw(c69.66,251.823) 69.66,251.664 71.792,251.664 ccw(c71.792,252.243) 72.371,252.243 72.371,252.741 cw(c73.402,252.741) 73.402,253.771 75.129,253.771 ccw(c75.129,255.12) 76.478,255.12 76.478,276.722 cw(c77.422,276.722) 77.422,277.666 103.612,277.666 ccw(c103.612,277.825) v10(103.772,277.825)
  L16 w0.101: v10(103.772,277.825) ccw(c103.822,277.825) 103.822,277.775 U39.5@104.899,277.775
TD_B_P: D1.3 D1.6 T21.4 U39.4 | length 96.1
  L1 w0.101: v1(61.087,251.224) 62.193,251.224 cw(c62.193,250.888) D1.6@62.528,250.888 cw(c62.963,250.888) 62.963,251.323 67.593,251.323 cw(c67.593,250.888) D1.3@68.028,250.888 cw(c68.363,250.888) 68.363,251.224 v1(69.5,251.224)
  L14 (Sign) w0.081: T21.4@47.552,245.111 47.552,245.08 ccw(c48.395,245.08) 48.395,244.237 ccw(c48.395,244.481) 48.639,244.481 48.639,244.875 cw(c49.468,244.875) 49.468,245.704 54.545,245.704 ccw(c54.545,246.493) 55.334,246.493 55.334,251.757 cw(c56.441,251.757) 56.441,252.865 62.002,252.865 cw(c62.002,252.19) 62.676,252.19 62.676,252.029 cw(c62.03,252.029) 62.03,251.383 61.246,251.383 ccw(c61.246,251.224) v1(61.087,251.224) ccw(c60.977,251.224) v1@60.977,251.334 ; v1(69.5,251.224) cw(c69.66,251.224) 69.66,251.383 70.329,251.383 70.652,251.383 cw(c70.652,251.298) 70.737,251.298 70.737,251.112 ccw(c70.822,251.112) 70.822,251.027 70.936,251.027 ccw(c70.936,251.112) 71.021,251.112 71.021,251.298 cw(c71.105,251.298) 71.105,251.383 71.535,251.383 71.792,251.383 ccw(c71.792,252.243) 72.652,252.243 72.652,252.741 cw(c73.402,252.741) 73.402,253.49 75.129,253.49 ccw(c75.129,255.12) 76.759,255.12 76.759,276.722 cw(c77.422,276.722) 77.422,277.385 77.766,277.385 78.09,277.385 cw(c78.09,277.3) 78.175,277.3 78.175,277.114 ccw(c78.26,277.114) 78.26,277.029 78.373,277.029 ccw(c78.373,277.114) 78.458,277.114 78.458,277.3 cw(c78.543,277.3) 78.543,277.385 78.781,277.385 103.612,277.385 cw(c103.612,277.225) v10(103.772,277.225)
  L16 w0.101: v10(103.772,277.225) cw(c103.822,277.225) 103.822,277.275 U39.4@104.899,277.275
TD_C_N: D2.2 D2.7 T21.2 U39.8 | length 91.4
  L1 w0.101: v1(61.087,255.354) ccw(c61.186,255.354) 61.186,255.254 62.08,255.254 ccw(c62.08,255.702) D2.7@62.528,255.702 ccw(c62.963,255.702) 62.963,255.267 67.593,255.267 ccw(c67.593,255.702) D2.2@68.028,255.702 ccw(c68.462,255.702) 68.462,255.267 69.401,255.267 ccw(c69.401,255.367) v1(69.5,255.367)
  L14 (Sign) w0.081: T21.2@47.552,249.171 47.552,248.886 ccw(c48.141,248.886) 48.141,248.297 48.219,248.297 cw(c48.219,247.596) 48.92,247.596 48.92,247.08 ccw(c49.226,247.08) 49.226,246.774 52.837,246.774 ccw(c52.837,247.948) 54.011,247.948 54.011,253.873 cw(c55.331,253.873) 55.331,255.194 60.928,255.194 ccw(c60.928,255.354) v1(61.087,255.354) cw(c60.977,255.354) v1@60.977,255.243 ; v1(69.5,255.367) ccw(c69.66,255.367) 69.66,255.207 73.644,255.207 73.684,255.207 ccw(c73.684,255.292) 73.769,255.292 73.769,255.334 cw(c73.854,255.334) 73.854,255.419 73.968,255.419 cw(c73.968,255.334) 74.053,255.334 74.053,255.292 ccw(c74.138,255.292) 74.138,255.207 74.526,255.207 ccw(c74.526,255.905) 75.224,255.905 75.224,277.961 cw(c76.428,277.961) 76.428,279.166 103.625,279.166 ccw(c103.625,279.325) v10(103.784,279.325)
  L16 w0.101: v10(103.784,279.325) ccw(c103.834,279.325) 103.834,279.275 U39.8@104.899,279.275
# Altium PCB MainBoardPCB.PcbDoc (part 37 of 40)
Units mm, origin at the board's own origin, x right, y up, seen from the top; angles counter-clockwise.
Board outline 258.95 x 308.86 mm, 16 copper layers (L1, L2 (GND), L3 (Sign), L4 (GND), L5 (Sign), L6 (PWR/GND), L7(12V+Other), L8 (Plane_GND), L9 (PWR/GND), L10 (3V3+Other), L11 (PWR/GND), L12 (Sign), L13 (GND), L14 (Sign), L15 (GND), L16), stack 2.503 mm thick; 2578 components, 1867 nets, 8817 pads, 8021 vias.
Unrouted connection lines stored in the file: 25.

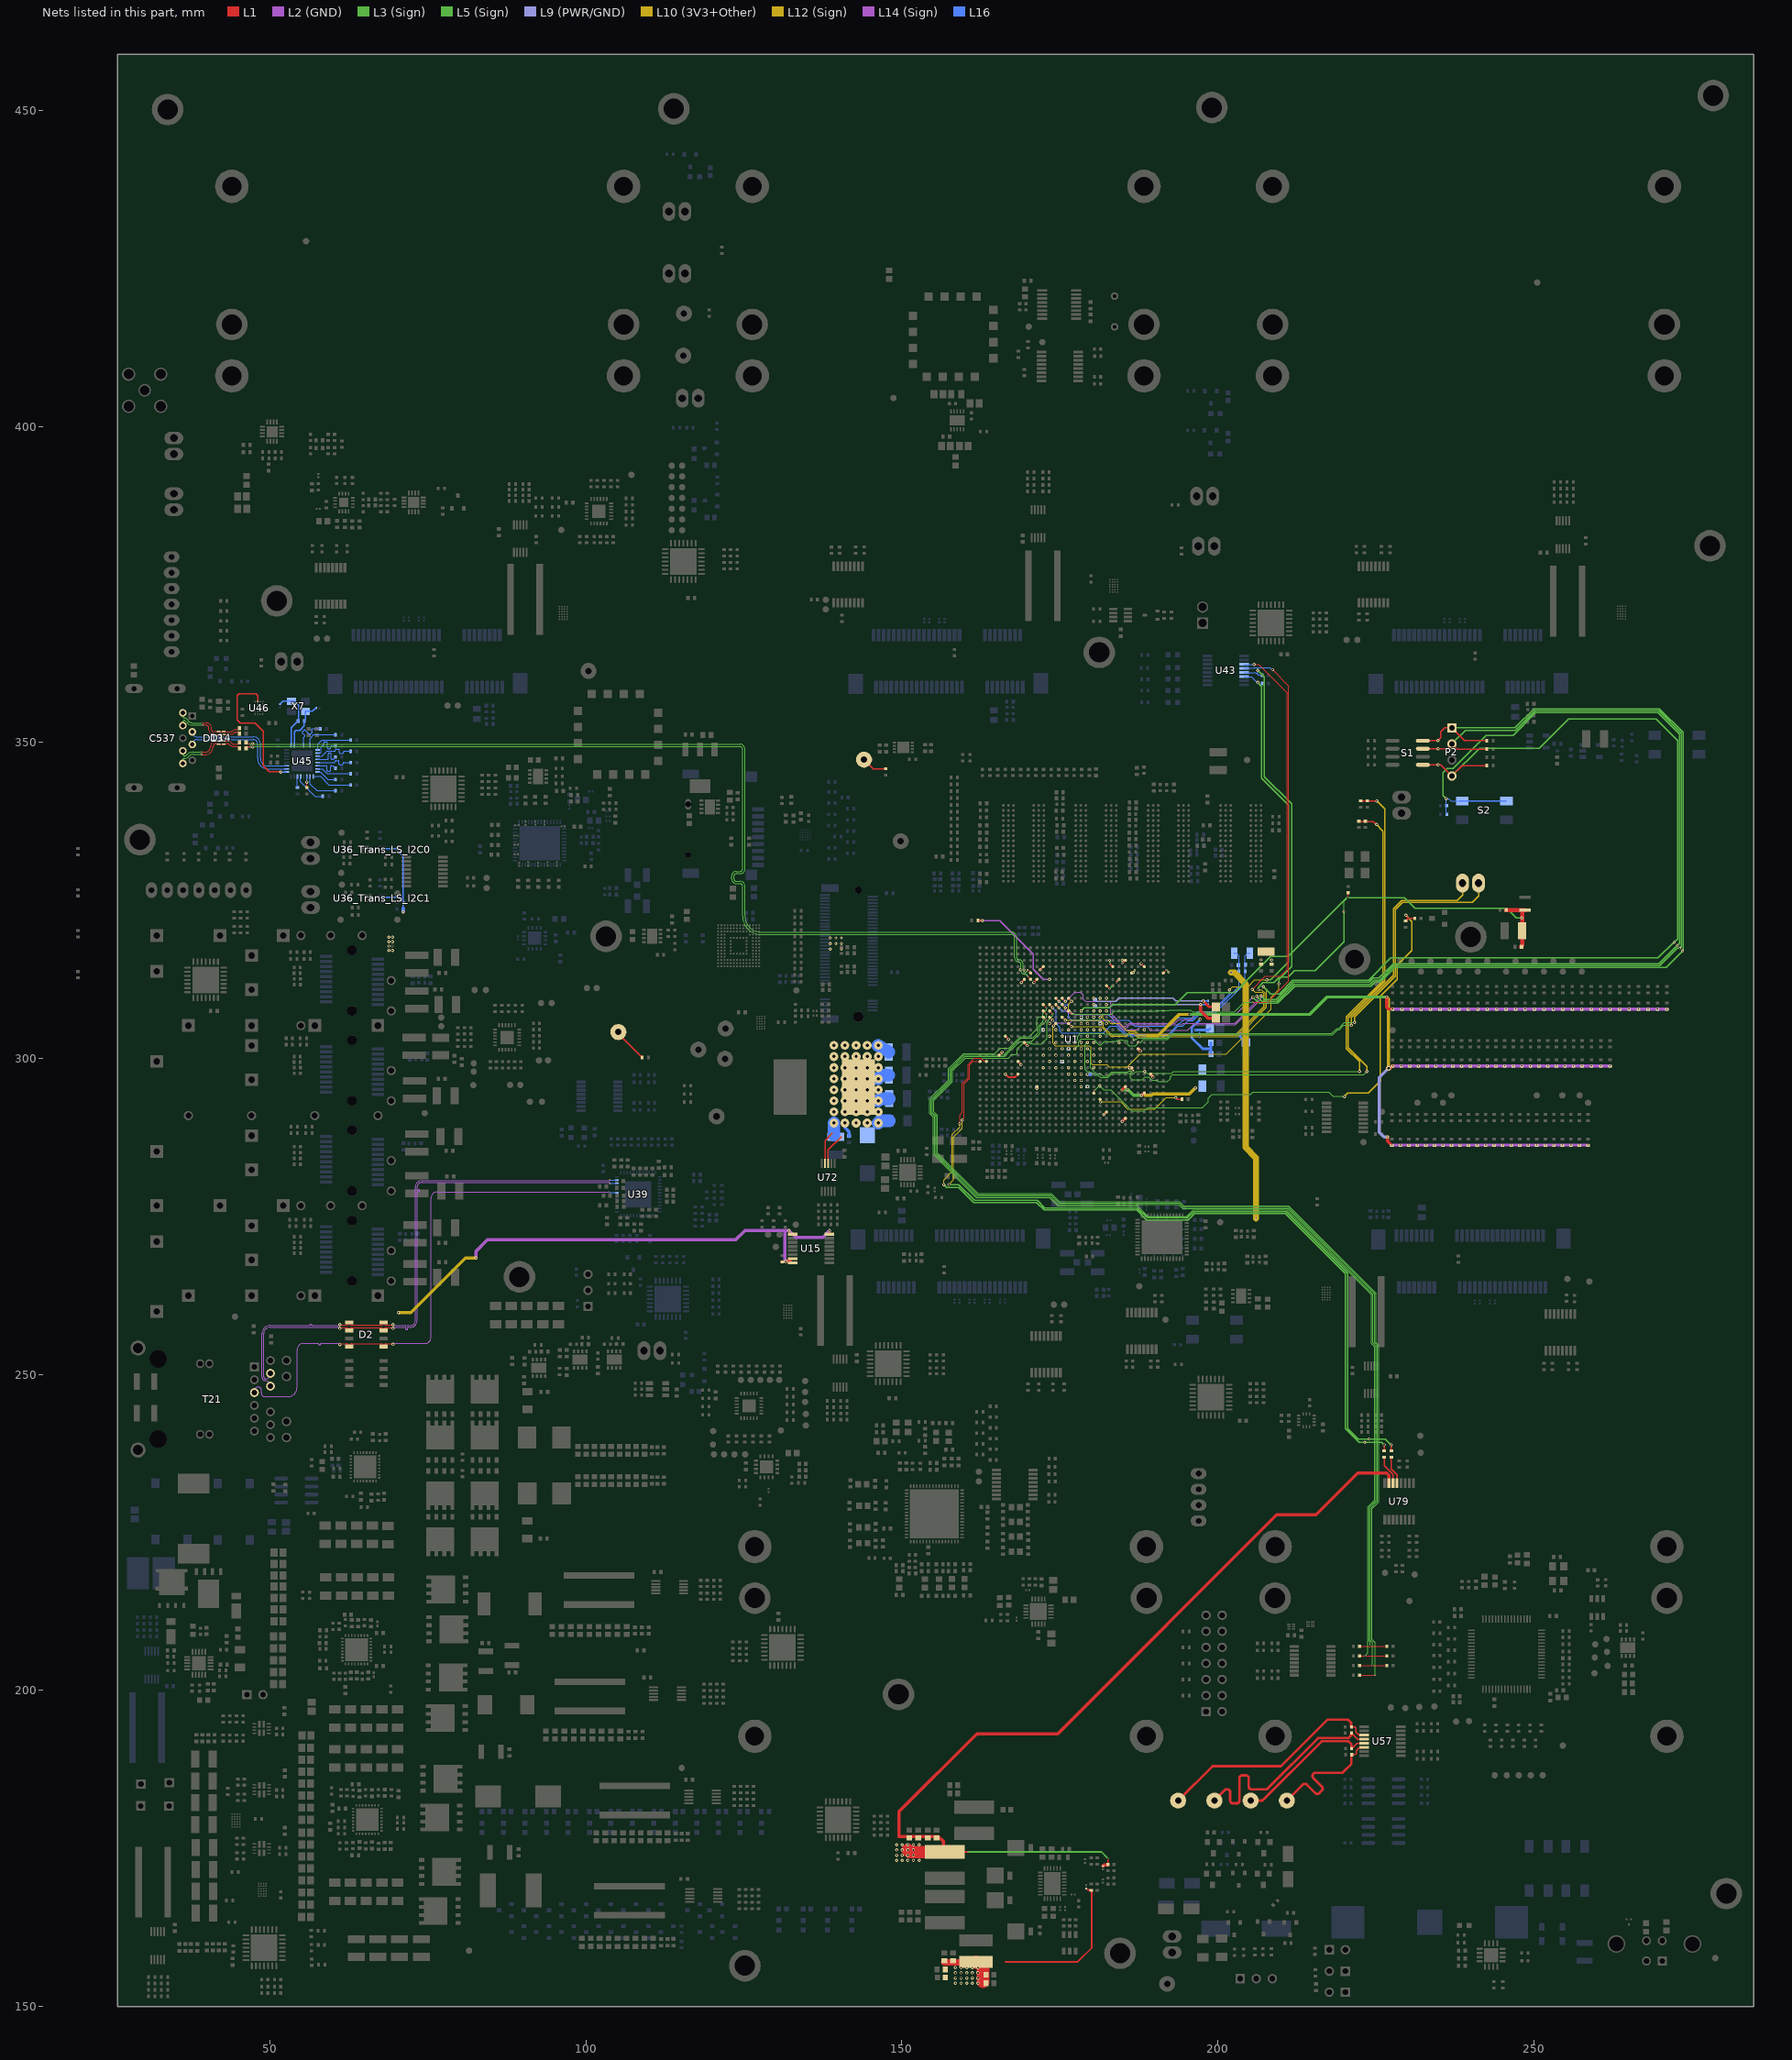
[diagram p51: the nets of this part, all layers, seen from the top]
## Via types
v1: diameter 0.5, hole 0.25, L1 to L16, tented both sides, 4341 vias
v2: diameter 0.254, hole 0.1, L1 to L3 (Sign), tented both sides, 781 vias
v3: diameter 0.5, hole 0.25, L1 to L16, 565 vias
v4: diameter 0.254, hole 0.1, L15 (GND) to L16, tented both sides, 406 vias
v5: diameter 0.254, hole 0.1, L1 to L2 (GND), tented both sides, 283 vias
v6: diameter 0.457, hole 0.2, L3 (Sign) to L6 (PWR/GND), tented both sides, 254 vias
v7: diameter 0.254, hole 0.1, L1 to L3 (Sign), 237 vias
v8: diameter 0.75, hole 0.4, L1 to L16, 200 vias
v9: diameter 0.8, hole 0.4, L1 to L16, tented both sides, 182 vias
v10: diameter 0.254, hole 0.1, L14 (Sign) to L16, tented both sides, 170 vias
v11: diameter 0.75/0/0/0/0/0/0/0/0/0/0/0/0/0/0/0.75 (per signal layer), hole 0.4, L1 to L16, 160 vias
v12: diameter 0.457, hole 0.2, L3 (Sign) to L6 (PWR/GND), 158 vias
v13: diameter 1.4, hole 0.5, L1 to L16, tented both sides, 80 vias
v14: diameter 0.254, hole 0.1, L14 (Sign) to L16, 65 vias
v15: diameter 0.254, hole 0.1, L1 to L2 (GND), 45 vias
v16: diameter 0.457, hole 0.2, L11 (PWR/GND) to L14 (Sign), tented both sides, 26 vias
v17: diameter 0.457, hole 0.2, L11 (PWR/GND) to L14 (Sign), 25 vias
v18: diameter 0.457, hole 0.2, L7(12V+Other) to L10 (3V3+Other), tented both sides, 11 vias
v19: diameter 0.254/0/0.254 (per signal layer), hole 0.1, L1 to L3 (Sign), 9 vias
v20: diameter 0.2/0/0.2 (per signal layer), hole 0.1, L1 to L3 (Sign), 6 vias
v21: diameter 1.65, hole 1.65, L1 to L16, 5 vias
v22: diameter 1.15, hole 1.15, L1 to L16, 5 vias
v23: diameter 0.457, hole 0.2, L1 to L16, 3 vias
v24: diameter 0.5, hole 0.3, L1 to L16, 2 vias
v25: diameter 0.5/0/0.5 (per signal layer), hole 0.2, L14 (Sign) to L16, 1 vias
v26: diameter 0.5, hole 0.25, L1 to L16, tented bottom, 1 vias

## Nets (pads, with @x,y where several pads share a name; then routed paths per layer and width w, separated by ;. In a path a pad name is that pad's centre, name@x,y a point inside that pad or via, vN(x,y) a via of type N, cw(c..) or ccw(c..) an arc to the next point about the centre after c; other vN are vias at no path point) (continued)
TD_C_P: D2.1 D2.8 T21.3 U39.7 | length 91.4
  L1 w0.101: v1(61.087,254.754) cw(c61.186,254.754) 61.186,254.853 62.107,254.853 cw(c62.107,254.432) D2.8@62.528,254.432 cw(c62.963,254.432) 62.963,254.866 67.593,254.866 cw(c67.593,254.432) D2.1@68.028,254.432 cw(c68.462,254.432) 68.462,254.866 69.401,254.866 cw(c69.401,254.767) v1(69.5,254.767)
  L14 (Sign) w0.081: T21.3@47.552,247.141 47.552,247.426 cw(c48.141,247.426) 48.141,248.016 48.219,248.016 cw(c48.219,247.596) 48.639,247.596 48.639,247.08 ccw(c49.226,247.08) 49.226,246.493 52.837,246.493 ccw(c52.837,247.948) 54.292,247.948 54.292,253.873 cw(c55.331,253.873) 55.331,254.913 57.315,254.913 57.639,254.913 cw(c57.639,254.828) 57.724,254.828 57.724,254.779 ccw(c57.809,254.779) 57.809,254.694 57.922,254.694 ccw(c57.922,254.779) 58.007,254.779 58.007,254.828 cw(c58.092,254.828) 58.092,254.913 58.466,254.913 60.928,254.913 cw(c60.928,254.754) v1(61.087,254.754) ccw(c60.977,254.754) v1@60.977,254.864 ; v1(69.5,254.767) cw(c69.66,254.767) 69.66,254.926 74.526,254.926 ccw(c74.526,255.905) 75.505,255.905 75.505,277.961 cw(c76.428,277.961) 76.428,278.885 103.625,278.885 cw(c103.625,278.725) v10(103.784,278.725)
  L16 w0.101: v10(103.784,278.725) cw(c103.834,278.725) 103.834,278.775 U39.7@104.899,278.775
TD_D_N: D2.4 D2.5 T21.9 U39.11 | length 89.9
  L1 w0.101: v1(61.056,257.907) ccw(c61.155,257.907) 61.155,257.807 62.094,257.807 ccw(c62.094,258.242) D2.5@62.528,258.242 ccw(c62.963,258.242) 62.963,257.807 67.593,257.807 ccw(c67.593,258.242) D2.4@68.028,258.242 ccw(c68.462,258.242) 68.462,257.807 69.401,257.807 ccw(c69.401,257.907) v1(69.5,257.907)
  L14 (Sign) w0.081: T21.9@50.092,248.156 50.092,248.252 ccw(c49.314,248.252) 49.314,249.031 cw(c49.314,249.61) 48.734,249.61 48.734,256.457 cw(c50.024,256.457) 50.024,257.747 56.205,257.747 56.245,257.747 ccw(c56.245,257.832) 56.33,257.832 56.33,257.859 cw(c56.415,257.859) 56.415,257.944 56.529,257.944 cw(c56.529,257.859) 56.614,257.859 56.614,257.832 ccw(c56.699,257.832) 56.699,257.747 57.241,257.747 60.896,257.747 ccw(c60.896,257.907) v1(61.056,257.907) v1@60.946,257.797 ; v1(69.5,257.907) ccw(c69.66,257.907) 69.66,257.747 72.235,257.747 ccw(c72.235,258.537) 73.024,258.537 73.024,279.66 cw(c74.03,279.66) 74.03,280.666 103.625,280.666 ccw(c103.625,280.825) v10(103.784,280.825)
  L16 w0.101: v10(103.784,280.825) ccw(c103.834,280.825) 103.834,280.775 U39.11@104.899,280.775
TD_D_P: D2.3 D2.6 T21.8 U39.10 | length 89.9
  L1 w0.101: v1(61.056,257.307) cw(c61.155,257.307) 61.155,257.406 62.094,257.406 cw(c62.094,256.972) D2.6@62.528,256.972 cw(c62.963,256.972) 62.963,257.406 67.593,257.406 cw(c67.593,256.972) D2.3@68.028,256.972 cw(c68.462,256.972) 68.462,257.406 69.401,257.406 cw(c69.401,257.307) v1(69.5,257.307)
  L14 (Sign) w0.081: T21.8@50.092,250.186 50.092,250.09 cw(c49.314,250.09) 49.314,249.312 cw(c49.314,249.61) 49.015,249.61 49.015,256.457 cw(c50.024,256.457) 50.024,257.466 60.896,257.466 cw(c60.896,257.307) v1(61.056,257.307) v1@60.946,257.417 ; v1(69.5,257.307) cw(c69.66,257.307) 69.66,257.466 71.106,257.466 71.43,257.466 cw(c71.43,257.381) 71.515,257.381 71.515,257.196 ccw(c71.6,257.196) 71.6,257.111 71.713,257.111 ccw(c71.713,257.196) 71.798,257.196 71.798,257.381 cw(c71.883,257.381) 71.883,257.466 72.235,257.466 ccw(c72.235,258.537) 73.305,258.537 73.305,278.532 73.305,278.856 cw(c73.39,278.856) 73.39,278.941 73.576,278.941 ccw(c73.576,279.026) 73.661,279.026 73.661,279.139 ccw(c73.576,279.139) 73.576,279.224 73.39,279.224 cw(c73.39,279.309) 73.305,279.309 73.305,279.66 cw(c74.03,279.66) 74.03,280.385 103.625,280.385 cw(c103.625,280.225) v10(103.784,280.225)
  L16 w0.101: v10(103.784,280.225) cw(c103.834,280.225) 103.834,280.275 U39.10@104.899,280.275
TTC_0: R810.1 TP42.1 | length 4
  L1 w0.2: TP42.1@144.03,347.301 145.517,345.814 R810.1@147.447,345.814
TTC_3: R804.1 TP38.1 | length 5.6
  L1 w0.2: TP38.1@105.156,304.196 105.156,303.926 R804.1@108.905,300.177 R804.1@108.955,300.177
uart0_RxD: R779.1 TP32.1 U57.12 | length 36.5
  L1 w0.2: R779.1@221.118,193.302 R779.1@221.168,193.302 222.171,192.298 U57.12@223.198,192.298
  L1 w0.4: TP32.1@199.475,182.585 201.25,184.361 201.544,184.361 cw(c201.544,183.921) 201.984,183.921 201.984,182.585 ccw(c202.424,182.585) 202.424,182.145 203.011,182.145 ccw(c203.011,182.585) 203.451,182.585 203.451,184.361 203.451,186.137 cw(c203.891,186.137) 203.891,186.577 204.478,186.577 cw(c204.478,186.137) 204.918,186.137 204.918,184.801 ccw(c205.358,184.801) 205.358,184.361 207.594,184.361 207.797,184.361 215.909,192.473 220.667,192.473 221.118,192.924 R779.1@221.118,193.302
uart0_TxD: R778.1 TP27.1 U57.11 | length 36.5
  L1 w0.2: R778.1@221.114,194.229 221.738,194.229 221.879,194.087 221.879,193.464 222.395,192.948 U57.11@223.198,192.948
  L1 w0.4: TP27.1@193.738,182.585 199.189,188.036 210.027,188.036 217.367,195.377 220.65,195.377 221.114,194.912 R778.1@221.114,194.229
uart1_RxD: R776.1 TP31.1 U57.13 | length 23.1
  L1 w0.2: R776.1@221.167,190.809 R776.1@221.217,190.809 222.053,191.645 222.171,191.645 222.174,191.648 U57.13@223.198,191.648
  L1 w0.4: TP31.1@205.211,182.585 207.077,182.585 216.465,191.973 220.689,191.973 221.167,191.495 R776.1@221.167,190.809
uart1_TxD: R777.1 TP29.1 U57.14 | length 21.7
  L1 w0.2: R777.1@221.168,189.856 221.807,189.856 221.924,189.973 221.924,190.461 222.336,190.873 223.073,190.873 U57.14@223.198,190.998
  L1 w0.4: TP29.1@210.947,182.585 213.291,184.93 213.477,185.115 cw(c213.788,184.804) 214.099,185.115 215.446,183.767 ccw(c215.758,184.079) 216.069,183.767 216.484,184.182 ccw(c216.172,184.494) 216.484,184.805 215.136,186.152 cw(c215.447,186.463) 215.136,186.775 215.344,186.982 219.745,186.982 221.168,188.406 R777.1@221.168,189.856
uart_FPGA_RxD_R: R909.1 U1.B12 | length 127.1
  L1 w0.12: v1(159.175,289.67) 159.175,291.059 159.605,291.49 159.605,296.067 160.485,296.947 160.485,299.074 161.438,300.027 162.543,300.027 163.031,299.539 U1.B12@163.397,299.539
  L1 w0.2: v1@226.352,238.867 R909.1@226.359,237.884 ; v1(226.352,238.874) v1@226.359,238.867
  L5 (Sign) w0.2: v12(223.282,239.268) 225.958,239.268 v1(226.352,238.874)
  L12 (Sign) w0.12: v1(156.653,280.06) 156.653,280.77 158,282.117 158,288.01 159.175,289.184 v1(159.175,289.67)
  L3 (Sign) w0.2: v1(156.653,280.06) 157.09,279.623 159.022,279.623 161.408,277.237 171.342,277.237 172.533,276.047 187.176,276.047 188.741,274.482 195.345,274.482 196.335,275.471 210.71,275.471 220.199,265.982 220.199,241.454 222.385,239.268 v12(223.282,239.268)
uart_FPGA_TxD_R: R910.1 U1.A12 | length 125.4
  L1 w0.12: v1(159.595,290.267) 159.585,290.277 159.585,290.377 159.825,290.618 159.825,295.976 160.705,296.856 160.705,298.983 161.262,299.539 U1.A12@162.397,299.539
  L1 w0.2: v1(227.475,238.874) 227.475,238.678 227.482,238.671 R910.1@227.482,237.884
  L5 (Sign) w0.2: v6(223.969,239.814) 226.535,239.814 v1(227.475,238.874)
  L12 (Sign) w0.12: v1(157.493,280.073) 158.22,280.8 158.22,287.607 159.585,288.972 159.585,290.257 v1(159.595,290.267)
  L3 (Sign) w0.2: v1(157.493,280.073) 159.017,280.073 161.544,277.546 171.458,277.546 172.657,276.347 187.301,276.347 188.865,274.782 195.221,274.782 196.211,275.771 210.846,275.771 220.598,266.019 220.598,241.479 222.263,239.814 v6(223.969,239.814)
US2_FTDI_UART1_RXD: R910.2 U79.13 | length 4.5
  L1 w0.2: R910.2@227.482,236.984 227.482,235.056 228.398,234.141 U79.13@228.398,232.825
US2_FTDI_UART1_TXD: R909.2 U79.14 | length 4.7
  L1 w0.2: R909.2@226.359,236.984 226.359,235.554 227.748,234.165 U79.14@227.748,232.825
US+_DxN: R279.1 R286.1 U1.V15 | length 94.8
  L1 w0.2: R279.1@222.364,337.508 224.607,337.508 225.011,337.104 ccw(c225.152,337.246) 225.145,337.046 v1(225.171,337.045)
  L5 (Sign) w0.12: v12(188.438,297.959) 188.749,297.647 189.854,297.647 189.86,297.642 192.397,297.642 192.706,297.642 193.006,297.942 v1(222.428,297.942)
  L12 (Sign) w0.2: v1(222.428,297.942) 222.428,299.529 220.37,301.587 220.37,306.576 226.123,312.329 226.123,335.908 ccw(c225.923,335.908) 226.072,336.043 v1(225.171,337.045)
  L3 (Sign) w0.12: v2(179.397,302.539) 179.029,302.172 179.029,301.802 178.982,301.754 178.982,298.28 179.281,297.98 179.664,297.98 180.013,297.631 180.268,297.631 180.512,297.387 181.048,297.387 181.451,296.984 182.627,296.984 183.277,297.635 186.769,297.635 187.115,297.98 188.416,297.98 v12(188.438,297.959)
US+_DxP: R282.1 R283.1 U1.V14 | length 100.5
  L1 w0.2: R282.1@222.656,340.746 225.178,340.746 v1(225.184,340.741)
  L5 (Sign) w0.12: v12(186.57,298.045) 186.507,298.045 186.215,297.753 186.215,296.958 186.531,296.642 188.079,296.642 188.489,297.052 189.093,297.052 189.605,296.539 190.419,296.539 190.626,296.333 191.977,296.333 192.397,296.753 192.547,296.902 192.547,297.052 192.537,297.062 192.537,297.161 192.838,297.462 193.377,297.462 193.417,297.421 223.114,297.421 v1(223.634,297.942)
  L12 (Sign) w0.2: v1(223.634,297.942) 223.634,298.747 220.675,301.706 220.675,306.456 226.428,312.209 226.428,339.496 v1(225.184,340.741)
  L3 (Sign) w0.12: v2(179.397,301.539) 179.433,301.539 179.629,301.344 179.708,301.344 179.858,301.195 179.858,298.499 180.749,297.607 181.441,297.607 181.844,297.204 182.536,297.204 183.214,297.883 185.817,297.883 185.937,298.003 186.528,298.003 v12(186.57,298.045)
US+_GND_PS_ADC: C627.1 C628.1 FB39.2 U1.W21 | length 22.4
  L1 w0.5: v1(197.269,308.539) 197.269,307.581 198.488,306.362 FB39.2@199.707,306.362
  L9 (PWR/GND) w0.2: v1(180.397,308.539) 180.898,308.038 182.887,308.038 183.388,308.539 v1(197.269,308.539)
  L16 w0.2: v1(197.269,308.539) 198.411,308.539 C627.1@198.476,308.604
US+_GNDADC: C629.1 C630.1 FB41.2 U1.R14 U1.U14 U1.U15 | length 2.2
  L16 w0.4: C629.1@197.104,303.905 197.104,303.505 v10(197.129,303.479) ; v10(203.568,303.963) 203.568,303.463 FB41.2@204.466,302.565
  other v1: 176.397,301.539 178.397,301.539 178.397,302.539
US+_MGTRref: R173.1 U1.M25 | length 16.6
  L1 w0.254: R173.1@162.03,321.871 162.062,321.839 162.737,321.839 v1(162.769,321.807)
  L14 (Sign) w0.254: v1(162.769,321.807) 165.533,321.807 168.801,318.539 170.832,316.508 170.832,314.119 172.412,312.539 v1(173.397,312.539)
US+_MGTRref_K8: R695.1 U1.K8
  other v1: 171.397,295.284
US+_MGTVccAux: C605.2 C606.2 C607.2 C610.2 C611.2 C756.2 C759.2 L16.2 R212.2 R363.1 R364.1 R365.1 R515.1 R522.1 R523.2 R531.1 R546.2 R548.1 R549.2 R551.1 R552.2 R554.1 R555.2 R557.1 R607.2 R659.1 R660.2 R661.1 R662.2 R663.1 R664.2 R735.1 R736.2 R765.1 R766.2 R817.1 R818.2 R820.1 R821.2 R823.1 R824.2 R847.1 R848.2 R849.1 R850.2 R852.1 R853.2 R855.1 R856.2 R858.1 R859.2 R861.2 R921.1 R922.2 R923.1 R924.2 R925.1 R926.2 R927.1 R928.2 R929.1 R930.2 R931.1 R932.2 R933.1 R934.2 R935.1 R936.2 R937.1 R938.2 R939.1 R940.2 R941.1 R942.2 R943.1 R944.2 R945.1 R946.2 R947.1 R948.2 R949.1 R950.2 R951.1 R952.2 R953.1 R954.2 R955.1 R956.2 R957.1 R958.2 R959.1 R960.2 U1.AA4 U1.AC15 U1.AD3 U1.AD8 U1.AE11 U1.AF14 U1.AG7 U1.AG17 U1.AH10 U1.D13 U1.E10 U1.E16 U1.G10 U1.G12 U1.H15 U1.H25 U1.K25 U1.L27 U15.1 U15.7 U15.8 U15.16 U36_Trans_LS_I2C0.2 U36_Trans_LS_I2C1.2 U79.15 | length 448.3
  L1 w0.2: v3(181.965,291.12) 181.971,291.12 182.39,291.539 U1.AA4@182.397,291.539
  L1 w0.254: L16.2@156.819,174.442 156.835,174.458 v7(160.468,174.458) ; R212.2@182.642,172.415 v7(182.642,173.417)
  L1 w0.3: R365.1@130.952,267.894 v1(131.641,267.894) ; U15.1@132.169,272.106 v1(132.169,272.795) ; U15.16@138.572,272.106 v1(138.572,272.795) ; U1.D13@165.397,300.539 v1(165.884,301.027) ; v1(166.397,297.539) 166.897,297.039 167.897,297.039 U1.G10@168.397,297.539 ; U1.E16@166.397,303.539 v1(166.884,303.052) ; U1.G12@168.397,299.539 v1(168.884,299.052) ; v1(168.909,312.052) U1.H25@169.397,312.539 ; U1.H15@169.397,302.539 v1(169.884,302.052) ; v1(170.909,312.052) U1.K25@171.397,312.539 ; v1(171.909,314.052) U1.L27@172.397,314.539
  L1 w0.5: v1(131.641,267.894) 132.191,267.894 132.344,268.046 ; L16.2@156.819,174.442 156.566,174.696 156.566,176.157 155.812,176.911 149.544,176.911 149.544,180.847 161.866,193.168 174.69,193.168 209.344,227.823 215.582,227.823 222.17,234.411 226.759,234.411 227.098,234.072 U79.15@227.098,232.825 ; C605.2@181.826,172.222 181.992,172.389 182.615,172.389 R212.2@182.642,172.415 ; v2(184.849,295.031) 184.889,295.031 U1.AD8@185.397,295.539 ; v1(184.909,290.052) U1.AD3@185.397,290.539 ; v3(186.074,298.522) 186.206,298.522 186.38,298.522 U1.AE11@186.397,298.539 ; U1.AF14@187.397,301.539 v1(187.756,301.18) ; v1(187.922,294.176) 188.034,294.176 U1.AG7@188.397,294.539 ; U1.AH10@189.397,297.539 189.397,297.525 189.775,297.147 v3(189.775,297.052) ; v1(226.732,309.74) 226.732,308.122 227.004,307.851 v5(227.686,307.851) ; v1(226.893,287.565) 226.893,286.923 R849.1@227.534,286.283 ; v9(227.057,298.475) 227.188,298.345 227.69,298.847 v5(227.74,298.847)
  L1 w2: v1(150.968,174.766) 151.292,174.442 L16.2@156.819,174.442
  L5 (Sign) w0.5: v1(195.509,306.984) 196.14,306.984 214.528,306.984 217.283,309.74 v1(226.732,309.74)
  L9 (PWR/GND) w0.5: v1(226.893,287.565) 226.34,287.565 225.603,288.302 225.603,297.021 v9(227.057,298.475)
  L12 (Sign) w0.5: v1(70.329,259.804) 72.331,259.804 80.967,268.44 v16(82.614,268.44) ; v1(226.732,309.74) 227.057,309.415 v9(227.057,298.475)
  L2 (GND) w0.5: v5(227.559,286.308) v5(228.908,286.308) v5(230.258,286.308) v5(232.957,286.308) v5(258.597,286.308) ; v5(227.686,307.851) 227.736,307.801 v5(271.098,307.801) ; v5(227.74,298.847) v5(229.053,298.847) v5(230.416,298.847) v5(231.78,298.847) v5(233.143,298.847) v5(262.116,298.847)
  L3 (Sign) w0.254: v7(160.468,174.458) 181.602,174.458 v7(182.642,173.417)
  L3 (Sign) w0.5: v2(184.849,295.031) 184.854,295.037 v12(185.748,295.037) 185.814,295.037 186.675,294.176 v1(187.922,294.176) ; v3(186.074,298.522) 186.074,298.435 v3@186.097,298.413
  L10 (3V3+Other) w0.5: 188.504,294.196 189.523,294.196 189.716,294.389 195.513,294.389 v1(196.459,295.335) ; 188.841,303.596 190.522,303.596 193.911,306.984 v1(195.509,306.984)
  L14 (Sign) w0.5: v16(82.614,268.44) 82.614,269.481 84.455,271.323 123.71,271.323 125.182,272.795 131.533,272.795 ; v1(131.641,267.894) 131.533,268.003 131.533,272.795 ; v1(138.572,272.795) 137.494,271.716 133.247,271.716 v1(132.169,272.795) 131.533,272.795
  L16 w0.2: U36_Trans_LS_I2C1.2@68.1,325.536 70.855,325.536 71.08,325.311 ; U36_Trans_LS_I2C0.2@68.1,333.21 68.323,333.21 69.925,333.21 71.08,332.055 71.08,325.311 ; R364.1@71.08,323.685 71.08,325.311
  L16 w0.5: v1(71.08,323.179) R364.1@71.08,323.685
  other v1: 149.18,173.117 150.067,173.117 150.968,173.117 151.85,173.117 152.737,173.117 149.18,173.942 150.067,173.942 150.968,173.942 151.85,173.942 149.18,174.766 150.067,174.766 151.85,174.766 149.18,175.591 150.067,175.591 150.968,175.591 151.85,175.591 152.737,175.591 184.397,302.539 188.397,304.539 68.825,317.092 69.383,317.092 68.821,317.79 69.379,317.79 68.825,318.487 69.383,318.487 68.825,319.185 69.383,319.185
  other v5: 231.607,286.307 234.306,286.307 235.656,286.308 237.005,286.307 238.355,286.308 239.704,286.308 241.054,286.308 242.403,286.308 243.753,286.307 245.102,286.308 246.452,286.308 247.801,286.308 249.151,286.308 250.5,286.308 251.85,286.307 253.199,286.308 254.549,286.308 255.898,286.308 257.248,286.308 237.233,298.847 238.596,298.847 239.96,298.847 241.323,298.847 242.686,298.847 244.05,298.847 245.413,298.847 246.776,298.847 248.14,298.847 249.503,298.847 250.866,298.847 252.23,298.847 253.593,298.847 254.956,298.847 256.32,298.847 257.683,298.847 259.161,298.847 260.639,298.847 234.506,298.897 235.87,298.897 229.183,307.851 230.68,307.851 232.177,307.851 233.674,307.851 235.172,307.853 236.668,307.851 238.165,307.851 239.662,307.851 241.159,307.851 242.656,307.851 244.153,307.851 245.649,307.851 247.146,307.851 248.643,307.851 250.14,307.851 251.637,307.851 253.134,307.851 254.631,307.851 256.128,307.851 257.625,307.851 259.122,307.851 260.619,307.851 262.116,307.851 263.613,307.851 265.11,307.851 266.607,307.851 268.104,307.851 269.601,307.851
  other v18: 138.684,317.31 140.462,317.31 138.684,318.198 139.573,318.198 140.462,318.198 138.684,319.087 139.573,319.087 140.462,319.087
US+_POR_OVE: R693.1 U1.Y6 | length 14.6
  L1 w0.12: U1.Y6@181.397,293.539 181.447,293.49 181.447,293.181 v3(181.496,293.131)
  L1 w0.2: v1(193.392,293.789) 193.634,293.548 R693.1@194.373,293.548
  L12 (Sign) w0.12: v3(181.496,293.131) 184.656,293.131 185.782,292.004 190.07,292.004 191.855,293.789 v1(193.392,293.789)
US+_Pudc_B: R694.2 R696.1 U1.W7 | length 81.6
  L1 w0.12: U1.W7@180.397,294.539 180.47,294.612 180.47,294.915 v7(180.556,295.001)
  L1 w0.2: R696.1@229.761,321.727 R696.1@229.761,321.777 230.165,322.182 ; v1(229.768,322.656) 230.165,322.259 230.165,322.182 ; R694.2@231.223,322.182 230.165,322.182
  L5 (Sign) w0.12: v12(181.34,295.709) 182.012,295.037 183.064,295.037 186.401,291.7 188.387,291.7 188.905,292.219 197.559,292.219 198.488,293.148 198.488,293.717 199.094,294.322 205.22,294.322 205.574,294.676 217.591,294.676 218.224,294.043 220.006,294.043 v1(220.066,293.983)
  L12 (Sign) w0.2: v1(220.066,293.983) 220.066,294.043 220.599,294.577 223.872,294.577 225.73,296.435 225.73,309.814 228.421,312.505 228.421,314.751 230.759,317.089 230.759,321.666 v1(229.768,322.656)
  L3 (Sign) w0.12: v7(180.556,295.001) 181.264,295.709 v12(181.34,295.709)
US+_Vcc_PS_ADC: C627.2 C628.2 FB38.2 U1.W22 | length 21
  L1 w0.4: v1(197.739,309.093) 198.653,308.178 FB38.2@199.707,308.178
  L9 (PWR/GND) w0.2: v1(180.397,309.539) 180.869,309.068 183.891,309.068 184.362,309.539 192.936,309.539 193.383,309.093 v1(197.739,309.093)
  L16 w0.2: v1(197.739,309.093) 198.444,309.093 C627.2@198.476,309.124
US+_Vcc_PS_Batt: B1.1 C747.1 C748.2 R276.1 U1.U20 | length 87.5
  L1 w0.65: R276.1@245.613,323.51 B1.1@248.262,323.51 ; C748.2@247.97,317.685 248.187,317.903 C747.1@248.187,320.226 248.187,323.435 B1.1@248.262,323.51 ; B1.1@248.648,323.51 B1.1@248.262,323.51
  L5 (Sign) w0.2: v1(178.397,307.539) 178.896,308.038 182.887,308.038 183.382,308.534 193.332,308.534 195.204,310.406 202.659,310.406 208.407,316.154 211.125,316.154 220.409,325.438 229.591,325.438 231.267,323.761 245.758,323.761 247.256,322.262 v1(248.145,322.262)
US+_Vcc_PS_DDR_504: C616.2 C617.2 C618.2 C619.2 C620.2 C621.2 C622.2 C753.1 C754.2 C755.2 L18.2 R220.2 U1.AA24 U1.AB27 U1.AC25 U1.AD28 U1.AE26 U1.AG27 U1.AK26 | length 80.8
  L1 w0.2: v2(182.909,315.027) U1.AB27@183.397,314.539 ; v2(184.91,315.052) U1.AD28@185.397,315.539
  L1 w0.25: U1.AA24@182.397,311.539 v2(182.884,311.052) ; v2(183.928,312.07) U1.AC25@184.397,312.539 ; U1.AE26@186.397,313.539 v2(186.884,314.027) ; v1@187.898,315.024 U1.AG27@188.382,314.539 ; U1.AK26@191.397,313.539 v2(191.884,314.027)
  L1 w0.254: 166.401,157.07 177.861,157.07 180.059,159.268 180.059,168.365 179.984,168.44 179.434,168.44 179.184,168.69 C616.2@179.174,168.69
  L1 w1: C619.2@156.729,156.993 L18.2@161.718,156.993
  L1 w2: L18.2@161.718,156.993 L18.2@161.768,157.043 ; 162.875,153.889 L18.2@162.875,156.152
  L9 (PWR/GND) w0.254: v18(206.06,274.726) v18@206.083,274.726
  L3 (Sign) w0.254: v2(182.884,311.052) v6(183.381,311.549) ; v2(182.909,315.027) v6@182.909,315.531 ; v2(183.928,312.07) v6@184.266,312.408 ; v2(184.91,315.052) v6@184.91,315.556 ; v6(186.652,313.631) 186.884,313.863 v2(186.884,314.027) ; v2(191.884,314.027) v6@192.241,313.671
  L10 (3V3+Other) w1: v1(202.115,313.623) 202.602,313.623 204.445,311.781 204.445,285.928 206.06,284.313 v18(206.06,274.726)
  other v1: 158.505,153.678 159.392,153.678 160.293,153.678 161.175,153.678 162.062,153.678 158.505,154.503 159.392,154.503 160.293,154.503 161.175,154.503 162.062,154.503 158.505,155.327 159.392,155.327 160.293,155.327 161.175,155.327 162.062,155.327 158.505,156.152 159.392,156.152 160.293,156.152 161.175,156.152 162.062,156.152 187.884,315.024 208.559,315.59 206.857,315.617
  other v6: 184.266,312.427 192.259,313.67 182.897,315.544 184.897,315.569
US+_Vcc_PS_DDR_PLL: C631.2 C632.2 FB42.2 U1.U18 U1.U19 | length 9
  L16 w0.4: v1(197.244,306.197) 195.897,304.851 195.897,303.287 197.648,301.536 198.918,301.536 ; FB42.2@198.918,302.489 198.918,301.536 ; C631.2@198.942,300.723 198.918,300.747 198.918,301.536
  other v1: 178.397,305.539 178.397,306.539
US+_Vcc_PS_IntFp: C738.1 C739.1 C740.2 C744.2 C745.2 C751.1 C752.2 C762.1 C763.2 C764.1 C765.2 R271.2 R617.2 U1.AA18 U1.AA20 U1.AA21 U1.AA22 U1.L11 U1.L13 U1.L17 U1.M12 U1.M14 U1.M16 U1.M18 U1.N11 U1.N13 U1.N15 U1.N17 U1.P12 U1.P14 U1.P16 U1.R10 U1.R11 U1.R13 U1.R17 U1.T9 U1.T10 U1.T12 U1.T16 U1.U8 U1.U9 U1.U10 U1.U11 U1.U13 U1.U17 U1.V8 U1.V10 U1.V12 U1.V16 U1.V17 U1.V18 U1.V19 U1.W11 U1.W13 U1.W15 U1.W17 U1.W19 U1.W20 U1.Y12 U1.Y14 U1.Y16 U1.Y17 U1.Y18 U1.Y19 U1.Y20 U1.Y22 U72.8 U72.9 | length 22.8
  L1 w0.2: U72.9@137.853,283.403 137.853,286.95 ; 137.853,287.027 139.032,288.205 ; U72.8@138.353,283.403 138.353,285.538 140.462,287.647
  L16 w0.5: v13(141.025,289.801) 141.025,289.074 141.681,288.417 C765.2@141.681,287.626 ; v1(179.397,297.539) 179.85,297.539 ccw(c179.85,297.561) R271.2@179.872,297.561
  L16 w2: C764.1@139.272,287.908 v13(139.272,289.801) ; v13(146.282,289.801) 146.638,290.157 C744.2@147.991,290.157 ; v13(146.282,293.306) 146.625,293.649 C739.1@148.028,293.649 ; v13(146.282,296.812) 146.841,297.37 C751.1@147.968,297.37 ; v13(146.282,302.069) 147.072,301.573 C762.1@147.939,301.028
  other v1: 178.397,295.539 179.397,295.539 177.397,296.539 178.397,296.539 176.397,297.539 177.397,297.539 178.397,297.539 172.397,298.539 174.397,298.539 176.397,298.539 178.397,298.539 180.397,298.539 173.397,299.539 175.397,299.539 177.397,299.539 179.397,299.539 181.397,299.539 172.397,300.539 174.397,300.539 176.397,300.539 178.397,300.539 180.397,300.539 173.397,301.539 175.397,301.539 181.397,301.539 174.397,302.539 180.397,302.539 173.397,303.539 175.397,303.539 177.397,303.539 179.397,303.539 181.397,303.539 172.397,304.539 174.397,304.539 176.397,304.539 178.397,304.539 179.397,304.539 180.397,304.539 181.397,304.539 173.395,305.545 179.397,305.539 181.397,305.539 182.397,305.539 179.397,306.539 180.397,306.539 181.397,306.539 180.397,307.539 181.397,307.539 182.397,307.539 182.397,308.539 181.397,309.539 182.397,309.539
  other v13: 142.777,289.801 144.53,289.801 139.272,291.554 141.025,291.554 142.777,291.554 144.53,291.554 146.282,291.554 142.777,293.306 144.53,293.306 139.272,293.306 141.025,293.306 139.272,295.059 141.025,295.059 142.777,295.059 144.53,295.059 146.282,295.059 142.777,296.812 144.53,296.812 139.272,296.812 141.025,296.812 139.272,298.564 141.025,298.564 142.777,298.564 144.53,298.564 146.282,298.564 142.777,300.317 144.53,300.317 146.282,300.317 139.272,300.317 141.025,300.317 139.272,302.07 141.025,302.07 142.777,302.069 144.53,302.069
US+_VccADC: C629.2 C630.2 FB40.2 U1.R15 | length 2.4
  L16 w0.4: v10(196.507,304.508) 198.537,304.508 FB40.2@198.779,304.749
  other v1: 176.397,302.539
US+_VN: J29.1 U1.T15 | length 83.3
  L5 (Sign) w0.12: v6(186.744,303.007) 187.157,303.007 187.384,303.234 192,303.234 192.729,303.963 209.887,303.963 209.905,303.98 218.062,303.98 218.883,304.8 219.174,304.8 220.092,305.718 221.619,305.718 v1(221.633,305.732)
  L12 (Sign) w0.2: v1(221.633,305.732) 221.659,305.758 221.659,306.591 228.121,313.054 228.121,323.575 229.273,324.726 240.309,324.726 241.287,325.704 J29.1@241.287,327.762
  L3 (Sign) w0.12: v2(177.397,302.539) 177.884,303.027 177.884,303.539 177.987,303.642 177.987,303.709 178.227,303.949 182.014,303.949 182.038,303.926 185.825,303.926 v6(186.744,303.007)
US+_VP: J29.2 U1.T14 | length 82.5
  L5 (Sign) w0.12: v6(187.477,302.539) 187.769,302.539 188.243,303.014 192.091,303.014 192.82,303.743 209.978,303.743 209.996,303.76 218.154,303.76 218.969,304.575 219.267,304.575 219.949,305.257 v1(221.132,305.257)
  L12 (Sign) w0.2: v1(221.132,305.257) 221.132,306.489 227.821,313.178 227.821,323.699 229.149,325.026 237.904,325.026 238.747,325.869 J29.2@238.747,327.762
  L3 (Sign) w0.12: v2(177.397,301.539) 177.964,302.106 177.964,302.686 178.33,303.052 178.337,303.052 178.384,303.098 180.418,303.098 180.822,302.694 180.822,302.534 181.227,302.129 181.567,302.129 182.141,302.704 182.516,302.704 182.578,302.642 183.216,302.642 183.278,302.704 183.981,302.704 184.227,302.949 184.879,302.949 184.974,302.854 185.626,302.854 185.776,302.704 185.776,302.229 185.986,302.018 186.956,302.018 v6(187.477,302.539)
US_PADI: C535.2 R374.1 U1.M21 X5.1 | length 44.1
  L1 w0.12: U1.M21@173.397,308.539 v1(173.884,308.052)
  L16 w0.12: v1(173.884,308.052) 174.422,307.515 174.422,305.511 174.987,304.946 174.987,304.37 175.227,304.129 175.259,304.129 175.336,304.052 181.909,304.052 183.012,305.155 183.958,305.155 185.278,303.835 185.498,303.615 192.261,303.615 192.397,303.751 192.481,303.835 193.764,305.118 194.462,305.118 195.356,306.011 196.139,306.011 197.118,306.99 199.408,306.99 204.31,311.893 204.31,313.797 204.31,314.782 204.31,316.26 204.7,316.649 X5.1@205.11,316.649
US_PADO: C536.2 R374.2 U1.N21 X5.2 | length 40.3
  L1 w0.12: U1.N21@174.397,308.539 v1(174.884,308.052)
  L16 w0.12: v1(174.884,308.052) 175.373,307.563 176.066,307.563 176.397,307.232 176.397,306.539 176.884,306.052 183.372,306.052 185.589,303.835 192.17,303.835 192.397,304.062 193.875,305.539 194.032,305.539 194.724,306.231 196.048,306.231 197.027,307.21 199.188,307.21 203.41,311.433 203.41,313.797 203.41,314.782 203.41,316.237 202.998,316.649 X5.2@202.61,316.649
US_PS_DONE: R357.1 U1.N22 U43.6 | length 93.1
  L1 w0.12: U1.N22@174.397,309.539 v1(174.884,309.052)
  L12 (Sign) w0.12: v1(201.841,310.865) 202.36,311.383 204.797,311.383 205.872,312.458 v1(207.785,312.458)
  L3 (Sign) w0.2: v1@206.34,359.508 ccw(c206.54,359.511) 206.399,359.369 206.904,358.864 206.904,344.377 211.21,340.072 211.21,315.299 208.369,312.458 v1(207.785,312.458)
  L16 w0.12: v1(174.884,309.052) 175.397,308.539 176.106,308.539 176.39,308.255 176.39,307.783 177.138,307.035 182.64,307.035 183.092,306.584 183.633,306.584 184.121,306.096 185.928,306.096 186.869,305.155 192.397,305.155 193.693,306.451 195.957,306.451 196.936,307.43 199.097,307.43 201.841,310.175 v1(201.841,310.865) ; U43.6@204.17,360.429 205.318,360.429 206.319,359.428 206.34,359.428 206.422,359.346 R357.1@207.068,359.346 ; v1@206.29,359.457 v1(206.34,359.508)
US_PS_Err_Out: U1.R22 U43.3 | length 100.2
  L1 w0.12: U1.R22@176.397,309.539 v1(176.884,309.052) ; v1(205.454,310.954) 207.527,313.027 209.917,313.027 211.014,314.124 211.014,357.865 206.5,362.379 v1(205.75,362.379)
  L12 (Sign) w0.12: v1(176.884,309.052) 176.806,309.052 176.403,308.649 176.403,307.77 177.138,307.035 181.546,307.035 181.864,306.718 181.864,306.356 182.15,306.07 182.55,306.07 183.058,305.562 184.455,305.562 185.598,304.419 186.906,304.419 187.406,303.919 192.397,303.919 202.954,303.919 207.308,308.273 207.308,310.229 207.051,310.486 205.922,310.486 v1(205.454,310.954)
  L16 w0.12: U43.3@204.17,362.379 v1(205.75,362.379)
US_PS_Err_Status: U1.R20 U43.4 | length 92.5
  L1 w0.12: U1.R20@176.397,307.539 v2(176.884,307.052) ; v2(205.511,308.94) 207.925,308.94 211.234,312.25 211.234,358.952 v1(208.655,361.531)
  L3 (Sign) w0.12: v2(176.884,307.052) 183.184,307.052 183.672,307.539 190.624,307.539 190.7,307.615 192.321,307.615 192.397,307.691 195.694,307.691 196.025,307.36 202.621,307.36 204.201,308.94 v2(205.511,308.94)
  L16 w0.12: U43.4@204.17,361.729 204.188,361.747 205.75,361.747 205.855,361.852 208.257,361.852 208.577,361.531 v1(208.655,361.531)
US_PS_Init_B: R353.2 U1.N18 U43.5 | length 105.6
  L1 w0.12: v1(174.007,305.155) 174.012,305.155 U1.N18@174.397,305.539
  L12 (Sign) w0.12: v1(174.007,305.155) 173.934,305.082 173.934,304.9 173.929,304.894 173.929,302.428 174.312,302.044 179.696,302.044 179.946,301.794 179.946,299.237 180.149,299.034 182.49,299.034 182.811,298.713 185.685,298.713 187.708,300.736 201.346,300.736 208.425,307.816 208.425,309.7 209.677,310.951 v1(209.677,311.844)
  L3 (Sign) w0.2: v1(206.362,361.432) 207.404,360.391 207.404,344.584 211.709,340.279 211.709,314.541 209.677,312.509 v1(209.677,311.844)
  L16 w0.12: U43.5@204.17,361.079 206.027,361.079 206.362,360.743 ; v1(206.362,361.432) 206.362,360.743 ; R353.2@207.068,360.667 206.439,360.667 206.362,360.743
US_PS_JTAG_TCK: R346.2 R1028.2 U1.L19 | length 176.9
  L1 w0.12: U1.L19@172.397,306.539 v2(172.884,306.052) ; R1028.2@222.413,203.95 222.426,203.962 v2@224.511,203.962 ; v2@224.511,203.944 v2(224.523,203.956) ; v2@224.523,203.962 R346.2@226.797,203.962
  L3 (Sign) w0.12: v2(172.884,306.052) 172.884,306.017 171.937,305.07 171.937,303.939 171.537,303.539 171.386,303.539 170.529,302.682 168.64,302.682 166.27,300.312 159.985,300.312 157.845,298.172 157.845,296.429 154.885,293.468 154.885,291.451 155.436,290.9 155.436,284.975 161.941,278.47 173.536,278.47 174.85,277.156 193.852,277.156 194.537,276.471 211.145,276.471 224.341,263.275 224.341,263.266 224.835,262.772 224.835,255.018 225.293,254.559 225.293,229.968 224.189,228.863 224.189,207.973 224.341,207.821 224.341,207.815 224.523,207.632 v2(224.523,203.956)
US_PS_JTAG_TDI: R347.2 R1026.2 U1.L20 | length 174.8
  L1 w0.12: U1.L20@172.397,307.539 v2(172.884,307.052) ; R1026.2@222.413,206.983 v2@224.121,206.983 ; v2(224.121,207.006) v2@224.13,206.997 ; v2@224.13,206.983 R347.2@226.797,206.983
  L3 (Sign) w0.12: v2(172.884,307.052) 172.884,306.559 172.339,306.013 172.339,305.828 171.594,305.084 171.594,304.107 170.731,303.244 168.89,303.244 166.179,300.532 159.894,300.532 157.625,298.263 157.625,296.52 154.665,293.559 154.665,291.36 155.216,290.809 155.216,284.884 161.85,278.25 173.445,278.25 174.759,276.936 193.761,276.936 194.446,276.251 211.045,276.251 224.561,262.736 224.561,254.981 225.073,254.468 225.073,230.059 223.969,228.954 223.969,207.882 224.121,207.73 v2(224.121,207.006)
US_PS_JTAG_TDO: R1029.2 U1.M20 | length 179.3
  L1 w0.12: U1.M20@173.397,307.539 v2(173.884,307.052) ; R1029.2@222.413,202.433 v2@224.892,202.433
  L3 (Sign) w0.12: v2(173.884,307.052) 173.884,306.754 173.219,306.089 173.219,305.95 172.985,305.715 172.985,303.16 172.11,302.285 170.832,302.285 170.73,302.387 170.26,302.387 170.185,302.462 169.242,302.462 168.294,301.514 168.294,300.882 168.054,300.642 167.422,300.642 166.872,300.092 160.077,300.092 158.065,298.081 158.065,296.337 155.105,293.377 155.105,291.542 155.656,290.991 155.656,285.066 162.032,278.69 173.627,278.69 174.941,277.376 193.944,277.376 194.629,276.691 211.236,276.691 224.561,263.367 ; 224.561,263.357 225.068,262.85 225.068,255.096 225.513,254.65 225.513,229.877 224.409,228.772 224.409,208.064 224.892,207.582 v2(224.892,202.438)
US_PS_JTAG_TMS: R348.2 R1027.2 U1.L21 | length 178.3
  L1 w0.12: U1.L21@172.397,308.539 v2(172.884,308.052) ; R1027.2@222.413,205.466 223.297,205.466 v2(223.304,205.473) R348.2@226.797,205.472
  L3 (Sign) w0.12: v2(172.884,308.052) 172.884,307.699 172.339,307.154 172.339,306.766 172.138,306.565 171.718,306.565 171.369,306.217 171.369,304.705 170.128,303.464 168.799,303.464 166.99,301.654 165.593,301.654 164.69,300.752 159.803,300.752 157.405,298.354 157.405,296.611 154.445,293.65 154.445,291.269 154.996,290.718 154.996,284.792 161.759,278.03 173.354,278.03 174.668,276.716 187.298,276.716 188.959,275.056 195.127,275.056 196.103,276.031 210.954,276.031 224.341,262.645 224.341,254.89 224.853,254.377 224.853,230.15 223.749,229.045 223.749,207.791 223.786,207.754 223.786,205.955 v2(223.304,205.473)
US_PS_Mode0: P2.4 R349.1 S1.1 U1.R18 | length 191.4
  L1 w0.12: U1.R18@176.397,305.539 v1(176.884,305.052)
  L1 w0.2: S1.1@232.473,346.481 v1(234.886,346.481) 235.293,346.481 P2.4@237.071,344.703 238.722,346.354 R349.1@242.659,346.354
  L5 (Sign) w0.2: v1(207.224,311.368) 208.352,310.24 209.734,310.24 211.86,312.366 223.874,312.366 227.425,315.916 269.712,315.916 272.194,318.398 v6(272.232,318.398)
  L12 (Sign) w0.12: v1(176.884,305.052) 181.525,305.052 183.075,303.502 185.646,303.502 186.118,303.974 186.728,303.974 187.224,303.479 192.397,303.479 203.136,303.479 207.748,308.091 207.748,310.844 v1(207.224,311.368)
  L3 (Sign) w0.2: P2.4@237.071,344.703 241.454,349.086 250.918,349.086 255.529,353.697 269.416,353.697 272.772,350.34 272.772,318.938 v6(272.232,318.398)
US_PS_Mode2: P2.2 R351.1 S1.3 U1.P21 | length 190.9
  L1 w0.12: U1.P21@175.397,308.539 v1(175.884,308.052)
  L1 w0.2: S1.3@232.473,349.021 v1(234.886,349.021) 236.309,349.021 P2.2@237.071,349.783 237.875,348.979 R351.1@242.659,348.979
  L5 (Sign) w0.2: v1(206.184,309.855) 206.999,309.04 209.382,309.04 212.108,311.766 224.123,311.766 224.78,312.423 225.628,312.423 227.922,314.716 269.96,314.716 272.693,317.449 273.151,317.449 v6(273.176,317.475)
  L3 (Sign) w0.2: P2.2@237.071,349.783 239.194,351.907 247.088,351.907 250.225,355.044 269.799,355.044 273.372,351.47 273.372,317.742 273.176,317.546 v6(273.176,317.475)
  L14 (Sign) w0.12: v1(175.884,308.052) 175.884,307.668 176.416,307.137 177.22,307.137 177.407,306.949 182.803,306.949 183.583,306.169 183.715,306.169 184.974,304.909 185.658,304.909 186.074,305.325 192.397,305.325 194.275,305.325 194.516,305.566 202.717,305.566 206.387,309.236 206.387,309.652 v1(206.184,309.855)
US_PS_Mode3: P2.1 R352.1 S1.4 U1.P22 | length 194.8
  L1 w0.12: U1.P22@175.397,309.539 v1(175.884,309.052)
  L1 w0.2: S1.4@232.473,350.291 234.836,350.291 v1(234.874,350.329) 235.318,350.774 235.318,351.726 235.915,352.323 P2.1@237.071,352.323 239.103,350.291 R352.1@242.659,350.291
  L5 (Sign) w0.2: v1(205.585,309.731) 206.575,308.74 209.507,308.74 212.233,311.466 224.247,311.466 224.904,312.123 225.752,312.123 228.046,314.416 270.966,314.416 273.575,317.025 v6(273.575,317.027)
  L3 (Sign) w0.2: P2.1@237.071,352.323 247.081,352.323 250.101,355.344 269.923,355.344 273.672,351.594 273.672,317.318 273.658,317.304 273.658,317.11 v6(273.575,317.027)
  L14 (Sign) w0.12: v1(175.884,309.052) 175.949,309.052 177.434,310.537 178.085,310.537 178.123,310.5 178.261,310.5 178.685,310.076 178.685,309.431 179.089,309.027 182.848,309.027 183.058,308.817 183.058,307.137 185.065,305.129 185.567,305.129 185.983,305.545 193.191,305.545 193.815,306.169 195.674,306.169 196.49,306.984 202.838,306.984 v1(205.585,309.731)
US_PS_Prog_B: R356.2 R367.1 S2.1 S2.2 U1.M19 | length 200.1
  L1 w0.12: U1.M19@173.397,306.539 v1(173.884,306.052)
  L5 (Sign) w0.2: v1(206.87,309.931) 207.461,309.34 209.258,309.34 211.984,312.066 223.999,312.066 224.655,312.723 225.504,312.723 227.797,315.016 269.836,315.016 272.719,317.899 v6(272.752,317.899)
  L3 (Sign) w0.2: v1(236.156,341.135) 235.661,341.63 235.661,345.224 236.309,345.872 237.236,345.872 242.481,351.117 246.723,351.117 250.342,354.736 269.682,354.736 273.072,351.346 273.072,318.22 v6(272.752,317.899)
  L14 (Sign) w0.12: v1(173.884,306.052) 174.294,305.642 176.597,305.642 176.982,306.027 183.096,306.027 183.557,305.566 184.006,305.566 185.033,304.539 187.287,304.539 187.775,305.027 188.884,305.027 189.403,304.508 192.397,304.508 195.287,304.508 196.125,305.346 202.808,305.346 206.87,309.408 v1(206.87,309.931)
  L16 w0.12: R367.1@236.156,340.03 236.156,338.684 R356.2@236.207,338.633 ; R367.1@236.194,340.03 236.194,341.097 v1(236.156,341.135) 236.565,341.135 236.932,340.768 S2.2@238.165,340.768
  L16 w0.2: S2.2@238.165,340.768 S2.2@238.702,340.768 S2.1@245.702,340.768
US_PS_Ref_Clk: R375.2 U1.P19 | length 64.4
  L1 w0.12: U1.P19@175.397,306.539 v1(175.884,306.052) ; v2(220.575,325.438) 220.65,325.512 R375.2@220.65,326.285
  L5 (Sign) w0.2: v1(206.4,310.896) 206.4,311.245 207.164,312.008 208.897,312.008 209.797,312.908 211.129,312.908 212.144,313.923 215.409,313.923 219.977,318.491 v6(219.977,323.24)
  L12 (Sign) w0.12: v1(175.884,306.052) 181.506,306.052 181.89,305.668 181.89,305.021 183.189,303.722 185.555,303.722 186.027,304.194 186.819,304.194 187.315,303.699 192.397,303.699 203.045,303.699 207.528,308.182 207.528,310.321 206.953,310.896 v1(206.4,310.896)
  L3 (Sign) w0.12: v6(219.977,323.24) 219.977,324.839 v2(220.575,325.438)
USB2_CLK: R362.2 U45.1 | length 6.4
  L16 w0.12: U45.1@57.555,348.841 57.555,349.719 58.233,350.397 R362.2@62.801,350.397
USB2_D0: R116.2 U45.3 | length 6.5
  L16 w0.12: U45.3@57.555,347.841 58.268,347.841 59.046,348.619 60.151,348.619 60.211,348.619 ccw(c60.211,348.776) 60.368,348.776 60.368,348.778 cw(c60.525,348.778) 60.525,348.935 60.839,348.935 cw(c60.839,348.778) 60.996,348.778 60.996,348.42 ccw(c61.153,348.42) 61.153,348.263 61.467,348.263 ccw(c61.467,348.42) 61.624,348.42 61.624,348.462 cw(c61.781,348.462) 61.781,348.619 62.101,348.619 R116.2@62.801,348.619
USB2_D1: R117.2 U45.4 | length 4.8
  L16 w0.12: U45.4@57.555,347.341 59.055,347.341 59.115,347.341 ccw(c59.115,347.461) 59.235,347.461 59.235,348.221 cw(c59.354,348.221) 59.354,348.34 59.592,348.34 cw(c59.592,348.221) 59.711,348.221 59.711,347.461 ccw(c59.831,347.461) 59.831,347.341 60.066,347.341 R117.2@60.427,347.702
USB2_D2: R115.2 U45.5 | length 6.1
  L16 w0.12: U45.5@57.555,346.841 60.002,346.841 60.172,346.841 ccw(c60.172,346.985) 60.316,346.985 cw(c60.473,346.985) 60.473,347.142 60.787,347.142 cw(c60.787,346.985) 60.944,346.985 60.944,346.841 60.944,346.654 ccw(c61.101,346.654) 61.101,346.497 61.415,346.497 ccw(c61.415,346.654) 61.572,346.654 61.572,346.684 cw(c61.729,346.684) 61.729,346.841 62.293,346.841 R115.2@62.801,346.841
USB2_D3: R119.2 U45.6 | length 4.6
  L16 w0.12: U45.6@57.555,346.341 58.226,346.341 58.863,346.341 cw(c58.863,346.197) 59.007,346.197 59.007,345.575 ccw(c59.152,345.575) 59.152,345.431 59.44,345.431 ccw(c59.44,345.575) 59.585,345.575 59.585,346.197 cw(c59.729,346.197) 59.729,346.341 60.015,346.341 R119.2@60.427,345.929
USB2_D4: R120.2 U45.7 | length 5.6
  L16 w0.12: U45.7@57.555,345.841 58.286,345.841 59.064,345.063 R120.2@62.801,345.063
USB2_D5: R121.2 U45.9 | length 6.5
  L16 w0.12: U45.9@56.855,344.641 58.007,344.641 59.363,343.285 R121.2@62.801,343.285
USB2_D6: R122.2 U45.10 | length 5.7
  L16 w0.12: U45.10@56.355,344.641 56.355,343.461 57.433,342.383 R122.2@60.427,342.383
USB2_D7: R802.1 U45.13 | length 5.3
  L16 w0.12: U45.13@54.855,344.641 54.855,343.778 57.126,341.507 R802.1@58.389,341.507
USB2_DIR: R800.1 U45.31 | length 5.4
  L16 w0.12: U45.31@56.355,349.541 56.355,350.64 56.964,351.248 R800.1@60.427,351.248
USB2_NXT: R801.1 U45.2 | length 5.7
  L16 w0.12: U45.2@57.555,348.341 57.99,348.341 58.09,348.441 58.09,349.339 58.226,349.475 58.297,349.475 58.357,349.475 ccw(c58.357,349.619) 58.501,349.619 58.501,349.982 cw(c58.645,349.982) 58.645,350.126 58.934,350.126 cw(c58.934,349.982) 59.078,349.982 59.078,349.183 ccw(c59.223,349.183) 59.223,349.038 59.511,349.038 ccw(c59.511,349.183) 59.656,349.183 59.656,349.331 cw(c59.8,349.331) 59.8,349.475 60.23,349.475 R801.1@60.427,349.475
USB2_STP: R118.2 U45.29 | length 6.5
  L16 w0.12: U45.29@55.355,349.541 55.355,350.821 55.385,350.85 55.488,350.954 ccw(c55.377,351.065) 55.488,351.176 55.159,351.506 cw(c55.27,351.617) 55.159,351.728 55.381,351.95 cw(c55.492,351.839) 55.603,351.95 56.043,351.509 56.233,351.319 ccw(c56.344,351.43) 56.455,351.319 56.677,351.541 ccw(c56.566,351.652) 56.677,351.763 56.598,351.842 cw(c56.71,351.953) 56.598,352.064 56.71,352.175 R118.2@58.015,352.175
USB_D_N: C537.2 D13.2 U45.19 | length 19.2
  L16 w0.135: C537.2@37.721,351.698 ccw(c38.498,351.698) 38.498,350.92 40.595,350.92 ccw(c40.595,351.048) D13.2@40.723,351.048 ccw(c40.85,351.048) 40.85,350.92 41.203,350.92 ccw(c41.203,351.055) 41.301,350.963 cw(c41.423,350.848) 41.422,351.015 ccw(c41.42,351.15) 41.464,351.022 cw(c41.573,350.698) 41.682,351.022 ccw(c41.726,351.15) 41.724,351.015 cw(c41.723,350.848) 41.845,350.963 ccw(c41.943,351.055) 41.943,350.92 42.347,350.92 47.353,350.92 cw(c47.353,349.769) 48.504,349.769 48.504,347.465 ccw(c49.629,347.465) 49.629,346.341 U45.19@52.655,346.341
USB_D_P: C537.3 D13.1 U45.18 | length 19.2
  L16 w0.135: C537.3@37.721,349.698 cw(c38.498,349.698) 38.498,350.475 40.596,350.475 cw(c40.596,350.348) D13.1@40.723,350.348 cw(c40.85,350.348) 40.85,350.475 41.203,350.475 cw(c41.203,350.34) 41.301,350.433 ccw(c41.423,350.548) 41.422,350.38 cw(c41.42,350.245) 41.465,350.373 ccw(c41.573,350.698) 41.683,350.373 cw(c41.726,350.245) 41.724,350.38 ccw(c41.723,350.548) 41.845,350.433 cw(c41.943,350.34) 41.943,350.475 47.353,350.475 cw(c47.353,349.769) 48.059,349.769 48.059,347.465 ccw(c49.684,347.465) 49.684,345.841 U45.18@52.655,345.841
USB_En_Vout: U45.17 U46.A2 | length 22.8
  L1 w0.2: U46.A2@48.075,356.49 48.075,357.411 47.774,357.713 45.097,357.713 44.791,357.407 44.791,353.573 45.298,353.066 47.649,353.066 48.95,351.765 48.95,346.311 49.898,345.363 51.669,345.363 v1(51.719,345.313)
  L16 w0.2: v1(51.719,345.313) 51.733,345.327 52.641,345.327 U45.17@52.655,345.341
USB_OSC_IN: C736.2 R491.2 U45.26 X7.1 | length 8.4
  L16 w0.2: U45.26@53.855,349.541 53.855,351.712 54.095,351.952 54.746,351.952 55.416,352.621 55.416,353.39 55.62,353.595 X7.1@55.62,354.94 56.731,354.94 C736.2@57.264,355.473
USB_OSC_Out: C737.2 R491.1 U45.25 X7.3 | length 10.3
  L16 w0.2: C737.2@51.613,356.101 52.051,356.54 X7.3@53.42,356.54 53.912,356.54 54.516,355.936 54.516,353.39 54.394,353.39 53.355,352.351 U45.25@53.355,349.541
USB_RS0: R376.1 U45.8 | length 3.4
  L16 w0.12: U45.8@57.555,345.341 58.031,345.341 59.216,344.156 R376.1@60.427,344.156
USB_RS1: R377.1 U45.11 | length 1.8
  L1 w0.12: R377.1@55.855,342.837 v1(55.855,343.752)
  L16 w0.12: v1(55.855,343.752) U45.11@55.855,344.641
USB_RS2: R378.1 U45.14 | length 1.8
  L16 w0.12: R378.1@54.355,342.847 U45.14@54.355,344.641
USB_RX_C_N: C537.5 C543.1 D14.1 D14.10 | length 11.2
  L1 w0.1: 39.653,348.074 39.748,348.074 ccw(c39.748,349.342) 41.016,349.342 cw(c41.48,349.342) 41.48,349.806 41.828,349.806 cw(c41.828,349.761) D14.10@41.874,349.761 D14.1@42.708,349.761 cw(c42.753,349.761) 42.753,349.806 43.256,349.806
  L1 w0.111: v7(39.195,348.123) 39.234,348.123 39.279,348.078 39.42,348.078 39.42,348.074 39.653,348.074
  L1 w0.135: 43.256,349.806 cw(c43.256,349.207) 43.68,349.631 43.744,349.567 ccw(c44.245,350.068) 44.245,349.359 44.806,349.359 cw(c44.806,348.679) 45.286,349.16 C543.1@45.33,349.116
  L3 (Sign) w0.111: C537.5@36.22,346.698 36.22,347.221 cw(c36.516,347.221) 36.516,347.517 ; 36.517,347.517 ccw(c36.517,348.285) 37.06,347.742 37.185,347.868 cw(c37.802,347.251) 37.802,348.123 v7(39.195,348.123)
USB_RX_C_P: C537.6 C542.1 D14.2 D14.9 | length 11.2
  L1 w0.1: v7(39.195,348.484) 39.748,348.484 ccw(c39.748,349.342) 40.606,349.342 cw(c41.48,349.342) 41.48,350.216 41.828,350.216 ccw(c41.828,350.261) D14.9@41.874,350.261 D14.2@42.709,350.261 ccw(c42.753,350.261) 42.753,350.216 43.258,350.216
  L1 w0.135: 43.258,350.216 cw(c43.258,349.211) 43.969,349.922 44.032,349.858 ccw(c44.247,350.073) 44.247,349.769 44.806,349.769 ccw(c44.806,350.449) 45.286,349.968 C542.1@45.33,350.012
  L3 (Sign) w0.111: C537.6@36.22,348.698 36.22,348.174 ccw(c36.516,348.174) 36.516,347.878 ccw(c36.516,348.287) 36.805,347.998 36.931,348.124 cw(c37.801,347.254) 37.801,348.484 v7(39.195,348.484)
USB_RX_N: C543.2 U1.J25 | length 161.5
  L1 w0.135: C543.2@46.11,349.116 cw(c46.353,349.116) C543.2@46.353,349.359 ; C543.2@46.245,349.116 cw(c46.288,349.116) 46.258,349.147 cw(c46.728,348.676) 46.728,349.342 v7(46.894,349.342) ; v2(169.909,313.027) U1.J25@170.397,312.539
  L5 (Sign) w0.1: 48.089,349.383 124.365,349.383 cw(c124.365,348.945) 124.803,348.945 124.803,331.788 124.803,329.978 cw(c124.438,329.978) 124.438,329.613 123.811,329.613 ccw(c123.811,328.886) 123.084,328.886 123.084,328.399 ccw(c123.811,328.399) 123.811,327.672 124.438,327.672 cw(c124.438,327.307) 124.803,327.307 124.803,324.907 124.803,322.555 ccw(c127.705,322.555) 127.705,319.652 167.008,319.652
  L5 (Sign) w0.111: v12(47.289,349.264) 47.394,349.264 47.514,349.384 48.088,349.384 ; 167.008,319.652 167.304,319.652 cw(c167.304,319.085) 167.872,319.085 167.872,316.043 167.872,315.931 ccw(c168.537,315.931) 168.537,315.265 cw(c168.537,314.961) 168.841,314.961 168.841,314.121 cw(c168.772,314.121) v12(168.772,314.052) ; v12(168.772,314.052) 168.8,314.023 v12(168.772,314.052)
  L3 (Sign) w0.111: v7(46.894,349.342) 46.922,349.369 47.016,349.369 47.031,349.384 47.175,349.384 47.289,349.27 v12(47.289,349.264) ; v2(169.909,313.027) 169.909,313.069 ccw(c169.632,313.069) 169.632,313.346 169.461,313.346 cw(c169.461,313.966) 168.841,313.966 168.841,313.982 ccw(c168.772,313.982) v12(168.772,314.052) ; v12(168.772,314.052) 168.8,314.023 v12(168.772,314.052)
USB_RX_P: C542.2 U1.J26 | length 161.6
  L1 w0.135: C542.2@46.11,350.012 ccw(c46.353,350.012) C542.2@46.353,349.769 ; C542.2@46.245,350.012 ccw(c46.288,350.012) 46.258,349.982 ccw(c46.728,350.452) 46.728,349.787 v7(46.894,349.787) ; v2(169.909,314.027) U1.J26@170.397,313.539
  L5 (Sign) w0.1: 47.939,349.745 124.365,349.745 cw(c124.365,348.945) 125.165,348.945 125.165,331.788 125.165,329.978 cw(c124.438,329.978) 124.438,329.251 123.811,329.251 ccw(c123.811,328.886) 123.446,328.886 123.446,328.399 ccw(c123.811,328.399) 123.811,328.034 124.438,328.034 cw(c124.438,327.307) 125.165,327.307 125.165,324.907 125.165,322.555 ccw(c127.705,322.555) 127.705,320.015 167.008,320.015
  L5 (Sign) w0.111: v12(47.289,349.864) 47.394,349.864 47.514,349.745 47.939,349.745 ; 167.008,320.015 167.303,320.015 cw(c167.303,319.085) 168.233,319.085 168.233,316.193 168.233,315.931 ccw(c168.537,315.931) 168.537,315.626 cw(c168.537,314.961) 169.202,314.961 169.202,314.121 ccw(c169.272,314.121) 169.272,314.052 169.296,314.027 v12(169.36,314.027)
  L3 (Sign) w0.111: v7(46.894,349.787) 46.922,349.759 47.016,349.759 47.031,349.745 47.175,349.745 47.289,349.858 v12(47.289,349.864) ; v12(169.36,314.027) 169.296,314.027 169.272,314.052 ccw(c169.272,313.982) 169.202,313.982 169.202,313.968 ccw(c169.463,313.968) 169.463,313.707 169.632,313.707 ccw(c169.632,313.985) 169.909,313.985 v2(169.909,314.027)
USB_TX_C_N: C537.8 C541.1 D14.4 D14.7 | length 11.3
  L1 w0.1: v7(39.304,352.76) 39.877,352.76 cw(c39.877,352.692) 39.944,352.692 cw(c39.944,352.286) 40.351,352.286 40.351,352.008 ccw(c41.098,352.008) 41.098,351.261 D14.7@41.874,351.261
  L1 w0.135: D14.7@41.874,351.261 41.874,351.271 43.041,351.271 43.041,351.306 43.828,351.306 ccw(c43.828,352.131) 44.411,351.548 ; 44.412,351.549 cw(c44.629,351.331) 44.629,351.639 44.92,351.639 cw(c44.92,351.234) 45.206,351.52 C541.1@45.33,351.396
  L3 (Sign) w0.1: C537.8@36.22,352.698 36.22,353.227 cw(c36.516,353.227) 36.516,353.523 36.965,353.074 ccw(c37.72,353.829) 37.72,352.762 39.302,352.762 v7(39.304,352.76)
USB_TX_C_P: C537.9 C540.1 D14.5 D14.6 | length 11.2
  L1 w0.1: v7(39.304,353.114) 39.304,353.102 39.944,353.102 cw(c39.944,352.286) 40.761,352.286 40.761,352.008 ccw(c41.008,352.008) 41.008,351.761 D14.6@41.874,351.761
  L1 w0.135: D14.6@41.874,351.761 ccw(c41.918,351.761) 41.918,351.716 43.827,351.716 ccw(c43.827,352.134) 44.122,351.839 44.124,351.84 cw(c44.627,351.337) 44.627,352.049 44.92,352.049 ccw(c44.92,352.453) 45.206,352.167 C540.1@45.33,352.291
  L3 (Sign) w0.1: C537.9@36.22,354.698 36.22,354.169 ccw(c36.516,354.169) 36.516,353.873 ; 36.517,353.873 cw(c36.517,353.525) 36.763,353.771 36.976,353.558 ccw(c37.121,353.598) 37.081,353.453 ; 37.081,353.453 37.212,353.322 ccw(c37.721,353.831) 37.721,353.112 39.302,353.112 v7(39.304,353.114)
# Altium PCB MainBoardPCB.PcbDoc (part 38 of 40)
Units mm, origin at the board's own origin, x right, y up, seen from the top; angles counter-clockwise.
Board outline 258.95 x 308.86 mm, 16 copper layers (L1, L2 (GND), L3 (Sign), L4 (GND), L5 (Sign), L6 (PWR/GND), L7(12V+Other), L8 (Plane_GND), L9 (PWR/GND), L10 (3V3+Other), L11 (PWR/GND), L12 (Sign), L13 (GND), L14 (Sign), L15 (GND), L16), stack 2.503 mm thick; 2578 components, 1867 nets, 8817 pads, 8021 vias.
Unrouted connection lines stored in the file: 25.

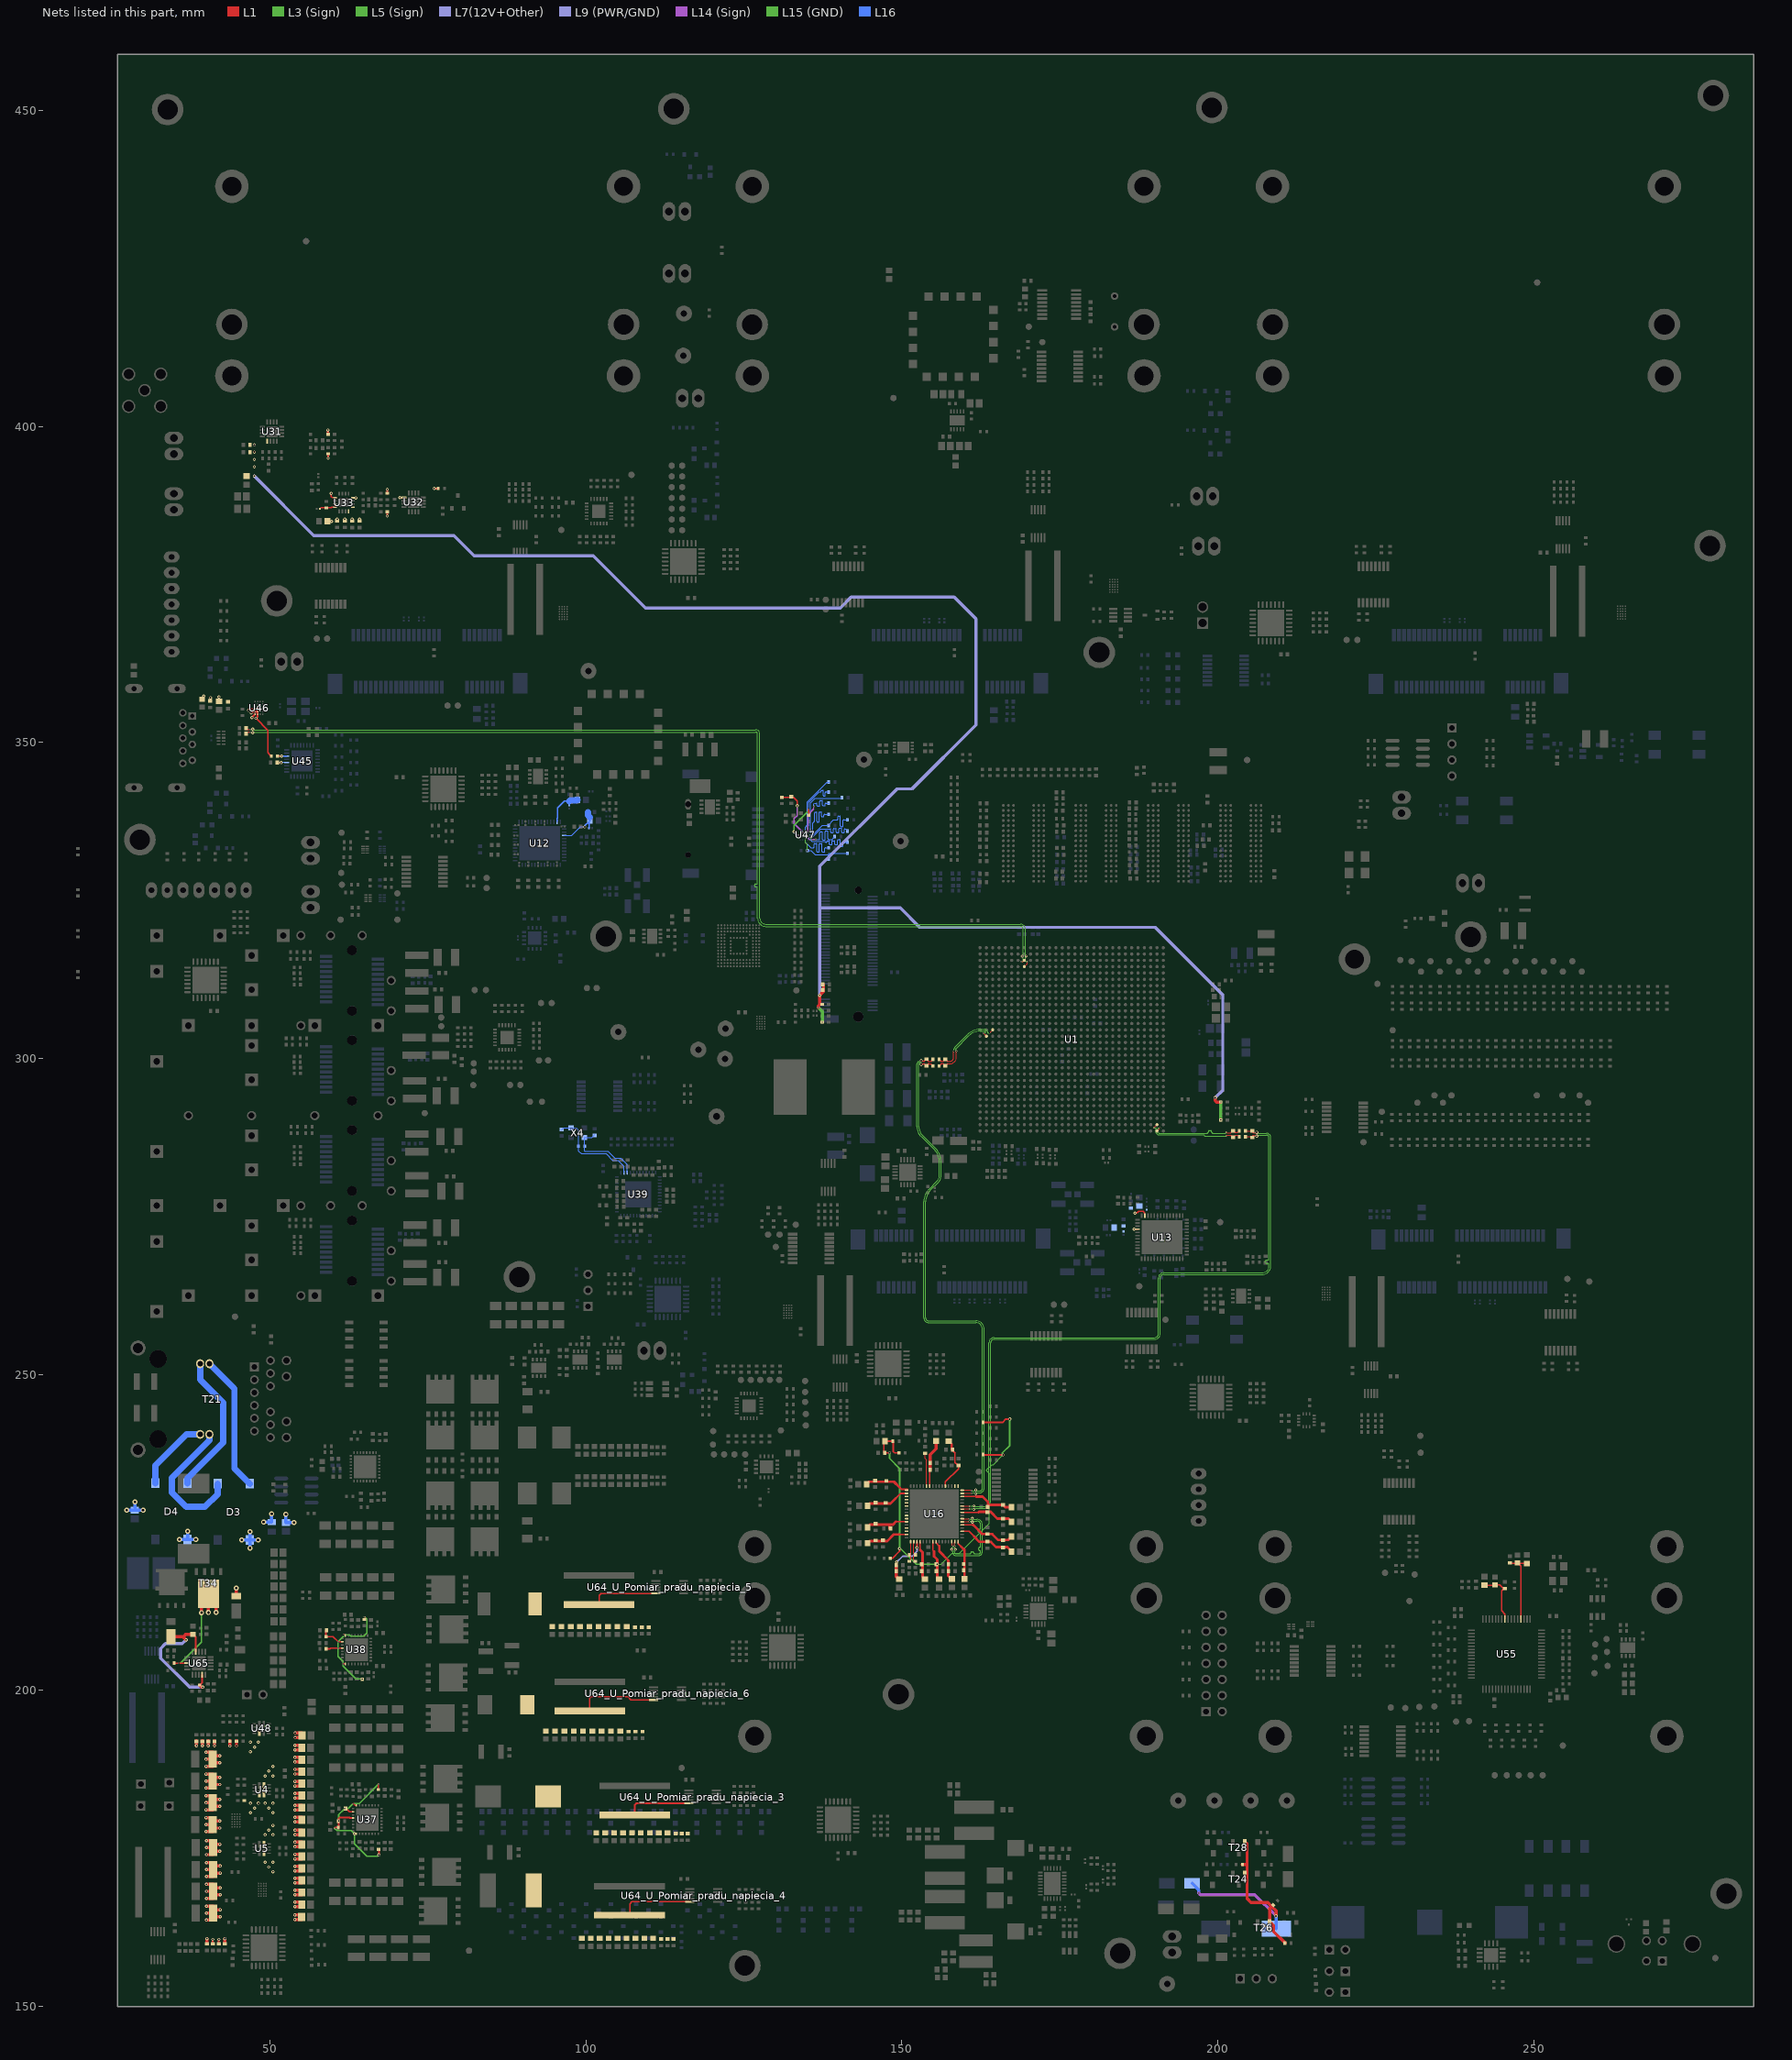
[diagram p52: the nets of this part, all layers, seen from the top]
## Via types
v1: diameter 0.5, hole 0.25, L1 to L16, tented both sides, 4341 vias
v2: diameter 0.254, hole 0.1, L1 to L3 (Sign), tented both sides, 781 vias
v3: diameter 0.5, hole 0.25, L1 to L16, 565 vias
v4: diameter 0.254, hole 0.1, L15 (GND) to L16, tented both sides, 406 vias
v5: diameter 0.254, hole 0.1, L1 to L2 (GND), tented both sides, 283 vias
v6: diameter 0.457, hole 0.2, L3 (Sign) to L6 (PWR/GND), tented both sides, 254 vias
v7: diameter 0.254, hole 0.1, L1 to L3 (Sign), 237 vias
v8: diameter 0.75, hole 0.4, L1 to L16, 200 vias
v9: diameter 0.8, hole 0.4, L1 to L16, tented both sides, 182 vias
v10: diameter 0.254, hole 0.1, L14 (Sign) to L16, tented both sides, 170 vias
v11: diameter 0.75/0/0/0/0/0/0/0/0/0/0/0/0/0/0/0.75 (per signal layer), hole 0.4, L1 to L16, 160 vias
v12: diameter 0.457, hole 0.2, L3 (Sign) to L6 (PWR/GND), 158 vias
v13: diameter 1.4, hole 0.5, L1 to L16, tented both sides, 80 vias
v14: diameter 0.254, hole 0.1, L14 (Sign) to L16, 65 vias
v15: diameter 0.254, hole 0.1, L1 to L2 (GND), 45 vias
v16: diameter 0.457, hole 0.2, L11 (PWR/GND) to L14 (Sign), tented both sides, 26 vias
v17: diameter 0.457, hole 0.2, L11 (PWR/GND) to L14 (Sign), 25 vias
v18: diameter 0.457, hole 0.2, L7(12V+Other) to L10 (3V3+Other), tented both sides, 11 vias
v19: diameter 0.254/0/0.254 (per signal layer), hole 0.1, L1 to L3 (Sign), 9 vias
v20: diameter 0.2/0/0.2 (per signal layer), hole 0.1, L1 to L3 (Sign), 6 vias
v21: diameter 1.65, hole 1.65, L1 to L16, 5 vias
v22: diameter 1.15, hole 1.15, L1 to L16, 5 vias
v23: diameter 0.457, hole 0.2, L1 to L16, 3 vias
v24: diameter 0.5, hole 0.3, L1 to L16, 2 vias
v25: diameter 0.5/0/0.5 (per signal layer), hole 0.2, L14 (Sign) to L16, 1 vias
v26: diameter 0.5, hole 0.25, L1 to L16, tented bottom, 1 vias

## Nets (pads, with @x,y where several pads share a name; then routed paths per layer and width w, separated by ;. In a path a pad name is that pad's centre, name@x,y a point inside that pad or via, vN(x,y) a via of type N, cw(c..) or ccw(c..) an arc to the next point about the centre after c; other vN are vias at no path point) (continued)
USB_TX_N: C541.2 U1.H28 | length 160.9
  L1 w0.135: C541.2@46.11,351.396 cw(c46.352,351.396) C541.2@46.352,351.639 ; C541.2@46.245,351.396 cw(c46.287,351.396) 46.257,351.426 46.271,351.439 cw(c46.71,351) 46.71,351.621 v7(46.894,351.621) ; v2(168.909,315.359) 169.216,315.359 U1.H28@169.397,315.539
  L5 (Sign) w0.1: 48.167,351.663 126.886,351.663 cw(c126.886,351.365) 127.184,351.365 127.184,328.164 127.184,327.71 cw(c127.063,327.71) 127.063,327.589 126.843,327.589 ccw(c126.843,327.468) 126.722,327.468 126.722,327.306 ccw(c126.843,327.306) 126.843,327.185 127.063,327.185 cw(c127.063,327.064) 127.184,327.064 127.184,326.724 127.184,325.535 127.184,323.99 127.184,323.342 127.184,322.205 ccw(c128.486,322.205) 128.486,320.903 168.757,320.903 cw(c168.757,320.444) 169.216,320.444
  L5 (Sign) w0.111: v12(47.289,351.544) 47.394,351.544 47.514,351.663 48.167,351.663 ; v12(169.076,316.192) 169.096,316.192 169.147,316.243 ccw(c169.147,316.312) 169.216,316.312 169.216,320.444
  L3 (Sign) w0.111: v7(46.894,351.621) 46.922,351.649 47.016,351.649 47.031,351.663 47.175,351.663 47.289,351.55 v12(47.289,351.544) ; v2(168.909,315.359) 168.922,315.346 169.151,315.346 169.216,315.411 169.216,316.033 169.202,316.047 169.202,316.187 169.198,316.192 v12(169.076,316.192) 169.096,316.192 169.147,316.243 cw(c169.147,316.173) v12@169.216,316.173
USB_TX_P: C540.2 U1.H27 | length 161.2
  L1 w0.135: C540.2@46.11,352.291 ccw(c46.352,352.291) C540.2@46.352,352.049 ; C540.2@46.245,352.291 ccw(c46.287,352.291) 46.257,352.262 46.271,352.248 ccw(c46.71,352.688) 46.71,352.066 v7(46.894,352.066) ; U1.H27@169.397,314.539 169.884,315.027 v2(169.884,315.334)
  L5 (Sign) w0.1: 48.167,352.025 126.886,352.025 cw(c126.886,351.365) 127.546,351.365 127.546,322.205 ccw(c128.486,322.205) 128.486,321.265 168.757,321.265 cw(c168.757,320.444) 169.578,320.444
  L5 (Sign) w0.111: v12(47.289,352.144) 47.394,352.144 47.514,352.024 48.167,352.024 ; 169.578,320.444 169.578,316.312 ccw(c169.647,316.312) 169.647,316.243 169.633,316.228 169.654,316.207 v12(169.704,316.207)
  L3 (Sign) w0.111: v7(46.894,352.066) 46.922,352.039 47.016,352.039 47.031,352.024 47.175,352.024 47.289,352.138 v12(47.289,352.144) ; v12@169.577,316.173 cw(c169.647,316.173) 169.647,316.243 169.633,316.228 169.654,316.207 v12(169.704,316.207) 169.611,316.207 169.592,316.187 169.592,316.047 169.577,316.033 169.577,315.411 169.642,315.346 169.872,315.346 v2(169.884,315.334)
USB_Vbus: R490.1 U45.22 | length 1.5
  L1 w0.2: R490.1@51.156,347.841 51.16,347.845 v1(51.853,347.845)
  L16 w0.2: v1(51.853,347.845) 51.857,347.841 U45.22@52.655,347.841
USB_Vdd33: C731.2 U45.20 | length 1.6
  L1 w0.12: C731.2@51.019,346.841 51.115,346.937 51.233,346.819 v1(51.793,346.819)
  L16 w0.12: v1@51.566,346.837 51.606,346.877 52.255,346.877
USB_Vout: C538.1 C539.2 C734.1 FB26.1 R490.2 U46.C2 U46.D1 U46.D2 U46.E1 U46.E2 U46.F1 U46.F2 | length 11.9
  L1 w0.2: v1(47.783,353.842) 49.675,351.95 49.675,348.422 50.006,348.091 50.006,348.041 R490.2@50.206,347.841 R490.2@50.256,347.841
  L1 w0.3: v1(46.602,355.082) 46.811,355.29 U46.D2@48.075,355.29 U46.C2@48.075,355.69 ; v1(47.034,354.655) 47.269,354.89 U46.E2@48.075,354.89 48.075,354.134 v1(47.783,353.842) ; v1@47.235,354.05 U46.F1@47.675,354.49
  other v1: 47.175,353.94 40.594,357.095 41.948,357.214 39.535,357.34
uSD_CD: R381.1 R782.1 R845.2 U47.D3 | length 9.8
  L15 (GND) w0.12: v4(134.729,335.004) 134.729,334.15 135.026,333.853 v4(135.026,332.909)
  L16 w0.12: v4(135.026,332.909) 135.616,332.909 136.269,332.257 138.475,332.257 ; 138.468,332.473 R782.1@141.458,332.473 ; R381.1@138.475,331.584 138.475,332.257 ; 138.475,332.466 138.475,332.257
uSD_CLK: R96.2 R97.1 U47.C1 | length 9.9
  L16 w0.12: U47.C1@135.529,335.404 135.913,335.404 137.427,336.918 138.367,336.918 139.224,337.776 139.268,337.776 139.776,337.776 ccw(c139.776,337.882) 139.883,337.882 139.883,338.265 cw(c139.989,338.265) 139.989,338.371 140.201,338.371 cw(c140.201,338.265) 140.307,338.265 140.307,337.776 140.307,336.822 ccw(c140.414,336.822) 140.414,336.715 140.626,336.715 ccw(c140.626,336.822) 140.732,336.822 140.732,337.669 cw(c140.838,337.669) 140.838,337.776 140.945,337.776 R96.2@141.458,337.776
uSD_CMD: R95.2 U47.D2 | length 9.5
  L14 (Sign) w0.2: v10(135.129,335.004) 135.454,334.68 v10(136.398,334.68)
  L16 w0.12: v10(136.398,334.68) 136.4,334.678 136.614,334.678 136.69,334.678 136.942,334.678 ccw(c136.942,334.784) 137.048,334.784 137.048,335.751 cw(c137.154,335.751) 137.154,335.858 137.367,335.858 cw(c137.367,335.751) 137.473,335.751 137.473,334.678 ccw(c137.579,334.678) 137.579,334.571 137.791,334.571 ccw(c137.791,334.678) 137.898,334.678 137.898,335.898 cw(c138.004,335.898) 138.004,336.005 138.216,336.005 cw(c138.216,335.898) 138.322,335.898 138.322,334.784 ccw(c138.429,334.784) 138.429,334.678 138.747,334.678 138.96,334.678 R95.2@139.41,335.128
uSD_D0: R87.2 U47.D1 | length 10
  L16 w0.12: U47.D1@135.529,335.004 135.824,335.004 137.166,336.347 138.532,336.347 138.676,336.347 cw(c138.676,336.241) 138.783,336.241 138.783,335.866 ccw(c138.889,335.866) 138.889,335.76 139.101,335.76 ccw(c139.101,335.866) 139.207,335.866 139.207,336.347 cw(c139.277,336.347) 139.277,336.417 139.562,336.417 cw(c139.562,336.347) 139.632,336.347 139.632,335.866 ccw(c139.738,335.866) 139.738,335.76 139.951,335.76 ccw(c139.951,335.866) 140.057,335.866 140.057,336.347 cw(c140.152,336.347) 140.152,336.442 140.387,336.442 cw(c140.387,336.347) 140.482,336.347 140.482,335.866 ccw(c140.588,335.866) 140.588,335.76 140.8,335.76 ccw(c140.8,335.866) 140.907,335.866 140.907,336.241 cw(c141.013,336.241) 141.013,336.347 141.119,336.347 R87.2@141.458,336.008
uSD_D1: R88.2 U47.E1 | length 10
  L16 w0.12: U47.E1@135.529,334.604 135.802,334.331 137.831,334.331 137.922,334.241 138.039,334.241 ccw(c138.039,334.347) 138.145,334.347 138.145,334.322 cw(c138.252,334.322) 138.252,334.428 138.464,334.428 cw(c138.464,334.322) 138.57,334.322 138.57,334.241 138.57,333.944 ccw(c138.676,333.944) 138.676,333.838 138.889,333.838 ccw(c138.889,333.944) 138.995,333.944 138.995,334.241 138.995,334.354 cw(c139.101,334.354) 139.101,334.461 139.314,334.461 cw(c139.314,334.354) 139.42,334.354 139.42,334.241 139.42,333.944 ccw(c139.526,333.944) 139.526,333.838 139.738,333.838 ccw(c139.738,333.944) 139.845,333.944 139.845,334.241 139.845,334.532 cw(c139.951,334.532) 139.951,334.638 140.163,334.638 cw(c140.163,334.532) 140.269,334.532 140.269,334.241 140.269,333.705 ccw(c140.376,333.705) 140.376,333.599 140.588,333.599 ccw(c140.588,333.705) 140.694,333.705 140.694,334.134 cw(c140.8,334.134) 140.8,334.241 140.906,334.241 R88.2@141.458,334.241
uSD_D2: R89.2 U47.A1 | length 9.6
  L16 w0.12: U47.A1@135.529,336.204 135.529,340.431 136.271,341.173 140.37,341.173 R89.2@140.508,341.31
uSD_D3: R90.2 U47.B1 | length 9.7
  L16 w0.12: U47.B1@135.527,335.804 135.754,335.804 135.913,335.963 135.913,337.246 136.073,337.406 136.133,337.466 ccw(c136.02,337.579) 136.18,337.579 136.18,338.877 cw(c136.273,338.877) 136.273,338.971 136.46,338.971 cw(c136.46,338.877) 136.554,338.877 136.554,337.52 ccw(c136.647,337.52) 136.647,337.427 136.834,337.427 ccw(c136.834,337.52) 136.928,337.52 136.928,338.911 cw(c137.021,338.911) 137.021,339.005 137.208,339.005 cw(c137.208,338.911) 137.302,338.911 137.302,338.35 ccw(c137.395,338.35) 137.395,338.257 137.582,338.257 ccw(c137.582,338.35) 137.676,338.35 137.676,338.5 cw(c137.796,338.5) 137.796,338.62 138.1,338.62 138.455,338.62 R90.2@138.475,338.641
uSD_D4: R91.1 U47.B2 | length 9.5
  L14 (Sign) w0.12: v10(136.093,339.916) 136.093,339.509 136.106,339.497
  L14 (Sign) w0.2: v10(135.129,335.804) 135.129,338.52 136.106,339.497
  L16 w0.12: v10(136.093,339.916) 136.093,340.296 136.201,340.405 136.322,340.405 136.507,340.405 cw(c136.507,340.299) 136.613,340.299 136.613,340.048 ccw(c136.719,340.048) 136.719,339.942 136.932,339.942 ccw(c136.932,340.048) 137.038,340.048 137.038,340.405 137.038,340.703 cw(c137.144,340.703) 137.144,340.809 137.356,340.809 cw(c137.356,340.703) 137.463,340.703 137.463,340.405 137.463,340.129 ccw(c137.569,340.129) 137.569,340.023 137.781,340.023 ccw(c137.781,340.129) 137.887,340.129 137.887,340.299 cw(c137.994,340.299) 137.994,340.405 138.1,340.405 R91.1@138.475,340.405
uSD_D5: R92.1 U47.A2 | length 9.8
  L16 w0.12: U47.A2@135.129,336.204 135.129,336.714 135.309,336.894 135.309,340.522 136.963,342.176 137.058,342.176 137.118,342.176 ccw(c137.118,342.296) 137.238,342.296 137.238,342.371 cw(c137.319,342.371) 137.319,342.451 137.481,342.451 cw(c137.481,342.371) 137.562,342.371 137.562,341.611 ccw(c137.642,341.611) 137.642,341.53 137.804,341.53 ccw(c137.804,341.611) 137.885,341.611 137.885,342.056 cw(c138.005,342.056) 138.005,342.176 138.386,342.176 138.468,342.176 R92.1@138.475,342.169
uSD_D6: R93.1 U47.A3 | length 9.3
  L16 w0.12: U47.A3@134.729,336.204 134.729,336.625 135.089,336.985 135.089,340.613 138.176,343.7 R93.1@138.506,343.7
uSD_D7: R94.1 U47.E3 | length 9.4
  L16 w0.12: U47.E3@134.729,334.604 134.729,334.234 135.615,333.348 135.7,333.348 136.019,333.348 ccw(c136.019,333.455) 136.125,333.455 136.125,333.915 cw(c136.231,333.915) 136.231,334.021 136.443,334.021 cw(c136.443,333.915) 136.55,333.915 136.55,333.348 136.55,332.792 ccw(c136.656,332.792) 136.656,332.686 136.868,332.686 ccw(c136.868,332.792) 136.974,332.792 136.974,333.348 136.974,333.915 cw(c137.081,333.915) 137.081,334.021 137.293,334.021 cw(c137.293,333.915) 137.399,333.915 137.399,333.348 137.399,332.792 ccw(c137.505,332.792) 137.505,332.686 137.718,332.686 ccw(c137.718,332.792) 137.824,332.792 137.824,333.242 cw(c137.93,333.242) 137.93,333.348 138.036,333.348 R94.1@138.475,333.348
V_KEY: C609.2 D24.2 R647.1 R648.1 R653.1 T24.1 T26.1 T28.1 | length 41.2
  L1 w0.5: R653.1@203.866,172.467 204.611,172.467 204.648,172.504 ; T28.1@204.277,176.105 204.648,175.734 204.648,172.504 ; T24.1@204.29,171.114 204.624,171.114 204.648,171.09 ; v1(209.232,164.325) 209.232,165.14 208.554,165.818 ; R648.1@210.688,160.033 208.827,161.893 208.827,162.805 T26.1@208.214,163.418 208.214,165.479 208.554,165.818 ; 204.648,171.09 204.648,172.504 ; 204.648,171.09 204.648,167.081 205.296,166.433 207.939,166.433 208.554,165.818
  L14 (Sign) w0.5: v10(197.002,167.945) 197.252,167.696 205.862,167.696 v1(209.232,164.325)
  L16 w0.5: D24.2@195.954,169.495 197.002,168.447 v10(197.002,167.945) ; v1(209.232,164.325) 209.232,162.395 C609.2@209.295,162.332
V_PoE+: C595.2 C596.2 D3.1 D4.1 D27.1 R149.2 R324.2 T34.5 U65.18 | length 35.1
  L1 w0.12: v2(35.547,204.318) v2@35.56,204.318
  L1 w0.254: R149.2@34.773,204.343 34.798,204.318 v2(35.547,204.318) ; v2@35.56,204.318 U65.18@36.92,204.318
  L1 w0.5: v9(39.187,212.32) T34.5@39.187,213.614 ; v9(40.282,212.342) T34.5@40.282,213.636 ; v9(41.478,212.347) T34.5@41.478,213.641 ; D27.1@44.666,214.897 v9(44.666,216.191)
  L3 (Sign) w0.2: v2(35.547,204.318) 35.859,204.318 39.187,207.646 v9(39.187,212.32)
  L16 w0.5: v9(27.345,228.551) C595.2@28.639,228.551 ; v9(28.639,229.845) C595.2@28.639,228.551 ; v9(29.932,228.551) C595.2@28.639,228.551 ; v9(35.686,223.896) D4.1@36.98,223.896 ; v9(36.98,225.19) D4.1@36.98,223.896 ; v9(38.274,223.896) D4.1@36.98,223.896 ; v9(45.554,223.832) D3.1@46.848,223.832 ; v9(46.848,222.539) D3.1@46.848,223.832 ; v9(46.848,225.126) D3.1@46.848,223.832 ; v9(48.141,223.832) D3.1@46.848,223.832 ; v9(48.998,226.657) R324.2@50.292,226.657 v9(50.292,227.951) ; v9(52.54,227.889) C596.2@52.54,226.595 v9(53.834,226.595)
VBB: C344.2 R257.1 U33.3 U33.4 | length 3
  L1 w0.2: C344.2@57.918,387 57.918,387.01 57.968,387.06 57.978,387.06 58.103,387.185 58.922,387.185 59.68,387.185 59.73,387.235 U33.4@60.319,387.235 U33.3@60.319,387.735
VC1~: D3.4 T21.13 | length 21.6
  L16 w1: T21.13@40.432,251.716 44.386,247.762 44.386,235.194 D3.4@46.848,232.732
VC2~: D3.3 T21.14 | length 22.4
  L16 w1: T21.14@40.432,240.536 40.432,239.625 34.468,233.66 34.468,231.356 36.767,229.057 39.738,229.057 41.748,231.066 D3.3@41.748,232.732
VC3~: D4.4 T21.15 | length 22.8
  L16 w1: D4.4@36.98,232.796 36.98,233.601 42.608,239.23 42.608,245.567 38.972,249.203 T21.15@38.972,251.716
VC4~: D4.3 T21.16 | length 11.9
  L16 w1: D4.3@31.88,232.796 31.88,235.613 36.803,240.536 T21.16@38.972,240.536
Vcc_CLK_Mux_Fine: C326.1 C327.1 C328.1 C329.1 FB23.2 R125.1 R250.1 R251.1 R259.1 R260.1 R386.1 R486.1 R488.2 R538.1 U31.5 U32.5 | length 297.4
  L1 w0.3: R250.1@59.189,398.76 v1(59.189,399.449) ; v1(59.222,394.996) R251.1@59.222,395.685 ; v1(68.58,385.864) R260.1@68.58,386.553 ; R259.1@68.58,389.383 68.58,389.405 v1(68.58,390.073) ; v1(70.573,388.759) U32.5@71.262,388.759 ; v1(75.985,390.204) R488.2@76.674,390.204
  L1 w0.5: v2(136.766,308.077) 136.766,308.318 137.02,308.572 v1(137.02,310.007) 137.632,310.619 C328.1@137.632,311.721 ; v1(199.589,293.789) 199.589,293.345 199.833,293.102 v2(200.49,293.102) ; v2(200.482,290.317) R386.1@200.49,290.309
  L9 (PWR/GND) w0.5: v1(47.548,392.159) 56.942,382.765 79.121,382.765 82.334,379.552 101.168,379.552 109.449,371.272 140.26,371.272 141.987,372.999 158.305,372.999 161.722,369.583 161.722,352.763 151.63,342.671 149.253,342.671 137.02,330.439 137.02,323.837 ; v1(137.02,310.007) 137.02,323.837 ; v1(199.589,293.789) 200.808,295.008 200.808,310.075 190.119,320.764 152.835,320.764 149.761,323.837 137.02,323.837
  L3 (Sign) w0.5: v2(136.766,308.077) 137.421,307.422 v2(137.421,305.772) ; v2(200.482,290.317) 200.482,293.094 v2(200.49,293.102)
  other v1: 47.548,393.611 47.548,394.803 47.548,395.968 47.548,397.075
VCCINT: C598.2 D26.2 R669.1 U65.4 U65.14 | length 24.4
  L1 w0.254: C598.2@37.846,208.912 38.26,208.498 U65.14@38.26,206.158 ; R669.1@38.887,200.831 39.26,201.204 U65.4@39.26,202.478
  L1 w0.5: D26.2@34.353,208.547 36.347,208.547 ; v1(36.741,208.019) 36.347,208.413 36.347,208.547 ; C598.2@37.846,208.912 36.713,208.912 36.347,208.547 ; R669.1@38.887,200.831 39.207,200.511 v1(39.387,200.511)
  L7(12V+Other) w0.5: v1(36.741,208.019) 36.129,207.407 33.477,207.407 32.687,206.616 32.687,205.136 37.311,200.511 v1(39.387,200.511)
VCCO_1: C398.1 R289.2 R293.2 R295.1 R296.1 U37.2 U37.4 U37.9 U37.32 | length 27.6
  L1 w0.2: v2(60.236,178.219) 60.334,178.317 R293.2@60.881,178.317 ; v2(61.848,181.317) 62.11,181.317 62.61,180.817 U37.2@63.175,180.817
  L1 w0.254: R293.2@60.881,178.317 R289.2@60.881,179.317 ; R289.2@60.881,179.361 60.881,179.717 61.08,179.915 62.591,179.915 62.69,179.817 U37.4@63.175,179.817 ; v2(63.182,182.131) 63.496,181.817 U37.32@63.675,181.817 ; R295.1@67.169,184.3 67.169,185.14 v2(67.183,185.153) ; R296.1@67.204,174.917 67.259,174.861 v1(67.259,173.965)
  L5 (Sign) w0.254: v1(63.41,177.317) 63.41,175.728 65.377,173.761 67.056,173.761 v1(67.259,173.965)
  L3 (Sign) w0.2: v2(60.236,178.219) 60.602,177.853 62.874,177.853 v1(63.41,177.317)
  L3 (Sign) w0.254: v2(60.884,179.361) 60.884,180.352 v2(61.848,181.317) 62.368,181.317 v2(63.182,182.131) 64.16,182.131 v2(67.183,185.153)
VCCO_2: C439.1 R307.2 R310.2 R313.1 R314.1 U38.2 U38.4 U38.9 U38.32 | length 23.8
  L1 w0.2: v2(61.575,204.216) 61.951,204.216 U38.9@61.953,204.214 ; v2(61.658,208.788) 61.669,208.778 61.928,208.778 61.953,208.753 U38.32@61.953,208.714 ; R313.1@64.953,211.254 v7(64.953,211.629)
  L1 w0.254: R307.2@58.845,206.596 59.525,206.596 59.643,206.714 v7(60.815,206.714) U38.4@61.453,206.714 ; C439.1@58.845,209.529 58.845,208.526 60.003,208.526 v2(60.815,207.714) U38.2@61.453,207.714
  L3 (Sign) w0.2: v2(64.623,201.823) 63.602,201.823 61.575,203.851 v2(61.575,204.216) 61.575,204.617 60.815,205.377 v7(60.815,206.714) v2(60.815,207.714) 61.658,208.558 v2(61.658,208.788) 62.62,208.788 62.807,208.601 64.84,208.601 65.328,209.089 65.328,211.254 v7(64.953,211.629)
VDD_APLL1: C88.1 C110.2 FB13.2 U16.49 | length 7
  L1 w0.3: 149.657,232.141 149.934,231.864 150.876,231.864
  L1 w0.4: FB13.2@144.469,232.658 144.843,233.031 147.567,233.031 148.767,233.031 149.657,232.141
VDD_APLL2: C89.1 C127.2 FB15.2 U16.37 | length 8.7
  L1 w0.2: U16.37@156.915,232.345 156.915,233.018 158.972,235.075 C89.1@158.972,235.63 158.922,235.63 158.447,236.105 158.447,237.499 158.471,237.522 157.907,238.086 C127.2@157.902,238.086
  L1 w0.3: FB15.2@157.404,239.452 157.454,239.452 157.902,239.004 C127.2@157.902,238.086
VDD_CLK_MUX_DIV_3.3V: C336.2 C337.2 C338.2 C340.1 FB24.2 U33.1 U33.8 U33.9 U33.12 | length 1.2
  L1 w0.2: v1(59.715,389.433) 59.715,388.925 59.905,388.735 U33.1@60.319,388.735
  other v1: 59.78,385.003 63.008,385.355 64.184,385.349 60.666,385.37 61.848,385.37 63.591,388.722
VDD_DIG: C93.1 C165.2 C590.2 FB21.2 FB37.1 R127.2 R128.2 R129.2 R366.1 R544.2 U16.8 | length 75.1
  L1 w0.254: v1(148.076,237.642) 148.056,237.622 147.195,237.622 147.175,237.602 147.175,239.249 FB37.1@147.37,239.444 148.641,239.444 148.641,237.837 148.876,237.602 R366.1@149.606,237.602 ; R127.2@148.141,220.935 148.549,220.935 149.657,222.044 v1(149.657,222.427) ; U16.8@154.915,223.545 154.915,222.185 155.097,222.003 ; R128.2@162.832,242.418 165.929,242.418 166.462,242.951 v1(167.094,242.951) ; R129.2@162.893,237.279 v1(166.05,237.279)
  L1 w0.4: 155.097,222.003 155.097,221.227 155.601,220.723 155.601,217.876 155.851,217.626 FB21.2@155.893,217.626
  L5 (Sign) w0.254: v1(148.076,237.642) 148.076,236.729 149.657,235.147 v1(149.657,222.427) 149.704,222.38 149.892,222.38 152.301,219.97 v1(155.609,219.97) ; v1@165.922,237.474 165.922,237.618 167.094,238.789 v1(167.094,242.951)
  L3 (Sign) w0.12: v1(155.609,219.97) 156.249,219.97 157.97,221.692 159.108,221.692 163.881,226.464 163.881,234.339 163.441,234.78 163.441,234.892 164.261,235.712 164.483,235.712 v1(166.05,237.279)
VDD_IN0: C63.1 C101.2 FB8.2 U16.3 | length 7.9
  L1 w0.254: v1(152.415,222.592) U16.3@152.415,223.545
  L1 w0.5: C63.1@149.157,219.859 149.157,218.007 149.538,217.626 FB8.2@149.588,217.626
  L9 (PWR/GND) w0.254: v1(149.218,220.344) 150.129,221.255 151.671,221.255 152.415,221.998 v1(152.415,222.592)
VDD_IN1: C64.1 C105.2 FB10.2 U16.16 | length 6.3
  L1 w0.2: U16.16@158.915,223.545 158.915,223.244 159.364,222.795
  L1 w0.4: 159.364,222.795 159.938,222.221 159.938,220.015 159.938,219.01 FB10.2@159.938,217.653
VDD_IN2: C67.1 C109.2 FB12.2 U16.9 | length 7
  L1 w0.2: U16.9@155.415,223.545 155.415,223.365 155.94,222.841
  L1 w0.4: 155.94,222.841 155.94,222.038 157.365,220.613 157.365,218.153 157.865,217.653 FB12.2@157.915,217.653
VDD_IN3: C70.1 C126.2 FB14.2 U16.4 | length 6.3
  L1 w0.2: U16.4@152.915,223.545 152.92,223.545 152.92,222.221
  L1 w0.4: 152.92,222.221 153.28,221.861 153.28,219.97 153.28,218.896 153.28,218.016 153.37,217.926 153.37,217.876 153.62,217.626 FB14.2@153.67,217.626
VDD_TCXO: C92.1 C148.2 FB19.2 U16.19 | length 9.2
  L1 w0.2: U16.19@159.565,225.195 160.641,225.195 161.461,224.376
  L1 w0.4: 161.461,224.376 162.32,223.517 164.101,223.517 164.921,222.696 166.719,222.696 167.369,222.046 FB19.2@167.369,221.996
VDD_XO: C90.1 C144.2 FB17.2 U16.42 | length 7.6
  L1 w0.2: U16.42@154.415,232.345 154.415,234.799 C144.2@154.504,234.888
  L1 w0.5: C144.2@154.504,234.888 C90.1@154.504,236.017 154.504,237.334 155.435,238.266 FB17.2@155.435,239.482
VDDO_0: C75.1 C143.2 FB16.2 U16.21 | length 9
  L1 w0.2: U16.21@159.565,226.195 161.309,226.195
  L1 w0.4: 161.309,226.195 161.324,226.195 162.765,224.754 164.321,224.754 165.264,223.811 166.043,223.811 166.831,223.811 167.069,224.048 167.119,224.048 167.369,224.298 FB16.2@167.369,224.348
VDDO_1: C76.1 C147.2 FB18.2 U16.25 | length 8.5
  L1 w0.2: U16.25@159.565,228.195 162.142,228.195
  L1 w0.4: 162.142,228.195 162.22,228.273 164.072,228.273 165.134,227.211 C147.2@166.003,227.211 166.008,227.206 166.908,227.206 167.369,226.745 FB18.2@167.369,226.695
VDDO_6: C77.1 C164.2 FB20.2 U16.59 | length 7.3
  L1 w0.2: 149.089,226.733 ccw(c149.127,226.733) 149.127,226.695 U16.59@150.765,226.695
  L1 w0.4: FB20.2@144.577,225.818 144.577,225.868 144.975,226.266 145.847,226.266 148.056,226.266 ; C77.1@148.095,225.611 148.056,225.65 148.056,226.266 ; 149.089,226.733 148.621,226.266 148.056,226.266
VDDO_7: C81.1 C180.2 FB22.2 U16.63 | length 6.8
  L1 w0.2: 149.712,224.695 U16.63@150.765,224.695
  L1 w0.4: FB22.2@144.577,223.318 144.577,223.368 144.827,223.618 144.877,223.618 144.899,223.641 147.697,223.641 148.752,224.695 149.712,224.695
VDDO_23: C82.1 C102.2 FB9.2 U16.30 | length 9.2
  L1 w0.2: U16.30@159.565,230.695 161.765,230.695
  L1 w0.4: 161.765,230.695 162.815,230.695 163.617,229.893 C82.1@163.617,229.095 ; C82.1@163.617,229.045 C82.1@163.617,229.095 ; FB9.2@167.369,229.023 166.362,229.023 166.128,229.258 166.128,229.281 166.053,229.356 C102.2@166.003,229.356 163.878,229.356 C82.1@163.617,229.095
VDDO_45: C83.1 C106.2 FB11.2 U16.50 | length 7
  L1 w0.3: 149.033,230.397 149.832,231.195 U16.50@150.765,231.195
  L1 w0.4: FB11.2@144.599,229.212 144.599,229.262 144.935,229.598 145.847,229.598 148.235,229.598 149.033,230.397
VLDO: C544.2 R383.1 U47.B4 | length 8.3
  L1 w0.2: R383.1@131.039,341.273 131.068,341.303 132.867,341.303 133.456,340.714 v1(133.456,339.992)
  L14 (Sign) w0.2: v1(133.456,339.992) 133.456,338.454 132.969,337.967 132.969,337.165 v10(134.329,335.804)
Vout1_1: C406.2 C407.2 C408.1 C409.2 C410.2 C411.2 C412.2 C413.2 C414.2 C415.2 C416.2 C417.2 L11.2 R448_U_Pomiar_pradu_napiecia_3.1 U64_U_Pomiar_pradu_napiecia_3.10 | length 10.2
  L1 w0.3: R448_U_Pomiar_pradu_napiecia_3.1@107.759,180.301 107.759,181.902 108.017,182.159 U64_U_Pomiar_pradu_napiecia_3.10@116.278,182.159
Vout1_2: C447.2 C448.2 C449.1 C450.2 C451.2 C452.2 C453.2 C454.2 C455.2 C456.2 C457.2 C458.2 L19.2 R448_U_Pomiar_pradu_napiecia_5.1 U64_U_Pomiar_pradu_napiecia_5.10 | length 10.6
  L1 w0.2: R448_U_Pomiar_pradu_napiecia_5.1@102.092,213.587 102.092,215.032 102.453,215.393 102.498,215.348 U64_U_Pomiar_pradu_napiecia_5.10@111.071,215.348
Vout2_1: C418.2 C419.2 C420.1 C421.2 C422.2 C423.2 C424.2 C425.2 C426.2 C427.2 C428.2 C429.2 L12.2 R448_U_Pomiar_pradu_napiecia_4.1 U64_U_Pomiar_pradu_napiecia_4.10 | length 15.1
  L1 w0.2: R448_U_Pomiar_pradu_napiecia_4.1@103.227,164.438 R448_U_Pomiar_pradu_napiecia_4.1@106.904,164.438 106.957,164.491 106.957,166.252 107.264,166.56 U64_U_Pomiar_pradu_napiecia_4.10@116.449,166.56
Vout2_2: C459.2 C460.2 C461.1 C462.2 C463.2 C464.2 C465.2 C466.2 C467.2 C468.2 C469.2 C470.2 L20.2 R448_U_Pomiar_pradu_napiecia_6.1 U64_U_Pomiar_pradu_napiecia_6.10 | length 12.5
  L1 w0.2: R448_U_Pomiar_pradu_napiecia_6.1@100.635,196.76 100.617,196.778 100.617,198.788 100.838,199.009 106.66,199.009 107.16,198.508 U64_U_Pomiar_pradu_napiecia_6.10@110.741,198.508
Vout_1_Selector: C4.1 C5.1 C6.1 C7.1 C8.2 C9.2 C10.2 C11.2 C20.2 C21.2 C22.2 C23.2 C24.2 C25.2 C26.2 C27.2 R15.2 U4.7 U5.1 U5.8 | length 42
  L1 w0.3: C10.2@40.975,159.932 v1(40.975,160.611) ; C11.2@41.91,159.932 v1(41.91,160.611)
  L1 w0.5: v1(39.961,163.667) C4.1@41.048,163.667 ; v1(39.961,164.772) C4.1@41.048,164.772 ; v1(39.961,165.868) C4.1@41.048,165.868 ; v1(39.961,167.121) C5.1@41.048,167.121 ; v1(39.961,168.226) C5.1@41.048,168.226 ; v1(39.961,169.323) C5.1@41.048,169.323 ; v1(39.961,170.575) C7.1@41.048,170.575 ; v1(39.961,171.68) C7.1@41.048,171.68 ; v1(39.961,172.777) C7.1@41.048,172.777 ; v1(39.961,174.03) C6.1@41.048,174.03 ; v1(39.961,175.135) C6.1@41.048,175.135 ; v1(39.961,176.232) C6.1@41.048,176.232 ; C9.2@40.046,159.932 v1(40.046,160.746) ; C4.1@41.048,164.215 v1(42.135,164.215) ; C4.1@41.048,165.32 v1(42.135,165.32) ; C5.1@41.048,167.669 v1(42.135,167.669) ; C5.1@41.048,168.774 v1(42.135,168.774) ; C7.1@41.048,171.124 v1(42.135,171.124) ; C7.1@41.048,172.229 v1(42.135,172.229) ; C6.1@41.048,174.578 v1(42.066,174.578) ; C6.1@41.048,175.683 v1(42.066,175.683) ; C8.2@42.89,159.932 v1(42.89,160.745) ; v1(53.932,163.773) C20.2@55.019,163.774 ; v1(53.932,164.497) C20.2@55.019,164.497 ; v1(53.959,166.505) C27.2@55.046,166.505 ; v1(53.959,168.403) C22.2@55.046,168.403 ; v1(53.959,170.301) C21.2@55.046,170.301 ; v1(53.959,172.199) C24.2@55.046,172.199 ; v1(53.959,174.096) C25.2@55.046,174.096 ; v1(53.959,175.994) C23.2@55.046,175.994 ; v1(53.959,165.781) C27.2@55.046,165.781 ; v1(53.959,167.679) C22.2@55.046,167.679 ; v1(53.959,169.577) C21.2@55.046,169.577 ; v1(53.959,171.475) C24.2@55.046,171.475 ; v1(53.959,173.373) C25.2@55.046,173.373 ; v1(53.959,175.27) C23.2@55.046,175.27 ; v1(53.989,177.168) C26.2@55.076,177.168 ; v1(53.989,177.892) C26.2@55.076,177.892
  other v1: 50.48,171.336 49.821,172.073 49.233,172.838 50.481,172.838 49.233,177.161 50.481,177.161 49.821,177.926 50.48,178.663 46.94,180.658 47.599,181.395 46.939,182.16 48.188,182.16
  other v3: 49.06,174.6 49.06,175.4 48.36,183.921
Vout_2_Selector: C12.1 C13.1 C14.1 C15.1 C16.2 C17.2 C18.2 C19.2 C28.2 C29.2 C30.2 C31.2 C32.2 C33.2 C34.2 C35.2 R677.2 R678.2 U4.1 U4.8 U48.7 | length 44
  L1 w0.5: v1(38.398,191.245) C16.2@38.398,192.058 ; v1(39.328,191.261) C19.2@39.328,192.075 ; v1(39.88,177.689) C12.1@40.967,177.689 ; v1(39.88,178.794) C12.1@40.967,178.794 ; v1(39.88,179.891) C12.1@40.967,179.891 ; v1(39.88,181.134) C15.1@40.967,181.134 ; v1(39.88,182.239) C15.1@40.967,182.239 ; v1(39.88,183.336) C15.1@40.967,183.336 ; v1(39.88,184.579) C13.1@40.967,184.579 ; v1(39.88,185.684) C13.1@40.967,185.684 ; v1(39.88,186.781) C13.1@40.967,186.781 ; v1(39.88,188.024) C14.1@40.967,188.024 ; v1(39.88,189.129) C14.1@40.967,189.129 ; v1(39.88,190.226) C14.1@40.967,190.226 ; v1(40.234,191.261) C18.2@40.234,192.075 ; C12.1@40.967,178.237 v1(42.054,178.237) ; C12.1@40.967,179.342 v1(42.054,179.342) ; C15.1@40.967,181.682 v1(42.054,181.682) ; C15.1@40.967,182.787 v1(42.054,182.787) ; C13.1@40.967,185.127 v1(42.054,185.127) ; C13.1@40.967,186.232 v1(42.054,186.232) ; C14.1@40.967,188.573 v1(42.054,188.573) ; C14.1@40.967,189.678 v1(42.054,189.678) ; v1(41.232,191.261) C17.2@41.232,192.075 ; v1(43.658,191.22) R678.2@43.658,192.033 ; v1(44.716,191.22) R677.2@44.716,192.033 ; v1(53.971,179.205) C31.2@55.058,179.205 ; v1(53.971,179.929) C31.2@55.058,179.929 ; v1(53.971,181.103) C30.2@55.058,181.103 ; v1(53.971,181.827) C30.2@55.058,181.827 ; v1(53.971,183.001) C32.2@55.058,183.001 ; v1(53.971,183.725) C32.2@55.058,183.725 ; v1(53.971,184.899) C29.2@55.058,184.899 ; v1(53.971,185.623) C29.2@55.058,185.623 ; v1(53.971,186.796) C28.2@55.058,186.796 ; v1(53.971,187.52) C28.2@55.058,187.52 ; v1(53.971,188.694) C33.2@55.058,188.694 ; v1(53.971,189.418) C33.2@55.058,189.418 ; v1(53.971,190.592) C34.2@55.058,190.592 ; v1(53.971,191.316) C34.2@55.058,191.316 ; v1(53.997,192.534) C35.2@55.084,192.534 ; v1(53.996,193.258) C35.2@55.083,193.258
  other v1: 50.48,180.658 49.821,181.395 49.233,182.16 50.481,182.16 49.233,186.483 50.481,186.483 49.821,187.248 50.48,187.985 46.907,190.32 47.566,191.057 46.906,191.822 48.155,191.821
  other v3: 49.06,183.921 49.06,184.721 48.327,193.583
VPHY_FTDI: C661.2 C662.2 FB44.2 U55.4 | length 11.8
  L1 w0.2: C662.2@246.235,220.323 246.456,220.102 C661.2@247.522,220.102 ; U55.4@247.97,211.316 247.97,219.654 C661.2@247.522,220.102 ; FB44.2@248.933,220.102 C661.2@247.522,220.102
VPLL_FTDI: C659.2 C660.2 FB43.2 U55.9 | length 8.9
  L1 w0.2: FB43.2@242.221,216.666 243.841,216.666 C659.2@243.891,216.716 244.642,216.716 245.06,216.299 245.456,216.299 245.47,216.285 244.942,215.757 244.942,212.631 245.47,212.103 U55.9@245.47,211.316
VREF+_1: C61.2 C62.2 FB3.2 U12.44 | length 7.7
  L16 w0.12: U12.44@96.597,335.311 97.8,335.311 99.141,336.652 v1(99.831,336.652)
  L16 w0.2: v1(99.831,336.652) 99.888,336.709 99.888,336.871 FB3.2@100.511,337.494 ; C61.2@100.511,336.482 FB3.2@100.511,337.494 ; FB3.2@100.511,337.682 100.511,338.032 FB3.2@100.649,338.171 ; FB3.2@100.649,337.682 100.649,337.632 FB3.2@100.511,337.494
  L16 w1: C62.2@100.321,338.988 100.321,338.5 FB3.2@100.649,338.171
VREF+_2: C73.2 C74.2 FB5.2 U13.44 | length 0.6
  L1 w0.2: v1(186.763,272.981) U13.44@187.323,272.981
VSD_REF: R911.2 U47.C4 | length 7.3
  L1 w0.2: v2(135.268,339.529) 135.268,338.459 R911.2@135.274,338.453
  L3 (Sign) w0.2: v1(132.956,335.906) 132.967,335.917 132.967,336.904 135.204,339.141 135.204,339.465 v2(135.268,339.529)
  L14 (Sign) w0.12: v1(132.956,335.906) 132.956,335.75 133.302,335.404 v10(134.329,335.404)
VVCO+_1: C86.2 C87.2 FB6.2 U12.39 | length 6.5
  L16 w0.2: U12.39@95.447,337.461 95.447,337.976 95.535,338.064 95.535,339.664 96.601,340.73 C87.2@97.38,340.73 C86.2@97.38,340.099
  L16 w1: C87.2@97.38,340.73 97.514,340.864 98.63,340.864 FB6.2@98.68,340.914
VVCO+_2: C97.2 C98.2 FB7.2 U13.39 | length 2.2
  L1 w0.2: v1(186.932,275.559) 187.013,275.559 187.08,275.625 187.273,275.625 187.468,275.821 188.199,275.821 188.473,275.547 U13.39@188.473,275.131
WR_LMK_CLK_HF1_N: C728.1 R1086.2 U16.26 | length 110.4
  L1 w0.101: U16.26@159.565,228.695 cw(c159.59,228.695) 159.59,228.72 v7(160.741,228.72) ; R1086.2@204.404,288.544 C728.1@205.454,288.544 ; v3(206.184,288.327) 206.184,288.286 cw(c206.127,288.286) 206.127,288.228 205.779,288.228 cw(c205.779,288.552) C728.1@205.454,288.544 ; C728.1@205.454,288.544 cw(c205.779,288.552) C728.1@205.454,288.552 C728.1@205.454,288.544
  L5 (Sign) w0.081: v12(161.405,228.645) cw(c161.564,228.645) 161.564,228.805 162.865,228.805 ccw(c162.865,230.004) 164.064,230.004 164.064,254.983 cw(c164.644,254.983) 164.644,255.563 189.992,255.563 ccw(c189.992,256.478) 190.906,256.478 190.906,265.252 cw(c191.479,265.252) 191.479,265.825 191.509,265.825 207.035,265.825 ccw(c207.035,267.197) 208.407,267.197 208.407,287.501 ccw(c207.74,287.501) 207.74,288.168 206.344,288.168 cw(c206.344,288.327) v3(206.184,288.327)
  L3 (Sign) w0.081: v7(160.741,228.72) 161.33,228.72 cw(c161.33,228.645) v12(161.405,228.645)
WR_LMK_CLK_HF1_P: C728.2 R1085.2 U16.27 | length 110.4
  L1 w0.101: U16.27@159.565,229.195 ccw(c159.59,229.195) 159.59,229.17 v7(160.741,229.17) ; R1085.2@204.404,287.617 205.339,287.617 cw(c205.339,287.502) C728.2@205.454,287.502 cw(c205.779,287.502) 205.779,287.827 206.127,287.827 cw(c206.127,287.769) 206.184,287.769 v3(206.184,287.727)
  L5 (Sign) w0.081: v12(161.405,229.245) ccw(c161.564,229.245) 161.564,229.086 162.865,229.086 ccw(c162.865,230.004) 163.783,230.004 163.783,254.983 cw(c164.644,254.983) 164.644,255.844 189.992,255.844 ccw(c189.992,256.478) 190.625,256.478 190.625,265.252 cw(c191.479,265.252) 191.479,266.106 191.509,266.106 207.035,266.106 ccw(c207.035,267.197) 208.126,267.197 208.126,267.34 208.126,267.38 ccw(c207.937,267.38) 207.937,267.568 207.74,267.568 cw(c207.74,267.757) 207.551,267.757 207.551,267.918 cw(c207.74,267.918) 207.74,268.107 207.937,268.107 ccw(c207.937,268.295) 208.126,268.295 208.126,268.578 208.126,287.501 ccw(c207.74,287.501) 207.74,287.887 206.344,287.887 ccw(c206.344,287.727) v3(206.184,287.727)
  L3 (Sign) w0.081: v7(160.741,229.17) 161.33,229.17 ccw(c161.33,229.245) v12(161.405,229.245)
WR_LMK_CLK_HF2_N: C793.2 R1088.2 U16.32 | length 84.7
  L1 w0.101: v3(153.078,299.671) ccw(c153.262,299.855) 153.262,299.595 153.395,299.595 cw(c153.395,299.516) 153.451,299.572 153.489,299.572 ccw(c153.489,299.724) 153.597,299.616 ccw(c153.562,299.651) 153.611,299.651 cw(c153.661,299.651) 153.626,299.686 153.801,299.861 cw(c153.886,299.775) C793.2@153.886,299.896 cw(c153.886,299.775) 153.971,299.861 154.146,299.686 cw(c154.111,299.651) 154.16,299.651 ccw(c154.21,299.651) 154.175,299.616 154.19,299.601 ccw(c154.261,299.673) 154.261,299.572 154.474,299.572 cw(c154.474,299.517) 154.512,299.556 ccw(c154.551,299.594) 154.551,299.54 154.6,299.54 ccw(c154.6,299.645) 154.674,299.571 ccw(c154.606,299.639) 154.703,299.639 cw(c154.799,299.639) 154.731,299.708 R1088.2@154.842,299.818 ; R1088.2@154.842,299.818 cw(c154.927,299.733) R1088.2@154.927,299.854 ; U16.32@159.565,231.695 161.025,231.695 v7(161.05,231.67)
  L5 (Sign) w0.081: v3(153.078,299.671) cw(c152.918,299.671) 152.918,299.512 152.781,299.512 ccw(c152.781,299.143) 152.412,299.143 152.412,289.269 ccw(c154.719,289.269) 153.088,287.638 153.395,287.33 155.187,285.539 cw(c153.391,283.743) 155.931,283.743 155.931,281.348 cw(c154.971,281.348) 155.65,280.669 154.316,279.335 ccw(c156.309,277.343) 153.491,277.343 153.491,259.008 ccw(c154.281,259.008) 154.281,258.217 161.741,258.217 cw(c161.741,257.207) 162.75,257.207 162.75,231.986 cw(c162.326,231.986) 162.326,231.562 161.873,231.562 cw(c161.873,231.721) v12(161.714,231.721)
  L3 (Sign) w0.081: v7(161.05,231.67) 161.123,231.67 161.207,231.586 161.599,231.586 161.714,231.7 v12(161.714,231.721)
WR_LMK_CLK_HF2_P: C793.1 R1087.2 U16.31 | length 84.7
  L1 w0.101: v3(153.078,299.071) cw(c153.262,298.887) 153.262,299.147 153.395,299.147 ccw(c153.395,299.227) 153.451,299.171 153.489,299.171 cw(c153.489,299.018) 153.597,299.126 cw(c153.562,299.091) 153.611,299.091 ccw(c153.661,299.091) 153.626,299.056 153.801,298.881 ccw(c153.886,298.967) C793.1@153.886,298.846 ccw(c153.886,298.967) 153.971,298.881 154.146,299.056 ccw(c154.111,299.091) 154.16,299.091 cw(c154.21,299.091) 154.175,299.126 154.19,299.141 ; 154.19,299.141 cw(c154.261,299.07) 154.261,299.171 154.308,299.171 cw(c154.308,299.116) 154.346,299.155 ccw(c154.384,299.193) 154.384,299.139 154.6,299.139 cw(c154.6,299.034) 154.674,299.108 cw(c154.606,299.04) 154.703,299.04 ccw(c154.799,299.04) 154.731,298.971 154.842,298.86 ccw(c154.927,298.946) R1087.2@154.927,298.825 ; U16.31@159.565,231.195 161.025,231.195 v7(161.05,231.22)
  L5 (Sign) w0.081: v3(153.078,299.071) ccw(c152.918,299.071) 152.918,299.231 152.781,299.231 ccw(c152.781,299.143) 152.693,299.143 152.693,289.271 ccw(c154.725,289.271) 153.288,287.835 155.386,285.737 cw(c153.393,283.744) 156.212,283.744 156.212,281.345 cw(c154.977,281.345) 155.85,280.472 154.516,279.138 ccw(c156.312,277.342) 153.772,277.342 153.772,259.008 ccw(c154.281,259.008) 154.281,258.498 161.741,258.498 cw(c161.741,257.207) 163.032,257.207 163.032,231.986 cw(c162.326,231.986) 162.326,231.281 161.86,231.281 ccw(c161.86,231.121) v12(161.7,231.121)
  L3 (Sign) w0.081: v7(161.05,231.22) 161.123,231.22 161.207,231.305 161.599,231.305 161.7,231.204 v12(161.7,231.121)
WR_LMK_CLK_HF3_N: U16.33
WR_LMK_CLK_HF3_P: U16.34
WR_LMK_CLK_HF4_N: U16.52
WR_LMK_CLK_HF4_P: U16.51
WR_LMK_CLK_HF5_N: U16.53
WR_LMK_CLK_HF5_P: U16.54
WR_LMK_CLK_HF6_N: U16.58
WR_LMK_CLK_HF6_P: U16.57
WR_LMK_CLK_HF7_N: U16.61
WR_LMK_CLK_HF7_P: U16.62
WR_LMK_CLK_IN_N: R311.1 R1084.2 U16.2 | length 3.6
  L1 w0.101: U16.2@151.915,223.545 ccw(c151.915,223.496) 151.866,223.496 151.866,221.781 ccw(c152.171,221.781) R311.1@152.171,221.475 ccw(c152.171,221.176) 151.872,221.176 151.872,220.739 ccw(c152.141,220.739) R1084.2@152.141,220.47
WR_LMK_CLK_IN_P: R311.2 R1083.2 U16.1 | length 3.6
  L1 w0.101: R1083.2@151.201,220.47 ccw(c151.201,220.739) 151.471,220.739 151.471,221.176 ccw(c151.171,221.176) R311.2@151.171,221.475 ccw(c151.171,221.769) 151.465,221.769 151.465,223.496 ccw(c151.415,223.496) U16.1@151.415,223.545
WR_LMK_CLK_LF_N: U16.14 U16.23 | length 15.4
  L1 w0.101: U16.14@157.915,223.545 cw(c157.915,223.496) 157.965,223.496 v7(157.965,222.86) ; U16.23@159.565,227.195 ccw(c159.615,227.195) 159.615,227.146 v7(160.669,227.146)
  L5 (Sign) w0.081: v12(157.907,222.325) cw(c157.907,222.208) 158.025,222.208 158.025,221.94 ccw(c158.613,221.94) 158.613,221.351 162.165,221.351 ccw(c162.165,221.94) 162.753,221.94 162.753,226.238 ccw(c161.905,226.238) 161.905,227.086 161.334,227.086 cw(c161.334,227.245) v12(161.174,227.245)
  L3 (Sign) w0.081: v12(157.907,222.325) ccw(c157.907,222.443) 158.025,222.443 158.025,222.8 ccw(c157.965,222.8) v7(157.965,222.86) ; v7(160.669,227.146) ccw(c160.729,227.146) 160.729,227.086 161.015,227.086 ccw(c161.015,227.245) v12(161.174,227.245)
WR_LMK_CLK_LF_P: U16.15 U16.22 | length 15.5
  L1 w0.101: v7(158.366,222.86) 158.366,223.496 cw(c158.415,223.496) U16.15@158.415,223.545 ; U16.22@159.565,226.695 cw(c159.615,226.695) 159.615,226.745 v7(160.669,226.745)
  L5 (Sign) w0.081: v12(158.507,222.325) 158.475,222.325 ccw(c158.475,222.241) 158.39,222.241 ccw(c158.39,222.156) 158.306,222.156 158.306,221.94 ccw(c158.613,221.94) 158.613,221.632 160.448,221.632 160.771,221.632 ccw(c160.771,221.779) 160.917,221.779 160.917,221.798 cw(c161.064,221.798) 161.064,221.944 161.259,221.944 cw(c161.259,221.798) 161.405,221.798 161.405,221.779 ccw(c161.551,221.779) 161.551,221.632 162.079,221.632 162.165,221.632 ccw(c162.165,221.94) 162.472,221.94 162.472,221.978 162.472,222.018 ccw(c162.326,222.018) 162.326,222.164 162.305,222.164 cw(c162.305,222.311) 162.158,222.311 162.158,222.506 cw(c162.305,222.506) 162.305,222.652 162.326,222.652 ccw(c162.326,222.798) 162.472,222.798 162.472,223.106 162.472,224.655 162.472,224.899 ccw(c162.326,224.899) 162.326,225.046 162.205,225.046 cw(c162.205,225.192) 162.059,225.192 162.059,225.387 cw(c162.205,225.387) 162.205,225.533 162.326,225.533 ccw(c162.326,225.679) 162.472,225.679 162.472,226.207 162.472,226.238 ccw(c161.905,226.238) 161.905,226.805 161.334,226.805 ccw(c161.334,226.645) v12(161.174,226.645)
  L3 (Sign) w0.081: v7(158.366,222.86) ccw(c158.366,222.8) 158.306,222.8 158.306,222.527 ccw(c158.507,222.527) v12(158.507,222.325) ; v7(160.669,226.745) cw(c160.729,226.745) 160.729,226.805 161.015,226.805 cw(c161.015,226.645) v12(161.174,226.645)
WR_LMK_CLK_RC_HF1_N: C729.2 R1086.1 U1.AJ1 | length 15.7
  L1 w0.1: U1.AJ1@190.397,288.539 v2(190.884,289.027)
  L1 w0.101: v2(201.358,288.345) 201.426,288.345 201.518,288.252 201.691,288.252 202.092,288.252 202.151,288.312 202.151,288.352 202.375,288.577 C729.2@202.425,288.577 202.475,288.577 202.7,288.352 202.7,288.34 202.759,288.281 203.12,288.281 203.18,288.34 203.18,288.369 203.354,288.544 R1086.1@203.404,288.544
  L3 (Sign) w0.081: v2(190.884,289.027) 190.872,289.039 190.585,289.039 190.537,288.992 190.537,288.457 190.537,288.348 190.615,288.27 190.692,288.192 192.397,288.192 197.787,288.192 198.318,288.192 ccw(c198.318,288.381) 198.506,288.381 198.506,288.407 cw(c198.694,288.407) 198.694,288.595 198.856,288.595 cw(c198.856,288.407) 199.044,288.407 199.044,288.381 ccw(c199.232,288.381) 199.232,288.192 199.811,288.192 201.206,288.192 ccw(c201.206,288.345) v2(201.358,288.345)
WR_LMK_CLK_RC_HF1_P: C729.1 R1085.1 U1.AJ2 | length 15.7
  L1 w0.1: v2(189.909,289.052) U1.AJ2@190.397,289.539
  L1 w0.101: v2(201.358,287.759) 201.426,287.759 201.518,287.851 201.857,287.851 202.092,287.851 202.151,287.792 202.151,287.751 202.375,287.527 C729.1@202.425,287.527 202.475,287.527 202.7,287.751 202.7,287.792 202.787,287.88 203.12,287.88 203.179,287.821 203.179,287.791 203.354,287.617 R1085.1@203.404,287.617
  L3 (Sign) w0.081: v2(189.909,289.052) 189.919,289.042 190.206,289.042 190.256,288.992 190.256,288.457 190.256,288.231 190.416,288.071 190.576,287.911 192.397,287.911 197.787,287.911 197.939,287.759 v2(201.358,287.759)
WR_LMK_CLK_RC_HF2_N: C730.2 R1088.1 U1.C17 | length 12.3
  L1 w0.1: v2(163.909,304.052) U1.C17@164.397,304.539
  L1 w0.101: R1088.1@155.927,299.854 cw(c155.927,299.733) R1088.1@156.012,299.819 ; R1088.1@156.012,299.818 156.134,299.696 cw(c156.093,299.655) 156.152,299.655 ccw(c156.21,299.655) 156.169,299.613 ccw(c156.27,299.715) 156.27,299.571 156.513,299.571 ccw(c156.513,299.672) 156.585,299.601 156.6,299.616 ccw(c156.565,299.651) 156.614,299.651 cw(c156.664,299.651) 156.629,299.686 156.804,299.861 cw(c156.889,299.775) C730.2@156.889,299.896 cw(c156.889,299.775) 156.974,299.861 157.149,299.686 cw(c157.114,299.651) 157.163,299.651 ccw(c157.213,299.651) 157.178,299.616 ccw(c157.286,299.724) 157.286,299.571 157.598,299.571 ccw(c157.598,300.173) 158.2,300.173 v2(158.2,301.168)
  L3 (Sign) w0.081: v2(158.2,301.168) cw(c158.313,301.168) 158.233,301.248 ccw(c158.109,301.372) 158.284,301.372 158.284,301.516 cw(c158.679,301.516) 158.4,301.795 160.396,303.792 cw(c162.389,301.798) 162.389,304.617 163.161,304.617 cw(c163.161,304.228) 163.55,304.228 ccw(c163.727,304.228) 163.727,304.052 v2(163.909,304.052)
WR_LMK_CLK_RC_HF2_P: C730.1 R1087.1 U1.B16 | length 12.1
  L1 w0.1: v2(162.909,304.027) U1.B16@163.397,303.539
  L1 w0.101: R1087.1@155.927,298.825 ccw(c155.927,298.946) 156.012,298.86 156.123,298.971 ccw(c156.055,299.04) 156.152,299.04 cw(c156.248,299.04) 156.18,299.108 cw(c156.331,298.957) 156.331,299.17 156.513,299.17 cw(c156.513,299.069) 156.585,299.141 156.6,299.126 cw(c156.565,299.091) 156.614,299.091 ccw(c156.664,299.091) 156.629,299.056 156.804,298.881 ccw(c156.889,298.967) C730.1@156.889,298.846 ccw(c156.889,298.967) C730.1@156.974,298.881 ; C730.1@156.974,298.881 157.149,299.056 ccw(c157.114,299.091) 157.163,299.091 cw(c157.213,299.091) 157.178,299.126 cw(c157.286,299.018) 157.286,299.17 157.598,299.17 ccw(c157.598,300.222) 158.65,300.222 v2(158.65,301.168)
  L3 (Sign) w0.081: v2(158.65,301.168) ccw(c158.537,301.168) 158.616,301.248 cw(c158.741,301.372) 158.565,301.372 158.565,301.514 cw(c158.683,301.514) 158.6,301.598 160.594,303.592 cw(c162.39,301.796) 162.39,304.336 163.161,304.336 cw(c163.161,304.228) 163.269,304.228 cw(c163.067,304.228) 163.067,304.027 v2(162.909,304.027)
X1: C481.2 R335.2 U39.14 X4.1 | length 15.5
  L16 w0.12: C481.2@96.15,288.662 96.497,289.01 X4.1@97.67,289.01 98.47,289.01 98.87,288.61 98.87,286.117 98.87,285.356 99.289,284.937 103.214,284.937 104.256,283.896 105.119,283.896 106.049,282.966 U39.14@106.049,281.925
X2: C480.2 R335.1 U39.15 X4.3 | length 12.9
  L16 w0.12: C480.2@101.403,287.959 101.403,287.949 100.964,287.51 X4.3@99.77,287.51 99.77,286.117 99.77,285.404 99.84,285.333 103.478,285.333 104.578,284.233 105.53,284.233 106.549,283.214 U39.15@106.549,281.925
XO_LMK05028_P: C589.1 U16.43 | length 5.4
  L1 w0.101: C589.1@153.67,237.664 153.67,236.715 153.915,236.47 U16.43@153.915,232.345
pads on no net: D28.1 FID1.0 FID2.0 FID3.0 FID4.0 FID5.0 FID6.0 FID7.0 FID8.0 J1_PCIE0.31 J1_PCIE0.33 J1_PCIE1.31 J1_PCIE1.33 J1_PCIE2.31 J1_PCIE2.33 J1_PCIE3.31 J1_PCIE3.33 J1_PCIE4.31 J1_PCIE4.33 J14.3 J27.5 J27.6 J27.7 J27.8 J27.11 J27.13 J27.17 J27.19 J27.20 J27.22 J27.23 J27.24 J27.25 J27.26 J27.28 J27.30 J27.32 J27.34 J27.36 J27.40 J27.42 J27.44 J27.46 J27.48 J27.56 J27.58 J27.59 J28.MH1 J28.MH2 J32. J33. J34. J35. P12.13 T21.MH1 T21.MH2 U1.A15 U1.AA8 U1.AA17 U1.AA26 U1.AA30 U1.AB5 U1.AB6 U1.AB8 U1.AB18 U1.AB19 U1.AB20 U1.AB21 U1.AB29 U1.AC7 U1.AC8 U1.AC13 U1.AC19 U1.AD7 U1.AD17 U1.AE3 U1.AE7 U1.AE10 U1.AE12 U1.AE17 U1.AF1 U1.AF2 U1.AF5 U1.AF6 U1.AF11 U1.AF12 U1.AF13 U1.AF15 U1.AF16 U1.AF17 U1.AG5 U1.AG6 U1.AG8 U1.AG9 U1.AG11 U1.AG14 U1.AG15 U1.AG19 U1.AH1 U1.AH4 U1.AH6 U1.AH7 U1.AH8 U1.AH11 U1.AH12 U1.AH14 U1.AJ6 U1.AJ7 U1.AJ12 U1.AJ27 U1.AK2 U1.AK3 U1.B15 U1.C13 U1.D14 U1.D15 U1.D17 U1.E12 U1.E13 U1.E14 U1.E15 U1.E17 U1.F12 U1.F13 U1.F15 U1.F16 U1.G13 U1.G15 U1.G16 U1.J15 U1.K14 U1.K15 U1.L14 U1.L15 U1.L25 U1.L26 U1.W9 U1.W10 U1.W26 U1.W27 U1.Y1 U1.Y9 U1.Y27 U1.Y29 U1.Y30 U8.T4 U9.T4 U10.T4 U11.T4 U13.42 U16.5 U16.6 U16.10 U16.11 U16.18 U30.6 U30.7 U30.8 U31.3 U31.4 U31.8 U31.13 U31.14 U31.15 U31.16 U32.8 U32.13 U32.14 U32.15 U32.16 U33.7 U35_I2C_Expander_00.7 U35_I2C_Expander_00.10 U35_I2C_Expander_01.7 U35_I2C_Expander_01.10 U35_I2C_Expander_02.7 U35_I2C_Expander_02.10 U35_I2C_Expander_10.7 U35_I2C_Expander_10.10 U35_I2C_Expander_11.7 U35_I2C_Expander_11.10 U35_I2C_Expander_12.7 U35_I2C_Expander_12.10 U35_I2C_Expander_Main_Rst.7 U35_I2C_Expander_Main_Rst.10 U35_I2C_Expander_PWR_CLK.7 U35_I2C_Expander_PWR_CLK.10 U35_I2C_Expander_PWR_Dist.7 U35_I2C_Expander_PWR_Dist.10 U35_I2C_Expander_SFP.7 U35_I2C_Expander_SFP.10 U39.18 U39.25 U39.26 U39.29 U39.32 U39.37 U39.38 U39.40 U40.6 U41.A1 U41.A2 U41.A7 U41.A8 U41.A9 U41.A10 U41.A11 U41.A12 U41.A13 U41.A14 U41.B1 U41.B7 U41.B8 U41.B9 U41.B10 U41.B11 U41.B12 U41.B13 U41.B14 U41.C1 U41.C3 U41.C5 U41.C7 U41.C8 U41.C9 U41.C10 U41.C11 U41.C12 U41.C13 U41.C14 U41.D1 U41.D2 U41.D3 U41.D4 U41.D12 U41.D13 U41.D14 U41.E1 U41.E2 U41.E3 U41.E5 U41.E8 U41.E9 U41.E10 U41.E12 U41.E13 U41.E14 U41.F1 U41.F2 U41.F3 U41.F10 U41.F12 U41.F13 U41.F14 U41.G1 U41.G2 U41.G3 U41.G10 U41.G12 U41.G13 U41.G14 U41.H1 U41.H2 U41.H3 U41.H5 U41.H12 U41.H13 U41.H14 U41.J1 U41.J2 U41.J3 U41.J12 U41.J13 U41.J14 U41.K1 U41.K2 U41.K3 U41.K6 U41.K7 U41.K10 U41.K12 U41.K13 U41.K14 U41.L1 U41.L2 U41.L3 U41.L12 U41.L13 U41.L14 U41.M1 U41.M2 U41.M3 U41.M7 U41.M8 U41.M9 U41.M10 U41.M11 U41.M12 U41.M13 U41.M14 U41.N1 U41.N3 U41.N6 U41.N7 U41.N8 U41.N9 U41.N10 U41.N11 U41.N12 U41.N13 U41.N14 U41.P1 U41.P2 U41.P7 U41.P8 U41.P9 U41.P10 U41.P11 U41.P12 U41.P13 U41.P14 U42.6 U44.8 U44.9 U45.12 U45.15 U45.16 U46.B3 U46.C4 U47.E2 U47.E4 U55.36 U55.60 U58.10 U58.11 U59_5to3V3_1.6 U59_5to3V3_2.6 U59_5V_to_3V3_for_FTDI.6 U60.8 U63.5 U65.1 U69.8 U73.3 U78.3 U78.4
copper on no net:
  other v21: 145.237,267.894 227.59,267.894 87.485,362.892 169.837,362.892 252.19,362.892
  other v22: 170.237,267.894 252.59,267.894 62.485,362.892 144.837,362.892 227.19,362.892

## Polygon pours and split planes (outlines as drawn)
Power2_In_CM on L1 "POWER2_IN_CM_L01_P225" (solid, pour order 225): 17 vertices, not listed, extent 44.628,175.056 48.704,179.437
Vout_1_Selector on L1 "VOUT_1_SELECTOR_L01_P221" (solid, pour order 221): 48.855,175.056 48.716,175.195 48.716,178.252 49.749,179.285 50.595,179.285 50.964,178.917 50.964,176.61 49.411,175.057 48.868,175.057
Battery_PWR on L1 "BATTERY_PWR_L01_P227" (solid, pour order 227): 48.532,194.039 48.671,194.179 48.671,197.235 47.638,198.269 46.792,198.269 46.424,197.901 46.424,195.593 47.976,194.041 48.519,194.041
Vout_2_Selector on L1 "VOUT_2_SELECTOR_L01_P229" (solid, pour order 229): 48.532,193.927 48.671,193.788 48.671,190.731 47.638,189.698 46.792,189.698 46.424,190.066 46.424,192.373 47.976,193.926 48.519,193.926
PWR_OUT_20V on L1 "PWR_OUT_20V_L01_P231" (solid, pour order 231): 48.822,194.039 48.683,194.179 48.683,197.235 49.716,198.269 50.563,198.269 50.931,197.901 50.931,195.593 49.378,194.041 48.835,194.041
PWR_OUT_20V on L1 "PWR_OUT_20V_L01_P233" (solid, pour order 233): 48.822,193.927 48.683,193.788 48.683,190.731 49.716,189.698 50.563,189.698 50.931,190.066 50.931,192.373 49.378,193.926 48.835,193.926
FTDI_GND on L1 "FTDI_GND_L01_P384" (solid, remove dead copper, pour order 384): 242.221,212.066 242.221,210.61 ccw(c242.904,210.61) 242.904,209.926 249.88,209.926 ccw(c249.88,210.766) 250.72,210.766 250.72,211.251 ccw(c249.904,211.251) 249.904,212.066
eMMC_VccQ on L1 "EMMC_VCCQ_L01_P387" (solid, remove dead copper, pour order 387): 22 vertices, not listed, extent 111.34,318.789 119.987,322.91
3V3_RAIL on L1 "3V3_RAIL_L01_P296" (solid, remove dead copper, pour order 296): 83.972,298.972 90.207,298.972 cw(c90.207,298.729) 90.449,298.729 90.449,297.766 cw(c90.18,297.766) 90.18,297.497 83.886,297.497 cw(c83.886,297.794) 83.589,297.794 83.589,298.588 cw(c83.972,298.588)
1V8@0.5A_ADC_filtered on L1 "1V8@0.5A_ADC_FILTERED_L01_P422" (solid, remove dead copper, pour order 422): 23 vertices, not listed, extent 153.089,281.94 160.837,286.155
Vcc_CLK_Mux_Fine on L1 "VCC_CLK_MUX_FINE_L01_P407" (solid, remove dead copper, pour order 407): 18 vertices, not listed, extent 44.703,391.343 49.843,398.251
VDD_CLK_MUX_DIV_3.3V on L1 "VDD_CLK_MUX_DIV_3.3V_L01_P405" (solid, remove dead copper, pour order 405): 20 vertices, not listed, extent 58.511,384.303 64.913,387.335
FTDI_VccIO on L1 "FTDI_VCCIO_L01_P390" (solid, remove dead copper, pour order 390): 32 vertices, not listed, extent 224.409,216.224 243.291,221.69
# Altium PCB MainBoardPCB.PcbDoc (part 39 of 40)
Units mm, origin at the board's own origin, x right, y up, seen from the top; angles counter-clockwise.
Board outline 258.95 x 308.86 mm, 16 copper layers (L1, L2 (GND), L3 (Sign), L4 (GND), L5 (Sign), L6 (PWR/GND), L7(12V+Other), L8 (Plane_GND), L9 (PWR/GND), L10 (3V3+Other), L11 (PWR/GND), L12 (Sign), L13 (GND), L14 (Sign), L15 (GND), L16), stack 2.503 mm thick; 2578 components, 1867 nets, 8817 pads, 8021 vias.
Unrouted connection lines stored in the file: 25.

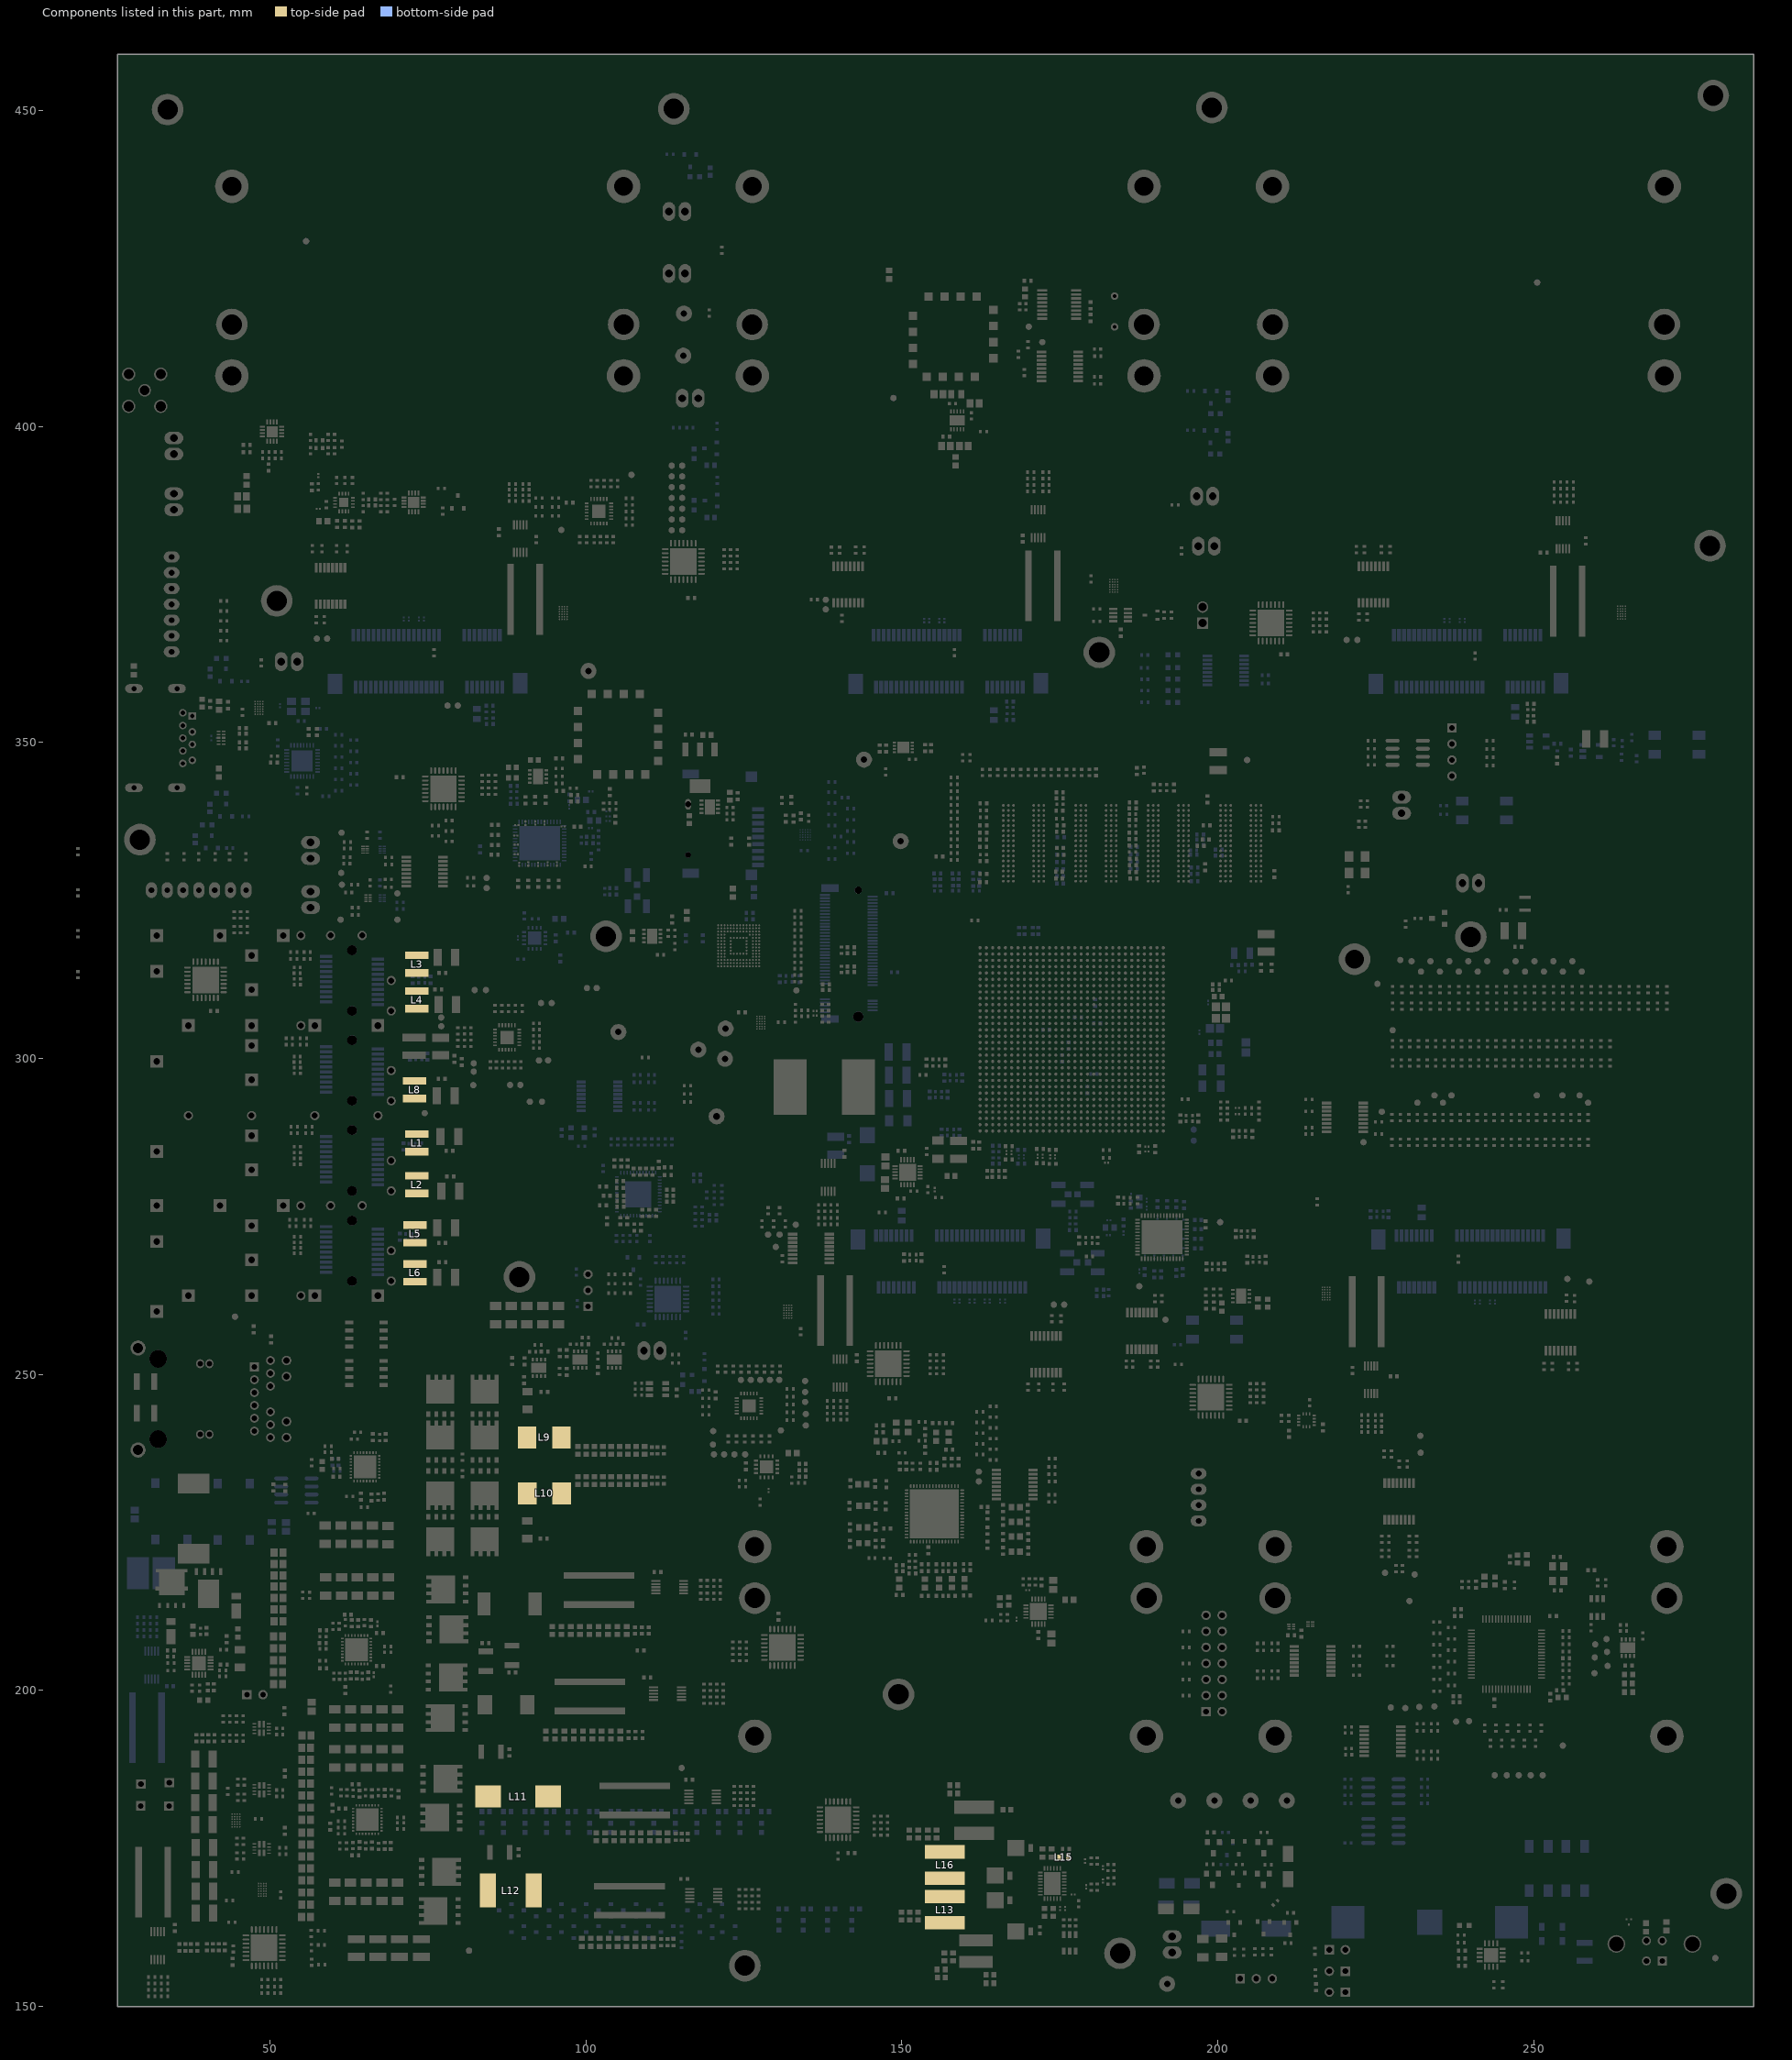
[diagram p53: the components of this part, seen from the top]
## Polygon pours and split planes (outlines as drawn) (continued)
eMMC_Vcc on L1 "EMMC_VCC_L01_P386" (solid, pour order 386): 121.109,335.89 ccw(c122.522,335.89) 122.522,334.477 126.486,334.477 ccw(c126.486,335.537) 127.546,335.537 127.546,339.175 ccw(c125.006,339.175) 125.006,341.715 121.19,341.715 ccw(c121.19,340.997) 120.472,340.997 120.472,340.584 ccw(c120.64,340.584) 120.64,340.416 122.209,340.416 cw(c122.209,339.821) 122.804,339.821 122.804,337.636 cw(c122.087,337.636) 122.087,336.919 ccw(c122.087,335.941) 121.109,335.941
Power_3.3_2 on L1 "POWER_3.3_2_L01_P370" (solid, pour order 370): 32 vertices, not listed, extent 166.329,212.694 171.728,223.193
Power_3.3_1 on L1 "POWER_3.3_1_L01_P369" (solid, remove dead copper, pour order 369): 19 vertices, not listed, extent 162.212,211.098 170.203,214.092
3V3_RAIL on L1 "3V3_RAIL_L01_P323" (solid, remove dead copper, pour order 323): 32 vertices, not listed, extent 94.756,245.514 108.341,252.921
Vout_2_Selector on L1 "VOUT_2_SELECTOR_L01_P217" (solid, pour order 217): 48.855,184.265 48.716,184.126 48.716,181.069 49.749,180.036 50.595,180.036 50.964,180.404 50.964,182.711 49.411,184.264 48.868,184.264
Vout_1_Selector on L1 "VOUT_1_SELECTOR_L01_P213" (solid, pour order 213): 46.717,182.972 45.683,182.972 45.54,182.829 45.54,181.32 46.825,180.036 47.671,180.036 48.704,181.069 48.704,184.126 48.565,184.265 48.552,184.264 48.009,184.264
B503_Ground on L1 "B503_GROUND_L01_P145" (solid, pour order 145): 112.877,233.64 97.684,233.654 73.698,233.654 73.698,237.566 73.711,237.579 97.621,237.579 112.877,237.579
AGND_2 on L1 "AGND_2_L01_P115" (solid, remove dead copper, pour order 115): 58.433,213.225 68.437,213.225 68.437,198.577 60.124,198.577 55.969,202.732 55.969,210.761
US+_MGTVccAux on L1 "US+_MGTVCCAUX_L01_P276" (solid, remove dead copper, pour order 276): 159.969,172.978 cw(c159.507,172.978) 159.507,172.515 149.35,172.515 cw(c149.35,173.53) 148.335,173.53 148.335,176.71 cw(c148.94,176.71) 148.94,177.315 150.551,177.315 cw(c150.565,177.301) 150.579,177.315 156.299,177.315 cw(c156.299,176.74) 156.875,176.74 ccw(c157.822,176.74) 157.768,175.794 159.643,175.794 cw(c159.643,175.467) 159.969,175.467
NetD17_1 on L1 "NETD17_1_L01_P267" (solid, remove dead copper, pour order 267): 161.206,169.43 160.994,169.218 153.669,169.218 153.669,171.97 166.106,171.97 166.106,170.185 166.466,169.825 172.278,169.825 172.278,169.575 170.672,169.575 170.527,169.43
ADP1741_3.6V on L1 "ADP1741_3.6V_L01_P277" (solid, remove dead copper, pour order 277): 154.782,162.176 ccw(c154.782,161.613) 154.22,161.613 154.22,160.845 cw(c152.867,160.845) 152.867,159.493 149.357,159.493 cw(c149.357,161.111) 147.739,161.111 147.739,162.684 cw(c149.356,162.684) 149.356,164.301 149.381,164.326 159.969,164.326 159.969,162.176
B503_Ground on L1 "B503_GROUND_L01_P481" (solid, remove dead copper, pour order 481): 105.385,281.735 cw(c105.75,281.735) 105.75,282.1 110.874,282.1 cw(c110.874,281.925) 111.049,281.925 111.049,278.825 ccw(c111.312,278.825) 111.312,278.562 cw(c111.312,278.338) 111.536,278.338 111.536,275.928 cw(c111.179,275.928) 111.179,275.571 106.223,275.571 cw(c106.223,276.325) 105.469,276.325 105.469,281.348 ccw(c105.397,281.348) 105.397,281.42
Power1_In_CM on L1 "POWER1_IN_CM_L01_P223" (solid, pour order 223): 17 vertices, not listed, extent 45.337,168.456 48.704,174.943
RAM_Vcc1V2 on L1 "RAM_VCC1V2_L01_P255" (solid, remove dead copper, pour order 255): 106.536,167.665 113.19,167.665 113.75,168.225 113.75,170.687 112.555,171.882 101.087,171.882 99.678,170.472 99.678,168.084 100.084,167.678 106.599,167.678
SFP1_VccR on L1 "SFP1_VCCR_L01_P344" (solid, remove dead copper, pour order 344): 77.252,317.591 cw(c77.252,316.946) 77.897,316.946 77.897,314.967 cw(c77.571,314.967) 77.571,314.641 ccw(c77.571,314.384) 77.314,314.384 77.314,313.253 cw(c76.901,313.253) 76.901,312.84 71.533,312.84 cw(c71.533,313.347) 71.027,313.347 71.027,314.314 cw(c71.336,314.314) 71.336,314.624 74.699,314.624 ccw(c74.699,315.251) 75.327,315.251 75.327,316.984 cw(c75.934,316.984) 75.934,317.591
AGND on L1 "AGND_L01_P489" (solid, pour order 489): 89.269,337.163 95.975,337.163 96.287,336.852 96.287,331.343 95.767,330.823 89.204,330.823 89.112,330.915 89.112,337.006
NetC693_1 on L1 "NETC693_1_L01_P199" (solid, pour order 199): 35.331,225.234 31.229,221.132 31.229,215.252 32.029,214.452 37.211,214.452 38.544,215.786 38.544,217.276 38.909,217.64 42.862,217.64 42.862,223.444 41.072,225.234
Vout2_2 on L1 "VOUT2_2_L01_P247" (solid, pour order 247): 92.405,200.584 94.297,198.691 106.35,198.691 110.045,194.996 110.045,193.205 109.828,192.987 89.918,192.987 87.816,195.089 87.816,199.136 89.264,200.584
SFP1_VccT on L1 "SFP1_VCCT_L01_P343" (solid, remove dead copper, pour order 343): 17 vertices, not listed, extent 71.126,307.167 78.074,311.746
3V3_RAIL on L1 "3V3_RAIL_L01_P438" (solid, remove dead copper, pour order 438): 27 vertices, not listed, extent 124.92,234.707 129.769,239.794
US+_Vcc_PS_DDR_504 on L1 "US+_VCC_PS_DDR_504_L01_P436" (solid, remove dead copper, pour order 436): 206.07,317.699 209.006,317.699 209.929,316.776 209.929,314.019 209.136,313.225 206.362,313.225 206.07,313.516
ETH_VDDIO on L1 "ETH_VDDIO_L01_P279" (solid, remove dead copper, pour order 279): 158.243,180.539 158.243,185.622 166.449,185.622 166.674,185.397 166.674,180.238 166.308,179.872 158.911,179.872
3V3_RAIL on L1 "3V3_RAIL_L01_P429" (solid, pour order 429): 100.413,390.989 cw(c100.413,391.399) 100.004,391.399 100.004,392.536 cw(c100.281,392.536) 100.281,392.813 107.281,392.813 cw(c107.281,392.366) 107.727,392.366 107.727,391.28 cw(c107.442,391.274) 107.449,390.989
CSN on L1 "CSN_L01_P423" (solid, remove dead copper, pour order 423): 19 vertices, not listed, extent 42.652,200.101 51.117,209.789
CSN on L1 "CSN_L01_P211" (solid, pour order 211): 46.817,185.571 45.869,185.571 45.538,185.902 45.538,187.32 46.641,188.423 46.825,188.607 47.671,188.607 48.704,187.574 48.704,184.517 48.565,184.378 48.552,184.379 48.009,184.379
Vout_2_Selector on L1 "VOUT_2_SELECTOR_L01_P215" (solid, pour order 215): 48.855,184.378 48.716,184.517 48.716,187.574 49.749,188.607 50.595,188.607 50.964,188.239 50.964,185.932 49.411,184.379 48.868,184.379
3V3_RAIL on L1 "3V3_RAIL_L01_P395" (solid, remove dead copper, pour order 395): 90.584,307.942 ccw(c90.584,308.586) 91.227,308.586 ccw(c90.071,308.586) 90.071,309.741 85.154,309.741 ccw(c85.154,308.723) 84.136,308.723 ccw(c84.917,308.723) 84.917,307.942
US+_Vcc_PS_DDR_504 on L1 "US+_VCC_PS_DDR_504_L01_P278" (solid, remove dead copper, pour order 278): 166.483,157.871 cw(c166.483,156.771) 167.583,156.771 cw(c166.68,156.771) 166.68,155.868 164.425,155.868 ccw(c164.425,155.417) 163.975,155.417 163.975,154.279 cw(c162.774,154.279) 162.774,153.078 157.765,153.078 cw(c157.765,154.593) 156.25,154.593 156.25,157.391 cw(c156.729,157.391) 156.729,157.871
12V_LT3042 on L1 "12V_LT3042_L01_P258" (solid, pour order 258): 101.724,216.814 108.378,216.814 108.938,217.374 108.938,219.836 107.743,221.031 96.275,221.031 94.866,219.621 94.866,217.233 95.272,216.827 101.787,216.827
SFP3_VccR on L1 "SFP3_VCCR_L01_P342" (solid, remove dead copper, pour order 342): 71.362,301.337 71.362,301.336 cw(c78.631,301.186) 78.781,301.186 78.781,299.938 ccw(c78.958,299.938) 78.958,299.761 79.43,299.761 cw(c79.43,299.61) 79.581,299.61 79.581,299.138 cw(c79.173,299.138) 79.173,298.729 72.28,298.729 cw(c72.28,300.297) 70.712,300.297 70.712,300.843 cw(c71.205,300.843) 71.205,301.336
SFP3_VccT on L1 "SFP3_VCCT_L01_P341" (solid, remove dead copper, pour order 341): 70.776,297.138 cw(c71.194,297.138) 71.194,297.556 76.327,297.556 cw(c76.327,296.639) 77.244,296.639 77.244,293.121 cw(c76.605,293.121) 76.605,292.481 76.123,292.481 cw(c76.123,293.06) 75.544,293.06 75.544,294.413 ccw(c74.876,294.413) 74.876,295.081 71.968,295.081 cw(c71.968,296.274) 70.776,296.274
SFP0_VccR on L1 "SFP0_VCCR_L01_P340" (solid, remove dead copper, pour order 340): 78.422,285.399 78.422,288.768 ccw(c77.943,288.768) 77.943,289.247 76.178,289.247 ccw(c76.178,288.954) 75.886,288.954 75.886,287.219 cw(c75.326,287.219) 75.326,286.66 71.929,286.66 ccw(c71.929,285.857) 71.126,285.857 71.126,284.77 ccw(c71.691,284.77) 71.691,284.205 78.062,284.205 ccw(c78.062,284.557) 78.415,284.557
SFP0_VccT on L1 "SFP0_VCCT_L01_P339" (solid, remove dead copper, pour order 339): 78.553,281.711 78.553,278.223 cw(c77.694,278.223) 77.694,277.364 76.303,277.364 cw(c76.303,277.697) 75.971,277.697 75.971,279.502 ccw(c75.427,279.502) 75.427,280.047 72.034,280.047 cw(c72.034,280.954) 71.127,280.954 71.127,281.985 cw(c71.577,281.985) 71.577,282.435 77.828,282.435 cw(c77.828,281.711)
SFP2_VccR on L1 "SFP2_VCCR_L01_P338" (solid, remove dead copper, pour order 338): 77.275,270.856 77.275,274.393 ccw(c76.561,274.393) 76.561,275.107 76.265,275.107 ccw(c76.265,274.457) 75.614,274.457 75.614,272.989 cw(c74.931,272.989) 74.931,272.305 71.557,272.305 ccw(c71.557,271.497) 70.748,271.497 70.748,270.26 ccw(c71.226,270.26) 71.226,269.781 76.967,269.781 ccw(c76.967,270.069) 77.255,270.069
SFP2_VccT on L1 "SFP2_VCCT_L01_P337" (solid, remove dead copper, pour order 337): 70.472,266.697 70.472,267.807 cw(c71.226,267.807) 71.226,268.561 76.516,268.561 cw(c76.516,267.773) 77.304,267.773 77.304,263.95 cw(c76.964,263.95) 76.964,263.611 76.54,263.611 cw(c76.54,264.537) 75.614,264.537 75.614,265.144 ccw(c74.562,265.144) 74.562,266.197 70.938,266.197 cw(c70.938,266.687) 70.447,266.687
ETH_VDDIO on L1 "ETH_VDDIO_L01_P312" (solid, remove dead copper, pour order 312): 107.149,283.424 cw(c107.956,283.424) 107.956,284.231 110.525,284.231 cw(c110.525,283.758) 110.998,283.758 110.993,282.79 cw(c110.55,282.722) 110.998,282.722 110.998,282.458 cw(c110.74,282.458) 110.74,282.2 107.549,282.2 cw(c107.549,282.6) 107.149,282.6
USB_Vout on L1 "USB_VOUT_L01_P308" (solid, remove dead copper, pour order 308): 43.886,357.543 cw(c43.886,357.078) 44.351,357.078 44.351,356.513 cw(c43.746,356.513) 43.746,355.908 38.606,355.908 cw(c38.609,356.09) 38.426,356.094 cw(c38.706,356.149) 38.421,356.149 38.421,357.543
3V3_RAIL on L1 "3V3_RAIL_L01_P294" (solid, remove dead copper, pour order 294): 108.702,383.81 cw(c108.288,383.81) 108.288,383.396 107.37,383.396 cw(c107.37,383.77) 106.997,383.77 106.997,389.085 cw(c107.441,389.085) 107.441,389.529 cw(c107.449,389.049) 107.449,389.529 108.381,389.529 cw(c108.382,389.209) 108.702,389.209
3V3_RAIL on L1 "3V3_RAIL_L01_P293" (solid, remove dead copper, pour order 293): 98.159,382.064 105.272,382.064 cw(c105.272,381.771) 105.566,381.771 105.566,380.674 cw(c105.219,380.674) 105.219,380.328 98.894,380.328 cw(c98.894,381.063) 98.159,381.063
3V3_RAIL on L1 "3V3_RAIL_L01_P292" (solid, remove dead copper, pour order 292): 57.628,380.682 58.229,380.682 ccw(c58.229,381.274) 58.821,381.274 58.821,381.93 ccw(c58.46,381.93) 58.46,382.291 57.77,382.294 56.61,382.294 ccw(c56.61,381.922) 56.238,381.922 56.238,380.682
3V3_RAIL on L1 "3V3_RAIL_L01_P291" (solid, remove dead copper, pour order 291): 60.877,371.621 60.877,371.02 ccw(c61.469,371.02) 61.469,370.428 62.124,370.428 ccw(c62.124,370.789) 62.485,370.789 62.488,371.479 62.488,372.639 ccw(c62.117,372.639) 62.117,373.011 60.877,373.011
3V3_RAIL on L1 "3V3_RAIL_L01_P290" (solid, remove dead copper, pour order 290): 54.356,315.101 54.356,311.054 cw(c54.042,311.054) 54.042,310.74 52.895,310.74 cw(c52.895,311.532) 52.104,311.532 52.104,314.635 cw(c52.572,314.635) 52.572,315.102
3V3_RAIL on L1 "3V3_RAIL_L01_P289" (solid, remove dead copper, pour order 289): 54.393,301.336 54.393,297.289 cw(c54.079,297.289) 54.079,296.975 52.932,296.975 cw(c52.932,297.767) 52.141,297.767 52.141,300.87 cw(c52.609,300.87) 52.609,301.337
3V3_RAIL on L1 "3V3_RAIL_L01_P288" (solid, remove dead copper, pour order 288): 54.357,286.714 54.357,282.668 cw(c54.043,282.668) 54.043,282.354 52.897,282.354 cw(c52.897,283.145) 52.106,283.145 52.106,286.248 cw(c52.573,286.248) 52.573,286.715
3V3_RAIL on L1 "3V3_RAIL_L01_P287" (solid, remove dead copper, pour order 287): 54.343,272.507 54.343,268.461 cw(c54.029,268.461) 54.029,268.147 52.883,268.147 cw(c52.883,268.938) 52.091,268.938 52.091,272.041 cw(c52.559,272.041) 52.559,272.508
Vout2_1 on L1 "VOUT2_1_L01_P243" (solid, remove dead copper, pour order 243): 91.63,172.441 93.398,172.441 100.103,165.735 113.817,165.735 115.595,163.957 115.595,160.909 114.91,160.223 114.91,160.147 114.14,160.147 93.738,160.146 89.599,164.285 89.599,171.501 90.538,172.441
5V_RAIL on L1 "5V_RAIL_L01_P256" (solid, pour order 256): 100.266,199.987 106.921,199.987 107.481,200.546 107.481,203.009 106.286,204.203 94.818,204.203 93.408,202.794 93.408,200.406 93.815,200 100.33,200
Vout1_2 on L1 "VOUT1_2_L01_P237" (solid, pour order 237): 92.926,217.589 95.618,214.897 108.372,214.897 111.443,211.826 111.443,210.338 110.605,209.5 92.239,209.5 88.816,212.924 88.816,216.209 90.195,217.589
RAM_Vcc1V2 on L1 "RAM_VCC1V2_L01_P283" (solid, remove dead copper, pour order 283): 117.157,166.238 115.765,166.238 115.745,166.258 115.745,167.06 117.152,167.06 117.157,167.055
US+_Vcc_PS_IntFp on L1 "US+_VCC_PS_INTFP_L01_P099" (solid, pour order 99): 145.706,304.356 148.104,301.958 148.104,289.481 146.012,287.388 138.648,287.388 138.102,287.934 138.112,287.945 138.112,303.81 138.659,304.356
0.85V@40A_INA on L1 "0.85V@40A_INA_L01_P112" (solid, pour order 112): 130.202,304.332 127.457,301.587 127.457,290.055 130.149,287.363 137.2,287.363 137.746,287.91 137.735,287.92 137.735,303.785 137.189,304.332
12V_PCIE2_CM on L1 "12V_PCIE2_CM_L01_P285" (solid, remove dead copper, pour order 285): 254.491,381.398 255.286,381.398 255.297,381.409 255.306,381.4 255.306,379.907 254.552,379.907 254.485,379.974
12V_PCIE3_CM on L1 "12V_PCIE3_CM_L01_P284" (solid, remove dead copper, pour order 284): 89.486,380.794 89.488,380.796 90.283,380.796 90.283,379.369 90.222,379.307 89.585,379.307 89.486,379.407
NetC674_2 on L1 "NETC674_2_L01_P282" (solid, pour order 282): 128.613,238.074 128.613,236.766 128.75,236.629 129.591,236.629 129.807,236.413 129.807,234.95 130.018,234.739 131.78,234.739 132.702,235.661 132.702,238.557 132.626,238.633 129.172,238.633
SW2_1 on L1 "SW2_1_L01_P195" (solid, pour order 195): 18 vertices, not listed, extent 74.924,160.693 88.405,176.352
SW1_1 on L1 "SW1_1_L01_P193" (solid, pour order 193): 18 vertices, not listed, extent 75.311,176.898 88.405,192.164
SW2_2 on L1 "SW2_2_L01_P191" (solid, pour order 191): 76.53,204.802 84.863,204.802 86.716,202.949 86.716,194.412 85.407,193.103 80.099,193.103 79.642,193.561 79.642,198.171 79.21,198.603 77.127,198.603 76.086,199.644 76.086,204.357
SW1_2 on L1 "SW1_2_L01_P167" (solid, pour order 167): 25 vertices, not listed, extent 76.276,205.962 91.421,218.415
SW1 on L1 "SW1_L01_P159" (solid, remove dead copper, pour order 159): 88.328,245.2 74.78,245.2 73.662,244.056 73.662,237.96 93.442,237.96 93.442,245.2
SW2 on L1 "SW2_L01_P163" (solid, pour order 163): 88.786,226.099 75.077,226.099 73.698,227.457 73.698,233.323 93.442,233.323 93.442,226.099
CSP on L1 "CSP_L01_P261" (solid, pour order 261): 35.344,235.28 43.258,235.28 45.949,232.589 45.949,230.226 44.005,228.282 36.106,228.282 34.023,230.365 34.023,234.036 35.242,235.255
3V3_RAIL on L1 "3V3_RAIL_L01_P249" (solid, remove dead copper, pour order 249): 107.391,183.528 114.046,183.528 114.605,184.087 114.605,186.55 113.411,187.744 101.943,187.744 100.533,186.334 100.533,183.947 100.94,183.54 107.455,183.54
Vout1_1 on L1 "VOUT1_1_L01_P239" (solid, remove dead copper, pour order 239): 96.208,186.85 101.498,181.559 113.602,181.559 114.579,180.581 114.579,179.317 116.187,179.317 117.615,177.889 117.615,176.949 117.516,176.851 93.685,176.851 90.081,180.454 90.081,185.039 91.892,186.85
Vout_1_Selector on L1 "VOUT_1_SELECTOR_L01_P219" (solid, pour order 219): 48.855,174.943 48.716,174.804 48.716,171.747 49.749,170.714 50.595,170.714 50.964,171.082 50.964,173.389 49.411,174.942 48.868,174.942
0.85V@40A_INA on L1 "0.85V@40A_INA_L01_P149" (solid, pour order 149): 113.933,245.2 116.336,245.2 116.336,226.109 116.091,226.109 93.832,226.109 93.832,233.306 97.534,233.306 97.862,232.978 113.243,232.978 113.243,238.214 97.767,238.214 97.5,237.947 93.832,237.947 93.832,245.2
12V_LT3042 on L7(12V+Other) "12V_LT3042_L07_P503" (solid, remove dead copper, pour order 503): 25.865,150.02 284.823,150.02 284.823,458.876 25.865,458.876
12V_LT3042 on L7(12V+Other) "12V_LT3042_L07_P461" (solid, remove dead copper, pour order 461): 25.87,150.012 284.823,150.012 284.823,458.876 25.87,458.876
Vout_1_Selector on L7(12V+Other) "VOUT_1_SELECTOR_L07_P378" (solid, pour order 378): 48.71,171.566 49.56,170.714 50.782,170.714 51.219,171.151 51.219,179.279 48.872,181.626 48.872,183.189 48.133,183.928 48.369,184.163 48.797,184.163 48.581,184.379 47.911,184.379 45.775,182.242 45.775,180.368 48.71,177.432
Vout_2_Selector on L7(12V+Other) "VOUT_2_SELECTOR_L07_P106" (solid, pour order 106): 38.581,183.172 39.274,183.866 42.487,183.866 43.053,183.299 43.053,177.786 42.255,176.987 39.04,176.987 38.581,177.446
0.85V@40A_INA on L7(12V+Other) "0.85V@40A_INA_L07_P428" (solid, pour order 428): 17 vertices, not listed, extent 97.942,226.832 152.561,305.118
Ground on L7(12V+Other) "GROUND_L07_P134" (solid, pour order 134): 146.695,244.393 159.557,244.393 162.148,246.984 168.25,246.984 181.165,234.068 181.165,205.816 177.025,201.676 167.219,201.676 161.148,207.747 147.892,207.747 138.709,216.929 138.709,233.402 144.31,239.002 144.31,242.094 146.482,244.266
3.3V_Stable_2 on L7(12V+Other) "3.3V_STABLE_2_L07_P404" (solid, pour order 404): 22 vertices, not listed, extent 187.073,260.913 201.273,277.255
5V_LN on L7(12V+Other) "5V_LN_L07_P136" (solid, pour order 136): 27 vertices, not listed, extent 97.38,337.642 158.638,407.241
US+_Vcc_PS_IntFp on L7(12V+Other) "US+_VCC_PS_INTFP_L07_P251" (solid, pour order 251): 183.397,310.539 184.397,309.539 184.397,295.539 176.309,287.452 153.022,287.452 138.532,287.452 138.102,287.881 138.102,305.501 143.141,310.539
3.3V_Stable_1 on L7(12V+Other) "3.3V_STABLE_1_L07_P411" (solid, remove dead copper, pour order 411): 87.741,340.703 96.371,340.703 cw(c96.371,338.319) 98.755,338.319 98.755,330.289 cw(c96.215,330.289) 96.215,327.749 88.113,327.749 cw(c88.113,330.289) 85.573,330.289 85.573,338.535 cw(c87.741,338.535)
1V0@1.5A on L7(12V+Other) "1V0@1.5A_L07_P147" (solid, remove dead copper, pour order 147): 22 vertices, not listed, extent 89.517,250.94 113.411,283.431
eMMC_Vcc on L7(12V+Other) "EMMC_VCC_L07_P446" (solid, remove dead copper, pour order 446): 120.509,335.934 123.284,338.709 126.413,338.709 127.546,337.576 127.546,318.083 125.712,316.248 122.281,316.248 120.438,318.091 120.438,335.839
12V_PCIE3 on L7(12V+Other) "12V_PCIE3_L07_P113" (solid, remove dead copper, pour order 113): 93.51,378.714 cw(c93.51,378.092) 94.132,378.092 94.132,371.216 ccw(c94.759,371.216) 94.759,370.589 95.846,370.589 cw(c95.846,370.007) 96.428,370.007 96.428,368.406 cw(c96.064,368.406) 96.064,368.042 94.709,368.042 ccw(c94.709,367.063) 93.731,367.063 cw(c93.309,367.063) 93.309,366.642 92.029,366.642 cw(c92.029,366.963) 91.708,366.963 91.708,377.71 cw(c92.711,377.71) 92.711,378.714
AGND_1 on L7(12V+Other) "AGND_1_L07_P457" (solid, remove dead copper, pour order 457): 60.154,186.328 70.158,186.328 70.158,172.592 60.934,172.592 58.389,175.137 58.389,184.563
RAM_DDR4_VTT on L7(12V+Other) "RAM_DDR4_VTT_L07_P437" (solid, pour order 437): 19 vertices, not listed, extent 150.244,332.464 180.048,351.079
SW2 on L7(12V+Other) "SW2_L07_P421" (solid, pour order 421): 88.786,226.099 75.077,226.099 73.698,227.457 73.698,233.323 93.442,233.323 93.442,226.099
SW1 on L7(12V+Other) "SW1_L07_P425" (solid, remove dead copper, pour order 425): 88.328,245.2 74.78,245.2 73.662,244.056 73.662,237.96 93.442,237.96 93.442,245.2
ADP1741_3.6V on L8 (Plane_GND) "ADP1741_3.6V_L08_P394" (solid, remove dead copper, pour order 394): 17 vertices, not listed, extent 90.937,291.084 121.425,317.983
0.85V@40A_INA on L8 (Plane_GND) "0.85V@40A_INA_L08_P415" (solid, pour order 415): 98.514,243.599 121.488,243.599 125.463,247.574 125.463,300.596 129.984,305.118 136.742,305.118 137.719,304.141 137.719,287.35 142.303,282.765 142.303,232.004 137.132,226.832 98.615,226.832 97.942,227.506 97.942,243.027
B503_Ground on L8 (Plane_GND) "B503_GROUND_L08_P504" (solid, pour order 504): 25.87,150.012 284.823,150.012 284.823,458.876 25.87,458.876
5V_RAIL on L8 (Plane_GND) "5V_RAIL_L08_P501" (solid, pour order 501): 17 vertices, not listed, extent 91.326,172.433 236.995,263.888
US+_Vcc_PS_IntFp on L8 (Plane_GND) "US+_VCC_PS_INTFP_L08_P257" (solid, pour order 257): 184.397,309.539 184.397,295.539 176.309,287.452 153.022,287.452 138.532,287.452 138.102,287.881 138.102,305.501 142.141,309.539
NetC537_Z1 on L8 (Plane_GND) "NETC537_Z1_L08_P098" (solid, pour order 98): 40.107,360.363 42.418,358.051 42.418,341.833 39.726,339.141 27.648,339.141 26.276,340.512 26.276,360.312 26.327,360.363
0V9@1A_REG3 on L8 (Plane_GND) "0V9@1A_REG3_L08_P104" (solid, pour order 104): 150.203,285.681 152.641,283.243 152.641,280.772 153.492,279.921 154.788,279.921 155.613,280.746 155.613,285.064 153.282,287.395 150.54,287.395 150.203,287.058
AGND_2 on L8 (Plane_GND) "AGND_2_L08_P097" (solid, remove dead copper, pour order 97): 58.433,213.225 68.437,213.225 68.437,198.577 60.124,198.577 55.969,202.732 55.969,210.761
AGND on L6 (PWR/GND) "AGND_L06_P508" (solid, pour order 508): 25.87,150.012 284.823,150.012 284.823,458.876 25.87,458.876
Vout_1_Selector on L6 (PWR/GND) "VOUT_1_SELECTOR_L06_P328" (solid, remove dead copper, pour order 328): 53.566,178.332 55.583,178.332 55.746,178.169 55.719,178.142 55.719,163.338 39.665,163.338 39.118,163.885 39.282,164.05 39.282,176.895 42.127,176.895 42.96,176.062 42.96,166.423 43.237,166.145 53.176,166.145 53.566,166.535
Vout_2_Selector on L6 (PWR/GND) "VOUT_2_SELECTOR_L06_P330" (solid, remove dead copper, pour order 330): 19 vertices, not listed, extent 37.538,177.544 55.829,195.232
US+_MGTVccAux on L6 (PWR/GND) "US+_MGTVCCAUX_L06_P301" (solid, remove dead copper, pour order 301): 23 vertices, not listed, extent 59.388,169.825 163.252,333.24
US+_Vcc_PS_DDR_504 on L6 (PWR/GND) "US+_VCC_PS_DDR_504_L06_P302" (solid, pour order 302): 24 vertices, not listed, extent 181.397,309.445 209.929,317.793
Ground on L6 (PWR/GND) "GROUND_L06_P497" (solid, pour order 497): 148.184,222.171 148.184,222.651 149.269,223.737 159.295,223.737 159.969,224.411 159.969,242.327 158.418,243.878 146.736,243.878 141.57,238.713 141.57,235.695 140.97,235.095 140.97,221.205 141.601,220.574 146.586,220.574
Ground on L6 (PWR/GND) "GROUND_L06_P433" (solid, pour order 433): 167.127,219.715 174.121,219.715 176.293,217.543 176.293,210.214 173.279,207.201 165.431,207.201 161.646,210.986 161.646,214.435 162.107,214.897 164.267,214.897 166.403,217.033 166.403,218.99
CSP on L6 (PWR/GND) "CSP_L06_P327" (solid, pour order 327): 36.83,235.496 43.193,235.496 49.835,228.854 49.835,202.349 49.136,201.651 44.228,201.651 42.634,203.245 42.634,224.104 35.573,231.166 35.573,234.239
12V_PCIE1 on L6 (PWR/GND) "12V_PCIE1_L06_P381" (solid, remove dead copper, pour order 381): 17 vertices, not listed, extent 217.156,254.114 221.904,265.849
12V_PCIE0 on L6 (PWR/GND) "12V_PCIE0_L06_P416" (solid, remove dead copper, pour order 416): 17 vertices, not listed, extent 173.415,368.567 183.535,380.896
12V_PCIE2 on L6 (PWR/GND) "12V_PCIE2_L06_P382" (solid, remove dead copper, pour order 382): 17 vertices, not listed, extent 257.58,366.334 264.932,378.511
12V_PCIE4 on L6 (PWR/GND) "12V_PCIE4_L06_P331" (solid, remove dead copper, pour order 331): 18 vertices, not listed, extent 132.155,254.173 137.698,265.816
Power4Charging on L6 (PWR/GND) "POWER4CHARGING_L06_P329" (solid, remove dead copper, pour order 329): 42.726,179.97 46.424,179.97 51.717,174.677 51.717,168.979 50.964,168.226 46.404,168.226 43.658,170.972 43.658,176.355 42.726,177.287
Power2_In_CM on L9 (PWR/GND) "POWER2_IN_CM_L09_P103" (solid, remove dead copper, pour order 103): 35.321,176.845 36.457,175.705 48.36,175.705 48.751,176.097 48.751,178.071 46.13,180.692 39.621,180.692 38.383,181.93 38.383,196.553 34.677,200.259 34.43,200.259 31.835,200.197 31.835,180.331
Power1_In_CM on L9 (PWR/GND) "POWER1_IN_CM_L09_P300" (solid, remove dead copper, pour order 300): 32.298,165.083 ccw(c33.408,165.083) 33.408,163.973 46.266,163.973 ccw(c46.266,166.513) 48.806,166.513 48.806,174.532 ccw(c48.28,174.532) 48.28,175.057 43.606,175.057 cw(c43.606,175.763) 42.9,175.763 ccw(c41.928,175.763) 41.928,176.735 33.02,176.735 ccw(c33.02,176.013) 32.298,176.013
PWR_OUT_20V on L9 (PWR/GND) "PWR_OUT_20V_L09_P235" (solid, pour order 235): 25 vertices, not listed, extent 31.369,155.156 88.341,258.534
RAM_Vcc1V2 on L9 (PWR/GND) "RAM_VCC1V2_L09_P295" (solid, pour order 295): 50 vertices, not listed, extent 97.701,165.176 216.421,346.24
US+_Vcc_PS_DDR_504 on L9 (PWR/GND) "US+_VCC_PS_DDR_504_L09_P442" (solid, pour order 442): 26 vertices, not listed, extent 146.291,152.794 209.753,278.275
US+_MGTVccAux on L9 (PWR/GND) "US+_MGTVCCAUX_L09_P165" (solid, pour order 165): 25 vertices, not listed, extent 137.808,297.053 173.397,320.154
5V_RAIL on L9 (PWR/GND) "5V_RAIL_L09_P402" (solid, remove dead copper, pour order 402): 30 vertices, not listed, extent 48.336,198.171 152.756,358.242
FTDI_GND on L9 (PWR/GND) "FTDI_GND_L09_P297" (solid, remove dead copper, pour order 297): 28 vertices, not listed, extent 204.787,151.536 278.6,234.411
US+_Vcc_PS_DDR_PLL on L9 (PWR/GND) "US+_VCC_PS_DDR_PLL_L09_P509" (solid, pour order 509): 198.412,307.189 196.608,307.189 194.964,305.545 186.416,305.545 184.422,307.539 178.711,307.539 177.965,306.793 177.965,304.317 179.743,302.539 183.498,302.539 184.036,302.002 184.086,302.052 195.449,302.052 198.806,305.409 198.806,306.795
USB_Vout on L9 (PWR/GND) "USB_VOUT_L09_P309" (solid, remove dead copper, pour order 309): 22 vertices, not listed, extent 38.69,353.309 48.315,358.064
PGND on L9 (PWR/GND) "PGND_L09_P471" (solid, pour order 471): 22 vertices, not listed, extent 26.556,196.126 54.877,231.191
ETH_VDDIO on L9 (PWR/GND) "ETH_VDDIO_L09_P393" (solid, remove dead copper, pour order 393): 21 vertices, not listed, extent 159.921,151.371 252.59,188.859
Vcc_CLK_Mux_Fine on L9 (PWR/GND) "VCC_CLK_MUX_FINE_L09_P408" (solid, remove dead copper, pour order 408): 46.32,397.425 cw(c47.145,397.425) 47.145,398.251 53.609,398.251 ccw(c53.609,399.285) 54.643,399.285 cw(c55.308,399.285) 55.308,399.949 74.607,399.949 cw(c74.607,397.409) 77.147,397.409 77.147,387.917 cw(c74.607,387.917) 74.607,385.377 67.627,385.377 cw(c67.627,387.097) 65.907,387.097 65.907,387.488 ccw(c63.367,387.488) 63.367,390.028 48.86,390.028 cw(c48.86,392.568) 46.32,392.568
5V_RAIL on L9 (PWR/GND) "5V_RAIL_L09_P473" (solid, pour order 473): 17 vertices, not listed, extent 174.18,192.469 210.706,262.864
VDD_CLK_MUX_DIV_3.3V on L9 (PWR/GND) "VDD_CLK_MUX_DIV_3.3V_L09_P406" (solid, remove dead copper, pour order 406): 62.722,389.826 cw(c62.722,387.286) 64.518,389.082 64.838,388.762 cw(c63.659,387.578) 65.33,387.581 65.33,384.673 cw(c64.96,384.673) 64.96,384.303 59.294,384.303 cw(c59.294,385.086) 58.511,385.086 58.511,389.183 cw(c59.154,389.183) 59.154,389.826
Vout_2_Selector on L9 (PWR/GND) "VOUT_2_SELECTOR_L09_P262" (solid, pour order 262): 18 vertices, not listed, extent 37.719,178.486 54.841,194.475
12V_PCIE4_CM on L9 (PWR/GND) "12V_PCIE4_CM_L09_P336" (solid, remove dead copper, pour order 336): 146.292,266.141 cw(c146.292,264.993) 147.439,264.993 147.439,257.056 cw(c144.899,257.056) 144.899,254.516 141.465,254.516 cw(c141.465,255.367) 140.614,255.367 140.614,265.73 cw(c141.025,265.73) 141.025,266.141
1V8@1.5A on L9 (PWR/GND) "1V8@1.5A_L09_P434" (solid, remove dead copper, pour order 434): 104.484,271.697 ccw(c104.484,273.477) 106.264,273.477 106.264,283.652 ccw(c104.979,283.652) 104.979,284.937 102.96,284.937 ccw(c102.96,282.397) 100.42,282.397 100.42,273.479 ccw(c102.202,273.479) 102.202,271.697
ETH_VDDIO on L9 (PWR/GND) "ETH_VDDIO_L09_P400" (solid, remove dead copper, pour order 400): 109.589,285.671 ccw(c109.589,283.131) 107.049,283.131 107.049,271.739 ccw(c108.719,271.739) 108.719,270.069 119.658,270.069 ccw(c119.658,272.609) 122.198,272.609 122.198,283.131 ccw(c119.658,283.131) 119.658,285.671
12V_PCIE2_CM on L9 (PWR/GND) "12V_PCIE2_CM_L09_P334" (solid, remove dead copper, pour order 334): 253.076,378.706 cw(c253.076,378.067) 253.716,378.067 253.716,366.562 cw(c252.82,366.562) 252.82,365.666 250.626,365.666 cw(c250.626,366.389) 249.903,366.389 249.903,377.37 cw(c251.24,377.37) 251.24,378.706
12V_PCIE0_CM on L9 (PWR/GND) "12V_PCIE0_CM_L09_P333" (solid, remove dead copper, pour order 333): 167.537,379.7 cw(c168.504,379.7) 168.504,380.666 170.529,380.666 cw(c170.529,380.058) 171.137,380.058 171.137,377.875 cw(c171.087,377.875) 171.086,377.825 171.086,366.189 cw(c170.509,366.189) 170.509,365.612 168.261,365.612 cw(c168.261,366.335) 167.537,366.335
12V_PCIE3_CM on L9 (PWR/GND) "12V_PCIE3_CM_L09_P332" (solid, remove dead copper, pour order 332): 88.091,378.363 86.635,378.363 ccw(c86.635,377.026) 85.298,377.026 85.298,366.046 ccw(c86.021,366.046) 86.021,365.323 88.27,365.323 ccw(c88.27,365.9) 88.847,365.9 88.847,377.608 ccw(c88.091,377.608)
12V_PCIE1_CM on L9 (PWR/GND) "12V_PCIE1_CM_L09_P335" (solid, remove dead copper, pour order 335): 228.716,265.925 cw(c228.716,264.751) 229.89,264.751 229.89,254.315 cw(c228.973,254.315) 228.973,253.398 225.812,253.398 cw(c225.812,254.237) 224.973,254.237 224.973,265.222 cw(c225.675,265.222) 225.675,265.925
Power1_In on L9 (PWR/GND) "POWER1_IN_L09_P305" (solid, remove dead copper, pour order 305): 28.086,182.893 ccw(c28.086,182.383) 27.576,182.383 27.576,163.31 ccw(c28.433,163.31) 28.433,162.454 30.038,162.454 ccw(c30.038,163.254) 30.838,163.254 30.838,182.567 ccw(c30.513,182.567) 30.513,182.893
Power2_In on L9 (PWR/GND) "POWER2_IN_L09_P304" (solid, remove dead copper, pour order 304): 27.749,200.556 28.833,200.558 cw(c28.833,199.808) 29.583,199.808 29.583,187.659 ccw(c29.876,187.659) 29.876,187.367 ccw(c30.582,187.367) 30.582,186.661 30.695,186.661 cw(c30.695,186.558) 30.798,186.558 30.798,184.152 cw(c30.451,184.152) 30.451,183.804 28.015,183.804 cw(c28.015,184.73) 27.089,184.73 27.089,199.896 cw(c27.749,199.896)
3V3_RAIL on L10 (3V3+Other) "3V3_RAIL_L10_P493" (solid, remove dead copper, pour order 493): 26.183,150.265 285.136,150.265 285.136,459.129 26.183,459.129
2V5@1.5A on L10 (3V3+Other) "2V5@1.5A_L10_P109" (solid, pour order 109): 160.832,343.801 205.96,343.801 209.918,339.842 209.918,327.139 208.458,325.679 163.565,325.679 161.52,327.724 160.21,327.724 157.772,330.162 157.772,340.741
ETH_VDDIO on L10 (3V3+Other) "ETH_VDDIO_L10_P107" (solid, pour order 107): 29 vertices, not listed, extent 112.89,181.108 165.875,312.407
0V9@1A_REG3 on L10 (3V3+Other) "0V9@1A_REG3_L10_P453" (solid, pour order 453): 18 vertices, not listed, extent 150.431,285.471 176.397,298.171
US+_MGTVccAux on L10 (3V3+Other) "US+_MGTVCCAUX_L10_P455" (solid, pour order 455): 21 vertices, not listed, extent 167.909,289.722 189.686,316.67
1V8@0.5A_ADC_filtered on L10 (3V3+Other) "1V8@0.5A_ADC_FILTERED_L10_P427" (solid, pour order 427): 34 vertices, not listed, extent 152.514,281.876 203.429,312.268
ETH_VDDIO on L10 (3V3+Other) "ETH_VDDIO_L10_P435" (solid, pour order 435): 18 vertices, not listed, extent 149.314,305.13 175.793,316.392
1V8@1.5A on L10 (3V3+Other) "1V8@1.5A_L10_P410" (solid, remove dead copper, pour order 410): 105.661,283.422 106.806,283.422 107.82,282.408 107.82,253.363 105.328,250.871 103.749,250.871 99.191,250.871 cw(c99.191,253.411) 96.651,253.411 96.651,254.803 cw(c97.714,254.803) 97.714,255.867 99.762,255.867 ccw(c99.762,258.407) 102.302,258.407 102.302,282.075 cw(c103.657,282.075) 103.657,283.431 105.555,283.431 cw(c105.555,282.791)
US+_MGTVccAux on L10 (3V3+Other) "US+_MGTVCCAUX_L10_P102" (solid, pour order 102): 140.945,322.485 140.945,316.845 140.38,316.281 138.659,316.281 138.201,315.824 68.252,315.824 64.604,319.472 64.604,323.202 65.804,324.401 139.029,324.401
5V_RAIL on L10 (3V3+Other) "5V_RAIL_L10_P108" (solid, pour order 108): 24 vertices, not listed, extent 91.084,170.849 180.01,205.08
ADP1741_3.6V on L10 (3V3+Other) "ADP1741_3.6V_L10_P479" (solid, remove dead copper, pour order 479): 116.898,255.395 116.484,255.808 116.484,292.405 118.542,294.462 120.307,294.462 120.853,293.916 120.853,292.647 119.57,291.364 119.57,255.763 119.202,255.395
ETH_VDDIO on L16 "ETH_VDDIO_L16_P430" (solid, remove dead copper, pour order 430): 114.562,288.658 ccw(c113.648,288.658) 113.648,289.572 106.918,289.572 ccw(c106.923,288.402) 105.753,288.397 ccw(c106.195,288.309) 105.745,288.309 105.745,287.087 ccw(c106.044,287.087) 106.044,286.787 113.883,286.787 ccw(c113.883,287.465) 114.562,287.465
3V3_NVMe on L16 "3V3_NVME_L16_P396" (solid, pour order 396): 28 vertices, not listed, extent 127.606,303.431 148.79,326.612
VREF+_2 on L16 "VREF+_2_L16_P321" (solid, remove dead copper, pour order 321): 186.106,274.136 cw(c186.106,273.381) 186.86,273.381 186.86,273.228 cw(c185.966,273.228) 185.966,272.334 183.135,272.334 cw(c183.138,272.54) 182.932,272.542 cw(c183.128,272.581) 182.928,272.581 182.928,273.689 cw(c183.374,273.689) 183.374,274.136
12V_PCIE1_CM on L16 "12V_PCIE1_CM_L16_P349" (solid, remove dead copper, pour order 349): 228.133,260.706 229.56,260.706 ccw(c229.56,261.036) 229.89,261.036 229.89,264.452 ccw(c229.477,264.452) 229.477,264.865 228.334,264.865 ccw(c228.334,264.664) 228.133,264.664
US+_MGTVccAux on L16 "US+_MGTVCCAUX_L16_P451" (solid, pour order 451): 196.538,299.607 198.461,299.604 198.779,299.286 198.779,294.539 198.446,294.207 196.819,294.207 195.471,294.207 194.929,294.749 194.929,299.171 195.365,299.607
AGND on L16 "AGND_L16_P447" (solid, pour order 447): 187.898,274.481 cw(c188.288,274.481) 188.288,274.871 194.638,274.871 cw(c194.638,274.646) 194.863,274.646 194.863,268.831 cw(c194.623,268.831) 194.623,268.591 188.368,268.591 cw(c188.368,269.113) 187.846,269.113 187.846,274.444 cw(c187.884,274.444) 187.884,274.482
ETH_VDDIO on L16 "ETH_VDDIO_L16_P440" (solid, remove dead copper, pour order 440): 20 vertices, not listed, extent 197.184,358.459 205.555,364.354
ADP1741_3.6V on L16 "ADP1741_3.6V_L16_P424" (solid, remove dead copper, pour order 424): 17 vertices, not listed, extent 91.3,315.957 96.37,318.98
NetR266_1 on L16 "NETR266_1_L16_P389" (solid, remove dead copper, pour order 389): 57.842,234.398 cw(c57.842,233.889) 58.351,233.889 58.351,229.872 cw(c57.377,229.872) 57.377,228.898 55.652,228.898 cw(c55.652,229.216) 55.334,229.216 55.334,234.229 cw(c55.503,234.229) 55.503,234.398
eMMC_VccQ on L16 "EMMC_VCCQ_L16_P388" (solid, remove dead copper, pour order 388): 114.688,321.341 119.208,321.341 cw(c119.208,320.903) 119.646,320.903 119.646,320.003 cw(c118.841,320.003) 118.841,319.198 115.398,319.198 cw(c115.398,319.908) 114.688,319.908
12V_PCIE4_CM on L16 "12V_PCIE4_CM_L16_P350" (solid, remove dead copper, pour order 350): 145.745,260.786 147.165,260.786 ccw(c147.165,261.116) 147.496,261.116 147.496,264.532 ccw(c147.083,264.532) 147.083,264.945 145.94,264.945 ccw(c145.94,264.744) 145.739,264.744
12V_PCIE2_CM on L16 "12V_PCIE2_CM_L16_P348" (solid, remove dead copper, pour order 348): 249.983,365.89 251.403,365.89 ccw(c251.403,366.22) 251.733,366.22 251.733,369.636 ccw(c251.32,369.636) 251.32,370.049 250.177,370.049 ccw(c250.177,369.848) 249.976,369.848
12V_PCIE0_CM on L16 "12V_PCIE0_CM_L16_P347" (solid, remove dead copper, pour order 347): 167.653,365.989 169.073,365.989 ccw(c169.073,366.319) 169.403,366.319 169.403,369.735 ccw(c168.99,369.735) 168.99,370.148 167.847,370.148 ccw(c167.847,369.947) 167.646,369.947
12V_PCIE3_CM on L16 "12V_PCIE3_CM_L16_P346" (solid, remove dead copper, pour order 346): 85.283,365.963 86.703,365.963 ccw(c86.703,366.293) 87.033,366.293 87.033,369.71 ccw(c86.62,369.71) 86.62,370.122 85.477,370.122 ccw(c85.477,369.922) 85.276,369.922
3V3_RAIL on L16 "3V3_RAIL_L16_P325" (solid, remove dead copper, pour order 325): 110.249,268.292 110.249,269.519 cw(c110.499,269.519) 110.499,269.769 115.925,269.769 cw(c115.925,269.477) 116.218,269.477 116.217,268.631 cw(c115.751,268.647) 115.751,268.181 110.373,268.181 cw(c110.373,268.318) 110.236,268.318
VVCO+_2 on L16 "VVCO+_2_L16_P322" (solid, pour order 322): 185.581,276.131 ccw(c186.431,276.131) 186.431,275.281 188.586,275.281 ccw(c188.586,275.762) 189.067,275.762 189.067,276.2 ccw(c188.93,276.2) 188.93,276.337 188.63,276.337 cw(c188.63,276.595) 188.373,276.595 188.373,276.98 ccw(c188.098,276.98) 188.098,277.255 187.093,277.255 ccw(c187.093,277.035) 186.873,277.035 cw(c186.653,277.035) 186.653,276.815 186.079,276.815 ccw(c186.079,276.317) 185.581,276.317
B503_Ground on L16 "B503_GROUND_L16_P148" (solid, pour order 148): 112.814,233.236 112.813,233.237 98.141,233.237 97.71,233.667 97.696,233.654 73.71,233.654 73.71,237.566 73.723,237.579 97.634,237.579 98.044,237.989 112.89,237.989 112.89,233.234
CSN on L12 (Sign) "CSN_L12_P207" (solid, pour order 207): 41.567,191.098 46.687,185.979 50.328,185.979 51.349,187 51.349,190.07 46.736,194.683 46.736,207.893 46.336,208.293 44.302,208.293 41.567,205.557
B223_Rx0_N on L11 (PWR/GND) "B223_RX0_N_L11_P512" (solid, pour order 512): 25.87,150.012 284.823,150.012 284.823,458.876 25.87,458.876
B503_Ground on L11 (PWR/GND) "B503_GROUND_L11_P511" (solid, pour order 511): 25.87,150.012 284.823,150.012 284.823,458.876 25.87,458.876
FTDI_VccIO on L11 (PWR/GND) "FTDI_VCCIO_L11_P391" (solid, pour order 391): 25 vertices, not listed, extent 205.201,174.421 266.419,223.48
Power_3.3_1 on L11 (PWR/GND) "POWER_3.3_1_L11_P380" (solid, pour order 380): 19 vertices, not listed, extent 164.694,211.518 174.841,230.2
ETH_VDDIO on L11 (PWR/GND) "ETH_VDDIO_L11_P392" (solid, pour order 392): 268.786,173.835 254.449,173.835 ccw(c254.449,171.295) 251.909,171.295 251.909,154.799 ccw(c254.449,154.799) 254.449,152.259 268.181,152.259 ccw(c268.181,154.799) 270.721,154.799 270.721,172.295 ccw(c269.069,172.295) 269.069,173.946
ADP1741_3.6V on L11 (PWR/GND) "ADP1741_3.6V_L11_P409" (solid, remove dead copper, pour order 409): 18 vertices, not listed, extent 115.595,157.34 156.712,258.534
Power_3.3_1 on L11 (PWR/GND) "POWER_3.3_1_L11_P383" (solid, pour order 383): 163.944,215.225 165.041,214.128 167.311,214.128 167.311,214.161 169.781,216.631 169.781,218.616 168.915,219.481 155.702,232.694 145.427,232.694 145.191,232.458 145.191,221.883 149.464,217.61 161.55,217.61 163.926,215.234
Power_3.3_2 on L11 (PWR/GND) "POWER_3.3_2_L11_P487" (solid, pour order 487): 169.024,221.64 171.348,221.64 172.11,220.878 172.11,218.567 171.285,217.742 169.449,217.742 168.862,218.328 168.872,218.338 168.872,221.488
Power_3.3_1 on L11 (PWR/GND) "POWER_3.3_1_L11_P379" (solid, pour order 379): 17 vertices, not listed, extent 142.291,211.049 164.694,230.632
Vout_1_Selector on L11 (PWR/GND) "VOUT_1_SELECTOR_L11_P298" (solid, pour order 298): 19 vertices, not listed, extent 46.076,162.969 55.746,184.321
PWR_OUT_20V on L11 (PWR/GND) "PWR_OUT_20V_L11_P303" (solid, remove dead copper, pour order 303): 66.247,198.269 66.586,197.93 66.586,186.189 66.153,185.756 58.597,185.756 58.597,192.924 57.178,194.342 54.483,194.342 52.644,192.503 52.644,190.2 52.142,189.698 49.716,189.698 48.732,190.682 48.732,197.734 49.266,198.269
B503_Ground on L13 (GND) "B503_GROUND_L13_P412" (solid, pour order 412): 25.87,150.012 284.823,150.012 284.823,458.876 25.87,458.876
Ground on L13 (GND) "GROUND_L13_P110" (solid, remove dead copper, pour order 110): 176.682,241.57 ccw(c174.142,241.57) 174.142,244.11 143.251,244.11 ccw(c143.251,241.57) 140.711,241.57 140.729,236.608 140.729,209.147 ccw(c143.269,209.147) 143.269,206.607 174.142,206.607 ccw(c174.142,209.147) 176.682,209.147
Vout_1_Selector on L5 (Sign) "VOUT_1_SELECTOR_L05_P463" (solid, pour order 463): 18 vertices, not listed, extent 38.468,158.966 55.016,184.468
ANGD on L5 (Sign) "ANGD_L05_P467" (solid, pour order 467): 68.415,241.744 71.044,239.116 71.044,230.632 68.72,228.308 58.877,228.308 56.769,230.416 56.769,238.404 60.109,241.744
US+_Vcc_PS_DDR_504 on L5 (Sign) "US+_VCC_PS_DDR_504_L05_P444" (solid, pour order 444): 19 vertices, not listed, extent 182.08,311.027 203.086,316.108
NetC537_Z1 on L5 (Sign) "NETC537_Z1_L05_P505" (solid, pour order 505): 25.87,360.177 41.935,360.177 44.364,357.749 44.364,340.634 42.752,339.023 25.91,339.023 25.87,339.063
PWR_OUT_20V on L5 (Sign) "PWR_OUT_20V_L05_P483" (solid, pour order 483): 96.749,258.483 97.968,257.264 97.968,254.784 95.381,252.197 91.707,252.197 88.303,248.793 88.303,246.786 87.185,245.669 73.774,245.669 73.127,246.316 73.203,246.393 73.203,252.197 79.489,258.483
Ground_PWR_PoE on L5 (Sign) "GROUND_PWR_POE_L05_P469" (solid, pour order 469): 47.533,213.322 47.533,203.222 42.278,197.968 34.963,197.968 31.178,201.752 31.178,212.649 33.071,214.541 46.317,214.541 47.536,213.322
5V_RAIL on L5 (Sign) "5V_RAIL_L05_P475" (solid, pour order 475): 173.163,217.005 172.58,216.422 172.58,208.153 173.317,207.416 177.419,207.416 181.508,203.327 184.137,203.327 184.137,203.505 186.271,205.638 186.271,210.134 179.4,217.005
US+_VccADC on L14 (Sign) "US+_VCCADC_L14_P507" (solid, pour order 507): 175.944,304.228 195.326,304.234 196.119,305.027 197.167,305.027 197.686,304.508 197.686,303.963 195.775,302.052 181.861,302.052 176.214,302.052 175.616,302.65 175.616,303.941 175.904,304.228
US+_GNDADC on L14 (Sign) "US+_GNDADC_L14_P203" (solid, pour order 203): 20 vertices, not listed, extent 175.904,299.852 206.184,304.857
V_PoE+ on L14 (Sign) "V_POE+_L14_P506" (solid, pour order 506): 49.6,234.95 55.334,229.216 55.334,219.532 47.324,211.522 31.861,211.522 26.619,216.764 26.619,233.705 27.864,234.95
Battery_PWR on L3 (Sign) "BATTERY_PWR_L03_P499" (solid, pour order 499): 44.945,200.609 42.726,198.39 42.726,196.25 44.094,194.881 48.209,194.881 49.2,195.872 49.2,199.136 47.727,200.609
B503_Ground on L15 (GND) "B503_GROUND_L15_P111" (solid, remove dead copper, pour order 111): 25.87,150.012 284.823,150.012 284.823,458.876 25.87,458.876
B503_Ground on L4 (GND) "B503_GROUND_L04_P413" (solid, pour order 413): 25.87,150.012 284.823,150.012 284.823,458.876 25.87,458.876
B503_Ground on L2 (GND) "B503_GROUND_L02_P486" (solid, pour order 486): 25.87,150.012 284.823,150.012 284.823,458.876 25.87,458.876

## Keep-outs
Keep-Out Layer:
  lines w0.125: 25.87,342.697 23.14,342.697 23.14,358.699 25.87,358.699 ; 25.87,343.948 25.87,150.012 284.823,150.012 284.823,458.876 284.137,458.876 25.87,458.876 25.87,357.448 ; 25.87,343.948 25.87,357.448 ; 25.87,343.948 35.09,343.948 35.09,357.448 25.87,357.448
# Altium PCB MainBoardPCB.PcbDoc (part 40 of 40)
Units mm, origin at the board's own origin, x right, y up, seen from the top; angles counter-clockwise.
Board outline 258.95 x 308.86 mm, 16 copper layers (L1, L2 (GND), L3 (Sign), L4 (GND), L5 (Sign), L6 (PWR/GND), L7(12V+Other), L8 (Plane_GND), L9 (PWR/GND), L10 (3V3+Other), L11 (PWR/GND), L12 (Sign), L13 (GND), L14 (Sign), L15 (GND), L16), stack 2.503 mm thick; 2578 components, 1867 nets, 8817 pads, 8021 vias.
Unrouted connection lines stored in the file: 25.

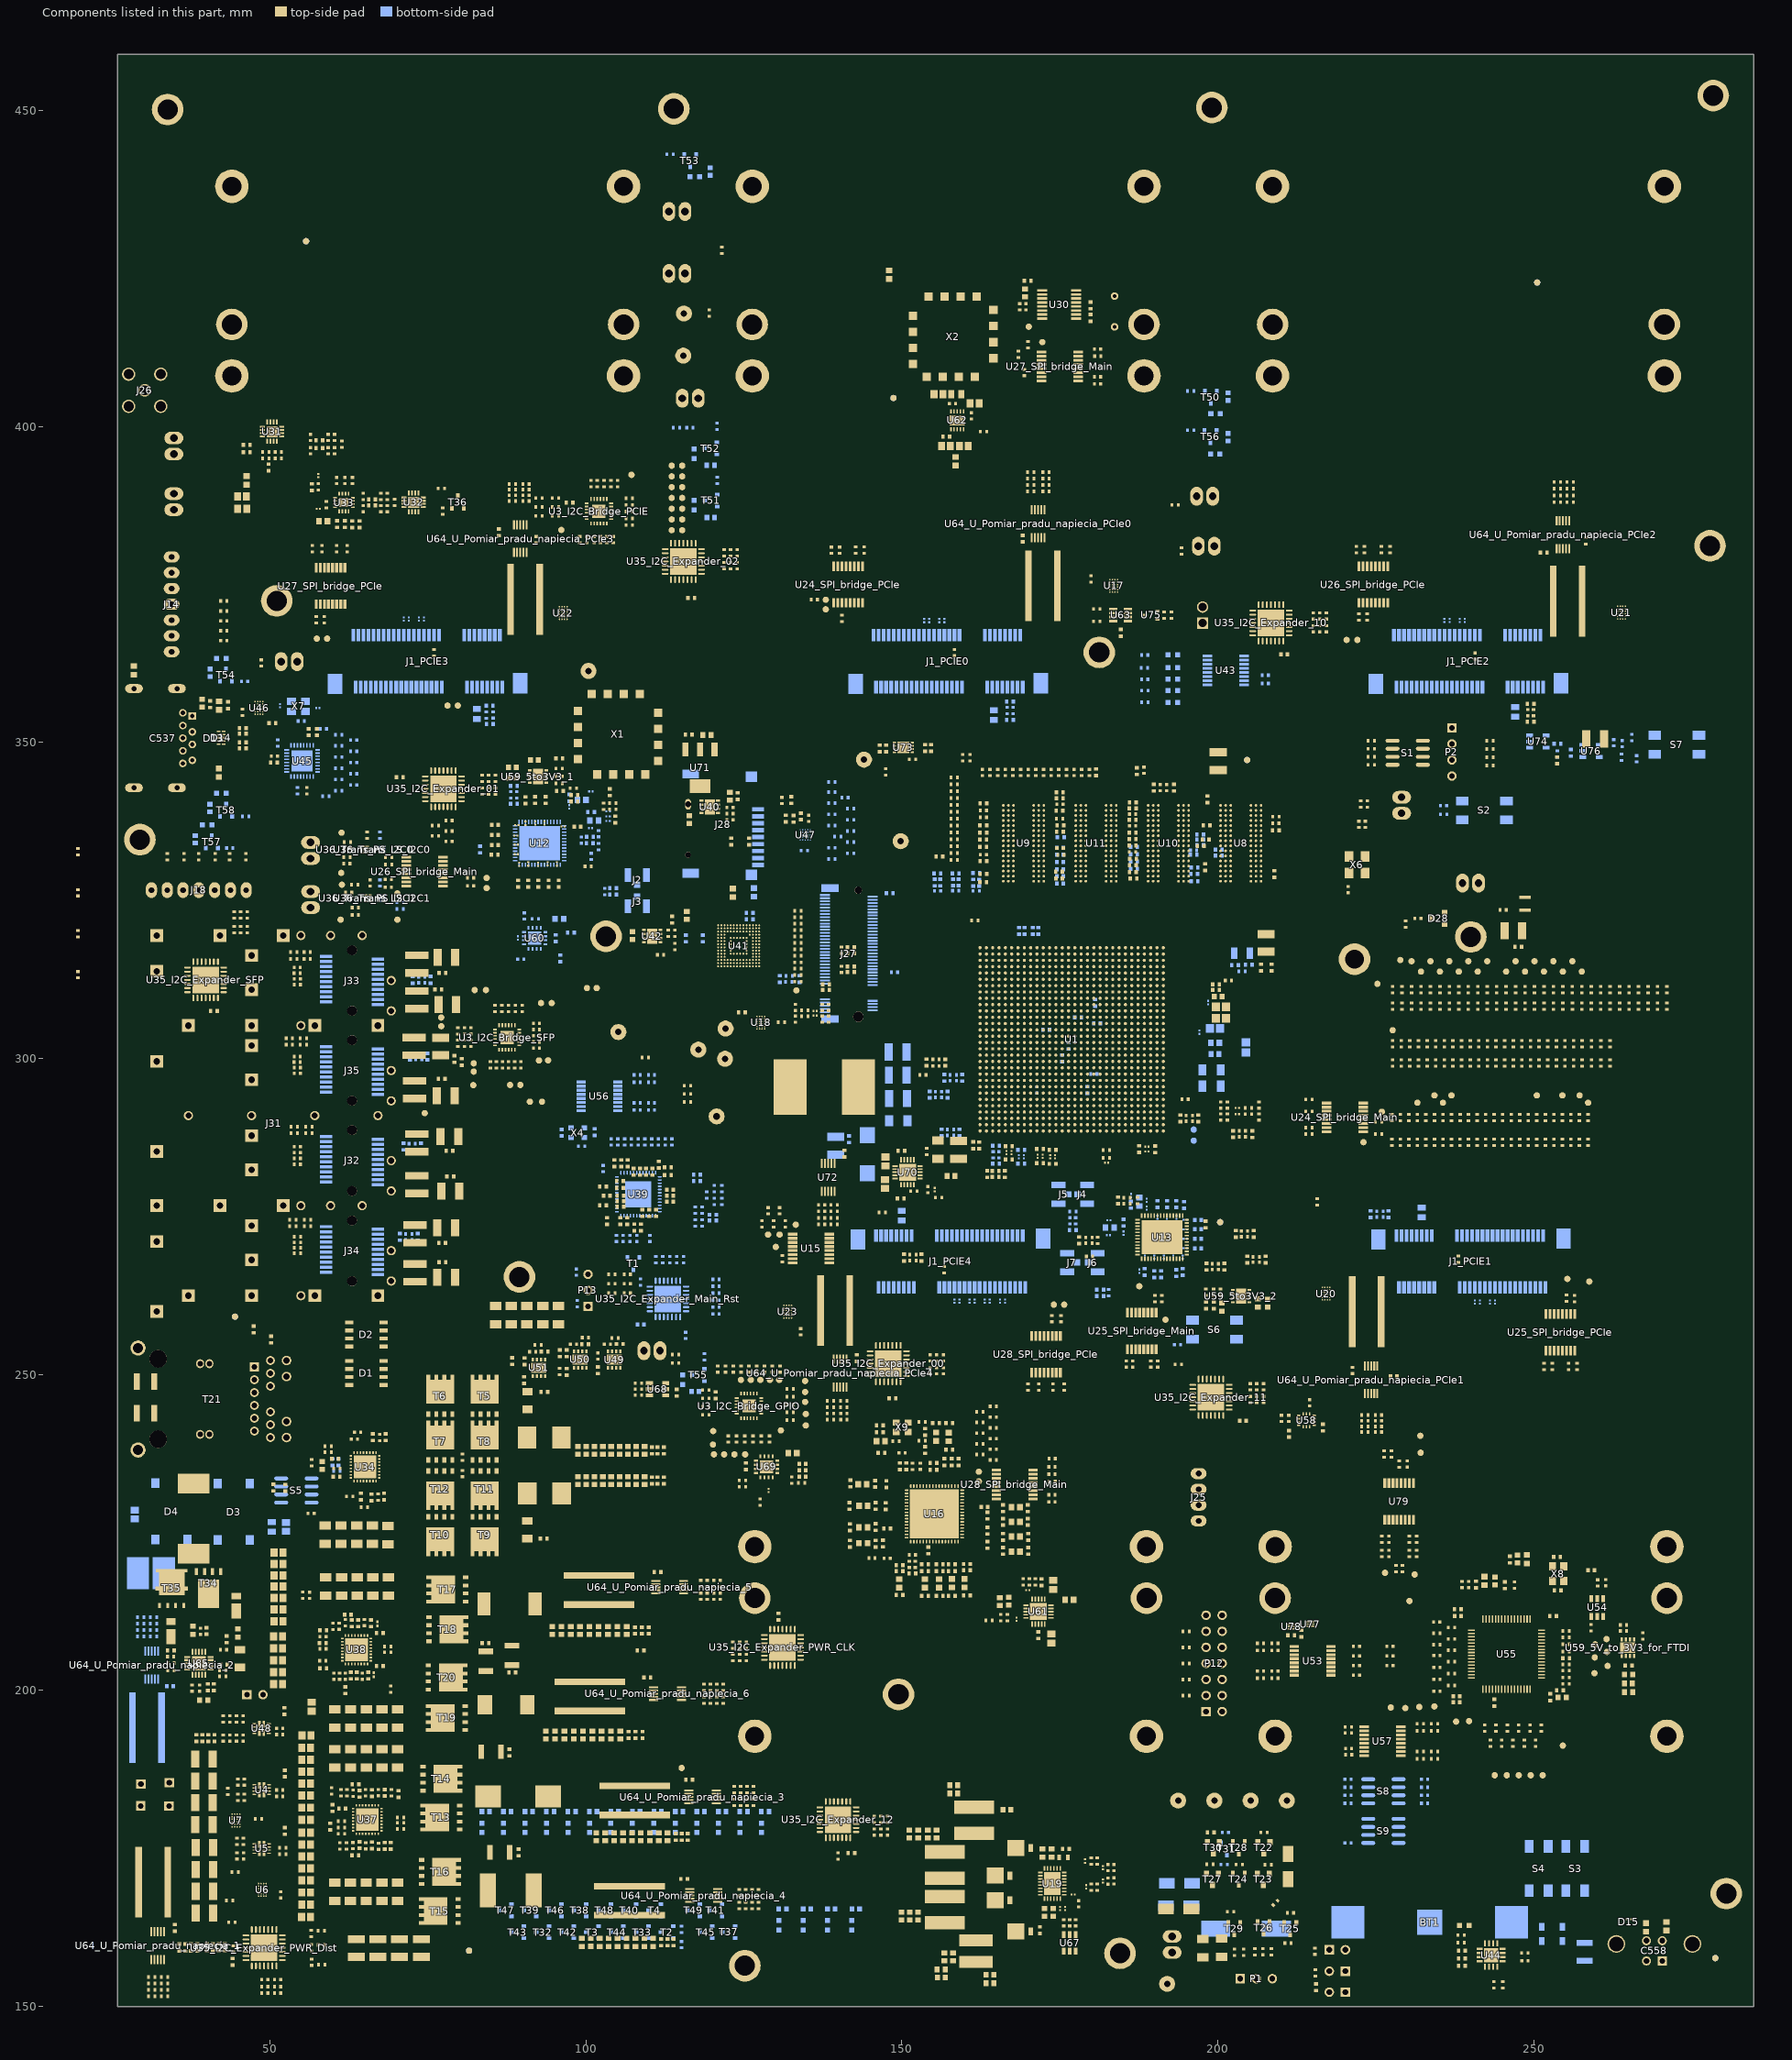
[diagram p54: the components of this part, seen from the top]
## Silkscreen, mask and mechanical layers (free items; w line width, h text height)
Top Overlay:
  drawing of 122 lines, arcs and shapes, not listed
  text "MIO_38" at 112.189,420.216 h1
  text "SPI_M_CS1" at 167.195,414.807 h1 r90
  text "DAC_OSC_OUT" at 111.325,414.098 h1
  text "SPI_M_OE1" at 171.55,414.06 h1
  text "R237_M" at 170.663,413.866 h0.51 r270
  text "R895_M" at 180.066,412.964 h0.51
  text "R893_M" at 180.116,410.026 h0.51
  text "R238_M" at 168.127,409.704 h0.51 r270
  text "R894_M" at 180.066,408.576 h0.51
  text "U27_M" at 176.058,406.681 h0.51 r180
  text "R892_M" at 179.97,405.469 h0.51
  text "PCIe_BR_3V3" at 106.793,393.44 h1 r45
  text "R3_P" at 101.127,392.87 h0.51 r90
  text "R6_P" at 104.253,392.87 h0.51 r90
  text "R7_P" at 105.28,392.87 h0.51 r90
  text "R4_P" at 102.135,392.845 h0.51 r90
  text "R5_P" at 103.21,392.845 h0.51 r90
  text "PCIe_HS_SC7" at 127.711,392.814 h1
  text "PCIe_HS_SD7" at 139.157,392.814 h1
  text "PCIe_HS_SC6" at 127.711,391.246 h1
  text "PCIe_HS_SD6" at 139.157,391.246 h1
  text "U3_P" at 99.45,389.936 h0.51 r90
  text "PCIE_4_SC" at 127.701,389.815 h1
  text "PCIE_4_SD" at 139.158,389.794 h1
  text "C303_P" at 97.502,388.979 h0.51 r90
  text "R8_P" at 108.663,388.568 h0.51
  text "PCIE_2_SC" at 127.701,388.264 h1
  text "PCIE_2_SD" at 139.107,388.209 h1
  text "R9_P" at 108.753,387.445 h0.51
  text "PCIE_1_SC" at 127.701,386.694 h1
  text "PCIE_1_SD" at 139.107,386.694 h1
  text "R10_P" at 108.78,386.332 h0.51
  text "R223_P" at 108.763,385.264 h0.51
  text "PCIe_HS_SC" at 127.711,385.191 h1
  text "PCIe_HS_SD" at 139.089,385.072 h1
  text "PCIe_BR_RST" at 94.289,384.58 h1 r270
  text "R224_P" at 108.802,383.994 h0.51
  text "PCIE_0_SD" at 127.701,383.727 h1
  text "PCIE_0_SC" at 139.107,383.603 h1
  text "U64_0" at 174.456,383.399 h0.51 r90
  text "C309_3" at 85.434,382.371 h0.51 r90
  text "R894_P" at 63.173,381.63 h0.51 r270
  text "R892_P" at 63.969,381.598 h0.51 r270
  text "U64_2" at 252.614,381.61 h0.51 r90
  text "R895_P" at 54.249,381.551 h0.51 r270
  text "R893_P" at 55.277,381.551 h0.51 r270
  text "U64_3" at 87.735,381.246 h0.51 r90
  text "C309_2" at 249.946,380.782 h0.51
  text "C309_0" at 168.21,380.536 h0.51 r90
  text "R888_P" at 228.365,379.754 h0.51 r90
  text "R889_P" at 224.317,379.426 h0.51 r90
  text "R890_P" at 225.044,379.426 h0.51 r90
  text "R891_P" at 220.72,379.326 h0.51 r90
  text "R602_P" at 142.046,379.191 h0.51 r90
  text "R426_P" at 141.358,379.16 h0.51 r90
  text "R425_P" at 145.341,379.091 h0.51 r90
  text "R603_P" at 137.777,379.066 h0.51 r90
  text "R560_P" at 99.434,377.385 h0.51 r90
  text "R559_P" at 100.385,377.385 h0.51 r90
  text "R558_P" at 101.516,377.385 h0.51 r90
  text "R227_P" at 102.516,377.385 h0.51 r90
  text "R226_P" at 103.516,377.385 h0.51 r90
  text "R225_P" at 104.593,377.385 h0.51 r90
  text "U35_02" at 111.455,377.007 h0.51 r90
  text "U27_P" at 62.967,376.04 h0.51 r270
  text "U24_P" at 138.509,374.234 h0.51 r90
  text "U26_P" at 220.973,373.958 h0.51 r90
  text "C311_02" at 115.021,373.798 h0.51
  text "SPI_PCIe_OE1" at 126.141,373.798 h1
  text "R448_0" at 168.834,372.768 h0.51 r90
  text "R232_P" at 133.926,371.303 h0.51
  text "R448_3" at 87.222,370.702 h0.51 r90
  text "R448_2" at 259.056,370.47 h0.51 r90
  text "R237_P" at 55.905,370.347 h0.51 r270
  text "R238_P" at 59.448,370.347 h0.51 r270
  text "SPI_PCIe_CS" at 128.123,368.942 h1
  text "R235_P" at 221.415,368.142 h0.51 r90
  text "R236_P" at 224.93,368.142 h0.51 r90
  text "R231_P" at 139.591,367.935 h0.51 r90
  text "U35_10" at 204.285,365.581 h0.51 r90
  text "LTC6952_0_CP" at 95.806,364.271 h1
  text "C311_10" at 209.18,362.316 h0.51
  text "I2C_SC" at 78.346,357.042 h1 r90
  text "I2C_SD" at 80.243,357.042 h1 r90
  text "SPI_PCIe_CS" at 59.651,355.311 h1 r90
  text "SPI_PCIe_CS" at 222.465,354.867 h1 r90
  text "SPI_PCIe_OE1" at 57.933,354.605 h1 r90
  text "SPI_PCIe_OE1" at 220.725,354.177 h1 r90
  text "U35_01" at 74.575,346.792 h0.51
  text "TTC_0" at 141.784,345.526 h1 r90
  text "C311_01" at 69.417,345.313 h0.51
  text "SC_PS_M" at 55.841,336.813 h1
  text "U36_PS_0" at 66.158,333.404 h0.51
  text "U26_M" at 72.725,332.706 h0.51
  text "PCIe_RESET" at 147.474,331.759 h1 r90
  text "R888_M" at 64.706,331.534 h0.51
  text "R890_M" at 64.669,330.727 h0.51
  text "SPI_M_CS" at 80.696,330.347 h1
  text "R236_M" at 80.492,329.4 h0.51
  text "SD_PS_M" at 53.235,329.306 h1
  text "R889_M" at 67.532,329.093 h0.51
  text "SC_PS1_M" at 53.232,327.947 h1
  text "R235_M" at 80.02,326.126 h0.51
  text "R891_M" at 66.698,325.815 h0.51
  text "SC_LS_M" at 71.846,325.58 h1
  text "U36_PS_1" at 60.977,325.021 h0.51
  text "SPI_M_OE1" at 80.152,324.332 h1
  text "SD_LS_M" at 71.781,321.459 h1
  text "SD_PS1_M" at 53.017,320.878 h1
  text "U35_S" at 36.727,316.712 h0.51
  text "SF_EXP_SC" at 82.753,312.014 h1 r90
  text "SF_EXP_SD" at 84.62,311.836 h1 r90
  text "eMMC_RST" at 124.79,310.374 h1
  text "HS_SD_MAIN" at 101.232,310.096 h1 r270
  text "HS_SC_MAIN" at 99.568,310.045 h1 r270
  text "P_SD" at 94.996,309.855 h1 r90
  text "P_SC" at 93.358,309.791 h1 r90
  text "C311_S" at 40.295,306.318 h0.51
  text "TTC_3" at 106.185,305.93 h1
  text "SF1_SD" at 70.904,305.829 h1
  text "SF1_SC" at 70.857,304.368 h1
  text "MIO1" at 125.184,303.289 h1 r90
  text "MIO2" at 120.498,301.219 h1 r90
  text "IM_SC" at 93.613,298.827 h1 r270
  text "IM_SD" at 92.239,298.79 h1 r270
  text "SF3_SD" at 72.726,298.739 h1
  text "MIO3" at 124.816,298.323 h1 r90
  text "SF3_SC" at 72.68,297.556 h1
  text "SF0_SD" at 87.558,294.756 h1 r270
  text "SF0_SC" at 89.219,294.756 h1 r270
  text "SFP_BR_RST" at 81.763,294.564 h1 r270
  text "U24_M" at 218.565,293.852 h0.51
  text "R425_M" at 210.236,293.227 h0.51
  text "SPI_M_CS" at 226.237,292.652 h1 r90
  text "SF2_SD" at 90.602,292.113 h1 r270
  text "SF2_SC" at 92.596,291.998 h1 r270
  text "R602_M" at 210.236,291.388 h0.51
  text "SFP_BR_3V3" at 63.636,291.184 h1
  text "R426_M" at 209.992,288.828 h0.51
  text "R231_M" at 224.395,288.737 h0.51
  text "R603_M" at 209.992,287.774 h0.51
  text "MIO0" at 119.148,287.652 h1
  text "R232_M" at 224.004,286.803 h0.51
  text "SPI_M_OE1" at 214.071,286.097 h1
  text "SPI_F_CLK" at 133.603,274.848 h1 r90
  text "SPI_F_CS" at 123.512,270.666 h1 r90
  text "SPI_F_MISO" at 126.516,268.881 h1 r90
  text "SPI_F_MOSI" at 125.015,266.532 h1 r90
  text "SPI_PCIe_CS" at 255.96,266.036 h1 r90
  text "SPI_PCIe_OE1" at 259.417,265.78 h1 r90
  text "SPI_M_CS1" at 186.541,264.49 h1 r180
  text "U59_L2" at 202.323,264.333 h0.51
  text "R430_L2" at 195.978,262.223 h0.51 r90
  text "R432_L2" at 196.727,262.218 h0.51 r90
  text "R431_L2" at 195.251,262.216 h0.51 r90
  text "SPI_PCIe_OE1" at 176.312,262.042 h1 r90
  text "SPI_PCIe_CS" at 174.542,261.992 h1 r90
  text "C566_L2" at 196.47,261.608 h0.51 r270
  text "C565_L2" at 197.188,261.611 h0.51 r270
  text "C567_L2" at 195.709,261.594 h0.51 r270
  text "R233_P" at 254.356,261.461 h0.51 r90
  text "R234" at 192.633,261.25 h0.51 r90
  text "R234_P" at 257.689,261.239 h0.51 r90
  text "R233" at 188.941,261.155 h0.51 r90
  text "R448_4" at 136.188,259.438 h0.51 r90
  text "R240_P" at 172.718,257.747 h0.51 r90
  text "SPI_M_OE1" at 191.271,257.722 h1 r270
  text "R448_1" at 220.073,257.594 h0.51 r90
  text "R239_P" at 176.594,257.205 h0.51 r90
  text "C563_L2" at 206.645,256.523 h0.51 r90
  text "C564_L2" at 208.239,256.523 h0.51 r90
  text "G_I2C_SD7" at 125.555,255.97 h0.9 r90
  text "G_I2C_SC6" at 126.822,255.97 h0.9 r90
  text "G_I2C_SD6" at 128.111,255.97 h0.9 r90
  text "U35_00" at 145.337,255.977 h0.51
  text "G_I2C_SC7" at 124.267,255.941 h0.9 r90
  text "G_I2C_SC5" at 129.35,255.927 h0.9 r90
  text "U25_P" at 251.1,255.917 h0.51 r90
  text "U25_M" at 184.646,254.655 h0.51 r90
  text "R3_G" at 125.959,252.231 h0.51 r90
  text "R4_G" at 127.217,252.201 h0.51 r90
  text "R6_G" at 129.736,252.189 h0.51 r90
  text "R7_G" at 130.885,252.189 h0.51 r90
  text "R5_G" at 128.397,252.134 h0.51 r90
  text "U28_P" at 169.257,251.678 h0.51 r90
  text "U64_4" at 138.245,250.304 h0.51 r90
  text "U35_11" at 195.839,250.245 h0.51
  text "C309_1" at 226.948,248.545 h0.51
  text "C609_4" at 142.917,248.472 h0.51 r90
  text "R8_G" at 128.53,247.44 h0.51
  text "R887_M" at 190.761,247.401 h0.51 r90
  text "R605_M" at 189.729,247.326 h0.51 r90
  text "R604_M" at 185.751,247.287 h0.51 r90
  text "R606_M" at 186.656,247.262 h0.51 r90
  text "R604_P" at 251.989,247.088 h0.51 r90
  text "U64_1" at 222.01,247.019 h0.51 r90
  text "R606_P" at 253.155,246.988 h0.51 r90
  text "R605_P" at 255.906,246.988 h0.51 r90
  text "R887_P" at 257.219,246.988 h0.51 r90
  text "R9_G" at 128.53,246.254 h0.51
  text "C303_G" at 121.702,245.391 h0.51 r90
  text "C311_00" at 147.322,245.119 h0.51
  text "R10_G" at 128.53,244.976 h0.51
  text "R896_P" at 170.202,244.012 h0.51 r90
  text "R898_P" at 171.986,244.012 h0.51 r90
  text "R897_P" at 174.191,244.012 h0.51 r90
  text "R899_P" at 175.919,244.012 h0.51 r90
  text "R223_G" at 128.53,243.715 h0.51
  text "0.85V 40A" at 102.387,243.332 h0.51
  text "R224_G" at 128.53,242.611 h0.51
  text "U3_G" at 126.76,242.24 h0.51 r180
  text "C311_11" at 203.191,241.541 h0.51
  text "G_I2C_SD5" at 137.536,241.27 h0.9
  text "GPIO_BR_RST" at 108.803,240.797 h1
  text "G_I2C_SC4" at 137.538,239.89 h0.9
  text "G_I2C_SD0" at 110.935,239.23 h1
  text "G_I2C_SD4" at 137.536,238.481 h0.9
  text "R560_G" at 132.167,238.406 h0.51 r90
  text "R559_G" at 132.901,238.406 h0.51 r90
  text "R558_G" at 133.72,238.406 h0.51 r90
  text "R227_G" at 134.427,238.416 h0.51 r90
  text "R226_G" at 135.127,238.416 h0.51 r90
  text "R225_G" at 135.932,238.378 h0.51 r90
  text "R240_M" at 165.813,238.025 h0.51
  text "G_I2C_SC3" at 137.494,237.095 h0.9
  text "R239_M" at 175.306,236.537 h0.51
  text "G_I2C_SC0" at 118.33,235.875 h1 r270
  text "G_I2C_SD1" at 119.614,235.867 h1 r270
  text "G_I2C_SC1" at 120.949,235.836 h1 r270
  text "G_I2C_SD2" at 122.229,235.789 h1 r270
  text "G_I2C_SD3" at 137.494,235.745 h0.9
  text "SPI_M_OE1" at 161.882,235.325 h1
  text "R899_M" at 175.292,235.248 h0.51
  text "G_I2C_SC2" at 137.538,234.575 h0.9
  text "R897_M" at 175.306,234.082 h0.51
  text "U28_M" at 172.012,232.188 h0.51 r270
  text "R898_M" at 175.217,230.908 h0.51
  text "R896_M" at 175.267,229.811 h0.51
  text "SPI_M_CS" at 161.995,224.518 h1 r90
  text "R448_P5" at 100.142,219.6 h0.51
  text "C309_P5" at 109.847,219.385 h0.51
  text "U64_P5" at 114.597,214.418 h0.51 r180
  text "12V 8A" at 100.215,211.589 h0.51
  text "C311_P_CLK" at 131.595,210.578 h0.51 r90
  text "U59_F" at 267.478,204.988 h0.51 r90
  text "U35_P_CLK" at 135.467,204.753 h0.51 r90
  text "C309_P6" at 108.574,202.897 h0.51
  text "R448_P6" at 98.685,202.773 h0.51
  text "C564_F" at 266.968,200.631 h0.51
  text "C563_F" at 266.968,199.447 h0.51
  text "U64_P6" at 114.182,197.524 h0.51 r180
  text "5V 10A" at 99.29,194.996 h0.51
  text "GPIO_BR_3V3" at 111.757,189.057 h1
  text "C309_P3" at 116.199,187.035 h0.51
  text "R448_P3" at 106.419,186.313 h0.51
  text "UART0_RX" at 200.072,185.085 h1 r90
  text "UART1_TX" at 213.38,185.085 h1 r90
  text "UART0_TX" at 194.222,185.041 h1 r90
  text "UART1_RX" at 205.358,184.801 h1 r90
  text "U64_P3" at 119.78,181.175 h0.51 r180
  text "U35_12" at 135.684,175.815 h0.51 r90
  text "C311_12" at 141.27,172.926 h0.51
  text "C309_P4" at 114.377,171.025 h0.51
  text "R448_P4" at 104.332,170.57 h0.51
  text "U64_P4" at 117.328,169.686 h0.51
  text "R448_P1" at 27.722,167.243 h0.51 r90
  text "C309_P1" at 35.307,163.963 h0.51 r90
  text "U64_P1" at 29.876,157.678 h0.51 r90
  text "CSU" at 189.5,152.448 h1 r90
Bottom Overlay:
  drawing of 42 lines, arcs and shapes, not listed
  text "U36_L_0" at 66.063,334.045 h0.51 r90
  text "U36_L_1" at 65.344,323.489 h0.51
  text "SC_LS1_M" at 194.663,288.419 h1
  text "SD_LS1_M" at 194.661,287.064 h1
  text "U35_RST" at 120.013,266.711 h0.51
  text "C311_RST" at 106.821,257.694 h0.51
  text "U64_P2" at 28.516,205.404 h0.51 r90
  text "C309_P2" at 37.542,201.663 h0.51
  text "R448_P2" at 27.264,193.683 h0.51 r90

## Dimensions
26.129,458.617 to 26.129,150.271 on Top Overlay
26.129,458.617 to 284.564,458.617 on Top Overlay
